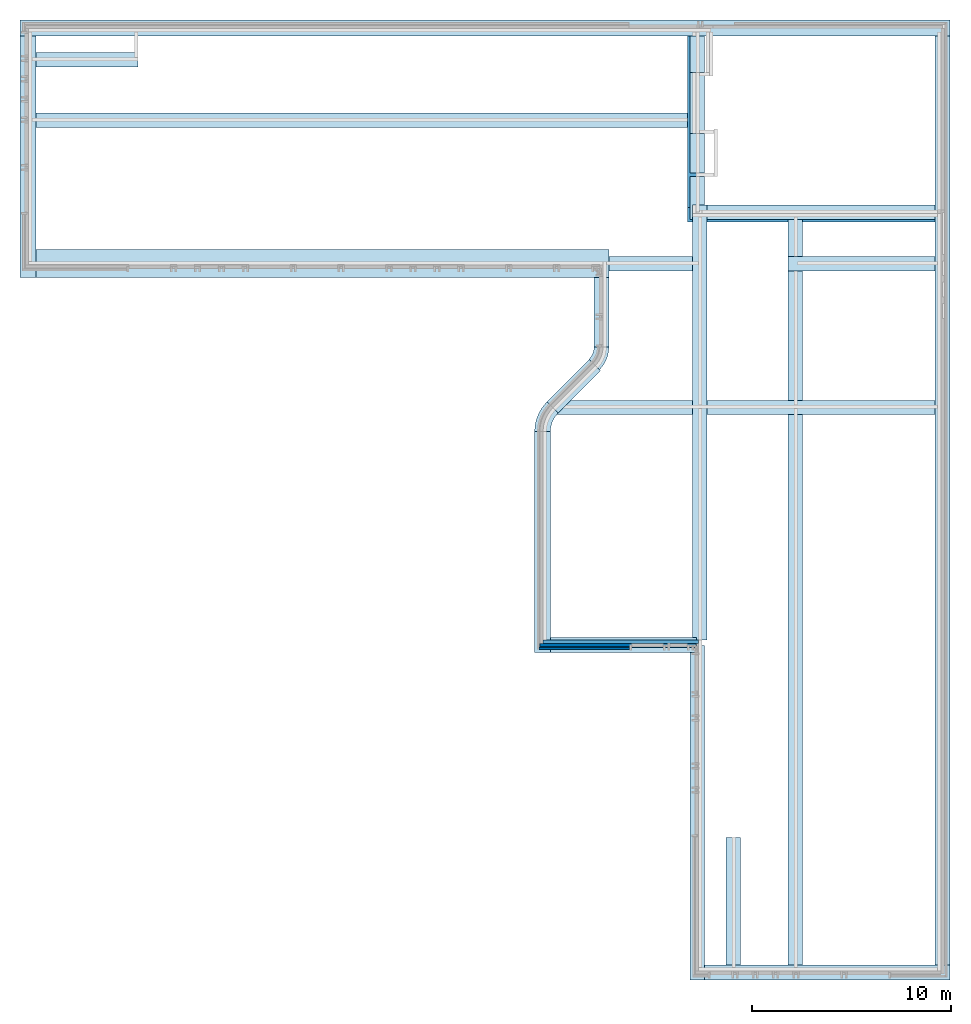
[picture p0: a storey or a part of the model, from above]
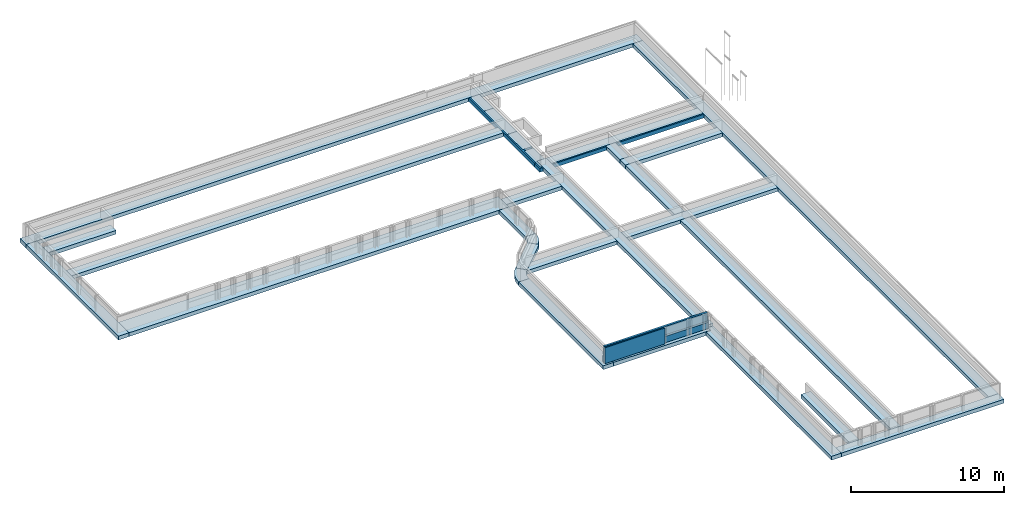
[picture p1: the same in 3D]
Properties of the parts of a building model (IFC2X3), part 1 of 37

# File
Description: ViewDefinition [CoordinationView_V2.0, QuantityTakeOffAddOnView], RevitIdentifiers [VersionGUID: 65c99af6-0f4b-4733-aae0-6f42005d6cb9, NumberOfSaves: 437], ExchangeRequirement [], CoordinateReference [CoordinateBase: Shared Coordinates]
File name: Kindcentrum de Nienekes
Time: 2024-05-14T12:10:15+01:00
Organization: DATarchitecten
Written by: ODA SDAI 23.12
Made in: Autodesk Revit 24.0.5.432 (ENU) - IFC 24.0.5.432

# IfcProject, Kindcentrum de Nienekes
LongName: 231105; Phase: <Project Status>

# IfcSite, <Kadastrale nummers>
RefLatitude: 52, 22, 58, 797912; RefLongitude: 4, 54, 57, 599601; RefElevation: 0 mm
Pset_ProductRequirements - Category: Project Information
Other - BCB_ProjectFolder: S:\7-BIM\01 BIM Bibliotheken\01 DAT Templates\; Category: Project Information; Client Name: Gemeente Land van Cuijk; Project Address: 231105@datarchitecten.nl; Project Issue Date: <Datum>; Project Name: 231105; Project Number: Kindcentrum de Nienekes; Project Status: <Project Status>; SiteName: <Kadastrale nummers>
Identity Data - IFC_Discipline: Bouwkundig; Organization Name: DAT; Revit_versie: R24; Workset: Project Info
Text - template_versie: 25-09-2017

# IfcSite: Table_Tennis_Table_12197:Table_Tennis_Table_12197 (2)
Material: Table Tennis playing surface, Table Tennis white lines, Table Tennis Metal, Table Tennis Glowing supports, Table Tennis Glowing Lines, Table Tennis net, Table Tennis Net Top
Pset_ProductRequirements - Category: Site
Other - Category: Site; Family: Table_Tennis_Table_12197; Family and Type: Table_Tennis_Table_12197: Table_Tennis_Table_12197; Type: Table_Tennis_Table_12197; Type Id: 6750400
Constraints - Level: 0; Moves With Nearby Elements: no; Offset from Host: 0 mm; Host: Level : 0
Dimensions - Area: 12.7457 m2; Volume: 0.258674 m3
Identity Data - Workset: situatie
Phasing - Phase Created: 2. nieuwbouw
Other(Type) - Category: Site; Family Name: Table_Tennis_Table_12197
Constraints(Type) - Default Elevation: 0 mm
Identity Data(Type) - Type Name: Table_Tennis_Table_12197; Workset: Family : Site : Table_Tennis_Table_12197
Name (Table_Tennis_Table_12197:Table_Tennis_Table_12197:...)
6750537
6750551

# IfcBuilding
Pset_BuildingCommon - NumberOfStoreys: 5
Pset_ProductRequirements - Category: Project Information
Other - BCB_ProjectFolder: S:\7-BIM\01 BIM Bibliotheken\01 DAT Templates\; Category: Project Information; Client Name: Gemeente Land van Cuijk; Project Address: 231105@datarchitecten.nl; Project Issue Date: <Datum>; Project Name: 231105; Project Number: Kindcentrum de Nienekes; Project Status: <Project Status>; SiteName: <Kadastrale nummers>
Identity Data - IFC_Discipline: Bouwkundig; Organization Name: DAT; Revit_versie: R24; Workset: Project Info
Text - template_versie: 25-09-2017

# IfcBuildingStorey: Level:A_hoogte_3.5mm, -1 fundering
LongName: ok. fundering; Elevation: -1570 mm
Pset_AirSideSystemInformation - Name: ok. fundering
Pset_ProductRequirements - Name: ok. fundering; Category: Levels
Other - Category: Levels; Family: Level; Family and Type: Level: A_hoogte_3.5mm; Type: A_hoogte_3.5mm; Type Id: 420648
Constraints - Elevation: -1570 mm
Dimensions - Computation Height: 0 mm
Identity Data - Structural: no; Building Story: yes; Name: ok. fundering; Workset: Shared Levels and Grids
Other(Type) - Category: Levels; Family Name: Level
Constraints(Type) - Elevation Base: Project Base Point
Graphics(Type) - Color: 8421504; Line Pattern: levels; Line Weight: 1; Symbol: 00_ISR_tag_level : 3.5mm; Symbol at End 1 Default: no; Symbol at End 2 Default: yes
Identity Data(Type) - Type Name: A_hoogte_3.5mm; Workset: Level Types

# IfcBuildingStorey: Level:A_omschrijving_3.5mm, -1 Speelvloer
LongName: V-1; Elevation: -600 mm
Pset_AirSideSystemInformation - Name: V-1; Description: Speelvloer
Pset_ProductRequirements - Name: V-1; Category: Levels
Other - Category: Levels; Family: Level; Family and Type: Level: A_omschrijving_3.5mm; Type: A_omschrijving_3.5mm; Type Id: 4122322
Constraints - Elevation: -600 mm
Dimensions - Computation Height: 0 mm
Identity Data - Structural: no; Building Story: yes; Workset: Shared Levels and Grids; Description: Speelvloer; Name: V-1
Other(Type) - Category: Levels; Family Name: Level
Constraints(Type) - Elevation Base: Project Base Point
Graphics(Type) - Line Pattern: levels; Line Weight: 1; Symbol at End 1 Default: no; Symbol at End 2 Default: yes; Color: 0; Symbol: 00_ISR_tag_level_description : 3.5mm
Identity Data(Type) - Workset: Level Types; Type Name: A_omschrijving_3.5mm

# IfcBuildingStorey: Level:S_hoogte_2.5mm_bk.vloer (3)
Pset_ProductRequirements - Category: Levels
Other - Category: Levels; Family: Level; Family and Type: Level: S_hoogte_2.5mm_bk.vloer; Type: S_hoogte_2.5mm_bk.vloer; Type Id: 549085
Dimensions - Computation Height: 0 mm
Identity Data - Structural: no; Building Story: yes; Workset: Shared Levels and Grids
Other(Type) - Category: Levels; Family Name: Level
Constraints(Type) - Elevation Base: Project Base Point
Graphics(Type) - Line Weight: 1; Color: 16711680; Line Pattern: Dash; Symbol: 00_ISR_tag_level_boven_buiten : std; Symbol at End 1 Default: yes; Symbol at End 2 Default: no
Identity Data(Type) - Workset: Level Types; Type Name: S_hoogte_2.5mm_bk.vloer
Name | LongName = Pset_AirSideSystemInformation, Name = Pset_ProductRequirements, Name = Identity Data, Name | Elevation (mm) = Constraints, Elevation (mm)
00 Begane grond | V0 bk. ruwe vloer | -70
01 eerste verdieping | V1 bk. ruwe vloer | 3560
02 tweede verdieping | V2 bk. ruwe vloer | 7150

# IfcSpace: BSO 1.04:5212714, 1.04
In: 01 eerste verdieping
LongName: BSO; InteriorOrExteriorSpace: INTERNAL
Pset_AirSideSystemInformation - Name: BSO
Pset_ProductRequirements - Name: BSO; Category: Rooms
Pset_SpaceCommon - Reference: BSO 1.04; Category: Rooms
BaseQuantities - NetFloorArea: 80.6502 m2; Height: 2600 mm; GrossFloorArea: 80.6502 m2; GrossVolume: 209.69 m3
Other - Category: Rooms; Phase Id: 0
Constraints - Base Offset: 0 mm; Upper Limit: 1; Level: 1; Limit Offset: 2600 mm
Dimensions - Computation Height: 0 mm; Area: 80.6502 m2; Perimeter: 46589.1 mm; Unbounded Height: 2600 mm; Volume: 208.352 m3
Energy Analysis - Actual Lighting Load per area: 0; Actual Power Load per area: 0; Base Lighting Load on: By Space Type; Base Power Load on: By Space Type; Heat Load Values: By Space Type; Lighting Load Units: Power Density; Number of People: 0; Power Load Units: Power Density; Actual Lighting Load: 0 W; Actual Power Load: 0 W; Area per Person: 28.5714 m2; Latent Heat Gain per person: 58.6142 W; Plenum Lighting Contribution: 20; Sensible Heat Gain per person: 73.2678 W; Specified Lighting Load: 0 W; Specified Lighting Load per area: 10.7639; Specified Power Load: 0 W; Specified Power Load per area: 13.9931; Total Heat Gain per person: 131.882 W
Identity Data - Workset: Bouwkundig; Name: BSO; Number: 1.04
Phasing - Phase: 2. nieuwbouw
Text - bezettingsgraadklasse: 30; bouwbesluit_functie: verblijfsruimte

# IfcSpace: BVO 0 2:5329016, 2
In: 00 Begane grond
LongName: BVO 0; InteriorOrExteriorSpace: INTERNAL; Group: bruto vloeroppervlak (BVO)
Pset_AirSideSystemInformation - Name: BVO 0
Pset_ProductRequirements - Name: BVO 0; Category: Areas
Pset_SpaceCommon - Reference: BVO 0 2; Category: Areas
BaseQuantities - NetFloorArea: 1160.68 m2; Height: 3630 mm; GrossFloorArea: 1160.68 m2; GrossVolume: 4213.26 m3
Other - Category: Areas; Area Scheme Id: 1055874; Area Type: Building Common Area
Constraints - Level: 0
Dimensions - Computation Height: 0 mm; Area: 1160.68 m2; Perimeter: 194664 mm
Identity Data - Workset: Bouwkundig; Name: BVO 0; Number: 2

# IfcSpace: BVO 1 1:5324504, 1
In: 01 eerste verdieping
LongName: BVO 1; InteriorOrExteriorSpace: INTERNAL; Group: bruto vloeroppervlak (BVO)
Pset_AirSideSystemInformation - Name: BVO 1
Pset_ProductRequirements - Name: BVO 1; Category: Areas
Pset_SpaceCommon - Reference: BVO 1 1; Category: Areas
BaseQuantities - NetFloorArea: 960.71 m2; Height: 3590 mm; GrossFloorArea: 960.71 m2; GrossVolume: 3448.95 m3
Other - Category: Areas; Area Scheme Id: 1055874; Area Type: Building Common Area
Constraints - Level: 1
Dimensions - Computation Height: 0 mm; Area: 960.71 m2; Perimeter: 197720 mm
Identity Data - Workset: Bouwkundig; Name: BVO 1; Number: 1

# IfcSpace: Basisgroep-lokaal 0.28:5206995, 0.28
In: 00 Begane grond
LongName: Basisgroep-lokaal; InteriorOrExteriorSpace: INTERNAL
Pset_AirSideSystemInformation - Name: Basisgroep-lokaal
Pset_ProductRequirements - Name: Basisgroep-lokaal; Category: Rooms
Pset_SpaceCommon - Reference: Basisgroep-lokaal 0.28; Category: Rooms
BaseQuantities - NetFloorArea: 49.9772 m2; Height: 2600 mm; GrossFloorArea: 49.9772 m2; GrossVolume: 129.941 m3
Other - Category: Rooms; Phase Id: 0
Constraints - Base Offset: 0 mm; Upper Limit: 0; Level: 0; Limit Offset: 2600 mm
Dimensions - Computation Height: 0 mm; Area: 49.9772 m2; Perimeter: 29171.9 mm; Unbounded Height: 2600 mm; Volume: 129.828 m3
Energy Analysis - Actual Lighting Load per area: 0; Actual Power Load per area: 0; Base Lighting Load on: By Space Type; Base Power Load on: By Space Type; Heat Load Values: By Space Type; Lighting Load Units: Power Density; Number of People: 0; Power Load Units: Power Density; Actual Lighting Load: 0 W; Actual Power Load: 0 W; Area per Person: 28.5714 m2; Latent Heat Gain per person: 58.6142 W; Plenum Lighting Contribution: 20; Sensible Heat Gain per person: 73.2678 W; Specified Lighting Load: 0 W; Specified Lighting Load per area: 10.7639; Specified Power Load: 0 W; Specified Power Load per area: 13.9931; Total Heat Gain per person: 131.882 W
Identity Data - Workset: Bouwkundig; Name: Basisgroep-lokaal; Number: 0.28
Phasing - Phase: 2. nieuwbouw
Text - bezettingsgraadklasse: 30; bouwbesluit_functie: verblijfsruimte

# IfcSpace: Basisgroep-lokaal 0.35:5207268, 0.35
In: 00 Begane grond
LongName: Basisgroep-lokaal; InteriorOrExteriorSpace: INTERNAL
Pset_AirSideSystemInformation - Name: Basisgroep-lokaal
Pset_ProductRequirements - Name: Basisgroep-lokaal; Category: Rooms
Pset_SpaceCommon - Reference: Basisgroep-lokaal 0.35; Category: Rooms
BaseQuantities - NetFloorArea: 48.6137 m2; Height: 2600 mm; GrossFloorArea: 48.6137 m2; GrossVolume: 126.395 m3
Other - Category: Rooms; Phase Id: 0
Constraints - Base Offset: 0 mm; Upper Limit: 0; Level: 0; Limit Offset: 2600 mm
Dimensions - Computation Height: 0 mm; Area: 48.6137 m2; Perimeter: 28484 mm; Unbounded Height: 2600 mm; Volume: 125.851 m3
Energy Analysis - Actual Lighting Load per area: 0; Actual Power Load per area: 0; Base Lighting Load on: By Space Type; Base Power Load on: By Space Type; Heat Load Values: By Space Type; Lighting Load Units: Power Density; Number of People: 0; Power Load Units: Power Density; Actual Lighting Load: 0 W; Actual Power Load: 0 W; Area per Person: 28.5714 m2; Latent Heat Gain per person: 58.6142 W; Plenum Lighting Contribution: 20; Sensible Heat Gain per person: 73.2678 W; Specified Lighting Load: 0 W; Specified Lighting Load per area: 10.7639; Specified Power Load: 0 W; Specified Power Load per area: 13.9931; Total Heat Gain per person: 131.882 W
Identity Data - Workset: Bouwkundig; Name: Basisgroep-lokaal; Number: 0.35
Phasing - Phase: 2. nieuwbouw
Text - bezettingsgraadklasse: 30; bouwbesluit_functie: verblijfsruimte

# IfcSpace: Basisgroep-lokaal 0.36:5207266, 0.36
In: 00 Begane grond
LongName: Basisgroep-lokaal; InteriorOrExteriorSpace: INTERNAL
Pset_AirSideSystemInformation - Name: Basisgroep-lokaal
Pset_ProductRequirements - Name: Basisgroep-lokaal; Category: Rooms
Pset_SpaceCommon - Reference: Basisgroep-lokaal 0.36; Category: Rooms
BaseQuantities - NetFloorArea: 49.4985 m2; Height: 2600 mm; GrossFloorArea: 49.4985 m2; GrossVolume: 128.696 m3
Other - Category: Rooms; Phase Id: 0
Constraints - Base Offset: 0 mm; Upper Limit: 0; Level: 0; Limit Offset: 2600 mm
Dimensions - Computation Height: 0 mm; Area: 49.4985 m2; Perimeter: 28762 mm; Unbounded Height: 2600 mm; Volume: 128.152 m3
Energy Analysis - Actual Lighting Load per area: 0; Actual Power Load per area: 0; Base Lighting Load on: By Space Type; Base Power Load on: By Space Type; Heat Load Values: By Space Type; Lighting Load Units: Power Density; Number of People: 0; Power Load Units: Power Density; Actual Lighting Load: 0 W; Actual Power Load: 0 W; Area per Person: 28.5714 m2; Latent Heat Gain per person: 58.6142 W; Plenum Lighting Contribution: 20; Sensible Heat Gain per person: 73.2678 W; Specified Lighting Load: 0 W; Specified Lighting Load per area: 10.7639; Specified Power Load: 0 W; Specified Power Load per area: 13.9931; Total Heat Gain per person: 131.882 W
Identity Data - Workset: Bouwkundig; Name: Basisgroep-lokaal; Number: 0.36
Phasing - Phase: 2. nieuwbouw
Text - bezettingsgraadklasse: 30; bouwbesluit_functie: verblijfsruimte

# IfcSpace: Basisgroep-lokaal 0.37:5207267, 0.37
In: 00 Begane grond
LongName: Basisgroep-lokaal; InteriorOrExteriorSpace: INTERNAL
Pset_AirSideSystemInformation - Name: Basisgroep-lokaal
Pset_ProductRequirements - Name: Basisgroep-lokaal; Category: Rooms
Pset_SpaceCommon - Reference: Basisgroep-lokaal 0.37; Category: Rooms
BaseQuantities - NetFloorArea: 49.6696 m2; Height: 2600 mm; GrossFloorArea: 49.6696 m2; GrossVolume: 129.141 m3
Other - Category: Rooms; Phase Id: 0
Constraints - Base Offset: 0 mm; Upper Limit: 0; Level: 0; Limit Offset: 2600 mm
Dimensions - Computation Height: 0 mm; Area: 49.6696 m2; Perimeter: 28804 mm; Unbounded Height: 2600 mm; Volume: 128.597 m3
Energy Analysis - Actual Lighting Load per area: 0; Actual Power Load per area: 0; Base Lighting Load on: By Space Type; Base Power Load on: By Space Type; Heat Load Values: By Space Type; Lighting Load Units: Power Density; Number of People: 0; Power Load Units: Power Density; Actual Lighting Load: 0 W; Actual Power Load: 0 W; Area per Person: 28.5714 m2; Latent Heat Gain per person: 58.6142 W; Plenum Lighting Contribution: 20; Sensible Heat Gain per person: 73.2678 W; Specified Lighting Load: 0 W; Specified Lighting Load per area: 10.7639; Specified Power Load: 0 W; Specified Power Load per area: 13.9931; Total Heat Gain per person: 131.882 W
Identity Data - Workset: Bouwkundig; Name: Basisgroep-lokaal; Number: 0.37
Phasing - Phase: 2. nieuwbouw
Text - bezettingsgraadklasse: 30; bouwbesluit_functie: verblijfsruimte

# IfcSpace: Basisgroep-lokaal 1.01:5212717, 1.01
In: 01 eerste verdieping
LongName: Basisgroep-lokaal; InteriorOrExteriorSpace: INTERNAL
Pset_AirSideSystemInformation - Name: Basisgroep-lokaal
Pset_ProductRequirements - Name: Basisgroep-lokaal; Category: Rooms
Pset_SpaceCommon - Reference: Basisgroep-lokaal 1.01; Category: Rooms
BaseQuantities - NetFloorArea: 48.8263 m2; Height: 2600 mm; GrossFloorArea: 48.8263 m2; GrossVolume: 126.948 m3
Other - Category: Rooms; Phase Id: 0
Constraints - Base Offset: 0 mm; Upper Limit: 1; Level: 1; Limit Offset: 2600 mm
Dimensions - Computation Height: 0 mm; Area: 48.8263 m2; Perimeter: 29366 mm; Unbounded Height: 2600 mm; Volume: 126.416 m3
Energy Analysis - Actual Lighting Load per area: 0; Actual Power Load per area: 0; Base Lighting Load on: By Space Type; Base Power Load on: By Space Type; Heat Load Values: By Space Type; Lighting Load Units: Power Density; Number of People: 0; Power Load Units: Power Density; Actual Lighting Load: 0 W; Actual Power Load: 0 W; Area per Person: 28.5714 m2; Latent Heat Gain per person: 58.6142 W; Plenum Lighting Contribution: 20; Sensible Heat Gain per person: 73.2678 W; Specified Lighting Load: 0 W; Specified Lighting Load per area: 10.7639; Specified Power Load: 0 W; Specified Power Load per area: 13.9931; Total Heat Gain per person: 131.882 W
Identity Data - Workset: Bouwkundig; Name: Basisgroep-lokaal; Number: 1.01
Phasing - Phase: 2. nieuwbouw
Text - bezettingsgraadklasse: 30; bouwbesluit_functie: verblijfsruimte

# IfcSpace: Basisgroep-lokaal 1.02:5212716, 1.02
In: 01 eerste verdieping
LongName: Basisgroep-lokaal; InteriorOrExteriorSpace: INTERNAL
Pset_AirSideSystemInformation - Name: Basisgroep-lokaal
Pset_ProductRequirements - Name: Basisgroep-lokaal; Category: Rooms
Pset_SpaceCommon - Reference: Basisgroep-lokaal 1.02; Category: Rooms
BaseQuantities - NetFloorArea: 49.5244 m2; Height: 2600 mm; GrossFloorArea: 49.5244 m2; GrossVolume: 128.763 m3
Other - Category: Rooms; Phase Id: 0
Constraints - Base Offset: 0 mm; Upper Limit: 1; Level: 1; Limit Offset: 2600 mm
Dimensions - Computation Height: 0 mm; Area: 49.5244 m2; Perimeter: 29568 mm; Unbounded Height: 2600 mm; Volume: 128.231 m3
Energy Analysis - Actual Lighting Load per area: 0; Actual Power Load per area: 0; Base Lighting Load on: By Space Type; Base Power Load on: By Space Type; Heat Load Values: By Space Type; Lighting Load Units: Power Density; Number of People: 0; Power Load Units: Power Density; Actual Lighting Load: 0 W; Actual Power Load: 0 W; Area per Person: 28.5714 m2; Latent Heat Gain per person: 58.6142 W; Plenum Lighting Contribution: 20; Sensible Heat Gain per person: 73.2678 W; Specified Lighting Load: 0 W; Specified Lighting Load per area: 10.7639; Specified Power Load: 0 W; Specified Power Load per area: 13.9931; Total Heat Gain per person: 131.882 W
Identity Data - Workset: Bouwkundig; Name: Basisgroep-lokaal; Number: 1.02
Phasing - Phase: 2. nieuwbouw
Text - bezettingsgraadklasse: 30; bouwbesluit_functie: verblijfsruimte

# IfcSpace: Basisgroep-lokaal 1.03:5212708, 1.03
In: 01 eerste verdieping
LongName: Basisgroep-lokaal; InteriorOrExteriorSpace: INTERNAL
Pset_AirSideSystemInformation - Name: Basisgroep-lokaal
Pset_ProductRequirements - Name: Basisgroep-lokaal; Category: Rooms
Pset_SpaceCommon - Reference: Basisgroep-lokaal 1.03; Category: Rooms
BaseQuantities - NetFloorArea: 49.4522 m2; Height: 2600 mm; GrossFloorArea: 49.4522 m2; GrossVolume: 128.576 m3
Other - Category: Rooms; Phase Id: 0
Constraints - Base Offset: 0 mm; Upper Limit: 1; Level: 1; Limit Offset: 2600 mm
Dimensions - Computation Height: 0 mm; Area: 49.4522 m2; Perimeter: 29556 mm; Unbounded Height: 2600 mm; Volume: 128.056 m3
Energy Analysis - Actual Lighting Load per area: 0; Actual Power Load per area: 0; Base Lighting Load on: By Space Type; Base Power Load on: By Space Type; Heat Load Values: By Space Type; Lighting Load Units: Power Density; Number of People: 0; Power Load Units: Power Density; Actual Lighting Load: 0 W; Actual Power Load: 0 W; Area per Person: 28.5714 m2; Latent Heat Gain per person: 58.6142 W; Plenum Lighting Contribution: 20; Sensible Heat Gain per person: 73.2678 W; Specified Lighting Load: 0 W; Specified Lighting Load per area: 10.7639; Specified Power Load: 0 W; Specified Power Load per area: 13.9931; Total Heat Gain per person: 131.882 W
Identity Data - Workset: Bouwkundig; Name: Basisgroep-lokaal; Number: 1.03
Phasing - Phase: 2. nieuwbouw
Text - bezettingsgraadklasse: 30; bouwbesluit_functie: verblijfsruimte

# IfcSpace: Basisgroep-lokaal 1.21:5227321, 1.21
In: 01 eerste verdieping
LongName: Basisgroep-lokaal; InteriorOrExteriorSpace: INTERNAL
Pset_AirSideSystemInformation - Name: Basisgroep-lokaal
Pset_ProductRequirements - Name: Basisgroep-lokaal; Category: Rooms
Pset_SpaceCommon - Reference: Basisgroep-lokaal 1.21; Category: Rooms
BaseQuantities - NetFloorArea: 48.8446 m2; Height: 2600 mm; GrossFloorArea: 48.8446 m2; GrossVolume: 126.996 m3
Other - Category: Rooms; Phase Id: 0
Constraints - Base Offset: 0 mm; Upper Limit: 1; Level: 1; Limit Offset: 2600 mm
Dimensions - Computation Height: 0 mm; Area: 48.8446 m2; Perimeter: 28554 mm; Unbounded Height: 2600 mm; Volume: 126.452 m3
Energy Analysis - Actual Lighting Load per area: 0; Actual Power Load per area: 0; Base Lighting Load on: By Space Type; Base Power Load on: By Space Type; Heat Load Values: By Space Type; Lighting Load Units: Power Density; Number of People: 0; Power Load Units: Power Density; Actual Lighting Load: 0 W; Actual Power Load: 0 W; Area per Person: 28.5714 m2; Latent Heat Gain per person: 58.6142 W; Plenum Lighting Contribution: 20; Sensible Heat Gain per person: 73.2678 W; Specified Lighting Load: 0 W; Specified Lighting Load per area: 10.7639; Specified Power Load: 0 W; Specified Power Load per area: 13.9931; Total Heat Gain per person: 131.882 W
Identity Data - Workset: Bouwkundig; Name: Basisgroep-lokaal; Number: 1.21
Phasing - Phase: 2. nieuwbouw
Text - bezettingsgraadklasse: 30; bouwbesluit_functie: verblijfsruimte

# IfcSpace: Basisgroep-lokaal 1.22:5212715, 1.22
In: 01 eerste verdieping
LongName: Basisgroep-lokaal; InteriorOrExteriorSpace: INTERNAL
Pset_AirSideSystemInformation - Name: Basisgroep-lokaal
Pset_ProductRequirements - Name: Basisgroep-lokaal; Category: Rooms
Pset_SpaceCommon - Reference: Basisgroep-lokaal 1.22; Category: Rooms
BaseQuantities - NetFloorArea: 49.5842 m2; Height: 2600 mm; GrossFloorArea: 49.5842 m2; GrossVolume: 128.919 m3
Other - Category: Rooms; Phase Id: 0
Constraints - Base Offset: 0 mm; Upper Limit: 1; Level: 1; Limit Offset: 2600 mm
Dimensions - Computation Height: 0 mm; Area: 49.5842 m2; Perimeter: 28794 mm; Unbounded Height: 2600 mm; Volume: 128.375 m3
Energy Analysis - Actual Lighting Load per area: 0; Actual Power Load per area: 0; Base Lighting Load on: By Space Type; Base Power Load on: By Space Type; Heat Load Values: By Space Type; Lighting Load Units: Power Density; Number of People: 0; Power Load Units: Power Density; Actual Lighting Load: 0 W; Actual Power Load: 0 W; Area per Person: 28.5714 m2; Latent Heat Gain per person: 58.6142 W; Plenum Lighting Contribution: 20; Sensible Heat Gain per person: 73.2678 W; Specified Lighting Load: 0 W; Specified Lighting Load per area: 10.7639; Specified Power Load: 0 W; Specified Power Load per area: 13.9931; Total Heat Gain per person: 131.882 W
Identity Data - Workset: Bouwkundig; Name: Basisgroep-lokaal; Number: 1.22
Phasing - Phase: 2. nieuwbouw
Text - bezettingsgraadklasse: 30; bouwbesluit_functie: verblijfsruimte

# IfcSpace: Basisgroep-lokaal 1.23:5227404, 1.23
In: 01 eerste verdieping
LongName: Basisgroep-lokaal; InteriorOrExteriorSpace: INTERNAL
Pset_AirSideSystemInformation - Name: Basisgroep-lokaal
Pset_ProductRequirements - Name: Basisgroep-lokaal; Category: Rooms
Pset_SpaceCommon - Reference: Basisgroep-lokaal 1.23; Category: Rooms
BaseQuantities - NetFloorArea: 49.6036 m2; Height: 2600 mm; GrossFloorArea: 49.6036 m2; GrossVolume: 128.969 m3
Other - Category: Rooms; Phase Id: 0
Constraints - Base Offset: 0 mm; Upper Limit: 1; Level: 1; Limit Offset: 2600 mm
Dimensions - Computation Height: 0 mm; Area: 49.6036 m2; Perimeter: 28784 mm; Unbounded Height: 2600 mm; Volume: 128.425 m3
Energy Analysis - Actual Lighting Load per area: 0; Actual Power Load per area: 0; Base Lighting Load on: By Space Type; Base Power Load on: By Space Type; Heat Load Values: By Space Type; Lighting Load Units: Power Density; Number of People: 0; Power Load Units: Power Density; Actual Lighting Load: 0 W; Actual Power Load: 0 W; Area per Person: 28.5714 m2; Latent Heat Gain per person: 58.6142 W; Plenum Lighting Contribution: 20; Sensible Heat Gain per person: 73.2678 W; Specified Lighting Load: 0 W; Specified Lighting Load per area: 10.7639; Specified Power Load: 0 W; Specified Power Load per area: 13.9931; Total Heat Gain per person: 131.882 W
Identity Data - Workset: Bouwkundig; Name: Basisgroep-lokaal; Number: 1.23
Phasing - Phase: 2. nieuwbouw
Text - bezettingsgraadklasse: 30; bouwbesluit_functie: verblijfsruimte

# IfcSpace: Basisgroep-lokaal groot 0.38:5207250, 0.38
In: 00 Begane grond
LongName: Basisgroep-lokaal groot; InteriorOrExteriorSpace: INTERNAL
Pset_AirSideSystemInformation - Name: Basisgroep-lokaal groot
Pset_ProductRequirements - Name: Basisgroep-lokaal groot; Category: Rooms
Pset_SpaceCommon - Reference: Basisgroep-lokaal groot 0.38; Category: Rooms
BaseQuantities - NetFloorArea: 67.4257 m2; Height: 2600 mm; GrossPerimeter: 33670 mm; GrossFloorArea: 67.4257 m2; GrossVolume: 175.307 m3
Other - Category: Rooms; Phase Id: 0
Constraints - Base Offset: 0 mm; Upper Limit: 0; Level: 0; Limit Offset: 2600 mm
Dimensions - Computation Height: 0 mm; Area: 67.4257 m2; Perimeter: 33670 mm; Unbounded Height: 2600 mm; Volume: 175.307 m3
Energy Analysis - Actual Lighting Load per area: 0; Actual Power Load per area: 0; Base Lighting Load on: By Space Type; Base Power Load on: By Space Type; Heat Load Values: By Space Type; Lighting Load Units: Power Density; Number of People: 0; Power Load Units: Power Density; Actual Lighting Load: 0 W; Actual Power Load: 0 W; Area per Person: 28.5714 m2; Latent Heat Gain per person: 58.6142 W; Plenum Lighting Contribution: 20; Sensible Heat Gain per person: 73.2678 W; Specified Lighting Load: 0 W; Specified Lighting Load per area: 10.7639; Specified Power Load: 0 W; Specified Power Load per area: 13.9931; Total Heat Gain per person: 131.882 W
Identity Data - Workset: Bouwkundig; Name: Basisgroep-lokaal groot; Number: 0.38
Phasing - Phase: 2. nieuwbouw
Text - bezettingsgraadklasse: 40; bouwbesluit_functie: verblijfsruimte

# IfcSpace: Basisgroep-lokaal groot 1.24:5212697, 1.24
In: 01 eerste verdieping
LongName: Basisgroep-lokaal groot; InteriorOrExteriorSpace: INTERNAL
Pset_AirSideSystemInformation - Name: Basisgroep-lokaal groot
Pset_ProductRequirements - Name: Basisgroep-lokaal groot; Category: Rooms
Pset_SpaceCommon - Reference: Basisgroep-lokaal groot 1.24; Category: Rooms
BaseQuantities - NetFloorArea: 66.0765 m2; Height: 2600 mm; GrossPerimeter: 33320 mm; GrossFloorArea: 66.0765 m2; GrossVolume: 171.799 m3
Other - Category: Rooms; Phase Id: 0
Constraints - Base Offset: 0 mm; Level: 1; Limit Offset: 2600 mm; Upper Limit: 1
Dimensions - Computation Height: 0 mm; Area: 66.0765 m2; Perimeter: 33320 mm; Unbounded Height: 2600 mm; Volume: 171.799 m3
Energy Analysis - Actual Lighting Load per area: 0; Actual Power Load per area: 0; Base Lighting Load on: By Space Type; Base Power Load on: By Space Type; Heat Load Values: By Space Type; Lighting Load Units: Power Density; Number of People: 0; Power Load Units: Power Density; Actual Lighting Load: 0 W; Actual Power Load: 0 W; Area per Person: 28.5714 m2; Latent Heat Gain per person: 58.6142 W; Plenum Lighting Contribution: 20; Sensible Heat Gain per person: 73.2678 W; Specified Lighting Load: 0 W; Specified Lighting Load per area: 10.7639; Specified Power Load: 0 W; Specified Power Load per area: 13.9931; Total Heat Gain per person: 131.882 W
Identity Data - Workset: Bouwkundig; Name: Basisgroep-lokaal groot; Number: 1.24
Phasing - Phase: 2. nieuwbouw
Text - bezettingsgraadklasse: 40; bouwbesluit_functie: verblijfsruimte

# IfcSpace: Berging 1.05:5212718, 1.05
In: 01 eerste verdieping
LongName: Berging; InteriorOrExteriorSpace: INTERNAL
Pset_AirSideSystemInformation - Name: Berging
Pset_ProductRequirements - Name: Berging; Category: Rooms
Pset_SpaceCommon - Reference: Berging 1.05; Category: Rooms
BaseQuantities - NetFloorArea: 4.31485 m2; Height: 2600 mm; GrossFloorArea: 4.31485 m2; GrossVolume: 11.2186 m3
Other - Category: Rooms; Phase Id: 0
Constraints - Base Offset: 0 mm; Upper Limit: 1; Level: 1; Limit Offset: 2600 mm
Dimensions - Computation Height: 0 mm; Area: 4.31485 m2; Perimeter: 8542 mm; Unbounded Height: 2600 mm; Volume: 10.3621 m3
Energy Analysis - Actual Lighting Load per area: 0; Actual Power Load per area: 0; Base Lighting Load on: By Space Type; Base Power Load on: By Space Type; Heat Load Values: By Space Type; Lighting Load Units: Power Density; Number of People: 0; Power Load Units: Power Density; Actual Lighting Load: 0 W; Actual Power Load: 0 W; Area per Person: 28.5714 m2; Latent Heat Gain per person: 58.6142 W; Plenum Lighting Contribution: 20; Sensible Heat Gain per person: 73.2678 W; Specified Lighting Load: 0 W; Specified Lighting Load per area: 10.7639; Specified Power Load: 0 W; Specified Power Load per area: 13.9931; Total Heat Gain per person: 131.882 W
Identity Data - Workset: Bouwkundig; Name: Berging; Number: 1.05
Phasing - Phase: 2. nieuwbouw
Text - bouwbesluit_functie: opslagruimte

# IfcSpace: Berging 1.07:5212719, 1.07
In: 01 eerste verdieping
LongName: Berging; InteriorOrExteriorSpace: INTERNAL
Pset_AirSideSystemInformation - Name: Berging
Pset_ProductRequirements - Name: Berging; Category: Rooms
Pset_SpaceCommon - Reference: Berging 1.07; Category: Rooms
BaseQuantities - NetFloorArea: 2.17581 m2; Height: 2600 mm; GrossFloorArea: 2.17581 m2; GrossVolume: 5.65711 m3
Other - Category: Rooms; Phase Id: 0
Constraints - Base Offset: 0 mm; Upper Limit: 1; Level: 1; Limit Offset: 2600 mm
Dimensions - Computation Height: 0 mm; Area: 2.17581 m2; Perimeter: 5962 mm; Unbounded Height: 2600 mm; Volume: 5.22883 m3
Energy Analysis - Actual Lighting Load per area: 0; Actual Power Load per area: 0; Base Lighting Load on: By Space Type; Base Power Load on: By Space Type; Heat Load Values: By Space Type; Lighting Load Units: Power Density; Number of People: 0; Power Load Units: Power Density; Actual Lighting Load: 0 W; Actual Power Load: 0 W; Area per Person: 28.5714 m2; Latent Heat Gain per person: 58.6142 W; Plenum Lighting Contribution: 20; Sensible Heat Gain per person: 73.2678 W; Specified Lighting Load: 0 W; Specified Lighting Load per area: 10.7639; Specified Power Load: 0 W; Specified Power Load per area: 13.9931; Total Heat Gain per person: 131.882 W
Identity Data - Workset: Bouwkundig; Name: Berging; Number: 1.07
Phasing - Phase: 2. nieuwbouw
Text - bouwbesluit_functie: opslagruimte

# IfcSpace: Berging 1.09:5212704, 1.09
In: 01 eerste verdieping
LongName: Berging; InteriorOrExteriorSpace: INTERNAL
Pset_AirSideSystemInformation - Name: Berging
Pset_ProductRequirements - Name: Berging; Category: Rooms
Pset_SpaceCommon - Reference: Berging 1.09; Category: Rooms
BaseQuantities - NetFloorArea: 3.52948 m2; Height: 2600 mm; GrossFloorArea: 3.52948 m2; GrossVolume: 9.17666 m3
Other - Category: Rooms; Phase Id: 0
Constraints - Base Offset: 0 mm; Upper Limit: 1; Level: 1; Limit Offset: 2600 mm
Dimensions - Computation Height: 0 mm; Area: 3.52948 m2; Perimeter: 7592 mm; Unbounded Height: 2600 mm; Volume: 8.47614 m3
Energy Analysis - Actual Lighting Load per area: 0; Actual Power Load per area: 0; Base Lighting Load on: By Space Type; Base Power Load on: By Space Type; Heat Load Values: By Space Type; Lighting Load Units: Power Density; Number of People: 0; Power Load Units: Power Density; Actual Lighting Load: 0 W; Actual Power Load: 0 W; Area per Person: 28.5714 m2; Latent Heat Gain per person: 58.6142 W; Plenum Lighting Contribution: 20; Sensible Heat Gain per person: 73.2678 W; Specified Lighting Load: 0 W; Specified Lighting Load per area: 10.7639; Specified Power Load: 0 W; Specified Power Load per area: 13.9931; Total Heat Gain per person: 131.882 W
Identity Data - Workset: Bouwkundig; Name: Berging; Number: 1.09
Phasing - Phase: 2. nieuwbouw
Text - bouwbesluit_functie: opslagruimte

# IfcSpace: Bibliotheek 1.13:5226995, 1.13
In: 01 eerste verdieping
LongName: Bibliotheek; InteriorOrExteriorSpace: INTERNAL
Pset_AirSideSystemInformation - Name: Bibliotheek
Pset_ProductRequirements - Name: Bibliotheek; Category: Rooms
Pset_SpaceCommon - Reference: Bibliotheek 1.13; Category: Rooms
BaseQuantities - NetFloorArea: 7.35 m2; Height: 2600 mm; GrossPerimeter: 10850 mm; GrossFloorArea: 7.35 m2; GrossVolume: 19.11 m3
Other - Category: Rooms; Phase Id: 0
Constraints - Base Offset: 0 mm; Upper Limit: 1; Level: 1; Limit Offset: 2600 mm
Dimensions - Computation Height: 0 mm; Area: 7.35 m2; Perimeter: 10850 mm; Unbounded Height: 2600 mm; Volume: 19.11 m3
Energy Analysis - Actual Lighting Load per area: 0; Actual Power Load per area: 0; Base Lighting Load on: By Space Type; Base Power Load on: By Space Type; Heat Load Values: By Space Type; Lighting Load Units: Power Density; Number of People: 0; Power Load Units: Power Density; Actual Lighting Load: 0 W; Actual Power Load: 0 W; Area per Person: 28.5714 m2; Latent Heat Gain per person: 58.6142 W; Plenum Lighting Contribution: 20; Sensible Heat Gain per person: 73.2678 W; Specified Lighting Load: 0 W; Specified Lighting Load per area: 10.7639; Specified Power Load: 0 W; Specified Power Load per area: 13.9931; Total Heat Gain per person: 131.882 W
Identity Data - Workset: Bouwkundig; Name: Bibliotheek; Number: 1.13
Phasing - Phase: 2. nieuwbouw
Text - bouwbesluit_functie: verkeersruimte

# IfcSpace: Entree 0.39:5207273, 0.39
In: 00 Begane grond
LongName: Entree; InteriorOrExteriorSpace: INTERNAL
Pset_AirSideSystemInformation - Name: Entree
Pset_ProductRequirements - Name: Entree; Category: Rooms
Pset_SpaceCommon - Reference: Entree 0.39; Category: Rooms
BaseQuantities - NetFloorArea: 4.61525 m2; Height: 6828.96 mm; GrossPerimeter: 9240 mm; GrossFloorArea: 4.61525 m2; GrossVolume: 31.5174 m3
Other - Category: Rooms; Phase Id: 0
Constraints - Base Offset: 0 mm; Upper Limit: 0; Level: 0; Limit Offset: 6828.96 mm
Dimensions - Computation Height: 0 mm; Area: 4.61525 m2; Perimeter: 9240 mm; Unbounded Height: 6828.96 mm; Volume: 31.5174 m3
Energy Analysis - Actual Lighting Load per area: 0; Actual Power Load per area: 0; Base Lighting Load on: By Space Type; Base Power Load on: By Space Type; Heat Load Values: By Space Type; Lighting Load Units: Power Density; Number of People: 0; Power Load Units: Power Density; Actual Lighting Load: 0 W; Actual Power Load: 0 W; Area per Person: 28.5714 m2; Latent Heat Gain per person: 58.6142 W; Plenum Lighting Contribution: 20; Sensible Heat Gain per person: 73.2678 W; Specified Lighting Load: 0 W; Specified Lighting Load per area: 10.7639; Specified Power Load: 0 W; Specified Power Load per area: 13.9931; Total Heat Gain per person: 131.882 W
Identity Data - Workset: Bouwkundig; Name: Entree; Number: 0.39
Phasing - Phase: 2. nieuwbouw
Text - bouwbesluit_functie: verkeersruimte

# IfcSpace: GO 0 2:5305672, 2
In: 00 Begane grond
LongName: GO 0; InteriorOrExteriorSpace: INTERNAL; Group: gebruiksoppvlak (GO)
Pset_AirSideSystemInformation - Name: GO 0
Pset_ProductRequirements - Name: GO 0; Category: Areas
Pset_SpaceCommon - Reference: GO 0 2; Category: Areas
BaseQuantities - NetFloorArea: 1056.22 m2; Height: 3630 mm; GrossFloorArea: 1056.22 m2; GrossVolume: 3834.07 m3
Other - Area Scheme Id: 1055910; Category: Areas; Area Type: Building Common Area
Constraints - Level: 0
Dimensions - Computation Height: 0 mm; Area: 1056.22 m2; Perimeter: 188694 mm
Identity Data - Workset: Bouwkundig; Name: GO 0; Number: 2

# IfcSpace: GO 1 1:5305666, 1
In: 01 eerste verdieping
LongName: GO 1; InteriorOrExteriorSpace: INTERNAL; Group: gebruiksoppvlak (GO)
Pset_AirSideSystemInformation - Name: GO 1
Pset_ProductRequirements - Name: GO 1; Category: Areas
Pset_SpaceCommon - Reference: GO 1 1; Category: Areas
BaseQuantities - NetFloorArea: 819.925 m2; Height: 3590 mm; GrossFloorArea: 819.925 m2; GrossVolume: 2943.53 m3
Other - Area Scheme Id: 1055910; Area Type: Building Common Area; Category: Areas
Constraints - Level: 1
Dimensions - Computation Height: 0 mm; Area: 819.925 m2; Perimeter: 208830 mm
Identity Data - Workset: Bouwkundig; Name: GO 1; Number: 1

# IfcSpace: Groepsruimte Kinderopvang 0.01:5207262, 0.01
In: 00 Begane grond
LongName: Groepsruimte Kinderopvang; InteriorOrExteriorSpace: INTERNAL
Pset_AirSideSystemInformation - Name: Groepsruimte Kinderopvang
Pset_ProductRequirements - Name: Groepsruimte Kinderopvang; Category: Rooms
Pset_SpaceCommon - Reference: Groepsruimte Kinderopvang 0.01; Category: Rooms
BaseQuantities - NetFloorArea: 59.4844 m2; Height: 2600 mm; GrossFloorArea: 59.4844 m2; GrossVolume: 154.659 m3
Other - Category: Rooms; Phase Id: 0
Constraints - Base Offset: 0 mm; Upper Limit: 0; Level: 0; Limit Offset: 2600 mm
Dimensions - Computation Height: 0 mm; Area: 59.4844 m2; Perimeter: 31950 mm; Unbounded Height: 2600 mm; Volume: 154.325 m3
Energy Analysis - Actual Lighting Load per area: 0; Actual Power Load per area: 0; Base Lighting Load on: By Space Type; Base Power Load on: By Space Type; Heat Load Values: By Space Type; Lighting Load Units: Power Density; Number of People: 0; Power Load Units: Power Density; Actual Lighting Load: 0 W; Actual Power Load: 0 W; Area per Person: 28.5714 m2; Latent Heat Gain per person: 58.6142 W; Plenum Lighting Contribution: 20; Sensible Heat Gain per person: 73.2678 W; Specified Lighting Load: 0 W; Specified Lighting Load per area: 10.7639; Specified Power Load: 0 W; Specified Power Load per area: 13.9931; Total Heat Gain per person: 131.882 W
Identity Data - Workset: Bouwkundig; Name: Groepsruimte Kinderopvang; Number: 0.01
Phasing - Phase: 2. nieuwbouw
Text - bezettingsgraadklasse: 20; bouwbesluit_functie: verblijfsruimte

# IfcSpace: Groepsruimte Kinderopvang 0.05:5207275, 0.05
In: 00 Begane grond
LongName: Groepsruimte Kinderopvang; InteriorOrExteriorSpace: INTERNAL
Pset_AirSideSystemInformation - Name: Groepsruimte Kinderopvang
Pset_ProductRequirements - Name: Groepsruimte Kinderopvang; Category: Rooms
Pset_SpaceCommon - Reference: Groepsruimte Kinderopvang 0.05; Category: Rooms
BaseQuantities - NetFloorArea: 58.788 m2; Height: 2600 mm; GrossFloorArea: 58.788 m2; GrossVolume: 152.849 m3
Other - Category: Rooms; Phase Id: 0
Constraints - Base Offset: 0 mm; Upper Limit: 0; Level: 0; Limit Offset: 2600 mm
Dimensions - Computation Height: 0 mm; Area: 58.788 m2; Perimeter: 31570 mm; Unbounded Height: 2600 mm; Volume: 152.587 m3
Energy Analysis - Actual Lighting Load per area: 0; Actual Power Load per area: 0; Base Lighting Load on: By Space Type; Base Power Load on: By Space Type; Heat Load Values: By Space Type; Lighting Load Units: Power Density; Number of People: 0; Power Load Units: Power Density; Actual Lighting Load: 0 W; Actual Power Load: 0 W; Area per Person: 28.5714 m2; Latent Heat Gain per person: 58.6142 W; Plenum Lighting Contribution: 20; Sensible Heat Gain per person: 73.2678 W; Specified Lighting Load: 0 W; Specified Lighting Load per area: 10.7639; Specified Power Load: 0 W; Specified Power Load per area: 13.9931; Total Heat Gain per person: 131.882 W
Identity Data - Workset: Bouwkundig; Name: Groepsruimte Kinderopvang; Number: 0.05
Phasing - Phase: 2. nieuwbouw
Text - bezettingsgraadklasse: 20; bouwbesluit_functie: verblijfsruimte

# IfcSpace: Hoofdentree 0.16:5207265, 0.16
In: 00 Begane grond
LongName: Hoofdentree; InteriorOrExteriorSpace: INTERNAL
Pset_AirSideSystemInformation - Name: Hoofdentree
Pset_ProductRequirements - Name: Hoofdentree; Category: Rooms
Pset_SpaceCommon - Reference: Hoofdentree 0.16; Category: Rooms
BaseQuantities - NetFloorArea: 9.70099 m2; Height: 2600 mm; GrossPerimeter: 13530.1 mm; GrossFloorArea: 9.70099 m2; GrossVolume: 25.2226 m3
Other - Category: Rooms; Phase Id: 0
Constraints - Base Offset: 0 mm; Upper Limit: 0; Level: 0; Limit Offset: 2600 mm
Dimensions - Computation Height: 0 mm; Area: 9.70099 m2; Perimeter: 13530.1 mm; Unbounded Height: 2600 mm; Volume: 25.2226 m3
Energy Analysis - Actual Lighting Load per area: 0; Actual Power Load per area: 0; Base Lighting Load on: By Space Type; Base Power Load on: By Space Type; Heat Load Values: By Space Type; Lighting Load Units: Power Density; Number of People: 0; Power Load Units: Power Density; Actual Lighting Load: 0 W; Actual Power Load: 0 W; Area per Person: 28.5714 m2; Latent Heat Gain per person: 58.6142 W; Plenum Lighting Contribution: 20; Sensible Heat Gain per person: 73.2678 W; Specified Lighting Load: 0 W; Specified Lighting Load per area: 10.7639; Specified Power Load: 0 W; Specified Power Load per area: 13.9931; Total Heat Gain per person: 131.882 W
Identity Data - Workset: Bouwkundig; Name: Hoofdentree; Number: 0.16
Phasing - Phase: 2. nieuwbouw
Text - bouwbesluit_functie: verkeersruimte

# IfcSpace: Kantoor 0.26:5207261, 0.26
In: 00 Begane grond
LongName: Kantoor; InteriorOrExteriorSpace: INTERNAL
Pset_AirSideSystemInformation - Name: Kantoor
Pset_ProductRequirements - Name: Kantoor; Category: Rooms
Pset_SpaceCommon - Reference: Kantoor 0.26; Category: Rooms
BaseQuantities - NetFloorArea: 13.6652 m2; Height: 2600 mm; GrossPerimeter: 15520.1 mm; GrossFloorArea: 13.6652 m2; GrossVolume: 35.5295 m3
Other - Category: Rooms; Phase Id: 0
Constraints - Base Offset: 0 mm; Upper Limit: 0; Level: 0; Limit Offset: 2600 mm
Dimensions - Computation Height: 0 mm; Area: 13.6652 m2; Perimeter: 15647.7 mm; Unbounded Height: 2600 mm; Volume: 35.5295 m3
Energy Analysis - Actual Lighting Load per area: 0; Actual Power Load per area: 0; Base Lighting Load on: By Space Type; Base Power Load on: By Space Type; Heat Load Values: By Space Type; Lighting Load Units: Power Density; Number of People: 0; Power Load Units: Power Density; Actual Lighting Load: 0 W; Actual Power Load: 0 W; Area per Person: 28.5714 m2; Latent Heat Gain per person: 58.6142 W; Plenum Lighting Contribution: 20; Sensible Heat Gain per person: 73.2678 W; Specified Lighting Load: 0 W; Specified Lighting Load per area: 10.7639; Specified Power Load: 0 W; Specified Power Load per area: 13.9931; Total Heat Gain per person: 131.882 W
Identity Data - Workset: Bouwkundig; Name: Kantoor; Number: 0.26
Phasing - Phase: 2. nieuwbouw
Text - bezettingsgraadklasse: 2; bouwbesluit_functie: verblijfsruimte

# IfcSpace: Kantoor 0.27:5207260, 0.27
In: 00 Begane grond
LongName: Kantoor; InteriorOrExteriorSpace: INTERNAL
Pset_AirSideSystemInformation - Name: Kantoor
Pset_ProductRequirements - Name: Kantoor; Category: Rooms
Pset_SpaceCommon - Reference: Kantoor 0.27; Category: Rooms
BaseQuantities - NetFloorArea: 13.7113 m2; Height: 2600 mm; GrossPerimeter: 15731 mm; GrossFloorArea: 13.7113 m2; GrossVolume: 35.6493 m3
Other - Category: Rooms; Phase Id: 0
Constraints - Base Offset: 0 mm; Upper Limit: 0; Level: 0; Limit Offset: 2600 mm
Dimensions - Computation Height: 0 mm; Area: 13.7113 m2; Perimeter: 15800.4 mm; Unbounded Height: 2600 mm; Volume: 35.6493 m3
Energy Analysis - Actual Lighting Load per area: 0; Actual Power Load per area: 0; Base Lighting Load on: By Space Type; Base Power Load on: By Space Type; Heat Load Values: By Space Type; Lighting Load Units: Power Density; Number of People: 0; Power Load Units: Power Density; Actual Lighting Load: 0 W; Actual Power Load: 0 W; Area per Person: 28.5714 m2; Latent Heat Gain per person: 58.6142 W; Plenum Lighting Contribution: 20; Sensible Heat Gain per person: 73.2678 W; Specified Lighting Load: 0 W; Specified Lighting Load per area: 10.7639; Specified Power Load: 0 W; Specified Power Load per area: 13.9931; Total Heat Gain per person: 131.882 W
Identity Data - Workset: Bouwkundig; Name: Kantoor; Number: 0.27
Phasing - Phase: 2. nieuwbouw
Text - bezettingsgraadklasse: 2; bouwbesluit_functie: verblijfsruimte

# IfcSpace: Kantoor 0.29:5206989, 0.29
In: 00 Begane grond
LongName: Kantoor; InteriorOrExteriorSpace: INTERNAL
Pset_AirSideSystemInformation - Name: Kantoor
Pset_ProductRequirements - Name: Kantoor; Category: Rooms
Pset_SpaceCommon - Reference: Kantoor 0.29; Category: Rooms
BaseQuantities - NetFloorArea: 18.8993 m2; Height: 2600 mm; GrossPerimeter: 20611.9 mm; GrossFloorArea: 18.8993 m2; GrossVolume: 49.1381 m3
Other - Category: Rooms; Phase Id: 0
Constraints - Base Offset: 0 mm; Level: 0; Limit Offset: 2600 mm; Upper Limit: 0
Dimensions - Area: 18.8993 m2; Computation Height: 0 mm; Perimeter: 20611.9 mm; Unbounded Height: 2600 mm; Volume: 49.1381 m3
Energy Analysis - Actual Lighting Load: 0 W; Actual Lighting Load per area: 0; Actual Power Load: 0 W; Actual Power Load per area: 0; Area per Person: 28.5714 m2; Base Lighting Load on: By Space Type; Base Power Load on: By Space Type; Heat Load Values: By Space Type; Latent Heat Gain per person: 58.6142 W; Lighting Load Units: Power Density; Number of People: 0; Plenum Lighting Contribution: 20; Power Load Units: Power Density; Sensible Heat Gain per person: 73.2678 W; Specified Lighting Load: 0 W; Specified Lighting Load per area: 10.7639; Specified Power Load: 0 W; Specified Power Load per area: 13.9931; Total Heat Gain per person: 131.882 W
Identity Data - Name: Kantoor; Number: 0.29; Workset: Bouwkundig
Phasing - Phase: 2. nieuwbouw
Text - bezettingsgraadklasse: 2; bouwbesluit_functie: verblijfsruimte

# IfcSpace: Kantoor 1.16:5212698, 1.16
In: 01 eerste verdieping
LongName: Kantoor; InteriorOrExteriorSpace: INTERNAL
Pset_AirSideSystemInformation - Name: Kantoor
Pset_ProductRequirements - Name: Kantoor; Category: Rooms
Pset_SpaceCommon - Reference: Kantoor 1.16; Category: Rooms
BaseQuantities - NetFloorArea: 14.4305 m2; Height: 2600 mm; GrossPerimeter: 16170 mm; GrossFloorArea: 14.4305 m2; GrossVolume: 37.5193 m3
Other - Category: Rooms; Phase Id: 0
Constraints - Base Offset: 0 mm; Upper Limit: 1; Level: 1; Limit Offset: 2600 mm
Dimensions - Computation Height: 0 mm; Area: 14.4305 m2; Perimeter: 16170 mm; Unbounded Height: 2600 mm; Volume: 37.5193 m3
Energy Analysis - Actual Lighting Load per area: 0; Actual Power Load per area: 0; Base Lighting Load on: By Space Type; Base Power Load on: By Space Type; Heat Load Values: By Space Type; Lighting Load Units: Power Density; Number of People: 0; Power Load Units: Power Density; Actual Lighting Load: 0 W; Actual Power Load: 0 W; Area per Person: 28.5714 m2; Latent Heat Gain per person: 58.6142 W; Plenum Lighting Contribution: 20; Sensible Heat Gain per person: 73.2678 W; Specified Lighting Load: 0 W; Specified Lighting Load per area: 10.7639; Specified Power Load: 0 W; Specified Power Load per area: 13.9931; Total Heat Gain per person: 131.882 W
Identity Data - Workset: Bouwkundig; Name: Kantoor; Number: 1.16
Phasing - Phase: 2. nieuwbouw
Text - bezettingsgraadklasse: 2; bouwbesluit_functie: overige ruimte

# IfcSpace: Kantoor 1.17:5212700, 1.17
In: 01 eerste verdieping
LongName: Kantoor; InteriorOrExteriorSpace: INTERNAL
Pset_AirSideSystemInformation - Name: Kantoor
Pset_ProductRequirements - Name: Kantoor; Category: Rooms
Pset_SpaceCommon - Reference: Kantoor 1.17; Category: Rooms
BaseQuantities - NetFloorArea: 12.4785 m2; Height: 2600 mm; GrossPerimeter: 14360 mm; GrossFloorArea: 12.4785 m2; GrossVolume: 32.4441 m3
Other - Category: Rooms; Phase Id: 0
Constraints - Base Offset: 0 mm; Upper Limit: 1; Level: 1; Limit Offset: 2600 mm
Dimensions - Computation Height: 0 mm; Area: 12.4785 m2; Perimeter: 14360 mm; Unbounded Height: 2600 mm; Volume: 32.4441 m3
Energy Analysis - Actual Lighting Load per area: 0; Actual Power Load per area: 0; Base Lighting Load on: By Space Type; Base Power Load on: By Space Type; Heat Load Values: By Space Type; Lighting Load Units: Power Density; Number of People: 0; Power Load Units: Power Density; Actual Lighting Load: 0 W; Actual Power Load: 0 W; Area per Person: 28.5714 m2; Latent Heat Gain per person: 58.6142 W; Plenum Lighting Contribution: 20; Sensible Heat Gain per person: 73.2678 W; Specified Lighting Load: 0 W; Specified Lighting Load per area: 10.7639; Specified Power Load: 0 W; Specified Power Load per area: 13.9931; Total Heat Gain per person: 131.882 W
Identity Data - Workset: Bouwkundig; Name: Kantoor; Number: 1.17
Phasing - Phase: 2. nieuwbouw
Text - bezettingsgraadklasse: 2; bouwbesluit_functie: overige ruimte

# IfcSpace: Kastruimte 0.15a:5980794, 0.15a
In: 00 Begane grond
LongName: Kastruimte; InteriorOrExteriorSpace: INTERNAL
Pset_AirSideSystemInformation - Name: Kastruimte
Pset_ProductRequirements - Name: Kastruimte; Category: Rooms
Pset_SpaceCommon - Reference: Kastruimte 0.15a; Category: Rooms
BaseQuantities - NetFloorArea: 8.27925 m2; Height: 2438.4 mm; GrossPerimeter: 48010 mm; GrossFloorArea: 8.27925 m2; GrossVolume: 20.1881 m3
Other - Category: Rooms; Phase Id: 0
Constraints - Base Offset: 0 mm; Upper Limit: 0; Limit Offset: 2438.4 mm; Level: 0
Dimensions - Computation Height: 0 mm; Unbounded Height: 2438.4 mm; Area: 8.27925 m2; Perimeter: 48010 mm; Volume: 20.1881 m3
Energy Analysis - Actual Lighting Load per area: 0; Actual Power Load per area: 0; Base Lighting Load on: By Space Type; Base Power Load on: By Space Type; Heat Load Values: By Space Type; Lighting Load Units: Power Density; Number of People: 0; Power Load Units: Power Density; Actual Lighting Load: 0 W; Actual Power Load: 0 W; Area per Person: 28.5714 m2; Latent Heat Gain per person: 58.6142 W; Plenum Lighting Contribution: 20; Sensible Heat Gain per person: 73.2678 W; Specified Lighting Load: 0 W; Specified Lighting Load per area: 10.7639; Specified Power Load: 0 W; Specified Power Load per area: 13.9931; Total Heat Gain per person: 131.882 W
Identity Data - Workset: Bouwkundig; Name: Kastruimte; Number: 0.15a
Phasing - Phase: 2. nieuwbouw
Text - bouwbesluit_functie: opslagruimte

# IfcSpace: Kastruimte 1.10:5220931, 1.10
In: 01 eerste verdieping
LongName: Kastruimte; InteriorOrExteriorSpace: INTERNAL
Pset_AirSideSystemInformation - Name: Kastruimte
Pset_ProductRequirements - Name: Kastruimte; Category: Rooms
Pset_SpaceCommon - Reference: Kastruimte 1.10; Category: Rooms
BaseQuantities - NetFloorArea: 2.892 m2; Height: 2600 mm; GrossFloorArea: 2.892 m2; GrossVolume: 7.5192 m3
Other - Category: Rooms; Phase Id: 0
Constraints - Base Offset: 0 mm; Upper Limit: 1; Level: 1; Limit Offset: 2600 mm
Dimensions - Computation Height: 0 mm; Area: 2.892 m2; Perimeter: 10827.2 mm; Unbounded Height: 2600 mm; Volume: 6.9649 m3
Energy Analysis - Actual Lighting Load per area: 0; Actual Power Load per area: 0; Base Lighting Load on: By Space Type; Base Power Load on: By Space Type; Heat Load Values: By Space Type; Lighting Load Units: Power Density; Number of People: 0; Power Load Units: Power Density; Actual Lighting Load: 0 W; Actual Power Load: 0 W; Area per Person: 28.5714 m2; Latent Heat Gain per person: 58.6142 W; Plenum Lighting Contribution: 20; Sensible Heat Gain per person: 73.2678 W; Specified Lighting Load: 0 W; Specified Lighting Load per area: 10.7639; Specified Power Load: 0 W; Specified Power Load per area: 13.9931; Total Heat Gain per person: 131.882 W
Identity Data - Workset: Bouwkundig; Name: Kastruimte; Number: 1.10
Phasing - Phase: 2. nieuwbouw
Text - bouwbesluit_functie: opslagruimte

# IfcSpace: Keuken 0.44:5311100, 0.44
In: 00 Begane grond
LongName: Keuken; InteriorOrExteriorSpace: INTERNAL
Pset_AirSideSystemInformation - Name: Keuken
Pset_ProductRequirements - Name: Keuken; Category: Rooms
Pset_SpaceCommon - Reference: Keuken 0.44; Category: Rooms
BaseQuantities - NetFloorArea: 9.3117 m2; Height: 2438.4 mm; GrossPerimeter: 14700 mm; GrossFloorArea: 9.3117 m2; GrossVolume: 22.7056 m3
Other - Category: Rooms; Phase Id: 0
Constraints - Base Offset: 0 mm; Upper Limit: 0; Limit Offset: 2438.4 mm; Level: 0
Dimensions - Computation Height: 0 mm; Unbounded Height: 2438.4 mm; Area: 9.3117 m2; Perimeter: 14700 mm; Volume: 22.7056 m3
Energy Analysis - Actual Lighting Load per area: 0; Actual Power Load per area: 0; Base Lighting Load on: By Space Type; Base Power Load on: By Space Type; Heat Load Values: By Space Type; Lighting Load Units: Power Density; Number of People: 0; Power Load Units: Power Density; Actual Lighting Load: 0 W; Actual Power Load: 0 W; Area per Person: 28.5714 m2; Latent Heat Gain per person: 58.6142 W; Plenum Lighting Contribution: 20; Sensible Heat Gain per person: 73.2678 W; Specified Lighting Load: 0 W; Specified Lighting Load per area: 10.7639; Specified Power Load: 0 W; Specified Power Load per area: 13.9931; Total Heat Gain per person: 131.882 W
Identity Data - Workset: Bouwkundig; Name: Keuken; Number: 0.44
Phasing - Phase: 2. nieuwbouw
Text - bouwbesluit_functie: overige ruimte

# IfcSpace: Leerplein 0.33:5207283, 0.33
In: 00 Begane grond
LongName: Leerplein; InteriorOrExteriorSpace: INTERNAL
Pset_AirSideSystemInformation - Name: Leerplein
Pset_ProductRequirements - Name: Leerplein; Category: Rooms
Pset_SpaceCommon - Reference: Leerplein 0.33; Category: Rooms
BaseQuantities - NetFloorArea: 84.9762 m2; Height: 2600 mm; GrossFloorArea: 84.9762 m2; GrossVolume: 220.938 m3
Other - Category: Rooms; Phase Id: 0
Constraints - Base Offset: 0 mm; Upper Limit: 0; Level: 0; Limit Offset: 2600 mm
Dimensions - Computation Height: 0 mm; Area: 84.9762 m2; Perimeter: 59538.9 mm; Unbounded Height: 2600 mm; Volume: 216.532 m3
Energy Analysis - Actual Lighting Load per area: 0; Actual Power Load per area: 0; Base Lighting Load on: By Space Type; Base Power Load on: By Space Type; Heat Load Values: By Space Type; Lighting Load Units: Power Density; Number of People: 0; Power Load Units: Power Density; Actual Lighting Load: 0 W; Actual Power Load: 0 W; Area per Person: 28.5714 m2; Latent Heat Gain per person: 58.6142 W; Plenum Lighting Contribution: 20; Sensible Heat Gain per person: 73.2678 W; Specified Lighting Load: 0 W; Specified Lighting Load per area: 10.7639; Specified Power Load: 0 W; Specified Power Load per area: 13.9931; Total Heat Gain per person: 131.882 W
Identity Data - Workset: Bouwkundig; Name: Leerplein; Number: 0.33
Phasing - Phase: 2. nieuwbouw
Text - bouwbesluit_functie: verkeersruimte

# IfcSpace: Leerplein 1.11:5212710, 1.11
In: 01 eerste verdieping
LongName: Leerplein; InteriorOrExteriorSpace: INTERNAL
Pset_AirSideSystemInformation - Name: Leerplein
Pset_ProductRequirements - Name: Leerplein; Category: Rooms
Pset_SpaceCommon - Reference: Leerplein 1.11; Category: Rooms
BaseQuantities - NetFloorArea: 108.024 m2; Height: 2600 mm; GrossFloorArea: 108.024 m2; GrossVolume: 280.862 m3
Other - Category: Rooms; Phase Id: 0
Constraints - Base Offset: 0 mm; Upper Limit: 1; Level: 1; Limit Offset: 2600 mm
Dimensions - Computation Height: 0 mm; Area: 108.024 m2; Perimeter: 82002 mm; Unbounded Height: 2600 mm; Volume: 278.051 m3
Energy Analysis - Actual Lighting Load per area: 0; Actual Power Load per area: 0; Base Lighting Load on: By Space Type; Base Power Load on: By Space Type; Heat Load Values: By Space Type; Lighting Load Units: Power Density; Number of People: 0; Power Load Units: Power Density; Actual Lighting Load: 0 W; Actual Power Load: 0 W; Area per Person: 28.5714 m2; Latent Heat Gain per person: 58.6142 W; Plenum Lighting Contribution: 20; Sensible Heat Gain per person: 73.2678 W; Specified Lighting Load: 0 W; Specified Lighting Load per area: 10.7639; Specified Power Load: 0 W; Specified Power Load per area: 13.9931; Total Heat Gain per person: 131.882 W
Identity Data - Workset: Bouwkundig; Name: Leerplein; Number: 1.11
Phasing - Phase: 2. nieuwbouw
Text - bouwbesluit_functie: verkeersruimte

# IfcSpace: Leerplein 1.12:5212721, 1.12
In: 01 eerste verdieping
LongName: Leerplein; InteriorOrExteriorSpace: INTERNAL
Pset_AirSideSystemInformation - Name: Leerplein
Pset_ProductRequirements - Name: Leerplein; Category: Rooms
Pset_SpaceCommon - Reference: Leerplein 1.12; Category: Rooms
BaseQuantities - NetFloorArea: 51.6118 m2; Height: 2600 mm; GrossFloorArea: 51.6118 m2; GrossVolume: 134.191 m3
Other - Category: Rooms; Phase Id: 0
Constraints - Base Offset: 0 mm; Upper Limit: 1; Level: 1; Limit Offset: 2600 mm
Dimensions - Computation Height: 0 mm; Area: 51.6118 m2; Perimeter: 58824.4 mm; Unbounded Height: 2600 mm; Volume: 133.836 m3
Energy Analysis - Actual Lighting Load per area: 0; Actual Power Load per area: 0; Base Lighting Load on: By Space Type; Base Power Load on: By Space Type; Heat Load Values: By Space Type; Lighting Load Units: Power Density; Number of People: 0; Power Load Units: Power Density; Actual Lighting Load: 0 W; Actual Power Load: 0 W; Area per Person: 28.5714 m2; Latent Heat Gain per person: 58.6142 W; Plenum Lighting Contribution: 20; Sensible Heat Gain per person: 73.2678 W; Specified Lighting Load: 0 W; Specified Lighting Load per area: 10.7639; Specified Power Load: 0 W; Specified Power Load per area: 13.9931; Total Heat Gain per person: 131.882 W
Identity Data - Workset: Bouwkundig; Name: Leerplein; Number: 1.12
Phasing - Phase: 2. nieuwbouw
Text - bouwbesluit_functie: verkeersruimte

# IfcSpace: Leerplein 1.20:5212720, 1.20
In: 01 eerste verdieping
LongName: Leerplein; InteriorOrExteriorSpace: INTERNAL
Pset_AirSideSystemInformation - Name: Leerplein
Pset_ProductRequirements - Name: Leerplein; Category: Rooms
Pset_SpaceCommon - Reference: Leerplein 1.20; Category: Rooms
BaseQuantities - NetFloorArea: 80.8009 m2; Height: 2600 mm; GrossFloorArea: 80.8009 m2; GrossVolume: 210.082 m3
Other - Category: Rooms; Phase Id: 0
Constraints - Base Offset: 0 mm; Upper Limit: 1; Level: 1; Limit Offset: 2600 mm
Dimensions - Computation Height: 0 mm; Area: 80.8009 m2; Perimeter: 56043.4 mm; Unbounded Height: 2600 mm; Volume: 208.124 m3
Energy Analysis - Actual Lighting Load per area: 0; Actual Power Load per area: 0; Base Lighting Load on: By Space Type; Base Power Load on: By Space Type; Heat Load Values: By Space Type; Lighting Load Units: Power Density; Number of People: 0; Power Load Units: Power Density; Actual Lighting Load: 0 W; Actual Power Load: 0 W; Area per Person: 28.5714 m2; Latent Heat Gain per person: 58.6142 W; Plenum Lighting Contribution: 20; Sensible Heat Gain per person: 73.2678 W; Specified Lighting Load: 0 W; Specified Lighting Load per area: 10.7639; Specified Power Load: 0 W; Specified Power Load per area: 13.9931; Total Heat Gain per person: 131.882 W
Identity Data - Workset: Bouwkundig; Name: Leerplein; Number: 1.20
Phasing - Phase: 2. nieuwbouw
Text - bouwbesluit_functie: verkeersruimte

# IfcSpace: Lift 0.00:5207251, 0.00
In: 00 Begane grond
LongName: Lift; InteriorOrExteriorSpace: INTERNAL
Pset_AirSideSystemInformation - Name: Lift
Pset_ProductRequirements - Name: Lift; Category: Rooms
Pset_SpaceCommon - Reference: Lift 0.00; Category: Rooms
BaseQuantities - NetFloorArea: 2.68095 m2; Height: 6047.98 mm; GrossFloorArea: 2.68095 m2; GrossVolume: 16.2143 m3
Other - Category: Rooms; Phase Id: 0
Constraints - Base Offset: 0 mm; Upper Limit: 0; Level: 0; Limit Offset: 6047.98 mm
Dimensions - Computation Height: 0 mm; Area: 2.68095 m2; Perimeter: 6605.92 mm; Unbounded Height: 6047.98 mm; Volume: 16.045 m3
Energy Analysis - Actual Lighting Load per area: 0; Actual Power Load per area: 0; Base Lighting Load on: By Space Type; Base Power Load on: By Space Type; Heat Load Values: By Space Type; Lighting Load Units: Power Density; Number of People: 0; Power Load Units: Power Density; Actual Lighting Load: 0 W; Actual Power Load: 0 W; Area per Person: 28.5714 m2; Latent Heat Gain per person: 58.6142 W; Plenum Lighting Contribution: 20; Sensible Heat Gain per person: 73.2678 W; Specified Lighting Load: 0 W; Specified Lighting Load per area: 10.7639; Specified Power Load: 0 W; Specified Power Load per area: 13.9931; Total Heat Gain per person: 131.882 W
Identity Data - Workset: Bouwkundig; Name: Lift; Number: 0.00
Phasing - Phase: 2. nieuwbouw
Text - bouwbesluit_functie: verkeersruimte

# IfcSpace: MiVa-toilet 0.18:5207281, 0.18
In: 00 Begane grond
LongName: MiVa-toilet; InteriorOrExteriorSpace: INTERNAL
Pset_AirSideSystemInformation - Name: MiVa-toilet
Pset_ProductRequirements - Name: MiVa-toilet; Category: Rooms
Pset_SpaceCommon - Reference: MiVa-toilet 0.18; Category: Rooms
BaseQuantities - NetFloorArea: 4.329 m2; Height: 2600 mm; GrossPerimeter: 8340 mm; GrossFloorArea: 4.329 m2; GrossVolume: 11.2554 m3
Other - Category: Rooms; Phase Id: 0
Constraints - Base Offset: 0 mm; Upper Limit: 0; Level: 0; Limit Offset: 2600 mm
Dimensions - Computation Height: 0 mm; Area: 4.329 m2; Perimeter: 8340 mm; Unbounded Height: 2600 mm; Volume: 10.3896 m3
Energy Analysis - Actual Lighting Load per area: 0; Actual Power Load per area: 0; Base Lighting Load on: By Space Type; Base Power Load on: By Space Type; Heat Load Values: By Space Type; Lighting Load Units: Power Density; Number of People: 0; Power Load Units: Power Density; Actual Lighting Load: 0 W; Actual Power Load: 0 W; Area per Person: 28.5714 m2; Latent Heat Gain per person: 58.6142 W; Plenum Lighting Contribution: 20; Sensible Heat Gain per person: 73.2678 W; Specified Lighting Load: 0 W; Specified Lighting Load per area: 10.7639; Specified Power Load: 0 W; Specified Power Load per area: 13.9931; Total Heat Gain per person: 131.882 W
Identity Data - Workset: Bouwkundig; Name: MiVa-toilet; Number: 0.18
Phasing - Phase: 2. nieuwbouw
Text - bouwbesluit_functie: toiletruimte
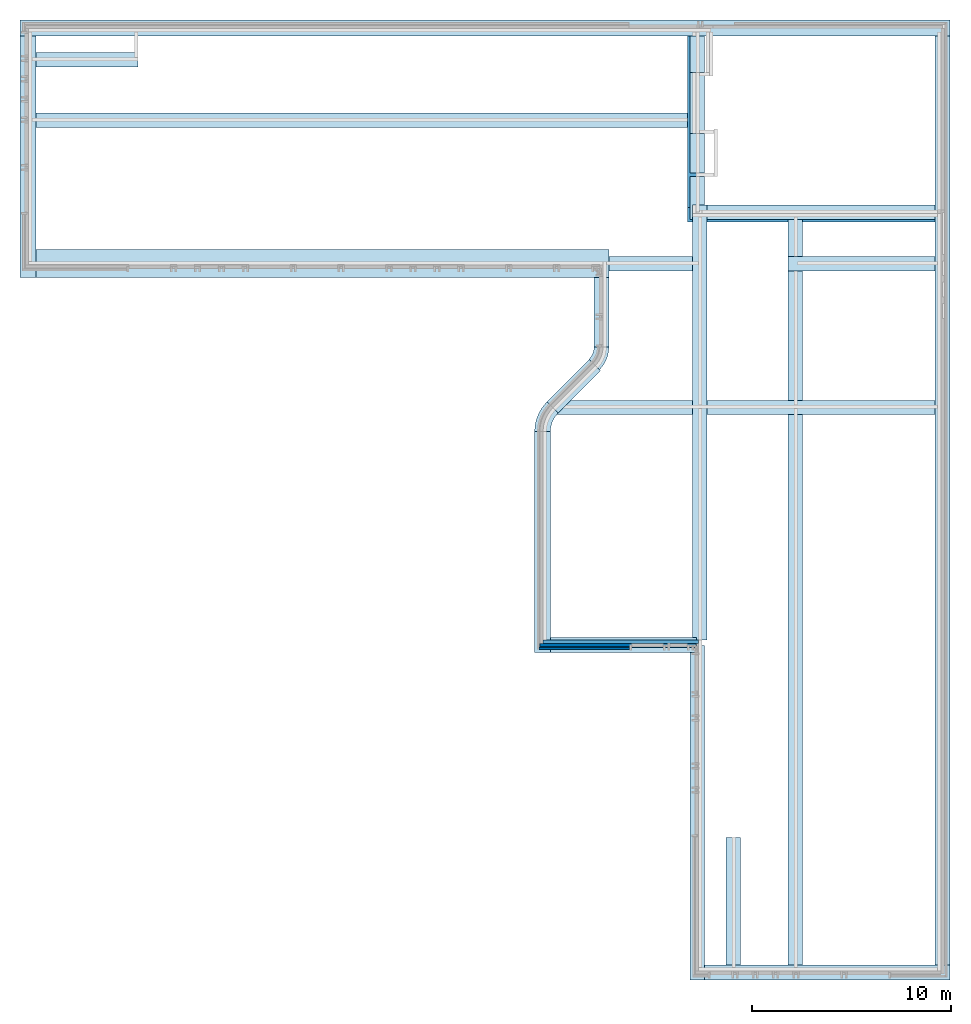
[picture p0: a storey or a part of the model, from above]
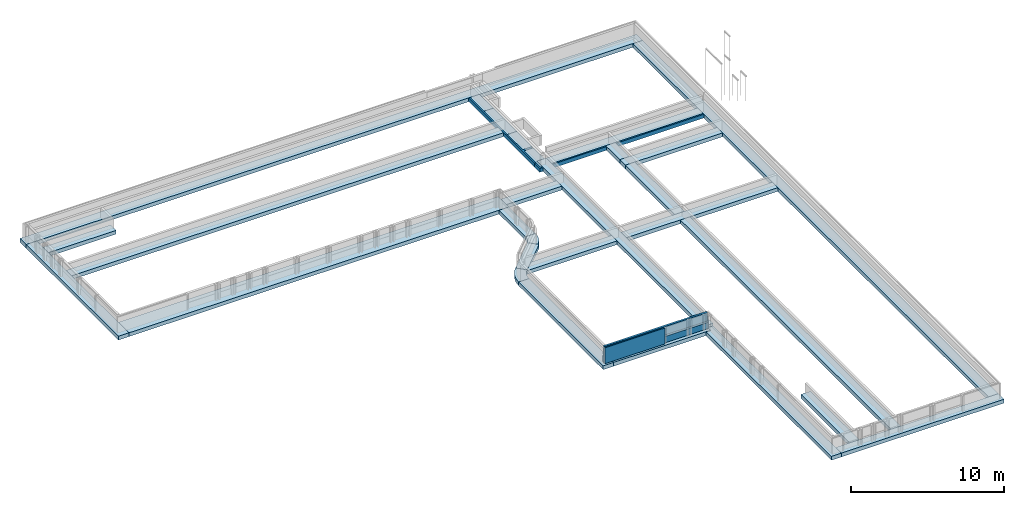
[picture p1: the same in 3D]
Properties of the parts of a building model (IFC2X3), part 2 of 37

# IfcSpace: Ontmoeten 0.20:5207280, 0.20
In: 00 Begane grond
LongName: Ontmoeten; InteriorOrExteriorSpace: INTERNAL
Pset_AirSideSystemInformation - Name: Ontmoeten
Pset_ProductRequirements - Name: Ontmoeten; Category: Rooms
Pset_SpaceCommon - Reference: Ontmoeten 0.20; Category: Rooms
BaseQuantities - NetFloorArea: 113.701 m2; Height: 2600 mm; GrossFloorArea: 113.701 m2; GrossVolume: 295.622 m3
Other - Category: Rooms; Phase Id: 0
Constraints - Base Offset: 0 mm; Upper Limit: 0; Level: 0; Limit Offset: 2600 mm
Dimensions - Computation Height: 0 mm; Area: 113.701 m2; Perimeter: 73110 mm; Unbounded Height: 2600 mm; Volume: 294.216 m3
Energy Analysis - Actual Lighting Load per area: 0; Actual Power Load per area: 0; Base Lighting Load on: By Space Type; Base Power Load on: By Space Type; Heat Load Values: By Space Type; Lighting Load Units: Power Density; Number of People: 0; Power Load Units: Power Density; Actual Lighting Load: 0 W; Actual Power Load: 0 W; Area per Person: 28.5714 m2; Latent Heat Gain per person: 58.6142 W; Plenum Lighting Contribution: 20; Sensible Heat Gain per person: 73.2678 W; Specified Lighting Load: 0 W; Specified Lighting Load per area: 10.7639; Specified Power Load: 0 W; Specified Power Load per area: 13.9931; Total Heat Gain per person: 131.882 W
Identity Data - Workset: Bouwkundig; Name: Ontmoeten; Number: 0.20
Phasing - Phase: 2. nieuwbouw
Text - bouwbesluit_functie: verkeersruimte

# IfcSpace: Opslag 0.40:5218797, 0.40
In: 00 Begane grond
LongName: Opslag; InteriorOrExteriorSpace: INTERNAL
Pset_AirSideSystemInformation - Name: Opslag
Pset_ProductRequirements - Name: Opslag; Category: Rooms
Pset_SpaceCommon - Reference: Opslag 0.40; Category: Rooms
BaseQuantities - NetFloorArea: 5.35267 m2; Height: 2600 mm; GrossPerimeter: 10140 mm; GrossFloorArea: 5.35267 m2; GrossVolume: 13.9169 m3
Other - Category: Rooms; Phase Id: 0
Constraints - Base Offset: 0 mm; Upper Limit: 0; Level: 0; Limit Offset: 2600 mm
Dimensions - Computation Height: 0 mm; Area: 5.35267 m2; Perimeter: 10140 mm; Unbounded Height: 2600 mm; Volume: 13.9169 m3
Energy Analysis - Actual Lighting Load per area: 0; Actual Power Load per area: 0; Base Lighting Load on: By Space Type; Base Power Load on: By Space Type; Heat Load Values: By Space Type; Lighting Load Units: Power Density; Number of People: 0; Power Load Units: Power Density; Actual Lighting Load: 0 W; Actual Power Load: 0 W; Area per Person: 28.5714 m2; Latent Heat Gain per person: 58.6142 W; Plenum Lighting Contribution: 20; Sensible Heat Gain per person: 73.2678 W; Specified Lighting Load: 0 W; Specified Lighting Load per area: 10.7639; Specified Power Load: 0 W; Specified Power Load per area: 13.9931; Total Heat Gain per person: 131.882 W
Identity Data - Workset: Bouwkundig; Name: Opslag; Number: 0.40
Phasing - Phase: 2. nieuwbouw
Text - bouwbesluit_functie: opslagruimte

# IfcSpace: Opslag algemeen 0.34:5218394, 0.34
In: 00 Begane grond
LongName: Opslag algemeen; InteriorOrExteriorSpace: INTERNAL
Pset_AirSideSystemInformation - Name: Opslag algemeen
Pset_ProductRequirements - Name: Opslag algemeen; Category: Rooms
Pset_SpaceCommon - Reference: Opslag algemeen 0.34; Category: Rooms
BaseQuantities - NetFloorArea: 23.67 m2; Height: 2600 mm; GrossPerimeter: 21007.5 mm; GrossFloorArea: 23.67 m2; GrossVolume: 61.5421 m3
Other - Category: Rooms; Phase Id: 0
Constraints - Base Offset: 0 mm; Upper Limit: 0; Level: 0; Limit Offset: 2600 mm
Dimensions - Computation Height: 0 mm; Area: 23.67 m2; Perimeter: 21007.5 mm; Unbounded Height: 2600 mm; Volume: 61.5421 m3
Energy Analysis - Actual Lighting Load per area: 0; Actual Power Load per area: 0; Base Lighting Load on: By Space Type; Base Power Load on: By Space Type; Heat Load Values: By Space Type; Lighting Load Units: Power Density; Number of People: 0; Power Load Units: Power Density; Actual Lighting Load: 0 W; Actual Power Load: 0 W; Area per Person: 28.5714 m2; Latent Heat Gain per person: 58.6142 W; Plenum Lighting Contribution: 20; Sensible Heat Gain per person: 73.2678 W; Specified Lighting Load: 0 W; Specified Lighting Load per area: 10.7639; Specified Power Load: 0 W; Specified Power Load per area: 13.9931; Total Heat Gain per person: 131.882 W
Identity Data - Workset: Bouwkundig; Name: Opslag algemeen; Number: 0.34
Phasing - Phase: 2. nieuwbouw
Text - bouwbesluit_functie: opslagruimte

# IfcSpace: PSZ/BSO 0.09:5207274, 0.09
In: 00 Begane grond
LongName: PSZ/BSO; InteriorOrExteriorSpace: INTERNAL
Pset_AirSideSystemInformation - Name: PSZ/BSO
Pset_ProductRequirements - Name: PSZ/BSO; Category: Rooms
Pset_SpaceCommon - Reference: PSZ/BSO 0.09; Category: Rooms
BaseQuantities - NetFloorArea: 59.4864 m2; Height: 2600 mm; GrossFloorArea: 59.4864 m2; GrossVolume: 154.665 m3
Other - Category: Rooms; Phase Id: 0
Constraints - Base Offset: 0 mm; Upper Limit: 0; Level: 0; Limit Offset: 2600 mm
Dimensions - Computation Height: 0 mm; Area: 59.4864 m2; Perimeter: 32770 mm; Unbounded Height: 2600 mm; Volume: 154.403 m3
Energy Analysis - Actual Lighting Load per area: 0; Actual Power Load per area: 0; Base Lighting Load on: By Space Type; Base Power Load on: By Space Type; Heat Load Values: By Space Type; Lighting Load Units: Power Density; Number of People: 0; Power Load Units: Power Density; Actual Lighting Load: 0 W; Actual Power Load: 0 W; Area per Person: 28.5714 m2; Latent Heat Gain per person: 58.6142 W; Plenum Lighting Contribution: 20; Sensible Heat Gain per person: 73.2678 W; Specified Lighting Load: 0 W; Specified Lighting Load per area: 10.7639; Specified Power Load: 0 W; Specified Power Load per area: 13.9931; Total Heat Gain per person: 131.882 W
Identity Data - Workset: Bouwkundig; Name: PSZ/BSO; Number: 0.09
Phasing - Phase: 2. nieuwbouw
Text - bezettingsgraadklasse: 20; bouwbesluit_functie: verblijfsruimte

# IfcSpace: Server 1.15:5212699, 1.15
In: 01 eerste verdieping
LongName: Server; InteriorOrExteriorSpace: INTERNAL
Pset_AirSideSystemInformation - Name: Server
Pset_ProductRequirements - Name: Server; Category: Rooms
Pset_SpaceCommon - Reference: Server 1.15; Category: Rooms
BaseQuantities - NetFloorArea: 4.0565 m2; Height: 2600 mm; GrossPerimeter: 8370 mm; GrossFloorArea: 4.0565 m2; GrossVolume: 10.5469 m3
Other - Category: Rooms; Phase Id: 0
Constraints - Base Offset: 0 mm; Upper Limit: 1; Level: 1; Limit Offset: 2600 mm
Dimensions - Computation Height: 0 mm; Area: 4.0565 m2; Perimeter: 8370 mm; Unbounded Height: 2600 mm; Volume: 10.5469 m3
Energy Analysis - Actual Lighting Load per area: 0; Actual Power Load per area: 0; Base Lighting Load on: By Space Type; Base Power Load on: By Space Type; Heat Load Values: By Space Type; Lighting Load Units: Power Density; Number of People: 0; Power Load Units: Power Density; Actual Lighting Load: 0 W; Actual Power Load: 0 W; Area per Person: 28.5714 m2; Latent Heat Gain per person: 58.6142 W; Plenum Lighting Contribution: 20; Sensible Heat Gain per person: 73.2678 W; Specified Lighting Load: 0 W; Specified Lighting Load per area: 10.7639; Specified Power Load: 0 W; Specified Power Load per area: 13.9931; Total Heat Gain per person: 131.882 W
Identity Data - Workset: Bouwkundig; Name: Server; Number: 1.15
Phasing - Phase: 2. nieuwbouw
Text - bouwbesluit_functie: technische ruimte

# IfcSpace: Slaapkamer 0.02:5207253, 0.02
In: 00 Begane grond
LongName: Slaapkamer; InteriorOrExteriorSpace: INTERNAL
Pset_AirSideSystemInformation - Name: Slaapkamer
Pset_ProductRequirements - Name: Slaapkamer; Category: Rooms
Pset_SpaceCommon - Reference: Slaapkamer 0.02; Category: Rooms
BaseQuantities - NetFloorArea: 9.09455 m2; Height: 2600 mm; GrossFloorArea: 9.09455 m2; GrossVolume: 23.6458 m3
Other - Category: Rooms; Phase Id: 0
Constraints - Base Offset: 0 mm; Upper Limit: 0; Level: 0; Limit Offset: 2600 mm
Dimensions - Computation Height: 0 mm; Area: 9.09455 m2; Perimeter: 12312 mm; Unbounded Height: 2600 mm; Volume: 21.8333 m3
Energy Analysis - Actual Lighting Load per area: 0; Actual Power Load per area: 0; Base Lighting Load on: By Space Type; Base Power Load on: By Space Type; Heat Load Values: By Space Type; Lighting Load Units: Power Density; Number of People: 0; Power Load Units: Power Density; Actual Lighting Load: 0 W; Actual Power Load: 0 W; Area per Person: 28.5714 m2; Latent Heat Gain per person: 58.6142 W; Plenum Lighting Contribution: 20; Sensible Heat Gain per person: 73.2678 W; Specified Lighting Load: 0 W; Specified Lighting Load per area: 10.7639; Specified Power Load: 0 W; Specified Power Load per area: 13.9931; Total Heat Gain per person: 131.882 W
Identity Data - Workset: Bouwkundig; Name: Slaapkamer; Number: 0.02
Phasing - Phase: 2. nieuwbouw
Text - bouwbesluit_functie: overige ruimte

# IfcSpace: Slaapkamer 0.03:5207252, 0.03
In: 00 Begane grond
LongName: Slaapkamer; InteriorOrExteriorSpace: INTERNAL
Pset_AirSideSystemInformation - Name: Slaapkamer
Pset_ProductRequirements - Name: Slaapkamer; Category: Rooms
Pset_SpaceCommon - Reference: Slaapkamer 0.03; Category: Rooms
BaseQuantities - NetFloorArea: 9.09455 m2; Height: 2600 mm; GrossFloorArea: 9.09455 m2; GrossVolume: 23.6458 m3
Other - Category: Rooms; Phase Id: 0
Constraints - Base Offset: 0 mm; Upper Limit: 0; Level: 0; Limit Offset: 2600 mm
Dimensions - Computation Height: 0 mm; Area: 9.09455 m2; Perimeter: 12312 mm; Unbounded Height: 2600 mm; Volume: 21.8333 m3
Energy Analysis - Actual Lighting Load per area: 0; Actual Power Load per area: 0; Base Lighting Load on: By Space Type; Base Power Load on: By Space Type; Heat Load Values: By Space Type; Lighting Load Units: Power Density; Number of People: 0; Power Load Units: Power Density; Actual Lighting Load: 0 W; Actual Power Load: 0 W; Area per Person: 28.5714 m2; Latent Heat Gain per person: 58.6142 W; Plenum Lighting Contribution: 20; Sensible Heat Gain per person: 73.2678 W; Specified Lighting Load: 0 W; Specified Lighting Load per area: 10.7639; Specified Power Load: 0 W; Specified Power Load per area: 13.9931; Total Heat Gain per person: 131.882 W
Identity Data - Workset: Bouwkundig; Name: Slaapkamer; Number: 0.03
Phasing - Phase: 2. nieuwbouw
Text - bouwbesluit_functie: overige ruimte

# IfcSpace: Slaapkamer 0.06:5207255, 0.06
In: 00 Begane grond
LongName: Slaapkamer; InteriorOrExteriorSpace: INTERNAL
Pset_AirSideSystemInformation - Name: Slaapkamer
Pset_ProductRequirements - Name: Slaapkamer; Category: Rooms
Pset_SpaceCommon - Reference: Slaapkamer 0.06; Category: Rooms
BaseQuantities - NetFloorArea: 9.13178 m2; Height: 2600 mm; GrossFloorArea: 9.13178 m2; GrossVolume: 23.7426 m3
Other - Category: Rooms; Phase Id: 0
Constraints - Base Offset: 0 mm; Upper Limit: 0; Level: 0; Limit Offset: 2600 mm
Dimensions - Computation Height: 0 mm; Area: 9.13178 m2; Perimeter: 12384 mm; Unbounded Height: 2600 mm; Volume: 21.9301 m3
Energy Analysis - Actual Lighting Load per area: 0; Actual Power Load per area: 0; Base Lighting Load on: By Space Type; Base Power Load on: By Space Type; Heat Load Values: By Space Type; Lighting Load Units: Power Density; Number of People: 0; Power Load Units: Power Density; Actual Lighting Load: 0 W; Actual Power Load: 0 W; Area per Person: 28.5714 m2; Latent Heat Gain per person: 58.6142 W; Plenum Lighting Contribution: 20; Sensible Heat Gain per person: 73.2678 W; Specified Lighting Load: 0 W; Specified Lighting Load per area: 10.7639; Specified Power Load: 0 W; Specified Power Load per area: 13.9931; Total Heat Gain per person: 131.882 W
Identity Data - Workset: Bouwkundig; Name: Slaapkamer; Number: 0.06
Phasing - Phase: 2. nieuwbouw
Text - bouwbesluit_functie: overige ruimte

# IfcSpace: Slaapkamer 0.07:5207254, 0.07
In: 00 Begane grond
LongName: Slaapkamer; InteriorOrExteriorSpace: INTERNAL
Pset_AirSideSystemInformation - Name: Slaapkamer
Pset_ProductRequirements - Name: Slaapkamer; Category: Rooms
Pset_SpaceCommon - Reference: Slaapkamer 0.07; Category: Rooms
BaseQuantities - NetFloorArea: 9.13178 m2; Height: 2600 mm; GrossFloorArea: 9.13178 m2; GrossVolume: 23.7426 m3
Other - Category: Rooms; Phase Id: 0
Constraints - Base Offset: 0 mm; Upper Limit: 0; Level: 0; Limit Offset: 2600 mm
Dimensions - Computation Height: 0 mm; Area: 9.13178 m2; Perimeter: 12384 mm; Unbounded Height: 2600 mm; Volume: 21.9301 m3
Energy Analysis - Actual Lighting Load per area: 0; Actual Power Load per area: 0; Base Lighting Load on: By Space Type; Base Power Load on: By Space Type; Heat Load Values: By Space Type; Lighting Load Units: Power Density; Number of People: 0; Power Load Units: Power Density; Actual Lighting Load: 0 W; Actual Power Load: 0 W; Area per Person: 28.5714 m2; Latent Heat Gain per person: 58.6142 W; Plenum Lighting Contribution: 20; Sensible Heat Gain per person: 73.2678 W; Specified Lighting Load: 0 W; Specified Lighting Load per area: 10.7639; Specified Power Load: 0 W; Specified Power Load per area: 13.9931; Total Heat Gain per person: 131.882 W
Identity Data - Workset: Bouwkundig; Name: Slaapkamer; Number: 0.07
Phasing - Phase: 2. nieuwbouw
Text - bouwbesluit_functie: overige ruimte

# IfcSpace: Speellokaal 0.23:5214059, 0.23
In: 00 Begane grond
LongName: Speellokaal; InteriorOrExteriorSpace: INTERNAL
Pset_AirSideSystemInformation - Name: Speellokaal
Pset_ProductRequirements - Name: Speellokaal; Category: Rooms
Pset_SpaceCommon - Reference: Speellokaal 0.23; Category: Rooms
BaseQuantities - NetFloorArea: 85.1122 m2; Height: 2600 mm; GrossPerimeter: 38729.9 mm; GrossFloorArea: 85.1122 m2; GrossVolume: 221.292 m3
Other - Category: Rooms; Phase Id: 0
Constraints - Base Offset: 0 mm; Upper Limit: 0; Level: 0; Limit Offset: 2600 mm
Dimensions - Computation Height: 0 mm; Area: 85.1122 m2; Perimeter: 39151.6 mm; Unbounded Height: 2600 mm; Volume: 221.292 m3
Energy Analysis - Actual Lighting Load per area: 0; Actual Power Load per area: 0; Base Lighting Load on: By Space Type; Base Power Load on: By Space Type; Heat Load Values: By Space Type; Lighting Load Units: Power Density; Number of People: 0; Power Load Units: Power Density; Actual Lighting Load: 0 W; Actual Power Load: 0 W; Area per Person: 28.5714 m2; Latent Heat Gain per person: 58.6142 W; Plenum Lighting Contribution: 20; Sensible Heat Gain per person: 73.2678 W; Specified Lighting Load: 0 W; Specified Lighting Load per area: 10.7639; Specified Power Load: 0 W; Specified Power Load per area: 13.9931; Total Heat Gain per person: 131.882 W
Identity Data - Workset: Bouwkundig; Name: Speellokaal; Number: 0.23
Phasing - Phase: 2. nieuwbouw
Text - bezettingsgraadklasse: 35; bouwbesluit_functie: overige ruimte

# IfcSpace: Spreekkamer 1.14:5212712, 1.14
In: 01 eerste verdieping
LongName: Spreekkamer; InteriorOrExteriorSpace: INTERNAL
Pset_AirSideSystemInformation - Name: Spreekkamer
Pset_ProductRequirements - Name: Spreekkamer; Category: Rooms
Pset_SpaceCommon - Reference: Spreekkamer 1.14; Category: Rooms
BaseQuantities - NetFloorArea: 6.48805 m2; Height: 2600 mm; GrossPerimeter: 10476.6 mm; GrossFloorArea: 6.48805 m2; GrossVolume: 16.8689 m3
Other - Category: Rooms; Phase Id: 0
Constraints - Base Offset: 0 mm; Upper Limit: 1; Level: 1; Limit Offset: 2600 mm
Dimensions - Computation Height: 0 mm; Area: 6.48805 m2; Perimeter: 10574.8 mm; Unbounded Height: 2600 mm; Volume: 16.8689 m3
Energy Analysis - Actual Lighting Load per area: 0; Actual Power Load per area: 0; Base Lighting Load on: By Space Type; Base Power Load on: By Space Type; Heat Load Values: By Space Type; Lighting Load Units: Power Density; Number of People: 0; Power Load Units: Power Density; Actual Lighting Load: 0 W; Actual Power Load: 0 W; Area per Person: 28.5714 m2; Latent Heat Gain per person: 58.6142 W; Plenum Lighting Contribution: 20; Sensible Heat Gain per person: 73.2678 W; Specified Lighting Load: 0 W; Specified Lighting Load per area: 10.7639; Specified Power Load: 0 W; Specified Power Load per area: 13.9931; Total Heat Gain per person: 131.882 W
Identity Data - Workset: Bouwkundig; Name: Spreekkamer; Number: 1.14
Phasing - Phase: 2. nieuwbouw
Text - bezettingsgraadklasse: 4; bouwbesluit_functie: overige ruimte

# IfcSpace: Toilet 0.12:5207256, 0.12
In: 00 Begane grond
LongName: Toilet; InteriorOrExteriorSpace: INTERNAL
Pset_AirSideSystemInformation - Name: Toilet
Pset_ProductRequirements - Name: Toilet; Category: Rooms
Pset_SpaceCommon - Reference: Toilet 0.12; Category: Rooms
BaseQuantities - NetFloorArea: 1.13176 m2; Height: 2600 mm; GrossFloorArea: 1.13176 m2; GrossVolume: 2.94259 m3
Other - Category: Rooms; Phase Id: 0
Constraints - Base Offset: 0 mm; Upper Limit: 0; Level: 0; Limit Offset: 2600 mm
Dimensions - Computation Height: 0 mm; Area: 1.13176 m2; Perimeter: 4292 mm; Unbounded Height: 2600 mm; Volume: 2.72271 m3
Energy Analysis - Actual Lighting Load per area: 0; Actual Power Load per area: 0; Base Lighting Load on: By Space Type; Base Power Load on: By Space Type; Heat Load Values: By Space Type; Lighting Load Units: Power Density; Number of People: 0; Power Load Units: Power Density; Actual Lighting Load: 0 W; Actual Power Load: 0 W; Area per Person: 28.5714 m2; Latent Heat Gain per person: 58.6142 W; Plenum Lighting Contribution: 20; Sensible Heat Gain per person: 73.2678 W; Specified Lighting Load: 0 W; Specified Lighting Load per area: 10.7639; Specified Power Load: 0 W; Specified Power Load per area: 13.9931; Total Heat Gain per person: 131.882 W
Identity Data - Workset: Bouwkundig; Name: Toilet; Number: 0.12
Phasing - Phase: 2. nieuwbouw
Text - bouwbesluit_functie: toiletruimte

# IfcSpace: Toilet 0.46:5207258, 0.46
In: 00 Begane grond
LongName: Toilet; InteriorOrExteriorSpace: INTERNAL
Pset_AirSideSystemInformation - Name: Toilet
Pset_ProductRequirements - Name: Toilet; Category: Rooms
Pset_SpaceCommon - Reference: Toilet 0.46; Category: Rooms
BaseQuantities - NetFloorArea: 2.0575 m2; Height: 2600 mm; GrossFloorArea: 2.0575 m2; GrossVolume: 5.34951 m3
Other - Category: Rooms; Phase Id: 0
Constraints - Base Offset: 0 mm; Upper Limit: 0; Level: 0; Limit Offset: 2600 mm
Dimensions - Computation Height: 0 mm; Area: 2.0575 m2; Perimeter: 5979.96 mm; Unbounded Height: 2600 mm; Volume: 4.94556 m3
Energy Analysis - Actual Lighting Load per area: 0; Actual Power Load per area: 0; Base Lighting Load on: By Space Type; Base Power Load on: By Space Type; Heat Load Values: By Space Type; Lighting Load Units: Power Density; Number of People: 0; Power Load Units: Power Density; Actual Lighting Load: 0 W; Actual Power Load: 0 W; Area per Person: 28.5714 m2; Latent Heat Gain per person: 58.6142 W; Plenum Lighting Contribution: 20; Sensible Heat Gain per person: 73.2678 W; Specified Lighting Load: 0 W; Specified Lighting Load per area: 10.7639; Specified Power Load: 0 W; Specified Power Load per area: 13.9931; Total Heat Gain per person: 131.882 W
Identity Data - Workset: Bouwkundig; Name: Toilet; Number: 0.46
Phasing - Phase: 2. nieuwbouw
Text - bouwbesluit_functie: toiletruimte

# IfcSpace: Toilet 1.18:5212713, 1.18
In: 01 eerste verdieping
LongName: Toilet; InteriorOrExteriorSpace: INTERNAL
Pset_AirSideSystemInformation - Name: Toilet
Pset_ProductRequirements - Name: Toilet; Category: Rooms
Pset_SpaceCommon - Reference: Toilet 1.18; Category: Rooms
BaseQuantities - NetFloorArea: 1.47046 m2; Height: 2438.4 mm; GrossPerimeter: 4898.25 mm; GrossFloorArea: 1.47046 m2; GrossVolume: 3.58558 m3
Other - Category: Rooms; Phase Id: 0
Constraints - Base Offset: 0 mm; Upper Limit: 1; Limit Offset: 2438.4 mm; Level: 1
Dimensions - Computation Height: 0 mm; Unbounded Height: 2438.4 mm; Area: 1.47046 m2; Perimeter: 4898.25 mm; Volume: 3.58558 m3
Energy Analysis - Actual Lighting Load per area: 0; Actual Power Load per area: 0; Base Lighting Load on: By Space Type; Base Power Load on: By Space Type; Heat Load Values: By Space Type; Lighting Load Units: Power Density; Number of People: 0; Power Load Units: Power Density; Actual Lighting Load: 0 W; Actual Power Load: 0 W; Area per Person: 28.5714 m2; Latent Heat Gain per person: 58.6142 W; Plenum Lighting Contribution: 20; Sensible Heat Gain per person: 73.2678 W; Specified Lighting Load: 0 W; Specified Lighting Load per area: 10.7639; Specified Power Load: 0 W; Specified Power Load per area: 13.9931; Total Heat Gain per person: 131.882 W
Identity Data - Workset: Bouwkundig; Name: Toilet; Number: 1.18
Phasing - Phase: 2. nieuwbouw
Text - bouwbesluit_functie: toiletruimte

# IfcSpace: Toiletgroep 0.41:5207272, 0.41
In: 00 Begane grond
LongName: Toiletgroep; InteriorOrExteriorSpace: INTERNAL
Pset_AirSideSystemInformation - Name: Toiletgroep
Pset_ProductRequirements - Name: Toiletgroep; Category: Rooms
Pset_SpaceCommon - Reference: Toiletgroep 0.41; Category: Rooms
BaseQuantities - NetFloorArea: 3.977 m2; Height: 2600 mm; GrossPerimeter: 8130 mm; GrossFloorArea: 3.977 m2; GrossVolume: 10.3402 m3
Other - Category: Rooms; Phase Id: 0
Constraints - Base Offset: 0 mm; Upper Limit: 0; Level: 0; Limit Offset: 2600 mm
Dimensions - Computation Height: 0 mm; Area: 3.977 m2; Perimeter: 8130 mm; Unbounded Height: 2600 mm; Volume: 9.5448 m3
Energy Analysis - Actual Lighting Load per area: 0; Actual Power Load per area: 0; Base Lighting Load on: By Space Type; Base Power Load on: By Space Type; Heat Load Values: By Space Type; Lighting Load Units: Power Density; Number of People: 0; Power Load Units: Power Density; Actual Lighting Load: 0 W; Actual Power Load: 0 W; Area per Person: 28.5714 m2; Latent Heat Gain per person: 58.6142 W; Plenum Lighting Contribution: 20; Sensible Heat Gain per person: 73.2678 W; Specified Lighting Load: 0 W; Specified Lighting Load per area: 10.7639; Specified Power Load: 0 W; Specified Power Load per area: 13.9931; Total Heat Gain per person: 131.882 W
Identity Data - Workset: Bouwkundig; Name: Toiletgroep; Number: 0.41
Phasing - Phase: 2. nieuwbouw
Text - bouwbesluit_functie: toiletruimte

# IfcSpace: Toiletgroep 0.42:5207270, 0.42
In: 00 Begane grond
LongName: Toiletgroep; InteriorOrExteriorSpace: INTERNAL
Pset_AirSideSystemInformation - Name: Toiletgroep
Pset_ProductRequirements - Name: Toiletgroep; Category: Rooms
Pset_SpaceCommon - Reference: Toiletgroep 0.42; Category: Rooms
BaseQuantities - NetFloorArea: 3.977 m2; Height: 2600 mm; GrossPerimeter: 8130 mm; GrossFloorArea: 3.977 m2; GrossVolume: 10.3402 m3
Other - Category: Rooms; Phase Id: 0
Constraints - Base Offset: 0 mm; Upper Limit: 0; Level: 0; Limit Offset: 2600 mm
Dimensions - Computation Height: 0 mm; Area: 3.977 m2; Perimeter: 8130 mm; Unbounded Height: 2600 mm; Volume: 9.5448 m3
Energy Analysis - Actual Lighting Load per area: 0; Actual Power Load per area: 0; Base Lighting Load on: By Space Type; Base Power Load on: By Space Type; Heat Load Values: By Space Type; Lighting Load Units: Power Density; Number of People: 0; Power Load Units: Power Density; Actual Lighting Load: 0 W; Actual Power Load: 0 W; Area per Person: 28.5714 m2; Latent Heat Gain per person: 58.6142 W; Plenum Lighting Contribution: 20; Sensible Heat Gain per person: 73.2678 W; Specified Lighting Load: 0 W; Specified Lighting Load per area: 10.7639; Specified Power Load: 0 W; Specified Power Load per area: 13.9931; Total Heat Gain per person: 131.882 W
Identity Data - Workset: Bouwkundig; Name: Toiletgroep; Number: 0.42
Phasing - Phase: 2. nieuwbouw
Text - bouwbesluit_functie: toiletruimte

# IfcSpace: Toiletgroep 0.43:5207271, 0.43
In: 00 Begane grond
LongName: Toiletgroep; InteriorOrExteriorSpace: INTERNAL
Pset_AirSideSystemInformation - Name: Toiletgroep
Pset_ProductRequirements - Name: Toiletgroep; Category: Rooms
Pset_SpaceCommon - Reference: Toiletgroep 0.43; Category: Rooms
BaseQuantities - NetFloorArea: 3.977 m2; Height: 2600 mm; GrossPerimeter: 8130 mm; GrossFloorArea: 3.977 m2; GrossVolume: 10.3402 m3
Other - Category: Rooms; Phase Id: 0
Constraints - Base Offset: 0 mm; Upper Limit: 0; Level: 0; Limit Offset: 2600 mm
Dimensions - Computation Height: 0 mm; Area: 3.977 m2; Perimeter: 8130 mm; Unbounded Height: 2600 mm; Volume: 9.5448 m3
Energy Analysis - Actual Lighting Load per area: 0; Actual Power Load per area: 0; Base Lighting Load on: By Space Type; Base Power Load on: By Space Type; Heat Load Values: By Space Type; Lighting Load Units: Power Density; Number of People: 0; Power Load Units: Power Density; Actual Lighting Load: 0 W; Actual Power Load: 0 W; Area per Person: 28.5714 m2; Latent Heat Gain per person: 58.6142 W; Plenum Lighting Contribution: 20; Sensible Heat Gain per person: 73.2678 W; Specified Lighting Load: 0 W; Specified Lighting Load per area: 10.7639; Specified Power Load: 0 W; Specified Power Load per area: 13.9931; Total Heat Gain per person: 131.882 W
Identity Data - Workset: Bouwkundig; Name: Toiletgroep; Number: 0.43
Phasing - Phase: 2. nieuwbouw
Text - bouwbesluit_functie: toiletruimte

# IfcSpace: Toiletgroep 1.06:5212711, 1.06
In: 01 eerste verdieping
LongName: Toiletgroep; InteriorOrExteriorSpace: INTERNAL
Pset_AirSideSystemInformation - Name: Toiletgroep
Pset_ProductRequirements - Name: Toiletgroep; Category: Rooms
Pset_SpaceCommon - Reference: Toiletgroep 1.06; Category: Rooms
BaseQuantities - NetFloorArea: 3.977 m2; Height: 2600 mm; GrossFloorArea: 3.977 m2; GrossVolume: 10.3402 m3
Other - Category: Rooms; Phase Id: 0
Constraints - Base Offset: 0 mm; Upper Limit: 1; Level: 1; Limit Offset: 2600 mm
Dimensions - Computation Height: 0 mm; Area: 3.977 m2; Perimeter: 8130 mm; Unbounded Height: 2600 mm; Volume: 9.5448 m3
Energy Analysis - Actual Lighting Load per area: 0; Actual Power Load per area: 0; Base Lighting Load on: By Space Type; Base Power Load on: By Space Type; Heat Load Values: By Space Type; Lighting Load Units: Power Density; Number of People: 0; Power Load Units: Power Density; Actual Lighting Load: 0 W; Actual Power Load: 0 W; Area per Person: 28.5714 m2; Latent Heat Gain per person: 58.6142 W; Plenum Lighting Contribution: 20; Sensible Heat Gain per person: 73.2678 W; Specified Lighting Load: 0 W; Specified Lighting Load per area: 10.7639; Specified Power Load: 0 W; Specified Power Load per area: 13.9931; Total Heat Gain per person: 131.882 W
Identity Data - Workset: Bouwkundig; Name: Toiletgroep; Number: 1.06
Phasing - Phase: 2. nieuwbouw
Text - bouwbesluit_functie: toiletruimte

# IfcSpace: Toiletgroep 1.08:5212709, 1.08
In: 01 eerste verdieping
LongName: Toiletgroep; InteriorOrExteriorSpace: INTERNAL
Pset_AirSideSystemInformation - Name: Toiletgroep
Pset_ProductRequirements - Name: Toiletgroep; Category: Rooms
Pset_SpaceCommon - Reference: Toiletgroep 1.08; Category: Rooms
BaseQuantities - NetFloorArea: 3.7966 m2; Height: 2600 mm; GrossFloorArea: 3.7966 m2; GrossVolume: 9.87116 m3
Other - Category: Rooms; Phase Id: 0
Constraints - Base Offset: 0 mm; Upper Limit: 1; Level: 1; Limit Offset: 2600 mm
Dimensions - Computation Height: 0 mm; Area: 3.7966 m2; Perimeter: 7910 mm; Unbounded Height: 2600 mm; Volume: 9.11184 m3
Energy Analysis - Actual Lighting Load per area: 0; Actual Power Load per area: 0; Base Lighting Load on: By Space Type; Base Power Load on: By Space Type; Heat Load Values: By Space Type; Lighting Load Units: Power Density; Number of People: 0; Power Load Units: Power Density; Actual Lighting Load: 0 W; Actual Power Load: 0 W; Area per Person: 28.5714 m2; Latent Heat Gain per person: 58.6142 W; Plenum Lighting Contribution: 20; Sensible Heat Gain per person: 73.2678 W; Specified Lighting Load: 0 W; Specified Lighting Load per area: 10.7639; Specified Power Load: 0 W; Specified Power Load per area: 13.9931; Total Heat Gain per person: 131.882 W
Identity Data - Workset: Bouwkundig; Name: Toiletgroep; Number: 1.08
Phasing - Phase: 2. nieuwbouw
Text - bouwbesluit_functie: toiletruimte

# IfcSpace: Toiletgroep 1.25:5212707, 1.25
In: 01 eerste verdieping
LongName: Toiletgroep; InteriorOrExteriorSpace: INTERNAL
Pset_AirSideSystemInformation - Name: Toiletgroep
Pset_ProductRequirements - Name: Toiletgroep; Category: Rooms
Pset_SpaceCommon - Reference: Toiletgroep 1.25; Category: Rooms
BaseQuantities - NetFloorArea: 3.977 m2; Height: 2600 mm; GrossPerimeter: 8130 mm; GrossFloorArea: 3.977 m2; GrossVolume: 10.3402 m3
Other - Category: Rooms; Phase Id: 0
Constraints - Base Offset: 0 mm; Upper Limit: 1; Level: 1; Limit Offset: 2600 mm
Dimensions - Computation Height: 0 mm; Area: 3.977 m2; Perimeter: 8130 mm; Unbounded Height: 2600 mm; Volume: 9.5448 m3
Energy Analysis - Actual Lighting Load per area: 0; Actual Power Load per area: 0; Base Lighting Load on: By Space Type; Base Power Load on: By Space Type; Heat Load Values: By Space Type; Lighting Load Units: Power Density; Number of People: 0; Power Load Units: Power Density; Actual Lighting Load: 0 W; Actual Power Load: 0 W; Area per Person: 28.5714 m2; Latent Heat Gain per person: 58.6142 W; Plenum Lighting Contribution: 20; Sensible Heat Gain per person: 73.2678 W; Specified Lighting Load: 0 W; Specified Lighting Load per area: 10.7639; Specified Power Load: 0 W; Specified Power Load per area: 13.9931; Total Heat Gain per person: 131.882 W
Identity Data - Workset: Bouwkundig; Name: Toiletgroep; Number: 1.25
Phasing - Phase: 2. nieuwbouw
Text - bouwbesluit_functie: toiletruimte

# IfcSpace: Toiletgroep 1.27:5212705, 1.27
In: 01 eerste verdieping
LongName: Toiletgroep; InteriorOrExteriorSpace: INTERNAL
Pset_AirSideSystemInformation - Name: Toiletgroep
Pset_ProductRequirements - Name: Toiletgroep; Category: Rooms
Pset_SpaceCommon - Reference: Toiletgroep 1.27; Category: Rooms
BaseQuantities - NetFloorArea: 3.977 m2; Height: 2600 mm; GrossPerimeter: 8130 mm; GrossFloorArea: 3.977 m2; GrossVolume: 10.3402 m3
Other - Category: Rooms; Phase Id: 0
Constraints - Base Offset: 0 mm; Upper Limit: 1; Level: 1; Limit Offset: 2600 mm
Dimensions - Computation Height: 0 mm; Area: 3.977 m2; Perimeter: 8130 mm; Unbounded Height: 2600 mm; Volume: 9.5448 m3
Energy Analysis - Actual Lighting Load per area: 0; Actual Power Load per area: 0; Base Lighting Load on: By Space Type; Base Power Load on: By Space Type; Heat Load Values: By Space Type; Lighting Load Units: Power Density; Number of People: 0; Power Load Units: Power Density; Actual Lighting Load: 0 W; Actual Power Load: 0 W; Area per Person: 28.5714 m2; Latent Heat Gain per person: 58.6142 W; Plenum Lighting Contribution: 20; Sensible Heat Gain per person: 73.2678 W; Specified Lighting Load: 0 W; Specified Lighting Load per area: 10.7639; Specified Power Load: 0 W; Specified Power Load per area: 13.9931; Total Heat Gain per person: 131.882 W
Identity Data - Workset: Bouwkundig; Name: Toiletgroep; Number: 1.27
Phasing - Phase: 2. nieuwbouw
Text - bouwbesluit_functie: toiletruimte

# IfcSpace: VG0.1 1:5736376, 1
In: 00 Begane grond
LongName: VG0.1; InteriorOrExteriorSpace: INTERNAL; Group: verblijfsgebied (VG)
Pset_AirSideSystemInformation - Name: VG0.1
Pset_ProductRequirements - Name: VG0.1; Category: Areas
Pset_SpaceCommon - Reference: VG0.1 1; Category: Areas
BaseQuantities - NetFloorArea: 156.773 m2; Height: 3630 mm; GrossFloorArea: 156.773 m2; GrossVolume: 569.086 m3
Other - Category: Areas; Area Scheme Id: 1055865; Area Type: Building Common Area
Constraints - Level: 0
Dimensions - Computation Height: 0 mm; Area: 156.773 m2; Perimeter: 68924 mm
Identity Data - Workset: Bouwkundig; Name: VG0.1; Number: 1

# IfcSpace: VG0.2 2:5736378, 2
In: 00 Begane grond
LongName: VG0.2; InteriorOrExteriorSpace: INTERNAL; Group: verblijfsgebied (VG)
Pset_AirSideSystemInformation - Name: VG0.2
Pset_ProductRequirements - Name: VG0.2; Category: Areas
Pset_SpaceCommon - Reference: VG0.2 2; Category: Areas
BaseQuantities - NetFloorArea: 58.351 m2; Height: 3630 mm; GrossFloorArea: 58.351 m2; GrossVolume: 211.814 m3
Other - Category: Areas; Area Scheme Id: 1055865; Area Type: Building Common Area
Constraints - Level: 0
Dimensions - Computation Height: 0 mm; Area: 58.351 m2; Perimeter: 31812 mm
Identity Data - Workset: Bouwkundig; Name: VG0.2; Number: 2

# IfcSpace: VG0.3 3:5738454, 3
In: 00 Begane grond
LongName: VG0.3; InteriorOrExteriorSpace: INTERNAL; Group: verblijfsgebied (VG)
Pset_AirSideSystemInformation - Name: VG0.3
Pset_ProductRequirements - Name: VG0.3; Category: Areas
Pset_SpaceCommon - Reference: VG0.3 3; Category: Areas
BaseQuantities - NetFloorArea: 244.595 m2; Height: 3630 mm; GrossFloorArea: 244.595 m2; GrossVolume: 887.88 m3
Other - Category: Areas; Area Scheme Id: 1055865; Area Type: Building Common Area
Constraints - Level: 0
Dimensions - Computation Height: 0 mm; Area: 244.595 m2; Perimeter: 108766 mm
Identity Data - Workset: Bouwkundig; Name: VG0.3; Number: 3

# IfcSpace: VG0.4 4:5736381, 4
In: 00 Begane grond
LongName: VG0.4; InteriorOrExteriorSpace: INTERNAL; Group: verblijfsgebied (VG)
Pset_AirSideSystemInformation - Name: VG0.4
Pset_ProductRequirements - Name: VG0.4; Category: Areas
Pset_SpaceCommon - Reference: VG0.4 4; Category: Areas
BaseQuantities - NetFloorArea: 380.377 m2; Height: 3630 mm; GrossFloorArea: 380.377 m2; GrossVolume: 1380.77 m3
Other - Category: Areas; Area Scheme Id: 1055865; Area Type: Building Common Area
Constraints - Level: 0
Dimensions - Computation Height: 0 mm; Area: 380.377 m2; Perimeter: 101180 mm
Identity Data - Workset: Bouwkundig; Name: VG0.4; Number: 4

# IfcSpace: VG1.1 5:5743598, 5
In: 01 eerste verdieping
LongName: VG1.1; InteriorOrExteriorSpace: INTERNAL; Group: verblijfsgebied (VG)
Pset_AirSideSystemInformation - Name: VG1.1
Pset_ProductRequirements - Name: VG1.1; Category: Areas
Pset_SpaceCommon - Reference: VG1.1 5; Category: Areas
BaseQuantities - NetFloorArea: 346.358 m2; Height: 3590 mm; GrossFloorArea: 346.358 m2; GrossVolume: 1243.43 m3
Other - Category: Areas; Area Scheme Id: 1055865; Area Type: Building Common Area
Constraints - Level: 1
Dimensions - Computation Height: 0 mm; Area: 346.358 m2; Perimeter: 98000 mm
Identity Data - Workset: Bouwkundig; Name: VG1.1; Number: 5

# IfcSpace: VG1.2 6:5743601, 6
In: 01 eerste verdieping
LongName: VG1.2; InteriorOrExteriorSpace: INTERNAL; Group: verblijfsgebied (VG)
Pset_AirSideSystemInformation - Name: VG1.2
Pset_ProductRequirements - Name: VG1.2; Category: Areas
Pset_SpaceCommon - Reference: VG1.2 6; Category: Areas
BaseQuantities - NetFloorArea: 87.2078 m2; Height: 3590 mm; GrossFloorArea: 87.2078 m2; GrossVolume: 313.076 m3
Other - Category: Areas; Area Scheme Id: 1055865; Area Type: Building Common Area
Constraints - Level: 1
Dimensions - Computation Height: 0 mm; Area: 87.2078 m2; Perimeter: 76187.4 mm
Identity Data - Workset: Bouwkundig; Name: VG1.2; Number: 6

# IfcSpace: VG1.3 8:5744100, 8
In: 01 eerste verdieping
LongName: VG1.3; InteriorOrExteriorSpace: INTERNAL; Group: verblijfsgebied (VG)
Pset_AirSideSystemInformation - Name: VG1.3
Pset_ProductRequirements - Name: VG1.3; Category: Areas
Pset_SpaceCommon - Reference: VG1.3 8; Category: Areas
BaseQuantities - NetFloorArea: 29.0926 m2; Height: 3590 mm; GrossFloorArea: 29.0926 m2; GrossVolume: 104.443 m3
Other - Category: Areas; Area Scheme Id: 1055865; Area Type: Building Common Area
Constraints - Level: 1
Dimensions - Computation Height: 0 mm; Area: 29.0926 m2; Perimeter: 22350 mm
Identity Data - Workset: Bouwkundig; Name: VG1.3; Number: 8

# IfcSpace: VG1.4 7:5743604, 7
In: 01 eerste verdieping
LongName: VG1.4; InteriorOrExteriorSpace: INTERNAL; Group: verblijfsgebied (VG)
Pset_AirSideSystemInformation - Name: VG1.4
Pset_ProductRequirements - Name: VG1.4; Category: Areas
Pset_SpaceCommon - Reference: VG1.4 7; Category: Areas
BaseQuantities - NetFloorArea: 304.009 m2; Height: 3590 mm; GrossFloorArea: 304.009 m2; GrossVolume: 1091.39 m3
Other - Category: Areas; Area Scheme Id: 1055865; Area Type: Building Common Area
Constraints - Level: 1
Dimensions - Computation Height: 0 mm; Area: 304.009 m2; Perimeter: 85580 mm
Identity Data - Workset: Bouwkundig; Name: VG1.4; Number: 7

# IfcSpace: Verkeersuimte 0.15:5207269, 0.15
In: 00 Begane grond
LongName: Verkeersuimte; InteriorOrExteriorSpace: INTERNAL
Pset_AirSideSystemInformation - Name: Verkeersuimte
Pset_ProductRequirements - Name: Verkeersuimte; Category: Rooms
Pset_SpaceCommon - Reference: Verkeersuimte 0.15; Category: Rooms
BaseQuantities - NetFloorArea: 48.8263 m2; Height: 2600 mm; GrossFloorArea: 48.8263 m2; GrossVolume: 126.948 m3
Other - Category: Rooms; Phase Id: 0
Constraints - Base Offset: 0 mm; Upper Limit: 0; Level: 0; Limit Offset: 2600 mm
Dimensions - Computation Height: 0 mm; Area: 48.8263 m2; Perimeter: 58378 mm; Unbounded Height: 2600 mm; Volume: 125.509 m3
Energy Analysis - Actual Lighting Load per area: 0; Actual Power Load per area: 0; Base Lighting Load on: By Space Type; Base Power Load on: By Space Type; Heat Load Values: By Space Type; Lighting Load Units: Power Density; Number of People: 0; Power Load Units: Power Density; Actual Lighting Load: 0 W; Actual Power Load: 0 W; Area per Person: 28.5714 m2; Latent Heat Gain per person: 58.6142 W; Plenum Lighting Contribution: 20; Sensible Heat Gain per person: 73.2678 W; Specified Lighting Load: 0 W; Specified Lighting Load per area: 10.7639; Specified Power Load: 0 W; Specified Power Load per area: 13.9931; Total Heat Gain per person: 131.882 W
Identity Data - Workset: Bouwkundig; Name: Verkeersuimte; Number: 0.15
Phasing - Phase: 2. nieuwbouw
Text - bouwbesluit_functie: verkeersruimte

# IfcSpace: Verschoonruimte 0.04:5207276, 0.04
In: 00 Begane grond
LongName: Verschoonruimte; InteriorOrExteriorSpace: INTERNAL
Pset_AirSideSystemInformation - Name: Verschoonruimte
Pset_ProductRequirements - Name: Verschoonruimte; Category: Rooms
Pset_SpaceCommon - Reference: Verschoonruimte 0.04; Category: Rooms
BaseQuantities - NetFloorArea: 14.0257 m2; Height: 2600 mm; GrossFloorArea: 14.0257 m2; GrossVolume: 36.4668 m3
Other - Category: Rooms; Phase Id: 0
Constraints - Base Offset: 0 mm; Upper Limit: 0; Level: 0; Limit Offset: 2600 mm
Dimensions - Computation Height: 0 mm; Area: 14.0257 m2; Perimeter: 15340 mm; Unbounded Height: 2600 mm; Volume: 33.6617 m3
Energy Analysis - Actual Lighting Load per area: 0; Actual Power Load per area: 0; Base Lighting Load on: By Space Type; Base Power Load on: By Space Type; Heat Load Values: By Space Type; Lighting Load Units: Power Density; Number of People: 0; Power Load Units: Power Density; Actual Lighting Load: 0 W; Actual Power Load: 0 W; Area per Person: 28.5714 m2; Latent Heat Gain per person: 58.6142 W; Plenum Lighting Contribution: 20; Sensible Heat Gain per person: 73.2678 W; Specified Lighting Load: 0 W; Specified Lighting Load per area: 10.7639; Specified Power Load: 0 W; Specified Power Load per area: 13.9931; Total Heat Gain per person: 131.882 W
Identity Data - Workset: Bouwkundig; Name: Verschoonruimte; Number: 0.04
Phasing - Phase: 2. nieuwbouw
Text - bouwbesluit_functie: toiletruimte

# IfcSpace: Verschoonruimte 0.08:5207277, 0.08
In: 00 Begane grond
LongName: Verschoonruimte; InteriorOrExteriorSpace: INTERNAL
Pset_AirSideSystemInformation - Name: Verschoonruimte
Pset_ProductRequirements - Name: Verschoonruimte; Category: Rooms
Pset_SpaceCommon - Reference: Verschoonruimte 0.08; Category: Rooms
BaseQuantities - NetFloorArea: 12.0603 m2; Height: 2600 mm; GrossFloorArea: 12.0603 m2; GrossVolume: 31.3568 m3
Other - Category: Rooms; Phase Id: 0
Constraints - Base Offset: 0 mm; Upper Limit: 0; Level: 0; Limit Offset: 2600 mm
Dimensions - Computation Height: 0 mm; Area: 12.0603 m2; Perimeter: 15310 mm; Unbounded Height: 2600 mm; Volume: 28.9448 m3
Energy Analysis - Actual Lighting Load per area: 0; Actual Power Load per area: 0; Base Lighting Load on: By Space Type; Base Power Load on: By Space Type; Heat Load Values: By Space Type; Lighting Load Units: Power Density; Number of People: 0; Power Load Units: Power Density; Actual Lighting Load: 0 W; Actual Power Load: 0 W; Area per Person: 28.5714 m2; Latent Heat Gain per person: 58.6142 W; Plenum Lighting Contribution: 20; Sensible Heat Gain per person: 73.2678 W; Specified Lighting Load: 0 W; Specified Lighting Load per area: 10.7639; Specified Power Load: 0 W; Specified Power Load per area: 13.9931; Total Heat Gain per person: 131.882 W
Identity Data - Workset: Bouwkundig; Name: Verschoonruimte; Number: 0.08
Phasing - Phase: 2. nieuwbouw
Text - bouwbesluit_functie: toiletruimte

# IfcSpace: Werkkast 0.30:5207259, 0.30
In: 00 Begane grond
LongName: Werkkast; InteriorOrExteriorSpace: INTERNAL
Pset_AirSideSystemInformation - Name: Werkkast
Pset_ProductRequirements - Name: Werkkast; Category: Rooms
Pset_SpaceCommon - Reference: Werkkast 0.30; Category: Rooms
BaseQuantities - NetFloorArea: 2.40245 m2; Height: 2600 mm; GrossFloorArea: 2.40245 m2; GrossVolume: 6.24636 m3
Other - Category: Rooms; Phase Id: 0
Constraints - Base Offset: 0 mm; Upper Limit: 0; Level: 0; Limit Offset: 2600 mm
Dimensions - Computation Height: 0 mm; Area: 2.40245 m2; Perimeter: 6340.79 mm; Unbounded Height: 2600 mm; Volume: 5.77389 m3
Energy Analysis - Actual Lighting Load per area: 0; Actual Power Load per area: 0; Base Lighting Load on: By Space Type; Base Power Load on: By Space Type; Heat Load Values: By Space Type; Lighting Load Units: Power Density; Number of People: 0; Power Load Units: Power Density; Actual Lighting Load: 0 W; Actual Power Load: 0 W; Area per Person: 28.5714 m2; Latent Heat Gain per person: 58.6142 W; Plenum Lighting Contribution: 20; Sensible Heat Gain per person: 73.2678 W; Specified Lighting Load: 0 W; Specified Lighting Load per area: 10.7639; Specified Power Load: 0 W; Specified Power Load per area: 13.9931; Total Heat Gain per person: 131.882 W
Identity Data - Workset: Bouwkundig; Name: Werkkast; Number: 0.30
Phasing - Phase: 2. nieuwbouw
Text - bouwbesluit_functie: overige ruimte

# IfcSpace: Werkkast 1.19:5212702, 1.19
In: 01 eerste verdieping
LongName: Werkkast; InteriorOrExteriorSpace: INTERNAL
Pset_AirSideSystemInformation - Name: Werkkast
Pset_ProductRequirements - Name: Werkkast; Category: Rooms
Pset_SpaceCommon - Reference: Werkkast 1.19; Category: Rooms
BaseQuantities - NetFloorArea: 2.24757 m2; Height: 2438.4 mm; GrossPerimeter: 6042.25 mm; GrossFloorArea: 2.24757 m2; GrossVolume: 5.48049 m3
Other - Category: Rooms; Phase Id: 0
Constraints - Base Offset: 0 mm; Upper Limit: 1; Level: 1; Limit Offset: 2438.4 mm
Dimensions - Computation Height: 0 mm; Area: 2.24757 m2; Perimeter: 6042.25 mm; Unbounded Height: 2438.4 mm; Volume: 5.48049 m3
Energy Analysis - Actual Lighting Load per area: 0; Actual Power Load per area: 0; Base Lighting Load on: By Space Type; Base Power Load on: By Space Type; Heat Load Values: By Space Type; Lighting Load Units: Power Density; Number of People: 0; Power Load Units: Power Density; Actual Lighting Load: 0 W; Actual Power Load: 0 W; Area per Person: 28.5714 m2; Latent Heat Gain per person: 58.6142 W; Plenum Lighting Contribution: 20; Sensible Heat Gain per person: 73.2678 W; Specified Lighting Load: 0 W; Specified Lighting Load per area: 10.7639; Specified Power Load: 0 W; Specified Power Load per area: 13.9931; Total Heat Gain per person: 131.882 W
Identity Data - Workset: Bouwkundig; Name: Werkkast; Number: 1.19
Phasing - Phase: 2. nieuwbouw
Text - bouwbesluit_functie: overige ruimte

# IfcSpace: berging 0.24:5207263, 0.24
In: 00 Begane grond
LongName: berging; InteriorOrExteriorSpace: INTERNAL
Pset_AirSideSystemInformation - Name: berging
Pset_ProductRequirements - Name: berging; Category: Rooms
Pset_SpaceCommon - Reference: berging 0.24; Category: Rooms
BaseQuantities - NetFloorArea: 4.49955 m2; Height: 2600 mm; GrossPerimeter: 8853.7 mm; GrossFloorArea: 4.49955 m2; GrossVolume: 11.6988 m3
Other - Category: Rooms; Phase Id: 0
Constraints - Base Offset: 0 mm; Upper Limit: 0; Level: 0; Limit Offset: 2600 mm
Dimensions - Computation Height: 0 mm; Area: 4.49955 m2; Perimeter: 8951.88 mm; Unbounded Height: 2600 mm; Volume: 11.6987 m3
Energy Analysis - Actual Lighting Load per area: 0; Actual Power Load per area: 0; Base Lighting Load on: By Space Type; Base Power Load on: By Space Type; Heat Load Values: By Space Type; Lighting Load Units: Power Density; Number of People: 0; Power Load Units: Power Density; Actual Lighting Load: 0 W; Actual Power Load: 0 W; Area per Person: 28.5714 m2; Latent Heat Gain per person: 58.6142 W; Plenum Lighting Contribution: 20; Sensible Heat Gain per person: 73.2678 W; Specified Lighting Load: 0 W; Specified Lighting Load per area: 10.7639; Specified Power Load: 0 W; Specified Power Load per area: 13.9931; Total Heat Gain per person: 131.882 W
Identity Data - Workset: Bouwkundig; Name: berging; Number: 0.24
Phasing - Phase: 2. nieuwbouw
Text - bouwbesluit_functie: opslagruimte

# IfcSpace: berging 1.26:5212706, 1.26
In: 01 eerste verdieping
LongName: berging; InteriorOrExteriorSpace: INTERNAL
Pset_AirSideSystemInformation - Name: berging
Pset_ProductRequirements - Name: berging; Category: Rooms
Pset_SpaceCommon - Reference: berging 1.26; Category: Rooms
BaseQuantities - NetFloorArea: 2.02265 m2; Height: 2600 mm; GrossFloorArea: 2.02265 m2; GrossVolume: 5.25889 m3
Other - Category: Rooms; Phase Id: 0
Constraints - Base Offset: 0 mm; Upper Limit: 1; Level: 1; Limit Offset: 2600 mm
Dimensions - Computation Height: 0 mm; Area: 2.02265 m2; Perimeter: 5949.23 mm; Unbounded Height: 2600 mm; Volume: 4.8658 m3
Energy Analysis - Actual Lighting Load per area: 0; Actual Power Load per area: 0; Base Lighting Load on: By Space Type; Base Power Load on: By Space Type; Heat Load Values: By Space Type; Lighting Load Units: Power Density; Number of People: 0; Power Load Units: Power Density; Actual Lighting Load: 0 W; Actual Power Load: 0 W; Area per Person: 28.5714 m2; Latent Heat Gain per person: 58.6142 W; Plenum Lighting Contribution: 20; Sensible Heat Gain per person: 73.2678 W; Specified Lighting Load: 0 W; Specified Lighting Load per area: 10.7639; Specified Power Load: 0 W; Specified Power Load per area: 13.9931; Total Heat Gain per person: 131.882 W
Identity Data - Workset: Bouwkundig; Name: berging; Number: 1.26
Phasing - Phase: 2. nieuwbouw
Text - bouwbesluit_functie: opslagruimte

# IfcSpace: entree 0.25:5207257, 0.25
In: 00 Begane grond
LongName: entree; InteriorOrExteriorSpace: INTERNAL
Pset_AirSideSystemInformation - Name: entree
Pset_ProductRequirements - Name: entree; Category: Rooms
Pset_SpaceCommon - Reference: entree 0.25; Category: Rooms
BaseQuantities - NetFloorArea: 3.85913 m2; Height: 2600 mm; GrossFloorArea: 3.85913 m2; GrossVolume: 10.0337 m3
Other - Category: Rooms; Phase Id: 0
Constraints - Base Offset: 0 mm; Upper Limit: 0; Level: 0; Limit Offset: 2600 mm
Dimensions - Computation Height: 0 mm; Area: 3.85913 m2; Perimeter: 7859.93 mm; Unbounded Height: 2600 mm; Volume: 9.26191 m3
Energy Analysis - Actual Lighting Load per area: 0; Actual Power Load per area: 0; Base Lighting Load on: By Space Type; Base Power Load on: By Space Type; Heat Load Values: By Space Type; Lighting Load Units: Power Density; Number of People: 0; Power Load Units: Power Density; Actual Lighting Load: 0 W; Actual Power Load: 0 W; Area per Person: 28.5714 m2; Latent Heat Gain per person: 58.6142 W; Plenum Lighting Contribution: 20; Sensible Heat Gain per person: 73.2678 W; Specified Lighting Load: 0 W; Specified Lighting Load per area: 10.7639; Specified Power Load: 0 W; Specified Power Load per area: 13.9931; Total Heat Gain per person: 131.882 W
Identity Data - Workset: Bouwkundig; Name: entree; Number: 0.25
Phasing - Phase: 2. nieuwbouw
Text - bouwbesluit_functie: verkeersruimte

# IfcSpace: garderobe 0.28a:5416243, 0.28a
In: 00 Begane grond
LongName: garderobe; InteriorOrExteriorSpace: INTERNAL
Pset_AirSideSystemInformation - Name: garderobe
Pset_ProductRequirements - Name: garderobe; Category: Rooms
Pset_SpaceCommon - Reference: garderobe 0.28a; Category: Rooms
BaseQuantities - NetFloorArea: 1.38657 m2; Height: 2438.4 mm; GrossFloorArea: 1.38657 m2; GrossVolume: 3.38102 m3
Other - Category: Rooms; Phase Id: 0
Constraints - Base Offset: 0 mm; Upper Limit: 0; Limit Offset: 2438.4 mm; Level: 0
Dimensions - Computation Height: 0 mm; Unbounded Height: 2438.4 mm; Area: 1.38657 m2; Perimeter: 8498 mm; Volume: 3.32808 m3
Energy Analysis - Actual Lighting Load per area: 0; Actual Power Load per area: 0; Base Lighting Load on: By Space Type; Base Power Load on: By Space Type; Heat Load Values: By Space Type; Lighting Load Units: Power Density; Number of People: 0; Power Load Units: Power Density; Actual Lighting Load: 0 W; Actual Power Load: 0 W; Area per Person: 28.5714 m2; Latent Heat Gain per person: 58.6142 W; Plenum Lighting Contribution: 20; Sensible Heat Gain per person: 73.2678 W; Specified Lighting Load: 0 W; Specified Lighting Load per area: 10.7639; Specified Power Load: 0 W; Specified Power Load per area: 13.9931; Total Heat Gain per person: 131.882 W
Identity Data - Workset: Bouwkundig; Name: garderobe; Number: 0.28a
Phasing - Phase: 2. nieuwbouw
Text - bouwbesluit_functie: opslagruimte

# IfcSpace: garderobe 0.35a:5416272, 0.35a
In: 00 Begane grond
LongName: garderobe; InteriorOrExteriorSpace: INTERNAL
Pset_AirSideSystemInformation - Name: garderobe
Pset_ProductRequirements - Name: garderobe; Category: Rooms
Pset_SpaceCommon - Reference: garderobe 0.35a; Category: Rooms
BaseQuantities - NetFloorArea: 1.42393 m2; Height: 2438.4 mm; GrossFloorArea: 1.42393 m2; GrossVolume: 3.47211 m3
Other - Category: Rooms; Phase Id: 0
Constraints - Base Offset: 0 mm; Upper Limit: 0; Limit Offset: 2438.4 mm; Level: 0
Dimensions - Computation Height: 0 mm; Unbounded Height: 2438.4 mm; Area: 1.42393 m2; Perimeter: 8573.88 mm; Volume: 3.41781 m3
Energy Analysis - Actual Lighting Load per area: 0; Actual Power Load per area: 0; Base Lighting Load on: By Space Type; Base Power Load on: By Space Type; Heat Load Values: By Space Type; Lighting Load Units: Power Density; Number of People: 0; Power Load Units: Power Density; Actual Lighting Load: 0 W; Actual Power Load: 0 W; Area per Person: 28.5714 m2; Latent Heat Gain per person: 58.6142 W; Plenum Lighting Contribution: 20; Sensible Heat Gain per person: 73.2678 W; Specified Lighting Load: 0 W; Specified Lighting Load per area: 10.7639; Specified Power Load: 0 W; Specified Power Load per area: 13.9931; Total Heat Gain per person: 131.882 W
Identity Data - Workset: Bouwkundig; Name: garderobe; Number: 0.35a
Phasing - Phase: 2. nieuwbouw
Text - bouwbesluit_functie: opslagruimte

# IfcSpace: garderobe 0.36a:5416292, 0.36a
In: 00 Begane grond
LongName: garderobe; InteriorOrExteriorSpace: INTERNAL
Pset_AirSideSystemInformation - Name: garderobe
Pset_ProductRequirements - Name: garderobe; Category: Rooms
Pset_SpaceCommon - Reference: garderobe 0.36a; Category: Rooms
BaseQuantities - NetFloorArea: 1.4221 m2; Height: 2438.4 mm; GrossFloorArea: 1.4221 m2; GrossVolume: 3.46765 m3
Other - Category: Rooms; Phase Id: 0
Constraints - Base Offset: 0 mm; Upper Limit: 0; Limit Offset: 2438.4 mm; Level: 0
Dimensions - Computation Height: 0 mm; Unbounded Height: 2438.4 mm; Area: 1.4221 m2; Perimeter: 8579.49 mm; Volume: 3.41342 m3
Energy Analysis - Actual Lighting Load per area: 0; Actual Power Load per area: 0; Base Lighting Load on: By Space Type; Base Power Load on: By Space Type; Heat Load Values: By Space Type; Lighting Load Units: Power Density; Number of People: 0; Power Load Units: Power Density; Actual Lighting Load: 0 W; Actual Power Load: 0 W; Area per Person: 28.5714 m2; Latent Heat Gain per person: 58.6142 W; Plenum Lighting Contribution: 20; Sensible Heat Gain per person: 73.2678 W; Specified Lighting Load: 0 W; Specified Lighting Load per area: 10.7639; Specified Power Load: 0 W; Specified Power Load per area: 13.9931; Total Heat Gain per person: 131.882 W
Identity Data - Workset: Bouwkundig; Name: garderobe; Number: 0.36a
Phasing - Phase: 2. nieuwbouw
Text - bouwbesluit_functie: opslagruimte

# IfcSpace: garderobe 0.37a:5416321, 0.37a
In: 00 Begane grond
LongName: garderobe; InteriorOrExteriorSpace: INTERNAL
Pset_AirSideSystemInformation - Name: garderobe
Pset_ProductRequirements - Name: garderobe; Category: Rooms
Pset_SpaceCommon - Reference: garderobe 0.37a; Category: Rooms
BaseQuantities - NetFloorArea: 1.4258 m2; Height: 2438.4 mm; GrossFloorArea: 1.4258 m2; GrossVolume: 3.47668 m3
Other - Category: Rooms; Phase Id: 0
Constraints - Base Offset: 0 mm; Upper Limit: 0; Limit Offset: 2438.4 mm; Level: 0
Dimensions - Computation Height: 0 mm; Unbounded Height: 2438.4 mm; Area: 1.4258 m2; Perimeter: 8593.88 mm; Volume: 3.4223 m3
Energy Analysis - Actual Lighting Load per area: 0; Actual Power Load per area: 0; Base Lighting Load on: By Space Type; Base Power Load on: By Space Type; Heat Load Values: By Space Type; Lighting Load Units: Power Density; Number of People: 0; Power Load Units: Power Density; Actual Lighting Load: 0 W; Actual Power Load: 0 W; Area per Person: 28.5714 m2; Latent Heat Gain per person: 58.6142 W; Plenum Lighting Contribution: 20; Sensible Heat Gain per person: 73.2678 W; Specified Lighting Load: 0 W; Specified Lighting Load per area: 10.7639; Specified Power Load: 0 W; Specified Power Load per area: 13.9931; Total Heat Gain per person: 131.882 W
Identity Data - Workset: Bouwkundig; Name: garderobe; Number: 0.37a
Phasing - Phase: 2. nieuwbouw
Text - bouwbesluit_functie: opslagruimte

# IfcSpace: garderobe 1.01a:5311804, 1.01a
In: 01 eerste verdieping
LongName: garderobe; InteriorOrExteriorSpace: INTERNAL
Pset_AirSideSystemInformation - Name: garderobe
Pset_ProductRequirements - Name: garderobe; Category: Rooms
Pset_SpaceCommon - Reference: garderobe 1.01a; Category: Rooms
BaseQuantities - NetFloorArea: 1.18717 m2; Height: 2438.4 mm; GrossPerimeter: 7188 mm; GrossFloorArea: 1.18717 m2; GrossVolume: 2.89479 m3
Other - Category: Rooms; Phase Id: 0
Constraints - Base Offset: 0 mm; Upper Limit: 1; Limit Offset: 2438.4 mm; Level: 1
Dimensions - Computation Height: 0 mm; Unbounded Height: 2438.4 mm; Area: 1.18717 m2; Perimeter: 7188 mm; Volume: 2.8492 m3
Energy Analysis - Actual Lighting Load per area: 0; Actual Power Load per area: 0; Base Lighting Load on: By Space Type; Base Power Load on: By Space Type; Heat Load Values: By Space Type; Lighting Load Units: Power Density; Number of People: 0; Power Load Units: Power Density; Actual Lighting Load: 0 W; Actual Power Load: 0 W; Area per Person: 28.5714 m2; Latent Heat Gain per person: 58.6142 W; Plenum Lighting Contribution: 20; Sensible Heat Gain per person: 73.2678 W; Specified Lighting Load: 0 W; Specified Lighting Load per area: 10.7639; Specified Power Load: 0 W; Specified Power Load per area: 13.9931; Total Heat Gain per person: 131.882 W
Identity Data - Workset: Bouwkundig; Name: garderobe; Number: 1.01a
Phasing - Phase: 2. nieuwbouw
Text - bouwbesluit_functie: opslagruimte

# IfcSpace: garderobe 1.02a:5311807, 1.02a
In: 01 eerste verdieping
LongName: garderobe; InteriorOrExteriorSpace: INTERNAL
Pset_AirSideSystemInformation - Name: garderobe
Pset_ProductRequirements - Name: garderobe; Category: Rooms
Pset_SpaceCommon - Reference: garderobe 1.02a; Category: Rooms
BaseQuantities - NetFloorArea: 1.18901 m2; Height: 2438.4 mm; GrossPerimeter: 7198 mm; GrossFloorArea: 1.18901 m2; GrossVolume: 2.89928 m3
Other - Category: Rooms; Phase Id: 0
Constraints - Base Offset: 0 mm; Upper Limit: 1; Limit Offset: 2438.4 mm; Level: 1
Dimensions - Computation Height: 0 mm; Unbounded Height: 2438.4 mm; Area: 1.18901 m2; Perimeter: 7198 mm; Volume: 2.85362 m3
Energy Analysis - Actual Lighting Load per area: 0; Actual Power Load per area: 0; Base Lighting Load on: By Space Type; Base Power Load on: By Space Type; Heat Load Values: By Space Type; Lighting Load Units: Power Density; Number of People: 0; Power Load Units: Power Density; Actual Lighting Load: 0 W; Actual Power Load: 0 W; Area per Person: 28.5714 m2; Latent Heat Gain per person: 58.6142 W; Plenum Lighting Contribution: 20; Sensible Heat Gain per person: 73.2678 W; Specified Lighting Load: 0 W; Specified Lighting Load per area: 10.7639; Specified Power Load: 0 W; Specified Power Load per area: 13.9931; Total Heat Gain per person: 131.882 W
Identity Data - Workset: Bouwkundig; Name: garderobe; Number: 1.02a
Phasing - Phase: 2. nieuwbouw
Text - bouwbesluit_functie: opslagruimte

# IfcSpace: garderobe 1.03a:5311847, 1.03a
In: 01 eerste verdieping
LongName: garderobe; InteriorOrExteriorSpace: INTERNAL
Pset_AirSideSystemInformation - Name: garderobe
Pset_ProductRequirements - Name: garderobe; Category: Rooms
Pset_SpaceCommon - Reference: garderobe 1.03a; Category: Rooms
BaseQuantities - NetFloorArea: 1.18901 m2; Height: 2438.4 mm; GrossPerimeter: 7198 mm; GrossFloorArea: 1.18901 m2; GrossVolume: 2.89928 m3
Other - Category: Rooms; Phase Id: 0
Constraints - Base Offset: 0 mm; Upper Limit: 1; Limit Offset: 2438.4 mm; Level: 1
Dimensions - Computation Height: 0 mm; Unbounded Height: 2438.4 mm; Area: 1.18901 m2; Perimeter: 7198 mm; Volume: 2.85362 m3
Energy Analysis - Actual Lighting Load per area: 0; Actual Power Load per area: 0; Base Lighting Load on: By Space Type; Base Power Load on: By Space Type; Heat Load Values: By Space Type; Lighting Load Units: Power Density; Number of People: 0; Power Load Units: Power Density; Actual Lighting Load: 0 W; Actual Power Load: 0 W; Area per Person: 28.5714 m2; Latent Heat Gain per person: 58.6142 W; Plenum Lighting Contribution: 20; Sensible Heat Gain per person: 73.2678 W; Specified Lighting Load: 0 W; Specified Lighting Load per area: 10.7639; Specified Power Load: 0 W; Specified Power Load per area: 13.9931; Total Heat Gain per person: 131.882 W
Identity Data - Workset: Bouwkundig; Name: garderobe; Number: 1.03a
Phasing - Phase: 2. nieuwbouw
Text - bouwbesluit_functie: opslagruimte

# IfcSpace: garderobe 1.04a:5311868, 1.04a
In: 01 eerste verdieping
LongName: garderobe; InteriorOrExteriorSpace: INTERNAL
Pset_AirSideSystemInformation - Name: garderobe
Pset_ProductRequirements - Name: garderobe; Category: Rooms
Pset_SpaceCommon - Reference: garderobe 1.04a; Category: Rooms
BaseQuantities - NetFloorArea: 1.18717 m2; Height: 2438.4 mm; GrossPerimeter: 7188 mm; GrossFloorArea: 1.18717 m2; GrossVolume: 2.89479 m3
Other - Category: Rooms; Phase Id: 0
Constraints - Base Offset: 0 mm; Upper Limit: 1; Limit Offset: 2438.4 mm; Level: 1
Dimensions - Computation Height: 0 mm; Unbounded Height: 2438.4 mm; Area: 1.18717 m2; Perimeter: 7188 mm; Volume: 2.8492 m3
Energy Analysis - Actual Lighting Load per area: 0; Actual Power Load per area: 0; Base Lighting Load on: By Space Type; Base Power Load on: By Space Type; Heat Load Values: By Space Type; Lighting Load Units: Power Density; Number of People: 0; Power Load Units: Power Density; Actual Lighting Load: 0 W; Actual Power Load: 0 W; Area per Person: 28.5714 m2; Latent Heat Gain per person: 58.6142 W; Plenum Lighting Contribution: 20; Sensible Heat Gain per person: 73.2678 W; Specified Lighting Load: 0 W; Specified Lighting Load per area: 10.7639; Specified Power Load: 0 W; Specified Power Load per area: 13.9931; Total Heat Gain per person: 131.882 W
Identity Data - Workset: Bouwkundig; Name: garderobe; Number: 1.04a
Phasing - Phase: 2. nieuwbouw
Text - bouwbesluit_functie: opslagruimte

# IfcSpace: garderobe 1.21a:5311910, 1.21a
In: 01 eerste verdieping
LongName: garderobe; InteriorOrExteriorSpace: INTERNAL
Pset_AirSideSystemInformation - Name: garderobe
Pset_ProductRequirements - Name: garderobe; Category: Rooms
Pset_SpaceCommon - Reference: garderobe 1.21a; Category: Rooms
BaseQuantities - NetFloorArea: 1.42315 m2; Height: 2438.4 mm; GrossFloorArea: 1.42315 m2; GrossVolume: 3.47022 m3
Other - Category: Rooms; Phase Id: 0
Constraints - Base Offset: 0 mm; Upper Limit: 1; Limit Offset: 2438.4 mm; Level: 1
Dimensions - Computation Height: 0 mm; Unbounded Height: 2438.4 mm; Area: 1.42315 m2; Perimeter: 8578.9 mm; Volume: 3.41584 m3
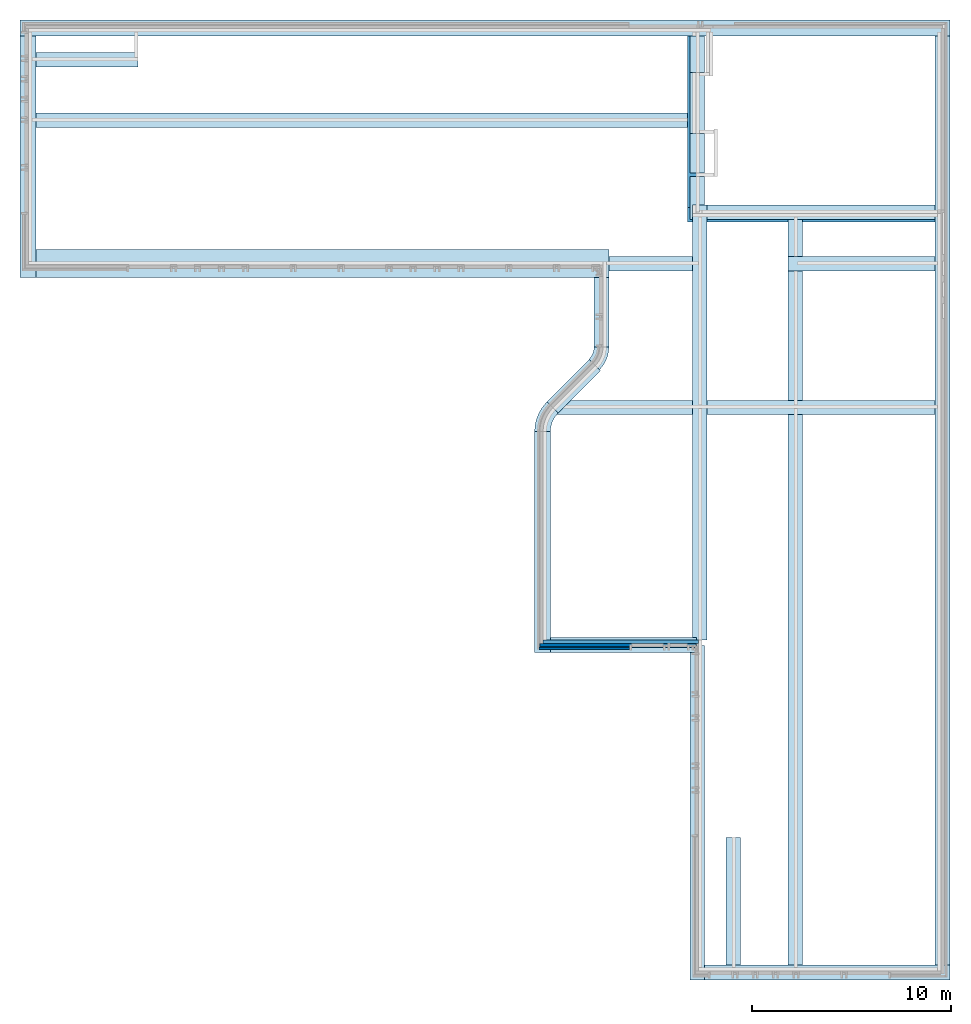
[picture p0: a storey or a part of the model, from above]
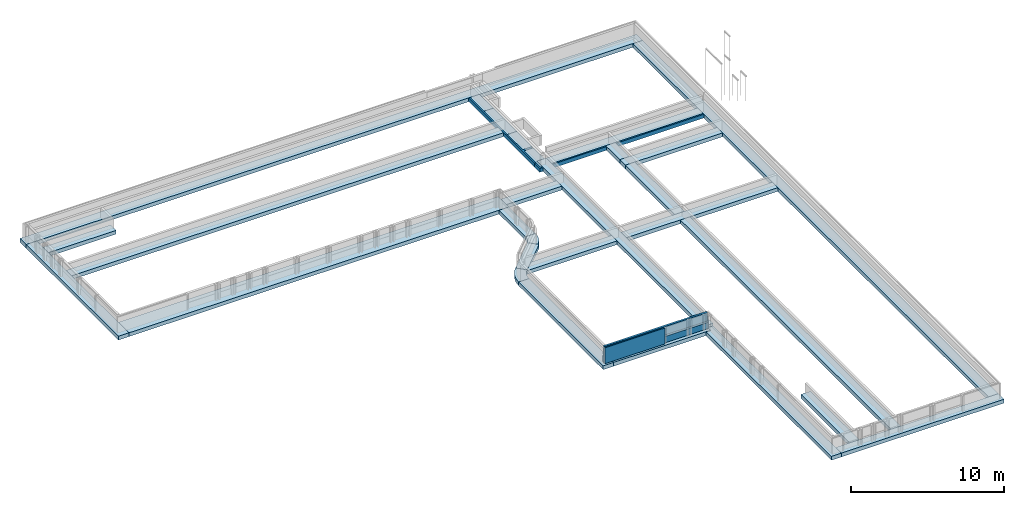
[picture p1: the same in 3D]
Properties of the parts of a building model (IFC2X3), part 3 of 37

# IfcSpace: garderobe 1.21a:5311910, 1.21a
Energy Analysis - Actual Lighting Load per area: 0; Actual Power Load per area: 0; Base Lighting Load on: By Space Type; Base Power Load on: By Space Type; Heat Load Values: By Space Type; Lighting Load Units: Power Density; Number of People: 0; Power Load Units: Power Density; Actual Lighting Load: 0 W; Actual Power Load: 0 W; Area per Person: 28.5714 m2; Latent Heat Gain per person: 58.6142 W; Plenum Lighting Contribution: 20; Sensible Heat Gain per person: 73.2678 W; Specified Lighting Load: 0 W; Specified Lighting Load per area: 10.7639; Specified Power Load: 0 W; Specified Power Load per area: 13.9931; Total Heat Gain per person: 131.882 W
Identity Data - Workset: Bouwkundig; Name: garderobe; Number: 1.21a
Phasing - Phase: 2. nieuwbouw
Text - bouwbesluit_functie: opslagruimte

# IfcSpace: garderobe 1.22a:5311933, 1.22a
In: 01 eerste verdieping
LongName: garderobe; InteriorOrExteriorSpace: INTERNAL
Pset_AirSideSystemInformation - Name: garderobe
Pset_ProductRequirements - Name: garderobe; Category: Rooms
Pset_SpaceCommon - Reference: garderobe 1.22a; Category: Rooms
BaseQuantities - NetFloorArea: 1.42315 m2; Height: 2438.4 mm; GrossFloorArea: 1.42315 m2; GrossVolume: 3.47021 m3
Other - Category: Rooms; Phase Id: 0
Constraints - Base Offset: 0 mm; Upper Limit: 1; Limit Offset: 2438.4 mm; Level: 1
Dimensions - Computation Height: 0 mm; Unbounded Height: 2438.4 mm; Area: 1.42315 m2; Perimeter: 8578.9 mm; Volume: 3.41584 m3
Energy Analysis - Actual Lighting Load per area: 0; Actual Power Load per area: 0; Base Lighting Load on: By Space Type; Base Power Load on: By Space Type; Heat Load Values: By Space Type; Lighting Load Units: Power Density; Number of People: 0; Power Load Units: Power Density; Actual Lighting Load: 0 W; Actual Power Load: 0 W; Area per Person: 28.5714 m2; Latent Heat Gain per person: 58.6142 W; Plenum Lighting Contribution: 20; Sensible Heat Gain per person: 73.2678 W; Specified Lighting Load: 0 W; Specified Lighting Load per area: 10.7639; Specified Power Load: 0 W; Specified Power Load per area: 13.9931; Total Heat Gain per person: 131.882 W
Identity Data - Workset: Bouwkundig; Name: garderobe; Number: 1.22a
Phasing - Phase: 2. nieuwbouw
Text - bouwbesluit_functie: opslagruimte

# IfcSpace: garderobe 1.23a:5311945, 1.23a
In: 01 eerste verdieping
LongName: garderobe; InteriorOrExteriorSpace: INTERNAL
Pset_AirSideSystemInformation - Name: garderobe
Pset_ProductRequirements - Name: garderobe; Category: Rooms
Pset_SpaceCommon - Reference: garderobe 1.23a; Category: Rooms
BaseQuantities - NetFloorArea: 1.42582 m2; Height: 2438.4 mm; GrossFloorArea: 1.42582 m2; GrossVolume: 3.47673 m3
Other - Category: Rooms; Phase Id: 0
Constraints - Base Offset: 0 mm; Upper Limit: 1; Limit Offset: 2438.4 mm; Level: 1
Dimensions - Computation Height: 0 mm; Unbounded Height: 2438.4 mm; Area: 1.42582 m2; Perimeter: 8582 mm; Volume: 3.42235 m3
Energy Analysis - Actual Lighting Load per area: 0; Actual Power Load per area: 0; Base Lighting Load on: By Space Type; Base Power Load on: By Space Type; Heat Load Values: By Space Type; Lighting Load Units: Power Density; Number of People: 0; Power Load Units: Power Density; Actual Lighting Load: 0 W; Actual Power Load: 0 W; Area per Person: 28.5714 m2; Latent Heat Gain per person: 58.6142 W; Plenum Lighting Contribution: 20; Sensible Heat Gain per person: 73.2678 W; Specified Lighting Load: 0 W; Specified Lighting Load per area: 10.7639; Specified Power Load: 0 W; Specified Power Load per area: 13.9931; Total Heat Gain per person: 131.882 W
Identity Data - Workset: Bouwkundig; Name: garderobe; Number: 1.23a
Phasing - Phase: 2. nieuwbouw
Text - bouwbesluit_functie: opslagruimte

# IfcSpace: kastruimte 0.10:5217941, 0.10
In: 00 Begane grond
LongName: kastruimte; InteriorOrExteriorSpace: INTERNAL
Pset_AirSideSystemInformation - Name: kastruimte
Pset_ProductRequirements - Name: kastruimte; Category: Rooms
Pset_SpaceCommon - Reference: kastruimte 0.10; Category: Rooms
BaseQuantities - NetFloorArea: 1.50061 m2; Height: 2600 mm; GrossFloorArea: 1.50061 m2; GrossVolume: 3.90157 m3
Other - Category: Rooms; Phase Id: 0
Constraints - Base Offset: 0 mm; Upper Limit: 0; Level: 0; Limit Offset: 2600 mm
Dimensions - Computation Height: 0 mm; Area: 1.50061 m2; Perimeter: 6098 mm; Unbounded Height: 2600 mm; Volume: 3.62757 m3
Energy Analysis - Actual Lighting Load per area: 0; Actual Power Load per area: 0; Base Lighting Load on: By Space Type; Base Power Load on: By Space Type; Heat Load Values: By Space Type; Lighting Load Units: Power Density; Number of People: 0; Power Load Units: Power Density; Actual Lighting Load: 0 W; Actual Power Load: 0 W; Area per Person: 28.5714 m2; Latent Heat Gain per person: 58.6142 W; Plenum Lighting Contribution: 20; Sensible Heat Gain per person: 73.2678 W; Specified Lighting Load: 0 W; Specified Lighting Load per area: 10.7639; Specified Power Load: 0 W; Specified Power Load per area: 13.9931; Total Heat Gain per person: 131.882 W
Identity Data - Workset: Bouwkundig; Name: kastruimte; Number: 0.10
Phasing - Phase: 2. nieuwbouw
Text - bouwbesluit_functie: opslagruimte

# IfcSpace: kastruimte 0.11:5213646, 0.11
In: 00 Begane grond
LongName: kastruimte; InteriorOrExteriorSpace: INTERNAL
Pset_AirSideSystemInformation - Name: kastruimte
Pset_ProductRequirements - Name: kastruimte; Category: Rooms
Pset_SpaceCommon - Reference: kastruimte 0.11; Category: Rooms
BaseQuantities - NetFloorArea: 2.11276 m2; Height: 2600 mm; GrossPerimeter: 6548 mm; GrossFloorArea: 2.11276 m2; GrossVolume: 5.49318 m3
Other - Category: Rooms; Phase Id: 0
Constraints - Base Offset: 0 mm; Upper Limit: 0; Level: 0; Limit Offset: 2600 mm
Dimensions - Computation Height: 0 mm; Area: 2.11276 m2; Perimeter: 6548 mm; Unbounded Height: 2600 mm; Volume: 5.49318 m3
Energy Analysis - Actual Lighting Load per area: 0; Actual Power Load per area: 0; Base Lighting Load on: By Space Type; Base Power Load on: By Space Type; Heat Load Values: By Space Type; Lighting Load Units: Power Density; Number of People: 0; Power Load Units: Power Density; Actual Lighting Load: 0 W; Actual Power Load: 0 W; Area per Person: 28.5714 m2; Latent Heat Gain per person: 58.6142 W; Plenum Lighting Contribution: 20; Sensible Heat Gain per person: 73.2678 W; Specified Lighting Load: 0 W; Specified Lighting Load per area: 10.7639; Specified Power Load: 0 W; Specified Power Load per area: 13.9931; Total Heat Gain per person: 131.882 W
Identity Data - Workset: Bouwkundig; Name: kastruimte; Number: 0.11
Phasing - Phase: 2. nieuwbouw
Text - bouwbesluit_functie: opslagruimte

# IfcSpace: kastruimte 0.13:5213649, 0.13
In: 00 Begane grond
LongName: kastruimte; InteriorOrExteriorSpace: INTERNAL
Pset_AirSideSystemInformation - Name: kastruimte
Pset_ProductRequirements - Name: kastruimte; Category: Rooms
Pset_SpaceCommon - Reference: kastruimte 0.13; Category: Rooms
BaseQuantities - NetFloorArea: 2.11276 m2; Height: 2600 mm; GrossPerimeter: 6548 mm; GrossFloorArea: 2.11276 m2; GrossVolume: 5.49318 m3
Other - Category: Rooms; Phase Id: 0
Constraints - Base Offset: 0 mm; Upper Limit: 0; Level: 0; Limit Offset: 2600 mm
Dimensions - Computation Height: 0 mm; Area: 2.11276 m2; Perimeter: 6548 mm; Unbounded Height: 2600 mm; Volume: 5.49318 m3
Energy Analysis - Actual Lighting Load per area: 0; Actual Power Load per area: 0; Base Lighting Load on: By Space Type; Base Power Load on: By Space Type; Heat Load Values: By Space Type; Lighting Load Units: Power Density; Number of People: 0; Power Load Units: Power Density; Actual Lighting Load: 0 W; Actual Power Load: 0 W; Area per Person: 28.5714 m2; Latent Heat Gain per person: 58.6142 W; Plenum Lighting Contribution: 20; Sensible Heat Gain per person: 73.2678 W; Specified Lighting Load: 0 W; Specified Lighting Load per area: 10.7639; Specified Power Load: 0 W; Specified Power Load per area: 13.9931; Total Heat Gain per person: 131.882 W
Identity Data - Workset: Bouwkundig; Name: kastruimte; Number: 0.13
Phasing - Phase: 2. nieuwbouw
Text - bouwbesluit_functie: opslagruimte

# IfcSpace: kastruimte 0.21:5207247, 0.21
In: 00 Begane grond
LongName: kastruimte; InteriorOrExteriorSpace: INTERNAL
Pset_AirSideSystemInformation - Name: kastruimte
Pset_ProductRequirements - Name: kastruimte; Category: Rooms
Pset_SpaceCommon - Reference: kastruimte 0.21; Category: Rooms
BaseQuantities - NetFloorArea: 2.00734 m2; Height: 2600 mm; GrossPerimeter: 6642 mm; GrossFloorArea: 2.00734 m2; GrossVolume: 5.21908 m3
Other - Category: Rooms; Phase Id: 0
Constraints - Base Offset: 0 mm; Upper Limit: 0; Level: 0; Limit Offset: 2600 mm
Dimensions - Computation Height: 0 mm; Area: 2.00734 m2; Perimeter: 6642 mm; Unbounded Height: 2600 mm; Volume: 5.21908 m3
Energy Analysis - Actual Lighting Load per area: 0; Actual Power Load per area: 0; Base Lighting Load on: By Space Type; Base Power Load on: By Space Type; Heat Load Values: By Space Type; Lighting Load Units: Power Density; Number of People: 0; Power Load Units: Power Density; Actual Lighting Load: 0 W; Actual Power Load: 0 W; Area per Person: 28.5714 m2; Latent Heat Gain per person: 58.6142 W; Plenum Lighting Contribution: 20; Sensible Heat Gain per person: 73.2678 W; Specified Lighting Load: 0 W; Specified Lighting Load per area: 10.7639; Specified Power Load: 0 W; Specified Power Load per area: 13.9931; Total Heat Gain per person: 131.882 W
Identity Data - Workset: Bouwkundig; Name: kastruimte; Number: 0.21
Phasing - Phase: 2. nieuwbouw
Text - bouwbesluit_functie: opslagruimte

# IfcSpace: kastruimte 0.22:5207248, 0.22
In: 00 Begane grond
LongName: kastruimte; InteriorOrExteriorSpace: INTERNAL
Pset_AirSideSystemInformation - Name: kastruimte
Pset_ProductRequirements - Name: kastruimte; Category: Rooms
Pset_SpaceCommon - Reference: kastruimte 0.22; Category: Rooms
BaseQuantities - NetFloorArea: 1.83429 m2; Height: 2600 mm; GrossFloorArea: 1.83429 m2; GrossVolume: 4.76915 m3
Other - Category: Rooms; Phase Id: 0
Constraints - Base Offset: 0 mm; Upper Limit: 0; Level: 0; Limit Offset: 2600 mm
Dimensions - Computation Height: 0 mm; Area: 1.83429 m2; Perimeter: 6182 mm; Unbounded Height: 2600 mm; Volume: 4.4023 m3
Energy Analysis - Actual Lighting Load per area: 0; Actual Power Load per area: 0; Base Lighting Load on: By Space Type; Base Power Load on: By Space Type; Heat Load Values: By Space Type; Lighting Load Units: Power Density; Number of People: 0; Power Load Units: Power Density; Actual Lighting Load: 0 W; Actual Power Load: 0 W; Area per Person: 28.5714 m2; Latent Heat Gain per person: 58.6142 W; Plenum Lighting Contribution: 20; Sensible Heat Gain per person: 73.2678 W; Specified Lighting Load: 0 W; Specified Lighting Load per area: 10.7639; Specified Power Load: 0 W; Specified Power Load per area: 13.9931; Total Heat Gain per person: 131.882 W
Identity Data - Workset: Bouwkundig; Name: kastruimte; Number: 0.22
Phasing - Phase: 2. nieuwbouw
Text - bouwbesluit_functie: opslagruimte

# IfcSpace: kastruimte 0.32:5207282, 0.32
In: 00 Begane grond
LongName: kastruimte; InteriorOrExteriorSpace: INTERNAL
Pset_AirSideSystemInformation - Name: kastruimte
Pset_ProductRequirements - Name: kastruimte; Category: Rooms
Pset_SpaceCommon - Reference: kastruimte 0.32; Category: Rooms
BaseQuantities - NetFloorArea: 2.34879 m2; Height: 2600 mm; GrossPerimeter: 6974 mm; GrossFloorArea: 2.34879 m2; GrossVolume: 6.10685 m3
Other - Category: Rooms; Phase Id: 0
Constraints - Base Offset: 0 mm; Upper Limit: 0; Level: 0; Limit Offset: 2600 mm
Dimensions - Computation Height: 0 mm; Area: 2.34879 m2; Perimeter: 6974 mm; Unbounded Height: 2600 mm; Volume: 5.63709 m3
Energy Analysis - Actual Lighting Load per area: 0; Actual Power Load per area: 0; Base Lighting Load on: By Space Type; Base Power Load on: By Space Type; Heat Load Values: By Space Type; Lighting Load Units: Power Density; Number of People: 0; Power Load Units: Power Density; Actual Lighting Load: 0 W; Actual Power Load: 0 W; Area per Person: 28.5714 m2; Latent Heat Gain per person: 58.6142 W; Plenum Lighting Contribution: 20; Sensible Heat Gain per person: 73.2678 W; Specified Lighting Load: 0 W; Specified Lighting Load per area: 10.7639; Specified Power Load: 0 W; Specified Power Load per area: 13.9931; Total Heat Gain per person: 131.882 W
Identity Data - Workset: Bouwkundig; Name: kastruimte; Number: 0.32
Phasing - Phase: 2. nieuwbouw
Text - bouwbesluit_functie: opslagruimte

# IfcSpace: meterkast 0.45:5207264, 0.45
In: 00 Begane grond
LongName: meterkast; InteriorOrExteriorSpace: INTERNAL
Pset_AirSideSystemInformation - Name: meterkast
Pset_ProductRequirements - Name: meterkast; Category: Rooms
Pset_SpaceCommon - Reference: meterkast 0.45; Category: Rooms
BaseQuantities - NetFloorArea: 1.09303 m2; Height: 2600 mm; GrossPerimeter: 5712 mm; GrossFloorArea: 1.09303 m2; GrossVolume: 2.84188 m3
Other - Category: Rooms; Phase Id: 0
Constraints - Base Offset: 0 mm; Upper Limit: 0; Level: 0; Limit Offset: 2600 mm
Dimensions - Computation Height: 0 mm; Area: 1.09303 m2; Perimeter: 5712 mm; Unbounded Height: 2600 mm; Volume: 2.84188 m3
Energy Analysis - Actual Lighting Load per area: 0; Actual Power Load per area: 0; Base Lighting Load on: By Space Type; Base Power Load on: By Space Type; Heat Load Values: By Space Type; Lighting Load Units: Power Density; Number of People: 0; Power Load Units: Power Density; Actual Lighting Load: 0 W; Actual Power Load: 0 W; Area per Person: 28.5714 m2; Latent Heat Gain per person: 58.6142 W; Plenum Lighting Contribution: 20; Sensible Heat Gain per person: 73.2678 W; Specified Lighting Load: 0 W; Specified Lighting Load per area: 10.7639; Specified Power Load: 0 W; Specified Power Load per area: 13.9931; Total Heat Gain per person: 131.882 W
Identity Data - Workset: Bouwkundig; Name: meterkast; Number: 0.45
Phasing - Phase: 2. nieuwbouw
Text - bouwbesluit_functie: technische ruimte

# IfcSpace: opstelruimte techniek 0.47:6622314, 0.47
In: 00 Begane grond
LongName: opstelruimte techniek; InteriorOrExteriorSpace: INTERNAL
Pset_AirSideSystemInformation - Name: opstelruimte techniek
Pset_ProductRequirements - Name: opstelruimte techniek; Category: Rooms
Pset_SpaceCommon - Reference: opstelruimte techniek 0.47; Category: Rooms
BaseQuantities - NetFloorArea: 8.96992 m2; Height: 2438.4 mm; GrossPerimeter: 12970 mm; GrossFloorArea: 8.96992 m2; GrossVolume: 21.8723 m3
Other - Category: Rooms; Phase Id: 0
Constraints - Base Offset: 0 mm; Upper Limit: 0; Limit Offset: 2438.4 mm; Level: 0
Dimensions - Computation Height: 0 mm; Unbounded Height: 2438.4 mm; Area: 8.96992 m2; Perimeter: 12970 mm; Volume: 21.8724 m3
Energy Analysis - Actual Lighting Load per area: 0; Actual Power Load per area: 0; Base Lighting Load on: By Space Type; Base Power Load on: By Space Type; Heat Load Values: By Space Type; Lighting Load Units: Power Density; Number of People: 0; Power Load Units: Power Density; Actual Lighting Load: 0 W; Actual Power Load: 0 W; Area per Person: 28.5714 m2; Latent Heat Gain per person: 58.6142 W; Plenum Lighting Contribution: 20; Sensible Heat Gain per person: 73.2678 W; Specified Lighting Load: 0 W; Specified Lighting Load per area: 10.7639; Specified Power Load: 0 W; Specified Power Load per area: 13.9931; Total Heat Gain per person: 131.882 W
Identity Data - Workset: Bouwkundig; Name: opstelruimte techniek; Number: 0.47
Phasing - Phase: 2. nieuwbouw
Text - bouwbesluit_functie: technische ruimte

# IfcSpace: wasruimte 0.14:5207278, 0.14
In: 00 Begane grond
LongName: wasruimte; InteriorOrExteriorSpace: INTERNAL
Pset_AirSideSystemInformation - Name: wasruimte
Pset_ProductRequirements - Name: wasruimte; Category: Rooms
Pset_SpaceCommon - Reference: wasruimte 0.14; Category: Rooms
BaseQuantities - NetFloorArea: 7.54258 m2; Height: 2600 mm; GrossPerimeter: 16342 mm; GrossFloorArea: 7.54258 m2; GrossVolume: 19.6107 m3
Other - Category: Rooms; Phase Id: 0
Constraints - Base Offset: 0 mm; Upper Limit: 0; Level: 0; Limit Offset: 2600 mm
Dimensions - Computation Height: 0 mm; Area: 7.54258 m2; Perimeter: 16342 mm; Unbounded Height: 2600 mm; Volume: 19.6107 m3
Energy Analysis - Actual Lighting Load per area: 0; Actual Power Load per area: 0; Base Lighting Load on: By Space Type; Base Power Load on: By Space Type; Heat Load Values: By Space Type; Lighting Load Units: Power Density; Number of People: 0; Power Load Units: Power Density; Actual Lighting Load: 0 W; Actual Power Load: 0 W; Area per Person: 28.5714 m2; Latent Heat Gain per person: 58.6142 W; Plenum Lighting Contribution: 20; Sensible Heat Gain per person: 73.2678 W; Specified Lighting Load: 0 W; Specified Lighting Load per area: 10.7639; Specified Power Load: 0 W; Specified Power Load per area: 13.9931; Total Heat Gain per person: 131.882 W
Identity Data - Workset: Bouwkundig; Name: wasruimte; Number: 0.14
Phasing - Phase: 2. nieuwbouw
Text - bouwbesluit_functie: overige ruimte

# IfcBeam: 300_28_ISR_balk_IPE:IPE160 (4)
In: 00 Begane grond
Type - Other - Category: Structural Framing; Family Name: 300_28_ISR_balk_IPE
Type - Dimensions - bf: 82 mm; d: 160 mm; k: 16.4 mm; tf: 7.4 mm; tr: 9 mm; tw: 5 mm
Type - Identity Data - Assembly Code: 28.11; Assembly Description: hoofddraagconstructies; kolommen en liggers, kolom-/liggerconstructies; Datum_Gewijzigd: 20110429; SmartRevit_Versie: 2012.1; Type Name: IPE160; Workset: Family : Structural Framing : 300_28_ISR_balk_IPE
Type - Structural - A: 0.002009 m2; Section Shape: 0; W: 16.1
Type - Pset_BeamCommon - LoadBearing: yes; IsExternal: no
Type - Pset_ProductRequirements - Category: Structural Framing
Classification: 28.11 Uniformat (Uniformat)
BaseQuantities - CrossSectionArea: 0.00200919 m2
Pset_BeamCommon - Slope: 0 deg; Reference: IPE160
Pset_QuantityTakeOff - Reference: IPE160; sets with these values: 2
Pset_DAT_KMS - Assembly Code: 28.11; Assembly Description: hoofddraagconstructies; kolommen en liggers, kolom-/liggerconstructies
Other - End Extension Calculation: 3000.1 mm; Family: 300_28_ISR_balk_IPE; Family and Type: 300_28_ISR_balk_IPE: IPE160; Type: IPE160; Type Id: 3825140
Constraints - Cross-Section Rotation: 0 deg; Reference Level: 0; Reference Level Elevation: 0 mm; End Level Offset: 2120 mm; Start Level Offset: 2120 mm
Construction - End Extension: -12.604 mm
Dimensions - Elevation at Bottom: 2120 mm; Elevation at Top: 2280 mm
Identity Data - Has Association: no; Workset: situatie
Phasing - Phase Created: 2. nieuwbouw
Structural - Stick Symbol Location: Center of Geometry; Structural Usage: Other
Geometric Position - End Extension: 0 mm; Start Extension: 0 mm; y Justification: Origin; yz Justification: Uniform; y Offset Value: 0 mm; z Offset Value: 0 mm; z Justification: Bottom; Join Status: One or two joins disabled
Name (300_28_ISR_balk_IPE:IPE160:...) | Material = Structural Material | BaseQuantities, Length (mm) = Cut Length (mm) | OuterSurfaceArea (m2) | GrossVolume (m3) | NetVolume (m3) = Volume (m3) | Span (mm) = Dimensions, Length (mm) | Start Extension Calculation (mm) | Start Extension (mm)
6497481 | ISR_RAL 7006 | 27650 | 17.2135 | 0.055554 | 0.0536299 | 27637.2 | 3012.7 | 0
6497533 | STAAL_RAL 7006 | 27650 | 17.2135 | 0.055554 | 0.0536299 | 27637.2 | 3012.7 | 0
6497590 | ISR_RAL 7006 | 2209.7 | 1.37565 | 0.0044397 | 0.00428593 | 2196.9 | 3012.7 | 0
6497693 | ISR_RAL 7006 | 2209.99 | 1.37582 | 0.00444028 | 0.00428649 | 2196.9 | 3012.99 | 0.286564

# IfcBeam: NLRS_28_SF_LIB_balk SFB_gen_ASN Links:balk HEA260460x15, NLRS_28_SF_LIB_balk SFB_gen_ASN Links:balk HEA260460x15:6526746
In: 00 Begane grond
Type - PredefinedType: BEAM; Material: <Unnamed>, ISR_Staal
Type - Other - Category: Structural Framing; Family Name: NLRS_28_SF_LIB_balk SFB_gen_ASN Links
Type - Dimensions - bf: 260 mm; bu: 360 mm; h: 250 mm; k: 42.5 mm; kr: 30 mm; NLRS_C_breedte: 260 mm; NLRS_C_hoogte: 250 mm; tf: 12.5 mm; tu: 15 mm; tw: 9 mm; y: 121 mm
Type - General - NLRS_C_content_creator: Arkance Systems; NLRS_C_content_datum_gewijzigd: 2022.05.27; NLRS_C_content_provider: Arkance Systems; NLRS_C_content_versie: 2.1; NLRS_C_revit_versie: 2021
Type - Identity Data - Assembly Code: 28.10; Assembly Description: hoofddraagconstructies; kolommen en liggers, algemeen (verzamelniveau); Description: HEA260 460x15; Manufacturer: generiek; Model: SFB ligger; Type Name: balk HEA260460x15; Workset: Family : Structural Framing : NLRS_28_SF_LIB_balk SFB_gen_ASN Links
Type - Structural - A: 0.012437 m2; Section Shape: 16; SG: 7800
Type - Structural Section Geometry - Bottom Flange Thickness: 15 mm; Bottom Flange Width: 360 mm; Centroid Horizontal: 180 mm; Centroid Vertical: 121 mm; Height: 250 mm; Top Flange Thickness: 12.5 mm; Top Flange Width: 260 mm; Web Height: 225 mm; Web Thickness: 9 mm; Width: 260 mm
Type - Pset_BeamCommon - LoadBearing: yes; IsExternal: no
Type - Pset_ManufacturerTypeInformation - Manufacturer: generiek
Type - Pset_ProductRequirements - Category: Structural Framing
Type - Pset_ReinforcementBarPitchOfBeam - Description: HEA260 460x15
Classification: 28.10 Uniformat (Uniformat); Material: ISR_Staal
Pset_BeamCommon - Slope: 0 deg; IsExternal: yes; Reference: balk HEA260460x15; Span: 1040 mm
Pset_PrecastConcreteElementGeneral - ElementWeight: 0 kg
Pset_QuantityTakeOff - Reference: balk HEA260460x15; sets with these values: 2
Pset_DAT_KMS - Assembly Code: 28.10; Assembly Description: hoofddraagconstructies; kolommen en liggers, algemeen (verzamelniveau); Description: HEA260 460x15
BaseQuantities - Length: 1040 mm; CrossSectionArea: 0.0054 m2; OuterSurfaceArea: 0.756437 m2; GrossSurfaceArea: 0.767237 m2; GrossVolume: 0.00544635 m3; NetVolume: 0.0170553 m3; NetSurfaceArea: 2.62187 m2
Other - Type: balk HEA260460x15; Family: NLRS_28_SF_LIB_balk SFB_gen_ASN Links; Family and Type: NLRS_28_SF_LIB_balk SFB_gen_ASN Links: balk HEA260460x15; Type Id: 5974320
Constraints - Cross-Section Rotation: 0 deg; Orientation: Normal; Reference Level: 0; Reference Level Elevation: 0 mm; End Level Offset: 3500 mm; Start Level Offset: 3500 mm; wandoplegging_eind: 120 mm; wandoplegging_start: 120 mm; Work Plane: <not associated>
Dimensions - Elevation at Bottom: 3225 mm; Elevation at Top: 3490 mm; Length: 1040 mm; NLRS_C_lengte: 1040 mm; Volume: 0.0170553 m3
Identity Data - Has Association: no; Workset: Constructie
Phasing - Phase Created: 2. nieuwbouw
Structural - Stick Symbol Location: Center of Geometry; Structural Usage: Other; Cut Length: 1248.58 mm
Geometric Position - End Extension: 0 mm; Join Status: Both joins enabled; y Justification: Origin; yz Justification: Uniform; z Justification: Top; Start Extension: 208.583 mm; y Offset Value: 10 mm; z Offset Value: -10 mm

# IfcBeam: NLRS_28_SF_LIB_balk SFB_gen_ASN Links:balk HEA260460x15, NLRS_28_SF_LIB_balk SFB_gen_ASN Links:balk HEA260460x15:4749066
In: 00 Begane grond
Type - PredefinedType: BEAM; Material: h2_staal S235
Type - Other - Category: Structural Framing; Family Name: NLRS_28_SF_LIB_balk SFB_gen_ASN Links
Type - Dimensions - bf: 260 mm; bu: 360 mm; h: 250 mm; k: 42.5 mm; kr: 30 mm; NLRS_C_breedte: 260 mm; NLRS_C_hoogte: 250 mm; tf: 12.5 mm; tu: 15 mm; tw: 9 mm; y: 121 mm
Type - General - NLRS_C_content_creator: Arkance Systems; NLRS_C_content_datum_gewijzigd: 2022.05.27; NLRS_C_content_provider: Arkance Systems; NLRS_C_content_versie: 2.1; NLRS_C_revit_versie: 2021
Type - Identity Data - Assembly Code: 28.10; Assembly Description: hoofddraagconstructies; kolommen en liggers, algemeen (verzamelniveau); Description: HEA260 460x15; Manufacturer: generiek; Model: SFB ligger; Type Name: balk HEA260460x15; Workset: Family : Structural Framing : NLRS_28_SF_LIB_balk SFB_gen_ASN Links
Type - Structural - A: 0.012437 m2; Section Shape: 16; SG: 7800
Type - Structural Section Geometry - Bottom Flange Thickness: 15 mm; Bottom Flange Width: 360 mm; Centroid Horizontal: 180 mm; Centroid Vertical: 121 mm; Height: 250 mm; Top Flange Thickness: 12.5 mm; Top Flange Width: 260 mm; Web Height: 225 mm; Web Thickness: 9 mm; Width: 260 mm
Type - Pset_BeamCommon - LoadBearing: yes; IsExternal: no
Type - Pset_ManufacturerTypeInformation - Manufacturer: generiek
Type - Pset_ProductRequirements - Category: Structural Framing
Type - Pset_ReinforcementBarPitchOfBeam - Description: HEA260 460x15
Classification: 28.10 Uniformat (Uniformat)
Pset_BeamCommon - Slope: 0 deg; IsExternal: yes; Reference: balk HEA260460x15; Span: 1790 mm
Pset_PrecastConcreteElementGeneral - ElementWeight: 0 kg
Pset_QuantityTakeOff - Reference: balk HEA260460x15; sets with these values: 2
Pset_DAT_KMS - Assembly Code: 28.10; Assembly Description: hoofddraagconstructies; kolommen en liggers, algemeen (verzamelniveau); Description: HEA260 460x15
BaseQuantities - Length: 1790 mm; CrossSectionArea: 0.0054 m2; OuterSurfaceArea: 3.46875 m2; GrossSurfaceArea: 3.47955 m2; GrossVolume: 0.024975 m3; NetVolume: 0.0702082 m3; NetSurfaceArea: 10.6521 m2
Other - Type: balk HEA260460x15; Family: NLRS_28_SF_LIB_balk SFB_gen_ASN Links; Family and Type: NLRS_28_SF_LIB_balk SFB_gen_ASN Links: balk HEA260460x15; Type Id: 5974320
Constraints - Cross-Section Rotation: 0 deg; End Level Offset: -15 mm; Reference Level: V1 ok. ruwe vloer; Reference Level Elevation: 3240 mm; Start Level Offset: -15 mm; wandoplegging_eind: 120 mm; wandoplegging_start: 120 mm
Dimensions - Elevation at Bottom: 3225 mm; Elevation at Top: 3490 mm; Length: 1790 mm; NLRS_C_lengte: 1790 mm; Volume: 0.0702082 m3
Identity Data - Has Association: no; Workset: Constructie
Materials and Finishes - Structural Material: h2_staal S235
Phasing - Phase Created: 2. nieuwbouw
Structural - Stick Symbol Location: Center of Geometry; Structural Usage: Other; Cut Length: 4865 mm
Geometric Position - End Extension: 0 mm; Join Status: Both joins enabled; y Justification: Origin; yz Justification: Uniform; y Offset Value: 0 mm; z Offset Value: 0 mm; Start Extension: 3075 mm; z Justification: Bottom

# IfcBeam: NLRS_28_SF_LIB_balk SFB_gen_ASN Links:balk HEB220 320x15 (2)
In: 00 Begane grond
Type - PredefinedType: T_BEAM; Material: h2_staal S235
Type - Other - Category: Structural Framing; Family Name: NLRS_28_SF_LIB_balk SFB_gen_ASN Links
Type - Dimensions - bf: 220 mm; bu: 320 mm; h: 220 mm; k: 42.5 mm; kr: 27 mm; NLRS_C_breedte: 220 mm; NLRS_C_hoogte: 220 mm; tf: 15.5 mm; tu: 15 mm; tw: 9 mm; y: 121 mm
Type - General - NLRS_C_content_creator: Arkance Systems; NLRS_C_content_datum_gewijzigd: 2022.05.27; NLRS_C_content_provider: Arkance Systems; NLRS_C_content_versie: 2.1; NLRS_C_revit_versie: 2021
Type - Identity Data - Workset: Family : Structural Framing : NLRS_28_SF_LIB_balk SFB_gen_ASN Links; Assembly Code: 28.10; Assembly Description: hoofddraagconstructies; kolommen en liggers, algemeen (verzamelniveau); Description: SFB-HEA320 500x15; Manufacturer: generiek; Model: SFB ligger; Type Name: balk HEB220 320x15
Type - Structural - A: 0.012437 m2; Section Shape: 16; SG: 7800
Type - Structural Section Geometry - Bottom Flange Thickness: 15 mm; Bottom Flange Width: 320 mm; Centroid Horizontal: 160 mm; Centroid Vertical: 121 mm; Height: 220 mm; Top Flange Thickness: 15.5 mm; Top Flange Width: 220 mm; Web Height: 189 mm; Web Thickness: 9 mm; Width: 220 mm
Type - Pset_BeamCommon - LoadBearing: yes; IsExternal: no
Type - Pset_ManufacturerTypeInformation - Manufacturer: generiek
Type - Pset_ProductRequirements - Category: Structural Framing
Type - Pset_ReinforcementBarPitchOfBeam - Description: SFB-HEA320 500x15
Classification: 28.10 Uniformat (Uniformat)
Pset_BeamCommon - Slope: 0 deg; IsExternal: yes; Reference: balk HEB220 320x15
Pset_PrecastConcreteElementGeneral - ElementWeight: 0 kg
Pset_QuantityTakeOff - Reference: balk HEB220 320x15; sets with these values: 2
Pset_DAT_KMS - Assembly Code: 28.10; Assembly Description: hoofddraagconstructies; kolommen en liggers, algemeen (verzamelniveau); Description: SFB-HEA320 500x15
BaseQuantities - CrossSectionArea: 0.0048 m2
Other - Family: NLRS_28_SF_LIB_balk SFB_gen_ASN Links; Family and Type: NLRS_28_SF_LIB_balk SFB_gen_ASN Links: balk HEB220 320x15; Type: balk HEB220 320x15; Type Id: 6156994
Constraints - Cross-Section Rotation: 0 deg; End Level Offset: 0 mm; Orientation: Normal; Start Level Offset: 0 mm; Reference Level: V1 ok. ruwe vloer; Reference Level Elevation: 3240 mm; wandoplegging_eind: 120 mm; wandoplegging_start: 120 mm
Dimensions - Elevation at Bottom: 3240 mm; Elevation at Top: 3475 mm
Identity Data - Has Association: no; Workset: Constructie
Materials and Finishes - Structural Material: h2_staal S235
Phasing - Phase Created: 2. nieuwbouw
Structural - Stick Symbol Location: Center of Geometry; Structural Usage: Other
Geometric Position - End Extension: 0 mm; Join Status: Both joins enabled; Start Extension: 0 mm; y Justification: Origin; yz Justification: Uniform; y Offset Value: 0 mm; z Offset Value: 0 mm; z Justification: Bottom
Name (NLRS_28_SF_LIB_balk SFB_gen_ASN Links:balk HEB220 320x15:...) | Span (mm) = BaseQuantities, Length (mm) = Dimensions, Length (mm) = NLRS_C_lengte (mm) | OuterSurfaceArea (m2) | GrossSurfaceArea (m2) | GrossVolume (m3) | NetVolume (m3) = Volume (m3) | NetSurfaceArea (m2) | Work Plane | Cut Length (mm)
6156946 | 8700 | 5.61949 | 5.62909 | 0.040259 | 0.119172 | 16.4802 | Level : V1 ok. ruwe vloer | 8627.3 | Structural - Start Attachment Type: End Elevation; Geometric Position - Start Join Cutback: 12.7 mm
6158140 | 5800 | 3.7252 | 3.7348 | 0.026688 | 0.0797399 | 11.0358 | Floor : 23_kanaalplaatvloer_260 | 5800

# IfcBeam: NLRS_28_SF_LIB_balk SFB_gen_ASN Links:balk HEB220 500x15, NLRS_28_SF_LIB_balk SFB_gen_ASN Links:balk HEB220 500x15:6147385
In: 00 Begane grond
Type - PredefinedType: T_BEAM; Material: <Unnamed>, ISR_Staal
Type - Other - Category: Structural Framing; Family Name: NLRS_28_SF_LIB_balk SFB_gen_ASN Links
Type - Dimensions - bf: 220 mm; bu: 400 mm; h: 220 mm; k: 42.5 mm; kr: 27 mm; NLRS_C_breedte: 220 mm; NLRS_C_hoogte: 220 mm; tf: 15.5 mm; tu: 15 mm; tw: 9 mm; y: 121 mm
Type - General - NLRS_C_content_creator: Arkance Systems; NLRS_C_content_datum_gewijzigd: 2022.05.27; NLRS_C_content_provider: Arkance Systems; NLRS_C_content_versie: 2.1; NLRS_C_revit_versie: 2021
Type - Identity Data - Workset: Family : Structural Framing : NLRS_28_SF_LIB_balk SFB_gen_ASN Links; Assembly Code: 28.10; Assembly Description: hoofddraagconstructies; kolommen en liggers, algemeen (verzamelniveau); Description: SFB-HEA320 500x15; Manufacturer: generiek; Model: SFB ligger; Type Name: balk HEB220 500x15
Type - Structural - A: 0.012437 m2; Section Shape: 16; SG: 7800
Type - Structural Section Geometry - Bottom Flange Thickness: 15 mm; Bottom Flange Width: 400 mm; Centroid Horizontal: 200 mm; Centroid Vertical: 121 mm; Height: 220 mm; Top Flange Thickness: 15.5 mm; Top Flange Width: 220 mm; Web Height: 189 mm; Web Thickness: 9 mm; Width: 220 mm
Type - Pset_BeamCommon - LoadBearing: yes; IsExternal: no
Type - Pset_ManufacturerTypeInformation - Manufacturer: generiek
Type - Pset_ProductRequirements - Category: Structural Framing
Type - Pset_ReinforcementBarPitchOfBeam - Description: SFB-HEA320 500x15
Classification: 28.10 Uniformat (Uniformat); Material: ISR_Staal
Pset_BeamCommon - Slope: 0 deg; IsExternal: yes; Reference: balk HEB220 500x15; Span: 10945 mm
Pset_PrecastConcreteElementGeneral - ElementWeight: 0 kg
Pset_QuantityTakeOff - Reference: balk HEB220 500x15; sets with these values: 2
Pset_DAT_KMS - Assembly Code: 28.10; Assembly Description: hoofddraagconstructies; kolommen en liggers, algemeen (verzamelniveau); Description: SFB-HEA320 500x15
BaseQuantities - Length: 10945 mm; CrossSectionArea: 0.006 m2; OuterSurfaceArea: 8.88515 m2; GrossSurfaceArea: 8.89715 m2; GrossVolume: 0.06423 m3; NetVolume: 0.164342 m3; NetSurfaceArea: 22.6585 m2
Other - Family: NLRS_28_SF_LIB_balk SFB_gen_ASN Links; Family and Type: NLRS_28_SF_LIB_balk SFB_gen_ASN Links: balk HEB220 500x15; Type: balk HEB220 500x15; Type Id: 5976243
Constraints - Cross-Section Rotation: 0 deg; Orientation: Normal; End Level Offset: 3470 mm; Reference Level: 0; Reference Level Elevation: 0 mm; Start Level Offset: 3470 mm; wandoplegging_eind: 120 mm; wandoplegging_start: 120 mm; Work Plane: <not associated>
Dimensions - Elevation at Bottom: 3225 mm; Elevation at Top: 3460 mm; Length: 10945 mm; NLRS_C_lengte: 10945 mm; Volume: 0.164342 m3
Identity Data - Has Association: no; Workset: Constructie
Phasing - Phase Created: 2. nieuwbouw
Structural - Stick Symbol Location: Center of Geometry; Structural Usage: Other; Cut Length: 10945 mm
Geometric Position - End Extension: 0 mm; Join Status: Both joins enabled; Start Extension: 0 mm; y Justification: Origin; yz Justification: Uniform; z Justification: Top; y Offset Value: 10 mm; z Offset Value: -10 mm

# IfcBeam: NLRS_28_SF_LIB_balk SFB_gen_ASN Links:balk HEB260 450x20, NLRS_28_SF_LIB_balk SFB_gen_ASN Links:balk HEB260 450x20:6155766
In: 01 eerste verdieping
Type - PredefinedType: T_BEAM; Material: h2_staal S235
Type - Other - Category: Structural Framing; Family Name: NLRS_28_SF_LIB_balk SFB_gen_ASN Links
Type - Dimensions - bf: 260 mm; bu: 460 mm; h: 260 mm; k: 41.5 mm; kr: 24 mm; NLRS_C_breedte: 260 mm; NLRS_C_hoogte: 260 mm; tf: 17.5 mm; tu: 20 mm; tw: 10 mm; y: 94 mm
Type - General - NLRS_C_content_creator: Arkance Systems; NLRS_C_content_datum_gewijzigd: 2022.05.27; NLRS_C_content_provider: Arkance Systems; NLRS_C_content_versie: 2.1; NLRS_C_revit_versie: 2021
Type - Identity Data - Workset: Family : Structural Framing : NLRS_28_SF_LIB_balk SFB_gen_ASN Links; Assembly Code: 28.10; Assembly Description: hoofddraagconstructies; kolommen en liggers, algemeen (verzamelniveau); Description: SFB-HEB260 450x15; Manufacturer: generiek; Model: SFB ligger; Type Name: balk HEB260 450x20
Type - Structural - A: 0.011844 m2; Section Shape: 16; SG: 7800
Type - Structural Section Geometry - Bottom Flange Thickness: 20 mm; Bottom Flange Width: 460 mm; Centroid Horizontal: 230 mm; Centroid Vertical: 94 mm; Height: 260 mm; Top Flange Thickness: 17.5 mm; Top Flange Width: 260 mm; Web Height: 225 mm; Web Thickness: 10 mm; Width: 260 mm
Type - Pset_BeamCommon - LoadBearing: yes; IsExternal: no
Type - Pset_ManufacturerTypeInformation - Manufacturer: generiek
Type - Pset_ProductRequirements - Category: Structural Framing
Type - Pset_ReinforcementBarPitchOfBeam - Description: SFB-HEB260 450x15
Classification: 28.10 Uniformat (Uniformat)
Pset_BeamCommon - Slope: 0 deg; IsExternal: yes; Reference: balk HEB260 450x20; Span: 3400 mm
Pset_PrecastConcreteElementGeneral - ElementWeight: 0 kg
Pset_QuantityTakeOff - Reference: balk HEB260 450x20; sets with these values: 2
Pset_DAT_KMS - Assembly Code: 28.10; Assembly Description: hoofddraagconstructies; kolommen en liggers, algemeen (verzamelniveau); Description: SFB-HEB260 450x15
BaseQuantities - Length: 3400 mm; CrossSectionArea: 0.0092 m2; OuterSurfaceArea: 2.77802 m2; GrossSurfaceArea: 2.79642 m2; GrossVolume: 0.0266227 m3; NetVolume: 0.0643771 m3; NetSurfaceArea: 7.59752 m2
Other - Family: NLRS_28_SF_LIB_balk SFB_gen_ASN Links; Type: balk HEB260 450x20; Family and Type: NLRS_28_SF_LIB_balk SFB_gen_ASN Links: balk HEB260 450x20; Type Id: 5974322
Constraints - Cross-Section Rotation: 0 deg; Reference Level: V2 ok. ruwe vloer; End Level Offset: -20 mm; Reference Level Elevation: 6890 mm; Start Level Offset: -20 mm; wandoplegging_eind: 173.731 mm; wandoplegging_start: 120 mm
Dimensions - Elevation at Bottom: 6870 mm; Elevation at Top: 7150 mm; Length: 3400 mm; NLRS_C_lengte: 3400 mm; Volume: 0.0643771 m3
Identity Data - Has Association: no; Workset: Constructie
Materials and Finishes - Structural Material: h2_staal S235
Phasing - Phase Created: 2. nieuwbouw
Structural - Stick Symbol Location: Center of Geometry; Structural Usage: Other; Cut Length: 3187.5 mm
Geometric Position - Join Status: Both joins enabled; Start Extension: 0 mm; y Justification: Origin; yz Justification: Uniform; y Offset Value: 0 mm; z Offset Value: 0 mm; z Justification: Bottom; End Extension: -212.5 mm

# IfcBeam: NLRS_28_SF_LIB_balk SFB_gen_ASN:balk HEA260460x15 (2)
Type - PredefinedType: BEAM; Material: <Unnamed>, ISR_Staal
Type - Other - Category: Structural Framing; Family Name: NLRS_28_SF_LIB_balk SFB_gen_ASN
Type - Dimensions - bf: 260 mm; bu: 460 mm; h: 250 mm; k: 42.5 mm; kr: 30 mm; NLRS_C_breedte: 260 mm; NLRS_C_hoogte: 250 mm; tf: 12.5 mm; tu: 15 mm; tw: 9 mm; y: 121 mm
Type - General - NLRS_C_content_creator: Arkance Systems; NLRS_C_content_datum_gewijzigd: 2022.05.27; NLRS_C_content_provider: Arkance Systems; NLRS_C_content_versie: 2.1; NLRS_C_revit_versie: 2021
Type - Identity Data - Workset: Family : Structural Framing : NLRS_28_SF_LIB_balk SFB_gen_ASN; Assembly Code: 28.10; Assembly Description: hoofddraagconstructies; kolommen en liggers, algemeen (verzamelniveau); Description: HEA260 460x15; Manufacturer: generiek; Model: SFB ligger; Type Name: balk HEA260460x15
Type - Structural - A: 0.012437 m2; Section Shape: 16; SG: 7800
Type - Structural Section Geometry - Bottom Flange Thickness: 15 mm; Bottom Flange Width: 460 mm; Centroid Horizontal: 230 mm; Centroid Vertical: 121 mm; Height: 250 mm; Top Flange Thickness: 12.5 mm; Top Flange Width: 260 mm; Web Height: 225 mm; Web Thickness: 9 mm; Width: 260 mm
Type - Pset_BeamCommon - LoadBearing: yes; IsExternal: no
Type - Pset_ManufacturerTypeInformation - Manufacturer: generiek
Type - Pset_ProductRequirements - Category: Structural Framing
Type - Pset_ReinforcementBarPitchOfBeam - Description: HEA260 460x15
Classification: 28.10 Uniformat (Uniformat); Material: ISR_Staal
Pset_BeamCommon - Slope: 0 deg; IsExternal: yes; Reference: balk HEA260460x15
Pset_PrecastConcreteElementGeneral - ElementWeight: 0 kg
Pset_QuantityTakeOff - Reference: balk HEA260460x15; sets with these values: 2
Pset_DAT_KMS - Assembly Code: 28.10; Assembly Description: hoofddraagconstructies; kolommen en liggers, algemeen (verzamelniveau); Description: HEA260 460x15
BaseQuantities - CrossSectionArea: 0.00929805 m2
Other - Family: NLRS_28_SF_LIB_balk SFB_gen_ASN; Family and Type: NLRS_28_SF_LIB_balk SFB_gen_ASN: balk HEA260460x15; Type: balk HEA260460x15; Type Id: 5940187
Constraints - Cross-Section Rotation: 0 deg
Identity Data - Has Association: no; Workset: Constructie
Phasing - Phase Created: 2. nieuwbouw
Structural - Stick Symbol Location: Center of Geometry; Structural Usage: Other
Geometric Position - Join Status: Both joins enabled; Start Extension: 0 mm; y Justification: Origin; yz Justification: Uniform; z Justification: Top; y Offset Value: -10 mm; z Offset Value: -10 mm
Name (NLRS_28_SF_LIB_balk SFB_gen_ASN:balk HEA260460x15:...) | In | Span (mm) = BaseQuantities, Length (mm) = Dimensions, Length (mm) = NLRS_C_lengte (mm) | OuterSurfaceArea (m2) | GrossSurfaceArea (m2) | GrossVolume (m3) | NetVolume (m3) = Volume (m3) | NetSurfaceArea (m2) | End Level Offset (mm) = Start Level Offset (mm) | Reference Level | Reference Level Elevation (mm) | wandoplegging_eind (mm) | wandoplegging_start (mm) | Elevation at Bottom (mm) | Elevation at Top (mm) | Cut Length (mm) | End Extension (mm)
4715135 | 01 eerste verdieping | 7000.01 | 9.96602 | 9.98462 | 0.0630159 | 0.107777 | 16.1616 | 0 | V1 bk. ruwe vloer | 3560 | 175 | 114.796 | 3285 | 3550 | 6777.32 | 0 | Geometric Position - Start Join Cutback: 12.7 mm
6526382 | 00 Begane grond | 4800 | 5.22234 | 5.24094 | 0.0330212 | 0.0558687 | 8.40058 | 3500 | 0 | 0 | 120 | 120 | 3225 | 3490 | 3551.42 | -1248.58 | Constraints - Orientation: Normal; Work Plane: <not associated>

# IfcBeam: NLRS_28_SF_LIB_balk SFB_gen_ASN:balk HEA260460x15 (2)
In: 00 Begane grond
Type - PredefinedType: BEAM; Material: h2_staal S235
Type - Other - Category: Structural Framing; Family Name: NLRS_28_SF_LIB_balk SFB_gen_ASN
Type - Dimensions - bf: 260 mm; bu: 460 mm; h: 250 mm; k: 42.5 mm; kr: 30 mm; NLRS_C_breedte: 260 mm; NLRS_C_hoogte: 250 mm; tf: 12.5 mm; tu: 15 mm; tw: 9 mm; y: 121 mm
Type - General - NLRS_C_content_creator: Arkance Systems; NLRS_C_content_datum_gewijzigd: 2022.05.27; NLRS_C_content_provider: Arkance Systems; NLRS_C_content_versie: 2.1; NLRS_C_revit_versie: 2021
Type - Identity Data - Workset: Family : Structural Framing : NLRS_28_SF_LIB_balk SFB_gen_ASN; Assembly Code: 28.10; Assembly Description: hoofddraagconstructies; kolommen en liggers, algemeen (verzamelniveau); Description: HEA260 460x15; Manufacturer: generiek; Model: SFB ligger; Type Name: balk HEA260460x15
Type - Structural - A: 0.012437 m2; Section Shape: 16; SG: 7800
Type - Structural Section Geometry - Bottom Flange Thickness: 15 mm; Bottom Flange Width: 460 mm; Centroid Horizontal: 230 mm; Centroid Vertical: 121 mm; Height: 250 mm; Top Flange Thickness: 12.5 mm; Top Flange Width: 260 mm; Web Height: 225 mm; Web Thickness: 9 mm; Width: 260 mm
Type - Pset_BeamCommon - LoadBearing: yes; IsExternal: no
Type - Pset_ManufacturerTypeInformation - Manufacturer: generiek
Type - Pset_ProductRequirements - Category: Structural Framing
Type - Pset_ReinforcementBarPitchOfBeam - Description: HEA260 460x15
Classification: 28.10 Uniformat (Uniformat)
Pset_BeamCommon - Slope: 0 deg; IsExternal: yes; Reference: balk HEA260460x15
Pset_PrecastConcreteElementGeneral - ElementWeight: 0 kg
Pset_QuantityTakeOff - Reference: balk HEA260460x15; sets with these values: 2
Pset_DAT_KMS - Assembly Code: 28.10; Assembly Description: hoofddraagconstructies; kolommen en liggers, algemeen (verzamelniveau); Description: HEA260 460x15
BaseQuantities - CrossSectionArea: 0.00929805 m2
Other - Family: NLRS_28_SF_LIB_balk SFB_gen_ASN; Family and Type: NLRS_28_SF_LIB_balk SFB_gen_ASN: balk HEA260460x15; Type: balk HEA260460x15; Type Id: 5940187
Constraints - Cross-Section Rotation: 0 deg; wandoplegging_eind: 120 mm
Dimensions - Elevation at Bottom: 3225 mm; Elevation at Top: 3490 mm
Identity Data - Has Association: no; Workset: Constructie
Materials and Finishes - Structural Material: h2_staal S235
Phasing - Phase Created: 2. nieuwbouw
Structural - Stick Symbol Location: Center of Geometry; Structural Usage: Other
Geometric Position - End Extension: 0 mm; Join Status: Both joins enabled; y Justification: Origin; yz Justification: Uniform; y Offset Value: 0 mm; z Offset Value: 0 mm; z Justification: Bottom; End Join Cutback: 12.7 mm
Name (NLRS_28_SF_LIB_balk SFB_gen_ASN:balk HEA260460x15:...) | Span (mm) = BaseQuantities, Length (mm) = Dimensions, Length (mm) = NLRS_C_lengte (mm) | OuterSurfaceArea (m2) | GrossSurfaceArea (m2) | GrossVolume (m3) | NetVolume (m3) = Volume (m3) | NetSurfaceArea (m2) | Reference Level | End Level Offset (mm) = Start Level Offset (mm) | Reference Level Elevation (mm) | wandoplegging_start (mm) | Cut Length (mm) | Start Extension (mm)
6151664 | 2270 | 3.33405 | 3.35265 | 0.0210815 | 0.035069 | 5.29239 | V1 ok. ruwe vloer | -15 | 3240 | 120 | 2267.3 | 10
6220123 | 6870 | 10.4733 | 10.4919 | 0.0662235 | 0.11277 | 16.9147 | 0 | 3225 | 0 | 256.002 | 7122.3 | 340 | Constraints - Orientation: Normal; Work Plane: <not associated>; Structural - End Attachment Type: End Elevation

# IfcBeam: NLRS_28_SF_LIB_balk SFB_gen_ASN:balk HEA320 500x15 (3)
In: 01 eerste verdieping
Type - PredefinedType: T_BEAM; Material: <Unnamed>, ISR_Staal
Type - Other - Category: Structural Framing; Family Name: NLRS_28_SF_LIB_balk SFB_gen_ASN
Type - Dimensions - bf: 300 mm; bu: 500 mm; h: 310 mm; k: 42.5 mm; kr: 27 mm; NLRS_C_breedte: 300 mm; NLRS_C_hoogte: 310 mm; tf: 15.5 mm; tu: 15 mm; tw: 9 mm; y: 121 mm
Type - General - NLRS_C_content_creator: Arkance Systems; NLRS_C_content_datum_gewijzigd: 2022.05.27; NLRS_C_content_provider: Arkance Systems; NLRS_C_content_versie: 2.1; NLRS_C_revit_versie: 2021
Type - Identity Data - Assembly Code: 28.10; Assembly Description: hoofddraagconstructies; kolommen en liggers, algemeen (verzamelniveau); Description: SFB-HEA320 500x15; Manufacturer: generiek; Model: SFB ligger; Type Name: balk HEA320 500x15; Workset: Family : Structural Framing : NLRS_28_SF_LIB_balk SFB_gen_ASN
Type - Structural - A: 0.012437 m2; Section Shape: 16; SG: 7800
Type - Structural Section Geometry - Bottom Flange Thickness: 15 mm; Bottom Flange Width: 500 mm; Centroid Horizontal: 250 mm; Centroid Vertical: 121 mm; Height: 310 mm; Top Flange Thickness: 15.5 mm; Top Flange Width: 300 mm; Web Height: 279 mm; Web Thickness: 9 mm; Width: 300 mm
Type - Pset_BeamCommon - LoadBearing: yes; IsExternal: no
Type - Pset_ManufacturerTypeInformation - Manufacturer: generiek
Type - Pset_ProductRequirements - Category: Structural Framing
Type - Pset_ReinforcementBarPitchOfBeam - Description: SFB-HEA320 500x15
Classification: 28.10 Uniformat (Uniformat); Material: ISR_Staal
Pset_BeamCommon - Reference: balk HEA320 500x15; Slope: 0 deg; IsExternal: yes
Pset_PrecastConcreteElementGeneral - ElementWeight: 0 kg
Pset_QuantityTakeOff - Reference: balk HEA320 500x15; sets with these values: 2
Pset_DAT_KMS - Assembly Code: 28.10; Assembly Description: hoofddraagconstructies; kolommen en liggers, algemeen (verzamelniveau); Description: SFB-HEA320 500x15
BaseQuantities - CrossSectionArea: 0.0124372 m2
Other - Family: NLRS_28_SF_LIB_balk SFB_gen_ASN; Family and Type: NLRS_28_SF_LIB_balk SFB_gen_ASN: balk HEA320 500x15; Type: balk HEA320 500x15; Type Id: 4711934
Constraints - Cross-Section Rotation: 0 deg; End Level Offset: 0 mm; Reference Level: V1 bk. ruwe vloer; Reference Level Elevation: 3560 mm; Start Level Offset: 0 mm; wandoplegging_eind: 175 mm
Dimensions - Elevation at Bottom: 3225 mm; Elevation at Top: 3550 mm
Identity Data - Has Association: no; Workset: Constructie
Phasing - Phase Created: 2. nieuwbouw
Structural - Stick Symbol Location: Center of Geometry; Structural Usage: Other
Geometric Position - End Extension: 0 mm; Join Status: Both joins enabled; Start Extension: 0 mm; y Justification: Origin; y Offset Value: -10 mm; yz Justification: Uniform; z Justification: Top; z Offset Value: -10 mm
Name (NLRS_28_SF_LIB_balk SFB_gen_ASN:balk HEA320 500x15:...) | Span (mm) = BaseQuantities, Length (mm) = Dimensions, Length (mm) = NLRS_C_lengte (mm) | OuterSurfaceArea (m2) | GrossSurfaceArea (m2) | GrossVolume (m3) | NetVolume (m3) = Volume (m3) | NetSurfaceArea (m2) | Orientation | wandoplegging_start (mm) | Work Plane | Cut Length (mm)
4714632 | 9010 | 15.8184 | 15.8432 | 0.112059 | 0.177006 | 24.778 | Normal | 175 | Level : V1 bk. ruwe vloer | 9010
4714757 | 28200 | 49.5092 | 49.5341 | 0.350729 | 0.560082 | 78.3015 |  | 110 |  | 28200
4715373 | 38410 | 66.9556 | 66.9805 | 0.474322 | 0.757713 | 105.916 | Normal | 175 | Level : V1 bk. ruwe vloer | 38137.3 | Geometric Position - End Join Cutback: 12.7 mm

# IfcBeam: NLRS_28_SF_LIB_balk SFB_gen_ASN:balk HEA320 500x20, NLRS_28_SF_LIB_balk SFB_gen_ASN:balk HEA320 500x20:4715047
In: 01 eerste verdieping
Type - PredefinedType: BEAM; Material: <Unnamed>, ISR_Staal
Type - Other - Category: Structural Framing; Family Name: NLRS_28_SF_LIB_balk SFB_gen_ASN
Type - Dimensions - bf: 300 mm; bu: 500 mm; h: 310 mm; k: 42.5 mm; kr: 27 mm; NLRS_C_breedte: 300 mm; NLRS_C_hoogte: 310 mm; tf: 15.5 mm; tu: 20 mm; tw: 9 mm; y: 121 mm
Type - General - NLRS_C_content_creator: Arkance Systems; NLRS_C_content_datum_gewijzigd: 2022.05.27; NLRS_C_content_provider: Arkance Systems; NLRS_C_content_versie: 2.1; NLRS_C_revit_versie: 2021
Type - Identity Data - Workset: Family : Structural Framing : NLRS_28_SF_LIB_balk SFB_gen_ASN; Assembly Code: 28.10; Assembly Description: hoofddraagconstructies; kolommen en liggers, algemeen (verzamelniveau); Description: SFB-HEA320 500x15; Manufacturer: generiek; Model: SFB ligger; Type Name: balk HEA320 500x20
Type - Structural - A: 0.012437 m2; Section Shape: 16; SG: 7800
Type - Structural Section Geometry - Bottom Flange Thickness: 20 mm; Bottom Flange Width: 500 mm; Centroid Horizontal: 250 mm; Centroid Vertical: 121 mm; Height: 310 mm; Top Flange Thickness: 15.5 mm; Top Flange Width: 300 mm; Web Height: 279 mm; Web Thickness: 9 mm; Width: 300 mm
Type - Pset_BeamCommon - LoadBearing: yes; IsExternal: no
Type - Pset_ManufacturerTypeInformation - Manufacturer: generiek
Type - Pset_ProductRequirements - Category: Structural Framing
Type - Pset_ReinforcementBarPitchOfBeam - Description: SFB-HEA320 500x15
Classification: 28.10 Uniformat (Uniformat); Material: ISR_Staal
Pset_BeamCommon - Slope: 0 deg; IsExternal: yes; Reference: balk HEA320 500x20; Span: 26090 mm
Pset_PrecastConcreteElementGeneral - ElementWeight: 0 kg
Pset_QuantityTakeOff - Reference: balk HEA320 500x20; sets with these values: 2
Pset_DAT_KMS - Assembly Code: 28.10; Assembly Description: hoofddraagconstructies; kolommen en liggers, algemeen (verzamelniveau); Description: SFB-HEA320 500x15
BaseQuantities - Length: 26090 mm; CrossSectionArea: 0.0124372 m2; OuterSurfaceArea: 45.326 m2; GrossSurfaceArea: 45.3509 m2; GrossVolume: 0.321095 m3; NetVolume: 0.575759 m3; NetSurfaceArea: 71.8569 m2
Other - Family: NLRS_28_SF_LIB_balk SFB_gen_ASN; Family and Type: NLRS_28_SF_LIB_balk SFB_gen_ASN: balk HEA320 500x20; Type: balk HEA320 500x20; Type Id: 5973235
Constraints - Cross-Section Rotation: 0 deg; End Level Offset: 0 mm; Orientation: Normal; Reference Level: V1 bk. ruwe vloer; Start Level Offset: 0 mm; Reference Level Elevation: 3560 mm; wandoplegging_eind: 175 mm; wandoplegging_start: 175 mm; Work Plane: Level : V1 bk. ruwe vloer
Dimensions - Elevation at Bottom: 3220 mm; Elevation at Top: 3550 mm; Length: 26090 mm; NLRS_C_lengte: 26090 mm; Volume: 0.575759 m3
Identity Data - Has Association: no; Workset: Constructie
Phasing - Phase Created: 2. nieuwbouw
Structural - Stick Symbol Location: Center of Geometry; Structural Usage: Other; Cut Length: 25817.3 mm
Geometric Position - End Extension: 0 mm; Join Status: Both joins enabled; Start Extension: 0 mm; y Justification: Origin; yz Justification: Uniform; z Justification: Top; Start Join Cutback: 12.7 mm; y Offset Value: -10 mm; z Offset Value: -10 mm

# IfcBeam: NLRS_28_SF_LIB_balk SFB_gen_ASN:balk HEB260 450x20, NLRS_28_SF_LIB_balk SFB_gen_ASN:balk HEB260 450x20:6151386
In: 00 Begane grond
Type - PredefinedType: T_BEAM; Material: h2_staal S235
Type - Other - Category: Structural Framing; Family Name: NLRS_28_SF_LIB_balk SFB_gen_ASN
Type - Dimensions - bf: 260 mm; bu: 460 mm; h: 260 mm; k: 41.5 mm; kr: 24 mm; NLRS_C_breedte: 260 mm; NLRS_C_hoogte: 260 mm; tf: 17.5 mm; tu: 20 mm; tw: 10 mm; y: 94 mm
Type - General - NLRS_C_content_creator: Arkance Systems; NLRS_C_content_datum_gewijzigd: 2022.05.27; NLRS_C_content_provider: Arkance Systems; NLRS_C_content_versie: 2.1; NLRS_C_revit_versie: 2021
Type - Identity Data - Workset: Family : Structural Framing : NLRS_28_SF_LIB_balk SFB_gen_ASN; Assembly Code: 28.10; Assembly Description: hoofddraagconstructies; kolommen en liggers, algemeen (verzamelniveau); Description: SFB-HEB260 450x15; Manufacturer: generiek; Model: SFB ligger; Type Name: balk HEB260 450x20
Type - Structural - A: 0.011844 m2; Section Shape: 16; SG: 7800
Type - Structural Section Geometry - Bottom Flange Thickness: 20 mm; Bottom Flange Width: 460 mm; Centroid Horizontal: 230 mm; Centroid Vertical: 94 mm; Height: 260 mm; Top Flange Thickness: 17.5 mm; Top Flange Width: 260 mm; Web Height: 225 mm; Web Thickness: 10 mm; Width: 260 mm
Type - Pset_BeamCommon - LoadBearing: yes; IsExternal: no
Type - Pset_ManufacturerTypeInformation - Manufacturer: generiek
Type - Pset_ProductRequirements - Category: Structural Framing
Type - Pset_ReinforcementBarPitchOfBeam - Description: SFB-HEB260 450x15
Classification: 28.10 Uniformat (Uniformat)
Pset_BeamCommon - Slope: 0 deg; IsExternal: yes; Reference: balk HEB260 450x20; Span: 4800 mm
Pset_PrecastConcreteElementGeneral - ElementWeight: 0 kg
Pset_QuantityTakeOff - Reference: balk HEB260 450x20; sets with these values: 2
Pset_DAT_KMS - Assembly Code: 28.10; Assembly Description: hoofddraagconstructies; kolommen en liggers, algemeen (verzamelniveau); Description: SFB-HEB260 450x15
BaseQuantities - Length: 4800 mm; CrossSectionArea: 0.0118448 m2; OuterSurfaceArea: 6.83916 m2; GrossSurfaceArea: 6.86285 m2; GrossVolume: 0.0540489 m3; NetVolume: 0.0938202 m3; NetSurfaceArea: 11.0314 m2
Other - Family: NLRS_28_SF_LIB_balk SFB_gen_ASN; Family and Type: NLRS_28_SF_LIB_balk SFB_gen_ASN: balk HEB260 450x20; Type: balk HEB260 450x20; Type Id: 4713009
Constraints - Cross-Section Rotation: 0 deg; Reference Level: V1 ok. ruwe vloer; End Level Offset: -20 mm; Reference Level Elevation: 3240 mm; Start Level Offset: -20 mm; wandoplegging_eind: 120 mm; wandoplegging_start: 120 mm
Dimensions - Elevation at Bottom: 3220 mm; Elevation at Top: 3500 mm; Length: 4800 mm; NLRS_C_lengte: 4800 mm; Volume: 0.0938202 m3
Identity Data - Has Association: no; Workset: Constructie
Materials and Finishes - Structural Material: h2_staal S235
Phasing - Phase Created: 2. nieuwbouw
Structural - Stick Symbol Location: Center of Geometry; Structural Usage: Other; Start Attachment Type: End Elevation; Cut Length: 4563.1 mm; End Attachment Type: End Elevation
Geometric Position - End Extension: 0 mm; Join Status: Both joins enabled; Start Extension: 0 mm; y Justification: Origin; yz Justification: Uniform; y Offset Value: 0 mm; z Offset Value: 0 mm; z Justification: Bottom; End Join Cutback: 12.7 mm; Start Join Cutback: 12.7 mm

# IfcBeam: NLRS_28_SF_LIB_balk SFB_gen_ASN:balk HEB260 460x15, NLRS_28_SF_LIB_balk SFB_gen_ASN:balk HEB260 460x15:6159238
In: 00 Begane grond
Type - PredefinedType: BEAM; Material: <Unnamed>, ISR_Staal
Type - Other - Category: Structural Framing; Family Name: NLRS_28_SF_LIB_balk SFB_gen_ASN
Type - Dimensions - bf: 260 mm; bu: 460 mm; h: 260 mm; k: 41.5 mm; kr: 24 mm; NLRS_C_breedte: 260 mm; NLRS_C_hoogte: 260 mm; tf: 17.5 mm; tu: 15 mm; tw: 10 mm; y: 94 mm
Type - General - NLRS_C_content_creator: Arkance Systems; NLRS_C_content_datum_gewijzigd: 2022.05.27; NLRS_C_content_provider: Arkance Systems; NLRS_C_content_versie: 2.1; NLRS_C_revit_versie: 2021
Type - Identity Data - Workset: Family : Structural Framing : NLRS_28_SF_LIB_balk SFB_gen_ASN; Assembly Code: 28.10; Assembly Description: hoofddraagconstructies; kolommen en liggers, algemeen (verzamelniveau); Description: SFB-HEB260 450x15; Manufacturer: generiek; Model: SFB ligger; Type Name: balk HEB260 460x15
Type - Structural - A: 0.011844 m2; Section Shape: 16; SG: 7800
Type - Structural Section Geometry - Bottom Flange Thickness: 15 mm; Bottom Flange Width: 460 mm; Centroid Horizontal: 230 mm; Centroid Vertical: 94 mm; Height: 260 mm; Top Flange Thickness: 17.5 mm; Top Flange Width: 260 mm; Web Height: 225 mm; Web Thickness: 10 mm; Width: 260 mm
Type - Pset_BeamCommon - LoadBearing: yes; IsExternal: no
Type - Pset_ManufacturerTypeInformation - Manufacturer: generiek
Type - Pset_ProductRequirements - Category: Structural Framing
Type - Pset_ReinforcementBarPitchOfBeam - Description: SFB-HEB260 450x15
Classification: 28.10 Uniformat (Uniformat); Material: ISR_Staal
Pset_BeamCommon - Slope: 0 deg; IsExternal: yes; Reference: balk HEB260 460x15; Span: 7200 mm
Pset_PrecastConcreteElementGeneral - ElementWeight: 0 kg
Pset_QuantityTakeOff - Reference: balk HEB260 460x15; sets with these values: 2
Pset_DAT_KMS - Assembly Code: 28.10; Assembly Description: hoofddraagconstructies; kolommen en liggers, algemeen (verzamelniveau); Description: SFB-HEB260 450x15
BaseQuantities - Length: 7200 mm; CrossSectionArea: 0.0118448 m2; OuterSurfaceArea: 10.7913 m2; GrossSurfaceArea: 10.815 m2; GrossVolume: 0.0852824 m3; NetVolume: 0.133305 m3; NetSurfaceArea: 17.4408 m2
Other - Family: NLRS_28_SF_LIB_balk SFB_gen_ASN; Family and Type: NLRS_28_SF_LIB_balk SFB_gen_ASN: balk HEB260 460x15; Type: balk HEB260 460x15; Type Id: 6150993
Constraints - Cross-Section Rotation: 0 deg; Orientation: Normal; Reference Level: 0; Reference Level Elevation: 0 mm; End Level Offset: 3510 mm; Start Level Offset: 3510 mm; wandoplegging_eind: 120 mm; wandoplegging_start: 120 mm; Work Plane: <not associated>
Dimensions - Elevation at Bottom: 3225 mm; Elevation at Top: 3500 mm; Length: 7200 mm; NLRS_C_lengte: 7200 mm; Volume: 0.133305 m3
Identity Data - Has Association: no; Workset: Constructie
Phasing - Phase Created: 2. nieuwbouw
Structural - Stick Symbol Location: Center of Geometry; Structural Usage: Other; Cut Length: 7200 mm
Geometric Position - End Extension: 0 mm; Join Status: Both joins enabled; Start Extension: 0 mm; y Justification: Origin; yz Justification: Uniform; z Justification: Top; y Offset Value: -10 mm; z Offset Value: -10 mm

# IfcBeam: NLRS_28_SF_LIB_balk SFB_gen_ASN:balk HEB260 460x20 (2)
In: 02 tweede verdieping
Type - PredefinedType: BEAM; Material: <Unnamed>, ISR_Staal
Type - Other - Category: Structural Framing; Family Name: NLRS_28_SF_LIB_balk SFB_gen_ASN
Type - Dimensions - bf: 260 mm; bu: 460 mm; h: 260 mm; k: 41.5 mm; kr: 24 mm; NLRS_C_breedte: 260 mm; NLRS_C_hoogte: 260 mm; tf: 17.5 mm; tu: 20 mm; tw: 10 mm; y: 94 mm
Type - General - NLRS_C_content_creator: Arkance Systems; NLRS_C_content_datum_gewijzigd: 2022.05.27; NLRS_C_content_provider: Arkance Systems; NLRS_C_content_versie: 2.1; NLRS_C_revit_versie: 2021
Type - Identity Data - Workset: Family : Structural Framing : NLRS_28_SF_LIB_balk SFB_gen_ASN; Assembly Code: 28.10; Assembly Description: hoofddraagconstructies; kolommen en liggers, algemeen (verzamelniveau); Description: SFB-HEB260 450x15; Manufacturer: generiek; Model: SFB ligger; Type Name: balk HEB260 460x20
Type - Structural - A: 0.011844 m2; Section Shape: 16; SG: 7800
Type - Structural Section Geometry - Bottom Flange Thickness: 20 mm; Bottom Flange Width: 460 mm; Centroid Horizontal: 230 mm; Centroid Vertical: 94 mm; Height: 260 mm; Top Flange Thickness: 17.5 mm; Top Flange Width: 260 mm; Web Height: 225 mm; Web Thickness: 10 mm; Width: 260 mm
Type - Pset_BeamCommon - LoadBearing: yes; IsExternal: no
Type - Pset_ManufacturerTypeInformation - Manufacturer: generiek
Type - Pset_ProductRequirements - Category: Structural Framing
Type - Pset_ReinforcementBarPitchOfBeam - Description: SFB-HEB260 450x15
Classification: 28.10 Uniformat (Uniformat); Material: ISR_Staal
Pset_BeamCommon - IsExternal: yes; Reference: balk HEB260 460x20
Pset_PrecastConcreteElementGeneral - ElementWeight: 0 kg
Pset_QuantityTakeOff - Reference: balk HEB260 460x20; sets with these values: 2
Pset_DAT_KMS - Assembly Code: 28.10; Assembly Description: hoofddraagconstructies; kolommen en liggers, algemeen (verzamelniveau); Description: SFB-HEB260 450x15
BaseQuantities - CrossSectionArea: 0.0118448 m2
Other - Family: NLRS_28_SF_LIB_balk SFB_gen_ASN; Family and Type: NLRS_28_SF_LIB_balk SFB_gen_ASN: balk HEB260 460x20; Type: balk HEB260 460x20; Type Id: 6155599
Constraints - Cross-Section Rotation: 0 deg; Start Level Offset: 0 mm; Reference Level: V2 bk. ruwe vloer; Reference Level Elevation: 7150 mm; wandoplegging_eind: 175 mm; wandoplegging_start: 175 mm
Identity Data - Has Association: no; Workset: Constructie
Phasing - Phase Created: 2. nieuwbouw
Structural - Stick Symbol Location: Center of Geometry; Structural Usage: Other
Geometric Position - End Extension: 0 mm; Join Status: Both joins enabled; Start Extension: 0 mm; y Justification: Origin; yz Justification: Uniform; z Justification: Top; y Offset Value: 0 mm; z Offset Value: 0 mm
Name (NLRS_28_SF_LIB_balk SFB_gen_ASN:balk HEB260 460x20:...) | Slope (deg) | Span (mm) = BaseQuantities, Length (mm) = Dimensions, Length (mm) = NLRS_C_lengte (mm) | OuterSurfaceArea (m2) | GrossSurfaceArea (m2) | GrossVolume (m3) | NetVolume (m3) = Volume (m3) | NetSurfaceArea (m2) | End Level Offset (mm) | Cut Length (mm)
4715706 | 0 | 43912.5 | 65.8159 | 65.8396 | 0.520134 | 0.920897 | 107.678 | 0 | 43912.5 | Constraints - Orientation: Normal; Work Plane: Level : V2 bk. ruwe vloer; Dimensions - Elevation at Bottom: 6870 mm; Elevation at Top: 7150 mm
4715799 | 0.102314 | 33600.1 | 50.0408 | 50.0645 | 0.395466 | 0.699401 | 81.7988 | -60 | 33387.4 | Geometric Position - End Join Cutback: 12.7 mm

# IfcBeam: NLRS_28_SF_LIB_balk hea -SH_gen_ISR:balk gen hea140 (7)
In: 02 tweede verdieping
Type - PredefinedType: BEAM
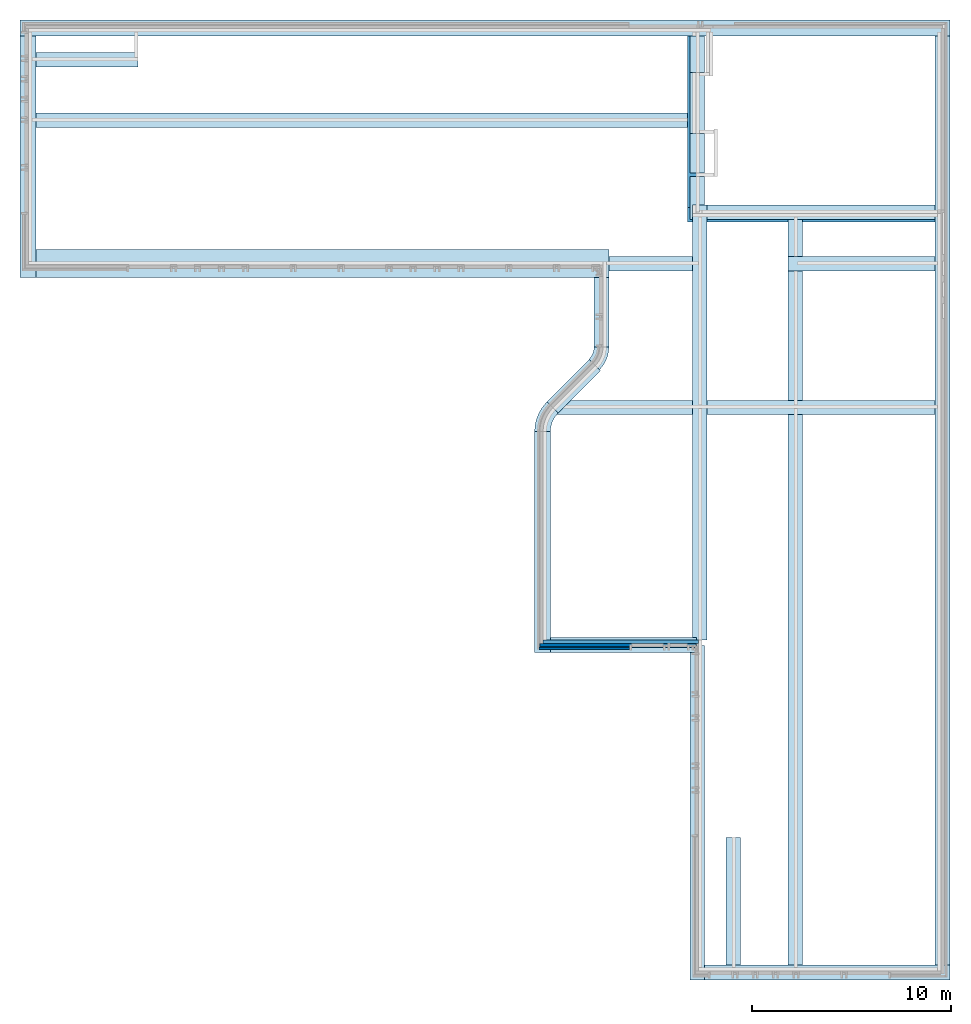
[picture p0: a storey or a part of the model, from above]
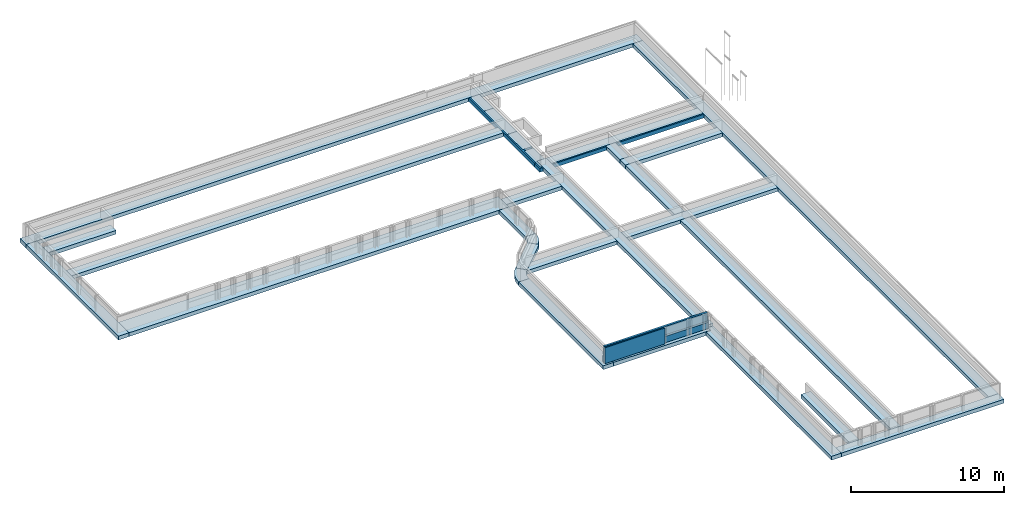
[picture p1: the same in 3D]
Properties of the parts of a building model (IFC2X3), part 4 of 37

# IfcBeam: NLRS_28_SF_LIB_balk hea -SH_gen_ISR:balk gen hea140 (7)
Type - Other - Category: Structural Framing; Family Name: NLRS_28_SF_LIB_balk hea -SH_gen_ISR
Type - Dimensions - NLRS_C_breedte: 140 mm; NLRS_C_hoogte: 133 mm; r: 12 mm; tf: 8.5 mm; tw: 5.5 mm
Type - Identity Data - Assembly Code: 28.10; Assembly Description: hoofddraagconstructies; kolommen en liggers, algemeen (verzamelniveau); Code Name: EURONORM 53-62; DIN 1025-3; Description: HEA140; Section Name Key: HEA140; SmartRevit_Versie: 2021.1; Type Name: balk gen hea140; Workset: Family : Structural Framing : NLRS_28_SF_LIB_balk hea -SH_gen_ISR
Type - Structural - Section Shape: 8
Type - Structural Analysis - Elastic Modulus strong axis: 0.000155 m3; Elastic Modulus weak axis: 0.0000556 m3; Moment of Inertia strong axis: 0.0000103 m4; Moment of Inertia weak axis: 0.00000389 m4; Nominal Weight: 24.6999; Perimeter: 794 mm; Plastic Modulus strong axis: 0.0001735 m3; Plastic Modulus weak axis: 0.00008485 m3; Section Area: 0.00314 m2; Torsional Moment of Inertia: 0 m4; Warping Constant: 0
Type - Structural Section Geometry - Centroid Horizontal: 70 mm; Centroid Vertical: 66.5 mm; Flange Thickness: 8.5 mm; Height: 133 mm; Web Fillet: 12 mm; Web Thickness: 5.5 mm; Width: 140 mm
Type - Pset_BeamCommon - LoadBearing: yes; IsExternal: no
Type - Pset_ProductRequirements - Category: Structural Framing
Type - Pset_ReinforcementBarPitchOfBeam - Description: HEA140
Classification: 28.10 Uniformat (Uniformat); Material: h2_staal S235
BaseQuantities - Length: 2940 mm; CrossSectionArea: 0.00314169 m2; OuterSurfaceArea: 2.33553 m2; GrossVolume: 0.00923658 m3; NetVolume: 0.00923639 m3
Pset_BeamCommon - Slope: 0 deg; IsExternal: yes; Reference: balk gen hea140
Pset_PrecastConcreteElementGeneral - ElementWeight: 0 kg
Pset_QuantityTakeOff - Reference: balk gen hea140; sets with these values: 2
Pset_DAT_KMS - Assembly Code: 28.10; Assembly Description: hoofddraagconstructies; kolommen en liggers, algemeen (verzamelniveau); Description: HEA140
Other - Family: NLRS_28_SF_LIB_balk hea -SH_gen_ISR; Family and Type: NLRS_28_SF_LIB_balk hea -SH_gen_ISR: balk gen hea140; Type: balk gen hea140; Type Id: 5971563
Constraints - Cross-Section Rotation: 0 deg; End Level Offset: -140 mm; Reference Level: 3; Reference Level Elevation: 9700 mm; Start Level Offset: -140 mm
Dimensions - Elevation at Bottom: 9560 mm; Elevation at Top: 9693 mm; Volume: 0.00923639 m3
Identity Data - Has Association: no; Workset: Constructie
Materials and Finishes - Structural Material: h2_staal S235
Phasing - Phase Created: 2. nieuwbouw
Structural - Stick Symbol Location: Center of Geometry; Structural Usage: Other; Cut Length: 2940 mm
Geometric Position - Join Status: Both joins enabled; y Justification: Origin; yz Justification: Uniform; y Offset Value: 0 mm; z Offset Value: 0 mm; z Justification: Bottom
Name (NLRS_28_SF_LIB_balk hea -SH_gen_ISR:balk gen hea140:...) | Span (mm) = Length (mm) = NLRS_C_lengte (mm) | Start Extension (mm) | End Extension (mm)
5971161 | 2640 | 0 | 435 | Structural - Start Attachment Type: End Elevation; Geometric Position - Start Join Cutback: 0 mm
5971162 | 1693 | 1132 | 115
5971163 | 3100 | 115 | -275
5971389 | 1693 | 1132 | 115
5971401 | 1693 | 1132 | 115
5971411 | 1693 | 1132 | 115
5971485 | 3100 | 115 | -275

# IfcBeam: NLRS_28_SF_LIB_balk sfb_gen_ISR Links:balk gen hea200 300x15, NLRS_28_SF_LIB_balk sfb_gen_ISR Links:balk gen hea200 300x15:6234599
In: 00 Begane grond
Type - PredefinedType: T_BEAM; Material: h2_staal S235
Type - Other - Category: Structural Framing; Family Name: NLRS_28_SF_LIB_balk sfb_gen_ISR Links
Type - Dimensions - bf: 200 mm; bu: 400 mm; h: 190 mm; k: 28 mm; kr: 18 mm; NLRS_C_breedte: 200 mm; NLRS_C_hoogte: 190 mm; tf: 10 mm; tu: 15 mm; tw: 6.5 mm; y: 73 mm
Type - Identity Data - Assembly Code: 28.10; Assembly Description: hoofddraagconstructies; kolommen en liggers, algemeen (verzamelniveau); Description: SFB-HEA200 400x10; Model: LOD300; SmartRevit_Versie: 2021.1; Type Name: balk gen hea200 300x15; Workset: Family : Structural Framing : NLRS_28_SF_LIB_balk sfb_gen_ISR Links
Type - Structural - A: 0.005383 m2; Section Shape: 16; SG: 7800
Type - Structural Section Geometry - Bottom Flange Thickness: 15 mm; Bottom Flange Width: 400 mm; Centroid Horizontal: 200 mm; Centroid Vertical: 73 mm; Height: 190 mm; Top Flange Thickness: 10 mm; Top Flange Width: 200 mm; Web Height: 170 mm; Web Thickness: 6.5 mm; Width: 200 mm
Type - Pset_BeamCommon - LoadBearing: yes; IsExternal: no
Type - Pset_ProductRequirements - Category: Structural Framing
Type - Pset_ReinforcementBarPitchOfBeam - Description: SFB-HEA200 400x10
Classification: 28.10 Uniformat (Uniformat)
Pset_BeamCommon - Slope: 0 deg; IsExternal: yes; Reference: balk gen hea200 300x15; Span: 24040 mm
Pset_PrecastConcreteElementGeneral - ElementWeight: 0 kg
Pset_QuantityTakeOff - Reference: balk gen hea200 300x15; sets with these values: 2
Pset_DAT_KMS - Assembly Code: 28.10; Assembly Description: hoofddraagconstructies; kolommen en liggers, algemeen (verzamelniveau); Description: SFB-HEA200 400x10
BaseQuantities - Length: 24040 mm; CrossSectionArea: 0.0045 m2; OuterSurfaceArea: 14.9387 m2; GrossSurfaceArea: 14.9477 m2; GrossVolume: 0.106705 m3; NetVolume: 0.235645 m3; NetSurfaceArea: 42.1707 m2
Other - Family: NLRS_28_SF_LIB_balk sfb_gen_ISR Links; Family and Type: NLRS_28_SF_LIB_balk sfb_gen_ISR Links: balk gen hea200 300x15; Type: balk gen hea200 300x15; Type Id: 5975614
Constraints - Cross-Section Rotation: 0 deg; Orientation: Normal; Reference Level: 0; Reference Level Elevation: 0 mm; End Level Offset: 3225 mm; Start Level Offset: 3225 mm; wandoplegging_eind: 120 mm; wandoplegging_start: 120 mm; Work Plane: <not associated>
Dimensions - Elevation at Bottom: 3225 mm; Elevation at Top: 3430 mm; Length: 24040 mm; NLRS_C_lengte: 24040 mm; Volume: 0.235645 m3
Identity Data - Has Association: no; Workset: Constructie
Materials and Finishes - Structural Material: h2_staal S235
Phasing - Phase Created: 2. nieuwbouw
Structural - Stick Symbol Location: Center of Geometry; Structural Usage: Other; End Attachment Type: End Elevation; Cut Length: 23952.3 mm
Geometric Position - End Extension: 0 mm; Join Status: Both joins enabled; Start Extension: 0 mm; y Justification: Origin; yz Justification: Uniform; y Offset Value: 0 mm; z Offset Value: 0 mm; z Justification: Bottom; End Join Cutback: 12.7 mm

# IfcBeam: NLRS_28_SF_LIB_balk sfb_gen_ISR1:balk gen heb200 400x15, NLRS_28_SF_LIB_balk sfb_gen_ISR1:balk gen heb200 400x15:4715749
In: 02 tweede verdieping
Type - PredefinedType: T_BEAM; Material: <Unnamed>, ISR_Staal
Type - Other - Category: Structural Framing; Family Name: NLRS_28_SF_LIB_balk sfb_gen_ISR1
Type - Dimensions - bf: 200 mm; bu: 400 mm; h: 200 mm; k: 33 mm; kr: 18 mm; NLRS_C_breedte: 200 mm; NLRS_C_hoogte: 200 mm; tf: 15 mm; tu: 15 mm; tw: 9 mm; y: 68 mm
Type - Identity Data - Assembly Code: 28.10; Assembly Description: hoofddraagconstructies; kolommen en liggers, algemeen (verzamelniveau); Description: SFB-HEB200 400x15; Model: LOD300; SmartRevit_Versie: 2021.1; Type Name: balk gen heb200 400x15; Workset: Family : Structural Framing : NLRS_28_SF_LIB_balk sfb_gen_ISR1
Type - Structural - A: 0.007808 m2; Section Shape: 16; SG: 7800
Type - Structural Section Geometry - Bottom Flange Thickness: 15 mm; Bottom Flange Width: 400 mm; Centroid Horizontal: 200 mm; Centroid Vertical: 68 mm; Height: 200 mm; Top Flange Thickness: 15 mm; Top Flange Width: 200 mm; Web Height: 170 mm; Web Thickness: 9 mm; Width: 200 mm
Type - Pset_BeamCommon - LoadBearing: yes; IsExternal: no
Type - Pset_ProductRequirements - Category: Structural Framing
Type - Pset_ReinforcementBarPitchOfBeam - Description: SFB-HEB200 400x15
Classification: 28.10 Uniformat (Uniformat); Material: ISR_Staal
Pset_BeamCommon - Slope: 0 deg; IsExternal: yes; Reference: balk gen heb200 400x15; Span: 11400 mm
Pset_PrecastConcreteElementGeneral - ElementWeight: 0 kg
Pset_QuantityTakeOff - Reference: balk gen heb200 400x15; sets with these values: 2
Pset_DAT_KMS - Assembly Code: 28.10; Assembly Description: hoofddraagconstructies; kolommen en liggers, algemeen (verzamelniveau); Description: SFB-HEB200 400x15
BaseQuantities - Length: 11400 mm; CrossSectionArea: 0.00780831 m2; OuterSurfaceArea: 13.1225 m2; GrossSurfaceArea: 13.1381 m2; GrossVolume: 0.0890147 m3; NetVolume: 0.155973 m3; NetSurfaceArea: 22.4129 m2
Other - Family: NLRS_28_SF_LIB_balk sfb_gen_ISR1; Family and Type: NLRS_28_SF_LIB_balk sfb_gen_ISR1: balk gen heb200 400x15; Type: balk gen heb200 400x15; Type Id: 5969169
Constraints - Cross-Section Rotation: 0 deg; Reference Level: V2 bk. ruwe vloer; End Level Offset: -60 mm; Reference Level Elevation: 7150 mm; Start Level Offset: -60 mm; wandoplegging_eind: 120 mm; wandoplegging_start: 120 mm
Dimensions - Elevation at Bottom: 6875 mm; Elevation at Top: 7090 mm; Length: 11400 mm; NLRS_C_lengte: 11400 mm; Volume: 0.155973 m3
Identity Data - Has Association: no; Workset: Constructie
Phasing - Phase Created: 2. nieuwbouw
Structural - Stick Symbol Location: Center of Geometry; Structural Usage: Other; Cut Length: 11400 mm
Geometric Position - End Extension: 0 mm; Join Status: Both joins enabled; Start Extension: 0 mm; y Justification: Origin; yz Justification: Uniform; z Justification: Top; y Offset Value: 0 mm; z Offset Value: 0 mm

# IfcBeam: NLRS_28_SF_LIB_balk sfb_gen_ISR:balk gen hea180 400x15 (2)
In: 01 eerste verdieping
Type - PredefinedType: T_BEAM; Material: h2_staal S235
Type - Other - Category: Structural Framing; Family Name: NLRS_28_SF_LIB_balk sfb_gen_ISR
Type - Dimensions - bf: 180 mm; bu: 280 mm; h: 171 mm; k: 24.5 mm; kr: 15 mm; NLRS_C_breedte: 180 mm; NLRS_C_hoogte: 171 mm; tf: 9.5 mm; tu: 15 mm; tw: 6 mm; y: 64 mm
Type - Identity Data - Assembly Code: 28.10; Assembly Description: hoofddraagconstructies; kolommen en liggers, algemeen (verzamelniveau); Description: SFB-HEA180 400x10; Model: LOD300; SmartRevit_Versie: 2021.1; Type Name: balk gen hea180 400x15; Workset: Family : Structural Framing : NLRS_28_SF_LIB_balk sfb_gen_ISR
Type - Structural - A: 0.004525 m2; Section Shape: 16; SG: 7800
Type - Structural Section Geometry - Bottom Flange Thickness: 15 mm; Bottom Flange Width: 280 mm; Centroid Horizontal: 140 mm; Centroid Vertical: 64 mm; Height: 171 mm; Top Flange Thickness: 9.5 mm; Top Flange Width: 180 mm; Web Height: 152 mm; Web Thickness: 6 mm; Width: 180 mm
Type - Pset_BeamCommon - LoadBearing: yes; IsExternal: no
Type - Pset_ProductRequirements - Category: Structural Framing
Type - Pset_ReinforcementBarPitchOfBeam - Description: SFB-HEA180 400x10
Classification: 28.10 Uniformat (Uniformat)
Pset_BeamCommon - Slope: 0 deg; IsExternal: yes; Reference: balk gen hea180 400x15
Pset_PrecastConcreteElementGeneral - ElementWeight: 0 kg
Pset_QuantityTakeOff - Reference: balk gen hea180 400x15; sets with these values: 2
Pset_DAT_KMS - Assembly Code: 28.10; Assembly Description: hoofddraagconstructies; kolommen en liggers, algemeen (verzamelniveau); Description: SFB-HEA180 400x10
BaseQuantities - CrossSectionArea: 0.0042 m2
Other - Family: NLRS_28_SF_LIB_balk sfb_gen_ISR; Family and Type: NLRS_28_SF_LIB_balk sfb_gen_ISR: balk gen hea180 400x15; Type: balk gen hea180 400x15; Type Id: 5968162
Constraints - Cross-Section Rotation: 0 deg; End Level Offset: -15 mm; Reference Level: V2 ok. ruwe vloer; Reference Level Elevation: 6890 mm; Start Level Offset: -15 mm; wandoplegging_eind: 120 mm
Dimensions - Elevation at Bottom: 6875 mm; Elevation at Top: 7061 mm
Identity Data - Has Association: no; Workset: Constructie
Materials and Finishes - Structural Material: h2_staal S235
Phasing - Phase Created: 2. nieuwbouw
Structural - Stick Symbol Location: Center of Geometry; Structural Usage: Other
Geometric Position - Join Status: Both joins enabled; y Justification: Origin; yz Justification: Uniform; y Offset Value: 0 mm; z Offset Value: 0 mm; z Justification: Bottom
Name (NLRS_28_SF_LIB_balk sfb_gen_ISR:balk gen hea180 400x15:...) | Span (mm) = BaseQuantities, Length (mm) = Dimensions, Length (mm) = NLRS_C_lengte (mm) | OuterSurfaceArea (m2) | GrossSurfaceArea (m2) | GrossVolume (m3) | NetVolume (m3) = Volume (m3) | NetSurfaceArea (m2) | wandoplegging_start (mm) | Cut Length (mm) | Start Extension (mm) | End Extension (mm)
4750500 | 31200 | 20.6166 | 20.625 | 0.146762 | 0.305714 | 56.612 | 62.9599 | 35126.3 | 0 | 3926.29
4750589 | 38400 | 22.5321 | 22.5405 | 0.160398 | 0.3343 | 61.9114 | 120 | 38430 | 15 | 15

# IfcBuildingElementProxy: 100_00_DAT_Revit_base_point_DAT:100_00_DAT_Revit_base_point_DAT, 100_00_DAT_Revit_base_point_DAT:100_00_DAT_Revit_base_point_DAT:4256537
In: 00 Begane grond
Type - Material: <Unnamed>
Type - Other - Category: Generic Models; Family Name: 100_00_DAT_Revit_base_point_DAT
Type - Constraints - Default Elevation: 0 mm
Type - Identity Data - Description: DAT base point; Manufacturer: DAT; Type Comments: Moet in positieve kwadrant staan.Denk aan de modeldatum voor export!; Type Name: 100_00_DAT_Revit_base_point_DAT; Workset: Family : Generic Models : 100_00_DAT_Revit_base_point_DAT
Type - Pset_ManufacturerTypeInformation - Manufacturer: DAT
Type - Pset_ProductRequirements - Category: Generic Models
Pset_BuildingElementProxyCommon - Reference: 100_00_DAT_Revit_base_point_DAT; sets with these values: 2
Pset_Generic Models - Family and Type: 100_00_DAT_Revit_base_point_DAT: 100_00_DAT_Revit_base_point_DAT; Omschrijving: DAT base point; Type Comments: Moet in positieve kwadrant staan.Denk aan de modeldatum voor export!; Level: 0
Pset_DAT_KMS - Description: DAT base point
Other - Family: 100_00_DAT_Revit_base_point_DAT; Family and Type: 100_00_DAT_Revit_base_point_DAT: 100_00_DAT_Revit_base_point_DAT; Type: 100_00_DAT_Revit_base_point_DAT; Type Id: 4256522
Constraints - Elevation from Level: 0 mm; Host: Level : 0; Level: 0; Moves With Nearby Elements: no; Offset from Host: 0 mm
Dimensions - Area: 3.12809 m2; Volume: 0.99936 m3
Identity Data - Workset: Bouwkundig; Edited by: Bas.Schenk
Phasing - Phase Created: 2. nieuwbouw
Text - model_datum: 14-05-2024

# IfcBuildingElementProxy: 29_DAT_Prefab betonband afgeschuind:29_DAT_Prefab betonband afgeschuind (80)
Type - Material: ISR_Beton_prefab
Type - Other - Category: Generic Models; Family Name: 29_DAT_Prefab betonband afgeschuind
Type - Constraints - Default Elevation: 0 mm
Type - Identity Data - Description: Prefab betonband 150x175; Manufacturer: NeHoBo; Model: SB afgeschuind; Type Comments: Prefab betonband; Type Name: 29_DAT_Prefab betonband afgeschuind; Workset: Family : Generic Models : 29_DAT_Prefab betonband afgeschuind
Type - Materials and Finishes - NLRS_C_materiaal: ISR_Beton_prefab
Type - Pset_ManufacturerTypeInformation - Manufacturer: NeHoBo
Type - Pset_ProductRequirements - Category: Generic Models
Pset_BuildingElementProxyCommon - Reference: 29_DAT_Prefab betonband afgeschuind; sets with these values: 2
Pset_Generic Models - Family and Type: 29_DAT_Prefab betonband afgeschuind: 29_DAT_Prefab betonband afgeschuind; Omschrijving: Prefab betonband 150x175; Type Comments: Prefab betonband
Pset_DAT_KMS - Description: Prefab betonband 150x175
Other - Family: 29_DAT_Prefab betonband afgeschuind; Family and Type: 29_DAT_Prefab betonband afgeschuind: 29_DAT_Prefab betonband afgeschuind; Type: 29_DAT_Prefab betonband afgeschuind; Type Id: 4783124
Constraints - Moves With Nearby Elements: no
Identity Data - Workset: Bouwkundig
Phasing - Phase Created: 2. nieuwbouw
Name (29_DAT_Prefab betonband afgeschuind:29_DAT_Prefab betonband afgeschuind:...) | In | Pset_Generic Models, Level = Constraints, Level | Elevation from Level (mm) = Offset from Host (mm) | Host | Area (m2) | NLRS_C_afstand (mm) | Volume (m3) | Group
5536854 | 00 Begane grond | 0 | 2762.5 | Level : 0 | 0.79014 | 2394 | 0.0547627 | Model Group:K_Raamwerk_03:5536855
5536926 | 00 Begane grond | 0 | 2762.5 | Level : 0 | 0.79014 | 2394 | 0.0547627 | Model Group:K_Raamwerk_03:5536927
5536977 | 00 Begane grond | 0 | 2762.5 | Level : 0 | 0.454582 | 1347 | 0.0308126 | Model Group:K_Raamwerk_05:5536976
5536979 | 00 Begane grond | 0 | 2762.5 | Level : 0 | 0.703607 | 2124 | 0.0485865 | Model Group:K_Raamwerk_21:5536962
5536980 | 00 Begane grond | 0 | 2762.5 | Level : 0 | 0.771872 | 2337 | 0.0534589 | Model Group:K_Raamwerk_02a:5536902
5536981 | 00 Begane grond | 0 | 2762.5 | Level : 0 | 0.405546 | 1194 | 0.0273127 | Model Group:K_Raamwerk_01:5536916
5536982 | 00 Begane grond | 0 | 2762.5 | Level : 0 | 0.405546 | 1194 | 0.0273127 | Model Group:K_Raamwerk_01:5536948
5537077 | 00 Begane grond | 0 | 2762.5 | Level : 0 | 0.79014 | 2394 | 0.0547627 | Model Group:K_Raamwerk_03:5537078
5537111 | 00 Begane grond | 0 | 2762.5 | Level : 0 | 0.454582 | 1347 | 0.0308126 | Model Group:K_Raamwerk_05:5537110
5537363 | 01 eerste verdieping | V1 bk. ruwe vloer | 4077.5 | Level : V1 bk. ruwe vloer | 0.775077 | 2347 | 0.0536876
5537380 | 01 eerste verdieping | V1 bk. ruwe vloer | 4077.5 | Level : V1 bk. ruwe vloer | 0.363882 | 1064 | 0.024339
5537381 | 01 eerste verdieping | V1 bk. ruwe vloer | 4077.5 | Level : V1 bk. ruwe vloer | 0.363882 | 1064 | 0.024339
5537382 | 01 eerste verdieping | V1 bk. ruwe vloer | 4077.5 | Level : V1 bk. ruwe vloer | 0.363882 | 1064 | 0.024339
5537383 | 01 eerste verdieping | V1 bk. ruwe vloer | 4077.5 | Level : V1 bk. ruwe vloer | 0.363882 | 1064 | 0.024339
5537384 | 01 eerste verdieping | V1 bk. ruwe vloer | 4077.5 | Level : V1 bk. ruwe vloer | 0.363882 | 1064 | 0.024339
5537442 | 00 Begane grond | 0 | 3012.5 | Level : 0 | 0.361318 | 1064 | 0.024156 | Model Group:K_Raamwerk_06:5537331
5537445 | 00 Begane grond | 0 | 3012.5 | Level : 0 | 0.363882 | 1064 | 0.024339 | Model Group:K_Raamwerk_06:5537289
5537448 | 00 Begane grond | 0 | 3012.5 | Level : 0 | 0.363882 | 1064 | 0.024339 | Model Group:K_Raamwerk_06:5537301
5537451 | 00 Begane grond | 0 | 3012.5 | Level : 0 | 0.363882 | 1064 | 0.024339 | Model Group:K_Raamwerk_06:5537313
5537454 | 00 Begane grond | 0 | 3012.5 | Level : 0 | 0.363882 | 1064 | 0.024339 | Model Group:K_Raamwerk_06:5537322
5537457 | 00 Begane grond | 0 | 3012.5 | Level : 0 | 0.363882 | 1064 | 0.024339 | Model Group:K_Raamwerk_06:5537327
5537497 | 00 Begane grond | 0 | 3012.5 | Level : 0 | 0.345614 | 1007 | 0.0230351 | Model Group:K_Raamwerk_06a:5537494
5537535 | 00 Begane grond | 0 | 3012.5 | Level : 0 | 0.847829 | 2574 | 0.0588803 | Model Group:K_Raamwerk_07:5537510
5537566 | 01 eerste verdieping | V1 bk. ruwe vloer | 4077.5 | Level : V1 bk. ruwe vloer | 0.363882 | 1064 | 0.024339
5537621 | 01 eerste verdieping | V1 bk. ruwe vloer | 4077.5 | Level : V1 bk. ruwe vloer | 0.813536 | 2467 | 0.0564326
5537723 | 00 Begane grond | 0 | 3012.5 | Level : 0 | 0.847829 | 2574 | 0.0588803 | Model Group:K_Raamwerk_07:5537720
5537738 | 01 eerste verdieping | 1 | 2862.5 | Level : 1 | 0.346255 | 1009 | 0.0230809 | Model Group:K_Raamwerk_30:5537736
5537758 | 01 eerste verdieping | 1 | 2862.5 | Level : 1 | 0.753924 | 2281 | 0.0521779 | Model Group:K_Raamwerk_23:5537755
5537762 | 01 eerste verdieping | 1 | 3987.5 | Level : 1 | 0.831805 | 2524 | 0.0577365 | Model Group:K_Raamwerk_22:5537759
5537766 | 01 eerste verdieping | 1 | 3987.5 | Level : 1 | 0.831805 | 2524 | 0.0577365 | Model Group:K_Raamwerk_22:5537763
5537770 | 01 eerste verdieping | 1 | 3987.5 | Level : 1 | 0.831805 | 2524 | 0.0577365 | Model Group:K_Raamwerk_22:5537767
5537774 | 01 eerste verdieping | 1 | 3987.5 | Level : 1 | 0.831805 | 2524 | 0.0577365 | Model Group:K_Raamwerk_22:5537771
5537778 | 01 eerste verdieping | 1 | 3987.5 | Level : 1 | 0.831805 | 2524 | 0.0577365 | Model Group:K_Raamwerk_22:5537775
5537782 | 01 eerste verdieping | 1 | 3987.5 | Level : 1 | 0.831805 | 2524 | 0.0577365 | Model Group:K_Raamwerk_22:5537779
5537825 | 01 eerste verdieping | 1 | 3987.5 | Level : 1 | 0.703607 | 2124 | 0.0485865 | Model Group:K_Raamwerk_29a:5537822
5537841 | 01 eerste verdieping | 1 | 3987.5 | Level : 1 | 0.831805 | 2524 | 0.0577365 | Model Group:K_Raamwerk_22:5537838
5537849 | 01 eerste verdieping | 1 | 3987.5 | Level : 1 | 0.831805 | 2524 | 0.0577365 | Model Group:K_Raamwerk_22:5537846
5537873 | 01 eerste verdieping | 1 | 3987.5 | Level : 1 | 0.831805 | 2524 | 0.0577365 | Model Group:K_Raamwerk_22:5537870
5537881 | 01 eerste verdieping | 1 | 3987.5 | Level : 1 | 0.831805 | 2524 | 0.0577365 | Model Group:K_Raamwerk_22:5537878
5537905 | 01 eerste verdieping | 1 | 3987.5 | Level : 1 | 0.831805 | 2524 | 0.0577365 | Model Group:K_Raamwerk_22:5537902
5537913 | 01 eerste verdieping | 1 | 3987.5 | Level : 1 | 0.831805 | 2524 | 0.0577365 | Model Group:K_Raamwerk_22:5537910
5537937 | 01 eerste verdieping | 1 | 3987.5 | Level : 1 | 0.831805 | 2524 | 0.0577365 | Model Group:K_Raamwerk_22:5537934
5537945 | 01 eerste verdieping | 1 | 3987.5 | Level : 1 | 0.831805 | 2524 | 0.0577365 | Model Group:K_Raamwerk_22:5537942
5537959 | 01 eerste verdieping | 1 | 3987.5 | Level : 1 | 1.2164 | 3724 | 0.0851865
5537963 | 01 eerste verdieping | 1 | 3987.5 | Level : 1 | 0.56964 | 1706 | 0.0390248
5537972 | 01 eerste verdieping | 1 | 3987.5 | Level : 1 | 0.459389 | 1362 | 0.0311557 | Model Group:K_Raamwerk_25:5537969
5538604 | 00 Begane grond | 0 | 3012.5 | Level : 0 | 0.0456302 | 71 | 0.00162413
5538760 | 00 Begane grond | 0 | 2762.5 | Level : 0 | 0.79014 | 2394 | 0.0547627 | Model Group:K_Raamwerk_03:5538761
5538778 | 00 Begane grond | 0 | 2762.5 | Level : 0 | 0.79014 | 2394 | 0.0547627 | Model Group:K_Raamwerk_03:5538779
5538796 | 00 Begane grond | 0 | 2762.5 | Level : 0 | 0.771872 | 2337 | 0.0534589 | Model Group:K_Raamwerk_03a:5538797
5538816 | 00 Begane grond | 0 | 2762.5 | Level : 0 | 0.79014 | 2394 | 0.0547627 | Model Group:K_Raamwerk_02:5538732
5538817 | 00 Begane grond | 0 | 2762.5 | Level : 0 | 0.79014 | 2394 | 0.0547627 | Model Group:K_Raamwerk_02:5538742
5538818 | 00 Begane grond | 0 | 2762.5 | Level : 0 | 0.405546 | 1194 | 0.0273127 | Model Group:K_Raamwerk_01 A:5538614
5538820 | 00 Begane grond | 0 | 2762.5 | Level : 0 | 0.6347 | 1909 | 0.0436684 | Model Group:K_Raamwerk_18:5538682
5539089 | 00 Begane grond | 0 | 2762.5 | Level : 0 | 0.505861 | 1507 | 0.0344726
5539093 | 00 Begane grond | 0 | 2762.5 | Level : 0 | 0.34946 | 1019 | 0.0233096 | Model Group:K_Raamwerk_04:5539091
5539096 | 00 Begane grond | 0 | 2762.5 | Level : 0 | 0.34946 | 1019 | 0.0233096 | Model Group:K_Raamwerk_04 A:5539094
5539099 | 00 Begane grond | 0 | 2762.5 | Level : 0 | 0.34946 | 1019 | 0.0233096 | Model Group:K_Raamwerk_04:5539097
5539102 | 00 Begane grond | 0 | 2762.5 | Level : 0 | 0.34946 | 1019 | 0.0233096 | Model Group:K_Raamwerk_04:5539100
5539105 | 00 Begane grond | 0 | 2762.5 | Level : 0 | 0.34946 | 1019 | 0.0233096 | Model Group:K_Raamwerk_04:5539103
5539108 | 00 Begane grond | 0 | 2762.5 | Level : 0 | 0.34946 | 1019 | 0.0233096 | Model Group:K_Raamwerk_04:5539106
5539159 | 00 Begane grond | 0 | 2762.5 | Level : 0 | 0.722836 | 2184 | 0.049959 | Model Group:K_Raamwerk_20:5539160
5539204 | 00 Begane grond | 0 | 2762.5 | Level : 0 | 0.616581 | 1852.46 | 0.0423751 | Model Group:K_Raamwerk_18A:5539193
5539233 | 00 Begane grond | 0 | 2762.5 | Level : 0 | 0.405546 | 1194 | 0.0273127 | Model Group:K_Raamwerk_01:5536975
5539235 | 00 Begane grond | 0 | 2762.5 | Level : 0 | 0.771872 | 2337 | 0.0534589 | Model Group:K_Raamwerk_02a:5537101
5539237 | 00 Begane grond | 0 | 2762.5 | Level : 0 | 0.771872 | 2337 | 0.0534589 | Model Group:K_Raamwerk_02a:5536878
5539373 | 00 Begane grond | 0 | 2762.5 | Level : 0 | 0.79014 | 2394 | 0.0547627 | Model Group:K_Raamwerk_02:5539371
6239124 | 00 Begane grond | 0 | 2762.5 | Level : 0 | 0.405546 | 1194 | 0.0273127 | Model Group:K_Raamwerk_01 A:5538632
6239129 | 00 Begane grond | 0 | 2762.5 | Level : 0 | 0.405546 | 1194 | 0.0273127 | Model Group:K_Raamwerk_01 A:5538692
6239134 | 00 Begane grond | 0 | 2762.5 | Level : 0 | 0.405546 | 1194 | 0.0273127 | Model Group:K_Raamwerk_01 A:5538702
6239139 | 00 Begane grond | 0 | 2762.5 | Level : 0 | 0.405546 | 1194 | 0.0273127 | Model Group:K_Raamwerk_01 A:5538712
6239144 | 00 Begane grond | 0 | 2762.5 | Level : 0 | 0.405546 | 1194 | 0.0273127 | Model Group:K_Raamwerk_01 A:5538722
6656740 | 01 eerste verdieping | 1 | 3987.5 | Level : 1 | 0.706812 | 2134 | 0.0488152 | Model Group:Waterslag K29 Dubbel:6656850
6658413 | 01 eerste verdieping | 1 | 3987.5 | Level : 1 | 0.706812 | 2134 | 0.0488152 | Model Group:Waterslag K29 Dubbel:6658414
6658425 | 01 eerste verdieping | 1 | 3987.5 | Level : 1 | 0.706812 | 2134 | 0.0488152 | Model Group:Waterslag K29 Dubbel:6658426
6659750 | 01 eerste verdieping | 1 | 3987.5 | Level : 1 | 0.364843 | 1067 | 0.0244076 | Model Group:Waterslag K29 Enkel:6659751
6660296 | 01 eerste verdieping | 1 | 3987.5 | Level : 1 | 0.706812 | 2134 | 0.0488152 | Model Group:Waterslag K29 Dubbel:6660297
6660383 | 01 eerste verdieping | 1 | 3987.5 | Level : 1 | 0.706812 | 2134 | 0.0488152 | Model Group:Waterslag K29 Dubbel:6660384
6660395 | 01 eerste verdieping | 1 | 3987.5 | Level : 1 | 0.706812 | 2134 | 0.0488152 | Model Group:Waterslag K29 Dubbel:6660396
6660526 | 01 eerste verdieping | 1 | 3987.5 | Level : 1 | 0.706812 | 2134 | 0.0488152 | Model Group:Waterslag K29 Dubbel:6660527

# IfcBuildingElementProxy: 29_DAT_Prefab betonband afgeschuind_Binnen_Hoek oplossing:29_DAT_Prefab betonband afgeschuind_Binnen_Hoek oplossing (2)
In: 00 Begane grond
Type - Material: ISR_Beton_prefab
Type - Other - Category: Generic Models; Family Name: 29_DAT_Prefab betonband afgeschuind_Binnen_Hoek oplossing
Type - Constraints - Default Elevation: 0 mm
Type - Identity Data - Type Name: 29_DAT_Prefab betonband afgeschuind_Binnen_Hoek oplossing; Workset: Family : Generic Models : 29_DAT_Prefab betonband afgeschuind_Binnen_Hoek oplossing
Type - Materials and Finishes - Materiaal: ISR_Beton_prefab
Type - Pset_ProductRequirements - Category: Generic Models
Pset_BuildingElementProxyCommon - Reference: 29_DAT_Prefab betonband afgeschuind_Binnen_Hoek oplossing; sets with these values: 2
Pset_Generic Models - Family and Type: 29_DAT_Prefab betonband afgeschuind_Binnen_Hoek oplossing: 29_DAT_Prefab betonband afgeschuind_Binnen_Hoek oplossing; Level: 0
Other - Family: 29_DAT_Prefab betonband afgeschuind_Binnen_Hoek oplossing; Family and Type: 29_DAT_Prefab betonband afgeschuind_Binnen_Hoek oplossing: 29_DAT_Prefab betonband afgeschuind_Binnen_Hoek oplossing; Type: 29_DAT_Prefab betonband afgeschuind_Binnen_Hoek oplossing; Type Id: 5076192
Constraints - Level: 0; Moves With Nearby Elements: no; Elevation from Level: 2650 mm; Host: Level : 0; Offset from Host: 2650 mm
Dimensions - Area: 0.111311 m2; Volume: 0.00638067 m3
Identity Data - Workset: Bouwkundig
Phasing - Phase Created: 2. nieuwbouw
Name (29_DAT_Prefab betonband afgeschuind_Binnen_Hoek oplossing:29_DAT_Prefab betonband afgeschuind_Binnen_Hoek oplossing:...)
5539162
5539163

# IfcBuildingElementProxy: 29_DAT_Prefab betonband afgeschuind_Hoek oplossing:29_DAT_Prefab betonband afgeschuind_Hoek oplossing (3)
Type - Material: ISR_Beton_prefab
Type - Other - Category: Generic Models; Family Name: 29_DAT_Prefab betonband afgeschuind_Hoek oplossing
Type - Constraints - Default Elevation: 0 mm
Type - Identity Data - Description: Prefab beton dorpel; Type Name: 29_DAT_Prefab betonband afgeschuind_Hoek oplossing; Workset: Family : Generic Models : 29_DAT_Prefab betonband afgeschuind_Hoek oplossing
Type - Materials and Finishes - Materiaal: ISR_Beton_prefab
Type - Pset_ProductRequirements - Category: Generic Models
Pset_BuildingElementProxyCommon - Reference: 29_DAT_Prefab betonband afgeschuind_Hoek oplossing; sets with these values: 2
Pset_Generic Models - Family and Type: 29_DAT_Prefab betonband afgeschuind_Hoek oplossing: 29_DAT_Prefab betonband afgeschuind_Hoek oplossing; Omschrijving: Prefab beton dorpel
Pset_DAT_KMS - Description: Prefab beton dorpel
Other - Family: 29_DAT_Prefab betonband afgeschuind_Hoek oplossing; Family and Type: 29_DAT_Prefab betonband afgeschuind_Hoek oplossing: 29_DAT_Prefab betonband afgeschuind_Hoek oplossing; Type: 29_DAT_Prefab betonband afgeschuind_Hoek oplossing; Type Id: 4901498
Constraints - Moves With Nearby Elements: no
Dimensions - Area: 0.231858 m2; Volume: 0.0148473 m3
Identity Data - Workset: Bouwkundig
Phasing - Phase Created: 2. nieuwbouw
Name (29_DAT_Prefab betonband afgeschuind_Hoek oplossing:29_DAT_Prefab betonband afgeschuind_Hoek oplossing:...) | In | Pset_Generic Models, Level = Constraints, Level | Elevation from Level (mm) = Offset from Host (mm) | Host
5537713 | 01 eerste verdieping | V1 bk. ruwe vloer | 2840 | Level : V1 bk. ruwe vloer
6013398 | 00 Begane grond | 0 | 2900 | Level : 0
6482919 | 01 eerste verdieping | V1 bk. ruwe vloer | 3965 | Level : V1 bk. ruwe vloer

# IfcBuildingElementProxy: 29_DAT_Prefab betonnen afdekplaat:29_DAT_Prefab betonnen afdekplaat (2)
In: 01 eerste verdieping
Type - Material: ISR_Beton_prefab
Type - Other - Category: Generic Models; Family Name: 29_DAT_Prefab betonnen afdekplaat; Links: yes; Rechts: yes
Type - Constraints - Default Elevation: 0 mm
Type - Identity Data - Description: Prefab afdekkap; Manufacturer: NeHoBo; Model: RD; Type Comments: Prefab betonband; Type Name: 29_DAT_Prefab betonnen afdekplaat; Workset: Family : Generic Models : 29_DAT_Prefab betonnen afdekplaat
Type - Materials and Finishes - NLRS_C_materiaal: ISR_Beton_prefab
Type - Pset_ManufacturerTypeInformation - Manufacturer: NeHoBo
Type - Pset_ProductRequirements - Category: Generic Models
Pset_BuildingElementProxyCommon - Reference: 29_DAT_Prefab betonnen afdekplaat; sets with these values: 2
Pset_Generic Models - Family and Type: 29_DAT_Prefab betonnen afdekplaat: 29_DAT_Prefab betonnen afdekplaat; Omschrijving: Prefab afdekkap; Type Comments: Prefab betonband; Level: 1
Pset_DAT_KMS - Description: Prefab afdekkap
Other - Family: 29_DAT_Prefab betonnen afdekplaat; Family and Type: 29_DAT_Prefab betonnen afdekplaat: 29_DAT_Prefab betonnen afdekplaat; Type: 29_DAT_Prefab betonnen afdekplaat; Type Id: 4993859; vlak 1: yes; vlak 2: yes
Constraints - Moves With Nearby Elements: no; Level: 1; Elevation from Level: 800 mm; Host: Level : 1; Offset from Host: 800 mm
Dimensions - hart vlak 1: 124.812 mm; hart vlak 2: 2200 mm; L opstand maat: 157 mm; Opvulhoogte: 43.8722 mm; R opstand maat: 157 mm
Identity Data - Workset: Bouwkundig
Phasing - Phase Created: 2. nieuwbouw
Name (29_DAT_Prefab betonnen afdekplaat:29_DAT_Prefab betonnen afdekplaat:...) | Area (m2) | NLRS_C_afstand (mm) | Volume (m3)
4992810 | 4.72521 | 6423 | 0.565466
4994083 | 1.85974 | 2454 | 0.216044

# IfcBuildingElementProxy: 29_DAT_Prefab betonnen waterslag kort:29_DAT_Prefab betonnen waterslag kort (54)
Type - Material: ISR_Beton_prefab
Type - Other - Category: Generic Models; Family Name: 29_DAT_Prefab betonnen waterslag kort
Type - Constraints - Default Elevation: 0 mm
Type - Identity Data - Description: Prefab beton raamdorpel; Manufacturer: NeHoBo; Model: RD; Type Comments: Prefab beton raamdorpel 132x270mm; Type Name: 29_DAT_Prefab betonnen waterslag kort; Workset: Family : Generic Models : 29_DAT_Prefab betonnen waterslag kort
Type - Materials and Finishes - NLRS_C_materiaal: ISR_Beton_prefab
Type - Pset_ManufacturerTypeInformation - Manufacturer: NeHoBo
Type - Pset_ProductRequirements - Category: Generic Models
Pset_BuildingElementProxyCommon - Reference: 29_DAT_Prefab betonnen waterslag kort; sets with these values: 2
Pset_Generic Models - Family and Type: 29_DAT_Prefab betonnen waterslag kort: 29_DAT_Prefab betonnen waterslag kort; Omschrijving: Prefab beton raamdorpel; Type Comments: Prefab beton raamdorpel 132x270mm
Pset_DAT_KMS - Description: Prefab beton raamdorpel
Other - vlak 1: yes; vlak 2: yes; Family: 29_DAT_Prefab betonnen waterslag kort; Family and Type: 29_DAT_Prefab betonnen waterslag kort: 29_DAT_Prefab betonnen waterslag kort; Type: 29_DAT_Prefab betonnen waterslag kort; Type Id: 4802417
Constraints - Moves With Nearby Elements: no
Dimensions - hart vlak 1: 124.812 mm; hart vlak 2: 2200 mm
Identity Data - Workset: Bouwkundig
Phasing - Phase Created: 2. nieuwbouw
Name (29_DAT_Prefab betonnen waterslag kort:29_DAT_Prefab betonnen waterslag kort:...) | In | Pset_Generic Models, Level = Constraints, Level | Elevation from Level (mm) = Offset from Host (mm) | Host | Area (m2) | NLRS_C_afstand (mm) | Volume (m3) | Group
5541152 | 00 Begane grond | 0 | 700 | Level : 0 | 0.915039 | 2000 | 0.0788221 | Model Group:K_Raamwerk_17:5540557
5542287 | 00 Begane grond | 0 | 700 | Level : 0 | 0.915039 | 2000 | 0.0788221 | Model Group:K_Raamwerk_17:5542283
5542313 | 00 Begane grond | 0 | 700 | Level : 0 | 0.915039 | 2000 | 0.0788221 | Model Group:K_Raamwerk_17:5542309
5542339 | 00 Begane grond | 0 | 700 | Level : 0 | 0.915039 | 2000 | 0.0788221 | Model Group:K_Raamwerk_17:5542335
5542365 | 00 Begane grond | 0 | 700 | Level : 0 | 0.915039 | 2000 | 0.0788221 | Model Group:K_Raamwerk_17:5542361
5542391 | 00 Begane grond | 0 | 700 | Level : 0 | 0.915039 | 2000 | 0.0788221 | Model Group:K_Raamwerk_17:5542387
5542463 | 00 Begane grond | 0 | 700 | Level : 0 | 0.407175 | 840 | 0.0331053 | Model Group:K_Raamwerk_16:5542459
5544036 | 00 Begane grond | 0 | 700 | Level : 0 | 0.407175 | 840 | 0.0331053 | Model Group:K_Raamwerk_16:5544033
5544058 | 00 Begane grond | 0 | 700 | Level : 0 | 0.407175 | 840 | 0.0331053 | Model Group:K_Raamwerk_16:5544055
5544109 | 00 Begane grond | 0 | 700 | Level : 0 | 0.407175 | 840 | 0.0331053 | Model Group:K_Raamwerk_16:5544106
5544135 | 00 Begane grond | 0 | 700 | Level : 0 | 0.407175 | 840 | 0.0331053 | Model Group:K_Raamwerk_16:5544132
5544807 | 00 Begane grond | 0 | 700 | Level : 0 | 0.407175 | 840 | 0.0331053 | Model Group:K_Raamwerk_16:5544804
5544825 | 00 Begane grond | 0 | 700 | Level : 0 | 0.407175 | 840 | 0.0331053 | Model Group:K_Raamwerk_16:5544822
5544975 | 00 Begane grond | 0 | 700 | Level : 0 | 0.915039 | 2000 | 0.0788221 | Model Group:K_Raamwerk_17:5544971
5545010 | 00 Begane grond | 0 | 700 | Level : 0 | 0.915039 | 2000 | 0.0788221 | Model Group:K_Raamwerk_17:5545006
5545036 | 00 Begane grond | 0 | 700 | Level : 0 | 0.407175 | 840 | 0.0331053 | Model Group:K_Raamwerk_16:5545033
5545109 | 00 Begane grond | 0 | 700 | Level : 0 | 0.407175 | 840 | 0.0331053 | Model Group:K_Raamwerk_16:5545106
5545132 | 00 Begane grond | 0 | 700 | Level : 0 | 0.407175 | 840 | 0.0331053 | Model Group:K_Raamwerk_16:5545129
5552761 | 00 Begane grond | 0 | 700 | Level : 0 | 0.407175 | 840 | 0.0331053
5856139 | 00 Begane grond | 0 | 700 | Level : 0 | 0.407175 | 840 | 0.0331053 | Model Group:K_Raamwerk_16:5856137
5856142 | 00 Begane grond | 0 | 700 | Level : 0 | 0.407175 | 840 | 0.0331053 | Model Group:K_Raamwerk_16:5856140
6054221 | 00 Begane grond | 0 | 700 | Level : 0 | 0.915039 | 2000 | 0.0788221 | Model Group:K_Raamwerk_17:5544238
6054341 | 00 Begane grond | 0 | 700 | Level : 0 | 0.915039 | 2000 | 0.0788221 | Model Group:K_Raamwerk_17:5856134
6054391 | 00 Begane grond | 0 | 700 | Level : 0 | 0.915039 | 2000 | 0.0788221 | Model Group:K_Raamwerk_17:5544293
6057857 | 01 eerste verdieping | V1 bk. ruwe vloer | 890 | Level : V1 bk. ruwe vloer | 0.407175 | 840 | 0.0331053 | Model Group:K_Raamwerk_28:6057727
6058275 | 01 eerste verdieping | V1 bk. ruwe vloer | 890 | Level : V1 bk. ruwe vloer | 0.407175 | 840 | 0.0331053 | Model Group:K_Raamwerk_28:6058262
6058294 | 01 eerste verdieping | V1 bk. ruwe vloer | 890 | Level : V1 bk. ruwe vloer | 0.407175 | 840 | 0.0331053 | Model Group:K_Raamwerk_28:6058281
6058313 | 01 eerste verdieping | V1 bk. ruwe vloer | 890 | Level : V1 bk. ruwe vloer | 0.407175 | 840 | 0.0331053 | Model Group:K_Raamwerk_28:6058300
6058332 | 01 eerste verdieping | V1 bk. ruwe vloer | 890 | Level : V1 bk. ruwe vloer | 0.407175 | 840 | 0.0331053 | Model Group:K_Raamwerk_28:6058319
6058351 | 01 eerste verdieping | V1 bk. ruwe vloer | 890 | Level : V1 bk. ruwe vloer | 0.407175 | 840 | 0.0331053 | Model Group:K_Raamwerk_28:6058338
6058370 | 01 eerste verdieping | V1 bk. ruwe vloer | 890 | Level : V1 bk. ruwe vloer | 0.407175 | 840 | 0.0331053 | Model Group:K_Raamwerk_28:6058357
6058389 | 01 eerste verdieping | V1 bk. ruwe vloer | 890 | Level : V1 bk. ruwe vloer | 0.407175 | 840 | 0.0331053 | Model Group:K_Raamwerk_28:6058376
6058408 | 01 eerste verdieping | V1 bk. ruwe vloer | 890 | Level : V1 bk. ruwe vloer | 0.407175 | 840 | 0.0331053 | Model Group:K_Raamwerk_28:6058395
6058427 | 01 eerste verdieping | V1 bk. ruwe vloer | 890 | Level : V1 bk. ruwe vloer | 0.407175 | 840 | 0.0331053 | Model Group:K_Raamwerk_28:6058414
6058446 | 01 eerste verdieping | V1 bk. ruwe vloer | 890 | Level : V1 bk. ruwe vloer | 0.407175 | 840 | 0.0331053 | Model Group:K_Raamwerk_28:6058433
6058465 | 01 eerste verdieping | V1 bk. ruwe vloer | 890 | Level : V1 bk. ruwe vloer | 0.407175 | 840 | 0.0331053 | Model Group:K_Raamwerk_28:6058452
6058484 | 01 eerste verdieping | V1 bk. ruwe vloer | 890 | Level : V1 bk. ruwe vloer | 0.407175 | 840 | 0.0331053 | Model Group:K_Raamwerk_28:6058471
6058503 | 01 eerste verdieping | V1 bk. ruwe vloer | 890 | Level : V1 bk. ruwe vloer | 0.407175 | 840 | 0.0331053 | Model Group:K_Raamwerk_28:6058490
6058522 | 01 eerste verdieping | V1 bk. ruwe vloer | 890 | Level : V1 bk. ruwe vloer | 0.407175 | 840 | 0.0331053 | Model Group:K_Raamwerk_28:6058509
6058541 | 01 eerste verdieping | V1 bk. ruwe vloer | 890 | Level : V1 bk. ruwe vloer | 0.407175 | 840 | 0.0331053 | Model Group:K_Raamwerk_28:6058528
6058560 | 01 eerste verdieping | V1 bk. ruwe vloer | 890 | Level : V1 bk. ruwe vloer | 0.407175 | 840 | 0.0331053 | Model Group:K_Raamwerk_28:6058547
6058694 | 01 eerste verdieping | 1 | 800 | Level : 1 | 0.915039 | 2000 | 0.0788221 | Model Group:K_Raamwerk_24:6058628
6059002 | 01 eerste verdieping | 1 | 800 | Level : 1 | 0.915039 | 2000 | 0.0788221 | Model Group:K_Raamwerk_24:6058988
6059021 | 01 eerste verdieping | 1 | 800 | Level : 1 | 0.915039 | 2000 | 0.0788221 | Model Group:K_Raamwerk_24:6059007
6059040 | 01 eerste verdieping | 1 | 800 | Level : 1 | 0.915039 | 2000 | 0.0788221 | Model Group:K_Raamwerk_24:6059026
6059059 | 01 eerste verdieping | 1 | 800 | Level : 1 | 0.915039 | 2000 | 0.0788221 | Model Group:K_Raamwerk_24:6059045
6059078 | 01 eerste verdieping | 1 | 800 | Level : 1 | 0.915039 | 2000 | 0.0788221 | Model Group:K_Raamwerk_24:6059064
6059097 | 01 eerste verdieping | 1 | 800 | Level : 1 | 0.915039 | 2000 | 0.0788221 | Model Group:K_Raamwerk_24:6059083
6059116 | 01 eerste verdieping | 1 | 800 | Level : 1 | 0.915039 | 2000 | 0.0788221 | Model Group:K_Raamwerk_24:6059102
6059135 | 01 eerste verdieping | 1 | 800 | Level : 1 | 0.915039 | 2000 | 0.0788221 | Model Group:K_Raamwerk_24:6059121
6059154 | 01 eerste verdieping | 1 | 800 | Level : 1 | 0.915039 | 2000 | 0.0788221 | Model Group:K_Raamwerk_24:6059140
6059173 | 01 eerste verdieping | 1 | 800 | Level : 1 | 0.915039 | 2000 | 0.0788221 | Model Group:K_Raamwerk_24:6059159
6059192 | 01 eerste verdieping | 1 | 800 | Level : 1 | 0.915039 | 2000 | 0.0788221 | Model Group:K_Raamwerk_24:6059178
6059211 | 01 eerste verdieping | 1 | 800 | Level : 1 | 0.915039 | 2000 | 0.0788221 | Model Group:K_Raamwerk_24:6059197

# IfcBuildingElementProxy: 29_DAT_Prefab betonnen waterslag lang Hoekoplossing:29_DAT_Prefab betonnen waterslag lang Hoekoplossing (2)
Type - Material: ISR_Beton_prefab
Type - Other - Category: Generic Models; Rechts: yes; Blok: no; Family Name: 29_DAT_Prefab betonnen waterslag lang Hoekoplossing
Type - Constraints - Default Elevation: 0 mm
Type - Identity Data - Workset: Family : Generic Models : 29_DAT_Prefab betonnen waterslag lang Hoekoplossing; Type Name: 29_DAT_Prefab betonnen waterslag lang Hoekoplossing
Type - Materials and Finishes - NLRS_C_materiaal: ISR_Beton_prefab; Materiaal: ISR_Beton_prefab
Type - Pset_ProductRequirements - Category: Generic Models
Pset_BuildingElementProxyCommon - Reference: 29_DAT_Prefab betonnen waterslag lang Hoekoplossing; sets with these values: 2
Pset_Generic Models - Family and Type: 29_DAT_Prefab betonnen waterslag lang Hoekoplossing: 29_DAT_Prefab betonnen waterslag lang Hoekoplossing
Other - Family: 29_DAT_Prefab betonnen waterslag lang Hoekoplossing; Family and Type: 29_DAT_Prefab betonnen waterslag lang Hoekoplossing: 29_DAT_Prefab betonnen waterslag lang Hoekoplossing; Type: 29_DAT_Prefab betonnen waterslag lang Hoekoplossing; Type Id: 4903744
Constraints - Moves With Nearby Elements: no
Dimensions - Area: 0.32852 m2; Opvulhoogte: 43.8722 mm; Volume: 0.0224456 m3
Identity Data - Workset: Bouwkundig
Phasing - Phase Created: 2. nieuwbouw
Name (29_DAT_Prefab betonnen waterslag lang Hoekoplossing:29_DAT_Prefab betonnen waterslag lang Hoekoplossing:...) | In | Pset_Generic Models, Level = Constraints, Level | Elevation from Level (mm) | Host | Offset from Host (mm)
6013733 | 00 Begane grond | 0 | 525 | Sub-Division | 535
6474500 | 01 eerste verdieping | 1 | 625 | Level : 1 | 625

# IfcBuildingElementProxy: 29_DAT_Prefab betonnen waterslag lang Hoekoplossing:29_DAT_Prefab betonnen waterslag lang Hoekoplossing Block, 29_DAT_Prefab betonnen waterslag lang Hoekoplossing:29_DAT_Prefab betonnen waterslag lang Hoekoplossing Block:5537704
In: 01 eerste verdieping
Type - Material: ISR_Beton_prefab
Type - Other - Category: Generic Models; Rechts: yes; Blok: yes; Family Name: 29_DAT_Prefab betonnen waterslag lang Hoekoplossing
Type - Constraints - Default Elevation: 0 mm
Type - Identity Data - Type Name: 29_DAT_Prefab betonnen waterslag lang Hoekoplossing Block; Workset: Family : Generic Models : 29_DAT_Prefab betonnen waterslag lang Hoekoplossing
Type - Materials and Finishes - NLRS_C_materiaal: ISR_Beton_prefab; Materiaal: ISR_Beton_prefab
Type - Pset_ProductRequirements - Category: Generic Models
Pset_BuildingElementProxyCommon - Reference: 29_DAT_Prefab betonnen waterslag lang Hoekoplossing Block; sets with these values: 2
Pset_Generic Models - Family and Type: 29_DAT_Prefab betonnen waterslag lang Hoekoplossing: 29_DAT_Prefab betonnen waterslag lang Hoekoplossing Block; Level: 1
Other - Family: 29_DAT_Prefab betonnen waterslag lang Hoekoplossing; Family and Type: 29_DAT_Prefab betonnen waterslag lang Hoekoplossing: 29_DAT_Prefab betonnen waterslag lang Hoekoplossing Block; Type: 29_DAT_Prefab betonnen waterslag lang Hoekoplossing Block; Type Id: 4998435
Constraints - Moves With Nearby Elements: no; Level: 1; Elevation from Level: 625 mm; Host: Level : 1; Offset from Host: 625 mm
Dimensions - Area: 0.32852 m2; Opvulhoogte: 43.8722 mm; Volume: 0.0224456 m3
Identity Data - Workset: Bouwkundig
Phasing - Phase Created: 2. nieuwbouw

# IfcBuildingElementProxy: 29_DAT_Prefab betonnen waterslag lang:06, 29_DAT_Prefab betonnen waterslag lang:06:5537496
In: 00 Begane grond
Type - Material: ISR_Beton_prefab
Type - Other - Category: Generic Models; 01: yes; 02: yes; 03: no; 04: no; 05: no; 06: no; 07: no; 08: no; 09: no; 10: no; Family Name: 29_DAT_Prefab betonnen waterslag lang
Type - Constraints - Default Elevation: 0 mm
Type - Dimensions - NLRS_C_afstand: 1007 mm; NLRS_C_lengte_01: 67 mm; NLRS_C_lengte_02: 917 mm; NLRS_C_lengte_03: 960 mm; NLRS_C_lengte_04: 1300 mm; NLRS_C_lengte_05: 1440 mm; NLRS_C_lengte_06: 1620 mm; NLRS_C_lengte_07: 1800 mm; NLRS_C_lengte_08: 1960 mm; NLRS_C_lengte_09: 2130 mm; NLRS_C_lengte_10: 2280 mm
Type - Identity Data - Workset: Family : Generic Models : 29_DAT_Prefab betonnen waterslag lang; Description: Prefab beton raamdorpel; Manufacturer: NeHoBo; Model: RD; Type Comments: Prefab beton raamdorpel 131x270mm; Type Name: 06
Type - Materials and Finishes - NLRS_C_materiaal: ISR_Beton_prefab
Type - Pset_ManufacturerTypeInformation - Manufacturer: NeHoBo
Type - Pset_ProductRequirements - Category: Generic Models
Pset_BuildingElementProxyCommon - Reference: 06; sets with these values: 2
Pset_Generic Models - Family and Type: 29_DAT_Prefab betonnen waterslag lang: 06; Omschrijving: Prefab beton raamdorpel; Type Comments: Prefab beton raamdorpel 131x270mm; Level: 0
Pset_DAT_KMS - Description: Prefab beton raamdorpel
Other - Family: 29_DAT_Prefab betonnen waterslag lang; Family and Type: 29_DAT_Prefab betonnen waterslag lang: 06; Type: 06; Type Id: 6865797
Constraints - Level: 0; Moves With Nearby Elements: no; Elevation from Level: 700 mm; Host: Level : 0; Offset from Host: 700 mm
Dimensions - Area: 0.775129 m2; Volume: 0.046919 m3
Identity Data - Workset: Bouwkundig
Phasing - Phase Created: 2. nieuwbouw
Group: Model Group:K_Raamwerk_06a:5537494

# IfcBuildingElementProxy: 29_DAT_Prefab betonnen waterslag lang:06 3x (2)
In: 00 Begane grond
Type - Material: ISR_Beton_prefab
Type - Other - Category: Generic Models; 01: yes; 02: yes; 07: no; 08: no; 09: no; 10: no; 03: yes; 04: yes; 05: yes; 06: yes; Family Name: 29_DAT_Prefab betonnen waterslag lang
Type - Constraints - Default Elevation: 0 mm
Type - Dimensions - NLRS_C_afstand: 3207 mm; NLRS_C_lengte_01: 67 mm; NLRS_C_lengte_02: 917 mm; NLRS_C_lengte_03: 1137 mm; NLRS_C_lengte_04: 1987 mm; NLRS_C_lengte_05: 2207 mm; NLRS_C_lengte_06: 3057 mm; NLRS_C_lengte_07: 1800 mm; NLRS_C_lengte_08: 1960 mm; NLRS_C_lengte_09: 2130 mm; NLRS_C_lengte_10: 2280 mm
Type - Identity Data - Workset: Family : Generic Models : 29_DAT_Prefab betonnen waterslag lang; Description: Prefab beton raamdorpel; Manufacturer: NeHoBo; Model: RD; Type Comments: Prefab beton raamdorpel 131x270mm; Type Name: 06 3x
Type - Materials and Finishes - NLRS_C_materiaal: ISR_Beton_prefab
Type - Pset_ManufacturerTypeInformation - Manufacturer: NeHoBo
Type - Pset_ProductRequirements - Category: Generic Models
Pset_BuildingElementProxyCommon - Reference: 06 3x; sets with these values: 2
Pset_Generic Models - Family and Type: 29_DAT_Prefab betonnen waterslag lang: 06 3x; Omschrijving: Prefab beton raamdorpel; Type Comments: Prefab beton raamdorpel 131x270mm; Level: 0
Pset_DAT_KMS - Description: Prefab beton raamdorpel
Other - Family: 29_DAT_Prefab betonnen waterslag lang; Family and Type: 29_DAT_Prefab betonnen waterslag lang: 06 3x; Type: 06 3x; Type Id: 6866039
Constraints - Level: 0; Moves With Nearby Elements: no; Elevation from Level: 700 mm; Host: Level : 0; Offset from Host: 700 mm
Dimensions - Area: 1.7594 m2; Volume: 0.136518 m3
Identity Data - Workset: Bouwkundig
Phasing - Phase Created: 2. nieuwbouw
Name (29_DAT_Prefab betonnen waterslag lang:06 3x:...)
5537444
6866346

# IfcBuildingElementProxy: 29_DAT_Prefab betonnen waterslag lang:07 (2)
In: 00 Begane grond
Type - Material: ISR_Beton_prefab
Type - Other - Category: Generic Models; 01: yes; 02: yes; 03: no; 04: no; 05: no; 06: no; 07: no; 08: no; 09: no; 10: no; Family Name: 29_DAT_Prefab betonnen waterslag lang
Type - Constraints - Default Elevation: 0 mm
Type - Dimensions - NLRS_C_afstand: 2574 mm; NLRS_C_lengte_01: 67 mm; NLRS_C_lengte_02: 2427 mm; NLRS_C_lengte_03: 960 mm; NLRS_C_lengte_04: 1300 mm; NLRS_C_lengte_05: 1440 mm; NLRS_C_lengte_06: 1620 mm; NLRS_C_lengte_07: 1800 mm; NLRS_C_lengte_08: 1960 mm; NLRS_C_lengte_09: 2130 mm; NLRS_C_lengte_10: 2280 mm
Type - Identity Data - Workset: Family : Generic Models : 29_DAT_Prefab betonnen waterslag lang; Description: Prefab beton raamdorpel; Manufacturer: NeHoBo; Model: RD; Type Comments: Prefab beton raamdorpel 131x270mm; Type Name: 07
Type - Materials and Finishes - NLRS_C_materiaal: ISR_Beton_prefab
Type - Pset_ManufacturerTypeInformation - Manufacturer: NeHoBo
Type - Pset_ProductRequirements - Category: Generic Models
Pset_BuildingElementProxyCommon - Reference: 07; sets with these values: 2
Pset_Generic Models - Family and Type: 29_DAT_Prefab betonnen waterslag lang: 07; Omschrijving: Prefab beton raamdorpel; Type Comments: Prefab beton raamdorpel 131x270mm; Level: 0
Pset_DAT_KMS - Description: Prefab beton raamdorpel
Other - Family: 29_DAT_Prefab betonnen waterslag lang; Family and Type: 29_DAT_Prefab betonnen waterslag lang: 07; Type: 07; Type Id: 6865959
Constraints - Level: 0; Moves With Nearby Elements: no; Elevation from Level: 700 mm; Host: Level : 0; Offset from Host: 700 mm
Dimensions - Area: 1.4762 m2; Volume: 0.110738 m3
Identity Data - Workset: Bouwkundig
Phasing - Phase Created: 2. nieuwbouw
Name (29_DAT_Prefab betonnen waterslag lang:07:...) | Group
5537534 | Model Group:K_Raamwerk_07:5537510
5537722 | Model Group:K_Raamwerk_07:5537720

# IfcBuildingElementProxy: 29_DAT_Prefab betonnen waterslag lang:08, 29_DAT_Prefab betonnen waterslag lang:08:5537433
In: 00 Begane grond
Type - Material: ISR_Beton_prefab
Type - Other - Category: Generic Models; 01: yes; 02: yes; 03: no; 04: no; 05: no; 06: no; 07: no; 08: no; 09: no; 10: no; Family Name: 29_DAT_Prefab betonnen waterslag lang
Type - Constraints - Default Elevation: 0 mm
Type - Dimensions - NLRS_C_afstand: 2347 mm; NLRS_C_lengte_01: 10 mm; NLRS_C_lengte_02: 2200 mm; NLRS_C_lengte_03: 960 mm; NLRS_C_lengte_04: 1300 mm; NLRS_C_lengte_05: 1440 mm; NLRS_C_lengte_06: 1620 mm; NLRS_C_lengte_07: 1800 mm; NLRS_C_lengte_08: 1960 mm; NLRS_C_lengte_09: 2130 mm; NLRS_C_lengte_10: 2280 mm
Type - Identity Data - Description: Prefab beton raamdorpel; Manufacturer: NeHoBo; Model: RD; Type Comments: Prefab beton raamdorpel 131x270mm; Type Name: 08; Workset: Family : Generic Models : 29_DAT_Prefab betonnen waterslag lang
Type - Materials and Finishes - NLRS_C_materiaal: ISR_Beton_prefab
Type - Pset_ManufacturerTypeInformation - Manufacturer: NeHoBo
Type - Pset_ProductRequirements - Category: Generic Models
Pset_BuildingElementProxyCommon - Reference: 08; sets with these values: 2
Pset_Generic Models - Family and Type: 29_DAT_Prefab betonnen waterslag lang: 08; Omschrijving: Prefab beton raamdorpel; Type Comments: Prefab beton raamdorpel 131x270mm; Level: 0
Pset_DAT_KMS - Description: Prefab beton raamdorpel
Other - Family: 29_DAT_Prefab betonnen waterslag lang; Family and Type: 29_DAT_Prefab betonnen waterslag lang: 08; Type: 08; Type Id: 6866385
Constraints - Level: 0; Moves With Nearby Elements: no; Elevation from Level: 700 mm; Host: Level : 0; Offset from Host: 700 mm
Dimensions - Area: 1.37464 m2; Volume: 0.101493 m3
Identity Data - Workset: Bouwkundig
Phasing - Phase Created: 2. nieuwbouw

# IfcBuildingElementProxy: 29_DAT_Prefab betonnen waterslag lang:09, 29_DAT_Prefab betonnen waterslag lang:09:5537438
In: 01 eerste verdieping
Type - Material: ISR_Beton_prefab
Type - Other - Category: Generic Models; 01: yes; 02: yes; 03: no; 04: no; 05: no; 06: no; 07: no; 08: no; 09: no; 10: no; Family Name: 29_DAT_Prefab betonnen waterslag lang
Type - Constraints - Default Elevation: 0 mm
Type - Dimensions - NLRS_C_afstand: 1117 mm; NLRS_C_lengte_01: 67 mm; NLRS_C_lengte_02: 917 mm; NLRS_C_lengte_03: 960 mm; NLRS_C_lengte_04: 1300 mm; NLRS_C_lengte_05: 1440 mm; NLRS_C_lengte_06: 1620 mm; NLRS_C_lengte_07: 1800 mm; NLRS_C_lengte_08: 1960 mm; NLRS_C_lengte_09: 2130 mm; NLRS_C_lengte_10: 2280 mm
Type - Identity Data - Workset: Family : Generic Models : 29_DAT_Prefab betonnen waterslag lang; Description: Prefab beton raamdorpel; Manufacturer: NeHoBo; Model: RD; Type Comments: Prefab beton raamdorpel 131x270mm; Type Name: 09
Type - Materials and Finishes - NLRS_C_materiaal: ISR_Beton_prefab
Type - Pset_ManufacturerTypeInformation - Manufacturer: NeHoBo
Type - Pset_ProductRequirements - Category: Generic Models
Pset_BuildingElementProxyCommon - Reference: 09; sets with these values: 2
Pset_Generic Models - Family and Type: 29_DAT_Prefab betonnen waterslag lang: 09; Omschrijving: Prefab beton raamdorpel; Type Comments: Prefab beton raamdorpel 131x270mm; Level: 1
Pset_DAT_KMS - Description: Prefab beton raamdorpel
Other - Family: 29_DAT_Prefab betonnen waterslag lang; Family and Type: 29_DAT_Prefab betonnen waterslag lang: 09; Type: 09; Type Id: 6866500
Constraints - Moves With Nearby Elements: no; Level: 1; Elevation from Level: 800 mm; Host: Level : 1; Offset from Host: 800 mm
Dimensions - Area: 0.824343 m2; Volume: 0.051399 m3
Identity Data - Workset: Bouwkundig
Phasing - Phase Created: 2. nieuwbouw

# IfcBuildingElementProxy: 29_DAT_Prefab betonnen waterslag lang:09 eind (5)
In: 00 Begane grond
Type - Material: ISR_Beton_prefab
Type - Other - Category: Generic Models; 01: yes; 02: yes; 03: no; 04: no; 05: no; 06: no; 07: no; 08: no; 09: no; 10: no; Family Name: 29_DAT_Prefab betonnen waterslag lang
Type - Constraints - Default Elevation: 0 mm
Type - Dimensions - NLRS_C_afstand: 1060 mm; NLRS_C_lengte_01: 10 mm; NLRS_C_lengte_02: 860 mm; NLRS_C_lengte_03: 960 mm; NLRS_C_lengte_04: 1300 mm; NLRS_C_lengte_05: 1440 mm; NLRS_C_lengte_06: 1620 mm; NLRS_C_lengte_07: 1800 mm; NLRS_C_lengte_08: 1960 mm; NLRS_C_lengte_09: 2130 mm; NLRS_C_lengte_10: 2280 mm
Type - Identity Data - Workset: Family : Generic Models : 29_DAT_Prefab betonnen waterslag lang; Description: Prefab beton raamdorpel; Manufacturer: NeHoBo; Model: RD; Type Comments: Prefab beton raamdorpel 131x270mm; Type Name: 09 eind
Type - Materials and Finishes - NLRS_C_materiaal: ISR_Beton_prefab
Type - Pset_ManufacturerTypeInformation - Manufacturer: NeHoBo
Type - Pset_ProductRequirements - Category: Generic Models
Pset_BuildingElementProxyCommon - Reference: 09 eind; sets with these values: 2
Pset_Generic Models - Family and Type: 29_DAT_Prefab betonnen waterslag lang: 09 eind; Omschrijving: Prefab beton raamdorpel; Type Comments: Prefab beton raamdorpel 131x270mm; Level: 0
Pset_DAT_KMS - Description: Prefab beton raamdorpel
Other - Family: 29_DAT_Prefab betonnen waterslag lang; Family and Type: 29_DAT_Prefab betonnen waterslag lang: 09 eind; Type: 09 eind; Type Id: 6867171
Constraints - Level: 0; Moves With Nearby Elements: no; Host: Level : 0
Dimensions - Area: 0.798841 m2; Volume: 0.0490775 m3
Identity Data - Workset: Bouwkundig
Phasing - Phase Created: 2. nieuwbouw
Name (29_DAT_Prefab betonnen waterslag lang:09 eind:...) | Elevation from Level (mm) = Offset from Host (mm)
5537434 | 1325
5537435 | 1950
5537436 | 2575
5537437 | 3200
5537439 | 3825

# IfcBuildingElementProxy: 29_DAT_Prefab betonnen waterslag lang:22 (14)
In: 01 eerste verdieping
Type - Material: ISR_Beton_prefab
Type - Other - Category: Generic Models; 01: yes; 02: yes; 03: no; 04: no; 05: no; 06: no; 07: no; 08: no; 09: no; 10: no; Family Name: 29_DAT_Prefab betonnen waterslag lang
Type - Constraints - Default Elevation: 0 mm
Type - Dimensions - NLRS_C_afstand: 2524 mm; NLRS_C_lengte_01: 67 mm; NLRS_C_lengte_02: 2377 mm; NLRS_C_lengte_03: 960 mm; NLRS_C_lengte_04: 1300 mm; NLRS_C_lengte_05: 1440 mm; NLRS_C_lengte_06: 1620 mm; NLRS_C_lengte_07: 1800 mm; NLRS_C_lengte_08: 1960 mm; NLRS_C_lengte_09: 2130 mm; NLRS_C_lengte_10: 2280 mm
Type - Identity Data - Workset: Family : Generic Models : 29_DAT_Prefab betonnen waterslag lang; Description: Prefab beton raamdorpel; Manufacturer: NeHoBo; Model: RD; Type Comments: Prefab beton raamdorpel 131x270mm; Type Name: 22
Type - Materials and Finishes - NLRS_C_materiaal: ISR_Beton_prefab
Type - Pset_ManufacturerTypeInformation - Manufacturer: NeHoBo
Type - Pset_ProductRequirements - Category: Generic Models
Pset_BuildingElementProxyCommon - Reference: 22; sets with these values: 2
Pset_Generic Models - Family and Type: 29_DAT_Prefab betonnen waterslag lang: 22; Omschrijving: Prefab beton raamdorpel; Type Comments: Prefab beton raamdorpel 131x270mm; Level: 1
Pset_DAT_KMS - Description: Prefab beton raamdorpel
Other - Family: 29_DAT_Prefab betonnen waterslag lang; Family and Type: 29_DAT_Prefab betonnen waterslag lang: 22; Type: 22; Type Id: 6853429
Constraints - Moves With Nearby Elements: no; Level: 1; Elevation from Level: 800 mm; Host: Level : 1; Offset from Host: 800 mm
Dimensions - Area: 1.45383 m2; Volume: 0.108701 m3
Identity Data - Workset: Bouwkundig
Phasing - Phase Created: 2. nieuwbouw
Name (29_DAT_Prefab betonnen waterslag lang:22:...) | Group
5537760 | Model Group:K_Raamwerk_22:5537759
5537764 | Model Group:K_Raamwerk_22:5537763
5537768 | Model Group:K_Raamwerk_22:5537767
5537772 | Model Group:K_Raamwerk_22:5537771
5537776 | Model Group:K_Raamwerk_22:5537775
5537780 | Model Group:K_Raamwerk_22:5537779
5537839 | Model Group:K_Raamwerk_22:5537838
5537847 | Model Group:K_Raamwerk_22:5537846
5537871 | Model Group:K_Raamwerk_22:5537870
5537879 | Model Group:K_Raamwerk_22:5537878
5537903 | Model Group:K_Raamwerk_22:5537902
5537911 | Model Group:K_Raamwerk_22:5537910
5537935 | Model Group:K_Raamwerk_22:5537934
5537943 | Model Group:K_Raamwerk_22:5537942

# IfcBuildingElementProxy: 29_DAT_Prefab betonnen waterslag lang:22 eind, 29_DAT_Prefab betonnen waterslag lang:22 eind:5537619
In: 01 eerste verdieping
Type - Material: ISR_Beton_prefab
Type - Other - Category: Generic Models; 01: yes; 02: yes; 03: no; 04: no; 05: no; 06: no; 07: no; 08: no; 09: no; 10: no; Family Name: 29_DAT_Prefab betonnen waterslag lang
Type - Constraints - Default Elevation: 0 mm
Type - Dimensions - NLRS_C_afstand: 2467 mm; NLRS_C_lengte_01: 10 mm; NLRS_C_lengte_02: 2320 mm; NLRS_C_lengte_03: 960 mm; NLRS_C_lengte_04: 1300 mm; NLRS_C_lengte_05: 1440 mm; NLRS_C_lengte_06: 1620 mm; NLRS_C_lengte_07: 1800 mm; NLRS_C_lengte_08: 1960 mm; NLRS_C_lengte_09: 2130 mm; NLRS_C_lengte_10: 2280 mm
Type - Identity Data - Workset: Family : Generic Models : 29_DAT_Prefab betonnen waterslag lang; Description: Prefab beton raamdorpel; Manufacturer: NeHoBo; Model: RD; Type Comments: Prefab beton raamdorpel 131x270mm; Type Name: 22 eind
Type - Materials and Finishes - NLRS_C_materiaal: ISR_Beton_prefab
Type - Pset_ManufacturerTypeInformation - Manufacturer: NeHoBo
Type - Pset_ProductRequirements - Category: Generic Models
Pset_BuildingElementProxyCommon - Reference: 22 eind; sets with these values: 2
Pset_Generic Models - Family and Type: 29_DAT_Prefab betonnen waterslag lang: 22 eind; Omschrijving: Prefab beton raamdorpel; Type Comments: Prefab beton raamdorpel 131x270mm; Level: 1
Pset_DAT_KMS - Description: Prefab beton raamdorpel
Other - Family: 29_DAT_Prefab betonnen waterslag lang; Family and Type: 29_DAT_Prefab betonnen waterslag lang: 22 eind; Type: 22 eind; Type Id: 6867109
Constraints - Moves With Nearby Elements: no; Level: 1; Elevation from Level: 800 mm; Host: Level : 1; Offset from Host: 800 mm
Dimensions - Area: 1.42833 m2; Volume: 0.10638 m3
Identity Data - Workset: Bouwkundig
Phasing - Phase Created: 2. nieuwbouw

# IfcBuildingElementProxy: 29_DAT_Prefab betonnen waterslag lang:23, 29_DAT_Prefab betonnen waterslag lang:23:5537756
In: 01 eerste verdieping
Type - Material: ISR_Beton_prefab
Type - Other - Category: Generic Models; 01: yes; 02: yes; 03: no; 04: no; 05: no; 06: no; 07: no; 08: no; 09: no; 10: no; Family Name: 29_DAT_Prefab betonnen waterslag lang
Type - Constraints - Default Elevation: 0 mm
Type - Dimensions - NLRS_C_afstand: 2281 mm; NLRS_C_lengte_01: 10 mm; NLRS_C_lengte_02: 2134 mm; NLRS_C_lengte_03: 960 mm; NLRS_C_lengte_04: 1300 mm; NLRS_C_lengte_05: 1440 mm; NLRS_C_lengte_06: 1620 mm; NLRS_C_lengte_07: 1800 mm; NLRS_C_lengte_08: 1960 mm; NLRS_C_lengte_09: 2130 mm; NLRS_C_lengte_10: 2280 mm
Type - Identity Data - Workset: Family : Generic Models : 29_DAT_Prefab betonnen waterslag lang; Description: Prefab beton raamdorpel; Manufacturer: NeHoBo; Model: RD; Type Comments: Prefab beton raamdorpel 131x270mm; Type Name: 23
Type - Materials and Finishes - NLRS_C_materiaal: ISR_Beton_prefab
Type - Pset_ManufacturerTypeInformation - Manufacturer: NeHoBo
Type - Pset_ProductRequirements - Category: Generic Models
Pset_BuildingElementProxyCommon - Reference: 23; sets with these values: 2
Pset_Generic Models - Family and Type: 29_DAT_Prefab betonnen waterslag lang: 23; Omschrijving: Prefab beton raamdorpel; Type Comments: Prefab beton raamdorpel 131x270mm; Level: 1
Pset_DAT_KMS - Description: Prefab beton raamdorpel
Other - Family: 29_DAT_Prefab betonnen waterslag lang; Family and Type: 29_DAT_Prefab betonnen waterslag lang: 23; Type: 23; Type Id: 6865601
Constraints - Moves With Nearby Elements: no; Level: 1; Elevation from Level: 800 mm; Host: Level : 1; Offset from Host: 800 mm
Dimensions - Area: 1.34511 m2; Volume: 0.0988049 m3
Identity Data - Workset: Bouwkundig
Phasing - Phase Created: 2. nieuwbouw
Group: Model Group:K_Raamwerk_23:5537755
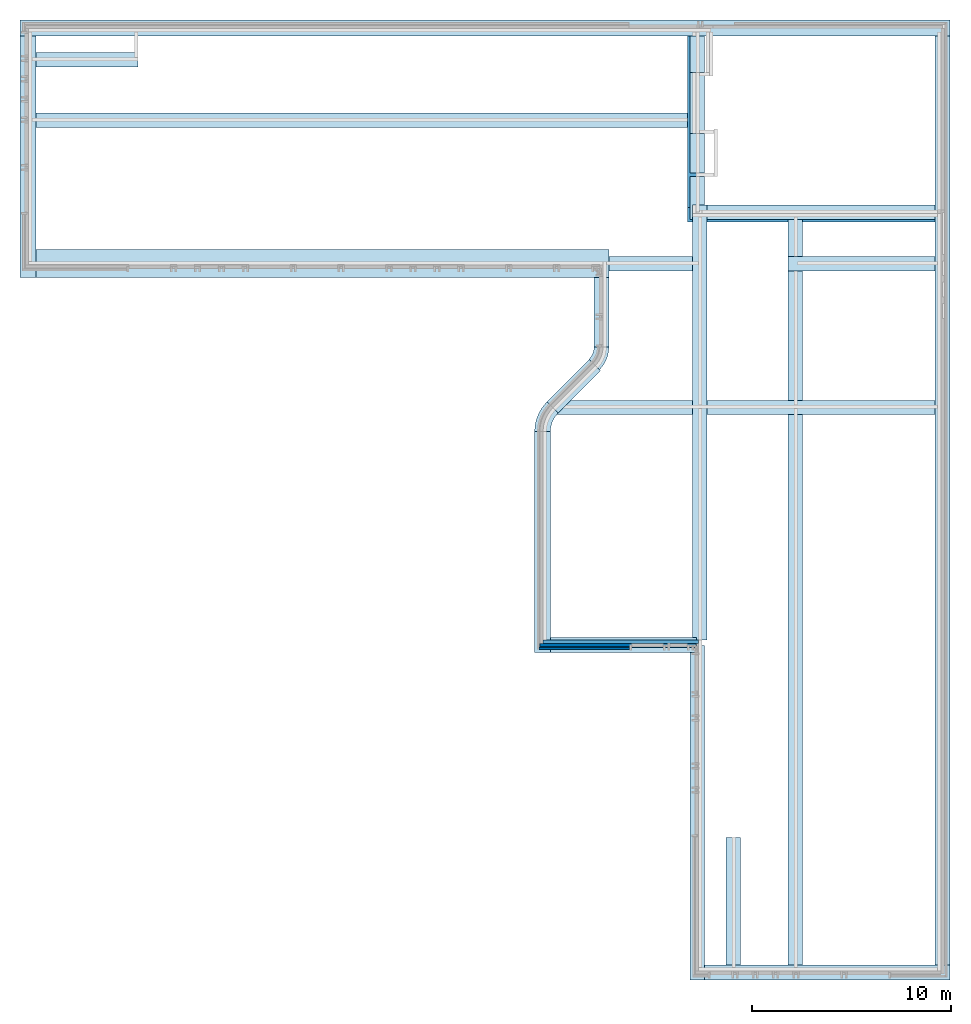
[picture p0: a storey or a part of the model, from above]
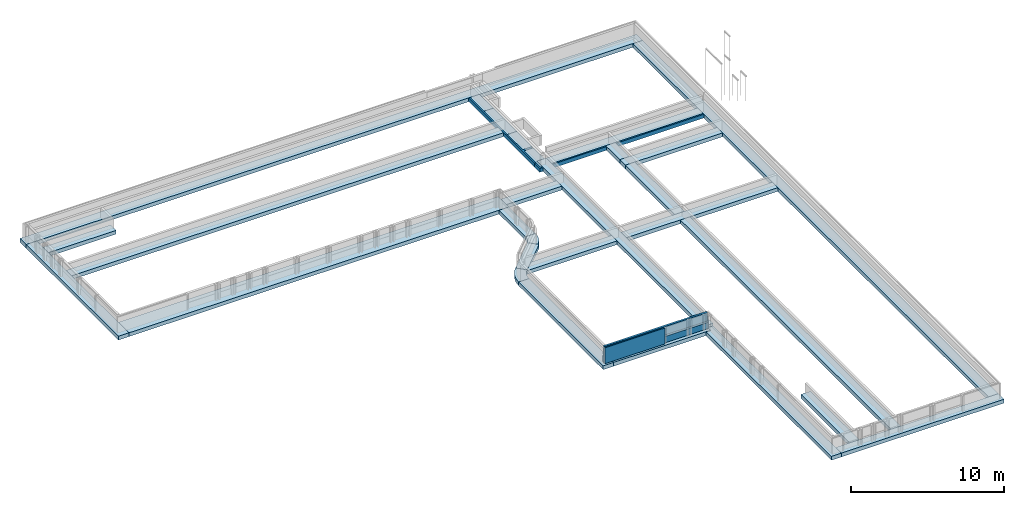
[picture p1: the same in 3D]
Properties of the parts of a building model (IFC2X3), part 5 of 37

# IfcBuildingElementProxy: 29_DAT_Prefab betonnen waterslag lang:25, 29_DAT_Prefab betonnen waterslag lang:25:5537970
In: 01 eerste verdieping
Type - Material: ISR_Beton_prefab
Type - Other - Category: Generic Models; 01: yes; 02: yes; 03: no; 04: no; 05: no; 06: no; 07: no; 08: no; 09: no; 10: no; Family Name: 29_DAT_Prefab betonnen waterslag lang
Type - Constraints - Default Elevation: 0 mm
Type - Dimensions - NLRS_C_afstand: 1362 mm; NLRS_C_lengte_01: 10 mm; NLRS_C_lengte_02: 1215 mm; NLRS_C_lengte_03: 960 mm; NLRS_C_lengte_04: 1300 mm; NLRS_C_lengte_05: 1440 mm; NLRS_C_lengte_06: 1620 mm; NLRS_C_lengte_07: 1800 mm; NLRS_C_lengte_08: 1960 mm; NLRS_C_lengte_09: 2130 mm; NLRS_C_lengte_10: 2280 mm
Type - Identity Data - Workset: Family : Generic Models : 29_DAT_Prefab betonnen waterslag lang; Description: Prefab beton raamdorpel; Manufacturer: NeHoBo; Model: RD; Type Comments: Prefab beton raamdorpel 131x270mm; Type Name: 25
Type - Materials and Finishes - NLRS_C_materiaal: ISR_Beton_prefab
Type - Pset_ManufacturerTypeInformation - Manufacturer: NeHoBo
Type - Pset_ProductRequirements - Category: Generic Models
Pset_BuildingElementProxyCommon - Reference: 25; sets with these values: 2
Pset_Generic Models - Family and Type: 29_DAT_Prefab betonnen waterslag lang: 25; Omschrijving: Prefab beton raamdorpel; Type Comments: Prefab beton raamdorpel 131x270mm; Level: 1
Pset_DAT_KMS - Description: Prefab beton raamdorpel
Other - Family: 29_DAT_Prefab betonnen waterslag lang; Family and Type: 29_DAT_Prefab betonnen waterslag lang: 25; Type: 25; Type Id: 6867348
Constraints - Moves With Nearby Elements: no; Level: 1; Elevation from Level: 800 mm; Host: Level : 1; Offset from Host: 800 mm
Dimensions - Area: 0.933955 m2; Volume: 0.061377 m3
Identity Data - Workset: Bouwkundig
Phasing - Phase Created: 2. nieuwbouw
Group: Model Group:K_Raamwerk_25:5537969

# IfcBuildingElementProxy: 29_DAT_Prefab betonnen waterslag lang:29 dubbel, 29_DAT_Prefab betonnen waterslag lang:29 dubbel:6857884
In: 01 eerste verdieping
Type - Material: ISR_Beton_prefab
Type - Other - Category: Generic Models; 01: yes; 02: yes; 05: no; 06: no; 07: no; 08: no; 09: no; 10: no; 03: yes; 04: yes; Family Name: 29_DAT_Prefab betonnen waterslag lang
Type - Constraints - Default Elevation: 0 mm
Type - Dimensions - NLRS_C_afstand: 2187 mm; NLRS_C_lengte_01: 120 mm; NLRS_C_lengte_02: 970 mm; NLRS_C_lengte_03: 1190 mm; NLRS_C_lengte_04: 2040 mm; NLRS_C_lengte_05: 1440 mm; NLRS_C_lengte_06: 1620 mm; NLRS_C_lengte_07: 1800 mm; NLRS_C_lengte_08: 1960 mm; NLRS_C_lengte_09: 2130 mm; NLRS_C_lengte_10: 2280 mm
Type - Identity Data - Workset: Family : Generic Models : 29_DAT_Prefab betonnen waterslag lang; Description: Prefab beton raamdorpel; Manufacturer: NeHoBo; Model: RD; Type Comments: Prefab beton raamdorpel 131x270mm; Type Name: 29 dubbel
Type - Materials and Finishes - NLRS_C_materiaal: ISR_Beton_prefab
Type - Pset_ManufacturerTypeInformation - Manufacturer: NeHoBo
Type - Pset_ProductRequirements - Category: Generic Models
Pset_BuildingElementProxyCommon - Reference: 29 dubbel; sets with these values: 2
Pset_Generic Models - Family and Type: 29_DAT_Prefab betonnen waterslag lang: 29 dubbel; Omschrijving: Prefab beton raamdorpel; Type Comments: Prefab beton raamdorpel 131x270mm; Level: 1
Pset_DAT_KMS - Description: Prefab beton raamdorpel
Other - Family: 29_DAT_Prefab betonnen waterslag lang; Family and Type: 29_DAT_Prefab betonnen waterslag lang: 29 dubbel; Type: 29 dubbel; Type Id: 6854009
Constraints - Moves With Nearby Elements: no; Level: 1; Elevation from Level: 800 mm; Host: Level : 1; Offset from Host: 800 mm
Dimensions - Area: 1.30306 m2; Volume: 0.0949765 m3
Identity Data - Workset: Bouwkundig
Phasing - Phase Created: 2. nieuwbouw
Group: Model Group:K_Raamwerk_29a:5537822

# IfcBuildingElementProxy: 29_DAT_Prefab betonnen waterslag lang:29 dubbel 1 (7)
In: 01 eerste verdieping
Type - Material: ISR_Beton_prefab
Type - Other - Category: Generic Models; 01: yes; 02: yes; 05: no; 06: no; 07: no; 08: no; 09: no; 10: no; 03: yes; 04: yes; Family Name: 29_DAT_Prefab betonnen waterslag lang
Type - Constraints - Default Elevation: 0 mm
Type - Dimensions - NLRS_C_afstand: 2134 mm; NLRS_C_lengte_01: 67 mm; NLRS_C_lengte_02: 917 mm; NLRS_C_lengte_03: 1137 mm; NLRS_C_lengte_04: 1987 mm; NLRS_C_lengte_05: 1387 mm; NLRS_C_lengte_06: 1620 mm; NLRS_C_lengte_07: 1800 mm; NLRS_C_lengte_08: 1960 mm; NLRS_C_lengte_09: 2130 mm; NLRS_C_lengte_10: 2280 mm
Type - Identity Data - Workset: Family : Generic Models : 29_DAT_Prefab betonnen waterslag lang; Description: Prefab beton raamdorpel; Manufacturer: NeHoBo; Model: RD; Type Comments: Prefab beton raamdorpel 131x270mm; Type Name: 29 dubbel 1
Type - Materials and Finishes - NLRS_C_materiaal: ISR_Beton_prefab
Type - Pset_ManufacturerTypeInformation - Manufacturer: NeHoBo
Type - Pset_ProductRequirements - Category: Generic Models
Pset_BuildingElementProxyCommon - Reference: 29 dubbel 1; sets with these values: 2
Pset_Generic Models - Family and Type: 29_DAT_Prefab betonnen waterslag lang: 29 dubbel 1; Omschrijving: Prefab beton raamdorpel; Type Comments: Prefab beton raamdorpel 131x270mm; Level: 1
Pset_DAT_KMS - Description: Prefab beton raamdorpel
Other - Family: 29_DAT_Prefab betonnen waterslag lang; Family and Type: 29_DAT_Prefab betonnen waterslag lang: 29 dubbel 1; Type: 29 dubbel 1; Type Id: 6866760
Constraints - Moves With Nearby Elements: no; Level: 1; Elevation from Level: 800 mm; Host: Level : 1; Offset from Host: 800 mm
Dimensions - Area: 1.27934 m2; Volume: 0.092818 m3
Identity Data - Workset: Bouwkundig
Phasing - Phase Created: 2. nieuwbouw
Name (29_DAT_Prefab betonnen waterslag lang:29 dubbel 1:...)
6656739
6658412
6658424
6660295
6660382
6660394
6866862

# IfcBuildingElementProxy: 29_DAT_Prefab betonnen waterslag lang:29 enkel, 29_DAT_Prefab betonnen waterslag lang:29 enkel:6659749
In: 01 eerste verdieping
Type - Material: ISR_Beton_prefab
Type - Other - Category: Generic Models; 01: yes; 02: yes; 03: no; 04: no; 05: no; 06: no; 07: no; 08: no; 09: no; 10: no; Family Name: 29_DAT_Prefab betonnen waterslag lang
Type - Constraints - Default Elevation: 0 mm
Type - Dimensions - NLRS_C_afstand: 1067 mm; NLRS_C_lengte_01: 67 mm; NLRS_C_lengte_02: 920 mm; NLRS_C_lengte_03: 1137 mm; NLRS_C_lengte_04: 1987 mm; NLRS_C_lengte_05: 1440 mm; NLRS_C_lengte_06: 1620 mm; NLRS_C_lengte_07: 1800 mm; NLRS_C_lengte_08: 1960 mm; NLRS_C_lengte_09: 2130 mm; NLRS_C_lengte_10: 2280 mm
Type - Identity Data - Workset: Family : Generic Models : 29_DAT_Prefab betonnen waterslag lang; Description: Prefab beton raamdorpel; Manufacturer: NeHoBo; Model: RD; Type Comments: Prefab beton raamdorpel 131x270mm; Type Name: 29 enkel
Type - Materials and Finishes - NLRS_C_materiaal: ISR_Beton_prefab
Type - Pset_ManufacturerTypeInformation - Manufacturer: NeHoBo
Type - Pset_ProductRequirements - Category: Generic Models
Pset_BuildingElementProxyCommon - Reference: 29 enkel; sets with these values: 2
Pset_Generic Models - Family and Type: 29_DAT_Prefab betonnen waterslag lang: 29 enkel; Omschrijving: Prefab beton raamdorpel; Type Comments: Prefab beton raamdorpel 131x270mm; Level: 1
Pset_DAT_KMS - Description: Prefab beton raamdorpel
Other - Family: 29_DAT_Prefab betonnen waterslag lang; Family and Type: 29_DAT_Prefab betonnen waterslag lang: 29 enkel; Type: 29 enkel; Type Id: 6857771
Constraints - Moves With Nearby Elements: no; Level: 1; Elevation from Level: 800 mm; Host: Level : 1; Offset from Host: 800 mm
Dimensions - Area: 0.801973 m2; Volume: 0.0493626 m3
Identity Data - Workset: Bouwkundig
Phasing - Phase Created: 2. nieuwbouw
Group: Model Group:Waterslag K29 Enkel:6659751

# IfcBuildingElementProxy: 29_DAT_Prefab betonnen waterslag lang:30, 29_DAT_Prefab betonnen waterslag lang:30:5537815
In: 01 eerste verdieping
Type - Material: ISR_Beton_prefab
Type - Other - Category: Generic Models; 01: yes; 02: yes; 03: no; 04: no; 05: no; 06: no; 07: no; 08: no; 09: no; 10: no; Family Name: 29_DAT_Prefab betonnen waterslag lang
Type - Constraints - Default Elevation: 0 mm
Type - Dimensions - NLRS_C_afstand: 1009 mm; NLRS_C_lengte_01: 10 mm; NLRS_C_lengte_02: 862 mm; NLRS_C_lengte_03: 960 mm; NLRS_C_lengte_04: 1300 mm; NLRS_C_lengte_05: 1440 mm; NLRS_C_lengte_06: 1620 mm; NLRS_C_lengte_07: 1800 mm; NLRS_C_lengte_08: 1960 mm; NLRS_C_lengte_09: 2130 mm; NLRS_C_lengte_10: 2280 mm
Type - Identity Data - Workset: Family : Generic Models : 29_DAT_Prefab betonnen waterslag lang; Description: Prefab beton raamdorpel; Manufacturer: NeHoBo; Model: RD; Type Comments: Prefab beton raamdorpel 131x270mm; Type Name: 30
Type - Materials and Finishes - NLRS_C_materiaal: ISR_Beton_prefab
Type - Pset_ManufacturerTypeInformation - Manufacturer: NeHoBo
Type - Pset_ProductRequirements - Category: Generic Models
Pset_BuildingElementProxyCommon - Reference: 30; sets with these values: 2
Pset_Generic Models - Family and Type: 29_DAT_Prefab betonnen waterslag lang: 30; Omschrijving: Prefab beton raamdorpel; Type Comments: Prefab beton raamdorpel 131x270mm; Level: 1
Pset_DAT_KMS - Description: Prefab beton raamdorpel
Other - Family: 29_DAT_Prefab betonnen waterslag lang; Family and Type: 29_DAT_Prefab betonnen waterslag lang: 30; Type: 30; Type Id: 6865634
Constraints - Moves With Nearby Elements: no; Level: 1; Elevation from Level: 800 mm; Host: Level : 1; Offset from Host: 800 mm
Dimensions - Area: 0.776024 m2; Volume: 0.0470005 m3
Identity Data - Workset: Bouwkundig
Phasing - Phase Created: 2. nieuwbouw
Group: Model Group:K_Raamwerk_30:5537736

# IfcBuildingElementProxy: 29_DAT_Prefab dakoverstek:29_DAT_Prefab dakoverstek, 29_DAT_Prefab dakoverstek:29_DAT_Prefab dakoverstek:5537557
In: 00 Begane grond
Type - Material: STAAL_RAL 7006
Type - Other - Category: Generic Models; Family Name: 29_DAT_Prefab dakoverstek
Type - Constraints - Default Elevation: 0 mm
Type - Identity Data - Description: Luifel in Ral: 7006; Manufacturer: NeHoBo; Model: SB afgeschuind; Type Name: 29_DAT_Prefab dakoverstek; Workset: Family : Generic Models : 29_DAT_Prefab dakoverstek
Type - Materials and Finishes - NLRS_C_materiaal: STAAL_RAL 7006
Type - Pset_ManufacturerTypeInformation - Manufacturer: NeHoBo
Type - Pset_ProductRequirements - Category: Generic Models
Pset_BuildingElementProxyCommon - Reference: 29_DAT_Prefab dakoverstek; sets with these values: 2
Pset_Generic Models - Family and Type: 29_DAT_Prefab dakoverstek: 29_DAT_Prefab dakoverstek; Omschrijving: Luifel in Ral: 7006; Level: 0
Pset_DAT_KMS - Description: Luifel in Ral: 7006
Other - Family: 29_DAT_Prefab dakoverstek; Family and Type: 29_DAT_Prefab dakoverstek: 29_DAT_Prefab dakoverstek; Type: 29_DAT_Prefab dakoverstek; Type Id: 4914482
Constraints - Level: 0; Moves With Nearby Elements: no; Elevation from Level: 2762.5 mm; Host: Level : 0; Offset from Host: 2762.5 mm
Dimensions - Area: 7.66093 m2; NLRS_C_afstand: 6385 mm; Volume: 1.0408 m3
Identity Data - Workset: Bouwkundig
Phasing - Phase Created: 2. nieuwbouw

# IfcBuildingElementProxy: 29_dat_hoek Dakplaat:29_dat_hoek Dakplaat, 29_dat_hoek Dakplaat:29_dat_hoek Dakplaat:4999344
In: 01 eerste verdieping
Type - Material: ISR_Beton_prefab
Type - Other - Category: Generic Models; Family Name: 29_dat_hoek Dakplaat
Type - Constraints - Default Elevation: 0 mm
Type - Identity Data - Description: Prefab beton afdekplaat; Type Name: 29_dat_hoek Dakplaat; Workset: Family : Generic Models : 29_dat_hoek Dakplaat
Type - Materials and Finishes - Materiaal: ISR_Beton_prefab
Type - Pset_ProductRequirements - Category: Generic Models
Pset_BuildingElementProxyCommon - Reference: 29_dat_hoek Dakplaat; sets with these values: 2
Pset_Generic Models - Family and Type: 29_dat_hoek Dakplaat: 29_dat_hoek Dakplaat; Omschrijving: Prefab beton afdekplaat; Level: 1
Pset_DAT_KMS - Description: Prefab beton afdekplaat
Other - Family: 29_dat_hoek Dakplaat; Family and Type: 29_dat_hoek Dakplaat: 29_dat_hoek Dakplaat; Type: 29_dat_hoek Dakplaat; Type Id: 4999328
Constraints - Moves With Nearby Elements: no; Level: 1; Elevation from Level: 800 mm; Host: Level : 1; Offset from Host: 800 mm
Dimensions - Area: 0.776503 m2; Volume: 0.0831508 m3
Identity Data - Workset: Bouwkundig
Phasing - Phase Created: 2. nieuwbouw

# IfcBuildingElementProxy: 300_74_DAT_toiletbeugel_MiVa:300_74_DAT_toiletbeugel_MiVa (2)
In: 0.18
Type - Material: <Unnamed>
Type - Other - Category: Generic Models; Family Name: 300_74_DAT_toiletbeugel_MiVa
Type - Constraints - Default Elevation: 0 mm
Type - Dimensions - bovenzijde beugel t.o.v. vloerpeil: 700 mm
Type - Identity Data - Type Name: 300_74_DAT_toiletbeugel_MiVa; Workset: Family : Generic Models : 300_74_DAT_toiletbeugel_MiVa
Type - Pset_ProductRequirements - Category: Generic Models
Pset_BuildingElementProxyCommon - Reference: 300_74_DAT_toiletbeugel_MiVa; sets with these values: 2
Pset_Generic Models - Family and Type: 300_74_DAT_toiletbeugel_MiVa: 300_74_DAT_toiletbeugel_MiVa; Level: 0
Other - Family: 300_74_DAT_toiletbeugel_MiVa; Family and Type: 300_74_DAT_toiletbeugel_MiVa: 300_74_DAT_toiletbeugel_MiVa; Type: 300_74_DAT_toiletbeugel_MiVa; Type Id: 5136540
Constraints - Elevation from Level: 0 mm; Level: 0; Moves With Nearby Elements: no; Offset from Host: 0 mm; Host: Level : 0
Dimensions - Area: 0.124212 m2; Volume: 0.00187079 m3
Identity Data - Workset: Bouwkundig
Phasing - Phase Created: 2. nieuwbouw
Name (300_74_DAT_toiletbeugel_MiVa:300_74_DAT_toiletbeugel_MiVa:...)
5136438
5136439

# IfcBuildingElementProxy: 300_90_ISR_boom:12500_Scarlet Oak (3)
In: 00 Begane grond
Type - Material: x_Situatie_Boom
Type - Other - Category: Planting; Family Name: 300_90_ISR_boom
Type - Constraints - Default Elevation: 0 mm
Type - Dimensions - Height: 12500 mm
Type - Graphics - basis_01: no; basis_02: no; basis_03: no; basis_04: no; basis_05: no; basis_07: no; basis_08: no; basis_09: no; basis_10: no; basis_12: no; basis_13: no; basis_06: no; basis_11: yes
Type - Identity Data - Workset: Family : Planting : 300_90_ISR_boom; Datum_Gewijzigd: 20110418; Render Appearance: RPC-16-G0FB-J5PX-0LX6-U000-ST1L-LVER-AU; Render Appearance Properties: {2, 15},{39, RPC-16-G0FB-J5PX-0LX6-U000-ST1L-LVER-AU},{1, 0},{1, 0},{2, 13},{1, 8},{5, Color},{1, 0},{1, 0},{3, 0.8},{3, 0.8},{3, 0.8},{1, 8},{7, BBoxMin},{1, 0},{1, 0},{1, 0},{1, 0},{1, 0},{1, 8},{7, BBoxMax},{1, 0},{1, 0},{1, 0},{1, 0},{1, 0},{2, 11},{9, RPCTypeId},{1, 0},{1, 0},{39, RPC-16-G0FB-J5PX-0LX6-U000-ST1L-LVER-AU},{1, 6},{14, RPCPlantHeight},{1, 0},{1, 0},{7, 41.0105},{2, 11},{7, keyword},{1, 0},{1, 0},{34, :RPCs:Trees [General]:Geometry:RPC},{2, 11},{8, category},{1, 0},{1, 0},{15, Trees [General]},{2, 11},{12, LocalizedUID},{1, 0},{1, 0},{11, Scarlet_Oak},{2, 14},{6, Height},{1, 0},{1, 0},{7, 41.0105},{1, 2},{16, Cast Reflections},{1, 0},{1, 0},{1, 0},{1, 2},{12, Cast Shadows},{1, 0},{1, 0},{1, 1},{1, 2},{9, Lock View},{1, 0},{1, 0},{1, 0},{1, 4},{5, ViewC},{1, 0},{1, 0},{1, 0},{21, assetlibrary_base.fbx},{1, 5},; SmartRevit_Versie: 2012.1; Type Comments: Scarlet Oak; Type Name: 12500_Scarlet Oak
Type - Pset_ProductRequirements - Category: Planting
Type - Pset_ProvisionForVoid - Height: 12500 mm
Pset_BuildingElementProxyCommon - Reference: 12500_Scarlet Oak; sets with these values: 2
Other - Family: 300_90_ISR_boom; Family and Type: 300_90_ISR_boom: 12500_Scarlet Oak; Type: 12500_Scarlet Oak; Type Id: 3890071
Constraints - Level: 0; Moves With Nearby Elements: no; Offset from Host: 0 mm
Dimensions - Area: 1762.93 m2; Volume: 5534.82 m3
Identity Data - Workset: Bouwkundig
Phasing - Phase Created: 2. nieuwbouw
Name (300_90_ISR_boom:12500_Scarlet Oak:...) | Elevation from Level (mm) | Host
5766061 | 0 | Level : 0
5766134 | -30 | Toposolid : Toposolid 1
6654332 | 0 | Level : 0

# IfcBuildingElementProxy: 300_90_ISR_boom:14500_Scarlet Oak (3)
In: 00 Begane grond
Type - Material: x_Situatie_Boom
Type - Other - Category: Planting; Family Name: 300_90_ISR_boom
Type - Constraints - Default Elevation: 0 mm
Type - Dimensions - Height: 14500 mm
Type - Graphics - basis_01: no; basis_02: no; basis_03: no; basis_04: no; basis_05: no; basis_07: no; basis_08: no; basis_09: no; basis_10: no; basis_12: no; basis_13: no; basis_06: no; basis_11: yes
Type - Identity Data - Workset: Family : Planting : 300_90_ISR_boom; Datum_Gewijzigd: 20110418; Render Appearance: RPC-16-G0FB-J5PX-0LX6-U000-ST1L-LVER-AU; Render Appearance Properties: {2, 15},{39, RPC-16-G0FB-J5PX-0LX6-U000-ST1L-LVER-AU},{1, 0},{1, 0},{2, 13},{1, 8},{5, Color},{1, 0},{1, 0},{3, 0.8},{3, 0.8},{3, 0.8},{1, 8},{7, BBoxMin},{1, 0},{1, 0},{1, 0},{1, 0},{1, 0},{1, 8},{7, BBoxMax},{1, 0},{1, 0},{1, 0},{1, 0},{1, 0},{2, 11},{9, RPCTypeId},{1, 0},{1, 0},{39, RPC-16-G0FB-J5PX-0LX6-U000-ST1L-LVER-AU},{1, 6},{14, RPCPlantHeight},{1, 0},{1, 0},{7, 41.0105},{2, 11},{7, keyword},{1, 0},{1, 0},{34, :RPCs:Trees [General]:Geometry:RPC},{2, 11},{8, category},{1, 0},{1, 0},{15, Trees [General]},{2, 11},{12, LocalizedUID},{1, 0},{1, 0},{11, Scarlet_Oak},{2, 14},{6, Height},{1, 0},{1, 0},{7, 41.0105},{1, 2},{16, Cast Reflections},{1, 0},{1, 0},{1, 0},{1, 2},{12, Cast Shadows},{1, 0},{1, 0},{1, 1},{1, 2},{9, Lock View},{1, 0},{1, 0},{1, 0},{1, 4},{5, ViewC},{1, 0},{1, 0},{1, 0},{21, assetlibrary_base.fbx},{1, 5},; SmartRevit_Versie: 2012.1; Type Comments: Scarlet Oak; Type Name: 14500_Scarlet Oak
Type - Pset_ProductRequirements - Category: Planting
Type - Pset_ProvisionForVoid - Height: 14500 mm
Pset_BuildingElementProxyCommon - Reference: 14500_Scarlet Oak; sets with these values: 2
Other - Family: 300_90_ISR_boom; Family and Type: 300_90_ISR_boom: 14500_Scarlet Oak; Type: 14500_Scarlet Oak; Type Id: 6651911
Constraints - Level: 0; Moves With Nearby Elements: no; Offset from Host: 0 mm
Dimensions - Area: 2348.19 m2; Volume: 8503.98 m3
Identity Data - Workset: Bouwkundig
Phasing - Phase Created: 2. nieuwbouw
Name (300_90_ISR_boom:14500_Scarlet Oak:...) | Elevation from Level (mm) | Host
5766041 | -10 | Sub-Division
6654128 | -30 | Toposolid : Toposolid 1
6654300 | -30 | Toposolid : Toposolid 1

# IfcBuildingElementProxy: 300_90_ISR_boom:3000_Japanese Maple (5)
In: 00 Begane grond
Type - Material: x_Situatie_Boom
Type - Other - Category: Planting; Family Name: 300_90_ISR_boom
Type - Constraints - Default Elevation: 0 mm
Type - Dimensions - Height: 3000 mm
Type - Graphics - basis_01: no; basis_03: no; basis_04: no; basis_05: no; basis_07: no; basis_08: no; basis_09: no; basis_10: no; basis_11: no; basis_12: no; basis_13: no; basis_06: no; basis_02: yes
Type - Identity Data - Workset: Family : Planting : 300_90_ISR_boom; Datum_Gewijzigd: 20110418; Render Appearance: RPC-16-G1GU-4F80-7PP2-A000-ST1L-LVER-AU; Render Appearance Properties: {2, 15},{39, RPC-16-G1GU-4F80-7PP2-A000-ST1L-LVER-AU},{1, 0},{1, 0},{2, 18},{1, 8},{5, Color},{1, 0},{1, 0},{3, 0.8},{3, 0.8},{3, 0.8},{1, 8},{7, BBoxMin},{1, 0},{1, 0},{1, 0},{1, 0},{1, 0},{1, 8},{7, BBoxMax},{1, 0},{1, 0},{1, 0},{1, 0},{1, 0},{2, 11},{9, RPCTypeId},{1, 0},{1, 0},{39, RPC-16-G1GU-4F80-7PP2-A000-ST1L-LVER-AU},{1, 6},{14, RPCPlantHeight},{1, 0},{1, 0},{7, 9.84252},{2, 11},{7, keyword},{1, 0},{1, 0},{34, :RPCs:Trees [General]:Geometry:RPC},{2, 11},{8, category},{1, 0},{1, 0},{15, Trees [General]},{2, 11},{12, LocalizedUID},{1, 0},{1, 0},{14, Japanese Maple},{2, 14},{6, Height},{1, 0},{1, 0},{7, 9.84252},{1, 2},{16, Cast Reflections},{1, 0},{1, 0},{1, 0},{1, 2},{12, Cast Shadows},{1, 0},{1, 0},{1, 1},{1, 2},{9, Lock View},{1, 0},{1, 0},{1, 0},{1, 4},{5, ViewC},{1, 0},{1, 0},{1, 0},{1, 2},{20, RPC_Cast Reflections},{1, 0},{1, 0},{1, 0},{1, 2},{16, RPC_Cast Shadows},{1, 0},{1, 0},{1, 1},{1, 2},{13, RPC_Lock View},{1, 0},{1, 0},{1, 0},{1, 4},{9, RPC_ViewC},{1, 0},{1, 0},{1, 0},{2, 11},{11, RPCFilePath},{1, 0},{1, 0},{124, C:\Program Files\Common Files\Autodesk Shared\Materials\4\assetlibrary_base.fbm\RPCs\ArchVision_Stills_T5_Japanese_Maple.rpc},{21, assetlibrary_base.fbx},{1, 5},; SmartRevit_Versie: 2012.1; Type Comments: Japanese Maple; Type Name: 3000_Japanese Maple
Type - Materials and Finishes - materiaal: x_Situatie_Boom
Type - Pset_ProductRequirements - Category: Planting
Type - Pset_ProvisionForVoid - Height: 3000 mm
Pset_BuildingElementProxyCommon - Reference: 3000_Japanese Maple; sets with these values: 2
Other - Family: 300_90_ISR_boom; Family and Type: 300_90_ISR_boom: 3000_Japanese Maple; Type: 3000_Japanese Maple; Type Id: 3890101
Constraints - Level: 0; Moves With Nearby Elements: no; Offset from Host: 0 mm; Elevation from Level: -30 mm; Host: Toposolid : Toposolid 1
Dimensions - Area: 100.517 m2; Volume: 75.3151 m3
Identity Data - Workset: Bouwkundig
Phasing - Phase Created: 2. nieuwbouw
Name (300_90_ISR_boom:3000_Japanese Maple:...)
5767900
6649112
6649277
6649442
6649607

# IfcBuildingElementProxy: 300_90_ISR_boom:6000_Comman Apple (32)
In: 00 Begane grond
Type - Material: x_Situatie_Boom
Type - Other - Category: Planting; Family Name: 300_90_ISR_boom
Type - Constraints - Default Elevation: 0 mm
Type - Dimensions - Height: 6000 mm
Type - Graphics - basis_01: no; basis_02: no; basis_03: no; basis_04: no; basis_07: no; basis_08: no; basis_09: no; basis_10: no; basis_11: no; basis_12: no; basis_13: no; basis_06: no; basis_05: yes
Type - Identity Data - Workset: Family : Planting : 300_90_ISR_boom; Datum_Gewijzigd: 20110418; Render Appearance: RPC-16-FXGK-4KXX-PJE5-6000-ST1L-LVER-AU; Render Appearance Properties: {2, 15},{39, RPC-16-FXGK-4KXX-PJE5-6000-ST1L-LVER-AU},{1, 0},{1, 0},{2, 13},{1, 8},{5, Color},{1, 0},{1, 0},{3, 0.8},{3, 0.8},{3, 0.8},{1, 8},{7, BBoxMin},{1, 0},{1, 0},{1, 0},{1, 0},{1, 0},{1, 8},{7, BBoxMax},{1, 0},{1, 0},{1, 0},{1, 0},{1, 0},{2, 11},{9, RPCTypeId},{1, 0},{1, 0},{39, RPC-16-FXGK-4KXX-PJE5-6000-ST1L-LVER-AU},{1, 6},{14, RPCPlantHeight},{1, 0},{1, 0},{6, 19.685},{2, 11},{7, keyword},{1, 0},{1, 0},{34, :RPCs:Trees [General]:Geometry:RPC},{2, 11},{8, category},{1, 0},{1, 0},{15, Trees [General]},{2, 11},{12, LocalizedUID},{1, 0},{1, 0},{12, Common Apple},{2, 14},{6, Height},{1, 0},{1, 0},{6, 19.685},{1, 2},{16, Cast Reflections},{1, 0},{1, 0},{1, 0},{1, 2},{12, Cast Shadows},{1, 0},{1, 0},{1, 1},{1, 2},{9, Lock View},{1, 0},{1, 0},{1, 0},{1, 4},{5, ViewC},{1, 0},{1, 0},{1, 0},{21, assetlibrary_base.fbx},{1, 5},; SmartRevit_Versie: 2012.1; Type Comments: Comman Apple; Type Name: 6000_Comman Apple
Type - Materials and Finishes - materiaal: x_Situatie_Boom
Type - Pset_ProductRequirements - Category: Planting
Type - Pset_ProvisionForVoid - Height: 6000 mm
Pset_BuildingElementProxyCommon - Reference: 6000_Comman Apple; sets with these values: 2
Other - Family: 300_90_ISR_boom; Family and Type: 300_90_ISR_boom: 6000_Comman Apple; Type: 6000_Comman Apple; Type Id: 3890091
Constraints - Level: 0; Moves With Nearby Elements: no; Offset from Host: 0 mm
Dimensions - Area: 407.947 m2; Volume: 615.022 m3
Identity Data - Workset: Bouwkundig
Phasing - Phase Created: 2. nieuwbouw
Name (300_90_ISR_boom:6000_Comman Apple:...) | Elevation from Level (mm) | Host
5766050 | -10 | Sub-Division
5766053 | -10 | Sub-Division
5766078 | 0 | Level : 0
5766081 | 0 | Level : 0
5766087 | 0 | Level : 0
5766106 | 0 | Level : 0
5766634 | -30 | Toposolid : Toposolid 1
5768065 | -30 | Toposolid : Toposolid 1
5768230 | -30 | Toposolid : Toposolid 1
5768395 | -30 | Toposolid : Toposolid 1
5768560 | -30 | Toposolid : Toposolid 1
5769055 | -30 | Toposolid : Toposolid 1
5770212 | -30 | Toposolid : Toposolid 1
5770377 | -30 | Toposolid : Toposolid 1
5770872 | -30 | Toposolid : Toposolid 1
5771367 | -30 | Toposolid : Toposolid 1
5771866 | -30 | Toposolid : Toposolid 1
5772033 | -30 | Toposolid : Toposolid 1
5772198 | -30 | Toposolid : Toposolid 1
5772363 | -30 | Toposolid : Toposolid 1
5772528 | -30 | Toposolid : Toposolid 1
5772899 | -30 | Toposolid : Toposolid 1
5819498 | -30 | Toposolid : Toposolid 1
5819663 | -30 | Toposolid : Toposolid 1
5819828 | -30 | Toposolid : Toposolid 1
5820077 | -30 | Toposolid : Toposolid 1
5820242 | -30 | Toposolid : Toposolid 1
6652303 | -30 | Toposolid : Toposolid 1
6652477 | -30 | Toposolid : Toposolid 1
6652644 | -30 | Toposolid : Toposolid 1
6652809 | -30 | Toposolid : Toposolid 1
6652974 | -30 | Toposolid : Toposolid 1

# IfcBuildingElementProxy: 300_90_ISR_boom:6000_Comman Apple 3000 (9)
In: 00 Begane grond
Type - Material: x_Situatie_Boom
Type - Other - Category: Planting; Family Name: 300_90_ISR_boom
Type - Constraints - Default Elevation: 0 mm
Type - Dimensions - Height: 4000 mm
Type - Graphics - basis_01: no; basis_02: no; basis_03: no; basis_04: no; basis_07: no; basis_08: no; basis_09: no; basis_10: no; basis_11: no; basis_12: no; basis_13: no; basis_06: no; basis_05: yes
Type - Identity Data - Workset: Family : Planting : 300_90_ISR_boom; Datum_Gewijzigd: 20110418; Render Appearance: RPC-16-FXGK-4KXX-PJE5-6000-ST1L-LVER-AU; Render Appearance Properties: {2, 15},{39, RPC-16-FXGK-4KXX-PJE5-6000-ST1L-LVER-AU},{1, 0},{1, 0},{2, 13},{1, 8},{5, Color},{1, 0},{1, 0},{3, 0.8},{3, 0.8},{3, 0.8},{1, 8},{7, BBoxMin},{1, 0},{1, 0},{1, 0},{1, 0},{1, 0},{1, 8},{7, BBoxMax},{1, 0},{1, 0},{1, 0},{1, 0},{1, 0},{2, 11},{9, RPCTypeId},{1, 0},{1, 0},{39, RPC-16-FXGK-4KXX-PJE5-6000-ST1L-LVER-AU},{1, 6},{14, RPCPlantHeight},{1, 0},{1, 0},{6, 19.685},{2, 11},{7, keyword},{1, 0},{1, 0},{34, :RPCs:Trees [General]:Geometry:RPC},{2, 11},{8, category},{1, 0},{1, 0},{15, Trees [General]},{2, 11},{12, LocalizedUID},{1, 0},{1, 0},{12, Common Apple},{2, 14},{6, Height},{1, 0},{1, 0},{6, 19.685},{1, 2},{16, Cast Reflections},{1, 0},{1, 0},{1, 0},{1, 2},{12, Cast Shadows},{1, 0},{1, 0},{1, 1},{1, 2},{9, Lock View},{1, 0},{1, 0},{1, 0},{1, 4},{5, ViewC},{1, 0},{1, 0},{1, 0},{21, assetlibrary_base.fbx},{1, 5},; SmartRevit_Versie: 2012.1; Type Comments: Comman Apple; Type Name: 6000_Comman Apple 3000
Type - Materials and Finishes - materiaal: x_Situatie_Boom
Type - Pset_ProductRequirements - Category: Planting
Type - Pset_ProvisionForVoid - Height: 4000 mm
Pset_BuildingElementProxyCommon - Reference: 6000_Comman Apple 3000; sets with these values: 2
Other - Family: 300_90_ISR_boom; Family and Type: 300_90_ISR_boom: 6000_Comman Apple 3000; Type: 6000_Comman Apple 3000; Type Id: 6650176
Constraints - Level: 0; Moves With Nearby Elements: no; Offset from Host: 0 mm; Elevation from Level: -30 mm; Host: Toposolid : Toposolid 1
Dimensions - Area: 178.697 m2; Volume: 178.525 m3
Identity Data - Workset: Bouwkundig
Phasing - Phase Created: 2. nieuwbouw
Name (300_90_ISR_boom:6000_Comman Apple 3000:...)
5768890
5769715
5771037
5771202
5771532
5771697
6650153
6650421
6650962

# IfcBuildingElementProxy: 300_90_ISR_boom:6000_Comman Apple 5000 (5)
In: 00 Begane grond
Type - Material: x_Situatie_Boom
Type - Other - Category: Planting; Family Name: 300_90_ISR_boom
Type - Constraints - Default Elevation: 0 mm
Type - Dimensions - Height: 5000 mm
Type - Graphics - basis_01: no; basis_02: no; basis_03: no; basis_04: no; basis_07: no; basis_08: no; basis_09: no; basis_10: no; basis_11: no; basis_12: no; basis_13: no; basis_06: no; basis_05: yes
Type - Identity Data - Workset: Family : Planting : 300_90_ISR_boom; Datum_Gewijzigd: 20110418; Render Appearance: RPC-16-FXGK-4KXX-PJE5-6000-ST1L-LVER-AU; Render Appearance Properties: {2, 15},{39, RPC-16-FXGK-4KXX-PJE5-6000-ST1L-LVER-AU},{1, 0},{1, 0},{2, 13},{1, 8},{5, Color},{1, 0},{1, 0},{3, 0.8},{3, 0.8},{3, 0.8},{1, 8},{7, BBoxMin},{1, 0},{1, 0},{1, 0},{1, 0},{1, 0},{1, 8},{7, BBoxMax},{1, 0},{1, 0},{1, 0},{1, 0},{1, 0},{2, 11},{9, RPCTypeId},{1, 0},{1, 0},{39, RPC-16-FXGK-4KXX-PJE5-6000-ST1L-LVER-AU},{1, 6},{14, RPCPlantHeight},{1, 0},{1, 0},{6, 19.685},{2, 11},{7, keyword},{1, 0},{1, 0},{34, :RPCs:Trees [General]:Geometry:RPC},{2, 11},{8, category},{1, 0},{1, 0},{15, Trees [General]},{2, 11},{12, LocalizedUID},{1, 0},{1, 0},{12, Common Apple},{2, 14},{6, Height},{1, 0},{1, 0},{6, 19.685},{1, 2},{16, Cast Reflections},{1, 0},{1, 0},{1, 0},{1, 2},{12, Cast Shadows},{1, 0},{1, 0},{1, 1},{1, 2},{9, Lock View},{1, 0},{1, 0},{1, 0},{1, 4},{5, ViewC},{1, 0},{1, 0},{1, 0},{21, assetlibrary_base.fbx},{1, 5},; SmartRevit_Versie: 2012.1; Type Comments: Comman Apple; Type Name: 6000_Comman Apple 5000
Type - Materials and Finishes - materiaal: x_Situatie_Boom
Type - Pset_ProductRequirements - Category: Planting
Type - Pset_ProvisionForVoid - Height: 5000 mm
Pset_BuildingElementProxyCommon - Reference: 6000_Comman Apple 5000; sets with these values: 2
Other - Family: 300_90_ISR_boom; Family and Type: 300_90_ISR_boom: 6000_Comman Apple 5000; Type: 6000_Comman Apple 5000; Type Id: 6649732
Constraints - Level: 0; Moves With Nearby Elements: no; Offset from Host: 0 mm
Dimensions - Area: 279.214 m2; Volume: 348.681 m3
Identity Data - Workset: Bouwkundig
Phasing - Phase Created: 2. nieuwbouw
Name (300_90_ISR_boom:6000_Comman Apple 5000:...) | Elevation from Level (mm) | Host
5766084 | 0 | Level : 0
5769880 | -30 | Toposolid : Toposolid 1
6649986 | -30 | Toposolid : Toposolid 1
6653564 | -30 | Toposolid : Toposolid 1
6653746 | -30 | Toposolid : Toposolid 1

# IfcBuildingElementProxy: 300_90_ISR_boom:6000_Comman Apple 7000 (2)
In: 00 Begane grond
Type - Material: x_Situatie_Boom
Type - Other - Category: Planting; Family Name: 300_90_ISR_boom
Type - Constraints - Default Elevation: 0 mm
Type - Dimensions - Height: 7000 mm
Type - Graphics - basis_01: no; basis_02: no; basis_03: no; basis_04: no; basis_07: no; basis_08: no; basis_09: no; basis_10: no; basis_11: no; basis_12: no; basis_13: no; basis_06: no; basis_05: yes
Type - Identity Data - Workset: Family : Planting : 300_90_ISR_boom; Datum_Gewijzigd: 20110418; Render Appearance: RPC-16-FXGK-4KXX-PJE5-6000-ST1L-LVER-AU; Render Appearance Properties: {2, 15},{39, RPC-16-FXGK-4KXX-PJE5-6000-ST1L-LVER-AU},{1, 0},{1, 0},{2, 13},{1, 8},{5, Color},{1, 0},{1, 0},{3, 0.8},{3, 0.8},{3, 0.8},{1, 8},{7, BBoxMin},{1, 0},{1, 0},{1, 0},{1, 0},{1, 0},{1, 8},{7, BBoxMax},{1, 0},{1, 0},{1, 0},{1, 0},{1, 0},{2, 11},{9, RPCTypeId},{1, 0},{1, 0},{39, RPC-16-FXGK-4KXX-PJE5-6000-ST1L-LVER-AU},{1, 6},{14, RPCPlantHeight},{1, 0},{1, 0},{6, 19.685},{2, 11},{7, keyword},{1, 0},{1, 0},{34, :RPCs:Trees [General]:Geometry:RPC},{2, 11},{8, category},{1, 0},{1, 0},{15, Trees [General]},{2, 11},{12, LocalizedUID},{1, 0},{1, 0},{12, Common Apple},{2, 14},{6, Height},{1, 0},{1, 0},{6, 19.685},{1, 2},{16, Cast Reflections},{1, 0},{1, 0},{1, 0},{1, 2},{12, Cast Shadows},{1, 0},{1, 0},{1, 1},{1, 2},{9, Lock View},{1, 0},{1, 0},{1, 0},{1, 4},{5, ViewC},{1, 0},{1, 0},{1, 0},{21, assetlibrary_base.fbx},{1, 5},; SmartRevit_Versie: 2012.1; Type Comments: Comman Apple; Type Name: 6000_Comman Apple 7000
Type - Materials and Finishes - materiaal: x_Situatie_Boom
Type - Pset_ProductRequirements - Category: Planting
Type - Pset_ProvisionForVoid - Height: 7000 mm
Pset_BuildingElementProxyCommon - Reference: 6000_Comman Apple 7000; sets with these values: 2
Other - Family: 300_90_ISR_boom; Family and Type: 300_90_ISR_boom: 6000_Comman Apple 7000; Type: 6000_Comman Apple 7000; Type Id: 6651169
Constraints - Level: 0; Moves With Nearby Elements: no; Offset from Host: 0 mm
Dimensions - Area: 555.064 m2; Volume: 979.363 m3
Identity Data - Workset: Bouwkundig
Phasing - Phase Created: 2. nieuwbouw
Name (300_90_ISR_boom:6000_Comman Apple 7000:...) | Elevation from Level (mm) | Host
5766109 | 0 | Level : 0
5770045 | -30 | Toposolid : Toposolid 1

# IfcBuildingElementProxy: 300_90_ISR_boom:9000_Red Maple, 300_90_ISR_boom:9000_Red Maple:5772693
In: 00 Begane grond
Type - Material: x_Situatie_Boom
Type - Other - Category: Planting; Family Name: 300_90_ISR_boom
Type - Constraints - Default Elevation: 0 mm
Type - Dimensions - Height: 9000 mm
Type - Graphics - basis_01: no; basis_02: no; basis_03: no; basis_04: no; basis_05: no; basis_08: no; basis_09: no; basis_10: no; basis_11: no; basis_12: no; basis_13: no; basis_06: no; basis_07: yes
Type - Identity Data - Workset: Family : Planting : 300_90_ISR_boom; Datum_Gewijzigd: 20110418; Render Appearance: RPC-16-G0SR-83PX-Q347-6000-ST1L-LVER-AU; Render Appearance Properties: {2, 15},{39, RPC-16-G0SR-83PX-Q347-6000-ST1L-LVER-AU},{1, 0},{1, 0},{2, 13},{1, 8},{5, Color},{1, 0},{1, 0},{3, 0.8},{3, 0.8},{3, 0.8},{1, 8},{7, BBoxMin},{1, 0},{1, 0},{1, 0},{1, 0},{1, 0},{1, 8},{7, BBoxMax},{1, 0},{1, 0},{1, 0},{1, 0},{1, 0},{2, 11},{9, RPCTypeId},{1, 0},{1, 0},{39, RPC-16-G0SR-83PX-Q347-6000-ST1L-LVER-AU},{1, 6},{14, RPCPlantHeight},{1, 0},{1, 0},{7, 29.5276},{2, 11},{7, keyword},{1, 0},{1, 0},{34, :RPCs:Trees [General]:Geometry:RPC},{2, 11},{8, category},{1, 0},{1, 0},{15, Trees [General]},{2, 11},{12, LocalizedUID},{1, 0},{1, 0},{9, Red Maple},{2, 14},{6, Height},{1, 0},{1, 0},{7, 29.5276},{1, 2},{16, Cast Reflections},{1, 0},{1, 0},{1, 0},{1, 2},{12, Cast Shadows},{1, 0},{1, 0},{1, 1},{1, 2},{9, Lock View},{1, 0},{1, 0},{1, 0},{1, 4},{5, ViewC},{1, 0},{1, 0},{1, 0},{21, assetlibrary_base.fbx},{1, 5},; SmartRevit_Versie: 2012.1; Type Comments: Red Maple; Type Name: 9000_Red Maple
Type - Pset_ProductRequirements - Category: Planting
Type - Pset_ProvisionForVoid - Height: 9000 mm
Pset_BuildingElementProxyCommon - Reference: 9000_Red Maple; sets with these values: 2
Other - Family: 300_90_ISR_boom; Family and Type: 300_90_ISR_boom: 9000_Red Maple; Type: 9000_Red Maple; Type Id: 3890073
Constraints - Level: 0; Moves With Nearby Elements: no; Offset from Host: 0 mm; Elevation from Level: -30 mm; Host: Toposolid : Toposolid 1
Dimensions - Area: 902.249 m2; Volume: 2025.3 m3
Identity Data - Workset: Bouwkundig
Phasing - Phase Created: 2. nieuwbouw

# IfcBuildingElementProxy: 300_90_ISR_boom:9100_Shumard Oak (2)
In: 00 Begane grond
Type - Material: x_Situatie_Boom
Type - Other - Category: Planting; Family Name: 300_90_ISR_boom
Type - Constraints - Default Elevation: 0 mm
Type - Dimensions - Height: 9100 mm
Type - Graphics - basis_01: no; basis_02: no; basis_03: no; basis_04: no; basis_05: no; basis_06: yes; basis_07: no; basis_08: no; basis_09: no; basis_10: no; basis_11: no; basis_12: no; basis_13: no
Type - Identity Data - Datum_Gewijzigd: 20110418; Render Appearance: RPC-16-FXGQ-AS80-PNHH-0000-ST1L-LVER-AU; Render Appearance Properties: {2, 15},{39, RPC-16-FXGQ-AS80-PNHH-0000-ST1L-LVER-AU},{1, 0},{1, 0},{2, 13},{1, 8},{5, Color},{1, 0},{1, 0},{3, 0.8},{3, 0.8},{3, 0.8},{1, 8},{7, BBoxMin},{1, 0},{1, 0},{1, 0},{1, 0},{1, 0},{1, 8},{7, BBoxMax},{1, 0},{1, 0},{1, 0},{1, 0},{1, 0},{2, 11},{9, RPCTypeId},{1, 0},{1, 0},{39, RPC-16-FXGQ-AS80-PNHH-0000-ST1L-LVER-AU},{1, 6},{14, RPCPlantHeight},{1, 0},{1, 0},{7, 29.8556},{2, 11},{7, keyword},{1, 0},{1, 0},{34, :RPCs:Trees [General]:Geometry:RPC},{2, 11},{8, category},{1, 0},{1, 0},{15, Trees [General]},{2, 11},{12, LocalizedUID},{1, 0},{1, 0},{11, Shumard Oak},{2, 14},{6, Height},{1, 0},{1, 0},{7, 29.8556},{1, 2},{16, Cast Reflections},{1, 0},{1, 0},{1, 0},{1, 2},{12, Cast Shadows},{1, 0},{1, 0},{1, 1},{1, 2},{9, Lock View},{1, 0},{1, 0},{1, 0},{1, 4},{5, ViewC},{1, 0},{1, 0},{1, 0},{21, assetlibrary_base.fbx},{1, 5},; SmartRevit_Versie: 2012.1; Type Comments: Shumard Oak; Type Name: 9100_Shumard Oak; Workset: Family : Planting : 300_90_ISR_boom
Type - Materials and Finishes - materiaal: x_Situatie_Boom
Type - Pset_ProductRequirements - Category: Planting
Type - Pset_ProvisionForVoid - Height: 9100 mm
Pset_BuildingElementProxyCommon - Reference: 9100_Shumard Oak; sets with these values: 2
Other - Family: 300_90_ISR_boom; Family and Type: 300_90_ISR_boom: 9100_Shumard Oak; Type: 9100_Shumard Oak; Type Id: 3890105
Constraints - Level: 0; Moves With Nearby Elements: no; Offset from Host: 0 mm
Dimensions - Area: 918.797 m2; Volume: 2081.34 m3
Identity Data - Workset: Bouwkundig
Phasing - Phase Created: 2. nieuwbouw
Name (300_90_ISR_boom:9100_Shumard Oak:...) | Elevation from Level (mm) | Host
5765969 | -10 | Sub-Division
5816987 | -30 | Toposolid : Toposolid 1

# IfcBuildingElementProxy: 31_DAT_Screen_zonwering_bak85:31_DAT_Screen_zonwering_bak85 (7)
In: 00 Begane grond
Type - Material: <Unnamed>
Type - Other - Category: Generic Models; Family Name: 31_DAT_Screen_zonwering_bak85
Type - Constraints - Default Elevation: 0 mm
Type - Identity Data - Assembly Code: 31.40; Assembly Description: buitenwandopeningen; gevuld met puien, algemeen (verzamelniveau); Description: Screen zonwering 85x85mmBak en geleiders: Ral 7006Doek: 1006 (1090) zand/brons (lichte kant binnen); Type Comments: Screen zonwering; Type Mark: ZW; Type Name: 31_DAT_Screen_zonwering_bak85; Workset: Family : Generic Models : 31_DAT_Screen_zonwering_bak85
Type - Pset_ProductRequirements - Category: Generic Models
Classification: 31.40 Uniformat (Uniformat)
Pset_BuildingElementProxyCommon - Reference: 31_DAT_Screen_zonwering_bak85; sets with these values: 2
Pset_Generic Models - Family and Type: 31_DAT_Screen_zonwering_bak85: 31_DAT_Screen_zonwering_bak85; NL-sfb-Codering: 31.40; Omschrijving: Screen zonwering 85x85mmBak en geleiders: Ral 7006Doek: 1006 (1090) zand/brons (lichte kant binnen); Type Comments: Screen zonwering; Level: 0
Pset_DAT_KMS - Assembly Code: 31.40; Assembly Description: buitenwandopeningen; gevuld met puien, algemeen (verzamelniveau); Description: Screen zonwering 85x85mmBak en geleiders: Ral 7006Doek: 1006 (1090) zand/brons (lichte kant binnen)
Other - Family: 31_DAT_Screen_zonwering_bak85; Family and Type: 31_DAT_Screen_zonwering_bak85: 31_DAT_Screen_zonwering_bak85; Type: 31_DAT_Screen_zonwering_bak85; Type Id: 4785772
Constraints - Elevation from Level: 0 mm; Level: 0; Moves With Nearby Elements: no; Offset from Host: 0 mm; Host: Level : 0
Dimensions - peil_BK_kap: 2735 mm
Identity Data - Workset: Bouwkundig
Phasing - Phase Created: 2. nieuwbouw
Name (31_DAT_Screen_zonwering_bak85:31_DAT_Screen_zonwering_bak85:...) | Width (mm) | Height (mm) = Depth (mm) | ok-geleiders (mm) | Area (m2) | hoogte (mm) | lengte (mm) | openstand (mm) | Volume (m3) | Group
5539092 | 1.16331 | 660 | 0 | 0.824732 | 2735 | 700 | 2616.88 | 0.00164525 | Model Group:K_Raamwerk_04:5539091
5539098 | 1.16331 | 660 | 0 | 0.824732 | 2735 | 700 | 2616.88 | 0.00164525 | Model Group:K_Raamwerk_04:5539097
5539101 | 1.16331 | 660 | 0 | 0.824732 | 2735 | 700 | 2616.88 | 0.00164525 | Model Group:K_Raamwerk_04:5539100
5539104 | 1.16331 | 660 | 0 | 0.824732 | 2735 | 700 | 2616.88 | 0.00164525 | Model Group:K_Raamwerk_04:5539103
5539107 | 1.16331 | 660 | 0 | 0.824732 | 2735 | 700 | 2616.88 | 0.00164525 | Model Group:K_Raamwerk_04:5539106
5539203 | 1.16331 | 1555 | 0 | 1.23144 | 2735 | 1595 | 2570.05 | 0.00278049 | Model Group:K_Raamwerk_18A:5539193
5552760 | 800 | 1.16331 | 710 | 0.786021 | 2025 | 840 | 1983.77 | 0.0016553

# IfcBuildingElementProxy: 31_DAT_Screen_zonwering_bak85:31_DAT_Screen_zonwering_bak85 (120)
Type - Material: STAAL_RAL 7006, <Unnamed>
Type - Other - Category: Generic Models; Family Name: 31_DAT_Screen_zonwering_bak85
Type - Constraints - Default Elevation: 0 mm
Type - Identity Data - Assembly Code: 31.40; Assembly Description: buitenwandopeningen; gevuld met puien, algemeen (verzamelniveau); Description: Screen zonwering 85x85mmBak en geleiders: Ral 7006Doek: 1006 (1090) zand/brons (lichte kant binnen); Type Comments: Screen zonwering; Type Mark: ZW; Type Name: 31_DAT_Screen_zonwering_bak85; Workset: Family : Generic Models : 31_DAT_Screen_zonwering_bak85
Type - Pset_ProductRequirements - Category: Generic Models
Classification: 31.40 Uniformat (Uniformat)
Pset_BuildingElementProxyCommon - Reference: 31_DAT_Screen_zonwering_bak85; sets with these values: 2
Pset_Generic Models - Family and Type: 31_DAT_Screen_zonwering_bak85: 31_DAT_Screen_zonwering_bak85; NL-sfb-Codering: 31.40; Omschrijving: Screen zonwering 85x85mmBak en geleiders: Ral 7006Doek: 1006 (1090) zand/brons (lichte kant binnen); Type Comments: Screen zonwering
Pset_DAT_KMS - Assembly Code: 31.40; Assembly Description: buitenwandopeningen; gevuld met puien, algemeen (verzamelniveau); Description: Screen zonwering 85x85mmBak en geleiders: Ral 7006Doek: 1006 (1090) zand/brons (lichte kant binnen)
Other - Family: 31_DAT_Screen_zonwering_bak85; Family and Type: 31_DAT_Screen_zonwering_bak85: 31_DAT_Screen_zonwering_bak85; Type: 31_DAT_Screen_zonwering_bak85; Type Id: 4785772
Constraints - Moves With Nearby Elements: no
Identity Data - Workset: Bouwkundig
Materials and Finishes - aluminium: STAAL_RAL 7006
Phasing - Phase Created: 2. nieuwbouw
Name (31_DAT_Screen_zonwering_bak85:31_DAT_Screen_zonwering_bak85:...) | In | Width (mm) | Height (mm) = Depth (mm) | Pset_Generic Models, Level = Constraints, Level | Elevation from Level (mm) = Offset from Host (mm) | Host | Area (m2) | hoogte (mm) | lengte (mm) | ok-geleiders (mm) | openstand (mm) | peil_BK_kap (mm) | Volume (m3) | Group
5536903 | 00 Begane grond | 1.16331 | 2039.95 | 0 | 0 | Level : 0 | 1.43504 | 2735 | 2079.95 | 0 | 2570.05 | 2735 | 0.00337613 | Model Group:K_Raamwerk_02a:5536902
5536917 | 00 Begane grond | 1.16331 | 840 | 0 | 0 | Level : 0 | 0.931263 | 2735 | 880 | 0 | 2570.05 | 2735 | 0.00190229 | Model Group:K_Raamwerk_01:5536916
5536949 | 00 Begane grond | 1.16331 | 840 | 0 | 0 | Level : 0 | 0.931263 | 2735 | 880 | 0 | 2570.05 | 2735 | 0.00190229 | Model Group:K_Raamwerk_01:5536948
5536963 | 00 Begane grond | 1.16331 | 1785 | 0 | 0 | Level : 0 | 1.328 | 2735 | 1825 | 0 | 2570.05 | 2735 | 0.00306299 | Model Group:K_Raamwerk_21:5536962
5537359 | 00 Begane grond | 2050 | 1.16331 | 0 | 3177 | Level : 0 | 1.37262 | 2858 | 2090 | 450 | 2738 | 3308 | 0.00331939
5537440 | 00 Begane grond | 710 | 1.16331 | 0 | 250 | Level : 0 | 0.763428 | 2285 | 750 | 450 | 2147.82 | 2735 | 0.00158022 | Model Group:K_Raamwerk_06:5537331
5537443 | 00 Begane grond | 710 | 1.16331 | 0 | 250 | Level : 0 | 0.763428 | 2285 | 750 | 450 | 2147.82 | 2735 | 0.00158022 | Model Group:K_Raamwerk_06:5537289
5537446 | 00 Begane grond | 710 | 1.16331 | 0 | 250 | Level : 0 | 0.763428 | 2285 | 750 | 450 | 2147.82 | 2735 | 0.00158022 | Model Group:K_Raamwerk_06:5537301
5537449 | 00 Begane grond | 710 | 1.16331 | 0 | 250 | Level : 0 | 0.763428 | 2285 | 750 | 450 | 2147.82 | 2735 | 0.00158022 | Model Group:K_Raamwerk_06:5537313
5537452 | 00 Begane grond | 710 | 1.16331 | 0 | 250 | Level : 0 | 0.763428 | 2285 | 750 | 450 | 2147.82 | 2735 | 0.00158022 | Model Group:K_Raamwerk_06:5537322
5537455 | 00 Begane grond | 710 | 1.16331 | 0 | 250 | Level : 0 | 0.763428 | 2285 | 750 | 450 | 2147.82 | 2735 | 0.00158022 | Model Group:K_Raamwerk_06:5537327
5537495 | 00 Begane grond | 702 | 1.16331 | 0 | 250 | Level : 0 | 0.760291 | 2285 | 742 | 450 | 2147.82 | 2735 | 0.00157066 | Model Group:K_Raamwerk_06a:5537494
5537516 | 00 Begane grond | 710 | 1.16331 | 0 | 1677 | Level : 0 | 0.869049 | 2848 | 750 | 1960 | 2726.8 | 4808 | 0.0017415
5537517 | 00 Begane grond | 710 | 1.16331 | 0 | 1995 | Level : 0 | 0.70219 | 1905 | 750 | 2585 | 1742.9 | 4490 | 0.00148305
5537518 | 00 Begane grond | 710 | 1.16331 | 0 | 0 | Level : 0 | 0.97867 | 3275 | 750 | 3210 | 3124.42 | 6485 | 0.00189809
5537519 | 00 Begane grond | 710 | 1.16331 | 0 | 0 | Level : 0 | 0.851803 | 2650 | 750 | 3835 | 2495.2 | 6485 | 0.00170789
5537520 | 01 eerste verdieping | 710 | 1.16331 | 1 | 10 | Level : 1 | 0.748334 | 2035 | 750 | 800 | 1846 | 2835 | 0.00154555
5537533 | 00 Begane grond | 2220 | 1.16331 | 0 | 0 | Level : 0 | 1.36001 | 2275 | 2260 | 710 | 2134.83 | 2985 | 0.00339073 | Model Group:K_Raamwerk_07:5537510
5537620 | 01 eerste verdieping | 2170 | 1.16331 | 1 | 10 | Level : 1 | 1.29671 | 2015 | 2210 | 800 | 1930 | 2815 | 0.00326237
5537721 | 00 Begane grond | 2220 | 1.16331 | 0 | 0 | Level : 0 | 1.36001 | 2275 | 2260 | 710 | 2134.83 | 2985 | 0.00339073 | Model Group:K_Raamwerk_07:5537720
5537737 | 01 eerste verdieping | 712 | 1.16331 | 1 | 10 | Level : 1 | 0.714192 | 2035 | 752 | 800 | 1895.12 | 2835 | 0.00150738 | Model Group:K_Raamwerk_30:5537736
5537757 | 01 eerste verdieping | 1984 | 1.16331 | 1 | 0 | Level : 1 | 1.20664 | 2035 | 2024 | 800 | 1940 | 2835 | 0.00302135 | Model Group:K_Raamwerk_23:5537755
5537761 | 01 eerste verdieping | 2170 | 1.16331 | 1 | 10 | Level : 1 | 1.24491 | 2015 | 2210 | 800 | 1893.86 | 2815 | 0.00320215 | Model Group:K_Raamwerk_22:5537759
5537765 | 01 eerste verdieping | 2170 | 1.16331 | 1 | 10 | Level : 1 | 1.24491 | 2015 | 2210 | 800 | 1893.86 | 2815 | 0.00320215 | Model Group:K_Raamwerk_22:5537763
5537769 | 01 eerste verdieping | 2170 | 1.16331 | 1 | 10 | Level : 1 | 1.24491 | 2015 | 2210 | 800 | 1893.86 | 2815 | 0.00320215 | Model Group:K_Raamwerk_22:5537767
5537773 | 01 eerste verdieping | 2170 | 1.16331 | 1 | 10 | Level : 1 | 1.24491 | 2015 | 2210 | 800 | 1893.86 | 2815 | 0.00320215 | Model Group:K_Raamwerk_22:5537771
5537777 | 01 eerste verdieping | 2170 | 1.16331 | 1 | 10 | Level : 1 | 1.24491 | 2015 | 2210 | 800 | 1893.86 | 2815 | 0.00320215 | Model Group:K_Raamwerk_22:5537775
5537781 | 01 eerste verdieping | 2170 | 1.16331 | 1 | 10 | Level : 1 | 1.24491 | 2015 | 2210 | 800 | 1893.86 | 2815 | 0.00320215 | Model Group:K_Raamwerk_22:5537779
5537785 | 01 eerste verdieping | 710 | 1.16331 | 1 | 10 | Level : 1 | 0.735641 | 2015 | 750 | 800 | 1962 | 2815 | 0.00152944 | Model Group:K_Raamwerk_29:5537783
5537789 | 01 eerste verdieping | 710 | 1.16331 | 1 | 10 | Level : 1 | 0.735641 | 2015 | 750 | 800 | 1962 | 2815 | 0.00152944 | Model Group:K_Raamwerk_29:5537787
5537793 | 01 eerste verdieping | 710 | 1.16331 | 1 | 10 | Level : 1 | 0.735641 | 2015 | 750 | 800 | 1962 | 2815 | 0.00152944 | Model Group:K_Raamwerk_29:5537791
5537797 | 01 eerste verdieping | 710 | 1.16331 | 1 | 10 | Level : 1 | 0.735641 | 2015 | 750 | 800 | 1962 | 2815 | 0.00152944 | Model Group:K_Raamwerk_29:5537795
5537801 | 01 eerste verdieping | 710 | 1.16331 | 1 | 10 | Level : 1 | 0.735641 | 2015 | 750 | 800 | 1962 | 2815 | 0.00152944 | Model Group:K_Raamwerk_29:5537799
5537805 | 01 eerste verdieping | 710 | 1.16331 | 1 | 10 | Level : 1 | 0.735641 | 2015 | 750 | 800 | 1962 | 2815 | 0.00152944 | Model Group:K_Raamwerk_29:5537803
5537809 | 01 eerste verdieping | 710 | 1.16331 | 1 | 10 | Level : 1 | 0.735641 | 2015 | 750 | 800 | 1962 | 2815 | 0.00152944 | Model Group:K_Raamwerk_29:5537807
5537813 | 01 eerste verdieping | 710 | 1.16331 | 1 | 10 | Level : 1 | 0.735641 | 2015 | 750 | 800 | 1962 | 2815 | 0.00152944 | Model Group:K_Raamwerk_29:5537811
5537824 | 01 eerste verdieping | 710 | 1.16331 | 1 | 10 | Level : 1 | 0.695087 | 2015 | 750 | 800 | 1904.97 | 2815 | 0.00148234 | Model Group:K_Raamwerk_29a:5537822
5537836 | 01 eerste verdieping | 710 | 1.16331 | 1 | 10 | Level : 1 | 0.735641 | 2015 | 750 | 800 | 1962 | 2815 | 0.00152944 | Model Group:K_Raamwerk_29:5537834
5537840 | 01 eerste verdieping | 2170 | 1.16331 | 1 | 10 | Level : 1 | 1.24491 | 2015 | 2210 | 800 | 1893.86 | 2815 | 0.00320215 | Model Group:K_Raamwerk_22:5537838
5537848 | 01 eerste verdieping | 2170 | 1.16331 | 1 | 10 | Level : 1 | 1.24491 | 2015 | 2210 | 800 | 1893.86 | 2815 | 0.00320215 | Model Group:K_Raamwerk_22:5537846
5537860 | 01 eerste verdieping | 710 | 1.16331 | 1 | 10 | Level : 1 | 0.735641 | 2015 | 750 | 800 | 1962 | 2815 | 0.00152944 | Model Group:K_Raamwerk_29:5537858
5537868 | 01 eerste verdieping | 710 | 1.16331 | 1 | 10 | Level : 1 | 0.735641 | 2015 | 750 | 800 | 1962 | 2815 | 0.00152944 | Model Group:K_Raamwerk_29:5537866
5537872 | 01 eerste verdieping | 2170 | 1.16331 | 1 | 10 | Level : 1 | 1.24491 | 2015 | 2210 | 800 | 1893.86 | 2815 | 0.00320215 | Model Group:K_Raamwerk_22:5537870
5537880 | 01 eerste verdieping | 2170 | 1.16331 | 1 | 10 | Level : 1 | 1.24491 | 2015 | 2210 | 800 | 1893.86 | 2815 | 0.00320215 | Model Group:K_Raamwerk_22:5537878
5537892 | 01 eerste verdieping | 710 | 1.16331 | 1 | 10 | Level : 1 | 0.735641 | 2015 | 750 | 800 | 1962 | 2815 | 0.00152944 | Model Group:K_Raamwerk_29:5537890
5537900 | 01 eerste verdieping | 710 | 1.16331 | 1 | 10 | Level : 1 | 0.735641 | 2015 | 750 | 800 | 1962 | 2815 | 0.00152944 | Model Group:K_Raamwerk_29:5537898
5537904 | 01 eerste verdieping | 2170 | 1.16331 | 1 | 10 | Level : 1 | 1.24491 | 2015 | 2210 | 800 | 1893.86 | 2815 | 0.00320215 | Model Group:K_Raamwerk_22:5537902
5537912 | 01 eerste verdieping | 2170 | 1.16331 | 1 | 10 | Level : 1 | 1.24491 | 2015 | 2210 | 800 | 1893.86 | 2815 | 0.00320215 | Model Group:K_Raamwerk_22:5537910
5537924 | 01 eerste verdieping | 710 | 1.16331 | 1 | 10 | Level : 1 | 0.735641 | 2015 | 750 | 800 | 1962 | 2815 | 0.00152944 | Model Group:K_Raamwerk_29:5537922
5537932 | 01 eerste verdieping | 710 | 1.16331 | 1 | 10 | Level : 1 | 0.735641 | 2015 | 750 | 800 | 1962 | 2815 | 0.00152944 | Model Group:K_Raamwerk_29:5537930
5537936 | 01 eerste verdieping | 2170 | 1.16331 | 1 | 10 | Level : 1 | 1.24491 | 2015 | 2210 | 800 | 1893.86 | 2815 | 0.00320215 | Model Group:K_Raamwerk_22:5537934
5537944 | 01 eerste verdieping | 2170 | 1.16331 | 1 | 10 | Level : 1 | 1.24491 | 2015 | 2210 | 800 | 1893.86 | 2815 | 0.00320215 | Model Group:K_Raamwerk_22:5537942
5537956 | 01 eerste verdieping | 710 | 1.16331 | 1 | 10 | Level : 1 | 0.735641 | 2015 | 750 | 800 | 1962 | 2815 | 0.00152944 | Model Group:K_Raamwerk_29:5537954
5537971 | 01 eerste verdieping | 1.16331 | 1065 | 1 | 0 | Level : 1 | 0.865506 | 2015 | 1105 | 800 | 1940 | 2815 | 0.00194319 | Model Group:K_Raamwerk_25:5537969
5538683 | 00 Begane grond | 1.16331 | 1555 | 0 | 0 | Level : 0 | 1.23144 | 2735 | 1595 | 0 | 2570.05 | 2735 | 0.00278049 | Model Group:K_Raamwerk_18:5538682
5538733 | 00 Begane grond | 1.16331 | 2040 | 0 | 0 | Level : 0 | 1.43506 | 2735 | 2080 | 0 | 2570.05 | 2735 | 0.00337619 | Model Group:K_Raamwerk_02:5538732
5538743 | 00 Begane grond | 1.16331 | 2040 | 0 | 0 | Level : 0 | 1.43506 | 2735 | 2080 | 0 | 2570.05 | 2735 | 0.00337619 | Model Group:K_Raamwerk_02:5538742
5539232 | 00 Begane grond | 1.16331 | 840 | 0 | 0 | Level : 0 | 0.931263 | 2735 | 880 | 0 | 2570.05 | 2735 | 0.00190229 | Model Group:K_Raamwerk_01:5536975
5539234 | 00 Begane grond | 1.16331 | 2039.95 | 0 | 0 | Level : 0 | 1.43504 | 2735 | 2079.95 | 0 | 2570.05 | 2735 | 0.00337613 | Model Group:K_Raamwerk_02a:5537101
5539236 | 00 Begane grond | 1.16331 | 2039.95 | 0 | 0 | Level : 0 | 1.43504 | 2735 | 2079.95 | 0 | 2570.05 | 2735 | 0.00337613 | Model Group:K_Raamwerk_02a:5536878
5539372 | 00 Begane grond | 1.16331 | 2040 | 0 | 0 | Level : 0 | 1.43506 | 2735 | 2080 | 0 | 2570.05 | 2735 | 0.00337619 | Model Group:K_Raamwerk_02:5539371
5541151 | 00 Begane grond | 1960 | 1.16331 | 0 | 0 | Level : 0 | 1.2346 | 2025 | 2000 | 710 | 1950.09 | 2735 | 0.00303541 | Model Group:K_Raamwerk_17:5540557
5542286 | 00 Begane grond | 1960 | 1.16331 | 0 | 0 | Level : 0 | 1.2346 | 2025 | 2000 | 710 | 1950.09 | 2735 | 0.00303541 | Model Group:K_Raamwerk_17:5542283
5542312 | 00 Begane grond | 1960 | 1.16331 | 0 | 0 | Level : 0 | 1.2346 | 2025 | 2000 | 710 | 1950.09 | 2735 | 0.00303541 | Model Group:K_Raamwerk_17:5542309
5542338 | 00 Begane grond | 1960 | 1.16331 | 0 | 0 | Level : 0 | 1.2346 | 2025 | 2000 | 710 | 1950.09 | 2735 | 0.00303541 | Model Group:K_Raamwerk_17:5542335
5542364 | 00 Begane grond | 1960 | 1.16331 | 0 | 0 | Level : 0 | 1.2346 | 2025 | 2000 | 710 | 1950.09 | 2735 | 0.00303541 | Model Group:K_Raamwerk_17:5542361
5542390 | 00 Begane grond | 1960 | 1.16331 | 0 | 0 | Level : 0 | 1.2346 | 2025 | 2000 | 710 | 1950.09 | 2735 | 0.00303541 | Model Group:K_Raamwerk_17:5542387
5542462 | 00 Begane grond | 800 | 1.16331 | 0 | 0 | Level : 0 | 0.786021 | 2025 | 840 | 710 | 1983.77 | 2735 | 0.0016553 | Model Group:K_Raamwerk_16:5542459
5544035 | 00 Begane grond | 800 | 1.16331 | 0 | 0 | Level : 0 | 0.786021 | 2025 | 840 | 710 | 1983.77 | 2735 | 0.0016553 | Model Group:K_Raamwerk_16:5544033
5544057 | 00 Begane grond | 800 | 1.16331 | 0 | 0 | Level : 0 | 0.786021 | 2025 | 840 | 710 | 1983.77 | 2735 | 0.0016553 | Model Group:K_Raamwerk_16:5544055
5544108 | 00 Begane grond | 800 | 1.16331 | 0 | 0 | Level : 0 | 0.786021 | 2025 | 840 | 710 | 1983.77 | 2735 | 0.0016553 | Model Group:K_Raamwerk_16:5544106
5544134 | 00 Begane grond | 800 | 1.16331 | 0 | 0 | Level : 0 | 0.786021 | 2025 | 840 | 710 | 1983.77 | 2735 | 0.0016553 | Model Group:K_Raamwerk_16:5544132
5544806 | 00 Begane grond | 800 | 1.16331 | 0 | 0 | Level : 0 | 0.786021 | 2025 | 840 | 710 | 1983.77 | 2735 | 0.0016553 | Model Group:K_Raamwerk_16:5544804
5544824 | 00 Begane grond | 800 | 1.16331 | 0 | 0 | Level : 0 | 0.786021 | 2025 | 840 | 710 | 1983.77 | 2735 | 0.0016553 | Model Group:K_Raamwerk_16:5544822
5544974 | 00 Begane grond | 1960 | 1.16331 | 0 | 0 | Level : 0 | 1.2346 | 2025 | 2000 | 710 | 1950.09 | 2735 | 0.00303541 | Model Group:K_Raamwerk_17:5544971
5545009 | 00 Begane grond | 1960 | 1.16331 | 0 | 0 | Level : 0 | 1.2346 | 2025 | 2000 | 710 | 1950.09 | 2735 | 0.00303541 | Model Group:K_Raamwerk_17:5545006
5545035 | 00 Begane grond | 800 | 1.16331 | 0 | 0 | Level : 0 | 0.786021 | 2025 | 840 | 710 | 1983.77 | 2735 | 0.0016553 | Model Group:K_Raamwerk_16:5545033
5545108 | 00 Begane grond | 800 | 1.16331 | 0 | 0 | Level : 0 | 0.786021 | 2025 | 840 | 710 | 1983.77 | 2735 | 0.0016553 | Model Group:K_Raamwerk_16:5545106
5545131 | 00 Begane grond | 800 | 1.16331 | 0 | 0 | Level : 0 | 0.786021 | 2025 | 840 | 710 | 1983.77 | 2735 | 0.0016553 | Model Group:K_Raamwerk_16:5545129
5627033 | 00 Begane grond | 1210 | 1.16331 | 0 | 0 | Level : 0 | 0.927123 | 2025 | 1250 | 710 | 1950.09 | 2735 | 0.00212283
5856138 | 00 Begane grond | 800 | 1.16331 | 0 | 0 | Level : 0 | 0.786021 | 2025 | 840 | 710 | 1983.77 | 2735 | 0.0016553 | Model Group:K_Raamwerk_16:5856137
5856141 | 00 Begane grond | 800 | 1.16331 | 0 | 0 | Level : 0 | 0.786021 | 2025 | 840 | 710 | 1983.77 | 2735 | 0.0016553 | Model Group:K_Raamwerk_16:5856140
6054220 | 00 Begane grond | 1960 | 1.16331 | 0 | 0 | Level : 0 | 1.2346 | 2025 | 2000 | 710 | 1950.09 | 2735 | 0.00303541 | Model Group:K_Raamwerk_17:5544238
6054340 | 00 Begane grond | 1960 | 1.16331 | 0 | 0 | Level : 0 | 1.2346 | 2025 | 2000 | 710 | 1950.09 | 2735 | 0.00303541 | Model Group:K_Raamwerk_17:5856134
6054390 | 00 Begane grond | 1960 | 1.16331 | 0 | 0 | Level : 0 | 1.2346 | 2025 | 2000 | 710 | 1950.09 | 2735 | 0.00303541 | Model Group:K_Raamwerk_17:5544293
6057858 | 01 eerste verdieping | 1.16331 | 800 | 1 | 0 | Level : 1 | 0.764889 | 2025 | 840 | 810 | 1957.39 | 2835 | 0.00163075 | Model Group:K_Raamwerk_28:6057727
6058276 | 01 eerste verdieping | 1.16331 | 800 | 1 | 0 | Level : 1 | 0.764889 | 2025 | 840 | 810 | 1957.39 | 2835 | 0.00163075 | Model Group:K_Raamwerk_28:6058262
6058295 | 01 eerste verdieping | 1.16331 | 800 | 1 | 0 | Level : 1 | 0.764889 | 2025 | 840 | 810 | 1957.39 | 2835 | 0.00163075 | Model Group:K_Raamwerk_28:6058281
6058314 | 01 eerste verdieping | 1.16331 | 800 | 1 | 0 | Level : 1 | 0.764889 | 2025 | 840 | 810 | 1957.39 | 2835 | 0.00163075 | Model Group:K_Raamwerk_28:6058300
6058333 | 01 eerste verdieping | 1.16331 | 800 | 1 | 0 | Level : 1 | 0.764889 | 2025 | 840 | 810 | 1957.39 | 2835 | 0.00163075 | Model Group:K_Raamwerk_28:6058319
6058352 | 01 eerste verdieping | 1.16331 | 800 | 1 | 0 | Level : 1 | 0.764889 | 2025 | 840 | 810 | 1957.39 | 2835 | 0.00163075 | Model Group:K_Raamwerk_28:6058338
6058371 | 01 eerste verdieping | 1.16331 | 800 | 1 | 0 | Level : 1 | 0.764889 | 2025 | 840 | 810 | 1957.39 | 2835 | 0.00163075 | Model Group:K_Raamwerk_28:6058357
6058390 | 01 eerste verdieping | 1.16331 | 800 | 1 | 0 | Level : 1 | 0.764889 | 2025 | 840 | 810 | 1957.39 | 2835 | 0.00163075 | Model Group:K_Raamwerk_28:6058376
6058409 | 01 eerste verdieping | 1.16331 | 800 | 1 | 0 | Level : 1 | 0.764889 | 2025 | 840 | 810 | 1957.39 | 2835 | 0.00163075 | Model Group:K_Raamwerk_28:6058395
6058428 | 01 eerste verdieping | 1.16331 | 800 | 1 | 0 | Level : 1 | 0.764889 | 2025 | 840 | 810 | 1957.39 | 2835 | 0.00163075 | Model Group:K_Raamwerk_28:6058414
6058447 | 01 eerste verdieping | 1.16331 | 800 | 1 | 0 | Level : 1 | 0.764889 | 2025 | 840 | 810 | 1957.39 | 2835 | 0.00163075 | Model Group:K_Raamwerk_28:6058433
6058466 | 01 eerste verdieping | 1.16331 | 800 | 1 | 0 | Level : 1 | 0.764889 | 2025 | 840 | 810 | 1957.39 | 2835 | 0.00163075 | Model Group:K_Raamwerk_28:6058452
6058485 | 01 eerste verdieping | 1.16331 | 800 | 1 | 0 | Level : 1 | 0.764889 | 2025 | 840 | 810 | 1957.39 | 2835 | 0.00163075 | Model Group:K_Raamwerk_28:6058471
6058504 | 01 eerste verdieping | 1.16331 | 800 | 1 | 0 | Level : 1 | 0.764889 | 2025 | 840 | 810 | 1957.39 | 2835 | 0.00163075 | Model Group:K_Raamwerk_28:6058490
6058523 | 01 eerste verdieping | 1.16331 | 800 | 1 | 0 | Level : 1 | 0.764889 | 2025 | 840 | 810 | 1957.39 | 2835 | 0.00163075 | Model Group:K_Raamwerk_28:6058509
6058542 | 01 eerste verdieping | 1.16331 | 800 | 1 | 0 | Level : 1 | 0.764889 | 2025 | 840 | 810 | 1957.39 | 2835 | 0.00163075 | Model Group:K_Raamwerk_28:6058528
6058561 | 01 eerste verdieping | 1.16331 | 800 | 1 | 0 | Level : 1 | 0.764889 | 2025 | 840 | 810 | 1957.39 | 2835 | 0.00163075 | Model Group:K_Raamwerk_28:6058547
6058693 | 01 eerste verdieping | 1960 | 1.16331 | V1 bk. ruwe vloer | 440 | Level : V1 bk. ruwe vloer | 1.19265 | 2035 | 2000 | 450 | 1902.36 | 2485 | 0.00298733 | Model Group:K_Raamwerk_24:6058628
6059001 | 01 eerste verdieping | 1960 | 1.16331 | V1 bk. ruwe vloer | 440 | Level : V1 bk. ruwe vloer | 1.19265 | 2035 | 2000 | 450 | 1902.36 | 2485 | 0.00298733 | Model Group:K_Raamwerk_24:6058988
6059020 | 01 eerste verdieping | 1960 | 1.16331 | V1 bk. ruwe vloer | 440 | Level : V1 bk. ruwe vloer | 1.19265 | 2035 | 2000 | 450 | 1902.36 | 2485 | 0.00298733 | Model Group:K_Raamwerk_24:6059007
6059039 | 01 eerste verdieping | 1960 | 1.16331 | V1 bk. ruwe vloer | 440 | Level : V1 bk. ruwe vloer | 1.19265 | 2035 | 2000 | 450 | 1902.36 | 2485 | 0.00298733 | Model Group:K_Raamwerk_24:6059026
6059058 | 01 eerste verdieping | 1960 | 1.16331 | V1 bk. ruwe vloer | 440 | Level : V1 bk. ruwe vloer | 1.19265 | 2035 | 2000 | 450 | 1902.36 | 2485 | 0.00298733 | Model Group:K_Raamwerk_24:6059045
6059077 | 01 eerste verdieping | 1960 | 1.16331 | V1 bk. ruwe vloer | 440 | Level : V1 bk. ruwe vloer | 1.19265 | 2035 | 2000 | 450 | 1902.36 | 2485 | 0.00298733 | Model Group:K_Raamwerk_24:6059064
6059096 | 01 eerste verdieping | 1960 | 1.16331 | V1 bk. ruwe vloer | 440 | Level : V1 bk. ruwe vloer | 1.19265 | 2035 | 2000 | 450 | 1902.36 | 2485 | 0.00298733 | Model Group:K_Raamwerk_24:6059083
6059115 | 01 eerste verdieping | 1960 | 1.16331 | V1 bk. ruwe vloer | 440 | Level : V1 bk. ruwe vloer | 1.19265 | 2035 | 2000 | 450 | 1902.36 | 2485 | 0.00298733 | Model Group:K_Raamwerk_24:6059102
6059134 | 01 eerste verdieping | 1960 | 1.16331 | V1 bk. ruwe vloer | 440 | Level : V1 bk. ruwe vloer | 1.19265 | 2035 | 2000 | 450 | 1902.36 | 2485 | 0.00298733 | Model Group:K_Raamwerk_24:6059121
6059153 | 01 eerste verdieping | 1960 | 1.16331 | V1 bk. ruwe vloer | 440 | Level : V1 bk. ruwe vloer | 1.19265 | 2035 | 2000 | 450 | 1902.36 | 2485 | 0.00298733 | Model Group:K_Raamwerk_24:6059140
6059172 | 01 eerste verdieping | 1960 | 1.16331 | V1 bk. ruwe vloer | 440 | Level : V1 bk. ruwe vloer | 1.19265 | 2035 | 2000 | 450 | 1902.36 | 2485 | 0.00298733 | Model Group:K_Raamwerk_24:6059159
6059191 | 01 eerste verdieping | 1960 | 1.16331 | V1 bk. ruwe vloer | 440 | Level : V1 bk. ruwe vloer | 1.19265 | 2035 | 2000 | 450 | 1902.36 | 2485 | 0.00298733 | Model Group:K_Raamwerk_24:6059178
6059210 | 01 eerste verdieping | 1960 | 1.16331 | V1 bk. ruwe vloer | 440 | Level : V1 bk. ruwe vloer | 1.19265 | 2035 | 2000 | 450 | 1902.36 | 2485 | 0.00298733 | Model Group:K_Raamwerk_24:6059197
6899194 | -1 fundering | 710 | 1.16331 | ok. fundering | 4815 | Level : ok. fundering | 0.673666 | 1905 | 750 | 1335 | 1783.01 | 3240 | 0.00144992
6899806 | -1 fundering | 2050 | 1.16331 | ok. fundering | 1822 | Level : ok. fundering | 1.39515 | 2925 | 2090 | 450 | 2800.8 | 3375 | 0.00335017
6900353 | -1 fundering | 710 | 1.16331 | ok. fundering | 1570 | Level : ok. fundering | 0.950691 | 3245 | 750 | 1335 | 3125 | 4580 | 0.00186354
6900577 | -1 fundering | 710 | 1.16331 | ok. fundering | 1570 | Level : ok. fundering | 0.625727 | 1677 | 750 | 1960 | 1555.8 | 3637 | 0.00137861
6900742 | -1 fundering | 710 | 1.16331 | bk. fundering | 1270 | Level : bk. fundering | 0.691397 | 1995 | 750 | 2585 | 1874.37 | 4580 | 0.00147668
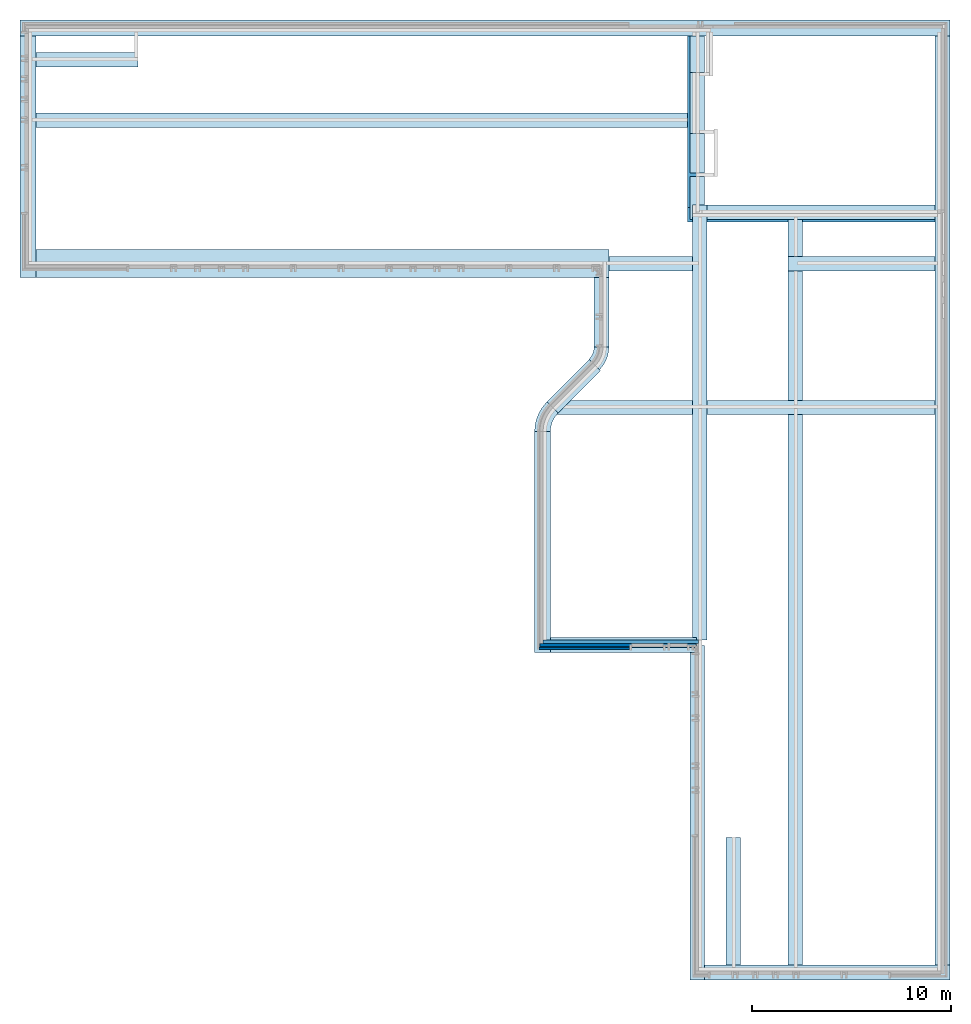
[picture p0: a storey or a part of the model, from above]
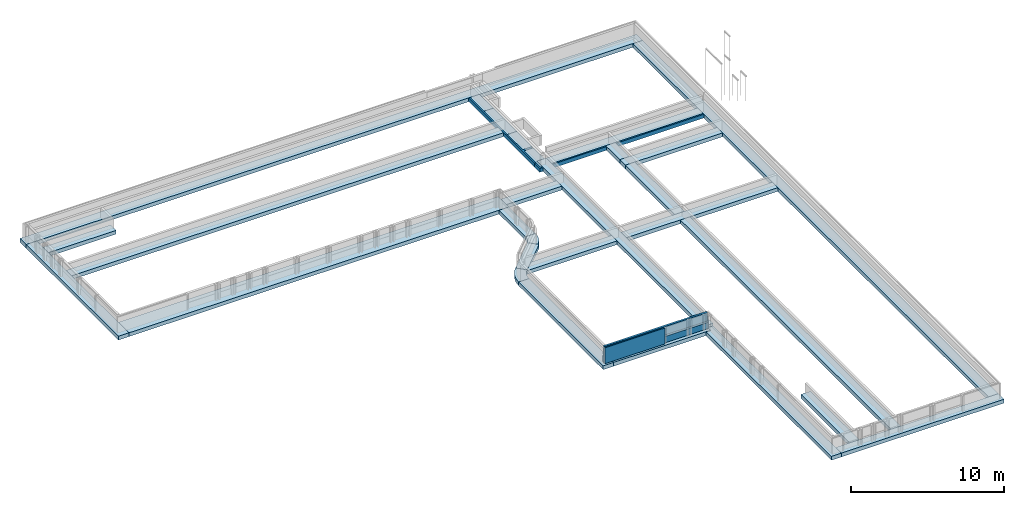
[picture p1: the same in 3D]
Properties of the parts of a building model (IFC2X3), part 6 of 37

# IfcBuildingElementProxy: 35_DAT_GM_prefab dorpel1:35_DAT_GM_prefab dorpel_41 (3)
In: 00 Begane grond
Type - Material: ISR_Beton_prefab
Type - Other - Category: Generic Models; Family Name: 35_DAT_GM_prefab dorpel1
Type - Constraints - Default Elevation: 0 mm
Type - Dimensions - breedte aanslag lip: 41 mm; Breedte waterslag: 190 mm
Type - Identity Data - Workset: Family : Generic Models : 35_DAT_GM_prefab dorpel1; Description: Prefab betonnen dorpel; Type Comments: prefab betonnen dorpel; Type Name: 35_DAT_GM_prefab dorpel_41
Type - Materials and Finishes - NLRS_C_materiaal: ISR_Beton_prefab
Type - Pset_ProductRequirements - Category: Generic Models
Pset_BuildingElementProxyCommon - Reference: 35_DAT_GM_prefab dorpel_41; sets with these values: 2
Pset_Generic Models - Family and Type: 35_DAT_GM_prefab dorpel1: 35_DAT_GM_prefab dorpel_41; Omschrijving: Prefab betonnen dorpel; Type Comments: prefab betonnen dorpel; Level: 0
Pset_DAT_KMS - Description: Prefab betonnen dorpel
Other - Family: 35_DAT_GM_prefab dorpel1; Family and Type: 35_DAT_GM_prefab dorpel1: 35_DAT_GM_prefab dorpel_41; Type: 35_DAT_GM_prefab dorpel_41; Type Id: 5676168
Constraints - Level: 0; Moves With Nearby Elements: no; Elevation from Level: -40 mm; Host: Level : 0; Offset from Host: -40 mm
Identity Data - Workset: Bouwkundig
Phasing - Phase Created: 2. nieuwbouw
Name (35_DAT_GM_prefab dorpel1:35_DAT_GM_prefab dorpel_41:...) | Area (m2) | NLRS_C_lengte (mm) | Volume (m3) | Group
5684593 | 0.46684 | 1870 | 0.0163476 | Model Group:K_Raamwerk_20:5539160
5685585 | 0.518285 | 2080 | 0.0181835 | Model Group:K_Raamwerk_03a:5538797
6293945 | 0.314958 | 1250 | 0.0109276

# IfcBuildingElementProxy: 35_DAT_GM_prefab dorpel1:35_DAT_GM_prefab dorpel_60, 35_DAT_GM_prefab dorpel1:35_DAT_GM_prefab dorpel_60:5694252
In: 00 Begane grond
Type - Material: ISR_Beton_prefab
Type - Other - Category: Generic Models; Family Name: 35_DAT_GM_prefab dorpel1
Type - Constraints - Default Elevation: 0 mm
Type - Dimensions - breedte aanslag lip: 60 mm; Breedte waterslag: 350 mm
Type - Identity Data - Workset: Family : Generic Models : 35_DAT_GM_prefab dorpel1; Description: Prefab betonnen dorpel; Type Comments: prefab betonnen dorpel; Type Name: 35_DAT_GM_prefab dorpel_60
Type - Materials and Finishes - NLRS_C_materiaal: ISR_Beton_prefab
Type - Pset_ProductRequirements - Category: Generic Models
Pset_BuildingElementProxyCommon - Reference: 35_DAT_GM_prefab dorpel_60; sets with these values: 2
Pset_Generic Models - Family and Type: 35_DAT_GM_prefab dorpel1: 35_DAT_GM_prefab dorpel_60; Omschrijving: Prefab betonnen dorpel; Type Comments: prefab betonnen dorpel; Level: 0
Pset_DAT_KMS - Description: Prefab betonnen dorpel
Other - Family: 35_DAT_GM_prefab dorpel1; Family and Type: 35_DAT_GM_prefab dorpel1: 35_DAT_GM_prefab dorpel_60; Type: 35_DAT_GM_prefab dorpel_60; Type Id: 5700533
Constraints - Level: 0; Moves With Nearby Elements: no; Elevation from Level: -40 mm; Host: Level : 0; Offset from Host: -40 mm
Dimensions - Area: 1.39648 m2; NLRS_C_lengte: 3410 mm; Volume: 0.0539694 m3
Identity Data - Workset: Bouwkundig
Phasing - Phase Created: 2. nieuwbouw

# IfcBuildingElementProxy: 35_DAT_GM_prefab dorpel1:35_DAT_GM_prefab dorpel_67 (29)
In: 00 Begane grond
Type - Material: ISR_Beton_prefab
Type - Other - Category: Generic Models; Family Name: 35_DAT_GM_prefab dorpel1
Type - Constraints - Default Elevation: 0 mm
Type - Dimensions - breedte aanslag lip: 67 mm; Breedte waterslag: 350 mm
Type - Identity Data - Description: Prefab betonnen dorpel; Type Comments: prefab betonnen dorpelgelijk aan voorkant metselwerkrib; Type Name: 35_DAT_GM_prefab dorpel_67; Workset: Family : Generic Models : 35_DAT_GM_prefab dorpel1
Type - Materials and Finishes - NLRS_C_materiaal: ISR_Beton_prefab
Type - Pset_ProductRequirements - Category: Generic Models
Pset_BuildingElementProxyCommon - Reference: 35_DAT_GM_prefab dorpel_67; sets with these values: 2
Pset_Generic Models - Family and Type: 35_DAT_GM_prefab dorpel1: 35_DAT_GM_prefab dorpel_67; Omschrijving: Prefab betonnen dorpel; Type Comments: prefab betonnen dorpelgelijk aan voorkant metselwerkrib; Level: 0
Pset_DAT_KMS - Description: Prefab betonnen dorpel
Other - Family: 35_DAT_GM_prefab dorpel1; Family and Type: 35_DAT_GM_prefab dorpel1: 35_DAT_GM_prefab dorpel_67; Type: 35_DAT_GM_prefab dorpel_67; Type Id: 4793988
Constraints - Level: 0; Moves With Nearby Elements: no; Host: Level : 0
Identity Data - Workset: Bouwkundig
Phasing - Phase Created: 2. nieuwbouw
Name (35_DAT_GM_prefab dorpel1:35_DAT_GM_prefab dorpel_67:...) | Elevation from Level (mm) = Offset from Host (mm) | Area (m2) | NLRS_C_lengte (mm) | Volume (m3) | Group
5539386 | -40 | 0.372252 | 880 | 0.0140375 | Model Group:K_Raamwerk_01 A:5538614
5539387 | -40 | 0.372252 | 880 | 0.0140375 | Model Group:K_Raamwerk_01:5536916
5539388 | -40 | 0.372252 | 880 | 0.0140375 | Model Group:K_Raamwerk_01:5536948
5539389 | -40 | 0.372252 | 880 | 0.0140375 | Model Group:K_Raamwerk_01:5536975
5655433 | -40 | 0.858115 | 2080 | 0.0331795 | Model Group:K_Raamwerk_02:5538742
5657515 | -40 | 0.858115 | 2080 | 0.0331795 | Model Group:K_Raamwerk_02:5538732
5657517 | -40 | 0.858115 | 2080 | 0.0331795 | Model Group:K_Raamwerk_02:5539371
5665368 | -45 | 0.754869 | 1825 | 0.0291118 | Model Group:K_Raamwerk_21:5536962
5665864 | -40 | 0.661745 | 1595 | 0.0254429 | Model Group:K_Raamwerk_18A:5539193
5666513 | -40 | 0.858115 | 2080 | 0.0331795 | Model Group:K_Raamwerk_02a:5536902
5666628 | -40 | 0.858115 | 2080 | 0.0331795 | Model Group:K_Raamwerk_02a:5536878
5666630 | -40 | 0.858115 | 2080 | 0.0331795 | Model Group:K_Raamwerk_02a:5537101
5666662 | -40 | 0.299372 | 700 | 0.0111662 | Model Group:K_Raamwerk_04:5539103
5666899 | -40 | 0.299372 | 700 | 0.0111662 | Model Group:K_Raamwerk_04:5539091
5666901 | -45 | 0.299372 | 700 | 0.0111662 | Model Group:K_Raamwerk_04 A:5539094
5666903 | -40 | 0.299372 | 700 | 0.0111662 | Model Group:K_Raamwerk_04:5539097
5666905 | -40 | 0.299372 | 700 | 0.0111662 | Model Group:K_Raamwerk_04:5539100
5666907 | -40 | 0.299372 | 700 | 0.0111662 | Model Group:K_Raamwerk_04:5539106
5680493 | -40 | 0.858115 | 2080 | 0.0331795 | Model Group:K_Raamwerk_03:5536855
5680668 | -40 | 0.858115 | 2080 | 0.0331795 | Model Group:K_Raamwerk_03:5536927
5680670 | -40 | 0.858115 | 2080 | 0.0331795 | Model Group:K_Raamwerk_03:5537078
5680672 | -40 | 0.858115 | 2080 | 0.0331795 | Model Group:K_Raamwerk_03:5538761
5680674 | -40 | 0.858115 | 2080 | 0.0331795 | Model Group:K_Raamwerk_03:5538779
5706680 | -40 | 0.661745 | 1595 | 0.0254429 | Model Group:K_Raamwerk_18:5538682
6239126 | -40 | 0.372252 | 880 | 0.0140375 | Model Group:K_Raamwerk_01 A:5538632
6239131 | -40 | 0.372252 | 880 | 0.0140375 | Model Group:K_Raamwerk_01 A:5538692
6239136 | -40 | 0.372252 | 880 | 0.0140375 | Model Group:K_Raamwerk_01 A:5538702
6239141 | -40 | 0.372252 | 880 | 0.0140375 | Model Group:K_Raamwerk_01 A:5538712
6239146 | -40 | 0.372252 | 880 | 0.0140375 | Model Group:K_Raamwerk_01 A:5538722

# IfcBuildingElementProxy: 35_DAT_GM_prefab dorpel1:35_DAT_GM_prefab dorpel_76 (2)
In: 00 Begane grond
Type - Material: ISR_Beton_prefab
Type - Other - Category: Generic Models; Family Name: 35_DAT_GM_prefab dorpel1
Type - Constraints - Default Elevation: 0 mm
Type - Dimensions - breedte aanslag lip: 76 mm; Breedte waterslag: 350 mm
Type - Identity Data - Workset: Family : Generic Models : 35_DAT_GM_prefab dorpel1; Description: Prefab betonnen dorpel; Type Comments: prefab betonnen dorpel; Type Name: 35_DAT_GM_prefab dorpel_76
Type - Materials and Finishes - NLRS_C_materiaal: ISR_Beton_prefab
Type - Pset_ProductRequirements - Category: Generic Models
Pset_BuildingElementProxyCommon - Reference: 35_DAT_GM_prefab dorpel_76; sets with these values: 2
Pset_Generic Models - Family and Type: 35_DAT_GM_prefab dorpel1: 35_DAT_GM_prefab dorpel_76; Omschrijving: Prefab betonnen dorpel; Type Comments: prefab betonnen dorpel; Level: 0
Pset_DAT_KMS - Description: Prefab betonnen dorpel
Other - Family: 35_DAT_GM_prefab dorpel1; Family and Type: 35_DAT_GM_prefab dorpel1: 35_DAT_GM_prefab dorpel_76; Type: 35_DAT_GM_prefab dorpel_76; Type Id: 6308851
Constraints - Level: 0; Moves With Nearby Elements: no; Elevation from Level: -40 mm; Host: Level : 0; Offset from Host: -40 mm
Dimensions - Area: 0.457442 m2; NLRS_C_lengte: 1090 mm; Volume: 0.0175623 m3
Identity Data - Workset: Bouwkundig
Phasing - Phase Created: 2. nieuwbouw
Name (35_DAT_GM_prefab dorpel1:35_DAT_GM_prefab dorpel_76:...) | Group
5674087 | Model Group:K_Raamwerk_05:5536976
5696768 | Model Group:K_Raamwerk_05:5537110

# IfcBuildingElementProxy: 48_DAT_brievenbus_smal:48_DAT_brievenbus_smal, 48_DAT_brievenbus_smal:48_DAT_brievenbus_smal:6481625
In: 00 Begane grond
Type - Material: <Unnamed>
Type - Other - Category: Generic Models; Family Name: 48_DAT_brievenbus_smal
Type - Constraints - Default Elevation: 0 mm
Type - Identity Data - Description: postkast BBK maatwerk 290mm breed - hoogte en diepte af te stemmen; Type Comments: postkast BBK maatwerk 290mm breed - hoogte en diepte af te stemmen; Type Name: 48_DAT_brievenbus_smal; Workset: Family : Generic Models : 48_DAT_brievenbus_smal
Type - Pset_ProductRequirements - Category: Generic Models
Pset_BuildingElementProxyCommon - Reference: 48_DAT_brievenbus_smal; sets with these values: 2
Pset_Generic Models - Family and Type: 48_DAT_brievenbus_smal: 48_DAT_brievenbus_smal; Omschrijving: postkast BBK maatwerk 290mm breed - hoogte en diepte af te stemmen; Type Comments: postkast BBK maatwerk 290mm breed - hoogte en diepte af te stemmen; Level: 0
Pset_DAT_KMS - Description: postkast BBK maatwerk 290mm breed - hoogte en diepte af te stemmen
Other - Family: 48_DAT_brievenbus_smal; Family and Type: 48_DAT_brievenbus_smal: 48_DAT_brievenbus_smal; Type: 48_DAT_brievenbus_smal; Type Id: 6481609
Constraints - Elevation from Level: 0 mm; Level: 0; Moves With Nearby Elements: no; Offset from Host: 0 mm; Host: Level : 0
Dimensions - Area: 0.556881 m2; Volume: 0.00109593 m3
Identity Data - Workset: Bouwkundig
Phasing - Phase Created: 2. nieuwbouw

# IfcBuildingElementProxy: 61_DAT_GMWB_digibord:61_DAT_GMWB_digibord (12)
Type - Material: <Unnamed>
Type - Other - Category: Electrical Equipment; Family Name: 61_DAT_GMWB_digibord
Type - Constraints - Default Elevation: 0 mm
Type - Identity Data - Assembly Code: 64.30; Assembly Description: communicatie; overdracht van beelden, algemeen (verzamelniveau); Description: Digibord; OmniClass Number: 23.80.30.11.17; OmniClass Title: Distribution Boards and Control Panels; Type Name: 61_DAT_GMWB_digibord; Workset: Family : Electrical Equipment : 61_DAT_GMWB_digibord
Type - Pset_ProductRequirements - Category: Electrical Equipment
Classification: 64.30 Uniformat (Uniformat)
Pset_BuildingElementProxyCommon - Reference: 61_DAT_GMWB_digibord; sets with these values: 2
Pset_DAT_KMS - Assembly Code: 64.30; Assembly Description: communicatie; overdracht van beelden, algemeen (verzamelniveau); Description: Digibord
Other - Family: 61_DAT_GMWB_digibord; Family and Type: 61_DAT_GMWB_digibord: 61_DAT_GMWB_digibord; Type: 61_DAT_GMWB_digibord; Type Id: 6733858
Constraints - Elevation from Level: 0 mm; Moves With Nearby Elements: no; Offset from Host: 0 mm
Dimensions - Area: 1.90346 m2; Breedte_digibord: 1600 mm; Hoogte_digibord: 1000 mm; Onderzijde_digibord: 1400 mm; Volume: 0.081116 m3
Electrical - Circuiting - Circuit Numbering Option: Default; Feed Through Lugs: yes; SubFeed Lugs: yes; MCB Rating: 1 A
Electrical - Loads - Apparent Load Phase A: 0 W; Apparent Load Phase B: 0 W; Apparent Load Phase C: 0 W; Branch Circuit Apparent Load Phase A: 0 W; Branch Circuit Apparent Load Phase B: 0 W; Branch Circuit Apparent Load Phase C: 0 W; Feed Through Lugs Apparent Load Phase A: 0 W; Feed Through Lugs Apparent Load Phase B: 0 W; Feed Through Lugs Apparent Load Phase C: 0 W; Total Connected: 0 W; Total Demand Factor: 100; Total Estimated Demand: 0 W
Identity Data - Workset: Bouwkundig
Phasing - Phase Created: 2. nieuwbouw
Name (61_DAT_GMWB_digibord:61_DAT_GMWB_digibord:...) | In | Level | Host | Location | Mark
6734057 | 0.35 | 0 | Floor : 23_Dekvloer 70mm | Basisgroep-lokaal 0.35 | 5
6734150 | 0.37 | 0 | Floor : 23_Dekvloer 70mm | Basisgroep-lokaal 0.37 | 6
6734249 | 0.38 | 0 | Floor : 23_Dekvloer 70mm | Basisgroep-lokaal groot 0.38 | 7
6734438 | 0.36 | 0 | Floor : 23_Dekvloer 70mm | Basisgroep-lokaal 0.36 | 8
6734549 | 0.28 | 0 | Floor : 23_Dekvloer 70mm | Basisgroep-lokaal 0.28 | 9
6735849 | 1.24 | 1 | Floor : 23_Zwevende dekvloer 90mm | Basisgroep-lokaal groot 1.24 | 12
6736126 | 1.23 | 1 | Floor : 23_Zwevende dekvloer 90mm | Basisgroep-lokaal 1.23 | 13
6736127 | 1.22 | 1 | Floor : 23_Zwevende dekvloer 90mm | Basisgroep-lokaal 1.22 | 14
6736281 | 1.21 | 1 | Floor : 23_Zwevende dekvloer 90mm | Basisgroep-lokaal 1.21 | 15
6736781 | 1.03 | 1 | Level : 1 | Basisgroep-lokaal 1.03 | 17
6736804 | 1.02 | 1 | Level : 1 | Basisgroep-lokaal 1.02 | 18
6736826 | 1.01 | 1 | Level : 1 | Basisgroep-lokaal 1.01 | 19

# IfcBuildingElementProxy: 6285826
In: 02 tweede verdieping
Pset_ProductRequirements - Category: Walls: Wall Sweeps; sets with these values: 2
Pset_ProvisionForVoid - Shape: Undefined
Constraints - Offset From Level: 2040 mm; Offset From Wall: 1 mm
Dimensions - Length: 1802.5 mm
Identity Data - Workset: Bouwkundig
Phasing - Phase Created: 2. nieuwbouw

# IfcBuildingElementProxy: 6285827
In: 02 tweede verdieping
Pset_ProductRequirements - Category: Walls: Wall Sweeps; sets with these values: 2
Pset_ProvisionForVoid - Shape: Undefined
Constraints - Offset From Level: 1920 mm; Offset From Wall: 1 mm
Dimensions - Length: 1802.5 mm
Identity Data - Workset: Bouwkundig
Phasing - Phase Created: 2. nieuwbouw

# IfcBuildingElementProxy: 6285828
In: 02 tweede verdieping
Pset_ProductRequirements - Category: Walls: Wall Sweeps; sets with these values: 2
Pset_ProvisionForVoid - Shape: Undefined
Constraints - Offset From Level: 1800 mm; Offset From Wall: 1 mm
Dimensions - Length: 1802.5 mm
Identity Data - Workset: Bouwkundig
Phasing - Phase Created: 2. nieuwbouw

# IfcBuildingElementProxy: 6285829
In: 02 tweede verdieping
Pset_ProductRequirements - Category: Walls: Wall Sweeps; sets with these values: 2
Pset_ProvisionForVoid - Shape: Undefined
Constraints - Offset From Level: 1680 mm; Offset From Wall: 1 mm
Dimensions - Length: 1802.5 mm
Identity Data - Workset: Bouwkundig
Phasing - Phase Created: 2. nieuwbouw

# IfcBuildingElementProxy: 6285830
In: 02 tweede verdieping
Pset_ProductRequirements - Category: Walls: Wall Sweeps; sets with these values: 2
Pset_ProvisionForVoid - Shape: Undefined
Constraints - Offset From Level: 1560 mm; Offset From Wall: 1 mm
Dimensions - Length: 1802.5 mm
Identity Data - Workset: Bouwkundig
Phasing - Phase Created: 2. nieuwbouw

# IfcBuildingElementProxy: 6285831
In: 02 tweede verdieping
Pset_ProductRequirements - Category: Walls: Wall Sweeps; sets with these values: 2
Pset_ProvisionForVoid - Shape: Undefined
Constraints - Offset From Level: 1440 mm; Offset From Wall: 1 mm
Dimensions - Length: 1802.5 mm
Identity Data - Workset: Bouwkundig
Phasing - Phase Created: 2. nieuwbouw

# IfcBuildingElementProxy: 6285832
In: 02 tweede verdieping
Pset_ProductRequirements - Category: Walls: Wall Sweeps; sets with these values: 2
Pset_ProvisionForVoid - Shape: Undefined
Constraints - Offset From Level: 1320 mm; Offset From Wall: 1 mm
Dimensions - Length: 1802.5 mm
Identity Data - Workset: Bouwkundig
Phasing - Phase Created: 2. nieuwbouw

# IfcBuildingElementProxy: 6285833
In: 02 tweede verdieping
Pset_ProductRequirements - Category: Walls: Wall Sweeps; sets with these values: 2
Pset_ProvisionForVoid - Shape: Undefined
Constraints - Offset From Level: 1200 mm; Offset From Wall: 1 mm
Dimensions - Length: 1802.5 mm
Identity Data - Workset: Bouwkundig
Phasing - Phase Created: 2. nieuwbouw

# IfcBuildingElementProxy: 6285834
In: 02 tweede verdieping
Pset_ProductRequirements - Category: Walls: Wall Sweeps; sets with these values: 2
Pset_ProvisionForVoid - Shape: Undefined
Constraints - Offset From Level: 1080 mm; Offset From Wall: 1 mm
Dimensions - Length: 1802.5 mm
Identity Data - Workset: Bouwkundig
Phasing - Phase Created: 2. nieuwbouw

# IfcBuildingElementProxy: 6285835
In: 02 tweede verdieping
Pset_ProductRequirements - Category: Walls: Wall Sweeps; sets with these values: 2
Pset_ProvisionForVoid - Shape: Undefined
Constraints - Offset From Level: 960 mm; Offset From Wall: 1 mm
Dimensions - Length: 1802.5 mm
Identity Data - Workset: Bouwkundig
Phasing - Phase Created: 2. nieuwbouw

# IfcBuildingElementProxy: 6285836
In: 02 tweede verdieping
Pset_ProductRequirements - Category: Walls: Wall Sweeps; sets with these values: 2
Pset_ProvisionForVoid - Shape: Undefined
Constraints - Offset From Level: 840 mm; Offset From Wall: 1 mm
Dimensions - Length: 1802.5 mm
Identity Data - Workset: Bouwkundig
Phasing - Phase Created: 2. nieuwbouw

# IfcBuildingElementProxy: 6285837
In: 02 tweede verdieping
Pset_ProductRequirements - Category: Walls: Wall Sweeps; sets with these values: 2
Pset_ProvisionForVoid - Shape: Undefined
Constraints - Offset From Level: 720 mm; Offset From Wall: 1 mm
Dimensions - Length: 1802.5 mm
Identity Data - Workset: Bouwkundig
Phasing - Phase Created: 2. nieuwbouw

# IfcBuildingElementProxy: 6285838
In: 02 tweede verdieping
Pset_ProductRequirements - Category: Walls: Wall Sweeps; sets with these values: 2
Pset_ProvisionForVoid - Shape: Undefined
Constraints - Offset From Level: 600 mm; Offset From Wall: 1 mm
Dimensions - Length: 1802.5 mm
Identity Data - Workset: Bouwkundig
Phasing - Phase Created: 2. nieuwbouw

# IfcBuildingElementProxy: 6285839
In: 02 tweede verdieping
Pset_ProductRequirements - Category: Walls: Wall Sweeps; sets with these values: 2
Pset_ProvisionForVoid - Shape: Undefined
Constraints - Offset From Level: 480 mm; Offset From Wall: 1 mm
Dimensions - Length: 1802.5 mm
Identity Data - Workset: Bouwkundig
Phasing - Phase Created: 2. nieuwbouw

# IfcBuildingElementProxy: 6285840
In: 02 tweede verdieping
Pset_ProductRequirements - Category: Walls: Wall Sweeps; sets with these values: 2
Pset_ProvisionForVoid - Shape: Undefined
Constraints - Offset From Level: 360 mm; Offset From Wall: 1 mm
Dimensions - Length: 1802.5 mm
Identity Data - Workset: Bouwkundig
Phasing - Phase Created: 2. nieuwbouw

# IfcBuildingElementProxy: 6285841
In: 02 tweede verdieping
Pset_ProductRequirements - Category: Walls: Wall Sweeps; sets with these values: 2
Pset_ProvisionForVoid - Shape: Undefined
Constraints - Offset From Level: 240 mm; Offset From Wall: 1 mm
Dimensions - Length: 1802.5 mm
Identity Data - Workset: Bouwkundig
Phasing - Phase Created: 2. nieuwbouw

# IfcBuildingElementProxy: 6285842
In: 02 tweede verdieping
Pset_ProductRequirements - Category: Walls: Wall Sweeps; sets with these values: 2
Pset_ProvisionForVoid - Shape: Undefined
Constraints - Offset From Level: 120 mm; Offset From Wall: 1 mm
Dimensions - Length: 1802.5 mm
Identity Data - Workset: Bouwkundig
Phasing - Phase Created: 2. nieuwbouw

# IfcBuildingElementProxy: 6286648
In: 02 tweede verdieping
Pset_ProductRequirements - Category: Walls: Wall Sweeps; sets with these values: 2
Constraints - Offset From Level: 2040 mm; Offset From Wall: 1 mm
Dimensions - Length: 1797.5 mm
Identity Data - Workset: Bouwkundig
Phasing - Phase Created: 2. nieuwbouw
Group: Model Group:Paneel op dak:6286816

# IfcBuildingElementProxy: 6286649
In: 02 tweede verdieping
Pset_ProductRequirements - Category: Walls: Wall Sweeps; sets with these values: 2
Pset_ProvisionForVoid - Shape: Undefined
Constraints - Offset From Level: 1920 mm; Offset From Wall: 1 mm
Dimensions - Length: 1797.5 mm
Identity Data - Workset: Bouwkundig
Phasing - Phase Created: 2. nieuwbouw
Group: Model Group:Paneel op dak:6286816

# IfcBuildingElementProxy: 6286650
In: 02 tweede verdieping
Pset_ProductRequirements - Category: Walls: Wall Sweeps; sets with these values: 2
Pset_ProvisionForVoid - Shape: Undefined
Constraints - Offset From Level: 1800 mm; Offset From Wall: 1 mm
Dimensions - Length: 1797.5 mm
Identity Data - Workset: Bouwkundig
Phasing - Phase Created: 2. nieuwbouw
Group: Model Group:Paneel op dak:6286816

# IfcBuildingElementProxy: 6286651
In: 02 tweede verdieping
Pset_ProductRequirements - Category: Walls: Wall Sweeps; sets with these values: 2
Pset_ProvisionForVoid - Shape: Undefined
Constraints - Offset From Level: 1680 mm; Offset From Wall: 1 mm
Dimensions - Length: 1797.5 mm
Identity Data - Workset: Bouwkundig
Phasing - Phase Created: 2. nieuwbouw
Group: Model Group:Paneel op dak:6286816

# IfcBuildingElementProxy: 6286652
In: 02 tweede verdieping
Pset_ProductRequirements - Category: Walls: Wall Sweeps; sets with these values: 2
Pset_ProvisionForVoid - Shape: Undefined
Constraints - Offset From Level: 1560 mm; Offset From Wall: 1 mm
Dimensions - Length: 1797.5 mm
Identity Data - Workset: Bouwkundig
Phasing - Phase Created: 2. nieuwbouw
Group: Model Group:Paneel op dak:6286816

# IfcBuildingElementProxy: 6286653
In: 02 tweede verdieping
Pset_ProductRequirements - Category: Walls: Wall Sweeps; sets with these values: 2
Pset_ProvisionForVoid - Shape: Undefined
Constraints - Offset From Level: 1440 mm; Offset From Wall: 1 mm
Dimensions - Length: 1797.5 mm
Identity Data - Workset: Bouwkundig
Phasing - Phase Created: 2. nieuwbouw
Group: Model Group:Paneel op dak:6286816

# IfcBuildingElementProxy: 6286654
In: 02 tweede verdieping
Pset_ProductRequirements - Category: Walls: Wall Sweeps; sets with these values: 2
Pset_ProvisionForVoid - Shape: Undefined
Constraints - Offset From Level: 1320 mm; Offset From Wall: 1 mm
Dimensions - Length: 1797.5 mm
Identity Data - Workset: Bouwkundig
Phasing - Phase Created: 2. nieuwbouw
Group: Model Group:Paneel op dak:6286816

# IfcBuildingElementProxy: 6286655
In: 02 tweede verdieping
Pset_ProductRequirements - Category: Walls: Wall Sweeps; sets with these values: 2
Pset_ProvisionForVoid - Shape: Undefined
Constraints - Offset From Level: 1200 mm; Offset From Wall: 1 mm
Dimensions - Length: 1797.5 mm
Identity Data - Workset: Bouwkundig
Phasing - Phase Created: 2. nieuwbouw
Group: Model Group:Paneel op dak:6286816

# IfcBuildingElementProxy: 6286656
In: 02 tweede verdieping
Pset_ProductRequirements - Category: Walls: Wall Sweeps; sets with these values: 2
Pset_ProvisionForVoid - Shape: Undefined
Constraints - Offset From Level: 1080 mm; Offset From Wall: 1 mm
Dimensions - Length: 1797.5 mm
Identity Data - Workset: Bouwkundig
Phasing - Phase Created: 2. nieuwbouw
Group: Model Group:Paneel op dak:6286816

# IfcBuildingElementProxy: 6286657
In: 02 tweede verdieping
Pset_ProductRequirements - Category: Walls: Wall Sweeps; sets with these values: 2
Pset_ProvisionForVoid - Shape: Undefined
Constraints - Offset From Level: 960 mm; Offset From Wall: 1 mm
Dimensions - Length: 1797.5 mm
Identity Data - Workset: Bouwkundig
Phasing - Phase Created: 2. nieuwbouw
Group: Model Group:Paneel op dak:6286816

# IfcBuildingElementProxy: 6286658
In: 02 tweede verdieping
Pset_ProductRequirements - Category: Walls: Wall Sweeps; sets with these values: 2
Pset_ProvisionForVoid - Shape: Undefined
Constraints - Offset From Level: 840 mm; Offset From Wall: 1 mm
Dimensions - Length: 1797.5 mm
Identity Data - Workset: Bouwkundig
Phasing - Phase Created: 2. nieuwbouw
Group: Model Group:Paneel op dak:6286816

# IfcBuildingElementProxy: 6286659
In: 02 tweede verdieping
Pset_ProductRequirements - Category: Walls: Wall Sweeps; sets with these values: 2
Pset_ProvisionForVoid - Shape: Undefined
Constraints - Offset From Level: 720 mm; Offset From Wall: 1 mm
Dimensions - Length: 1797.5 mm
Identity Data - Workset: Bouwkundig
Phasing - Phase Created: 2. nieuwbouw
Group: Model Group:Paneel op dak:6286816

# IfcBuildingElementProxy: 6286660
In: 02 tweede verdieping
Pset_ProductRequirements - Category: Walls: Wall Sweeps; sets with these values: 2
Pset_ProvisionForVoid - Shape: Undefined
Constraints - Offset From Level: 600 mm; Offset From Wall: 1 mm
Dimensions - Length: 1797.5 mm
Identity Data - Workset: Bouwkundig
Phasing - Phase Created: 2. nieuwbouw
Group: Model Group:Paneel op dak:6286816

# IfcBuildingElementProxy: 6286661
In: 02 tweede verdieping
Pset_ProductRequirements - Category: Walls: Wall Sweeps; sets with these values: 2
Pset_ProvisionForVoid - Shape: Undefined
Constraints - Offset From Level: 480 mm; Offset From Wall: 1 mm
Dimensions - Length: 1797.5 mm
Identity Data - Workset: Bouwkundig
Phasing - Phase Created: 2. nieuwbouw
Group: Model Group:Paneel op dak:6286816

# IfcBuildingElementProxy: 6286662
In: 02 tweede verdieping
Pset_ProductRequirements - Category: Walls: Wall Sweeps; sets with these values: 2
Pset_ProvisionForVoid - Shape: Undefined
Constraints - Offset From Level: 360 mm; Offset From Wall: 1 mm
Dimensions - Length: 1797.5 mm
Identity Data - Workset: Bouwkundig
Phasing - Phase Created: 2. nieuwbouw
Group: Model Group:Paneel op dak:6286816

# IfcBuildingElementProxy: 6286663
In: 02 tweede verdieping
Pset_ProductRequirements - Category: Walls: Wall Sweeps; sets with these values: 2
Pset_ProvisionForVoid - Shape: Undefined
Constraints - Offset From Level: 240 mm; Offset From Wall: 1 mm
Dimensions - Length: 1797.5 mm
Identity Data - Workset: Bouwkundig
Phasing - Phase Created: 2. nieuwbouw
Group: Model Group:Paneel op dak:6286816

# IfcBuildingElementProxy: 6286664
In: 02 tweede verdieping
Pset_ProductRequirements - Category: Walls: Wall Sweeps; sets with these values: 2
Pset_ProvisionForVoid - Shape: Undefined
Constraints - Offset From Level: 120 mm; Offset From Wall: 1 mm
Dimensions - Length: 1797.5 mm
Identity Data - Workset: Bouwkundig
Phasing - Phase Created: 2. nieuwbouw
Group: Model Group:Paneel op dak:6286816

# IfcBuildingElementProxy: 6286697
In: 02 tweede verdieping
Pset_ProductRequirements - Category: Walls: Wall Sweeps; sets with these values: 2
Pset_ProvisionForVoid - Shape: Undefined
Constraints - Offset From Level: 2040 mm; Offset From Wall: 1 mm
Dimensions - Length: 1797.5 mm
Identity Data - Workset: Bouwkundig
Phasing - Phase Created: 2. nieuwbouw
Group: Model Group:Paneel op dak:6286816

# IfcBuildingElementProxy: 6286698
In: 02 tweede verdieping
Pset_ProductRequirements - Category: Walls: Wall Sweeps; sets with these values: 2
Pset_ProvisionForVoid - Shape: Undefined
Constraints - Offset From Level: 1920 mm; Offset From Wall: 1 mm
Dimensions - Length: 1797.5 mm
Identity Data - Workset: Bouwkundig
Phasing - Phase Created: 2. nieuwbouw
Group: Model Group:Paneel op dak:6286816

# IfcBuildingElementProxy: 6286699
In: 02 tweede verdieping
Pset_ProductRequirements - Category: Walls: Wall Sweeps; sets with these values: 2
Pset_ProvisionForVoid - Shape: Undefined
Constraints - Offset From Level: 1800 mm; Offset From Wall: 1 mm
Dimensions - Length: 1797.5 mm
Identity Data - Workset: Bouwkundig
Phasing - Phase Created: 2. nieuwbouw
Group: Model Group:Paneel op dak:6286816

# IfcBuildingElementProxy: 6286700
In: 02 tweede verdieping
Pset_ProductRequirements - Category: Walls: Wall Sweeps; sets with these values: 2
Pset_ProvisionForVoid - Shape: Undefined
Constraints - Offset From Level: 1680 mm; Offset From Wall: 1 mm
Dimensions - Length: 1797.5 mm
Identity Data - Workset: Bouwkundig
Phasing - Phase Created: 2. nieuwbouw
Group: Model Group:Paneel op dak:6286816

# IfcBuildingElementProxy: 6286701
In: 02 tweede verdieping
Pset_ProductRequirements - Category: Walls: Wall Sweeps; sets with these values: 2
Pset_ProvisionForVoid - Shape: Undefined
Constraints - Offset From Level: 1560 mm; Offset From Wall: 1 mm
Dimensions - Length: 1797.5 mm
Identity Data - Workset: Bouwkundig
Phasing - Phase Created: 2. nieuwbouw
Group: Model Group:Paneel op dak:6286816

# IfcBuildingElementProxy: 6286702
In: 02 tweede verdieping
Pset_ProductRequirements - Category: Walls: Wall Sweeps; sets with these values: 2
Pset_ProvisionForVoid - Shape: Undefined
Constraints - Offset From Level: 1440 mm; Offset From Wall: 1 mm
Dimensions - Length: 1797.5 mm
Identity Data - Workset: Bouwkundig
Phasing - Phase Created: 2. nieuwbouw
Group: Model Group:Paneel op dak:6286816

# IfcBuildingElementProxy: 6286703
In: 02 tweede verdieping
Pset_ProductRequirements - Category: Walls: Wall Sweeps; sets with these values: 2
Pset_ProvisionForVoid - Shape: Undefined
Constraints - Offset From Level: 1320 mm; Offset From Wall: 1 mm
Dimensions - Length: 1797.5 mm
Identity Data - Workset: Bouwkundig
Phasing - Phase Created: 2. nieuwbouw
Group: Model Group:Paneel op dak:6286816

# IfcBuildingElementProxy: 6286704
In: 02 tweede verdieping
Pset_ProductRequirements - Category: Walls: Wall Sweeps; sets with these values: 2
Pset_ProvisionForVoid - Shape: Undefined
Constraints - Offset From Level: 1200 mm; Offset From Wall: 1 mm
Dimensions - Length: 1797.5 mm
Identity Data - Workset: Bouwkundig
Phasing - Phase Created: 2. nieuwbouw
Group: Model Group:Paneel op dak:6286816

# IfcBuildingElementProxy: 6286705
In: 02 tweede verdieping
Pset_ProductRequirements - Category: Walls: Wall Sweeps; sets with these values: 2
Pset_ProvisionForVoid - Shape: Undefined
Constraints - Offset From Level: 1080 mm; Offset From Wall: 1 mm
Dimensions - Length: 1797.5 mm
Identity Data - Workset: Bouwkundig
Phasing - Phase Created: 2. nieuwbouw
Group: Model Group:Paneel op dak:6286816

# IfcBuildingElementProxy: 6286706
In: 02 tweede verdieping
Pset_ProductRequirements - Category: Walls: Wall Sweeps; sets with these values: 2
Pset_ProvisionForVoid - Shape: Undefined
Constraints - Offset From Level: 960 mm; Offset From Wall: 1 mm
Dimensions - Length: 1797.5 mm
Identity Data - Workset: Bouwkundig
Phasing - Phase Created: 2. nieuwbouw
Group: Model Group:Paneel op dak:6286816

# IfcBuildingElementProxy: 6286707
In: 02 tweede verdieping
Pset_ProductRequirements - Category: Walls: Wall Sweeps; sets with these values: 2
Pset_ProvisionForVoid - Shape: Undefined
Constraints - Offset From Level: 840 mm; Offset From Wall: 1 mm
Dimensions - Length: 1797.5 mm
Identity Data - Workset: Bouwkundig
Phasing - Phase Created: 2. nieuwbouw
Group: Model Group:Paneel op dak:6286816

# IfcBuildingElementProxy: 6286708
In: 02 tweede verdieping
Pset_ProductRequirements - Category: Walls: Wall Sweeps; sets with these values: 2
Pset_ProvisionForVoid - Shape: Undefined
Constraints - Offset From Level: 720 mm; Offset From Wall: 1 mm
Dimensions - Length: 1797.5 mm
Identity Data - Workset: Bouwkundig
Phasing - Phase Created: 2. nieuwbouw
Group: Model Group:Paneel op dak:6286816

# IfcBuildingElementProxy: 6286709
In: 02 tweede verdieping
Pset_ProductRequirements - Category: Walls: Wall Sweeps; sets with these values: 2
Pset_ProvisionForVoid - Shape: Undefined
Constraints - Offset From Level: 600 mm; Offset From Wall: 1 mm
Dimensions - Length: 1797.5 mm
Identity Data - Workset: Bouwkundig
Phasing - Phase Created: 2. nieuwbouw
Group: Model Group:Paneel op dak:6286816

# IfcBuildingElementProxy: 6286710
In: 02 tweede verdieping
Pset_ProductRequirements - Category: Walls: Wall Sweeps; sets with these values: 2
Pset_ProvisionForVoid - Shape: Undefined
Constraints - Offset From Level: 480 mm; Offset From Wall: 1 mm
Dimensions - Length: 1797.5 mm
Identity Data - Workset: Bouwkundig
Phasing - Phase Created: 2. nieuwbouw
Group: Model Group:Paneel op dak:6286816

# IfcBuildingElementProxy: 6286711
In: 02 tweede verdieping
Pset_ProductRequirements - Category: Walls: Wall Sweeps; sets with these values: 2
Pset_ProvisionForVoid - Shape: Undefined
Constraints - Offset From Level: 360 mm; Offset From Wall: 1 mm
Dimensions - Length: 1797.5 mm
Identity Data - Workset: Bouwkundig
Phasing - Phase Created: 2. nieuwbouw
Group: Model Group:Paneel op dak:6286816

# IfcBuildingElementProxy: 6286712
In: 02 tweede verdieping
Pset_ProductRequirements - Category: Walls: Wall Sweeps; sets with these values: 2
Pset_ProvisionForVoid - Shape: Undefined
Constraints - Offset From Level: 240 mm; Offset From Wall: 1 mm
Dimensions - Length: 1797.5 mm
Identity Data - Workset: Bouwkundig
Phasing - Phase Created: 2. nieuwbouw
Group: Model Group:Paneel op dak:6286816

# IfcBuildingElementProxy: 6286713
In: 02 tweede verdieping
Pset_ProductRequirements - Category: Walls: Wall Sweeps; sets with these values: 2
Pset_ProvisionForVoid - Shape: Undefined
Constraints - Offset From Level: 120 mm; Offset From Wall: 1 mm
Dimensions - Length: 1797.5 mm
Identity Data - Workset: Bouwkundig
Phasing - Phase Created: 2. nieuwbouw
Group: Model Group:Paneel op dak:6286816

# IfcBuildingElementProxy: 6286746
In: 02 tweede verdieping
Pset_ProductRequirements - Category: Walls: Wall Sweeps; sets with these values: 2
Constraints - Offset From Level: 2040 mm; Offset From Wall: 1 mm
Dimensions - Length: 1797.5 mm
Identity Data - Workset: Bouwkundig
Phasing - Phase Created: 2. nieuwbouw
Group: Model Group:Paneel op dak:6286816

# IfcBuildingElementProxy: 6286747
In: 02 tweede verdieping
Pset_ProductRequirements - Category: Walls: Wall Sweeps; sets with these values: 2
Constraints - Offset From Level: 1920 mm; Offset From Wall: 1 mm
Dimensions - Length: 1797.5 mm
Identity Data - Workset: Bouwkundig
Phasing - Phase Created: 2. nieuwbouw
Group: Model Group:Paneel op dak:6286816

# IfcBuildingElementProxy: 6286748
In: 02 tweede verdieping
Pset_ProductRequirements - Category: Walls: Wall Sweeps; sets with these values: 2
Constraints - Offset From Level: 1800 mm; Offset From Wall: 1 mm
Dimensions - Length: 1797.5 mm
Identity Data - Workset: Bouwkundig
Phasing - Phase Created: 2. nieuwbouw
Group: Model Group:Paneel op dak:6286816

# IfcBuildingElementProxy: 6286749
In: 02 tweede verdieping
Pset_ProductRequirements - Category: Walls: Wall Sweeps; sets with these values: 2
Constraints - Offset From Level: 1680 mm; Offset From Wall: 1 mm
Dimensions - Length: 1797.5 mm
Identity Data - Workset: Bouwkundig
Phasing - Phase Created: 2. nieuwbouw
Group: Model Group:Paneel op dak:6286816

# IfcBuildingElementProxy: 6286750
In: 02 tweede verdieping
Pset_ProductRequirements - Category: Walls: Wall Sweeps; sets with these values: 2
Constraints - Offset From Level: 1560 mm; Offset From Wall: 1 mm
Dimensions - Length: 1797.5 mm
Identity Data - Workset: Bouwkundig
Phasing - Phase Created: 2. nieuwbouw
Group: Model Group:Paneel op dak:6286816

# IfcBuildingElementProxy: 6286751
In: 02 tweede verdieping
Pset_ProductRequirements - Category: Walls: Wall Sweeps; sets with these values: 2
Constraints - Offset From Level: 1440 mm; Offset From Wall: 1 mm
Dimensions - Length: 1797.5 mm
Identity Data - Workset: Bouwkundig
Phasing - Phase Created: 2. nieuwbouw
Group: Model Group:Paneel op dak:6286816

# IfcBuildingElementProxy: 6286752
In: 02 tweede verdieping
Pset_ProductRequirements - Category: Walls: Wall Sweeps; sets with these values: 2
Constraints - Offset From Level: 1320 mm; Offset From Wall: 1 mm
Dimensions - Length: 1797.5 mm
Identity Data - Workset: Bouwkundig
Phasing - Phase Created: 2. nieuwbouw
Group: Model Group:Paneel op dak:6286816

# IfcBuildingElementProxy: 6286753
In: 02 tweede verdieping
Pset_ProductRequirements - Category: Walls: Wall Sweeps; sets with these values: 2
Constraints - Offset From Level: 1200 mm; Offset From Wall: 1 mm
Dimensions - Length: 1797.5 mm
Identity Data - Workset: Bouwkundig
Phasing - Phase Created: 2. nieuwbouw
Group: Model Group:Paneel op dak:6286816

# IfcBuildingElementProxy: 6286754
In: 02 tweede verdieping
Pset_ProductRequirements - Category: Walls: Wall Sweeps; sets with these values: 2
Constraints - Offset From Level: 1080 mm; Offset From Wall: 1 mm
Dimensions - Length: 1797.5 mm
Identity Data - Workset: Bouwkundig
Phasing - Phase Created: 2. nieuwbouw
Group: Model Group:Paneel op dak:6286816

# IfcBuildingElementProxy: 6286755
In: 02 tweede verdieping
Pset_ProductRequirements - Category: Walls: Wall Sweeps; sets with these values: 2
Constraints - Offset From Level: 960 mm; Offset From Wall: 1 mm
Dimensions - Length: 1797.5 mm
Identity Data - Workset: Bouwkundig
Phasing - Phase Created: 2. nieuwbouw
Group: Model Group:Paneel op dak:6286816

# IfcBuildingElementProxy: 6286756
In: 02 tweede verdieping
Pset_ProductRequirements - Category: Walls: Wall Sweeps; sets with these values: 2
Constraints - Offset From Level: 840 mm; Offset From Wall: 1 mm
Dimensions - Length: 1797.5 mm
Identity Data - Workset: Bouwkundig
Phasing - Phase Created: 2. nieuwbouw
Group: Model Group:Paneel op dak:6286816

# IfcBuildingElementProxy: 6286757
In: 02 tweede verdieping
Pset_ProductRequirements - Category: Walls: Wall Sweeps; sets with these values: 2
Constraints - Offset From Level: 720 mm; Offset From Wall: 1 mm
Dimensions - Length: 1797.5 mm
Identity Data - Workset: Bouwkundig
Phasing - Phase Created: 2. nieuwbouw
Group: Model Group:Paneel op dak:6286816

# IfcBuildingElementProxy: 6286758
In: 02 tweede verdieping
Pset_ProductRequirements - Category: Walls: Wall Sweeps; sets with these values: 2
Constraints - Offset From Level: 600 mm; Offset From Wall: 1 mm
Dimensions - Length: 1797.5 mm
Identity Data - Workset: Bouwkundig
Phasing - Phase Created: 2. nieuwbouw
Group: Model Group:Paneel op dak:6286816

# IfcBuildingElementProxy: 6286759
In: 02 tweede verdieping
Pset_ProductRequirements - Category: Walls: Wall Sweeps; sets with these values: 2
Constraints - Offset From Level: 480 mm; Offset From Wall: 1 mm
Dimensions - Length: 1797.5 mm
Identity Data - Workset: Bouwkundig
Phasing - Phase Created: 2. nieuwbouw
Group: Model Group:Paneel op dak:6286816

# IfcBuildingElementProxy: 6286760
In: 02 tweede verdieping
Pset_ProductRequirements - Category: Walls: Wall Sweeps; sets with these values: 2
Constraints - Offset From Level: 360 mm; Offset From Wall: 1 mm
Dimensions - Length: 1797.5 mm
Identity Data - Workset: Bouwkundig
Phasing - Phase Created: 2. nieuwbouw
Group: Model Group:Paneel op dak:6286816

# IfcBuildingElementProxy: 6286761
In: 02 tweede verdieping
Pset_ProductRequirements - Category: Walls: Wall Sweeps; sets with these values: 2
Constraints - Offset From Level: 240 mm; Offset From Wall: 1 mm
Dimensions - Length: 1797.5 mm
Identity Data - Workset: Bouwkundig
Phasing - Phase Created: 2. nieuwbouw
Group: Model Group:Paneel op dak:6286816

# IfcBuildingElementProxy: 6286762
In: 02 tweede verdieping
Pset_ProductRequirements - Category: Walls: Wall Sweeps; sets with these values: 2
Constraints - Offset From Level: 120 mm; Offset From Wall: 1 mm
Dimensions - Length: 1797.5 mm
Identity Data - Workset: Bouwkundig
Phasing - Phase Created: 2. nieuwbouw
Group: Model Group:Paneel op dak:6286816

# IfcBuildingElementProxy: 6286799
In: 02 tweede verdieping
Pset_ProductRequirements - Category: Walls: Wall Sweeps; sets with these values: 2
Pset_ProvisionForVoid - Shape: Undefined
Constraints - Offset From Level: 2040 mm; Offset From Wall: 1 mm
Dimensions - Length: 1797.5 mm
Identity Data - Workset: Bouwkundig
Phasing - Phase Created: 2. nieuwbouw
Group: Model Group:Paneel op dak:6286816

# IfcBuildingElementProxy: 6286800
In: 02 tweede verdieping
Pset_ProductRequirements - Category: Walls: Wall Sweeps; sets with these values: 2
Pset_ProvisionForVoid - Shape: Undefined
Constraints - Offset From Level: 1920 mm; Offset From Wall: 1 mm
Dimensions - Length: 1797.5 mm
Identity Data - Workset: Bouwkundig
Phasing - Phase Created: 2. nieuwbouw
Group: Model Group:Paneel op dak:6286816

# IfcBuildingElementProxy: 6286801
In: 02 tweede verdieping
Pset_ProductRequirements - Category: Walls: Wall Sweeps; sets with these values: 2
Pset_ProvisionForVoid - Shape: Undefined
Constraints - Offset From Level: 1800 mm; Offset From Wall: 1 mm
Dimensions - Length: 1797.5 mm
Identity Data - Workset: Bouwkundig
Phasing - Phase Created: 2. nieuwbouw
Group: Model Group:Paneel op dak:6286816

# IfcBuildingElementProxy: 6286802
In: 02 tweede verdieping
Pset_ProductRequirements - Category: Walls: Wall Sweeps; sets with these values: 2
Pset_ProvisionForVoid - Shape: Undefined
Constraints - Offset From Level: 1680 mm; Offset From Wall: 1 mm
Dimensions - Length: 1797.5 mm
Identity Data - Workset: Bouwkundig
Phasing - Phase Created: 2. nieuwbouw
Group: Model Group:Paneel op dak:6286816

# IfcBuildingElementProxy: 6286803
In: 02 tweede verdieping
Pset_ProductRequirements - Category: Walls: Wall Sweeps; sets with these values: 2
Pset_ProvisionForVoid - Shape: Undefined
Constraints - Offset From Level: 1560 mm; Offset From Wall: 1 mm
Dimensions - Length: 1797.5 mm
Identity Data - Workset: Bouwkundig
Phasing - Phase Created: 2. nieuwbouw
Group: Model Group:Paneel op dak:6286816

# IfcBuildingElementProxy: 6286804
In: 02 tweede verdieping
Pset_ProductRequirements - Category: Walls: Wall Sweeps; sets with these values: 2
Pset_ProvisionForVoid - Shape: Undefined
Constraints - Offset From Level: 1440 mm; Offset From Wall: 1 mm
Dimensions - Length: 1797.5 mm
Identity Data - Workset: Bouwkundig
Phasing - Phase Created: 2. nieuwbouw
Group: Model Group:Paneel op dak:6286816

# IfcBuildingElementProxy: 6286805
In: 02 tweede verdieping
Pset_ProductRequirements - Category: Walls: Wall Sweeps; sets with these values: 2
Pset_ProvisionForVoid - Shape: Undefined
Constraints - Offset From Level: 1320 mm; Offset From Wall: 1 mm
Dimensions - Length: 1797.5 mm
Identity Data - Workset: Bouwkundig
Phasing - Phase Created: 2. nieuwbouw
Group: Model Group:Paneel op dak:6286816

# IfcBuildingElementProxy: 6286806
In: 02 tweede verdieping
Pset_ProductRequirements - Category: Walls: Wall Sweeps; sets with these values: 2
Pset_ProvisionForVoid - Shape: Undefined
Constraints - Offset From Level: 1200 mm; Offset From Wall: 1 mm
Dimensions - Length: 1797.5 mm
Identity Data - Workset: Bouwkundig
Phasing - Phase Created: 2. nieuwbouw
Group: Model Group:Paneel op dak:6286816

# IfcBuildingElementProxy: 6286807
In: 02 tweede verdieping
Pset_ProductRequirements - Category: Walls: Wall Sweeps; sets with these values: 2
Pset_ProvisionForVoid - Shape: Undefined
Constraints - Offset From Level: 1080 mm; Offset From Wall: 1 mm
Dimensions - Length: 1797.5 mm
Identity Data - Workset: Bouwkundig
Phasing - Phase Created: 2. nieuwbouw
Group: Model Group:Paneel op dak:6286816

# IfcBuildingElementProxy: 6286808
In: 02 tweede verdieping
Pset_ProductRequirements - Category: Walls: Wall Sweeps; sets with these values: 2
Pset_ProvisionForVoid - Shape: Undefined
Constraints - Offset From Level: 960 mm; Offset From Wall: 1 mm
Dimensions - Length: 1797.5 mm
Identity Data - Workset: Bouwkundig
Phasing - Phase Created: 2. nieuwbouw
Group: Model Group:Paneel op dak:6286816

# IfcBuildingElementProxy: 6286809
In: 02 tweede verdieping
Pset_ProductRequirements - Category: Walls: Wall Sweeps; sets with these values: 2
Pset_ProvisionForVoid - Shape: Undefined
Constraints - Offset From Level: 840 mm; Offset From Wall: 1 mm
Dimensions - Length: 1797.5 mm
Identity Data - Workset: Bouwkundig
Phasing - Phase Created: 2. nieuwbouw
Group: Model Group:Paneel op dak:6286816

# IfcBuildingElementProxy: 6286810
In: 02 tweede verdieping
Pset_ProductRequirements - Category: Walls: Wall Sweeps; sets with these values: 2
Pset_ProvisionForVoid - Shape: Undefined
Constraints - Offset From Level: 720 mm; Offset From Wall: 1 mm
Dimensions - Length: 1797.5 mm
Identity Data - Workset: Bouwkundig
Phasing - Phase Created: 2. nieuwbouw
Group: Model Group:Paneel op dak:6286816

# IfcBuildingElementProxy: 6286811
In: 02 tweede verdieping
Pset_ProductRequirements - Category: Walls: Wall Sweeps; sets with these values: 2
Pset_ProvisionForVoid - Shape: Undefined
Constraints - Offset From Level: 600 mm; Offset From Wall: 1 mm
Dimensions - Length: 1797.5 mm
Identity Data - Workset: Bouwkundig
Phasing - Phase Created: 2. nieuwbouw
Group: Model Group:Paneel op dak:6286816

# IfcBuildingElementProxy: 6286812
In: 02 tweede verdieping
Pset_ProductRequirements - Category: Walls: Wall Sweeps; sets with these values: 2
Pset_ProvisionForVoid - Shape: Undefined
Constraints - Offset From Level: 480 mm; Offset From Wall: 1 mm
Dimensions - Length: 1797.5 mm
Identity Data - Workset: Bouwkundig
Phasing - Phase Created: 2. nieuwbouw
Group: Model Group:Paneel op dak:6286816

# IfcBuildingElementProxy: 6286813
In: 02 tweede verdieping
Pset_ProductRequirements - Category: Walls: Wall Sweeps; sets with these values: 2
Pset_ProvisionForVoid - Shape: Undefined
Constraints - Offset From Level: 360 mm; Offset From Wall: 1 mm
Dimensions - Length: 1797.5 mm
Identity Data - Workset: Bouwkundig
Phasing - Phase Created: 2. nieuwbouw
Group: Model Group:Paneel op dak:6286816

# IfcBuildingElementProxy: 6286814
In: 02 tweede verdieping
Pset_ProductRequirements - Category: Walls: Wall Sweeps; sets with these values: 2
Pset_ProvisionForVoid - Shape: Undefined
Constraints - Offset From Level: 240 mm; Offset From Wall: 1 mm
Dimensions - Length: 1797.5 mm
Identity Data - Workset: Bouwkundig
Phasing - Phase Created: 2. nieuwbouw
Group: Model Group:Paneel op dak:6286816

# IfcBuildingElementProxy: 6286815
In: 02 tweede verdieping
Pset_ProductRequirements - Category: Walls: Wall Sweeps; sets with these values: 2
Pset_ProvisionForVoid - Shape: Undefined
Constraints - Offset From Level: 120 mm; Offset From Wall: 1 mm
Dimensions - Length: 1797.5 mm
Identity Data - Workset: Bouwkundig
Phasing - Phase Created: 2. nieuwbouw
Group: Model Group:Paneel op dak:6286816

# IfcBuildingElementProxy: 6287125
In: 02 tweede verdieping
Pset_ProductRequirements - Category: Walls: Wall Sweeps; sets with these values: 2
Constraints - Offset From Level: 2040 mm; Offset From Wall: 1 mm
Dimensions - Length: 1807.5 mm
Identity Data - Workset: Bouwkundig
Phasing - Phase Created: 2. nieuwbouw
Group: Model Group:Paneel op dak:6287293

# IfcBuildingElementProxy: 6287126
In: 02 tweede verdieping
Pset_ProductRequirements - Category: Walls: Wall Sweeps; sets with these values: 2
Pset_ProvisionForVoid - Shape: Undefined
Constraints - Offset From Level: 1920 mm; Offset From Wall: 1 mm
Dimensions - Length: 1807.5 mm
Identity Data - Workset: Bouwkundig
Phasing - Phase Created: 2. nieuwbouw
Group: Model Group:Paneel op dak:6287293

# IfcBuildingElementProxy: 6287127
In: 02 tweede verdieping
Pset_ProductRequirements - Category: Walls: Wall Sweeps; sets with these values: 2
Pset_ProvisionForVoid - Shape: Undefined
Constraints - Offset From Level: 1800 mm; Offset From Wall: 1 mm
Dimensions - Length: 1807.5 mm
Identity Data - Workset: Bouwkundig
Phasing - Phase Created: 2. nieuwbouw
Group: Model Group:Paneel op dak:6287293

# IfcBuildingElementProxy: 6287128
In: 02 tweede verdieping
Pset_ProductRequirements - Category: Walls: Wall Sweeps; sets with these values: 2
Pset_ProvisionForVoid - Shape: Undefined
Constraints - Offset From Level: 1680 mm; Offset From Wall: 1 mm
Dimensions - Length: 1807.5 mm
Identity Data - Workset: Bouwkundig
Phasing - Phase Created: 2. nieuwbouw
Group: Model Group:Paneel op dak:6287293

# IfcBuildingElementProxy: 6287129
In: 02 tweede verdieping
Pset_ProductRequirements - Category: Walls: Wall Sweeps; sets with these values: 2
Pset_ProvisionForVoid - Shape: Undefined
Constraints - Offset From Level: 1560 mm; Offset From Wall: 1 mm
Dimensions - Length: 1807.5 mm
Identity Data - Workset: Bouwkundig
Phasing - Phase Created: 2. nieuwbouw
Group: Model Group:Paneel op dak:6287293

# IfcBuildingElementProxy: 6287130
In: 02 tweede verdieping
Pset_ProductRequirements - Category: Walls: Wall Sweeps; sets with these values: 2
Pset_ProvisionForVoid - Shape: Undefined
Constraints - Offset From Level: 1440 mm; Offset From Wall: 1 mm
Dimensions - Length: 1807.5 mm
Identity Data - Workset: Bouwkundig
Phasing - Phase Created: 2. nieuwbouw
Group: Model Group:Paneel op dak:6287293

# IfcBuildingElementProxy: 6287131
In: 02 tweede verdieping
Pset_ProductRequirements - Category: Walls: Wall Sweeps; sets with these values: 2
Pset_ProvisionForVoid - Shape: Undefined
Constraints - Offset From Level: 1320 mm; Offset From Wall: 1 mm
Dimensions - Length: 1807.5 mm
Identity Data - Workset: Bouwkundig
Phasing - Phase Created: 2. nieuwbouw
Group: Model Group:Paneel op dak:6287293

# IfcBuildingElementProxy: 6287132
In: 02 tweede verdieping
Pset_ProductRequirements - Category: Walls: Wall Sweeps; sets with these values: 2
Pset_ProvisionForVoid - Shape: Undefined
Constraints - Offset From Level: 1200 mm; Offset From Wall: 1 mm
Dimensions - Length: 1807.5 mm
Identity Data - Workset: Bouwkundig
Phasing - Phase Created: 2. nieuwbouw
Group: Model Group:Paneel op dak:6287293

# IfcBuildingElementProxy: 6287133
In: 02 tweede verdieping
Pset_ProductRequirements - Category: Walls: Wall Sweeps; sets with these values: 2
Pset_ProvisionForVoid - Shape: Undefined
Constraints - Offset From Level: 1080 mm; Offset From Wall: 1 mm
Dimensions - Length: 1807.5 mm
Identity Data - Workset: Bouwkundig
Phasing - Phase Created: 2. nieuwbouw
Group: Model Group:Paneel op dak:6287293

# IfcBuildingElementProxy: 6287134
In: 02 tweede verdieping
Pset_ProductRequirements - Category: Walls: Wall Sweeps; sets with these values: 2
Pset_ProvisionForVoid - Shape: Undefined
Constraints - Offset From Level: 960 mm; Offset From Wall: 1 mm
Dimensions - Length: 1807.5 mm
Identity Data - Workset: Bouwkundig
Phasing - Phase Created: 2. nieuwbouw
Group: Model Group:Paneel op dak:6287293

# IfcBuildingElementProxy: 6287135
In: 02 tweede verdieping
Pset_ProductRequirements - Category: Walls: Wall Sweeps; sets with these values: 2
Pset_ProvisionForVoid - Shape: Undefined
Constraints - Offset From Level: 840 mm; Offset From Wall: 1 mm
Dimensions - Length: 1807.5 mm
Identity Data - Workset: Bouwkundig
Phasing - Phase Created: 2. nieuwbouw
Group: Model Group:Paneel op dak:6287293

# IfcBuildingElementProxy: 6287136
In: 02 tweede verdieping
Pset_ProductRequirements - Category: Walls: Wall Sweeps; sets with these values: 2
Pset_ProvisionForVoid - Shape: Undefined
Constraints - Offset From Level: 720 mm; Offset From Wall: 1 mm
Dimensions - Length: 1807.5 mm
Identity Data - Workset: Bouwkundig
Phasing - Phase Created: 2. nieuwbouw
Group: Model Group:Paneel op dak:6287293

# IfcBuildingElementProxy: 6287137
In: 02 tweede verdieping
Pset_ProductRequirements - Category: Walls: Wall Sweeps; sets with these values: 2
Pset_ProvisionForVoid - Shape: Undefined
Constraints - Offset From Level: 600 mm; Offset From Wall: 1 mm
Dimensions - Length: 1807.5 mm
Identity Data - Workset: Bouwkundig
Phasing - Phase Created: 2. nieuwbouw
Group: Model Group:Paneel op dak:6287293

# IfcBuildingElementProxy: 6287138
In: 02 tweede verdieping
Pset_ProductRequirements - Category: Walls: Wall Sweeps; sets with these values: 2
Pset_ProvisionForVoid - Shape: Undefined
Constraints - Offset From Level: 480 mm; Offset From Wall: 1 mm
Dimensions - Length: 1807.5 mm
Identity Data - Workset: Bouwkundig
Phasing - Phase Created: 2. nieuwbouw
Group: Model Group:Paneel op dak:6287293

# IfcBuildingElementProxy: 6287139
In: 02 tweede verdieping
Pset_ProductRequirements - Category: Walls: Wall Sweeps; sets with these values: 2
Pset_ProvisionForVoid - Shape: Undefined
Constraints - Offset From Level: 360 mm; Offset From Wall: 1 mm
Dimensions - Length: 1807.5 mm
Identity Data - Workset: Bouwkundig
Phasing - Phase Created: 2. nieuwbouw
Group: Model Group:Paneel op dak:6287293

# IfcBuildingElementProxy: 6287140
In: 02 tweede verdieping
Pset_ProductRequirements - Category: Walls: Wall Sweeps; sets with these values: 2
Pset_ProvisionForVoid - Shape: Undefined
Constraints - Offset From Level: 240 mm; Offset From Wall: 1 mm
Dimensions - Length: 1807.5 mm
Identity Data - Workset: Bouwkundig
Phasing - Phase Created: 2. nieuwbouw
Group: Model Group:Paneel op dak:6287293

# IfcBuildingElementProxy: 6287141
In: 02 tweede verdieping
Pset_ProductRequirements - Category: Walls: Wall Sweeps; sets with these values: 2
Pset_ProvisionForVoid - Shape: Undefined
Constraints - Offset From Level: 120 mm; Offset From Wall: 1 mm
Dimensions - Length: 1807.5 mm
Identity Data - Workset: Bouwkundig
Phasing - Phase Created: 2. nieuwbouw
Group: Model Group:Paneel op dak:6287293

# IfcBuildingElementProxy: 6287174
In: 02 tweede verdieping
Pset_ProductRequirements - Category: Walls: Wall Sweeps; sets with these values: 2
Pset_ProvisionForVoid - Shape: Undefined
Constraints - Offset From Level: 2040 mm; Offset From Wall: 1 mm
Dimensions - Length: 1797.5 mm
Identity Data - Workset: Bouwkundig
Phasing - Phase Created: 2. nieuwbouw
Group: Model Group:Paneel op dak:6287293

# IfcBuildingElementProxy: 6287175
In: 02 tweede verdieping
Pset_ProductRequirements - Category: Walls: Wall Sweeps; sets with these values: 2
Pset_ProvisionForVoid - Shape: Undefined
Constraints - Offset From Level: 1920 mm; Offset From Wall: 1 mm
Dimensions - Length: 1797.5 mm
Identity Data - Workset: Bouwkundig
Phasing - Phase Created: 2. nieuwbouw
Group: Model Group:Paneel op dak:6287293

# IfcBuildingElementProxy: 6287176
In: 02 tweede verdieping
Pset_ProductRequirements - Category: Walls: Wall Sweeps; sets with these values: 2
Pset_ProvisionForVoid - Shape: Undefined
Constraints - Offset From Level: 1800 mm; Offset From Wall: 1 mm
Dimensions - Length: 1797.5 mm
Identity Data - Workset: Bouwkundig
Phasing - Phase Created: 2. nieuwbouw
Group: Model Group:Paneel op dak:6287293

# IfcBuildingElementProxy: 6287177
In: 02 tweede verdieping
Pset_ProductRequirements - Category: Walls: Wall Sweeps; sets with these values: 2
Pset_ProvisionForVoid - Shape: Undefined
Constraints - Offset From Level: 1680 mm; Offset From Wall: 1 mm
Dimensions - Length: 1797.5 mm
Identity Data - Workset: Bouwkundig
Phasing - Phase Created: 2. nieuwbouw
Group: Model Group:Paneel op dak:6287293

# IfcBuildingElementProxy: 6287178
In: 02 tweede verdieping
Pset_ProductRequirements - Category: Walls: Wall Sweeps; sets with these values: 2
Pset_ProvisionForVoid - Shape: Undefined
Constraints - Offset From Level: 1560 mm; Offset From Wall: 1 mm
Dimensions - Length: 1797.5 mm
Identity Data - Workset: Bouwkundig
Phasing - Phase Created: 2. nieuwbouw
Group: Model Group:Paneel op dak:6287293

# IfcBuildingElementProxy: 6287179
In: 02 tweede verdieping
Pset_ProductRequirements - Category: Walls: Wall Sweeps; sets with these values: 2
Pset_ProvisionForVoid - Shape: Undefined
Constraints - Offset From Level: 1440 mm; Offset From Wall: 1 mm
Dimensions - Length: 1797.5 mm
Identity Data - Workset: Bouwkundig
Phasing - Phase Created: 2. nieuwbouw
Group: Model Group:Paneel op dak:6287293

# IfcBuildingElementProxy: 6287180
In: 02 tweede verdieping
Pset_ProductRequirements - Category: Walls: Wall Sweeps; sets with these values: 2
Pset_ProvisionForVoid - Shape: Undefined
Constraints - Offset From Level: 1320 mm; Offset From Wall: 1 mm
Dimensions - Length: 1797.5 mm
Identity Data - Workset: Bouwkundig
Phasing - Phase Created: 2. nieuwbouw
Group: Model Group:Paneel op dak:6287293

# IfcBuildingElementProxy: 6287181
In: 02 tweede verdieping
Pset_ProductRequirements - Category: Walls: Wall Sweeps; sets with these values: 2
Pset_ProvisionForVoid - Shape: Undefined
Constraints - Offset From Level: 1200 mm; Offset From Wall: 1 mm
Dimensions - Length: 1797.5 mm
Identity Data - Workset: Bouwkundig
Phasing - Phase Created: 2. nieuwbouw
Group: Model Group:Paneel op dak:6287293

# IfcBuildingElementProxy: 6287182
In: 02 tweede verdieping
Pset_ProductRequirements - Category: Walls: Wall Sweeps; sets with these values: 2
Pset_ProvisionForVoid - Shape: Undefined
Constraints - Offset From Level: 1080 mm; Offset From Wall: 1 mm
Dimensions - Length: 1797.5 mm
Identity Data - Workset: Bouwkundig
Phasing - Phase Created: 2. nieuwbouw
Group: Model Group:Paneel op dak:6287293

# IfcBuildingElementProxy: 6287183
In: 02 tweede verdieping
Pset_ProductRequirements - Category: Walls: Wall Sweeps; sets with these values: 2
Pset_ProvisionForVoid - Shape: Undefined
Constraints - Offset From Level: 960 mm; Offset From Wall: 1 mm
Dimensions - Length: 1797.5 mm
Identity Data - Workset: Bouwkundig
Phasing - Phase Created: 2. nieuwbouw
Group: Model Group:Paneel op dak:6287293

# IfcBuildingElementProxy: 6287184
In: 02 tweede verdieping
Pset_ProductRequirements - Category: Walls: Wall Sweeps; sets with these values: 2
Pset_ProvisionForVoid - Shape: Undefined
Constraints - Offset From Level: 840 mm; Offset From Wall: 1 mm
Dimensions - Length: 1797.5 mm
Identity Data - Workset: Bouwkundig
Phasing - Phase Created: 2. nieuwbouw
Group: Model Group:Paneel op dak:6287293

# IfcBuildingElementProxy: 6287185
In: 02 tweede verdieping
Pset_ProductRequirements - Category: Walls: Wall Sweeps; sets with these values: 2
Pset_ProvisionForVoid - Shape: Undefined
Constraints - Offset From Level: 720 mm; Offset From Wall: 1 mm
Dimensions - Length: 1797.5 mm
Identity Data - Workset: Bouwkundig
Phasing - Phase Created: 2. nieuwbouw
Group: Model Group:Paneel op dak:6287293

# IfcBuildingElementProxy: 6287186
In: 02 tweede verdieping
Pset_ProductRequirements - Category: Walls: Wall Sweeps; sets with these values: 2
Pset_ProvisionForVoid - Shape: Undefined
Constraints - Offset From Level: 600 mm; Offset From Wall: 1 mm
Dimensions - Length: 1797.5 mm
Identity Data - Workset: Bouwkundig
Phasing - Phase Created: 2. nieuwbouw
Group: Model Group:Paneel op dak:6287293

# IfcBuildingElementProxy: 6287187
In: 02 tweede verdieping
Pset_ProductRequirements - Category: Walls: Wall Sweeps; sets with these values: 2
Pset_ProvisionForVoid - Shape: Undefined
Constraints - Offset From Level: 480 mm; Offset From Wall: 1 mm
Dimensions - Length: 1797.5 mm
Identity Data - Workset: Bouwkundig
Phasing - Phase Created: 2. nieuwbouw
Group: Model Group:Paneel op dak:6287293

# IfcBuildingElementProxy: 6287188
In: 02 tweede verdieping
Pset_ProductRequirements - Category: Walls: Wall Sweeps; sets with these values: 2
Pset_ProvisionForVoid - Shape: Undefined
Constraints - Offset From Level: 360 mm; Offset From Wall: 1 mm
Dimensions - Length: 1797.5 mm
Identity Data - Workset: Bouwkundig
Phasing - Phase Created: 2. nieuwbouw
Group: Model Group:Paneel op dak:6287293

# IfcBuildingElementProxy: 6287189
In: 02 tweede verdieping
Pset_ProductRequirements - Category: Walls: Wall Sweeps; sets with these values: 2
Pset_ProvisionForVoid - Shape: Undefined
Constraints - Offset From Level: 240 mm; Offset From Wall: 1 mm
Dimensions - Length: 1797.5 mm
Identity Data - Workset: Bouwkundig
Phasing - Phase Created: 2. nieuwbouw
Group: Model Group:Paneel op dak:6287293

# IfcBuildingElementProxy: 6287190
In: 02 tweede verdieping
Pset_ProductRequirements - Category: Walls: Wall Sweeps; sets with these values: 2
Pset_ProvisionForVoid - Shape: Undefined
Constraints - Offset From Level: 120 mm; Offset From Wall: 1 mm
Dimensions - Length: 1797.5 mm
Identity Data - Workset: Bouwkundig
Phasing - Phase Created: 2. nieuwbouw
Group: Model Group:Paneel op dak:6287293

# IfcBuildingElementProxy: 6287223
In: 02 tweede verdieping
Pset_ProductRequirements - Category: Walls: Wall Sweeps; sets with these values: 2
Constraints - Offset From Level: 2040 mm; Offset From Wall: 1 mm
Dimensions - Length: 1797.5 mm
Identity Data - Workset: Bouwkundig
Phasing - Phase Created: 2. nieuwbouw
Group: Model Group:Paneel op dak:6287293

# IfcBuildingElementProxy: 6287224
In: 02 tweede verdieping
Pset_ProductRequirements - Category: Walls: Wall Sweeps; sets with these values: 2
Constraints - Offset From Level: 1920 mm; Offset From Wall: 1 mm
Dimensions - Length: 1797.5 mm
Identity Data - Workset: Bouwkundig
Phasing - Phase Created: 2. nieuwbouw
Group: Model Group:Paneel op dak:6287293

# IfcBuildingElementProxy: 6287225
In: 02 tweede verdieping
Pset_ProductRequirements - Category: Walls: Wall Sweeps; sets with these values: 2
Constraints - Offset From Level: 1800 mm; Offset From Wall: 1 mm
Dimensions - Length: 1797.5 mm
Identity Data - Workset: Bouwkundig
Phasing - Phase Created: 2. nieuwbouw
Group: Model Group:Paneel op dak:6287293

# IfcBuildingElementProxy: 6287226
In: 02 tweede verdieping
Pset_ProductRequirements - Category: Walls: Wall Sweeps; sets with these values: 2
Constraints - Offset From Level: 1680 mm; Offset From Wall: 1 mm
Dimensions - Length: 1797.5 mm
Identity Data - Workset: Bouwkundig
Phasing - Phase Created: 2. nieuwbouw
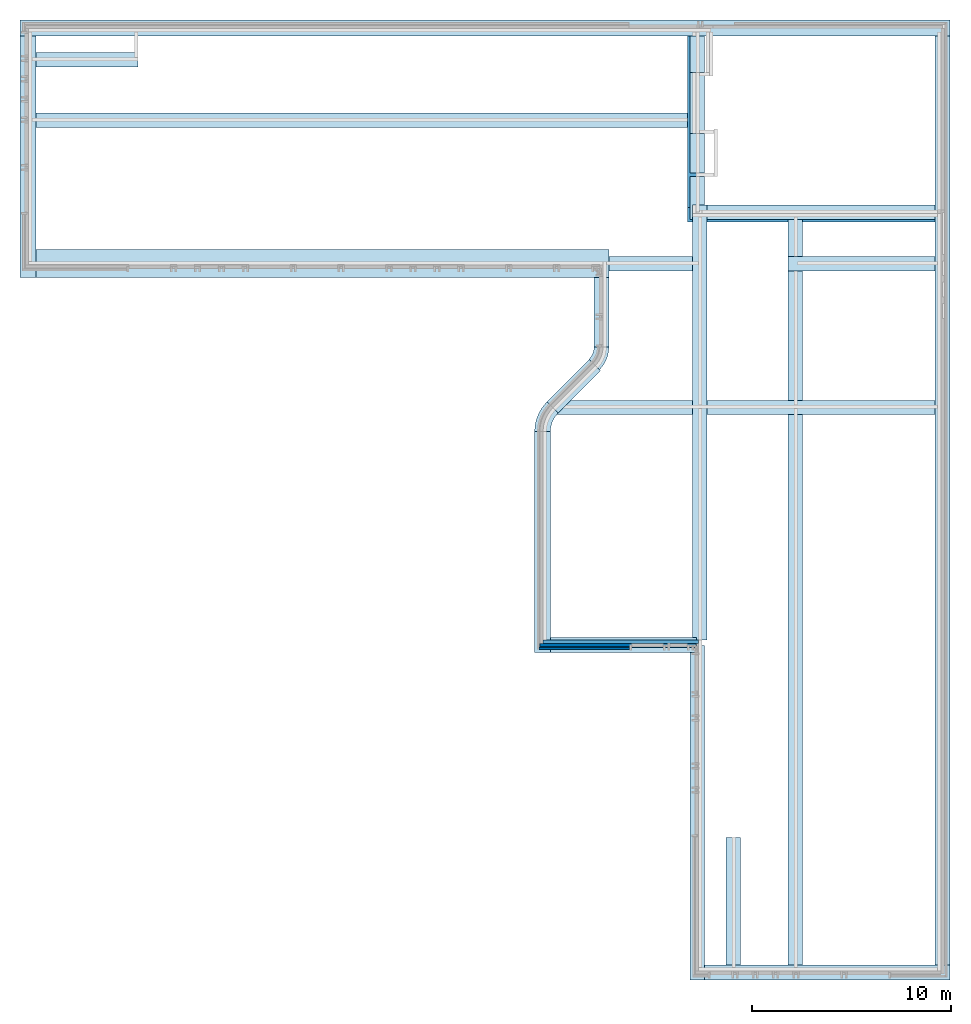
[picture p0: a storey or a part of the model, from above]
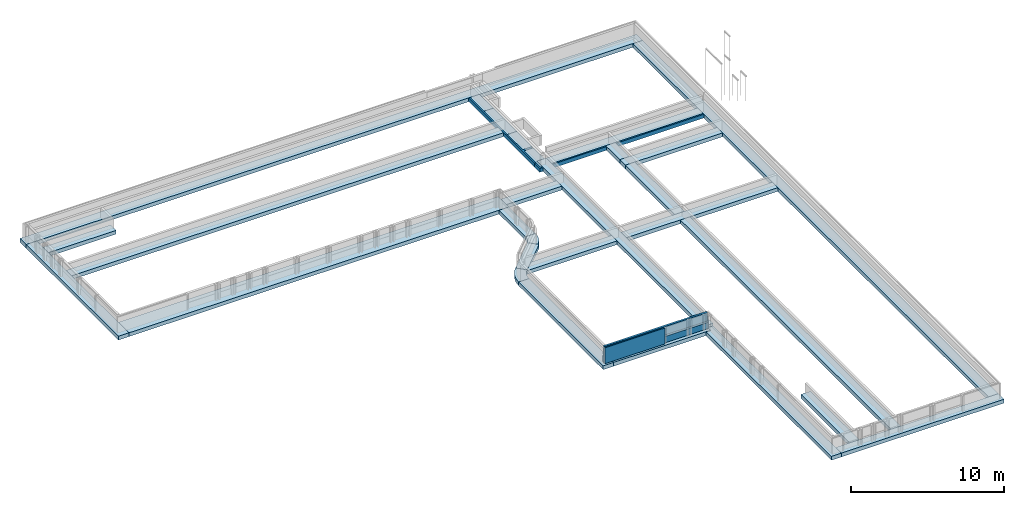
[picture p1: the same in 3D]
Properties of the parts of a building model (IFC2X3), part 7 of 37

# IfcBuildingElementProxy: 6287226
Group: Model Group:Paneel op dak:6287293

# IfcBuildingElementProxy: 6287227
In: 02 tweede verdieping
Pset_ProductRequirements - Category: Walls: Wall Sweeps; sets with these values: 2
Constraints - Offset From Level: 1560 mm; Offset From Wall: 1 mm
Dimensions - Length: 1797.5 mm
Identity Data - Workset: Bouwkundig
Phasing - Phase Created: 2. nieuwbouw
Group: Model Group:Paneel op dak:6287293

# IfcBuildingElementProxy: 6287228
In: 02 tweede verdieping
Pset_ProductRequirements - Category: Walls: Wall Sweeps; sets with these values: 2
Constraints - Offset From Level: 1440 mm; Offset From Wall: 1 mm
Dimensions - Length: 1797.5 mm
Identity Data - Workset: Bouwkundig
Phasing - Phase Created: 2. nieuwbouw
Group: Model Group:Paneel op dak:6287293

# IfcBuildingElementProxy: 6287229
In: 02 tweede verdieping
Pset_ProductRequirements - Category: Walls: Wall Sweeps; sets with these values: 2
Constraints - Offset From Level: 1320 mm; Offset From Wall: 1 mm
Dimensions - Length: 1797.5 mm
Identity Data - Workset: Bouwkundig
Phasing - Phase Created: 2. nieuwbouw
Group: Model Group:Paneel op dak:6287293

# IfcBuildingElementProxy: 6287230
In: 02 tweede verdieping
Pset_ProductRequirements - Category: Walls: Wall Sweeps; sets with these values: 2
Constraints - Offset From Level: 1200 mm; Offset From Wall: 1 mm
Dimensions - Length: 1797.5 mm
Identity Data - Workset: Bouwkundig
Phasing - Phase Created: 2. nieuwbouw
Group: Model Group:Paneel op dak:6287293

# IfcBuildingElementProxy: 6287231
In: 02 tweede verdieping
Pset_ProductRequirements - Category: Walls: Wall Sweeps; sets with these values: 2
Constraints - Offset From Level: 1080 mm; Offset From Wall: 1 mm
Dimensions - Length: 1797.5 mm
Identity Data - Workset: Bouwkundig
Phasing - Phase Created: 2. nieuwbouw
Group: Model Group:Paneel op dak:6287293

# IfcBuildingElementProxy: 6287232
In: 02 tweede verdieping
Pset_ProductRequirements - Category: Walls: Wall Sweeps; sets with these values: 2
Constraints - Offset From Level: 960 mm; Offset From Wall: 1 mm
Dimensions - Length: 1797.5 mm
Identity Data - Workset: Bouwkundig
Phasing - Phase Created: 2. nieuwbouw
Group: Model Group:Paneel op dak:6287293

# IfcBuildingElementProxy: 6287233
In: 02 tweede verdieping
Pset_ProductRequirements - Category: Walls: Wall Sweeps; sets with these values: 2
Constraints - Offset From Level: 840 mm; Offset From Wall: 1 mm
Dimensions - Length: 1797.5 mm
Identity Data - Workset: Bouwkundig
Phasing - Phase Created: 2. nieuwbouw
Group: Model Group:Paneel op dak:6287293

# IfcBuildingElementProxy: 6287234
In: 02 tweede verdieping
Pset_ProductRequirements - Category: Walls: Wall Sweeps; sets with these values: 2
Constraints - Offset From Level: 720 mm; Offset From Wall: 1 mm
Dimensions - Length: 1797.5 mm
Identity Data - Workset: Bouwkundig
Phasing - Phase Created: 2. nieuwbouw
Group: Model Group:Paneel op dak:6287293

# IfcBuildingElementProxy: 6287235
In: 02 tweede verdieping
Pset_ProductRequirements - Category: Walls: Wall Sweeps; sets with these values: 2
Constraints - Offset From Level: 600 mm; Offset From Wall: 1 mm
Dimensions - Length: 1797.5 mm
Identity Data - Workset: Bouwkundig
Phasing - Phase Created: 2. nieuwbouw
Group: Model Group:Paneel op dak:6287293

# IfcBuildingElementProxy: 6287236
In: 02 tweede verdieping
Pset_ProductRequirements - Category: Walls: Wall Sweeps; sets with these values: 2
Constraints - Offset From Level: 480 mm; Offset From Wall: 1 mm
Dimensions - Length: 1797.5 mm
Identity Data - Workset: Bouwkundig
Phasing - Phase Created: 2. nieuwbouw
Group: Model Group:Paneel op dak:6287293

# IfcBuildingElementProxy: 6287237
In: 02 tweede verdieping
Pset_ProductRequirements - Category: Walls: Wall Sweeps; sets with these values: 2
Constraints - Offset From Level: 360 mm; Offset From Wall: 1 mm
Dimensions - Length: 1797.5 mm
Identity Data - Workset: Bouwkundig
Phasing - Phase Created: 2. nieuwbouw
Group: Model Group:Paneel op dak:6287293

# IfcBuildingElementProxy: 6287238
In: 02 tweede verdieping
Pset_ProductRequirements - Category: Walls: Wall Sweeps; sets with these values: 2
Constraints - Offset From Level: 240 mm; Offset From Wall: 1 mm
Dimensions - Length: 1797.5 mm
Identity Data - Workset: Bouwkundig
Phasing - Phase Created: 2. nieuwbouw
Group: Model Group:Paneel op dak:6287293

# IfcBuildingElementProxy: 6287239
In: 02 tweede verdieping
Pset_ProductRequirements - Category: Walls: Wall Sweeps; sets with these values: 2
Constraints - Offset From Level: 120 mm; Offset From Wall: 1 mm
Dimensions - Length: 1797.5 mm
Identity Data - Workset: Bouwkundig
Phasing - Phase Created: 2. nieuwbouw
Group: Model Group:Paneel op dak:6287293

# IfcBuildingElementProxy: 6287276
In: 02 tweede verdieping
Pset_ProductRequirements - Category: Walls: Wall Sweeps; sets with these values: 2
Pset_ProvisionForVoid - Shape: Undefined
Constraints - Offset From Level: 2040 mm; Offset From Wall: 1 mm
Dimensions - Length: 1797.5 mm
Identity Data - Workset: Bouwkundig
Phasing - Phase Created: 2. nieuwbouw
Group: Model Group:Paneel op dak:6287293

# IfcBuildingElementProxy: 6287277
In: 02 tweede verdieping
Pset_ProductRequirements - Category: Walls: Wall Sweeps; sets with these values: 2
Pset_ProvisionForVoid - Shape: Undefined
Constraints - Offset From Level: 1920 mm; Offset From Wall: 1 mm
Dimensions - Length: 1797.5 mm
Identity Data - Workset: Bouwkundig
Phasing - Phase Created: 2. nieuwbouw
Group: Model Group:Paneel op dak:6287293

# IfcBuildingElementProxy: 6287278
In: 02 tweede verdieping
Pset_ProductRequirements - Category: Walls: Wall Sweeps; sets with these values: 2
Pset_ProvisionForVoid - Shape: Undefined
Constraints - Offset From Level: 1800 mm; Offset From Wall: 1 mm
Dimensions - Length: 1797.5 mm
Identity Data - Workset: Bouwkundig
Phasing - Phase Created: 2. nieuwbouw
Group: Model Group:Paneel op dak:6287293

# IfcBuildingElementProxy: 6287279
In: 02 tweede verdieping
Pset_ProductRequirements - Category: Walls: Wall Sweeps; sets with these values: 2
Pset_ProvisionForVoid - Shape: Undefined
Constraints - Offset From Level: 1680 mm; Offset From Wall: 1 mm
Dimensions - Length: 1797.5 mm
Identity Data - Workset: Bouwkundig
Phasing - Phase Created: 2. nieuwbouw
Group: Model Group:Paneel op dak:6287293

# IfcBuildingElementProxy: 6287280
In: 02 tweede verdieping
Pset_ProductRequirements - Category: Walls: Wall Sweeps; sets with these values: 2
Pset_ProvisionForVoid - Shape: Undefined
Constraints - Offset From Level: 1560 mm; Offset From Wall: 1 mm
Dimensions - Length: 1797.5 mm
Identity Data - Workset: Bouwkundig
Phasing - Phase Created: 2. nieuwbouw
Group: Model Group:Paneel op dak:6287293

# IfcBuildingElementProxy: 6287281
In: 02 tweede verdieping
Pset_ProductRequirements - Category: Walls: Wall Sweeps; sets with these values: 2
Pset_ProvisionForVoid - Shape: Undefined
Constraints - Offset From Level: 1440 mm; Offset From Wall: 1 mm
Dimensions - Length: 1797.5 mm
Identity Data - Workset: Bouwkundig
Phasing - Phase Created: 2. nieuwbouw
Group: Model Group:Paneel op dak:6287293

# IfcBuildingElementProxy: 6287282
In: 02 tweede verdieping
Pset_ProductRequirements - Category: Walls: Wall Sweeps; sets with these values: 2
Pset_ProvisionForVoid - Shape: Undefined
Constraints - Offset From Level: 1320 mm; Offset From Wall: 1 mm
Dimensions - Length: 1797.5 mm
Identity Data - Workset: Bouwkundig
Phasing - Phase Created: 2. nieuwbouw
Group: Model Group:Paneel op dak:6287293

# IfcBuildingElementProxy: 6287283
In: 02 tweede verdieping
Pset_ProductRequirements - Category: Walls: Wall Sweeps; sets with these values: 2
Pset_ProvisionForVoid - Shape: Undefined
Constraints - Offset From Level: 1200 mm; Offset From Wall: 1 mm
Dimensions - Length: 1797.5 mm
Identity Data - Workset: Bouwkundig
Phasing - Phase Created: 2. nieuwbouw
Group: Model Group:Paneel op dak:6287293

# IfcBuildingElementProxy: 6287284
In: 02 tweede verdieping
Pset_ProductRequirements - Category: Walls: Wall Sweeps; sets with these values: 2
Pset_ProvisionForVoid - Shape: Undefined
Constraints - Offset From Level: 1080 mm; Offset From Wall: 1 mm
Dimensions - Length: 1797.5 mm
Identity Data - Workset: Bouwkundig
Phasing - Phase Created: 2. nieuwbouw
Group: Model Group:Paneel op dak:6287293

# IfcBuildingElementProxy: 6287285
In: 02 tweede verdieping
Pset_ProductRequirements - Category: Walls: Wall Sweeps; sets with these values: 2
Pset_ProvisionForVoid - Shape: Undefined
Constraints - Offset From Level: 960 mm; Offset From Wall: 1 mm
Dimensions - Length: 1797.5 mm
Identity Data - Workset: Bouwkundig
Phasing - Phase Created: 2. nieuwbouw
Group: Model Group:Paneel op dak:6287293

# IfcBuildingElementProxy: 6287286
In: 02 tweede verdieping
Pset_ProductRequirements - Category: Walls: Wall Sweeps; sets with these values: 2
Pset_ProvisionForVoid - Shape: Undefined
Constraints - Offset From Level: 840 mm; Offset From Wall: 1 mm
Dimensions - Length: 1797.5 mm
Identity Data - Workset: Bouwkundig
Phasing - Phase Created: 2. nieuwbouw
Group: Model Group:Paneel op dak:6287293

# IfcBuildingElementProxy: 6287287
In: 02 tweede verdieping
Pset_ProductRequirements - Category: Walls: Wall Sweeps; sets with these values: 2
Pset_ProvisionForVoid - Shape: Undefined
Constraints - Offset From Level: 720 mm; Offset From Wall: 1 mm
Dimensions - Length: 1797.5 mm
Identity Data - Workset: Bouwkundig
Phasing - Phase Created: 2. nieuwbouw
Group: Model Group:Paneel op dak:6287293

# IfcBuildingElementProxy: 6287288
In: 02 tweede verdieping
Pset_ProductRequirements - Category: Walls: Wall Sweeps; sets with these values: 2
Pset_ProvisionForVoid - Shape: Undefined
Constraints - Offset From Level: 600 mm; Offset From Wall: 1 mm
Dimensions - Length: 1797.5 mm
Identity Data - Workset: Bouwkundig
Phasing - Phase Created: 2. nieuwbouw
Group: Model Group:Paneel op dak:6287293

# IfcBuildingElementProxy: 6287289
In: 02 tweede verdieping
Pset_ProductRequirements - Category: Walls: Wall Sweeps; sets with these values: 2
Pset_ProvisionForVoid - Shape: Undefined
Constraints - Offset From Level: 480 mm; Offset From Wall: 1 mm
Dimensions - Length: 1797.5 mm
Identity Data - Workset: Bouwkundig
Phasing - Phase Created: 2. nieuwbouw
Group: Model Group:Paneel op dak:6287293

# IfcBuildingElementProxy: 6287290
In: 02 tweede verdieping
Pset_ProductRequirements - Category: Walls: Wall Sweeps; sets with these values: 2
Pset_ProvisionForVoid - Shape: Undefined
Constraints - Offset From Level: 360 mm; Offset From Wall: 1 mm
Dimensions - Length: 1797.5 mm
Identity Data - Workset: Bouwkundig
Phasing - Phase Created: 2. nieuwbouw
Group: Model Group:Paneel op dak:6287293

# IfcBuildingElementProxy: 6287291
In: 02 tweede verdieping
Pset_ProductRequirements - Category: Walls: Wall Sweeps; sets with these values: 2
Pset_ProvisionForVoid - Shape: Undefined
Constraints - Offset From Level: 240 mm; Offset From Wall: 1 mm
Dimensions - Length: 1797.5 mm
Identity Data - Workset: Bouwkundig
Phasing - Phase Created: 2. nieuwbouw
Group: Model Group:Paneel op dak:6287293

# IfcBuildingElementProxy: 6287292
In: 02 tweede verdieping
Pset_ProductRequirements - Category: Walls: Wall Sweeps; sets with these values: 2
Pset_ProvisionForVoid - Shape: Undefined
Constraints - Offset From Level: 120 mm; Offset From Wall: 1 mm
Dimensions - Length: 1797.5 mm
Identity Data - Workset: Bouwkundig
Phasing - Phase Created: 2. nieuwbouw
Group: Model Group:Paneel op dak:6287293

# IfcBuildingElementProxy: 6287339
In: 02 tweede verdieping
Pset_ProductRequirements - Category: Walls: Wall Sweeps; sets with these values: 2
Constraints - Offset From Level: 2040 mm; Offset From Wall: 1 mm
Dimensions - Length: 1797.5 mm
Identity Data - Workset: Bouwkundig
Phasing - Phase Created: 2. nieuwbouw
Group: Model Group:Paneel op dak:6287507

# IfcBuildingElementProxy: 6287340
In: 02 tweede verdieping
Pset_ProductRequirements - Category: Walls: Wall Sweeps; sets with these values: 2
Pset_ProvisionForVoid - Shape: Undefined
Constraints - Offset From Level: 1920 mm; Offset From Wall: 1 mm
Dimensions - Length: 1797.5 mm
Identity Data - Workset: Bouwkundig
Phasing - Phase Created: 2. nieuwbouw
Group: Model Group:Paneel op dak:6287507

# IfcBuildingElementProxy: 6287341
In: 02 tweede verdieping
Pset_ProductRequirements - Category: Walls: Wall Sweeps; sets with these values: 2
Pset_ProvisionForVoid - Shape: Undefined
Constraints - Offset From Level: 1800 mm; Offset From Wall: 1 mm
Dimensions - Length: 1797.5 mm
Identity Data - Workset: Bouwkundig
Phasing - Phase Created: 2. nieuwbouw
Group: Model Group:Paneel op dak:6287507

# IfcBuildingElementProxy: 6287342
In: 02 tweede verdieping
Pset_ProductRequirements - Category: Walls: Wall Sweeps; sets with these values: 2
Pset_ProvisionForVoid - Shape: Undefined
Constraints - Offset From Level: 1680 mm; Offset From Wall: 1 mm
Dimensions - Length: 1797.5 mm
Identity Data - Workset: Bouwkundig
Phasing - Phase Created: 2. nieuwbouw
Group: Model Group:Paneel op dak:6287507

# IfcBuildingElementProxy: 6287343
In: 02 tweede verdieping
Pset_ProductRequirements - Category: Walls: Wall Sweeps; sets with these values: 2
Pset_ProvisionForVoid - Shape: Undefined
Constraints - Offset From Level: 1560 mm; Offset From Wall: 1 mm
Dimensions - Length: 1797.5 mm
Identity Data - Workset: Bouwkundig
Phasing - Phase Created: 2. nieuwbouw
Group: Model Group:Paneel op dak:6287507

# IfcBuildingElementProxy: 6287344
In: 02 tweede verdieping
Pset_ProductRequirements - Category: Walls: Wall Sweeps; sets with these values: 2
Pset_ProvisionForVoid - Shape: Undefined
Constraints - Offset From Level: 1440 mm; Offset From Wall: 1 mm
Dimensions - Length: 1797.5 mm
Identity Data - Workset: Bouwkundig
Phasing - Phase Created: 2. nieuwbouw
Group: Model Group:Paneel op dak:6287507

# IfcBuildingElementProxy: 6287345
In: 02 tweede verdieping
Pset_ProductRequirements - Category: Walls: Wall Sweeps; sets with these values: 2
Pset_ProvisionForVoid - Shape: Undefined
Constraints - Offset From Level: 1320 mm; Offset From Wall: 1 mm
Dimensions - Length: 1797.5 mm
Identity Data - Workset: Bouwkundig
Phasing - Phase Created: 2. nieuwbouw
Group: Model Group:Paneel op dak:6287507

# IfcBuildingElementProxy: 6287346
In: 02 tweede verdieping
Pset_ProductRequirements - Category: Walls: Wall Sweeps; sets with these values: 2
Pset_ProvisionForVoid - Shape: Undefined
Constraints - Offset From Level: 1200 mm; Offset From Wall: 1 mm
Dimensions - Length: 1797.5 mm
Identity Data - Workset: Bouwkundig
Phasing - Phase Created: 2. nieuwbouw
Group: Model Group:Paneel op dak:6287507

# IfcBuildingElementProxy: 6287347
In: 02 tweede verdieping
Pset_ProductRequirements - Category: Walls: Wall Sweeps; sets with these values: 2
Pset_ProvisionForVoid - Shape: Undefined
Constraints - Offset From Level: 1080 mm; Offset From Wall: 1 mm
Dimensions - Length: 1797.5 mm
Identity Data - Workset: Bouwkundig
Phasing - Phase Created: 2. nieuwbouw
Group: Model Group:Paneel op dak:6287507

# IfcBuildingElementProxy: 6287348
In: 02 tweede verdieping
Pset_ProductRequirements - Category: Walls: Wall Sweeps; sets with these values: 2
Pset_ProvisionForVoid - Shape: Undefined
Constraints - Offset From Level: 960 mm; Offset From Wall: 1 mm
Dimensions - Length: 1797.5 mm
Identity Data - Workset: Bouwkundig
Phasing - Phase Created: 2. nieuwbouw
Group: Model Group:Paneel op dak:6287507

# IfcBuildingElementProxy: 6287349
In: 02 tweede verdieping
Pset_ProductRequirements - Category: Walls: Wall Sweeps; sets with these values: 2
Pset_ProvisionForVoid - Shape: Undefined
Constraints - Offset From Level: 840 mm; Offset From Wall: 1 mm
Dimensions - Length: 1797.5 mm
Identity Data - Workset: Bouwkundig
Phasing - Phase Created: 2. nieuwbouw
Group: Model Group:Paneel op dak:6287507

# IfcBuildingElementProxy: 6287350
In: 02 tweede verdieping
Pset_ProductRequirements - Category: Walls: Wall Sweeps; sets with these values: 2
Pset_ProvisionForVoid - Shape: Undefined
Constraints - Offset From Level: 720 mm; Offset From Wall: 1 mm
Dimensions - Length: 1797.5 mm
Identity Data - Workset: Bouwkundig
Phasing - Phase Created: 2. nieuwbouw
Group: Model Group:Paneel op dak:6287507

# IfcBuildingElementProxy: 6287351
In: 02 tweede verdieping
Pset_ProductRequirements - Category: Walls: Wall Sweeps; sets with these values: 2
Pset_ProvisionForVoid - Shape: Undefined
Constraints - Offset From Level: 600 mm; Offset From Wall: 1 mm
Dimensions - Length: 1797.5 mm
Identity Data - Workset: Bouwkundig
Phasing - Phase Created: 2. nieuwbouw
Group: Model Group:Paneel op dak:6287507

# IfcBuildingElementProxy: 6287352
In: 02 tweede verdieping
Pset_ProductRequirements - Category: Walls: Wall Sweeps; sets with these values: 2
Pset_ProvisionForVoid - Shape: Undefined
Constraints - Offset From Level: 480 mm; Offset From Wall: 1 mm
Dimensions - Length: 1797.5 mm
Identity Data - Workset: Bouwkundig
Phasing - Phase Created: 2. nieuwbouw
Group: Model Group:Paneel op dak:6287507

# IfcBuildingElementProxy: 6287353
In: 02 tweede verdieping
Pset_ProductRequirements - Category: Walls: Wall Sweeps; sets with these values: 2
Pset_ProvisionForVoid - Shape: Undefined
Constraints - Offset From Level: 360 mm; Offset From Wall: 1 mm
Dimensions - Length: 1797.5 mm
Identity Data - Workset: Bouwkundig
Phasing - Phase Created: 2. nieuwbouw
Group: Model Group:Paneel op dak:6287507

# IfcBuildingElementProxy: 6287354
In: 02 tweede verdieping
Pset_ProductRequirements - Category: Walls: Wall Sweeps; sets with these values: 2
Pset_ProvisionForVoid - Shape: Undefined
Constraints - Offset From Level: 240 mm; Offset From Wall: 1 mm
Dimensions - Length: 1797.5 mm
Identity Data - Workset: Bouwkundig
Phasing - Phase Created: 2. nieuwbouw
Group: Model Group:Paneel op dak:6287507

# IfcBuildingElementProxy: 6287355
In: 02 tweede verdieping
Pset_ProductRequirements - Category: Walls: Wall Sweeps; sets with these values: 2
Pset_ProvisionForVoid - Shape: Undefined
Constraints - Offset From Level: 120 mm; Offset From Wall: 1 mm
Dimensions - Length: 1797.5 mm
Identity Data - Workset: Bouwkundig
Phasing - Phase Created: 2. nieuwbouw
Group: Model Group:Paneel op dak:6287507

# IfcBuildingElementProxy: 6287388
In: 02 tweede verdieping
Pset_ProductRequirements - Category: Walls: Wall Sweeps; sets with these values: 2
Pset_ProvisionForVoid - Shape: Undefined
Constraints - Offset From Level: 2040 mm; Offset From Wall: 1 mm
Dimensions - Length: 1797.5 mm
Identity Data - Workset: Bouwkundig
Phasing - Phase Created: 2. nieuwbouw
Group: Model Group:Paneel op dak:6287507

# IfcBuildingElementProxy: 6287389
In: 02 tweede verdieping
Pset_ProductRequirements - Category: Walls: Wall Sweeps; sets with these values: 2
Pset_ProvisionForVoid - Shape: Undefined
Constraints - Offset From Level: 1920 mm; Offset From Wall: 1 mm
Dimensions - Length: 1797.5 mm
Identity Data - Workset: Bouwkundig
Phasing - Phase Created: 2. nieuwbouw
Group: Model Group:Paneel op dak:6287507

# IfcBuildingElementProxy: 6287390
In: 02 tweede verdieping
Pset_ProductRequirements - Category: Walls: Wall Sweeps; sets with these values: 2
Pset_ProvisionForVoid - Shape: Undefined
Constraints - Offset From Level: 1800 mm; Offset From Wall: 1 mm
Dimensions - Length: 1797.5 mm
Identity Data - Workset: Bouwkundig
Phasing - Phase Created: 2. nieuwbouw
Group: Model Group:Paneel op dak:6287507

# IfcBuildingElementProxy: 6287391
In: 02 tweede verdieping
Pset_ProductRequirements - Category: Walls: Wall Sweeps; sets with these values: 2
Pset_ProvisionForVoid - Shape: Undefined
Constraints - Offset From Level: 1680 mm; Offset From Wall: 1 mm
Dimensions - Length: 1797.5 mm
Identity Data - Workset: Bouwkundig
Phasing - Phase Created: 2. nieuwbouw
Group: Model Group:Paneel op dak:6287507

# IfcBuildingElementProxy: 6287392
In: 02 tweede verdieping
Pset_ProductRequirements - Category: Walls: Wall Sweeps; sets with these values: 2
Pset_ProvisionForVoid - Shape: Undefined
Constraints - Offset From Level: 1560 mm; Offset From Wall: 1 mm
Dimensions - Length: 1797.5 mm
Identity Data - Workset: Bouwkundig
Phasing - Phase Created: 2. nieuwbouw
Group: Model Group:Paneel op dak:6287507

# IfcBuildingElementProxy: 6287393
In: 02 tweede verdieping
Pset_ProductRequirements - Category: Walls: Wall Sweeps; sets with these values: 2
Pset_ProvisionForVoid - Shape: Undefined
Constraints - Offset From Level: 1440 mm; Offset From Wall: 1 mm
Dimensions - Length: 1797.5 mm
Identity Data - Workset: Bouwkundig
Phasing - Phase Created: 2. nieuwbouw
Group: Model Group:Paneel op dak:6287507

# IfcBuildingElementProxy: 6287394
In: 02 tweede verdieping
Pset_ProductRequirements - Category: Walls: Wall Sweeps; sets with these values: 2
Pset_ProvisionForVoid - Shape: Undefined
Constraints - Offset From Level: 1320 mm; Offset From Wall: 1 mm
Dimensions - Length: 1797.5 mm
Identity Data - Workset: Bouwkundig
Phasing - Phase Created: 2. nieuwbouw
Group: Model Group:Paneel op dak:6287507

# IfcBuildingElementProxy: 6287395
In: 02 tweede verdieping
Pset_ProductRequirements - Category: Walls: Wall Sweeps; sets with these values: 2
Pset_ProvisionForVoid - Shape: Undefined
Constraints - Offset From Level: 1200 mm; Offset From Wall: 1 mm
Dimensions - Length: 1797.5 mm
Identity Data - Workset: Bouwkundig
Phasing - Phase Created: 2. nieuwbouw
Group: Model Group:Paneel op dak:6287507

# IfcBuildingElementProxy: 6287396
In: 02 tweede verdieping
Pset_ProductRequirements - Category: Walls: Wall Sweeps; sets with these values: 2
Pset_ProvisionForVoid - Shape: Undefined
Constraints - Offset From Level: 1080 mm; Offset From Wall: 1 mm
Dimensions - Length: 1797.5 mm
Identity Data - Workset: Bouwkundig
Phasing - Phase Created: 2. nieuwbouw
Group: Model Group:Paneel op dak:6287507

# IfcBuildingElementProxy: 6287397
In: 02 tweede verdieping
Pset_ProductRequirements - Category: Walls: Wall Sweeps; sets with these values: 2
Pset_ProvisionForVoid - Shape: Undefined
Constraints - Offset From Level: 960 mm; Offset From Wall: 1 mm
Dimensions - Length: 1797.5 mm
Identity Data - Workset: Bouwkundig
Phasing - Phase Created: 2. nieuwbouw
Group: Model Group:Paneel op dak:6287507

# IfcBuildingElementProxy: 6287398
In: 02 tweede verdieping
Pset_ProductRequirements - Category: Walls: Wall Sweeps; sets with these values: 2
Pset_ProvisionForVoid - Shape: Undefined
Constraints - Offset From Level: 840 mm; Offset From Wall: 1 mm
Dimensions - Length: 1797.5 mm
Identity Data - Workset: Bouwkundig
Phasing - Phase Created: 2. nieuwbouw
Group: Model Group:Paneel op dak:6287507

# IfcBuildingElementProxy: 6287399
In: 02 tweede verdieping
Pset_ProductRequirements - Category: Walls: Wall Sweeps; sets with these values: 2
Pset_ProvisionForVoid - Shape: Undefined
Constraints - Offset From Level: 720 mm; Offset From Wall: 1 mm
Dimensions - Length: 1797.5 mm
Identity Data - Workset: Bouwkundig
Phasing - Phase Created: 2. nieuwbouw
Group: Model Group:Paneel op dak:6287507

# IfcBuildingElementProxy: 6287400
In: 02 tweede verdieping
Pset_ProductRequirements - Category: Walls: Wall Sweeps; sets with these values: 2
Pset_ProvisionForVoid - Shape: Undefined
Constraints - Offset From Level: 600 mm; Offset From Wall: 1 mm
Dimensions - Length: 1797.5 mm
Identity Data - Workset: Bouwkundig
Phasing - Phase Created: 2. nieuwbouw
Group: Model Group:Paneel op dak:6287507

# IfcBuildingElementProxy: 6287401
In: 02 tweede verdieping
Pset_ProductRequirements - Category: Walls: Wall Sweeps; sets with these values: 2
Pset_ProvisionForVoid - Shape: Undefined
Constraints - Offset From Level: 480 mm; Offset From Wall: 1 mm
Dimensions - Length: 1797.5 mm
Identity Data - Workset: Bouwkundig
Phasing - Phase Created: 2. nieuwbouw
Group: Model Group:Paneel op dak:6287507

# IfcBuildingElementProxy: 6287402
In: 02 tweede verdieping
Pset_ProductRequirements - Category: Walls: Wall Sweeps; sets with these values: 2
Pset_ProvisionForVoid - Shape: Undefined
Constraints - Offset From Level: 360 mm; Offset From Wall: 1 mm
Dimensions - Length: 1797.5 mm
Identity Data - Workset: Bouwkundig
Phasing - Phase Created: 2. nieuwbouw
Group: Model Group:Paneel op dak:6287507

# IfcBuildingElementProxy: 6287403
In: 02 tweede verdieping
Pset_ProductRequirements - Category: Walls: Wall Sweeps; sets with these values: 2
Pset_ProvisionForVoid - Shape: Undefined
Constraints - Offset From Level: 240 mm; Offset From Wall: 1 mm
Dimensions - Length: 1797.5 mm
Identity Data - Workset: Bouwkundig
Phasing - Phase Created: 2. nieuwbouw
Group: Model Group:Paneel op dak:6287507

# IfcBuildingElementProxy: 6287404
In: 02 tweede verdieping
Pset_ProductRequirements - Category: Walls: Wall Sweeps; sets with these values: 2
Pset_ProvisionForVoid - Shape: Undefined
Constraints - Offset From Level: 120 mm; Offset From Wall: 1 mm
Dimensions - Length: 1797.5 mm
Identity Data - Workset: Bouwkundig
Phasing - Phase Created: 2. nieuwbouw
Group: Model Group:Paneel op dak:6287507

# IfcBuildingElementProxy: 6287437
In: 02 tweede verdieping
Pset_ProductRequirements - Category: Walls: Wall Sweeps; sets with these values: 2
Constraints - Offset From Level: 2040 mm; Offset From Wall: 1 mm
Dimensions - Length: 1797.5 mm
Identity Data - Workset: Bouwkundig
Phasing - Phase Created: 2. nieuwbouw
Group: Model Group:Paneel op dak:6287507

# IfcBuildingElementProxy: 6287438
In: 02 tweede verdieping
Pset_ProductRequirements - Category: Walls: Wall Sweeps; sets with these values: 2
Constraints - Offset From Level: 1920 mm; Offset From Wall: 1 mm
Dimensions - Length: 1797.5 mm
Identity Data - Workset: Bouwkundig
Phasing - Phase Created: 2. nieuwbouw
Group: Model Group:Paneel op dak:6287507

# IfcBuildingElementProxy: 6287439
In: 02 tweede verdieping
Pset_ProductRequirements - Category: Walls: Wall Sweeps; sets with these values: 2
Constraints - Offset From Level: 1800 mm; Offset From Wall: 1 mm
Dimensions - Length: 1797.5 mm
Identity Data - Workset: Bouwkundig
Phasing - Phase Created: 2. nieuwbouw
Group: Model Group:Paneel op dak:6287507

# IfcBuildingElementProxy: 6287440
In: 02 tweede verdieping
Pset_ProductRequirements - Category: Walls: Wall Sweeps; sets with these values: 2
Constraints - Offset From Level: 1680 mm; Offset From Wall: 1 mm
Dimensions - Length: 1797.5 mm
Identity Data - Workset: Bouwkundig
Phasing - Phase Created: 2. nieuwbouw
Group: Model Group:Paneel op dak:6287507

# IfcBuildingElementProxy: 6287441
In: 02 tweede verdieping
Pset_ProductRequirements - Category: Walls: Wall Sweeps; sets with these values: 2
Constraints - Offset From Level: 1560 mm; Offset From Wall: 1 mm
Dimensions - Length: 1797.5 mm
Identity Data - Workset: Bouwkundig
Phasing - Phase Created: 2. nieuwbouw
Group: Model Group:Paneel op dak:6287507

# IfcBuildingElementProxy: 6287442
In: 02 tweede verdieping
Pset_ProductRequirements - Category: Walls: Wall Sweeps; sets with these values: 2
Constraints - Offset From Level: 1440 mm; Offset From Wall: 1 mm
Dimensions - Length: 1797.5 mm
Identity Data - Workset: Bouwkundig
Phasing - Phase Created: 2. nieuwbouw
Group: Model Group:Paneel op dak:6287507

# IfcBuildingElementProxy: 6287443
In: 02 tweede verdieping
Pset_ProductRequirements - Category: Walls: Wall Sweeps; sets with these values: 2
Constraints - Offset From Level: 1320 mm; Offset From Wall: 1 mm
Dimensions - Length: 1797.5 mm
Identity Data - Workset: Bouwkundig
Phasing - Phase Created: 2. nieuwbouw
Group: Model Group:Paneel op dak:6287507

# IfcBuildingElementProxy: 6287444
In: 02 tweede verdieping
Pset_ProductRequirements - Category: Walls: Wall Sweeps; sets with these values: 2
Constraints - Offset From Level: 1200 mm; Offset From Wall: 1 mm
Dimensions - Length: 1797.5 mm
Identity Data - Workset: Bouwkundig
Phasing - Phase Created: 2. nieuwbouw
Group: Model Group:Paneel op dak:6287507

# IfcBuildingElementProxy: 6287445
In: 02 tweede verdieping
Pset_ProductRequirements - Category: Walls: Wall Sweeps; sets with these values: 2
Constraints - Offset From Level: 1080 mm; Offset From Wall: 1 mm
Dimensions - Length: 1797.5 mm
Identity Data - Workset: Bouwkundig
Phasing - Phase Created: 2. nieuwbouw
Group: Model Group:Paneel op dak:6287507

# IfcBuildingElementProxy: 6287446
In: 02 tweede verdieping
Pset_ProductRequirements - Category: Walls: Wall Sweeps; sets with these values: 2
Constraints - Offset From Level: 960 mm; Offset From Wall: 1 mm
Dimensions - Length: 1797.5 mm
Identity Data - Workset: Bouwkundig
Phasing - Phase Created: 2. nieuwbouw
Group: Model Group:Paneel op dak:6287507

# IfcBuildingElementProxy: 6287447
In: 02 tweede verdieping
Pset_ProductRequirements - Category: Walls: Wall Sweeps; sets with these values: 2
Constraints - Offset From Level: 840 mm; Offset From Wall: 1 mm
Dimensions - Length: 1797.5 mm
Identity Data - Workset: Bouwkundig
Phasing - Phase Created: 2. nieuwbouw
Group: Model Group:Paneel op dak:6287507

# IfcBuildingElementProxy: 6287448
In: 02 tweede verdieping
Pset_ProductRequirements - Category: Walls: Wall Sweeps; sets with these values: 2
Constraints - Offset From Level: 720 mm; Offset From Wall: 1 mm
Dimensions - Length: 1797.5 mm
Identity Data - Workset: Bouwkundig
Phasing - Phase Created: 2. nieuwbouw
Group: Model Group:Paneel op dak:6287507

# IfcBuildingElementProxy: 6287449
In: 02 tweede verdieping
Pset_ProductRequirements - Category: Walls: Wall Sweeps; sets with these values: 2
Constraints - Offset From Level: 600 mm; Offset From Wall: 1 mm
Dimensions - Length: 1797.5 mm
Identity Data - Workset: Bouwkundig
Phasing - Phase Created: 2. nieuwbouw
Group: Model Group:Paneel op dak:6287507

# IfcBuildingElementProxy: 6287450
In: 02 tweede verdieping
Pset_ProductRequirements - Category: Walls: Wall Sweeps; sets with these values: 2
Constraints - Offset From Level: 480 mm; Offset From Wall: 1 mm
Dimensions - Length: 1797.5 mm
Identity Data - Workset: Bouwkundig
Phasing - Phase Created: 2. nieuwbouw
Group: Model Group:Paneel op dak:6287507

# IfcBuildingElementProxy: 6287451
In: 02 tweede verdieping
Pset_ProductRequirements - Category: Walls: Wall Sweeps; sets with these values: 2
Constraints - Offset From Level: 360 mm; Offset From Wall: 1 mm
Dimensions - Length: 1797.5 mm
Identity Data - Workset: Bouwkundig
Phasing - Phase Created: 2. nieuwbouw
Group: Model Group:Paneel op dak:6287507

# IfcBuildingElementProxy: 6287452
In: 02 tweede verdieping
Pset_ProductRequirements - Category: Walls: Wall Sweeps; sets with these values: 2
Constraints - Offset From Level: 240 mm; Offset From Wall: 1 mm
Dimensions - Length: 1797.5 mm
Identity Data - Workset: Bouwkundig
Phasing - Phase Created: 2. nieuwbouw
Group: Model Group:Paneel op dak:6287507

# IfcBuildingElementProxy: 6287453
In: 02 tweede verdieping
Pset_ProductRequirements - Category: Walls: Wall Sweeps; sets with these values: 2
Constraints - Offset From Level: 120 mm; Offset From Wall: 1 mm
Dimensions - Length: 1797.5 mm
Identity Data - Workset: Bouwkundig
Phasing - Phase Created: 2. nieuwbouw
Group: Model Group:Paneel op dak:6287507

# IfcBuildingElementProxy: 6287490
In: 02 tweede verdieping
Pset_ProductRequirements - Category: Walls: Wall Sweeps; sets with these values: 2
Pset_ProvisionForVoid - Shape: Undefined
Constraints - Offset From Level: 2040 mm; Offset From Wall: 1 mm
Dimensions - Length: 1797.5 mm
Identity Data - Workset: Bouwkundig
Phasing - Phase Created: 2. nieuwbouw
Group: Model Group:Paneel op dak:6287507

# IfcBuildingElementProxy: 6287491
In: 02 tweede verdieping
Pset_ProductRequirements - Category: Walls: Wall Sweeps; sets with these values: 2
Pset_ProvisionForVoid - Shape: Undefined
Constraints - Offset From Level: 1920 mm; Offset From Wall: 1 mm
Dimensions - Length: 1797.5 mm
Identity Data - Workset: Bouwkundig
Phasing - Phase Created: 2. nieuwbouw
Group: Model Group:Paneel op dak:6287507

# IfcBuildingElementProxy: 6287492
In: 02 tweede verdieping
Pset_ProductRequirements - Category: Walls: Wall Sweeps; sets with these values: 2
Pset_ProvisionForVoid - Shape: Undefined
Constraints - Offset From Level: 1800 mm; Offset From Wall: 1 mm
Dimensions - Length: 1797.5 mm
Identity Data - Workset: Bouwkundig
Phasing - Phase Created: 2. nieuwbouw
Group: Model Group:Paneel op dak:6287507

# IfcBuildingElementProxy: 6287493
In: 02 tweede verdieping
Pset_ProductRequirements - Category: Walls: Wall Sweeps; sets with these values: 2
Pset_ProvisionForVoid - Shape: Undefined
Constraints - Offset From Level: 1680 mm; Offset From Wall: 1 mm
Dimensions - Length: 1797.5 mm
Identity Data - Workset: Bouwkundig
Phasing - Phase Created: 2. nieuwbouw
Group: Model Group:Paneel op dak:6287507

# IfcBuildingElementProxy: 6287494
In: 02 tweede verdieping
Pset_ProductRequirements - Category: Walls: Wall Sweeps; sets with these values: 2
Pset_ProvisionForVoid - Shape: Undefined
Constraints - Offset From Level: 1560 mm; Offset From Wall: 1 mm
Dimensions - Length: 1797.5 mm
Identity Data - Workset: Bouwkundig
Phasing - Phase Created: 2. nieuwbouw
Group: Model Group:Paneel op dak:6287507

# IfcBuildingElementProxy: 6287495
In: 02 tweede verdieping
Pset_ProductRequirements - Category: Walls: Wall Sweeps; sets with these values: 2
Pset_ProvisionForVoid - Shape: Undefined
Constraints - Offset From Level: 1440 mm; Offset From Wall: 1 mm
Dimensions - Length: 1797.5 mm
Identity Data - Workset: Bouwkundig
Phasing - Phase Created: 2. nieuwbouw
Group: Model Group:Paneel op dak:6287507

# IfcBuildingElementProxy: 6287496
In: 02 tweede verdieping
Pset_ProductRequirements - Category: Walls: Wall Sweeps; sets with these values: 2
Pset_ProvisionForVoid - Shape: Undefined
Constraints - Offset From Level: 1320 mm; Offset From Wall: 1 mm
Dimensions - Length: 1797.5 mm
Identity Data - Workset: Bouwkundig
Phasing - Phase Created: 2. nieuwbouw
Group: Model Group:Paneel op dak:6287507

# IfcBuildingElementProxy: 6287497
In: 02 tweede verdieping
Pset_ProductRequirements - Category: Walls: Wall Sweeps; sets with these values: 2
Pset_ProvisionForVoid - Shape: Undefined
Constraints - Offset From Level: 1200 mm; Offset From Wall: 1 mm
Dimensions - Length: 1797.5 mm
Identity Data - Workset: Bouwkundig
Phasing - Phase Created: 2. nieuwbouw
Group: Model Group:Paneel op dak:6287507

# IfcBuildingElementProxy: 6287498
In: 02 tweede verdieping
Pset_ProductRequirements - Category: Walls: Wall Sweeps; sets with these values: 2
Pset_ProvisionForVoid - Shape: Undefined
Constraints - Offset From Level: 1080 mm; Offset From Wall: 1 mm
Dimensions - Length: 1797.5 mm
Identity Data - Workset: Bouwkundig
Phasing - Phase Created: 2. nieuwbouw
Group: Model Group:Paneel op dak:6287507

# IfcBuildingElementProxy: 6287499
In: 02 tweede verdieping
Pset_ProductRequirements - Category: Walls: Wall Sweeps; sets with these values: 2
Pset_ProvisionForVoid - Shape: Undefined
Constraints - Offset From Level: 960 mm; Offset From Wall: 1 mm
Dimensions - Length: 1797.5 mm
Identity Data - Workset: Bouwkundig
Phasing - Phase Created: 2. nieuwbouw
Group: Model Group:Paneel op dak:6287507

# IfcBuildingElementProxy: 6287500
In: 02 tweede verdieping
Pset_ProductRequirements - Category: Walls: Wall Sweeps; sets with these values: 2
Pset_ProvisionForVoid - Shape: Undefined
Constraints - Offset From Level: 840 mm; Offset From Wall: 1 mm
Dimensions - Length: 1797.5 mm
Identity Data - Workset: Bouwkundig
Phasing - Phase Created: 2. nieuwbouw
Group: Model Group:Paneel op dak:6287507

# IfcBuildingElementProxy: 6287501
In: 02 tweede verdieping
Pset_ProductRequirements - Category: Walls: Wall Sweeps; sets with these values: 2
Pset_ProvisionForVoid - Shape: Undefined
Constraints - Offset From Level: 720 mm; Offset From Wall: 1 mm
Dimensions - Length: 1797.5 mm
Identity Data - Workset: Bouwkundig
Phasing - Phase Created: 2. nieuwbouw
Group: Model Group:Paneel op dak:6287507

# IfcBuildingElementProxy: 6287502
In: 02 tweede verdieping
Pset_ProductRequirements - Category: Walls: Wall Sweeps; sets with these values: 2
Pset_ProvisionForVoid - Shape: Undefined
Constraints - Offset From Level: 600 mm; Offset From Wall: 1 mm
Dimensions - Length: 1797.5 mm
Identity Data - Workset: Bouwkundig
Phasing - Phase Created: 2. nieuwbouw
Group: Model Group:Paneel op dak:6287507

# IfcBuildingElementProxy: 6287503
In: 02 tweede verdieping
Pset_ProductRequirements - Category: Walls: Wall Sweeps; sets with these values: 2
Pset_ProvisionForVoid - Shape: Undefined
Constraints - Offset From Level: 480 mm; Offset From Wall: 1 mm
Dimensions - Length: 1797.5 mm
Identity Data - Workset: Bouwkundig
Phasing - Phase Created: 2. nieuwbouw
Group: Model Group:Paneel op dak:6287507

# IfcBuildingElementProxy: 6287504
In: 02 tweede verdieping
Pset_ProductRequirements - Category: Walls: Wall Sweeps; sets with these values: 2
Pset_ProvisionForVoid - Shape: Undefined
Constraints - Offset From Level: 360 mm; Offset From Wall: 1 mm
Dimensions - Length: 1797.5 mm
Identity Data - Workset: Bouwkundig
Phasing - Phase Created: 2. nieuwbouw
Group: Model Group:Paneel op dak:6287507

# IfcBuildingElementProxy: 6287505
In: 02 tweede verdieping
Pset_ProductRequirements - Category: Walls: Wall Sweeps; sets with these values: 2
Pset_ProvisionForVoid - Shape: Undefined
Constraints - Offset From Level: 240 mm; Offset From Wall: 1 mm
Dimensions - Length: 1797.5 mm
Identity Data - Workset: Bouwkundig
Phasing - Phase Created: 2. nieuwbouw
Group: Model Group:Paneel op dak:6287507

# IfcBuildingElementProxy: 6287506
In: 02 tweede verdieping
Pset_ProductRequirements - Category: Walls: Wall Sweeps; sets with these values: 2
Pset_ProvisionForVoid - Shape: Undefined
Constraints - Offset From Level: 120 mm; Offset From Wall: 1 mm
Dimensions - Length: 1797.5 mm
Identity Data - Workset: Bouwkundig
Phasing - Phase Created: 2. nieuwbouw
Group: Model Group:Paneel op dak:6287507

# IfcBuildingElementProxy: 63_DAT_Spotverlichting layout 4 stuks:2400 (3)
In: 00 Begane grond
Type - Material: <Unnamed>
Type - Other - Category: Generic Models; Midden: no; Family Name: 63_DAT_Spotverlichting layout 4 stuks
Type - Constraints - Default Elevation: 0 mm
Type - Dimensions - Maat vanaf muur: 500 mm; Plafondhoogte: 3240 mm
Type - Identity Data - Type Name: 2400; Workset: Family : Generic Models : 63_DAT_Spotverlichting layout 4 stuks
Type - Pset_ProductRequirements - Category: Generic Models
Pset_BuildingElementProxyCommon - Reference: 2400; sets with these values: 2
Pset_Generic Models - Family and Type: 63_DAT_Spotverlichting layout 4 stuks: 2400; Level: 0
Other - Type: 2400; Family: 63_DAT_Spotverlichting layout 4 stuks; Family and Type: 63_DAT_Spotverlichting layout 4 stuks: 2400; Type Id: 5368973
Constraints - Elevation from Level: 0 mm; Level: 0; Moves With Nearby Elements: no; Offset from Host: 0 mm; Host: Level : 0
Dimensions - Area: 0.12566 m2; Lengte: 11015 mm; Volume: 0.00471217 m3
Identity Data - Workset: installatie
Phasing - Phase Created: 2. nieuwbouw
Name (63_DAT_Spotverlichting layout 4 stuks:2400:...)
5371534
5411740
5412089

# IfcBuildingElementProxy: 63_DAT_Spotverlichting:2400 (11)
Type - Material: <Unnamed>
Type - Other - Category: Generic Models; Family Name: 63_DAT_Spotverlichting
Type - Constraints - Default Elevation: 0 mm
Type - Dimensions - Diameter: 100 mm; Hoogte: 150 mm; Hoogte plafond: 2400 mm; Straal: 50 mm
Type - Identity Data - Type Name: 2400; Workset: Family : Generic Models : 63_DAT_Spotverlichting
Type - Pset_ProductRequirements - Category: Generic Models
Type - Pset_ProvisionForVoid - Diameter: 100 mm
Pset_BuildingElementProxyCommon - Reference: 2400; sets with these values: 2
Pset_Generic Models - Family and Type: 63_DAT_Spotverlichting: 2400
Other - Family: 63_DAT_Spotverlichting; Family and Type: 63_DAT_Spotverlichting: 2400; Type: 2400; Type Id: 5354753
Constraints - Elevation from Level: 0 mm; Moves With Nearby Elements: no; Offset from Host: 0 mm
Dimensions - Area: 0.0314149 m2; Volume: 0.00117804 m3
Identity Data - Workset: Bouwkundig
Phasing - Phase Created: 2. nieuwbouw
Name (63_DAT_Spotverlichting:2400:...) | In | Pset_Generic Models, Level = Constraints, Level | Host | Group
5354769 | 0.41 | 0 | Level : 0 | Model Group:WC_V0:4977398
5355276 | 0.43 | 0 | Level : 0 | Model Group:WC_V0:4976980
5355280 | 0.42 | 0 | Level : 0 | Model Group:WC_V0:4977293
5355282 | 1.27 | 1 | Level : 1 | Model Group:WC_V0:5035649
5355284 | 1.25 | 1 | Level : 1 | Model Group:WC_V0:5035659
5355286 | 1.08 | 1 | Level : 1
5381442 | 1.14 | 1 | Floor : 23_Zwevende dekvloer 90mm
5381517 | 1.15 | 1 | Floor : 23_Zwevende dekvloer 90mm
5381554 | 1.18 | 1 | Floor : 23_Zwevende dekvloer 90mm
5381589 | 1.19 | 1 | Floor : 23_Zwevende dekvloer 90mm
5994943 | 1.06 | 1 | Level : 1 | Model Group:WC_V0:5994912

# IfcBuildingElementProxy: 63_DAT_Spotverlichting:3240,0 (2)
In: 01 eerste verdieping
Type - Material: <Unnamed>
Type - Other - Category: Generic Models; Family Name: 63_DAT_Spotverlichting
Type - Constraints - Default Elevation: 0 mm
Type - Dimensions - Diameter: 100 mm; Hoogte: 150 mm; Hoogte plafond: 3240 mm; Straal: 50 mm
Type - Identity Data - Workset: Family : Generic Models : 63_DAT_Spotverlichting; Type Name: 3240,0
Type - Pset_ProductRequirements - Category: Generic Models
Type - Pset_ProvisionForVoid - Diameter: 100 mm
Pset_BuildingElementProxyCommon - Reference: 3240,0; sets with these values: 2
Pset_Generic Models - Family and Type: 63_DAT_Spotverlichting: 3240,0; Level: 1
Other - Family: 63_DAT_Spotverlichting; Family and Type: 63_DAT_Spotverlichting: 3240,0; Type: 3240,0; Type Id: 5355955
Constraints - Elevation from Level: 0 mm; Moves With Nearby Elements: no; Offset from Host: 0 mm; Level: 1; Host: Floor : 23_Zwevende dekvloer 90mm
Dimensions - Area: 0.0314149 m2; Volume: 0.00117804 m3
Identity Data - Workset: Bouwkundig
Phasing - Phase Created: 2. nieuwbouw
Name (63_DAT_Spotverlichting:3240,0:...)
5381012
5413787

# IfcBuildingElementProxy: 6605324
In: 02 tweede verdieping
Pset_ProductRequirements - Category: Walls: Wall Sweeps; sets with these values: 2
Constraints - Offset From Level: 2040 mm; Offset From Wall: 1 mm
Dimensions - Length: 1802.5 mm
Identity Data - Workset: Bouwkundig
Phasing - Phase Created: 2. nieuwbouw

# IfcBuildingElementProxy: 6605325
In: 02 tweede verdieping
Pset_ProductRequirements - Category: Walls: Wall Sweeps; sets with these values: 2
Constraints - Offset From Level: 1920 mm; Offset From Wall: 1 mm
Dimensions - Length: 1802.5 mm
Identity Data - Workset: Bouwkundig
Phasing - Phase Created: 2. nieuwbouw

# IfcBuildingElementProxy: 6605326
In: 02 tweede verdieping
Pset_ProductRequirements - Category: Walls: Wall Sweeps; sets with these values: 2
Constraints - Offset From Level: 1800 mm; Offset From Wall: 1 mm
Dimensions - Length: 1802.5 mm
Identity Data - Workset: Bouwkundig
Phasing - Phase Created: 2. nieuwbouw

# IfcBuildingElementProxy: 6605327
In: 02 tweede verdieping
Pset_ProductRequirements - Category: Walls: Wall Sweeps; sets with these values: 2
Constraints - Offset From Level: 1680 mm; Offset From Wall: 1 mm
Dimensions - Length: 1802.5 mm
Identity Data - Workset: Bouwkundig
Phasing - Phase Created: 2. nieuwbouw

# IfcBuildingElementProxy: 6605328
In: 02 tweede verdieping
Pset_ProductRequirements - Category: Walls: Wall Sweeps; sets with these values: 2
Constraints - Offset From Level: 1560 mm; Offset From Wall: 1 mm
Dimensions - Length: 1802.5 mm
Identity Data - Workset: Bouwkundig
Phasing - Phase Created: 2. nieuwbouw

# IfcBuildingElementProxy: 6605329
In: 02 tweede verdieping
Pset_ProductRequirements - Category: Walls: Wall Sweeps; sets with these values: 2
Constraints - Offset From Level: 1440 mm; Offset From Wall: 1 mm
Dimensions - Length: 1802.5 mm
Identity Data - Workset: Bouwkundig
Phasing - Phase Created: 2. nieuwbouw

# IfcBuildingElementProxy: 6605330
In: 02 tweede verdieping
Pset_ProductRequirements - Category: Walls: Wall Sweeps; sets with these values: 2
Constraints - Offset From Level: 1320 mm; Offset From Wall: 1 mm
Dimensions - Length: 1802.5 mm
Identity Data - Workset: Bouwkundig
Phasing - Phase Created: 2. nieuwbouw

# IfcBuildingElementProxy: 6605331
In: 02 tweede verdieping
Pset_ProductRequirements - Category: Walls: Wall Sweeps; sets with these values: 2
Constraints - Offset From Level: 1200 mm; Offset From Wall: 1 mm
Dimensions - Length: 1802.5 mm
Identity Data - Workset: Bouwkundig
Phasing - Phase Created: 2. nieuwbouw

# IfcBuildingElementProxy: 6605332
In: 02 tweede verdieping
Pset_ProductRequirements - Category: Walls: Wall Sweeps; sets with these values: 2
Constraints - Offset From Level: 1080 mm; Offset From Wall: 1 mm
Dimensions - Length: 1802.5 mm
Identity Data - Workset: Bouwkundig
Phasing - Phase Created: 2. nieuwbouw

# IfcBuildingElementProxy: 6605333
In: 02 tweede verdieping
Pset_ProductRequirements - Category: Walls: Wall Sweeps; sets with these values: 2
Constraints - Offset From Level: 960 mm; Offset From Wall: 1 mm
Dimensions - Length: 1802.5 mm
Identity Data - Workset: Bouwkundig
Phasing - Phase Created: 2. nieuwbouw

# IfcBuildingElementProxy: 6605334
In: 02 tweede verdieping
Pset_ProductRequirements - Category: Walls: Wall Sweeps; sets with these values: 2
Constraints - Offset From Level: 840 mm; Offset From Wall: 1 mm
Dimensions - Length: 1802.5 mm
Identity Data - Workset: Bouwkundig
Phasing - Phase Created: 2. nieuwbouw

# IfcBuildingElementProxy: 6605335
In: 02 tweede verdieping
Pset_ProductRequirements - Category: Walls: Wall Sweeps; sets with these values: 2
Constraints - Offset From Level: 720 mm; Offset From Wall: 1 mm
Dimensions - Length: 1802.5 mm
Identity Data - Workset: Bouwkundig
Phasing - Phase Created: 2. nieuwbouw

# IfcBuildingElementProxy: 6605336
In: 02 tweede verdieping
Pset_ProductRequirements - Category: Walls: Wall Sweeps; sets with these values: 2
Constraints - Offset From Level: 600 mm; Offset From Wall: 1 mm
Dimensions - Length: 1802.5 mm
Identity Data - Workset: Bouwkundig
Phasing - Phase Created: 2. nieuwbouw

# IfcBuildingElementProxy: 6605337
In: 02 tweede verdieping
Pset_ProductRequirements - Category: Walls: Wall Sweeps; sets with these values: 2
Constraints - Offset From Level: 480 mm; Offset From Wall: 1 mm
Dimensions - Length: 1802.5 mm
Identity Data - Workset: Bouwkundig
Phasing - Phase Created: 2. nieuwbouw

# IfcBuildingElementProxy: 6605338
In: 02 tweede verdieping
Pset_ProductRequirements - Category: Walls: Wall Sweeps; sets with these values: 2
Constraints - Offset From Level: 360 mm; Offset From Wall: 1 mm
Dimensions - Length: 1802.5 mm
Identity Data - Workset: Bouwkundig
Phasing - Phase Created: 2. nieuwbouw

# IfcBuildingElementProxy: 6605339
In: 02 tweede verdieping
Pset_ProductRequirements - Category: Walls: Wall Sweeps; sets with these values: 2
Constraints - Offset From Level: 240 mm; Offset From Wall: 1 mm
Dimensions - Length: 1802.5 mm
Identity Data - Workset: Bouwkundig
Phasing - Phase Created: 2. nieuwbouw

# IfcBuildingElementProxy: 6605340
In: 02 tweede verdieping
Pset_ProductRequirements - Category: Walls: Wall Sweeps; sets with these values: 2
Constraints - Offset From Level: 120 mm; Offset From Wall: 1 mm
Dimensions - Length: 1802.5 mm
Identity Data - Workset: Bouwkundig
Phasing - Phase Created: 2. nieuwbouw

# IfcBuildingElementProxy: 82_DAT_Trimlat om element:82_DAT_Trimlat om element (37)
Type - Material: ISR_HPL Kleur hout
Type - Other - Category: Generic Models; Family Name: 82_DAT_Trimlat om element
Type - Constraints - Default Elevation: 0 mm
Type - Dimensions - Breedte strip: 35 mm; Hoogte: 2400 mm; Ofset: 0 mm; voor de wand: 20 mm
Type - Identity Data - Type Name: 82_DAT_Trimlat om element; Workset: Family : Generic Models : 82_DAT_Trimlat om element
Type - Materials and Finishes - Materiaal: ISR_HPL Kleur hout
Type - Pset_ProductRequirements - Category: Generic Models
Pset_BuildingElementProxyCommon - Reference: 82_DAT_Trimlat om element; sets with these values: 2
Pset_Generic Models - Family and Type: 82_DAT_Trimlat om element: 82_DAT_Trimlat om element
Other - Boven: yes; Family: 82_DAT_Trimlat om element; Family and Type: 82_DAT_Trimlat om element: 82_DAT_Trimlat om element; Type: 82_DAT_Trimlat om element; Type Id: 6331531
Constraints - Elevation from Level: 0 mm; Moves With Nearby Elements: no; Offset from Host: 0 mm
Identity Data - Workset: Bouwkundig
Phasing - Phase Created: 2. nieuwbouw
Name (82_DAT_Trimlat om element:82_DAT_Trimlat om element:...) | In | Width (mm) | Height (mm) = Depth (mm) | Pset_Generic Models, Level = Constraints, Level | Links | Rechts | Host | Area (m2) | Breedte (mm) | Volume (m3)
6331882 | 0.15 | 20 | 1925 | 0 | yes | yes | Level : 0 | 0.371975 | 1855 | 0.0047075
6331927 | 0.15 | 20 | 2500 | 0 | yes | yes | Level : 0 | 0.4036 | 2430 | 0.00511
6331939 | 0.15 | 20 | 1925 | 0 | yes | yes | Level : 0 | 0.371975 | 1855 | 0.0047075
6331949 | 0.15 | 20 | 2485 | 0 | no | yes | Level : 0 | 0.402775 | 2415 | 0.0034195
6332899 | 0.16 | 20 | 4740.04 | 0 | no | no | Level : 0 | 0.526802 | 4670.04 | 0.00331803
6338791 | 0.33 | 20 | 4344 | 0 | yes | yes | Level : 0 | 0.50502 | 4274 | 0.0064008
6347505 | 0.33 | 20 | 4345 | 0 | yes | yes | Level : 0 | 0.505075 | 4275 | 0.0064015
6347556 | 0.33 | 20 | 4345 | 0 | yes | yes | Level : 0 | 0.505075 | 4275 | 0.0064015
6347725 | 0.33 | 20 | 4345 | 0 | yes | no | Level : 0 | 0.505075 | 4275 | 0.0047215
6367043 | 1.11 | 20 | 4345 | 1 | yes | yes | Level : 1 | 0.505075 | 4275 | 0.0064015
6367146 | 1.11 | 20 | 4345 | 1 | yes | yes | Level : 1 | 0.505075 | 4275 | 0.0064015
6367154 | 1.11 | 20 | 4345 | 1 | yes | yes | Level : 1 | 0.505075 | 4275 | 0.0064015
6367168 | 1.11 | 20 | 4345 | 1 | yes | yes | Level : 1 | 0.505075 | 4275 | 0.0064015
6370135 | 1.12 | 20 | 1578 | 1 | yes | yes | Level : 1 | 0.35289 | 1508 | 0.0044646
6371022 | 1.20 | 20 | 4345 | 1 | yes | no | Level : 1 | 0.505075 | 4275 | 0.0047215
6371474 | 1.20 | 20 | 4345 | 1 | yes | yes | Level : 1 | 0.505075 | 4275 | 0.0064015
6371482 | 1.20 | 20 | 4345 | 1 | yes | yes | Level : 1 | 0.505075 | 4275 | 0.0064015
6382278 | 00 Begane grond | 20 | 1726.25 | 0 | no | yes | Level : 0 | 0.361044 | 1656.25 | 0.00288837
6382283 | 01 eerste verdieping | 20 | 2923.99 | 1 | no | yes | Level : 1 | 0.42692 | 2853.99 | 0.0037268
6382303 | 00 Begane grond | 20 | 1580 | 0 | yes | no | Level : 0 | 0.353 | 1510 | 0.002786
6395413 | 0.36 | 4330 | 20 | 0 | yes | yes | Level : 0 | 0.50425 | 4260 | 0.006391
6397136 | 0.35 | 4330 | 20 | 0 | yes | yes | Level : 0 | 0.50425 | 4260 | 0.006391
6397144 | 0.37 | 4330 | 20 | 0 | yes | yes | Level : 0 | 0.50425 | 4260 | 0.006391
6397353 | 0.28 | 20 | 5320 | 0 | no | yes | Level : 0 | 0.5587 | 5250 | 0.005404
6399138 | 0.05 | 6995 | 20 | 0 | yes | yes | Level : 0 | 0.650825 | 6925 | 0.0082565
6399273 | 0.01 | 7020.5 | 20 | 0 | yes | yes | Level : 0 | 0.652227 | 6950.5 | 0.00827435
6399377 | 0.09 | 6995 | 20 | 0 | yes | yes | Level : 0 | 0.650825 | 6925 | 0.0082565
6405793 | 1.01 | 20 | 4345 | 1 | yes | no | Level : 1 | 0.505075 | 4275 | 0.0047215
6405851 | 1.02 | 20 | 4345 | 1 | yes | no | Level : 1 | 0.505075 | 4275 | 0.0047215
6405859 | 1.03 | 20 | 4345 | 1 | yes | no | Level : 1 | 0.505075 | 4275 | 0.0047215
6405869 | 1.04 | 20 | 4345 | 1 | yes | yes | Level : 1 | 0.505075 | 4275 | 0.0064015
6406740 | 1.21 | 4325 | 20 | 1 | yes | yes | Level : 1 | 0.503975 | 4255 | 0.0063875
6406804 | 1.22 | 4325 | 20 | 1 | yes | yes | Level : 1 | 0.503975 | 4255 | 0.0063875
6406812 | 1.23 | 4325 | 20 | 1 | yes | yes | Level : 1 | 0.503975 | 4255 | 0.0063875
6693919 | 0.16 | 1580 | 20 | 0 | yes | no | Level : 0 | 0.353 | 1510 | 0.002786
6693966 | 00 Begane grond | 20 | 1580 | 0 | yes | no | Level : 0 | 0.353 | 1510 | 0.002786
6884494 | 0.15 | 20 | 1925 | 0 | yes | yes | Level : 0 | 0.371975 | 1855 | 0.0047075

# IfcBuildingElementProxy: 82_DAT_garderobekast_ Hoek:82_DAT_garderobekast_02 (7)
Type - Material: <Unnamed>, ISR_HPL Kleur hout
Type - Other - Category: Generic Models; aantal 1_haakjes: 14; aantal 2_haakjes: 15; Family Name: 82_DAT_garderobekast_ Hoek; Tassenschot: yes; Totaal haakjes: 29
Type - Constraints - Default Elevation: 0 mm
Type - Dimensions - Diepte: 392 mm; Diepte gang: 1313.17 mm; Dikte paneel: 67 mm; Hoogte Kast: 1200 mm; Hoogte plank: 0 mm; Hoogte Tassen schot: 300 mm; Inham: 96 mm; Linkse verbreding: 670 mm; NLRS_C_lengte: 3120 mm; rechtse verbreding: 621 mm
Type - Identity Data - Type Name: 82_DAT_garderobekast_02; Workset: Family : Generic Models : 82_DAT_garderobekast_ Hoek
Type - Materials and Finishes - achterwand_materiaal: ISR_HPL Kleur hout; plank_materiaal: ISR_HPL Kleur hout
Type - Pset_ProductRequirements - Category: Generic Models
Pset_BuildingElementProxyCommon - Reference: 82_DAT_garderobekast_02; sets with these values: 2
Pset_Generic Models - Family and Type: 82_DAT_garderobekast_ Hoek: 82_DAT_garderobekast_02
Other - Family: 82_DAT_garderobekast_ Hoek; Family and Type: 82_DAT_garderobekast_ Hoek: 82_DAT_garderobekast_02; NLRS_C_aantal: 29; Ruimte Gipsplaat L: yes; Ruimte Gipsplaat R: yes; Type: 82_DAT_garderobekast_02; Type Id: 5147200; Verbreding links: no; Verbreding rechts: no
Constraints - Elevation from Level: 0 mm; Moves With Nearby Elements: no; Offset from Host: 0 mm
Dimensions - Area: 14.4253 m2; Volume: 0.32183 m3
Identity Data - Workset: Bouwkundig
Phasing - Phase Created: 2. nieuwbouw
Name (82_DAT_garderobekast_ Hoek:82_DAT_garderobekast_02:...) | In | Pset_Generic Models, Level = Constraints, Level | Host | Group
5147944 | 0.33 | 0 | Level : 0 | Model Group:Basisgroep element:5145694
5148190 | 0.33 | 0 | Level : 0 | Model Group:Basisgroep element:5145620
5148194 | 0.33 | 0 | Level : 0 | Model Group:Basisgroep element:5145670
5181888 | 1.20 | 1 | Level : 1 | Model Group:Basisgroep element:5181887
5184347 | 1.20 | 1 | Level : 1 | Model Group:Basisgroep element:5184346
5184396 | 1.20 | 1 | Level : 1 | Model Group:Basisgroep element:5184395
5203611 | 0.33 | 0 | Level : 0 | Model Group:Basisgroep element 2:5203610

# IfcBuildingElementProxy: 82_DAT_garderobekast_2 rijen:82_DAT_garderobekast_02 (4)
Type - Material: <Unnamed>, ISR_HPL Kleur hout
Type - Other - Category: Generic Models; Tassenschot: yes; aantal 1_haakjes: 14; aantal 2_haakjes: 15; Family Name: 82_DAT_garderobekast_2 rijen; Totaal haakjes: 29
Type - Constraints - Default Elevation: 0 mm
Type - Dimensions - Hoogte plank: 0 mm; Diepte: 392 mm; Dikte paneel: 67 mm; Hoogte Kast: 1200 mm; Hoogte Tassen schot: 300 mm; Inham: 96 mm; Linkse verbreding: 670 mm; maat plank voor haakjes: 60 mm; NLRS_C_lengte: 3125 mm; rechtse verbreding: 670 mm; Restmaat: 325 mm
Type - Identity Data - Workset: Family : Generic Models : 82_DAT_garderobekast_2 rijen; Type Name: 82_DAT_garderobekast_02
Type - Materials and Finishes - achterwand_materiaal: ISR_HPL Kleur hout; plank_materiaal: ISR_HPL Kleur hout
Type - Pset_ProductRequirements - Category: Generic Models
Pset_BuildingElementProxyCommon - Reference: 82_DAT_garderobekast_02; sets with these values: 2
Pset_Generic Models - Family and Type: 82_DAT_garderobekast_2 rijen: 82_DAT_garderobekast_02; Level: 1
Other - Ruimte Gipsplaat L: yes; Ruimte Gipsplaat R: yes; Type: 82_DAT_garderobekast_02; Verbreding links: no; Verbreding rechts: no; Family: 82_DAT_garderobekast_2 rijen; Family and Type: 82_DAT_garderobekast_2 rijen: 82_DAT_garderobekast_02; NLRS_C_aantal: 29; Type Id: 5169674
Constraints - Elevation from Level: 0 mm; Moves With Nearby Elements: no; Offset from Host: 0 mm; Level: 1; Host: Level : 1
Dimensions - Area: 11.5801 m2; Volume: 0.241119 m3
Identity Data - Workset: Bouwkundig
Phasing - Phase Created: 2. nieuwbouw
Name (82_DAT_garderobekast_2 rijen:82_DAT_garderobekast_02:...) | In
5989093 | 1.01a
5989135 | 1.03a | Group: Model Group:V1_Basiselement:5167028
5989137 | 1.04a
5989139 | 1.02a | Group: Model Group:V1_Basiselement:5988153

# IfcBuildingElementProxy: 82_DAT_garderobekast_2 rijen:82_DAT_garderobekast_05 (2)
In: 0.15
Type - Material: <Unnamed>, ISR_HPL Kleur hout
Type - Other - Category: Generic Models; Tassenschot: yes; aantal 1_haakjes: 10; aantal 2_haakjes: 11; Family Name: 82_DAT_garderobekast_2 rijen; Totaal haakjes: 21
Type - Constraints - Default Elevation: 0 mm
Type - Dimensions - Hoogte plank: 0 mm; Diepte: 392 mm; Dikte paneel: 67 mm; Hoogte Kast: 1000 mm; Hoogte Tassen schot: 250 mm; Inham: 96 mm; Linkse verbreding: 670 mm; maat plank voor haakjes: 60 mm; NLRS_C_lengte: 2400 mm; rechtse verbreding: 670 mm; Restmaat: 400 mm
Type - Identity Data - Type Name: 82_DAT_garderobekast_05; Workset: Family : Generic Models : 82_DAT_garderobekast_2 rijen
Type - Materials and Finishes - achterwand_materiaal: ISR_HPL Kleur hout; plank_materiaal: ISR_HPL Kleur hout
Type - Pset_ProductRequirements - Category: Generic Models
Pset_BuildingElementProxyCommon - Reference: 82_DAT_garderobekast_05; sets with these values: 2
Pset_Generic Models - Family and Type: 82_DAT_garderobekast_2 rijen: 82_DAT_garderobekast_05; Level: 0
Other - Ruimte Gipsplaat L: yes; Ruimte Gipsplaat R: yes; Verbreding links: no; Verbreding rechts: no; Family: 82_DAT_garderobekast_2 rijen; Family and Type: 82_DAT_garderobekast_2 rijen: 82_DAT_garderobekast_05; NLRS_C_aantal: 21; Type: 82_DAT_garderobekast_05; Type Id: 5688843
Constraints - Elevation from Level: 0 mm; Level: 0; Moves With Nearby Elements: no; Offset from Host: 0 mm; Host: Level : 0
Dimensions - Area: 8.61708 m2; Volume: 0.177608 m3
Identity Data - Workset: Bouwkundig
Phasing - Phase Created: 2. nieuwbouw
Name (82_DAT_garderobekast_2 rijen:82_DAT_garderobekast_05:...)
5688745
5689675

# IfcBuildingElementProxy: 82_DAT_garderobekast_2 rijen:82_DAT_garderobekast_05 2, 82_DAT_garderobekast_2 rijen:82_DAT_garderobekast_05 2:6144802
In: 01 eerste verdieping
Type - Material: <Unnamed>, ISR_RAL 7044
Type - Other - Category: Generic Models; Tassenschot: yes; aantal 1_haakjes: 4; aantal 2_haakjes: 5; Family Name: 82_DAT_garderobekast_2 rijen; Totaal haakjes: 9
Type - Constraints - Default Elevation: 0 mm
Type - Dimensions - Hoogte plank: 0 mm; Diepte: 392 mm; Dikte paneel: 67 mm; Hoogte Kast: 1200 mm; Hoogte Tassen schot: 250 mm; Inham: 96 mm; Linkse verbreding: 670 mm; maat plank voor haakjes: 60 mm; NLRS_C_lengte: 1200 mm; rechtse verbreding: 670 mm; Restmaat: 400 mm
Type - Identity Data - Workset: Family : Generic Models : 82_DAT_garderobekast_2 rijen; Type Name: 82_DAT_garderobekast_05 2
Type - Materials and Finishes - achterwand_materiaal: ISR_RAL 7044; plank_materiaal: Interieurplaat hout
Type - Pset_ProductRequirements - Category: Generic Models
Pset_BuildingElementProxyCommon - Reference: 82_DAT_garderobekast_05 2; sets with these values: 2
Pset_Generic Models - Family and Type: 82_DAT_garderobekast_2 rijen: 82_DAT_garderobekast_05 2; Level: 1
Other - Ruimte Gipsplaat L: yes; Ruimte Gipsplaat R: yes; Verbreding links: no; Verbreding rechts: no; Family: 82_DAT_garderobekast_2 rijen; Family and Type: 82_DAT_garderobekast_2 rijen: 82_DAT_garderobekast_05 2; NLRS_C_aantal: 9; Type: 82_DAT_garderobekast_05 2; Type Id: 6143656
Constraints - Elevation from Level: 0 mm; Moves With Nearby Elements: no; Offset from Host: 0 mm; Level: 1; Host: Level : 1
Dimensions - Area: 6.73813 m2; Volume: 0.127807 m3
Identity Data - Workset: Constructie
Phasing - Phase Created: 2. nieuwbouw

# IfcBuildingElementProxy: 90_DAT_Fietsen Nietjes:90_DAT_Fietsen Nietjes (13)
In: 00 Begane grond
Type - Material: bcb_staal
Type - Other - Category: Generic Models; Family Name: 90_DAT_Fietsen Nietjes
Type - Constraints - Default Elevation: 0 mm
Type - Dimensions - Breedte: 1200 mm; Hoogte: 900 mm; Maat X: 30 mm; Maat Y: 80 mm; Radius: 30 mm
Type - Identity Data - Type Name: 90_DAT_Fietsen Nietjes; Workset: Family : Generic Models : 90_DAT_Fietsen Nietjes
Type - Materials and Finishes - Materiaal: bcb_staal
Type - Pset_ProductRequirements - Category: Generic Models
Pset_BuildingElementProxyCommon - Reference: 90_DAT_Fietsen Nietjes; sets with these values: 2
Pset_Generic Models - Family and Type: 90_DAT_Fietsen Nietjes: 90_DAT_Fietsen Nietjes; Level: 0
Other - Family: 90_DAT_Fietsen Nietjes; Family and Type: 90_DAT_Fietsen Nietjes: 90_DAT_Fietsen Nietjes; Type: 90_DAT_Fietsen Nietjes; Type Id: 6761790
Constraints - Elevation from Level: 0 mm; Level: 0; Moves With Nearby Elements: no; Offset from Host: 0 mm; Host: Level : 0
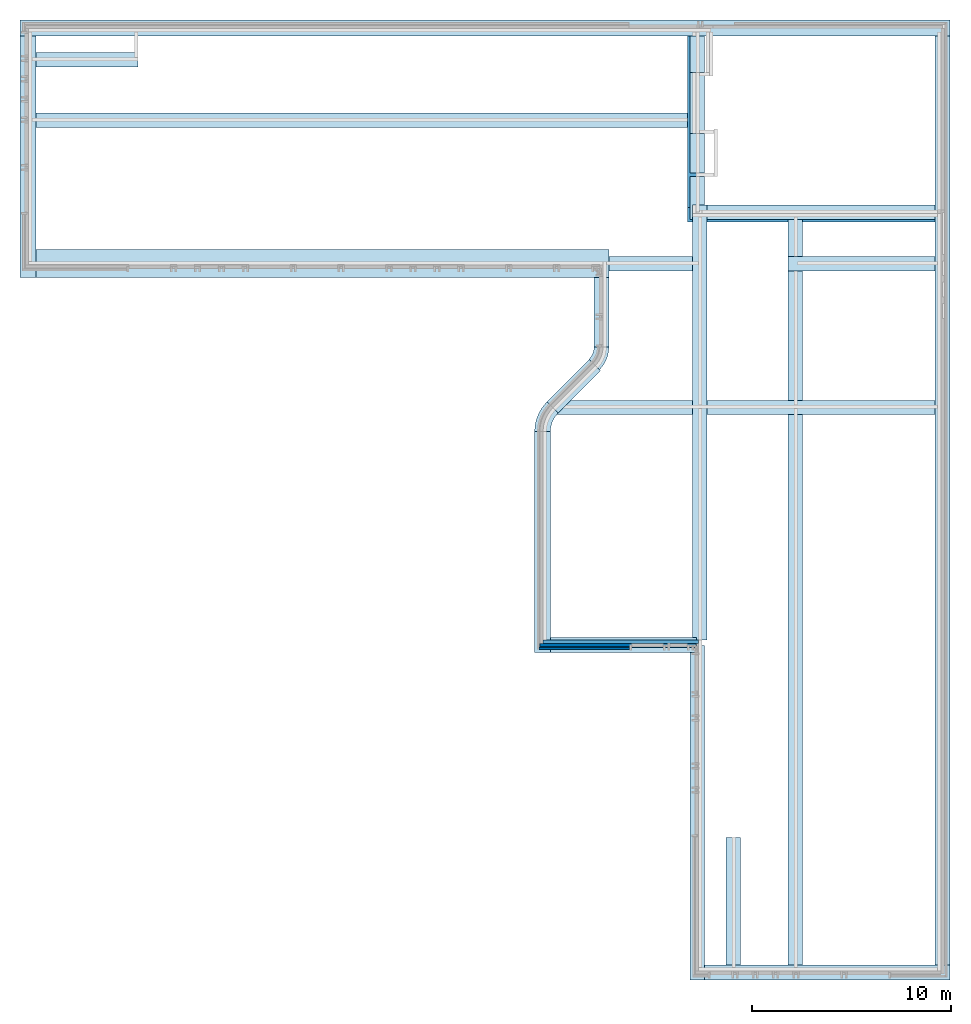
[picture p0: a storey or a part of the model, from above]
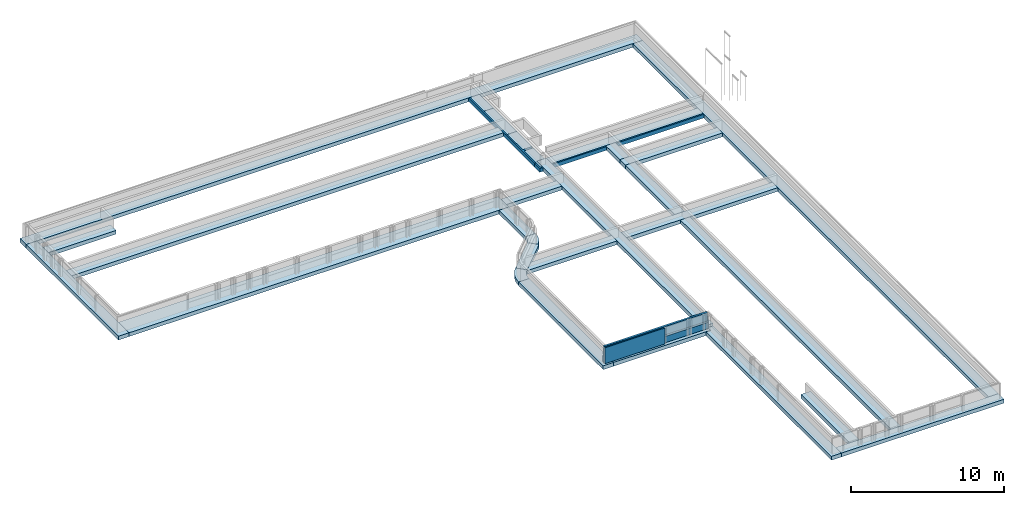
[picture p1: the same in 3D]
Properties of the parts of a building model (IFC2X3), part 8 of 37

# IfcBuildingElementProxy: 90_DAT_Fietsen Nietjes:90_DAT_Fietsen Nietjes (13)
Dimensions - Area: 0.267788 m2; Volume: 0.00794884 m3
Phasing - Phase Created: 2. nieuwbouw
Name (90_DAT_Fietsen Nietjes:90_DAT_Fietsen Nietjes:...) | Workset | Group
6762010 | Bouwkundig | Model Group:Array Group 4:6775005
6775008 | Bouwkundig | Model Group:Array Group 4:6775009
6775039 | Bouwkundig | Model Group:Array Group 4:6775040
6775066 | Bouwkundig | Model Group:Array Group 5:6775082
6775085 | Bouwkundig | Model Group:Array Group 5:6775086
6775102 | Bouwkundig | Model Group:Array Group 5:6775103
6775105 | Bouwkundig | Model Group:Array Group 5:6775106
6775108 | Bouwkundig | Model Group:Array Group 5:6775109
6775111 | Bouwkundig | Model Group:Array Group 5:6775112
6775114 | Bouwkundig | Model Group:Array Group 5:6775115
6902631 | situatie
6902645 | situatie
6902647 | situatie

# IfcBuildingElementProxy: A-side_Door_aluminium:1100 x 1467 - Left hinged (3)
Type - Material: cibes_RAL_9016
Type - Other - Category: Specialty Equipment; cibes_door_left_right_hung: Aluminium Door_single_glass : Left hinged; Family Name: A-side_Door_aluminium
Type - Constraints - Default Elevation: 1219.2 mm
Type - Construction - cibes_door_opening_AC_side: 900 mm
Type - Dimensions - cibes_component_width: 1440 mm
Type - General - Edition number: 1; Nominal height: 0; Nominal width: 0; Weight Net (Kg): 0; Date of publishing: 3/24/2014; Design country: Sweden; Manufacturer country: Sweden; Manufacturer name: Cibes Lift AB; Product family: Platform lifts; Product group: A5000; Product SKU: a_5000_ff; QR code: http://bimobject.com/cibeslift/product/a_5000_ff; Region Africa: All; Region Antarctica: All; Region Asia: All; Region Europe: All; Region Middle East: All; Region North America: All; Region Oceania: All; Region South America: All
Type - Identity Data - Assembly Code: 66.11; Assembly Description: transport; liften en heftableau's, elektrische liften; Product data url: https://bimobject.com/cibeslift/product/a_5000_ff; Technical description: http://www.cibeslift.com/products/platform-lifts/cibes-a5000-adaptable-solution/technical-overview/; Type Name: 1100 x 1467 - Left hinged; Workset: Family : Specialty Equipment : A-side_Door_aluminium; Youtube clip: http://www.youtube.com/watch?v=MNIus_d9DUA&feature=share&list=UUgiFKWIvNnKmXocLRwVWLuQ
Type - Materials and Finishes - Material main: Steel; Material secondary: Glass
Type - Pset_ProductRequirements - Category: Specialty Equipment
Classification: 66.11 Uniformat (Uniformat)
Pset_BuildingElementProxyCommon - Reference: 1100 x 1467 - Left hinged; sets with these values: 2
Pset_ProvisionForVoid - Width: 1440 mm; Height: 2460 mm; Depth: 2460 mm
Pset_DAT_KMS - Assembly Code: 66.11; Assembly Description: transport; liften en heftableau's, elektrische liften
Other - Family: A-side_Door_aluminium; Family and Type: A-side_Door_aluminium: 1100 x 1467 - Left hinged; Type: 1100 x 1467 - Left hinged; Type Id: 6207900
Construction - cibes_machinery_compartment: yes
Dimensions - Area: 2.23417 m2; Volume: 0.091854 m3
Fire Protection - NLRS_C_brandwerend: no
General - cibes_automatic_door_opener: yes
Identity Data - Workset: Bouwkundig
Materials and Finishes - cibes_component_material_glass: cibes_glass; cibes_component_material_glass_side: cibes_glass_black; cibes_component_material_additional: cibes_RAL_9016; cibes_component_material_main: cibes_RAL_9016; cibes_component_material_panel_steel: cibes_RAL_9016
Phasing - Phase Created: 2. nieuwbouw
Name (A-side_Door_aluminium:1100 x 1467 - Left hinged:...) | In | Level = Schedule Level | Elevation from Level (mm) | Offset from Host (mm) | Work Plane
6207977 | 0.00 | 0 | -45 | 555 | Floor : 23_Dekvloer 70mm
6209186 | -1 Speelvloer |  | 0 | 555 | <not associated>
6209443 | 0.00 | 1 | -45 | -45 | Level : 1

# IfcBuildingElementProxy: Cibes A5000 Base Component:1100x1567, Cibes A5000 Base Component:1100x1567:6200289
In: 0.00
Type - Material: <Unnamed>, cibes_metal_construction, cibes_RAL_9016_Traffic White, cibes_chrome, cibes_seat_wood, cibes_floor_rubber, cibes_pit, cibes_lifting_screw
Type - Other - Category: Electrical Equipment; Family Name: Cibes A5000 Base Component; ShX: 1680 mm; ShY: 1380 mm
Type - Constraints - Default Elevation: 0 mm
Type - Construction - cibes_construction_AC_side: 1440 mm; cibes_construction_BD_side: 1487 mm; cibes_hole_ac_side: 1380 mm; cibes_hole_bd_side: 1610 mm; cibes_platform: Platform A5000 : 1000x1467
Type - Dimensions - cibes_fixing_points_dist: 650 mm
Type - General - Date of publishing: 3/24/2014; Design country: Sweden; Edition number: 1; Manufacturer country: Sweden; Manufacturer name: Cibes Lift AB; Nominal height: 0; Nominal width: 0; Product family: Platform lifts; Product group: A5000; Product SKU: a_5000_ff; QR code: http://bimobject.com/cibeslift/product/a_5000_ff; Region Africa: All; Region Antarctica: All; Region Asia: All; Region Europe: All; Region Middle East: All; Region North America: All; Region Oceania: All; Region South America: All; Weight Net (Kg): 0
Type - Identity Data - Assembly Code: 66.11; Assembly Description: transport; liften en heftableau's, elektrische liften; Description: Plateaulift vloer 1100x1597; Keynote: 71; Manufacturer: Cibes Lift AB; Model: Cibes A5000; Product data url: https://bimobject.com/cibeslift/product/a_5000_ff; Technical description: http://www.cibeslift.com/products/platform-lifts/cibes-a5000-adaptable-solution/technical-overview/; Type Comments: Godkänd för både 400 kg och 500 kg; Type Name: 1100x1567; URL: http://www.cibeslift.com/; Workset: Family : Electrical Equipment : Cibes A5000 Base Component; Youtube clip: http://www.youtube.com/watch?v=MNIus_d9DUA&feature=share&list=UUgiFKWIvNnKmXocLRwVWLuQ
Type - Materials and Finishes - Material main: Steel; Material secondary: Glass
Type - Text - Fixing Points - Text: Fixing Points
Type - Pset_ManufacturerTypeInformation - Manufacturer: Cibes Lift AB
Type - Pset_ProductRequirements - Category: Electrical Equipment
Classification: 66.11 Uniformat (Uniformat)
Pset_BuildingElementProxyCommon - Reference: 1100x1567; sets with these values: 2
Pset_DAT_KMS - Assembly Code: 66.11; Assembly Description: transport; liften en heftableau's, elektrische liften; Description: Plateaulift vloer 1100x1597
Other - Family: Cibes A5000 Base Component; Family and Type: Cibes A5000 Base Component: 1100x1567; pltfmr_offs: 550 mm; Type: 1100x1567; Type Id: 6200254
Constraints - Elevation from Level: 0 mm; Moves With Nearby Elements: no; Offset from Host: 0 mm; Level: V-1; cibes_Celing_type: Ceiling w LEDs; cibes_fold-down_seat: yes; cibes_platform_elevation: 600 mm; cibes_top_floor_reference: 4250 mm; cibes_tot: 7440 mm; Host: Floor : 23_Dekvloer 70mm
Dimensions - Area: 90.6209 m2; Volume: 0.331598 m3
Electrical - Circuiting - Circuit Numbering Option: Default; Feed Through Lugs: yes; MCB Rating: 1 A; SubFeed Lugs: yes
Electrical - Loads - Apparent Load Phase A: 0 W; Apparent Load Phase B: 0 W; Apparent Load Phase C: 0 W; Branch Circuit Apparent Load Phase A: 0 W; Branch Circuit Apparent Load Phase B: 0 W; Branch Circuit Apparent Load Phase C: 0 W; Feed Through Lugs Apparent Load Phase A: 0 W; Feed Through Lugs Apparent Load Phase B: 0 W; Feed Through Lugs Apparent Load Phase C: 0 W; Total Connected: 0 W; Total Demand Factor: 100; Total Estimated Demand: 0 W
General - Location: Lift 0.00
Graphics - cibes_3D_text: no; cibes_show_construction_template: no; cibes_show_fixing_points_info: no; cibes_show_glass_info: no; cibes_show_hole_cutout_volume: no; cibes_show_shaft_hole_2D_info: yes; cibes_show_shaft_size: no
Identity Data - Workset: Bouwkundig; Cibes Product Sheet_GB: http://www.cibeslift.com/fileadmin/user_upload/Brochures_cibes/Cibes_A5000/Cibes.A5000.LOW.GB.pdf; Cibes Product Sheet_SE: http://www.cibeslift.com/fileadmin/user_upload/Brochures_cibes/Cibes_A5000/Cibes.A5000_HIGH.SE.pdf; Cibes Website: http://www.cibeslift.com/; Mark: 1
Materials and Finishes - cibes_component_material_additional: cibes_RAL_9016_Traffic White; cibes_component_material_glass: cibes_glass; cibes_component_material_glass_side: cibes_glass_black; cibes_component_material_main: cibes_RAL_9016_Traffic White; cibes_component_material_panel_steel: cibes_steel_panel_RAL9016; cibes_floor_material: cibes_floor_rubber
Phasing - Phase Created: 2. nieuwbouw

# IfcBuildingElementProxy: DAT_mozaiek:DAT_mozaiek, DAT_mozaiek:DAT_mozaiek:6325790
In: 00 Begane grond
Type - Material: <Unnamed>
Type - Other - Category: Generic Models; Family Name: DAT_mozaiek
Type - Constraints - Default Elevation: 0 mm
Type - Identity Data - Description: Mozaiek paneel Verdiept in metselwerk; Type Comments: Mozaiek paneel Verdiept in metselwerk; Type Name: DAT_mozaiek; Workset: Family : Generic Models : DAT_mozaiek
Type - Pset_ProductRequirements - Category: Generic Models
Pset_BuildingElementProxyCommon - Reference: DAT_mozaiek; sets with these values: 2
Pset_ProvisionForVoid - Width: 50 mm; Height: 1540 mm; Depth: 1540 mm
Pset_Generic Models - Family and Type: DAT_mozaiek: DAT_mozaiek; Omschrijving: Mozaiek paneel Verdiept in metselwerk; Type Comments: Mozaiek paneel Verdiept in metselwerk; Level: 0
Pset_DAT_KMS - Description: Mozaiek paneel Verdiept in metselwerk
Other - Family: DAT_mozaiek; Family and Type: DAT_mozaiek: DAT_mozaiek; Type: DAT_mozaiek; Type Id: 6325708
Constraints - Elevation from Level: 0 mm; Level: 0; Moves With Nearby Elements: no; Offset from Host: 0 mm; Host: Level : 0
Dimensions - Area: 1.53185 m2; Hoogte vanaf P: 1048 mm; Volume: 0.070455 m3
Identity Data - Workset: Bouwkundig
Phasing - Phase Created: 2. nieuwbouw

# IfcBuildingElementProxy: Furniture 1:Furniture 1, Furniture 1:Furniture 1:6430242
In: 0.20
Type - Material: ISR_HPL Kleur hout
Type - Other - Category: Generic Models; Family Name: Furniture 1
Type - Identity Data - Workset: Bouwkundig; Type Name: Furniture 1
Type - Pset_ProductRequirements - Category: Generic Models
Pset_BuildingElementProxyCommon - Reference: Furniture 1; sets with these values: 2
Pset_Generic Models - Family and Type: Furniture 1: Furniture 1
Other - Family: Furniture 1; Family and Type: Furniture 1: Furniture 1; Type: Furniture 1; Type Id: 6430240
Constraints - Moves With Nearby Elements: no
Dimensions - Area: 2.43024 m2; Volume: 0.877992 m3
Phasing - Phase Created: 2. nieuwbouw

# IfcBuildingElementProxy: LBK1:LBK, LBK1:LBK:6602786
In: 02 tweede verdieping
Type - Material: <Unnamed>
Type - Other - Category: Mechanical Equipment; Family Name: LBK1
Type - Identity Data - Workset: Bouwkundig; Type Name: LBK
Type - Pset_ProductRequirements - Category: Mechanical Equipment
Pset_BuildingElementProxyCommon - Reference: LBK; sets with these values: 2
Pset_ProvisionForVoid - Width: 3090 mm; Height: 2170 mm; Depth: 2170 mm
Other - Family: LBK1; Family and Type: LBK1: LBK; Type: LBK; Type Id: 6602784
Constraints - Moves With Nearby Elements: no; Elevation from Level: 290 mm
Dimensions - Area: 6.7053 m2; Volume: 14.0811 m3
Identity Data - Mark: 4
Phasing - Phase Created: 2. nieuwbouw

# IfcBuildingElementProxy: LBK:LBK, LBK:LBK:6602851
In: 02 tweede verdieping
Type - Material: <Unnamed>
Type - Other - Category: Mechanical Equipment; Family Name: LBK
Type - Identity Data - Workset: Bouwkundig; Type Name: LBK
Type - Pset_ProductRequirements - Category: Mechanical Equipment
Pset_BuildingElementProxyCommon - Reference: LBK; sets with these values: 2
Pset_ProvisionForVoid - Width: 3090 mm; Height: 2170 mm; Depth: 2170 mm
Other - Type: LBK; Family: LBK; Family and Type: LBK: LBK; Type Id: 6602849
Constraints - Moves With Nearby Elements: no; Elevation from Level: 290 mm
Dimensions - Area: 6.7053 m2; Volume: 14.0811 m3
Identity Data - Mark: 5
Phasing - Phase Created: 2. nieuwbouw

# IfcBuildingElementProxy: Mechanical Equipment 1:Mechanical Equipment 1, Mechanical Equipment 1:Mechanical Equipment 1:6622999
In: 02 tweede verdieping
Type - Material: <Unnamed>
Type - Other - Category: Mechanical Equipment; Family Name: Mechanical Equipment 1
Type - Identity Data - Workset: Bouwkundig; Type Name: Mechanical Equipment 1
Type - Pset_ProductRequirements - Category: Mechanical Equipment
Pset_BuildingElementProxyCommon - Reference: Mechanical Equipment 1; sets with these values: 2
Other - Family: Mechanical Equipment 1; Family and Type: Mechanical Equipment 1: Mechanical Equipment 1; Type: Mechanical Equipment 1; Type Id: 6622997
Constraints - Moves With Nearby Elements: no
Dimensions - Area: 23.2304 m2; Volume: 11.6152 m3
Identity Data - Mark: 6
Phasing - Phase Created: 2. nieuwbouw

# IfcBuildingElementProxy: Mechanical Equipment 2:Mechanical Equipment 1, Mechanical Equipment 2:Mechanical Equipment 1:6623226
In: 02 tweede verdieping
Type - Material: <Unnamed>
Type - Other - Category: Mechanical Equipment; Family Name: Mechanical Equipment 2
Type - Identity Data - Workset: Bouwkundig; Type Name: Mechanical Equipment 1
Type - Pset_ProductRequirements - Category: Mechanical Equipment
Pset_BuildingElementProxyCommon - Reference: Mechanical Equipment 1; sets with these values: 2
Other - Type: Mechanical Equipment 1; Family: Mechanical Equipment 2; Family and Type: Mechanical Equipment 2: Mechanical Equipment 1; Type Id: 6623224
Constraints - Moves With Nearby Elements: no
Dimensions - Area: 23.1684 m2; Volume: 11.5842 m3
Identity Data - Mark: 7
Phasing - Phase Created: 2. nieuwbouw

# IfcBuildingElementProxy: Mechanical Equipment 3:Mechanical Equipment 1, Mechanical Equipment 3:Mechanical Equipment 1:6623631
In: 02 tweede verdieping
Type - Material: <Unnamed>
Type - Other - Category: Mechanical Equipment; Family Name: Mechanical Equipment 3
Type - Identity Data - Workset: Bouwkundig; Type Name: Mechanical Equipment 1
Type - Pset_ProductRequirements - Category: Mechanical Equipment
Pset_BuildingElementProxyCommon - Reference: Mechanical Equipment 1; sets with these values: 2
Other - Type: Mechanical Equipment 1; Family: Mechanical Equipment 3; Family and Type: Mechanical Equipment 3: Mechanical Equipment 1; Type Id: 6623629
Constraints - Moves With Nearby Elements: no
Dimensions - Area: 25.3526 m2; Volume: 12.6763 m3
Identity Data - Mark: 8
Phasing - Phase Created: 2. nieuwbouw

# IfcBuildingElementProxy: Model Text:200mm Arial, Model Text:200mm Arial:6689090
In: 00 Begane grond
Type - Other - Category: Generic Models; Family Name: Model Text
Type - Identity Data - Workset: Model Text Types; Description: 3D text; Type Comments: Letters op pootjes van 20mm; Type Name: 200mm Arial
Type - Text - Bold: no; Italic: no; Text Font: Arial; Text Size: 200 mm
Type - Pset_ProductRequirements - Category: Generic Models
Pset_BuildingElementProxyCommon - Reference: 200mm Arial; sets with these values: 2
Pset_ProvisionForVoid - Shape: Undefined; Width: 20 mm; Height: 25.1141 mm; Depth: 20 mm
Pset_Generic Models - Family and Type: Model Text: 200mm Arial; Omschrijving: 3D text; Type Comments: Letters op pootjes van 20mm
Pset_DAT_KMS - Description: 3D text
Other - Family: Model Text; Family and Type: Model Text: 200mm Arial; Type: 200mm Arial; Type Id: 6595751
Constraints - Work Plane: <not associated>
Dimensions - Depth: 20 mm
Graphics - Horizontal Align: Left; Text: Kindcentrum
Identity Data - Workset: Bouwkundig; Subcategory: Generic Models
Phasing - Phase Created: 2. nieuwbouw

# IfcBuildingElementProxy: Model Text:400mm Arial, Model Text:400mm Arial:6595646
In: 00 Begane grond
Type - Other - Category: Generic Models; Family Name: Model Text
Type - Identity Data - Description: Blank RVS geborsteld op afstandhouders 20mm; Type Name: 400mm Arial; Workset: Model Text Types
Type - Text - Bold: no; Italic: no; Text Font: Arial; Text Size: 400 mm
Type - Pset_ProductRequirements - Category: Generic Models
Pset_BuildingElementProxyCommon - Reference: 400mm Arial; sets with these values: 2
Pset_ProvisionForVoid - Shape: Undefined; Width: 20 mm; Height: 50.2282 mm; Depth: 20 mm
Pset_Generic Models - Family and Type: Model Text: 400mm Arial; Omschrijving: Blank RVS geborsteld op afstandhouders 20mm
Pset_DAT_KMS - Description: Blank RVS geborsteld op afstandhouders 20mm
Other - Family: Model Text; Family and Type: Model Text: 400mm Arial; Type: 400mm Arial; Type Id: 4372635
Constraints - Work Plane: Basic Wall : 21_DAT_metselwerk_100
Dimensions - Depth: 20 mm
Graphics - Horizontal Align: Left; Text: De Nienekes
Identity Data - Workset: Bouwkundig; Subcategory: Generic Models
Phasing - Phase Created: 2. nieuwbouw

# IfcBuildingElementProxy: NLRS_24_GM_LB_betontrap bomen 20 treden_gen_ASN:betontrap met bomen gen b 1200, NLRS_24_GM_LB_betontrap bomen 20 treden_gen_ASN:betontrap met bomen gen b 1200:4789480
In: 0.14
Type - Material: f2_beton prefab
Type - Other - Category: Generic Models; Family Name: NLRS_24_GM_LB_betontrap bomen 20 treden_gen_ASN
Type - Constraints - Default Elevation: 0 mm
Type - Construction - trede_01: NLRS_24_GM_LB_traptrede bg_gen_ISR : traptrede bg_gen; aantal_treden: 20
Type - Dimensions - aantrede: 200 mm; bordes_dikte: 165 mm; meegestort_bordes_lengte: 1000 mm; NLRS_C_breedte: 1230 mm; NLRS_C_hoogte: 3650 mm; optrede: 182.5 mm; plaat: 100 mm
Type - General - NLRS_C_content_creator: Arkance Systems; NLRS_C_content_datum_gewijzigd: 2022.05.27; NLRS_C_content_provider: Arkance Systems; NLRS_C_content_versie: 2.1; NLRS_C_revit_versie: 2021
Type - Graphics - meegestort_bordes: no
Type - Identity Data - Workset: Family : Generic Models : NLRS_24_GM_LB_betontrap bomen 20 treden_gen_ASN; Assembly Code: 24.11; Assembly Description: trappen en hellingen; trappen, rechte steektrappen; Description: Trap met bomen 20 tredenOptrede 183mmAantrede 200mm; Manufacturer: generiek; Type Comments: Trap met bomen 20 tredenOptrede 183mmAantrede 200mm; Type Name: betontrap met bomen gen b 1200
Type - Pset_ManufacturerTypeInformation - Manufacturer: generiek
Type - Pset_ProductRequirements - Category: Generic Models
Classification: 24.11 Uniformat (Uniformat)
Pset_BuildingElementProxyCommon - Reference: betontrap met bomen gen b 1200; sets with these values: 2
Pset_Generic Models - Family and Type: NLRS_24_GM_LB_betontrap bomen 20 treden_gen_ASN: betontrap met bomen gen b 1200; NL-sfb-Codering: 24.11; Omschrijving: Trap met bomen 20 tredenOptrede 183mmAantrede 200mm; IfcExportAs: IfcStairs; Type Comments: Trap met bomen 20 tredenOptrede 183mmAantrede 200mm; Level: 0
Pset_DAT_KMS - Assembly Code: 24.11; Assembly Description: trappen en hellingen; trappen, rechte steektrappen; Description: Trap met bomen 20 tredenOptrede 183mmAantrede 200mm
Other - Family: NLRS_24_GM_LB_betontrap bomen 20 treden_gen_ASN; Family and Type: NLRS_24_GM_LB_betontrap bomen 20 treden_gen_ASN: betontrap met bomen gen b 1200; Type: betontrap met bomen gen b 1200; Type Id: 4760974
Constraints - Elevation from Level: 0 mm; Level: 0; Moves With Nearby Elements: no; Offset from Host: 0 mm; Host: Level : 0
Dimensions - Area: 14.9676 m2; Volume: 1.10694 m3
Identity Data - Workset: Bouwkundig
Materials and Finishes - NLRS_C_materiaal: f2_beton prefab
Phasing - Phase Created: 2. nieuwbouw
Structural - Rebar Cover: Rebar Cover 1 <25 mm>

# IfcBuildingElementProxy: NLRS_24_GM_LB_betontrap bomen 20 treden_gen_ASN:betontrap met bomen gen b 1500, NLRS_24_GM_LB_betontrap bomen 20 treden_gen_ASN:betontrap met bomen gen b 1500:4789362
In: 0.40
Type - Material: f2_beton prefab
Type - Other - Category: Generic Models; Family Name: NLRS_24_GM_LB_betontrap bomen 20 treden_gen_ASN
Type - Constraints - Default Elevation: 0 mm
Type - Construction - aantal_treden: 20; trede_01: NLRS_24_GM_LB_traptrede bg_gen_ISR : traptrede bg_gen
Type - Dimensions - aantrede: 200 mm; bordes_dikte: 165 mm; meegestort_bordes_lengte: 1000 mm; NLRS_C_breedte: 1480 mm; NLRS_C_hoogte: 3650 mm; optrede: 182.5 mm; plaat: 100 mm
Type - General - NLRS_C_content_creator: Arkance Systems; NLRS_C_content_datum_gewijzigd: 2022.05.27; NLRS_C_content_provider: Arkance Systems; NLRS_C_content_versie: 2.1; NLRS_C_revit_versie: 2021
Type - Graphics - meegestort_bordes: no
Type - Identity Data - Assembly Code: 24.11; Assembly Description: trappen en hellingen; trappen, rechte steektrappen; Description: Trap met bomen 20 tredenOptrede 183mmAantrede 200mm; Manufacturer: generiek; Type Comments: Trap met bomen 20 tredenOptrede 183mmAantrede 200mm; Type Name: betontrap met bomen gen b 1500; Workset: Family : Generic Models : NLRS_24_GM_LB_betontrap bomen 20 treden_gen_ASN
Type - Pset_ManufacturerTypeInformation - Manufacturer: generiek
Type - Pset_ProductRequirements - Category: Generic Models
Classification: 24.11 Uniformat (Uniformat)
Pset_BuildingElementProxyCommon - Reference: betontrap met bomen gen b 1500; sets with these values: 2
Pset_Generic Models - Family and Type: NLRS_24_GM_LB_betontrap bomen 20 treden_gen_ASN: betontrap met bomen gen b 1500; NL-sfb-Codering: 24.11; Omschrijving: Trap met bomen 20 tredenOptrede 183mmAantrede 200mm; IfcExportAs: IfcStairs; Type Comments: Trap met bomen 20 tredenOptrede 183mmAantrede 200mm; Level: 0
Pset_DAT_KMS - Assembly Code: 24.11; Assembly Description: trappen en hellingen; trappen, rechte steektrappen; Description: Trap met bomen 20 tredenOptrede 183mmAantrede 200mm
Other - Family: NLRS_24_GM_LB_betontrap bomen 20 treden_gen_ASN; Family and Type: NLRS_24_GM_LB_betontrap bomen 20 treden_gen_ASN: betontrap met bomen gen b 1500; Type: betontrap met bomen gen b 1500; Type Id: 4964773
Constraints - Elevation from Level: 0 mm; Level: 0; Moves With Nearby Elements: no; Offset from Host: 0 mm; Host: Level : 0
Dimensions - Area: 17.5816 m2; Volume: 1.3161 m3
Identity Data - Workset: Bouwkundig
Materials and Finishes - NLRS_C_materiaal: f2_beton prefab
Phasing - Phase Created: 2. nieuwbouw
Structural - Rebar Cover: Rebar Cover 1 <25 mm>

# IfcBuildingElementProxy: NLRS_24_GM_LB_betontrap zonder bomen 04 treden_gen_ASN:betontrap zonder bomen gen b 1100, NLRS_24_GM_LB_betontrap zonder bomen 04 treden_gen_ASN:betontrap zonder bomen gen b 1100:5034214
In: 1.12
Type - Material: ISR_Beton_prefab, f2_beton prefab
Type - Other - Category: Generic Models; Family Name: NLRS_24_GM_LB_betontrap zonder bomen 04 treden_gen_ASN
Type - Constraints - Default Elevation: 0 mm
Type - Construction - aantal_treden: 4; trede_01: NLRS_24_GM_LB_traptrede bg_gen_ISR : traptrede bg_gen
Type - Dimensions - aantrede: 250 mm; bordes_dikte: 165 mm; meegestort_bordes_lengte: 1000 mm; NLRS_C_breedte: 1800 mm; NLRS_C_hoogte: 730 mm; optrede: 182.5 mm; plaat: 100 mm
Type - General - NLRS_C_content_creator: Arkance Systems; NLRS_C_content_datum_gewijzigd: 2022.05.27; NLRS_C_content_provider: Arkance Systems; NLRS_C_content_versie: 2.1; NLRS_C_revit_versie: 2021
Type - Graphics - meegestort_bordes: no
Type - Identity Data - Assembly Code: 24.11; Assembly Description: trappen en hellingen; trappen, rechte steektrappen; Description: trap zonder bomen 04 treden; Manufacturer: generiek; Type Comments: trap:optrede 183mmaantrede 250mm; Type Name: betontrap zonder bomen gen b 1100; Workset: Family : Generic Models : NLRS_24_GM_LB_betontrap zonder bomen 04 treden_gen_ASN
Type - Pset_ManufacturerTypeInformation - Manufacturer: generiek
Type - Pset_ProductRequirements - Category: Generic Models
Classification: 24.11 Uniformat (Uniformat)
Pset_BuildingElementProxyCommon - Reference: betontrap zonder bomen gen b 1100; sets with these values: 2
Pset_Generic Models - Family and Type: NLRS_24_GM_LB_betontrap zonder bomen 04 treden_gen_ASN: betontrap zonder bomen gen b 1100; NL-sfb-Codering: 24.11; Omschrijving: trap zonder bomen 04 treden; IfcExportAs: IfcStairs; Type Comments: trap:optrede 183mmaantrede 250mm; Level: 1
Pset_DAT_KMS - Assembly Code: 24.11; Assembly Description: trappen en hellingen; trappen, rechte steektrappen; Description: trap zonder bomen 04 treden
Other - Family: NLRS_24_GM_LB_betontrap zonder bomen 04 treden_gen_ASN; Family and Type: NLRS_24_GM_LB_betontrap zonder bomen 04 treden_gen_ASN: betontrap zonder bomen gen b 1100; Type: betontrap zonder bomen gen b 1100; Type Id: 5027276
Constraints - Moves With Nearby Elements: no; Level: 1; Elevation from Level: -730 mm; Host: Level : 1; Offset from Host: -730 mm
Dimensions - Area: 4.287 m2; Volume: 0.359563 m3
Identity Data - Workset: Bouwkundig
Materials and Finishes - NLRS_C_materiaal: f2_beton prefab
Phasing - Phase Created: 2. nieuwbouw
Structural - Rebar Cover: Rebar Cover 1 <25 mm>

# IfcBuildingElementProxy: NLRS_31_GM_WPB_vensterbank natuursteen -SH_gen_ASN:200x18 (104)
Type - PredefinedType: USERDEFINED; Material: e1_natuursteen
Type - Other - Category: Generic Models; Family Name: NLRS_31_GM_WPB_vensterbank natuursteen -SH_gen_ASN
Type - Constraints - Default Elevation: 1219.2 mm
Type - Dimensions - breedte: 200 mm; hoogte: 18 mm
Type - General - NLRS_C_content_creator: Arkance Systems; NLRS_C_content_datum_gewijzigd: 2022.05.27; NLRS_C_content_provider: Arkance Systems; NLRS_C_content_versie: 2.1; NLRS_C_revit_versie: 2021
Type - Identity Data - Assembly Code: 31.20; Assembly Description: buitenwandopeningen; gevuld met ramen, algemeen (verzamelniveau); Description: vensterbank natuursteen; Manufacturer: generiek; Type Name: 200x18; Workset: Family : Generic Models : NLRS_31_GM_WPB_vensterbank natuursteen -SH_gen_ASN
Type - Materials and Finishes - materiaal: e1_natuursteen
Type - Pset_ManufacturerTypeInformation - Manufacturer: generiek
Type - Pset_ProductRequirements - Category: Generic Models
Classification: 31.20 Uniformat (Uniformat)
Pset_BuildingElementProxyCommon - Reference: 200x18; sets with these values: 2
Pset_Generic Models - Family and Type: NLRS_31_GM_WPB_vensterbank natuursteen -SH_gen_ASN: 200x18; NL-sfb-Codering: 31.20; Omschrijving: vensterbank natuursteen; IfcExportAs: IfcBuildingElementProxy
Pset_DAT_KMS - Assembly Code: 31.20; Assembly Description: buitenwandopeningen; gevuld met ramen, algemeen (verzamelniveau); Description: vensterbank natuursteen
Other - berekende_overstek_a: 0 mm; berekende_overstek_b: 0 mm; berekende_hoek_a: 0 deg; berekende_verlenging_a: 2000 mm; berekende_verlenging_b: 2000 mm; Family: NLRS_31_GM_WPB_vensterbank natuursteen -SH_gen_ASN; Family and Type: NLRS_31_GM_WPB_vensterbank natuursteen -SH_gen_ASN: 200x18; Type: 200x18; Type Id: 6051154
Dimensions - NLRS_C_breedte: 200 mm; NLRS_C_hoogte: 18 mm; verlenging_a: 0 mm; verlenging_b: 0 mm
Graphics - hoek_b: 0 deg; hoek_a: 0 deg
Identity Data - Workset: Bouwkundig
Phasing - Phase Created: 2. nieuwbouw
Name (NLRS_31_GM_WPB_vensterbank natuursteen -SH_gen_ASN:200x18:...) | In | Width (mm) | Height (mm) = Depth (mm) | Pset_Generic Models, Level = Constraints, Level = Schedule Level | Elevation from Level (mm) | lengte (mm) = element_lengte (mm) = NLRS_C_lengte (mm) | Offset from Host (mm) | Work Plane | Area (m2) | Volume (m3) | Group
6052729 | 0.35 | 2040 | 200 | 0 | 730 | 2040 | 730 | Level : 0 | 0.44832 | 0.007344 | Model Group:K_Raamwerk_17:5540557
6052733 | 0.35 | 2040 | 200 | 0 | 730 | 2040 | 730 | Level : 0 | 0.44832 | 0.007344 | Model Group:K_Raamwerk_17:5542283
6052735 | 0.36 | 2040 | 200 | 0 | 730 | 2040 | 730 | Level : 0 | 0.44832 | 0.007344 | Model Group:K_Raamwerk_17:5542309
6052737 | 0.36 | 2040 | 200 | 0 | 730 | 2040 | 730 | Level : 0 | 0.44832 | 0.007344 | Model Group:K_Raamwerk_17:5542335
6052739 | 0.37 | 2040 | 200 | 0 | 730 | 2040 | 730 | Level : 0 | 0.44832 | 0.007344 | Model Group:K_Raamwerk_17:5542361
6052741 | 0.37 | 2040 | 200 | 0 | 730 | 2040 | 730 | Level : 0 | 0.44832 | 0.007344 | Model Group:K_Raamwerk_17:5542387
6052745 | 0.28 | 2040 | 200 | 0 | 730 | 2040 | 730 | Level : 0 | 0.44832 | 0.007344 | Model Group:K_Raamwerk_17:5544971
6052747 | 0.28 | 2040 | 200 | 0 | 730 | 2040 | 730 | Level : 0 | 0.44832 | 0.007344 | Model Group:K_Raamwerk_17:5545006
6053996 | 0.36 | 889.903 | 200 |  | 0 | 889.903 | 730 | Floor : 23_Dekvloer 70mm | 0.197599 | 0.00320365 | Model Group:K_Raamwerk_16:5544033
6054141 | 0.35 | 889.903 | 200 | 0 | 730 | 889.903 | 730 | Level : 0 | 0.197599 | 0.00320365 | Model Group:K_Raamwerk_16:5542459
6054143 | 0.37 | 889.903 | 200 | 0 | 730 | 889.903 | 730 | Level : 0 | 0.197599 | 0.00320365 | Model Group:K_Raamwerk_16:5544055
6054145 | 0.38 | 889.903 | 200 | 0 | 730 | 889.903 | 730 | Level : 0 | 0.197599 | 0.00320365 | Model Group:K_Raamwerk_16:5544106
6054147 | 0.38 | 889.903 | 200 | 0 | 730 | 889.903 | 730 | Level : 0 | 0.197599 | 0.00320365 | Model Group:K_Raamwerk_16:5544132
6054149 | 0.15a |  |  | 0 | 730 | 889.903 | 730 | Level : 0 | 0.0297549 | 0.000118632 | Model Group:K_Raamwerk_16:5544804
6054151 | 0.15a |  |  | 0 | 730 | 889.903 | 730 | Level : 0 | 0.0297549 | 0.000118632 | Model Group:K_Raamwerk_16:5544822
6054153 | 0.28 | 889.903 | 200 | 0 | 730 | 889.903 | 730 | Level : 0 | 0.197599 | 0.00320365 | Model Group:K_Raamwerk_16:5545033
6054155 | 0.29 | 889.903 | 200 | 0 | 730 | 889.903 | 730 | Level : 0 | 0.197599 | 0.00320365 | Model Group:K_Raamwerk_16:5545106
6054157 | 0.27 | 889.903 | 200 | 0 | 730 | 889.903 | 730 | Level : 0 | 0.197599 | 0.00320365 | Model Group:K_Raamwerk_16:5545129
6054159 | 0.15a |  |  | 0 | 730 | 889.903 | 730 | Level : 0 | 0.0297549 | 0.000118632 | Model Group:K_Raamwerk_16:5856137
6054161 | 0.15a |  |  | 0 | 730 | 889.903 | 730 | Level : 0 | 0.0297549 | 0.000118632 | Model Group:K_Raamwerk_16:5856140
6054222 | 0.15a |  |  | 0 | 730 | 2040 | 730 | Level : 0 | 0.051956 | 0.00014562 | Model Group:K_Raamwerk_17:5544238
6054342 | 0.15a |  |  | 0 | 730 | 2040 | 730 | Level : 0 | 0.051956 | 0.00014562 | Model Group:K_Raamwerk_17:5856134
6054392 | 0.15a |  |  | 0 | 730 | 2040 | 730 | Level : 0 | 0.051956 | 0.00014562 | Model Group:K_Raamwerk_17:5544293
6054687 | 0.23 | 2310 | 200 | 0 | 730 | 2310 | 730 | Level : 0 | 0.50718 | 0.008316 | Model Group:K_Raamwerk_07:5537720
6054872 | 0.23 | 2310 | 200 | 0 | 730 | 2310 | 730 | Level : 0 | 0.50718 | 0.008316 | Model Group:K_Raamwerk_07:5537510
6056082 | 0.23 | 800 | 200 | 0 | 730 | 800 | 730 | Level : 0 | 0.178 | 0.00288 | Model Group:K_Raamwerk_06:5537322
6056178 | 0.23 | 800 | 200 | 0 | 730 | 800 | 730 | Level : 0 | 0.178 | 0.00288 | Model Group:K_Raamwerk_06:5537289
6056180 | 0.23 | 800 | 200 | 0 | 730 | 800 | 730 | Level : 0 | 0.178 | 0.00288 | Model Group:K_Raamwerk_06:5537301
6056182 | 0.23 | 800 | 200 | 0 | 730 | 800 | 730 | Level : 0 | 0.178 | 0.00288 | Model Group:K_Raamwerk_06:5537313
6056184 | 0.23 | 800 | 200 | 0 | 730 | 800 | 730 | Level : 0 | 0.178 | 0.00288 | Model Group:K_Raamwerk_06:5537327
6056186 | 00 Begane grond | 800 | 200 | 0 | 730 | 800 | 730 | Level : 0 | 0.178 | 0.00288 | Model Group:K_Raamwerk_06:5537331
6056404 | 0.23 | 790 | 200 | 0 | 730 | 790 | 730 | Level : 0 | 0.17582 | 0.002844 | Model Group:K_Raamwerk_06a:5537494
6056645 | 0.20 | 2130 | 200 | 0 | 730 | 2130 | 730 | Floor : 23_Dekvloer 70mm | 0.46794 | 0.007668
6056826 | 0.20 | 200 | 789.999 |  | 0 | 789.999 | 1355 | Floor : 23_Dekvloer 70mm | 0.17582 | 0.002844
6056990 | 0.20 | 200 | 789.999 |  | 0 | 789.999 | 1355 | <not associated> | 0.17582 | 0.002844
6057000 | 00 Begane grond | 200 | 789.999 |  | 0 | 789.999 | 1355 | <not associated> | 0.17582 | 0.002844
6057010 | 00 Begane grond | 200 | 789.999 |  | 0 | 789.999 | 1355 | <not associated> | 0.17582 | 0.002844
6057018 | 01 eerste verdieping | 200 | 789.999 |  | 0 | 789.999 | 1355 | <not associated> | 0.17582 | 0.002844
6057060 | 01 eerste verdieping | 200 | 789.999 | 1 | 830 | 789.999 | 830 | Level : 1 | 0.17582 | 0.002844
6057181 | 01 eerste verdieping | 200 | 789.999 | 1 | 830 | 789.999 | 830 | Level : 1 | 0.17582 | 0.002844 | Model Group:K_Raamwerk_29:5537787
6057253 | 1.23 | 200 | 789.999 | 1 | 830 | 789.999 | 830 | Level : 1 | 0.17582 | 0.002844 | Model Group:K_Raamwerk_29:5537783
6057255 | 1.21 | 200 | 789.999 | 1 | 830 | 789.999 | 830 | Level : 1 | 0.17582 | 0.002844 | Model Group:K_Raamwerk_29:5537791
6057257 | 1.21 | 200 | 789.999 | 1 | 830 | 789.999 | 830 | Level : 1 | 0.17582 | 0.002844 | Model Group:K_Raamwerk_29:5537795
6057259 | 1.22 | 200 | 789.999 | 1 | 830 | 789.999 | 830 | Level : 1 | 0.17582 | 0.002844 | Model Group:K_Raamwerk_29:5537799
6057261 | 1.22 | 200 | 789.999 | 1 | 830 | 789.999 | 830 | Level : 1 | 0.17582 | 0.002844 | Model Group:K_Raamwerk_29:5537803
6057263 | 1.23 | 200 | 789.999 | 1 | 830 | 789.999 | 830 | Level : 1 | 0.17582 | 0.002844 | Model Group:K_Raamwerk_29:5537807
6057265 | 1.24 | 200 | 789.999 | 1 | 830 | 789.999 | 830 | Level : 1 | 0.17582 | 0.002844 | Model Group:K_Raamwerk_29:5537811
6057267 | 1.11 | 200 | 789.999 | 1 | 830 | 789.999 | 830 | Level : 1 | 0.17582 | 0.002844 | Model Group:K_Raamwerk_29:5537834
6057269 | 1.11 | 200 | 789.999 | 1 | 830 | 789.999 | 830 | Level : 1 | 0.17582 | 0.002844 | Model Group:K_Raamwerk_29:5537858
6057271 | 1.11 | 200 | 789.999 | 1 | 830 | 789.999 | 830 | Level : 1 | 0.17582 | 0.002844 | Model Group:K_Raamwerk_29:5537866
6057273 | 1.11 | 200 | 789.999 | 1 | 830 | 789.999 | 830 | Level : 1 | 0.17582 | 0.002844 | Model Group:K_Raamwerk_29:5537890
6057275 | 1.11 | 200 | 789.999 | 1 | 830 | 789.999 | 830 | Level : 1 | 0.17582 | 0.002844 | Model Group:K_Raamwerk_29:5537898
6057277 | 1.11 | 200 | 789.999 | 1 | 830 | 789.999 | 830 | Level : 1 | 0.17582 | 0.002844 | Model Group:K_Raamwerk_29:5537922
6057279 | 1.11 | 200 | 789.999 | 1 | 830 | 789.999 | 830 | Level : 1 | 0.17582 | 0.002844 | Model Group:K_Raamwerk_29:5537930
6057281 | 01 eerste verdieping | 200 | 789.999 | 1 | 830 | 789.999 | 830 | Level : 1 | 0.17582 | 0.002844 | Model Group:K_Raamwerk_29:5537954
6057322 | 1.21 | 200 | 2250 | 1 | 830 | 2250 | 830 | Level : 1 | 0.4941 | 0.0081 | Model Group:K_Raamwerk_22:5537759
6057433 | 1.21 | 200 | 2250 | 1 | 830 | 2250 | 830 | Level : 1 | 0.4941 | 0.0081 | Model Group:K_Raamwerk_22:5537763
6057435 | 1.22 | 200 | 2250 | 1 | 830 | 2250 | 830 | Level : 1 | 0.4941 | 0.0081 | Model Group:K_Raamwerk_22:5537767
6057437 | 1.22 | 200 | 2250 | 1 | 830 | 2250 | 830 | Level : 1 | 0.4941 | 0.0081 | Model Group:K_Raamwerk_22:5537771
6057439 | 1.23 | 200 | 2250 | 1 | 830 | 2250 | 830 | Level : 1 | 0.4941 | 0.0081 | Model Group:K_Raamwerk_22:5537775
6057441 | 1.23 | 200 | 2250 | 1 | 830 | 2250 | 830 | Level : 1 | 0.4941 | 0.0081 | Model Group:K_Raamwerk_22:5537779
6057443 | 1.11 | 200 | 2250 | 1 | 830 | 2250 | 830 | Level : 1 | 0.4941 | 0.0081 | Model Group:K_Raamwerk_22:5537838
6057445 | 1.11 | 200 | 2250 | 1 | 830 | 2250 | 830 | Level : 1 | 0.4941 | 0.0081 | Model Group:K_Raamwerk_22:5537846
6057447 | 1.11 | 200 | 2250 | 1 | 830 | 2250 | 830 | Level : 1 | 0.4941 | 0.0081 | Model Group:K_Raamwerk_22:5537870
6057449 | 1.11 | 200 | 2250 | 1 | 830 | 2250 | 830 | Level : 1 | 0.4941 | 0.0081 | Model Group:K_Raamwerk_22:5537878
6057451 | 1.11 | 200 | 2250 | 1 | 830 | 2250 | 830 | Level : 1 | 0.4941 | 0.0081 | Model Group:K_Raamwerk_22:5537902
6057453 | 1.11 | 200 | 2250 | 1 | 830 | 2250 | 830 | Level : 1 | 0.4941 | 0.0081 | Model Group:K_Raamwerk_22:5537910
6057455 | 01 eerste verdieping | 200 | 2250 | 1 | 830 | 2250 | 830 | Level : 1 | 0.4941 | 0.0081 | Model Group:K_Raamwerk_22:5537934
6057457 | 01 eerste verdieping | 200 | 2250 | 1 | 830 | 2250 | 830 | Level : 1 | 0.4941 | 0.0081 | Model Group:K_Raamwerk_22:5537942
6057496 | 1.24 | 200 | 2250 | 1 | 830 | 2250 | 830 | Level : 1 | 0.4941 | 0.0081
6057540 | 01 eerste verdieping | 200 | 880 | 1 | 830 | 880 | 830 | Level : 1 | 0.19544 | 0.003168 | Model Group:K_Raamwerk_28:6057727
6059355 | 01 eerste verdieping | 200 | 880 | 1 | 830 | 880 | 830 | Level : 1 | 0.19544 | 0.003168 | Model Group:K_Raamwerk_28:6058262
6059357 | 01 eerste verdieping | 200 | 880 | 1 | 830 | 880 | 830 | Level : 1 | 0.19544 | 0.003168 | Model Group:K_Raamwerk_28:6058281
6059359 | 01 eerste verdieping | 200 | 880 | 1 | 830 | 880 | 830 | Level : 1 | 0.19544 | 0.003168 | Model Group:K_Raamwerk_28:6058300
6059361 | 01 eerste verdieping | 200 | 880 | 1 | 830 | 880 | 830 | Level : 1 | 0.19544 | 0.003168 | Model Group:K_Raamwerk_28:6058319
6059363 | 01 eerste verdieping | 200 | 880 | 1 | 830 | 880 | 830 | Level : 1 | 0.19544 | 0.003168 | Model Group:K_Raamwerk_28:6058338
6059365 | 01 eerste verdieping | 200 | 880 | 1 | 830 | 880 | 830 | Level : 1 | 0.19544 | 0.003168 | Model Group:K_Raamwerk_28:6058357
6059367 | 01 eerste verdieping | 200 | 880 | 1 | 830 | 880 | 830 | Level : 1 | 0.19544 | 0.003168 | Model Group:K_Raamwerk_28:6058376
6059369 | 01 eerste verdieping | 200 | 880 | 1 | 830 | 880 | 830 | Level : 1 | 0.19544 | 0.003168 | Model Group:K_Raamwerk_28:6058395
6059371 | 01 eerste verdieping | 200 | 880 | 1 | 830 | 880 | 830 | Level : 1 | 0.19544 | 0.003168 | Model Group:K_Raamwerk_28:6058414
6059373 | 01 eerste verdieping | 200 | 880 | 1 | 830 | 880 | 830 | Level : 1 | 0.19544 | 0.003168 | Model Group:K_Raamwerk_28:6058433
6059375 | 01 eerste verdieping | 200 | 880 | 1 | 830 | 880 | 830 | Level : 1 | 0.19544 | 0.003168 | Model Group:K_Raamwerk_28:6058452
6059377 | 01 eerste verdieping | 200 | 880 | 1 | 830 | 880 | 830 | Level : 1 | 0.19544 | 0.003168 | Model Group:K_Raamwerk_28:6058471
6059379 | 01 eerste verdieping | 200 | 880 | 1 | 830 | 880 | 830 | Level : 1 | 0.19544 | 0.003168 | Model Group:K_Raamwerk_28:6058490
6059381 | 01 eerste verdieping | 200 | 880 | 1 | 830 | 880 | 830 | Level : 1 | 0.19544 | 0.003168 | Model Group:K_Raamwerk_28:6058509
6059383 | 01 eerste verdieping | 200 | 880 | 1 | 830 | 880 | 830 | Level : 1 | 0.19544 | 0.003168 | Model Group:K_Raamwerk_28:6058528
6059385 | 01 eerste verdieping | 200 | 880 | 1 | 830 | 880 | 830 | Level : 1 | 0.19544 | 0.003168 | Model Group:K_Raamwerk_28:6058547
6059422 | 01 eerste verdieping | 200 | 2040 | 1 | 830 | 2040 | 830 | Level : 1 | 0.44832 | 0.007344 | Model Group:K_Raamwerk_24:6058628
6059528 | 01 eerste verdieping | 200 | 2040 | 1 | 830 | 2040 | 830 | Level : 1 | 0.44832 | 0.007344 | Model Group:K_Raamwerk_24:6058988
6059530 | 01 eerste verdieping | 200 | 2040 | 1 | 830 | 2040 | 830 | Level : 1 | 0.44832 | 0.007344 | Model Group:K_Raamwerk_24:6059007
6059532 | 01 eerste verdieping | 200 | 2040 | 1 | 830 | 2040 | 830 | Level : 1 | 0.44832 | 0.007344 | Model Group:K_Raamwerk_24:6059026
6059534 | 01 eerste verdieping | 200 | 2040 | 1 | 830 | 2040 | 830 | Level : 1 | 0.44832 | 0.007344 | Model Group:K_Raamwerk_24:6059045
6059536 | 01 eerste verdieping | 200 | 2040 | 1 | 830 | 2040 | 830 | Level : 1 | 0.44832 | 0.007344 | Model Group:K_Raamwerk_24:6059064
6059538 | 01 eerste verdieping | 200 | 2040 | 1 | 830 | 2040 | 830 | Level : 1 | 0.44832 | 0.007344 | Model Group:K_Raamwerk_24:6059083
6059540 | 01 eerste verdieping | 200 | 2040 | 1 | 830 | 2040 | 830 | Level : 1 | 0.44832 | 0.007344 | Model Group:K_Raamwerk_24:6059102
6059542 | 01 eerste verdieping | 200 | 2040 | 1 | 830 | 2040 | 830 | Level : 1 | 0.44832 | 0.007344 | Model Group:K_Raamwerk_24:6059121
6059544 | 01 eerste verdieping | 200 | 2040 | 1 | 830 | 2040 | 830 | Level : 1 | 0.44832 | 0.007344 | Model Group:K_Raamwerk_24:6059140
6059546 | 01 eerste verdieping | 200 | 2040 | 1 | 830 | 2040 | 830 | Level : 1 | 0.44832 | 0.007344 | Model Group:K_Raamwerk_24:6059159
6059548 | 01 eerste verdieping | 200 | 2040 | 1 | 830 | 2040 | 830 | Level : 1 | 0.44832 | 0.007344 | Model Group:K_Raamwerk_24:6059178
6059550 | 01 eerste verdieping | 200 | 2040 | 1 | 830 | 2040 | 830 | Level : 1 | 0.44832 | 0.007344 | Model Group:K_Raamwerk_24:6059197
6059606 | 01 eerste verdieping | 200 | 1145 | 1 | 830 | 1145 | 830 | Level : 1 | 0.25321 | 0.004122 | Model Group:K_Raamwerk_25:5537969
6059832 | 1.11 | 200 | 789.999 | 1 | 830 | 789.999 | 830 | Level : 1 | 0.17582 | 0.002844 | Model Group:K_Raamwerk_29a:5537822
6059915 | 1.13 | 200 | 792 | 1 | 830 | 792 | 830 | Level : 1 | 0.176256 | 0.0028512 | Model Group:K_Raamwerk_30:5537736
6060202 | 01 eerste verdieping | 200 | 2064 |  | 0 | 2064 | 830 | Floor : 23_Zwevende dekvloer 90mm | 0.453552 | 0.0074304 | Model Group:K_Raamwerk_23:5537755

# IfcBuildingElementProxy: NLRS_31_GM_WPB_vensterbank natuursteen -SH_gen_ASN:545x18 (7)
In: 0.15
Type - Material: e1_natuursteen
Type - Other - Category: Generic Models; Family Name: NLRS_31_GM_WPB_vensterbank natuursteen -SH_gen_ASN
Type - Constraints - Default Elevation: 1219.2 mm
Type - Dimensions - breedte: 545 mm; hoogte: 18 mm
Type - General - NLRS_C_content_creator: Arkance Systems; NLRS_C_content_datum_gewijzigd: 2022.05.27; NLRS_C_content_provider: Arkance Systems; NLRS_C_content_versie: 2.1; NLRS_C_revit_versie: 2021
Type - Identity Data - Workset: Family : Generic Models : NLRS_31_GM_WPB_vensterbank natuursteen -SH_gen_ASN; Assembly Code: 31.20; Assembly Description: buitenwandopeningen; gevuld met ramen, algemeen (verzamelniveau); Description: vensterbank natuursteen; Manufacturer: generiek; Type Name: 545x18
Type - Materials and Finishes - materiaal: e1_natuursteen
Type - Pset_ManufacturerTypeInformation - Manufacturer: generiek
Type - Pset_ProductRequirements - Category: Generic Models
Classification: 31.20 Uniformat (Uniformat)
Pset_BuildingElementProxyCommon - Reference: 545x18; sets with these values: 2
Pset_ProvisionForVoid - Height: 545 mm; Depth: 545 mm
Pset_Generic Models - Family and Type: NLRS_31_GM_WPB_vensterbank natuursteen -SH_gen_ASN: 545x18; NL-sfb-Codering: 31.20; Omschrijving: vensterbank natuursteen; IfcExportAs: IfcBuildingElementProxy
Pset_DAT_KMS - Assembly Code: 31.20; Assembly Description: buitenwandopeningen; gevuld met ramen, algemeen (verzamelniveau); Description: vensterbank natuursteen
Other - berekende_overstek_a: 0 mm; berekende_overstek_b: 0 mm; berekende_hoek_a: 0 deg; Family: NLRS_31_GM_WPB_vensterbank natuursteen -SH_gen_ASN; berekende_verlenging_a: 2000 mm; berekende_verlenging_b: 2000 mm; Family and Type: NLRS_31_GM_WPB_vensterbank natuursteen -SH_gen_ASN: 545x18; Type: 545x18; Type Id: 6053789
Constraints - Elevation from Level: 0 mm; Offset from Host: 730 mm; Work Plane: Floor : 23_Dekvloer 70mm
Dimensions - verlenging_a: 0 mm; verlenging_b: 0 mm; NLRS_C_breedte: 545 mm; NLRS_C_hoogte: 18 mm
Graphics - hoek_b: 0 deg; hoek_a: 0 deg
Identity Data - Workset: Bouwkundig
Phasing - Phase Created: 2. nieuwbouw
Name (NLRS_31_GM_WPB_vensterbank natuursteen -SH_gen_ASN:545x18:...) | Width (mm) = lengte (mm) = element_lengte (mm) = NLRS_C_lengte (mm) | Area (m2) | Volume (m3)
6054247 | 2030 | 1.1527 | 0.0199143
6054471 | 2030 | 1.1527 | 0.0199143
6054479 | 2030 | 1.1527 | 0.0199143
6054487 | 870 | 0.49962 | 0.0085347
6054547 | 870 | 0.49962 | 0.0085347
6054557 | 870 | 0.49962 | 0.0085347
6054565 | 870 | 0.49962 | 0.0085347

# IfcBuildingElementProxy: NLRS_42_GM_WBP_plaat:18x409 (11)
Type - Material: ISR_Multiplex
Type - Other - Category: Generic Models; Family Name: NLRS_42_GM_WBP_plaat
Type - Constraints - Default Elevation: 1219.2 mm
Type - Dimensions - breedte: 409 mm; NLRS_C_dikte: 18 mm
Type - Graphics - plank: yes
Type - Identity Data - Assembly Code: 2C(47); Description: multiplex plaat; Model: LOD300; SmartRevit_Versie: 2018.1; Type Comments: Multiplex 18mm; Type Name: 18x409; Workset: Family : Generic Models : NLRS_42_GM_WBP_plaat
Type - Materials and Finishes - materiaal_plank: ISR_Multiplex
Type - Pset_ProductRequirements - Category: Generic Models
Classification: 2C(47) Uniformat (Uniformat)
Pset_BuildingElementProxyCommon - Reference: 18x409; sets with these values: 2
Pset_Generic Models - Family and Type: NLRS_42_GM_WBP_plaat: 18x409; NL-sfb-Codering: 2C(47); Omschrijving: multiplex plaat; Type Comments: Multiplex 18mm
Pset_DAT_KMS - Assembly Code: 2C(47); Description: multiplex plaat
Other - Family: NLRS_42_GM_WBP_plaat; Family and Type: NLRS_42_GM_WBP_plaat: 18x409; Type: 18x409; Type Id: 5044810
Dimensions - NLRS_C_breedte: 409 mm
Identity Data - Workset: Bouwkundig
Phasing - Phase Created: 2. nieuwbouw
Name (NLRS_42_GM_WBP_plaat:18x409:...) | In | berekende_hoek_a (deg) | berekende_overstek_a (mm) | berekende_overstek_b (mm) | Elevation from Level (mm) | lengte (mm) = NLRS_C_lengte (mm) | Offset from Host (mm) | Work Plane | Area (m2) | element_lengte (mm) | Volume (m3) | hoek_a (deg) | hoek_b (deg)
5050371 | 00 Begane grond | 45 | 0 | 0 | 835 | 7799.96 | 835 | Level : V1 ok. ruwe vloer | 3.25215 | 7799.96 | 0.0559178 | -45 | 0 | Pset_Generic Models - Level: V1 ok. ruwe vloer; Constraints - Level: V1 ok. ruwe vloer; Schedule Level: V1 ok. ruwe vloer
5051320 | 00 Begane grond | 0 | 0 | 0 | 835 | 10914.3 | 835 | Level : V1 ok. ruwe vloer | 4.58196 | 10914.3 | 0.0788453 | 0 | -45 | Pset_Generic Models - Level: V1 ok. ruwe vloer; Constraints - Level: V1 ok. ruwe vloer; Schedule Level: V1 ok. ruwe vloer
5057973 | 01 eerste verdieping | 0 | 0 | 0 | 425 | 3000 | 261 | Basic Roof : 300_27_dakisolatie+dakleer+grind | 1.28836 | 3000 | 0.022086 | 0 | 0 | Pset_Generic Models - Level: 1; Constraints - Level: 1; Schedule Level: 1; Pset_ProvisionForVoid - Width: 3000 mm; Height: 409 mm; Depth: 409 mm
5059259 | 01 eerste verdieping | 0 | 0 | 0 | 425 | 3813.1 | 0 | Basic Wall : 21_DAT_metselwerk_100 | 1.63555 | 3813.1 | 0.028072 | 0 | 0 | Pset_Generic Models - Level: 1; Constraints - Level: 1; Schedule Level: 1; Pset_ProvisionForVoid - Width: 3813.1 mm; Height: 409 mm; Depth: 409 mm
5086360 | 02 tweede verdieping | 0 | 0 | 0 | 0 | 35690 | 125 | <not associated> | 15.1612 | 35690 | 0.261244 | 0 | -45
5086386 | 02 tweede verdieping | 45 | 0 | 410 | 0 | 33600 | 125 | <not associated> | 14.3576 | 34010 | 0.247363 | -45 | 45
5086426 | 02 tweede verdieping | -45 | 410 | 0 | 0 | 35400 | 125 | <not associated> | 15.1262 | 35810 | 0.260615 | 45 | -45
5086466 | 02 tweede verdieping | 45 | 0 | 0 | 0 | 12750 | 125 | <not associated> | 5.28002 | 12750 | 0.0908544 | -45 | -45
5086499 | 02 tweede verdieping | 45 | 0 | 0 | 0 | 44675 | 125 | <not associated> | 18.912 | 44675 | 0.325886 | -45 | -45
5086539 | 02 tweede verdieping | 45 | 0 | 0 | 0 | 7200 | 125 | <not associated> | 2.99597 | 7200 | 0.0515009 | -45 | 0
6256002 | 01 eerste verdieping | 45 | 0 | 0 | 550 | 12450 | 0 | Basic Wall : 21_DAT_Hekwerk 100 | 5.15192 | 12450 | 0.0886458 | -45 | -45 | Pset_Generic Models - Level: 2; Constraints - Level: 2; Schedule Level: 2

# IfcBuildingElementProxy: NLRS_42_GM_WBP_plaat_gebogen:18x430 (2)
In: 01 eerste verdieping
Type - Material: ISR_Multiplex
Type - Other - Category: Generic Models; Family Name: NLRS_42_GM_WBP_plaat_gebogen
Type - Constraints - Default Elevation: 0 mm
Type - Dimensions - NLRS_C_breedte: 409 mm; NLRS_C_dikte: 18 mm
Type - Identity Data - Assembly Code: 2D(41); Description: Multiplex plaat; Type Name: 18x430; Workset: Family : Generic Models : NLRS_42_GM_WBP_plaat_gebogen
Type - Materials and Finishes - NLRS_C_materiaal: ISR_Multiplex
Type - Pset_ProductRequirements - Category: Generic Models
Classification: 2D(41) Uniformat (Uniformat)
Pset_BuildingElementProxyCommon - Reference: 18x430; sets with these values: 2
Pset_Generic Models - Family and Type: NLRS_42_GM_WBP_plaat_gebogen: 18x430; NL-sfb-Codering: 2D(41); Omschrijving: Multiplex plaat; Level: 1
Pset_DAT_KMS - Assembly Code: 2D(41); Description: Multiplex plaat
Other - Family: NLRS_42_GM_WBP_plaat_gebogen; Family and Type: NLRS_42_GM_WBP_plaat_gebogen: 18x430; Type: 18x430; Type Id: 5044814
Constraints - Level: 1; Elevation from Level: 425 mm; Schedule Level: 1
Dimensions - NLRS_C_hoek: 45 deg
Identity Data - Workset: Bouwkundig
Phasing - Phase Created: 2. nieuwbouw
Name (NLRS_42_GM_WBP_plaat_gebogen:18x430:...) | Host | Area (m2) | buitenradius (mm) | NLRS_C_lengte (mm) | NLRS_C_radius (mm) | Volume (m3)
5056692 | Basic Wall : 21_DAT_Hekwerk 100 | 0.601144 | 1975 | 1229.93 | 1566 | 0.0102373
5059099 | Basic Wall : 21_DAT_metselwerk_100 | 0.419689 | 1434 | 805.033 | 1025 | 0.00710908

# IfcBuildingElementProxy: NLRS_42_GM_WPB_dakrand_afdekkap_gen_ISR:afdekkap (4)
Type - Material: STAAL_RAL 7006
Type - Other - Category: Generic Models; Family Name: NLRS_42_GM_WPB_dakrand_afdekkap_gen_ISR
Type - Constraints - Default Elevation: 1219.2 mm
Type - Dimensions - breedte: 140 mm
Type - Graphics - plank: yes
Type - Identity Data - Assembly Code: 2C(47); Description: Aluminium daktrimin RAL 7006; Model: LOD300; SmartRevit_Versie: 2018.1; Type Comments: Aluminium afdekkapRal 7006; Type Name: afdekkap; Workset: Family : Generic Models : NLRS_42_GM_WPB_dakrand_afdekkap_gen_ISR
Type - Materials and Finishes - materiaal_daktrim: STAAL_RAL 7006
Type - Pset_ProductRequirements - Category: Generic Models
Classification: 2C(47) Uniformat (Uniformat)
Pset_BuildingElementProxyCommon - Reference: afdekkap; sets with these values: 2
Pset_Generic Models - Family and Type: NLRS_42_GM_WPB_dakrand_afdekkap_gen_ISR: afdekkap; NL-sfb-Codering: 2C(47); Omschrijving: Aluminium daktrimin RAL 7006; Type Comments: Aluminium afdekkapRal 7006
Pset_DAT_KMS - Assembly Code: 2C(47); Description: Aluminium daktrimin RAL 7006
Other - berekende_hoek_a: 45 deg; berekende_overstek_a: 0 mm; berekende_overstek_b: 0 mm; Family: NLRS_42_GM_WPB_dakrand_afdekkap_gen_ISR; Family and Type: NLRS_42_GM_WPB_dakrand_afdekkap_gen_ISR: afdekkap; Type: afdekkap; Type Id: 6876892
Constraints - Offset from Host: 0 mm
Dimensions - breedte_plank: 105 mm; NLRS_C_breedte: 140 mm
Graphics - hoek_a: -45 deg; hoek_b: -45 deg
Identity Data - Workset: Bouwkundig
Phasing - Phase Created: 2. nieuwbouw
Name (NLRS_42_GM_WPB_dakrand_afdekkap_gen_ISR:afdekkap:...) | In | Elevation from Level (mm) | lengte (mm) = element_lengte (mm) = NLRS_C_lengte (mm) | Work Plane | Area (m2) | Volume (m3)
6875020 | 00 Begane grond | 9700 | 3494 | Basic Wall : 21_DAT_metselwerk_100 | 0.88896 | 0.00178201 | Pset_Generic Models - Level: 0; Constraints - Level: 0; Schedule Level: 0
6877323 | 02 tweede verdieping | 0 | 22384 | <not associated> | 5.89142 | 0.0118184
6877487 | 02 tweede verdieping | 0 | 22384 | <not associated> | 5.89142 | 0.0118184
6877597 | 02 tweede verdieping | 0 | 3494 | <not associated> | 0.88896 | 0.00178201

# IfcBuildingElementProxy: NLRS_42_GM_WPB_dakrand_gen_ISR:dakrand_gen (12)
Type - Material: STAAL_RAL 7006
Type - Other - Category: Generic Models; Family Name: NLRS_42_GM_WPB_dakrand_gen_ISR
Type - Constraints - Default Elevation: 1219.2 mm
Type - Dimensions - breedte: 122 mm
Type - Graphics - plank: yes
Type - Identity Data - Assembly Code: 2C(47); Description: Aluminium daktrimin RAL 7006; Model: LOD300; SmartRevit_Versie: 2018.1; Type Comments: Aluminium daktrim Ral 7006; Type Name: dakrand_gen; Workset: Family : Generic Models : NLRS_42_GM_WPB_dakrand_gen_ISR
Type - Materials and Finishes - materiaal_daktrim: STAAL_RAL 7006
Type - Pset_ProductRequirements - Category: Generic Models
Classification: 2C(47) Uniformat (Uniformat)
Pset_BuildingElementProxyCommon - Reference: dakrand_gen; sets with these values: 2
Pset_Generic Models - Family and Type: NLRS_42_GM_WPB_dakrand_gen_ISR: dakrand_gen; NL-sfb-Codering: 2C(47); Omschrijving: Aluminium daktrimin RAL 7006; Type Comments: Aluminium daktrim Ral 7006
Pset_DAT_KMS - Assembly Code: 2C(47); Description: Aluminium daktrimin RAL 7006
Other - Family: NLRS_42_GM_WPB_dakrand_gen_ISR; Family and Type: NLRS_42_GM_WPB_dakrand_gen_ISR: dakrand_gen; Type: dakrand_gen; Type Id: 5044812
Constraints - Offset from Host: 0 mm
Dimensions - breedte_plank: 105 mm; NLRS_C_breedte: 122 mm
Identity Data - Workset: Bouwkundig
Phasing - Phase Created: 2. nieuwbouw
Name (NLRS_42_GM_WPB_dakrand_gen_ISR:dakrand_gen:...) | In | berekende_hoek_a (deg) | berekende_overstek_a (mm) | berekende_overstek_b (mm) | Elevation from Level (mm) | lengte (mm) = NLRS_C_lengte (mm) | Work Plane | Area (m2) | element_lengte (mm) | Volume (m3) | hoek_a (deg) | hoek_b (deg)
5059795 | 01 eerste verdieping | 45 | 0 | 0 | 443 | 7776.96 | NLRS_42_GM_WBP_plaat : 18x409 | 1.17384 | 7776.96 | 0.00237277 | -45 | 0 | Pset_Generic Models - Level: 1; Constraints - Level: 1; Schedule Level: 1
5060461 | 01 eerste verdieping | 0 | 0 | 0 | 443 | 10931.3 | NLRS_42_GM_WBP_plaat : 18x409 | 1.65092 | 10931.3 | 0.00333752 | 0 | -45 | Pset_Generic Models - Level: 1; Constraints - Level: 1; Schedule Level: 1
5070208 | 01 eerste verdieping | 0 | 0 | 0 | 0 | 3000 | <not associated> | 0.454044 | 3000 | 0.000917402 | 0 | 0
5070271 | 01 eerste verdieping | 0 | 0 | 0 | 0 | 3000 | <not associated> | 0.454044 | 3000 | 0.000917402 | 0 | 0
5070378 | 01 eerste verdieping | 0 | 0 | 0 | 443 | 3813.1 | NLRS_42_GM_WBP_plaat : 18x409 | 0.577022 | 3813.1 | 0.00116605 | 0 | 0 | Pset_Generic Models - Level: 1; Constraints - Level: 1; Schedule Level: 1
5086362 | 02 tweede verdieping | 0 | 0 | 0 | 0 | 35707 | NLRS_42_GM_WBP_plaat : 18x409 | 5.39815 | 35707 | 0.010914 | 0 | -45
5086388 | 02 tweede verdieping | 45 | 0 | 123 | 0 | 33600 | NLRS_42_GM_WBP_plaat : 18x409 | 5.0823 | 33723 | 0.0102742 | -45 | 45
5086428 | 02 tweede verdieping | -45 | 123 | 0 | 0 | 35400 | NLRS_42_GM_WBP_plaat : 18x409 | 5.35455 | 35523 | 0.0108246 | 45 | -45
5086468 | 02 tweede verdieping | 45 | 0 | 0 | 0 | 12784 | NLRS_42_GM_WBP_plaat : 18x409 | 1.92844 | 12784 | 0.00389856 | -45 | -45
5086501 | 02 tweede verdieping | 45 | 0 | 0 | 0 | 44709 | NLRS_42_GM_WBP_plaat : 18x409 | 6.75697 | 44709 | 0.0136606 | -45 | -45
5086541 | 02 tweede verdieping | 45 | 0 | 0 | 0 | 7217 | NLRS_42_GM_WBP_plaat : 18x409 | 1.08915 | 7217 | 0.00220155 | -45 | 0
6256336 | 01 eerste verdieping | 45 | 0 | 0 | 568 | 12484 | NLRS_42_GM_WBP_plaat : 18x409 | 1.88306 | 12484 | 0.00380682 | -45 | -45 | Pset_Generic Models - Level: 2; Constraints - Level: 2; Schedule Level: 2

# IfcBuildingElementProxy: NLRS_42_GM_daktrim_gebogen Hol:18x400, NLRS_42_GM_daktrim_gebogen Hol:18x400:5080248
In: 01 eerste verdieping
Type - Material: STAAL_RAL 7006
Type - Other - Category: Generic Models; Family Name: NLRS_42_GM_daktrim_gebogen Hol
Type - Constraints - Default Elevation: 0 mm
Type - Dimensions - NLRS_C_breedte: 400 mm; NLRS_C_dikte: 18 mm
Type - Identity Data - Assembly Code: 2C(47); Description: Gebogen daktrim; Type Name: 18x400; Workset: Family : Generic Models : NLRS_42_GM_daktrim_gebogen Hol
Type - Materials and Finishes - NLRS_C_materiaal: STAAL_RAL 7006
Type - Pset_ProductRequirements - Category: Generic Models
Classification: 2C(47) Uniformat (Uniformat)
Pset_BuildingElementProxyCommon - Reference: 18x400; sets with these values: 2
Pset_Generic Models - Family and Type: NLRS_42_GM_daktrim_gebogen Hol: 18x400; NL-sfb-Codering: 2C(47); Omschrijving: Gebogen daktrim; Level: 1
Pset_DAT_KMS - Assembly Code: 2C(47); Description: Gebogen daktrim
Other - Type: 18x400; Family: NLRS_42_GM_daktrim_gebogen Hol; Family and Type: NLRS_42_GM_daktrim_gebogen Hol: 18x400; Type Id: 5080135
Constraints - Level: 1; Schedule Level: 1; Elevation from Level: 443 mm; Host: NLRS_42_GM_WBP_plaat_gebogen : 18x430
Dimensions - NLRS_C_hoek: 45 deg; Area: 0.122246 m2; buitenradius: 1425 mm; NLRS_C_lengte: 805.033 mm; NLRS_C_radius: 1025 mm; Volume: 0.000246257 m3
Identity Data - Workset: Bouwkundig
Phasing - Phase Created: 2. nieuwbouw

# IfcBuildingElementProxy: NLRS_42_GM_daktrim_gebogen:18x400, NLRS_42_GM_daktrim_gebogen:18x400:5070701
In: 01 eerste verdieping
Type - Material: STAAL_RAL 7006
Type - Other - Category: Generic Models; Family Name: NLRS_42_GM_daktrim_gebogen
Type - Constraints - Default Elevation: 0 mm
Type - Dimensions - NLRS_C_breedte: 400 mm; NLRS_C_dikte: 18 mm
Type - Identity Data - Assembly Code: 2C(47); Description: Gebogen daktrim; Type Name: 18x400; Workset: Family : Generic Models : NLRS_42_GM_daktrim_gebogen
Type - Materials and Finishes - NLRS_C_materiaal: STAAL_RAL 7006
Type - Pset_ProductRequirements - Category: Generic Models
Classification: 2C(47) Uniformat (Uniformat)
Pset_BuildingElementProxyCommon - Reference: 18x400; sets with these values: 2
Pset_Generic Models - Family and Type: NLRS_42_GM_daktrim_gebogen: 18x400; NL-sfb-Codering: 2C(47); Omschrijving: Gebogen daktrim; Level: 1
Pset_DAT_KMS - Assembly Code: 2C(47); Description: Gebogen daktrim
Other - Family: NLRS_42_GM_daktrim_gebogen; Family and Type: NLRS_42_GM_daktrim_gebogen: 18x400; Type: 18x400; Type Id: 5044815
Constraints - Level: 1; Schedule Level: 1; Elevation from Level: 443 mm; Host: NLRS_42_GM_WBP_plaat_gebogen : 18x430
Dimensions - NLRS_C_hoek: 45 deg; Area: 0.234762 m2; buitenradius: 2375 mm; NLRS_C_lengte: 1551.16 mm; NLRS_C_radius: 1975 mm; Volume: 0.000474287 m3
Identity Data - Workset: Bouwkundig
Phasing - Phase Created: 2. nieuwbouw

# IfcBuildingElementProxy: Storax-vloerluik-BV-F90:BV-F90 106 (5)
Type - Material: bcb_kunststof, bcb_staal
Type - Other(Type) - Category: Generic Models; Family Name: Storax-vloerluik-BV-F90
Type - Constraints(Type) - Default Elevation: 0 mm
Type - Data(Type) - belasting: 125 kN; binnenluik: tbv betonvulling; brandwerend 90 min: ja; gasdrukveer: nee; geïsoleerd: ja; gewicht: 45; rubberen_afdichting: enkel; scharnierend: nee; sluiting: 4; vergrendeling: nee
Type - Dimensions(Type) - binnenmaat_breedte: 600 mm; binnenmaat_lengte: 1000 mm; uitwendige_breedte: 735 mm; uitwendige_lengte: 1135 mm
Type - Identity Data(Type) - Assembly Code: 33.21; Assembly Description: vloeropeningen; gevuld, beloopbare vullingen; Description: vloerluik; Manufacturer: Storax; Model: BV; productgroep: Vloerluiken; Type Name: BV-F90 106; URL: http://www.storax.nl/producten/Staal/187/Type-BV-F90; Workset: Family : Generic Models : Storax-vloerluik-BV-F90
Type - Materials and Finishes(Type) - materiaal: bcb_staal; vullen_met_beton: ja
Type - Pset_ManufacturerTypeInformation - Manufacturer: Storax
Type - Pset_ProductRequirements - Category: Generic Models
Classification: 33.21 Uniformat (Uniformat)
Pset_BuildingElementProxyCommon - Reference: BV-F90 106; sets with these values: 2
Pset_Generic Models - Family and Type: Storax-vloerluik-BV-F90: BV-F90 106; NL-sfb-Codering: 33.21; Omschrijving: vloerluik
Pset_DAT_KMS - Assembly Code: 33.21; Assembly Description: vloeropeningen; gevuld, beloopbare vullingen; Description: vloerluik
Other - Category: Generic Models; Family: Storax-vloerluik-BV-F90; Family and Type: Storax-vloerluik-BV-F90: BV-F90 106; Type: BV-F90 106; Type Id: 6149338
Constraints - Elevation from Level: 0 mm; Host: Floor : 23_Dekvloer 70mm
Dimensions - Area: 1.86317 m2; inbouwhoogte: 75 mm; Volume: 0.0376724 m3
Identity Data - Workset: Bouwkundig
Phasing - Phase Created: 2. nieuwbouw
Name (Storax-vloerluik-BV-F90:BV-F90 106:...) | In | Pset_Generic Models, Level = Constraints, Level = Schedule Level
6149365 | 0.14 | 0
6149515 | 0.40 | 0
6149637 | 0.30 | 0
6149726 | 0.34 | 0
6224300 | 0.16

# IfcBuildingElementProxy: Sub-Division:5750698
In: 00 Begane grond
Pset_BuildingElementProxyCommon - Reference: Sub-Division; sets with these values: 2
Pset_ProductRequirements - Category: Toposolid; sets with these values: 2
Pset_ProvisionForVoid - Shape: Undefined
Dimensions - Area: 29.7337 m2; Elevation at Bottom: -30 mm; Elevation at Top: -5 mm; Perimeter: 605389 mm; Volume: 0.743644 m3
Identity Data - Workset: Bouwkundig
Phasing - Phase Created: 2. nieuwbouw
Sub-Division - Inherit Contours: yes; Material: x_Situatie_Band; Sub-divide Height: 25 mm

# IfcBuildingElementProxy: Sub-Division:5753152
In: 00 Begane grond
Pset_BuildingElementProxyCommon - Reference: Sub-Division; sets with these values: 2
Pset_ProductRequirements - Category: Toposolid; sets with these values: 2
Pset_ProvisionForVoid - Shape: Undefined
Dimensions - Area: 703.7 m2; Elevation at Bottom: -30 mm; Elevation at Top: -10 mm; Perimeter: 714531 mm; Volume: 14.0741 m3
Identity Data - Workset: Bouwkundig
Phasing - Phase Created: 2. nieuwbouw
Sub-Division - Inherit Contours: yes; Material: x_Situatie_Gras; Sub-divide Height: 20 mm

# IfcBuildingElementProxy: Sub-Division:5754387
In: 00 Begane grond
Pset_BuildingElementProxyCommon - Reference: Sub-Division; sets with these values: 2
Pset_ProductRequirements - Category: Toposolid; sets with these values: 2
Pset_ProvisionForVoid - Shape: Undefined
Dimensions - Area: 1.94196 m2; Elevation at Bottom: -30 mm; Elevation at Top: -10 mm; Perimeter: 38966 mm; Volume: 0.0389012 m3
Identity Data - Workset: Bouwkundig
Phasing - Phase Created: 2. nieuwbouw
Sub-Division - Inherit Contours: yes; Material: x_Situatie_Band; Sub-divide Height: 20 mm

# IfcBuildingElementProxy: Sub-Division:5758544
In: 00 Begane grond
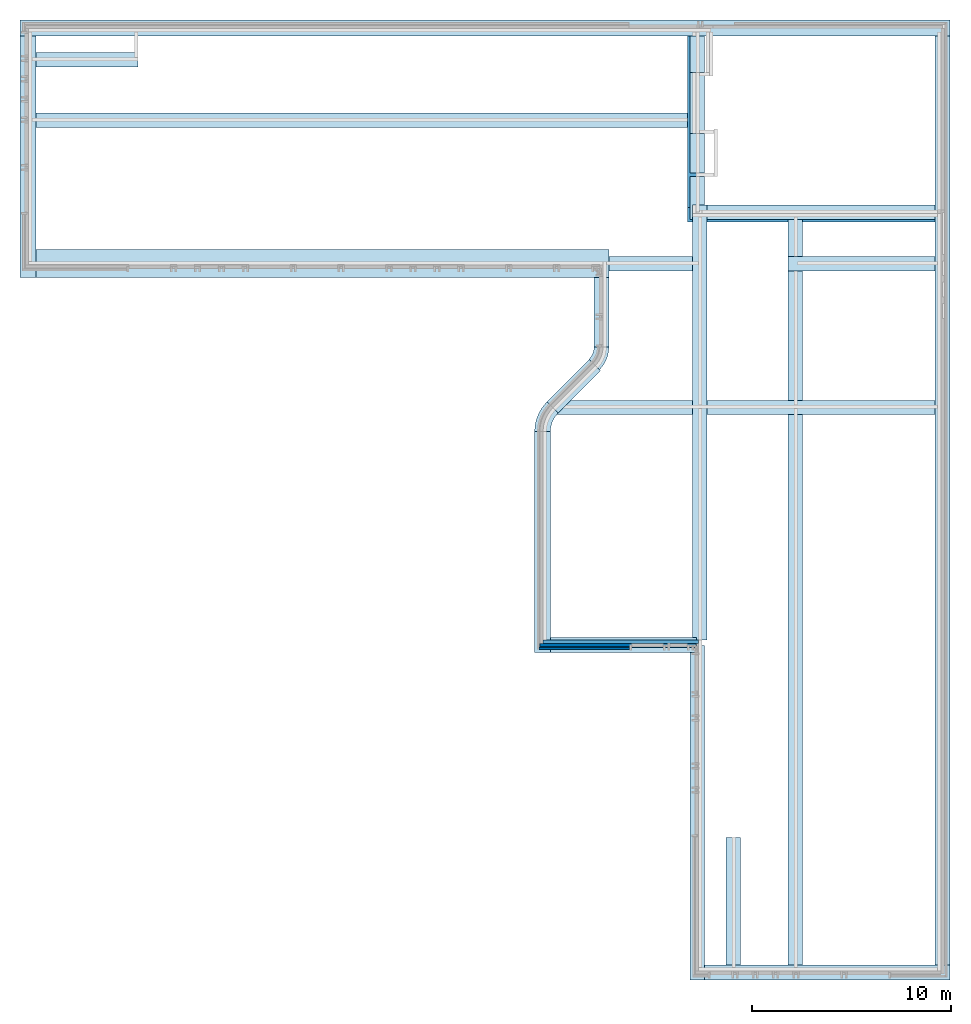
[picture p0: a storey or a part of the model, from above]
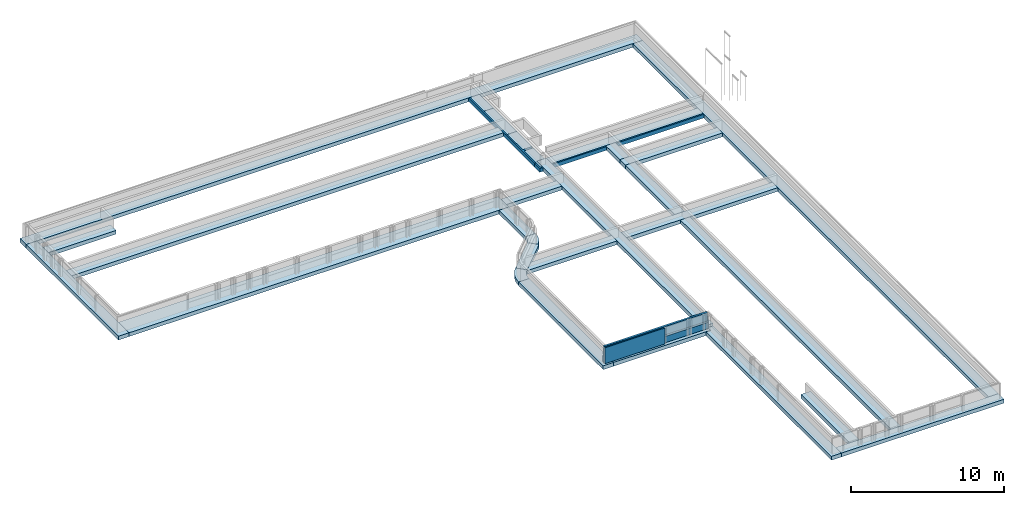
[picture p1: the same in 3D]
Properties of the parts of a building model (IFC2X3), part 9 of 37

# IfcBuildingElementProxy: Sub-Division:5758544
Pset_BuildingElementProxyCommon - Reference: Sub-Division; sets with these values: 2
Pset_ProductRequirements - Category: Toposolid; sets with these values: 2
Pset_ProvisionForVoid - Shape: Undefined
Dimensions - Elevation at Top: 0 mm; Area: 128.077 m2; Elevation at Bottom: -30 mm; Perimeter: 78699.9 mm; Volume: 3.84164 m3
Identity Data - Workset: Bouwkundig
Phasing - Phase Created: 2. nieuwbouw
Sub-Division - Inherit Contours: yes; Material: x_Situatie_Houtsnippers; Sub-divide Height: 30 mm

# IfcBuildingElementProxy: Sub-Division:5758580
In: 00 Begane grond
Pset_BuildingElementProxyCommon - Reference: Sub-Division; sets with these values: 2
Pset_ProductRequirements - Category: Toposolid; sets with these values: 2
Pset_ProvisionForVoid - Shape: Undefined
Dimensions - Elevation at Top: 0 mm; Area: 417.377 m2; Elevation at Bottom: -30 mm; Perimeter: 395030 mm; Volume: 12.5213 m3
Identity Data - Workset: Bouwkundig
Phasing - Phase Created: 2. nieuwbouw
Sub-Division - Inherit Contours: yes; Material: x_Situatie_Parkeren; Sub-divide Height: 30 mm

# IfcBuildingElementProxy: Sub-Division:5759375
In: 00 Begane grond
Pset_BuildingElementProxyCommon - Reference: Sub-Division; sets with these values: 2
Pset_ProductRequirements - Category: Toposolid; sets with these values: 2
Pset_ProvisionForVoid - Shape: Undefined
Dimensions - Area: 316.454 m2; Elevation at Bottom: -30 mm; Elevation at Top: -10 mm; Perimeter: 654524 mm; Volume: 6.32909 m3
Identity Data - Workset: Bouwkundig
Phasing - Phase Created: 2. nieuwbouw
Sub-Division - Inherit Contours: yes; Material: x_Situatie_Fietspad; Sub-divide Height: 20 mm

# IfcBuildingElementProxy: Sub-Division:5759901
In: 00 Begane grond
Pset_BuildingElementProxyCommon - Reference: Sub-Division; sets with these values: 2
Pset_ProductRequirements - Category: Toposolid; sets with these values: 2
Pset_ProvisionForVoid - Shape: Undefined
Dimensions - Area: 734.815 m2; Elevation at Bottom: -30 mm; Elevation at Top: -10 mm; Perimeter: 526577 mm; Volume: 14.6964 m3
Identity Data - Workset: Bouwkundig
Phasing - Phase Created: 2. nieuwbouw
Sub-Division - Inherit Contours: yes; Material: x_Situatie_Stoep; Sub-divide Height: 20 mm

# IfcBuildingElementProxy: Sub-Division:5765204
In: 00 Begane grond
Pset_BuildingElementProxyCommon - Reference: Sub-Division; sets with these values: 2
Pset_ProductRequirements - Category: Toposolid; sets with these values: 2
Pset_ProvisionForVoid - Shape: Undefined
Dimensions - Area: 1.94837 m2; Elevation at Bottom: -30 mm; Elevation at Top: 20 mm; Perimeter: 38966.3 mm; Volume: 0.0973118 m3
Identity Data - Workset: Bouwkundig
Phasing - Phase Created: 2. nieuwbouw
Sub-Division - Inherit Contours: yes; Material: x_Situatie_Band; Sub-divide Height: 50 mm

# IfcBuildingElementProxy: Sub-Division:5817066
In: 00 Begane grond
Pset_BuildingElementProxyCommon - Reference: Sub-Division; sets with these values: 2
Pset_ProductRequirements - Category: Toposolid; sets with these values: 2
Pset_ProvisionForVoid - Shape: Undefined
Dimensions - Area: 22181.2 m2; Elevation at Bottom: -30 mm; Elevation at Top: -10 mm; Perimeter: 1641687 mm; Volume: 443.625 m3
Identity Data - Workset: Bouwkundig
Phasing - Phase Created: 2. nieuwbouw
Sub-Division - Inherit Contours: yes; Material: x_Situatie_Situatie omgeving; Sub-divide Height: 20 mm

# IfcBuildingElementProxy: Sub-Division:5820671
In: 00 Begane grond
Pset_BuildingElementProxyCommon - Reference: Sub-Division; sets with these values: 2
Pset_ProductRequirements - Category: Toposolid; sets with these values: 2
Pset_ProvisionForVoid - Shape: Undefined
Dimensions - Area: 6111.83 m2; Elevation at Bottom: -30 mm; Elevation at Top: 20 mm; Perimeter: 2608415 mm; Volume: 305.592 m3
Identity Data - Workset: Bouwkundig
Phasing - Phase Created: 2. nieuwbouw
Sub-Division - Inherit Contours: yes; Material: x_Situatie_Gebouwen omgeving; Sub-divide Height: 50 mm

# IfcBuildingElementProxy: Sub-Division:6474244
In: 00 Begane grond
Pset_BuildingElementProxyCommon - Reference: Sub-Division; sets with these values: 2
Pset_ProductRequirements - Category: Toposolid; sets with these values: 2
Pset_ProvisionForVoid - Shape: Undefined
Dimensions - Area: 51.0715 m2; Elevation at Bottom: -30 mm; Elevation at Top: 1570 mm; Perimeter: 174952 mm; Volume: 81.7144 m3
Identity Data - Workset: situatie
Phasing - Phase Created: 2. nieuwbouw
Sub-Division - Inherit Contours: yes; Material: x_Situatie_Heg; Sub-divide Height: 1600 mm

# IfcBuildingElementProxy: Sub-Division:6474394
In: 00 Begane grond
Pset_BuildingElementProxyCommon - Reference: Sub-Division; sets with these values: 2
Pset_ProductRequirements - Category: Toposolid; sets with these values: 2
Pset_ProvisionForVoid - Shape: Undefined
Dimensions - Area: 16.7973 m2; Elevation at Bottom: -30 mm; Elevation at Top: 1170 mm; Perimeter: 57159 mm; Volume: 20.1498 m3
Identity Data - Workset: situatie
Phasing - Phase Created: 2. nieuwbouw
Sub-Division - Inherit Contours: yes; Material: x_Situatie_Heg; Sub-divide Height: 1200 mm

# IfcBuildingElementProxy: Sub-Division:6847005
In: -1 Speelvloer
Pset_BuildingElementProxyCommon - Reference: Sub-Division; sets with these values: 2
Pset_ProductRequirements - Category: Toposolid; sets with these values: 2
Pset_ProvisionForVoid - Shape: Rectangle; Width: 9999.33 mm; Height: 18999.5 mm
Dimensions - Area: 189.983 m2; Elevation at Bottom: -480 mm; Elevation at Top: -470 mm; Perimeter: 57997.7 mm; Volume: 1.89983 m3
Identity Data - Workset: Bouwkundig
Phasing - Phase Created: 2. nieuwbouw
Sub-Division - Inherit Contours: yes; Material: x_Situatie_Sportplek; Sub-divide Height: 10 mm

# IfcBuildingElementProxy: Sub-Division:6847038
In: -1 Speelvloer
Pset_BuildingElementProxyCommon - Reference: Sub-Division; sets with these values: 2
Pset_ProductRequirements - Category: Toposolid; sets with these values: 2
Pset_ProvisionForVoid - Shape: Rectangle
Dimensions - Area: 34.5529 m2; Elevation at Bottom: -480 mm; Elevation at Top: -470 mm; Perimeter: 46335.6 mm; Volume: 0.345529 m3
Identity Data - Workset: Bouwkundig
Phasing - Phase Created: 2. nieuwbouw
Sub-Division - Inherit Contours: yes; Material: x_Situatie_Tegel; Sub-divide Height: 10 mm

# IfcBuildingElementProxy: Sub-Division:6909690
In: 00 Begane grond
Pset_BuildingElementProxyCommon - Reference: Sub-Division; sets with these values: 2
Pset_ProductRequirements - Category: Toposolid; sets with these values: 2
Pset_ProvisionForVoid - Shape: Rectangle
Dimensions - Area: 1736.8 m2; Elevation at Bottom: -30 mm; Elevation at Top: -29 mm; Perimeter: 224525 mm; Volume: 1.7368 m3
Identity Data - Workset: Bouwkundig
Phasing - Phase Created: 2. nieuwbouw
Sub-Division - Inherit Contours: yes; Material: x_Situatie_Tegel; Sub-divide Height: 1 mm

# IfcBuildingElementProxy: Toposolid:Toposolid 1 (2)
In: 00 Begane grond
Type - Material: ISR_Terrein 3000 mm
Type - Other - Category: Toposolid; Family Name: Toposolid
Type - Construction - Default Thickness: 3000 mm
Type - Graphics - Coarse Scale Fill Color: 0
Type - Identity Data - Type Name: Toposolid 1; Workset: Toposolid Types
Type - Analytical Properties - Roughness: 1; Absorptance: 0.1
Type - Pset_ElementShading - Roughness: 304.8 mm
Type - Pset_ProductRequirements - Category: Toposolid
Pset_BuildingElementProxyCommon - Reference: Toposolid 1; sets with these values: 2
Pset_ProvisionForVoid - Shape: Undefined
Other - Family: Toposolid; Family and Type: Toposolid: Toposolid 1; Type: Toposolid 1; Type Id: 4709300
Constraints - Level: 0; Related to Mass: no; Room Bounding: yes
Dimensions - Thickness: 3000 mm
Identity Data - Workset: Bouwkundig
Phasing - Phase Created: 2. nieuwbouw
Name (Toposolid:Toposolid 1:...) | Height Offset From Level (mm) = Elevation at Top (mm) | Area (m2) | Elevation at Bottom (mm) | Perimeter (mm) | Volume (m3)
5187340 | -30 | 31976 | -3030 | 1008000 | 95928 | Slab Shape Edit - Curved Edge Condition: 1
6846565 | -480 | 237.409 | -3480 | 67345.9 | 712.225

# IfcBuildingElementProxy: Toposolid:Toposolid zitbank (3)
In: 00 Begane grond
Type - Material: ISR_Beton_prefab 3000 mm
Type - Other - Category: Toposolid; Family Name: Toposolid
Type - Construction - Default Thickness: 3000 mm
Type - Graphics - Coarse Scale Fill Color: 0
Type - Identity Data - Workset: Toposolid Types; Type Name: Toposolid zitbank
Type - Analytical Properties - Roughness: 1; Absorptance: 0.1
Type - Pset_ElementShading - Roughness: 304.8 mm
Type - Pset_ProductRequirements - Category: Toposolid
Pset_BuildingElementProxyCommon - Reference: Toposolid zitbank; sets with these values: 2
Pset_ProvisionForVoid - Shape: Rectangle
Other - Family: Toposolid; Family and Type: Toposolid: Toposolid zitbank; Type: Toposolid zitbank; Type Id: 6847471
Constraints - Level: 0; Related to Mass: no; Room Bounding: yes
Dimensions - Thickness: 3000 mm
Identity Data - Workset: Bouwkundig
Phasing - Phase Created: 2. nieuwbouw
Name (Toposolid:Toposolid zitbank:...) | Height Offset From Level (mm) = Elevation at Top (mm) | Area (m2) | Elevation at Bottom (mm) | Perimeter (mm) | Volume (m3)
6847249 | -170 | 11.0664 | -3170 | 40485.6 | 33.1993
6847559 | -170 | 0.900001 | -3170 | 7200 | 2.7
6847634 | -320 | 0.900001 | -3320 | 7200 | 2.7

# IfcBuildingElementProxy: Toposolid:hellingbaan (2)
In: 00 Begane grond
Type - Material: x_Situatie_Tegel 3000 mm
Type - Other - Category: Toposolid; Family Name: Toposolid
Type - Construction - Default Thickness: 3000 mm
Type - Graphics - Coarse Scale Fill Color: 0
Type - Identity Data - Workset: Toposolid Types; Type Name: hellingbaan
Type - Analytical Properties - Roughness: 1; Absorptance: 0.1
Type - Pset_ElementShading - Roughness: 304.8 mm
Type - Pset_ProductRequirements - Category: Toposolid
Pset_BuildingElementProxyCommon - Reference: hellingbaan; sets with these values: 2
Pset_ProvisionForVoid - Shape: Rectangle
Other - Family: Toposolid; Family and Type: Toposolid: hellingbaan; Type: hellingbaan; Type Id: 6847079
Constraints - Level: 0; Related to Mass: no; Room Bounding: yes; Height Offset From Level: 0 mm
Dimensions - Thickness: 3000 mm
Identity Data - Workset: Bouwkundig
Phasing - Phase Created: 2. nieuwbouw
Name (Toposolid:hellingbaan:...) | Width (mm) | Height (mm) | Area (m2) | Perimeter (mm) | Volume (m3)
6846654 | 3033.56 | 1199.38 | 3.6384 | 8398.76 | 10.9152
6846962 | 3032.5 | 1199.98 | 3.63895 | 8397.82 | 10.9169

# IfcColumn: NLRS_28_SCO_TLB_kolom buis betongevuld_gen_ASN:kolom betongevuld ø168.3x8 (2)
In: 00 Begane grond
Type - PredefinedType: COLUMN; Material: ISR_Beton ihwg, h2_staal
Type - Other - Category: Structural Columns; Family Name: NLRS_28_SCO_TLB_kolom buis betongevuld_gen_ASN
Type - Dimensions - Height: 168.3 mm; OD: 168.3 mm; r_inw: 76.15 mm; r_uitw: 84.15 mm; t: 8 mm; Wall Design Thickness: 8 mm; Width: 168.3 mm
Type - General - NLRS_C_content_creator: Arkance Systems; NLRS_C_content_datum_gewijzigd: 2022.05.27; NLRS_C_content_provider: Arkance Systems; NLRS_C_content_versie: 2.1; NLRS_C_revit_versie: 2021
Type - Identity Data - Assembly Code: 28.10; Assembly Description: hoofddraagconstructies; kolommen en liggers, algemeen (verzamelniveau); Description: ø168.3x8 betongevuld; Manufacturer: generiek; Model: buisprofiel, beton gevuld; Type Name: kolom betongevuld ø168.3x8; Workset: Family : Structural Columns : NLRS_28_SCO_TLB_kolom buis betongevuld_gen_ASN
Type - Structural - Section Shape: 15
Type - Structural Section Geometry - Centroid Horizontal: 84.15 mm; Centroid Vertical: 84.15 mm; Diameter: 168.3 mm; Wall Nominal Thickness: 8 mm
Type - Pset_ColumnCommon - LoadBearing: yes; IsExternal: no
Type - Pset_ManufacturerTypeInformation - Manufacturer: generiek
Type - Pset_ProductRequirements - Category: Structural Columns
Type - Pset_ReinforcementBarPitchOfColumn - Description: ø168.3x8 betongevuld
Classification: 28.10 Uniformat (Uniformat)
BaseQuantities - Length: 3240 mm; CrossSectionArea: 0.00402824 m2; OuterSurfaceArea: 3.26331 m2; GrossVolume: 0.0130515 m3; NetVolume: 0.0720746 m3
Pset_ColumnCommon - IsExternal: yes; Reference: kolom betongevuld ø168.3x8
Pset_PrecastConcreteElementGeneral - ElementWeight: 0 kg
Pset_QuantityTakeOff - Reference: kolom betongevuld ø168.3x8; sets with these values: 2
Pset_Structural Column - Omschrijving: ø168.3x8 betongevuld; NL-sfb-Codering: 28.10; Structural Material: h2_staal
Pset_DAT_KMS - Assembly Code: 28.10; Assembly Description: hoofddraagconstructies; kolommen en liggers, algemeen (verzamelniveau); Description: ø168.3x8 betongevuld
Other - Family: NLRS_28_SCO_TLB_kolom buis betongevuld_gen_ASN; Family and Type: NLRS_28_SCO_TLB_kolom buis betongevuld_gen_ASN: kolom betongevuld ø168.3x8; Type: kolom betongevuld ø168.3x8; Type Id: 5966522
Constraints - Base Offset: 0 mm; Level: 0; Base Level: 0; Column Style: Vertical; Moves With Grids: yes; Top Level: V1 ok. ruwe vloer; Top Offset: 0 mm
Dimensions - Length: 3240 mm; NLRS_C_breedte: 168.3 mm; NLRS_C_diameter: 168.3 mm; NLRS_C_hoogte: 168.3 mm; Volume: 0.0720746 m3
Identity Data - Has Association: no; Workset: Constructie
Materials and Finishes - Structural Material: h2_staal
Phasing - Phase Created: 2. nieuwbouw
Name (NLRS_28_SCO_TLB_kolom buis betongevuld_gen_ASN:kolom betongevuld ø168.3x8:...) | Column Location Mark
4751095 | J-1(309)
4755674 | A(310)-9

# IfcColumn: NLRS_28_SCO_TLB_kolom buis betongevuld_gen_ASN:kolom betongevuld ø273x6.3, NLRS_28_SCO_TLB_kolom buis betongevuld_gen_ASN:kolom betongevuld ø273x6.3:4752196
In: 00 Begane grond
Type - PredefinedType: COLUMN; Material: f2_beton, h2_staal
Type - Other - Category: Structural Columns; Family Name: NLRS_28_SCO_TLB_kolom buis betongevuld_gen_ASN
Type - Dimensions - Height: 273 mm; OD: 273 mm; r_inw: 130.2 mm; r_uitw: 136.5 mm; t: 6.3 mm; Wall Design Thickness: 6.3 mm; Width: 273 mm
Type - General - NLRS_C_content_creator: Arkance Systems; NLRS_C_content_datum_gewijzigd: 2022.05.27; NLRS_C_content_provider: Arkance Systems; NLRS_C_content_versie: 2.1; NLRS_C_revit_versie: 2021
Type - Identity Data - Workset: Family : Structural Columns : NLRS_28_SCO_TLB_kolom buis betongevuld_gen_ASN; Assembly Code: 28.10; Assembly Description: hoofddraagconstructies; kolommen en liggers, algemeen (verzamelniveau); Description: ø273x8 betongevuld; Manufacturer: generiek; Model: buisprofiel, beton gevuld; Type Name: kolom betongevuld ø273x6.3
Type - Structural - Section Shape: 15
Type - Structural Section Geometry - Centroid Horizontal: 136.5 mm; Centroid Vertical: 136.5 mm; Diameter: 273 mm; Wall Nominal Thickness: 6.3 mm
Type - Pset_ColumnCommon - LoadBearing: yes; IsExternal: no
Type - Pset_ManufacturerTypeInformation - Manufacturer: generiek
Type - Pset_ProductRequirements - Category: Structural Columns
Type - Pset_ReinforcementBarPitchOfColumn - Description: ø273x8 betongevuld
Classification: 28.10 Uniformat (Uniformat)
BaseQuantities - Length: 6890 mm; CrossSectionArea: 0.00527783 m2; OuterSurfaceArea: 11.5457 m2; GrossVolume: 0.0363642 m3; NetVolume: 0.403287 m3
Pset_ColumnCommon - IsExternal: yes; Reference: kolom betongevuld ø273x6.3
Pset_PrecastConcreteElementGeneral - ElementWeight: 0 kg
Pset_QuantityTakeOff - Reference: kolom betongevuld ø273x6.3; sets with these values: 2
Pset_Structural Column - Omschrijving: ø273x8 betongevuld; NL-sfb-Codering: 28.10; Structural Material: h2_staal
Pset_DAT_KMS - Assembly Code: 28.10; Assembly Description: hoofddraagconstructies; kolommen en liggers, algemeen (verzamelniveau); Description: ø273x8 betongevuld
Other - Family: NLRS_28_SCO_TLB_kolom buis betongevuld_gen_ASN; Family and Type: NLRS_28_SCO_TLB_kolom buis betongevuld_gen_ASN: kolom betongevuld ø273x6.3; Type: kolom betongevuld ø273x6.3; Type Id: 5966618
Constraints - Base Offset: 0 mm; Level: 0; Base Level: 0; Column Style: Vertical; Moves With Grids: yes; Top Offset: 0 mm; Top Level: V2 ok. ruwe vloer; Column Location Mark: F-9
Dimensions - Length: 6890 mm; NLRS_C_breedte: 273 mm; NLRS_C_diameter: 273 mm; NLRS_C_hoogte: 273 mm; Volume: 0.403287 m3
Identity Data - Has Association: no; Workset: Constructie
Materials and Finishes - Structural Material: h2_staal; materiaal_vulling: f2_beton
Phasing - Phase Created: 2. nieuwbouw

# IfcColumn: NLRS_28_SCO_TLB_kolom buis betongevuld_gen_ASN:kolom betongevuld ø273x8, NLRS_28_SCO_TLB_kolom buis betongevuld_gen_ASN:kolom betongevuld ø273x8:4752208
In: 00 Begane grond
Type - PredefinedType: COLUMN; Material: f2_beton, h2_staal
Type - Other - Category: Structural Columns; Family Name: NLRS_28_SCO_TLB_kolom buis betongevuld_gen_ASN
Type - Dimensions - Height: 273 mm; OD: 273 mm; r_inw: 128.5 mm; r_uitw: 136.5 mm; t: 8 mm; Wall Design Thickness: 8 mm; Width: 273 mm
Type - General - NLRS_C_content_creator: Arkance Systems; NLRS_C_content_datum_gewijzigd: 2022.05.27; NLRS_C_content_provider: Arkance Systems; NLRS_C_content_versie: 2.1; NLRS_C_revit_versie: 2021
Type - Identity Data - Workset: Family : Structural Columns : NLRS_28_SCO_TLB_kolom buis betongevuld_gen_ASN; Assembly Code: 28.10; Assembly Description: hoofddraagconstructies; kolommen en liggers, algemeen (verzamelniveau); Description: ø273x8 betongevuld; Manufacturer: generiek; Model: buisprofiel, beton gevuld; Type Name: kolom betongevuld ø273x8
Type - Structural - Section Shape: 15
Type - Structural Section Geometry - Centroid Horizontal: 136.5 mm; Centroid Vertical: 136.5 mm; Diameter: 273 mm; Wall Nominal Thickness: 8 mm
Type - Pset_ColumnCommon - LoadBearing: yes; IsExternal: no
Type - Pset_ManufacturerTypeInformation - Manufacturer: generiek
Type - Pset_ProductRequirements - Category: Structural Columns
Type - Pset_ReinforcementBarPitchOfColumn - Description: ø273x8 betongevuld
Classification: 28.10 Uniformat (Uniformat)
BaseQuantities - Length: 3240 mm; CrossSectionArea: 0.00665929 m2; OuterSurfaceArea: 5.39474 m2; GrossVolume: 0.0215761 m3; NetVolume: 0.189644 m3
Pset_ColumnCommon - IsExternal: yes; Reference: kolom betongevuld ø273x8
Pset_PrecastConcreteElementGeneral - ElementWeight: 0 kg
Pset_QuantityTakeOff - Reference: kolom betongevuld ø273x8; sets with these values: 2
Pset_Structural Column - Omschrijving: ø273x8 betongevuld; NL-sfb-Codering: 28.10; Structural Material: h2_staal
Pset_DAT_KMS - Assembly Code: 28.10; Assembly Description: hoofddraagconstructies; kolommen en liggers, algemeen (verzamelniveau); Description: ø273x8 betongevuld
Other - Family: NLRS_28_SCO_TLB_kolom buis betongevuld_gen_ASN; Family and Type: NLRS_28_SCO_TLB_kolom buis betongevuld_gen_ASN: kolom betongevuld ø273x8; Type: kolom betongevuld ø273x8; Type Id: 5966639
Constraints - Base Offset: 0 mm; Level: 0; Base Level: 0; Column Style: Vertical; Moves With Grids: yes; Top Level: V1 ok. ruwe vloer; Top Offset: 0 mm; Column Location Mark: G-8
Dimensions - Length: 3240 mm; NLRS_C_breedte: 273 mm; NLRS_C_diameter: 273 mm; NLRS_C_hoogte: 273 mm; Volume: 0.189644 m3
Identity Data - Has Association: no; Workset: Constructie
Materials and Finishes - Structural Material: h2_staal; materiaal_vulling: f2_beton
Phasing - Phase Created: 2. nieuwbouw

# IfcColumn: NLRS_28_SCO_TLB_kolom koker RHS_gen_ASN:kolom K120x60x10 (18)
Type - PredefinedType: COLUMN; Material: ISR_Staal
Type - Other - Category: Structural Columns; Family Name: NLRS_28_SCO_TLB_kolom koker RHS_gen_ASN; h: 160 mm
Type - Dimensions - NLRS_C_breedte: 60 mm; NLRS_C_dikte: 10 mm; NLRS_C_hoogte: 160 mm; r: 6 mm; r_inw: 3 mm; Wall Design Thickness: 10 mm
Type - General - NLRS_C_content_creator: Arkance Systems; NLRS_C_content_datum_gewijzigd: 2022.05.27; NLRS_C_content_provider: Arkance Systems; NLRS_C_content_versie: 2.1; NLRS_C_revit_versie: 2021
Type - Identity Data - Assembly Code: 28.10; Assembly Description: hoofddraagconstructies; kolommen en liggers, algemeen (verzamelniveau); Description: K120x60x10; Manufacturer: generiek; Model: kokerprofiel (ongelijkzijdig); Type Name: kolom K120x60x10; Workset: Family : Structural Columns : NLRS_28_SCO_TLB_kolom koker RHS_gen_ASN
Type - Structural - Section Shape: 14
Type - Text - Shape: rechthoek
Type - Structural Section Geometry - Centroid Horizontal: 80 mm; Centroid Vertical: 30 mm; Height: 160 mm; Inner Fillet: 3 mm; Outer Fillet: 6 mm; Wall Nominal Thickness: 10 mm; Width: 60 mm
Type - Pset_ColumnCommon - LoadBearing: yes; IsExternal: no
Type - Pset_ManufacturerTypeInformation - Manufacturer: generiek
Type - Pset_ProductRequirements - Category: Structural Columns
Type - Pset_ReinforcementBarPitchOfColumn - Description: K120x60x10
Classification: 28.10 Uniformat (Uniformat)
BaseQuantities - Length: 2350 mm; CrossSectionArea: 0.0039768 m2; OuterSurfaceArea: 1.84369 m2; GrossVolume: 0.00934547 m3; NetVolume: 0.00934552 m3
Pset_ColumnCommon - Slope: 0 deg; IsExternal: yes; Reference: kolom K120x60x10
Pset_PrecastConcreteElementGeneral - ElementWeight: 0 kg
Pset_QuantityTakeOff - Reference: kolom K120x60x10; sets with these values: 2
Pset_Structural Column - Omschrijving: K120x60x10; NL-sfb-Codering: 28.10
Pset_DAT_KMS - Assembly Code: 28.10; Assembly Description: hoofddraagconstructies; kolommen en liggers, algemeen (verzamelniveau); Description: K120x60x10
Other - Family: NLRS_28_SCO_TLB_kolom koker RHS_gen_ASN; Family and Type: NLRS_28_SCO_TLB_kolom koker RHS_gen_ASN: kolom K120x60x10; Type: kolom K120x60x10; Type Id: 5290611
Constraints - Column Style: Vertical; Moves With Grids: yes; Top Offset: 0 mm; Base Offset: 200 mm; Top Level: 3
Dimensions - Length: 2350 mm; Volume: 0.00934552 m3
Identity Data - Has Association: no; Workset: Constructie
Phasing - Phase Created: 2. nieuwbouw
Name (NLRS_28_SCO_TLB_kolom koker RHS_gen_ASN:kolom K120x60x10:...) | In | Base Level = Level | Column Location Mark
5290580 | 01 eerste verdieping | 2 | K-8(1895)
5291913 | 02 tweede verdieping | V2 bk. ruwe vloer | K-9(195)
5291951 | 02 tweede verdieping | V2 bk. ruwe vloer | J(900)-8(1895)
5291952 | 02 tweede verdieping | V2 bk. ruwe vloer | J(900)-9(195)
5291988 | 02 tweede verdieping | V2 bk. ruwe vloer | I(300)-8(1895)
5291989 | 02 tweede verdieping | V2 bk. ruwe vloer | I(300)-9(195)
5292021 | 02 tweede verdieping | V2 bk. ruwe vloer | G(900)-8(1895)
5292022 | 02 tweede verdieping | V2 bk. ruwe vloer | G(900)-9(195)
5292063 | 02 tweede verdieping | V2 bk. ruwe vloer | F(1800)-8(1895)
5292064 | 02 tweede verdieping | V2 bk. ruwe vloer | F(1800)-9(195)
5292102 | 02 tweede verdieping | V2 bk. ruwe vloer | E(900)-8(1895)
5292103 | 02 tweede verdieping | V2 bk. ruwe vloer | E(900)-9(195)
5292139 | 02 tweede verdieping | V2 bk. ruwe vloer | E(-2700)-8(1895)
5292140 | 02 tweede verdieping | V2 bk. ruwe vloer | E(-2700)-9(195)
5292445 | 02 tweede verdieping | V2 bk. ruwe vloer | K(195)-8(2090)
5292566 | 02 tweede verdieping | V2 bk. ruwe vloer | K(195)-9
5292648 | 02 tweede verdieping | V2 bk. ruwe vloer | E(-2895)-8(2090)
5292649 | 02 tweede verdieping | V2 bk. ruwe vloer | E(-2895)-9

# IfcColumn: NLRS_28_SCO_TLB_kolom koker betongevuld_gen_ASN:kolom betongevuld K120x120x5 (21)
In: 01 eerste verdieping
Type - PredefinedType: COLUMN; Material: f2_beton, h2_staal
Type - Other - Category: Structural Columns; Family Name: NLRS_28_SCO_TLB_kolom koker betongevuld_gen_ASN
Type - Dimensions - b: 120 mm; h: 120 mm; r: 9 mm; r_inw: 4 mm; t: 5 mm; Wall Design Thickness: 5 mm
Type - General - NLRS_C_content_creator: Arkance Systems; NLRS_C_content_datum_gewijzigd: 2022.05.27; NLRS_C_content_provider: Arkance Systems; NLRS_C_content_versie: 2.1; NLRS_C_revit_versie: 2021
Type - Identity Data - Workset: Family : Structural Columns : NLRS_28_SCO_TLB_kolom koker betongevuld_gen_ASN; Assembly Code: 28.10; Assembly Description: hoofddraagconstructies; kolommen en liggers, algemeen (verzamelniveau); Description: K120x120x4 betongevuld; Manufacturer: generiek; Model: kokerprofiel (gelijkzijdig), beton gevuld; Type Name: kolom betongevuld K120x120x5
Type - Structural - SG: 0; Section Shape: 14
Type - Text - Shape: vierkant
Type - Structural Section Geometry - Centroid Horizontal: 60 mm; Centroid Vertical: 60 mm; Height: 120 mm; Inner Fillet: 4 mm; Outer Fillet: 9 mm; Wall Nominal Thickness: 5 mm; Width: 120 mm
Type - Pset_ColumnCommon - LoadBearing: yes; IsExternal: no
Type - Pset_ManufacturerTypeInformation - Manufacturer: generiek
Type - Pset_ProductRequirements - Category: Structural Columns
Type - Pset_ReinforcementBarPitchOfColumn - Description: K120x120x4 betongevuld
Classification: 28.10 Uniformat (Uniformat)
BaseQuantities - Length: 3180 mm; CrossSectionArea: 0.00224415 m2; OuterSurfaceArea: 2.85463 m2; GrossVolume: 0.00713641 m3; NetVolume: 0.0455462 m3
Pset_ColumnCommon - IsExternal: yes; Reference: kolom betongevuld K120x120x5
Pset_PrecastConcreteElementGeneral - ElementWeight: 0 kg
Pset_QuantityTakeOff - Reference: kolom betongevuld K120x120x5; sets with these values: 2
Pset_Structural Column - Omschrijving: K120x120x4 betongevuld; NL-sfb-Codering: 28.10; Structural Material: h2_staal
Pset_DAT_KMS - Assembly Code: 28.10; Assembly Description: hoofddraagconstructies; kolommen en liggers, algemeen (verzamelniveau); Description: K120x120x4 betongevuld
Other - Family: NLRS_28_SCO_TLB_kolom koker betongevuld_gen_ASN; Family and Type: NLRS_28_SCO_TLB_kolom koker betongevuld_gen_ASN: kolom betongevuld K120x120x5; Type: kolom betongevuld K120x120x5; Type Id: 5966792
Constraints - Base Offset: 0 mm; Column Style: Vertical; Moves With Grids: yes; Base Level: 1; Level: 1; Top Level: V2 ok. ruwe vloer; Top Offset: -60 mm
Dimensions - Length: 3180 mm; NLRS_C_hoogte: 120 mm; Volume: 0.0455462 m3
Identity Data - Has Association: no; Workset: Constructie
Materials and Finishes - materiaal_vulling: f2_beton; Structural Material: h2_staal
Phasing - Phase Created: 2. nieuwbouw
Name (NLRS_28_SCO_TLB_kolom koker betongevuld_gen_ASN:kolom betongevuld K120x120x5:...) | Column Location Mark
4744586 | D-10
4744587 | C-10
4744588 | B-10
4744589 | B(3600)-10
4744591 | E-10
4744592 | D(3600)-10
4744663 | H-10
4744735 | K-1(1070)
4744745 | K-1(3600)
4744755 | K-2
4744765 | K-3
4744777 | K-3(3600)
4744787 | K-4
4744799 | K-5
4744823 | K-7
4744831 | K-7(1070)
4744841 | K-8
4744853 | K-9(-1700)
5966795 | K-1
5966868 | K-6(-600)
5967011 | C(3600)-10

# IfcColumn: NLRS_28_SCO_TLB_kolom koker betongevuld_gen_ASN:kolom betongevuld K120x120x6.3 (3)
In: 01 eerste verdieping
Type - PredefinedType: COLUMN; Material: f2_beton, h2_staal
Type - Other - Category: Structural Columns; Family Name: NLRS_28_SCO_TLB_kolom koker betongevuld_gen_ASN
Type - Dimensions - b: 120 mm; h: 120 mm; r: 9 mm; r_inw: 2.7 mm; t: 6.3 mm; Wall Design Thickness: 6.3 mm
Type - General - NLRS_C_content_creator: Arkance Systems; NLRS_C_content_datum_gewijzigd: 2022.05.27; NLRS_C_content_provider: Arkance Systems; NLRS_C_content_versie: 2.1; NLRS_C_revit_versie: 2021
Type - Identity Data - Workset: Family : Structural Columns : NLRS_28_SCO_TLB_kolom koker betongevuld_gen_ASN; Assembly Code: 28.10; Assembly Description: hoofddraagconstructies; kolommen en liggers, algemeen (verzamelniveau); Description: K120x120x4 betongevuld; Manufacturer: generiek; Model: kokerprofiel (gelijkzijdig), beton gevuld; Type Name: kolom betongevuld K120x120x6.3
Type - Structural - SG: 0; Section Shape: 14
Type - Text - Shape: vierkant
Type - Structural Section Geometry - Centroid Horizontal: 60 mm; Centroid Vertical: 60 mm; Height: 120 mm; Inner Fillet: 2.7 mm; Outer Fillet: 9 mm; Wall Nominal Thickness: 6.3 mm; Width: 120 mm
Type - Pset_ColumnCommon - LoadBearing: yes; IsExternal: no
Type - Pset_ManufacturerTypeInformation - Manufacturer: generiek
Type - Pset_ProductRequirements - Category: Structural Columns
Type - Pset_ReinforcementBarPitchOfColumn - Description: K120x120x4 betongevuld
Classification: 28.10 Uniformat (Uniformat)
BaseQuantities - CrossSectionArea: 0.00280191 m2
Pset_ColumnCommon - IsExternal: yes; Reference: kolom betongevuld K120x120x6.3
Pset_PrecastConcreteElementGeneral - ElementWeight: 0 kg
Pset_QuantityTakeOff - Reference: kolom betongevuld K120x120x6.3; sets with these values: 2
Pset_Structural Column - Omschrijving: K120x120x4 betongevuld; NL-sfb-Codering: 28.10; Structural Material: h2_staal
Pset_DAT_KMS - Assembly Code: 28.10; Assembly Description: hoofddraagconstructies; kolommen en liggers, algemeen (verzamelniveau); Description: K120x120x4 betongevuld
Other - Family: NLRS_28_SCO_TLB_kolom koker betongevuld_gen_ASN; Family and Type: NLRS_28_SCO_TLB_kolom koker betongevuld_gen_ASN: kolom betongevuld K120x120x6.3; Type: kolom betongevuld K120x120x6.3; Type Id: 5966896
Constraints - Base Offset: 0 mm; Column Style: Vertical; Moves With Grids: yes; Base Level: 1; Level: 1; Top Level: V2 ok. ruwe vloer
Dimensions - NLRS_C_hoogte: 120 mm
Identity Data - Has Association: no; Workset: Constructie
Materials and Finishes - materiaal_vulling: f2_beton; Structural Material: h2_staal
Phasing - Phase Created: 2. nieuwbouw
Name (NLRS_28_SCO_TLB_kolom koker betongevuld_gen_ASN:kolom betongevuld K120x120x6.3:...) | BaseQuantities, Length (mm) = Dimensions, Length (mm) | OuterSurfaceArea (m2) | GrossVolume (m3) | NetVolume (m3) = Volume (m3) | Column Location Mark | Top Offset (mm)
4744863 | 3180 | 2.82865 | 0.00891006 | 0.0455225 | K-9 | -60
4752873 | 3240 | 2.88202 | 0.00907818 | 0.0463814 | A-9 | 0
4752885 | 3240 | 2.88202 | 0.00907818 | 0.0463814 | J-1 | 0

# IfcColumn: NLRS_28_SCO_TLB_kolom koker betongevuld_gen_ASN:kolom betongevuld K120x120x8 (19)
Type - PredefinedType: COLUMN; Material: f2_beton, h2_staal
Type - Other - Category: Structural Columns; Family Name: NLRS_28_SCO_TLB_kolom koker betongevuld_gen_ASN
Type - Dimensions - b: 120 mm; h: 120 mm; r: 9 mm; r_inw: 1 mm; t: 8 mm; Wall Design Thickness: 8 mm
Type - General - NLRS_C_content_creator: Arkance Systems; NLRS_C_content_datum_gewijzigd: 2022.05.27; NLRS_C_content_provider: Arkance Systems; NLRS_C_content_versie: 2.1; NLRS_C_revit_versie: 2021
Type - Identity Data - Assembly Code: 28.10; Assembly Description: hoofddraagconstructies; kolommen en liggers, algemeen (verzamelniveau); Description: K120x120x4 betongevuld; Manufacturer: generiek; Model: kokerprofiel (gelijkzijdig), beton gevuld; Type Name: kolom betongevuld K120x120x8; Workset: Family : Structural Columns : NLRS_28_SCO_TLB_kolom koker betongevuld_gen_ASN
Type - Structural - Section Shape: 14; SG: 0
Type - Text - Shape: vierkant
Type - Structural Section Geometry - Centroid Horizontal: 60 mm; Centroid Vertical: 60 mm; Height: 120 mm; Inner Fillet: 1 mm; Outer Fillet: 9 mm; Wall Nominal Thickness: 8 mm; Width: 120 mm
Type - Pset_ColumnCommon - LoadBearing: yes; IsExternal: no
Type - Pset_ManufacturerTypeInformation - Manufacturer: generiek
Type - Pset_ProductRequirements - Category: Structural Columns
Type - Pset_ReinforcementBarPitchOfColumn - Description: K120x120x4 betongevuld
Classification: 28.10 Uniformat (Uniformat)
BaseQuantities - CrossSectionArea: 0.00351526 m2
Pset_ColumnCommon - IsExternal: yes; Reference: kolom betongevuld K120x120x8
Pset_PrecastConcreteElementGeneral - ElementWeight: 0 kg
Pset_QuantityTakeOff - Reference: kolom betongevuld K120x120x8; sets with these values: 2
Pset_Structural Column - Omschrijving: K120x120x4 betongevuld; NL-sfb-Codering: 28.10; Structural Material: h2_staal
Pset_DAT_KMS - Assembly Code: 28.10; Assembly Description: hoofddraagconstructies; kolommen en liggers, algemeen (verzamelniveau); Description: K120x120x4 betongevuld
Other - Family: NLRS_28_SCO_TLB_kolom koker betongevuld_gen_ASN; Family and Type: NLRS_28_SCO_TLB_kolom koker betongevuld_gen_ASN: kolom betongevuld K120x120x8; Type: kolom betongevuld K120x120x8; Type Id: 4741679
Constraints - Base Offset: 0 mm; Column Style: Vertical; Moves With Grids: yes
Dimensions - NLRS_C_hoogte: 120 mm
Identity Data - Has Association: no
Materials and Finishes - materiaal_vulling: f2_beton; Structural Material: h2_staal
Phasing - Phase Created: 2. nieuwbouw
Name (NLRS_28_SCO_TLB_kolom koker betongevuld_gen_ASN:kolom betongevuld K120x120x8:...) | In | BaseQuantities, Length (mm) = Dimensions, Length (mm) | OuterSurfaceArea (m2) | GrossVolume (m3) | NetVolume (m3) = Volume (m3) | Level = Base Level | Column Location Mark | Top Level | Top Offset (mm) | Workset
4744239 | 00 Begane grond | 3240 | 2.84742 | 0.0113894 | 0.0463639 | 0 | K-8 | V1 ok. ruwe vloer | 0 | Constructie
4744399 | 00 Begane grond | 3240 | 2.84742 | 0.0113894 | 0.0463639 | 0 | K(-2140)-10 | V1 ok. ruwe vloer | 0 | Constructie
4744554 | 00 Begane grond | 3240 | 2.84742 | 0.0113894 | 0.0463639 | 0 | B(3600)-8 | V1 ok. ruwe vloer | 0 | Constructie
4744564 | 00 Begane grond | 3240 | 2.84742 | 0.0113894 | 0.0463639 | 0 | C(-1200)-8 | V1 ok. ruwe vloer | 0 | Constructie
4773191 | 00 Begane grond | 3240 | 2.84742 | 0.0113894 | 0.0463639 | 0 | K-10 | V1 ok. ruwe vloer | 0 | Constructie
4900009 | 00 Begane grond | 3240 | 2.84742 | 0.0113894 | 0.0463639 | 0 | K-10(-2550) | V1 ok. ruwe vloer | 0 | Constructie
4919942 | 01 eerste verdieping | 3180 | 2.79469 | 0.0111785 | 0.0455053 | 1 | C(3600)-10 | V2 ok. ruwe vloer | -60 | Bouwkundig
4957412 | 00 Begane grond | 3240 | 2.84742 | 0.0113894 | 0.0463639 | 0 | G-2 | V1 ok. ruwe vloer | 0 | Constructie
4957413 | 00 Begane grond | 3240 | 2.84742 | 0.0113894 | 0.0463639 | 0 | G-3(2400) | V1 ok. ruwe vloer | 0 | Constructie
4957414 | 00 Begane grond | 3240 | 2.84742 | 0.0113894 | 0.0463639 | 0 | G-4(-2400) | V1 ok. ruwe vloer | 0 | Constructie
4957415 | 00 Begane grond | 3240 | 2.84742 | 0.0113894 | 0.0463639 | 0 | G-4 | V1 ok. ruwe vloer | 0 | Constructie
4957416 | 00 Begane grond | 3240 | 2.84742 | 0.0113894 | 0.0463639 | 0 | G-5 | V1 ok. ruwe vloer | 0 | Constructie
4957417 | 00 Begane grond | 3240 | 2.84742 | 0.0113894 | 0.0463639 | 0 | G-6(-1800) | V1 ok. ruwe vloer | 0 | Constructie
4957418 | 00 Begane grond | 3240 | 2.84742 | 0.0113894 | 0.0463639 | 0 | G-6(600) | V1 ok. ruwe vloer | 0 | Constructie
4957448 | 00 Begane grond | 3240 | 2.84742 | 0.0113894 | 0.0463639 | 0 | G-3 | V1 ok. ruwe vloer | 0 | Constructie
5329930 | 01 eerste verdieping | 3180 | 2.79469 | 0.0111785 | 0.0455053 | 1 | K-6(-600) | V2 ok. ruwe vloer | -60 | Bouwkundig
5966502 | 00 Begane grond | 3240 | 2.84742 | 0.0113894 | 0.0463639 | 0 | F(1812)-7 | V1 ok. ruwe vloer | 0 | Constructie
5966512 | 00 Begane grond | 3240 | 2.84742 | 0.0113894 | 0.0463639 | 0 | C(2642)-8 | V1 ok. ruwe vloer | 0 | Constructie
5966673 | 00 Begane grond | 3240 | 2.84742 | 0.0113894 | 0.0463639 | 0 | H-10 | V1 ok. ruwe vloer | 0 | Constructie

# IfcColumn: NLRS_28_SCO_TLB_kolom koker betongevuld_gen_ASN:kolom betongevuld K150x150x6.3 (6)
Type - PredefinedType: COLUMN; Material: f2_beton, h2_staal
Type - Other - Category: Structural Columns; Family Name: NLRS_28_SCO_TLB_kolom koker betongevuld_gen_ASN
Type - Dimensions - b: 150 mm; h: 150 mm; r: 13 mm; r_inw: 6.7 mm; t: 6.3 mm; Wall Design Thickness: 6.3 mm
Type - General - NLRS_C_content_creator: Arkance Systems; NLRS_C_content_datum_gewijzigd: 2022.05.27; NLRS_C_content_provider: Arkance Systems; NLRS_C_content_versie: 2.1; NLRS_C_revit_versie: 2021
Type - Identity Data - Workset: Family : Structural Columns : NLRS_28_SCO_TLB_kolom koker betongevuld_gen_ASN; Assembly Code: 28.10; Assembly Description: hoofddraagconstructies; kolommen en liggers, algemeen (verzamelniveau); Description: K150x150x8 betongevuld; Manufacturer: generiek; Model: kokerprofiel (gelijkzijdig), beton gevuld; Type Name: kolom betongevuld K150x150x6.3
Type - Structural - SG: 0; Section Shape: 14
Type - Text - Shape: vierkant
Type - Structural Section Geometry - Centroid Horizontal: 75 mm; Centroid Vertical: 75 mm; Height: 150 mm; Inner Fillet: 6.7 mm; Outer Fillet: 13 mm; Wall Nominal Thickness: 6.3 mm; Width: 150 mm
Type - Pset_ColumnCommon - LoadBearing: yes; IsExternal: no
Type - Pset_ManufacturerTypeInformation - Manufacturer: generiek
Type - Pset_ProductRequirements - Category: Structural Columns
Type - Pset_ReinforcementBarPitchOfColumn - Description: K150x150x8 betongevuld
Classification: 28.10 Uniformat (Uniformat)
BaseQuantities - CrossSectionArea: 0.00351461 m2
Pset_ColumnCommon - IsExternal: yes; Reference: kolom betongevuld K150x150x6.3
Pset_PrecastConcreteElementGeneral - ElementWeight: 0 kg
Pset_QuantityTakeOff - Reference: kolom betongevuld K150x150x6.3; sets with these values: 2
Pset_Structural Column - Omschrijving: K150x150x8 betongevuld; NL-sfb-Codering: 28.10; Structural Material: h2_staal
Pset_DAT_KMS - Assembly Code: 28.10; Assembly Description: hoofddraagconstructies; kolommen en liggers, algemeen (verzamelniveau); Description: K150x150x8 betongevuld
Other - Family: NLRS_28_SCO_TLB_kolom koker betongevuld_gen_ASN; Family and Type: NLRS_28_SCO_TLB_kolom koker betongevuld_gen_ASN: kolom betongevuld K150x150x6.3; Type: kolom betongevuld K150x150x6.3; Type Id: 5939945
Constraints - Column Style: Vertical; Moves With Grids: yes; Top Level: V2 ok. ruwe vloer; Top Offset: -60 mm
Dimensions - NLRS_C_hoogte: 150 mm
Identity Data - Has Association: no
Materials and Finishes - materiaal_vulling: f2_beton; Structural Material: h2_staal
Phasing - Phase Created: 2. nieuwbouw
Name (NLRS_28_SCO_TLB_kolom koker betongevuld_gen_ASN:kolom betongevuld K150x150x6.3:...) | In | BaseQuantities, Length (mm) = Dimensions, Length (mm) | OuterSurfaceArea (m2) | GrossVolume (m3) | NetVolume (m3) = Volume (m3) | Base Offset (mm) | Base Level = Level | Column Location Mark | Workset
4744621 | 01 eerste verdieping | 3180 | 3.54818 | 0.0111765 | 0.0711428 | 0 | 1 | F(-560)-10 | Constructie
4744631 | 01 eerste verdieping | 3620 | 4.03912 | 0.0127229 | 0.0809865 | -440 | 1 | F(510)-10 | Constructie
4744643 | 01 eerste verdieping | 4870 | 5.43384 | 0.0171162 | 0.108951 | -1690 | 1 | G(-1850)-10 | Constructie
4744653 | 00 Begane grond | 6900 | 7.69887 | 0.0242508 | 0.154367 | 0 | V0 bk. ruwe vloer | G(-780)-10 | Constructie
5940110 | 01 eerste verdieping | 3180 | 3.54818 | 0.0111765 | 0.0711428 | 0 | 1 | F(1580)-10 | Bouwkundig
5966674 | 01 eerste verdieping | 4245 | 4.73648 | 0.0149195 | 0.094969 | -1065 | 1 | F(1580)-10 | Constructie

# IfcColumn: NLRS_28_SCO_TLB_kolom koker betongevuld_gen_ASN:kolom betongevuld K150x150x8 (4)
In: 00 Begane grond
Type - PredefinedType: COLUMN; Material: f2_beton, h2_staal
Type - Other - Category: Structural Columns; Family Name: NLRS_28_SCO_TLB_kolom koker betongevuld_gen_ASN
Type - Dimensions - b: 150 mm; h: 150 mm; r: 13 mm; r_inw: 5 mm; t: 8 mm; Wall Design Thickness: 8 mm
Type - General - NLRS_C_content_creator: Arkance Systems; NLRS_C_content_datum_gewijzigd: 2022.05.27; NLRS_C_content_provider: Arkance Systems; NLRS_C_content_versie: 2.1; NLRS_C_revit_versie: 2021
Type - Identity Data - Workset: Family : Structural Columns : NLRS_28_SCO_TLB_kolom koker betongevuld_gen_ASN; Assembly Code: 28.10; Assembly Description: hoofddraagconstructies; kolommen en liggers, algemeen (verzamelniveau); Description: K150x150x8 betongevuld; Manufacturer: generiek; Model: kokerprofiel (gelijkzijdig), beton gevuld; Type Name: kolom betongevuld K150x150x8
Type - Structural - SG: 0; Section Shape: 14
Type - Text - Shape: vierkant
Type - Structural Section Geometry - Centroid Horizontal: 75 mm; Centroid Vertical: 75 mm; Height: 150 mm; Inner Fillet: 5 mm; Outer Fillet: 13 mm; Wall Nominal Thickness: 8 mm; Width: 150 mm
Type - Pset_ColumnCommon - LoadBearing: yes; IsExternal: no
Type - Pset_ManufacturerTypeInformation - Manufacturer: generiek
Type - Pset_ProductRequirements - Category: Structural Columns
Type - Pset_ReinforcementBarPitchOfColumn - Description: K150x150x8 betongevuld
Classification: 28.10 Uniformat (Uniformat)
BaseQuantities - CrossSectionArea: 0.00442028 m2
Pset_ColumnCommon - IsExternal: yes; Reference: kolom betongevuld K150x150x8
Pset_PrecastConcreteElementGeneral - ElementWeight: 0 kg
Pset_QuantityTakeOff - Reference: kolom betongevuld K150x150x8; sets with these values: 2
Pset_Structural Column - Omschrijving: K150x150x8 betongevuld; NL-sfb-Codering: 28.10; Structural Material: h2_staal
Pset_DAT_KMS - Assembly Code: 28.10; Assembly Description: hoofddraagconstructies; kolommen en liggers, algemeen (verzamelniveau); Description: K150x150x8 betongevuld
Other - Family: NLRS_28_SCO_TLB_kolom koker betongevuld_gen_ASN; Family and Type: NLRS_28_SCO_TLB_kolom koker betongevuld_gen_ASN: kolom betongevuld K150x150x8; Type: kolom betongevuld K150x150x8; Type Id: 4742762
Constraints - Base Offset: 0 mm; Level: 0; Base Level: 0; Column Style: Vertical; Moves With Grids: yes
Dimensions - NLRS_C_hoogte: 150 mm
Identity Data - Has Association: no
Materials and Finishes - materiaal_vulling: f2_beton; Structural Material: h2_staal
Phasing - Phase Created: 2. nieuwbouw
Name (NLRS_28_SCO_TLB_kolom koker betongevuld_gen_ASN:kolom betongevuld K150x150x8:...) | BaseQuantities, Length (mm) = Dimensions, Length (mm) | OuterSurfaceArea (m2) | GrossVolume (m3) | NetVolume (m3) = Volume (m3) | Top Level | Top Offset (mm) | Column Location Mark | Workset
4773327 | 3240 | 3.58052 | 0.0143217 | 0.0724298 | V1 ok. ruwe vloer | 0 | J(-1290)-10 | Constructie
5290344 | 2500 | 2.76274 | 0.0110507 | 0.0558872 | 0 | 2500 | G(290)-10 | Bouwkundig
5966487 | 3240 | 3.58052 | 0.0143217 | 0.0724298 | V1 ok. ruwe vloer | 0 | G-7 | Constructie
5966672 | 3240 | 3.58052 | 0.0143217 | 0.0724298 | V1 ok. ruwe vloer | 0 | K-9 | Constructie

# IfcColumn: NLRS_28_SCO_TLB_kolom koker betongevuld_gen_ASN:kolom betongevuld K150x70x6.3 (30)
In: 00 Begane grond
Type - PredefinedType: COLUMN; Material: ISR_Beton ihwg, ISR_RAL 7006
Type - Other - Category: Structural Columns; Family Name: NLRS_28_SCO_TLB_kolom koker betongevuld_gen_ASN
Type - Dimensions - b: 70 mm; h: 150 mm; r: 13 mm; r_inw: 6.7 mm; t: 6.3 mm; Wall Design Thickness: 6.3 mm
Type - General - NLRS_C_content_creator: Arkance Systems; NLRS_C_content_datum_gewijzigd: 2022.05.27; NLRS_C_content_provider: Arkance Systems; NLRS_C_content_versie: 2.1; NLRS_C_revit_versie: 2021
Type - Identity Data - Workset: Family : Structural Columns : NLRS_28_SCO_TLB_kolom koker betongevuld_gen_ASN; Assembly Code: 28.10; Assembly Description: hoofddraagconstructies; kolommen en liggers, algemeen (verzamelniveau); Description: K150x150x8 betongevuld; Manufacturer: generiek; Model: kokerprofiel (gelijkzijdig), beton gevuld; Type Name: kolom betongevuld K150x70x6.3
Type - Structural - SG: 0; Section Shape: 14
Type - Text - Shape: vierkant
Type - Structural Section Geometry - Centroid Horizontal: 35 mm; Centroid Vertical: 75 mm; Height: 150 mm; Inner Fillet: 6.7 mm; Outer Fillet: 13 mm; Wall Nominal Thickness: 6.3 mm; Width: 70 mm
Type - Pset_ColumnCommon - LoadBearing: yes; IsExternal: no
Type - Pset_ManufacturerTypeInformation - Manufacturer: generiek
Type - Pset_ProductRequirements - Category: Structural Columns
Type - Pset_ReinforcementBarPitchOfColumn - Description: K150x150x8 betongevuld
Classification: 28.10 Uniformat (Uniformat)
BaseQuantities - Length: 2120 mm; CrossSectionArea: 0.00250662 m2; OuterSurfaceArea: 1.68705 m2; GrossVolume: 0.00531404 m3; NetVolume: 0.0219886 m3
Pset_ColumnCommon - IsExternal: yes; Reference: kolom betongevuld K150x70x6.3
Pset_PrecastConcreteElementGeneral - ElementWeight: 0 kg
Pset_QuantityTakeOff - Reference: kolom betongevuld K150x70x6.3; sets with these values: 2
Pset_Structural Column - Omschrijving: K150x150x8 betongevuld; NL-sfb-Codering: 28.10; Structural Material: ISR_RAL 7006
Pset_DAT_KMS - Assembly Code: 28.10; Assembly Description: hoofddraagconstructies; kolommen en liggers, algemeen (verzamelniveau); Description: K150x150x8 betongevuld
Other - Family: NLRS_28_SCO_TLB_kolom koker betongevuld_gen_ASN; Family and Type: NLRS_28_SCO_TLB_kolom koker betongevuld_gen_ASN: kolom betongevuld K150x70x6.3; Type: kolom betongevuld K150x70x6.3; Type Id: 6494371
Constraints - Base Offset: 0 mm; Level: 0; Base Level: 0; Column Style: Vertical; Moves With Grids: yes; Top Level: 0; Top Offset: 2120 mm
Dimensions - Length: 2120 mm; NLRS_C_hoogte: 150 mm; Volume: 0.0219886 m3
Identity Data - Has Association: no; Workset: situatie
Materials and Finishes - Structural Material: ISR_RAL 7006
Phasing - Phase Created: 2. nieuwbouw
Name (NLRS_28_SCO_TLB_kolom koker betongevuld_gen_ASN:kolom betongevuld K150x70x6.3:...) | Column Location Mark
6494767 | A(-2586)-7(-733)
6494877 | A(-2586)-6(297)
6494951 | A(-2586)-6(-1673)
6494964 | A(-2586)-5(557)
6494975 | A(-2586)-5(-1413)
6495080 | A(-2586)-4(217)
6495109 | A(-2586)-4(-1753)
6495118 | A(-2586)-3(3477)
6495153 | A(-2586)-3(1507)
6495154 | A(-2586)-3(-463)
6495155 | A(-2586)-2(1167)
6495156 | A(-2586)-2(-803)
6495165 | A(-2586)-2(-2773)
6495166 | A(-2586)-1(2457)
6495167 | A(-2586)-1(487)
6495193 | A(-4646)-7(-733)
6495194 | A(-4646)-6(297)
6495195 | A(-4646)-6(-1673)
6495196 | A(-4646)-5(557)
6495197 | A(-4646)-5(-1413)
6495198 | A(-4646)-4(217)
6495199 | A(-4646)-4(-1753)
6495200 | A(-4646)-3(3477)
6495201 | A(-4646)-3(1507)
6495202 | A(-4646)-3(-463)
6495203 | A(-4646)-2(1167)
6495204 | A(-4646)-2(-803)
6495205 | A(-4646)-2(-2773)
6495206 | A(-4646)-1(2457)
6495207 | A(-4646)-1(487)

# IfcColumn: NLRS_28_SCO_TLB_kolom koker betongevuld_gen_ASN:kolom betongevuld K160x160x6.3 (13)
Type - PredefinedType: COLUMN; Material: f2_beton, h2_staal
Type - Other - Category: Structural Columns; Family Name: NLRS_28_SCO_TLB_kolom koker betongevuld_gen_ASN
Type - Dimensions - b: 160 mm; h: 160 mm; r: 13 mm; r_inw: 6.7 mm; t: 6.3 mm; Wall Design Thickness: 6.3 mm
Type - General - NLRS_C_content_creator: Arkance Systems; NLRS_C_content_datum_gewijzigd: 2022.05.27; NLRS_C_content_provider: Arkance Systems; NLRS_C_content_versie: 2.1; NLRS_C_revit_versie: 2021
Type - Identity Data - Workset: Family : Structural Columns : NLRS_28_SCO_TLB_kolom koker betongevuld_gen_ASN; Assembly Code: 28.10; Assembly Description: hoofddraagconstructies; kolommen en liggers, algemeen (verzamelniveau); Description: K160x160x8 betongevuld; Manufacturer: generiek; Model: kokerprofiel (gelijkzijdig), beton gevuld; Type Name: kolom betongevuld K160x160x6.3
Type - Structural - SG: 0; Section Shape: 14
Type - Text - Shape: vierkant
Type - Structural Section Geometry - Centroid Horizontal: 80 mm; Centroid Vertical: 80 mm; Height: 160 mm; Inner Fillet: 6.7 mm; Outer Fillet: 13 mm; Wall Nominal Thickness: 6.3 mm; Width: 160 mm
Type - Pset_ColumnCommon - LoadBearing: yes; IsExternal: no
Type - Pset_ManufacturerTypeInformation - Manufacturer: generiek
Type - Pset_ProductRequirements - Category: Structural Columns
Type - Pset_ReinforcementBarPitchOfColumn - Description: K160x160x8 betongevuld
Classification: 28.10 Uniformat (Uniformat)
BaseQuantities - CrossSectionArea: 0.00376661 m2
Pset_ColumnCommon - IsExternal: yes; Reference: kolom betongevuld K160x160x6.3
Pset_PrecastConcreteElementGeneral - ElementWeight: 0 kg
Pset_QuantityTakeOff - Reference: kolom betongevuld K160x160x6.3; sets with these values: 2
Pset_Structural Column - Omschrijving: K160x160x8 betongevuld; NL-sfb-Codering: 28.10; Structural Material: h2_staal
Pset_DAT_KMS - Assembly Code: 28.10; Assembly Description: hoofddraagconstructies; kolommen en liggers, algemeen (verzamelniveau); Description: K160x160x8 betongevuld
Other - Family: NLRS_28_SCO_TLB_kolom koker betongevuld_gen_ASN; Family and Type: NLRS_28_SCO_TLB_kolom koker betongevuld_gen_ASN: kolom betongevuld K160x160x6.3; Type: kolom betongevuld K160x160x6.3; Type Id: 5966651
Constraints - Base Offset: 0 mm; Column Style: Vertical; Moves With Grids: yes
Dimensions - NLRS_C_hoogte: 160 mm
Identity Data - Has Association: no; Workset: Constructie
Materials and Finishes - materiaal_vulling: f2_beton; Structural Material: h2_staal
Phasing - Phase Created: 2. nieuwbouw
Name (NLRS_28_SCO_TLB_kolom koker betongevuld_gen_ASN:kolom betongevuld K160x160x6.3:...) | In | BaseQuantities, Length (mm) = Dimensions, Length (mm) | OuterSurfaceArea (m2) | GrossVolume (m3) | NetVolume (m3) = Volume (m3) | Top Offset (mm) | Base Level = Level | Top Level | Column Location Mark
4752874 | 01 eerste verdieping | 3240 | 3.87432 | 0.0122038 | 0.0825291 | 0 | 1 | V2 ok. ruwe vloer | B-9
4752875 | 01 eerste verdieping | 3240 | 3.87432 | 0.0122038 | 0.0825291 | 0 | 1 | V2 ok. ruwe vloer | C-9
4752876 | 01 eerste verdieping | 3240 | 3.87432 | 0.0122038 | 0.0825291 | 0 | 1 | V2 ok. ruwe vloer | D-9
4752879 | 01 eerste verdieping | 3240 | 3.87432 | 0.0122038 | 0.0825291 | 0 | 1 | V2 ok. ruwe vloer | E-9
4752880 | 01 eerste verdieping | 3240 | 3.87432 | 0.0122038 | 0.0825291 | 0 | 1 | V2 ok. ruwe vloer | J-7
4752881 | 01 eerste verdieping | 3240 | 3.87432 | 0.0122038 | 0.0825291 | 0 | 1 | V2 ok. ruwe vloer | J-5
4752882 | 01 eerste verdieping | 3240 | 3.87432 | 0.0122038 | 0.0825291 | 0 | 1 | V2 ok. ruwe vloer | J-4
4752883 | 01 eerste verdieping | 3240 | 3.87432 | 0.0122038 | 0.0825291 | 0 | 1 | V2 ok. ruwe vloer | J-3
4752884 | 01 eerste verdieping | 3240 | 3.87432 | 0.0122038 | 0.0825291 | 0 | 1 | V2 ok. ruwe vloer | J-2
4752886 | 01 eerste verdieping | 3240 | 3.87432 | 0.0122038 | 0.0825291 | 0 | 1 | V2 ok. ruwe vloer | J-8
4772434 | 00 Begane grond | 3240 | 3.87432 | 0.0122038 | 0.0825291 | 0 | 0 | V1 ok. ruwe vloer | H-9
4772540 | 01 eerste verdieping | 3180 | 3.80258 | 0.0119778 | 0.0810008 | -60 | 1 | V2 ok. ruwe vloer | H-9
4772541 | 01 eerste verdieping | 3180 | 3.80258 | 0.0119778 | 0.0810008 | -60 | 1 | V2 ok. ruwe vloer | I-9

# IfcColumn: NLRS_28_SCO_TLB_kolom koker betongevuld_gen_ASN:kolom betongevuld K220x220x10 (2)
In: 00 Begane grond
Type - PredefinedType: COLUMN; Material: f2_beton, h2_staal
Type - Other - Category: Structural Columns; Family Name: NLRS_28_SCO_TLB_kolom koker betongevuld_gen_ASN
Type - Dimensions - b: 220 mm; h: 220 mm; r: 13 mm; r_inw: 3 mm; t: 10 mm; Wall Design Thickness: 10 mm
Type - General - NLRS_C_content_creator: Arkance Systems; NLRS_C_content_datum_gewijzigd: 2022.05.27; NLRS_C_content_provider: Arkance Systems; NLRS_C_content_versie: 2.1; NLRS_C_revit_versie: 2021
Type - Identity Data - Workset: Family : Structural Columns : NLRS_28_SCO_TLB_kolom koker betongevuld_gen_ASN; Assembly Code: 28.10; Assembly Description: hoofddraagconstructies; kolommen en liggers, algemeen (verzamelniveau); Description: K220x220x8 betongevuld; Manufacturer: generiek; Model: kokerprofiel (gelijkzijdig), beton gevuld; Type Name: kolom betongevuld K220x220x10
Type - Structural - SG: 0; Section Shape: 14
Type - Text - Shape: vierkant
Type - Structural Section Geometry - Centroid Horizontal: 110 mm; Centroid Vertical: 110 mm; Height: 220 mm; Inner Fillet: 3 mm; Outer Fillet: 13 mm; Wall Nominal Thickness: 10 mm; Width: 220 mm
Type - Pset_ColumnCommon - LoadBearing: yes; IsExternal: no
Type - Pset_ManufacturerTypeInformation - Manufacturer: generiek
Type - Pset_ProductRequirements - Category: Structural Columns
Type - Pset_ReinforcementBarPitchOfColumn - Description: K220x220x8 betongevuld
Classification: 28.10 Uniformat (Uniformat)
BaseQuantities - Length: 3240 mm; CrossSectionArea: 0.0082625 m2; OuterSurfaceArea: 5.3542 m2; GrossVolume: 0.0267705 m3; NetVolume: 0.156301 m3
Pset_ColumnCommon - IsExternal: yes; Reference: kolom betongevuld K220x220x10
Pset_PrecastConcreteElementGeneral - ElementWeight: 0 kg
Pset_QuantityTakeOff - Reference: kolom betongevuld K220x220x10; sets with these values: 2
Pset_Structural Column - Omschrijving: K220x220x8 betongevuld; NL-sfb-Codering: 28.10; Structural Material: h2_staal
Pset_DAT_KMS - Assembly Code: 28.10; Assembly Description: hoofddraagconstructies; kolommen en liggers, algemeen (verzamelniveau); Description: K220x220x8 betongevuld
Other - Family: NLRS_28_SCO_TLB_kolom koker betongevuld_gen_ASN; Family and Type: NLRS_28_SCO_TLB_kolom koker betongevuld_gen_ASN: kolom betongevuld K220x220x10; Type: kolom betongevuld K220x220x10; Type Id: 5966588
Constraints - Base Offset: 0 mm; Level: 0; Base Level: 0; Column Style: Vertical; Moves With Grids: yes; Top Level: V1 ok. ruwe vloer; Top Offset: 0 mm
Dimensions - Length: 3240 mm; NLRS_C_hoogte: 220 mm; Volume: 0.156301 m3
Identity Data - Has Association: no; Workset: Constructie
Materials and Finishes - materiaal_vulling: f2_beton; Structural Material: h2_staal
Phasing - Phase Created: 2. nieuwbouw
Name (NLRS_28_SCO_TLB_kolom koker betongevuld_gen_ASN:kolom betongevuld K220x220x10:...) | Column Location Mark
4751013 | D-8
4751025 | E-8

# IfcColumn: NLRS_28_SCO_TLB_kolom koker betongevuld_gen_ASN:kolom betongevuld K220x220x8 (11)
In: 00 Begane grond
Type - PredefinedType: COLUMN; Material: f2_beton, h2_staal
Type - Other - Category: Structural Columns; Family Name: NLRS_28_SCO_TLB_kolom koker betongevuld_gen_ASN
Type - Dimensions - b: 220 mm; h: 220 mm; r: 13 mm; r_inw: 5 mm; t: 8 mm; Wall Design Thickness: 8 mm
Type - General - NLRS_C_content_creator: Arkance Systems; NLRS_C_content_datum_gewijzigd: 2022.05.27; NLRS_C_content_provider: Arkance Systems; NLRS_C_content_versie: 2.1; NLRS_C_revit_versie: 2021
Type - Identity Data - Workset: Family : Structural Columns : NLRS_28_SCO_TLB_kolom koker betongevuld_gen_ASN; Assembly Code: 28.10; Assembly Description: hoofddraagconstructies; kolommen en liggers, algemeen (verzamelniveau); Description: K220x220x8 betongevuld; Manufacturer: generiek; Model: kokerprofiel (gelijkzijdig), beton gevuld; Type Name: kolom betongevuld K220x220x8
Type - Structural - SG: 0; Section Shape: 14
Type - Text - Shape: vierkant
Type - Structural Section Geometry - Centroid Horizontal: 110 mm; Centroid Vertical: 110 mm; Height: 220 mm; Inner Fillet: 5 mm; Outer Fillet: 13 mm; Wall Nominal Thickness: 8 mm; Width: 220 mm
Type - Pset_ColumnCommon - LoadBearing: yes; IsExternal: no
Type - Pset_ManufacturerTypeInformation - Manufacturer: generiek
Type - Pset_ProductRequirements - Category: Structural Columns
Type - Pset_ReinforcementBarPitchOfColumn - Description: K220x220x8 betongevuld
Classification: 28.10 Uniformat (Uniformat)
BaseQuantities - Length: 3240 mm; CrossSectionArea: 0.00666026 m2; OuterSurfaceArea: 5.39492 m2; GrossVolume: 0.0215792 m3; NetVolume: 0.156346 m3
Pset_ColumnCommon - IsExternal: yes; Reference: kolom betongevuld K220x220x8
Pset_PrecastConcreteElementGeneral - ElementWeight: 0 kg
Pset_QuantityTakeOff - Reference: kolom betongevuld K220x220x8; sets with these values: 2
Pset_Structural Column - Omschrijving: K220x220x8 betongevuld; NL-sfb-Codering: 28.10; Structural Material: h2_staal
Pset_DAT_KMS - Assembly Code: 28.10; Assembly Description: hoofddraagconstructies; kolommen en liggers, algemeen (verzamelniveau); Description: K220x220x8 betongevuld
Other - Family: NLRS_28_SCO_TLB_kolom koker betongevuld_gen_ASN; Family and Type: NLRS_28_SCO_TLB_kolom koker betongevuld_gen_ASN: kolom betongevuld K220x220x8; Type: kolom betongevuld K220x220x8; Type Id: 4750816
Constraints - Base Offset: 0 mm; Level: 0; Base Level: 0; Column Style: Vertical; Moves With Grids: yes; Top Level: V1 ok. ruwe vloer; Top Offset: 0 mm
Dimensions - Length: 3240 mm; NLRS_C_hoogte: 220 mm; Volume: 0.156346 m3
Identity Data - Has Association: no; Workset: Constructie
Materials and Finishes - materiaal_vulling: f2_beton; Structural Material: h2_staal
Phasing - Phase Created: 2. nieuwbouw
Name (NLRS_28_SCO_TLB_kolom koker betongevuld_gen_ASN:kolom betongevuld K220x220x8:...) | Column Location Mark
4750977 | B-9
4750993 | C-9
4751003 | D-9
4751035 | E-9
4751045 | J-7
4751055 | J-5
4751065 | J-4
4751077 | J-3
4751085 | J-2
4751109 | J-8
4772435 | I-9

# IfcCovering: Compound Ceiling:300_45_Gipsplaat_25mm, Compound Ceiling:300_45_Gipsplaat_25mm:5253457
In: 0.33
Type - PredefinedType: CEILING
Type - Other - Category: Ceilings; Family Name: Compound Ceiling
Type - Construction - Thickness: 25 mm
Type - Graphics - Coarse Scale Fill Pattern: <Solid fill>; Coarse Scale Fill Color: 0
Type - Identity Data - Workset: Ceiling Types; Assembly Code: 45.21; Assembly Description: plafondafwerkingen; niet verlaagd, afwerkingen; Description: Houtwolcementplaat plafond; Type Name: 300_45_Gipsplaat_25mm
Type - Analytical Properties - Roughness: 1; Absorptance: 0.1
Type - Pset_CoveringCommon - TotalThickness: 25 mm
Type - Pset_ElementShading - Roughness: 304.8 mm
Type - Pset_ProductRequirements - Category: Ceilings
Classification: 45.21 Uniformat (Uniformat); Material: ISR_Plafond 25 mm
Pset_CoveringCommon - Reference: 300_45_Gipsplaat_25mm; Finish: ISR_Plafond;
Pset_QuantityTakeOff - Reference: 300_45_Gipsplaat_25mm
Pset_Plafonds - Family and Type: Compound Ceiling: 300_45_Gipsplaat_25mm; Level: V0 ok. plafond; Omschrijving: Houtwolcementplaat plafond; NL-sfb-Codering: 45.21; Area: 8.1151 m2
Pset_DAT_KMS - Assembly Code: 45.21; Assembly Description: plafondafwerkingen; niet verlaagd, afwerkingen; Description: Houtwolcementplaat plafond
BaseQuantities - GrossCeilingArea: 8.1151 m2
Other - Family: Compound Ceiling; Family and Type: Compound Ceiling: 300_45_Gipsplaat_25mm; Type: 300_45_Gipsplaat_25mm; Type Id: 5148505
Constraints - Room Bounding: yes; Height Offset From Level: 0 mm; Level: V0 ok. plafond
Dimensions - Area: 8.1151 m2; Perimeter: 11507 mm; Volume: 0.202877 m3
Identity Data - Workset: Bouwkundig
Phasing - Phase Created: 2. nieuwbouw

# IfcCovering: Compound Ceiling:300_45_Gipsplaat_45 (8)
Type - PredefinedType: CEILING
Type - Other - Category: Ceilings; Family Name: Compound Ceiling
Type - Construction - Thickness: 45 mm
Type - Graphics - Coarse Scale Fill Pattern: <Solid fill>; Coarse Scale Fill Color: 0
Type - Identity Data - Workset: Ceiling Types; Assembly Code: 45.21; Assembly Description: plafondafwerkingen; niet verlaagd, afwerkingen; Description: Houtwolcementplaat plafond; Type Name: 300_45_Gipsplaat_45
Type - Analytical Properties - Roughness: 1; Absorptance: 0.1
Type - Pset_CoveringCommon - TotalThickness: 45 mm
Type - Pset_ElementShading - Roughness: 304.8 mm
Type - Pset_ProductRequirements - Category: Ceilings
Classification: 45.21 Uniformat (Uniformat); Material: ISR_Plafond 45 mm
Pset_CoveringCommon - Reference: 300_45_Gipsplaat_45; Finish: ISR_Plafond;
Pset_QuantityTakeOff - Reference: 300_45_Gipsplaat_45
Pset_Plafonds - Family and Type: Compound Ceiling: 300_45_Gipsplaat_45; Omschrijving: Houtwolcementplaat plafond; NL-sfb-Codering: 45.21
Pset_DAT_KMS - Assembly Code: 45.21; Assembly Description: plafondafwerkingen; niet verlaagd, afwerkingen; Description: Houtwolcementplaat plafond
Other - Family: Compound Ceiling; Family and Type: Compound Ceiling: 300_45_Gipsplaat_45; Type: 300_45_Gipsplaat_45; Type Id: 6297424
Constraints - Room Bounding: yes
Identity Data - Workset: Bouwkundig
Phasing - Phase Created: 2. nieuwbouw
Name (Compound Ceiling:300_45_Gipsplaat_45:...) | In | Pset_Plafonds, Level = Constraints, Level | Pset_Plafonds, Area (m2) = GrossCeilingArea (m2) = Dimensions, Area (m2) | Height Offset From Level (mm) | Perimeter (mm) | Volume (m3)
6251572 | 00 Begane grond | V1 ok. ruwe vloer | 18.5971 | -45 | 84760 | 0.836869
6251888 | 00 Begane grond | V1 ok. ruwe vloer | 7.16655 | -45 | 81856 | 0.322494
6252045 | 00 Begane grond | V1 ok. ruwe vloer | 7.0456 | -45 | 91676 | 0.317052
6252489 | 01 eerste verdieping | V2 ok. ruwe vloer | 39.0355 | -45 | 423730 | 1.7566
6423219 | 0.20 | V0 ok. plafond | 1.41362 | 0 | 6582.51 | 0.0636127
6425586 | 00 Begane grond | V1 ok. ruwe vloer | 5.49666 | -73 | 28012.9 | 0.247416
6425800 | 0.20 | V0 ok. plafond | 5.64385 | 0 | 9550.08 | 0.253973
6427275 | 00 Begane grond | V0 ok. plafond | 1.431 | 500 | 14710 | 0.064395

# IfcCovering: Compound Ceiling:300_45_akoestisch spuitwerk (3)
Type - PredefinedType: CEILING
Type - Other - Category: Ceilings; Family Name: Compound Ceiling
Type - Construction - Thickness: 35 mm
Type - Graphics - Coarse Scale Fill Color: 0; Coarse Scale Fill Pattern: afdichting
Type - Identity Data - Workset: Ceiling Types; Assembly Code: 45.21; Assembly Description: plafondafwerkingen; niet verlaagd, afwerkingen; Description: akoestisch spuitwerk; Type Name: 300_45_akoestisch spuitwerk
Type - Analytical Properties - Roughness: 1; Absorptance: 0.1
Type - Pset_CoveringCommon - TotalThickness: 35 mm
Type - Pset_ElementShading - Roughness: 304.8 mm
Type - Pset_ProductRequirements - Category: Ceilings
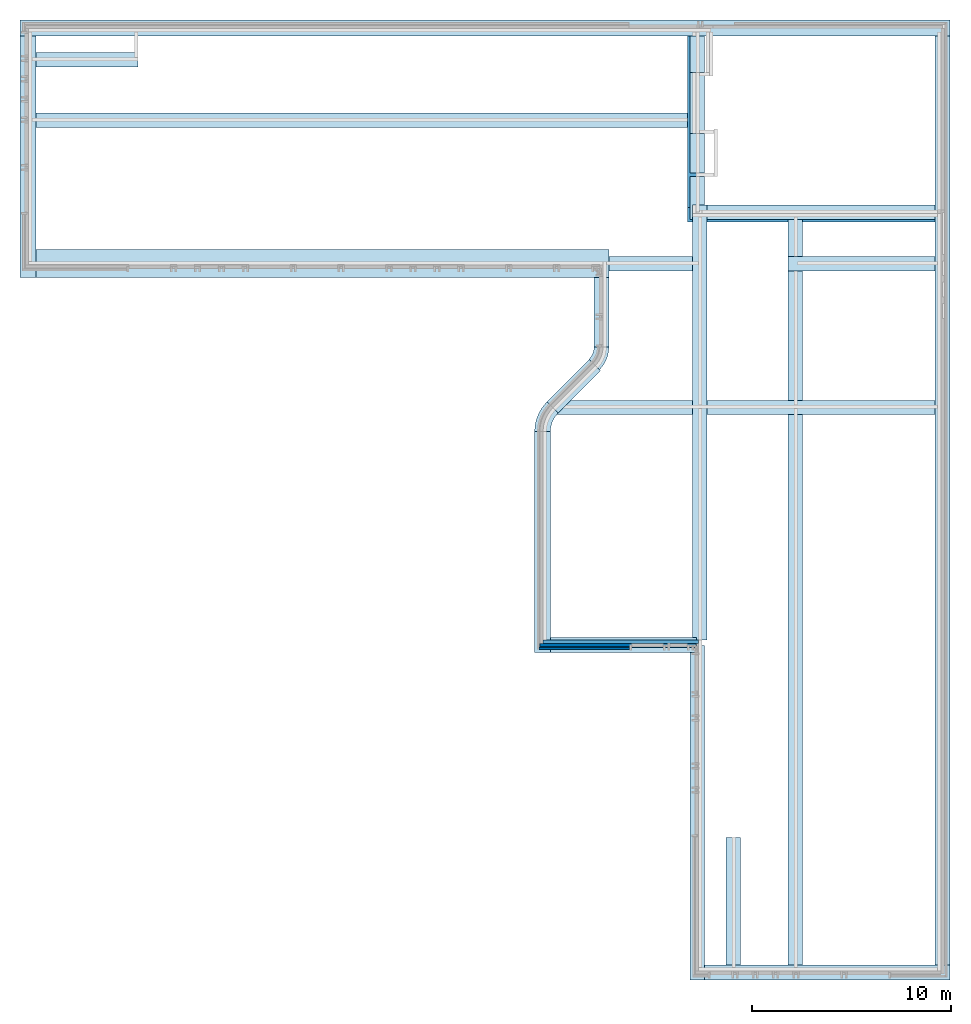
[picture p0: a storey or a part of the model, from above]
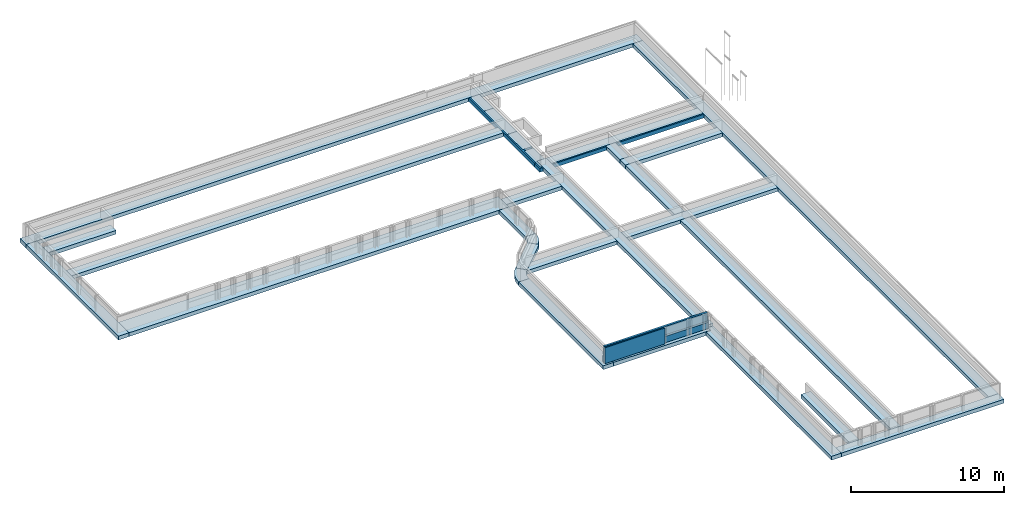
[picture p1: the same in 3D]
Properties of the parts of a building model (IFC2X3), part 10 of 37

# IfcCovering: Compound Ceiling:300_45_akoestisch spuitwerk (3)
Classification: 45.21 Uniformat (Uniformat); Material: ISR_Stucwerk_wit 35 mm
Pset_CoveringCommon - Reference: 300_45_akoestisch spuitwerk; sets with these values: 2
Pset_Plafonds - Family and Type: Compound Ceiling: 300_45_akoestisch spuitwerk; Omschrijving: akoestisch spuitwerk; NL-sfb-Codering: 45.21
Pset_DAT_KMS - Assembly Code: 45.21; Assembly Description: plafondafwerkingen; niet verlaagd, afwerkingen; Description: akoestisch spuitwerk
Other - Family: Compound Ceiling; Family and Type: Compound Ceiling: 300_45_akoestisch spuitwerk; Type: 300_45_akoestisch spuitwerk; Type Id: 5188795
Constraints - Room Bounding: yes
Identity Data - Workset: Bouwkundig
Phasing - Phase Created: 2. nieuwbouw
Name (Compound Ceiling:300_45_akoestisch spuitwerk:...) | In | Pset_Plafonds, Level = Constraints, Level | Pset_Plafonds, Area (m2) = GrossCeilingArea (m2) = Dimensions, Area (m2) | Height Offset From Level (mm) | Perimeter (mm) | Volume (m3)
5558964 | 01 eerste verdieping | V2 ok. ruwe vloer | 710.643 | -35 | 453637 | 24.8726
5995793 | 00 Begane grond | V1 ok. ruwe vloer | 503.378 | -35 | 348118 | 17.6182
6802930 | 00 Begane grond | V1 ok. ruwe vloer | 3.90565 | 0 | 8207.53 | 0.136698

# IfcCovering: Compound Ceiling:300_45_akoestisch spuitwerk DC2, Compound Ceiling:300_45_akoestisch spuitwerk DC2:6425207
In: 00 Begane grond
Type - PredefinedType: CEILING
Type - Other - Category: Ceilings; Family Name: Compound Ceiling
Type - Construction - Thickness: 35 mm
Type - Graphics - Coarse Scale Fill Color: 0; Coarse Scale Fill Pattern: afdichting
Type - Identity Data - Workset: Ceiling Types; Assembly Code: 45.21; Assembly Description: plafondafwerkingen; niet verlaagd, afwerkingen; Description: akoestisch spuitwerk; Type Name: 300_45_akoestisch spuitwerk DC2
Type - Analytical Properties - Roughness: 1; Absorptance: 0.1
Type - Pset_CoveringCommon - TotalThickness: 35 mm
Type - Pset_ElementShading - Roughness: 304.8 mm
Type - Pset_ProductRequirements - Category: Ceilings
Classification: 45.21 Uniformat (Uniformat); Material: ISR_Stucwerk_DC2 35 mm
Pset_CoveringCommon - Reference: 300_45_akoestisch spuitwerk DC2; sets with these values: 2
Pset_Plafonds - Family and Type: Compound Ceiling: 300_45_akoestisch spuitwerk DC2; Level: V1 ok. ruwe vloer; Omschrijving: akoestisch spuitwerk; NL-sfb-Codering: 45.21; Area: 52.0261 m2
Pset_DAT_KMS - Assembly Code: 45.21; Assembly Description: plafondafwerkingen; niet verlaagd, afwerkingen; Description: akoestisch spuitwerk
BaseQuantities - GrossCeilingArea: 52.0261 m2
Other - Family: Compound Ceiling; Family and Type: Compound Ceiling: 300_45_akoestisch spuitwerk DC2; Type: 300_45_akoestisch spuitwerk DC2; Type Id: 6255480
Constraints - Room Bounding: yes; Level: V1 ok. ruwe vloer; Height Offset From Level: -73 mm
Dimensions - Area: 52.0261 m2; Perimeter: 47126.4 mm; Volume: 1.82067 m3
Identity Data - Workset: Bouwkundig
Phasing - Phase Created: 2. nieuwbouw

# IfcCovering: Compound Ceiling:300_45_plaatwerk_25mm (31)
Type - PredefinedType: CEILING
Type - Other - Category: Ceilings; Family Name: Compound Ceiling
Type - Construction - Thickness: 25 mm
Type - Graphics - Coarse Scale Fill Pattern: <Solid fill>; Coarse Scale Fill Color: 0
Type - Identity Data - Assembly Code: 45.21; Assembly Description: plafondafwerkingen; niet verlaagd, afwerkingen; Description: Houtwolcementplaat plafond; Type Name: 300_45_plaatwerk_25mm; Workset: Ceiling Types
Type - Analytical Properties - Roughness: 1; Absorptance: 0.1
Type - Pset_CoveringCommon - TotalThickness: 25 mm
Type - Pset_ElementShading - Roughness: 304.8 mm
Type - Pset_ProductRequirements - Category: Ceilings
Classification: 45.21 Uniformat (Uniformat); Material: ISR_Paneel 25 mm
Pset_CoveringCommon - Reference: 300_45_plaatwerk_25mm; Finish: ISR_Paneel;
Pset_QuantityTakeOff - Reference: 300_45_plaatwerk_25mm
Pset_Plafonds - Family and Type: Compound Ceiling: 300_45_plaatwerk_25mm; Omschrijving: Houtwolcementplaat plafond; NL-sfb-Codering: 45.21
Pset_DAT_KMS - Assembly Code: 45.21; Assembly Description: plafondafwerkingen; niet verlaagd, afwerkingen; Description: Houtwolcementplaat plafond
Other - Family: Compound Ceiling; Family and Type: Compound Ceiling: 300_45_plaatwerk_25mm; Type: 300_45_plaatwerk_25mm; Type Id: 5164776
Constraints - Room Bounding: yes; Height Offset From Level: 0 mm
Identity Data - Workset: Bouwkundig
Phasing - Phase Created: 2. nieuwbouw
Name (Compound Ceiling:300_45_plaatwerk_25mm:...) | In | Pset_Plafonds, Level = Constraints, Level | Pset_Plafonds, Area (m2) = GrossCeilingArea (m2) = Dimensions, Area (m2) | Perimeter (mm) | Volume (m3) | Group
5148524 | 00 Begane grond | V0 ok. plafond | 4.69993 | 10748.8 | 0.117498 | Model Group:Basisgroep element:5145670
5148580 | 00 Begane grond | V0 ok. plafond | 4.69993 | 10748.8 | 0.117498 | Model Group:Basisgroep element:5145620
5148596 | 00 Begane grond | V0 ok. plafond | 4.69993 | 10748.8 | 0.117498 | Model Group:Basisgroep element:5145694
5152876 | 0.15 | V0 ok. plafond | 2.71552 | 11256 | 0.0678879
5153103 | 0.15 | V0 ok. plafond | 2.71552 | 11256 | 0.0678879
5153163 | 0.15 | V0 ok. plafond | 1.86312 | 5816 | 0.0465779
5165001 | 0.35 | V0 ok. plafond | 2.74817 | 9861.2 | 0.0687043 | Model Group:Basisgroep element:5145694
5165156 | 0.36 | V0 ok. plafond | 2.74817 | 9861.2 | 0.0687043 | Model Group:Basisgroep element:5145620
5165178 | 0.37 | V0 ok. plafond | 2.74817 | 9861.2 | 0.0687043 | Model Group:Basisgroep element:5145670
5165544 | 0.28 | V0 ok. plafond | 0.5625 | 3400 | 0.0140625
5172657 | 01 eerste verdieping | V1 ok. plafond | 4.7025 | 10750 | 0.117563
5172762 | 01 eerste verdieping | V1 ok. plafond | 4.7025 | 10750 | 0.117563 | Model Group:V1_Basiselement:5167028
5173217 | 01 eerste verdieping | V1 ok. plafond | 4.631 | 10620 | 0.115775
5174904 | 01 eerste verdieping | V1 ok. plafond | 4.7025 | 10750 | 0.117563
5181891 | 01 eerste verdieping | V1 ok. plafond | 4.69993 | 10748.8 | 0.117498 | Model Group:Basisgroep element:5181887
5181908 | 1.21 | V1 ok. plafond | 2.74817 | 9861.2 | 0.0687043 | Model Group:Basisgroep element:5181887
5184350 | 01 eerste verdieping | V1 ok. plafond | 4.69993 | 10748.8 | 0.117498 | Model Group:Basisgroep element:5184346
5184367 | 1.22 | V1 ok. plafond | 2.74817 | 9861.2 | 0.0687043 | Model Group:Basisgroep element:5184346
5184399 | 01 eerste verdieping | V1 ok. plafond | 4.69993 | 10748.8 | 0.117498 | Model Group:Basisgroep element:5184395
5184416 | 1.23 | V1 ok. plafond | 2.74817 | 9861.2 | 0.0687043 | Model Group:Basisgroep element:5184395
5203614 | 00 Begane grond | V0 ok. plafond | 4.7421 | 10822 | 0.118553 | Model Group:Basisgroep element 2:5203610
5250480 | 1.01 | V1 ok. plafond | 2.66382 | 9660 | 0.0665956
5250593 | 1.03 | V1 ok. plafond | 2.5995 | 9660 | 0.0649874 | Model Group:V1_Basiselement:5167028
5250605 | 1.04 | V1 ok. plafond | 2.67335 | 9690 | 0.0668337
5280676 | 1.12 | V1 ok. plafond | 1.786 | 5390 | 0.04465
5988158 | 01 eerste verdieping | V1 ok. plafond | 4.7025 | 10750 | 0.117563 | Model Group:V1_Basiselement:5988153
5988177 | 1.02 | V1 ok. plafond | 2.66382 | 9660 | 0.0665956 | Model Group:V1_Basiselement:5988153
6309681 | 0.09 | V0 ok. plafond | 1.30734 | 5936 | 0.0326835
6310124 | 0.05 | V0 ok. plafond | 1.30734 | 5936 | 0.0326835
6310143 | 0.01 | V0 ok. plafond | 1.67184 | 6236 | 0.041796
6596418 | 1.04 | V1 ok. plafond | 4.0172 | 8160 | 0.10043

# IfcCovering: Compound Ceiling:300_45_plaatwerk_25mm plafond 2 (20)
Type - PredefinedType: CEILING
Type - Other - Category: Ceilings; Family Name: Compound Ceiling
Type - Construction - Thickness: 25 mm
Type - Graphics - Coarse Scale Fill Pattern: <Solid fill>; Coarse Scale Fill Color: 0
Type - Identity Data - Workset: Ceiling Types; Assembly Code: 45.21; Assembly Description: plafondafwerkingen; niet verlaagd, afwerkingen; Description: Verlaagd systeemplafond; Type Name: 300_45_plaatwerk_25mm plafond 2
Type - Analytical Properties - Roughness: 1; Absorptance: 0.1
Type - Pset_CoveringCommon - TotalThickness: 25 mm
Type - Pset_ElementShading - Roughness: 304.8 mm
Type - Pset_ProductRequirements - Category: Ceilings
Classification: 45.21 Uniformat (Uniformat); Material: ISR_Paneel(2) 25 mm
Pset_CoveringCommon - Reference: 300_45_plaatwerk_25mm plafond 2; Finish: ISR_Paneel(2);
Pset_QuantityTakeOff - Reference: 300_45_plaatwerk_25mm plafond 2
Pset_Plafonds - Family and Type: Compound Ceiling: 300_45_plaatwerk_25mm plafond 2; Omschrijving: Verlaagd systeemplafond; NL-sfb-Codering: 45.21
Pset_DAT_KMS - Assembly Code: 45.21; Assembly Description: plafondafwerkingen; niet verlaagd, afwerkingen; Description: Verlaagd systeemplafond
Other - Family: Compound Ceiling; Family and Type: Compound Ceiling: 300_45_plaatwerk_25mm plafond 2; Type: 300_45_plaatwerk_25mm plafond 2; Type Id: 5244022
Constraints - Room Bounding: yes
Identity Data - Workset: Bouwkundig
Phasing - Phase Created: 2. nieuwbouw
Name (Compound Ceiling:300_45_plaatwerk_25mm plafond 2:...) | In | Pset_Plafonds, Level = Constraints, Level | Pset_Plafonds, Area (m2) = GrossCeilingArea (m2) = Dimensions, Area (m2) | Height Offset From Level (mm) | Perimeter (mm) | Volume (m3)
5153610 | 0.32 | V0 ok. plafond | 2.87735 | 0 | 7662 | 0.0719338
5154864 | 0.33 | V0 ok. plafond | 0.78125 | 0 | 3750 | 0.0195312
5180101 | 1.10 | V1 ok. plafond | 2.7715 | 0 | 10790 | 0.0692875
5188814 | 00 Begane grond | V0 ok. plafond | 10.2282 | 250 | 16804 | 0.255706
5189018 | 00 Begane grond | V0 ok. plafond | 10.2282 | 250 | 16804 | 0.255706
5189690 | 00 Begane grond | V0 ok. plafond | 10.2873 | 250 | 16884 | 0.257183
5244101 | 00 Begane grond | V0 ok. plafond | 46.2421 | 300 | 51800.5 | 1.15605
5245317 | 0.41 | V0 ok. plafond | 4.4571 | 0 | 8690 | 0.111427
5245396 | 0.42 | V0 ok. plafond | 4.5484 | 0 | 8800 | 0.11371
5245428 | 0.43 | V0 ok. plafond | 4.5484 | 0 | 8800 | 0.11371
5246730 | 0.18 | V0 ok. plafond | 4.71815 | 0 | 8730 | 0.117954
5250628 | 01 eerste verdieping | V1 ok. plafond | 29.9078 | 0 | 62790 | 0.747696
5252772 | 01 eerste verdieping | V1 ok. plafond | 41.9877 | 300 | 61107.4 | 1.04969
5256973 | 0.22 | V0 ok. plafond | 2.061 | 0 | 6380 | 0.051525
5257642 | 00 Begane grond | V0 ok. plafond | 4.07734 | 200 | 12972 | 0.101934
5280408 | 0.30 | V0 ok. plafond | 2.36985 | 0 | 6250 | 0.0592463
6220557 | 00 Begane grond | V0 ok. plafond | 5.88953 | 0 | 13779.9 | 0.147238
6220905 | 00 Begane grond | V0 ok. plafond | 65.0955 | 0 | 84970 | 1.62739
6802691 | 00 Begane grond | V0 ok. plafond | 6.71247 | 250 | 15641.7 | 0.167814
6802808 | 0.10 | V0 ok. plafond | 1.37004 | 0 | 5836 | 0.034251

# IfcCovering: Compound Ceiling:Systeemplafond 600x600 Balvast, Compound Ceiling:Systeemplafond 600x600 Balvast:6426352
In: 00 Begane grond
Type - PredefinedType: CEILING
Type - Other - Category: Ceilings; Family Name: Compound Ceiling
Type - Construction - Thickness: 100 mm
Type - Graphics - Coarse Scale Fill Pattern: <Solid fill>; Coarse Scale Fill Color: 4227327
Type - Identity Data - Workset: Ceiling Types; Assembly Code: 45.11; Assembly Description: plafondafwerkingen; verlaagd, verlaagde plafonds; Description: Systeemplafond 600x600; Keynote: 75mm luchtspouw in model tbv ruimtebeslag, die moet installatievrij zijn; Type Name: Systeemplafond 600x600 Balvast
Type - Analytical Properties - Roughness: 1; Absorptance: 0.1
Type - Pset_CoveringCommon - TotalThickness: 100 mm
Type - Pset_ElementShading - Roughness: 304.8 mm
Type - Pset_ProductRequirements - Category: Ceilings
Classification: 45.11 Uniformat (Uniformat); Material: ISR_Luchtspouw 75 mm, ISR_Plafondplaten_600x600 BAL VAST 25 mm
Pset_CoveringCommon - Reference: Systeemplafond 600x600 Balvast; Finish: ISR_Plafondplaten_600x600 BAL VAST;
Pset_QuantityTakeOff - Reference: Systeemplafond 600x600 Balvast
Pset_Plafonds - Family and Type: Compound Ceiling: Systeemplafond 600x600 Balvast; Level: V0 ok. plafond; Omschrijving: Systeemplafond 600x600; NL-sfb-Codering: 45.11; Area: 34.0337 m2
Pset_DAT_KMS - Assembly Code: 45.11; Assembly Description: plafondafwerkingen; verlaagd, verlaagde plafonds; Description: Systeemplafond 600x600
BaseQuantities - GrossCeilingArea: 34.0337 m2
Other - Family: Compound Ceiling; Family and Type: Compound Ceiling: Systeemplafond 600x600 Balvast; Type: Systeemplafond 600x600 Balvast; Type Id: 6426333
Constraints - Room Bounding: yes; Level: V0 ok. plafond; Height Offset From Level: 500 mm
Dimensions - Area: 34.0337 m2; Perimeter: 25089.9 mm; Volume: 3.35507 m3
Identity Data - Workset: Bouwkundig
Phasing - Phase Created: 2. nieuwbouw

# IfcCurtainWall: Basic Wall:NLRS_21_WA_lamellenwand Linius - L.120_Storax (14)
In: 02 tweede verdieping
Type - Material: STAAL_RAL 7006 2 mm
Type - Other - Category: Walls; Family Name: Basic Wall
Type - Model Properties - Storax_I Lamel_materiaal: STAAL_RAL 7006; Storax_I Material: STAAL_RAL 7006
Type - Construction - Function: Exterior; Wrapping at Inserts: Do not wrap; Width: 2 mm
Type - Graphics - Coarse Scale Fill Color: 0
Type - Identity Data - Workset: Wall Types; Type Comments: storax lamellenwand enkele lamellenhouder: type ST-120-11 Ral:7006; Type Name: NLRS_21_WA_lamellenwand Linius - L.120_Storax
Type - Materials and Finishes - Structural Material: STAAL_RAL 7006
Type - Analytical Properties - Roughness: 1; Absorptance: 0.1
Type - Pset_CurtainWallCommon - IsExternal: yes
Type - Pset_ElementShading - Roughness: 304.8 mm
Type - Pset_ProductRequirements - Category: Walls
Classification: 20 Uniformat (Uniformat)
Pset_CurtainWallCommon - Reference: NLRS_21_WA_lamellenwand Linius - L.120_Storax
Pset_ProductRequirements - Category: Curtain Panels
Pset_QuantityTakeOff - Reference: NLRS_21_WA_lamellenwand Linius - L.120_Storax
Other - Family: Basic Wall; Category: Curtain Panels; Family and Type: Basic Wall: NLRS_21_WA_lamellenwand Linius - L.120_Storax; Type: NLRS_21_WA_lamellenwand Linius - L.120_Storax; Type Id: 6284810
Constraints - Base Extension Distance: 0 mm; Related to Mass: no; Top Extension Distance: 0 mm; Location Line: Wall Centerline; Base Constraint: V2 bk. ruwe vloer; Base Offset: 500 mm; Location Line Offset: 0 mm; Unconnected Height: 2050 mm
Dimensions - Height: 2050 mm
Identity Data - Workset: Bouwkundig; Categorize as: Panel
Phasing - Phase Created: 2. nieuwbouw
Structural - Structural Usage: Non-bearing; Structural: no
Cross-Section Definition - Cross-Section: Vertical
Name (Basic Wall:NLRS_21_WA_lamellenwand Linius - L.120_Storax:...) | Area (m2) | Length (mm) | Volume (m3) | Width (mm) | Group
6605291 | 3.69512 | 1802.5 | 0.00739025 | 1802.5
6285787 | 3.69512 | 1802.5 | 0.00739025 | 1802.5
6286611 | 3.68487 | 1797.5 | 0.00736975 | 1797.5 | Model Group:Paneel op dak:6286816
6286766 | 3.68487 | 1797.5 | 0.00736975 | 1797.5 | Model Group:Paneel op dak:6286816
6286610 | 3.68487 | 1797.5 | 0.00736975 | 1797.5 | Model Group:Paneel op dak:6286816
6286609 | 3.68487 | 1797.5 | 0.00736975 | 1797.5 | Model Group:Paneel op dak:6286816
6287088 | 3.68487 | 1797.5 | 0.00736975 | 1797.5 | Model Group:Paneel op dak:6287293
6287243 | 3.68487 | 1797.5 | 0.00736975 | 1797.5 | Model Group:Paneel op dak:6287293
6287087 | 3.68487 | 1797.5 | 0.00736975 | 1797.5 | Model Group:Paneel op dak:6287293
6287086 | 3.70537 | 1807.5 | 0.00741075 | 1797.5 | Model Group:Paneel op dak:6287293
6287302 | 3.68487 | 1797.5 | 0.00736975 | 1797.5 | Model Group:Paneel op dak:6287507
6287457 | 3.68487 | 1797.5 | 0.00736975 | 1797.5 | Model Group:Paneel op dak:6287507
6287301 | 3.68487 | 1797.5 | 0.00736975 | 1797.5 | Model Group:Paneel op dak:6287507
6287300 | 3.68487 | 1797.5 | 0.00736975 | 1797.5 | Model Group:Paneel op dak:6287507

# IfcCurtainWall: Curtain Wall:K_01 (3)
In: 00 Begane grond
Type - Other(Type) - Category: Walls; Family Name: Curtain Wall
Type - Construction(Type) - Function: Exterior; Automatically Embed: yes; Curtain Panel: System Panel : glas_offset 35; Join Condition: Border and Vertical Grid Continuous
Type - Identity Data(Type) - Workset: Curtain Wall Types; Assembly Code: 31; Assembly Description: buitenwandopeningen; Description: Kunststof kozijn Gealan Kubus; Type Mark: K01; Type Name: K_01
Type - Horizontal Grid(Type) - Adjust for Mullion Size: no
Type - Vertical Grid(Type) - Adjust for Mullion Size: no
Type - Horizontal Mullions(Type) - Border 1 Type: Rectangular Mullion : 120x83 Gealan Kubus; Border 2 Type: Rectangular Mullion : 100x83 Gealan Kubus; Interior Type: Rectangular Mullion : 100x83 Gealan Kubus
Type - Vertical Mullions(Type) - Border 1 Type: Rectangular Mullion : 100x83 Gealan Kubus; Border 2 Type: Rectangular Mullion : 100x83 Gealan Kubus; Interior Type: Rectangular Mullion : 100x83 Gealan Kubus
Type - Pset_CurtainWallCommon - IsExternal: yes
Type - Pset_ProductRequirements - Category: Walls
Type - Pset_kozijnen (CW) - Kozijnmerk: K01
Classification: 31 Uniformat (Uniformat)
Pset_CurtainWallCommon - Reference: K_01
Pset_QuantityTakeOff - Reference: K_01
Pset_wanden - Structural Usage: Non-bearing; Omschrijving: Kunststof kozijn Gealan Kubus; NL-sfb-Codering: 31
Pset_kozijnen (CW) - Omschrijving: Kunststof kozijn Gealan Kubus; NL-sfb-Codering: 31
Pset_DAT_KMS - Assembly Code: 31; Assembly Description: buitenwandopeningen; Description: Kunststof kozijn Gealan Kubus
Other - Category: Walls; Family: Curtain Wall; Doorvalveilig 1-zijdig: no; Doorvalveilig 2-zijdig: yes; Family and Type: Curtain Wall: K_01; Type: K_01; Type Id: 4774158
Constraints - Top Offset: 0 mm; Base is Attached: no; Related to Mass: no; Room Bounding: yes; Top is Attached: no; Base Constraint: 0; Base Offset: 10 mm; Unconnected Height: 2630 mm
Dimensions - Area: 2.4196 m2; Length: 920 mm
Identity Data - Workset: Bouwkundig
Phasing - Phase Created: 2. nieuwbouw
Structural - Structural Usage: Non-bearing; Structural: no
Text - NLRS_C_merk: K01
Horizontal Grid - Angle: 0 deg; Justification: Beginning; Number: 4; Offset: 0 mm; sets with these values: 2
Cross-Section Definition - Cross-Section: Vertical
Name (Curtain Wall:K_01:...) | Group
5536919 | Model Group:Merk K01:5536918
5536951 | Model Group:Merk K01:5536950
5539225 | Model Group:Merk K01:5539224

# IfcCurtainWall: Curtain Wall:K_02 (7)
In: 00 Begane grond
Type - Other(Type) - Category: Walls; Family Name: Curtain Wall
Type - Construction(Type) - Function: Exterior; Automatically Embed: yes; Curtain Panel: System Panel : glas_offset 35; Join Condition: Border and Vertical Grid Continuous
Type - Identity Data(Type) - Workset: Curtain Wall Types; Assembly Code: 31; Assembly Description: buitenwandopeningen; Description: Kunststof kozijn Gealan Kubus; Type Comments: Kunststof kozijn; Type Mark: K02; Type Name: K_02
Type - Horizontal Grid(Type) - Adjust for Mullion Size: no
Type - Vertical Grid(Type) - Adjust for Mullion Size: no
Type - Horizontal Mullions(Type) - Border 1 Type: Rectangular Mullion : 120x83 Gealan Kubus; Border 2 Type: Rectangular Mullion : 100x83 Gealan Kubus; Interior Type: Rectangular Mullion : 100x83 Gealan Kubus
Type - Vertical Mullions(Type) - Border 1 Type: Rectangular Mullion : 100x83 Gealan Kubus; Border 2 Type: Rectangular Mullion : 100x83 Gealan Kubus; Interior Type: Rectangular Mullion : 100x83 Gealan Kubus
Type - Pset_CurtainWallCommon - IsExternal: yes
Type - Pset_ProductRequirements - Category: Walls
Type - Pset_kozijnen (CW) - Kozijnmerk: K02
Classification: 31 Uniformat (Uniformat)
Pset_CurtainWallCommon - Reference: K_02
Pset_QuantityTakeOff - Reference: K_02
Pset_wanden - Structural Usage: Non-bearing; Omschrijving: Kunststof kozijn Gealan Kubus; NL-sfb-Codering: 31
Pset_kozijnen (CW) - Omschrijving: Kunststof kozijn Gealan Kubus; NL-sfb-Codering: 31
Pset_DAT_KMS - Assembly Code: 31; Assembly Description: buitenwandopeningen; Description: Kunststof kozijn Gealan Kubus
Other - Category: Walls; Family: Curtain Wall; Doorvalveilig 1-zijdig: no; Doorvalveilig 2-zijdig: yes; Family and Type: Curtain Wall: K_02; Type: K_02; Type Id: 4792108
Constraints - Top Offset: 0 mm; Base is Attached: no; Related to Mass: no; Room Bounding: yes; Top is Attached: no; Base Constraint: 0; Base Offset: 10 mm; Unconnected Height: 2630 mm
Dimensions - Area: 5.5756 m2; Length: 2120 mm
Identity Data - Workset: Bouwkundig
Phasing - Phase Created: 2. nieuwbouw
Structural - Structural Usage: Non-bearing; Structural: no
Text - NLRS_C_merk: K01
Horizontal Grid - Angle: 0 deg; Justification: Beginning; Number: 4; Offset: 0 mm; sets with these values: 2
Cross-Section Definition - Cross-Section: Vertical
Name (Curtain Wall:K_02:...) | Group
5536880 | Model Group:Merk K02:5536879
5536905 | Model Group:Merk K02:5536904
5537103 | Model Group:Merk K02:5537102
5538735 | Model Group:Merk K02:5538734
5538745 | Model Group:Merk K02:5538744
5538753 | Model Group:Merk K02:5538752
6782308

# IfcCurtainWall: Curtain Wall:K_03 (6)
In: 00 Begane grond
Type - Other(Type) - Category: Walls; Family Name: Curtain Wall
Type - Construction(Type) - Function: Exterior; Automatically Embed: yes; Curtain Panel: System Panel : glas_offset 35; Join Condition: Border and Vertical Grid Continuous
Type - Identity Data(Type) - Workset: Curtain Wall Types; Assembly Code: 31; Assembly Description: buitenwandopeningen; Description: Kunststof kozijn Gealan Linear; Type Comments: Kunststof kozijn; Type Mark: K03; Type Name: K_03
Type - Horizontal Grid(Type) - Adjust for Mullion Size: no
Type - Vertical Grid(Type) - Adjust for Mullion Size: no
Type - Horizontal Mullions(Type) - Border 1 Type: Rectangular Mullion : 40x74 Gealan linear; Border 2 Type: Rectangular Mullion : 84x74 Gealan linear; Interior Type: Rectangular Mullion : 84x74 Gealan linear
Type - Vertical Mullions(Type) - Border 1 Type: Rectangular Mullion : 84x74 Gealan linear; Border 2 Type: Rectangular Mullion : 84x74 Gealan linear; Interior Type: Rectangular Mullion : 84x74 Gealan linear
Type - Pset_CurtainWallCommon - IsExternal: yes
Type - Pset_ProductRequirements - Category: Walls
Type - Pset_kozijnen (CW) - Kozijnmerk: K03
Classification: 31 Uniformat (Uniformat)
Pset_CurtainWallCommon - Reference: K_03
Pset_QuantityTakeOff - Reference: K_03
Pset_wanden - Structural Usage: Non-bearing; Omschrijving: Kunststof kozijn Gealan Linear; NL-sfb-Codering: 31
Pset_kozijnen (CW) - Omschrijving: Kunststof kozijn Gealan Linear; NL-sfb-Codering: 31
Pset_DAT_KMS - Assembly Code: 31; Assembly Description: buitenwandopeningen; Description: Kunststof kozijn Gealan Linear
Other - Category: Walls; Family: Curtain Wall; Doorvalveilig 1-zijdig: no; Doorvalveilig 2-zijdig: yes; Family and Type: Curtain Wall: K_03; Type: K_03; Type Id: 4793066
Constraints - Top Offset: 0 mm; Base is Attached: no; Related to Mass: no; Room Bounding: yes; Top is Attached: no; Base Constraint: 0; Base Offset: 30 mm; Unconnected Height: 2610 mm
Dimensions - Area: 5.5332 m2; Length: 2120 mm
Identity Data - Workset: Bouwkundig
Phasing - Phase Created: 2. nieuwbouw
Structural - Structural Usage: Non-bearing; Structural: no
Text - NLRS_C_merk: K01
Horizontal Grid - Angle: 0 deg; Justification: Beginning; Number: 4; Offset: 0 mm; sets with these values: 2
Cross-Section Definition - Cross-Section: Vertical
Name (Curtain Wall:K_03:...) | Group
5536857 | Model Group:Merk K03:5536856
5536929 | Model Group:Merk K03:5536928
5537080 | Model Group:Merk K03:5537079
5538763 | Model Group:Merk K03:5538762
5538781 | Model Group:Merk K03:5538780
5538799 | Model Group:Merk K03:5538798

# IfcCurtainWall: Curtain Wall:K_04 (5)
In: 00 Begane grond
Type - Other(Type) - Category: Walls; Family Name: Curtain Wall
Type - Construction(Type) - Function: Exterior; Automatically Embed: yes; Curtain Panel: System Panel : glas_offset 35; Join Condition: Border and Vertical Grid Continuous
Type - Identity Data(Type) - Workset: Curtain Wall Types; Assembly Code: 31; Assembly Description: buitenwandopeningen; Description: Kunststof kozijn Gealan Kubus; Type Mark: K04; Type Name: K_04
Type - Horizontal Grid(Type) - Adjust for Mullion Size: no
Type - Vertical Grid(Type) - Adjust for Mullion Size: no
Type - Horizontal Mullions(Type) - Border 1 Type: Rectangular Mullion : 120x83 Gealan Kubus; Border 2 Type: Rectangular Mullion : 100x83 Gealan Kubus; Interior Type: Rectangular Mullion : 100x83 Gealan Kubus
Type - Vertical Mullions(Type) - Border 1 Type: Rectangular Mullion : 100x83 Gealan Kubus; Border 2 Type: Rectangular Mullion : 100x83 Gealan Kubus; Interior Type: Rectangular Mullion : 100x83 Gealan Kubus
Type - Pset_CurtainWallCommon - IsExternal: yes
Type - Pset_ProductRequirements - Category: Walls
Type - Pset_kozijnen (CW) - Kozijnmerk: K04
Classification: 31 Uniformat (Uniformat)
Pset_CurtainWallCommon - Reference: K_04
Pset_QuantityTakeOff - Reference: K_04
Pset_wanden - Structural Usage: Non-bearing; Omschrijving: Kunststof kozijn Gealan Kubus; NL-sfb-Codering: 31
Pset_kozijnen (CW) - Omschrijving: Kunststof kozijn Gealan Kubus; NL-sfb-Codering: 31
Pset_DAT_KMS - Assembly Code: 31; Assembly Description: buitenwandopeningen; Description: Kunststof kozijn Gealan Kubus
Other - Category: Walls; Family: Curtain Wall; Doorvalveilig 1-zijdig: no; Doorvalveilig 2-zijdig: yes; Family and Type: Curtain Wall: K_04; Type: K_04; Type Id: 4800906
Constraints - Top Offset: 0 mm; Base is Attached: no; Related to Mass: no; Room Bounding: yes; Top is Attached: no; Base Constraint: 0; Base Offset: 10 mm; Unconnected Height: 2630 mm
Dimensions - Area: 1.9462 m2; Length: 740 mm
Identity Data - Workset: Bouwkundig
Phasing - Phase Created: 2. nieuwbouw
Structural - Structural Usage: Non-bearing; Structural: no
Text - NLRS_C_merk: K01
Horizontal Grid - Angle: 0 deg; Justification: Beginning; Number: 4; Offset: 0 mm; sets with these values: 2
Cross-Section Definition - Cross-Section: Vertical
Name (Curtain Wall:K_04:...) | Group
5536831 | Model Group:Merk K04:5536830
5536839 | Model Group:Merk K04:5536838
5536847 | Model Group:Merk K04:5536846
5537031 | Model Group:Merk K04:5537030
5537066 | Model Group:Merk K04:5537065

# IfcCurtainWall: Curtain Wall:K_05 (2)
In: 00 Begane grond
Type - Other(Type) - Category: Walls; Family Name: Curtain Wall
Type - Construction(Type) - Function: Exterior; Automatically Embed: yes; Curtain Panel: System Panel : glas_offset 35; Join Condition: Border and Vertical Grid Continuous
Type - Identity Data(Type) - Workset: Curtain Wall Types; Assembly Code: 31; Assembly Description: buitenwandopeningen; Description: Kunststof kozijn Gealan Linear; Type Mark: K05; Type Name: K_05
Type - Horizontal Grid(Type) - Adjust for Mullion Size: no
Type - Vertical Grid(Type) - Adjust for Mullion Size: no
Type - Horizontal Mullions(Type) - Border 1 Type: Rectangular Mullion : 40x74 Gealan linear; Border 2 Type: Rectangular Mullion : 84x74 Gealan linear; Interior Type: Rectangular Mullion : 84x74 Gealan linear
Type - Vertical Mullions(Type) - Border 1 Type: Rectangular Mullion : 84x74 Gealan linear; Border 2 Type: Rectangular Mullion : 84x74 Gealan linear; Interior Type: Rectangular Mullion : 84x74 Gealan linear
Type - Pset_CurtainWallCommon - IsExternal: yes
Type - Pset_ProductRequirements - Category: Walls
Type - Pset_kozijnen (CW) - Kozijnmerk: K05
Classification: 31 Uniformat (Uniformat)
Pset_CurtainWallCommon - Reference: K_05
Pset_QuantityTakeOff - Reference: K_05
Pset_wanden - Structural Usage: Non-bearing; Omschrijving: Kunststof kozijn Gealan Linear; NL-sfb-Codering: 31
Pset_kozijnen (CW) - Omschrijving: Kunststof kozijn Gealan Linear; NL-sfb-Codering: 31
Pset_DAT_KMS - Assembly Code: 31; Assembly Description: buitenwandopeningen; Description: Kunststof kozijn Gealan Linear
Other - Category: Walls; Family: Curtain Wall; Doorvalveilig 1-zijdig: no; Doorvalveilig 2-zijdig: yes; Family and Type: Curtain Wall: K_05; Type: K_05; Type Id: 4797835
Constraints - Top Offset: 0 mm; Base is Attached: no; Related to Mass: no; Room Bounding: yes; Top is Attached: no; Base Constraint: 0; Base Offset: 10 mm; Unconnected Height: 2630 mm
Dimensions - Area: 2.9719 m2; Length: 1130 mm
Identity Data - Workset: Bouwkundig
Phasing - Phase Created: 2. nieuwbouw
Structural - Structural Usage: Non-bearing; Structural: no
Text - NLRS_C_merk: K01
Horizontal Grid - Angle: 0 deg; Justification: Beginning; Number: 4; Offset: 0 mm; sets with these values: 2
Cross-Section Definition - Cross-Section: Vertical
Name (Curtain Wall:K_05:...) | Group
5537043 | Model Group:Merk K05:5537042
6703045 | Model Group:Merk K05:6703044

# IfcCurtainWall: Curtain Wall:K_06 (7)
In: 00 Begane grond
Type - Other - Category: Walls; Family Name: Curtain Wall
Type - Construction - Function: Exterior; Automatically Embed: yes; Curtain Panel: System Panel : glas_offset 35; Join Condition: Border and Vertical Grid Continuous
Type - Identity Data - Workset: Curtain Wall Types; Assembly Code: 31; Assembly Description: buitenwandopeningen; Description: Kunststof kozijn Gealan Kubus; Type Mark: K06; Type Name: K_06
Type - Horizontal Grid - Adjust for Mullion Size: no
Type - Vertical Grid - Adjust for Mullion Size: no
Type - Horizontal Mullions - Border 1 Type: Rectangular Mullion : 120x83 Gealan Kubus; Border 2 Type: Rectangular Mullion : 100x83 Gealan Kubus; Interior Type: Rectangular Mullion : 100x83 Gealan Kubus
Type - Vertical Mullions - Border 1 Type: Rectangular Mullion : 100x83 Gealan Kubus; Border 2 Type: Rectangular Mullion : 100x83 Gealan Kubus; Interior Type: Rectangular Mullion : 100x83 Gealan Kubus
Type - Pset_CurtainWallCommon - IsExternal: yes
Type - Pset_ProductRequirements - Category: Walls
Type - Pset_kozijnen (CW) - Kozijnmerk: K06
Classification: 31 Uniformat (Uniformat)
Pset_CurtainWallCommon - Reference: K_06
Pset_QuantityTakeOff - Reference: K_06
Pset_wanden - Structural Usage: Non-bearing; Omschrijving: Kunststof kozijn Gealan Kubus; NL-sfb-Codering: 31
Pset_kozijnen (CW) - Omschrijving: Kunststof kozijn Gealan Kubus; NL-sfb-Codering: 31
Pset_DAT_KMS - Assembly Code: 31; Assembly Description: buitenwandopeningen; Description: Kunststof kozijn Gealan Kubus
Other - Family: Curtain Wall; Doorvalveilig 1-zijdig: no; Doorvalveilig 2-zijdig: yes; Family and Type: Curtain Wall: K_06; Type: K_06; Type Id: 4842980
Constraints - Top Offset: 0 mm; Base is Attached: no; Related to Mass: no; Room Bounding: yes; Top is Attached: no; Base Constraint: 0; Base Offset: 710 mm; Unconnected Height: 2180 mm
Dimensions - Area: 1.7222 m2; Length: 790 mm
Identity Data - Workset: Bouwkundig
Phasing - Phase Created: 2. nieuwbouw
Structural - Structural Usage: Non-bearing; Structural: no
Text - NLRS_C_merk: K01
Horizontal Grid - Angle: 0 deg; Justification: Beginning; Number: 4; Offset: 0 mm; sets with these values: 2
Cross-Section Definition - Cross-Section: Vertical
Name (Curtain Wall:K_06:...) | Group
5537282 | Model Group:Merk K06:5537281
5537294 | Model Group:Merk K06:5537293
5537333 | Model Group:Merk K06:5537332
5537341 | Model Group:Merk K06:5537340
5610885 | Model Group:Merk K06:5537348
5610909 | Model Group:Merk K06:5537306
5610955 | Model Group:Merk K06:5537485

# IfcCurtainWall: Curtain Wall:K_07 (2)
In: 00 Begane grond
Type - Other(Type) - Category: Walls; Family Name: Curtain Wall
Type - Construction(Type) - Function: Exterior; Automatically Embed: yes; Curtain Panel: System Panel : glas_offset 35; Join Condition: Border and Vertical Grid Continuous
Type - Identity Data(Type) - Workset: Curtain Wall Types; Assembly Code: 31; Assembly Description: buitenwandopeningen; Description: Kunststof kozijn Gealan Kubus; Type Mark: K07; Type Name: K_07
Type - Horizontal Grid(Type) - Adjust for Mullion Size: no
Type - Vertical Grid(Type) - Adjust for Mullion Size: no
Type - Horizontal Mullions(Type) - Border 1 Type: Rectangular Mullion : 120x83 Gealan Kubus; Border 2 Type: Rectangular Mullion : 100x83 Gealan Kubus; Interior Type: Rectangular Mullion : 100x83 Gealan Kubus
Type - Vertical Mullions(Type) - Border 1 Type: Rectangular Mullion : 100x83 Gealan Kubus; Border 2 Type: Rectangular Mullion : 100x83 Gealan Kubus; Interior Type: Rectangular Mullion : 154x83 Gealan Kubus
Type - Pset_CurtainWallCommon - IsExternal: yes
Type - Pset_ProductRequirements - Category: Walls
Type - Pset_kozijnen (CW) - Kozijnmerk: K07
Classification: 31 Uniformat (Uniformat)
Pset_CurtainWallCommon - Reference: K_07
Pset_QuantityTakeOff - Reference: K_07
Pset_wanden - Structural Usage: Non-bearing; Omschrijving: Kunststof kozijn Gealan Kubus; NL-sfb-Codering: 31
Pset_kozijnen (CW) - Omschrijving: Kunststof kozijn Gealan Kubus; NL-sfb-Codering: 31
Pset_DAT_KMS - Assembly Code: 31; Assembly Description: buitenwandopeningen; Description: Kunststof kozijn Gealan Kubus
Other - Category: Walls; Family: Curtain Wall; Doorvalveilig 1-zijdig: no; Doorvalveilig 2-zijdig: yes; Family and Type: Curtain Wall: K_07; Type: K_07; Type Id: 4849800
Constraints - Top Offset: 0 mm; Base is Attached: no; Related to Mass: no; Room Bounding: yes; Top is Attached: no; Base Constraint: 0; Base Offset: 710 mm; Unconnected Height: 2180 mm
Dimensions - Area: 5.014 m2; Length: 2300 mm
Identity Data - Workset: Bouwkundig
Phasing - Phase Created: 2. nieuwbouw
Structural - Structural Usage: Non-bearing; Structural: no
Text - NLRS_C_merk: K01
Horizontal Grid - Angle: 0 deg; Justification: Beginning; Number: 4; Offset: 0 mm; sets with these values: 2
Cross-Section Definition - Cross-Section: Vertical
Name (Curtain Wall:K_07:...) | Group
5537503 | Model Group:Merk K07:5537502
5537725 | Model Group:Merk K07:5537724

# IfcCurtainWall: Curtain Wall:K_08, Curtain Wall:K_08:5537386
In: 00 Begane grond
Type - Other(Type) - Category: Walls; Family Name: Curtain Wall
Type - Construction(Type) - Function: Exterior; Automatically Embed: yes; Curtain Panel: System Panel : glas_offset 35; Join Condition: Border and Vertical Grid Continuous
Type - Identity Data(Type) - Workset: Curtain Wall Types; Assembly Code: 31; Assembly Description: buitenwandopeningen; Description: Kunststof kozijn Gealan Kubus; Type Mark: K08; Type Name: K_08
Type - Horizontal Grid(Type) - Adjust for Mullion Size: no
Type - Vertical Grid(Type) - Adjust for Mullion Size: no
Type - Horizontal Mullions(Type) - Border 1 Type: Rectangular Mullion : 120x83 Gealan Kubus; Border 2 Type: Rectangular Mullion : 100x83 Gealan Kubus; Interior Type: Rectangular Mullion : 100x83 Gealan Kubus
Type - Vertical Mullions(Type) - Border 1 Type: Rectangular Mullion : 100x83 Gealan Kubus; Border 2 Type: Rectangular Mullion : 100x83 Gealan Kubus; Interior Type: Rectangular Mullion : 100x83 Gealan Kubus
Type - Pset_CurtainWallCommon - IsExternal: yes
Type - Pset_ProductRequirements - Category: Walls
Type - Pset_kozijnen (CW) - Kozijnmerk: K08
Classification: 31 Uniformat (Uniformat); Group: Model Group:Merk K08:5537385
Pset_CurtainWallCommon - Reference: K_08
Pset_QuantityTakeOff - Reference: K_08
Pset_wanden - Structural Usage: Non-bearing; Omschrijving: Kunststof kozijn Gealan Kubus; NL-sfb-Codering: 31
Pset_kozijnen (CW) - Omschrijving: Kunststof kozijn Gealan Kubus; NL-sfb-Codering: 31
Pset_DAT_KMS - Assembly Code: 31; Assembly Description: buitenwandopeningen; Description: Kunststof kozijn Gealan Kubus
Other - Category: Walls; Family: Curtain Wall; Doorvalveilig 1-zijdig: no; Doorvalveilig 2-zijdig: yes; Family and Type: Curtain Wall: K_08; Type: K_08; Type Id: 4854521
Constraints - Top Offset: 0 mm; Base is Attached: no; Related to Mass: no; Room Bounding: yes; Top is Attached: no; Base Constraint: 0; Base Offset: 710 mm; Unconnected Height: 5680 mm
Dimensions - Area: 12.0984 m2; Length: 2130 mm
Identity Data - Workset: Bouwkundig
Phasing - Phase Created: 2. nieuwbouw
Structural - Structural Usage: Non-bearing; Structural: no
Text - NLRS_C_merk: K01
Horizontal Grid - Angle: 0 deg; Justification: Beginning; Number: 4; Offset: 0 mm; sets with these values: 2
Cross-Section Definition - Cross-Section: Vertical

# IfcCurtainWall: Curtain Wall:K_09, Curtain Wall:K_09:5537394
In: 00 Begane grond
Type - Other(Type) - Category: Walls; Family Name: Curtain Wall
Type - Construction(Type) - Function: Exterior; Automatically Embed: yes; Curtain Panel: System Panel : glas_offset 35; Join Condition: Border and Vertical Grid Continuous
Type - Identity Data(Type) - Workset: Curtain Wall Types; Assembly Code: 31; Assembly Description: buitenwandopeningen; Description: Kunststof kozijn Gealan Kubus; Type Mark: K09; Type Name: K_09
Type - Horizontal Grid(Type) - Adjust for Mullion Size: no
Type - Vertical Grid(Type) - Adjust for Mullion Size: no
Type - Horizontal Mullions(Type) - Border 1 Type: Rectangular Mullion : 120x83 Gealan Kubus; Border 2 Type: Rectangular Mullion : 100x83 Gealan Kubus; Interior Type: Rectangular Mullion : 100x83 Gealan Kubus
Type - Vertical Mullions(Type) - Border 1 Type: Rectangular Mullion : 100x83 Gealan Kubus; Border 2 Type: Rectangular Mullion : 100x83 Gealan Kubus; Interior Type: Rectangular Mullion : 100x83 Gealan Kubus
Type - Pset_CurtainWallCommon - IsExternal: yes
Type - Pset_ProductRequirements - Category: Walls
Type - Pset_kozijnen (CW) - Kozijnmerk: K09
Classification: 31 Uniformat (Uniformat); Group: Model Group:Merk K09:5537393
Pset_CurtainWallCommon - Reference: K_09
Pset_QuantityTakeOff - Reference: K_09
Pset_wanden - Structural Usage: Non-bearing; Omschrijving: Kunststof kozijn Gealan Kubus; NL-sfb-Codering: 31
Pset_kozijnen (CW) - Omschrijving: Kunststof kozijn Gealan Kubus; NL-sfb-Codering: 31
Pset_DAT_KMS - Assembly Code: 31; Assembly Description: buitenwandopeningen; Description: Kunststof kozijn Gealan Kubus
Other - Category: Walls; Family: Curtain Wall; Doorvalveilig 1-zijdig: no; Doorvalveilig 2-zijdig: yes; Family and Type: Curtain Wall: K_09; Type: K_09; Type Id: 4858854
Constraints - Top Offset: 0 mm; Base is Attached: no; Related to Mass: no; Room Bounding: yes; Top is Attached: no; Base Constraint: 0; Base Offset: 1335 mm; Unconnected Height: 5055 mm
Dimensions - Area: 3.99345 m2; Length: 790 mm
Identity Data - Workset: Bouwkundig
Phasing - Phase Created: 2. nieuwbouw
Structural - Structural Usage: Non-bearing; Structural: no
Text - NLRS_C_merk: K01
Horizontal Grid - Angle: 0 deg; Justification: Beginning; Number: 4; Offset: 0 mm; sets with these values: 2
Cross-Section Definition - Cross-Section: Vertical

# IfcCurtainWall: Curtain Wall:K_10, Curtain Wall:K_10:5537402
In: 00 Begane grond
Type - Other(Type) - Category: Walls; Family Name: Curtain Wall
Type - Construction(Type) - Function: Exterior; Automatically Embed: yes; Curtain Panel: System Panel : glas_offset 35; Join Condition: Border and Vertical Grid Continuous
Type - Identity Data(Type) - Workset: Curtain Wall Types; Assembly Code: 31; Assembly Description: buitenwandopeningen; Description: Kunststof kozijn Gealan Kubus; Type Mark: K10; Type Name: K_10
Type - Horizontal Grid(Type) - Adjust for Mullion Size: no
Type - Vertical Grid(Type) - Adjust for Mullion Size: no
Type - Horizontal Mullions(Type) - Border 1 Type: Rectangular Mullion : 120x83 Gealan Kubus; Border 2 Type: Rectangular Mullion : 100x83 Gealan Kubus; Interior Type: Rectangular Mullion : 100x83 Gealan Kubus
Type - Vertical Mullions(Type) - Border 1 Type: Rectangular Mullion : 100x83 Gealan Kubus; Border 2 Type: Rectangular Mullion : 100x83 Gealan Kubus; Interior Type: Rectangular Mullion : 100x83 Gealan Kubus
Type - Pset_CurtainWallCommon - IsExternal: yes
Type - Pset_ProductRequirements - Category: Walls
Type - Pset_kozijnen (CW) - Kozijnmerk: K10
Classification: 31 Uniformat (Uniformat); Group: Model Group:Merk K10:5537401
Pset_CurtainWallCommon - Reference: K_10
Pset_QuantityTakeOff - Reference: K_10
Pset_wanden - Structural Usage: Non-bearing; Omschrijving: Kunststof kozijn Gealan Kubus; NL-sfb-Codering: 31
Pset_kozijnen (CW) - Omschrijving: Kunststof kozijn Gealan Kubus; NL-sfb-Codering: 31
Pset_DAT_KMS - Assembly Code: 31; Assembly Description: buitenwandopeningen; Description: Kunststof kozijn Gealan Kubus
Other - Category: Walls; Family: Curtain Wall; Doorvalveilig 1-zijdig: no; Doorvalveilig 2-zijdig: yes; Family and Type: Curtain Wall: K_10; Type: K_10; Type Id: 4859456
Constraints - Top Offset: 0 mm; Base is Attached: no; Related to Mass: no; Room Bounding: yes; Top is Attached: no; Base Constraint: 0; Base Offset: 1960 mm; Unconnected Height: 4430 mm
Dimensions - Area: 3.4997 m2; Length: 790 mm
Identity Data - Workset: Bouwkundig
Phasing - Phase Created: 2. nieuwbouw
Structural - Structural Usage: Non-bearing; Structural: no
Text - NLRS_C_merk: K01
Horizontal Grid - Angle: 0 deg; Justification: Beginning; Number: 4; Offset: 0 mm; sets with these values: 2
Cross-Section Definition - Cross-Section: Vertical

# IfcCurtainWall: Curtain Wall:K_11, Curtain Wall:K_11:5537410
In: 00 Begane grond
Type - Other(Type) - Category: Walls; Family Name: Curtain Wall
Type - Construction(Type) - Function: Exterior; Automatically Embed: yes; Curtain Panel: System Panel : glas_offset 35; Join Condition: Border and Vertical Grid Continuous
Type - Identity Data(Type) - Workset: Curtain Wall Types; Assembly Code: 31; Assembly Description: buitenwandopeningen; Description: Kunststof kozijn Gealan Kubus; Type Mark: K11; Type Name: K_11
Type - Horizontal Grid(Type) - Adjust for Mullion Size: no
Type - Vertical Grid(Type) - Adjust for Mullion Size: no
Type - Horizontal Mullions(Type) - Border 1 Type: Rectangular Mullion : 120x83 Gealan Kubus; Border 2 Type: Rectangular Mullion : 100x83 Gealan Kubus; Interior Type: Rectangular Mullion : 100x83 Gealan Kubus
Type - Vertical Mullions(Type) - Border 1 Type: Rectangular Mullion : 100x83 Gealan Kubus; Border 2 Type: Rectangular Mullion : 100x83 Gealan Kubus; Interior Type: Rectangular Mullion : 100x83 Gealan Kubus
Type - Pset_CurtainWallCommon - IsExternal: yes
Type - Pset_ProductRequirements - Category: Walls
Type - Pset_kozijnen (CW) - Kozijnmerk: K11
Classification: 31 Uniformat (Uniformat); Group: Model Group:Merk K11:5537409
Pset_CurtainWallCommon - Reference: K_11
Pset_QuantityTakeOff - Reference: K_11
Pset_wanden - Structural Usage: Non-bearing; Omschrijving: Kunststof kozijn Gealan Kubus; NL-sfb-Codering: 31
Pset_kozijnen (CW) - Omschrijving: Kunststof kozijn Gealan Kubus; NL-sfb-Codering: 31
Pset_DAT_KMS - Assembly Code: 31; Assembly Description: buitenwandopeningen; Description: Kunststof kozijn Gealan Kubus
Other - Category: Walls; Family: Curtain Wall; Doorvalveilig 1-zijdig: no; Doorvalveilig 2-zijdig: yes; Family and Type: Curtain Wall: K_11; Type: K_11; Type Id: 4859827
Constraints - Top Offset: 0 mm; Base is Attached: no; Related to Mass: no; Room Bounding: yes; Top is Attached: no; Base Constraint: 0; Base Offset: 2585 mm; Unconnected Height: 3805 mm
Dimensions - Area: 3.00595 m2; Length: 790 mm
Identity Data - Workset: Bouwkundig
Phasing - Phase Created: 2. nieuwbouw
Structural - Structural Usage: Non-bearing; Structural: no
Text - NLRS_C_merk: K01
Horizontal Grid - Angle: 0 deg; Justification: Beginning; Number: 4; Offset: 0 mm; sets with these values: 2
Cross-Section Definition - Cross-Section: Vertical

# IfcCurtainWall: Curtain Wall:K_12, Curtain Wall:K_12:5537418
In: 00 Begane grond
Type - Other(Type) - Category: Walls; Family Name: Curtain Wall
Type - Construction(Type) - Function: Exterior; Automatically Embed: yes; Curtain Panel: System Panel : glas_offset 35; Join Condition: Border and Vertical Grid Continuous
Type - Identity Data(Type) - Workset: Curtain Wall Types; Assembly Code: 31; Assembly Description: buitenwandopeningen; Description: Kunststof kozijn Gealan Kubus; Type Mark: K12; Type Name: K_12
Type - Horizontal Grid(Type) - Adjust for Mullion Size: no
Type - Vertical Grid(Type) - Adjust for Mullion Size: no
Type - Horizontal Mullions(Type) - Border 1 Type: Rectangular Mullion : 120x83 Gealan Kubus; Border 2 Type: Rectangular Mullion : 100x83 Gealan Kubus; Interior Type: Rectangular Mullion : 100x83 Gealan Kubus
Type - Vertical Mullions(Type) - Border 1 Type: Rectangular Mullion : 100x83 Gealan Kubus; Border 2 Type: Rectangular Mullion : 100x83 Gealan Kubus; Interior Type: Rectangular Mullion : 100x83 Gealan Kubus
Type - Pset_CurtainWallCommon - IsExternal: yes
Type - Pset_ProductRequirements - Category: Walls
Type - Pset_kozijnen (CW) - Kozijnmerk: K12
Classification: 31 Uniformat (Uniformat); Group: Model Group:Merk K12:5537417
Pset_CurtainWallCommon - Reference: K_12
Pset_QuantityTakeOff - Reference: K_12
Pset_wanden - Structural Usage: Non-bearing; Omschrijving: Kunststof kozijn Gealan Kubus; NL-sfb-Codering: 31
Pset_kozijnen (CW) - Omschrijving: Kunststof kozijn Gealan Kubus; NL-sfb-Codering: 31
Pset_DAT_KMS - Assembly Code: 31; Assembly Description: buitenwandopeningen; Description: Kunststof kozijn Gealan Kubus
Other - Category: Walls; Family: Curtain Wall; Doorvalveilig 1-zijdig: no; Doorvalveilig 2-zijdig: yes; Family and Type: Curtain Wall: K_12; Type: K_12; Type Id: 4860014
Constraints - Top Offset: 0 mm; Base is Attached: no; Related to Mass: no; Room Bounding: yes; Top is Attached: no; Base Constraint: 0; Base Offset: 3210 mm; Unconnected Height: 3180 mm
Dimensions - Area: 2.5122 m2; Length: 790 mm
Identity Data - Workset: Bouwkundig
Phasing - Phase Created: 2. nieuwbouw
Structural - Structural Usage: Non-bearing; Structural: no
Text - NLRS_C_merk: K01
Horizontal Grid - Angle: 0 deg; Justification: Beginning; Number: 4; Offset: 0 mm; sets with these values: 2
Cross-Section Definition - Cross-Section: Vertical

# IfcCurtainWall: Curtain Wall:K_13, Curtain Wall:K_13:5537426
In: 00 Begane grond
Type - Other(Type) - Category: Walls; Family Name: Curtain Wall
Type - Construction(Type) - Function: Exterior; Automatically Embed: yes; Curtain Panel: System Panel : glas_offset 35; Join Condition: Border and Vertical Grid Continuous
Type - Identity Data(Type) - Workset: Curtain Wall Types; Assembly Code: 31; Assembly Description: buitenwandopeningen; Description: Kunststof kozijn Gealan Kubus; Type Mark: K13; Type Name: K_13
Type - Horizontal Grid(Type) - Adjust for Mullion Size: no
Type - Vertical Grid(Type) - Adjust for Mullion Size: no
Type - Horizontal Mullions(Type) - Border 1 Type: Rectangular Mullion : 120x83 Gealan Kubus; Border 2 Type: Rectangular Mullion : 100x83 Gealan Kubus; Interior Type: Rectangular Mullion : 100x83 Gealan Kubus
Type - Vertical Mullions(Type) - Border 1 Type: Rectangular Mullion : 100x83 Gealan Kubus; Border 2 Type: Rectangular Mullion : 100x83 Gealan Kubus; Interior Type: Rectangular Mullion : 100x83 Gealan Kubus
Type - Pset_CurtainWallCommon - IsExternal: yes
Type - Pset_ProductRequirements - Category: Walls
Type - Pset_kozijnen (CW) - Kozijnmerk: K13
Classification: 31 Uniformat (Uniformat); Group: Model Group:Merk K13:5537425
Pset_CurtainWallCommon - Reference: K_13
Pset_QuantityTakeOff - Reference: K_13
Pset_wanden - Structural Usage: Non-bearing; Omschrijving: Kunststof kozijn Gealan Kubus; NL-sfb-Codering: 31
Pset_kozijnen (CW) - Omschrijving: Kunststof kozijn Gealan Kubus; NL-sfb-Codering: 31
Pset_DAT_KMS - Assembly Code: 31; Assembly Description: buitenwandopeningen; Description: Kunststof kozijn Gealan Kubus
Other - Category: Walls; Family: Curtain Wall; Doorvalveilig 1-zijdig: no; Doorvalveilig 2-zijdig: yes; Family and Type: Curtain Wall: K_13; Type: K_13; Type Id: 4860509
Constraints - Top Offset: 0 mm; Base is Attached: no; Related to Mass: no; Room Bounding: yes; Top is Attached: no; Base Constraint: 0; Base Offset: 3835 mm; Unconnected Height: 2555 mm
Dimensions - Area: 2.01845 m2; Length: 790 mm
Identity Data - Workset: Bouwkundig
Phasing - Phase Created: 2. nieuwbouw
Structural - Structural Usage: Non-bearing; Structural: no
Text - NLRS_C_merk: K01
Horizontal Grid - Angle: 0 deg; Justification: Beginning; Number: 4; Offset: 0 mm; sets with these values: 2
Cross-Section Definition - Cross-Section: Vertical

# IfcCurtainWall: Curtain Wall:K_14, Curtain Wall:K_14:5537526
In: 00 Begane grond
Type - Other(Type) - Category: Walls; Family Name: Curtain Wall
Type - Construction(Type) - Function: Exterior; Automatically Embed: yes; Curtain Panel: System Panel : glas_offset 35; Join Condition: Border and Vertical Grid Continuous
Type - Identity Data(Type) - Workset: Curtain Wall Types; Assembly Code: 31; Assembly Description: buitenwandopeningen; Description: Kunststof kozijn Gealan Kubus; Type Mark: K14; Type Name: K_14
Type - Horizontal Grid(Type) - Adjust for Mullion Size: no
Type - Vertical Grid(Type) - Adjust for Mullion Size: no
Type - Horizontal Mullions(Type) - Border 1 Type: Rectangular Mullion : 120x83 Gealan Kubus; Border 2 Type: Rectangular Mullion : 100x83 Gealan Kubus; Interior Type: Rectangular Mullion : 100x83 Gealan Kubus
Type - Vertical Mullions(Type) - Border 1 Type: Rectangular Mullion : 100x83 Gealan Kubus; Border 2 Type: Rectangular Mullion : 100x83 Gealan Kubus; Interior Type: Rectangular Mullion : 100x83 Gealan Kubus
Type - Pset_CurtainWallCommon - IsExternal: yes
Type - Pset_ProductRequirements - Category: Walls
Type - Pset_kozijnen (CW) - Kozijnmerk: K14
Classification: 31 Uniformat (Uniformat); Group: Model Group:Merk K14:5537525
Pset_CurtainWallCommon - Reference: K_14
Pset_QuantityTakeOff - Reference: K_14
Pset_wanden - Structural Usage: Non-bearing; Omschrijving: Kunststof kozijn Gealan Kubus; NL-sfb-Codering: 31
Pset_kozijnen (CW) - Omschrijving: Kunststof kozijn Gealan Kubus; NL-sfb-Codering: 31
Pset_DAT_KMS - Assembly Code: 31; Assembly Description: buitenwandopeningen; Description: Kunststof kozijn Gealan Kubus
Other - Category: Walls; Family: Curtain Wall; Doorvalveilig 1-zijdig: no; Doorvalveilig 2-zijdig: yes; Family and Type: Curtain Wall: K_14; Type: K_14; Type Id: 4906721
Constraints - Top Offset: 0 mm; Base is Attached: no; Related to Mass: no; Room Bounding: yes; Top is Attached: no; Base Constraint: 0; Base Offset: 10 mm; Unconnected Height: 2630 mm
Dimensions - Area: 3.93185 m2; Length: 1495 mm
Identity Data - Workset: Bouwkundig
Phasing - Phase Created: 2. nieuwbouw
Structural - Structural Usage: Non-bearing; Structural: no
Text - NLRS_C_merk: K01
Horizontal Grid - Angle: 0 deg; Justification: Beginning; Number: 4; Offset: 0 mm; sets with these values: 2
Cross-Section Definition - Cross-Section: Vertical

# IfcCurtainWall: Curtain Wall:K_15, Curtain Wall:K_15:5537537
In: 00 Begane grond
Type - Other(Type) - Category: Walls; Family Name: Curtain Wall
Type - Construction(Type) - Function: Exterior; Automatically Embed: yes; Curtain Panel: System Panel : glas_offset 35; Join Condition: Border and Vertical Grid Continuous
Type - Identity Data(Type) - Workset: Curtain Wall Types; Assembly Code: 31; Assembly Description: buitenwandopeningen; Description: Kunststof kozijn Gealan Kubus; Type Mark: K15; Type Name: K_15
Type - Horizontal Grid(Type) - Adjust for Mullion Size: no
Type - Vertical Grid(Type) - Adjust for Mullion Size: no
Type - Horizontal Mullions(Type) - Border 1 Type: Rectangular Mullion : 120x83 Gealan Kubus; Border 2 Type: Rectangular Mullion : 100x83 Gealan Kubus; Interior Type: Rectangular Mullion : 100x83 Gealan Kubus
Type - Vertical Mullions(Type) - Border 1 Type: Rectangular Mullion : 100x83 Gealan Kubus; Border 2 Type: Rectangular Mullion : 100x83 Gealan Kubus; Interior Type: Rectangular Mullion : 100x83 Gealan Kubus
Type - Pset_CurtainWallCommon - IsExternal: yes
Type - Pset_ProductRequirements - Category: Walls
Type - Pset_kozijnen (CW) - Kozijnmerk: K15
Classification: 31 Uniformat (Uniformat); Group: Model Group:Merk K15:5537536
Pset_CurtainWallCommon - Reference: K_15
Pset_QuantityTakeOff - Reference: K_15
Pset_wanden - Structural Usage: Non-bearing; Omschrijving: Kunststof kozijn Gealan Kubus; NL-sfb-Codering: 31
Pset_kozijnen (CW) - Omschrijving: Kunststof kozijn Gealan Kubus; NL-sfb-Codering: 31
Pset_DAT_KMS - Assembly Code: 31; Assembly Description: buitenwandopeningen; Description: Kunststof kozijn Gealan Kubus
Other - Category: Walls; Family: Curtain Wall; Doorvalveilig 1-zijdig: no; Doorvalveilig 2-zijdig: yes; Family and Type: Curtain Wall: K_15; Type: K_15; Type Id: 4912009
Constraints - Top Offset: 0 mm; Base is Attached: no; Related to Mass: no; Room Bounding: yes; Top is Attached: no; Base Constraint: 0; Base Offset: 10 mm; Unconnected Height: 2630 mm
Dimensions - Area: 9.0735 m2; Length: 3450 mm
Identity Data - Workset: Bouwkundig
Phasing - Phase Created: 2. nieuwbouw
Structural - Structural Usage: Non-bearing; Structural: no
Text - NLRS_C_merk: K01
Horizontal Grid - Angle: 0 deg; Justification: Beginning; Number: 4; Offset: 0 mm; sets with these values: 2
Cross-Section Definition - Cross-Section: Vertical

# IfcCurtainWall: Curtain Wall:K_16 (12)
In: 00 Begane grond
Type - Other(Type) - Category: Walls; Family Name: Curtain Wall
Type - Construction(Type) - Function: Exterior; Automatically Embed: yes; Curtain Panel: System Panel : glas_offset 35; Join Condition: Border and Vertical Grid Continuous
Type - Identity Data(Type) - Workset: Curtain Wall Types; Assembly Code: 31; Assembly Description: buitenwandopeningen; Description: Kunststof kozijn Gealan Kubus; Type Comments: Kunststof kozijn; Type Mark: K16; Type Name: K_16
Type - Horizontal Grid(Type) - Adjust for Mullion Size: no
Type - Vertical Grid(Type) - Adjust for Mullion Size: no
Type - Horizontal Mullions(Type) - Border 1 Type: Rectangular Mullion : 120x83 Gealan Kubus; Border 2 Type: Rectangular Mullion : 100x83 Gealan Kubus; Interior Type: Rectangular Mullion : 100x83 Gealan Kubus
Type - Vertical Mullions(Type) - Border 1 Type: Rectangular Mullion : 100x83 Gealan Kubus; Border 2 Type: Rectangular Mullion : 100x83 Gealan Kubus; Interior Type: Rectangular Mullion : 100x83 Gealan Kubus
Type - Pset_CurtainWallCommon - IsExternal: yes
Type - Pset_ProductRequirements - Category: Walls
Type - Pset_kozijnen (CW) - Kozijnmerk: K16
Classification: 31 Uniformat (Uniformat)
Pset_CurtainWallCommon - Reference: K_16
Pset_QuantityTakeOff - Reference: K_16
Pset_wanden - Structural Usage: Non-bearing; Omschrijving: Kunststof kozijn Gealan Kubus; NL-sfb-Codering: 31
Pset_kozijnen (CW) - Omschrijving: Kunststof kozijn Gealan Kubus; NL-sfb-Codering: 31
Pset_DAT_KMS - Assembly Code: 31; Assembly Description: buitenwandopeningen; Description: Kunststof kozijn Gealan Kubus
Other - Category: Walls; Family: Curtain Wall; Doorvalveilig 1-zijdig: no; Doorvalveilig 2-zijdig: yes; Family and Type: Curtain Wall: K_16; Type: K_16; Type Id: 6074129
Constraints - Top Offset: 0 mm; Base is Attached: no; Related to Mass: no; Room Bounding: yes; Top is Attached: no; Base Constraint: 0; Base Offset: 710 mm; Unconnected Height: 1930 mm
Dimensions - Area: 1.6984 m2; Length: 880 mm
Identity Data - Workset: Bouwkundig
Phasing - Phase Created: 2. nieuwbouw
Structural - Structural Usage: Non-bearing; Structural: no
Text - NLRS_C_merk: K01
Horizontal Grid - Angle: 0 deg; Justification: Beginning; Number: 4; Offset: 0 mm; sets with these values: 2
Cross-Section Definition - Cross-Section: Vertical
Name (Curtain Wall:K_16:...) | Group
5542464 | Model Group:Merk K16:5542460
5544037 | Model Group:Merk K16:5544034
5544059 | Model Group:Merk K16:5544056
5544110 | Model Group:Merk K16:5544107
5544136 | Model Group:Merk K16:5544133
5544808 | Model Group:Merk K16:5544805
5544826 | Model Group:Merk K16:5544823
5545037 | Model Group:Merk K16:5545034
5552592 | Model Group:Merk K16:5552591
5552763 | Model Group:Merk K16:5552762
5856002 | Model Group:Merk K16:5856001
5856009 | Model Group:Merk K16:5856008

# IfcCurtainWall: Curtain Wall:K_17 (11)
In: 00 Begane grond
Type - Other(Type) - Category: Walls; Family Name: Curtain Wall
Type - Construction(Type) - Function: Exterior; Automatically Embed: yes; Curtain Panel: System Panel : glas_offset 35; Join Condition: Border and Vertical Grid Continuous
Type - Identity Data(Type) - Workset: Curtain Wall Types; Assembly Code: 31; Assembly Description: buitenwandopeningen; Description: Kunststof kozijn Gealan Kubus; Type Comments: Kunststof kozijn; Type Mark: K17; Type Name: K_17
Type - Horizontal Grid(Type) - Adjust for Mullion Size: no
Type - Vertical Grid(Type) - Adjust for Mullion Size: no
Type - Horizontal Mullions(Type) - Border 1 Type: Rectangular Mullion : 120x83 Gealan Kubus; Border 2 Type: Rectangular Mullion : 100x83 Gealan Kubus; Interior Type: Rectangular Mullion : 100x83 Gealan Kubus
Type - Vertical Mullions(Type) - Border 1 Type: Rectangular Mullion : 100x83 Gealan Kubus; Border 2 Type: Rectangular Mullion : 100x83 Gealan Kubus; Interior Type: Rectangular Mullion : 154x83 Gealan Kubus
Type - Pset_CurtainWallCommon - IsExternal: yes
Type - Pset_ProductRequirements - Category: Walls
Type - Pset_kozijnen (CW) - Kozijnmerk: K17
Classification: 31 Uniformat (Uniformat)
Pset_CurtainWallCommon - Reference: K_17
Pset_QuantityTakeOff - Reference: K_17
Pset_wanden - Structural Usage: Non-bearing; Omschrijving: Kunststof kozijn Gealan Kubus; NL-sfb-Codering: 31
Pset_kozijnen (CW) - Omschrijving: Kunststof kozijn Gealan Kubus; NL-sfb-Codering: 31
Pset_DAT_KMS - Assembly Code: 31; Assembly Description: buitenwandopeningen; Description: Kunststof kozijn Gealan Kubus
Other - Category: Walls; Family: Curtain Wall; Doorvalveilig 1-zijdig: no; Doorvalveilig 2-zijdig: yes; Family and Type: Curtain Wall: K_17; Type: K_17; Type Id: 6061266
Constraints - Top Offset: 0 mm; Base is Attached: no; Related to Mass: no; Room Bounding: yes; Top is Attached: no; Base Constraint: 0; Base Offset: 710 mm; Unconnected Height: 1930 mm
Dimensions - Area: 3.9372 m2; Length: 2040 mm
Identity Data - Workset: Bouwkundig
Phasing - Phase Created: 2. nieuwbouw
Structural - Structural Usage: Non-bearing; Structural: no
Text - NLRS_C_merk: K01
Horizontal Grid - Angle: 0 deg; Justification: Beginning; Number: 4; Offset: 0 mm; sets with these values: 2
Cross-Section Definition - Cross-Section: Vertical
Name (Curtain Wall:K_17:...) | Group
5542011 | Model Group:Merk K17:5540560
5542288 | Model Group:Merk K17:5542284
5542314 | Model Group:Merk K17:5542310
5542340 | Model Group:Merk K17:5542336
5542366 | Model Group:Merk K17:5542362
5542392 | Model Group:Merk K17:5542388
5544298 | Model Group:Merk K17:5544294
5544976 | Model Group:Merk K17:5544972
5545011 | Model Group:Merk K17:5545007
5855990 | Model Group:Merk K17:5855989
5856031 | Model Group:Merk K17:5856030

# IfcCurtainWall: Curtain Wall:K_18 (2)
In: 00 Begane grond
Type - Other(Type) - Category: Walls; Family Name: Curtain Wall
Type - Construction(Type) - Function: Exterior; Automatically Embed: yes; Curtain Panel: System Panel : glas_offset 35; Join Condition: Border and Vertical Grid Continuous
Type - Identity Data(Type) - Workset: Curtain Wall Types; Assembly Code: 31; Assembly Description: buitenwandopeningen; Description: Kunststof kozijn Gealan Kubus; Type Comments: Kunststof kozijn; Type Mark: K18; Type Name: K_18
Type - Horizontal Grid(Type) - Adjust for Mullion Size: no
Type - Vertical Grid(Type) - Adjust for Mullion Size: no
Type - Horizontal Mullions(Type) - Border 1 Type: Rectangular Mullion : 120x83 Gealan Kubus; Border 2 Type: Rectangular Mullion : 100x83 Gealan Kubus; Interior Type: Rectangular Mullion : 100x83 Gealan Kubus
Type - Vertical Mullions(Type) - Border 1 Type: Rectangular Mullion : 100x83 Gealan Kubus; Border 2 Type: Rectangular Mullion : 100x83 Gealan Kubus; Interior Type: Rectangular Mullion : 100x83 Gealan Kubus
Type - Pset_CurtainWallCommon - IsExternal: yes
Type - Pset_ProductRequirements - Category: Walls
Type - Pset_kozijnen (CW) - Kozijnmerk: K18
Classification: 31 Uniformat (Uniformat)
Pset_CurtainWallCommon - Reference: K_18
Pset_QuantityTakeOff - Reference: K_18
Pset_wanden - Structural Usage: Non-bearing; Omschrijving: Kunststof kozijn Gealan Kubus; NL-sfb-Codering: 31
Pset_kozijnen (CW) - Omschrijving: Kunststof kozijn Gealan Kubus; NL-sfb-Codering: 31
Pset_DAT_KMS - Assembly Code: 31; Assembly Description: buitenwandopeningen; Description: Kunststof kozijn Gealan Kubus
Other - Category: Walls; Family: Curtain Wall; Doorvalveilig 1-zijdig: no; Doorvalveilig 2-zijdig: yes; Family and Type: Curtain Wall: K_18; Type: K_18; Type Id: 6067594
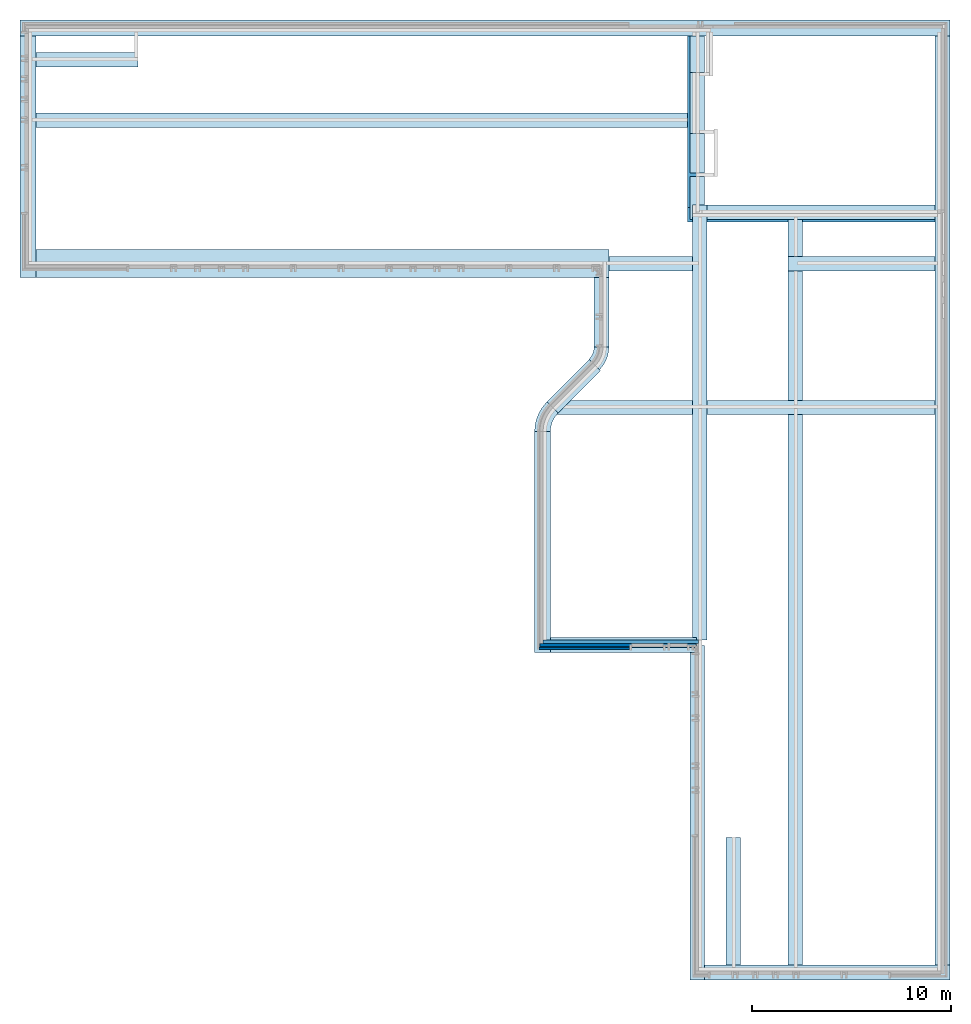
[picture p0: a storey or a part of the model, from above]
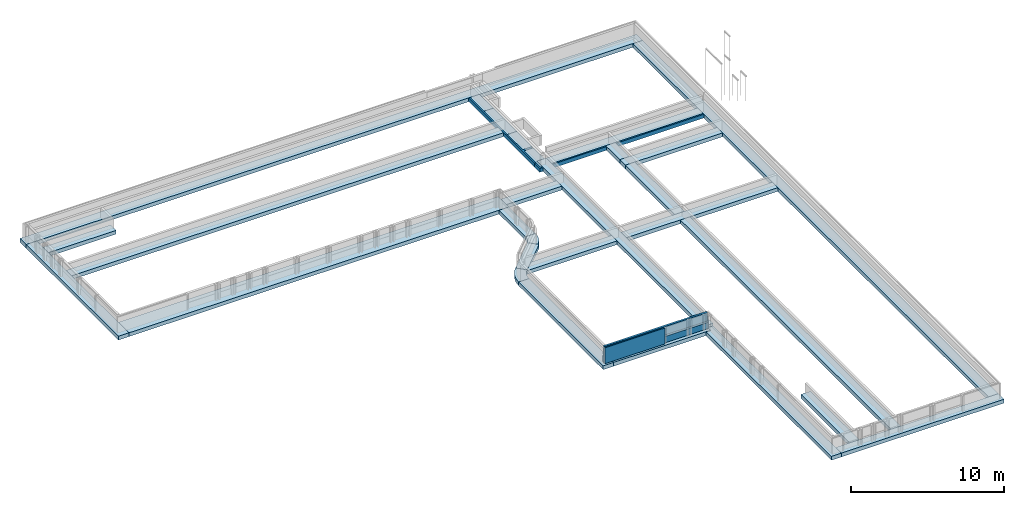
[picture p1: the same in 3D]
Properties of the parts of a building model (IFC2X3), part 11 of 37

# IfcCurtainWall: Curtain Wall:K_18 (2)
Constraints - Top Offset: 0 mm; Base is Attached: no; Related to Mass: no; Room Bounding: yes; Top is Attached: no; Base Constraint: 0; Base Offset: 10 mm; Unconnected Height: 2630 mm
Dimensions - Area: 4.30005 m2; Length: 1635 mm
Identity Data - Workset: Bouwkundig
Phasing - Phase Created: 2. nieuwbouw
Structural - Structural Usage: Non-bearing; Structural: no
Text - NLRS_C_merk: K01
Horizontal Grid - Angle: 0 deg; Justification: Beginning; Number: 4; Offset: 0 mm; sets with these values: 2
Cross-Section Definition - Cross-Section: Vertical
Name (Curtain Wall:K_18:...) | Group
5538685 | Model Group:Merk K18:5538684
5539196 | Model Group:Merk K18:5539194

# IfcCurtainWall: Curtain Wall:K_20, Curtain Wall:K_20:5539075
In: 00 Begane grond
Type - Other(Type) - Category: Walls; Family Name: Curtain Wall
Type - Construction(Type) - Function: Exterior; Automatically Embed: yes; Curtain Panel: System Panel : glas_offset 35; Join Condition: Border and Vertical Grid Continuous
Type - Identity Data(Type) - Workset: Curtain Wall Types; Assembly Code: 31; Assembly Description: buitenwandopeningen; Description: Kunststof kozijn Gealan Linear; Type Mark: K20; Type Name: K_20
Type - Horizontal Grid(Type) - Adjust for Mullion Size: no
Type - Vertical Grid(Type) - Adjust for Mullion Size: no
Type - Horizontal Mullions(Type) - Border 1 Type: Rectangular Mullion : 40x74 Gealan linear; Border 2 Type: Rectangular Mullion : 84x74 Gealan linear; Interior Type: Rectangular Mullion : 84x74 Gealan linear
Type - Vertical Mullions(Type) - Border 1 Type: Rectangular Mullion : 84x74 Gealan linear; Border 2 Type: Rectangular Mullion : 84x74 Gealan linear; Interior Type: Rectangular Mullion : 84x74 Gealan linear
Type - Pset_CurtainWallCommon - IsExternal: yes
Type - Pset_ProductRequirements - Category: Walls
Type - Pset_kozijnen (CW) - Kozijnmerk: K20
Classification: 31 Uniformat (Uniformat); Group: Model Group:Merk K20:5539074
Pset_CurtainWallCommon - Reference: K_20
Pset_QuantityTakeOff - Reference: K_20
Pset_wanden - Structural Usage: Non-bearing; Omschrijving: Kunststof kozijn Gealan Linear; NL-sfb-Codering: 31
Pset_kozijnen (CW) - Omschrijving: Kunststof kozijn Gealan Linear; NL-sfb-Codering: 31
Pset_DAT_KMS - Assembly Code: 31; Assembly Description: buitenwandopeningen; Description: Kunststof kozijn Gealan Linear
Other - Category: Walls; Family: Curtain Wall; Doorvalveilig 1-zijdig: no; Doorvalveilig 2-zijdig: yes; Family and Type: Curtain Wall: K_20; Type: K_20; Type Id: 4960166
Constraints - Top Offset: 0 mm; Base is Attached: no; Related to Mass: no; Room Bounding: yes; Top is Attached: no; Base Constraint: 0; Base Offset: 30 mm; Unconnected Height: 2630 mm
Dimensions - Area: 5.0233 m2; Length: 1910 mm
Identity Data - Workset: Bouwkundig
Phasing - Phase Created: 2. nieuwbouw
Structural - Structural Usage: Non-bearing; Structural: no
Text - NLRS_C_merk: K01
Horizontal Grid - Angle: 0 deg; Justification: Beginning; Number: 4; Offset: 0 mm; sets with these values: 2
Cross-Section Definition - Cross-Section: Vertical

# IfcCurtainWall: Curtain Wall:K_21, Curtain Wall:K_21:5536965
In: 00 Begane grond
Type - Other(Type) - Category: Walls; Family Name: Curtain Wall
Type - Construction(Type) - Function: Exterior; Automatically Embed: yes; Curtain Panel: System Panel : glas_offset 35; Join Condition: Border and Vertical Grid Continuous
Type - Identity Data(Type) - Workset: Curtain Wall Types; Assembly Code: 31; Assembly Description: buitenwandopeningen; Description: Kunststof kozijn Gealan Kubus; Type Mark: K21; Type Name: K_21
Type - Horizontal Grid(Type) - Adjust for Mullion Size: no
Type - Vertical Grid(Type) - Adjust for Mullion Size: no
Type - Horizontal Mullions(Type) - Border 1 Type: Rectangular Mullion : 120x83 Gealan Kubus; Border 2 Type: Rectangular Mullion : 100x83 Gealan Kubus; Interior Type: Rectangular Mullion : 100x83 Gealan Kubus
Type - Vertical Mullions(Type) - Border 1 Type: Rectangular Mullion : 100x83 Gealan Kubus; Border 2 Type: Rectangular Mullion : 100x83 Gealan Kubus; Interior Type: Rectangular Mullion : 100x83 Gealan Kubus
Type - Pset_CurtainWallCommon - IsExternal: yes
Type - Pset_ProductRequirements - Category: Walls
Type - Pset_kozijnen (CW) - Kozijnmerk: K21
Classification: 31 Uniformat (Uniformat); Group: Model Group:Merk K21:5536964
Pset_CurtainWallCommon - Reference: K_21
Pset_QuantityTakeOff - Reference: K_21
Pset_wanden - Structural Usage: Non-bearing; Omschrijving: Kunststof kozijn Gealan Kubus; NL-sfb-Codering: 31
Pset_kozijnen (CW) - Omschrijving: Kunststof kozijn Gealan Kubus; NL-sfb-Codering: 31
Pset_DAT_KMS - Assembly Code: 31; Assembly Description: buitenwandopeningen; Description: Kunststof kozijn Gealan Kubus
Other - Category: Walls; Family: Curtain Wall; Doorvalveilig 1-zijdig: no; Doorvalveilig 2-zijdig: yes; Family and Type: Curtain Wall: K_21; Type: K_21; Type Id: 5077807
Constraints - Top Offset: 0 mm; Base is Attached: no; Related to Mass: no; Room Bounding: yes; Top is Attached: no; Base Constraint: 0; Base Offset: 10 mm; Unconnected Height: 2630 mm
Dimensions - Area: 4.90495 m2; Length: 1865 mm
Identity Data - Workset: Bouwkundig
Phasing - Phase Created: 2. nieuwbouw
Structural - Structural Usage: Non-bearing; Structural: no
Text - NLRS_C_merk: K01
Horizontal Grid - Angle: 0 deg; Justification: Beginning; Number: 4; Offset: 0 mm; sets with these values: 2
Cross-Section Definition - Cross-Section: Vertical

# IfcCurtainWall: Curtain Wall:K_22 (13)
In: 01 eerste verdieping
Type - Other(Type) - Category: Walls; Family Name: Curtain Wall
Type - Construction(Type) - Function: Exterior; Automatically Embed: yes; Curtain Panel: System Panel : glas_offset 35; Join Condition: Border and Vertical Grid Continuous
Type - Identity Data(Type) - Workset: Curtain Wall Types; Assembly Code: 31; Assembly Description: buitenwandopeningen; Description: Kunststof kozijn Gealan Kubus; Type Mark: K22; Type Name: K_22
Type - Horizontal Grid(Type) - Adjust for Mullion Size: no
Type - Vertical Grid(Type) - Adjust for Mullion Size: no
Type - Horizontal Mullions(Type) - Border 1 Type: Rectangular Mullion : 120x83 Gealan Kubus; Border 2 Type: Rectangular Mullion : 100x83 Gealan Kubus; Interior Type: Rectangular Mullion : 100x83 Gealan Kubus
Type - Vertical Mullions(Type) - Border 1 Type: Rectangular Mullion : 100x83 Gealan Kubus; Border 2 Type: Rectangular Mullion : 100x83 Gealan Kubus; Interior Type: Rectangular Mullion : 154x83 Gealan Kubus
Type - Pset_CurtainWallCommon - IsExternal: yes
Type - Pset_ProductRequirements - Category: Walls
Type - Pset_kozijnen (CW) - Kozijnmerk: K22
Classification: 31 Uniformat (Uniformat)
Pset_CurtainWallCommon - Reference: K_22
Pset_QuantityTakeOff - Reference: K_22
Pset_wanden - Structural Usage: Non-bearing; Omschrijving: Kunststof kozijn Gealan Kubus; NL-sfb-Codering: 31
Pset_kozijnen (CW) - Omschrijving: Kunststof kozijn Gealan Kubus; NL-sfb-Codering: 31
Pset_DAT_KMS - Assembly Code: 31; Assembly Description: buitenwandopeningen; Description: Kunststof kozijn Gealan Kubus
Other - Category: Walls; Family: Curtain Wall; Doorvalveilig 1-zijdig: no; Doorvalveilig 2-zijdig: yes; Family and Type: Curtain Wall: K_22; Type: K_22; Type Id: 4917986
Constraints - Top Offset: 0 mm; Base is Attached: no; Related to Mass: no; Room Bounding: yes; Top is Attached: no; Base Constraint: 1; Base Offset: 810 mm; Unconnected Height: 1930 mm
Dimensions - Area: 4.3425 m2; Length: 2250 mm
Identity Data - Workset: Bouwkundig
Phasing - Phase Created: 2. nieuwbouw
Structural - Structural Usage: Non-bearing; Structural: no
Text - NLRS_C_merk: K01
Horizontal Grid - Angle: 0 deg; Justification: Beginning; Number: 4; Offset: 0 mm; sets with these values: 2
Cross-Section Definition - Cross-Section: Vertical
Name (Curtain Wall:K_22:...) | Group
5537991 | Model Group:Merk K22:5537990
5537999 | Model Group:Merk K22:5537998
5538007 | Model Group:Merk K22:5538006
5538015 | Model Group:Merk K22:5538014
5538023 | Model Group:Merk K22:5538022
5538031 | Model Group:Merk K22:5538030
5538039 | Model Group:Merk K22:5538038
5538047 | Model Group:Merk K22:5538046
5538055 | Model Group:Merk K22:5538054
5538063 | Model Group:Merk K22:5538062
5538071 | Model Group:Merk K22:5538070
5538079 | Model Group:Merk K22:5538078
5538087 | Model Group:Merk K22:5538086

# IfcCurtainWall: Curtain Wall:K_23, Curtain Wall:K_23:5537748
In: 01 eerste verdieping
Type - Other(Type) - Category: Walls; Family Name: Curtain Wall
Type - Construction(Type) - Function: Exterior; Automatically Embed: yes; Curtain Panel: System Panel : glas_offset 35; Join Condition: Border and Vertical Grid Continuous
Type - Identity Data(Type) - Workset: Curtain Wall Types; Assembly Code: 31; Assembly Description: buitenwandopeningen; Description: Kunststof kozijn Gealan Kubus; Type Mark: K23; Type Name: K_23
Type - Horizontal Grid(Type) - Adjust for Mullion Size: no
Type - Vertical Grid(Type) - Adjust for Mullion Size: no
Type - Horizontal Mullions(Type) - Border 1 Type: Rectangular Mullion : 120x83 Gealan Kubus; Border 2 Type: Rectangular Mullion : 100x83 Gealan Kubus; Interior Type: Rectangular Mullion : 100x83 Gealan Kubus
Type - Vertical Mullions(Type) - Border 1 Type: Rectangular Mullion : 100x83 Gealan Kubus; Border 2 Type: Rectangular Mullion : 100x83 Gealan Kubus; Interior Type: Rectangular Mullion : 100x83 Gealan Kubus
Type - Pset_CurtainWallCommon - IsExternal: yes
Type - Pset_ProductRequirements - Category: Walls
Type - Pset_kozijnen (CW) - Kozijnmerk: K23
Classification: 31 Uniformat (Uniformat); Group: Model Group:Merk K23:5537747
Pset_CurtainWallCommon - Reference: K_23
Pset_QuantityTakeOff - Reference: K_23
Pset_wanden - Structural Usage: Non-bearing; Omschrijving: Kunststof kozijn Gealan Kubus; NL-sfb-Codering: 31
Pset_kozijnen (CW) - Omschrijving: Kunststof kozijn Gealan Kubus; NL-sfb-Codering: 31
Pset_DAT_KMS - Assembly Code: 31; Assembly Description: buitenwandopeningen; Description: Kunststof kozijn Gealan Kubus
Other - Category: Walls; Family: Curtain Wall; Doorvalveilig 1-zijdig: no; Doorvalveilig 2-zijdig: yes; Family and Type: Curtain Wall: K_23; Type: K_23; Type Id: 4942408
Constraints - Top Offset: 0 mm; Base is Attached: no; Related to Mass: no; Room Bounding: yes; Top is Attached: no; Base Constraint: 1; Base Offset: 810 mm; Unconnected Height: 1930 mm
Dimensions - Area: 3.98352 m2; Length: 2064 mm
Identity Data - Workset: Bouwkundig
Phasing - Phase Created: 2. nieuwbouw
Structural - Structural Usage: Non-bearing; Structural: no
Text - NLRS_C_merk: K01
Horizontal Grid - Angle: 0 deg; Justification: Beginning; Number: 4; Offset: 0 mm; sets with these values: 2
Cross-Section Definition - Cross-Section: Vertical

# IfcCurtainWall: Curtain Wall:K_24 (13)
In: 01 eerste verdieping
Type - Other(Type) - Category: Walls; Family Name: Curtain Wall
Type - Construction(Type) - Function: Exterior; Automatically Embed: yes; Curtain Panel: System Panel : glas_offset 35; Join Condition: Border and Vertical Grid Continuous
Type - Identity Data(Type) - Workset: Curtain Wall Types; Assembly Code: 31; Assembly Description: buitenwandopeningen; Description: Kunststof kozijn Gealan Kubus; Type Comments: Kunststof kozijn; Type Mark: K24; Type Name: K_24
Type - Horizontal Grid(Type) - Adjust for Mullion Size: no
Type - Vertical Grid(Type) - Adjust for Mullion Size: no
Type - Horizontal Mullions(Type) - Border 1 Type: Rectangular Mullion : 120x83 Gealan Kubus; Border 2 Type: Rectangular Mullion : 100x83 Gealan Kubus; Interior Type: Rectangular Mullion : 100x83 Gealan Kubus
Type - Vertical Mullions(Type) - Border 1 Type: Rectangular Mullion : 100x83 Gealan Kubus; Border 2 Type: Rectangular Mullion : 100x83 Gealan Kubus; Interior Type: Rectangular Mullion : 154x83 Gealan Kubus
Type - Pset_CurtainWallCommon - IsExternal: yes
Type - Pset_ProductRequirements - Category: Walls
Type - Pset_kozijnen (CW) - Kozijnmerk: K24
Classification: 31 Uniformat (Uniformat)
Pset_CurtainWallCommon - Reference: K_24
Pset_QuantityTakeOff - Reference: K_24
Pset_wanden - Structural Usage: Non-bearing; Omschrijving: Kunststof kozijn Gealan Kubus; NL-sfb-Codering: 31
Pset_kozijnen (CW) - Omschrijving: Kunststof kozijn Gealan Kubus; NL-sfb-Codering: 31
Pset_DAT_KMS - Assembly Code: 31; Assembly Description: buitenwandopeningen; Description: Kunststof kozijn Gealan Kubus
Other - Category: Walls; Family: Curtain Wall; Doorvalveilig 1-zijdig: no; Doorvalveilig 2-zijdig: yes; Family and Type: Curtain Wall: K_24; Type: K_24; Type Id: 4801721
Constraints - Top Offset: 0 mm; Base is Attached: no; Related to Mass: no; Room Bounding: yes; Top is Attached: no; Base Constraint: 1; Base Offset: 810 mm; Unconnected Height: 1930 mm
Dimensions - Area: 3.9372 m2; Length: 2040 mm
Identity Data - Workset: Bouwkundig
Phasing - Phase Created: 2. nieuwbouw
Structural - Structural Usage: Non-bearing; Structural: no
Text - NLRS_C_merk: K01
Horizontal Grid - Angle: 0 deg; Justification: Beginning; Number: 4; Offset: 0 mm; sets with these values: 2
Cross-Section Definition - Cross-Section: Vertical
Name (Curtain Wall:K_24:...) | Group
6065213 | Model Group:Merk K24:6065197
6065244 | Model Group:Merk K24:6065228
6065275 | Model Group:Merk K24:6065259
6065306 | Model Group:Merk K24:6065290
6065337 | Model Group:Merk K24:6065321
6065368 | Model Group:Merk K24:6065352
6065399 | Model Group:Merk K24:6065383
6065430 | Model Group:Merk K24:6065414
6065461 | Model Group:Merk K24:6065445
6065492 | Model Group:Merk K24:6065476
6065523 | Model Group:Merk K24:6065507
6065554 | Model Group:Merk K24:6065538
6065585 | Model Group:Merk K24:6065569

# IfcCurtainWall: Curtain Wall:K_25, Curtain Wall:K_25:5537975
In: 01 eerste verdieping
Type - Other(Type) - Category: Walls; Family Name: Curtain Wall
Type - Construction(Type) - Function: Exterior; Automatically Embed: yes; Curtain Panel: System Panel : glas_offset 35; Join Condition: Border and Vertical Grid Continuous
Type - Identity Data(Type) - Workset: Curtain Wall Types; Assembly Code: 31; Assembly Description: buitenwandopeningen; Description: Kunststof kozijn Gealan Kubus; Type Mark: K25; Type Name: K_25
Type - Horizontal Grid(Type) - Adjust for Mullion Size: no
Type - Vertical Grid(Type) - Adjust for Mullion Size: no
Type - Horizontal Mullions(Type) - Border 1 Type: Rectangular Mullion : 120x83 Gealan Kubus; Border 2 Type: Rectangular Mullion : 100x83 Gealan Kubus; Interior Type: Rectangular Mullion : 100x83 Gealan Kubus
Type - Vertical Mullions(Type) - Border 1 Type: Rectangular Mullion : 100x83 Gealan Kubus; Border 2 Type: Rectangular Mullion : 100x83 Gealan Kubus; Interior Type: Rectangular Mullion : 100x83 Gealan Kubus
Type - Pset_CurtainWallCommon - IsExternal: yes
Type - Pset_ProductRequirements - Category: Walls
Type - Pset_kozijnen (CW) - Kozijnmerk: K25
Classification: 31 Uniformat (Uniformat); Group: Model Group:Merk K25:5537974
Pset_CurtainWallCommon - Reference: K_25
Pset_QuantityTakeOff - Reference: K_25
Pset_wanden - Structural Usage: Non-bearing; Omschrijving: Kunststof kozijn Gealan Kubus; NL-sfb-Codering: 31
Pset_kozijnen (CW) - Omschrijving: Kunststof kozijn Gealan Kubus; NL-sfb-Codering: 31
Pset_DAT_KMS - Assembly Code: 31; Assembly Description: buitenwandopeningen; Description: Kunststof kozijn Gealan Kubus
Other - Category: Walls; Family: Curtain Wall; Doorvalveilig 1-zijdig: no; Doorvalveilig 2-zijdig: yes; Family and Type: Curtain Wall: K_25; Type: K_25; Type Id: 4942169
Constraints - Top Offset: 0 mm; Base is Attached: no; Related to Mass: no; Room Bounding: yes; Top is Attached: no; Base Constraint: 1; Base Offset: 810 mm; Unconnected Height: 1930 mm
Dimensions - Area: 2.20985 m2; Length: 1145 mm
Identity Data - Workset: Bouwkundig
Phasing - Phase Created: 2. nieuwbouw
Structural - Structural Usage: Non-bearing; Structural: no
Text - NLRS_C_merk: K01
Horizontal Grid - Angle: 0 deg; Justification: Beginning; Number: 4; Offset: 0 mm; sets with these values: 2
Cross-Section Definition - Cross-Section: Vertical

# IfcCurtainWall: Curtain Wall:K_26, Curtain Wall:K_26:5538528
In: 01 eerste verdieping
Type - Other(Type) - Category: Walls; Family Name: Curtain Wall
Type - Construction(Type) - Function: Exterior; Automatically Embed: yes; Curtain Panel: System Panel : glas_offset 35; Join Condition: Border and Vertical Grid Continuous
Type - Identity Data(Type) - Workset: Curtain Wall Types; Assembly Code: 31; Assembly Description: buitenwandopeningen; Description: Kunststof kozijn Gealan Kubus; Type Mark: K26; Type Name: K_26
Type - Horizontal Grid(Type) - Adjust for Mullion Size: no
Type - Vertical Grid(Type) - Adjust for Mullion Size: no
Type - Horizontal Mullions(Type) - Border 1 Type: Rectangular Mullion : 120x83 Gealan Kubus; Border 2 Type: Rectangular Mullion : 100x83 Gealan Kubus; Interior Type: Rectangular Mullion : 100x83 Gealan Kubus
Type - Vertical Mullions(Type) - Border 1 Type: Rectangular Mullion : 100x83 Gealan Kubus; Border 2 Type: Rectangular Mullion : 100x83 Gealan Kubus; Interior Type: Rectangular Mullion : 100x83 Gealan Kubus
Type - Pset_CurtainWallCommon - IsExternal: yes
Type - Pset_ProductRequirements - Category: Walls
Type - Pset_kozijnen (CW) - Kozijnmerk: K26
Classification: 31 Uniformat (Uniformat); Group: Model Group:Merk K26:5538527
Pset_CurtainWallCommon - Reference: K_26
Pset_QuantityTakeOff - Reference: K_26
Pset_wanden - Structural Usage: Non-bearing; Omschrijving: Kunststof kozijn Gealan Kubus; NL-sfb-Codering: 31
Pset_kozijnen (CW) - Omschrijving: Kunststof kozijn Gealan Kubus; NL-sfb-Codering: 31
Pset_DAT_KMS - Assembly Code: 31; Assembly Description: buitenwandopeningen; Description: Kunststof kozijn Gealan Kubus
Other - Category: Walls; Family: Curtain Wall; Doorvalveilig 1-zijdig: no; Doorvalveilig 2-zijdig: yes; Family and Type: Curtain Wall: K_26; Type: K_26; Type Id: 4951884
Constraints - Top Offset: 0 mm; Base is Attached: no; Related to Mass: no; Room Bounding: yes; Top is Attached: no; Base Constraint: 1; Base Offset: -20 mm; Unconnected Height: 2760 mm
Dimensions - Area: 4.1262 m2; Length: 1495 mm
Identity Data - Workset: Bouwkundig
Phasing - Phase Created: 2. nieuwbouw
Structural - Structural Usage: Non-bearing; Structural: no
Text - NLRS_C_merk: K01
Horizontal Grid - Angle: 0 deg; Justification: Beginning; Number: 4; Offset: 0 mm; sets with these values: 2
Cross-Section Definition - Cross-Section: Vertical

# IfcCurtainWall: Curtain Wall:K_27, Curtain Wall:K_27:5538542
In: 01 eerste verdieping
Type - Other(Type) - Category: Walls; Family Name: Curtain Wall
Type - Construction(Type) - Function: Exterior; Automatically Embed: yes; Curtain Panel: System Panel : glas_offset 35; Join Condition: Border and Vertical Grid Continuous
Type - Identity Data(Type) - Workset: Curtain Wall Types; Assembly Code: 31; Assembly Description: buitenwandopeningen; Description: Kunststof kozijn Gealan Kubus; Type Mark: K27; Type Name: K_27
Type - Horizontal Grid(Type) - Adjust for Mullion Size: no
Type - Vertical Grid(Type) - Adjust for Mullion Size: no
Type - Horizontal Mullions(Type) - Border 1 Type: Rectangular Mullion : 120x83 Gealan Kubus; Border 2 Type: Rectangular Mullion : 100x83 Gealan Kubus; Interior Type: Rectangular Mullion : 100x83 Gealan Kubus
Type - Vertical Mullions(Type) - Border 1 Type: Rectangular Mullion : 100x83 Gealan Kubus; Border 2 Type: Rectangular Mullion : 100x83 Gealan Kubus; Interior Type: Rectangular Mullion : 100x83 Gealan Kubus
Type - Pset_CurtainWallCommon - IsExternal: yes
Type - Pset_ProductRequirements - Category: Walls
Type - Pset_kozijnen (CW) - Kozijnmerk: K27
Classification: 31 Uniformat (Uniformat); Group: Model Group:Merk K27:5538541
Pset_CurtainWallCommon - Reference: K_27
Pset_QuantityTakeOff - Reference: K_27
Pset_wanden - Structural Usage: Non-bearing; Omschrijving: Kunststof kozijn Gealan Kubus; NL-sfb-Codering: 31
Pset_kozijnen (CW) - Omschrijving: Kunststof kozijn Gealan Kubus; NL-sfb-Codering: 31
Pset_DAT_KMS - Assembly Code: 31; Assembly Description: buitenwandopeningen; Description: Kunststof kozijn Gealan Kubus
Other - Category: Walls; Family: Curtain Wall; Doorvalveilig 1-zijdig: no; Doorvalveilig 2-zijdig: yes; Family and Type: Curtain Wall: K_27; Type: K_27; Type Id: 4952631
Constraints - Top Offset: 0 mm; Base is Attached: no; Related to Mass: no; Room Bounding: yes; Top is Attached: no; Base Constraint: 1; Base Offset: -20 mm; Unconnected Height: 2760 mm
Dimensions - Area: 9.522 m2; Length: 3450 mm
Identity Data - Workset: Bouwkundig
Phasing - Phase Created: 2. nieuwbouw
Structural - Structural Usage: Non-bearing; Structural: no
Text - NLRS_C_merk: K01
Horizontal Grid - Angle: 0 deg; Justification: Beginning; Number: 4; Offset: 0 mm; sets with these values: 2
Cross-Section Definition - Cross-Section: Vertical

# IfcCurtainWall: Curtain Wall:K_28 (13)
In: 01 eerste verdieping
Type - Other(Type) - Category: Walls; Family Name: Curtain Wall
Type - Construction(Type) - Function: Exterior; Automatically Embed: yes; Curtain Panel: System Panel : glas_offset 35; Join Condition: Border and Vertical Grid Continuous
Type - Identity Data(Type) - Workset: Curtain Wall Types; Assembly Code: 31; Assembly Description: buitenwandopeningen; Description: Kunststof kozijn Gealan Kubus; Type Mark: K28; Type Name: K_28
Type - Horizontal Grid(Type) - Adjust for Mullion Size: no
Type - Vertical Grid(Type) - Adjust for Mullion Size: no
Type - Horizontal Mullions(Type) - Border 1 Type: Rectangular Mullion : 120x83 Gealan Kubus; Border 2 Type: Rectangular Mullion : 100x83 Gealan Kubus; Interior Type: Rectangular Mullion : 100x83 Gealan Kubus
Type - Vertical Mullions(Type) - Border 1 Type: Rectangular Mullion : 100x83 Gealan Kubus; Border 2 Type: Rectangular Mullion : 100x83 Gealan Kubus; Interior Type: Rectangular Mullion : 100x83 Gealan Kubus
Type - Pset_CurtainWallCommon - IsExternal: yes
Type - Pset_ProductRequirements - Category: Walls
Type - Pset_kozijnen (CW) - Kozijnmerk: K28
Classification: 31 Uniformat (Uniformat)
Pset_CurtainWallCommon - Reference: K_28
Pset_QuantityTakeOff - Reference: K_28
Pset_wanden - Structural Usage: Non-bearing; Omschrijving: Kunststof kozijn Gealan Kubus; NL-sfb-Codering: 31
Pset_kozijnen (CW) - Omschrijving: Kunststof kozijn Gealan Kubus; NL-sfb-Codering: 31
Pset_DAT_KMS - Assembly Code: 31; Assembly Description: buitenwandopeningen; Description: Kunststof kozijn Gealan Kubus
Other - Category: Walls; Family: Curtain Wall; Doorvalveilig 1-zijdig: no; Doorvalveilig 2-zijdig: yes; Family and Type: Curtain Wall: K_28; Type: K_28; Type Id: 6068408
Constraints - Top Offset: 0 mm; Base is Attached: no; Related to Mass: no; Room Bounding: yes; Top is Attached: no; Base Constraint: 1; Base Offset: 810 mm; Unconnected Height: 1930 mm
Dimensions - Area: 1.6984 m2; Length: 880 mm
Identity Data - Workset: Bouwkundig
Phasing - Phase Created: 2. nieuwbouw
Structural - Structural Usage: Non-bearing; Structural: no
Text - NLRS_C_merk: K01
Horizontal Grid - Angle: 0 deg; Justification: Beginning; Number: 4; Offset: 0 mm; sets with these values: 2
Cross-Section Definition - Cross-Section: Vertical
Name (Curtain Wall:K_28:...) | Group
6064878 | Model Group:Merk K28:6064868
6064897 | Model Group:Merk K28:6064887
6064916 | Model Group:Merk K28:6064906
6064935 | Model Group:Merk K28:6064925
6064954 | Model Group:Merk K28:6064944
6064973 | Model Group:Merk K28:6064963
6064992 | Model Group:Merk K28:6064982
6065030 | Model Group:Merk K28:6065020
6065049 | Model Group:Merk K28:6065039
6065087 | Model Group:Merk K28:6065077
6065106 | Model Group:Merk K28:6065096
6065125 | Model Group:Merk K28:6065115
6065144 | Model Group:Merk K28:6065134

# IfcCurtainWall: Curtain Wall:K_29 (18)
In: 01 eerste verdieping
Type - Other(Type) - Category: Walls; Family Name: Curtain Wall
Type - Construction(Type) - Function: Exterior; Automatically Embed: yes; Curtain Panel: System Panel : glas_offset 35; Join Condition: Border and Vertical Grid Continuous
Type - Identity Data(Type) - Workset: Curtain Wall Types; Assembly Code: 31; Assembly Description: buitenwandopeningen; Description: Kunststof kozijn Gealan Kubus; Type Comments: Kunststof kozijn; Type Mark: K29; Type Name: K_29
Type - Horizontal Grid(Type) - Adjust for Mullion Size: no
Type - Vertical Grid(Type) - Adjust for Mullion Size: no
Type - Horizontal Mullions(Type) - Border 1 Type: Rectangular Mullion : 120x83 Gealan Kubus; Border 2 Type: Rectangular Mullion : 100x83 Gealan Kubus; Interior Type: Rectangular Mullion : 100x83 Gealan Kubus
Type - Vertical Mullions(Type) - Border 1 Type: Rectangular Mullion : 100x83 Gealan Kubus; Border 2 Type: Rectangular Mullion : 100x83 Gealan Kubus; Interior Type: Rectangular Mullion : 100x83 Gealan Kubus
Type - Pset_CurtainWallCommon - IsExternal: yes
Type - Pset_ProductRequirements - Category: Walls
Type - Pset_kozijnen (CW) - Kozijnmerk: K29
Classification: 31 Uniformat (Uniformat)
Pset_CurtainWallCommon - Reference: K_29
Pset_QuantityTakeOff - Reference: K_29
Pset_wanden - Structural Usage: Non-bearing; Omschrijving: Kunststof kozijn Gealan Kubus; NL-sfb-Codering: 31
Pset_kozijnen (CW) - Omschrijving: Kunststof kozijn Gealan Kubus; NL-sfb-Codering: 31
Pset_DAT_KMS - Assembly Code: 31; Assembly Description: buitenwandopeningen; Description: Kunststof kozijn Gealan Kubus
Other - Category: Walls; Family: Curtain Wall; Doorvalveilig 1-zijdig: no; Doorvalveilig 2-zijdig: yes; Family and Type: Curtain Wall: K_29; Type: K_29; Type Id: 4860879
Constraints - Top Offset: 0 mm; Base is Attached: no; Related to Mass: no; Room Bounding: yes; Top is Attached: no; Base Constraint: 1; Base Offset: 810 mm; Unconnected Height: 1930 mm
Dimensions - Area: 1.5247 m2; Length: 790 mm
Identity Data - Workset: Bouwkundig
Phasing - Phase Created: 2. nieuwbouw
Structural - Structural Usage: Non-bearing; Structural: no
Text - NLRS_C_merk: K01
Horizontal Grid - Angle: 0 deg; Justification: Beginning; Number: 4; Offset: 0 mm; sets with these values: 2
Cross-Section Definition - Cross-Section: Vertical
Name (Curtain Wall:K_29:...) | Group
5537982 | Model Group:Merk K29:5537981
5538111 | Model Group:Merk K29:5538110
5538120 | Model Group:Merk K29:5538119
5538129 | Model Group:Merk K29:5538128
5538138 | Model Group:Merk K29:5538137
5538147 | Model Group:Merk K29:5538146
5538156 | Model Group:Merk K29:5538155
5538165 | Model Group:Merk K29:5538164
5538174 | Model Group:Merk K29:5538173
5538183 | Model Group:Merk K29:5538182
5538192 | Model Group:Merk K29:5538191
5538201 | Model Group:Merk K29:5538200
5538210 | Model Group:Merk K29:5538209
5538219 | Model Group:Merk K29:5538218
5538228 | Model Group:Merk K29:5538227
5538237 | Model Group:Merk K29:5538236
5538246 | Model Group:Merk K29:5538245
5538255 | Model Group:Merk K29:5538254

# IfcCurtainWall: Curtain Wall:K_30, Curtain Wall:K_30:5537740
In: 01 eerste verdieping
Type - Other(Type) - Category: Walls; Family Name: Curtain Wall
Type - Construction(Type) - Function: Exterior; Automatically Embed: yes; Curtain Panel: System Panel : glas_offset 35; Join Condition: Border and Vertical Grid Continuous
Type - Identity Data(Type) - Workset: Curtain Wall Types; Assembly Code: 31; Assembly Description: buitenwandopeningen; Description: Kunststof kozijn Gealan Kubus; Type Mark: K30; Type Name: K_30
Type - Horizontal Grid(Type) - Adjust for Mullion Size: no
Type - Vertical Grid(Type) - Adjust for Mullion Size: no
Type - Horizontal Mullions(Type) - Border 1 Type: Rectangular Mullion : 120x83 Gealan Kubus; Border 2 Type: Rectangular Mullion : 100x83 Gealan Kubus; Interior Type: Rectangular Mullion : 100x83 Gealan Kubus
Type - Vertical Mullions(Type) - Border 1 Type: Rectangular Mullion : 100x83 Gealan Kubus; Border 2 Type: Rectangular Mullion : 100x83 Gealan Kubus; Interior Type: Rectangular Mullion : 100x83 Gealan Kubus
Type - Pset_CurtainWallCommon - IsExternal: yes
Type - Pset_ProductRequirements - Category: Walls
Type - Pset_kozijnen (CW) - Kozijnmerk: K30
Classification: 31 Uniformat (Uniformat); Group: Model Group:Merk K30:5537739
Pset_CurtainWallCommon - Reference: K_30
Pset_QuantityTakeOff - Reference: K_30
Pset_wanden - Structural Usage: Non-bearing; Omschrijving: Kunststof kozijn Gealan Kubus; NL-sfb-Codering: 31
Pset_kozijnen (CW) - Omschrijving: Kunststof kozijn Gealan Kubus; NL-sfb-Codering: 31
Pset_DAT_KMS - Assembly Code: 31; Assembly Description: buitenwandopeningen; Description: Kunststof kozijn Gealan Kubus
Other - Category: Walls; Family: Curtain Wall; Doorvalveilig 1-zijdig: no; Doorvalveilig 2-zijdig: yes; Family and Type: Curtain Wall: K_30; Type: K_30; Type Id: 4942327
Constraints - Top Offset: 0 mm; Base is Attached: no; Related to Mass: no; Room Bounding: yes; Top is Attached: no; Base Constraint: 1; Base Offset: 810 mm; Unconnected Height: 1930 mm
Dimensions - Area: 1.5247 m2; Length: 790 mm
Identity Data - Workset: Bouwkundig
Phasing - Phase Created: 2. nieuwbouw
Structural - Structural Usage: Non-bearing; Structural: no
Text - NLRS_C_merk: K01
Horizontal Grid - Angle: 0 deg; Justification: Beginning; Number: 4; Offset: 0 mm; sets with these values: 2
Cross-Section Definition - Cross-Section: Vertical

# IfcCurtainWall: Curtain Wall:K_31 (5)
Type - Other(Type) - Category: Walls; Family Name: Curtain Wall
Type - Construction(Type) - Function: Exterior; Automatically Embed: yes; Curtain Panel: System Panel : glas_offset 35; Join Condition: Border and Vertical Grid Continuous
Type - Identity Data(Type) - Workset: Curtain Wall Types; Assembly Code: 31; Assembly Description: buitenwandopeningen; Description: Kunststof kozijn Gealan Kubus; Type Mark: K31; Type Name: K_31
Type - Horizontal Grid(Type) - Adjust for Mullion Size: no
Type - Vertical Grid(Type) - Adjust for Mullion Size: no
Type - Horizontal Mullions(Type) - Border 1 Type: Rectangular Mullion : 120x83 Gealan Kubus; Border 2 Type: Rectangular Mullion : 100x83 Gealan Kubus; Interior Type: Rectangular Mullion : 100x83 Gealan Kubus
Type - Vertical Mullions(Type) - Border 1 Type: Rectangular Mullion : 100x83 Gealan Kubus; Border 2 Type: Rectangular Mullion : 100x83 Gealan Kubus; Interior Type: Rectangular Mullion : 100x83 Gealan Kubus
Type - Pset_CurtainWallCommon - IsExternal: yes
Type - Pset_ProductRequirements - Category: Walls
Type - Pset_kozijnen (CW) - Kozijnmerk: K31
Classification: 31 Uniformat (Uniformat)
Pset_CurtainWallCommon - Reference: K_31
Pset_QuantityTakeOff - Reference: K_31
Pset_wanden - Structural Usage: Non-bearing; Omschrijving: Kunststof kozijn Gealan Kubus; NL-sfb-Codering: 31
Pset_kozijnen (CW) - Omschrijving: Kunststof kozijn Gealan Kubus; NL-sfb-Codering: 31
Pset_DAT_KMS - Assembly Code: 31; Assembly Description: buitenwandopeningen; Description: Kunststof kozijn Gealan Kubus
Other - Category: Walls; Family: Curtain Wall; Doorvalveilig 1-zijdig: no; Doorvalveilig 2-zijdig: yes; Family and Type: Curtain Wall: K_31; Type: K_31; Type Id: 6069143
Constraints - Top Offset: 0 mm; Base is Attached: no; Related to Mass: no; Room Bounding: yes; Top is Attached: no; Unconnected Height: 1930 mm
Dimensions - Area: 1.6984 m2; Length: 880 mm
Identity Data - Workset: Bouwkundig
Phasing - Phase Created: 2. nieuwbouw
Structural - Structural Usage: Non-bearing; Structural: no
Text - NLRS_C_merk: K01
Horizontal Grid - Angle: 0 deg; Justification: Beginning; Number: 4; Offset: 0 mm; sets with these values: 2
Cross-Section Definition - Cross-Section: Vertical
Name (Curtain Wall:K_31:...) | In | Base Constraint | Base Offset (mm) | Group
6315730 | 01 eerste verdieping | 1 | 810 | Model Group:Merk K31:6065001
6315973 | 01 eerste verdieping | 1 | 810 | Model Group:Merk K31:6065058
6322834 | 01 eerste verdieping | 1 | 810 | Model Group:Merk K31:6322821
6322865 | 01 eerste verdieping | 1 | 810 | Model Group:Merk K31:6322854
6474576 | 00 Begane grond | V0 bk. ruwe vloer | 780 | Model Group:Merk K31:6474575

# IfcCurtainWall: Curtain Wall:K_32 (2)
In: 01 eerste verdieping
Type - Other(Type) - Category: Walls; Family Name: Curtain Wall
Type - Construction(Type) - Function: Exterior; Automatically Embed: yes; Curtain Panel: System Panel : glas_offset 35; Join Condition: Border and Vertical Grid Continuous
Type - Identity Data(Type) - Workset: Curtain Wall Types; Assembly Code: 31; Assembly Description: buitenwandopeningen; Description: Kunststof kozijn Gealan Kubus; Type Mark: K32; Type Name: K_32
Type - Horizontal Grid(Type) - Adjust for Mullion Size: no
Type - Vertical Grid(Type) - Adjust for Mullion Size: no
Type - Horizontal Mullions(Type) - Border 1 Type: Rectangular Mullion : 120x83 Gealan Kubus; Border 2 Type: Rectangular Mullion : 100x83 Gealan Kubus; Interior Type: Rectangular Mullion : 100x83 Gealan Kubus
Type - Vertical Mullions(Type) - Border 1 Type: Rectangular Mullion : 100x83 Gealan Kubus; Border 2 Type: Rectangular Mullion : 100x83 Gealan Kubus; Interior Type: Rectangular Mullion : 154x83 Gealan Kubus
Type - Pset_CurtainWallCommon - IsExternal: yes
Type - Pset_ProductRequirements - Category: Walls
Type - Pset_kozijnen (CW) - Kozijnmerk: K32
Classification: 31 Uniformat (Uniformat)
Pset_CurtainWallCommon - Reference: K_32
Pset_QuantityTakeOff - Reference: K_32
Pset_wanden - Structural Usage: Non-bearing; Omschrijving: Kunststof kozijn Gealan Kubus; NL-sfb-Codering: 31
Pset_kozijnen (CW) - Omschrijving: Kunststof kozijn Gealan Kubus; NL-sfb-Codering: 31
Pset_DAT_KMS - Assembly Code: 31; Assembly Description: buitenwandopeningen; Description: Kunststof kozijn Gealan Kubus
Other - Category: Walls; Family: Curtain Wall; Doorvalveilig 1-zijdig: no; Doorvalveilig 2-zijdig: yes; Family and Type: Curtain Wall: K_32; Type: K_32; Type Id: 6474551
Constraints - Top Offset: 0 mm; Base is Attached: no; Related to Mass: no; Room Bounding: yes; Top is Attached: no; Base Constraint: 1; Base Offset: 810 mm; Unconnected Height: 1930 mm
Dimensions - Area: 4.3425 m2; Length: 2250 mm
Identity Data - Workset: Bouwkundig
Phasing - Phase Created: 2. nieuwbouw
Structural - Structural Usage: Non-bearing; Structural: no
Text - NLRS_C_merk: K01
Horizontal Grid - Angle: 0 deg; Justification: Beginning; Number: 4; Offset: 0 mm; sets with these values: 2
Cross-Section Definition - Cross-Section: Vertical
Name (Curtain Wall:K_32:...) | Group
5538103 | Model Group:Merk K32:5538102
6474584 | Model Group:Merk K32:5538094

# IfcCurtainWall: Curtain Wall:Merk H01 (16)
Type - Other(Type) - Category: Walls; Family Name: Curtain Wall
Type - Construction(Type) - Function: Exterior; Automatically Embed: yes; Curtain Panel: 31_WI_glas_1 : 31_glas_2; Join Condition: Border and Horizontal Grid Continuous
Type - Identity Data(Type) - Workset: Curtain Wall Types; Assembly Code: 31.10; Assembly Description: buitenwandopeningen; niet gevuld, algemeen (verzamelniveau); Description: houten kozijn; Manufacturer: ITANNEX; Model: 10-07-2014; Type Mark: H01; Type Name: Merk H01; URL: www.bimvoorfabrikanten.nl
Type - Horizontal Grid(Type) - Adjust for Mullion Size: no
Type - Vertical Grid(Type) - Adjust for Mullion Size: no
Type - Horizontal Mullions(Type) - Border 1 Type: Rectangular Mullion : 31_CWM_067x114; Border 2 Type: Rectangular Mullion : 31_CWM_067x114; Interior Type: Rectangular Mullion : 31_CWM_067x114
Type - Vertical Mullions(Type) - Border 1 Type: Rectangular Mullion : 31_CWM_067x114; Border 2 Type: Rectangular Mullion : 31_CWM_067x114; Interior Type: Rectangular Mullion : 31_CWM_067x114
Type - Pset_CurtainWallCommon - IsExternal: yes
Type - Pset_ManufacturerTypeInformation - Manufacturer: ITANNEX
Type - Pset_ProductRequirements - Category: Walls
Type - Pset_kozijnen (CW) - Kozijnmerk: H01
Classification: 31.10 Uniformat (Uniformat)
Pset_CurtainWallCommon - Reference: Merk H01
Pset_QuantityTakeOff - Reference: Merk H01
Pset_wanden - Structural Usage: Non-bearing; Omschrijving: houten kozijn; NL-sfb-Codering: 31.10
Pset_kozijnen (CW) - Omschrijving: houten kozijn; NL-sfb-Codering: 31.10
Pset_DAT_KMS - Assembly Code: 31.10; Assembly Description: buitenwandopeningen; niet gevuld, algemeen (verzamelniveau); Description: houten kozijn
Other - Category: Walls; Family: Curtain Wall; Family and Type: Curtain Wall: Merk H01; Type: Merk H01; Type Id: 5121256
Constraints - Base Offset: 0 mm; Base is Attached: no; Related to Mass: no; Room Bounding: yes; Top is Attached: no; Top Offset: 400 mm; Unconnected Height: 2390 mm
Dimensions - Area: 2.47126 m2; Length: 1034 mm
Identity Data - Workset: Bouwkundig
Materials and Finishes - NLRS_C_Afwerking Kozijn: Ral 9010 - Deur HPL Formica F2296 Sno White
Phasing - Phase Created: 2. nieuwbouw
Structural - Structural Usage: Non-bearing; Structural: no
Horizontal Grid - Angle: 0 deg; Justification: Beginning; Number: 4; Offset: 0 mm; sets with these values: 2
Cross-Section Definition - Cross-Section: Vertical
Name (Curtain Wall:Merk H01:...) | In | Pset_wanden, NLRS_C_Geluidwering_DnTA = Pset_kozijnen (CW), NLRS_C_Geluidwering_DnTA = Data, NLRS_C_Geluidwering_DnTA | Base Constraint | Group
5125426 | 00 Begane grond | 34 | 0 | Model Group:H01:5125425
5125625 | 00 Begane grond | 34 | 0 | Model Group:H01:5125624
5126010 | 00 Begane grond | 34 | 0 | Model Group:H01:5126009
5126019 | 00 Begane grond | 34 | 0 | Model Group:H01:5126018
5126063 | 00 Begane grond | 34 | 0 | Model Group:H01:5126062 | Pset_wanden - NLRS_C_brandwerendheid: 30; Pset_kozijnen (CW) - Kozijnmerk: S; NLRS_C_brandwerendheid: 30; NLRS_C_gespiegeld: S; Data - NLRS_C_gespiegeld: S; Fire Protection - NLRS_C_brandwerendheid: 30
5126072 | 00 Begane grond | 34 | 0 | Model Group:H01:5126071 | Pset_wanden - NLRS_C_brandwerendheid: 30; Pset_kozijnen (CW) - Kozijnmerk: S; NLRS_C_brandwerendheid: 30; NLRS_C_gespiegeld: S; Data - NLRS_C_gespiegeld: S; Fire Protection - NLRS_C_brandwerendheid: 30
5127341 | 00 Begane grond | 33 | 0 | Model Group:H01:5127340
5127583 | 00 Begane grond | 33 | 0 | Model Group:H01:5127582
5127594 | 00 Begane grond | 33 | 0 | Model Group:H01:5127593
5127605 | 01 eerste verdieping | 33 | 1 | Model Group:H01:5127604
5127616 | 01 eerste verdieping | 33 | 1 | Model Group:H01:5127615
5127627 | 01 eerste verdieping | 33 | 1 | Model Group:H01:5127626
5174550 | 01 eerste verdieping | 25 | 1 | Model Group:H01:5174549
5277201 | 01 eerste verdieping | 25 | 1 | Model Group:H01:5174800
5277237 | 01 eerste verdieping | 25 | 1 | Model Group:H01:5174841
5994925 | 01 eerste verdieping |  | 1 | Model Group:H01:5994924

# IfcCurtainWall: Curtain Wall:Merk H02 (11)
Type - Other(Type) - Category: Walls; Family Name: Curtain Wall
Type - Construction(Type) - Function: Exterior; Automatically Embed: yes; Curtain Panel: 31_WI_glas_1 : 31_glas_2; Join Condition: Border and Horizontal Grid Continuous
Type - Identity Data(Type) - Assembly Code: 31.10; Assembly Description: buitenwandopeningen; niet gevuld, algemeen (verzamelniveau); Description: houten kozijn; Manufacturer: ITANNEX; Model: 10-07-2014; Type Mark: H02; Type Name: Merk H02; URL: www.bimvoorfabrikanten.nl; Workset: Curtain Wall Types
Type - Horizontal Grid(Type) - Adjust for Mullion Size: no
Type - Vertical Grid(Type) - Adjust for Mullion Size: no
Type - Horizontal Mullions(Type) - Border 1 Type: Rectangular Mullion : 31_CWM_067x114; Border 2 Type: Rectangular Mullion : 31_CWM_067x114; Interior Type: Rectangular Mullion : 31_CWM_067x114
Type - Vertical Mullions(Type) - Border 1 Type: Rectangular Mullion : 31_CWM_067x114; Border 2 Type: Rectangular Mullion : 31_CWM_067x114; Interior Type: Rectangular Mullion : 31_CWM_067x114
Type - Pset_CurtainWallCommon - IsExternal: yes
Type - Pset_ManufacturerTypeInformation - Manufacturer: ITANNEX
Type - Pset_ProductRequirements - Category: Walls
Type - Pset_kozijnen (CW) - Kozijnmerk: H02
Classification: 31.10 Uniformat (Uniformat)
Pset_CurtainWallCommon - Reference: Merk H02
Pset_QuantityTakeOff - Reference: Merk H02
Pset_wanden - Structural Usage: Non-bearing; Omschrijving: houten kozijn; NL-sfb-Codering: 31.10
Pset_kozijnen (CW) - Omschrijving: houten kozijn; NL-sfb-Codering: 31.10
Pset_DAT_KMS - Assembly Code: 31.10; Assembly Description: buitenwandopeningen; niet gevuld, algemeen (verzamelniveau); Description: houten kozijn
Other - Category: Walls; Family: Curtain Wall; Family and Type: Curtain Wall: Merk H02; Type: Merk H02; Type Id: 5128107
Constraints - Base Offset: 0 mm; Base is Attached: no; Related to Mass: no; Room Bounding: yes; Top is Attached: no; Top Offset: 400 mm; Unconnected Height: 2390 mm
Dimensions - Area: 2.47126 m2; Length: 1034 mm
Identity Data - Workset: Bouwkundig
Phasing - Phase Created: 2. nieuwbouw
Structural - Structural Usage: Non-bearing; Structural: no
Horizontal Grid - Angle: 0 deg; Justification: Beginning; Number: 4; Offset: 0 mm; sets with these values: 2
Cross-Section Definition - Cross-Section: Vertical
Name (Curtain Wall:Merk H02:...) | In | Pset_wanden, NLRS_C_Geluidwering_DnTA = Pset_kozijnen (CW), NLRS_C_Geluidwering_DnTA = Data, NLRS_C_Geluidwering_DnTA | Base Constraint | NLRS_C_Afwerking Kozijn | Group
5126986 | 00 Begane grond | 25 | 0 | Kozijn Bamboo - Deur Bamboo | Model Group:H02:5126985
5130145 | 00 Begane grond | 25 | 0 | Ral 9010 - Deur HPL Formica F2296 Sno White | Model Group:H02:5130144
5202330 | 00 Begane grond | 25 | 0 | Ral 9010 - Deur HPL Formica F2296 Sno White | Model Group:H02:5127227
5206507 | 00 Begane grond |  | 0 | Ral 9010 - Deur HPL Formica F2296 Sno White | Model Group:H02:5206506
5533682 | 01 eerste verdieping | 25 | 1 | Ral 9010 - Deur HPL Formica F2296 Sno White | Model Group:H02:5533681
5987149 | 01 eerste verdieping | 34 | 1 | Ral 9010 - Deur HPL Formica F2296 Sno White | Model Group:H02:5987148
5987395 | 01 eerste verdieping | 34 | 1 | Ral 9010 - Deur HPL Formica F2296 Sno White | Model Group:H02:5987394
5987403 | 01 eerste verdieping | 25 | 1 | Ral 9010 - Deur HPL Formica F2296 Sno White | Model Group:H02:5987402
6522731 | 00 Begane grond | 25 | 0 | Ral 9010 - Deur HPL Formica F2296 Sno White | Model Group:H02:6522730
6694315 | 00 Begane grond | 25 | 0 | Ral 9010 - Deur HPL Formica F2296 Sno White | Model Group:H02:6694314
6804081 | 00 Begane grond | 25 | 0 | Ral 9010 - Deur HPL Formica F2296 Sno White | Model Group:H02:5126556

# IfcCurtainWall: Curtain Wall:Merk H03 (3)
Type - Other(Type) - Category: Walls; Family Name: Curtain Wall
Type - Construction(Type) - Function: Exterior; Automatically Embed: yes; Curtain Panel: 31_WI_glas_1 : 31_glas_2; Join Condition: Border and Horizontal Grid Continuous
Type - Identity Data(Type) - Workset: Curtain Wall Types; Assembly Code: 31.10; Assembly Description: buitenwandopeningen; niet gevuld, algemeen (verzamelniveau); Description: houten kozijn; Manufacturer: ITANNEX; Model: 10-07-2014; Type Mark: H03; Type Name: Merk H03; URL: www.bimvoorfabrikanten.nl
Type - Horizontal Grid(Type) - Adjust for Mullion Size: no
Type - Vertical Grid(Type) - Adjust for Mullion Size: no
Type - Horizontal Mullions(Type) - Border 1 Type: Rectangular Mullion : 31_CWM_067x114; Border 2 Type: Rectangular Mullion : 31_CWM_067x114; Interior Type: Rectangular Mullion : 31_CWM_067x114
Type - Vertical Mullions(Type) - Border 1 Type: Rectangular Mullion : 31_CWM_067x114; Border 2 Type: Rectangular Mullion : 31_CWM_067x114; Interior Type: Rectangular Mullion : 31_CWM_090x114
Type - Pset_CurtainWallCommon - IsExternal: yes
Type - Pset_ManufacturerTypeInformation - Manufacturer: ITANNEX
Type - Pset_ProductRequirements - Category: Walls
Type - Pset_kozijnen (CW) - Kozijnmerk: H03
Classification: 31.10 Uniformat (Uniformat)
Pset_CurtainWallCommon - Reference: Merk H03
Pset_QuantityTakeOff - Reference: Merk H03
Pset_wanden - Structural Usage: Non-bearing; Omschrijving: houten kozijn; NL-sfb-Codering: 31.10
Pset_kozijnen (CW) - Omschrijving: houten kozijn; NL-sfb-Codering: 31.10
Pset_DAT_KMS - Assembly Code: 31.10; Assembly Description: buitenwandopeningen; niet gevuld, algemeen (verzamelniveau); Description: houten kozijn
Other - Category: Walls; Family: Curtain Wall; Family and Type: Curtain Wall: Merk H03; Type: Merk H03; Type Id: 5128005
Constraints - Base Offset: 0 mm; Base is Attached: no; Related to Mass: no; Room Bounding: yes; Top is Attached: no; Top Offset: 400 mm; Unconnected Height: 2390 mm
Dimensions - Area: 3.5133 m2; Length: 1470 mm
Identity Data - Workset: Bouwkundig
Materials and Finishes - NLRS_C_Afwerking Kozijn: Kozijn Bamboo - Deur Bamboo
Phasing - Phase Created: 2. nieuwbouw
Structural - Structural Usage: Non-bearing; Structural: no
Horizontal Grid - Angle: 0 deg; Justification: Beginning; Number: 4; Offset: 0 mm; sets with these values: 2
Cross-Section Definition - Cross-Section: Vertical
Name (Curtain Wall:Merk H03:...) | In | Pset_wanden, NLRS_C_Geluidwering_DnTA = Pset_kozijnen (CW), NLRS_C_Geluidwering_DnTA = Data, NLRS_C_Geluidwering_DnTA | Pset_wanden, NLRS_C_brandwerendheid = Pset_kozijnen (CW), NLRS_C_brandwerendheid = Fire Protection, NLRS_C_brandwerendheid | Base Constraint | Group
5131934 | 00 Begane grond | 31 | 30 | 0 | Model Group:H03:5131933
5179822 | 01 eerste verdieping | 39 | 20 | 1 | Model Group:H03:5179821
5465828 | 00 Begane grond |  | 30 | 0 | Model Group:H03:5465827

# IfcCurtainWall: Curtain Wall:Merk H04 (3)
In: 00 Begane grond
Type - Other(Type) - Category: Walls; Family Name: Curtain Wall
Type - Construction(Type) - Function: Exterior; Automatically Embed: yes; Curtain Panel: 31_WI_glas_1 : 31_glas_2; Join Condition: Border and Horizontal Grid Continuous
Type - Identity Data(Type) - Workset: Curtain Wall Types; Assembly Code: 31.10; Assembly Description: buitenwandopeningen; niet gevuld, algemeen (verzamelniveau); Description: houten kozijn; Manufacturer: ITANNEX; Model: 10-07-2014; Type Mark: H04; Type Name: Merk H04; URL: www.bimvoorfabrikanten.nl
Type - Horizontal Grid(Type) - Adjust for Mullion Size: no
Type - Vertical Grid(Type) - Adjust for Mullion Size: no
Type - Horizontal Mullions(Type) - Border 1 Type: Rectangular Mullion : 31_CWM_090x114; Border 2 Type: Rectangular Mullion : 31_CWM_090x114; Interior Type: Rectangular Mullion : 31_CWM_090x114
Type - Vertical Mullions(Type) - Border 1 Type: Rectangular Mullion : 31_CWM_090x114; Border 2 Type: Rectangular Mullion : 31_CWM_090x114; Interior Type: Rectangular Mullion : 31_CWM_090x114
Type - Pset_CurtainWallCommon - IsExternal: yes
Type - Pset_ManufacturerTypeInformation - Manufacturer: ITANNEX
Type - Pset_ProductRequirements - Category: Walls
Type - Pset_kozijnen (CW) - Kozijnmerk: H04
Classification: 31.10 Uniformat (Uniformat)
Pset_CurtainWallCommon - Reference: Merk H04
Pset_QuantityTakeOff - Reference: Merk H04
Pset_wanden - Structural Usage: Non-bearing; Omschrijving: houten kozijn; NL-sfb-Codering: 31.10; NLRS_C_Geluidwering_DnTA: 25
Pset_kozijnen (CW) - Omschrijving: houten kozijn; NL-sfb-Codering: 31.10; NLRS_C_Geluidwering_DnTA: 25
Pset_DAT_KMS - Assembly Code: 31.10; Assembly Description: buitenwandopeningen; niet gevuld, algemeen (verzamelniveau); Description: houten kozijn
Other - Category: Walls; Family: Curtain Wall; Family and Type: Curtain Wall: Merk H04; Type: Merk H04; Type Id: 6102986
Constraints - Base Offset: 0 mm; Base is Attached: no; Related to Mass: no; Room Bounding: yes; Top is Attached: no; Base Constraint: 0; Top Offset: 400 mm; Unconnected Height: 2390 mm
Data - NLRS_C_Geluidwering_DnTA: 25
Dimensions - Area: 4.36175 m2; Length: 1825 mm
Identity Data - Workset: Bouwkundig
Materials and Finishes - NLRS_C_Afwerking Kozijn: Kozijn Bamboo - Deur Bamboo
Phasing - Phase Created: 2. nieuwbouw
Structural - Structural Usage: Non-bearing; Structural: no
Horizontal Grid - Angle: 0 deg; Justification: Beginning; Number: 4; Offset: 0 mm; sets with these values: 2
Cross-Section Definition - Cross-Section: Vertical
Name (Curtain Wall:Merk H04:...) | Group | Pset_wanden, NLRS_C_brandwerendheid = Pset_kozijnen (CW), NLRS_C_brandwerendheid = Fire Protection, NLRS_C_brandwerendheid
5130949 | Model Group:H04:5130948
5131647 | Model Group:H04:5131646 | 30
6241462 | Model Group:H04:6241461 | 30

# IfcCurtainWall: Curtain Wall:Merk H05 (14)
Type - Other(Type) - Category: Walls; Family Name: Curtain Wall
Type - Construction(Type) - Function: Exterior; Automatically Embed: yes; Curtain Panel: 31_WI_glas_1 : 31_glas_2; Join Condition: Border and Horizontal Grid Continuous
Type - Identity Data(Type) - Workset: Curtain Wall Types; Assembly Code: 31.10; Assembly Description: buitenwandopeningen; niet gevuld, algemeen (verzamelniveau); Description: houten kozijn; Manufacturer: ITANNEX; Model: 10-07-2014; Type Mark: H05; Type Name: Merk H05; URL: www.bimvoorfabrikanten.nl
Type - Horizontal Grid(Type) - Adjust for Mullion Size: no
Type - Vertical Grid(Type) - Adjust for Mullion Size: no
Type - Horizontal Mullions(Type) - Border 1 Type: Rectangular Mullion : 31_CWM_067x114; Border 2 Type: Rectangular Mullion : 31_CWM_067x114; Interior Type: Rectangular Mullion : 31_CWM_067x114
Type - Vertical Mullions(Type) - Border 1 Type: Rectangular Mullion : 31_CWM_067x114; Border 2 Type: Rectangular Mullion : 31_CWM_067x114; Interior Type: Rectangular Mullion : 31_CWM_067x114
Type - Pset_CurtainWallCommon - IsExternal: yes
Type - Pset_ManufacturerTypeInformation - Manufacturer: ITANNEX
Type - Pset_ProductRequirements - Category: Walls
Type - Pset_kozijnen (CW) - Kozijnmerk: H05
Classification: 31.10 Uniformat (Uniformat)
Pset_CurtainWallCommon - Reference: Merk H05
Pset_QuantityTakeOff - Reference: Merk H05
Pset_wanden - Structural Usage: Non-bearing; Omschrijving: houten kozijn; NL-sfb-Codering: 31.10
Pset_kozijnen (CW) - Omschrijving: houten kozijn; NL-sfb-Codering: 31.10
Pset_DAT_KMS - Assembly Code: 31.10; Assembly Description: buitenwandopeningen; niet gevuld, algemeen (verzamelniveau); Description: houten kozijn
Other - Category: Walls; Family: Curtain Wall; Family and Type: Curtain Wall: Merk H05; Type: Merk H05; Type Id: 5132093
Constraints - Base is Attached: no; Related to Mass: no; Room Bounding: yes; Top is Attached: no; Base Offset: 1200 mm; Top Offset: 400 mm; Unconnected Height: 1190 mm
Dimensions - Area: 0.714 m2; Length: 600 mm
Identity Data - Workset: Bouwkundig
Materials and Finishes - NLRS_C_Afwerking Kozijn: Ral 9010 - Deur HPL Formica F2296 Sno White
Phasing - Phase Created: 2. nieuwbouw
Structural - Structural Usage: Non-bearing; Structural: no
Horizontal Grid - Angle: 0 deg; Justification: Beginning; Number: 4; Offset: 0 mm; sets with these values: 2
Cross-Section Definition - Cross-Section: Vertical
Name (Curtain Wall:Merk H05:...) | In | Pset_wanden, NLRS_C_Geluidwering_DnTA = Pset_kozijnen (CW), NLRS_C_Geluidwering_DnTA = Data, NLRS_C_Geluidwering_DnTA | Base Constraint | Group
5174066 | 00 Begane grond | 39 | 0 | Model Group:H05:5174065
5174266 | 00 Begane grond | 39 | 0 | Model Group:H05:5174265
5174286 | 00 Begane grond | 39 | 0 | Model Group:H05:5174285
5174296 | 01 eerste verdieping | 39 | 1 | Model Group:H05:5174295
5174306 | 01 eerste verdieping | 39 | 1 | Model Group:H05:5174305
5174316 | 01 eerste verdieping | 39 | 1 | Model Group:H05:5174315
5174562 | 01 eerste verdieping | 25 | 1 | Model Group:H05:5174561
5178252 | 01 eerste verdieping | 34 | 1 | Model Group:H05:5178251
5185370 | 01 eerste verdieping | 25 | 1 | Model Group:H05:5185369
5185411 | 01 eerste verdieping | 25 | 1 | Model Group:H05:5185410
5196985 | 00 Begane grond | 34 | 0 | Model Group:H05:5196983
5197462 | 00 Begane grond | 34 | 0 | Model Group:H05:5197461
5197622 | 00 Begane grond | 34 | 0 | Model Group:H05:5197621
5994935 | 01 eerste verdieping | 25 | 1 | Model Group:H05:5994934

# IfcCurtainWall: Curtain Wall:Merk H07 (5)
Type - Other(Type) - Category: Walls; Family Name: Curtain Wall
Type - Construction(Type) - Function: Exterior; Automatically Embed: yes; Curtain Panel: 31_WI_glas_1 : 31_glas_2; Join Condition: Border and Horizontal Grid Continuous
Type - Identity Data(Type) - Workset: Curtain Wall Types; Assembly Code: 31.10; Assembly Description: buitenwandopeningen; niet gevuld, algemeen (verzamelniveau); Description: houten kozijn; Manufacturer: ITANNEX; Model: 10-07-2014; Type Mark: H06; Type Name: Merk H07; URL: www.bimvoorfabrikanten.nl
Type - Horizontal Grid(Type) - Adjust for Mullion Size: no
Type - Vertical Grid(Type) - Adjust for Mullion Size: no
Type - Horizontal Mullions(Type) - Border 1 Type: Rectangular Mullion : 31_CWM_067x114; Border 2 Type: Rectangular Mullion : 31_CWM_067x114; Interior Type: Rectangular Mullion : 31_CWM_067x114
Type - Vertical Mullions(Type) - Border 1 Type: Rectangular Mullion : 31_CWM_067x114; Border 2 Type: Rectangular Mullion : 31_CWM_067x114; Interior Type: Rectangular Mullion : 31_CWM_067x114
Type - Pset_CurtainWallCommon - IsExternal: yes
Type - Pset_ManufacturerTypeInformation - Manufacturer: ITANNEX
Type - Pset_ProductRequirements - Category: Walls
Type - Pset_kozijnen (CW) - Kozijnmerk: H06
Classification: 31.10 Uniformat (Uniformat)
Pset_CurtainWallCommon - Reference: Merk H07
Pset_QuantityTakeOff - Reference: Merk H07
Pset_wanden - Structural Usage: Non-bearing; Omschrijving: houten kozijn; NL-sfb-Codering: 31.10; NLRS_C_Geluidwering_DnTA: 38
Pset_kozijnen (CW) - Omschrijving: houten kozijn; NL-sfb-Codering: 31.10; NLRS_C_Geluidwering_DnTA: 38
Pset_DAT_KMS - Assembly Code: 31.10; Assembly Description: buitenwandopeningen; niet gevuld, algemeen (verzamelniveau); Description: houten kozijn
Other - Category: Walls; Family: Curtain Wall; Family and Type: Curtain Wall: Merk H07; Type: Merk H07; Type Id: 5144215
Constraints - Base Offset: 0 mm; Base is Attached: no; Related to Mass: no; Room Bounding: yes; Top is Attached: no; Top Offset: 400 mm; Unconnected Height: 2390 mm
Data - NLRS_C_Geluidwering_DnTA: 38
Dimensions - Area: 4.7322 m2; Length: 1980 mm
Identity Data - Workset: Bouwkundig
Materials and Finishes - NLRS_C_Afwerking Kozijn: Ral 9010 - Deur HPL Formica F2296 Sno White
Phasing - Phase Created: 2. nieuwbouw
Structural - Structural Usage: Non-bearing; Structural: no
Horizontal Grid - Angle: 0 deg; Justification: Beginning; Number: 4; Offset: 0 mm; sets with these values: 2
Cross-Section Definition - Cross-Section: Vertical
Name (Curtain Wall:Merk H07:...) | In | Base Constraint | Group
5144104 | 00 Begane grond | 0 | Model Group:H07:5144116
5145171 | 00 Begane grond | 0 | Model Group:H07:5145183
5227226 | 01 eerste verdieping | 1 | Model Group:H07:5227238
5227252 | 01 eerste verdieping | 1 | Model Group:H07:5227264
5995271 | 01 eerste verdieping | 1 | Model Group:H07:5995281

# IfcCurtainWall: Curtain Wall:Merk H08 (7)
Type - Other(Type) - Category: Walls; Family Name: Curtain Wall
Type - Construction(Type) - Function: Exterior; Automatically Embed: yes; Curtain Panel: 31_WI_glas_1 : 31_glas_2; Join Condition: Border and Horizontal Grid Continuous
Type - Identity Data(Type) - Workset: Curtain Wall Types; Assembly Code: 31.10; Assembly Description: buitenwandopeningen; niet gevuld, algemeen (verzamelniveau); Description: houten kozijn; Manufacturer: ITANNEX; Model: 10-07-2014; Type Mark: H08; Type Name: Merk H08; URL: www.bimvoorfabrikanten.nl
Type - Horizontal Grid(Type) - Adjust for Mullion Size: no
Type - Vertical Grid(Type) - Adjust for Mullion Size: no
Type - Horizontal Mullions(Type) - Border 1 Type: Rectangular Mullion : 31_CWM_067x114; Border 2 Type: Rectangular Mullion : 31_CWM_067x114; Interior Type: Rectangular Mullion : 31_CWM_067x114
Type - Vertical Mullions(Type) - Border 1 Type: Rectangular Mullion : 31_CWM_067x114; Border 2 Type: Rectangular Mullion : 31_CWM_067x114; Interior Type: Rectangular Mullion : 31_CWM_067x114
Type - Pset_CurtainWallCommon - IsExternal: yes
Type - Pset_ManufacturerTypeInformation - Manufacturer: ITANNEX
Type - Pset_ProductRequirements - Category: Walls
Type - Pset_kozijnen (CW) - Kozijnmerk: H08
Classification: 31.10 Uniformat (Uniformat)
Pset_CurtainWallCommon - Reference: Merk H08
Pset_QuantityTakeOff - Reference: Merk H08
Pset_wanden - Structural Usage: Non-bearing; Omschrijving: houten kozijn; NL-sfb-Codering: 31.10; NLRS_C_Geluidwering_DnTA: 31
Pset_kozijnen (CW) - Omschrijving: houten kozijn; NL-sfb-Codering: 31.10; NLRS_C_Geluidwering_DnTA: 31
Pset_DAT_KMS - Assembly Code: 31.10; Assembly Description: buitenwandopeningen; niet gevuld, algemeen (verzamelniveau); Description: houten kozijn
Other - Category: Walls; Family: Curtain Wall; Family and Type: Curtain Wall: Merk H08; Type: Merk H08; Type Id: 5145389
Constraints - Base is Attached: no; Related to Mass: no; Room Bounding: yes; Top is Attached: no; Base Offset: 1200 mm; Top Offset: 400 mm; Unconnected Height: 600 mm
Data - NLRS_C_Geluidwering_DnTA: 31
Dimensions - Area: 1.626 m2; Length: 2710 mm
Identity Data - Workset: Bouwkundig
Materials and Finishes - NLRS_C_Afwerking Kozijn: Kozijn Bamboo - Deur Bamboo
Phasing - Phase Created: 2. nieuwbouw
Structural - Structural Usage: Non-bearing; Structural: no
Horizontal Grid - Angle: 0 deg; Justification: Beginning; Number: 4; Offset: 0 mm; sets with these values: 2
Cross-Section Definition - Cross-Section: Vertical
Name (Curtain Wall:Merk H08:...) | In | Base Constraint | Group
5145321 | 00 Begane grond | 0 | Model Group:H08:5145320
5145663 | 00 Begane grond | 0 | Model Group:H08:5145662
5145687 | 00 Begane grond | 0 | Model Group:H08:5145686
5181880 | 01 eerste verdieping | 1 | Model Group:H08:5181879
5184339 | 01 eerste verdieping | 1 | Model Group:H08:5184338
5184388 | 01 eerste verdieping | 1 | Model Group:H08:5184387
5203603 | 00 Begane grond | 0 | Model Group:H08:5203602

# IfcCurtainWall: Curtain Wall:Merk H09 (13)
Type - Other(Type) - Category: Walls; Family Name: Curtain Wall
Type - Construction(Type) - Function: Exterior; Automatically Embed: yes; Curtain Panel: 31_WI_glas_1 : 31_glas_2; Join Condition: Border and Horizontal Grid Continuous
Type - Identity Data(Type) - Workset: Curtain Wall Types; Assembly Code: 31.10; Assembly Description: buitenwandopeningen; niet gevuld, algemeen (verzamelniveau); Description: houten kozijn; Manufacturer: ITANNEX; Model: 10-07-2014; Type Mark: H09; Type Name: Merk H09; URL: www.bimvoorfabrikanten.nl
Type - Horizontal Grid(Type) - Adjust for Mullion Size: no
Type - Vertical Grid(Type) - Adjust for Mullion Size: no
Type - Horizontal Mullions(Type) - Border 1 Type: Rectangular Mullion : 31_CWM_067x114; Border 2 Type: Rectangular Mullion : 31_CWM_067x114; Interior Type: Rectangular Mullion : 31_CWM_067x114
Type - Vertical Mullions(Type) - Border 1 Type: Rectangular Mullion : 31_CWM_067x114; Border 2 Type: Rectangular Mullion : 31_CWM_067x114; Interior Type: Rectangular Mullion : 31_CWM_067x114
Type - Pset_CurtainWallCommon - IsExternal: yes
Type - Pset_ManufacturerTypeInformation - Manufacturer: ITANNEX
Type - Pset_ProductRequirements - Category: Walls
Type - Pset_kozijnen (CW) - Kozijnmerk: H09
Classification: 31.10 Uniformat (Uniformat)
Pset_CurtainWallCommon - Reference: Merk H09
Pset_QuantityTakeOff - Reference: Merk H09
Pset_wanden - Structural Usage: Non-bearing; Omschrijving: houten kozijn; NL-sfb-Codering: 31.10
Pset_kozijnen (CW) - Omschrijving: houten kozijn; NL-sfb-Codering: 31.10
Pset_DAT_KMS - Assembly Code: 31.10; Assembly Description: buitenwandopeningen; niet gevuld, algemeen (verzamelniveau); Description: houten kozijn
Other - Category: Walls; Family: Curtain Wall; Family and Type: Curtain Wall: Merk H09; Type: Merk H09; Type Id: 5149044
Constraints - Base Offset: 0 mm; Base is Attached: no; Related to Mass: no; Room Bounding: yes; Top is Attached: no; Top Offset: 400 mm; Unconnected Height: 2390 mm
Dimensions - Area: 2.71026 m2; Length: 1134 mm
Identity Data - Workset: Bouwkundig
Phasing - Phase Created: 2. nieuwbouw
Structural - Structural Usage: Non-bearing; Structural: no
Horizontal Grid - Angle: 0 deg; Justification: Beginning; Number: 4; Offset: 0 mm; sets with these values: 2
Cross-Section Definition - Cross-Section: Vertical
Name (Curtain Wall:Merk H09:...) | In | Pset_wanden, NLRS_C_Geluidwering_DnTA = Pset_kozijnen (CW), NLRS_C_Geluidwering_DnTA = Data, NLRS_C_Geluidwering_DnTA | Base Constraint | NLRS_C_Afwerking Kozijn | Group
5149166 | 00 Begane grond | 31 | 0 | Kozijn Bamboo - Deur Bamboo | Model Group:H09:5145245
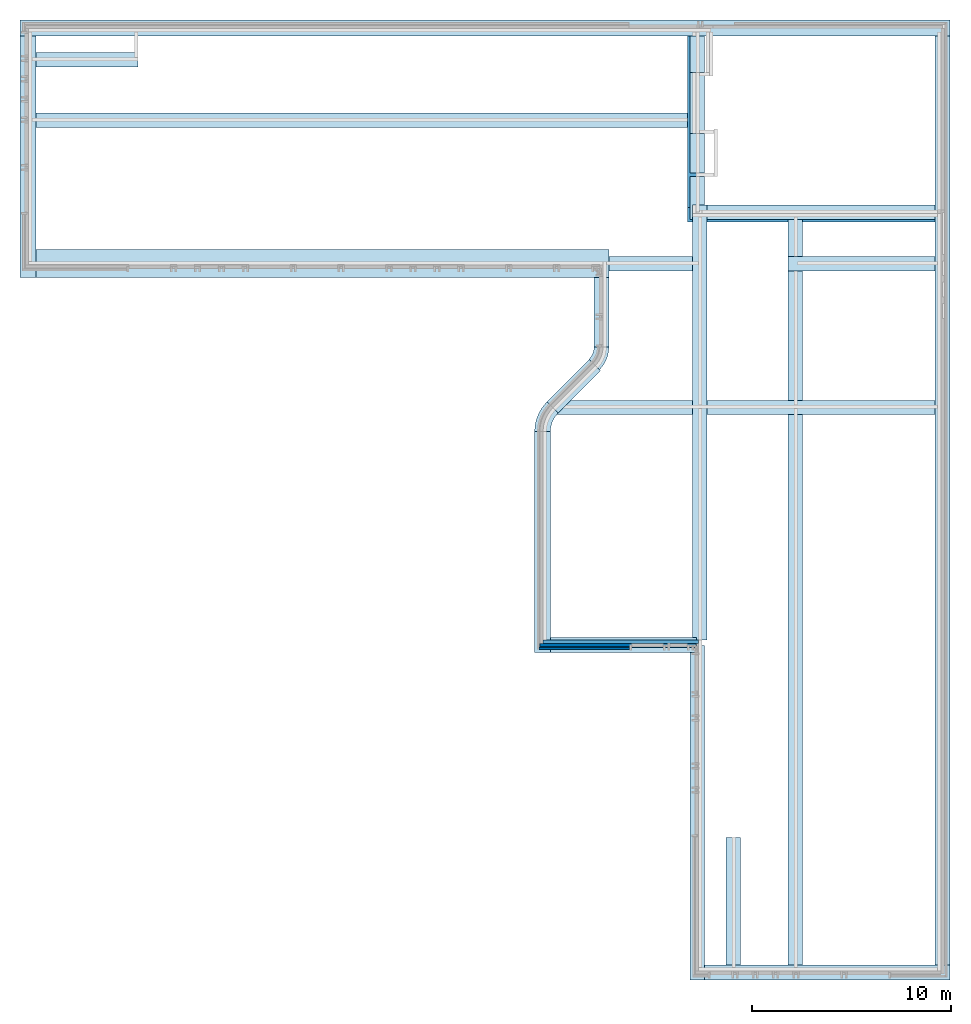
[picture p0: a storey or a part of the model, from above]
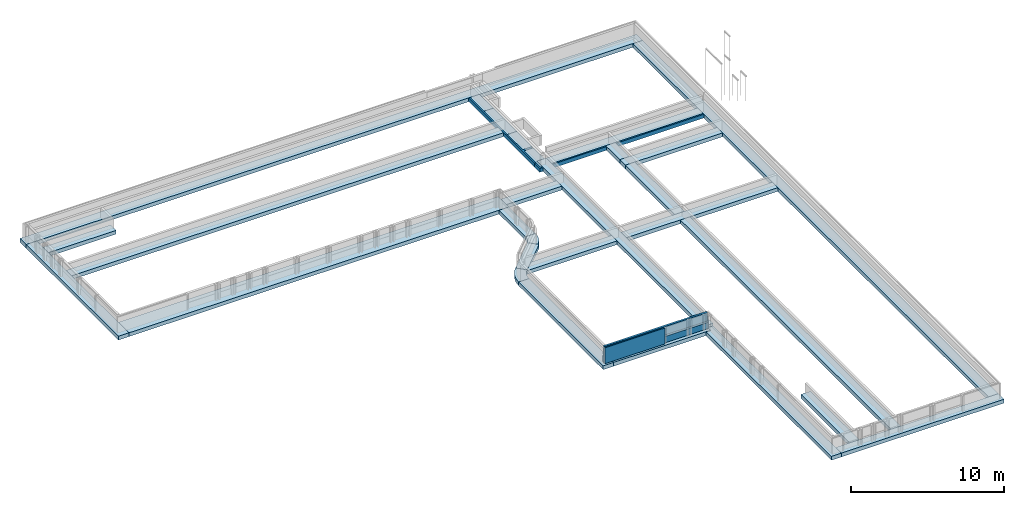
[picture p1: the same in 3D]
Properties of the parts of a building model (IFC2X3), part 12 of 37

# IfcCurtainWall: Curtain Wall:Merk H09 (13)
Name (Curtain Wall:Merk H09:...) | In | Pset_wanden, NLRS_C_Geluidwering_DnTA = Pset_kozijnen (CW), NLRS_C_Geluidwering_DnTA = Data, NLRS_C_Geluidwering_DnTA | Base Constraint | NLRS_C_Afwerking Kozijn | Group
5149210 | 00 Begane grond | 31 | 0 | Kozijn Bamboo - Deur Bamboo | Model Group:H09:5145654
5149218 | 00 Begane grond | 31 | 0 | Kozijn Bamboo - Deur Bamboo | Model Group:H09:5145678
5167023 | 01 eerste verdieping | 31 | 1 | Kozijn Bamboo - Deur Bamboo | Model Group:H09:5167012
5167164 | 01 eerste verdieping | 31 | 1 | Kozijn Bamboo - Deur Bamboo | Model Group:H09:5167153
5174894 | 01 eerste verdieping | 31 | 1 | Kozijn Bamboo - Deur Bamboo | Model Group:H09:5174883
5181898 | 01 eerste verdieping | 31 | 1 | Kozijn Bamboo - Deur Bamboo | Model Group:H09:5181878
5184357 | 01 eerste verdieping | 31 | 1 | Kozijn Bamboo - Deur Bamboo | Model Group:H09:5184337
5184406 | 01 eerste verdieping | 31 | 1 | Kozijn Bamboo - Deur Bamboo | Model Group:H09:5184386
5203621 | 00 Begane grond | 31 | 0 | Kozijn Bamboo - Deur Bamboo | Model Group:H09:5203601
5206888 | 00 Begane grond | 34 | 0 | Ral 9010 - Deur HPL Formica F2296 Sno White | Model Group:H09:5206741
5988148 | 01 eerste verdieping | 31 | 1 | Kozijn Bamboo - Deur Bamboo | Model Group:H09:5988145
6668703 | 00 Begane grond | 39 | 0 | Ral 9010 - Deur HPL Formica F2296 Sno White | Model Group:H09:6668701

# IfcCurtainWall: Curtain Wall:Merk H10, Curtain Wall:Merk H10:5151840
In: 00 Begane grond
Type - Other - Category: Walls; Family Name: Curtain Wall
Type - Construction - Function: Exterior; Automatically Embed: yes; Curtain Panel: 31_WI_glas_1 : 31_glas_2; Join Condition: Border and Horizontal Grid Continuous
Type - Identity Data - Workset: Curtain Wall Types; Assembly Code: 31.10; Assembly Description: buitenwandopeningen; niet gevuld, algemeen (verzamelniveau); Description: houten kozijn; Manufacturer: ITANNEX; Model: 10-07-2014; Type Mark: H10; Type Name: Merk H10; URL: www.bimvoorfabrikanten.nl
Type - Horizontal Grid - Adjust for Mullion Size: no
Type - Vertical Grid - Adjust for Mullion Size: no
Type - Horizontal Mullions - Border 1 Type: Rectangular Mullion : 31_CWM_067x114; Border 2 Type: Rectangular Mullion : 31_CWM_067x114; Interior Type: Rectangular Mullion : 31_CWM_067x114
Type - Vertical Mullions - Border 1 Type: Rectangular Mullion : 31_CWM_067x114; Border 2 Type: Rectangular Mullion : 31_CWM_067x114; Interior Type: Rectangular Mullion : 31_CWM_090x114
Type - Pset_CurtainWallCommon - IsExternal: yes
Type - Pset_ManufacturerTypeInformation - Manufacturer: ITANNEX
Type - Pset_ProductRequirements - Category: Walls
Type - Pset_kozijnen (CW) - Kozijnmerk: H10
Classification: 31.10 Uniformat (Uniformat); Group: Model Group:H10:5151852
Pset_CurtainWallCommon - Reference: Merk H10
Pset_QuantityTakeOff - Reference: Merk H10
Pset_wanden - Structural Usage: Non-bearing; Omschrijving: houten kozijn; NL-sfb-Codering: 31.10; NLRS_C_Geluidwering_DnTA: 34; NLRS_C_brandwerendheid: 30
Pset_kozijnen (CW) - Omschrijving: houten kozijn; NL-sfb-Codering: 31.10; NLRS_C_brandwerendheid: 30; NLRS_C_Geluidwering_DnTA: 34
Pset_DAT_KMS - Assembly Code: 31.10; Assembly Description: buitenwandopeningen; niet gevuld, algemeen (verzamelniveau); Description: houten kozijn
Other - Family: Curtain Wall; Family and Type: Curtain Wall: Merk H10; Type: Merk H10; Type Id: 5152091
Constraints - Base Offset: 0 mm; Base is Attached: no; Related to Mass: no; Room Bounding: yes; Top is Attached: no; Base Constraint: 0; Top Offset: 400 mm; Unconnected Height: 2390 mm
Data - NLRS_C_Geluidwering_DnTA: 34
Dimensions - Area: 7.7914 m2; Length: 3260 mm
Fire Protection - NLRS_C_brandwerendheid: 30
Identity Data - Workset: Bouwkundig
Materials and Finishes - NLRS_C_Afwerking Kozijn: Kozijn Bamboo - Deur Bamboo
Phasing - Phase Created: 2. nieuwbouw
Structural - Structural Usage: Non-bearing; Structural: no
Horizontal Grid - Angle: 0 deg; Justification: Beginning; Number: 4; Offset: 0 mm; sets with these values: 2
Cross-Section Definition - Cross-Section: Vertical

# IfcCurtainWall: Curtain Wall:Merk H11, Curtain Wall:Merk H11:5533689
In: 01 eerste verdieping
Type - Other(Type) - Category: Walls; Family Name: Curtain Wall
Type - Construction(Type) - Function: Exterior; Automatically Embed: yes; Curtain Panel: 31_WI_glas_1 : 31_glas_2; Join Condition: Border and Horizontal Grid Continuous
Type - Identity Data(Type) - Workset: Curtain Wall Types; Assembly Code: 31.10; Assembly Description: buitenwandopeningen; niet gevuld, algemeen (verzamelniveau); Description: houten kozijn; Manufacturer: ITANNEX; Model: 10-07-2014; Type Mark: H11; Type Name: Merk H11; URL: www.bimvoorfabrikanten.nl
Type - Horizontal Grid(Type) - Adjust for Mullion Size: no
Type - Vertical Grid(Type) - Adjust for Mullion Size: no
Type - Horizontal Mullions(Type) - Border 1 Type: Rectangular Mullion : 31_CWM_067x114; Border 2 Type: Rectangular Mullion : 31_CWM_067x114; Interior Type: Rectangular Mullion : 31_CWM_090x114
Type - Vertical Mullions(Type) - Border 1 Type: Rectangular Mullion : 31_CWM_067x114; Border 2 Type: Rectangular Mullion : 31_CWM_067x114; Interior Type: Rectangular Mullion : 31_CWM_090x114
Type - Pset_CurtainWallCommon - IsExternal: yes
Type - Pset_ManufacturerTypeInformation - Manufacturer: ITANNEX
Type - Pset_ProductRequirements - Category: Walls
Type - Pset_kozijnen (CW) - Kozijnmerk: H11
Classification: 31.10 Uniformat (Uniformat); Group: Model Group:H11:5533699
Pset_CurtainWallCommon - Reference: Merk H11
Pset_QuantityTakeOff - Reference: Merk H11
Pset_wanden - Structural Usage: Non-bearing; Omschrijving: houten kozijn; NL-sfb-Codering: 31.10; NLRS_C_Geluidwering_DnTA: 31; NLRS_C_brandwerendheid: 30
Pset_kozijnen (CW) - Omschrijving: houten kozijn; NL-sfb-Codering: 31.10; NLRS_C_brandwerendheid: 30; NLRS_C_Geluidwering_DnTA: 31
Pset_DAT_KMS - Assembly Code: 31.10; Assembly Description: buitenwandopeningen; niet gevuld, algemeen (verzamelniveau); Description: houten kozijn
Other - Category: Walls; Family: Curtain Wall; Family and Type: Curtain Wall: Merk H11; Type: Merk H11; Type Id: 5175472
Constraints - Base Offset: 0 mm; Base is Attached: no; Related to Mass: no; Room Bounding: yes; Top is Attached: no; Base Constraint: 1; Top Offset: 400 mm; Unconnected Height: 3190 mm
Data - NLRS_C_Geluidwering_DnTA: 31
Dimensions - Area: 9.4743 m2; Length: 2970 mm
Fire Protection - NLRS_C_brandwerendheid: 30
Identity Data - Workset: Bouwkundig
Materials and Finishes - NLRS_C_Afwerking Kozijn: Ral 9010 - Deur HPL Formica F2296 Sno White
Phasing - Phase Created: 2. nieuwbouw
Structural - Structural Usage: Non-bearing; Structural: no
Horizontal Grid - Angle: 0 deg; Justification: Beginning; Number: 4; Offset: 0 mm; sets with these values: 2
Cross-Section Definition - Cross-Section: Vertical

# IfcCurtainWall: Curtain Wall:Merk H12, Curtain Wall:Merk H12:5194902
In: 01 eerste verdieping
Type - Other(Type) - Category: Walls; Family Name: Curtain Wall
Type - Construction(Type) - Function: Exterior; Automatically Embed: yes; Curtain Panel: 31_WI_glas_1 : 31_glas_2; Join Condition: Border and Horizontal Grid Continuous
Type - Identity Data(Type) - Workset: Curtain Wall Types; Assembly Code: 31.10; Assembly Description: buitenwandopeningen; niet gevuld, algemeen (verzamelniveau); Description: houten kozijn; Manufacturer: ITANNEX; Model: 10-07-2014; Type Mark: H12; Type Name: Merk H12; URL: www.bimvoorfabrikanten.nl
Type - Horizontal Grid(Type) - Adjust for Mullion Size: no
Type - Vertical Grid(Type) - Adjust for Mullion Size: no
Type - Horizontal Mullions(Type) - Border 1 Type: Rectangular Mullion : 31_CWM_067x114; Border 2 Type: Rectangular Mullion : 31_CWM_067x114; Interior Type: Rectangular Mullion : 31_CWM_090x114
Type - Vertical Mullions(Type) - Border 1 Type: Rectangular Mullion : 31_CWM_067x114; Border 2 Type: Rectangular Mullion : 31_CWM_067x114; Interior Type: Rectangular Mullion : 31_CWM_090x114
Type - Pset_CurtainWallCommon - IsExternal: yes
Type - Pset_ManufacturerTypeInformation - Manufacturer: ITANNEX
Type - Pset_ProductRequirements - Category: Walls
Type - Pset_kozijnen (CW) - Kozijnmerk: H12
Classification: 31.10 Uniformat (Uniformat); Group: Model Group:H12:5194912
Pset_CurtainWallCommon - Reference: Merk H12
Pset_QuantityTakeOff - Reference: Merk H12
Pset_wanden - Structural Usage: Non-bearing; Omschrijving: houten kozijn; NL-sfb-Codering: 31.10; NLRS_C_Geluidwering_DnTA: 34; NLRS_C_brandwerendheid: 30
Pset_kozijnen (CW) - Omschrijving: houten kozijn; NL-sfb-Codering: 31.10; NLRS_C_brandwerendheid: 30; NLRS_C_Geluidwering_DnTA: 34
Pset_DAT_KMS - Assembly Code: 31.10; Assembly Description: buitenwandopeningen; niet gevuld, algemeen (verzamelniveau); Description: houten kozijn
Other - Category: Walls; Family: Curtain Wall; Family and Type: Curtain Wall: Merk H12; Type: Merk H12; Type Id: 5181526
Constraints - Base Offset: 0 mm; Base is Attached: no; Related to Mass: no; Room Bounding: yes; Top is Attached: no; Base Constraint: 1; Top Offset: 400 mm; Unconnected Height: 3190 mm
Data - NLRS_C_Geluidwering_DnTA: 34
Dimensions - Area: 10.4313 m2; Length: 3270 mm
Fire Protection - NLRS_C_brandwerendheid: 30
Identity Data - Workset: Bouwkundig
Materials and Finishes - NLRS_C_Afwerking Kozijn: Ral 9010 - Deur HPL Formica F2296 Sno White
Phasing - Phase Created: 2. nieuwbouw
Structural - Structural Usage: Non-bearing; Structural: no
Horizontal Grid - Angle: 0 deg; Justification: Beginning; Number: 4; Offset: 0 mm; sets with these values: 2
Cross-Section Definition - Cross-Section: Vertical

# IfcCurtainWall: Curtain Wall:Merk H13 (6)
In: 01 eerste verdieping
Type - Other(Type) - Category: Walls; Family Name: Curtain Wall
Type - Construction(Type) - Function: Exterior; Automatically Embed: yes; Curtain Panel: 31_WI_glas_1 : 31_glas_2; Join Condition: Border and Horizontal Grid Continuous
Type - Identity Data(Type) - Workset: Curtain Wall Types; Assembly Code: 31.10; Assembly Description: buitenwandopeningen; niet gevuld, algemeen (verzamelniveau); Description: houten kozijn; Manufacturer: ITANNEX; Model: 10-07-2014; Type Mark: H13; Type Name: Merk H13; URL: www.bimvoorfabrikanten.nl
Type - Horizontal Grid(Type) - Adjust for Mullion Size: no
Type - Vertical Grid(Type) - Adjust for Mullion Size: no
Type - Horizontal Mullions(Type) - Border 1 Type: Rectangular Mullion : 31_CWM_067x114; Border 2 Type: Rectangular Mullion : 31_CWM_067x114; Interior Type: Rectangular Mullion : 31_CWM_067x114
Type - Vertical Mullions(Type) - Border 1 Type: Rectangular Mullion : 31_CWM_067x114; Border 2 Type: Rectangular Mullion : 31_CWM_067x114; Interior Type: Rectangular Mullion : 31_CWM_067x114
Type - Pset_CurtainWallCommon - IsExternal: yes
Type - Pset_ManufacturerTypeInformation - Manufacturer: ITANNEX
Type - Pset_ProductRequirements - Category: Walls
Type - Pset_kozijnen (CW) - Kozijnmerk: H13
Classification: 31.10 Uniformat (Uniformat)
Pset_CurtainWallCommon - Reference: Merk H13
Pset_QuantityTakeOff - Reference: Merk H13
Pset_wanden - Structural Usage: Non-bearing; Omschrijving: houten kozijn; NL-sfb-Codering: 31.10
Pset_kozijnen (CW) - Omschrijving: houten kozijn; NL-sfb-Codering: 31.10
Pset_DAT_KMS - Assembly Code: 31.10; Assembly Description: buitenwandopeningen; niet gevuld, algemeen (verzamelniveau); Description: houten kozijn
Other - Category: Walls; Family: Curtain Wall; Family and Type: Curtain Wall: Merk H13; Type: Merk H13; Type Id: 6102836
Constraints - Base is Attached: no; Related to Mass: no; Room Bounding: yes; Top is Attached: no; Base Constraint: 1; Base Offset: 1200 mm; Top Offset: 400 mm; Unconnected Height: 600 mm
Dimensions - Area: 1.323 m2; Length: 2205 mm
Identity Data - Workset: Bouwkundig
Phasing - Phase Created: 2. nieuwbouw
Structural - Structural Usage: Non-bearing; Structural: no
Horizontal Grid - Angle: 0 deg; Justification: Beginning; Number: 4; Offset: 0 mm; sets with these values: 2
Cross-Section Definition - Cross-Section: Vertical
Name (Curtain Wall:Merk H13:...) | Pset_wanden, NLRS_C_Geluidwering_DnTA = Pset_kozijnen (CW), NLRS_C_Geluidwering_DnTA = Data, NLRS_C_Geluidwering_DnTA | NLRS_C_Afwerking Kozijn | Group
5185192 | 31 | Kozijn Bamboo - Deur Bamboo | Model Group:H13:5167154
5185255 | 31 | Kozijn Bamboo - Deur Bamboo | Model Group:H13:5167013
5185263 | 31 | Kozijn Bamboo - Deur Bamboo | Model Group:H13:5174884
5185277 | 31 | Ral 9010 - Deur HPL Formica F2296 Sno White | Model Group:H13:5184708
5274117 |  | Ral 9010 - Deur HPL Formica F2296 Sno White | Model Group:H13:5274116
5988164 | 31 | Kozijn Bamboo - Deur Bamboo | Model Group:H13:5988146

# IfcCurtainWall: Curtain Wall:Merk H14 (2)
In: 00 Begane grond
Type - Other(Type) - Category: Walls; Family Name: Curtain Wall
Type - Construction(Type) - Function: Exterior; Automatically Embed: yes; Curtain Panel: 31_WI_glas_1 : 31_glas_2; Join Condition: Border and Horizontal Grid Continuous
Type - Identity Data(Type) - Workset: Curtain Wall Types; Assembly Code: 31.10; Assembly Description: buitenwandopeningen; niet gevuld, algemeen (verzamelniveau); Description: houten kozijn; Manufacturer: ITANNEX; Model: 10-07-2014; Type Mark: H14; Type Name: Merk H14; URL: www.bimvoorfabrikanten.nl
Type - Horizontal Grid(Type) - Adjust for Mullion Size: no
Type - Vertical Grid(Type) - Adjust for Mullion Size: no
Type - Horizontal Mullions(Type) - Border 1 Type: Rectangular Mullion : 31_CWM_067x114; Border 2 Type: Rectangular Mullion : 31_CWM_067x114; Interior Type: Rectangular Mullion : 31_CWM_067x114
Type - Vertical Mullions(Type) - Border 1 Type: Rectangular Mullion : 31_CWM_067x114; Border 2 Type: Rectangular Mullion : 31_CWM_067x114; Interior Type: Rectangular Mullion : 31_CWM_067x114
Type - Pset_CurtainWallCommon - IsExternal: yes
Type - Pset_ManufacturerTypeInformation - Manufacturer: ITANNEX
Type - Pset_ProductRequirements - Category: Walls
Type - Pset_kozijnen (CW) - Kozijnmerk: H14
Classification: 31.10 Uniformat (Uniformat)
Pset_CurtainWallCommon - Reference: Merk H14
Pset_QuantityTakeOff - Reference: Merk H14
Pset_wanden - Structural Usage: Non-bearing; Omschrijving: houten kozijn; NL-sfb-Codering: 31.10; NLRS_C_Geluidwering_DnTA: 25
Pset_kozijnen (CW) - Omschrijving: houten kozijn; NL-sfb-Codering: 31.10; NLRS_C_Geluidwering_DnTA: 25
Pset_DAT_KMS - Assembly Code: 31.10; Assembly Description: buitenwandopeningen; niet gevuld, algemeen (verzamelniveau); Description: houten kozijn
Other - Category: Walls; Family: Curtain Wall; Family and Type: Curtain Wall: Merk H14; Type: Merk H14; Type Id: 5142452
Constraints - Base Offset: 0 mm; Base is Attached: no; Related to Mass: no; Room Bounding: yes; Top is Attached: no; Base Constraint: 0; Top Offset: 400 mm; Unconnected Height: 2390 mm
Data - NLRS_C_Geluidwering_DnTA: 25
Identity Data - Workset: Bouwkundig
Materials and Finishes - NLRS_C_Afwerking Kozijn: Kozijn Bamboo - Deur Bamboo
Phasing - Phase Created: 2. nieuwbouw
Structural - Structural Usage: Non-bearing; Structural: no
Horizontal Grid - Angle: 0 deg; Justification: Beginning; Number: 4; Offset: 0 mm; sets with these values: 2
Cross-Section Definition - Cross-Section: Vertical
Name (Curtain Wall:Merk H14:...) | Area (m2) | Length (mm) | Group
5142280 | 4.48125 | 1875 | Model Group:H14:5143401
5143923 | 5.0668 | 2120 | Model Group:H06:5143935 | Pset_wanden - NLRS_C_brandwerendheid: 30; Pset_kozijnen (CW) - NLRS_C_brandwerendheid: 30; Fire Protection - NLRS_C_brandwerendheid: 30

# IfcCurtainWall: Curtain Wall:Merk H15 (2)
In: 00 Begane grond
Type - Other(Type) - Category: Walls; Family Name: Curtain Wall
Type - Construction(Type) - Function: Exterior; Automatically Embed: yes; Curtain Panel: 31_WI_glas_1 : 31_glas_2; Join Condition: Border and Horizontal Grid Continuous
Type - Identity Data(Type) - Workset: Curtain Wall Types; Assembly Code: 31.10; Assembly Description: buitenwandopeningen; niet gevuld, algemeen (verzamelniveau); Description: houten kozijn; Manufacturer: ITANNEX; Model: 10-07-2014; Type Mark: H15; Type Name: Merk H15; URL: www.bimvoorfabrikanten.nl
Type - Horizontal Grid(Type) - Adjust for Mullion Size: no
Type - Vertical Grid(Type) - Adjust for Mullion Size: no
Type - Horizontal Mullions(Type) - Border 1 Type: Rectangular Mullion : 31_CWM_067x114; Border 2 Type: Rectangular Mullion : 31_CWM_067x114; Interior Type: Rectangular Mullion : 31_CWM_067x114
Type - Vertical Mullions(Type) - Border 1 Type: Rectangular Mullion : 31_CWM_067x114; Border 2 Type: Rectangular Mullion : 31_CWM_067x114; Interior Type: Rectangular Mullion : 31_CWM_067x114
Type - Pset_CurtainWallCommon - IsExternal: yes
Type - Pset_ManufacturerTypeInformation - Manufacturer: ITANNEX
Type - Pset_ProductRequirements - Category: Walls
Type - Pset_kozijnen (CW) - Kozijnmerk: H15
Classification: 31.10 Uniformat (Uniformat)
Pset_CurtainWallCommon - Reference: Merk H15
Pset_QuantityTakeOff - Reference: Merk H15
Pset_wanden - Structural Usage: Non-bearing; Omschrijving: houten kozijn; NL-sfb-Codering: 31.10; NLRS_C_Geluidwering_DnTA: 25
Pset_kozijnen (CW) - Omschrijving: houten kozijn; NL-sfb-Codering: 31.10; NLRS_C_Geluidwering_DnTA: 25
Pset_DAT_KMS - Assembly Code: 31.10; Assembly Description: buitenwandopeningen; niet gevuld, algemeen (verzamelniveau); Description: houten kozijn
Other - Category: Walls; Family: Curtain Wall; Family and Type: Curtain Wall: Merk H15; Type: Merk H15; Type Id: 5184984
Constraints - Base is Attached: no; Related to Mass: no; Room Bounding: yes; Top is Attached: no; Base Constraint: 0; Base Offset: 1000 mm; Top Offset: 400 mm; Unconnected Height: 600 mm
Data - NLRS_C_Geluidwering_DnTA: 25
Dimensions - Area: 1.44 m2; Length: 2400 mm
Identity Data - Workset: Bouwkundig
Materials and Finishes - NLRS_C_Afwerking Kozijn: Kozijn Bamboo - Deur Bamboo
Phasing - Phase Created: 2. nieuwbouw
Structural - Structural Usage: Non-bearing; Structural: no
Horizontal Grid - Angle: 0 deg; Justification: Beginning; Number: 4; Offset: 0 mm; sets with these values: 2
Cross-Section Definition - Cross-Section: Vertical
Name (Curtain Wall:Merk H15:...) | Group
5270211 | Model Group:H15:5270210 | Pset_wanden - NLRS_C_brandwerendheid: 30; Pset_kozijnen (CW) - NLRS_C_brandwerendheid: 30; Fire Protection - NLRS_C_brandwerendheid: 30
5271079 | Model Group:H15:5271078

# IfcCurtainWall: Curtain Wall:Merk H16 (13)
Type - Other(Type) - Category: Walls; Family Name: Curtain Wall
Type - Construction(Type) - Function: Exterior; Automatically Embed: yes; Curtain Panel: 31_WI_glas_1 : 31_glas_2; Join Condition: Border and Horizontal Grid Continuous
Type - Identity Data(Type) - Workset: Curtain Wall Types; Assembly Code: 31.10; Assembly Description: buitenwandopeningen; niet gevuld, algemeen (verzamelniveau); Description: houten kozijn; Manufacturer: ITANNEX; Model: 10-07-2014; Type Mark: H16; Type Name: Merk H16; URL: www.bimvoorfabrikanten.nl
Type - Horizontal Grid(Type) - Adjust for Mullion Size: no
Type - Vertical Grid(Type) - Adjust for Mullion Size: no
Type - Horizontal Mullions(Type) - Border 1 Type: Rectangular Mullion : 31_CWM_067x114; Border 2 Type: Rectangular Mullion : 31_CWM_067x114; Interior Type: Rectangular Mullion : 31_CWM_067x114
Type - Vertical Mullions(Type) - Border 1 Type: Rectangular Mullion : 31_CWM_067x114; Border 2 Type: Rectangular Mullion : 31_CWM_067x114; Interior Type: Rectangular Mullion : 31_CWM_067x114
Type - Pset_CurtainWallCommon - IsExternal: yes
Type - Pset_ManufacturerTypeInformation - Manufacturer: ITANNEX
Type - Pset_ProductRequirements - Category: Walls
Type - Pset_kozijnen (CW) - Kozijnmerk: H16
Classification: 31.10 Uniformat (Uniformat)
Pset_CurtainWallCommon - Reference: Merk H16
Pset_QuantityTakeOff - Reference: Merk H16
Pset_wanden - Structural Usage: Non-bearing; Omschrijving: houten kozijn; NL-sfb-Codering: 31.10
Pset_kozijnen (CW) - Omschrijving: houten kozijn; NL-sfb-Codering: 31.10
Pset_DAT_KMS - Assembly Code: 31.10; Assembly Description: buitenwandopeningen; niet gevuld, algemeen (verzamelniveau); Description: houten kozijn
Other - Category: Walls; Family: Curtain Wall; Family and Type: Curtain Wall: Merk H16; Type: Merk H16; Type Id: 6103248
Constraints - Base Offset: 0 mm; Base is Attached: no; Related to Mass: no; Room Bounding: yes; Top is Attached: no; Top Offset: 400 mm; Unconnected Height: 2390 mm
Dimensions - Area: 2.47126 m2; Length: 1034 mm
Identity Data - Workset: Bouwkundig
Phasing - Phase Created: 2. nieuwbouw
Structural - Structural Usage: Non-bearing; Structural: no
Horizontal Grid - Angle: 0 deg; Justification: Beginning; Number: 4; Offset: 0 mm; sets with these values: 2
Cross-Section Definition - Cross-Section: Vertical
Name (Curtain Wall:Merk H16:...) | In | Pset_wanden, NLRS_C_Geluidwering_DnTA = Pset_kozijnen (CW), NLRS_C_Geluidwering_DnTA = Data, NLRS_C_Geluidwering_DnTA | Base Constraint | NLRS_C_Afwerking Kozijn | Group | Kozijnmerk = Pset_kozijnen (CW), NLRS_C_gespiegeld = Data, NLRS_C_gespiegeld
5227245 | 01 eerste verdieping | 38 | 1 | Ral 9010 - Deur HPL Formica F2296 Sno White | Model Group:H16:5227244
5276453 | 00 Begane grond | 34 | 0 | Ral 9010 - Deur HPL Formica F2296 Sno White | Model Group:H16:5197611 | S
5276560 | 00 Begane grond | 34 | 0 | Ral 9010 - Deur HPL Formica F2296 Sno White | Model Group:H16:5195722 | S
5276569 | 00 Begane grond | 34 | 0 | Ral 9010 - Deur HPL Formica F2296 Sno White | Model Group:H16:5197451
6382284 | 01 eerste verdieping | 25 | 1 | Kozijn Bamboo - Deur Bamboo | Model Group:H16:5185909 | S
6800002 | 00 Begane grond | 38 | 0 | Ral 9010 - Deur HPL Formica F2296 Sno White | Model Group:H16:5145073
6800234 | 01 eerste verdieping | 38 | 1 | Ral 9010 - Deur HPL Formica F2296 Sno White | Model Group:H16:5987797 | S
6800243 | 01 eerste verdieping | 38 | 1 | Ral 9010 - Deur HPL Formica F2296 Sno White | Model Group:H16:5995318 | S
6801736 | 00 Begane grond | 39 | 0 | Ral 9010 - Deur HPL Formica F2296 Sno White | Model Group:H16:5130407
6801779 | 00 Begane grond | 39 | 0 | Ral 9010 - Deur HPL Formica F2296 Sno White | Model Group:H16:5127086 | S
6802014 | 01 eerste verdieping | 34 | 1 | Ral 9010 - Deur HPL Formica F2296 Sno White | Model Group:H16:5987147
6802177 | 01 eerste verdieping | 34 | 1 | Ral 9010 - Deur HPL Formica F2296 Sno White | Model Group:H16:5987156 | S
6802218 | 01 eerste verdieping | 34 | 1 | Ral 9010 - Deur HPL Formica F2296 Sno White | Model Group:H16:5179182 | S

# IfcCurtainWall: Curtain Wall:Merk H17 (4)
In: 00 Begane grond
Type - Other(Type) - Category: Walls; Family Name: Curtain Wall
Type - Construction(Type) - Function: Exterior; Automatically Embed: yes; Curtain Panel: 31_WI_glas_1 : 31_glas_2; Join Condition: Border and Horizontal Grid Continuous
Type - Identity Data(Type) - Workset: Curtain Wall Types; Assembly Code: 31.10; Assembly Description: buitenwandopeningen; niet gevuld, algemeen (verzamelniveau); Description: houten kozijn; Manufacturer: ITANNEX; Model: 10-07-2014; Type Mark: H17; Type Name: Merk H17; URL: www.bimvoorfabrikanten.nl
Type - Horizontal Grid(Type) - Adjust for Mullion Size: no
Type - Vertical Grid(Type) - Adjust for Mullion Size: no
Type - Horizontal Mullions(Type) - Border 1 Type: Rectangular Mullion : 31_CWM_067x114; Border 2 Type: Rectangular Mullion : 31_CWM_067x114; Interior Type: Rectangular Mullion : 31_CWM_067x114
Type - Vertical Mullions(Type) - Border 1 Type: Rectangular Mullion : 31_CWM_067x114; Border 2 Type: Rectangular Mullion : 31_CWM_067x114; Interior Type: Rectangular Mullion : 31_CWM_067x114
Type - Pset_CurtainWallCommon - IsExternal: yes
Type - Pset_ManufacturerTypeInformation - Manufacturer: ITANNEX
Type - Pset_ProductRequirements - Category: Walls
Type - Pset_kozijnen (CW) - Kozijnmerk: H17
Classification: 31.10 Uniformat (Uniformat)
Pset_CurtainWallCommon - Reference: Merk H17
Pset_QuantityTakeOff - Reference: Merk H17
Pset_wanden - Structural Usage: Non-bearing; Omschrijving: houten kozijn; NL-sfb-Codering: 31.10
Pset_kozijnen (CW) - Omschrijving: houten kozijn; NL-sfb-Codering: 31.10
Pset_DAT_KMS - Assembly Code: 31.10; Assembly Description: buitenwandopeningen; niet gevuld, algemeen (verzamelniveau); Description: houten kozijn
Other - Category: Walls; Family: Curtain Wall; Family and Type: Curtain Wall: Merk H17; Type: Merk H17; Type Id: 6423568
Constraints - Base is Attached: no; Related to Mass: no; Room Bounding: yes; Top is Attached: no; Base Constraint: 0; Base Offset: 900 mm; Top Offset: 400 mm; Unconnected Height: 1190 mm
Dimensions - Area: 0.6545 m2; Length: 550 mm
Identity Data - Workset: Bouwkundig
Materials and Finishes - NLRS_C_Afwerking Kozijn: Ral 9010 - Deur HPL Formica F2296 Sno White
Phasing - Phase Created: 2. nieuwbouw
Structural - Structural Usage: Non-bearing; Structural: no
Horizontal Grid - Angle: 0 deg; Justification: Beginning; Number: 4; Offset: 0 mm; sets with these values: 2
Cross-Section Definition - Cross-Section: Vertical
Name (Curtain Wall:Merk H17:...) | Pset_wanden, NLRS_C_Geluidwering_DnTA = Pset_kozijnen (CW), NLRS_C_Geluidwering_DnTA = Data, NLRS_C_Geluidwering_DnTA | Group
5259387 | 25 | Model Group:H17:5259385
6423886 | 39 | Model Group:H27:5259555
6423921 | 39 | Model Group:H27:5259652
6693330 | 39 | Model Group:H27:6693328

# IfcCurtainWall: Curtain Wall:Merk H18 (2)
Type - Other - Category: Walls; Family Name: Curtain Wall
Type - Construction - Function: Exterior; Automatically Embed: yes; Curtain Panel: 31_WI_glas_1 : 31_glas_2; Join Condition: Border and Horizontal Grid Continuous
Type - Identity Data - Workset: Curtain Wall Types; Assembly Code: 31.10; Assembly Description: buitenwandopeningen; niet gevuld, algemeen (verzamelniveau); Description: houten kozijn; Manufacturer: ITANNEX; Model: 10-07-2014; Type Mark: H18; Type Name: Merk H18; URL: www.bimvoorfabrikanten.nl
Type - Horizontal Grid - Adjust for Mullion Size: no
Type - Vertical Grid - Adjust for Mullion Size: no
Type - Horizontal Mullions - Border 1 Type: Rectangular Mullion : 31_CWM_067x114; Border 2 Type: Rectangular Mullion : 31_CWM_067x114; Interior Type: Rectangular Mullion : 31_CWM_067x114
Type - Vertical Mullions - Border 1 Type: Rectangular Mullion : 31_CWM_067x114; Border 2 Type: Rectangular Mullion : 31_CWM_067x114; Interior Type: Rectangular Mullion : 31_CWM_090x114
Type - Pset_CurtainWallCommon - IsExternal: yes
Type - Pset_ManufacturerTypeInformation - Manufacturer: ITANNEX
Type - Pset_ProductRequirements - Category: Walls
Type - Pset_kozijnen (CW) - Kozijnmerk: H18
Classification: 31.10 Uniformat (Uniformat)
Pset_CurtainWallCommon - Reference: Merk H18
Pset_QuantityTakeOff - Reference: Merk H18
Pset_wanden - Structural Usage: Non-bearing; Omschrijving: houten kozijn; NL-sfb-Codering: 31.10; NLRS_C_Geluidwering_DnTA: 31
Pset_kozijnen (CW) - Omschrijving: houten kozijn; NL-sfb-Codering: 31.10; NLRS_C_Geluidwering_DnTA: 31
Pset_DAT_KMS - Assembly Code: 31.10; Assembly Description: buitenwandopeningen; niet gevuld, algemeen (verzamelniveau); Description: houten kozijn
Other - Family: Curtain Wall; Family and Type: Curtain Wall: Merk H18; Type: Merk H18; Type Id: 6103426
Constraints - Base Offset: 0 mm; Base is Attached: no; Related to Mass: no; Room Bounding: yes; Top is Attached: no; Top Offset: 400 mm; Unconnected Height: 2390 mm
Data - NLRS_C_Geluidwering_DnTA: 31
Dimensions - Area: 3.824 m2; Length: 1600 mm
Identity Data - Workset: Bouwkundig
Materials and Finishes - NLRS_C_Afwerking Kozijn: Kozijn Bamboo - Deur Bamboo
Phasing - Phase Created: 2. nieuwbouw
Structural - Structural Usage: Non-bearing; Structural: no
Horizontal Grid - Angle: 0 deg; Justification: Beginning; Number: 4; Offset: 0 mm; sets with these values: 2
Cross-Section Definition - Cross-Section: Vertical
Name (Curtain Wall:Merk H18:...) | In | Base Constraint | Group
5185792 | 01 eerste verdieping | 1 | Model Group:H18:5185791
6604026 | 00 Begane grond | 0 | Model Group:H18:5129917

# IfcCurtainWall: Curtain Wall:Merk H19, Curtain Wall:Merk H19:5125870
In: 00 Begane grond
Type - Other - Category: Walls; Family Name: Curtain Wall
Type - Construction - Function: Exterior; Automatically Embed: yes; Curtain Panel: 31_WI_glas_1 : 31_glas_2; Join Condition: Border and Horizontal Grid Continuous
Type - Identity Data - Workset: Curtain Wall Types; Assembly Code: 31.10; Assembly Description: buitenwandopeningen; niet gevuld, algemeen (verzamelniveau); Description: houten kozijn; Manufacturer: ITANNEX; Model: 10-07-2014; Type Mark: H19; Type Name: Merk H19; URL: www.bimvoorfabrikanten.nl
Type - Horizontal Grid - Adjust for Mullion Size: no
Type - Vertical Grid - Adjust for Mullion Size: no
Type - Horizontal Mullions - Border 1 Type: Rectangular Mullion : 31_CWM_067x114; Border 2 Type: Rectangular Mullion : 31_CWM_067x114; Interior Type: Rectangular Mullion : 31_CWM_067x114
Type - Vertical Mullions - Border 1 Type: Rectangular Mullion : 31_CWM_067x114; Border 2 Type: Rectangular Mullion : 31_CWM_067x114; Interior Type: Rectangular Mullion : 31_CWM_067x114
Type - Pset_CurtainWallCommon - IsExternal: yes
Type - Pset_ManufacturerTypeInformation - Manufacturer: ITANNEX
Type - Pset_ProductRequirements - Category: Walls
Type - Pset_kozijnen (CW) - Kozijnmerk: H19
Classification: 31.10 Uniformat (Uniformat); Group: Model Group:H19:5125869
Pset_CurtainWallCommon - Reference: Merk H19
Pset_QuantityTakeOff - Reference: Merk H19
Pset_wanden - Structural Usage: Non-bearing; Omschrijving: houten kozijn; NL-sfb-Codering: 31.10; NLRS_C_Geluidwering_DnTA: 34
Pset_kozijnen (CW) - Omschrijving: houten kozijn; NL-sfb-Codering: 31.10; NLRS_C_Geluidwering_DnTA: 34
Pset_DAT_KMS - Assembly Code: 31.10; Assembly Description: buitenwandopeningen; niet gevuld, algemeen (verzamelniveau); Description: houten kozijn
Other - Family: Curtain Wall; Family and Type: Curtain Wall: Merk H19; Type: Merk H19; Type Id: 6103729
Constraints - Base Offset: 0 mm; Base is Attached: no; Related to Mass: no; Room Bounding: yes; Top is Attached: no; Base Constraint: 0; Top Offset: 400 mm; Unconnected Height: 2390 mm
Data - NLRS_C_Geluidwering_DnTA: 34
Dimensions - Area: 2.629 m2; Length: 1100 mm
Identity Data - Workset: Bouwkundig
Materials and Finishes - NLRS_C_Afwerking Kozijn: Ral 9010 - Deur HPL Formica F2296 Sno White
Phasing - Phase Created: 2. nieuwbouw
Structural - Structural Usage: Non-bearing; Structural: no
Horizontal Grid - Angle: 0 deg; Justification: Beginning; Number: 4; Offset: 0 mm; sets with these values: 2
Cross-Section Definition - Cross-Section: Vertical

# IfcCurtainWall: Curtain Wall:Merk H20, Curtain Wall:Merk H20:5140500
In: 00 Begane grond
Type - Other(Type) - Category: Walls; Family Name: Curtain Wall
Type - Construction(Type) - Function: Exterior; Automatically Embed: yes; Curtain Panel: 31_WI_glas_1 : 31_glas_2; Join Condition: Border and Horizontal Grid Continuous
Type - Identity Data(Type) - Workset: Curtain Wall Types; Assembly Code: 31.10; Assembly Description: buitenwandopeningen; niet gevuld, algemeen (verzamelniveau); Description: houten kozijn; Manufacturer: ITANNEX; Model: 10-07-2014; Type Mark: H20; Type Name: Merk H20; URL: www.bimvoorfabrikanten.nl
Type - Horizontal Grid(Type) - Adjust for Mullion Size: no
Type - Vertical Grid(Type) - Adjust for Mullion Size: no
Type - Horizontal Mullions(Type) - Border 1 Type: Rectangular Mullion : 31_CWM_067x114; Border 2 Type: Rectangular Mullion : 31_CWM_067x114; Interior Type: Rectangular Mullion : 31_CWM_067x114
Type - Vertical Mullions(Type) - Border 1 Type: Rectangular Mullion : 31_CWM_067x114; Border 2 Type: Rectangular Mullion : 31_CWM_067x114; Interior Type: Rectangular Mullion : 31_CWM_067x114
Type - Pset_CurtainWallCommon - IsExternal: yes
Type - Pset_ManufacturerTypeInformation - Manufacturer: ITANNEX
Type - Pset_ProductRequirements - Category: Walls
Type - Pset_kozijnen (CW) - Kozijnmerk: H20
Classification: 31.10 Uniformat (Uniformat); Group: Model Group:H20:5488876
Pset_CurtainWallCommon - Reference: Merk H20
Pset_QuantityTakeOff - Reference: Merk H20
Pset_wanden - Structural Usage: Non-bearing; Omschrijving: houten kozijn; NL-sfb-Codering: 31.10
Pset_kozijnen (CW) - Omschrijving: houten kozijn; NL-sfb-Codering: 31.10
Pset_DAT_KMS - Assembly Code: 31.10; Assembly Description: buitenwandopeningen; niet gevuld, algemeen (verzamelniveau); Description: houten kozijn
Other - Category: Walls; Family: Curtain Wall; Family and Type: Curtain Wall: Merk H20; Type: Merk H20; Type Id: 5488219
Constraints - Base Offset: 0 mm; Base is Attached: no; Related to Mass: no; Room Bounding: yes; Top is Attached: no; Base Constraint: 0; Top Offset: 400 mm; Unconnected Height: 2390 mm
Dimensions - Area: 4.78 m2; Length: 2000 mm
Identity Data - Workset: Bouwkundig
Materials and Finishes - NLRS_C_Afwerking Kozijn: Kozijn Bamboo - Deur Bamboo
Phasing - Phase Created: 2. nieuwbouw
Structural - Structural Usage: Non-bearing; Structural: no
Horizontal Grid - Angle: 0 deg; Justification: Beginning; Number: 4; Offset: 0 mm; sets with these values: 2
Cross-Section Definition - Cross-Section: Vertical

# IfcCurtainWall: Curtain Wall:Merk H21, Curtain Wall:Merk H21:5489886
In: 00 Begane grond
Type - Other - Category: Walls; Family Name: Curtain Wall
Type - Construction - Function: Exterior; Automatically Embed: yes; Curtain Panel: 31_WI_glas_1 : 31_glas_2; Join Condition: Border and Horizontal Grid Continuous
Type - Identity Data - Workset: Curtain Wall Types; Assembly Code: 31.10; Assembly Description: buitenwandopeningen; niet gevuld, algemeen (verzamelniveau); Description: houten kozijn; Manufacturer: ITANNEX; Model: 10-07-2014; Type Mark: H21; Type Name: Merk H21; URL: www.bimvoorfabrikanten.nl
Type - Materials and Finishes - NLRS_C_afwerkingsklasse: S3020-Y20R - Deur HPL Formica F0903 cafe
Type - Horizontal Grid - Adjust for Mullion Size: no
Type - Vertical Grid - Adjust for Mullion Size: no
Type - Horizontal Mullions - Border 1 Type: Rectangular Mullion : 31_CWM_020x114; Border 2 Type: Rectangular Mullion : 31_CWM_020x114; Interior Type: Rectangular Mullion : 31_CWM_020x114
Type - Vertical Mullions - Border 1 Type: Rectangular Mullion : 31_CWM_020x114; Border 2 Type: Rectangular Mullion : 31_CWM_020x114; Interior Type: Rectangular Mullion : 31_CWM_020x114
Type - Pset_CurtainWallCommon - IsExternal: yes
Type - Pset_ManufacturerTypeInformation - Manufacturer: ITANNEX
Type - Pset_ProductRequirements - Category: Walls
Type - Pset_kozijnen (CW) - Kozijnmerk: H21
Classification: 31.10 Uniformat (Uniformat); Group: Model Group:H21:5489898
Pset_CurtainWallCommon - Reference: Merk H21
Pset_QuantityTakeOff - Reference: Merk H21
Pset_wanden - Structural Usage: Non-bearing; Omschrijving: houten kozijn; NL-sfb-Codering: 31.10; IfcMaterial: S3020-Y20R - Deur HPL Formica F0903 cafe; NLRS_C_afwerkingsklasse: S3020-Y20R - Deur HPL Formica F0903 cafe
Pset_kozijnen (CW) - Omschrijving: houten kozijn; NL-sfb-Codering: 31.10
Pset_DAT_KMS - Assembly Code: 31.10; Assembly Description: buitenwandopeningen; niet gevuld, algemeen (verzamelniveau); Description: houten kozijn
Other - Family: Curtain Wall; Family and Type: Curtain Wall: Merk H21; Type: Merk H21; Type Id: 5893300
Constraints - Base Offset: 0 mm; Base is Attached: no; Related to Mass: no; Room Bounding: yes; Top is Attached: no; Base Constraint: 0; Top Offset: 400 mm; Unconnected Height: 2390 mm
Dimensions - Area: 5.497 m2; Length: 2300 mm
Identity Data - Workset: Bouwkundig
Materials and Finishes - NLRS_C_Afwerking Kozijn: S3020-Y20R - Deur HPL Formica F0903 cafe
Phasing - Phase Created: 2. nieuwbouw
Structural - Structural Usage: Non-bearing; Structural: no
Horizontal Grid - Angle: 0 deg; Justification: Beginning; Number: 4; Offset: 0 mm; sets with these values: 2
Cross-Section Definition - Cross-Section: Vertical

# IfcCurtainWall: Curtain Wall:Merk H22, Curtain Wall:Merk H22:5493791
In: -1 Speelvloer
Type - Other(Type) - Category: Walls; Family Name: Curtain Wall
Type - Construction(Type) - Function: Exterior; Automatically Embed: yes; Curtain Panel: 31_WI_glas_1 : 31_glas_2; Join Condition: Border and Horizontal Grid Continuous
Type - Identity Data(Type) - Workset: Curtain Wall Types; Assembly Code: 31.10; Assembly Description: buitenwandopeningen; niet gevuld, algemeen (verzamelniveau); Description: houten kozijn; Manufacturer: ITANNEX; Model: 10-07-2014; Type Mark: H26; Type Name: Merk H22; URL: www.bimvoorfabrikanten.nl
Type - Horizontal Grid(Type) - Adjust for Mullion Size: no
Type - Vertical Grid(Type) - Adjust for Mullion Size: no
Type - Horizontal Mullions(Type) - Border 1 Type: Rectangular Mullion : 31_CWM_020x114; Border 2 Type: Rectangular Mullion : 31_CWM_020x114; Interior Type: Rectangular Mullion : 31_CWM_020x114
Type - Vertical Mullions(Type) - Border 1 Type: Rectangular Mullion : 31_CWM_020x114; Border 2 Type: Rectangular Mullion : 31_CWM_020x114; Interior Type: Rectangular Mullion : 31_CWM_020x114
Type - Pset_CurtainWallCommon - IsExternal: yes
Type - Pset_ManufacturerTypeInformation - Manufacturer: ITANNEX
Type - Pset_ProductRequirements - Category: Walls
Type - Pset_kozijnen (CW) - Kozijnmerk: H26
Classification: 31.10 Uniformat (Uniformat); Group: Model Group:H22:5493776
Pset_CurtainWallCommon - Reference: Merk H22
Pset_QuantityTakeOff - Reference: Merk H22
Pset_wanden - Structural Usage: Non-bearing; Omschrijving: houten kozijn; NL-sfb-Codering: 31.10
Pset_kozijnen (CW) - Omschrijving: houten kozijn; NL-sfb-Codering: 31.10
Pset_DAT_KMS - Assembly Code: 31.10; Assembly Description: buitenwandopeningen; niet gevuld, algemeen (verzamelniveau); Description: houten kozijn
Other - Category: Walls; Family: Curtain Wall; Family and Type: Curtain Wall: Merk H22; Type: Merk H22; Type Id: 5490352
Constraints - Base Offset: 0 mm; Base is Attached: no; Related to Mass: no; Room Bounding: yes; Top is Attached: no; Base Constraint: V-1; Top Offset: 400 mm; Unconnected Height: 2650 mm
Dimensions - Area: 5.512 m2; Length: 2080 mm
Identity Data - Workset: Bouwkundig
Materials and Finishes - NLRS_C_Afwerking Kozijn: Ral 9010 - Deur HPL Formica F2296 Sno White
Phasing - Phase Created: 2. nieuwbouw
Structural - Structural Usage: Non-bearing; Structural: no
Horizontal Grid - Angle: 0 deg; Justification: Beginning; Number: 4; Offset: 0 mm; sets with these values: 2
Cross-Section Definition - Cross-Section: Vertical

# IfcCurtainWall: Curtain Wall:Merk H23, Curtain Wall:Merk H23:6608197
In: -1 Speelvloer
Type - Other - Category: Walls; Family Name: Curtain Wall
Type - Construction - Function: Exterior; Automatically Embed: yes; Curtain Panel: 31_WI_glas_1 : 31_glas_2; Join Condition: Border and Horizontal Grid Continuous
Type - Identity Data - Workset: Curtain Wall Types; Assembly Code: 31.10; Assembly Description: buitenwandopeningen; niet gevuld, algemeen (verzamelniveau); Description: houten kozijn; Manufacturer: ITANNEX; Model: 10-07-2014; Type Mark: H28; Type Name: Merk H23; URL: www.bimvoorfabrikanten.nl
Type - Horizontal Grid - Adjust for Mullion Size: no
Type - Vertical Grid - Adjust for Mullion Size: no
Type - Horizontal Mullions - Border 1 Type: Rectangular Mullion : 31_CWM_020x114; Border 2 Type: Rectangular Mullion : 31_CWM_020x114; Interior Type: Rectangular Mullion : 31_CWM_020x114
Type - Vertical Mullions - Border 1 Type: Rectangular Mullion : 31_CWM_020x114; Border 2 Type: Rectangular Mullion : 31_CWM_020x114; Interior Type: Rectangular Mullion : 31_CWM_020x114
Type - Pset_CurtainWallCommon - IsExternal: yes
Type - Pset_ManufacturerTypeInformation - Manufacturer: ITANNEX
Type - Pset_ProductRequirements - Category: Walls
Type - Pset_kozijnen (CW) - Kozijnmerk: H28
Classification: 31.10 Uniformat (Uniformat); Group: Model Group:H23:5131789
Pset_CurtainWallCommon - Reference: Merk H23
Pset_QuantityTakeOff - Reference: Merk H23
Pset_wanden - Structural Usage: Non-bearing; Omschrijving: houten kozijn; NL-sfb-Codering: 31.10
Pset_kozijnen (CW) - Kozijnmerk: s; Omschrijving: houten kozijn; NL-sfb-Codering: 31.10; NLRS_C_gespiegeld: s
Pset_DAT_KMS - Assembly Code: 31.10; Assembly Description: buitenwandopeningen; niet gevuld, algemeen (verzamelniveau); Description: houten kozijn
Other - Family: Curtain Wall; Family and Type: Curtain Wall: Merk H23; Type: Merk H23; Type Id: 6608376
Constraints - Base Offset: 0 mm; Base is Attached: no; Related to Mass: no; Room Bounding: yes; Top is Attached: no; Base Constraint: V-1; Top Offset: 400 mm; Unconnected Height: 2650 mm
Data - NLRS_C_gespiegeld: s
Dimensions - Area: 5.60464 m2; Length: 2114.96 mm
Identity Data - Workset: Bouwkundig
Materials and Finishes - NLRS_C_Afwerking Kozijn: Ral 9010 - Deur HPL Formica F2296 Sno White
Phasing - Phase Created: 2. nieuwbouw
Structural - Structural Usage: Non-bearing; Structural: no
Horizontal Grid - Angle: 0 deg; Justification: Beginning; Number: 4; Offset: 0 mm; sets with these values: 2
Cross-Section Definition - Cross-Section: Vertical

# IfcCurtainWall: Curtain Wall:Merk H24 (3)
In: 00 Begane grond
Type - Other(Type) - Category: Walls; Family Name: Curtain Wall
Type - Construction(Type) - Function: Exterior; Automatically Embed: yes; Curtain Panel: 31_WI_glas_1 : 31_glas_2; Join Condition: Border and Horizontal Grid Continuous
Type - Identity Data(Type) - Workset: Curtain Wall Types; Assembly Code: 31.10; Assembly Description: buitenwandopeningen; niet gevuld, algemeen (verzamelniveau); Description: houten kozijn; Manufacturer: ITANNEX; Model: 10-07-2014; Type Mark: H24; Type Name: Merk H24; URL: www.bimvoorfabrikanten.nl
Type - Horizontal Grid(Type) - Adjust for Mullion Size: no
Type - Vertical Grid(Type) - Adjust for Mullion Size: no
Type - Horizontal Mullions(Type) - Border 1 Type: Rectangular Mullion : 31_CWM_020x114; Border 2 Type: Rectangular Mullion : 31_CWM_020x114; Interior Type: Rectangular Mullion : 31_CWM_020x114
Type - Vertical Mullions(Type) - Border 1 Type: Rectangular Mullion : 31_CWM_020x114; Border 2 Type: Rectangular Mullion : 31_CWM_020x114; Interior Type: Rectangular Mullion : 31_CWM_020x114
Type - Pset_CurtainWallCommon - IsExternal: yes
Type - Pset_ManufacturerTypeInformation - Manufacturer: ITANNEX
Type - Pset_ProductRequirements - Category: Walls
Type - Pset_kozijnen (CW) - Kozijnmerk: H24
Classification: 31.10 Uniformat (Uniformat)
Pset_CurtainWallCommon - Reference: Merk H24
Pset_QuantityTakeOff - Reference: Merk H24
Pset_wanden - Structural Usage: Non-bearing; Omschrijving: houten kozijn; NL-sfb-Codering: 31.10
Pset_kozijnen (CW) - Omschrijving: houten kozijn; NL-sfb-Codering: 31.10
Pset_DAT_KMS - Assembly Code: 31.10; Assembly Description: buitenwandopeningen; niet gevuld, algemeen (verzamelniveau); Description: houten kozijn
Other - Category: Walls; Family: Curtain Wall; Family and Type: Curtain Wall: Merk H24; Type: Merk H24; Type Id: 5489050
Constraints - Base Offset: 0 mm; Base is Attached: no; Related to Mass: no; Room Bounding: yes; Top is Attached: no; Base Constraint: 0; Top Offset: 400 mm; Unconnected Height: 2390 mm
Dimensions - Area: 5.6404 m2; Length: 2360 mm
Identity Data - Workset: Bouwkundig
Phasing - Phase Created: 2. nieuwbouw
Structural - Structural Usage: Non-bearing; Structural: no
Horizontal Grid - Angle: 0 deg; Justification: Beginning; Number: 4; Offset: 0 mm; sets with these values: 2
Cross-Section Definition - Cross-Section: Vertical
Name (Curtain Wall:Merk H24:...) | NLRS_C_Afwerking Kozijn | Group
5489859 | S3020-Y20R - Deur HPL Formica F0903 cafe | Model Group:H24:5489871
5490909 | Ral 9010 - Deur HPL Formica F2296 Sno White | Model Group:H24:5490908
6241702 | S3020-Y20R - Deur HPL Formica F0903 cafe | Model Group:H24:6241714

# IfcCurtainWall: Curtain Wall:NLRS_21_CWA_lamellenwand Linius - L.120 met LD.0065_Storax (4)
In: 02 tweede verdieping
Type - Other - Category: Walls; Family Name: Curtain Wall
Type - Model Properties - Storax_I Cd-coëfficiënt uitblaas met gaas: 0.198; Storax_I Cd-coëfficiënt uitblaas zonder gaas: 0.261; Storax_I Ce-coëfficiënt aanzuig met gaas: 0.206; Storax_I Ce-coëfficiënt aanzuig zonder gaas: 0.269; Storax_I Deur: ja; Storax_I Fysische vrije doorlaat: 0.6; Storax_I Gaas: yes; Storax_I Gaas_positie: achter; Storax_I Gebogen: no; Storax_I K-factor aanzuig met gaas: 25.25; Storax_I K-factor aanzuig zonder gaas: 13.82; Storax_I K-factor uitblaas met gaas: 23.56; Storax_I K-factor uitblaas zonder gaas: 14.68; Storax_I Lamel_diepte: 90; Storax_I Lamel_hoek: 52; Storax_I Lamel_hoogte: 36576 mm; Storax_I Lamel_materiaal: aluminiumAlMgSi0.5; Storax_I Lamel_overlap: 0; Storax_I Lamel_stap: 36576 mm; Storax_I Lamel_type: L.120; Storax_I Lamel_vorm: Z; Storax_I Material: aluminiumALMgSi0.5; Storax_I Maximale overspanning tussen 2 dragers: 707441 mm; Storax_I Sleepcoëfficient Cfy: 1.21; Storax_I Sleepcoëfficient Cfz: 0.85; Storax_I Verstekhoek: yes; Storax_I Visuele vrije doorlaat: 0.66
Type - Construction - Function: Exterior; Automatically Embed: yes; Join Condition: Border and Vertical Grid Continuous; Curtain Panel: Basic Wall : NLRS_21_WA_lamellenwand Linius - L.120_Storax
Type - Identity Data - Workset: Curtain Wall Types; Assembly Code: 20; Manufacturer: Renson; NLRS_C_code_artikel: VV-L-1.1501; NLRS_C_code_ETIM_url: http://prod.etim-international.com/Class/Details?classId=EC003108&classVersion=2; NLRS_C_content_creator: Itannex; NLRS_C_content_datum_uitgifte: 29-03-2017; NLRS_C_content_handleiding: n/a; NLRS_C_content_provider: Storax; NLRS_C_content_versie: V1; NLRS_C_description: lamellenwand_Storax_Linius_L.120 met LD.0065; NLRS_C_IFC_versie: 2x3; NLRS_C_model: Linius; NLRS_C_revit_versie: 2016; NLRS_C_type: L.120 met LD.0065; NLRS_C_type_comments: lamellenwand; Storax_I BaseKeynote: 21.1; Type Name: NLRS_21_CWA_lamellenwand Linius - L.120 met LD.0065_Storax; URL: https://www.storax.nl/producten/lamellenwanden
Type - Horizontal Grid - Adjust for Mullion Size: no; Layout: Fixed Distance; Spacing: 6000 mm
Type - Vertical Grid - Adjust for Mullion Size: no; Layout: Maximum Spacing; Spacing: 2321 mm
Type - Vertical Mullions - Border 1 Type: Rectangular Mullion : NLRS_21_CWM_drager LD.0065 - rechts_Storax; Border 2 Type: Rectangular Mullion : NLRS_21_CWM_drager LD.0065 - links_Storax; Interior Type: Rectangular Mullion : NLRS_21_CWM_drager LD.0065_Storax
Type - Pset_CurtainWallCommon - IsExternal: yes
Type - Pset_ManufacturerTypeInformation - Manufacturer: Renson
Type - Pset_ProductRequirements - Category: Walls
Classification: 20 Uniformat (Uniformat)
Pset_CurtainWallCommon - Reference: NLRS_21_CWA_lamellenwand Linius - L.120 met LD.0065_Storax
Pset_QuantityTakeOff - Reference: NLRS_21_CWA_lamellenwand Linius - L.120 met LD.0065_Storax
Pset_wanden - Structural Usage: Non-bearing; NL-sfb-Codering: 20
Pset_DAT_KMS - Assembly Code: 20
Other - Family: Curtain Wall; Family and Type: Curtain Wall: NLRS_21_CWA_lamellenwand Linius - L.120 met LD.0065_Storax; Type: NLRS_21_CWA_lamellenwand Linius - L.120 met LD.0065_Storax; Type Id: 6284811
Constraints - Base is Attached: no; Related to Mass: no; Room Bounding: yes; Top is Attached: no; Base Constraint: V2 bk. ruwe vloer; Top Constraint: Up to level: V2 bk. ruwe vloer; Base Offset: 500 mm; Top Offset: 2550 mm; Unconnected Height: 2050 mm
Identity Data - Workset: Bouwkundig
Phasing - Phase Created: 2. nieuwbouw
Structural - Structural Usage: Non-bearing; Structural: no
Horizontal Grid - Angle: 0 deg; Justification: Beginning; Number: 4; Offset: 0 mm
Vertical Grid - Angle: 0 deg; Justification: Beginning; Offset: 0 mm
Cross-Section Definition - Cross-Section: Vertical
Name (Curtain Wall:NLRS_21_CWA_lamellenwand Linius - L.120 met LD.0065_Storax:...) | Area (m2) | Length (mm) | Number | Group
6285781 | 7.39025 | 3605 | 1
6286603 | 14.7395 | 7190 | 3 | Model Group:Paneel op dak:6286816
6287080 | 14.7395 | 7190 | 3 | Model Group:Paneel op dak:6287293
6287294 | 14.7395 | 7190 | 3 | Model Group:Paneel op dak:6287507

# IfcCurtainWall: Curtain Wall:NLRS_31_CW_buitenbergingdeuren (10)
In: 00 Begane grond
Type - Other(Type) - Category: Walls; Family Name: Curtain Wall
Type - Construction(Type) - Function: Exterior; Automatically Embed: yes; Curtain Panel: 31_WI_glas_1 : 31_glas_2; Join Condition: Border and Horizontal Grid Continuous
Type - Identity Data(Type) - Workset: Curtain Wall Types; Assembly Code: 31.10; Assembly Description: buitenwandopeningen; niet gevuld, algemeen (verzamelniveau); Description: kozijn; Manufacturer: ITANNEX; Model: 10-07-2014; Type Name: NLRS_31_CW_buitenbergingdeuren; URL: www.bimvoorfabrikanten.nl
Type - Horizontal Grid(Type) - Adjust for Mullion Size: no
Type - Vertical Grid(Type) - Adjust for Mullion Size: no
Type - Horizontal Mullions(Type) - Border 1 Type: Rectangular Mullion : 31_CWM_067x114; Border 2 Type: Rectangular Mullion : 31_CWM_067x114; Interior Type: Rectangular Mullion : 31_CWM_067x114
Type - Vertical Mullions(Type) - Border 1 Type: Rectangular Mullion : 31_CWM_067x114; Border 2 Type: Rectangular Mullion : 31_CWM_067x114; Interior Type: Rectangular Mullion : 31_CWM_067x114
Type - Pset_CurtainWallCommon - IsExternal: yes
Type - Pset_ManufacturerTypeInformation - Manufacturer: ITANNEX
Type - Pset_ProductRequirements - Category: Walls
Classification: 31.10 Uniformat (Uniformat)
Pset_CurtainWallCommon - Reference: NLRS_31_CW_buitenbergingdeuren
Pset_QuantityTakeOff - Reference: NLRS_31_CW_buitenbergingdeuren
Pset_wanden - Structural Usage: Non-bearing; Omschrijving: kozijn; NL-sfb-Codering: 31.10
Pset_kozijnen (CW) - Omschrijving: kozijn; NL-sfb-Codering: 31.10
Pset_DAT_KMS - Assembly Code: 31.10; Assembly Description: buitenwandopeningen; niet gevuld, algemeen (verzamelniveau); Description: kozijn
Other - Category: Walls; Family: Curtain Wall; Family and Type: Curtain Wall: NLRS_31_CW_buitenbergingdeuren; Type: NLRS_31_CW_buitenbergingdeuren; Type Id: 6486346
Constraints - Top Offset: 0 mm; Base is Attached: no; Related to Mass: no; Room Bounding: yes; Top is Attached: no; Base Constraint: 0
Phasing - Phase Created: 2. nieuwbouw
Structural - Structural Usage: Non-bearing; Structural: no
Horizontal Grid - Angle: 0 deg; Justification: Beginning; Number: 4; Offset: 0 mm; sets with these values: 2
Cross-Section Definition - Cross-Section: Vertical
Name (Curtain Wall:NLRS_31_CW_buitenbergingdeuren:...) | Base Offset (mm) | Unconnected Height (mm) | Area (m2) | Length (mm) | Workset
6486348 | 0 | 1065 | 1.90635 | 4854 | situatie
6487006 | 100 | 1500 | 3.75 | 2500 | situatie
6487408 | 100 | 1500 | 5.22276 | 3481.84 | situatie
6487742 | 100 | 1100 | 1.04539 | 950.358 | situatie
6495806 | 50 | 2050 | 3.854 | 1880 | situatie | Group: Model Group:bergingdeur:6495812
6495822 | 50 | 2050 | 3.854 | 1880 | situatie | Group: Model Group:bergingdeur:6495828
6495926 | 50 | 2050 | 3.854 | 1880 | situatie | Group: Model Group:bergingdeur:6495932
6495940 | 50 | 2050 | 3.854 | 1880 | situatie | Group: Model Group:bergingdeur:6495946
6766702 | 0 | 1065 | 1.90635 | 1790 | Bouwkundig
6872227 | 100 | 1100 | 1.04539 | 950.358 | situatie

# IfcCurtainWall: Curtain Wall:k_19, Curtain Wall:k_19:5539067
In: 00 Begane grond
Type - Other(Type) - Category: Walls; Family Name: Curtain Wall
Type - Construction(Type) - Function: Exterior; Automatically Embed: yes; Curtain Panel: System Panel : glas_offset 35; Join Condition: Border and Vertical Grid Continuous
Type - Identity Data(Type) - Workset: Curtain Wall Types; Assembly Code: 31; Assembly Description: buitenwandopeningen; Description: Kunststof kozijn Gealan Kubus; Type Mark: K19; Type Name: k_19
Type - Horizontal Grid(Type) - Adjust for Mullion Size: no
Type - Vertical Grid(Type) - Adjust for Mullion Size: no
Type - Horizontal Mullions(Type) - Border 1 Type: Rectangular Mullion : 120x83 Gealan Kubus; Border 2 Type: Rectangular Mullion : 100x83 Gealan Kubus; Interior Type: Rectangular Mullion : 100x83 Gealan Kubus
Type - Vertical Mullions(Type) - Border 1 Type: Rectangular Mullion : 100x83 Gealan Kubus; Border 2 Type: Rectangular Mullion : 100x83 Gealan Kubus; Interior Type: Rectangular Mullion : 100x83 Gealan Kubus
Type - Pset_CurtainWallCommon - IsExternal: yes
Type - Pset_ProductRequirements - Category: Walls
Type - Pset_kozijnen (CW) - Kozijnmerk: K19
Classification: 31 Uniformat (Uniformat); Group: Model Group:Merk K19:5539066
Pset_CurtainWallCommon - Reference: k_19
Pset_QuantityTakeOff - Reference: k_19
Pset_wanden - Structural Usage: Non-bearing; Omschrijving: Kunststof kozijn Gealan Kubus; NL-sfb-Codering: 31
Pset_kozijnen (CW) - Omschrijving: Kunststof kozijn Gealan Kubus; NL-sfb-Codering: 31
Pset_DAT_KMS - Assembly Code: 31; Assembly Description: buitenwandopeningen; Description: Kunststof kozijn Gealan Kubus
Other - Category: Walls; Family: Curtain Wall; Doorvalveilig 1-zijdig: no; Doorvalveilig 2-zijdig: yes; Family and Type: Curtain Wall: k_19; Type: k_19; Type Id: 4959005
Constraints - Top Offset: 0 mm; Base is Attached: no; Related to Mass: no; Room Bounding: yes; Top is Attached: no; Base Constraint: 0; Base Offset: 10 mm; Unconnected Height: 2630 mm
Dimensions - Area: 3.3927 m2; Length: 1290 mm
Identity Data - Workset: Bouwkundig
Phasing - Phase Created: 2. nieuwbouw
Structural - Structural Usage: Non-bearing; Structural: no
Text - NLRS_C_merk: K01
Horizontal Grid - Angle: 0 deg; Justification: Beginning; Number: 4; Offset: 0 mm; sets with these values: 2
Cross-Section Definition - Cross-Section: Vertical

# IfcDistributionControlElement: 57_luchtbehandelings buis:Ø 250 op 2946 (22)
Type - Material: <Unnamed>
Type - Other - Category: Mechanical Control Devices; Family Name: 57_luchtbehandelings buis
Type - Constraints - Default Elevation: 0 mm
Type - Dimensions - Diameter: 250 mm; Hoogte Hart buis: 2800 mm; Straal Buis: 125 mm
Type - Identity Data - Workset: Family : Mechanical Control Devices : 57_luchtbehandelings buis; Type Name: Ø 250 op 2946
Type - Pset_ProductRequirements - Category: Mechanical Control Devices
Pset_QuantityTakeOff - Reference: Ø 250 op 2946
Other - Family: 57_luchtbehandelings buis; Family and Type: 57_luchtbehandelings buis: Ø 250 op 2946; Type: Ø 250 op 2946; Type Id: 5399404
Constraints - Elevation from Level: 0 mm; Moves With Nearby Elements: no; Offset from Host: 0 mm
Phasing - Phase Created: 2. nieuwbouw
Name (57_luchtbehandelings buis:Ø 250 op 2946:...) | In | Level | Host | Area (m2) | Lengte (mm) | Volume (m3) | Workset | Group
5399350 | 00 Begane grond | 0 | Floor : 23_Dekvloer 70mm | 0.21696 | 427.5 | 0.0209839 | installatie | Model Group:Verlichtingsplan lokaal:5339618
5399931 | 00 Begane grond | 0 | Floor : 23_Dekvloer 70mm | 0.21696 | 427.5 | 0.0209839 | installatie | Model Group:Verlichtingsplan lokaal:5339709
5399957 | 00 Begane grond | 0 | Floor : 23_Dekvloer 70mm | 0.21696 | 427.5 | 0.0209839 | installatie | Model Group:Verlichtingsplan lokaal:5339745
5399983 | 01 eerste verdieping | 1 | Floor : 23_Zwevende dekvloer 90mm | 0.21696 | 427.5 | 0.0209839 | installatie | Model Group:Verlichtingsplan lokaal:5347175
5400010 | 01 eerste verdieping | 1 | Floor : 23_Zwevende dekvloer 90mm | 0.21696 | 427.5 | 0.0209839 | installatie | Model Group:Verlichtingsplan lokaal:5347232
5400037 | 01 eerste verdieping | 1 | Floor : 23_Zwevende dekvloer 90mm | 0.21696 | 427.5 | 0.0209839 | installatie | Model Group:Verlichtingsplan lokaal:5347244
5400091 | 01 eerste verdieping | 1 | Floor : 23_Zwevende dekvloer 90mm | 0.21696 | 427.5 | 0.0209839 | installatie | Model Group:Verlichtingsplan lokaal:5347429
5400117 | 01 eerste verdieping | 1 | Floor : 23_Zwevende dekvloer 90mm | 0.21696 | 427.5 | 0.0209839 | installatie | Model Group:Verlichtingsplan lokaal:5347502
5400143 | 01 eerste verdieping | 1 | Floor : 23_Zwevende dekvloer 90mm | 0.21696 | 427.5 | 0.0209839 | installatie | Model Group:Verlichtingsplan lokaal:5347541
5400281 | 00 Begane grond | 0 | Floor : 23_Dekvloer 70mm | 0.21696 | 427.5 | 0.0209839 | Bouwkundig | Model Group:Verlichtingsplan lokaal 3:5347561
5400382 | 00 Begane grond | 0 | Floor : 23_Dekvloer 70mm | 0.184396 | 344.578 | 0.0169136 | Bouwkundig | Model Group:Verlichtingsplan lokaal 3:5347561
5400616 | 01 eerste verdieping | 1 | Floor : 23_Zwevende dekvloer 90mm | 0.21696 | 427.5 | 0.0209839 | Bouwkundig | Model Group:Verlichtingsplan lokaal 3:5347665
5400617 | 01 eerste verdieping | 1 | Floor : 23_Zwevende dekvloer 90mm | 0.184396 | 344.578 | 0.0169136 | Bouwkundig | Model Group:Verlichtingsplan lokaal 3:5347665
5401251 | 00 Begane grond | 0 | Floor : 23_Dekvloer 70mm | 0.176708 | 325 | 0.0159526 | Bouwkundig | Model Group:Verlichtingsplan lokaal 4:5376136
5401774 | 00 Begane grond | 0 | Floor : 23_Dekvloer 70mm | 0.374039 | 827.5 | 0.0406179 | Bouwkundig | Model Group:Verlichtingsplan lokaal 2:5344628
5401993 | 00 Begane grond | 0 | Floor : 23_Dekvloer 70mm | 0.374039 | 827.5 | 0.0406179 | Bouwkundig | Model Group:Verlichtingsplan lokaal 2:5344952
5402019 | 00 Begane grond | 0 | Floor : 23_Dekvloer 70mm | 0.374039 | 827.5 | 0.0406179 | Bouwkundig | Model Group:Verlichtingsplan lokaal 2:5344994
6223567 | 01 eerste verdieping | 1 | Floor : 23_Zwevende dekvloer 90mm | 0.21696 | 427.5 | 0.0209839 | Bouwkundig
6227679 | 01 eerste verdieping | 1 | Level : 1 | 0.565729 | 1315.63 | 0.064578 | Bouwkundig
6227789 | 01 eerste verdieping | 1 | Level : 1 | 0.565729 | 1315.63 | 0.064578 | Bouwkundig
6542721 | 00 Begane grond | 0 | Floor : 23_Dekvloer 70mm | 0.179653 | 332.5 | 0.0163208 | Bouwkundig | Identity Data - Mark: 2
6543637 | 01 eerste verdieping | 1 | Level : 1 | 0.244449 | 497.501 | 0.0244199 | Bouwkundig | Identity Data - Mark: 7

# IfcDistributionControlElement: 57_luchtbehandelings buis:Ø 350 op 2945 (25)
Type - Material: <Unnamed>
Type - Other - Category: Mechanical Control Devices; Family Name: 57_luchtbehandelings buis
Type - Constraints - Default Elevation: 0 mm
Type - Dimensions - Diameter: 350 mm; Hoogte Hart buis: 2800 mm; Straal Buis: 175 mm
Type - Identity Data - Type Name: Ø 350 op 2945; Workset: Family : Mechanical Control Devices : 57_luchtbehandelings buis
Type - Pset_ProductRequirements - Category: Mechanical Control Devices
Pset_QuantityTakeOff - Reference: Ø 350 op 2945
Other - Family: 57_luchtbehandelings buis; Family and Type: 57_luchtbehandelings buis: Ø 350 op 2945; Type: Ø 350 op 2945; Type Id: 5334317
Constraints - Moves With Nearby Elements: no
Phasing - Phase Created: 2. nieuwbouw
Name (57_luchtbehandelings buis:Ø 350 op 2945:...) | In | Elevation from Level (mm) | Level | Offset from Host (mm) | Host | Area (m2) | Lengte (mm) | Volume (m3) | Workset | Group
5336060 | 00 Begane grond | 0 | 0 | 0 | Floor : 23_Dekvloer 70mm | 3.3935 | 5997.5 | 0.577 | installatie | Model Group:Verlichtingsplan lokaal:5339618
5336440 | 00 Begane grond | 0 | 0 | 0 | Floor : 23_Dekvloer 70mm | 3.54264 | 6268.78 | 0.603099 | Bouwkundig | Model Group:Verlichtingsplan lokaal 3:5347561
5339705 | 00 Begane grond | 0 | 0 | 0 | Floor : 23_Dekvloer 70mm | 3.3935 | 5997.5 | 0.577 | installatie | Model Group:Verlichtingsplan lokaal:5339709
5339741 | 00 Begane grond | 0 | 0 | 0 | Floor : 23_Dekvloer 70mm | 3.3935 | 5997.5 | 0.577 | installatie | Model Group:Verlichtingsplan lokaal:5339745
5344624 | 00 Begane grond | 0 | 0 | 0 | Floor : 23_Dekvloer 70mm | 3.3935 | 5997.5 | 0.577 | Bouwkundig | Model Group:Verlichtingsplan lokaal 2:5344628
5344948 | 00 Begane grond | 0 | 0 | 0 | Floor : 23_Dekvloer 70mm | 3.3935 | 5997.5 | 0.577 | Bouwkundig | Model Group:Verlichtingsplan lokaal 2:5344952
5344990 | 00 Begane grond | 0 | 0 | 0 | Floor : 23_Dekvloer 70mm | 3.3935 | 5997.5 | 0.577 | Bouwkundig | Model Group:Verlichtingsplan lokaal 2:5344994
5346791 | 0.23 | -75 | 0 | 525 | Floor : 23_Dekvloer 70mm | 3.47734 | 6150 | 0.591671 | Bouwkundig
5347171 | 01 eerste verdieping | 0 | 1 | 0 | Floor : 23_Zwevende dekvloer 90mm | 3.3935 | 5997.5 | 0.577 | installatie | Model Group:Verlichtingsplan lokaal:5347175
5347228 | 01 eerste verdieping | 0 | 1 | 0 | Floor : 23_Zwevende dekvloer 90mm | 3.3935 | 5997.5 | 0.577 | installatie | Model Group:Verlichtingsplan lokaal:5347232
5347240 | 01 eerste verdieping | 0 | 1 | 0 | Floor : 23_Zwevende dekvloer 90mm | 3.3935 | 5997.5 | 0.577 | installatie | Model Group:Verlichtingsplan lokaal:5347244
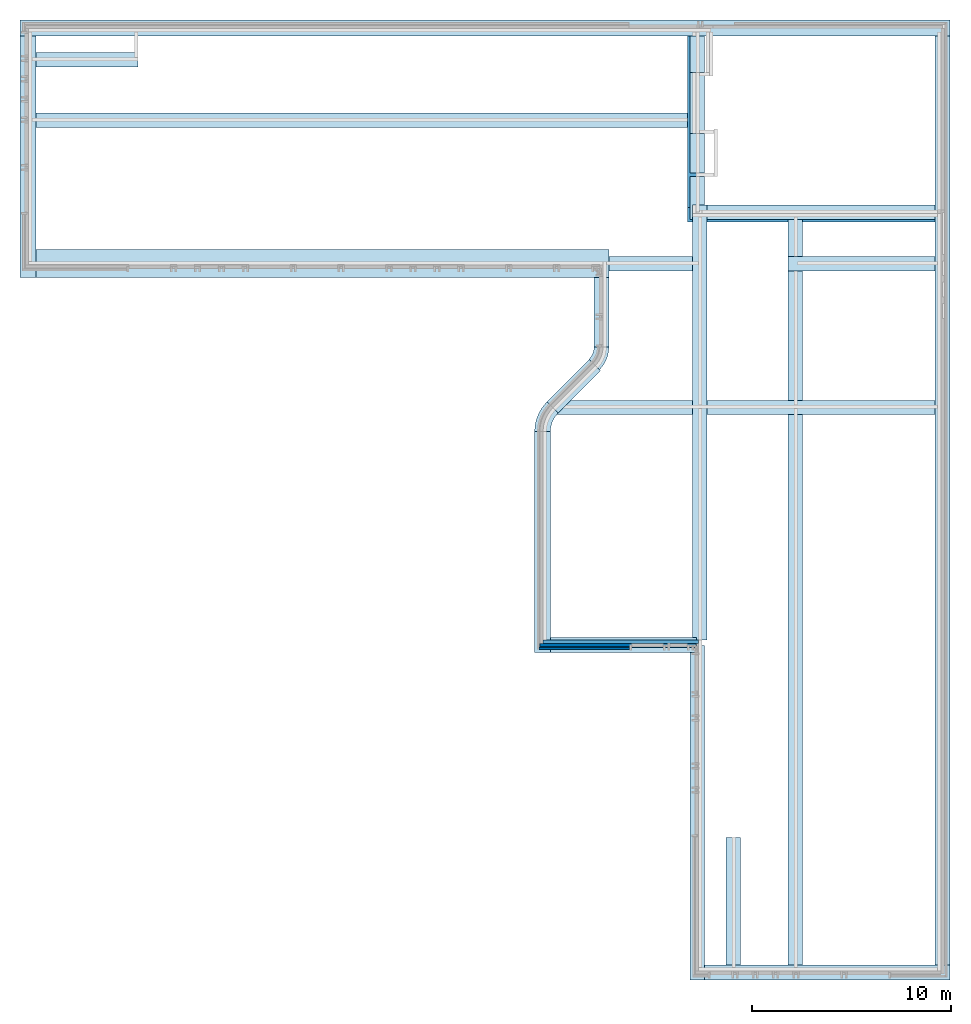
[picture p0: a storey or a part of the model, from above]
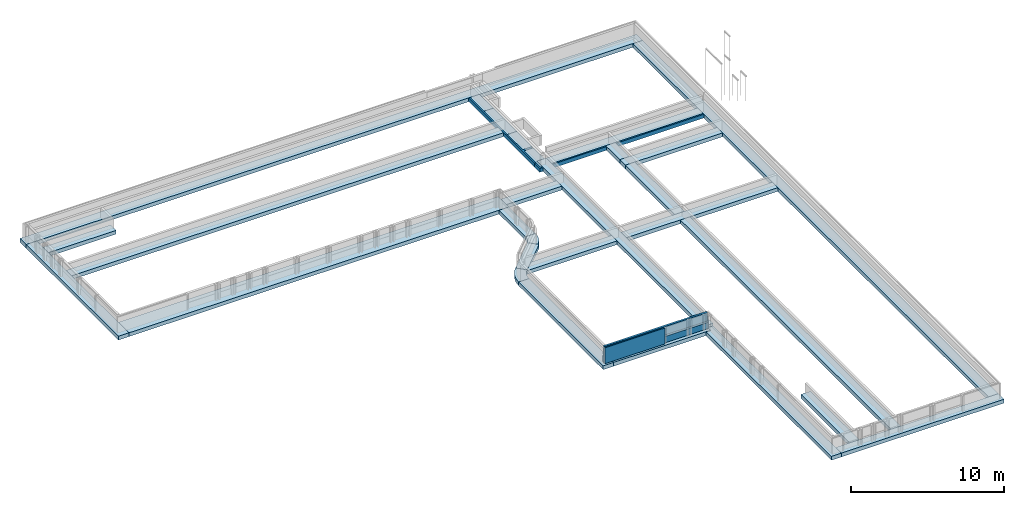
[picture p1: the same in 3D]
Properties of the parts of a building model (IFC2X3), part 13 of 37

# IfcDistributionControlElement: 57_luchtbehandelings buis:Ø 350 op 2945 (25)
Name (57_luchtbehandelings buis:Ø 350 op 2945:...) | In | Elevation from Level (mm) | Level | Offset from Host (mm) | Host | Area (m2) | Lengte (mm) | Volume (m3) | Workset | Group
5347425 | 01 eerste verdieping | 0 | 1 | 0 | Floor : 23_Zwevende dekvloer 90mm | 3.3935 | 5997.5 | 0.577 | installatie | Model Group:Verlichtingsplan lokaal:5347429
5347498 | 01 eerste verdieping | 0 | 1 | 0 | Floor : 23_Zwevende dekvloer 90mm | 3.3935 | 5997.5 | 0.577 | installatie | Model Group:Verlichtingsplan lokaal:5347502
5347537 | 01 eerste verdieping | 0 | 1 | 0 | Floor : 23_Zwevende dekvloer 90mm | 3.3935 | 5997.5 | 0.577 | installatie | Model Group:Verlichtingsplan lokaal:5347541
5347652 | 01 eerste verdieping | 0 | 1 | 0 | Floor : 23_Zwevende dekvloer 90mm | 3.54264 | 6268.78 | 0.603099 | Bouwkundig | Model Group:Verlichtingsplan lokaal 3:5347665
5376133 | 00 Begane grond | 0 | 0 | 0 | Level : 0 | 3.3935 | 5997.5 | 0.577 | Bouwkundig | Model Group:Verlichtingsplan lokaal 4:5376136
6223562 | 01 eerste verdieping | 0 | 1 | 0 | Floor : 23_Zwevende dekvloer 90mm | 3.3935 | 5997.5 | 0.577 | Bouwkundig
6227574 | 01 eerste verdieping | 0 | 1 | 0 | Level : 1 | 4.02162 | 7140 | 0.686916 | Bouwkundig
6228057 | 01 eerste verdieping | 0 | 1 | 0 | Level : 1 | 4.02162 | 7140 | 0.686916 | Bouwkundig
6542720 | 00 Begane grond | 0 | 0 | 0 | Floor : 23_Dekvloer 70mm | 2.20323 | 3832.5 | 0.368712 | Bouwkundig | Identity Data - Mark: 1
6543071 | 00 Begane grond | 0 | 0 | 0 | Level : 0 | 2.97704 | 5240 | 0.504123 | Bouwkundig | Identity Data - Mark: 4
6543328 | 00 Begane grond | 0 | 0 | 0 | Level : 0 | 2.97704 | 5240 | 0.504123 | Bouwkundig | Identity Data - Mark: 5
6543636 | 01 eerste verdieping | 0 | 1 | 0 | Level : 1 | 3.67857 | 6516.03 | 0.626886 | Bouwkundig | Identity Data - Mark: 6
6544633 | 01 eerste verdieping | 0 | 1 | 0 | Level : 1 | 2.97704 | 5240 | 0.504123 | Bouwkundig | Identity Data - Mark: 9
6544634 | 01 eerste verdieping | 0 | 1 | 0 | Level : 1 | 2.97704 | 5240 | 0.504123 | Bouwkundig | Identity Data - Mark: 10

# IfcDistributionPort (186)
Description: Flow
Name | FlowDirection
OutPort_4977532_1 | SOURCE
OutPort_4977532_2 | SOURCE
OutPort_4977532_3 | SOURCE
OutPort_4977532_4 | SOURCE
OutPort_4977532_5 | SOURCE
OutPort_4977532_6 | SOURCE
OutPort_4977532_7 | SOURCE
OutPort_4977533_1 | SOURCE
OutPort_4977533_2 | SOURCE
OutPort_4977533_3 | SOURCE
OutPort_4977533_4 | SOURCE
OutPort_4977533_5 | SOURCE
OutPort_4977533_6 | SOURCE
OutPort_4977533_7 | SOURCE
OutPort_4977711_1 | SOURCE
OutPort_4977711_2 | SOURCE
OutPort_4977711_3 | SOURCE
OutPort_4977711_4 | SOURCE
OutPort_4977711_5 | SOURCE
OutPort_4977711_6 | SOURCE
OutPort_4977711_7 | SOURCE
OutPort_4977712_1 | SOURCE
OutPort_4977712_2 | SOURCE
OutPort_4977712_3 | SOURCE
OutPort_4977712_4 | SOURCE
OutPort_4977712_5 | SOURCE
OutPort_4977712_6 | SOURCE
OutPort_4977712_7 | SOURCE
OutPort_4977722_1 | SOURCE
OutPort_4977722_2 | SOURCE
OutPort_4977722_3 | SOURCE
OutPort_4977722_4 | SOURCE
OutPort_4977722_5 | SOURCE
OutPort_4977722_6 | SOURCE
OutPort_4977722_7 | SOURCE
OutPort_4977723_1 | SOURCE
OutPort_4977723_2 | SOURCE
OutPort_4977723_3 | SOURCE
OutPort_4977723_4 | SOURCE
OutPort_4977723_5 | SOURCE
OutPort_4977723_6 | SOURCE
OutPort_4977723_7 | SOURCE
OutPort_5000930_1 | SOURCE
OutPort_5000930_2 | SOURCE
OutPort_5000930_3 | SOURCE
OutPort_5000930_4 | SOURCE
OutPort_5000930_5 | SOURCE
OutPort_5000930_6 | SOURCE
OutPort_5000930_7 | SOURCE
OutPort_5035663_1 | SOURCE
OutPort_5035663_2 | SOURCE
OutPort_5035663_3 | SOURCE
OutPort_5035663_4 | SOURCE
OutPort_5035663_5 | SOURCE
OutPort_5035663_6 | SOURCE
OutPort_5035663_7 | SOURCE
OutPort_5035664_1 | SOURCE
OutPort_5035664_2 | SOURCE
OutPort_5035664_3 | SOURCE
OutPort_5035664_4 | SOURCE
OutPort_5035664_5 | SOURCE
OutPort_5035664_6 | SOURCE
OutPort_5035664_7 | SOURCE
OutPort_5035681_1 | SOURCE
OutPort_5035681_2 | SOURCE
OutPort_5035681_3 | SOURCE
OutPort_5035681_4 | SOURCE
OutPort_5035681_5 | SOURCE
OutPort_5035681_6 | SOURCE
OutPort_5035681_7 | SOURCE
OutPort_5035682_1 | SOURCE
OutPort_5035682_2 | SOURCE
OutPort_5035682_3 | SOURCE
OutPort_5035682_4 | SOURCE
OutPort_5035682_5 | SOURCE
OutPort_5035682_6 | SOURCE
OutPort_5035682_7 | SOURCE
OutPort_5135296_1 | SOURCE
InPort_5135296_2 | SINK
OutPort_5135341_1 | SOURCE
InPort_5135341_2 | SINK
OutPort_5136225_1 | SOURCE
InPort_5136225_2 | SINK
OutPort_5136282_1 | SOURCE
OutPort_5136282_2 | SOURCE
OutPort_5136282_3 | SOURCE
OutPort_5136282_4 | SOURCE
OutPort_5136282_5 | SOURCE
OutPort_5136282_6 | SOURCE
OutPort_5136282_7 | SOURCE
OutPort_5136436_1 | SOURCE
OutPort_5136436_2 | SOURCE
OutPort_5136436_3 | SOURCE
OutPort_5136437_1 | SOURCE
OutPort_5158567_1 | SOURCE
OutPort_5158645_1 | SOURCE
InPort_5173648_1 | SINK
InPort_5173652_1 | SINK
InPort_5173654_1 | SINK
InPort_5173656_1 | SINK
InPort_5173660_1 | SINK
OutPort_5174541_1 | SOURCE
OutPort_5174541_2 | SOURCE
OutPort_5174541_3 | SOURCE
OutPort_5174541_4 | SOURCE
OutPort_5174541_5 | SOURCE
OutPort_5174541_6 | SOURCE
OutPort_5174541_7 | SOURCE
OutPort_5174542_1 | SOURCE
OutPort_5174542_2 | SOURCE
OutPort_5174542_3 | SOURCE
OutPort_5174542_4 | SOURCE
OutPort_5174542_5 | SOURCE
OutPort_5174542_6 | SOURCE
OutPort_5174542_7 | SOURCE
InPort_5174560_1 | SINK
OutPort_5178714_1 | SOURCE
OutPort_5178714_2 | SOURCE
OutPort_5178714_3 | SOURCE
OutPort_5178714_4 | SOURCE
OutPort_5178714_5 | SOURCE
OutPort_5178714_6 | SOURCE
OutPort_5178714_7 | SOURCE
OutPort_5178997_1 | SOURCE
OutPort_5179287_1 | SOURCE
InPort_5225412_1 | SINK
OutPort_5225412_2 | SOURCE
Port_5225412_3 | SOURCEANDSINK
InPort_5225495_1 | SINK
OutPort_5225495_2 | SOURCE
Port_5225495_3 | SOURCEANDSINK
InPort_5226056_1 | SINK
OutPort_5226056_2 | SOURCE
Port_5226056_3 | SOURCEANDSINK
InPort_5226265_1 | SINK
OutPort_5226265_2 | SOURCE
Port_5226265_3 | SOURCEANDSINK
InPort_5267633_1 | SINK
OutPort_5267633_2 | SOURCE
Port_5267633_3 | SOURCEANDSINK
InPort_5382441_1 | SINK
InPort_5440045_1 | SINK
InPort_5466378_1 | SINK
OutPort_5994916_1 | SOURCE
OutPort_5994916_2 | SOURCE
OutPort_5994916_3 | SOURCE
OutPort_5994916_4 | SOURCE
OutPort_5994916_5 | SOURCE
OutPort_5994916_6 | SOURCE
OutPort_5994916_7 | SOURCE
OutPort_5994917_1 | SOURCE
OutPort_5994917_2 | SOURCE
OutPort_5994917_3 | SOURCE
OutPort_5994917_4 | SOURCE
OutPort_5994917_5 | SOURCE
OutPort_5994917_6 | SOURCE
OutPort_5994917_7 | SOURCE
InPort_5994933_1 | SINK
OutPort_6420698_1 | SOURCE
OutPort_6522726_1 | SOURCE
OutPort_6522726_2 | SOURCE
OutPort_6522726_3 | SOURCE
OutPort_6522726_4 | SOURCE
OutPort_6522726_5 | SOURCE
OutPort_6522726_6 | SOURCE
OutPort_6522726_7 | SOURCE
InPort_6598615_1 | SINK
InPort_6610308_1 | SINK
InPort_6702433_1 | SINK
InPort_6702433_2 | SINK
OutPort_6702433_3 | SOURCE
InPort_6702625_1 | SINK
InPort_6702625_2 | SINK
OutPort_6702625_3 | SOURCE
Port_6880071_1 | SOURCEANDSINK
Port_6880484_1 | SOURCEANDSINK
Port_6880547_1 | SOURCEANDSINK
Port_6880549_1 | SOURCEANDSINK
Port_6880551_1 | SOURCEANDSINK
Port_6880553_1 | SOURCEANDSINK
Port_6880555_1 | SOURCEANDSINK
Port_6880628_1 | SOURCEANDSINK
Port_6881375_1 | SOURCEANDSINK
Port_6881456_1 | SOURCEANDSINK
Port_6882090_1 | SOURCEANDSINK
Port_6882139_1 | SOURCEANDSINK

# IfcDoor: 31_DO_Rondgat_deur:dichte_deur (16)
Type - ParameterTakesPrecedence: no; Sizeable: no; Material: ISR_Kunststof_wit, ISR_Mass_Glazing
Type - Other - Category: Doors; Family Name: 31_DO_Rondgat_deur
Type - Constraints - Offset: 30 mm; offset_bovenkant: 0 mm; offset_links: 0 mm; offset_onderkant: 0 mm; offset_rechts: 0 mm
Type - Dimensions - Hartlein rond gat: 1600 mm; Radius rond gat: 200 mm; Thickness: 54 mm
Type - Identity Data - Assembly Code: 31.3; Description: deur dicht; Manufacturer: ITANNEX; Model: 10-07-2014; Type Comments: deuren; Type Mark: 347; Type Name: dichte_deur; URL: www.bimvoorfabrikanten.nl; Workset: Family : Doors : 31_DO_Rondgat_deur
Type - Analytical Properties - Define Thermal Properties by: Schematic Type; Analytic Construction: <None>
Type - Pset_DoorCommon - IsExternal: no
Type - Pset_ManufacturerTypeInformation - Manufacturer: ITANNEX
Type - Pset_ProductRequirements - Category: Doors
Type - Pset_Door - Kozijnmerk: 347
OverallHeight: 2303 mm; OverallWidth: 900 mm; Classification: 31.10 Uniformat (Uniformat)
Pset_DoorCommon - Reference: dichte_deur
Pset_QuantityTakeOff - Reference: dichte_deur
Pset_Door - Description: deur dicht; NL-sfb-Codering: 31.3
Pset_DAT_KMS - Assembly Code: 31.3; Description: deur dicht
BaseQuantities - Height: 2303 mm; Width: 900 mm; Area: 2.0727 m2
Other - Family: 31_DO_Rondgat_deur; Family and Type: 31_DO_Rondgat_deur: dichte_deur; HeightReport: 2303 mm; offset_a: 30 mm; offset_b: 60 mm; offset_bovenkant_a: 0 mm; offset_bovenkant_b: 0 mm; offset_links_a: 0 mm; offset_links_b: 0 mm; offset_onderkant_a: 0 mm; offset_onderkant_b: 0 mm; offset_rechts_a: 0 mm; offset_rechts_b: 0 mm; Type: dichte_deur; Type Id: 5468890; WidthReport: 900 mm
Model Properties - diepte_offset_a: 0 mm; draairichting_a_type: BU deur links
Dimensions - Area: 2.0727 m2; Height: 2303 mm; netto_breedte: 900 mm; netto_hoogte: 2303 mm; paneel_oppervlakte: 2.0727 m2; Volume: 0.0557279 m3; Width: 900 mm
Fire Protection - WBDBO 20: no; WBDBO 60: no
Graphics - Geen WBDBO of zelfsluitend: yes
Identity Data - Workset: Bouwkundig
Materials and Finishes - paneel_exterieur_materiaal: ISR_Kunststof_wit; paneel_interieur_materiaal: ISR_Kunststof_wit
Phasing - Phase Created: 2. nieuwbouw
Name (31_DO_Rondgat_deur:dichte_deur:...) | In | Host Id | Level | Firerating_grafisch | WBDBO 30 = Zelfsluitend | Zelfsluitend_grafisch | Mark | Group
5125427 | 00 Begane grond | 5125426 | 0 | 0 | no | 0 | 478 | Model Group:H01:5125425 | Pset_DoorCommon - IsExternal: yes
5125626 | 00 Begane grond | 5125625 | 0 | 0 | no | 0 | 480 | Model Group:H01:5125624
5126011 | 00 Begane grond | 5126010 | 0 | 0 | no | 0 | 2683 | Model Group:H01:5126009
5126020 | 00 Begane grond | 5126019 | 0 | 0 | no | 0 | 2684 | Model Group:H01:5126018
5126064 | 00 Begane grond | 5126063 | 0 | 30 | yes | 30 | 2687 | Model Group:H01:5126062
5126073 | 00 Begane grond | 5126072 | 0 | 30 | yes | 2 | 2688 | Model Group:H01:5126071 | Pset_Door - NLRS_C_brandwerendheid: R200; Fire Protection - NLRS_C_brandwerendheid: R200
5127342 | 00 Begane grond | 5127341 | 0 | 0 | no | 0 | 2707 | Model Group:H01:5127340
5127584 | 00 Begane grond | 5127583 | 0 | 0 | no | 0 | 2708 | Model Group:H01:5127582
5127595 | 00 Begane grond | 5127594 | 0 | 0 | no | 0 | 2709 | Model Group:H01:5127593
5127606 | 01 eerste verdieping | 5127605 | 1 | 0 | no | 0 | 2711 | Model Group:H01:5127604
5127617 | 01 eerste verdieping | 5127616 | 1 | 0 | no | 0 | 2712 | Model Group:H01:5127615
5127628 | 01 eerste verdieping | 5127627 | 1 | 0 | no | 0 | 2713 | Model Group:H01:5127626
5174551 | 01 eerste verdieping | 5174550 | 1 | 0 | no | 0 | 3267 | Model Group:H01:5174549
5277202 | 01 eerste verdieping | 5277201 | 1 | 0 | no | 0 | 2727 | Model Group:H01:5174800
5277238 | 01 eerste verdieping | 5277237 | 1 | 0 | no | 0 | 2730 | Model Group:H01:5174841
5994926 | 01 eerste verdieping | 5994925 | 1 | 0 | no | 0 | 2781 | Model Group:H01:5994924

# IfcDoor: 31_DO_deur_met_stapeldorpel:deur_Gealan Liniear Links (7)
In: 00 Begane grond
Type - ParameterTakesPrecedence: no; Sizeable: no; Material: ISR_Kunststof_RAL7006
Type - Other - Category: Doors; Family Name: 31_DO_deur_met_stapeldorpel
Type - Constraints - offset_links: 0 mm; Offset: 16 mm; offset_bovenkant: 34 mm; offset_onderkant: 10 mm; offset_rechts: 34 mm
Type - Dimensions - SillStacks: 0; Frame: 110 mm; Head: 110 mm; Sill: 110 mm; Thickness: 74 mm
Type - Identity Data - Workset: Family : Doors : 31_DO_deur_met_stapeldorpel; Assembly Code: 31.3; Description: deur met 1 stapeldorpel; Manufacturer: ITANNEX; Model: 10-07-2014; Type Comments: deuren; Type Mark: 350; Type Name: deur_Gealan Liniear Links; URL: www.bimvoorfabrikanten.nl
Type - Analytical Properties - Define Thermal Properties by: Schematic Type; Analytic Construction: <None>
Type - Pset_DoorCommon - IsExternal: no
Type - Pset_ManufacturerTypeInformation - Manufacturer: ITANNEX
Type - Pset_ProductRequirements - Category: Doors
Type - Pset_Door - Kozijnmerk: 350
Classification: 31 Uniformat (Uniformat)
Pset_DoorCommon - Reference: deur_Gealan Liniear Links
Pset_QuantityTakeOff - Reference: deur_Gealan Liniear Links
Pset_Door - Description: deur met 1 stapeldorpel; NL-sfb-Codering: 31.3
Pset_DAT_KMS - Assembly Code: 31.3; Description: deur met 1 stapeldorpel
Other - offset_links_a: 0 mm; offset_links_b: 0 mm; Family: 31_DO_deur_met_stapeldorpel; SillStacksCalc: 2; Family and Type: 31_DO_deur_met_stapeldorpel: deur_Gealan Liniear Links; offset_a: 16 mm; offset_b: 32 mm; offset_bovenkant_a: 34 mm; offset_bovenkant_b: 68 mm; offset_onderkant_a: 10 mm; offset_onderkant_b: 20 mm; offset_rechts_a: 34 mm; offset_rechts_b: 68 mm; Type: deur_Gealan Liniear Links; Type Id: 5644733
Model Properties - diepte_offset_a: 0 mm; subpaneel_a1_roedes_hor: 0; subpaneel_a1_roedes_ver: 0; subpaneel_a1_type: WI_subvak1 : glas 2; draairichting_a_type: BU deur rechts
Constraints - Level: 0
Fire Protection - WBDBO 20: no; WBDBO 30: no; WBDBO 60: no
Identity Data - Workset: Bouwkundig
Materials and Finishes - paneel_exterieur_materiaal: ISR_Kunststof_RAL7006; paneel_interieur_materiaal: ISR_Kunststof_RAL7006
Phasing - Phase Created: 2. nieuwbouw
Name (31_DO_deur_met_stapeldorpel:deur_Gealan Liniear Links:...) | OverallHeight (mm) = netto_hoogte (mm) | OverallWidth (mm) | BaseQuantities, Height (mm) = HeightReport (mm) = Dimensions, Height (mm) | BaseQuantities, Width (mm) = WidthReport (mm) = Dimensions, Width (mm) | BaseQuantities, Area (m2) = Dimensions, Area (m2) | Host Id | subpaneel_1_hoogte (mm) | subpaneel_a_breedte (mm) | subpaneel_a1_oppervlakte (m2) | netto_breedte (mm) | paneel_oppervlakte (m2) | Volume (m3) | Zelfsluitend | Firerating_grafisch = Zelfsluitend_grafisch | Mark | Group
5536858 | 2550 | 1027 | 2506 | 976 | 2.44586 | 5536857 | 2330 | 790 | 1.8407 | 1010 | 0.7348 | 0.00489171 | no | 0 | 2756 | Model Group:Merk K03:5536856 | Pset_DoorCommon - IsExternal: yes
5536930 | 2550 | 1027 | 2506 | 976 | 2.44586 | 5536929 | 2330 | 790 | 1.8407 | 1010 | 0.7348 | 0.00489171 | no | 0 | 2761 | Model Group:Merk K03:5536928
5537081 | 2550 | 1027 | 2506 | 976 | 2.44586 | 5537080 | 2330 | 790 | 1.8407 | 1010 | 0.7348 | 0.00489171 | no | 0 | 2766 | Model Group:Merk K03:5537079
5538764 | 2550 | 1027 | 2506 | 976 | 2.44586 | 5538763 | 2330 | 790 | 1.8407 | 1010 | 0.7348 | 0.00489171 | no | 0 | 2770 | Model Group:Merk K03:5538762
5538782 | 2550 | 1027 | 2506 | 976 | 2.44586 | 5538781 | 2330 | 790 | 1.8407 | 1010 | 0.7348 | 0.00489171 | no | 0 | 2772 | Model Group:Merk K03:5538780
5538800 | 2550 | 1027 | 2506 | 976 | 2.44586 | 5538799 | 2330 | 790 | 1.8407 | 1010 | 0.7348 | 0.00489171 | no | 0 | 2774 | Model Group:Merk K03:5538798
5539076 | 2570 | 922 | 2526 | 871 | 2.20015 | 5539075 | 2350 | 685 | 1.60975 | 905 | 0.7161 | 0.00440029 | yes | 1 | 2776 | Model Group:Merk K20:5539074

# IfcDoor: 31_DO_deur_met_stapeldorpel:deur_Gealan Liniear Rechts (7)
In: 00 Begane grond
Type - ParameterTakesPrecedence: no; Sizeable: no; Material: ISR_Kunststof_RAL7006
Type - Other - Category: Doors; Family Name: 31_DO_deur_met_stapeldorpel
Type - Constraints - offset_rechts: 0 mm; Offset: 16 mm; offset_bovenkant: 34 mm; offset_links: 34 mm; offset_onderkant: 10 mm
Type - Dimensions - SillStacks: 0; Frame: 110 mm; Head: 110 mm; Sill: 110 mm; Thickness: 74 mm
Type - Identity Data - Workset: Family : Doors : 31_DO_deur_met_stapeldorpel; Assembly Code: 31.3; Description: deur met 1 stapeldorpel; Manufacturer: ITANNEX; Model: 10-07-2014; Type Comments: deuren; Type Mark: 351; Type Name: deur_Gealan Liniear Rechts; URL: www.bimvoorfabrikanten.nl
Type - Analytical Properties - Define Thermal Properties by: Schematic Type; Analytic Construction: <None>
Type - Pset_DoorCommon - IsExternal: no
Type - Pset_ManufacturerTypeInformation - Manufacturer: ITANNEX
Type - Pset_ProductRequirements - Category: Doors
Type - Pset_Door - Kozijnmerk: 351
Classification: 31 Uniformat (Uniformat)
Pset_DoorCommon - Reference: deur_Gealan Liniear Rechts
Pset_QuantityTakeOff - Reference: deur_Gealan Liniear Rechts
Pset_Door - Description: deur met 1 stapeldorpel; NL-sfb-Codering: 31.3
Pset_DAT_KMS - Assembly Code: 31.3; Description: deur met 1 stapeldorpel
Other - offset_rechts_a: 0 mm; offset_rechts_b: 0 mm; Family: 31_DO_deur_met_stapeldorpel; SillStacksCalc: 2; Family and Type: 31_DO_deur_met_stapeldorpel: deur_Gealan Liniear Rechts; offset_a: 16 mm; offset_b: 32 mm; offset_bovenkant_a: 34 mm; offset_bovenkant_b: 68 mm; offset_links_a: 34 mm; offset_links_b: 68 mm; offset_onderkant_a: 10 mm; offset_onderkant_b: 20 mm; Type: deur_Gealan Liniear Rechts; Type Id: 5648002
Model Properties - diepte_offset_a: 0 mm; draairichting_a_type: BU deur links; subpaneel_a1_roedes_hor: 0; subpaneel_a1_roedes_ver: 0; subpaneel_a1_type: WI_subvak1 : glas 2
Constraints - Level: 0
Fire Protection - WBDBO 20: no; WBDBO 30: no; WBDBO 60: no; Firerating_grafisch: 0
Identity Data - Workset: Bouwkundig
Materials and Finishes - paneel_exterieur_materiaal: ISR_Kunststof_RAL7006; paneel_interieur_materiaal: ISR_Kunststof_RAL7006
Phasing - Phase Created: 2. nieuwbouw
Name (31_DO_deur_met_stapeldorpel:deur_Gealan Liniear Rechts:...) | OverallHeight (mm) = netto_hoogte (mm) | OverallWidth (mm) | BaseQuantities, Height (mm) = HeightReport (mm) = Dimensions, Height (mm) | BaseQuantities, Width (mm) = WidthReport (mm) = Dimensions, Width (mm) | BaseQuantities, Area (m2) = Dimensions, Area (m2) | Host Id | subpaneel_1_hoogte (mm) | subpaneel_a_breedte (mm) | subpaneel_a1_oppervlakte (m2) | netto_breedte (mm) | paneel_oppervlakte (m2) | Volume (m3) | Zelfsluitend | Zelfsluitend_grafisch | Mark | Group
5536864 | 2550 | 1027 | 2506 | 976 | 2.44586 | 5536857 | 2330 | 790 | 1.8407 | 1010 | 0.7348 | 0.00489171 | no | 0 | 2759 | Model Group:Merk K03:5536856 | Pset_DoorCommon - IsExternal: yes
5536936 | 2550 | 1027 | 2506 | 976 | 2.44586 | 5536929 | 2330 | 790 | 1.8407 | 1010 | 0.7348 | 0.00489171 | no | 0 | 2762 | Model Group:Merk K03:5536928
5537087 | 2550 | 1027 | 2506 | 976 | 2.44586 | 5537080 | 2330 | 790 | 1.8407 | 1010 | 0.7348 | 0.00489171 | no | 0 | 2767 | Model Group:Merk K03:5537079
5538770 | 2550 | 1027 | 2506 | 976 | 2.44586 | 5538763 | 2330 | 790 | 1.8407 | 1010 | 0.7348 | 0.00489171 | no | 0 | 2771 | Model Group:Merk K03:5538762
5538788 | 2550 | 1027 | 2506 | 976 | 2.44586 | 5538781 | 2330 | 790 | 1.8407 | 1010 | 0.7348 | 0.00489171 | no | 0 | 2773 | Model Group:Merk K03:5538780
5538806 | 2550 | 1027 | 2506 | 976 | 2.44586 | 5538799 | 2330 | 790 | 1.8407 | 1010 | 0.7348 | 0.00489171 | no | 0 | 2775 | Model Group:Merk K03:5538798
5539082 | 2570 | 922 | 2526 | 871 | 2.20015 | 5539075 | 2350 | 685 | 1.60975 | 905 | 0.7161 | 0.00440029 | yes | 1 | 2777 | Model Group:Merk K20:5539074

# IfcDoor: 31_DO_deur_met_stapeldorpel:deur_Gealan Liniear enkel (2)
In: 00 Begane grond
Type - ParameterTakesPrecedence: no; Sizeable: no; Material: ISR_Kunststof_RAL7006
Type - Other - Category: Doors; Family Name: 31_DO_deur_met_stapeldorpel
Type - Constraints - Offset: 16 mm; offset_bovenkant: 34 mm; offset_links: 34 mm; offset_onderkant: 10 mm; offset_rechts: 34 mm
Type - Dimensions - SillStacks: 0; Frame: 110 mm; Head: 110 mm; Sill: 110 mm; Thickness: 74 mm
Type - Identity Data - Workset: Family : Doors : 31_DO_deur_met_stapeldorpel; Assembly Code: 31.3; Description: deur met 1 stapeldorpel; Manufacturer: ITANNEX; Model: 10-07-2014; Type Comments: deuren; Type Mark: 352; Type Name: deur_Gealan Liniear enkel; URL: www.bimvoorfabrikanten.nl
Type - Analytical Properties - Define Thermal Properties by: Schematic Type; Analytic Construction: <None>
Type - Pset_DoorCommon - IsExternal: no
Type - Pset_ManufacturerTypeInformation - Manufacturer: ITANNEX
Type - Pset_ProductRequirements - Category: Doors
Type - Pset_Door - Kozijnmerk: 352
OverallHeight: 2550 mm; OverallWidth: 1030 mm; Classification: 31 Uniformat (Uniformat)
Pset_DoorCommon - Reference: deur_Gealan Liniear enkel
Pset_QuantityTakeOff - Reference: deur_Gealan Liniear enkel
Pset_Door - Description: deur met 1 stapeldorpel; NL-sfb-Codering: 31.3
Pset_DAT_KMS - Assembly Code: 31.3; Description: deur met 1 stapeldorpel
BaseQuantities - Height: 2506 mm; Width: 962 mm; Area: 2.41077 m2
Other - Family: 31_DO_deur_met_stapeldorpel; SillStacksCalc: 2; Family and Type: 31_DO_deur_met_stapeldorpel: deur_Gealan Liniear enkel; HeightReport: 2506 mm; offset_a: 16 mm; offset_b: 32 mm; offset_bovenkant_a: 34 mm; offset_bovenkant_b: 68 mm; offset_links_a: 34 mm; offset_links_b: 68 mm; offset_onderkant_a: 10 mm; offset_onderkant_b: 20 mm; offset_rechts_a: 34 mm; offset_rechts_b: 68 mm; subpaneel_1_hoogte: 2330 mm; subpaneel_a_breedte: 810 mm; subpaneel_a1_oppervlakte: 1.8873 m2; Type: deur_Gealan Liniear enkel; Type Id: 5649567; WidthReport: 962 mm
Model Properties - diepte_offset_a: 0 mm; subpaneel_a1_roedes_hor: 0; subpaneel_a1_roedes_ver: 0; subpaneel_a1_type: WI_subvak1 : glas 2; draairichting_a_type: BU deur rechts
Constraints - Level: 0
Dimensions - Area: 2.41077 m2; Height: 2506 mm; netto_breedte: 1030 mm; netto_hoogte: 2550 mm; paneel_oppervlakte: 0.7392 m2; Volume: 0.00482154 m3; Width: 962 mm
Fire Protection - WBDBO 20: no; WBDBO 30: no; WBDBO 60: no; Zelfsluitend: yes; Firerating_grafisch: 0; Zelfsluitend_grafisch: 1
Identity Data - Workset: Bouwkundig
Materials and Finishes - paneel_exterieur_materiaal: ISR_Kunststof_RAL7006; paneel_interieur_materiaal: ISR_Kunststof_RAL7006
Phasing - Phase Created: 2. nieuwbouw
Name (31_DO_deur_met_stapeldorpel:deur_Gealan Liniear enkel:...) | Host Id | Mark | Group
5537044 | 5537043 | 2765 | Model Group:Merk K05:5537042 | Pset_DoorCommon - IsExternal: yes
6703046 | 6703045 | 2700 | Model Group:Merk K05:6703044

# IfcDoor: 31_DO_deur_met_stapeldorpel:deur_met_stapeldorpel (36)
Type - ParameterTakesPrecedence: no; Sizeable: no; Material: HPL F7853 ocean gray
Type - Other - Category: Doors; Family Name: 31_DO_deur_met_stapeldorpel
Type - Constraints - offset_bovenkant: 0 mm; offset_links: 0 mm; offset_onderkant: 0 mm; offset_rechts: 0 mm; Offset: 30 mm
Type - Dimensions - Frame: 120 mm; Head: 120 mm; Sill: 240 mm; SillStacks: 0; Thickness: 54 mm
Type - Identity Data - Assembly Code: 31.3; Description: deur met 1 stapeldorpel; Manufacturer: ITANNEX; Model: 10-07-2014; Type Comments: deuren; Type Mark: 341; Type Name: deur_met_stapeldorpel; URL: www.bimvoorfabrikanten.nl; Workset: Family : Doors : 31_DO_deur_met_stapeldorpel
Type - Analytical Properties - Define Thermal Properties by: Schematic Type; Analytic Construction: <None>
Type - Pset_DoorCommon - IsExternal: no
Type - Pset_ManufacturerTypeInformation - Manufacturer: ITANNEX
Type - Pset_ProductRequirements - Category: Doors
Type - Pset_Door - Kozijnmerk: 341
OverallHeight: 2303 mm; Classification: 31.10 Uniformat (Uniformat)
Pset_DoorCommon - Reference: deur_met_stapeldorpel
Pset_QuantityTakeOff - Reference: deur_met_stapeldorpel
Pset_Door - Description: deur met 1 stapeldorpel; NL-sfb-Codering: 31.3
Pset_DAT_KMS - Assembly Code: 31.3; Description: deur met 1 stapeldorpel
BaseQuantities - Height: 2303 mm
Other - offset_bovenkant_a: 0 mm; offset_bovenkant_b: 0 mm; offset_links_a: 0 mm; offset_links_b: 0 mm; offset_onderkant_a: 0 mm; offset_onderkant_b: 0 mm; offset_rechts_a: 0 mm; offset_rechts_b: 0 mm; Family: 31_DO_deur_met_stapeldorpel; Family and Type: 31_DO_deur_met_stapeldorpel: deur_met_stapeldorpel; SillStacksCalc: 2; Type: deur_met_stapeldorpel; Type Id: 4388973; HeightReport: 2303 mm; offset_a: 30 mm; offset_b: 60 mm; subpaneel_1_hoogte: 1943 mm
Model Properties - diepte_offset_a: 0 mm; subpaneel_a1_roedes_hor: 0; subpaneel_a1_roedes_ver: 0; subpaneel_a1_type: WI_subvak1 : glas 2
Dimensions - Height: 2303 mm; netto_hoogte: 2303 mm
Fire Protection - WBDBO 20: no; WBDBO 60: no
Identity Data - Workset: Bouwkundig
Materials and Finishes - paneel_exterieur_materiaal: HPL F7853 ocean gray; paneel_interieur_materiaal: HPL F7853 ocean gray
Phasing - Phase Created: 2. nieuwbouw
Name (31_DO_deur_met_stapeldorpel:deur_met_stapeldorpel:...) | In | OverallWidth (mm) = BaseQuantities, Width (mm) = WidthReport (mm) = netto_breedte (mm) = Dimensions, Width (mm) | BaseQuantities, Area (m2) = Dimensions, Area (m2) | Host Id | subpaneel_a_breedte (mm) | subpaneel_a1_oppervlakte (m2) | draairichting_a_type | Level | paneel_oppervlakte (m2) | Volume (m3) | WBDBO 30 = Zelfsluitend | Firerating_grafisch | Zelfsluitend_grafisch | Mark | Group
5131942 | 00 Begane grond | 1000 | 2.303 | 5131934 | 760 | 1.47668 | BU deur links | 0 | 0.82632 | 0.004606 | yes | 30 | 30 | 3233 | Model Group:H03:5131933 | Pset_Door - NLRS_C_brandwerendheid: 30; Fire Protection - NLRS_C_brandwerendheid: 30
5142281 | 00 Begane grond | 870.5 | 2.00476 | 5142280 | 630.5 | 1.22506 | BU deur rechts | 0 | 0.7797 | 0.00400952 | no | 0 | 0 | 3245 | Model Group:H14:5143401
5142599 | 00 Begane grond | 870.5 | 2.00476 | 5142280 | 630.5 | 1.22506 | BU deur links | 0 | 0.7797 | 0.00400952 | no | 0 | 0 | 3246 | Model Group:H14:5143401
5144105 | 00 Begane grond | 923 | 2.12567 | 5144104 | 683 | 1.32707 | BU deur rechts | 0 | 0.7986 | 0.00425134 | no | 0 | 0 | 3251 | Model Group:H07:5144116
5144112 | 00 Begane grond | 923 | 2.12567 | 5144104 | 683 | 1.32707 | BU deur links | 0 | 0.7986 | 0.00425134 | no | 0 | 0 | 3252 | Model Group:H07:5144116
5145172 | 00 Begane grond | 923 | 2.12567 | 5145171 | 683 | 1.32707 | BU deur rechts | 0 | 0.7986 | 0.00425134 | no | 0 | 0 | 3255 | Model Group:H07:5145183
5145179 | 00 Begane grond | 923 | 2.12567 | 5145171 | 683 | 1.32707 | BU deur links | 0 | 0.7986 | 0.00425134 | no | 0 | 0 | 3256 | Model Group:H07:5145183
5161150 | 00 Begane grond | 900 | 2.0727 | 5151840 | 660 | 1.28238 | BU deur rechts | 0 | 0.79032 | 0.0041454 | yes | 30 | 30 | 2701 | Model Group:H10:5151852 | Pset_Door - NLRS_C_brandwerendheid: 30; Fire Protection - NLRS_C_brandwerendheid: 30
5151848 | 00 Begane grond | 900 | 2.0727 | 5151840 | 660 | 1.28238 | BU deur links | 0 | 0.79032 | 0.0041454 | yes | 30 | 30 | 3259 | Model Group:H10:5151852 | Pset_Door - NLRS_C_brandwerendheid: 30; Fire Protection - NLRS_C_brandwerendheid: 30
5179830 | 01 eerste verdieping | 1000 | 2.303 | 5179822 | 760 | 1.47668 | BU deur links | 1 | 0.82632 | 0.004606 | yes | 30 | 20 | 2722 | Model Group:H03:5179821 | Pset_Door - NLRS_C_brandwerendheid: 20; Fire Protection - NLRS_C_brandwerendheid: 20
5185800 | 01 eerste verdieping | 1000 | 2.303 | 5185792 | 760 | 1.47668 | BU deur links | 1 | 0.82632 | 0.004606 | no | 0 | 0 | 2718 | Model Group:H18:5185791
5194917 | 01 eerste verdieping | 903.75 | 2.08134 | 5194902 | 663.75 | 1.28967 | BU deur rechts | 1 | 0.79167 | 0.00416267 | yes | 30 | 30 | 2729 | Model Group:H12:5194912 | Pset_Door - NLRS_C_brandwerendheid: 30; Fire Protection - NLRS_C_brandwerendheid: 30
5194909 | 01 eerste verdieping | 896.25 | 2.06406 | 5194902 | 656.25 | 1.27509 | BI deur rechts | 1 | 0.78897 | 0.00412813 | yes | 30 | 30 | 2728 | Model Group:H12:5194912 | Pset_Door - NLRS_C_brandwerendheid: 30; Fire Protection - NLRS_C_brandwerendheid: 30
5227227 | 01 eerste verdieping | 923 | 2.12567 | 5227226 | 683 | 1.32707 | BU deur rechts | 1 | 0.7986 | 0.00425134 | no | 0 | 0 | 2731 | Model Group:H07:5227238
5227234 | 01 eerste verdieping | 923 | 2.12567 | 5227226 | 683 | 1.32707 | BU deur links | 1 | 0.7986 | 0.00425134 | no | 0 | 0 | 2733 | Model Group:H07:5227238
5227246 | 01 eerste verdieping | 900 | 2.0727 | 5227245 | 660 | 1.28238 | BU deur links | 1 | 0.79032 | 0.0041454 | no | 0 | 0 | 2734 | Model Group:H16:5227244
5227253 | 01 eerste verdieping | 923 | 2.12567 | 5227252 | 683 | 1.32707 | BU deur rechts | 1 | 0.7986 | 0.00425134 | no | 0 | 0 | 2735 | Model Group:H07:5227264
5227260 | 01 eerste verdieping | 923 | 2.12567 | 5227252 | 683 | 1.32707 | BU deur links | 1 | 0.7986 | 0.00425134 | no | 0 | 0 | 2736 | Model Group:H07:5227264
5276454 | 00 Begane grond | 900 | 2.0727 | 5276453 | 660 | 1.28238 | BU deur links | 0 | 0.79032 | 0.0041454 | no | 0 | 0 | 2694 | Model Group:H16:5197611
5276561 | 00 Begane grond | 900 | 2.0727 | 5276560 | 660 | 1.28238 | BU deur links | 0 | 0.79032 | 0.0041454 | no | 0 | 0 | 2695 | Model Group:H16:5195722
5276570 | 00 Begane grond | 900 | 2.0727 | 5276569 | 660 | 1.28238 | BU deur links | 0 | 0.79032 | 0.0041454 | no | 0 | 0 | 2696 | Model Group:H16:5197451
5465836 | 00 Begane grond | 1000 | 2.303 | 5465828 | 760 | 1.47668 | BU deur links | 0 | 0.82632 | 0.004606 | yes | 30 | 1 | 477 | Model Group:H03:5465827
5533704 | 01 eerste verdieping | 900 | 2.0727 | 5533689 | 660 | 1.28238 | BU deur rechts | 1 | 0.79032 | 0.0041454 | yes | 30 | 20 | 2719 | Model Group:H11:5533699 | Pset_Door - NLRS_C_brandwerendheid: 20; Fire Protection - NLRS_C_brandwerendheid: 20
5533696 | 01 eerste verdieping | 900 | 2.0727 | 5533689 | 660 | 1.28238 | BU deur links | 1 | 0.79032 | 0.0041454 | yes | 30 | 20 | 2715 | Model Group:H11:5533699 | Pset_Door - NLRS_C_brandwerendheid: 20; Fire Protection - NLRS_C_brandwerendheid: 20
5995272 | 01 eerste verdieping | 923 | 2.12567 | 5995271 | 683 | 1.32707 | BU deur rechts | 1 | 0.7986 | 0.00425134 | no | 0 | 0 | 2782 | Model Group:H07:5995281
5995278 | 01 eerste verdieping | 923 | 2.12567 | 5995271 | 683 | 1.32707 | BU deur links | 1 | 0.7986 | 0.00425134 | no | 0 | 0 | 2783 | Model Group:H07:5995281
6382285 | 01 eerste verdieping | 900 | 2.0727 | 6382284 | 660 | 1.28238 | BU deur links | 1 | 0.79032 | 0.0041454 | no | 0 | 0 | 2739 | Model Group:H16:5185909
6604034 | 00 Begane grond | 1000 | 2.303 | 6604026 | 760 | 1.47668 | BU deur links | 0 | 0.82632 | 0.004606 | no | 0 | 0 | 479 | Model Group:H18:5129917
6800003 | 00 Begane grond | 900 | 2.0727 | 6800002 | 660 | 1.28238 | BU deur links | 0 | 0.79032 | 0.0041454 | no | 0 | 0 | 2710 | Model Group:H16:5145073
6800235 | 01 eerste verdieping | 900 | 2.0727 | 6800234 | 660 | 1.28238 | BU deur links | 1 | 0.79032 | 0.0041454 | no | 0 | 0 | 2726 | Model Group:H16:5987797
6800244 | 01 eerste verdieping | 900 | 2.0727 | 6800243 | 660 | 1.28238 | BU deur links | 1 | 0.79032 | 0.0041454 | no | 0 | 0 | 2754 | Model Group:H16:5995318
6801737 | 00 Begane grond | 900 | 2.0727 | 6801736 | 660 | 1.28238 | BU deur links | 0 | 0.79032 | 0.0041454 | no | 0 | 0 | 2794 | Model Group:H16:5130407
6801780 | 00 Begane grond | 900 | 2.0727 | 6801779 | 660 | 1.28238 | BU deur links | 0 | 0.79032 | 0.0041454 | no | 0 | 0 | 2795 | Model Group:H16:5127086
6802015 | 01 eerste verdieping | 900 | 2.0727 | 6802014 | 660 | 1.28238 | BU deur links | 1 | 0.79032 | 0.0041454 | no | 0 | 0 | 2800 | Model Group:H16:5987147
6802178 | 01 eerste verdieping | 900 | 2.0727 | 6802177 | 660 | 1.28238 | BU deur links | 1 | 0.79032 | 0.0041454 | no | 0 | 0 | 2801 | Model Group:H16:5987156
6802219 | 01 eerste verdieping | 900 | 2.0727 | 6802218 | 660 | 1.28238 | BU deur links | 1 | 0.79032 | 0.0041454 | no | 0 | 0 | 2802 | Model Group:H16:5179182

# IfcDoor: 31_DO_deur_met_stapeldorpel:deur_met_stapeldorpel, 31_DO_deur_met_stapeldorpel:deur_met_stapeldorpel:5143931
In: 00 Begane grond
Type - ParameterTakesPrecedence: no; Sizeable: no; Material: HPL F7853 ocean gray, ISR_HPL Kleur hout
Type - Other - Category: Doors; Family Name: 31_DO_deur_met_stapeldorpel
Type - Constraints - offset_bovenkant: 0 mm; offset_links: 0 mm; offset_onderkant: 0 mm; offset_rechts: 0 mm; Offset: 30 mm
Type - Dimensions - Frame: 120 mm; Head: 120 mm; Sill: 240 mm; SillStacks: 0; Thickness: 54 mm
Type - Identity Data - Assembly Code: 31.3; Description: deur met 1 stapeldorpel; Manufacturer: ITANNEX; Model: 10-07-2014; Type Comments: deuren; Type Mark: 341; Type Name: deur_met_stapeldorpel; URL: www.bimvoorfabrikanten.nl; Workset: Family : Doors : 31_DO_deur_met_stapeldorpel
Type - Analytical Properties - Define Thermal Properties by: Schematic Type; Analytic Construction: <None>
Type - Pset_DoorCommon - IsExternal: no
Type - Pset_ManufacturerTypeInformation - Manufacturer: ITANNEX
Type - Pset_ProductRequirements - Category: Doors
Type - Pset_Door - Kozijnmerk: 341
OverallHeight: 2303 mm; OverallWidth: 993 mm; Classification: 31.10 Uniformat (Uniformat); Group: Model Group:H06:5143935
Pset_DoorCommon - Reference: deur_met_stapeldorpel
Pset_QuantityTakeOff - Reference: deur_met_stapeldorpel
Pset_Door - Description: deur met 1 stapeldorpel; NL-sfb-Codering: 31.3; NLRS_C_brandwerendheid: 30
Pset_DAT_KMS - Assembly Code: 31.3; Description: deur met 1 stapeldorpel
BaseQuantities - Height: 2303 mm; Width: 993 mm; Area: 2.28688 m2
Other - offset_bovenkant_a: 0 mm; offset_bovenkant_b: 0 mm; offset_links_a: 0 mm; offset_links_b: 0 mm; offset_onderkant_a: 0 mm; offset_onderkant_b: 0 mm; offset_rechts_a: 0 mm; offset_rechts_b: 0 mm; Family: 31_DO_deur_met_stapeldorpel; Family and Type: 31_DO_deur_met_stapeldorpel: deur_met_stapeldorpel; SillStacksCalc: 2; Type: deur_met_stapeldorpel; Type Id: 4388973; Host Id: 5143923; HeightReport: 2303 mm; offset_a: 30 mm; offset_b: 60 mm; subpaneel_1_hoogte: 1943 mm; subpaneel_a_breedte: 753 mm; subpaneel_a1_oppervlakte: 1.46308 m2; WidthReport: 993 mm
Model Properties - diepte_offset_a: 0 mm; draairichting_a_type: BU deur links; subpaneel_a1_roedes_hor: 0; subpaneel_a1_roedes_ver: 0; subpaneel_a1_type: WI_subvak1 : glas 2
Constraints - Level: 0
Dimensions - Area: 2.28688 m2; Height: 2303 mm; netto_breedte: 993 mm; netto_hoogte: 2303 mm; paneel_oppervlakte: 0.8238 m2; Volume: 0.00457376 m3; Width: 993 mm
Fire Protection - WBDBO 20: no; WBDBO 60: no; WBDBO 30: yes; Zelfsluitend: yes; Firerating_grafisch: 30; NLRS_C_brandwerendheid: 30; Zelfsluitend_grafisch: 30
Identity Data - Workset: Bouwkundig; Mark: 3250
Materials and Finishes - paneel_exterieur_materiaal: HPL F7853 ocean gray; paneel_interieur_materiaal: ISR_HPL Kleur hout
Phasing - Phase Created: 2. nieuwbouw

# IfcDoor: 31_DO_deur_met_stapeldorpel:deur_met_stapeldorpel (17)
Type - ParameterTakesPrecedence: no; Sizeable: no; Material: ISR_HPL Kleur hout
Type - Other - Category: Doors; Family Name: 31_DO_deur_met_stapeldorpel
Type - Constraints - offset_bovenkant: 0 mm; offset_links: 0 mm; offset_onderkant: 0 mm; offset_rechts: 0 mm; Offset: 30 mm
Type - Dimensions - Frame: 120 mm; Head: 120 mm; Sill: 240 mm; SillStacks: 0; Thickness: 54 mm
Type - Identity Data - Assembly Code: 31.3; Description: deur met 1 stapeldorpel; Manufacturer: ITANNEX; Model: 10-07-2014; Type Comments: deuren; Type Mark: 341; Type Name: deur_met_stapeldorpel; URL: www.bimvoorfabrikanten.nl; Workset: Family : Doors : 31_DO_deur_met_stapeldorpel
Type - Analytical Properties - Define Thermal Properties by: Schematic Type; Analytic Construction: <None>
Type - Pset_DoorCommon - IsExternal: no
Type - Pset_ManufacturerTypeInformation - Manufacturer: ITANNEX
Type - Pset_ProductRequirements - Category: Doors
Type - Pset_Door - Kozijnmerk: 341
Classification: 31.10 Uniformat (Uniformat)
Pset_DoorCommon - Reference: deur_met_stapeldorpel
Pset_QuantityTakeOff - Reference: deur_met_stapeldorpel
Pset_Door - Description: deur met 1 stapeldorpel; NL-sfb-Codering: 31.3
Pset_DAT_KMS - Assembly Code: 31.3; Description: deur met 1 stapeldorpel
Other - offset_bovenkant_a: 0 mm; offset_bovenkant_b: 0 mm; offset_links_a: 0 mm; offset_links_b: 0 mm; offset_onderkant_a: 0 mm; offset_onderkant_b: 0 mm; offset_rechts_a: 0 mm; offset_rechts_b: 0 mm; Family: 31_DO_deur_met_stapeldorpel; Family and Type: 31_DO_deur_met_stapeldorpel: deur_met_stapeldorpel; offset_a: 30 mm; offset_b: 60 mm; SillStacksCalc: 2; Type: deur_met_stapeldorpel; Type Id: 4388973
Model Properties - diepte_offset_a: 0 mm; subpaneel_a1_roedes_hor: 0; subpaneel_a1_roedes_ver: 0; subpaneel_a1_type: WI_subvak1 : glas 2
Fire Protection - WBDBO 20: no; WBDBO 60: no
Identity Data - Workset: Bouwkundig
Materials and Finishes - paneel_exterieur_materiaal: ISR_HPL Kleur hout; paneel_interieur_materiaal: ISR_HPL Kleur hout
Phasing - Phase Created: 2. nieuwbouw
Name (31_DO_deur_met_stapeldorpel:deur_met_stapeldorpel:...) | In | OverallHeight (mm) = BaseQuantities, Height (mm) = HeightReport (mm) = Dimensions, Height (mm) = netto_hoogte (mm) | OverallWidth (mm) = BaseQuantities, Width (mm) = WidthReport (mm) = netto_breedte (mm) = Dimensions, Width (mm) | BaseQuantities, Area (m2) = Dimensions, Area (m2) | Host Id | subpaneel_1_hoogte (mm) | subpaneel_a_breedte (mm) | subpaneel_a1_oppervlakte (m2) | draairichting_a_type | Level | paneel_oppervlakte (m2) | Volume (m3) | WBDBO 30 = Zelfsluitend | Firerating_grafisch = Zelfsluitend_grafisch | Mark | Group
5130957 | 00 Begane grond | 2280 | 1000 | 2.28 | 5130949 | 1920 | 760 | 1.4592 | BU deur links | 0 | 0.8208 | 0.00456 | no | 0 | 3232 | Model Group:H04:5130948 | Pset_DoorCommon - IsExternal: yes
5131655 | 00 Begane grond | 2280 | 1000 | 2.28 | 5131647 | 1920 | 760 | 1.4592 | BU deur links | 0 | 0.8208 | 0.00456 | yes | 30 | 3223 | Model Group:H04:5131646 | Pset_Door - NLRS_C_brandwerendheid: R200; Fire Protection - NLRS_C_brandwerendheid: R200
5143924 | 00 Begane grond | 2303 | 993 | 2.28688 | 5143923 | 1943 | 753 | 1.46308 | BU deur rechts | 0 | 0.8238 | 0.00457376 | yes | 30 | 3249 | Model Group:H06:5143935 | Pset_Door - NLRS_C_brandwerendheid: 30; Fire Protection - NLRS_C_brandwerendheid: 30
5149167 | 00 Begane grond | 2303 | 1000 | 2.303 | 5149166 | 1943 | 760 | 1.47668 | BU deur links | 0 | 0.82632 | 0.004606 | no | 0 | 2682 | Model Group:H09:5145245
5149211 | 00 Begane grond | 2303 | 1000 | 2.303 | 5149210 | 1943 | 760 | 1.47668 | BU deur links | 0 | 0.82632 | 0.004606 | no | 0 | 2685 | Model Group:H09:5145654
5149219 | 00 Begane grond | 2303 | 1000 | 2.303 | 5149218 | 1943 | 760 | 1.47668 | BU deur links | 0 | 0.82632 | 0.004606 | no | 0 | 2686 | Model Group:H09:5145678
5167024 | 01 eerste verdieping | 2303 | 1000 | 2.303 | 5167023 | 1943 | 760 | 1.47668 | BU deur links | 1 | 0.82632 | 0.004606 | no | 0 | 3261 | Model Group:H09:5167012
5167165 | 01 eerste verdieping | 2303 | 1000 | 2.303 | 5167164 | 1943 | 760 | 1.47668 | BU deur links | 1 | 0.82632 | 0.004606 | no | 0 | 3263 | Model Group:H09:5167153
5174895 | 01 eerste verdieping | 2303 | 1000 | 2.303 | 5174894 | 1943 | 760 | 1.47668 | BU deur links | 1 | 0.82632 | 0.004606 | no | 0 | 3272 | Model Group:H09:5174883
5181899 | 01 eerste verdieping | 2303 | 1000 | 2.303 | 5181898 | 1943 | 760 | 1.47668 | BU deur links | 1 | 0.82632 | 0.004606 | no | 0 | 2702 | Model Group:H09:5181878
5184358 | 01 eerste verdieping | 2303 | 1000 | 2.303 | 5184357 | 1943 | 760 | 1.47668 | BU deur links | 1 | 0.82632 | 0.004606 | no | 0 | 2714 | Model Group:H09:5184337
5184407 | 01 eerste verdieping | 2303 | 1000 | 2.303 | 5184406 | 1943 | 760 | 1.47668 | BU deur links | 1 | 0.82632 | 0.004606 | no | 0 | 2717 | Model Group:H09:5184386
5203622 | 00 Begane grond | 2303 | 1000 | 2.303 | 5203621 | 1943 | 760 | 1.47668 | BU deur links | 0 | 0.82632 | 0.004606 | no | 0 | 2725 | Model Group:H09:5203601
5206889 | 00 Begane grond | 2303 | 1000 | 2.303 | 5206888 | 1943 | 760 | 1.47668 | BU deur links | 0 | 0.82632 | 0.004606 | no | 0 | 2732 | Model Group:H09:5206741
5988149 | 01 eerste verdieping | 2303 | 1000 | 2.303 | 5988148 | 1943 | 760 | 1.47668 | BU deur links | 1 | 0.82632 | 0.004606 | no | 0 | 2780 | Model Group:H09:5988145
6241470 | 00 Begane grond | 2280 | 1000 | 2.28 | 6241462 | 1920 | 760 | 1.4592 | BU deur links | 0 | 0.8208 | 0.00456 | yes | 30 | 2691 | Model Group:H04:6241461 | Pset_Door - NLRS_C_brandwerendheid: R200; Fire Protection - NLRS_C_brandwerendheid: R200
6668704 | 00 Begane grond | 2303 | 1000 | 2.303 | 6668703 | 1943 | 760 | 1.47668 | BU deur links | 0 | 0.82632 | 0.004606 | yes | 30 | 2740 | Model Group:H09:6668701

# IfcDoor: 31_DO_deur_met_stapeldorpel:deur_met_stapeldorpel Gealan Links, 31_DO_deur_met_stapeldorpel:deur_met_stapeldorpel Gealan Links:5537550
In: 00 Begane grond
Type - ParameterTakesPrecedence: no; Sizeable: no; Material: ISR_Kunststof_RAL7006
Type - Other - Category: Doors; Family Name: 31_DO_deur_met_stapeldorpel
Type - Constraints - offset_rechts: 0 mm; Offset: -18 mm; offset_bovenkant: 64 mm; offset_links: 64 mm; offset_onderkant: 64 mm
Type - Dimensions - SillStacks: 0; Frame: 120 mm; Head: 120 mm; Sill: 240 mm; Thickness: 86 mm
Type - Identity Data - Workset: Family : Doors : 31_DO_deur_met_stapeldorpel; Assembly Code: 31.3; Description: deur met 1 stapeldorpel; Manufacturer: ITANNEX; Model: 10-07-2014; Type Comments: deuren; Type Mark: 353; Type Name: deur_met_stapeldorpel Gealan Links; URL: www.bimvoorfabrikanten.nl
Type - Analytical Properties - Define Thermal Properties by: Schematic Type; Analytic Construction: <None>
Type - Pset_DoorCommon - IsExternal: no
Type - Pset_ManufacturerTypeInformation - Manufacturer: ITANNEX
Type - Pset_ProductRequirements - Category: Doors
Type - Pset_Door - Kozijnmerk: 353
OverallHeight: 2618 mm; OverallWidth: 997 mm; Classification: 31 Uniformat (Uniformat); Group: Model Group:Merk K15:5537536
Pset_DoorCommon - IsExternal: yes; Reference: deur_met_stapeldorpel Gealan Links
Pset_QuantityTakeOff - Reference: deur_met_stapeldorpel Gealan Links
Pset_Door - Description: deur met 1 stapeldorpel; NL-sfb-Codering: 31.3
Pset_DAT_KMS - Assembly Code: 31.3; Description: deur met 1 stapeldorpel
BaseQuantities - Height: 2490 mm; Width: 901 mm; Area: 2.24349 m2
Other - offset_rechts_a: 0 mm; offset_rechts_b: 0 mm; offset_b: 0 mm; Family: 31_DO_deur_met_stapeldorpel; SillStacksCalc: 2; Host Id: 5537537; Family and Type: 31_DO_deur_met_stapeldorpel: deur_met_stapeldorpel Gealan Links; HeightReport: 2490 mm; offset_a: 18 mm; offset_bovenkant_a: 64 mm; offset_bovenkant_b: 128 mm; offset_links_a: 64 mm; offset_links_b: 128 mm; offset_onderkant_a: 64 mm; offset_onderkant_b: 128 mm; subpaneel_1_hoogte: 2258 mm; subpaneel_a_breedte: 725 mm; subpaneel_a1_oppervlakte: 1.63705 m2; Type: deur_met_stapeldorpel Gealan Links; Type Id: 6477741; WidthReport: 901 mm
Model Properties - diepte_offset_a: 0 mm; subpaneel_a1_roedes_hor: 0; subpaneel_a1_roedes_ver: 0; subpaneel_a1_type: WI_subvak1 : glas 2; draairichting_a_type: BI deur rechts
Constraints - Level: 0
Dimensions - Area: 2.24349 m2; Height: 2490 mm; netto_breedte: 965 mm; netto_hoogte: 2618 mm; paneel_oppervlakte: 0.88932 m2; Volume: 0.00448698 m3; Width: 901 mm
Fire Protection - WBDBO 20: no; WBDBO 30: no; WBDBO 60: no; Zelfsluitend: yes; Firerating_grafisch: 0; Zelfsluitend_grafisch: 1
Identity Data - Workset: Bouwkundig; Mark: 2769
Materials and Finishes - paneel_exterieur_materiaal: ISR_Kunststof_RAL7006; paneel_interieur_materiaal: ISR_Kunststof_RAL7006
Phasing - Phase Created: 2. nieuwbouw

# IfcDoor: 31_DO_deur_met_stapeldorpel:deur_met_stapeldorpel Gealan Rechts, 31_DO_deur_met_stapeldorpel:deur_met_stapeldorpel Gealan Rechts:5537538
In: 00 Begane grond
Type - ParameterTakesPrecedence: no; Sizeable: no; Material: ISR_Kunststof_RAL7006
Type - Other - Category: Doors; Family Name: 31_DO_deur_met_stapeldorpel
Type - Constraints - offset_links: 0 mm; Offset: -18 mm; offset_bovenkant: 64 mm; offset_onderkant: 64 mm; offset_rechts: 64 mm
Type - Dimensions - SillStacks: 0; Frame: 120 mm; Head: 120 mm; Sill: 240 mm; Thickness: 86 mm
Type - Identity Data - Workset: Family : Doors : 31_DO_deur_met_stapeldorpel; Assembly Code: 31.3; Description: deur met 1 stapeldorpel; Manufacturer: ITANNEX; Model: 10-07-2014; Type Comments: deuren; Type Mark: 354; Type Name: deur_met_stapeldorpel Gealan Rechts; URL: www.bimvoorfabrikanten.nl
Type - Analytical Properties - Define Thermal Properties by: Schematic Type; Analytic Construction: <None>
Type - Pset_DoorCommon - IsExternal: no
Type - Pset_ManufacturerTypeInformation - Manufacturer: ITANNEX
Type - Pset_ProductRequirements - Category: Doors
Type - Pset_Door - Kozijnmerk: 354
OverallHeight: 2618 mm; OverallWidth: 1071 mm; Classification: 31 Uniformat (Uniformat); Group: Model Group:Merk K15:5537536
Pset_DoorCommon - IsExternal: yes; Reference: deur_met_stapeldorpel Gealan Rechts
Pset_QuantityTakeOff - Reference: deur_met_stapeldorpel Gealan Rechts
Pset_Door - Description: deur met 1 stapeldorpel; NL-sfb-Codering: 31.3
Pset_DAT_KMS - Assembly Code: 31.3; Description: deur met 1 stapeldorpel
BaseQuantities - Height: 2490 mm; Width: 975 mm; Area: 2.42775 m2
Other - offset_links_a: 0 mm; offset_links_b: 0 mm; offset_b: 0 mm; Family: 31_DO_deur_met_stapeldorpel; SillStacksCalc: 2; Family and Type: 31_DO_deur_met_stapeldorpel: deur_met_stapeldorpel Gealan Rechts; HeightReport: 2490 mm; Host Id: 5537537; offset_a: 18 mm; offset_bovenkant_a: 64 mm; offset_bovenkant_b: 128 mm; offset_onderkant_a: 64 mm; offset_onderkant_b: 128 mm; offset_rechts_a: 64 mm; offset_rechts_b: 128 mm; subpaneel_1_hoogte: 2258 mm; subpaneel_a_breedte: 799 mm; subpaneel_a1_oppervlakte: 1.80414 m2; Type: deur_met_stapeldorpel Gealan Rechts; Type Id: 6479543; WidthReport: 975 mm
Model Properties - diepte_offset_a: 0 mm; subpaneel_a1_roedes_hor: 0; subpaneel_a1_roedes_ver: 0; subpaneel_a1_type: WI_subvak1 : glas 2; draairichting_a_type: BI deur links
Constraints - Level: 0
Dimensions - Area: 2.42775 m2; Height: 2490 mm; netto_breedte: 1039 mm; netto_hoogte: 2618 mm; paneel_oppervlakte: 0.91596 m2; Volume: 0.0048555 m3; Width: 975 mm
Fire Protection - WBDBO 20: no; WBDBO 30: no; WBDBO 60: no; Zelfsluitend: yes; Firerating_grafisch: 0; Zelfsluitend_grafisch: 1
Identity Data - Workset: Bouwkundig; Mark: 2768
Materials and Finishes - paneel_exterieur_materiaal: ISR_Kunststof_RAL7006; paneel_interieur_materiaal: ISR_Kunststof_RAL7006
Phasing - Phase Created: 2. nieuwbouw

# IfcDoor: 31_DO_dichte_deur:berging dakluik (2)
In: 00 Begane grond
Type - ParameterTakesPrecedence: no; Sizeable: no; Material: ISR_Underlayment, ISR_Dak_folie
Type - Other - Category: Doors; Family Name: 31_DO_dichte_deur
Type - Constraints - offset_bovenkant: 0 mm; offset_links: 0 mm; offset_onderkant: 0 mm; offset_rechts: 0 mm; Offset: 30 mm
Type - Dimensions - Thickness: 54 mm
Type - Identity Data - Workset: Family : Doors : 31_DO_dichte_deur; Assembly Code: 31.3; Description: deur dicht; Manufacturer: ITANNEX; Model: 10-07-2014; Type Comments: deuren; Type Mark: 353; Type Name: berging dakluik; URL: www.bimvoorfabrikanten.nl
Type - Analytical Properties - Define Thermal Properties by: Schematic Type; Analytic Construction: <None>
Type - Pset_DoorCommon - IsExternal: no
Type - Pset_ManufacturerTypeInformation - Manufacturer: ITANNEX
Type - Pset_ProductRequirements - Category: Doors
Type - Pset_Door - Kozijnmerk: 353
OverallHeight: 1977.75 mm; OverallWidth: 1417 mm; Classification: 27.20 Uniformat (Uniformat)
Pset_DoorCommon - IsExternal: yes; Reference: berging dakluik
Pset_QuantityTakeOff - Reference: berging dakluik
Pset_Door - Description: deur dicht; NL-sfb-Codering: 31.3
Pset_DAT_KMS - Assembly Code: 31.3; Description: deur dicht
BaseQuantities - Height: 2389 mm; Width: 1417 mm; Area: 3.38521 m2
Other - offset_bovenkant_a: 0 mm; offset_bovenkant_b: 0 mm; offset_links_a: 0 mm; offset_links_b: 0 mm; offset_onderkant_a: 0 mm; offset_onderkant_b: 0 mm; offset_rechts_a: 0 mm; offset_rechts_b: 0 mm; Family: 31_DO_dichte_deur; Family and Type: 31_DO_dichte_deur: berging dakluik; HeightReport: 2389 mm; Host Id: 6486298; offset_a: 1 mm; offset_b: 2 mm; Type: berging dakluik; Type Id: 6486329; WidthReport: 1417 mm
Model Properties - draairichting_a_type: BI deur links; diepte_offset_a: 1 mm
Constraints - Level: 0
Dimensions - Area: 3.38521 m2; Height: 2389 mm; netto_breedte: 1417 mm; netto_hoogte: 2389 mm; paneel_oppervlakte: 3.38521 m2; Volume: 0.0914008 m3; Width: 1417 mm
Fire Protection - WBDBO 20: no; WBDBO 30: no; WBDBO 60: no; Zelfsluitend: no; Firerating_grafisch: 0; Zelfsluitend_grafisch: 0
Graphics - Geen WBDBO of zelfsluitend: yes
Identity Data - Workset: situatie
Materials and Finishes - paneel_exterieur_materiaal: ISR_Dak_folie; paneel_interieur_materiaal: ISR_Underlayment
Phasing - Phase Created: 2. nieuwbouw
Name (31_DO_dichte_deur:berging dakluik:...)
6486308
6486317

# IfcDoor: 31_DO_dichte_deur:dichte_deur (5)
Type - ParameterTakesPrecedence: no; Sizeable: no; Material: HPL F7853 ocean gray
Type - Other - Category: Doors; Family Name: 31_DO_dichte_deur
Type - Constraints - offset_bovenkant: 0 mm; offset_links: 0 mm; offset_onderkant: 0 mm; offset_rechts: 0 mm; Offset: 30 mm
Type - Dimensions - Thickness: 54 mm
Type - Identity Data - Assembly Code: 31.3; Description: deur dicht; Manufacturer: ITANNEX; Model: 10-07-2014; Type Comments: deuren; Type Mark: 338; Type Name: dichte_deur; URL: www.bimvoorfabrikanten.nl; Workset: Family : Doors : 31_DO_dichte_deur
Type - Analytical Properties - Define Thermal Properties by: Schematic Type; Analytic Construction: <None>
Type - Pset_DoorCommon - IsExternal: no
Type - Pset_ManufacturerTypeInformation - Manufacturer: ITANNEX
Type - Pset_ProductRequirements - Category: Doors
Type - Pset_Door - Kozijnmerk: 338
Classification: 31.10 Uniformat (Uniformat)
Pset_DoorCommon - Reference: dichte_deur
Pset_QuantityTakeOff - Reference: dichte_deur
Pset_Door - Description: deur dicht; NL-sfb-Codering: 31.3
Pset_DAT_KMS - Assembly Code: 31.3; Description: deur dicht
Other - offset_bovenkant_a: 0 mm; offset_bovenkant_b: 0 mm; offset_links_a: 0 mm; offset_links_b: 0 mm; offset_onderkant_a: 0 mm; offset_onderkant_b: 0 mm; offset_rechts_a: 0 mm; offset_rechts_b: 0 mm; Type: dichte_deur; Family: 31_DO_dichte_deur; Family and Type: 31_DO_dichte_deur: dichte_deur; Type Id: 4388966
Fire Protection - WBDBO 20: no; WBDBO 30: no; WBDBO 60: no; Zelfsluitend: no; Firerating_grafisch: 0; Zelfsluitend_grafisch: 0
Graphics - Geen WBDBO of zelfsluitend: yes
Identity Data - Workset: Bouwkundig
Materials and Finishes - paneel_exterieur_materiaal: HPL F7853 ocean gray; paneel_interieur_materiaal: HPL F7853 ocean gray
Phasing - Phase Created: 2. nieuwbouw
Name (31_DO_dichte_deur:dichte_deur:...) | In | OverallHeight (mm) = BaseQuantities, Height (mm) = HeightReport (mm) = Dimensions, Height (mm) = netto_hoogte (mm) | OverallWidth (mm) | BaseQuantities, Width (mm) = WidthReport (mm) = netto_breedte (mm) = Dimensions, Width (mm) | BaseQuantities, Area (m2) = Dimensions, Area (m2) = paneel_oppervlakte (m2) | Host Id | offset_a (mm) | offset_b (mm) | draairichting_a_type | diepte_offset_a (mm) | Level | Volume (m3) | Mark | Group
5125871 | 00 Begane grond | 2303 | 966 | 966 | 2.2247 | 5125870 | 1 | 0 | BU deur links | -1 | 0 | 0.0600668 | 488 | Model Group:H19:5125869 | Pset_DoorCommon - IsExternal: yes
5493792 | -1 Speelvloer | 2610 | 2200 | 1160 | 3.0276 | 5493791 | 30 | 60 | BU schuif links | 0 | V-1 | 0.0817452 | 2738 | Model Group:H22:5493776
5493799 | -1 Speelvloer | 2610 | 1640 | 880 | 2.2968 | 5493791 | 30 | 60 | BI schuif rechts | 0 | V-1 | 0.0620136 | 2747 | Model Group:H22:5493776
6608198 | -1 Speelvloer | 2610 | 1954 | 1037 | 2.70657 | 6608197 | 30 | 60 | BU schuif links | 0 | V-1 | 0.0730774 | 3219 | Model Group:H23:5131789
6608205 | -1 Speelvloer | 2610 | 1955.92 | 1037.96 | 2.70908 | 6608197 | 30 | 60 | BI schuif rechts | 0 | V-1 | 0.073145 | 3220 | Model Group:H23:5131789

# IfcDoor: 31_DO_dichte_deur:dichte_deur, 31_DO_dichte_deur:dichte_deur:5140501
In: 00 Begane grond
Type - ParameterTakesPrecedence: no; Sizeable: no; Material: HPL F7853 ocean gray, ISR_HPL Kleur hout
Type - Other - Category: Doors; Family Name: 31_DO_dichte_deur
Type - Constraints - offset_bovenkant: 0 mm; offset_links: 0 mm; offset_onderkant: 0 mm; offset_rechts: 0 mm; Offset: 30 mm
Type - Dimensions - Thickness: 54 mm
Type - Identity Data - Assembly Code: 31.3; Description: deur dicht; Manufacturer: ITANNEX; Model: 10-07-2014; Type Comments: deuren; Type Mark: 338; Type Name: dichte_deur; URL: www.bimvoorfabrikanten.nl; Workset: Family : Doors : 31_DO_dichte_deur
Type - Analytical Properties - Define Thermal Properties by: Schematic Type; Analytic Construction: <None>
Type - Pset_DoorCommon - IsExternal: no
Type - Pset_ManufacturerTypeInformation - Manufacturer: ITANNEX
Type - Pset_ProductRequirements - Category: Doors
Type - Pset_Door - Kozijnmerk: 338
OverallHeight: 2303 mm; OverallWidth: 933 mm; Classification: 31.10 Uniformat (Uniformat); Group: Model Group:H20:5488876
Pset_DoorCommon - Reference: dichte_deur
Pset_QuantityTakeOff - Reference: dichte_deur
Pset_Door - Description: deur dicht; NL-sfb-Codering: 31.3
Pset_DAT_KMS - Assembly Code: 31.3; Description: deur dicht
BaseQuantities - Height: 2303 mm; Width: 933 mm; Area: 2.1487 m2
Other - offset_bovenkant_a: 0 mm; offset_bovenkant_b: 0 mm; offset_links_a: 0 mm; offset_links_b: 0 mm; offset_onderkant_a: 0 mm; offset_onderkant_b: 0 mm; offset_rechts_a: 0 mm; offset_rechts_b: 0 mm; Type: dichte_deur; Family: 31_DO_dichte_deur; Family and Type: 31_DO_dichte_deur: dichte_deur; Type Id: 4388966; HeightReport: 2303 mm; Host Id: 5140500; offset_a: 60 mm; offset_b: 120 mm; WidthReport: 933 mm
Model Properties - diepte_offset_a: 60 mm; draairichting_a_type: BU deur rechts
Constraints - Level: 0
Dimensions - Area: 2.1487 m2; Height: 2303 mm; netto_breedte: 933 mm; netto_hoogte: 2303 mm; paneel_oppervlakte: 2.1487 m2; Volume: 0.0580149 m3; Width: 933 mm
Fire Protection - WBDBO 20: no; WBDBO 30: no; WBDBO 60: no; Zelfsluitend: no; Firerating_grafisch: 0; Zelfsluitend_grafisch: 0
Graphics - Geen WBDBO of zelfsluitend: yes
Identity Data - Workset: Bouwkundig; Mark: 3242
Materials and Finishes - paneel_interieur_materiaal: HPL F7853 ocean gray; paneel_exterieur_materiaal: ISR_HPL Kleur hout
Phasing - Phase Created: 2. nieuwbouw

# IfcDoor: 31_DO_dichte_deur:dichte_deur (9)
In: 00 Begane grond
Type - ParameterTakesPrecedence: no; Sizeable: no; Material: ISR_HPL Kleur hout
Type - Other - Category: Doors; Family Name: 31_DO_dichte_deur
Type - Constraints - offset_bovenkant: 0 mm; offset_links: 0 mm; offset_onderkant: 0 mm; offset_rechts: 0 mm; Offset: 30 mm
Type - Dimensions - Thickness: 54 mm
Type - Identity Data - Assembly Code: 31.3; Description: deur dicht; Manufacturer: ITANNEX; Model: 10-07-2014; Type Comments: deuren; Type Mark: 338; Type Name: dichte_deur; URL: www.bimvoorfabrikanten.nl; Workset: Family : Doors : 31_DO_dichte_deur
Type - Analytical Properties - Define Thermal Properties by: Schematic Type; Analytic Construction: <None>
Type - Pset_DoorCommon - IsExternal: no
Type - Pset_ManufacturerTypeInformation - Manufacturer: ITANNEX
Type - Pset_ProductRequirements - Category: Doors
Type - Pset_Door - Kozijnmerk: 338
Classification: 31.10 Uniformat (Uniformat)
Pset_DoorCommon - Reference: dichte_deur
Pset_QuantityTakeOff - Reference: dichte_deur
Pset_Door - Description: deur dicht; NL-sfb-Codering: 31.3
Pset_DAT_KMS - Assembly Code: 31.3; Description: deur dicht
Other - offset_bovenkant_a: 0 mm; offset_bovenkant_b: 0 mm; offset_links_a: 0 mm; offset_links_b: 0 mm; offset_onderkant_a: 0 mm; offset_onderkant_b: 0 mm; offset_rechts_a: 0 mm; offset_rechts_b: 0 mm; Type: dichte_deur; Family: 31_DO_dichte_deur; Family and Type: 31_DO_dichte_deur: dichte_deur; Type Id: 4388966
Constraints - Level: 0
Fire Protection - WBDBO 20: no; WBDBO 30: no; WBDBO 60: no; Zelfsluitend: no; Firerating_grafisch: 0; Zelfsluitend_grafisch: 0
Graphics - Geen WBDBO of zelfsluitend: yes
Identity Data - Workset: Bouwkundig
Materials and Finishes - paneel_exterieur_materiaal: ISR_HPL Kleur hout; paneel_interieur_materiaal: ISR_HPL Kleur hout
Phasing - Phase Created: 2. nieuwbouw
Name (31_DO_dichte_deur:dichte_deur:...) | OverallHeight (mm) = BaseQuantities, Height (mm) = HeightReport (mm) = Dimensions, Height (mm) = netto_hoogte (mm) | OverallWidth (mm) | BaseQuantities, Width (mm) = WidthReport (mm) = netto_breedte (mm) = Dimensions, Width (mm) | BaseQuantities, Area (m2) = Dimensions, Area (m2) = paneel_oppervlakte (m2) | Host Id | offset_a (mm) | offset_b (mm) | draairichting_a_type | diepte_offset_a (mm) | Volume (m3) | Mark | Group
5488369 | 2303 | 933 | 933 | 2.1487 | 5140500 | 60 | 120 | BU deur links | 60 | 0.0580149 | 2737 | Model Group:H20:5488876
5489860 | 2350 | 2250 | 1185 | 2.78475 | 5489859 | 30 | 60 | BU schuif links | 0 | 0.0751882 | 2741 | Model Group:H24:5489871
5489867 | 2350 | 2150 | 1135 | 2.66725 | 5489859 | 30 | 60 | BI schuif rechts | 0 | 0.0720157 | 2742 | Model Group:H24:5489871
5489887 | 2350 | 2135 | 1127.5 | 2.64963 | 5489886 | 30 | 60 | BU schuif links | 0 | 0.0715399 | 2743 | Model Group:H21:5489898
5489894 | 2350 | 2145 | 1132.5 | 2.66137 | 5489886 | 30 | 60 | BI schuif rechts | 0 | 0.0718571 | 2744 | Model Group:H21:5489898
5490910 | 2350 | 2250 | 1185 | 2.78475 | 5490909 | 30 | 60 | BU schuif links | 0 | 0.0751882 | 2752 | Model Group:H24:5490908
5490917 | 2350 | 2150 | 1135 | 2.66725 | 5490909 | 30 | 60 | BI schuif rechts | 0 | 0.0720157 | 2753 | Model Group:H24:5490908
6241703 | 2350 | 2250 | 1185 | 2.78475 | 6241702 | 30 | 60 | BU schuif links | 0 | 0.0751882 | 2697 | Model Group:H24:6241714
6241710 | 2350 | 2150 | 1135 | 2.66725 | 6241702 | 30 | 60 | BI schuif rechts | 0 | 0.0720157 | 2698 | Model Group:H24:6241714

# IfcDoor: 31_DO_dichte_deur:dichte_deur (11)
Type - ParameterTakesPrecedence: no; Sizeable: no; Material: ISR_Kunststof_wit
Type - Other - Category: Doors; Family Name: 31_DO_dichte_deur
Type - Constraints - offset_bovenkant: 0 mm; offset_links: 0 mm; offset_onderkant: 0 mm; offset_rechts: 0 mm; Offset: 30 mm
Type - Dimensions - Thickness: 54 mm
Type - Identity Data - Assembly Code: 31.3; Description: deur dicht; Manufacturer: ITANNEX; Model: 10-07-2014; Type Comments: deuren; Type Mark: 338; Type Name: dichte_deur; URL: www.bimvoorfabrikanten.nl; Workset: Family : Doors : 31_DO_dichte_deur
Type - Analytical Properties - Define Thermal Properties by: Schematic Type; Analytic Construction: <None>
Type - Pset_DoorCommon - IsExternal: no
Type - Pset_ManufacturerTypeInformation - Manufacturer: ITANNEX
Type - Pset_ProductRequirements - Category: Doors
Type - Pset_Door - Kozijnmerk: 338
OverallHeight: 2303 mm; OverallWidth: 900 mm; Classification: 31.10 Uniformat (Uniformat)
Pset_DoorCommon - Reference: dichte_deur
Pset_QuantityTakeOff - Reference: dichte_deur
Pset_Door - Description: deur dicht; NL-sfb-Codering: 31.3
Pset_DAT_KMS - Assembly Code: 31.3; Description: deur dicht
BaseQuantities - Height: 2303 mm; Width: 900 mm; Area: 2.0727 m2
Other - offset_bovenkant_a: 0 mm; offset_bovenkant_b: 0 mm; offset_links_a: 0 mm; offset_links_b: 0 mm; offset_onderkant_a: 0 mm; offset_onderkant_b: 0 mm; offset_rechts_a: 0 mm; offset_rechts_b: 0 mm; Type: dichte_deur; Family: 31_DO_dichte_deur; Family and Type: 31_DO_dichte_deur: dichte_deur; offset_b: 0 mm; Type Id: 4388966; HeightReport: 2303 mm; offset_a: 1 mm; WidthReport: 900 mm
Model Properties - draairichting_a_type: BU deur links; diepte_offset_a: -1 mm
Dimensions - Area: 2.0727 m2; Height: 2303 mm; netto_breedte: 900 mm; netto_hoogte: 2303 mm; paneel_oppervlakte: 2.0727 m2; Volume: 0.0559629 m3; Width: 900 mm
Fire Protection - WBDBO 20: no; WBDBO 30: no; WBDBO 60: no; Zelfsluitend: no; Firerating_grafisch: 0; Zelfsluitend_grafisch: 0
Graphics - Geen WBDBO of zelfsluitend: yes
Identity Data - Workset: Bouwkundig
Materials and Finishes - paneel_exterieur_materiaal: ISR_Kunststof_wit; paneel_interieur_materiaal: ISR_Kunststof_wit
Phasing - Phase Created: 2. nieuwbouw
Name (31_DO_dichte_deur:dichte_deur:...) | In | Host Id | Level | Mark | Group
5126987 | 00 Begane grond | 5126986 | 0 | 2701 | Model Group:H02:5126985
5130146 | 00 Begane grond | 5130145 | 0 | 3224 | Model Group:H02:5130144
5202331 | 00 Begane grond | 5202330 | 0 | 2723 | Model Group:H02:5127227
5206508 | 00 Begane grond | 5206507 | 0 | 2724 | Model Group:H02:5206506
5533683 | 01 eerste verdieping | 5533682 | 1 | 2704 | Model Group:H02:5533681
5987150 | 01 eerste verdieping | 5987149 | 1 | 2745 | Model Group:H02:5987148
5987396 | 01 eerste verdieping | 5987395 | 1 | 2750 | Model Group:H02:5987394
5987404 | 01 eerste verdieping | 5987403 | 1 | 2751 | Model Group:H02:5987402
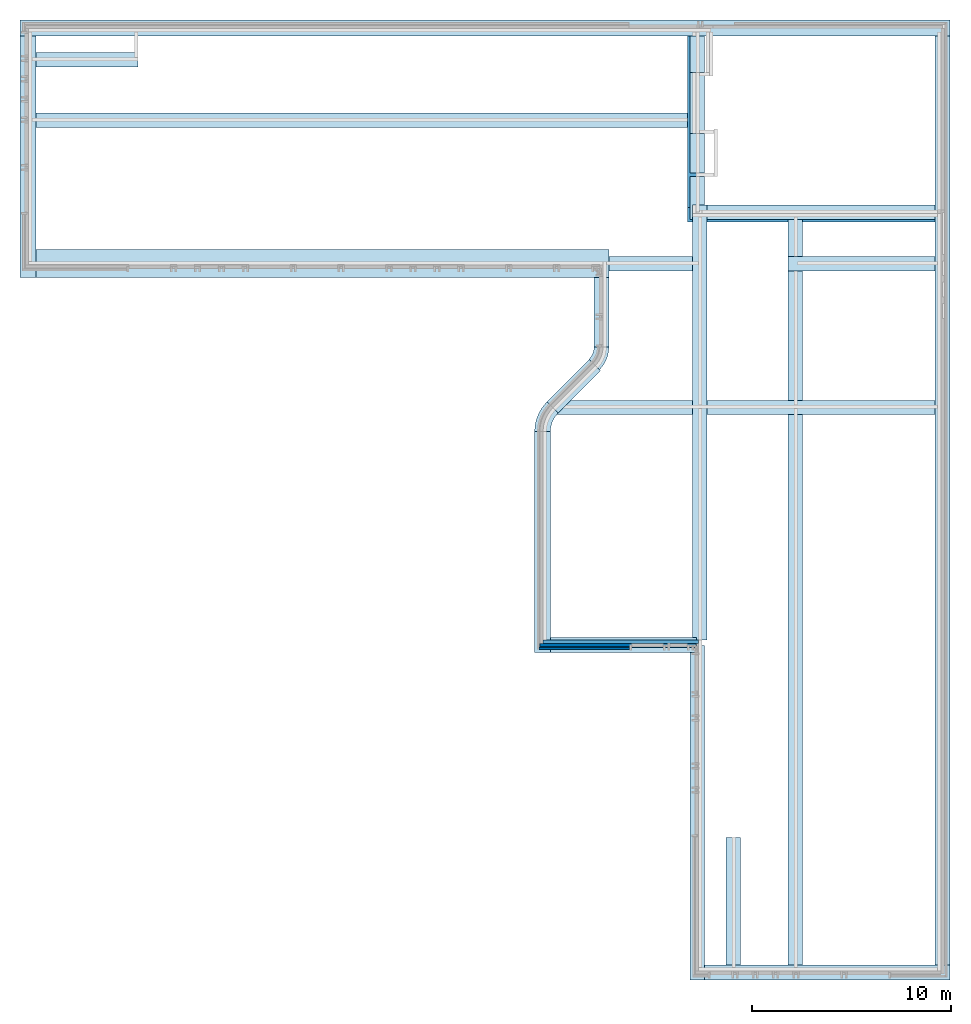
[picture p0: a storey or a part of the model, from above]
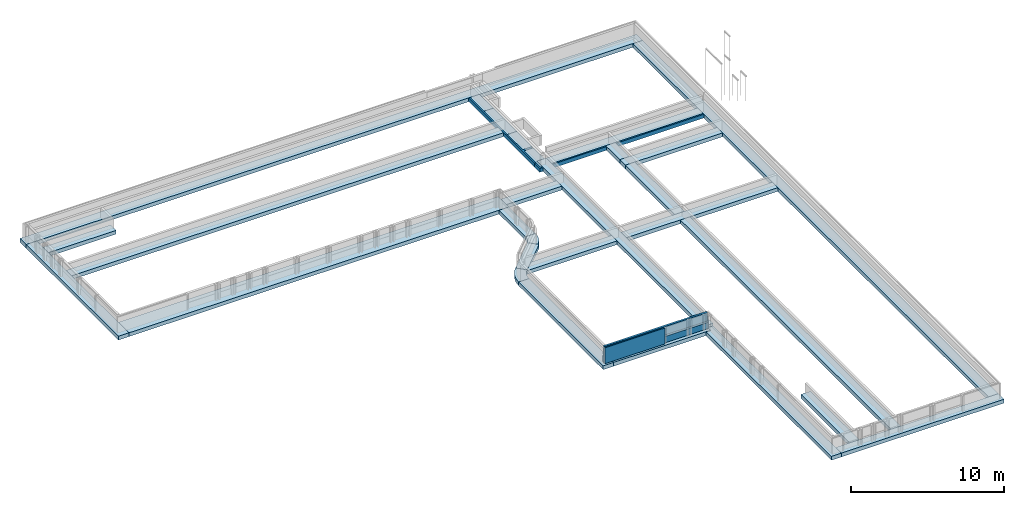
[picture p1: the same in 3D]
Properties of the parts of a building model (IFC2X3), part 14 of 37

# IfcDoor: 31_DO_dichte_deur:dichte_deur (11)
Name (31_DO_dichte_deur:dichte_deur:...) | In | Host Id | Level | Mark | Group
6522732 | 00 Begane grond | 6522731 | 0 | 2787 | Model Group:H02:6522730
6694316 | 00 Begane grond | 6694315 | 0 | 2692 | Model Group:H02:6694314
6804082 | 00 Begane grond | 6804081 | 0 | 2804 | Model Group:H02:5126556

# IfcDoor: 31_DO_dichte_deur:dichte_deur buitenberging (12)
In: 00 Begane grond
Type - ParameterTakesPrecedence: no; Sizeable: no; Material: ISR_Hardhout_gevelbekleding
Type - Other - Category: Doors; Family Name: 31_DO_dichte_deur
Type - Constraints - offset_bovenkant: 0 mm; offset_links: 0 mm; offset_onderkant: 0 mm; offset_rechts: 0 mm; Offset: 30 mm
Type - Dimensions - Thickness: 16 mm
Type - Identity Data - Workset: Family : Doors : 31_DO_dichte_deur; Assembly Code: 31.3; Description: deur dicht; Manufacturer: ITANNEX; Model: 10-07-2014; Type Comments: deuren; Type Mark: 354; Type Name: dichte_deur buitenberging; URL: www.bimvoorfabrikanten.nl
Type - Analytical Properties - Define Thermal Properties by: Schematic Type; Analytic Construction: <None>
Type - Pset_DoorCommon - IsExternal: no
Type - Pset_ManufacturerTypeInformation - Manufacturer: ITANNEX
Type - Pset_ProductRequirements - Category: Doors
Type - Pset_Door - Kozijnmerk: 354
Classification: 31.10 Uniformat (Uniformat)
Pset_DoorCommon - Reference: dichte_deur buitenberging
Pset_QuantityTakeOff - Reference: dichte_deur buitenberging
Pset_Door - Description: deur dicht; NL-sfb-Codering: 31.3
Pset_DAT_KMS - Assembly Code: 31.3; Description: deur dicht
Other - offset_bovenkant_a: 0 mm; offset_bovenkant_b: 0 mm; offset_links_a: 0 mm; offset_links_b: 0 mm; offset_onderkant_a: 0 mm; offset_onderkant_b: 0 mm; offset_rechts_a: 0 mm; offset_rechts_b: 0 mm; Family: 31_DO_dichte_deur; offset_b: 0 mm; Family and Type: 31_DO_dichte_deur: dichte_deur buitenberging; offset_a: 1 mm; Type: dichte_deur buitenberging; Type Id: 6486402
Model Properties - diepte_offset_a: -1 mm
Constraints - Level: 0
Fire Protection - WBDBO 20: no; WBDBO 30: no; WBDBO 60: no; Zelfsluitend: no; Firerating_grafisch: 0; Zelfsluitend_grafisch: 0
Graphics - Geen WBDBO of zelfsluitend: yes
Materials and Finishes - paneel_exterieur_materiaal: ISR_Hardhout_gevelbekleding; paneel_interieur_materiaal: ISR_Hardhout_gevelbekleding
Phasing - Phase Created: 2. nieuwbouw
Name (31_DO_dichte_deur:dichte_deur buitenberging:...) | OverallHeight (mm) = BaseQuantities, Height (mm) = HeightReport (mm) = Dimensions, Height (mm) = netto_hoogte (mm) | OverallWidth (mm) = BaseQuantities, Width (mm) = WidthReport (mm) = netto_breedte (mm) = Dimensions, Width (mm) | BaseQuantities, Area (m2) = Dimensions, Area (m2) = paneel_oppervlakte (m2) | Host Id | draairichting_a_type | Volume (m3) | Workset | Mark | Group
6486349 | 1065 | 900.5 | 0.959032 | 6486348 | BU deur rechts | 0.00767226 | situatie | 3562 | Pset_DoorCommon - IsExternal: yes
6486375 | 1065 | 889.5 | 0.947318 | 6486348 | BU deur links | 0.00757854 | situatie | 3566 | Pset_DoorCommon - IsExternal: yes
6495807 | 2050 | 940 | 1.927 | 6495806 | BU deur rechts | 0.015416 | situatie | 2814 | Model Group:bergingdeur:6495812
6495809 | 2050 | 940 | 1.927 | 6495806 | BU deur links | 0.015416 | situatie | 2815 | Model Group:bergingdeur:6495812
6495823 | 2050 | 940 | 1.927 | 6495822 | BU deur rechts | 0.015416 | situatie | 2816 | Model Group:bergingdeur:6495828
6495825 | 2050 | 940 | 1.927 | 6495822 | BU deur links | 0.015416 | situatie | 2817 | Model Group:bergingdeur:6495828
6495927 | 2050 | 940 | 1.927 | 6495926 | BU deur rechts | 0.015416 | situatie | 2828 | Model Group:bergingdeur:6495932
6495929 | 2050 | 940 | 1.927 | 6495926 | BU deur links | 0.015416 | situatie | 2829 | Model Group:bergingdeur:6495932
6495941 | 2050 | 940 | 1.927 | 6495940 | BU deur rechts | 0.015416 | situatie | 2830 | Model Group:bergingdeur:6495946
6495943 | 2050 | 940 | 1.927 | 6495940 | BU deur links | 0.015416 | situatie | 2831 | Model Group:bergingdeur:6495946
6766703 | 1065 | 900.5 | 0.959032 | 6766702 | BU deur rechts | 0.00767226 | Bouwkundig | 2786
6766705 | 1065 | 889.5 | 0.947318 | 6766702 | BU deur links | 0.00757854 | Bouwkundig | 2788

# IfcDoor: 31_DO_dichte_deur:draairichting poort (4)
In: 00 Begane grond
Type - ParameterTakesPrecedence: no; Sizeable: no; Material: ISR_Luchtspouw
Type - Other - Category: Doors; Family Name: 31_DO_dichte_deur
Type - Constraints - Offset: 0 mm; offset_bovenkant: 0 mm; offset_links: 0 mm; offset_onderkant: 0 mm; offset_rechts: 0 mm
Type - Dimensions - Thickness: 50 mm
Type - Identity Data - Workset: Family : Doors : 31_DO_dichte_deur; Assembly Code: 31.3; Description: deur dicht; Manufacturer: ITANNEX; Model: 10-07-2014; Type Comments: deuren; Type Mark: 355; Type Name: draairichting poort; URL: www.bimvoorfabrikanten.nl
Type - Analytical Properties - Define Thermal Properties by: Schematic Type; Analytic Construction: <None>
Type - Pset_DoorCommon - IsExternal: no
Type - Pset_ManufacturerTypeInformation - Manufacturer: ITANNEX
Type - Pset_ProductRequirements - Category: Doors
Type - Pset_Door - Kozijnmerk: 355
OverallHeight: 1500 mm; Classification: 31.10 Uniformat (Uniformat)
Pset_DoorCommon - Reference: draairichting poort
Pset_QuantityTakeOff - Reference: draairichting poort
Pset_Door - Description: deur dicht; NL-sfb-Codering: 31.3
Pset_DAT_KMS - Assembly Code: 31.3; Description: deur dicht
BaseQuantities - Height: 1500 mm
Other - offset_bovenkant_a: 0 mm; offset_bovenkant_b: 0 mm; offset_links_a: 0 mm; offset_links_b: 0 mm; offset_onderkant_a: 0 mm; offset_onderkant_b: 0 mm; offset_rechts_a: 0 mm; offset_rechts_b: 0 mm; Family: 31_DO_dichte_deur; offset_b: 0 mm; Family and Type: 31_DO_dichte_deur: draairichting poort; HeightReport: 1500 mm; offset_a: 0 mm; Type: draairichting poort; Type Id: 6486575
Model Properties - diepte_offset_a: 0 mm
Constraints - Level: 0
Dimensions - Height: 1500 mm; netto_hoogte: 1500 mm
Fire Protection - WBDBO 20: no; WBDBO 30: no; WBDBO 60: no; Zelfsluitend: no; Firerating_grafisch: 0; Zelfsluitend_grafisch: 0
Graphics - Geen WBDBO of zelfsluitend: yes
Identity Data - Workset: situatie
Materials and Finishes - paneel_exterieur_materiaal: ISR_Luchtspouw; paneel_interieur_materiaal: ISR_Luchtspouw
Phasing - Phase Created: 2. nieuwbouw
Name (31_DO_dichte_deur:draairichting poort:...) | OverallWidth (mm) = BaseQuantities, Width (mm) = WidthReport (mm) = netto_breedte (mm) = Dimensions, Width (mm) | BaseQuantities, Area (m2) = Dimensions, Area (m2) = paneel_oppervlakte (m2) | Host Id | draairichting_a_type | Volume (m3) | Mark
6487007 | 1250 | 1.875 | 6487006 | BU deur rechts | 0.046875 | 2791 | Pset_DoorCommon - IsExternal: yes
6487009 | 1250 | 1.875 | 6487006 | BU deur links | 0.046875 | 2792 | Pset_DoorCommon - IsExternal: yes
6487409 | 1740.94 | 2.61141 | 6487408 | BU deur rechts | 0.0652853 | 2797
6487411 | 1740.9 | 2.61135 | 6487408 | BU deur links | 0.0652838 | 2798

# IfcDoor: Aluminium Door_single_glass:Left hinged (3)
Type - ParameterTakesPrecedence: no; Sizeable: no; Material: cibes_RAL_9016, cibes_glass
Type - Other - Category: Doors; Family Name: Aluminium Door_single_glass; Left hinged: yes; Right_hinged: no
Type - Dimensions - clg_handle_side: 105 mm; clg_hinged_side: 105 mm
Type - Identity Data - Type Mark: YD10:DD; Type Name: Left hinged; Workset: Family : Doors : Aluminium Door_single_glass
Type - Analytical Properties - Define Thermal Properties by: Schematic Type; Analytic Construction: <None>
Type - Pset_DoorCommon - IsExternal: no
Type - Pset_ProductRequirements - Category: Doors
Type - Pset_Door - Kozijnmerk: YD10:DD
OverallHeight: 900 mm; OverallWidth: 900 mm
Pset_DoorCommon - Reference: Left hinged
Pset_QuantityTakeOff - Reference: Left hinged
BaseQuantities - Area: 1.02552 m2
Other - Family: Aluminium Door_single_glass; Family and Type: Aluminium Door_single_glass: Left hinged; Type: Left hinged; Type Id: 6207808
Constraints - Moves With Nearby Elements: no; Offset from Host: 0 mm
Dimensions - Area: 1.02552 m2; clg_depth: 50 mm; clg_door_opening: 939 mm; clg_door_sidepanel: 200 mm; clg_glass_offset: 0 mm; clg_height: 2100 mm; clg_width: 900 mm; clg_window_left: 100 mm; clg_window_right: 100 mm; clg_window_sill: 450 mm; Volume: 0.0401561 m3
Identity Data - Workset: Bouwkundig
Materials and Finishes - clg_material_additional: cibes_RAL_9016; clg_material_glass: cibes_glass; clg_material_glass_side: cibes_glass_black; clg_material_main: cibes_RAL_9016
Phasing - Phase Created: 2. nieuwbouw
Name (Aluminium Door_single_glass:Left hinged:...) | In | Host | Mark
6207978 | 00 Begane grond | Floor : 23_Dekvloer 70mm | 2778
6209187 | -1 Speelvloer | <not associated> | 2779
6209444 | 01 eerste verdieping | Level : 1 | 2785

# IfcDoor: NLRS_22_DO_LB_ESP Vetro rail en basiswandlijst:-, NLRS_22_DO_LB_ESP Vetro rail en basiswandlijst:-:5089135
In: 00 Begane grond
Type - ParameterTakesPrecedence: no; Sizeable: no; Material: <Unnamed>, Default(2)
Type - Other - Category: Doors; Family Name: NLRS_22_DO_LB_ESP Vetro rail en basiswandlijst
Type - Dimensions - ESP_aftrekmaat_1: 65 mm; ESP_aftrekmaat_2: 65 mm; Height: 0 mm; NLRS_C_hoogte: 3240 mm; Rough Height: 0 mm; Rough Width: 0 mm; Thickness: 0 mm; Width: 0 mm
Type - Identity Data - Assembly Code: 22.14; Assembly Description: binnenwanden; niet constructief, systeemwanden; verplaatsbaar; Description: Panelenwand; Manufacturer: Espero BV; Model: 2P; Type Comments: Akoestische panelenwand; Type Mark: 348; Type Name: -; URL: www.espero.nl; Workset: Family : Doors : NLRS_22_DO_LB_ESP Vetro rail en basiswandlijst
Type - Text - bouwdeel: 1
Type - Analytical Properties - Analytic Construction: <None>; Define Thermal Properties by: Schematic Type
Type - Pset_DoorCommon - IsExternal: no
Type - Pset_ManufacturerTypeInformation - Manufacturer: Espero BV
Type - Pset_ProductRequirements - Category: Doors
Type - Pset_Door - Kozijnmerk: 348
OverallHeight: 150 mm; OverallWidth: 6450 mm; Classification: 22.14 Uniformat (Uniformat); Group: Model Group:S01:5089124
Pset_DoorCommon - Reference: -
Pset_QuantityTakeOff - Reference: -
Pset_Door - Description: Panelenwand; NL-sfb-Codering: 22.14
Pset_DAT_KMS - Assembly Code: 22.14; Assembly Description: binnenwanden; niet constructief, systeemwanden; verplaatsbaar; Description: Panelenwand
BaseQuantities - Height: 0 mm; Width: 0 mm; Area: 0 m2
Other - Family: NLRS_22_DO_LB_ESP Vetro rail en basiswandlijst; Family and Type: NLRS_22_DO_LB_ESP Vetro rail en basiswandlijst: -; Type: -; Type Id: 5002823
Constraints - Offset from Host: 0 mm; Length: 6450 mm; Work Plane: Level : 0
Construction - ESP_afhanging: yes; ESP_drager: yes
Dimensions - Area: 4.49475 m2; ESP_aantal railplaten: 14; ESP_draadeind links: 70 mm; ESP_draadeind rechts: 70 mm; ESP_h.o.h. afhanging: 450 mm; ESP_hoogte afhanging: 600 mm; NLRS_C_breedte: 6450 mm; Volume: 0.0427333 m3
Graphics - ESP_100x100 hoek: no; ESP_90 graden hoek: yes
Identity Data - Workset: Bouwkundig; Has Association: no; Mark: 2679
Phasing - Phase Created: 2. nieuwbouw

# IfcDoor: NLRS_22_DO_UN_ESP_Vetro:Wand_A_Flexio85_BP met wiel 785 (7)
In: 00 Begane grond
Type - OperationType: REVOLVING; ParameterTakesPrecedence: no; Sizeable: no; Material: Diverse, <Unnamed>, ISR_HPL Kleur hout
Type - NLRS_22_DO_UN_ESP_Vetro:Wand_A_Flexio85_BP met wiel 785:5089136:1 - PanelOperation: REVOLVING
Type - Other - Category: Doors; ESP_deurpaneel: no; ESP_DI_paneel_b.k.: NLRS_22_DI_verticaal : BP_Flexio 85; ESP_DI_paneel_links: NLRS_22_DI_Horizontaal : BP_Flexio 85; ESP_DI_paneel_o.k.: NLRS_22_DI_verticaal : BP_Flexio 85; ESP_DI_paneel_rechts: NLRS_22_DI_Horizontaal : BP_Flexio 85; Family Name: NLRS_22_DO_UN_ESP_Vetro
Type - Constraints - ESP_overstek_if: 451.5 mm; NLRS_C_dikte_if: 86 mm
Type - Construction - ESP_drager_centrisch: yes; ESP_overstek: 65 mm
Type - Dimensions - ESP_breedte_KP: 853 mm; ESP_dikte_aftrekmaat afwerking: 0 mm; ESP_sparing_bovenkant: 0 mm; ESP_sparing_dikte: 3 mm; ESP_sparing_links: 0 mm; ESP_sparing_onderkant: 0 mm; ESP_sparing_rechts: 0 mm; Height: 3210 mm; Length: 700 mm; NLRS_C_breedte: 903 mm; NLRS_C_dikte: 86 mm; NLRS_C_hoogte: 3210 mm; Rough Height: 3210 mm; Rough Width: 903 mm; Thickness: 86 mm; Width: 903 mm
Type - Graphics - ESP_draairichting: no; ESP_glasopening: no; ESP_sluitpaneel: no
Type - Identity Data - Assembly Code: 22.14; Assembly Description: binnenwanden; niet constructief, systeemwanden; verplaatsbaar; Description: Basispaneel; Manufacturer: ESPERO B.V.; Model: BP; NLRS_C_leverancier_bedrijfsnaam: ESPERO B.V.; NLRS_C_leverancier_email: info@espero.nl; NLRS_C_leverancier_telefoonnummer: +31 (0)416 33 89 55; NLRS_C_leverancier_URL: www.espero.nl; Type Mark: 356; Type Name: Wand_A_Flexio85_BP met wiel 785; Workset: Family : Doors : NLRS_22_DO_UN_ESP_Vetro
Type - Materials and Finishes - NLRS_C_materiaal_01: ISR_HPL Kleur hout; NLRS_C_materiaal_02: ISR_HPL Kleur hout
Type - Text - ESP_taal_Engels: no; ESP_taal_Nederland: yes; NLRS_C_omschrijving: Wand profiel
Type - Visibility - ESP_Wiel: yes
Type - Analytical Properties - Define Thermal Properties by: Schematic Type; Analytic Construction: <None>
Type - Pset_DoorCommon - IsExternal: no
Type - Pset_ManufacturerTypeInformation - Manufacturer: ESPERO B.V.
Type - Pset_ProductRequirements - Category: Doors
Type - Pset_Door - Kozijnmerk: 356
OverallHeight: 989.25 mm; OverallWidth: 1217.53 mm; Classification: 22.14 Uniformat (Uniformat); Group: Model Group:S01:5089124
Pset_DoorCommon - Reference: Wand_A_Flexio85_BP met wiel 785
Pset_QuantityTakeOff - Reference: Wand_A_Flexio85_BP met wiel 785
Pset_Door - Description: Basispaneel; NL-sfb-Codering: 22.14
Pset_DAT_KMS - Assembly Code: 22.14; Assembly Description: binnenwanden; niet constructief, systeemwanden; verplaatsbaar; Description: Basispaneel
BaseQuantities - Height: 3210 mm; Width: 903 mm; Area: 2.89863 m2
Other - Family: NLRS_22_DO_UN_ESP_Vetro; Family and Type: NLRS_22_DO_UN_ESP_Vetro: Wand_A_Flexio85_BP met wiel 785; Type: Wand_A_Flexio85_BP met wiel 785; Type Id: 5002825
Constraints - Level: 0; Moves With Nearby Elements: no; Offset from Host: 0 mm; ESP_glasopening_if: no; Host: Level : 0
Construction - ESP_drager_zichtbaar: yes
Dimensions - Area: 1.20492 m2; Volume: 0.0384813 m3
Graphics - ESP_gestippeld: no; ESP_getekend: yes; ESP_Rozet: yes
Identity Data - Workset: Bouwkundig
Phasing - Phase Created: 2. nieuwbouw
Name (NLRS_22_DO_UN_ESP_Vetro:Wand_A_Flexio85_BP met wiel 785:...) | Mark
5089136 | 2749
5089137 | 2755
5089138 | 2757
5089139 | 2758
5089140 | 2763
5089141 | 2764
6714295 | 2680

# IfcFlowTerminal: 63_DAT_Spotverlichting layout:2 Spots (25)
Type - Material: <Unnamed>
Type - Other - Category: Lighting Fixtures; Family Name: 63_DAT_Spotverlichting layout; Midden: no
Type - Constraints - Default Elevation: 0 mm
Type - Dimensions - Maat vanaf muur: 700 mm; Plafondhoogte: 3240 mm
Type - Identity Data - Type Name: 2 Spots; Workset: Family : Lighting Fixtures : 63_DAT_Spotverlichting layout
Type - Pset_ProductRequirements - Category: Lighting Fixtures
Pset_DistributionFlowElementCommon - Reference: 2 Spots; sets with these values: 2
Other - Family: 63_DAT_Spotverlichting layout; Family and Type: 63_DAT_Spotverlichting layout: 2 Spots; Type: 2 Spots; Type Id: 5352061
Constraints - Elevation from Level: 0 mm; Moves With Nearby Elements: no; Offset from Host: 0 mm
Dimensions - Area: 0.0942446 m2; Lengte: 3292.5 mm; Volume: 0.00353412 m3
Electrical - Lighting - Calculate Coefficient of Utilization: no
Identity Data - Workset: Bouwkundig
Phasing - Phase Created: 2. nieuwbouw
Name (63_DAT_Spotverlichting layout:2 Spots:...) | In | Level | Host
5352217 | 00 Begane grond | 0 | Floor : 23_Dekvloer 70mm | Group: Model Group:Verlichtingsplan gang BG1:5347695
5352870 | 00 Begane grond | 0 | Floor : 23_Dekvloer 70mm | Group: Model Group:Verlichtingsplan gang BG1:5347695
5353417 | 00 Begane grond | 0 | Floor : 23_Dekvloer 70mm | Group: Model Group:Verlichtingsplan gang BG1:5347695
5353513 | 00 Begane grond | 0 | Floor : 23_Dekvloer 70mm | Group: Model Group:Verlichtingsplan gang BG1:5347695
5353573 | 00 Begane grond | 0 | Floor : 23_Dekvloer 70mm | Group: Model Group:Verlichtingsplan gang BG1:5347695
5355435 | 00 Begane grond | 0 | Floor : 23_Dekvloer 70mm
5379943 | 01 eerste verdieping | 1 | Floor : 23_Zwevende dekvloer 90mm
5380038 | 01 eerste verdieping | 1 | Floor : 23_Zwevende dekvloer 90mm
5380075 | 01 eerste verdieping | 1 | Floor : 23_Zwevende dekvloer 90mm
5380145 | 01 eerste verdieping | 1 | Floor : 23_Zwevende dekvloer 90mm
5380180 | 01 eerste verdieping | 1 | Floor : 23_Zwevende dekvloer 90mm
5380217 | 01 eerste verdieping | 1 | Floor : 23_Zwevende dekvloer 90mm
5380254 | 01 eerste verdieping | 1 | Floor : 23_Zwevende dekvloer 90mm
5380541 | 01 eerste verdieping | 1 | Floor : 23_Zwevende dekvloer 90mm
5380615 | 01 eerste verdieping | 1 | Floor : 23_Zwevende dekvloer 90mm
5411449 | 01 eerste verdieping | 1 | Floor : 23_Zwevende dekvloer 90mm
5411450 | 01 eerste verdieping | 1 | Floor : 23_Zwevende dekvloer 90mm
5411451 | 01 eerste verdieping | 1 | Floor : 23_Zwevende dekvloer 90mm
5411452 | 01 eerste verdieping | 1 | Floor : 23_Zwevende dekvloer 90mm
5411453 | 01 eerste verdieping | 1 | Floor : 23_Zwevende dekvloer 90mm
5411501 | 01 eerste verdieping | 1 | Floor : 23_Zwevende dekvloer 90mm | Group: Model Group:Verlichtingsplan gang 2:5347818
5411502 | 01 eerste verdieping | 1 | Floor : 23_Zwevende dekvloer 90mm | Group: Model Group:Verlichtingsplan gang 2:5347818
5411503 | 01 eerste verdieping | 1 | Floor : 23_Zwevende dekvloer 90mm | Group: Model Group:Verlichtingsplan gang 2:5347818
5411504 | 01 eerste verdieping | 1 | Floor : 23_Zwevende dekvloer 90mm | Group: Model Group:Verlichtingsplan gang 2:5347818
5411505 | 01 eerste verdieping | 1 | Floor : 23_Zwevende dekvloer 90mm | Group: Model Group:Verlichtingsplan gang 2:5347818

# IfcFlowTerminal: 63_DAT_Spotverlichting layout:2 Spots 2, 63_DAT_Spotverlichting layout:2 Spots 2:5379980
In: 01 eerste verdieping
Type - Material: <Unnamed>
Type - Other - Category: Lighting Fixtures; Midden: no; Family Name: 63_DAT_Spotverlichting layout
Type - Constraints - Default Elevation: 0 mm
Type - Dimensions - Maat vanaf muur: 700 mm; Plafondhoogte: 3240 mm
Type - Identity Data - Workset: Family : Lighting Fixtures : 63_DAT_Spotverlichting layout; Type Name: 2 Spots 2
Type - Pset_ProductRequirements - Category: Lighting Fixtures
Pset_DistributionFlowElementCommon - Reference: 2 Spots 2; sets with these values: 2
Other - Family: 63_DAT_Spotverlichting layout; Family and Type: 63_DAT_Spotverlichting layout: 2 Spots 2; Type: 2 Spots 2; Type Id: 5412546
Constraints - Elevation from Level: 0 mm; Moves With Nearby Elements: no; Offset from Host: 0 mm; Level: 1; Host: Floor : 23_Zwevende dekvloer 90mm
Dimensions - Area: 0.0942446 m2; Lengte: 3292.5 mm; Volume: 0.00353412 m3
Electrical - Lighting - Calculate Coefficient of Utilization: no
Identity Data - Workset: Bouwkundig
Phasing - Phase Created: 2. nieuwbouw

# IfcFlowTerminal: 63_DAT_Spotverlichting layout:2400 (8)
In: 00 Begane grond
Type - Material: <Unnamed>
Type - Other - Category: Lighting Fixtures; Midden: no; Family Name: 63_DAT_Spotverlichting layout
Type - Constraints - Default Elevation: 0 mm
Type - Dimensions - Maat vanaf muur: 500 mm; Plafondhoogte: 3240 mm
Type - Identity Data - Workset: Family : Lighting Fixtures : 63_DAT_Spotverlichting layout; Type Name: 2400
Type - Pset_ProductRequirements - Category: Lighting Fixtures
Pset_DistributionFlowElementCommon - Reference: 2400; sets with these values: 2
Other - Family: 63_DAT_Spotverlichting layout; Type: 2400; Family and Type: 63_DAT_Spotverlichting layout: 2400; Type Id: 5361337
Constraints - Elevation from Level: 0 mm; Level: 0; Moves With Nearby Elements: no; Offset from Host: 0 mm; Host: Level : 0
Dimensions - Area: 0.0942446 m2; Lengte: 3670 mm; Volume: 0.00353412 m3
Electrical - Lighting - Calculate Coefficient of Utilization: no
Identity Data - Workset: Bouwkundig
Phasing - Phase Created: 2. nieuwbouw
Name (63_DAT_Spotverlichting layout:2400:...)
5361152
5361415
5361648
5361693
5372456
5372457
5372458
5372459

# IfcFlowTerminal: 63_DAT_TL Bak met kabelgoot:63_DAT_TL Bak met kabelgoot (50)
Type - Material: <Unnamed>
Type - Other - Category: Lighting Fixtures; Family Name: 63_DAT_TL Bak met kabelgoot; Tl Bak: yes
Type - Constraints - Default Elevation: 0 mm
Type - Dimensions - Breedte Kabelgoot: 240 mm; Hoogte: 2800 mm; Hoogte kabelgoot: 50.3009 mm
Type - Identity Data - Type Name: 63_DAT_TL Bak met kabelgoot; Workset: Family : Lighting Fixtures : 63_DAT_TL Bak met kabelgoot
Type - Pset_ProductRequirements - Category: Lighting Fixtures
Pset_DistributionFlowElementCommon - Reference: 63_DAT_TL Bak met kabelgoot; sets with these values: 2
Other - Family: 63_DAT_TL Bak met kabelgoot; Family and Type: 63_DAT_TL Bak met kabelgoot: 63_DAT_TL Bak met kabelgoot; Type: 63_DAT_TL Bak met kabelgoot; Type Id: 5338772
Constraints - Moves With Nearby Elements: no
Electrical - Lighting - Calculate Coefficient of Utilization: no
Phasing - Phase Created: 2. nieuwbouw
Name (63_DAT_TL Bak met kabelgoot:63_DAT_TL Bak met kabelgoot:...) | In | Elevation from Level (mm) | Level | Offset from Host (mm) | Host | Area (m2) | Lengte (mm) | Volume (m3) | Workset | Group
5339303 | 00 Begane grond | 0 | 0 | 0 | Floor : 23_Dekvloer 70mm | 2.87233 | 6597.5 | 0.116246 | installatie | Model Group:Verlichtingsplan lokaal:5339618
5339569 | 00 Begane grond | 0 | 0 | 0 | Floor : 23_Dekvloer 70mm | 2.87233 | 6597.5 | 0.116246 | installatie | Model Group:Verlichtingsplan lokaal:5339618
5339706 | 00 Begane grond | 0 | 0 | 0 | Floor : 23_Dekvloer 70mm | 2.87233 | 6597.5 | 0.116246 | installatie | Model Group:Verlichtingsplan lokaal:5339709
5339708 | 00 Begane grond | 0 | 0 | 0 | Floor : 23_Dekvloer 70mm | 2.87233 | 6597.5 | 0.116246 | installatie | Model Group:Verlichtingsplan lokaal:5339709
5339742 | 00 Begane grond | 0 | 0 | 0 | Floor : 23_Dekvloer 70mm | 2.87233 | 6597.5 | 0.116246 | installatie | Model Group:Verlichtingsplan lokaal:5339745
5339744 | 00 Begane grond | 0 | 0 | 0 | Floor : 23_Dekvloer 70mm | 2.87233 | 6597.5 | 0.116246 | installatie | Model Group:Verlichtingsplan lokaal:5339745
5339779 | 00 Begane grond | 0 | 0 | 0 | Floor : 23_Dekvloer 70mm | 2.75258 | 6185 | 0.111267 | Bouwkundig | Model Group:Verlichtingsplan lokaal 3:5347561
5344241 | 00 Begane grond | 0 | 0 | 0 | Floor : 23_Dekvloer 70mm | 2.75258 | 6185 | 0.111267 | Bouwkundig | Model Group:Verlichtingsplan lokaal 3:5347561
5344625 | 00 Begane grond | -30 | 0 | -30 | Floor : 23_Dekvloer 70mm | 3.01821 | 7100 | 0.122313 | Bouwkundig | Model Group:Verlichtingsplan lokaal 2:5344628
5344627 | 00 Begane grond | -30 | 0 | -30 | Floor : 23_Dekvloer 70mm | 3.01821 | 7100 | 0.122313 | Bouwkundig | Model Group:Verlichtingsplan lokaal 2:5344628
5344949 | 00 Begane grond | -30 | 0 | -30 | Floor : 23_Dekvloer 70mm | 3.01821 | 7100 | 0.122313 | Bouwkundig | Model Group:Verlichtingsplan lokaal 2:5344952
5344951 | 00 Begane grond | -30 | 0 | -30 | Floor : 23_Dekvloer 70mm | 3.01821 | 7100 | 0.122313 | Bouwkundig | Model Group:Verlichtingsplan lokaal 2:5344952
5344991 | 00 Begane grond | -30 | 0 | -30 | Floor : 23_Dekvloer 70mm | 3.01821 | 7100 | 0.122313 | Bouwkundig | Model Group:Verlichtingsplan lokaal 2:5344994
5344993 | 00 Begane grond | -30 | 0 | -30 | Floor : 23_Dekvloer 70mm | 3.01821 | 7100 | 0.122313 | Bouwkundig | Model Group:Verlichtingsplan lokaal 2:5344994
5347172 | 01 eerste verdieping | 0 | 1 | 0 | Floor : 23_Zwevende dekvloer 90mm | 2.87233 | 6597.5 | 0.116246 | installatie | Model Group:Verlichtingsplan lokaal:5347175
5347174 | 01 eerste verdieping | 0 | 1 | 0 | Floor : 23_Zwevende dekvloer 90mm | 2.87233 | 6597.5 | 0.116246 | installatie | Model Group:Verlichtingsplan lokaal:5347175
5347229 | 01 eerste verdieping | 0 | 1 | 0 | Floor : 23_Zwevende dekvloer 90mm | 2.87233 | 6597.5 | 0.116246 | installatie | Model Group:Verlichtingsplan lokaal:5347232
5347231 | 01 eerste verdieping | 0 | 1 | 0 | Floor : 23_Zwevende dekvloer 90mm | 2.87233 | 6597.5 | 0.116246 | installatie | Model Group:Verlichtingsplan lokaal:5347232
5347241 | 01 eerste verdieping | 0 | 1 | 0 | Floor : 23_Zwevende dekvloer 90mm | 2.87233 | 6597.5 | 0.116246 | installatie | Model Group:Verlichtingsplan lokaal:5347244
5347243 | 01 eerste verdieping | 0 | 1 | 0 | Floor : 23_Zwevende dekvloer 90mm | 2.87233 | 6597.5 | 0.116246 | installatie | Model Group:Verlichtingsplan lokaal:5347244
5347313 | 01 eerste verdieping | 0 | 1 | 0 | Level : 1 | 2.87233 | 6597.5 | 0.116246 | Bouwkundig
5347426 | 01 eerste verdieping | 0 | 1 | 0 | Floor : 23_Zwevende dekvloer 90mm | 2.87233 | 6597.5 | 0.116246 | installatie | Model Group:Verlichtingsplan lokaal:5347429
5347428 | 01 eerste verdieping | 0 | 1 | 0 | Floor : 23_Zwevende dekvloer 90mm | 2.87233 | 6597.5 | 0.116246 | installatie | Model Group:Verlichtingsplan lokaal:5347429
5347499 | 01 eerste verdieping | 0 | 1 | 0 | Floor : 23_Zwevende dekvloer 90mm | 2.87233 | 6597.5 | 0.116246 | installatie | Model Group:Verlichtingsplan lokaal:5347502
5347501 | 01 eerste verdieping | 0 | 1 | 0 | Floor : 23_Zwevende dekvloer 90mm | 2.87233 | 6597.5 | 0.116246 | installatie | Model Group:Verlichtingsplan lokaal:5347502
5347538 | 01 eerste verdieping | 0 | 1 | 0 | Floor : 23_Zwevende dekvloer 90mm | 2.87233 | 6597.5 | 0.116246 | installatie | Model Group:Verlichtingsplan lokaal:5347541
5347540 | 01 eerste verdieping | 0 | 1 | 0 | Floor : 23_Zwevende dekvloer 90mm | 2.87233 | 6597.5 | 0.116246 | installatie | Model Group:Verlichtingsplan lokaal:5347541
5347653 | 01 eerste verdieping | 0 | 1 | 0 | Floor : 23_Zwevende dekvloer 90mm | 2.75258 | 6185 | 0.111267 | Bouwkundig | Model Group:Verlichtingsplan lokaal 3:5347665
5347657 | 01 eerste verdieping | 0 | 1 | 0 | Floor : 23_Zwevende dekvloer 90mm | 2.75258 | 6185 | 0.111267 | Bouwkundig | Model Group:Verlichtingsplan lokaal 3:5347665
5373593 | 00 Begane grond | 0 | 0 | 0 | Floor : 23_Dekvloer 70mm | 2.75258 | 6185 | 0.111267 | Bouwkundig | Model Group:Verlichtingsplan lokaal 3:5347561
5373736 | 01 eerste verdieping | 0 | 1 | 0 | Floor : 23_Zwevende dekvloer 90mm | 2.75258 | 6185 | 0.111267 | Bouwkundig | Model Group:Verlichtingsplan lokaal 3:5347665
5374067 | 00 Begane grond | 0 | 0 | 0 | Floor : 23_Dekvloer 70mm | 2.87233 | 6597.5 | 0.116246 | installatie | Model Group:Verlichtingsplan lokaal:5339745
5374583 | 00 Begane grond | 0 | 0 | 0 | Floor : 23_Dekvloer 70mm | 2.87233 | 6597.5 | 0.116246 | installatie | Model Group:Verlichtingsplan lokaal:5339618
5374635 | 00 Begane grond | 0 | 0 | 0 | Floor : 23_Dekvloer 70mm | 2.87233 | 6597.5 | 0.116246 | installatie | Model Group:Verlichtingsplan lokaal:5339709
5374687 | 01 eerste verdieping | 0 | 1 | 0 | Floor : 23_Zwevende dekvloer 90mm | 2.87233 | 6597.5 | 0.116246 | installatie | Model Group:Verlichtingsplan lokaal:5347175
5374714 | 01 eerste verdieping | 0 | 1 | 0 | Floor : 23_Zwevende dekvloer 90mm | 2.87233 | 6597.5 | 0.116246 | installatie | Model Group:Verlichtingsplan lokaal:5347232
5374741 | 01 eerste verdieping | 0 | 1 | 0 | Floor : 23_Zwevende dekvloer 90mm | 2.87233 | 6597.5 | 0.116246 | installatie | Model Group:Verlichtingsplan lokaal:5347244
5374795 | 01 eerste verdieping | 0 | 1 | 0 | Floor : 23_Zwevende dekvloer 90mm | 2.87233 | 6597.5 | 0.116246 | installatie | Model Group:Verlichtingsplan lokaal:5347429
5374821 | 01 eerste verdieping | 0 | 1 | 0 | Floor : 23_Zwevende dekvloer 90mm | 2.87233 | 6597.5 | 0.116246 | installatie | Model Group:Verlichtingsplan lokaal:5347502
5374847 | 01 eerste verdieping | 0 | 1 | 0 | Floor : 23_Zwevende dekvloer 90mm | 2.87233 | 6597.5 | 0.116246 | installatie | Model Group:Verlichtingsplan lokaal:5347541
5375706 | 00 Begane grond | -30 | 0 | -30 | Floor : 23_Dekvloer 70mm | 3.01821 | 7100 | 0.122313 | Bouwkundig | Model Group:Verlichtingsplan lokaal 2:5344628
5375884 | 00 Begane grond | -30 | 0 | -30 | Floor : 23_Dekvloer 70mm | 3.01821 | 7100 | 0.122313 | Bouwkundig | Model Group:Verlichtingsplan lokaal 2:5344952
5375910 | 00 Begane grond | -30 | 0 | -30 | Floor : 23_Dekvloer 70mm | 3.01821 | 7100 | 0.122313 | Bouwkundig | Model Group:Verlichtingsplan lokaal 2:5344994
5376134 | 0.28 | -60 | 0 | -30 | Toposolid : Toposolid 1 | 2.85853 | 6549.96 | 0.115673 | Bouwkundig | Model Group:Verlichtingsplan lokaal 4:5376136
5376756 | 00 Begane grond | -30 | 0 | -30 | Floor : 23_Dekvloer 70mm | 2.85853 | 6549.96 | 0.115673 | Bouwkundig | Model Group:Verlichtingsplan lokaal 4:5376136
5376860 | 00 Begane grond | -30 | 0 | -30 | Floor : 23_Dekvloer 70mm | 2.85853 | 6549.96 | 0.115673 | Bouwkundig | Model Group:Verlichtingsplan lokaal 4:5376136
6223563 | 01 eerste verdieping | 0 | 1 | 0 | Floor : 23_Zwevende dekvloer 90mm | 2.87233 | 6597.5 | 0.116246 | Bouwkundig
6223564 | 01 eerste verdieping | 0 | 1 | 0 | Floor : 23_Zwevende dekvloer 90mm | 2.87233 | 6597.5 | 0.116246 | Bouwkundig
6223566 | 01 eerste verdieping | 0 | 1 | 0 | Floor : 23_Zwevende dekvloer 90mm | 2.87233 | 6597.5 | 0.116246 | Bouwkundig
6223977 | 01 eerste verdieping | 0 | 1 | 0 | Level : 1 | 2.87233 | 6597.5 | 0.116246 | Bouwkundig

# IfcFlowTerminal: 63_DAT_TL Bak met kabelgoot:Kabelgoot (6)
Type - Material: <Unnamed>
Type - Other - Category: Lighting Fixtures; Family Name: 63_DAT_TL Bak met kabelgoot; Tl Bak: no
Type - Constraints - Default Elevation: 0 mm
Type - Dimensions - Breedte Kabelgoot: 240 mm; Hoogte: 2800 mm; Hoogte kabelgoot: 50.3009 mm
Type - Identity Data - Workset: Family : Lighting Fixtures : 63_DAT_TL Bak met kabelgoot; Type Name: Kabelgoot
Type - Pset_ProductRequirements - Category: Lighting Fixtures
Pset_DistributionFlowElementCommon - Reference: Kabelgoot; sets with these values: 2
Other - Family: 63_DAT_TL Bak met kabelgoot; Family and Type: 63_DAT_TL Bak met kabelgoot: Kabelgoot; Type: Kabelgoot; Type Id: 5341885
Constraints - Elevation from Level: 0 mm; Moves With Nearby Elements: no; Offset from Host: 0 mm
Dimensions - Area: 2.10812 m2; Lengte: 3965 mm; Volume: 0.0844663 m3
Electrical - Lighting - Calculate Coefficient of Utilization: no
Identity Data - Workset: Bouwkundig
Phasing - Phase Created: 2. nieuwbouw
Name (63_DAT_TL Bak met kabelgoot:Kabelgoot:...) | In | Level | Host | Group
5341804 | 00 Begane grond | 0 | Level : 0 | Model Group:Verlichtingsplan lokaal 3:5347561
5344242 | 00 Begane grond | 0 | Level : 0 | Model Group:Verlichtingsplan lokaal 3:5347561
5347654 | 01 eerste verdieping | 1 | Level : 1 | Model Group:Verlichtingsplan lokaal 3:5347665
5347658 | 01 eerste verdieping | 1 | Level : 1 | Model Group:Verlichtingsplan lokaal 3:5347665
5373594 | 00 Begane grond | 0 | Level : 0 | Model Group:Verlichtingsplan lokaal 3:5347561
5373737 | 01 eerste verdieping | 1 | Level : 1 | Model Group:Verlichtingsplan lokaal 3:5347665

# IfcFlowTerminal: 63_DAT_TL Bak:63_DAT_TL Bak (12)
Type - Material: <Unnamed>
Type - Other - Category: Lighting Fixtures; Family Name: 63_DAT_TL Bak
Type - Constraints - Default Elevation: 0 mm
Type - Dimensions - Breedte: 200 mm; Lengte: 1220 mm
Type - Identity Data - Type Name: 63_DAT_TL Bak; Workset: Family : Lighting Fixtures : 63_DAT_TL Bak
Type - Pset_ProductRequirements - Category: Lighting Fixtures
Pset_DistributionFlowElementCommon - Reference: 63_DAT_TL Bak; sets with these values: 2
Other - Family: 63_DAT_TL Bak; Family and Type: 63_DAT_TL Bak: 63_DAT_TL Bak; Type: 63_DAT_TL Bak; Type Id: 5342791
Constraints - Moves With Nearby Elements: no; Elevation from Level: 2502.34 mm; Offset from Host: 2502.34 mm
Dimensions - Area: 0.315 m2; Volume: 0.0122 m3
Electrical - Lighting - Calculate Coefficient of Utilization: no
Identity Data - Workset: Bouwkundig
Phasing - Phase Created: 2. nieuwbouw
Name (63_DAT_TL Bak:63_DAT_TL Bak:...) | In | Level | Host | Group
5343333 | 0.38 | 0 | Level : 0 | Model Group:Verlichtingsplan lokaal 3:5347561
5344090 | 0.38 | 0 | Level : 0 | Model Group:Verlichtingsplan lokaal 3:5347561
5344243 | 0.38 | 0 | Level : 0 | Model Group:Verlichtingsplan lokaal 3:5347561
5344244 | 0.38 | 0 | Level : 0 | Model Group:Verlichtingsplan lokaal 3:5347561
5347655 | 1.24 | 1 | Level : 1 | Model Group:Verlichtingsplan lokaal 3:5347665
5347656 | 1.24 | 1 | Level : 1 | Model Group:Verlichtingsplan lokaal 3:5347665
5347659 | 1.24 | 1 | Level : 1 | Model Group:Verlichtingsplan lokaal 3:5347665
5347660 | 1.24 | 1 | Level : 1 | Model Group:Verlichtingsplan lokaal 3:5347665
5373595 | 0.38 | 0 | Level : 0 | Model Group:Verlichtingsplan lokaal 3:5347561
5373596 | 0.38 | 0 | Level : 0 | Model Group:Verlichtingsplan lokaal 3:5347561
5373738 | 1.24 | 1 | Level : 1 | Model Group:Verlichtingsplan lokaal 3:5347665
5373739 | 1.24 | 1 | Level : 1 | Model Group:Verlichtingsplan lokaal 3:5347665

# IfcFlowTerminal: 74_DAT_PF_Sphinx300_kindertoilet:74_DAT_PF_Sphinx300_kindertoilet (3)
Type - Material: <Unnamed>
Type - Other - Category: Plumbing Fixtures; artikelnummer: S8203205000; BCB WUID: AgAAAGNe6wABAAAAZX8BAAWkQwAAy3AAAD4vAACodwEA2IEBAAAA; Family Name: 74_DAT_PF_Sphinx300_kindertoilet; IFCClass: IFCFLOWTERMINAL; IFCExportAs: IFCFLOWTERMINAL; kleur: wit; merk: Sphinx; NLRS_C_zichtbaar_01: no; NL-SfB tabel 1: 74.11; NL-SfB tabel 3: g3; serie: 300 Kids; uitvoering: zonder gaten
Type - Constraints - Default Elevation: 0 mm
Type - Dimensions - breedte: 330 mm; diepte: 535 mm; hoogte: 335 mm
Type - Identity Data - OmniClass Number: 23.45.00.00; OmniClass Title: Sanitary, Laundry, and Cleaning Equipment; Type Name: 74_DAT_PF_Sphinx300_kindertoilet; Workset: Family : Plumbing Fixtures : 74_DAT_PF_Sphinx300_kindertoilet
Type - Pset_ProductRequirements - Category: Plumbing Fixtures
Pset_DistributionFlowElementCommon - Reference: 74_DAT_PF_Sphinx300_kindertoilet; sets with these values: 2
Other - Family: 74_DAT_PF_Sphinx300_kindertoilet; Family and Type: 74_DAT_PF_Sphinx300_kindertoilet: 74_DAT_PF_Sphinx300_kindertoilet; Type: 74_DAT_PF_Sphinx300_kindertoilet; Type Id: 5132973
Constraints - Level: 0; Elevation from Level: 420 mm; Host: Level : 0; Offset from Host: 420 mm
Dimensions - Area: 0.562636 m2; Volume: 0.0354004 m3
Identity Data - Workset: Bouwkundig
Mechanical - System Classification: Sanitary,Domestic Cold Water
Phasing - Phase Created: 2. nieuwbouw
Name (74_DAT_PF_Sphinx300_kindertoilet:74_DAT_PF_Sphinx300_kindertoilet:...) | In | Mark
5135296 | 0.04 | 39
5135341 | 0.04 | 40
5136225 | 0.08 | 43

# IfcFlowTerminal: 74_DAT_fonteintje:74_DAT_fonteintje (3)
Type - Material: <Unnamed>
Type - Other - Category: Plumbing Fixtures; artikelnummer: S8400100000; BCB WUID: AgAAANNAKAEBAAAA1RUAAAWkQwAAr2UAAK8wAAB0vwAAhYEBAAAA; Family Name: 74_DAT_fonteintje; IFCClass: IFCFLOWTERMINAL; IFCExportAs: IFCFLOWTERMINAL; kleur: wit; kraangat: rechts; merk: Sphinx; NL-SfB tabel 1: 74.11; NL-SfB tabel 3: g3; serie: 300 Basic; type: afgerond, kuip afgerond; uitvoering: 36 met kraangat en overloop
Type - Constraints - Default Elevation: 0 mm
Type - Dimensions - breedte: 360 mm; diepte: 250 mm; hoogte: 138 mm
Type - Identity Data - Assembly Code: 74; Assembly Description: vaste sanitaire voorzieningen; Description: Fonteintje; OmniClass Number: 23.45.00.00; OmniClass Title: Sanitary, Laundry, and Cleaning Equipment; Type Name: 74_DAT_fonteintje; Workset: Family : Plumbing Fixtures : 74_DAT_fonteintje
Type - Pset_ProductRequirements - Category: Plumbing Fixtures
Classification: 74 Uniformat (Uniformat)
Pset_DistributionFlowElementCommon - Reference: 74_DAT_fonteintje; sets with these values: 2
Pset_DAT_KMS - Assembly Code: 74; Assembly Description: vaste sanitaire voorzieningen; Description: Fonteintje
Other - Family: 74_DAT_fonteintje; Family and Type: 74_DAT_fonteintje: 74_DAT_fonteintje; Type: 74_DAT_fonteintje; Type Id: 4334299
Constraints - Elevation from Level: 800 mm; Offset from Host: 800 mm
Dimensions - Area: 0.15302 m2; Volume: 0.00490432 m3
Identity Data - Workset: Bouwkundig
Mechanical - System Classification: Sanitary
Phasing - Phase Created: 2. nieuwbouw
Name (74_DAT_fonteintje:74_DAT_fonteintje:...) | In | Level | Host | Mark
5158567 | 0.46 | 0 | Level : 0 | 50
5158645 | 0.12 | 0 | Level : 0 | 51
5178997 | 1.18 | 1 | Level : 1 | 72

# IfcFlowTerminal: 74_DAT_toiletpot zwevend:74_DAT_toiletpot zwevend (18)
Type - Material: <Unnamed>
Type - Other - Category: Plumbing Fixtures; artikelnummer: S8200100000; BCB WUID: AgAAALYs0QABAAAAsAAAAAWkQwAAy3AAAKmKAAB0vwAAntcAAAAA; Family Name: 74_DAT_toiletpot zwevend; IFCClass: IFCFLOWTERMINAL; IFCExportAs: IFCFLOWTERMINAL; kleur: wit; merk: Sphinx; NL-SfB tabel 1: 74.11; NL-SfB tabel 3: g3; serie: 300 Basic; type: 22
Type - Constraints - Default Elevation: 0 mm
Type - Dimensions - breedte: 355 mm; diepte: 530 mm; hoogte: 378 mm
Type - Identity Data - Assembly Code: 74; Assembly Description: vaste sanitaire voorzieningen; Description: Hangende toiletpot; OmniClass Number: 23.45.00.00; OmniClass Title: Sanitary, Laundry, and Cleaning Equipment; Type Name: 74_DAT_toiletpot zwevend; Workset: Family : Plumbing Fixtures : 74_DAT_toiletpot zwevend
Type - Pset_ProductRequirements - Category: Plumbing Fixtures
Classification: 74 Uniformat (Uniformat)
Pset_DistributionFlowElementCommon - Reference: 74_DAT_toiletpot zwevend; sets with these values: 2
Pset_DAT_KMS - Assembly Code: 74; Assembly Description: vaste sanitaire voorzieningen; Description: Hangende toiletpot
Other - Family: 74_DAT_toiletpot zwevend; Family and Type: 74_DAT_toiletpot zwevend: 74_DAT_toiletpot zwevend; Type: 74_DAT_toiletpot zwevend; Type Id: 4334295
Constraints - Elevation from Level: 420 mm; Offset from Host: 420 mm
Dimensions - Area: 0.490268 m2; Volume: 0.0579985 m3
Identity Data - Workset: Bouwkundig
Mechanical - System Classification: Sanitary
Phasing - Phase Created: 2. nieuwbouw
Name (74_DAT_toiletpot zwevend:74_DAT_toiletpot zwevend:...) | In | Level | Host | Mark | Group
4977532 | 0.43 | 0 | Level : 0 | 15 | Model Group:WC_V0:4976980
4977533 | 0.43 | 0 | Level : 0 | 16 | Model Group:WC_V0:4976980
4977711 | 0.42 | 0 | Level : 0 | 17 | Model Group:WC_V0:4977293
4977712 | 0.42 | 0 | Level : 0 | 18 | Model Group:WC_V0:4977293
4977722 | 0.41 | 0 | Level : 0 | 19 | Model Group:WC_V0:4977398
4977723 | 0.41 | 0 | Level : 0 | 20 | Model Group:WC_V0:4977398
5000930 | 0.12 | 0 | Level : 0 | 22
5035663 | 1.27 | 1 | Level : 1 | 23 | Model Group:WC_V0:5035649
5035664 | 1.27 | 1 | Level : 1 | 24 | Model Group:WC_V0:5035649
5035681 | 1.25 | 1 | Level : 1 | 27 | Model Group:WC_V0:5035659
5035682 | 1.25 | 1 | Level : 1 | 28 | Model Group:WC_V0:5035659
5136282 | 0.08 | 0 | Level : 0 | 44
5174541 | 1.08 | 1 | Level : 1 | 65
5174542 | 1.08 | 1 | Level : 1 | 66
5178714 | 1.18 | 1 | Floor : 23_Zwevende dekvloer 90mm | 71
5994916 | 1.06 | 1 | Level : 1 | 74 | Model Group:WC_V0:5994912
5994917 | 1.06 | 1 | Level : 1 | 75 | Model Group:WC_V0:5994912
6522726 | 0.46 | 0 | Level : 0 | 78

# IfcFlowTerminal: 74_DAT_wastafel:74_DAT_wastafel (7)
Type - Material: <Unnamed>
Type - Other - Category: Plumbing Fixtures; artikelnummer: S8300100000; BCB WUID: AgAAAEusfAEBAAAATeEAAAWkQwAA1jIAAK8wAAB0vwAA5IIBAAAA; Family Name: 74_DAT_wastafel; IFCClass: IFCFLOWTERMINAL; IFCExportAs: IFCFLOWTERMINAL; kleur: wit; kraangat: midden; merk: Sphinx; NL-SfB tabel 1: 74.11; NL-SfB tabel 3: g3; serie: 300 Basic; type: afgerond, kuip afgerond; uitvoering: 50 met kraangat en overloop
Type - Constraints - Default Elevation: 0 mm
Type - Dimensions - breedte: 500 mm; diepte: 380 mm; hoogte: 170 mm
Type - Identity Data - Assembly Code: 74; Assembly Description: vaste sanitaire voorzieningen; Description: Wastafel; OmniClass Number: 23.45.00.00; OmniClass Title: Sanitary, Laundry, and Cleaning Equipment; Type Name: 74_DAT_wastafel; Workset: Family : Plumbing Fixtures : 74_DAT_wastafel
Type - Pset_ProductRequirements - Category: Plumbing Fixtures
Classification: 74 Uniformat (Uniformat)
Pset_DistributionFlowElementCommon - Reference: 74_DAT_wastafel; sets with these values: 2
Pset_DAT_KMS - Assembly Code: 74; Assembly Description: vaste sanitaire voorzieningen; Description: Wastafel
Other - Family: 74_DAT_wastafel; Family and Type: 74_DAT_wastafel: 74_DAT_wastafel; Type: 74_DAT_wastafel; Type Id: 4272932
Constraints - Elevation from Level: 800 mm; Offset from Host: 800 mm
Dimensions - Area: 0.369486 m2; Volume: 0.0160438 m3
Identity Data - Workset: Bouwkundig
Mechanical - System Classification: Sanitary
Phasing - Phase Created: 2. nieuwbouw
Name (74_DAT_wastafel:74_DAT_wastafel:...) | In | Level | Host | Mark | Group
5173648 | 0.43 | 0 | Level : 0 | 58 | Model Group:WC_V0:4976980
5173652 | 0.42 | 0 | Level : 0 | 59 | Model Group:WC_V0:4977293
5173654 | 0.41 | 0 | Level : 0 | 60 | Model Group:WC_V0:4977398
5173656 | 1.27 | 1 | Level : 1 | 61 | Model Group:WC_V0:5035649
5173660 | 1.25 | 1 | Level : 1 | 63 | Model Group:WC_V0:5035659
5174560 | 1.08 | 1 | Level : 1 | 67
5994933 | 1.06 | 1 | Level : 1 | 76 | Model Group:WC_V0:5994912

# IfcFlowTerminal: Lighting_Wall_Fagerhult_Rondo-G3-Twin-Wall_Unhosted:Reload with Type Catalog (12)
In: 00 Begane grond
Type - Material: bcb_staal
Type - Other - Category: Lighting Fixtures; Family Name: Lighting_Wall_Fagerhult_Rondo-G3-Twin-Wall_Unhosted
Type - Constraints - Default Elevation: 0 mm; Default Elevation_2: 1219 mm
Type - Dimensions - Height: 242.9 mm; Length: 205 mm; Width: 75 mm
Type - Electrical - Lamp: LED
Type - Electrical - Lighting - Calculate Coefficient of Utilization: yes; Coefficient of Utilization: 0
Type - Electrical - Loads - Apparent Load: 21 W; Load Classification: Lighting; Voltage: 230 V
Type - Identity Data - Article Number: Reload with Type Catalog; Assembly Code: D5020230; Description: Reload with Type Catalog; EAN_Code: Reload with Type Catalog; IP Code: Reload with Type Catalog; Keynote: V59; Manufacturer: Fagerhult; Model: Reload with Type Catalog; OmniClass Number: 23.80.70.00; OmniClass Title: Lighting; TypeID: EA2xx-i; Type Name: Reload with Type Catalog; URL: www.Fagerhult.com; Weight (Kg): Reload with Type Catalog; Workset: Family : Lighting Fixtures : Lighting_Wall_Fagerhult_Rondo-G3-Twin-Wall_Unhosted
Type - Photometrics - Dimming Lamp Color Temperature Shift: <None>; Emit Shape Visible in Rendering: no; Tilt Angle: 90 deg; Total Light Loss Factor: 1; Color Filter: 16777215; Color Rendering Index: Reload with Type Catalog; Efficacy: 148.542 s3*lm/kg/m2; Emit from Circle Diameter: 90 mm; Illuminance: 11.8206 lx; Initial Color Temperature: 3200 K; Light Source Definition (family): Circle+Photometric Web; Luminous Flux: 1380 lm; Luminous Intensity: 109.817 cd; Photometric File Note: The .IES files provided are sample files based on a few standard configurations. Not all photometric configurations are available. The actual data and values will vary depending on lens, color temperature and other options. Please visit www.fagerhult.com for more defined photometric data.; Photometric Web File: GENERIC - Please download and link the .IES file that best matches your fixture specification; Wattage: 9.2903 W
Type - Materials and Finishes - Body: bcb_staal; Color: Reload with Type Catalog
Type - Pset_ElementShading - Color: Reload with Type Catalog
Type - Pset_ManufacturerTypeInformation - ArticleNumber: Reload with Type Catalog; Manufacturer: Fagerhult
Type - Pset_ProductRequirements - Category: Lighting Fixtures
Classification: D5020230 Uniformat (Uniformat)
Pset_DistributionFlowElementCommon - Reference: Reload with Type Catalog; sets with these values: 2
Pset_DAT_KMS - Assembly Code: D5020230; Description: Reload with Type Catalog
Other - Family: Lighting_Wall_Fagerhult_Rondo-G3-Twin-Wall_Unhosted; Family and Type: Lighting_Wall_Fagerhult_Rondo-G3-Twin-Wall_Unhosted: Reload with Type Catalog; Type: Reload with Type Catalog; Type Id: 6879808
Constraints - Level: 0; Host: Level : 0
Dimensions - Area: 0.113423 m2; Volume: 0.00531433 m3
Electrical - Circuiting - Electrical Data: Reload with Type Catalog 230 V/1-21 VA
Identity Data - Workset: Bouwkundig
Phasing - Phase Created: 2. nieuwbouw
Name (Lighting_Wall_Fagerhult_Rondo-G3-Twin-Wall_Unhosted:Reload with Type Catalog:...) | Elevation from Level (mm) = Offset from Host (mm) | Mark
6880071 | 2982.1 | 7
6880484 | 2982.1 | 9 | Group: Model Group:Merk K03:5538780
6880547 | 2982.1 | 10 | Group: Model Group:Merk K03:5536856
6880549 | 2982.1 | 11 | Group: Model Group:Merk K03:5536928
6880551 | 2982.1 | 12 | Group: Model Group:Merk K03:5537079
6880553 | 2982.1 | 13 | Group: Model Group:Merk K03:5538762
6880555 | 2982.1 | 14 | Group: Model Group:Merk K03:5538798
6880628 | 2200 | 16
6881375 | 1600 | 20
6881456 | 1600 | 22
6882090 | 1600 | 23
6882139 | 1600 | 24

# IfcFlowTerminal: NLRS_59_PF_FB_brandslanghaspel inbouw_gen_ISR:haspel slang 30m gen hxdxb 730x240x790 (5)
Type - PredefinedType: USERDEFINED; Material: ISR_Kunststof_wit
Type - Other(Type) - Category: Plumbing Fixtures; Family Name: NLRS_59_PF_FB_brandslanghaspel inbouw_gen_ISR; slang_lengte: 30000 mm
Type - Constraints(Type) - Default Elevation: 1500 mm
Type - Dimensions(Type) - haspelkast_breedte: 790 mm; haspelkast_diepte: 240 mm; haspelkast_hoogte: 790 mm; leiding_diameter: 22 mm; leiding_radius: 11 mm
Type - Identity Data(Type) - Assembly Code: 59.20; Datum_Gewijzigd: 12-11-2020; Description: brandslanghaspel inbouw; Model: LOD300; SmartRevit_Versie: 2021.1; Type Comments: brandslanghaspel inbouw; Type Name: haspel slang 30m gen hxdxb 730x240x790; Workset: Family : Plumbing Fixtures : NLRS_59_PF_FB_brandslanghaspel inbouw_gen_ISR
Type - Materials and Finishes(Type) - haspelkast_materiaal: ISR_Kunststof_wit
Type - Pset_ProductRequirements - Category: Plumbing Fixtures
Classification: 59.20 Uniformat (Uniformat)
Pset_DistributionFlowElementCommon - Reference: haspel slang 30m gen hxdxb 730x240x790; sets with these values: 2
Pset_DAT_KMS - Assembly Code: 59.20; Description: brandslanghaspel inbouw
Other - Category: Plumbing Fixtures; Family: NLRS_59_PF_FB_brandslanghaspel inbouw_gen_ISR; Family and Type: NLRS_59_PF_FB_brandslanghaspel inbouw_gen_ISR: haspel slang 30m gen hxdxb 730x240x790; Type: haspel slang 30m gen hxdxb 730x240x790; Type Id: 4687182
Dimensions - Area: 1.00371 m2; NLRS_C_breedte: 790 mm; NLRS_C_diepte: 240 mm; NLRS_C_hoogte: 790 mm; Volume: 0.149784 m3
General - NLRS_P_c01_diameter: 22 mm; NLRS_P_c01_radius: 11 mm
Graphics - slang_bereik: no
Identity Data - Workset: Bouwkundig
Mechanical - brandslanghaspel_kw_flow: 0.361 m3/s; System Classification: Domestic Cold Water
Phasing - Phase Created: 2. nieuwbouw
Name (NLRS_59_PF_FB_brandslanghaspel inbouw_gen_ISR:haspel slang 30m gen hxdxb 730x240x790:...) | In | Level = Schedule Level | Elevation from Level (mm) | Host | Mark
5382441 | 0.33 | 0 | 1195 | Basic Wall : 22_DAT_binnenwand_125 | 103
5440045 | 1.11 | 1 | 1195 | Basic Wall : 22_DAT_binnenwand_125 HPL | 107
5466378 | 0.20 | 0 | 1195 | Basic Wall : 22_DAT_binnenwand_125 | 109
6598615 | 0.15 | V-1 | 1780 | Basic Wall : 22_DAT_binnenwand_125 | 80
6610308 | 1.20 | 1 | 1195 | Basic Wall : 22_DAT_binnenwand_125 HPL | 81

# IfcFlowTerminal: NLRS_74_PF_UN_AV_Geberit wastafel S8VR3027000G_BCB:NLRS_74_PF_UN_AV_Geberit wastafel S8VR3027000G_BCB (2)
Type - Material: NLRS_n0_kunststof_Geberit
Type - Other - Category: Plumbing Fixtures; Family Name: NLRS_74_PF_UN_AV_Geberit wastafel S8VR3027000G_BCB
Type - Model Properties - Content creator URL: www.bouwconnect.nl; NLRS_C_content_datum_uitgifte: 2018-04; Revit standaard: NLRS 2.5.2
Type - Constraints - Default Elevation: 0 mm
Type - Data - Gewicht: 30 kg
Type - Dimensions - Diameter in: 35 mm; Diameter uit: 45 mm; NLRS_C_breedte: 900 mm; NLRS_C_diepte: 415 mm; NLRS_C_hoogte: 200 mm
Type - General - NLRS_C_content_creator: BouwConnect; NLRS_C_content_datum_gewijzigd: 2020-03; NLRS_C_content_versie: 2.0; NLRS_C_revit_versie: 2018
Type - Identity Data - Assembly Code: 74.11; Assembly Description: vaste sanitaire voorzieningen; standaard, sanitaire toestellen; normaal; Description: 300 Kids kinderspeelwastafel 90 cm; Manufacturer: Geberit B.V.; Model: Kinderspeelwastafel 90 cm zonder overloop; NLRS_C_code_artikel: S8VR3027000G; NLRS_C_code_EAN: 4025410724434; NLRS_C_model: Kinderspeelwastafel 90 cm zonder overloop; NLRS_C_serie: 300 Kids; OmniClass Number: 23.45.00.00; OmniClass Title: Sanitary, Laundry, and Cleaning Equipment; Type Name: NLRS_74_PF_UN_AV_Geberit wastafel S8VR3027000G_BCB; URL: http://www.geberit.nl/; URL BCB: https://bcb-online.nl/?zoekterm=Geberit; Workset: Family : Plumbing Fixtures : NLRS_74_PF_UN_AV_Geberit wastafel S8VR3027000G_BCB
Type - Materials and Finishes - NLRS_C_materiaal: NLRS_n0_kunststof_Geberit
Type - Mechanical - CWFU: 0; WFU: 0
Type - Text - NLRS_C_merk: Geberit B.V.; NLRS_C_omschrijving: 300 Kids kinderspeelwastafel 90 cm; NLRS_C_type: Wastafel
Type - Pset_ManufacturerTypeInformation - Manufacturer: Geberit B.V.
Type - Pset_ProductRequirements - Category: Plumbing Fixtures
Classification: 74.11 Uniformat (Uniformat)
Pset_DistributionFlowElementCommon - Reference: NLRS_74_PF_UN_AV_Geberit wastafel S8VR3027000G_BCB; sets with these values: 2
Pset_DAT_KMS - Assembly Code: 74.11; Assembly Description: vaste sanitaire voorzieningen; standaard, sanitaire toestellen; normaal; Description: 300 Kids kinderspeelwastafel 90 cm
Other - Family: NLRS_74_PF_UN_AV_Geberit wastafel S8VR3027000G_BCB; Family and Type: NLRS_74_PF_UN_AV_Geberit wastafel S8VR3027000G_BCB: NLRS_74_PF_UN_AV_Geberit wastafel S8VR3027000G_BCB; Type: NLRS_74_PF_UN_AV_Geberit wastafel S8VR3027000G_BCB; Type Id: 6702381
Constraints - Level: 0; Elevation from Level: 530 mm; Host: Level : 0; Offset from Host: 530 mm
Dimensions - Area: 0.829575 m2; Volume: 0.0360579 m3
Identity Data - Workset: Bouwkundig
Mechanical - System Classification: Sanitary
Phasing - Phase Created: 2. nieuwbouw
Name (NLRS_74_PF_UN_AV_Geberit wastafel S8VR3027000G_BCB:NLRS_74_PF_UN_AV_Geberit wastafel S8VR3027000G_BCB:...) | In | Mark
6702433 | 0.08 | 84
6702625 | 0.04 | 85

# IfcFlowTerminal: NLRS_83_PF_LB_vaatwasser_gen_ASN:Koelkast (3)
Type - Material: <Unnamed>
Type - Other - Category: Plumbing Fixtures; Family Name: NLRS_83_PF_LB_vaatwasser_gen_ASN
Type - Constraints - Default Elevation: 0 mm
Type - Dimensions - KW_radius: 11 mm; NLRS_C_breedte: 600 mm; NLRS_C_diepte: 590 mm; NLRS_C_hoogte: 850 mm; vaatwasser_breedte: 600 mm; vaatwasser_diepte: 590 mm; vaatwasser_hoogte: 850 mm; VWA_radius: 20 mm
Type - Electrical - Loads - aansluit_waarde: 2200 W
Type - General - NLRS_C_content_creator: Arkance Systems; NLRS_C_content_datum_gewijzigd: 2022.05.27; NLRS_C_content_provider: Arkance Systems; NLRS_C_content_versie: 2.1; NLRS_C_revit_versie: 2021
Type - Identity Data - Assembly Code: 83.12; Assembly Description: losse keukeninventaris; standaard, keukenapparatuur; Description: koelkast; Manufacturer: generiek; Type Comments: KK; Type Name: Koelkast; Workset: Family : Plumbing Fixtures : NLRS_83_PF_LB_vaatwasser_gen_ASN
Type - Text - text: yes
Type - Pset_ManufacturerTypeInformation - Manufacturer: generiek
Type - Pset_ProductRequirements - Category: Plumbing Fixtures
Classification: 83.12 Uniformat (Uniformat)
Pset_DistributionFlowElementCommon - Reference: Koelkast; sets with these values: 2
Pset_DAT_KMS - Assembly Code: 83.12; Assembly Description: losse keukeninventaris; standaard, keukenapparatuur; Description: koelkast
Other - Family: NLRS_83_PF_LB_vaatwasser_gen_ASN; Family and Type: NLRS_83_PF_LB_vaatwasser_gen_ASN: Koelkast; Type: Koelkast; Type Id: 5226057
Dimensions - Area: 1.1878 m2; Volume: 0.24108 m3
Identity Data - Workset: Bouwkundig
Mechanical - System Classification: Domestic Cold Water,Sanitary,Power
Phasing - Phase Created: 2. nieuwbouw
Name (NLRS_83_PF_LB_vaatwasser_gen_ASN:Koelkast:...) | In | Level | Elevation from Level (mm) = Offset from Host (mm) | Host | Mark
5226056 | 1.10 | 1 | 100 | Level : 1 | 4
5226265 | 1.10 | 1 | 100 | Level : 1 | 88
5267633 | 0.33 | 0 | 96.3158 | Level : 0 | 95

# IfcFlowTerminal: NLRS_85_PF_LB_wasmaschine_gen_ASN:wasmachine (2)
In: 0.14
Type - Material: <Unnamed>
Type - Other - Category: Plumbing Fixtures; Family Name: NLRS_85_PF_LB_wasmaschine_gen_ASN
Type - Constraints - Default Elevation: 0 mm
Type - Dimensions - KW_radius: 11 mm; NLRS_C_breedte: 600 mm; NLRS_C_diepte: 590 mm; NLRS_C_hoogte: 850 mm; VWA_radius: 20 mm; wasmaschine_breedte: 600 mm; wasmaschine_diepte: 590 mm; wasmaschine_hoogte: 850 mm
Type - Electrical - Loads - aansluit_waarde: 2300 W
Type - General - NLRS_C_content_creator: Arkance Systems; NLRS_C_content_datum_gewijzigd: 2022.05.27; NLRS_C_content_provider: Arkance Systems; NLRS_C_content_versie: 2.1; NLRS_C_revit_versie: 2021
Type - Identity Data - Assembly Code: 85.11; Assembly Description: losse schoonmaakinventaris; standaard, schoonmaakapparatuur; Description: wasmachine; Manufacturer: generiek; Type Comments: WM; Type Name: wasmachine; Workset: Family : Plumbing Fixtures : NLRS_85_PF_LB_wasmaschine_gen_ASN
Type - Text - text: yes
Type - Pset_ManufacturerTypeInformation - Manufacturer: generiek
Type - Pset_ProductRequirements - Category: Plumbing Fixtures
Classification: 85.11 Uniformat (Uniformat)
Pset_DistributionFlowElementCommon - Reference: wasmachine; sets with these values: 2
Pset_DAT_KMS - Assembly Code: 85.11; Assembly Description: losse schoonmaakinventaris; standaard, schoonmaakapparatuur; Description: wasmachine
Other - Family: NLRS_85_PF_LB_wasmaschine_gen_ASN; Family and Type: NLRS_85_PF_LB_wasmaschine_gen_ASN: wasmachine; Type: wasmachine; Type Id: 5221094
Constraints - Elevation from Level: 0 mm; Level: 0; Offset from Host: 0 mm; Host: Level : 0
Dimensions - Area: 1.19115 m2; Volume: 0.241093 m3
Identity Data - Workset: Bouwkundig
Mechanical - System Classification: Domestic Cold Water,Sanitary,Power
Phasing - Phase Created: 2. nieuwbouw
Name (NLRS_85_PF_LB_wasmaschine_gen_ASN:wasmachine:...) | Mark
5225412 | 86
5225495 | 87

# IfcFlowTerminal: S8203300000:S8203300000, S8203300000:S8203300000:5136436
In: 0.18
Type - Material: <Unnamed>
Type - Other - Category: Plumbing Fixtures; artikelnummer: S8203300000; BCB WUID: AgAAACY0TwABAAAAIHgBAAWkQwAAy3AAAKmKAABjdwEA6YABAAAA; Family Name: S8203300000; IFCClass: IFCFLOWTERMINAL; IFCExportAs: IFCFLOWTERMINAL; kleur: wit; merk: Sphinx; NL-SfB tabel 1: 74.11; NL-SfB tabel 3: g3; serie: 300 Comfort; type: verlengd 700
Type - Constraints - Default Elevation: 0 mm
Type - Dimensions - breedte: 390 mm; diepte: 700 mm; hoogte: 350 mm
Type - Identity Data - OmniClass Number: 23.45.00.00; OmniClass Title: Sanitary, Laundry, and Cleaning Equipment; Type Name: S8203300000; Workset: Family : Plumbing Fixtures : S8203300000
Type - Pset_ProductRequirements - Category: Plumbing Fixtures
Pset_DistributionFlowElementCommon - Reference: S8203300000; sets with these values: 2
Other - Family: S8203300000; Family and Type: S8203300000: S8203300000; Type: S8203300000; Type Id: 5136542
Constraints - Level: 0; Elevation from Level: 400 mm; Host: Level : 0; Offset from Host: 400 mm
Dimensions - Area: 0.74894 m2; Volume: 0.0697791 m3
Identity Data - Workset: Bouwkundig; Mark: 97
Mechanical - System Classification: Sanitary
Phasing - Phase Created: 2. nieuwbouw

# IfcFlowTerminal: S8309800000:S8309800000 (3)
Type - Material: <Unnamed>
Type - Other - Category: Plumbing Fixtures; artikelnummer: S8309800000; BCB WUID: AgAAAO-iSAABAAAA6XMBAAWkQwAA1jIAAK8wAABjdwEAb38BAAAA; Family Name: S8309800000; IFCClass: IFCFLOWTERMINAL; IFCExportAs: IFCFLOWTERMINAL; kleur: wit; kraangat: midden; merk: Sphinx; NL-SfB tabel 1: 74.11; NL-SfB tabel 3: g3; serie: 300 Comfort; type: (afgerond, kuip afgerond); uitvoering: rolstoelwastafel met kraangat en overloop
Type - Constraints - Default Elevation: 0 mm
Type - Dimensions - breedte: 650 mm; diepte: 550 mm; hoogte: 155 mm
Type - Identity Data - OmniClass Number: 23.45.00.00; OmniClass Title: Sanitary, Laundry, and Cleaning Equipment; Type Name: S8309800000; Workset: Family : Plumbing Fixtures : S8309800000
Type - Pset_ProductRequirements - Category: Plumbing Fixtures
Pset_DistributionFlowElementCommon - Reference: S8309800000; sets with these values: 2
Other - Family: S8309800000; Family and Type: S8309800000: S8309800000; Type: S8309800000; Type Id: 5136538
Constraints - Elevation from Level: 800 mm; Offset from Host: 800 mm
Dimensions - Area: 0.554908 m2; Volume: 0.0401448 m3
Identity Data - Workset: Bouwkundig
Mechanical - System Classification: Sanitary
Phasing - Phase Created: 2. nieuwbouw
Name (S8309800000:S8309800000:...) | In | Level | Host | Mark
5136437 | 0.18 | 0 | Level : 0 | 98
5179287 | 1.19 | 1 | Floor : 23_Zwevende dekvloer 90mm | 73
6420698 | 0.30 | 0 | Level : 0 | 77

# IfcFlowTerminal: ___LED___subcomponent:___LED___subcomponent (4)
In: -1 Speelvloer
Type - Material: Cibes_spotlight
Type - Other - Category: Lighting Fixtures; Family Name: ___LED___subcomponent
Type - Constraints - Default Elevation: 0 mm
Type - Dimensions - Light Source Symbol Length: 3048 mm
Type - Identity Data - OmniClass Number: 23.80.70.00; OmniClass Title: Lighting; Type Name: ___LED___subcomponent; Workset: Family : Lighting Fixtures : ___LED___subcomponent
Type - Photometrics - Color Filter: 16777215; Dimming Lamp Color Temperature Shift: <None>; Efficacy: 148.542 s3*lm/kg/m2; Emit from Circle Diameter: 50 mm; Emit Shape Visible in Rendering: no; Illuminance: 959.925 lx; Initial Color Temperature: 3000 K; Light Source Definition (family): Circle+Spot; Luminous Flux: 1380 lm; Luminous Intensity: 8917.99 cd; Spot Beam Angle: 30 deg; Spot Field Angle: 30 deg; Tilt Angle: 90 deg; Total Light Loss Factor: 1; Wattage: 9.2903 W
Type - Pset_ProductRequirements - Category: Lighting Fixtures
Pset_DistributionFlowElementCommon - Reference: ___LED___subcomponent; sets with these values: 2
Other - Family: ___LED___subcomponent; Family and Type: ___LED___subcomponent: ___LED___subcomponent; Type: ___LED___subcomponent; Type Id: 6199750
Constraints - Moves With Nearby Elements: no; Level: V-1; Elevation from Level: 4490 mm; Host: Level : V-1; Offset from Host: 4490 mm
Dimensions - Area: 10.1946 m2; Volume: 4.25805 m3
Electrical - Lighting - Calculate Coefficient of Utilization: no
Identity Data - Workset: Bouwkundig
Phasing - Phase Created: 2. nieuwbouw
Name (___LED___subcomponent:___LED___subcomponent:...) | Mark
6200291 | 1
6200292 | 2
6200293 | 3
6200294 | 4

# IfcFooting: Wall Foundation:300_16_strokenfundatie_300x1400, Wall Foundation:300_16_strokenfundatie_300x1400:6264903
In: -1 fundering
PredefinedType: STRIP_FOOTING; Classification: 16.12 Uniformat (Uniformat)
Pset_ProductRequirements - Category: Structural Foundations
Pset_QuantityTakeOff - Reference: 300_16_strokenfundatie_300x1400; sets with these values: 3
Pset_Constructieve fundering - NL-sfb-Codering: 16.12; Volume: 12.0214 m3
Pset_DAT_KMS - Assembly Code: 16.12; Assembly Description: funderingsconstructies; voeten en balken, fundatie balken
Other - Category: Structural Foundations; Family: Wall Foundation; Family and Type: Wall Foundation: 300_16_strokenfundatie_300x1400; Type: 300_16_strokenfundatie_300x1400; Type Id: 6548097
Dimensions - Area: 40.0714 m2; Elevation at Bottom: -1570 mm; Elevation at Bottom Survey: -1570 mm; Elevation at Top: -1270 mm; Elevation at Top Survey: -1270 mm; Length: 28800 mm; Volume: 12.0214 m3; Width: 1395 mm
Identity Data - Workset: Bouwkundig; Has Association: no
Phasing - Phase Created: 2. nieuwbouw
Structural - Rebar Cover - Bottom Face: Rebar Cover 1 <25 mm>; Rebar Cover - Other Faces: Rebar Cover 1 <25 mm>; Rebar Cover - Top Face: Rebar Cover 1 <25 mm>
Other(Type) - Category: Structural Foundations; Family Name: Wall Foundation
Dimensions(Type) - Default End Extension Length: 0 mm; Do Not Break At Inserts: yes; Foundation Thickness: 300 mm; Heel Length: 425 mm; Toe Length: 775 mm
Identity Data(Type) - Workset: Wall Types; Assembly Code: 16.12; Assembly Description: funderingsconstructies; voeten en balken, fundatie balken; Type Name: 300_16_strokenfundatie_300x1400
Structural(Type) - Structural Usage: Retaining

# IfcFooting: Wall Foundation:300_16_strokenfundatie_300x800 (5)
In: -1 fundering
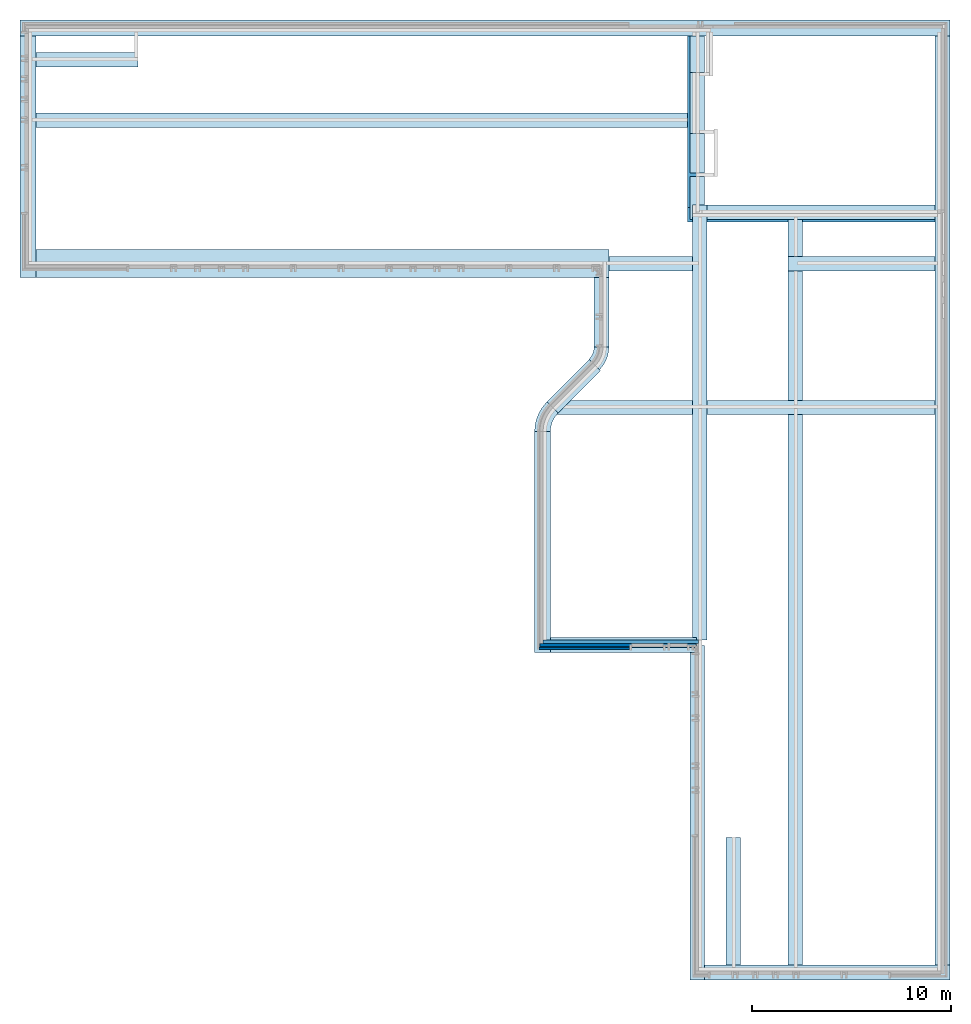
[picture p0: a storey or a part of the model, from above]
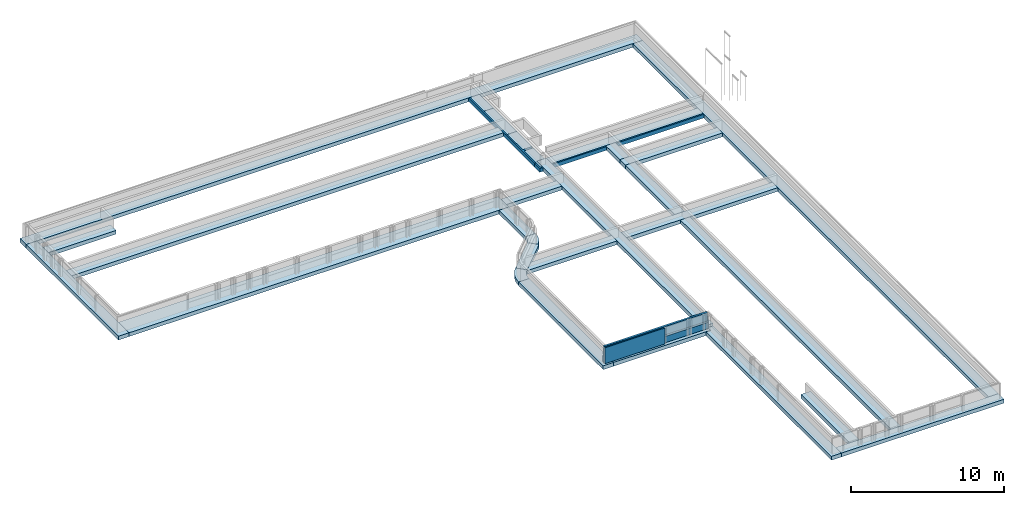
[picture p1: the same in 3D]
Properties of the parts of a building model (IFC2X3), part 15 of 37

# IfcFooting: Wall Foundation:300_16_strokenfundatie_300x800 (5)
PredefinedType: STRIP_FOOTING; Classification: 16.12 Uniformat (Uniformat)
Pset_ProductRequirements - Category: Structural Foundations
Pset_QuantityTakeOff - Reference: 300_16_strokenfundatie_300x800; sets with these values: 3
Pset_Constructieve fundering - NL-sfb-Codering: 16.12
Pset_DAT_KMS - Assembly Code: 16.12; Assembly Description: funderingsconstructies; voeten en balken, fundatie balken
Other - Category: Structural Foundations; Family: Wall Foundation; Family and Type: Wall Foundation: 300_16_strokenfundatie_300x800; Type: 300_16_strokenfundatie_300x800; Type Id: 6547655
Dimensions - Elevation at Bottom: -1570 mm; Elevation at Bottom Survey: -1570 mm; Elevation at Top: -1270 mm; Elevation at Top Survey: -1270 mm; Width: 795 mm
Identity Data - Workset: Bouwkundig; Has Association: no
Phasing - Phase Created: 2. nieuwbouw
Structural - Rebar Cover - Bottom Face: Rebar Cover 1 <25 mm>; Rebar Cover - Other Faces: Rebar Cover 1 <25 mm>; Rebar Cover - Top Face: Rebar Cover 1 <25 mm>
Other(Type) - Category: Structural Foundations; Family Name: Wall Foundation
Dimensions(Type) - Default End Extension Length: 0 mm; Do Not Break At Inserts: yes; Foundation Thickness: 300 mm; Heel Length: 225 mm; Toe Length: 375 mm
Identity Data(Type) - Workset: Wall Types; Assembly Code: 16.12; Assembly Description: funderingsconstructies; voeten en balken, fundatie balken; Type Name: 300_16_strokenfundatie_300x800
Structural(Type) - Structural Usage: Retaining
Name (Wall Foundation:300_16_strokenfundatie_300x800:...) | Pset_Constructieve fundering, Volume (m3) = Dimensions, Volume (m3) | Area (m2) | Length (mm)
6264879 | 11.1201 | 37.0669 | 46150
6264891 | 2.88704 | 9.62347 | 11860
6264934 | 0.7155 | 2.385 | 3000
6264941 | 0.318909 | 1.06293 | 1396.05
6264953 | 2.63883 | 8.79609 | 10619.3

# IfcFooting: Wall Foundation:300_16_strokenfundatie_bi350/bu250/hg350 (21)
In: -1 fundering
PredefinedType: STRIP_FOOTING; Classification: 16.12 Uniformat (Uniformat)
Pset_ProductRequirements - Category: Structural Foundations
Pset_QuantityTakeOff - Reference: 300_16_strokenfundatie_bi350/bu250/hg350; sets with these values: 3
Pset_Constructieve fundering - NL-sfb-Codering: 16.12
Pset_DAT_KMS - Assembly Code: 16.12; Assembly Description: funderingsconstructies; voeten en balken, fundatie balken
Other - Category: Structural Foundations; Family: Wall Foundation; Family and Type: Wall Foundation: 300_16_strokenfundatie_bi350/bu250/hg350; Type: 300_16_strokenfundatie_bi350/bu250/hg350; Type Id: 53638
Dimensions - Elevation at Bottom: -1570 mm; Elevation at Bottom Survey: -1570 mm; Elevation at Top: -1270 mm; Elevation at Top Survey: -1270 mm
Identity Data - Has Association: no
Phasing - Phase Created: 2. nieuwbouw
Structural - Rebar Cover - Bottom Face: Rebar Cover 1 <25 mm>; Rebar Cover - Other Faces: Rebar Cover 1 <25 mm>; Rebar Cover - Top Face: Rebar Cover 1 <25 mm>
Other(Type) - Category: Structural Foundations; Family Name: Wall Foundation
Dimensions(Type) - Default End Extension Length: 0 mm; Do Not Break At Inserts: yes; Foundation Thickness: 300 mm; Heel Length: 250 mm; Toe Length: 300 mm
Identity Data(Type) - Workset: Wall Types; Assembly Code: 16.12; Assembly Description: funderingsconstructies; voeten en balken, fundatie balken; Type Name: 300_16_strokenfundatie_bi350/bu250/hg350
Structural(Type) - Structural Usage: Retaining
Name (Wall Foundation:300_16_strokenfundatie_bi350/bu250/hg350:...) | Pset_Constructieve fundering, Volume (m3) = Dimensions, Volume (m3) | Area (m2) | Length (mm) | Width (mm) | Workset
6264915 | 0.77959 | 2.59863 | 4108.1 | 745 | Bouwkundig
6264922 | 0.218981 | 0.729944 | 960.149 | 745 | Bouwkundig
6264965 | 1.63825 | 5.46082 | 7899.96 | 745 | Bouwkundig
6264977 | 3.71358 | 12.3786 | 16335 | 745 | Bouwkundig
6264989 | 2.75017 | 9.16722 | 12355 | 745 | Bouwkundig
6265001 | 10.4117 | 34.7058 | 47455 | 745 | Bouwkundig
6266390 | 7.10682 | 23.6894 | 33120 | 725 | Bouwkundig
6266402 | 4.73321 | 15.7774 | 21365 | 725 | Bouwkundig
6266420 | 0.914579 | 3.0486 | 4620 | 725 | Bouwkundig
6266432 | 1.60243 | 5.34144 | 7012.5 | 725 | Bouwkundig
6266444 | 3.89201 | 12.9734 | 19078 | 725 | Bouwkundig
6266456 | 7.81369 | 26.0456 | 37795 | 725 | Bouwkundig
6266474 | 1.38983 | 4.63275 | 6510 | 725 | Bouwkundig
6266566 | 0.396938 | 1.32313 | 2020 | 725 | Bouwkundig
6266694 | 0.434823 | 1.44941 | 1999.19 | 725 | Bouwkundig
6266777 | 0.665264 | 2.21755 | 3058.69 | 725 | Bouwkundig
6266789 | 0.341058 | 1.13686 | 1672.13 | 725 | Bouwkundig
6266807 | 2.50317 | 8.3439 | 12120 | 730 | Bouwkundig
6266974 | 1.11273 | 3.7091 | 5311 | 725 | Bouwkundig
6492231 | 0.381479 | 1.2716 | 12280 | 710 | situatie
6562866 | 0.31563 | 1.0521 | 9105 | 710 | Bouwkundig

# IfcFurnishingElement: 00_DAT Vaste inrichting Boven Keukenkasten:Bovenkast Gaderobe (28)
Type - Material: ISR_HPL Kleur hout
Type - Other - Category: Furniture; Family Name: 00_DAT Vaste inrichting Boven Keukenkasten
Type - Constraints - Default Elevation: 0 mm
Type - Dimensions - 1/2 maat: 337.5 mm; Breedte: 675 mm; Diepte Bovenkast: 415 mm; Hoogte Bovenkast: 590 mm; Hoogte Bovenkast vanaf 0: 1800 mm; y: 295 mm
Type - Identity Data - Workset: Family : Furniture : 00_DAT Vaste inrichting Boven Keukenkasten; OmniClass Number: 23.40.20.00; OmniClass Title: General Furniture and Specialties; Type Name: Bovenkast Gaderobe
Type - Materials and Finishes - Materiaal: ISR_HPL Kleur hout
Type - Pset_ProductRequirements - Category: Furniture
Pset_QuantityTakeOff - Reference: Bovenkast Gaderobe
Other - Boven Geen: no; Family: 00_DAT Vaste inrichting Boven Keukenkasten; Family and Type: 00_DAT Vaste inrichting Boven Keukenkasten: Bovenkast Gaderobe; Type: Bovenkast Gaderobe; Type Id: 5853006
Constraints - Elevation from Level: 0 mm; Moves With Nearby Elements: no; Offset from Host: 0 mm
Dimensions - Area: 0.923225 m2; Volume: 0.165274 m3
Identity Data - Workset: Bouwkundig
Phasing - Phase Created: 2. nieuwbouw
Visibility - Bo Geen Visible: no
Name (00_DAT Vaste inrichting Boven Keukenkasten:Bovenkast Gaderobe:...) | In | Boven Links = Bo Links Visible | Boven Rechts = Bo Rechts Visible | Level | Host | Group
5864548 | 0.28a | no | yes | 0 | Level : 0 | Model Group:Basisgroep element 2:5203610
5865112 | 0.28a | yes | no | 0 | Level : 0 | Model Group:Basisgroep element 2:5203610
5865122 | 0.28a | no | yes | 0 | Level : 0 | Model Group:Basisgroep element 2:5203610
5865130 | 0.28a | yes | no | 0 | Level : 0 | Model Group:Basisgroep element 2:5203610
5884165 | 0.35a | no | yes | 0 | Level : 0 | Model Group:Basisgroep element:5145694
5884345 | 0.35a | yes | no | 0 | Level : 0 | Model Group:Basisgroep element:5145694
5884353 | 0.35a | no | yes | 0 | Level : 0 | Model Group:Basisgroep element:5145694
5884361 | 0.35a | yes | no | 0 | Level : 0 | Model Group:Basisgroep element:5145694
5884455 | 0.36a | no | yes | 0 | Level : 0 | Model Group:Basisgroep element:5145620
5884456 | 0.36a | yes | no | 0 | Level : 0 | Model Group:Basisgroep element:5145620
5884457 | 0.36a | no | yes | 0 | Level : 0 | Model Group:Basisgroep element:5145620
5884458 | 0.36a | yes | no | 0 | Level : 0 | Model Group:Basisgroep element:5145620
5884467 | 0.37a | no | yes | 0 | Level : 0 | Model Group:Basisgroep element:5145670
5884468 | 0.37a | yes | no | 0 | Level : 0 | Model Group:Basisgroep element:5145670
5884469 | 0.37a | no | yes | 0 | Level : 0 | Model Group:Basisgroep element:5145670
5884470 | 0.37a | yes | no | 0 | Level : 0 | Model Group:Basisgroep element:5145670
5884473 | 1.21a | no | yes | 1 | Level : 1 | Model Group:Basisgroep element:5181887
5884474 | 1.21a | yes | no | 1 | Level : 1 | Model Group:Basisgroep element:5181887
5884475 | 1.21a | no | yes | 1 | Level : 1 | Model Group:Basisgroep element:5181887
5884476 | 1.21a | yes | no | 1 | Level : 1 | Model Group:Basisgroep element:5181887
5884479 | 1.22a | no | yes | 1 | Level : 1 | Model Group:Basisgroep element:5184346
5884480 | 1.22a | yes | no | 1 | Level : 1 | Model Group:Basisgroep element:5184346
5884481 | 1.22a | no | yes | 1 | Level : 1 | Model Group:Basisgroep element:5184346
5884482 | 1.22a | yes | no | 1 | Level : 1 | Model Group:Basisgroep element:5184346
5884485 | 1.23a | no | yes | 1 | Level : 1 | Model Group:Basisgroep element:5184395
5884486 | 1.23a | yes | no | 1 | Level : 1 | Model Group:Basisgroep element:5184395
5884487 | 1.23a | no | yes | 1 | Level : 1 | Model Group:Basisgroep element:5184395
5884488 | 1.23a | yes | no | 1 | Level : 1 | Model Group:Basisgroep element:5184395

# IfcFurnishingElement: 00_DAT Vaste inrichting Boven Keukenkasten:Bovenkast Gaderobe B643 Hoog (7)
Type - Material: ISR_HPL Kleur hout
Type - Other - Category: Furniture; Family Name: 00_DAT Vaste inrichting Boven Keukenkasten
Type - Constraints - Default Elevation: 0 mm
Type - Dimensions - 1/2 maat: 331.5 mm; Breedte: 663 mm; Diepte Bovenkast: 415 mm; Hoogte Bovenkast: 1190 mm; Hoogte Bovenkast vanaf 0: 1200 mm; y: 595 mm
Type - Identity Data - Workset: Family : Furniture : 00_DAT Vaste inrichting Boven Keukenkasten; OmniClass Number: 23.40.20.00; OmniClass Title: General Furniture and Specialties; Type Name: Bovenkast Gaderobe B643 Hoog
Type - Materials and Finishes - Materiaal: ISR_HPL Kleur hout
Type - Pset_ProductRequirements - Category: Furniture
Pset_QuantityTakeOff - Reference: Bovenkast Gaderobe B643 Hoog
Other - Boven Links: no; Boven Rechts: yes; Boven Geen: no; Family: 00_DAT Vaste inrichting Boven Keukenkasten; Family and Type: 00_DAT Vaste inrichting Boven Keukenkasten: Bovenkast Gaderobe B643 Hoog; Type: Bovenkast Gaderobe B643 Hoog; Type Id: 6142823
Constraints - Elevation from Level: 0 mm; Moves With Nearby Elements: no; Offset from Host: 0 mm
Dimensions - Area: 1.55797 m2; Volume: 0.327423 m3
Identity Data - Workset: Bouwkundig
Phasing - Phase Created: 2. nieuwbouw
Visibility - Bo Geen Visible: no; Bo Links Visible: no; Bo Rechts Visible: yes
Name (00_DAT Vaste inrichting Boven Keukenkasten:Bovenkast Gaderobe B643 Hoog:...) | In | Level | Host | Group
5868138 | 0.28a | 0 | Level : 0 | Model Group:Basisgroep element 2:5203610
5884038 | 0.35a | 0 | Level : 0 | Model Group:Basisgroep element:5145694
5884454 | 0.36a | 0 | Level : 0 | Model Group:Basisgroep element:5145620
5884466 | 0.37a | 0 | Level : 0 | Model Group:Basisgroep element:5145670
5884472 | 1.21a | 1 | Level : 1 | Model Group:Basisgroep element:5181887
5884478 | 1.22a | 1 | Level : 1 | Model Group:Basisgroep element:5184346
5884484 | 1.23a | 1 | Level : 1 | Model Group:Basisgroep element:5184395

# IfcFurnishingElement: 00_DAT Vaste inrichting Boven Keukenkasten:Bovenkast Gaderobe KDV (8)
In: 0.15
Type - Material: ISR_HPL Kleur hout
Type - Other - Category: Furniture; Family Name: 00_DAT Vaste inrichting Boven Keukenkasten
Type - Constraints - Default Elevation: 0 mm
Type - Dimensions - 1/2 maat: 300 mm; Breedte: 600 mm; Diepte Bovenkast: 415 mm; Hoogte Bovenkast: 790 mm; Hoogte Bovenkast vanaf 0: 1600 mm; y: 395 mm
Type - Identity Data - Workset: Family : Furniture : 00_DAT Vaste inrichting Boven Keukenkasten; OmniClass Number: 23.40.20.00; OmniClass Title: General Furniture and Specialties; Type Name: Bovenkast Gaderobe KDV
Type - Materials and Finishes - Materiaal: ISR_HPL Kleur hout
Type - Pset_ProductRequirements - Category: Furniture
Pset_QuantityTakeOff - Reference: Bovenkast Gaderobe KDV
Other - Boven Geen: no; Family: 00_DAT Vaste inrichting Boven Keukenkasten; Family and Type: 00_DAT Vaste inrichting Boven Keukenkasten: Bovenkast Gaderobe KDV; Type: Bovenkast Gaderobe KDV; Type Id: 5895941
Constraints - Elevation from Level: 0 mm; Level: 0; Moves With Nearby Elements: no; Offset from Host: 0 mm; Host: Floor : 23_Dekvloer 70mm
Dimensions - Area: 1.05085 m2; Volume: 0.19671 m3
Identity Data - Workset: Bouwkundig
Phasing - Phase Created: 2. nieuwbouw
Visibility - Bo Geen Visible: no
Name (00_DAT Vaste inrichting Boven Keukenkasten:Bovenkast Gaderobe KDV:...) | Boven Rechts = Bo Rechts Visible | Boven Links = Bo Links Visible | Group
5896300 | no | yes | Model Group:Bovenkast KDV:5896304
5896301 | yes | no | Model Group:Bovenkast KDV:5896304
5896302 | no | yes | Model Group:Bovenkast KDV:5896304
5896303 | yes | no | Model Group:Bovenkast KDV:5896304
6181584 | no | yes | Model Group:Bovenkast KDV:6181588
6181585 | yes | no | Model Group:Bovenkast KDV:6181588
6181586 | no | yes | Model Group:Bovenkast KDV:6181588
6181587 | yes | no | Model Group:Bovenkast KDV:6181588

# IfcFurnishingElement: 00_DAT Vaste inrichting Boven Keukenkasten:Bovenkast Gaderobe bso (12)
Type - Material: ISR_HPL Kleur hout
Type - Other - Category: Furniture; Family Name: 00_DAT Vaste inrichting Boven Keukenkasten
Type - Constraints - Default Elevation: 0 mm
Type - Dimensions - 1/2 maat: 367.5 mm; Breedte: 735 mm; Diepte Bovenkast: 415 mm; Hoogte Bovenkast: 590 mm; Hoogte Bovenkast vanaf 0: 1800 mm; y: 295 mm
Type - Identity Data - Workset: Family : Furniture : 00_DAT Vaste inrichting Boven Keukenkasten; OmniClass Number: 23.40.20.00; OmniClass Title: General Furniture and Specialties; Type Name: Bovenkast Gaderobe bso
Type - Materials and Finishes - Materiaal: ISR_HPL Kleur hout
Type - Pset_ProductRequirements - Category: Furniture
Pset_QuantityTakeOff - Reference: Bovenkast Gaderobe bso
Other - Boven Geen: no; Family: 00_DAT Vaste inrichting Boven Keukenkasten; Family and Type: 00_DAT Vaste inrichting Boven Keukenkasten: Bovenkast Gaderobe bso; Type: Bovenkast Gaderobe bso; Type Id: 6281085
Constraints - Elevation from Level: 0 mm; Moves With Nearby Elements: no; Offset from Host: 0 mm; Level: 1; Host: Floor : 23_Zwevende dekvloer 90mm
Dimensions - Area: 0.983525 m2; Volume: 0.179965 m3
Identity Data - Workset: Bouwkundig
Phasing - Phase Created: 2. nieuwbouw
Visibility - Bo Geen Visible: no
Name (00_DAT Vaste inrichting Boven Keukenkasten:Bovenkast Gaderobe bso:...) | In | Boven Rechts = Bo Rechts Visible | Boven Links = Bo Links Visible
6280809 | 1.04a | no | yes
6281253 | 1.04a | yes | no
6281286 | 1.04a | no | yes
6281465 | 1.03a | no | yes | Group: Model Group:V1_Basiselement:5167028
6281466 | 1.03a | yes | no | Group: Model Group:V1_Basiselement:5167028
6281467 | 1.03a | no | yes | Group: Model Group:V1_Basiselement:5167028
6281644 | 1.02a | no | yes | Group: Model Group:V1_Basiselement:5988153
6281645 | 1.02a | yes | no | Group: Model Group:V1_Basiselement:5988153
6281646 | 1.02a | no | yes | Group: Model Group:V1_Basiselement:5988153
6281745 | 1.01a | no | yes
6281746 | 1.01a | yes | no
6281747 | 1.01a | no | yes

# IfcFurnishingElement: 00_DAT Vaste inrichting Boven Keukenkasten:Bovenkast Gaderobe bso Hoog (4)
Type - Material: ISR_HPL Kleur hout
Type - Other - Category: Furniture; Family Name: 00_DAT Vaste inrichting Boven Keukenkasten
Type - Constraints - Default Elevation: 0 mm
Type - Dimensions - 1/2 maat: 460 mm; Breedte: 920 mm; Diepte Bovenkast: 415 mm; Hoogte Bovenkast: 1190 mm; Hoogte Bovenkast vanaf 0: 1200 mm; y: 595 mm
Type - Identity Data - Workset: Family : Furniture : 00_DAT Vaste inrichting Boven Keukenkasten; OmniClass Number: 23.40.20.00; OmniClass Title: General Furniture and Specialties; Type Name: Bovenkast Gaderobe bso Hoog
Type - Materials and Finishes - Materiaal: ISR_HPL Kleur hout
Type - Pset_ProductRequirements - Category: Furniture
Pset_QuantityTakeOff - Reference: Bovenkast Gaderobe bso Hoog
Other - Boven Links: no; Boven Rechts: yes; Boven Geen: no; Family: 00_DAT Vaste inrichting Boven Keukenkasten; Family and Type: 00_DAT Vaste inrichting Boven Keukenkasten: Bovenkast Gaderobe bso Hoog; Type: Bovenkast Gaderobe bso Hoog; Type Id: 6612757
Constraints - Elevation from Level: 0 mm; Moves With Nearby Elements: no; Offset from Host: 0 mm; Level: 1; Host: Floor : 23_Zwevende dekvloer 90mm
Dimensions - Area: 1.97045 m2; Volume: 0.454342 m3
Identity Data - Workset: Bouwkundig
Phasing - Phase Created: 2. nieuwbouw
Visibility - Bo Geen Visible: no; Bo Links Visible: no; Bo Rechts Visible: yes
Name (00_DAT Vaste inrichting Boven Keukenkasten:Bovenkast Gaderobe bso Hoog:...) | In
6281356 | 1.04a
6281469 | 1.03a | Group: Model Group:V1_Basiselement:5167028
6281648 | 1.02a | Group: Model Group:V1_Basiselement:5988153
6281749 | 1.01a

# IfcFurnishingElement: 00_DAT Vaste inrichting Boven Keukenkasten:Kastenwand B 23490, 00_DAT Vaste inrichting Boven Keukenkasten:Kastenwand B 23490:5855752
In: 00 Begane grond
Type - Material: ISR_RAL 9010
Type - Other - Category: Furniture; Family Name: 00_DAT Vaste inrichting Boven Keukenkasten
Type - Constraints - Default Elevation: 0 mm
Type - Dimensions - 1/2 maat: 11777.5 mm; Breedte: 23555 mm; Diepte Bovenkast: 350 mm; Hoogte Bovenkast: 600 mm; Hoogte Bovenkast vanaf 0: 2640 mm; y: 300 mm
Type - Identity Data - OmniClass Number: 23.40.20.00; OmniClass Title: General Furniture and Specialties; Type Name: Kastenwand B 23490; Workset: Family : Furniture : 00_DAT Vaste inrichting Boven Keukenkasten
Type - Pset_ProductRequirements - Category: Furniture
Pset_QuantityTakeOff - Reference: Kastenwand B 23490
Other - Boven Links: no; Boven Rechts: no; Boven Geen: no; Family: 00_DAT Vaste inrichting Boven Keukenkasten; Family and Type: 00_DAT Vaste inrichting Boven Keukenkasten: Kastenwand B 23490; Type: Kastenwand B 23490; Type Id: 5853000
Constraints - Elevation from Level: 0 mm; Level: 0; Moves With Nearby Elements: no; Offset from Host: 0 mm; Host: Floor : 23_Dekvloer 70mm
Dimensions - Area: 22.5873 m2; Volume: 4.94655 m3
Identity Data - Workset: Bouwkundig
Phasing - Phase Created: 2. nieuwbouw
Visibility - Bo Geen Visible: yes; Bo Links Visible: yes; Bo Rechts Visible: no
Group: Model Group:Kastenwand:5849908

# IfcFurnishingElement: 00_DAT Vaste inrichting Keukenkasten hoog:Hoge kast 600 (4)
Type - Material: ISR_RAL 9010
Type - Other - Category: Furniture; Family Name: 00_DAT Vaste inrichting Keukenkasten hoog
Type - Constraints - Default Elevation: 0 mm
Type - Dimensions - Breedte: 600 mm; Diepte Bovenkast: 350 mm; Diepte Kast: 600 mm; Hoogte: 2390 mm; Hoogte Bovenkast: 490 mm; Hoogte Bovenkast vanaf 0: 1900 mm; Hoogte Spatwand: 300 mm
Type - Division Geometry - 1/2 maat: 300 mm; x: 2700 mm; y: 245 mm; Z: 875 mm
Type - Identity Data - OmniClass Number: 23.40.20.00; OmniClass Title: General Furniture and Specialties; Type Name: Hoge kast 600; Workset: Family : Furniture : 00_DAT Vaste inrichting Keukenkasten hoog
Type - Pset_ProductRequirements - Category: Furniture
Pset_QuantityTakeOff - Reference: Hoge kast 600
Other - Boven Links: no; Boven Rechts: no; Family: 00_DAT Vaste inrichting Keukenkasten hoog; Family and Type: 00_DAT Vaste inrichting Keukenkasten hoog: Hoge kast 600; Type: Hoge kast 600; Type Id: 5837111
Constraints - Elevation from Level: 0 mm; Moves With Nearby Elements: no; Offset from Host: 0 mm
Dimensions - Area: 3.223 m2; Volume: 0.8574 m3
Identity Data - Workset: Bouwkundig
Phasing - Phase Created: 2. nieuwbouw
Name (00_DAT Vaste inrichting Keukenkasten hoog:Hoge kast 600:...) | In | Links | Boven klep = Bovenkast | Rechts | Level | Host
5837167 | 0.44 | yes | no | no | 0 | Level : 0
5837186 | 00 Begane grond | no | yes | yes | 0 | Level : 0
5905151 | 1.04 | no | yes | no | 1 | Level : 1
6134567 | 0.44 | yes | yes | no | 0 | Level : 0

# IfcFurnishingElement: 00_DAT Vaste inrichting Keukenkasten hoog:Hogekast Lokaal 400B (6)
Type - Material: ISR_HPL Kleur hout
Type - Other - Category: Furniture; Family Name: 00_DAT Vaste inrichting Keukenkasten hoog
Type - Constraints - Default Elevation: 0 mm
Type - Dimensions - Breedte: 400 mm; Diepte Bovenkast: 350 mm; Diepte Kast: 600 mm; Hoogte: 2390 mm; Hoogte Bovenkast: 0 mm; Hoogte Bovenkast vanaf 0: 2390 mm; Hoogte Spatwand: 300 mm
Type - Division Geometry - 1/2 maat: 200 mm; x: 2700 mm; y: 0 mm; Z: 1120 mm
Type - Identity Data - Workset: Family : Furniture : 00_DAT Vaste inrichting Keukenkasten hoog; OmniClass Number: 23.40.20.00; OmniClass Title: General Furniture and Specialties; Type Name: Hogekast Lokaal 400B
Type - Materials and Finishes - Materiaal: ISR_HPL Kleur hout
Type - Pset_ProductRequirements - Category: Furniture
Pset_QuantityTakeOff - Reference: Hogekast Lokaal 400B
Other - Links: yes; Boven klep: no; Boven Links: no; Boven Rechts: no; Bovenkast: no; Rechts: no; Family: 00_DAT Vaste inrichting Keukenkasten hoog; Family and Type: 00_DAT Vaste inrichting Keukenkasten hoog: Hogekast Lokaal 400B; Type: Hogekast Lokaal 400B; Type Id: 5844316
Constraints - Elevation from Level: 0 mm; Moves With Nearby Elements: no; Offset from Host: 0 mm
Dimensions - Area: 2.625 m2; Volume: 0.5716 m3
Identity Data - Workset: Bouwkundig
Phasing - Phase Created: 2. nieuwbouw
Name (00_DAT Vaste inrichting Keukenkasten hoog:Hogekast Lokaal 400B:...) | In | Level | Host | Group
5846868 | 0.35 | 0 | Level : 0 | Model Group:Pantrie onderbouw:5846863
5846875 | 1.21 | 1 | Level : 1 | Model Group:Pantrie Middenbouw:5846870
5912808 | 1.22 | 1 | Level : 1 | Model Group:Pantrie Middenbouw:5912805
5912821 | 1.23 | 1 | Level : 1 | Model Group:Pantrie Middenbouw:5912818
5983577 | 0.36 | 0 | Level : 0 | Model Group:Pantrie onderbouw:5983574
5983592 | 0.37 | 0 | Level : 0 | Model Group:Pantrie onderbouw:5983589

# IfcFurnishingElement: 00_DAT Vaste inrichting Keukenkasten hoog:Hogekast Lokaal 600B (8)
In: 1.10
Type - Material: ISR_RAL 9010
Type - Other - Category: Furniture; Family Name: 00_DAT Vaste inrichting Keukenkasten hoog
Type - Constraints - Default Elevation: 0 mm
Type - Dimensions - Hoogte Bovenkast: 0 mm; Breedte: 600 mm; Diepte Bovenkast: 350 mm; Diepte Kast: 600 mm; Hoogte: 2390 mm; Hoogte Bovenkast vanaf 0: 2390 mm; Hoogte Spatwand: 300 mm
Type - Division Geometry - y: 0 mm; 1/2 maat: 300 mm; x: 2700 mm; Z: 1120 mm
Type - Identity Data - Workset: Family : Furniture : 00_DAT Vaste inrichting Keukenkasten hoog; OmniClass Number: 23.40.20.00; OmniClass Title: General Furniture and Specialties; Type Name: Hogekast Lokaal 600B
Type - Pset_ProductRequirements - Category: Furniture
Pset_QuantityTakeOff - Reference: Hogekast Lokaal 600B
Other - Boven Links: no; Boven Rechts: no; Boven klep: yes; Bovenkast: yes; Family: 00_DAT Vaste inrichting Keukenkasten hoog; Family and Type: 00_DAT Vaste inrichting Keukenkasten hoog: Hogekast Lokaal 600B; Type: Hogekast Lokaal 600B; Type Id: 5841196
Constraints - Elevation from Level: 0 mm; Moves With Nearby Elements: no; Offset from Host: 0 mm; Level: 1; Host: Level : 1
Dimensions - Area: 3.223 m2; Volume: 0.8574 m3
Identity Data - Workset: Bouwkundig
Phasing - Phase Created: 2. nieuwbouw
Name (00_DAT Vaste inrichting Keukenkasten hoog:Hogekast Lokaal 600B:...) | Links | Rechts
5910214 | yes | no
5910215 | no | yes
5910423 | yes | no
5910424 | no | yes
5910434 | yes | no
5910435 | no | yes
5910445 | yes | no
5910446 | no | yes

# IfcFurnishingElement: 00_DAT Vaste inrichting Keukenkasten hoog:Hogekast Lokaal 600B 22 (2)
In: 0.33
Type - Material: ISR_RAL 9010
Type - Other - Category: Furniture; Family Name: 00_DAT Vaste inrichting Keukenkasten hoog
Type - Constraints - Default Elevation: 0 mm
Type - Dimensions - Hoogte Bovenkast: 0 mm; Breedte: 600 mm; Diepte Bovenkast: 350 mm; Diepte Kast: 600 mm; Hoogte: 2100 mm; Hoogte Bovenkast vanaf 0: 2100 mm; Hoogte Spatwand: 300 mm
Type - Division Geometry - y: 0 mm; 1/2 maat: 300 mm; x: 2700 mm; Z: 975 mm
Type - Identity Data - Workset: Family : Furniture : 00_DAT Vaste inrichting Keukenkasten hoog; OmniClass Number: 23.40.20.00; OmniClass Title: General Furniture and Specialties; Type Name: Hogekast Lokaal 600B 22
Type - Pset_ProductRequirements - Category: Furniture
Pset_QuantityTakeOff - Reference: Hogekast Lokaal 600B 22
Other - Boven Links: no; Boven Rechts: no; Boven klep: yes; Bovenkast: yes; Family: 00_DAT Vaste inrichting Keukenkasten hoog; Family and Type: 00_DAT Vaste inrichting Keukenkasten hoog: Hogekast Lokaal 600B 22; Type: Hogekast Lokaal 600B 22; Type Id: 6732193
Constraints - Elevation from Level: 0 mm; Level: 0; Moves With Nearby Elements: no; Offset from Host: 0 mm; Host: Level : 0
Dimensions - Area: 2.875 m2; Volume: 0.753 m3
Identity Data - Workset: Bouwkundig
Phasing - Phase Created: 2. nieuwbouw
Name (00_DAT Vaste inrichting Keukenkasten hoog:Hogekast Lokaal 600B 22:...) | Links | Rechts
5864014 | yes | no
5864015 | no | yes

# IfcFurnishingElement: 00_DAT Vaste inrichting Keukenkasten hoog:Hogekast Lokaal 675B (4)
Type - Material: ISR_HPL Kleur hout
Type - Other - Category: Furniture; Family Name: 00_DAT Vaste inrichting Keukenkasten hoog
Type - Constraints - Default Elevation: 0 mm
Type - Dimensions - Hoogte Bovenkast: 0 mm; Breedte: 675 mm; Diepte Bovenkast: 350 mm; Diepte Kast: 600 mm; Hoogte: 2390 mm; Hoogte Bovenkast vanaf 0: 2390 mm; Hoogte Spatwand: 300 mm
Type - Division Geometry - y: 0 mm; 1/2 maat: 337.5 mm; x: 2700 mm; Z: 1120 mm
Type - Identity Data - Workset: Family : Furniture : 00_DAT Vaste inrichting Keukenkasten hoog; OmniClass Number: 23.40.20.00; OmniClass Title: General Furniture and Specialties; Type Name: Hogekast Lokaal 675B
Type - Materials and Finishes - Materiaal: ISR_HPL Kleur hout
Type - Pset_ProductRequirements - Category: Furniture
Pset_QuantityTakeOff - Reference: Hogekast Lokaal 675B
Other - Links: yes; Boven Links: no; Boven Rechts: no; Rechts: no; Boven klep: yes; Bovenkast: yes; Family: 00_DAT Vaste inrichting Keukenkasten hoog; Family and Type: 00_DAT Vaste inrichting Keukenkasten hoog: Hogekast Lokaal 675B; Type: Hogekast Lokaal 675B; Type Id: 6268540
Constraints - Elevation from Level: 0 mm; Moves With Nearby Elements: no; Offset from Host: 0 mm; Level: 1; Host: Level : 1
Dimensions - Area: 3.44725 m2; Volume: 0.964575 m3
Identity Data - Workset: Bouwkundig
Phasing - Phase Created: 2. nieuwbouw
Name (00_DAT Vaste inrichting Keukenkasten hoog:Hogekast Lokaal 675B:...) | In | Group
6023157 | 1.03 | Model Group:Pantry lokaal boven 2:5977383
6023173 | 1.02 | Model Group:Pantry lokaal boven 2:5988671
6269194 | 1.01 | Model Group:Pantrie lokaal Boven:5901741
6269307 | 1.04 | Model Group:Pantrie lokaal Boven:5901934

# IfcFurnishingElement: 00_DAT Vaste inrichting Keukenkasten hoog:Hogekast kastenwand 115B, 00_DAT Vaste inrichting Keukenkasten hoog:Hogekast kastenwand 115B:6531498
In: 0.15a
Type - Material: ISR_RAL 9010
Type - Other - Category: Furniture; Family Name: 00_DAT Vaste inrichting Keukenkasten hoog
Type - Constraints - Default Elevation: 0 mm
Type - Dimensions - Hoogte Bovenkast: 0 mm; Breedte: 115 mm; Diepte Bovenkast: 350 mm; Diepte Kast: 350 mm; Hoogte: 2640 mm; Hoogte Bovenkast vanaf 0: 2640 mm; Hoogte Spatwand: 300 mm
Type - Division Geometry - y: 0 mm; 1/2 maat: 57.5 mm; x: 2700 mm; Z: 1245 mm
Type - Identity Data - Workset: Family : Furniture : 00_DAT Vaste inrichting Keukenkasten hoog; OmniClass Number: 23.40.20.00; OmniClass Title: General Furniture and Specialties; Type Name: Hogekast kastenwand 115B
Type - Pset_ProductRequirements - Category: Furniture
Pset_QuantityTakeOff - Reference: Hogekast kastenwand 115B
Other - Boven klep: no; Boven Links: no; Boven Rechts: no; Links: no; Bovenkast: no; Rechts: no; Family: 00_DAT Vaste inrichting Keukenkasten hoog; Family and Type: 00_DAT Vaste inrichting Keukenkasten hoog: Hogekast kastenwand 115B; Type: Hogekast kastenwand 115B; Type Id: 6534307
Constraints - Elevation from Level: 0 mm; Level: 0; Moves With Nearby Elements: no; Offset from Host: 0 mm; Host: Level : 0
Dimensions - Area: 1.26285 m2; Volume: 0.105685 m3
Identity Data - Workset: Bouwkundig
Phasing - Phase Created: 2. nieuwbouw
Group: Model Group:Kastenwand:5849908

# IfcFurnishingElement: 00_DAT Vaste inrichting Keukenkasten hoog:Hogekast kastenwand 220B, 00_DAT Vaste inrichting Keukenkasten hoog:Hogekast kastenwand 220B:6531324
In: 0.15a
Type - Material: ISR_RAL 9010
Type - Other - Category: Furniture; Family Name: 00_DAT Vaste inrichting Keukenkasten hoog
Type - Constraints - Default Elevation: 0 mm
Type - Dimensions - Hoogte Bovenkast: 0 mm; Breedte: 225 mm; Diepte Bovenkast: 350 mm; Diepte Kast: 350 mm; Hoogte: 2640 mm; Hoogte Bovenkast vanaf 0: 2640 mm; Hoogte Spatwand: 300 mm
Type - Division Geometry - y: 0 mm; 1/2 maat: 112.5 mm; x: 2700 mm; Z: 1245 mm
Type - Identity Data - Workset: Family : Furniture : 00_DAT Vaste inrichting Keukenkasten hoog; OmniClass Number: 23.40.20.00; OmniClass Title: General Furniture and Specialties; Type Name: Hogekast kastenwand 220B
Type - Pset_ProductRequirements - Category: Furniture
Pset_QuantityTakeOff - Reference: Hogekast kastenwand 220B
Other - Boven klep: no; Boven Links: no; Boven Rechts: no; Links: no; Bovenkast: no; Rechts: no; Family: 00_DAT Vaste inrichting Keukenkasten hoog; Family and Type: 00_DAT Vaste inrichting Keukenkasten hoog: Hogekast kastenwand 220B; Type: Hogekast kastenwand 220B; Type Id: 6531347
Constraints - Elevation from Level: 0 mm; Level: 0; Moves With Nearby Elements: no; Offset from Host: 0 mm; Host: Level : 0
Dimensions - Area: 1.59175 m2; Volume: 0.206775 m3
Identity Data - Workset: Bouwkundig
Phasing - Phase Created: 2. nieuwbouw
Group: Model Group:Kastenwand:5849908

# IfcFurnishingElement: 00_DAT Vaste inrichting Keukenkasten hoog:Hogekast kastenwand 370 (2)
In: 0.15a
Type - Material: ISR_RAL 9010
Type - Other - Category: Furniture; Family Name: 00_DAT Vaste inrichting Keukenkasten hoog
Type - Constraints - Default Elevation: 0 mm
Type - Dimensions - Hoogte Bovenkast: 0 mm; Breedte: 370 mm; Diepte Bovenkast: 350 mm; Diepte Kast: 350 mm; Hoogte: 2640 mm; Hoogte Bovenkast vanaf 0: 2640 mm; Hoogte Spatwand: 300 mm
Type - Division Geometry - y: 0 mm; 1/2 maat: 185 mm; x: 2700 mm; Z: 1245 mm
Type - Identity Data - Workset: Family : Furniture : 00_DAT Vaste inrichting Keukenkasten hoog; OmniClass Number: 23.40.20.00; OmniClass Title: General Furniture and Specialties; Type Name: Hogekast kastenwand 370
Type - Pset_ProductRequirements - Category: Furniture
Pset_QuantityTakeOff - Reference: Hogekast kastenwand 370
Other - Boven klep: no; Boven Links: no; Boven Rechts: no; Links: no; Rechts: no; Family: 00_DAT Vaste inrichting Keukenkasten hoog; Family and Type: 00_DAT Vaste inrichting Keukenkasten hoog: Hogekast kastenwand 370; Type: Hogekast kastenwand 370; Type Id: 5849592
Constraints - Elevation from Level: 0 mm; Level: 0; Moves With Nearby Elements: no; Offset from Host: 0 mm; Host: Level : 0
Dimensions - Area: 2.0253 m2; Volume: 0.34003 m3
Identity Data - Workset: Bouwkundig
Phasing - Phase Created: 2. nieuwbouw
Group: Model Group:Kastenwand:5849908
Name (00_DAT Vaste inrichting Keukenkasten hoog:Hogekast kastenwand 370:...) | Bovenkast
5849627 | no
5850150 | yes

# IfcFurnishingElement: 00_DAT Vaste inrichting Keukenkasten hoog:Hogekast kastenwand 510B (2)
In: 0.15a
Type - Material: ISR_RAL 9010
Type - Other - Category: Furniture; Family Name: 00_DAT Vaste inrichting Keukenkasten hoog
Type - Constraints - Default Elevation: 0 mm
Type - Dimensions - Hoogte Bovenkast: 0 mm; Breedte: 510 mm; Diepte Bovenkast: 350 mm; Diepte Kast: 350 mm; Hoogte: 2640 mm; Hoogte Bovenkast vanaf 0: 2640 mm; Hoogte Spatwand: 300 mm
Type - Division Geometry - y: 0 mm; 1/2 maat: 255 mm; x: 2700 mm; Z: 1245 mm
Type - Identity Data - Workset: Family : Furniture : 00_DAT Vaste inrichting Keukenkasten hoog; OmniClass Number: 23.40.20.00; OmniClass Title: General Furniture and Specialties; Type Name: Hogekast kastenwand 510B
Type - Pset_ProductRequirements - Category: Furniture
Pset_QuantityTakeOff - Reference: Hogekast kastenwand 510B
Other - Boven klep: no; Boven Links: no; Boven Rechts: no; Links: no; Rechts: no; Family: 00_DAT Vaste inrichting Keukenkasten hoog; Family and Type: 00_DAT Vaste inrichting Keukenkasten hoog: Hogekast kastenwand 510B; Type: Hogekast kastenwand 510B; Type Id: 5849824
Constraints - Elevation from Level: 0 mm; Level: 0; Moves With Nearby Elements: no; Offset from Host: 0 mm; Host: Level : 0
Dimensions - Area: 2.4439 m2; Volume: 0.46869 m3
Identity Data - Workset: Bouwkundig
Phasing - Phase Created: 2. nieuwbouw
Group: Model Group:Kastenwand:5849908
Name (00_DAT Vaste inrichting Keukenkasten hoog:Hogekast kastenwand 510B:...) | Bovenkast
5849851 | no
5850153 | yes

# IfcFurnishingElement: 00_DAT Vaste inrichting Keukenkasten hoog:Hogekast kastenwand 790B (8)
In: 0.15a
Type - Material: ISR_RAL 9010
Type - Other - Category: Furniture; Family Name: 00_DAT Vaste inrichting Keukenkasten hoog
Type - Constraints - Default Elevation: 0 mm
Type - Dimensions - Hoogte Bovenkast: 0 mm; Breedte: 790 mm; Diepte Bovenkast: 350 mm; Diepte Kast: 350 mm; Hoogte: 2640 mm; Hoogte Bovenkast vanaf 0: 2640 mm; Hoogte Spatwand: 300 mm
Type - Division Geometry - y: 0 mm; 1/2 maat: 395 mm; x: 2700 mm; Z: 1245 mm
Type - Identity Data - Workset: Family : Furniture : 00_DAT Vaste inrichting Keukenkasten hoog; OmniClass Number: 23.40.20.00; OmniClass Title: General Furniture and Specialties; Type Name: Hogekast kastenwand 790B
Type - Pset_ProductRequirements - Category: Furniture
Pset_QuantityTakeOff - Reference: Hogekast kastenwand 790B
Other - Boven klep: no; Boven Links: no; Boven Rechts: no; Bovenkast: yes; Family: 00_DAT Vaste inrichting Keukenkasten hoog; Family and Type: 00_DAT Vaste inrichting Keukenkasten hoog: Hogekast kastenwand 790B; Type: Hogekast kastenwand 790B; Type Id: 5849347
Constraints - Elevation from Level: 0 mm; Level: 0; Moves With Nearby Elements: no; Offset from Host: 0 mm; Host: Level : 0
Dimensions - Area: 3.2811 m2; Volume: 0.72601 m3
Identity Data - Workset: Bouwkundig
Phasing - Phase Created: 2. nieuwbouw
Group: Model Group:Kastenwand:5849908
Name (00_DAT Vaste inrichting Keukenkasten hoog:Hogekast kastenwand 790B:...) | Rechts | Links
5849997 | yes | no
5850013 | yes | no
5850021 | no | yes
5850220 | yes | no
5850221 | no | yes
5850222 | yes | no
5850223 | no | yes
6231324 | no | yes

# IfcFurnishingElement: 00_DAT Vaste inrichting Keukenkasten hoog:Hogekast kastenwand 795 (7)
In: 0.15a
Type - Material: ISR_RAL 9010
Type - Other - Category: Furniture; Family Name: 00_DAT Vaste inrichting Keukenkasten hoog
Type - Constraints - Default Elevation: 0 mm
Type - Dimensions - Hoogte Bovenkast: 0 mm; Breedte: 795 mm; Diepte Bovenkast: 350 mm; Diepte Kast: 350 mm; Hoogte: 2640 mm; Hoogte Bovenkast vanaf 0: 2640 mm; Hoogte Spatwand: 300 mm
Type - Division Geometry - y: 0 mm; 1/2 maat: 397.5 mm; x: 2700 mm; Z: 1245 mm
Type - Identity Data - Workset: Family : Furniture : 00_DAT Vaste inrichting Keukenkasten hoog; OmniClass Number: 23.40.20.00; OmniClass Title: General Furniture and Specialties; Type Name: Hogekast kastenwand 795
Type - Pset_ProductRequirements - Category: Furniture
Pset_QuantityTakeOff - Reference: Hogekast kastenwand 795
Other - Links: yes; Boven klep: no; Boven Links: no; Boven Rechts: no; Rechts: no; Bovenkast: yes; Family: 00_DAT Vaste inrichting Keukenkasten hoog; Family and Type: 00_DAT Vaste inrichting Keukenkasten hoog: Hogekast kastenwand 795; Type: Hogekast kastenwand 795; Type Id: 6535067
Constraints - Elevation from Level: 0 mm; Level: 0; Moves With Nearby Elements: no; Offset from Host: 0 mm; Host: Level : 0
Dimensions - Area: 3.29605 m2; Volume: 0.730605 m3
Identity Data - Workset: Bouwkundig
Phasing - Phase Created: 2. nieuwbouw
Group: Model Group:Kastenwand:5849908
Name (00_DAT Vaste inrichting Keukenkasten hoog:Hogekast kastenwand 795:...)
5849518
5849960
5850029
5850149
5850219
5850224
5850276

# IfcFurnishingElement: 00_DAT Vaste inrichting Keukenkasten hoog:Plaat hoge kast (4)
Type - Material: ISR_HPL Kleur hout
Type - Other - Category: Furniture; Family Name: 00_DAT Vaste inrichting Keukenkasten hoog
Type - Constraints - Default Elevation: 0 mm
Type - Dimensions - Hoogte Bovenkast: 0 mm; Breedte: 226 mm; Diepte Bovenkast: 350 mm; Diepte Kast: 300 mm; Hoogte: 2390 mm; Hoogte Bovenkast vanaf 0: 2390 mm; Hoogte Spatwand: 300 mm
Type - Division Geometry - y: 0 mm; 1/2 maat: 113 mm; x: 2700 mm; Z: 1120 mm
Type - Identity Data - Workset: Family : Furniture : 00_DAT Vaste inrichting Keukenkasten hoog; OmniClass Number: 23.40.20.00; OmniClass Title: General Furniture and Specialties; Type Name: Plaat hoge kast
Type - Materials and Finishes - Materiaal: ISR_HPL Kleur hout
Type - Pset_ProductRequirements - Category: Furniture
Pset_QuantityTakeOff - Reference: Plaat hoge kast
Other - Boven Links: no; Boven Rechts: no; Links: no; Rechts: no; Boven klep: yes; Bovenkast: yes; Family: 00_DAT Vaste inrichting Keukenkasten hoog; Family and Type: 00_DAT Vaste inrichting Keukenkasten hoog: Plaat hoge kast; Type: Plaat hoge kast; Type Id: 6268682
Constraints - Elevation from Level: 0 mm; Moves With Nearby Elements: no; Offset from Host: 0 mm; Level: 1; Host: Level : 1
Dimensions - Area: 1.31994 m2; Volume: 0.160912 m3
Identity Data - Workset: Bouwkundig
Phasing - Phase Created: 2. nieuwbouw
Name (00_DAT Vaste inrichting Keukenkasten hoog:Plaat hoge kast:...) | In | Group
6268659 | 1.03 | Model Group:Pantry lokaal boven 2:5977383
6268808 | 1.02 | Model Group:Pantry lokaal boven 2:5988671
6269195 | 1.01 | Model Group:Pantrie lokaal Boven:5901741
6269308 | 1.04 | Model Group:Pantrie lokaal Boven:5901934

# IfcFurnishingElement: 00_DAT Vaste inrichting Keukenkasten hoog:lagekast kastenwand 1020B (6)
In: 0.15a
Type - Material: ISR_RAL 9010
Type - Other - Category: Furniture; Family Name: 00_DAT Vaste inrichting Keukenkasten hoog
Type - Constraints - Default Elevation: 0 mm
Type - Dimensions - Hoogte Bovenkast: 0 mm; Breedte: 1020 mm; Diepte Bovenkast: 350 mm; Diepte Kast: 350 mm; Hoogte: 730 mm; Hoogte Bovenkast vanaf 0: 730 mm; Hoogte Spatwand: 300 mm
Type - Division Geometry - y: 0 mm; 1/2 maat: 510 mm; x: 2700 mm; Z: 290 mm
Type - Identity Data - Workset: Family : Furniture : 00_DAT Vaste inrichting Keukenkasten hoog; OmniClass Number: 23.40.20.00; OmniClass Title: General Furniture and Specialties; Type Name: lagekast kastenwand 1020B
Type - Pset_ProductRequirements - Category: Furniture
Pset_QuantityTakeOff - Reference: lagekast kastenwand 1020B
Other - Boven klep: no; Boven Links: no; Boven Rechts: no; Bovenkast: no; Family: 00_DAT Vaste inrichting Keukenkasten hoog; Family and Type: 00_DAT Vaste inrichting Keukenkasten hoog: lagekast kastenwand 1020B; Type: lagekast kastenwand 1020B; Type Id: 5849362
Constraints - Elevation from Level: 0 mm; Level: 0; Moves With Nearby Elements: no; Offset from Host: 0 mm; Host: Level : 0
Dimensions - Area: 1.3521 m2; Volume: 0.25551 m3
Identity Data - Workset: Bouwkundig
Phasing - Phase Created: 2. nieuwbouw
Group: Model Group:Kastenwand:5849908
Name (00_DAT Vaste inrichting Keukenkasten hoog:lagekast kastenwand 1020B:...) | Links | Rechts
5849395 | yes | no
5849460 | no | yes
5850147 | yes | no
5850148 | no | yes
5850274 | yes | no
5850275 | no | yes

# IfcFurnishingElement: 00_DAT Vaste inrichting Keukenkasten hoog:lagekast kastenwand 880B (4)
In: 0.15a
Type - Material: ISR_RAL 9010
Type - Other - Category: Furniture; Family Name: 00_DAT Vaste inrichting Keukenkasten hoog
Type - Constraints - Default Elevation: 0 mm
Type - Dimensions - Hoogte Bovenkast: 0 mm; Breedte: 880 mm; Diepte Bovenkast: 350 mm; Diepte Kast: 350 mm; Hoogte: 730 mm; Hoogte Bovenkast vanaf 0: 730 mm; Hoogte Spatwand: 300 mm
Type - Division Geometry - y: 0 mm; 1/2 maat: 440 mm; x: 2700 mm; Z: 290 mm
Type - Identity Data - Workset: Family : Furniture : 00_DAT Vaste inrichting Keukenkasten hoog; OmniClass Number: 23.40.20.00; OmniClass Title: General Furniture and Specialties; Type Name: lagekast kastenwand 880B
Type - Pset_ProductRequirements - Category: Furniture
Pset_QuantityTakeOff - Reference: lagekast kastenwand 880B
Other - Boven klep: no; Boven Links: no; Boven Rechts: no; Bovenkast: no; Family: 00_DAT Vaste inrichting Keukenkasten hoog; Family and Type: 00_DAT Vaste inrichting Keukenkasten hoog: lagekast kastenwand 880B; Type: lagekast kastenwand 880B; Type Id: 5849705
Constraints - Elevation from Level: 0 mm; Level: 0; Moves With Nearby Elements: no; Offset from Host: 0 mm; Host: Level : 0
Dimensions - Area: 1.2009 m2; Volume: 0.22044 m3
Identity Data - Workset: Bouwkundig
Phasing - Phase Created: 2. nieuwbouw
Group: Model Group:Kastenwand:5849908
Name (00_DAT Vaste inrichting Keukenkasten hoog:lagekast kastenwand 880B:...) | Links | Rechts
5849731 | yes | no
5849757 | no | yes
5850151 | yes | no
5850152 | no | yes

# IfcFurnishingElement: 00_DAT Vaste inrichting Keukenkasten:Kast met Bovenkast 120 B675 (12)
Type - Material: ISR_HPL Kleur hout
Type - Other - Category: Furniture; Bovenkast: yes; Family Name: 00_DAT Vaste inrichting Keukenkasten
Type - Constraints - Default Elevation: 0 mm
Type - Dimensions - 1/2 maat: 337.5 mm; Breedte: 675 mm; Diepte Bovenkast: 350 mm; Hoogte: 1200 mm; Hoogte Bovenkast: 590 mm; Hoogte Bovenkast vanaf 0: 1800 mm; Hoogte Spatwand: 600 mm; Plint: 100 mm; x: 1800 mm; y: 295 mm; Z: 630 mm
Type - Identity Data - Workset: Family : Furniture : 00_DAT Vaste inrichting Keukenkasten; OmniClass Number: 23.40.20.00; OmniClass Title: General Furniture and Specialties; Type Name: Kast met Bovenkast 120 B675
Type - Pset_ProductRequirements - Category: Furniture
Pset_QuantityTakeOff - Reference: Kast met Bovenkast 120 B675
Other - Boven klep: no; Family: 00_DAT Vaste inrichting Keukenkasten; Klep: no; Kookplaat: no; Lade: no; Wasbak: no; Family and Type: 00_DAT Vaste inrichting Keukenkasten: Kast met Bovenkast 120 B675; Spatwand: no; Type: Kast met Bovenkast 120 B675; Type Id: 5862070
Constraints - Elevation from Level: 0 mm; Moves With Nearby Elements: no; Offset from Host: 0 mm
Dimensions - Area: 3.66268 m2; Volume: 0.623001 m3
Identity Data - Workset: Bouwkundig
Materials and Finishes - Materiaal: ISR_HPL Kleur hout
Phasing - Phase Created: 2. nieuwbouw
Visibility - Klep visible: no; Lade visible: no
Name (00_DAT Vaste inrichting Keukenkasten:Kast met Bovenkast 120 B675:...) | In | Links = Boven Links = Links visible | Boven Rechts = Rechts = Rechts visible | Level | Host | Group
5846867 | 0.35 | yes | no | 0 | Level : 0 | Model Group:Pantrie onderbouw:5846863
5846874 | 1.21 | yes | no | 1 | Level : 1 | Model Group:Pantrie Middenbouw:5846870
5862140 | 0.35 | no | yes | 0 | Level : 0 | Model Group:Pantrie onderbouw:5846863
5862322 | 1.21 | no | yes | 1 | Level : 1 | Model Group:Pantrie Middenbouw:5846870
5912807 | 1.22 | yes | no | 1 | Level : 1 | Model Group:Pantrie Middenbouw:5912805
5912809 | 1.22 | no | yes | 1 | Level : 1 | Model Group:Pantrie Middenbouw:5912805
5912820 | 1.23 | yes | no | 1 | Level : 1 | Model Group:Pantrie Middenbouw:5912818
5912822 | 1.23 | no | yes | 1 | Level : 1 | Model Group:Pantrie Middenbouw:5912818
5983576 | 0.36 | yes | no | 0 | Level : 0 | Model Group:Pantrie onderbouw:5983574
5983578 | 0.36 | no | yes | 0 | Level : 0 | Model Group:Pantrie onderbouw:5983574
5983591 | 0.37 | yes | no | 0 | Level : 0 | Model Group:Pantrie onderbouw:5983589
5983593 | 0.37 | no | yes | 0 | Level : 0 | Model Group:Pantrie onderbouw:5983589

# IfcFurnishingElement: 00_DAT Vaste inrichting Keukenkasten:Kast met Bovenkast 600, 00_DAT Vaste inrichting Keukenkasten:Kast met Bovenkast 600:5863058
In: 0.28
Type - Material: ISR_HPL Kleur hout
Type - Other - Category: Furniture; Bovenkast: yes; Family Name: 00_DAT Vaste inrichting Keukenkasten
Type - Constraints - Default Elevation: 0 mm
Type - Dimensions - 1/2 maat: 300 mm; Breedte: 600 mm; Diepte Bovenkast: 350 mm; Hoogte: 650 mm; Hoogte Bovenkast: 890 mm; Hoogte Bovenkast vanaf 0: 1500 mm; Hoogte Spatwand: 850 mm; Plint: 100 mm; x: 1500 mm; y: 445 mm; Z: 355 mm
Type - Identity Data - Workset: Family : Furniture : 00_DAT Vaste inrichting Keukenkasten; OmniClass Number: 23.40.20.00; OmniClass Title: General Furniture and Specialties; Type Name: Kast met Bovenkast 600
Type - Pset_ProductRequirements - Category: Furniture
Pset_QuantityTakeOff - Reference: Kast met Bovenkast 600
Other - Rechts: yes; Boven klep: no; Boven Links: no; Family: 00_DAT Vaste inrichting Keukenkasten; Klep: no; Kookplaat: no; Lade: no; Links: no; Spatwand: yes; Wasbak: no; Boven Rechts: yes; Family and Type: 00_DAT Vaste inrichting Keukenkasten: Kast met Bovenkast 600; Type: Kast met Bovenkast 600; Type Id: 5841616
Constraints - Elevation from Level: 0 mm; Level: 0; Moves With Nearby Elements: no; Offset from Host: 0 mm; Host: Level : 0
Dimensions - Area: 3.14918 m2; Volume: 0.423931 m3
Identity Data - Workset: Bouwkundig
Materials and Finishes - Materiaal: ISR_HPL Kleur hout
Phasing - Phase Created: 2. nieuwbouw
Visibility - Klep visible: no; Lade visible: no; Links visible: no; Rechts visible: yes

# IfcFurnishingElement: 00_DAT Vaste inrichting Keukenkasten:Kast met Bovenkast 600, 00_DAT Vaste inrichting Keukenkasten:Kast met Bovenkast 600:5863625
In: 0.28
Type - Material: NBS_VilleroyAndBochAG_Chrome, ISR_HPL Kleur hout
Type - Other - Category: Furniture; Bovenkast: yes; Family Name: 00_DAT Vaste inrichting Keukenkasten
Type - Constraints - Default Elevation: 0 mm
Type - Dimensions - 1/2 maat: 300 mm; Breedte: 600 mm; Diepte Bovenkast: 350 mm; Hoogte: 650 mm; Hoogte Bovenkast: 890 mm; Hoogte Bovenkast vanaf 0: 1500 mm; Hoogte Spatwand: 850 mm; Plint: 100 mm; x: 1500 mm; y: 445 mm; Z: 355 mm
Type - Identity Data - Workset: Family : Furniture : 00_DAT Vaste inrichting Keukenkasten; OmniClass Number: 23.40.20.00; OmniClass Title: General Furniture and Specialties; Type Name: Kast met Bovenkast 600
Type - Pset_ProductRequirements - Category: Furniture
Pset_QuantityTakeOff - Reference: Kast met Bovenkast 600
Other - Links: yes; Boven klep: no; Boven Rechts: no; Family: 00_DAT Vaste inrichting Keukenkasten; Klep: no; Kookplaat: no; Lade: no; Spatwand: yes; Rechts: no; Wasbak: yes; Boven Links: yes; Family and Type: 00_DAT Vaste inrichting Keukenkasten: Kast met Bovenkast 600; Type: Kast met Bovenkast 600; Type Id: 5841616
Constraints - Elevation from Level: 0 mm; Level: 0; Moves With Nearby Elements: no; Offset from Host: 0 mm; Host: Level : 0
Dimensions - Area: 3.40631 m2; Volume: 0.364575 m3
Identity Data - Workset: Bouwkundig
Materials and Finishes - Materiaal: ISR_HPL Kleur hout
Phasing - Phase Created: 2. nieuwbouw
Visibility - Klep visible: no; Lade visible: no; Links visible: yes; Rechts visible: no

# IfcFurnishingElement: 00_DAT Vaste inrichting Keukenkasten:Kast met Bovenkast B675 (3)
Type - Material: ISR_HPL Kleur hout
Type - Other - Category: Furniture; Bovenkast: yes; Family Name: 00_DAT Vaste inrichting Keukenkasten
Type - Constraints - Default Elevation: 0 mm
Type - Dimensions - 1/2 maat: 337.5 mm; Breedte: 675 mm; Diepte Bovenkast: 350 mm; Hoogte: 650 mm; Hoogte Bovenkast: 590 mm; Hoogte Bovenkast vanaf 0: 1800 mm; Hoogte Spatwand: 550 mm; Plint: 100 mm; x: 1200 mm; y: 295 mm; Z: 355 mm
Type - Identity Data - Workset: Family : Furniture : 00_DAT Vaste inrichting Keukenkasten; OmniClass Number: 23.40.20.00; OmniClass Title: General Furniture and Specialties; Type Name: Kast met Bovenkast B675
Type - Pset_ProductRequirements - Category: Furniture
Pset_QuantityTakeOff - Reference: Kast met Bovenkast B675
Other - Rechts: yes; Boven klep: no; Boven Links: no; Family: 00_DAT Vaste inrichting Keukenkasten; Klep: no; Kookplaat: no; Lade: no; Links: no; Spatwand: yes; Wasbak: no; Boven Rechts: yes; Family and Type: 00_DAT Vaste inrichting Keukenkasten: Kast met Bovenkast B675; Type: Kast met Bovenkast B675; Type Id: 5862163
Constraints - Elevation from Level: 0 mm; Level: 0; Moves With Nearby Elements: no; Offset from Host: 0 mm; Host: Level : 0
Dimensions - Area: 2.92718 m2; Volume: 0.403963 m3
Identity Data - Workset: Bouwkundig
Materials and Finishes - Materiaal: ISR_HPL Kleur hout
Phasing - Phase Created: 2. nieuwbouw
Visibility - Klep visible: no; Lade visible: no; Links visible: no; Rechts visible: yes
Name (00_DAT Vaste inrichting Keukenkasten:Kast met Bovenkast B675:...) | In | Group
5862242 | 0.35 | Model Group:Pantrie onderbouw:5846863
5983579 | 0.36 | Model Group:Pantrie onderbouw:5983574
5983594 | 0.37 | Model Group:Pantrie onderbouw:5983589

# IfcFurnishingElement: 00_DAT Vaste inrichting Keukenkasten:Kast met Bovenkast B675 (3)
Type - Material: NBS_VilleroyAndBochAG_Chrome, ISR_HPL Kleur hout
Type - Other - Category: Furniture; Bovenkast: yes; Family Name: 00_DAT Vaste inrichting Keukenkasten
Type - Constraints - Default Elevation: 0 mm
Type - Dimensions - 1/2 maat: 337.5 mm; Breedte: 675 mm; Diepte Bovenkast: 350 mm; Hoogte: 650 mm; Hoogte Bovenkast: 590 mm; Hoogte Bovenkast vanaf 0: 1800 mm; Hoogte Spatwand: 550 mm; Plint: 100 mm; x: 1200 mm; y: 295 mm; Z: 355 mm
Type - Identity Data - Workset: Family : Furniture : 00_DAT Vaste inrichting Keukenkasten; OmniClass Number: 23.40.20.00; OmniClass Title: General Furniture and Specialties; Type Name: Kast met Bovenkast B675
Type - Pset_ProductRequirements - Category: Furniture
Pset_QuantityTakeOff - Reference: Kast met Bovenkast B675
Other - Links: yes; Boven klep: no; Boven Rechts: no; Family: 00_DAT Vaste inrichting Keukenkasten; Klep: no; Kookplaat: no; Lade: no; Spatwand: yes; Rechts: no; Wasbak: yes; Boven Links: yes; Family and Type: 00_DAT Vaste inrichting Keukenkasten: Kast met Bovenkast B675; Type: Kast met Bovenkast B675; Type Id: 5862163
Constraints - Elevation from Level: 0 mm; Level: 0; Moves With Nearby Elements: no; Offset from Host: 0 mm; Host: Level : 0
Dimensions - Area: 3.20681 m2; Volume: 0.335607 m3
Identity Data - Workset: Bouwkundig
Materials and Finishes - Materiaal: ISR_HPL Kleur hout
Phasing - Phase Created: 2. nieuwbouw
Visibility - Klep visible: no; Lade visible: no; Links visible: yes; Rechts visible: no
Name (00_DAT Vaste inrichting Keukenkasten:Kast met Bovenkast B675:...) | In | Group
5846865 | 0.35 | Model Group:Pantrie onderbouw:5846863
5983575 | 0.36 | Model Group:Pantrie onderbouw:5983574
5983590 | 0.37 | Model Group:Pantrie onderbouw:5983589

# IfcFurnishingElement: 00_DAT Vaste inrichting Keukenkasten:Kast met Bovenkast B675 H850 (3)
Type - Material: ISR_HPL Kleur hout
Type - Other - Category: Furniture; Bovenkast: yes; Family Name: 00_DAT Vaste inrichting Keukenkasten
Type - Constraints - Default Elevation: 0 mm
Type - Dimensions - 1/2 maat: 337.5 mm; Breedte: 675 mm; Diepte Bovenkast: 350 mm; Hoogte: 850 mm; Hoogte Bovenkast: 590 mm; Hoogte Bovenkast vanaf 0: 1800 mm; Hoogte Spatwand: 350 mm; Plint: 100 mm; x: 1200 mm; y: 295 mm; Z: 455 mm
Type - Identity Data - Workset: Family : Furniture : 00_DAT Vaste inrichting Keukenkasten; OmniClass Number: 23.40.20.00; OmniClass Title: General Furniture and Specialties; Type Name: Kast met Bovenkast B675 H850
Type - Pset_ProductRequirements - Category: Furniture
Pset_QuantityTakeOff - Reference: Kast met Bovenkast B675 H850
Other - Rechts: yes; Boven klep: no; Boven Rechts: no; Family: 00_DAT Vaste inrichting Keukenkasten; Klep: no; Kookplaat: no; Lade: no; Links: no; Spatwand: yes; Wasbak: no; Boven Links: yes; Family and Type: 00_DAT Vaste inrichting Keukenkasten: Kast met Bovenkast B675 H850; Type: Kast met Bovenkast B675 H850; Type Id: 5912665
Constraints - Elevation from Level: 0 mm; Moves With Nearby Elements: no; Offset from Host: 0 mm; Level: 1; Host: Level : 1
Dimensions - Area: 3.04518 m2; Volume: 0.483613 m3
Identity Data - Workset: Bouwkundig
Materials and Finishes - Materiaal: ISR_HPL Kleur hout
Phasing - Phase Created: 2. nieuwbouw
Visibility - Klep visible: no; Lade visible: no; Links visible: no; Rechts visible: yes
Name (00_DAT Vaste inrichting Keukenkasten:Kast met Bovenkast B675 H850:...) | In | Group
5862323 | 1.21 | Model Group:Pantrie Middenbouw:5846870
5912810 | 1.22 | Model Group:Pantrie Middenbouw:5912805
5912823 | 1.23 | Model Group:Pantrie Middenbouw:5912818

# IfcFurnishingElement: 00_DAT Vaste inrichting Keukenkasten:Kast met Bovenkast B675 H850 (3)
Type - Material: NBS_VilleroyAndBochAG_Chrome, ISR_HPL Kleur hout
Type - Other - Category: Furniture; Bovenkast: yes; Family Name: 00_DAT Vaste inrichting Keukenkasten
Type - Constraints - Default Elevation: 0 mm
Type - Dimensions - 1/2 maat: 337.5 mm; Breedte: 675 mm; Diepte Bovenkast: 350 mm; Hoogte: 850 mm; Hoogte Bovenkast: 590 mm; Hoogte Bovenkast vanaf 0: 1800 mm; Hoogte Spatwand: 350 mm; Plint: 100 mm; x: 1200 mm; y: 295 mm; Z: 455 mm
Type - Identity Data - Workset: Family : Furniture : 00_DAT Vaste inrichting Keukenkasten; OmniClass Number: 23.40.20.00; OmniClass Title: General Furniture and Specialties; Type Name: Kast met Bovenkast B675 H850
Type - Pset_ProductRequirements - Category: Furniture
Pset_QuantityTakeOff - Reference: Kast met Bovenkast B675 H850
Other - Links: yes; Boven klep: no; Boven Rechts: no; Family: 00_DAT Vaste inrichting Keukenkasten; Klep: no; Kookplaat: no; Lade: no; Spatwand: yes; Rechts: no; Wasbak: yes; Boven Links: yes; Family and Type: 00_DAT Vaste inrichting Keukenkasten: Kast met Bovenkast B675 H850; Type: Kast met Bovenkast B675 H850; Type Id: 5912665
Constraints - Elevation from Level: 0 mm; Moves With Nearby Elements: no; Offset from Host: 0 mm; Level: 1; Host: Level : 1
Dimensions - Area: 3.32481 m2; Volume: 0.415257 m3
Identity Data - Workset: Bouwkundig
Materials and Finishes - Materiaal: ISR_HPL Kleur hout
Phasing - Phase Created: 2. nieuwbouw
Visibility - Klep visible: no; Lade visible: no; Links visible: yes; Rechts visible: no
Name (00_DAT Vaste inrichting Keukenkasten:Kast met Bovenkast B675 H850:...) | In | Group
5846872 | 1.21 | Model Group:Pantrie Middenbouw:5846870
5912806 | 1.22 | Model Group:Pantrie Middenbouw:5912805
5912819 | 1.23 | Model Group:Pantrie Middenbouw:5912818

# IfcFurnishingElement: 00_DAT Vaste inrichting Keukenkasten:Kast met Bovenkast Ont (3)
In: 0.44
Type - Material: ISR_RAL 9010
Type - Other - Category: Furniture; Bovenkast: yes; Family Name: 00_DAT Vaste inrichting Keukenkasten
Type - Constraints - Default Elevation: 0 mm
Type - Dimensions - 1/2 maat: 300 mm; Breedte: 600 mm; Diepte Bovenkast: 600 mm; Hoogte: 900 mm; Hoogte Bovenkast: 490 mm; Hoogte Bovenkast vanaf 0: 1900 mm; Hoogte Spatwand: 1000 mm; Plint: 100 mm; x: 1900 mm; y: 245 mm; Z: 480 mm
Type - Identity Data - Workset: Family : Furniture : 00_DAT Vaste inrichting Keukenkasten; OmniClass Number: 23.40.20.00; OmniClass Title: General Furniture and Specialties; Type Name: Kast met Bovenkast Ont
Type - Pset_ProductRequirements - Category: Furniture
Pset_QuantityTakeOff - Reference: Kast met Bovenkast Ont
Other - Boven Links: no; Boven Rechts: no; Family: 00_DAT Vaste inrichting Keukenkasten; Klep: no; Kookplaat: no; Lade: no; Spatwand: yes; Wasbak: no; Boven klep: yes; Family and Type: 00_DAT Vaste inrichting Keukenkasten: Kast met Bovenkast Ont; Type: Kast met Bovenkast Ont; Type Id: 6134596
Constraints - Elevation from Level: 0 mm; Level: 0; Moves With Nearby Elements: no; Offset from Host: 0 mm; Host: Level : 0
Dimensions - Area: 3.43318 m2; Volume: 0.504331 m3
Identity Data - Workset: Bouwkundig
Phasing - Phase Created: 2. nieuwbouw
Visibility - Klep visible: no; Lade visible: no
Name (00_DAT Vaste inrichting Keukenkasten:Kast met Bovenkast Ont:...) | Links = Links visible | Rechts = Rechts visible
5830259 | yes | no
5830511 | no | yes
5830517 | yes | no

# IfcFurnishingElement: 00_DAT Vaste inrichting Keukenkasten:Kast met Bovenkast bovenbouw (8)
Type - Material: ISR_HPL Kleur hout
Type - Other - Category: Furniture; Bovenkast: yes; Family Name: 00_DAT Vaste inrichting Keukenkasten
Type - Constraints - Default Elevation: 0 mm
Type - Dimensions - 1/2 maat: 367.5 mm; Breedte: 735 mm; Diepte Bovenkast: 350 mm; Hoogte: 850 mm; Hoogte Bovenkast: 590 mm; Hoogte Bovenkast vanaf 0: 1800 mm; Hoogte Spatwand: 350 mm; Plint: 100 mm; x: 1200 mm; y: 295 mm; Z: 455 mm
Type - Identity Data - Workset: Family : Furniture : 00_DAT Vaste inrichting Keukenkasten; OmniClass Number: 23.40.20.00; OmniClass Title: General Furniture and Specialties; Type Name: Kast met Bovenkast bovenbouw
Type - Pset_ProductRequirements - Category: Furniture
Pset_QuantityTakeOff - Reference: Kast met Bovenkast bovenbouw
Other - Boven klep: no; Family: 00_DAT Vaste inrichting Keukenkasten; Klep: no; Kookplaat: no; Lade: no; Spatwand: yes; Wasbak: no; Family and Type: 00_DAT Vaste inrichting Keukenkasten: Kast met Bovenkast bovenbouw; Type: Kast met Bovenkast bovenbouw; Type Id: 5840733
Constraints - Elevation from Level: 0 mm; Moves With Nearby Elements: no; Offset from Host: 0 mm; Level: 1; Host: Level : 1
Dimensions - Area: 3.24198 m2; Volume: 0.526559 m3
Identity Data - Workset: Bouwkundig
Materials and Finishes - Materiaal: ISR_HPL Kleur hout
Phasing - Phase Created: 2. nieuwbouw
Visibility - Klep visible: no; Lade visible: no
Name (00_DAT Vaste inrichting Keukenkasten:Kast met Bovenkast bovenbouw:...) | In | Rechts = Boven Rechts = Rechts visible | Boven Links = Links = Links visible | Group
5899888 | 1.03 | yes | no | Model Group:Pantry lokaal boven 2:5977383
5900739 | 1.03 | no | yes | Model Group:Pantry lokaal boven 2:5977383
5901743 | 1.01 | yes | no | Model Group:Pantrie lokaal Boven:5901741
5901745 | 1.01 | no | yes | Model Group:Pantrie lokaal Boven:5901741
5901936 | 1.04 | yes | no | Model Group:Pantrie lokaal Boven:5901934
5901938 | 1.04 | no | yes | Model Group:Pantrie lokaal Boven:5901934
5988673 | 1.02 | yes | no | Model Group:Pantry lokaal boven 2:5988671
5988675 | 1.02 | no | yes | Model Group:Pantry lokaal boven 2:5988671

# IfcFurnishingElement: 00_DAT Vaste inrichting Keukenkasten:Kast met Bovenkast bovenbouw (4)
Type - Material: NBS_VilleroyAndBochAG_Chrome, ISR_HPL Kleur hout
Type - Other - Category: Furniture; Bovenkast: yes; Family Name: 00_DAT Vaste inrichting Keukenkasten
Type - Constraints - Default Elevation: 0 mm
Type - Dimensions - 1/2 maat: 367.5 mm; Breedte: 735 mm; Diepte Bovenkast: 350 mm; Hoogte: 850 mm; Hoogte Bovenkast: 590 mm; Hoogte Bovenkast vanaf 0: 1800 mm; Hoogte Spatwand: 350 mm; Plint: 100 mm; x: 1200 mm; y: 295 mm; Z: 455 mm
Type - Identity Data - Workset: Family : Furniture : 00_DAT Vaste inrichting Keukenkasten; OmniClass Number: 23.40.20.00; OmniClass Title: General Furniture and Specialties; Type Name: Kast met Bovenkast bovenbouw
Type - Pset_ProductRequirements - Category: Furniture
Pset_QuantityTakeOff - Reference: Kast met Bovenkast bovenbouw
Other - Links: yes; Boven klep: no; Boven Rechts: no; Family: 00_DAT Vaste inrichting Keukenkasten; Klep: no; Kookplaat: no; Lade: no; Spatwand: yes; Rechts: no; Wasbak: yes; Boven Links: yes; Family and Type: 00_DAT Vaste inrichting Keukenkasten: Kast met Bovenkast bovenbouw; Type: Kast met Bovenkast bovenbouw; Type Id: 5840733
Constraints - Elevation from Level: 0 mm; Moves With Nearby Elements: no; Offset from Host: 0 mm; Level: 1; Host: Level : 1
Dimensions - Area: 3.53961 m2; Volume: 0.451003 m3
Identity Data - Workset: Bouwkundig
Materials and Finishes - Materiaal: ISR_HPL Kleur hout
Phasing - Phase Created: 2. nieuwbouw
Visibility - Klep visible: no; Lade visible: no; Links visible: yes; Rechts visible: no
Name (00_DAT Vaste inrichting Keukenkasten:Kast met Bovenkast bovenbouw:...) | In | Group
5900738 | 1.03 | Model Group:Pantry lokaal boven 2:5977383
5901744 | 1.01 | Model Group:Pantrie lokaal Boven:5901741
5901937 | 1.04 | Model Group:Pantrie lokaal Boven:5901934
5988674 | 1.02 | Model Group:Pantry lokaal boven 2:5988671

# IfcFurnishingElement: 00_DAT Vaste inrichting Keukenkasten:Kast met bovenkast KDV (9)
Type - Material: ISR_HPL Kleur hout
Type - Other - Category: Furniture; Bovenkast: yes; Family Name: 00_DAT Vaste inrichting Keukenkasten
Type - Constraints - Default Elevation: 0 mm
Type - Dimensions - 1/2 maat: 300 mm; Breedte: 600 mm; Diepte Bovenkast: 350 mm; Hoogte: 900 mm; Hoogte Bovenkast: 790 mm; Hoogte Bovenkast vanaf 0: 1600 mm; Hoogte Spatwand: 100 mm; Plint: 100 mm; x: 1000 mm; y: 395 mm; Z: 480 mm
Type - Identity Data - Workset: Family : Furniture : 00_DAT Vaste inrichting Keukenkasten; OmniClass Number: 23.40.20.00; OmniClass Title: General Furniture and Specialties; Type Name: Kast met bovenkast KDV
Type - Pset_ProductRequirements - Category: Furniture
Pset_QuantityTakeOff - Reference: Kast met bovenkast KDV
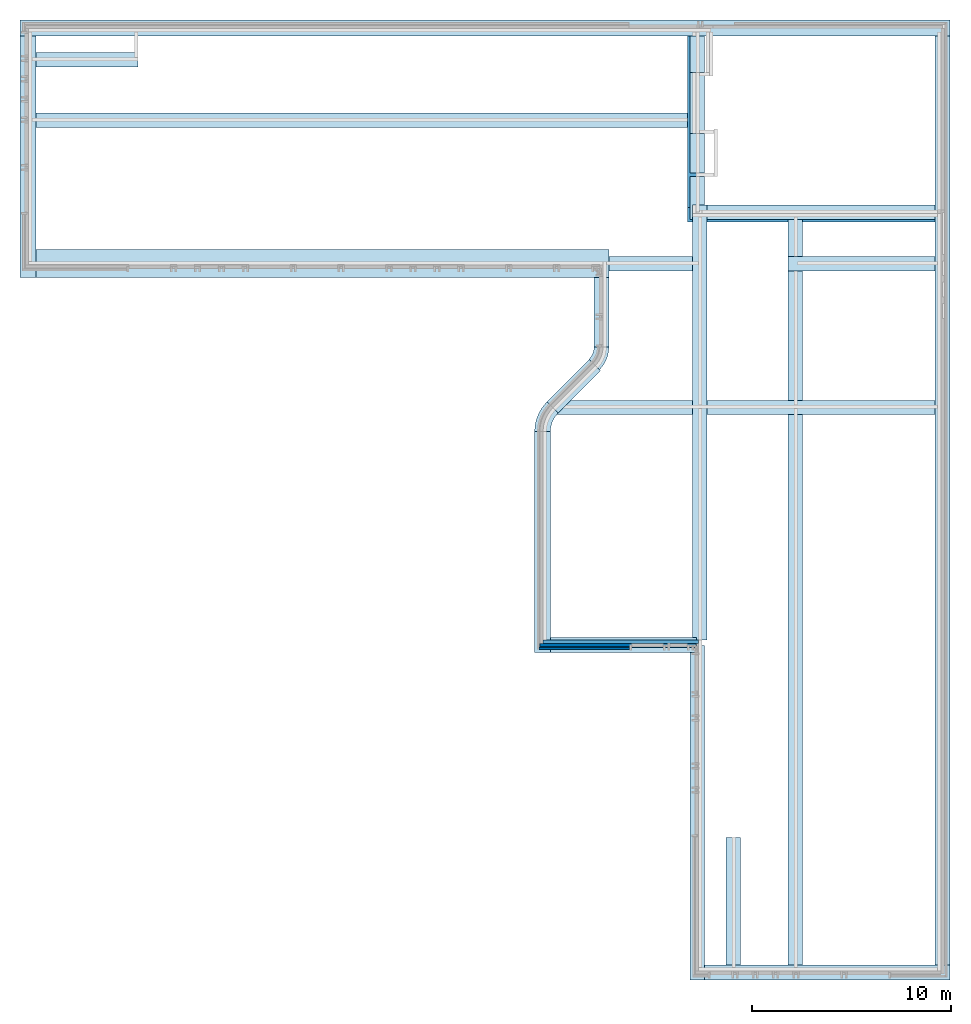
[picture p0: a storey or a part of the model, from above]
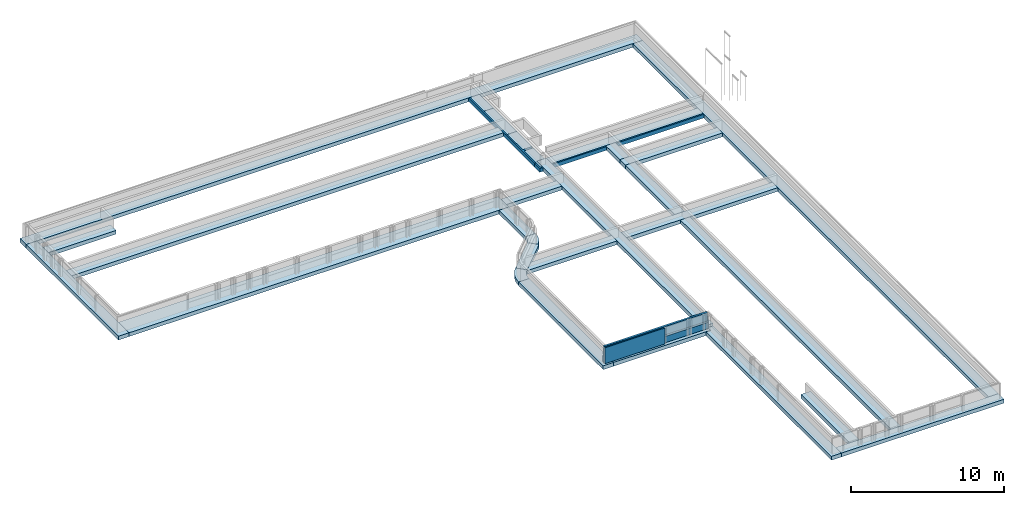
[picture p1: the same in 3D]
Properties of the parts of a building model (IFC2X3), part 16 of 37

# IfcFurnishingElement: 00_DAT Vaste inrichting Keukenkasten:Kast met bovenkast KDV (9)
Other - Boven klep: no; Boven Rechts: no; Family: 00_DAT Vaste inrichting Keukenkasten; Kookplaat: no; Spatwand: yes; Wasbak: no; Rechts: no; Family and Type: 00_DAT Vaste inrichting Keukenkasten: Kast met bovenkast KDV; Type: Kast met bovenkast KDV; Type Id: 5839756
Constraints - Elevation from Level: 0 mm; Level: 0; Moves With Nearby Elements: no; Offset from Host: 0 mm; Host: Level : 0
Dimensions - Area: 2.89668 m2; Volume: 0.488431 m3
Identity Data - Workset: Bouwkundig
Materials and Finishes - Materiaal: ISR_HPL Kleur hout
Phasing - Phase Created: 2. nieuwbouw
Visibility - Rechts visible: no
Name (00_DAT Vaste inrichting Keukenkasten:Kast met bovenkast KDV:...) | In | Links = Links visible | Klep = Klep visible | Lade = Lade visible | Boven Links | Group
5840231 | 0.05 | yes | no | no | yes | Model Group:Pantrie KDV BSO/PSZ:5840235
5840233 | 0.05 | no | yes | no | yes | Model Group:Pantrie KDV BSO/PSZ:5840235
5840274 | 0.09 | yes | no | no | yes | Model Group:Pantrie KDV BSO/PSZ:5840278
5840276 | 0.09 | no | yes | no | yes | Model Group:Pantrie KDV BSO/PSZ:5840278
6141297 | 0.01 | yes | no | no | yes | Model Group:Pantrie KDV BSO/PSZ:6141301
6141299 | 0.01 | no | yes | no | yes | Model Group:Pantrie KDV BSO/PSZ:6141301
6697206 | 0.05 | no | no | yes | no | Model Group:Pantrie KDV BSO/PSZ:5840235
6697241 | 0.09 | no | no | yes | no | Model Group:Pantrie KDV BSO/PSZ:5840278
6697243 | 0.01 | no | no | yes | no | Model Group:Pantrie KDV BSO/PSZ:6141301

# IfcFurnishingElement: 00_DAT Vaste inrichting Keukenkasten:Kast met bovenkast KDV (3)
Type - Material: NBS_VilleroyAndBochAG_Chrome, ISR_HPL Kleur hout
Type - Other - Category: Furniture; Bovenkast: yes; Family Name: 00_DAT Vaste inrichting Keukenkasten
Type - Constraints - Default Elevation: 0 mm
Type - Dimensions - 1/2 maat: 300 mm; Breedte: 600 mm; Diepte Bovenkast: 350 mm; Hoogte: 900 mm; Hoogte Bovenkast: 790 mm; Hoogte Bovenkast vanaf 0: 1600 mm; Hoogte Spatwand: 100 mm; Plint: 100 mm; x: 1000 mm; y: 395 mm; Z: 480 mm
Type - Identity Data - Workset: Family : Furniture : 00_DAT Vaste inrichting Keukenkasten; OmniClass Number: 23.40.20.00; OmniClass Title: General Furniture and Specialties; Type Name: Kast met bovenkast KDV
Type - Pset_ProductRequirements - Category: Furniture
Pset_QuantityTakeOff - Reference: Kast met bovenkast KDV
Other - Links: yes; Boven klep: no; Boven Links: no; Family: 00_DAT Vaste inrichting Keukenkasten; Klep: no; Kookplaat: no; Lade: no; Spatwand: yes; Rechts: no; Wasbak: yes; Family and Type: 00_DAT Vaste inrichting Keukenkasten: Kast met bovenkast KDV; Type: Kast met bovenkast KDV; Type Id: 5839756; Boven Rechts: yes
Constraints - Elevation from Level: 0 mm; Level: 0; Moves With Nearby Elements: no; Offset from Host: 0 mm; Host: Level : 0
Dimensions - Area: 3.15381 m2; Volume: 0.429075 m3
Identity Data - Workset: Bouwkundig
Materials and Finishes - Materiaal: ISR_HPL Kleur hout
Phasing - Phase Created: 2. nieuwbouw
Visibility - Klep visible: no; Lade visible: no; Links visible: yes; Rechts visible: no
Name (00_DAT Vaste inrichting Keukenkasten:Kast met bovenkast KDV:...) | In | Group
5840232 | 0.05 | Model Group:Pantrie KDV BSO/PSZ:5840235
5840275 | 0.09 | Model Group:Pantrie KDV BSO/PSZ:5840278
6141298 | 0.01 | Model Group:Pantrie KDV BSO/PSZ:6141301

# IfcFurnishingElement: 00_DAT Vaste inrichting Keukenkasten:Kast voor verdeler (2)
Type - Material: ISR_RAL 9010
Type - Other - Category: Furniture; Bovenkast: no; Family Name: 00_DAT Vaste inrichting Keukenkasten
Type - Constraints - Default Elevation: 0 mm
Type - Dimensions - 1/2 maat: 337.5 mm; Breedte: 675 mm; Diepte Bovenkast: 350 mm; Hoogte: 1200 mm; Hoogte Bovenkast: 590 mm; Hoogte Bovenkast vanaf 0: 1800 mm; Hoogte Spatwand: 600 mm; Plint: 100 mm; x: 1800 mm; y: 295 mm; Z: 630 mm
Type - Identity Data - Workset: Family : Furniture : 00_DAT Vaste inrichting Keukenkasten; OmniClass Number: 23.40.20.00; OmniClass Title: General Furniture and Specialties; Type Name: Kast voor verdeler
Type - Pset_ProductRequirements - Category: Furniture
Pset_QuantityTakeOff - Reference: Kast voor verdeler
Other - Rechts: yes; Boven klep: no; Boven Links: no; Boven Rechts: no; Family: 00_DAT Vaste inrichting Keukenkasten; Klep: no; Kookplaat: no; Lade: no; Links: no; Wasbak: no; Spatwand: no; Family and Type: 00_DAT Vaste inrichting Keukenkasten: Kast voor verdeler; Type: Kast voor verdeler; Type Id: 6314441
Constraints - Elevation from Level: 0 mm; Moves With Nearby Elements: no; Offset from Host: 0 mm
Dimensions - Area: 3.66268 m2; Volume: 0.483613 m3
Identity Data - Workset: Bouwkundig
Phasing - Phase Created: 2. nieuwbouw
Visibility - Klep visible: no; Lade visible: no; Links visible: no; Rechts visible: yes
Name (00_DAT Vaste inrichting Keukenkasten:Kast voor verdeler:...) | In | Level | Host | Group
6314420 | 0.38 | 0 | Level : 0 | Model Group:pantry 0.38 en 1.24:6883385
6883437 | 1.24 | 1 | Level : 1 | Model Group:pantry 0.38 en 1.24:6883476

# IfcFurnishingElement: 00_DAT Vaste inrichting Keukenkasten:Kast zonder Bovenkast D300, 00_DAT Vaste inrichting Keukenkasten:Kast zonder Bovenkast D300:5904407
In: 1.04
Type - Material: ISR_RAL 9010
Type - Other - Category: Furniture; Bovenkast: no; Family Name: 00_DAT Vaste inrichting Keukenkasten
Type - Constraints - Default Elevation: 0 mm
Type - Dimensions - 1/2 maat: 150 mm; Breedte: 300 mm; Diepte Bovenkast: 350 mm; Hoogte: 900 mm; Hoogte Bovenkast: 540 mm; Hoogte Bovenkast vanaf 0: 1500 mm; Hoogte Spatwand: 300 mm; Plint: 100 mm; x: 1200 mm; y: 270 mm; Z: 480 mm
Type - Identity Data - Workset: Family : Furniture : 00_DAT Vaste inrichting Keukenkasten; OmniClass Number: 23.40.20.00; OmniClass Title: General Furniture and Specialties; Type Name: Kast zonder Bovenkast D300
Type - Pset_ProductRequirements - Category: Furniture
Pset_QuantityTakeOff - Reference: Kast zonder Bovenkast D300
Other - Rechts: yes; Boven klep: no; Boven Links: no; Boven Rechts: no; Family: 00_DAT Vaste inrichting Keukenkasten; Klep: no; Kookplaat: no; Lade: no; Links: no; Spatwand: yes; Wasbak: no; Family and Type: 00_DAT Vaste inrichting Keukenkasten: Kast zonder Bovenkast D300; Type: Kast zonder Bovenkast D300; Type Id: 5904422
Constraints - Elevation from Level: 0 mm; Moves With Nearby Elements: no; Offset from Host: 0 mm; Level: 1; Host: Level : 1
Dimensions - Area: 1.70514 m2; Volume: 0.162103 m3
Identity Data - Workset: Bouwkundig
Phasing - Phase Created: 2. nieuwbouw
Visibility - Klep visible: no; Lade visible: no; Links visible: no; Rechts visible: yes

# IfcFurnishingElement: 00_DAT Vaste inrichting Keukenkasten:Kast zonder Bovenkast D400, 00_DAT Vaste inrichting Keukenkasten:Kast zonder Bovenkast D400:5905382
In: 1.04
Type - Material: ISR_RAL 9010
Type - Other - Category: Furniture; Bovenkast: no; Family Name: 00_DAT Vaste inrichting Keukenkasten
Type - Constraints - Default Elevation: 0 mm
Type - Dimensions - 1/2 maat: 200 mm; Breedte: 400 mm; Diepte Bovenkast: 350 mm; Hoogte: 900 mm; Hoogte Bovenkast: 540 mm; Hoogte Bovenkast vanaf 0: 1500 mm; Hoogte Spatwand: 300 mm; Plint: 100 mm; x: 1200 mm; y: 270 mm; Z: 480 mm
Type - Identity Data - Workset: Family : Furniture : 00_DAT Vaste inrichting Keukenkasten; OmniClass Number: 23.40.20.00; OmniClass Title: General Furniture and Specialties; Type Name: Kast zonder Bovenkast D400
Type - Pset_ProductRequirements - Category: Furniture
Pset_QuantityTakeOff - Reference: Kast zonder Bovenkast D400
Other - Rechts: yes; Boven klep: no; Boven Links: no; Boven Rechts: no; Family: 00_DAT Vaste inrichting Keukenkasten; Klep: no; Kookplaat: no; Lade: no; Links: no; Spatwand: yes; Wasbak: no; Family and Type: 00_DAT Vaste inrichting Keukenkasten: Kast zonder Bovenkast D400; Type: Kast zonder Bovenkast D400; Type Id: 5905405
Constraints - Elevation from Level: 0 mm; Moves With Nearby Elements: no; Offset from Host: 0 mm; Level: 1; Host: Level : 1
Dimensions - Area: 2.02814 m2; Volume: 0.215979 m3
Identity Data - Workset: Bouwkundig
Phasing - Phase Created: 2. nieuwbouw
Visibility - Klep visible: no; Lade visible: no; Links visible: no; Rechts visible: yes

# IfcFurnishingElement: 00_DAT Vaste inrichting Keukenkasten:Kast zonder Bovenkast D600 (4)
In: 0.44
Type - Material: ISR_Kunststof_wit
Type - Other - Category: Furniture; Bovenkast: no; Family Name: 00_DAT Vaste inrichting Keukenkasten
Type - Constraints - Default Elevation: 0 mm
Type - Dimensions - 1/2 maat: 300 mm; Breedte: 600 mm; Diepte Bovenkast: 350 mm; Hoogte: 900 mm; Hoogte Bovenkast: 540 mm; Hoogte Bovenkast vanaf 0: 1500 mm; Hoogte Spatwand: 300 mm; Plint: 100 mm; x: 1200 mm; y: 270 mm; Z: 480 mm
Type - Identity Data - OmniClass Number: 23.40.20.00; OmniClass Title: General Furniture and Specialties; Type Name: Kast zonder Bovenkast D600; Workset: Family : Furniture : 00_DAT Vaste inrichting Keukenkasten
Type - Pset_ProductRequirements - Category: Furniture
Pset_QuantityTakeOff - Reference: Kast zonder Bovenkast D600
Other - Boven klep: no; Boven Links: no; Boven Rechts: no; Family: 00_DAT Vaste inrichting Keukenkasten; Family and Type: 00_DAT Vaste inrichting Keukenkasten: Kast zonder Bovenkast D600; Kookplaat: no; Spatwand: yes; Type: Kast zonder Bovenkast D600; Type Id: 5827483; Wasbak: no
Constraints - Elevation from Level: 0 mm; Level: 0; Moves With Nearby Elements: no; Offset from Host: 0 mm; Host: Level : 0
Dimensions - Area: 2.78118 m2; Volume: 0.323731 m3
Identity Data - Workset: Bouwkundig
Materials and Finishes - Materiaal: ISR_Kunststof_wit
Phasing - Phase Created: 2. nieuwbouw
Name (00_DAT Vaste inrichting Keukenkasten:Kast zonder Bovenkast D600:...) | Rechts = Rechts visible | Klep = Klep visible | Lade = Lade visible | Links = Links visible
5827460 | yes | no | no | no
5829845 | no | no | no | yes
5829863 | no | yes | no | no
6428757 | no | no | yes | no

# IfcFurnishingElement: 00_DAT Vaste inrichting Keukenkasten:Kast zonder Bovenkast D600 (2)
In: 1.04
Type - Material: ISR_RAL 9010
Type - Other - Category: Furniture; Bovenkast: no; Family Name: 00_DAT Vaste inrichting Keukenkasten
Type - Constraints - Default Elevation: 0 mm
Type - Dimensions - 1/2 maat: 300 mm; Breedte: 600 mm; Diepte Bovenkast: 350 mm; Hoogte: 900 mm; Hoogte Bovenkast: 540 mm; Hoogte Bovenkast vanaf 0: 1500 mm; Hoogte Spatwand: 300 mm; Plint: 100 mm; x: 1200 mm; y: 270 mm; Z: 480 mm
Type - Identity Data - OmniClass Number: 23.40.20.00; OmniClass Title: General Furniture and Specialties; Type Name: Kast zonder Bovenkast D600; Workset: Family : Furniture : 00_DAT Vaste inrichting Keukenkasten
Type - Pset_ProductRequirements - Category: Furniture
Pset_QuantityTakeOff - Reference: Kast zonder Bovenkast D600
Other - Boven klep: no; Boven Links: no; Boven Rechts: no; Family: 00_DAT Vaste inrichting Keukenkasten; Family and Type: 00_DAT Vaste inrichting Keukenkasten: Kast zonder Bovenkast D600; Kookplaat: no; Lade: no; Spatwand: yes; Type: Kast zonder Bovenkast D600; Type Id: 5827483; Wasbak: no; Rechts: no
Constraints - Elevation from Level: 0 mm; Moves With Nearby Elements: no; Offset from Host: 0 mm; Level: 1; Host: Level : 1
Dimensions - Area: 2.78118 m2; Volume: 0.323731 m3
Identity Data - Workset: Bouwkundig
Phasing - Phase Created: 2. nieuwbouw
Visibility - Lade visible: no; Rechts visible: no
Name (00_DAT Vaste inrichting Keukenkasten:Kast zonder Bovenkast D600:...) | Links = Links visible | Klep = Klep visible
5904185 | no | yes
5904798 | yes | no

# IfcFurnishingElement: 00_DAT Vaste inrichting Keukenkasten:Kast zonder Bovenkast D600, 00_DAT Vaste inrichting Keukenkasten:Kast zonder Bovenkast D600:5829855
In: 0.44
Type - Material: NBS_VilleroyAndBochAG_Chrome, ISR_Kunststof_wit
Type - Other - Category: Furniture; Bovenkast: no; Family Name: 00_DAT Vaste inrichting Keukenkasten
Type - Constraints - Default Elevation: 0 mm
Type - Dimensions - 1/2 maat: 300 mm; Breedte: 600 mm; Diepte Bovenkast: 350 mm; Hoogte: 900 mm; Hoogte Bovenkast: 540 mm; Hoogte Bovenkast vanaf 0: 1500 mm; Hoogte Spatwand: 300 mm; Plint: 100 mm; x: 1200 mm; y: 270 mm; Z: 480 mm
Type - Identity Data - OmniClass Number: 23.40.20.00; OmniClass Title: General Furniture and Specialties; Type Name: Kast zonder Bovenkast D600; Workset: Family : Furniture : 00_DAT Vaste inrichting Keukenkasten
Type - Pset_ProductRequirements - Category: Furniture
Pset_QuantityTakeOff - Reference: Kast zonder Bovenkast D600
Other - Links: yes; Boven klep: no; Boven Links: no; Boven Rechts: no; Family: 00_DAT Vaste inrichting Keukenkasten; Family and Type: 00_DAT Vaste inrichting Keukenkasten: Kast zonder Bovenkast D600; Klep: no; Kookplaat: no; Lade: no; Spatwand: yes; Type: Kast zonder Bovenkast D600; Type Id: 5827483; Rechts: no; Wasbak: yes
Constraints - Elevation from Level: 0 mm; Level: 0; Moves With Nearby Elements: no; Offset from Host: 0 mm; Host: Level : 0
Dimensions - Area: 3.03831 m2; Volume: 0.264375 m3
Identity Data - Workset: Bouwkundig
Materials and Finishes - Materiaal: ISR_Kunststof_wit
Phasing - Phase Created: 2. nieuwbouw
Visibility - Klep visible: no; Lade visible: no; Links visible: yes; Rechts visible: no

# IfcFurnishingElement: 00_DAT Vaste inrichting Keukenkasten:Kast zonder Bovenkast D600 H650 (2)
Type - Material: ISR_RAL 9010
Type - Other - Category: Furniture; Bovenkast: no; Family Name: 00_DAT Vaste inrichting Keukenkasten
Type - Constraints - Default Elevation: 0 mm
Type - Dimensions - 1/2 maat: 300 mm; Breedte: 600 mm; Diepte Bovenkast: 350 mm; Hoogte: 650 mm; Hoogte Bovenkast: 540 mm; Hoogte Bovenkast vanaf 0: 1500 mm; Hoogte Spatwand: 300 mm; Plint: 100 mm; x: 950 mm; y: 270 mm; Z: 355 mm
Type - Identity Data - Workset: Family : Furniture : 00_DAT Vaste inrichting Keukenkasten; OmniClass Number: 23.40.20.00; OmniClass Title: General Furniture and Specialties; Type Name: Kast zonder Bovenkast D600 H650
Type - Pset_ProductRequirements - Category: Furniture
Pset_QuantityTakeOff - Reference: Kast zonder Bovenkast D600 H650
Other - Links: yes; Boven klep: no; Boven Links: no; Boven Rechts: no; Family: 00_DAT Vaste inrichting Keukenkasten; Klep: no; Kookplaat: no; Lade: no; Spatwand: yes; Wasbak: no; Rechts: no; Family and Type: 00_DAT Vaste inrichting Keukenkasten: Kast zonder Bovenkast D600 H650; Type: Kast zonder Bovenkast D600 H650; Type Id: 6134193
Constraints - Elevation from Level: 0 mm; Moves With Nearby Elements: no; Offset from Host: 0 mm
Dimensions - Area: 2.48118 m2; Volume: 0.233731 m3
Identity Data - Workset: Bouwkundig
Phasing - Phase Created: 2. nieuwbouw
Visibility - Klep visible: no; Lade visible: no; Links visible: yes; Rechts visible: no
Name (00_DAT Vaste inrichting Keukenkasten:Kast zonder Bovenkast D600 H650:...) | In | Level | Host | Group
5981449 | 0.38 | 0 | Level : 0 | Model Group:pantry 0.38 en 1.24:6883385
6883436 | 1.24 | 1 | Level : 1 | Model Group:pantry 0.38 en 1.24:6883476

# IfcFurnishingElement: 00_DAT Vaste inrichting Keukenkasten:Kast zonder Bovenkast D600 H650 (2)
Type - Material: NBS_VilleroyAndBochAG_Chrome, ISR_RAL 9010
Type - Other - Category: Furniture; Bovenkast: no; Family Name: 00_DAT Vaste inrichting Keukenkasten
Type - Constraints - Default Elevation: 0 mm
Type - Dimensions - 1/2 maat: 300 mm; Breedte: 600 mm; Diepte Bovenkast: 350 mm; Hoogte: 650 mm; Hoogte Bovenkast: 540 mm; Hoogte Bovenkast vanaf 0: 1500 mm; Hoogte Spatwand: 300 mm; Plint: 100 mm; x: 950 mm; y: 270 mm; Z: 355 mm
Type - Identity Data - Workset: Family : Furniture : 00_DAT Vaste inrichting Keukenkasten; OmniClass Number: 23.40.20.00; OmniClass Title: General Furniture and Specialties; Type Name: Kast zonder Bovenkast D600 H650
Type - Pset_ProductRequirements - Category: Furniture
Pset_QuantityTakeOff - Reference: Kast zonder Bovenkast D600 H650
Other - Rechts: yes; Boven klep: no; Boven Links: no; Boven Rechts: no; Family: 00_DAT Vaste inrichting Keukenkasten; Klep: no; Kookplaat: no; Lade: no; Links: no; Spatwand: yes; Wasbak: yes; Family and Type: 00_DAT Vaste inrichting Keukenkasten: Kast zonder Bovenkast D600 H650; Type: Kast zonder Bovenkast D600 H650; Type Id: 6134193
Constraints - Elevation from Level: 0 mm; Moves With Nearby Elements: no; Offset from Host: 0 mm
Dimensions - Area: 2.73831 m2; Volume: 0.174375 m3
Identity Data - Workset: Bouwkundig
Phasing - Phase Created: 2. nieuwbouw
Visibility - Klep visible: no; Lade visible: no; Links visible: no; Rechts visible: yes
Name (00_DAT Vaste inrichting Keukenkasten:Kast zonder Bovenkast D600 H650:...) | In | Level | Host | Group
5981448 | 0.38 | 0 | Level : 0 | Model Group:pantry 0.38 en 1.24:6883385
6883435 | 1.24 | 1 | Level : 1 | Model Group:pantry 0.38 en 1.24:6883476

# IfcFurnishingElement: 00_DAT Vaste inrichting Keukenkasten:Kast zonder Bovenkast D600 Hogeplint (2)
In: 1.04
Type - Material: ISR_RAL 9010
Type - Other - Category: Furniture; Bovenkast: no; Family Name: 00_DAT Vaste inrichting Keukenkasten
Type - Constraints - Default Elevation: 0 mm
Type - Dimensions - 1/2 maat: 300 mm; Breedte: 600 mm; Diepte Bovenkast: 350 mm; Hoogte: 900 mm; Hoogte Bovenkast: 540 mm; Hoogte Bovenkast vanaf 0: 1500 mm; Hoogte Spatwand: 300 mm; Plint: 150 mm; x: 1200 mm; y: 270 mm; Z: 480 mm
Type - Identity Data - Workset: Family : Furniture : 00_DAT Vaste inrichting Keukenkasten; OmniClass Number: 23.40.20.00; OmniClass Title: General Furniture and Specialties; Type Name: Kast zonder Bovenkast D600 Hogeplint
Type - Pset_ProductRequirements - Category: Furniture
Pset_QuantityTakeOff - Reference: Kast zonder Bovenkast D600 Hogeplint
Other - Boven klep: no; Boven Links: no; Boven Rechts: no; Family: 00_DAT Vaste inrichting Keukenkasten; Klep: no; Spatwand: yes; Wasbak: no; Rechts: no; Family and Type: 00_DAT Vaste inrichting Keukenkasten: Kast zonder Bovenkast D600 Hogeplint; Type: Kast zonder Bovenkast D600 Hogeplint; Type Id: 5904596
Constraints - Elevation from Level: 0 mm; Moves With Nearby Elements: no; Offset from Host: 0 mm; Level: 1; Host: Level : 1
Dimensions - Area: 2.77868 m2
Identity Data - Workset: Bouwkundig
Phasing - Phase Created: 2. nieuwbouw
Visibility - Klep visible: no; Rechts visible: no
Name (00_DAT Vaste inrichting Keukenkasten:Kast zonder Bovenkast D600 Hogeplint:...) | Links = Links visible | Kookplaat = Lade = Lade visible | Volume (m3)
5904568 | no | yes | 0.326664
5904611 | yes | no | 0.322231

# IfcFurnishingElement: 00_DAT Vaste inrichting Keukenkasten:Kast zonder Bovenkast D600 Hogeplint, 00_DAT Vaste inrichting Keukenkasten:Kast zonder Bovenkast D600 Hogeplint:5904621
In: 1.04
Type - Material: NBS_VilleroyAndBochAG_Chrome, ISR_RAL 9010
Type - Other - Category: Furniture; Bovenkast: no; Family Name: 00_DAT Vaste inrichting Keukenkasten
Type - Constraints - Default Elevation: 0 mm
Type - Dimensions - 1/2 maat: 300 mm; Breedte: 600 mm; Diepte Bovenkast: 350 mm; Hoogte: 900 mm; Hoogte Bovenkast: 540 mm; Hoogte Bovenkast vanaf 0: 1500 mm; Hoogte Spatwand: 300 mm; Plint: 150 mm; x: 1200 mm; y: 270 mm; Z: 480 mm
Type - Identity Data - Workset: Family : Furniture : 00_DAT Vaste inrichting Keukenkasten; OmniClass Number: 23.40.20.00; OmniClass Title: General Furniture and Specialties; Type Name: Kast zonder Bovenkast D600 Hogeplint
Type - Pset_ProductRequirements - Category: Furniture
Pset_QuantityTakeOff - Reference: Kast zonder Bovenkast D600 Hogeplint
Other - Rechts: yes; Boven klep: no; Boven Links: no; Boven Rechts: no; Family: 00_DAT Vaste inrichting Keukenkasten; Klep: no; Kookplaat: no; Lade: no; Links: no; Spatwand: yes; Wasbak: yes; Family and Type: 00_DAT Vaste inrichting Keukenkasten: Kast zonder Bovenkast D600 Hogeplint; Type: Kast zonder Bovenkast D600 Hogeplint; Type Id: 5904596
Constraints - Elevation from Level: 0 mm; Moves With Nearby Elements: no; Offset from Host: 0 mm; Level: 1; Host: Level : 1
Dimensions - Area: 3.03581 m2; Volume: 0.262875 m3
Identity Data - Workset: Bouwkundig
Phasing - Phase Created: 2. nieuwbouw
Visibility - Klep visible: no; Lade visible: no; Links visible: no; Rechts visible: yes

# IfcFurnishingElement: Furniture 2:Furniture 2, Furniture 2:Furniture 2:6882631
In: 0.38
Type - Material: ISR_RAL 9010
Type - Other - Category: Furniture; Family Name: Furniture 2
Type - Dimensions - Height: 0 mm
Type - Identity Data - Workset: Bouwkundig; Type Name: Furniture 2
Type - Pset_ProductRequirements - Category: Furniture
Pset_QuantityTakeOff - Reference: Furniture 2
Other - Family: Furniture 2; Family and Type: Furniture 2: Furniture 2; Type: Furniture 2; Type Id: 6882629
Constraints - Moves With Nearby Elements: no
Dimensions - Area: 0.292564 m2; Volume: 0.592412 m3
Phasing - Phase Created: 2. nieuwbouw
Group: Model Group:pantry 0.38 en 1.24:6883385

# IfcFurnishingElement: Furniture 3:Furniture 2, Furniture 3:Furniture 2:6883453
In: 1.24
Type - Material: ISR_RAL 9010
Type - Other - Category: Furniture; Family Name: Furniture 3
Type - Dimensions - Height: 0 mm
Type - Identity Data - Workset: Bouwkundig; Type Name: Furniture 2
Type - Pset_ProductRequirements - Category: Furniture
Pset_QuantityTakeOff - Reference: Furniture 2
Other - Type: Furniture 2; Family: Furniture 3; Family and Type: Furniture 3: Furniture 2; Type Id: 6883451
Constraints - Moves With Nearby Elements: no
Dimensions - Area: 0.292564 m2; Volume: 0.592412 m3
Phasing - Phase Created: 2. nieuwbouw
Group: Model Group:pantry 0.38 en 1.24:6883476

# IfcFurnishingElement: Furniture 4:Furniture 4, Furniture 4:Furniture 4:6886827
In: 1.04
Type - Material: ISR_RAL 9010
Type - Other - Category: Furniture; Family Name: Furniture 4
Type - Dimensions - Height: 0 mm
Type - Identity Data - Workset: Bouwkundig; Type Name: Furniture 4
Type - Pset_ProductRequirements - Category: Furniture
Pset_QuantityTakeOff - Reference: Furniture 4
Other - Family: Furniture 4; Family and Type: Furniture 4: Furniture 4; Type: Furniture 4; Type Id: 6886825
Constraints - Moves With Nearby Elements: no
Dimensions - Area: 0.407663 m2; Volume: 0.00815325 m3
Phasing - Phase Created: 2. nieuwbouw

# IfcFurnishingElement: NLRS_82_FU_LB_kast boeken_gen_ASN:boekenkast gen bxhxd 900 x 2100 x 300 (12)
Type - Material: ISR_RAL 9010
Type - Other - Category: Furniture; Family Name: NLRS_82_FU_LB_kast boeken_gen_ASN; knop_pl_hoogte: 1000 mm; plank_diepte: 250 mm; plank_dikte: 20 mm; plank_hoogte_1: 400 mm; plank_hoogte_2: 800 mm; plank_hoogte_3: 1200 mm; plank_hoogte_4: 1600 mm; plint_hoogte: 50 mm; wand_dikte: 18 mm
Type - Constraints - Default Elevation: 0 mm
Type - Dimensions - kast_breedte: 900 mm; kast_diepte: 300 mm; kast_hoogte: 2100 mm; NLRS_C_breedte: 900 mm; NLRS_C_diepte: 300 mm; NLRS_C_hoogte: 2100 mm
Type - General - NLRS_C_content_creator: Arkance Systems; NLRS_C_content_datum_gewijzigd: 2022.05.27; NLRS_C_content_provider: Arkance Systems; NLRS_C_content_versie: 2.1; NLRS_C_revit_versie: 2021
Type - Identity Data - Assembly Code: 82.10; Assembly Description: losse gebruikersinventaris; standaard, algemeen (verzamelniveau); Description: boekenkast; Manufacturer: generiek; Type Name: boekenkast gen bxhxd 900 x 2100 x 300; Workset: Family : Furniture : NLRS_82_FU_LB_kast boeken_gen_ASN
Type - Pset_FurnitureTypeCommon - Description: boekenkast
Type - Pset_ManufacturerTypeInformation - Manufacturer: generiek
Type - Pset_ProductRequirements - Category: Furniture
Classification: 82.10 Uniformat (Uniformat)
Pset_QuantityTakeOff - Reference: boekenkast gen bxhxd 900 x 2100 x 300
Pset_DAT_KMS - Assembly Code: 82.10; Assembly Description: losse gebruikersinventaris; standaard, algemeen (verzamelniveau); Description: boekenkast
Other - Family: NLRS_82_FU_LB_kast boeken_gen_ASN; Family and Type: NLRS_82_FU_LB_kast boeken_gen_ASN: boekenkast gen bxhxd 900 x 2100 x 300; Type: boekenkast gen bxhxd 900 x 2100 x 300; Type Id: 5925837
Constraints - Elevation from Level: 0 mm; Moves With Nearby Elements: no; Offset from Host: 0 mm
Dimensions - Area: 4.55472 m2; Volume: 0.0935729 m3
Graphics - plank_1: yes; plank_2: yes; plank_3: yes; plank_4: yes
Identity Data - Workset: Bouwkundig
Phasing - Phase Created: 2. nieuwbouw
Name (NLRS_82_FU_LB_kast boeken_gen_ASN:boekenkast gen bxhxd 900 x 2100 x 300:...) | In | Level | Host
5925768 | 0.26 | 0 | Level : 0
5928866 | 0.26 | 0 | Level : 0
5928884 | 0.26 | 0 | Level : 0
5929007 | 0.27 | 0 | Level : 0
5929008 | 0.27 | 0 | Level : 0
5929125 | 0.29 | 0 | Level : 0
5929126 | 0.29 | 0 | Level : 0
5929198 | 0.29 | 0 | Level : 0
5933387 | 1.17 | 1 | Level : 1
5933388 | 1.17 | 1 | Level : 1
5933604 | 1.16 | 1 | Level : 1
5933605 | 1.16 | 1 | Level : 1

# IfcFurnishingElement: NLRS_82_FU_LB_tafel 1_gen_ASN:eettafel rond gen d 1200, NLRS_82_FU_LB_tafel 1_gen_ASN:eettafel rond gen d 1200:5933257
In: 1.14
Type - Material: ISR_RAL 9010
Type - Other - Category: Furniture; afronding_blad: 599 mm; afronding_poot: 2 mm; blad_dikte: 40 mm; Family Name: NLRS_82_FU_LB_tafel 1_gen_ASN; overstek: 300 mm; poot_dikte: 60 mm
Type - Constraints - Default Elevation: 0 mm
Type - Dimensions - frame_hoogte: 30 mm; NLRS_C_breedte: 1200 mm; NLRS_C_diepte: 1200 mm; NLRS_C_hoogte: 720 mm
Type - General - NLRS_C_content_creator: Arkance Systems; NLRS_C_content_datum_gewijzigd: 2022.05.27; NLRS_C_content_provider: Arkance Systems; NLRS_C_content_versie: 2.1; NLRS_C_revit_versie: 2021
Type - Identity Data - Assembly Code: 82.10; Assembly Description: losse gebruikersinventaris; standaard, algemeen (verzamelniveau); Description: eettafel rond; Manufacturer: generiek; Type Name: eettafel rond gen d 1200; Workset: Family : Furniture : NLRS_82_FU_LB_tafel 1_gen_ASN
Type - Pset_FurnitureTypeCommon - Description: eettafel rond
Type - Pset_ManufacturerTypeInformation - Manufacturer: generiek
Type - Pset_ProductRequirements - Category: Furniture
Classification: 82.10 Uniformat (Uniformat); Group: Model Group:spreektafel rond 120+4 stoelen:5933262
Pset_QuantityTakeOff - Reference: eettafel rond gen d 1200
Pset_DAT_KMS - Assembly Code: 82.10; Assembly Description: losse gebruikersinventaris; standaard, algemeen (verzamelniveau); Description: eettafel rond
Other - Family: NLRS_82_FU_LB_tafel 1_gen_ASN; Family and Type: NLRS_82_FU_LB_tafel 1_gen_ASN: eettafel rond gen d 1200; Type: eettafel rond gen d 1200; Type Id: 5923328
Constraints - Elevation from Level: 0 mm; Moves With Nearby Elements: no; Offset from Host: 0 mm; Level: 1; Host: Level : 1
Dimensions - Area: 1.71537 m2; Volume: 0.0582878 m3
Identity Data - Workset: Bouwkundig
Phasing - Phase Created: 2. nieuwbouw

# IfcFurnishingElement: NLRS_82_FU_LB_zitmeubel_gen_ASN:stoel (4)
In: 1.14
Type - Material: ISR_RAL 9010
Type - Other - Category: Furniture; Family Name: NLRS_82_FU_LB_zitmeubel_gen_ASN; leuning_afronding: 200 mm; leuning_links: 0 mm; leuning_rechts: 0 mm; poot_afronding: 1 mm; poot_dikte: 30 mm; poot_offset: 10 mm
Type - Constraints - Default Elevation: 0 mm
Type - Data - EnscapeAssetSource: REMOTE; EnscapeNativeAssetHeight: 873.142 mm
Type - Dimensions - breedte: 500 mm; diepte: 500 mm; hoogte: 900 mm; NLRS_C_breedte: 500 mm; NLRS_C_diepte: 500 mm; NLRS_C_hoogte: 900 mm; poot_hoogte: 350 mm; zit_hoogte: 430 mm
Type - General - NLRS_C_content_creator: Arkance Systems; NLRS_C_content_datum_gewijzigd: 2022.05.27; NLRS_C_content_provider: Arkance Systems; NLRS_C_content_versie: 2.1; NLRS_C_revit_versie: 2021
Type - Identity Data - Assembly Code: 82.10; Assembly Description: losse gebruikersinventaris; standaard, algemeen (verzamelniveau); Description: stoel; Manufacturer: generiek; Type Name: stoel; Workset: Family : Furniture : NLRS_82_FU_LB_zitmeubel_gen_ASN
Type - Pset_FurnitureTypeCommon - Description: stoel
Type - Pset_ManufacturerTypeInformation - Manufacturer: generiek
Type - Pset_ProductRequirements - Category: Furniture
Classification: 82.10 Uniformat (Uniformat); Group: Model Group:spreektafel rond 120+4 stoelen:5933262
Pset_QuantityTakeOff - Reference: stoel
Pset_DAT_KMS - Assembly Code: 82.10; Assembly Description: losse gebruikersinventaris; standaard, algemeen (verzamelniveau); Description: stoel
Other - Family: NLRS_82_FU_LB_zitmeubel_gen_ASN; Family and Type: NLRS_82_FU_LB_zitmeubel_gen_ASN: stoel; Type: stoel; Type Id: 5923324
Constraints - Elevation from Level: 0 mm; Moves With Nearby Elements: no; Offset from Host: 0 mm; Level: 1; Host: Level : 1
Data - EnscapeHeight: 873.142 mm
Dimensions - Area: 0.674531 m2; Volume: 0.0326063 m3
Identity Data - Workset: Bouwkundig
Phasing - Phase Created: 2. nieuwbouw
Name (NLRS_82_FU_LB_zitmeubel_gen_ASN:stoel:...)
5933258
5933259
5933260
5933261

# IfcFurnishingElement: Plaat2:Plaat, Plaat2:Plaat:6143360
In: 0.36a
Type - Material: ISR_HPL Kleur hout
Type - Other - Category: Furniture; Family Name: Plaat2
Type - Dimensions - Height: 0 mm
Type - Identity Data - Workset: Bouwkundig; Type Name: Plaat
Type - Pset_ProductRequirements - Category: Furniture
Pset_QuantityTakeOff - Reference: Plaat
Other - Type: Plaat; Family: Plaat2; Family and Type: Plaat2: Plaat; Type Id: 6143358
Constraints - Elevation from Level: 0 mm; Moves With Nearby Elements: no
Dimensions - Area: 0.0096739 m2; Volume: 0.00580434 m3
Phasing - Phase Created: 2. nieuwbouw
Group: Model Group:Basisgroep element:5145620

# IfcFurnishingElement: Plaat3:Plaat, Plaat3:Plaat:6143384
In: 0.37a
Type - Material: ISR_HPL Kleur hout
Type - Other - Category: Furniture; Family Name: Plaat3
Type - Dimensions - Height: 0 mm
Type - Identity Data - Workset: Bouwkundig; Type Name: Plaat
Type - Pset_ProductRequirements - Category: Furniture
Pset_QuantityTakeOff - Reference: Plaat
Other - Type: Plaat; Family: Plaat3; Family and Type: Plaat3: Plaat; Type Id: 6143382
Constraints - Elevation from Level: 0 mm; Moves With Nearby Elements: no
Dimensions - Area: 0.0096739 m2; Volume: 0.00580434 m3
Phasing - Phase Created: 2. nieuwbouw
Group: Model Group:Basisgroep element:5145670

# IfcFurnishingElement: Plaat4:Plaat, Plaat4:Plaat:6143396
In: 1.21a
Type - Material: ISR_HPL Kleur hout
Type - Other - Category: Furniture; Family Name: Plaat4
Type - Dimensions - Height: 0 mm
Type - Identity Data - Workset: Bouwkundig; Type Name: Plaat
Type - Pset_ProductRequirements - Category: Furniture
Pset_QuantityTakeOff - Reference: Plaat
Other - Type: Plaat; Family: Plaat4; Family and Type: Plaat4: Plaat; Type Id: 6143394
Constraints - Elevation from Level: 0 mm; Moves With Nearby Elements: no
Dimensions - Area: 0.0096739 m2; Volume: 0.00580434 m3
Phasing - Phase Created: 2. nieuwbouw
Group: Model Group:Basisgroep element:5181887

# IfcFurnishingElement: Plaat5:Plaat, Plaat5:Plaat:6143408
In: 1.22a
Type - Material: ISR_HPL Kleur hout
Type - Other - Category: Furniture; Family Name: Plaat5
Type - Dimensions - Height: 0 mm
Type - Identity Data - Workset: Bouwkundig; Type Name: Plaat
Type - Pset_ProductRequirements - Category: Furniture
Pset_QuantityTakeOff - Reference: Plaat
Other - Type: Plaat; Family: Plaat5; Family and Type: Plaat5: Plaat; Type Id: 6143406
Constraints - Elevation from Level: 0 mm; Moves With Nearby Elements: no
Dimensions - Area: 0.0096739 m2; Volume: 0.00580434 m3
Phasing - Phase Created: 2. nieuwbouw
Group: Model Group:Basisgroep element:5184346

# IfcFurnishingElement: Plaat6:Plaat, Plaat6:Plaat:6143420
In: 1.23a
Type - Material: ISR_HPL Kleur hout
Type - Other - Category: Furniture; Family Name: Plaat6
Type - Dimensions - Height: 0 mm
Type - Identity Data - Workset: Bouwkundig; Type Name: Plaat
Type - Pset_ProductRequirements - Category: Furniture
Pset_QuantityTakeOff - Reference: Plaat
Other - Type: Plaat; Family: Plaat6; Family and Type: Plaat6: Plaat; Type Id: 6143418
Constraints - Elevation from Level: 0 mm; Moves With Nearby Elements: no
Dimensions - Area: 0.0096739 m2; Volume: 0.00580434 m3
Phasing - Phase Created: 2. nieuwbouw
Group: Model Group:Basisgroep element:5184395

# IfcFurnishingElement: Plaat7:Plaat, Plaat7:Plaat:6143259
In: 0.35a
Type - Material: ISR_HPL Kleur hout
Type - Other - Category: Furniture; Family Name: Plaat7
Type - Dimensions - Height: 0 mm
Type - Identity Data - Workset: Bouwkundig; Type Name: Plaat
Type - Pset_ProductRequirements - Category: Furniture
Pset_QuantityTakeOff - Reference: Plaat
Other - Type: Plaat; Family: Plaat7; Family and Type: Plaat7: Plaat; Type Id: 6143257
Constraints - Elevation from Level: 0 mm; Moves With Nearby Elements: no
Dimensions - Area: 0.0096739 m2; Volume: 0.00580434 m3
Phasing - Phase Created: 2. nieuwbouw
Group: Model Group:Basisgroep element:5145694

# IfcFurnishingElement: Plaat:Plaat, Plaat:Plaat:6143120
In: 0.28a
Type - Material: ISR_HPL Kleur hout
Type - Other - Category: Furniture; Family Name: Plaat
Type - Dimensions - Height: 0 mm
Type - Identity Data - Workset: Bouwkundig; Type Name: Plaat
Type - Pset_ProductRequirements - Category: Furniture
Pset_QuantityTakeOff - Reference: Plaat
Other - Family: Plaat; Family and Type: Plaat: Plaat; Type: Plaat; Type Id: 6143118
Constraints - Moves With Nearby Elements: no
Dimensions - Area: 0.00747 m2; Volume: 0.004482 m3
Phasing - Phase Created: 2. nieuwbouw
Group: Model Group:Basisgroep element 2:5203610

# IfcFurnishingElement: verschoontafel1:verschoontafel, verschoontafel1:verschoontafel:6246990
In: 0.08
Type - Material: ISR_RAL 9010
Type - Other - Category: Furniture; Family Name: verschoontafel1
Type - Dimensions - Height: 0 mm
Type - Identity Data - Workset: Bouwkundig; Type Name: verschoontafel
Type - Pset_ProductRequirements - Category: Furniture
Pset_QuantityTakeOff - Reference: verschoontafel
Other - Type: verschoontafel; Family: verschoontafel1; Family and Type: verschoontafel1: verschoontafel; Type Id: 6246988
Constraints - Elevation from Level: 0 mm; Moves With Nearby Elements: no
Dimensions - Area: 2.16 m2; Volume: 1.836 m3
Phasing - Phase Created: 2. nieuwbouw
Group: Model Group:verschoontafel 800x2700x850 bxlxh:6246991

# IfcFurnishingElement: verschoontafel2:verschoontafel, verschoontafel2:verschoontafel:6246961
In: 0.04
Type - Material: ISR_RAL 9010
Type - Other - Category: Furniture; Family Name: verschoontafel2
Type - Dimensions - Height: 0 mm
Type - Identity Data - Workset: Bouwkundig; Type Name: verschoontafel
Type - Pset_ProductRequirements - Category: Furniture
Pset_QuantityTakeOff - Reference: verschoontafel
Other - Family: verschoontafel2; Family and Type: verschoontafel2: verschoontafel; Type: verschoontafel; Type Id: 6246959
Constraints - Moves With Nearby Elements: no
Dimensions - Area: 2.16 m2; Volume: 1.836 m3
Phasing - Phase Created: 2. nieuwbouw
Group: Model Group:verschoontafel 800x2700x850 bxlxh:6246962

# IfcGroup (3)
Other - Category: Area Schemes
Identity Data - Workset: Area and Volume Computations
Name | Name
gebruiksoppvlak (GO) | gebruiksoppvlak (GO)
bruto vloeroppervlak (BVO) | bruto vloeroppervlak (BVO)
verblijfsgebied (VG) | verblijfsgebied (VG)

# IfcGroup: Model Group:Array Group 4 (3)
Other - Category: Model Groups; Family: Model Group; Family and Type: Model Group: Array Group 4; Type: Array Group 4; Type Id: 6775006
Constraints - Origin Level Offset: 0 mm; Reference Level: 0
Identity Data - Workset: Bouwkundig
Other(Type) - Category: Model Groups; Family Name: Model Group
Identity Data(Type) - Workset: Bouwkundig; Type Name: Array Group 4
Name (Model Group:Array Group 4:...)
6775005
6775009
6775040

# IfcGroup: Model Group:Array Group 5 (7)
Other - Category: Model Groups; Family: Model Group; Family and Type: Model Group: Array Group 5; Type: Array Group 5; Type Id: 6775083
Constraints - Origin Level Offset: 0 mm; Reference Level: 0
Identity Data - Workset: Bouwkundig
Other(Type) - Category: Model Groups; Family Name: Model Group
Identity Data(Type) - Workset: Bouwkundig; Type Name: Array Group 5
Name (Model Group:Array Group 5:...)
6775082
6775086
6775103
6775106
6775109
6775112
6775115

# IfcGroup: Model Group:Basisgroep element (6)
Other - Category: Model Groups; Family: Model Group; Family and Type: Model Group: Basisgroep element; Type: Basisgroep element; Type Id: 5145621
Constraints - Origin Level Offset: 0 mm
Identity Data - Workset: Bouwkundig
Other(Type) - Category: Model Groups; Family Name: Model Group
Identity Data(Type) - Workset: Bouwkundig; Type Name: Basisgroep element
Name (Model Group:Basisgroep element:...) | Reference Level
5145620 | 0
5145670 | 0
5145694 | 0
5181887 | 1
5184346 | 1
5184395 | 1

# IfcGroup: Model Group:Basisgroep element 2, Model Group:Basisgroep element 2:5203610
Other - Category: Model Groups; Family: Model Group; Family and Type: Model Group: Basisgroep element 2; Type: Basisgroep element 2; Type Id: 5205386
Constraints - Origin Level Offset: 0 mm; Reference Level: 0
Identity Data - Workset: Bouwkundig
Other(Type) - Category: Model Groups; Family Name: Model Group
Identity Data(Type) - Workset: Bouwkundig; Type Name: Basisgroep element 2

# IfcGroup: Model Group:Bovenkast KDV (2)
Other - Category: Model Groups; Family: Model Group; Family and Type: Model Group: Bovenkast KDV; Type: Bovenkast KDV; Type Id: 5896203
Constraints - Origin Level Offset: 0 mm; Reference Level: 0
Identity Data - Workset: Bouwkundig
Other(Type) - Category: Model Groups; Family Name: Model Group
Identity Data(Type) - Workset: Bouwkundig; Type Name: Bovenkast KDV
Name (Model Group:Bovenkast KDV:...)
5896304
6181588

# IfcGroup: Model Group:Dicht kozijn (6)
Other - Category: Model Groups; Family: Model Group; Family and Type: Model Group: Dicht kozijn; Type: Dicht kozijn; Type Id: 6238664
Constraints - Origin Level Offset: 0 mm; Reference Level: 0
Identity Data - Workset: Bouwkundig
Other(Type) - Category: Model Groups; Family Name: Model Group
Identity Data(Type) - Workset: Bouwkundig; Type Name: Dicht kozijn
Name (Model Group:Dicht kozijn:...)
6238663
6238866
6238878
6238890
6905425
6905436

# IfcGroup: Model Group:H01 (16)
Other - Category: Model Groups; Family: Model Group; Family and Type: Model Group: H01; Type: H01; Type Id: 5121246
Constraints - Origin Level Offset: 0 mm
Identity Data - Workset: Bouwkundig
Other(Type) - Category: Model Groups; Family Name: Model Group
Identity Data(Type) - Workset: Bouwkundig; Description: dm 900; Type Name: H01
Name (Model Group:H01:...) | Reference Level
5125425 | 0
5125624 | 0
5126009 | 0
5126018 | 0
5126062 | 0
5126071 | 0
5127340 | 0 | Group: Model Group:WC_V0:4976980
5127582 | 0 | Group: Model Group:WC_V0:4977293
5127593 | 0 | Group: Model Group:WC_V0:4977398
5127604 | 1 | Group: Model Group:WC_V0:5035649
5127615 | 1
5127626 | 1 | Group: Model Group:WC_V0:5035659
5174549 | 1
5174800 | 1
5174841 | 1
5994924 | 1 | Group: Model Group:WC_V0:5994912

# IfcGroup: Model Group:H02 (11)
Other - Category: Model Groups; Family: Model Group; Family and Type: Model Group: H02; Type: H02; Type Id: 5125894
Constraints - Origin Level Offset: 0 mm
Identity Data - Workset: Bouwkundig
Other(Type) - Category: Model Groups; Family Name: Model Group
Identity Data(Type) - Workset: Bouwkundig; Type Mark: Merk H02; Type Name: H02
Name (Model Group:H02:...) | Reference Level
5126556 | 0
5126985 | 0
5127227 | 0
5130144 | 0
5206506 | 0
5533681 | 1
5987148 | 1
5987394 | 1
5987402 | 1
6522730 | 0
6694314 | 0

# IfcGroup: Model Group:H03 (3)
Other - Category: Model Groups; Family: Model Group; Family and Type: Model Group: H03; Type: H03; Type Id: 5127977
Constraints - Origin Level Offset: 0 mm
Identity Data - Workset: Bouwkundig
Other(Type) - Category: Model Groups; Family Name: Model Group
Identity Data(Type) - Workset: Bouwkundig; Type Comments: DM 1000mm; Type Mark: Merk H03; Type Name: H03
Name (Model Group:H03:...) | Reference Level
5131933 | 0
5179821 | 1
5465827 | 0

# IfcGroup: Model Group:H04 (3)
Other - Category: Model Groups; Family: Model Group; Family and Type: Model Group: H04; Type: H04; Type Id: 5131220
Constraints - Origin Level Offset: 0 mm; Reference Level: 0
Identity Data - Workset: Bouwkundig
Other(Type) - Category: Model Groups; Family Name: Model Group
Identity Data(Type) - Workset: Bouwkundig; Type Comments: Dm 1000mm; Type Name: H04
Name (Model Group:H04:...)
5130948
5131646
6241461

# IfcGroup: Model Group:H05 (14)
Other - Category: Model Groups; Family: Model Group; Family and Type: Model Group: H05; Type: H05; Type Id: 5132062
Constraints - Origin Level Offset: 0 mm
Identity Data - Workset: Bouwkundig
Other(Type) - Category: Model Groups; Family Name: Model Group
Identity Data(Type) - Workset: Bouwkundig; Type Name: H05
Name (Model Group:H05:...) | Reference Level
5174065 | 0 | Group: Model Group:WC_V0:4977293
5174265 | 0 | Group: Model Group:WC_V0:4976980
5174285 | 0 | Group: Model Group:WC_V0:4977398
5174295 | 1 | Group: Model Group:WC_V0:5035649
5174305 | 1
5174315 | 1 | Group: Model Group:WC_V0:5035659
5174561 | 1
5178251 | 1
5185369 | 1
5185410 | 1
5196983 | 0
5197461 | 0
5197621 | 0
5994934 | 1 | Group: Model Group:WC_V0:5994912

# IfcGroup: Model Group:H06, Model Group:H06:5143935
Other - Category: Model Groups; Family: Model Group; Family and Type: Model Group: H06; Type: H06; Type Id: 5143402
Constraints - Origin Level Offset: 0 mm; Reference Level: 0
Identity Data - Workset: Bouwkundig
Other(Type) - Category: Model Groups; Family Name: Model Group
Identity Data(Type) - Workset: Bouwkundig; Type Name: H06

# IfcGroup: Model Group:H07 (5)
Other - Category: Model Groups; Family: Model Group; Family and Type: Model Group: H07; Type: H07; Type Id: 5144179
Constraints - Origin Level Offset: 0 mm
Identity Data - Workset: Bouwkundig
Other(Type) - Category: Model Groups; Family Name: Model Group
Identity Data(Type) - Workset: Bouwkundig; Type Name: H07
Name (Model Group:H07:...) | Reference Level
5144116 | 0
5145183 | 0
5227238 | 1
5227264 | 1
5995281 | 1

# IfcGroup: Model Group:H08 (7)
Other - Category: Model Groups; Family: Model Group; Family and Type: Model Group: H08; Type: H08; Type Id: 5145355
Constraints - Origin Level Offset: 0 mm
Identity Data - Workset: Bouwkundig
Other(Type) - Category: Model Groups; Family Name: Model Group
Identity Data(Type) - Workset: Bouwkundig; Type Name: H08
Name (Model Group:H08:...) | Reference Level | Group
5145320 | 0 | Model Group:Basisgroep element:5145620
5145662 | 0 | Model Group:Basisgroep element:5145670
5145686 | 0 | Model Group:Basisgroep element:5145694
5181879 | 1 | Model Group:Basisgroep element:5181887
5184338 | 1 | Model Group:Basisgroep element:5184346
5184387 | 1 | Model Group:Basisgroep element:5184395
5203602 | 0 | Model Group:Basisgroep element 2:5203610

# IfcGroup: Model Group:H09 (13)
Other - Category: Model Groups; Family: Model Group; Family and Type: Model Group: H09; Type: H09; Type Id: 5149017
Constraints - Origin Level Offset: 0 mm
Identity Data - Workset: Bouwkundig
Other(Type) - Category: Model Groups; Family Name: Model Group
Identity Data(Type) - Workset: Bouwkundig; Type Comments: Dm 1000mm; Type Name: H09
Name (Model Group:H09:...) | Reference Level | Group
5145245 | 0 | Model Group:Basisgroep element:5145620
5145654 | 0 | Model Group:Basisgroep element:5145670
5145678 | 0 | Model Group:Basisgroep element:5145694
5167012 | 1 | Model Group:V1_Basiselement:5167028
5167153 | 1
5174883 | 1
5181878 | 1 | Model Group:Basisgroep element:5181887
5184337 | 1 | Model Group:Basisgroep element:5184346
5184386 | 1 | Model Group:Basisgroep element:5184395
5203601 | 0 | Model Group:Basisgroep element 2:5203610
5206741 | 0
5988145 | 1 | Model Group:V1_Basiselement:5988153
6668701 | 0

# IfcGroup: Model Group:H10, Model Group:H10:5151852
Other - Category: Model Groups; Family: Model Group; Family and Type: Model Group: H10; Type: H10; Type Id: 5152044
Constraints - Origin Level Offset: 0 mm; Reference Level: 0
Identity Data - Workset: Bouwkundig
Other(Type) - Category: Model Groups; Family Name: Model Group
Identity Data(Type) - Workset: Bouwkundig; Type Mark: Merk H10; Type Name: H10

# IfcGroup: Model Group:H11, Model Group:H11:5533699
Other - Category: Model Groups; Family: Model Group; Family and Type: Model Group: H11; Type: H11; Type Id: 5175415
Constraints - Origin Level Offset: 0 mm; Reference Level: 1
Identity Data - Workset: Bouwkundig
Other(Type) - Category: Model Groups; Family Name: Model Group
Identity Data(Type) - Workset: Bouwkundig; Type Name: H11

# IfcGroup: Model Group:H12, Model Group:H12:5194912
Other - Category: Model Groups; Family: Model Group; Family and Type: Model Group: H12; Type: H12; Type Id: 5181458
Constraints - Origin Level Offset: 0 mm; Reference Level: 1
Identity Data - Workset: Bouwkundig
Other(Type) - Category: Model Groups; Family Name: Model Group
Identity Data(Type) - Workset: Bouwkundig; Type Mark: Merk H13; Type Name: H12

# IfcGroup: Model Group:H13 (6)
Other - Category: Model Groups; Family: Model Group; Family and Type: Model Group: H13; Type: H13; Type Id: 5184919
Constraints - Origin Level Offset: 0 mm; Reference Level: 1
Identity Data - Workset: Bouwkundig
Other(Type) - Category: Model Groups; Family Name: Model Group
Identity Data(Type) - Workset: Bouwkundig; Type Name: H13
Name (Model Group:H13:...)
5167013 | Group: Model Group:V1_Basiselement:5167028
5167154
5174884
5184708
5274116
5988146 | Group: Model Group:V1_Basiselement:5988153

# IfcGroup: Model Group:H14, Model Group:H14:5143401
Other - Category: Model Groups; Family: Model Group; Family and Type: Model Group: H14; Type: H14; Type Id: 5254885
Constraints - Origin Level Offset: 0 mm; Reference Level: 0
Identity Data - Workset: Bouwkundig
Other(Type) - Category: Model Groups; Family Name: Model Group
Identity Data(Type) - Workset: Bouwkundig; Type Name: H14

# IfcGroup: Model Group:H15 (2)
Other - Category: Model Groups; Family: Model Group; Family and Type: Model Group: H15; Type: H15; Type Id: 5270412
Constraints - Origin Level Offset: 0 mm; Reference Level: 0
Identity Data - Workset: Bouwkundig
Other(Type) - Category: Model Groups; Family Name: Model Group
Identity Data(Type) - Workset: Bouwkundig; Type Name: H15
Name (Model Group:H15:...)
5270210
5271078

# IfcGroup: Model Group:H16 (13)
Other - Category: Model Groups; Family: Model Group; Family and Type: Model Group: H16; Type: H16; Type Id: 5276279
Constraints - Origin Level Offset: 0 mm
Identity Data - Workset: Bouwkundig
Other(Type) - Category: Model Groups; Family Name: Model Group
Identity Data(Type) - Workset: Bouwkundig; Type Name: H16
Name (Model Group:H16:...) | Reference Level
5127086 | 0
5130407 | 0
5145073 | 0
5179182 | 1
5185909 | 1
5195722 | 0
5197451 | 0
5197611 | 0
5227244 | 1
5987147 | 1
5987156 | 1
5987797 | 1
5995318 | 1

# IfcGroup: Model Group:H17, Model Group:H17:5259385
Other - Category: Model Groups; Family: Model Group; Family and Type: Model Group: H17; Type: H17; Type Id: 6800297
Constraints - Origin Level Offset: 0 mm; Reference Level: 0
Identity Data - Workset: Bouwkundig
Other(Type) - Category: Model Groups; Family Name: Model Group
Identity Data(Type) - Workset: Bouwkundig; Type Name: H17

# IfcGroup: Model Group:H18 (2)
Other - Category: Model Groups; Family: Model Group; Family and Type: Model Group: H18; Type: H18; Type Id: 5277649
Constraints - Origin Level Offset: 0 mm
Identity Data - Workset: Bouwkundig
Other(Type) - Category: Model Groups; Family Name: Model Group
Identity Data(Type) - Workset: Bouwkundig; Description: Dm 1000; Type Comments: Dm 1000; Type Name: H18
Name (Model Group:H18:...) | Reference Level
5129917 | 0
5185791 | 1

# IfcGroup: Model Group:H19, Model Group:H19:5125869
Other - Category: Model Groups; Family: Model Group; Family and Type: Model Group: H19; Type: H19; Type Id: 5980873
Constraints - Origin Level Offset: 0 mm; Reference Level: 0
Identity Data - Workset: Bouwkundig
Other(Type) - Category: Model Groups; Family Name: Model Group
Identity Data(Type) - Workset: Bouwkundig; Type Mark: Merk H27; Type Name: H19

# IfcGroup: Model Group:H20, Model Group:H20:5488876
Other - Category: Model Groups; Family: Model Group; Family and Type: Model Group: H20; Type: H20; Type Id: 5488877
Constraints - Origin Level Offset: 0 mm; Reference Level: 0
Identity Data - Workset: Bouwkundig
Other(Type) - Category: Model Groups; Family Name: Model Group
Identity Data(Type) - Workset: Bouwkundig; Type Name: H20

# IfcGroup: Model Group:H21, Model Group:H21:5489898
Other - Category: Model Groups; Family: Model Group; Family and Type: Model Group: H21; Type: H21; Type Id: 5893234
Constraints - Origin Level Offset: 0 mm; Reference Level: 0
Identity Data - Workset: Bouwkundig
Other(Type) - Category: Model Groups; Family Name: Model Group
Identity Data(Type) - Workset: Bouwkundig; Type Name: H21

# IfcGroup: Model Group:H22, Model Group:H22:5493776
Other - Category: Model Groups; Family: Model Group; Family and Type: Model Group: H22; Type: H22; Type Id: 5490314
Constraints - Origin Level Offset: 0 mm; Reference Level: V-1
Identity Data - Workset: Bouwkundig
Other(Type) - Category: Model Groups; Family Name: Model Group
Identity Data(Type) - Workset: Bouwkundig; Type Name: H22

# IfcGroup: Model Group:H23, Model Group:H23:5131789
Other - Category: Model Groups; Family: Model Group; Family and Type: Model Group: H23; Type: H23; Type Id: 6608317
Constraints - Origin Level Offset: 0 mm; Reference Level: V-1
Identity Data - Workset: Bouwkundig
Other(Type) - Category: Model Groups; Family Name: Model Group
Identity Data(Type) - Workset: Bouwkundig; Type Name: H23

# IfcGroup: Model Group:H24 (3)
Other - Category: Model Groups; Family: Model Group; Family and Type: Model Group: H24; Type: H24; Type Id: 5489748
Constraints - Origin Level Offset: 0 mm; Reference Level: 0
Identity Data - Workset: Bouwkundig
Other(Type) - Category: Model Groups; Family Name: Model Group
Identity Data(Type) - Workset: Bouwkundig; Type Name: H24
Name (Model Group:H24:...)
5489871
5490908
6241714

# IfcGroup: Model Group:H27 (3)
Other - Category: Model Groups; Family: Model Group; Family and Type: Model Group: H27; Type: H27; Type Id: 6423382
Constraints - Origin Level Offset: 0 mm; Reference Level: 0
Identity Data - Workset: Bouwkundig
Other(Type) - Category: Model Groups; Family Name: Model Group
Identity Data(Type) - Workset: Bouwkundig; Type Name: H27
Name (Model Group:H27:...)
5259555
5259652
6693328

# IfcGroup: Model Group:K_Raamwerk_01 (3)
Other - Category: Model Groups; Family: Model Group; Family and Type: Model Group: K_Raamwerk_01; Type: K_Raamwerk_01; Type Id: 4785289
Constraints - Reference Level: 0; Origin Level Offset: -50 mm
Identity Data - Workset: Bouwkundig
Other(Type) - Category: Model Groups; Family Name: Model Group
Identity Data(Type) - Workset: Bouwkundig; Type Name: K_Raamwerk_01
Name (Model Group:K_Raamwerk_01:...)
5536916
5536948
5536975

# IfcGroup: Model Group:K_Raamwerk_01 A (6)
Other - Category: Model Groups; Family: Model Group; Family and Type: Model Group: K_Raamwerk_01 A; Type: K_Raamwerk_01 A; Type Id: 6238935
Constraints - Reference Level: 0; Origin Level Offset: -50 mm
Identity Data - Workset: Bouwkundig
Other(Type) - Category: Model Groups; Family Name: Model Group
Identity Data(Type) - Workset: Bouwkundig; Type Name: K_Raamwerk_01 A
Name (Model Group:K_Raamwerk_01 A:...)
5538614
5538632
5538692
5538702
5538712
5538722

# IfcGroup: Model Group:K_Raamwerk_02 (3)
Other - Category: Model Groups; Family: Model Group; Family and Type: Model Group: K_Raamwerk_02; Type: K_Raamwerk_02; Type Id: 4792265
Constraints - Reference Level: 0; Origin Level Offset: -50 mm
Identity Data - Workset: Bouwkundig
Other(Type) - Category: Model Groups; Family Name: Model Group
Identity Data(Type) - Workset: Bouwkundig; Type Name: K_Raamwerk_02
Name (Model Group:K_Raamwerk_02:...)
5538732
5538742
5539371

# IfcGroup: Model Group:K_Raamwerk_02a (3)
Other - Category: Model Groups; Family: Model Group; Family and Type: Model Group: K_Raamwerk_02a; Type: K_Raamwerk_02a; Type Id: 5279937
Constraints - Reference Level: 0; Origin Level Offset: -50 mm
Identity Data - Workset: Bouwkundig
Other(Type) - Category: Model Groups; Family Name: Model Group
Identity Data(Type) - Workset: Bouwkundig; Type Name: K_Raamwerk_02a
Name (Model Group:K_Raamwerk_02a:...)
5536878
5536902
5537101

# IfcGroup: Model Group:K_Raamwerk_03 (5)
Other - Category: Model Groups; Family: Model Group; Family and Type: Model Group: K_Raamwerk_03; Type: K_Raamwerk_03; Type Id: 4793642
Constraints - Reference Level: 0; Origin Level Offset: -50 mm
Identity Data - Workset: Bouwkundig
Other(Type) - Category: Model Groups; Family Name: Model Group
Identity Data(Type) - Workset: Bouwkundig; Type Name: K_Raamwerk_03
Name (Model Group:K_Raamwerk_03:...)
5536855
5536927
5537078
5538761
5538779

# IfcGroup: Model Group:K_Raamwerk_03a, Model Group:K_Raamwerk_03a:5538797
Other - Category: Model Groups; Family: Model Group; Family and Type: Model Group: K_Raamwerk_03a; Type: K_Raamwerk_03a; Type Id: 5278888
Constraints - Reference Level: 0; Origin Level Offset: -50 mm
Identity Data - Workset: Bouwkundig
Other(Type) - Category: Model Groups; Family Name: Model Group
Identity Data(Type) - Workset: Bouwkundig; Type Name: K_Raamwerk_03a

# IfcGroup: Model Group:K_Raamwerk_04 (5)
Other - Category: Model Groups; Family: Model Group; Family and Type: Model Group: K_Raamwerk_04; Type: K_Raamwerk_04; Type Id: 4796440
Constraints - Origin Level Offset: 0 mm; Reference Level: 0
Identity Data - Workset: Bouwkundig
Other(Type) - Category: Model Groups; Family Name: Model Group
Identity Data(Type) - Workset: Bouwkundig; Type Name: K_Raamwerk_04
Name (Model Group:K_Raamwerk_04:...)
5539091
5539097
5539100
5539103
5539106

# IfcGroup: Model Group:K_Raamwerk_04 A, Model Group:K_Raamwerk_04 A:5539094
Other - Category: Model Groups; Family: Model Group; Family and Type: Model Group: K_Raamwerk_04 A; Type: K_Raamwerk_04 A; Type Id: 6239494
Constraints - Origin Level Offset: 0 mm; Reference Level: 0
Identity Data - Workset: Bouwkundig
Other(Type) - Category: Model Groups; Family Name: Model Group
Identity Data(Type) - Workset: Bouwkundig; Type Name: K_Raamwerk_04 A

# IfcGroup: Model Group:K_Raamwerk_05 (2)
Other - Category: Model Groups; Family: Model Group; Family and Type: Model Group: K_Raamwerk_05; Type: K_Raamwerk_05; Type Id: 4798525
Constraints - Origin Level Offset: 0 mm; Reference Level: 0
Identity Data - Workset: Bouwkundig
Other(Type) - Category: Model Groups; Family Name: Model Group
Identity Data(Type) - Workset: Bouwkundig; Type Name: K_Raamwerk_05
Name (Model Group:K_Raamwerk_05:...)
5536976
5537110

# IfcGroup: Model Group:K_Raamwerk_06 (6)
Other - Category: Model Groups; Family: Model Group; Family and Type: Model Group: K_Raamwerk_06; Type: K_Raamwerk_06; Type Id: 4843161
Constraints - Origin Level Offset: 0 mm; Reference Level: 0
Identity Data - Workset: Bouwkundig
Other(Type) - Category: Model Groups; Family Name: Model Group
Identity Data(Type) - Workset: Bouwkundig; Type Name: K_Raamwerk_06
Name (Model Group:K_Raamwerk_06:...)
5537289
5537301
5537313
5537322
5537327
5537331

# IfcGroup: Model Group:K_Raamwerk_06a, Model Group:K_Raamwerk_06a:5537494
Other - Category: Model Groups; Family: Model Group; Family and Type: Model Group: K_Raamwerk_06a; Type: K_Raamwerk_06a; Type Id: 4910352
Constraints - Origin Level Offset: 0 mm; Reference Level: 0
Identity Data - Workset: Bouwkundig
Other(Type) - Category: Model Groups; Family Name: Model Group
Identity Data(Type) - Workset: Bouwkundig; Type Name: K_Raamwerk_06a

# IfcGroup: Model Group:K_Raamwerk_07 (2)
Other - Category: Model Groups; Family: Model Group; Family and Type: Model Group: K_Raamwerk_07; Type: K_Raamwerk_07; Type Id: 4849752
Constraints - Origin Level Offset: 0 mm; Reference Level: 0
Identity Data - Workset: Bouwkundig
Other(Type) - Category: Model Groups; Family Name: Model Group
Identity Data(Type) - Workset: Bouwkundig; Type Name: K_Raamwerk_07
Name (Model Group:K_Raamwerk_07:...)
5537510
5537720

# IfcGroup: Model Group:K_Raamwerk_16 (12)
Other - Category: Model Groups; Family: Model Group; Family and Type: Model Group: K_Raamwerk_16; Type: K_Raamwerk_16; Type Id: 5956500
Constraints - Origin Level Offset: 0 mm; Reference Level: 0
Identity Data - Workset: Bouwkundig
Other(Type) - Category: Model Groups; Family Name: Model Group
Identity Data(Type) - Workset: Bouwkundig; Type Name: K_Raamwerk_16
Name (Model Group:K_Raamwerk_16:...)
5542459
5544033
5544055
5544106
5544132
5544804
5544822
5545033
5545106
5545129
5856137
5856140

# IfcGroup: Model Group:K_Raamwerk_17 (11)
Other - Category: Model Groups; Family: Model Group; Family and Type: Model Group: K_Raamwerk_17; Type: K_Raamwerk_17; Type Id: 5541129
Constraints - Origin Level Offset: 0 mm; Reference Level: 0
Identity Data - Workset: Bouwkundig
Other(Type) - Category: Model Groups; Family Name: Model Group
Identity Data(Type) - Workset: Bouwkundig; Type Name: K_Raamwerk_17
Name (Model Group:K_Raamwerk_17:...)
5540557
5542283
5542309
5542335
5542361
5542387
5544238
5544293
5544971
5545006
5856134

# IfcGroup: Model Group:K_Raamwerk_18, Model Group:K_Raamwerk_18:5538682
Other - Category: Model Groups; Family: Model Group; Family and Type: Model Group: K_Raamwerk_18; Type: K_Raamwerk_18; Type Id: 5073640
Constraints - Reference Level: 0; Origin Level Offset: -50 mm
Identity Data - Workset: Bouwkundig
Other(Type) - Category: Model Groups; Family Name: Model Group
Identity Data(Type) - Workset: Bouwkundig; Type Name: K_Raamwerk_18

# IfcGroup: Model Group:K_Raamwerk_18A, Model Group:K_Raamwerk_18A:5539193
Other - Category: Model Groups; Family: Model Group; Family and Type: Model Group: K_Raamwerk_18A; Type: K_Raamwerk_18A; Type Id: 5269075
Constraints - Reference Level: 0; Origin Level Offset: -50 mm
Identity Data - Workset: Bouwkundig
Other(Type) - Category: Model Groups; Family Name: Model Group
Identity Data(Type) - Workset: Bouwkundig; Type Name: K_Raamwerk_18A

# IfcGroup: Model Group:K_Raamwerk_20, Model Group:K_Raamwerk_20:5539160
Other - Category: Model Groups; Family: Model Group; Family and Type: Model Group: K_Raamwerk_20; Type: K_Raamwerk_20; Type Id: 5074515
Constraints - Reference Level: 0; Origin Level Offset: -50 mm
Identity Data - Workset: Bouwkundig
Other(Type) - Category: Model Groups; Family Name: Model Group
Identity Data(Type) - Workset: Bouwkundig; Type Name: K_Raamwerk_20

# IfcGroup: Model Group:K_Raamwerk_21, Model Group:K_Raamwerk_21:5536962
Other - Category: Model Groups; Family: Model Group; Family and Type: Model Group: K_Raamwerk_21; Type: K_Raamwerk_21; Type Id: 5078062
Constraints - Reference Level: 0; Origin Level Offset: -50 mm
Identity Data - Workset: Bouwkundig
Other(Type) - Category: Model Groups; Family Name: Model Group
Identity Data(Type) - Workset: Bouwkundig; Type Name: K_Raamwerk_21

# IfcGroup: Model Group:K_Raamwerk_22 (14)
Other - Category: Model Groups; Family: Model Group; Family and Type: Model Group: K_Raamwerk_22; Type: K_Raamwerk_22; Type Id: 4918289
Constraints - Origin Level Offset: 0 mm; Reference Level: 1
Identity Data - Workset: Bouwkundig
Other(Type) - Category: Model Groups; Family Name: Model Group
Identity Data(Type) - Workset: Bouwkundig; Type Name: K_Raamwerk_22
Name (Model Group:K_Raamwerk_22:...)
5537759
5537763
5537767
5537771
5537775
5537779
5537838
5537846
5537870
5537878
5537902
5537910
5537934
5537942

# IfcGroup: Model Group:K_Raamwerk_23, Model Group:K_Raamwerk_23:5537755
Other - Category: Model Groups; Family: Model Group; Family and Type: Model Group: K_Raamwerk_23; Type: K_Raamwerk_23; Type Id: 4927166
Constraints - Origin Level Offset: 0 mm; Reference Level: 1
Identity Data - Workset: Bouwkundig
Other(Type) - Category: Model Groups; Family Name: Model Group
Identity Data(Type) - Workset: Bouwkundig; Type Name: K_Raamwerk_23

# IfcGroup: Model Group:K_Raamwerk_24 (13)
Other - Category: Model Groups; Family: Model Group; Family and Type: Model Group: K_Raamwerk_24; Type: K_Raamwerk_24; Type Id: 4802323
Constraints - Origin Level Offset: 0 mm; Reference Level: 1
Identity Data - Workset: Bouwkundig
Other(Type) - Category: Model Groups; Family Name: Model Group
Identity Data(Type) - Workset: Bouwkundig; Type Name: K_Raamwerk_24
Name (Model Group:K_Raamwerk_24:...)
6058628
6058988
6059007
6059026
6059045
6059064
6059083
6059102
6059121
6059140
6059159
6059178
6059197

# IfcGroup: Model Group:K_Raamwerk_25, Model Group:K_Raamwerk_25:5537969
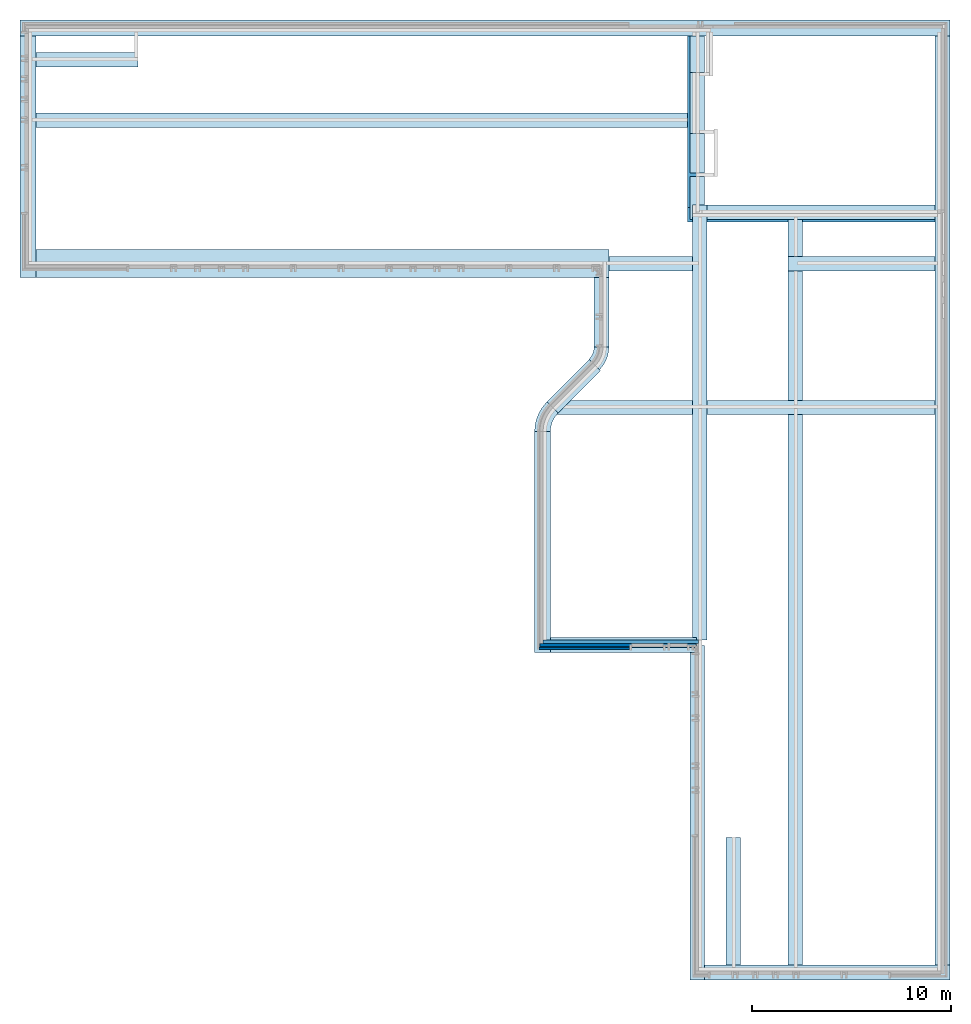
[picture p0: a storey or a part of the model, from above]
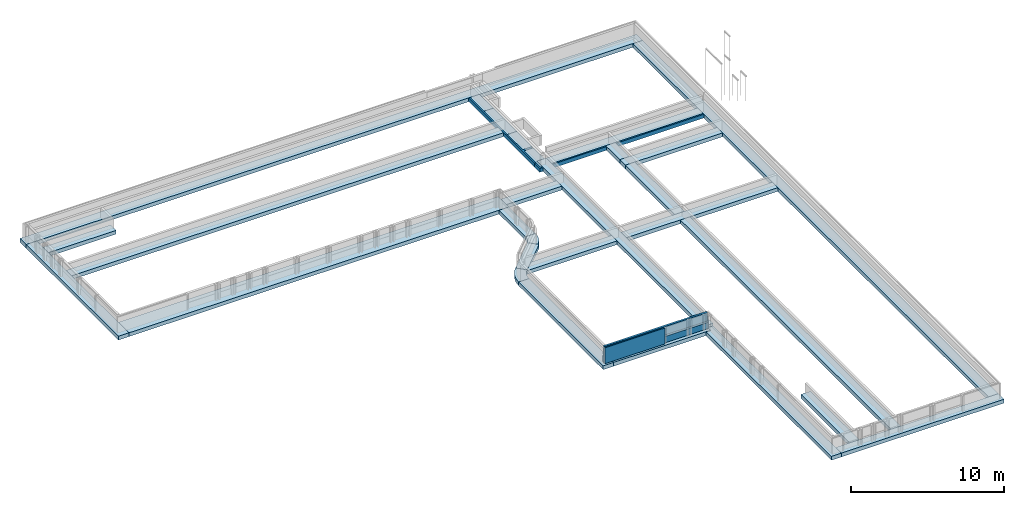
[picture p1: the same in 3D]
Properties of the parts of a building model (IFC2X3), part 17 of 37

# IfcGroup: Model Group:K_Raamwerk_25, Model Group:K_Raamwerk_25:5537969
Other - Category: Model Groups; Family: Model Group; Family and Type: Model Group: K_Raamwerk_25; Type: K_Raamwerk_25; Type Id: 4940530
Constraints - Origin Level Offset: 0 mm; Reference Level: 1
Identity Data - Workset: Bouwkundig
Other(Type) - Category: Model Groups; Family Name: Model Group
Identity Data(Type) - Workset: Bouwkundig; Type Name: K_Raamwerk_25

# IfcGroup: Model Group:K_Raamwerk_28 (17)
Other - Category: Model Groups; Family: Model Group; Family and Type: Model Group: K_Raamwerk_28; Type: K_Raamwerk_28; Type Id: 5545851
Constraints - Origin Level Offset: 0 mm; Reference Level: 1
Identity Data - Workset: Bouwkundig
Other(Type) - Category: Model Groups; Family Name: Model Group
Identity Data(Type) - Workset: Bouwkundig; Type Name: K_Raamwerk_28
Name (Model Group:K_Raamwerk_28:...)
6057727
6058262
6058281
6058300
6058319
6058338
6058357
6058376
6058395
6058414
6058433
6058452
6058471
6058490
6058509
6058528
6058547

# IfcGroup: Model Group:K_Raamwerk_29 (16)
Other - Category: Model Groups; Family: Model Group; Family and Type: Model Group: K_Raamwerk_29; Type: K_Raamwerk_29; Type Id: 4916091
Constraints - Origin Level Offset: 0 mm; Reference Level: 1
Identity Data - Workset: Bouwkundig
Other(Type) - Category: Model Groups; Family Name: Model Group
Identity Data(Type) - Workset: Bouwkundig; Type Name: K_Raamwerk_29
Name (Model Group:K_Raamwerk_29:...)
5537783
5537787
5537791
5537795
5537799
5537803
5537807
5537811
5537834
5537858
5537866
5537890
5537898
5537922
5537930
5537954

# IfcGroup: Model Group:K_Raamwerk_29a, Model Group:K_Raamwerk_29a:5537822
Other - Category: Model Groups; Family: Model Group; Family and Type: Model Group: K_Raamwerk_29a; Type: K_Raamwerk_29a; Type Id: 4936863
Constraints - Origin Level Offset: 0 mm; Reference Level: 1
Identity Data - Workset: Bouwkundig
Other(Type) - Category: Model Groups; Family Name: Model Group
Identity Data(Type) - Workset: Bouwkundig; Type Name: K_Raamwerk_29a

# IfcGroup: Model Group:K_Raamwerk_30, Model Group:K_Raamwerk_30:5537736
Other - Category: Model Groups; Family: Model Group; Family and Type: Model Group: K_Raamwerk_30; Type: K_Raamwerk_30; Type Id: 4934201
Constraints - Origin Level Offset: 0 mm; Reference Level: 1
Identity Data - Workset: Bouwkundig
Other(Type) - Category: Model Groups; Family Name: Model Group
Identity Data(Type) - Workset: Bouwkundig; Type Name: K_Raamwerk_30

# IfcGroup: Model Group:Kastenwand, Model Group:Kastenwand:5849908
Other - Category: Model Groups; Family: Model Group; Family and Type: Model Group: Kastenwand; Type: Kastenwand; Type Id: 5849909
Constraints - Origin Level Offset: 0 mm; Reference Level: 0
Identity Data - Workset: Bouwkundig
Other(Type) - Category: Model Groups; Family Name: Model Group
Identity Data(Type) - Workset: Bouwkundig; Type Name: Kastenwand

# IfcGroup: Model Group:Kollom tussenmaat 120x120 (5)
Other - Category: Model Groups; Family: Model Group; Family and Type: Model Group: Kollom tussenmaat 120x120; Type: Kollom tussenmaat 120x120; Type Id: 6001335
Other(Type) - Category: Model Groups; Family Name: Model Group
Identity Data(Type) - Workset: Bouwkundig; Type Name: Kollom tussenmaat 120x120
Name (Model Group:Kollom tussenmaat 120x120:...) | Origin Level Offset (mm) | Reference Level | Workset
5998666 | 0 | V0 bk. ruwe vloer | Bouwkundig
6002382 | 0 | V0 bk. ruwe vloer | Bouwkundig
6002465 | 0 | V0 bk. ruwe vloer | Bouwkundig
6152818 | 20 | V1 bk. ruwe vloer | Constructie
6152949 | 20 | V1 bk. ruwe vloer | Bouwkundig

# IfcGroup: Model Group:Kollom tussenmaat 120x120 Heel (10)
Other - Category: Model Groups; Family: Model Group; Family and Type: Model Group: Kollom tussenmaat 120x120 Heel; Type: Kollom tussenmaat 120x120 Heel; Type Id: 6782473
Identity Data - Workset: Bouwkundig
Other(Type) - Category: Model Groups; Family Name: Model Group
Identity Data(Type) - Workset: Bouwkundig; Type Name: Kollom tussenmaat 120x120 Heel
Name (Model Group:Kollom tussenmaat 120x120 Heel:...) | Origin Level Offset (mm) | Reference Level
5998578 | 0 | V0 bk. ruwe vloer
5998631 | 0 | V0 bk. ruwe vloer
5998642 | 0 | V0 bk. ruwe vloer
5998655 | 0 | V0 bk. ruwe vloer
5998677 | 0 | V0 bk. ruwe vloer
5998690 | 0 | V0 bk. ruwe vloer
5998910 | 0 | V0 bk. ruwe vloer
6000652 | 0 | V0 bk. ruwe vloer
6000703 | 0 | V0 bk. ruwe vloer
6004935 | 20 | V1 bk. ruwe vloer

# IfcGroup: Model Group:Kollom tussenmaat 120x120 eerste verdieping (16)
Other - Category: Model Groups; Family: Model Group; Family and Type: Model Group: Kollom tussenmaat 120x120 eerste verdieping; Type: Kollom tussenmaat 120x120 eerste verdieping; Type Id: 6786180
Constraints - Origin Level Offset: 0 mm; Reference Level: 1
Identity Data - Workset: Bouwkundig
Other(Type) - Category: Model Groups; Family Name: Model Group
Identity Data(Type) - Workset: Bouwkundig; Type Name: Kollom tussenmaat 120x120 eerste verdieping
Name (Model Group:Kollom tussenmaat 120x120 eerste verdieping:...)
6790255
6790516
6790527
6790538
6790549
6790560
6790571
6791081
6791092
6791103
6791114
6791125
6791136
6791147
6791290
6791938

# IfcGroup: Model Group:Kollom tussenmaat 150x150 (2)
Other - Category: Model Groups; Family: Model Group; Family and Type: Model Group: Kollom tussenmaat 150x150; Type: Kollom tussenmaat 150x150; Type Id: 5998579
Constraints - Origin Level Offset: 0 mm; Reference Level: V0 bk. ruwe vloer
Identity Data - Workset: Bouwkundig
Other(Type) - Category: Model Groups; Family Name: Model Group
Identity Data(Type) - Workset: Bouwkundig; Type Name: Kollom tussenmaat 150x150
Name (Model Group:Kollom tussenmaat 150x150:...)
6001982
6001993

# IfcGroup: Model Group:Kollom tussenmaat 150x150 Trap (5)
Other - Category: Model Groups; Family: Model Group; Family and Type: Model Group: Kollom tussenmaat 150x150 Trap; Type: Kollom tussenmaat 150x150 Trap; Type Id: 6008085
Constraints - Origin Level Offset: 0 mm; Reference Level: 0
Identity Data - Workset: Bouwkundig
Other(Type) - Category: Model Groups; Family Name: Model Group
Identity Data(Type) - Workset: Bouwkundig; Type Name: Kollom tussenmaat 150x150 Trap
Name (Model Group:Kollom tussenmaat 150x150 Trap:...)
6008169
6008522
6008536
6789422
6789695

# IfcGroup: Model Group:Merk K01 (3)
Other - Category: Model Groups; Family: Model Group; Family and Type: Model Group: Merk K01; Type: Merk K01; Type Id: 4774201
Constraints - Origin Level Offset: 0 mm; Reference Level: 0
Identity Data - Workset: Bouwkundig
Other(Type) - Category: Model Groups; Family Name: Model Group
Identity Data(Type) - Workset: Bouwkundig; Type Name: Merk K01
Name (Model Group:Merk K01:...)
5536918
5536950
5539224

# IfcGroup: Model Group:Merk K02 (6)
Other - Category: Model Groups; Family: Model Group; Family and Type: Model Group: Merk K02; Type: Merk K02; Type Id: 4792076
Constraints - Origin Level Offset: 0 mm; Reference Level: 0
Identity Data - Workset: Bouwkundig
Other(Type) - Category: Model Groups; Family Name: Model Group
Identity Data(Type) - Workset: Bouwkundig; Type Name: Merk K02
Name (Model Group:Merk K02:...)
5536879
5536904
5537102
5538734
5538744
5538752

# IfcGroup: Model Group:Merk K03 (6)
Other - Category: Model Groups; Family: Model Group; Family and Type: Model Group: Merk K03; Type: Merk K03; Type Id: 4793034
Constraints - Origin Level Offset: 0 mm; Reference Level: 0
Identity Data - Workset: Bouwkundig
Other(Type) - Category: Model Groups; Family Name: Model Group
Identity Data(Type) - Workset: Bouwkundig; Type Name: Merk K03
Name (Model Group:Merk K03:...)
5536856
5536928
5537079
5538762
5538780
5538798

# IfcGroup: Model Group:Merk K04 (5)
Other - Category: Model Groups; Family: Model Group; Family and Type: Model Group: Merk K04; Type: Merk K04; Type Id: 4796422
Constraints - Origin Level Offset: 0 mm; Reference Level: 0
Identity Data - Workset: Bouwkundig
Other(Type) - Category: Model Groups; Family Name: Model Group
Identity Data(Type) - Workset: Bouwkundig; Type Name: Merk K04
Name (Model Group:Merk K04:...)
5536830
5536838
5536846
5537030
5537065

# IfcGroup: Model Group:Merk K05 (2)
Other - Category: Model Groups; Family: Model Group; Family and Type: Model Group: Merk K05; Type: Merk K05; Type Id: 4797789
Constraints - Origin Level Offset: 0 mm; Reference Level: 0
Identity Data - Workset: Bouwkundig
Other(Type) - Category: Model Groups; Family Name: Model Group
Identity Data(Type) - Workset: Bouwkundig; Type Mark: Merk K05; Type Name: Merk K05
Name (Model Group:Merk K05:...)
5537042
6703044

# IfcGroup: Model Group:Merk K06 (7)
Other - Category: Model Groups; Family: Model Group; Family and Type: Model Group: Merk K06; Type: Merk K06; Type Id: 4842956
Constraints - Origin Level Offset: 0 mm; Reference Level: 0
Identity Data - Workset: Bouwkundig
Other(Type) - Category: Model Groups; Family Name: Model Group
Identity Data(Type) - Workset: Bouwkundig; Type Name: Merk K06
Name (Model Group:Merk K06:...)
5537281
5537293
5537306
5537332
5537340
5537348
5537485

# IfcGroup: Model Group:Merk K07 (2)
Other - Category: Model Groups; Family: Model Group; Family and Type: Model Group: Merk K07; Type: Merk K07; Type Id: 4849768
Constraints - Origin Level Offset: 0 mm; Reference Level: 0
Identity Data - Workset: Bouwkundig
Other(Type) - Category: Model Groups; Family Name: Model Group
Identity Data(Type) - Workset: Bouwkundig; Type Name: Merk K07
Name (Model Group:Merk K07:...)
5537502
5537724

# IfcGroup: Model Group:Merk K08, Model Group:Merk K08:5537385
Other - Category: Model Groups; Family: Model Group; Family and Type: Model Group: Merk K08; Type: Merk K08; Type Id: 4854489
Constraints - Reference Level: 0; Origin Level Offset: 44 mm
Identity Data - Workset: Bouwkundig
Other(Type) - Category: Model Groups; Family Name: Model Group
Identity Data(Type) - Workset: Bouwkundig; Type Name: Merk K08

# IfcGroup: Model Group:Merk K09, Model Group:Merk K09:5537393
Other - Category: Model Groups; Family: Model Group; Family and Type: Model Group: Merk K09; Type: Merk K09; Type Id: 4858759
Constraints - Reference Level: 0; Origin Level Offset: 44 mm
Identity Data - Workset: Bouwkundig
Other(Type) - Category: Model Groups; Family Name: Model Group
Identity Data(Type) - Workset: Bouwkundig; Type Name: Merk K09

# IfcGroup: Model Group:Merk K10, Model Group:Merk K10:5537401
Other - Category: Model Groups; Family: Model Group; Family and Type: Model Group: Merk K10; Type: Merk K10; Type Id: 4859432
Constraints - Reference Level: 0; Origin Level Offset: 44 mm
Identity Data - Workset: Bouwkundig
Other(Type) - Category: Model Groups; Family Name: Model Group
Identity Data(Type) - Workset: Bouwkundig; Type Name: Merk K10

# IfcGroup: Model Group:Merk K11, Model Group:Merk K11:5537409
Other - Category: Model Groups; Family: Model Group; Family and Type: Model Group: Merk K11; Type: Merk K11; Type Id: 4859803
Constraints - Reference Level: 0; Origin Level Offset: 44 mm
Identity Data - Workset: Bouwkundig
Other(Type) - Category: Model Groups; Family Name: Model Group
Identity Data(Type) - Workset: Bouwkundig; Type Name: Merk K11

# IfcGroup: Model Group:Merk K12, Model Group:Merk K12:5537417
Other - Category: Model Groups; Family: Model Group; Family and Type: Model Group: Merk K12; Type: Merk K12; Type Id: 4859990
Constraints - Reference Level: 0; Origin Level Offset: 44 mm
Identity Data - Workset: Bouwkundig
Other(Type) - Category: Model Groups; Family Name: Model Group
Identity Data(Type) - Workset: Bouwkundig; Type Name: Merk K12

# IfcGroup: Model Group:Merk K13, Model Group:Merk K13:5537425
Other - Category: Model Groups; Family: Model Group; Family and Type: Model Group: Merk K13; Type: Merk K13; Type Id: 4860485
Constraints - Reference Level: 0; Origin Level Offset: 44 mm
Identity Data - Workset: Bouwkundig
Other(Type) - Category: Model Groups; Family Name: Model Group
Identity Data(Type) - Workset: Bouwkundig; Type Name: Merk K13

# IfcGroup: Model Group:Merk K14, Model Group:Merk K14:5537525
Other - Category: Model Groups; Family: Model Group; Family and Type: Model Group: Merk K14; Type: Merk K14; Type Id: 4906686
Constraints - Origin Level Offset: 0 mm; Reference Level: 0
Identity Data - Workset: Bouwkundig
Other(Type) - Category: Model Groups; Family Name: Model Group
Identity Data(Type) - Workset: Bouwkundig; Type Name: Merk K14

# IfcGroup: Model Group:Merk K15, Model Group:Merk K15:5537536
Other - Category: Model Groups; Family: Model Group; Family and Type: Model Group: Merk K15; Type: Merk K15; Type Id: 4911977
Constraints - Origin Level Offset: 0 mm; Reference Level: 0
Identity Data - Workset: Bouwkundig
Other(Type) - Category: Model Groups; Family Name: Model Group
Identity Data(Type) - Workset: Bouwkundig; Type Name: Merk K15

# IfcGroup: Model Group:Merk K16 (12)
Other - Category: Model Groups; Family: Model Group; Family and Type: Model Group: Merk K16; Type: Merk K16; Type Id: 5543341
Constraints - Origin Level Offset: 0 mm; Reference Level: 0
Identity Data - Workset: Bouwkundig
Other(Type) - Category: Model Groups; Family Name: Model Group
Identity Data(Type) - Workset: Bouwkundig; Type Name: Merk K16
Name (Model Group:Merk K16:...)
5542460
5544034
5544056
5544107
5544133
5544805
5544823
5545034
5552591
5552762
5856001
5856008

# IfcGroup: Model Group:Merk K17 (11)
Other - Category: Model Groups; Family: Model Group; Family and Type: Model Group: Merk K17; Type: Merk K17; Type Id: 5541643
Constraints - Origin Level Offset: 0 mm; Reference Level: 0
Identity Data - Workset: Bouwkundig
Other(Type) - Category: Model Groups; Family Name: Model Group
Identity Data(Type) - Workset: Bouwkundig; Type Name: Merk K17
Name (Model Group:Merk K17:...)
5540560
5542284
5542310
5542336
5542362
5542388
5544294
5544972
5545007
5855989
5856030

# IfcGroup: Model Group:Merk K18 (2)
Other - Category: Model Groups; Family: Model Group; Family and Type: Model Group: Merk K18; Type: Merk K18; Type Id: 5073427
Constraints - Origin Level Offset: 0 mm; Reference Level: 0
Identity Data - Workset: Bouwkundig
Other(Type) - Category: Model Groups; Family Name: Model Group
Identity Data(Type) - Workset: Bouwkundig; Type Name: Merk K18
Name (Model Group:Merk K18:...)
5538684
5539194

# IfcGroup: Model Group:Merk K19, Model Group:Merk K19:5539066
Other - Category: Model Groups; Family: Model Group; Family and Type: Model Group: Merk K19; Type: Merk K19; Type Id: 4958975
Constraints - Origin Level Offset: 0 mm; Reference Level: 0
Identity Data - Workset: Bouwkundig
Other(Type) - Category: Model Groups; Family Name: Model Group
Identity Data(Type) - Workset: Bouwkundig; Type Name: Merk K19

# IfcGroup: Model Group:Merk K20, Model Group:Merk K20:5539074
Other - Category: Model Groups; Family: Model Group; Family and Type: Model Group: Merk K20; Type: Merk K20; Type Id: 6067154
Constraints - Origin Level Offset: 0 mm; Reference Level: 0
Identity Data - Workset: Bouwkundig
Other(Type) - Category: Model Groups; Family Name: Model Group
Identity Data(Type) - Workset: Bouwkundig; Type Name: Merk K20

# IfcGroup: Model Group:Merk K21, Model Group:Merk K21:5536964
Other - Category: Model Groups; Family: Model Group; Family and Type: Model Group: Merk K21; Type: Merk K21; Type Id: 6068928
Constraints - Origin Level Offset: 0 mm; Reference Level: 0
Identity Data - Workset: Bouwkundig
Other(Type) - Category: Model Groups; Family Name: Model Group
Identity Data(Type) - Workset: Bouwkundig; Type Name: Merk K21

# IfcGroup: Model Group:Merk K22 (13)
Other - Category: Model Groups; Family: Model Group; Family and Type: Model Group: Merk K22; Type: Merk K22; Type Id: 4917955
Constraints - Origin Level Offset: 0 mm; Reference Level: 1
Identity Data - Workset: Bouwkundig
Other(Type) - Category: Model Groups; Family Name: Model Group
Identity Data(Type) - Workset: Bouwkundig; Type Name: Merk K22
Name (Model Group:Merk K22:...)
5537990
5537998
5538006
5538014
5538022
5538030
5538038
5538046
5538054
5538062
5538070
5538078
5538086

# IfcGroup: Model Group:Merk K23, Model Group:Merk K23:5537747
Other - Category: Model Groups; Family: Model Group; Family and Type: Model Group: Merk K23; Type: Merk K23; Type Id: 4927041
Constraints - Origin Level Offset: 0 mm; Reference Level: 1
Identity Data - Workset: Bouwkundig
Other(Type) - Category: Model Groups; Family Name: Model Group
Identity Data(Type) - Workset: Bouwkundig; Type Name: Merk K23

# IfcGroup: Model Group:Merk K24 (13)
Other - Category: Model Groups; Family: Model Group; Family and Type: Model Group: Merk K24; Type: Merk K24; Type Id: 4801691
Constraints - Origin Level Offset: 0 mm; Reference Level: 1
Identity Data - Workset: Bouwkundig
Other(Type) - Category: Model Groups; Family Name: Model Group
Identity Data(Type) - Workset: Bouwkundig; Type Name: Merk K24
Name (Model Group:Merk K24:...)
6065197
6065228
6065259
6065290
6065321
6065352
6065383
6065414
6065445
6065476
6065507
6065538
6065569

# IfcGroup: Model Group:Merk K25, Model Group:Merk K25:5537974
Other - Category: Model Groups; Family: Model Group; Family and Type: Model Group: Merk K25; Type: Merk K25; Type Id: 4940549
Constraints - Origin Level Offset: 0 mm; Reference Level: 1
Identity Data - Workset: Bouwkundig
Other(Type) - Category: Model Groups; Family Name: Model Group
Identity Data(Type) - Workset: Bouwkundig; Type Name: Merk K25

# IfcGroup: Model Group:Merk K26, Model Group:Merk K26:5538527
Other - Category: Model Groups; Family: Model Group; Family and Type: Model Group: Merk K26; Type: Merk K26; Type Id: 4951849
Constraints - Origin Level Offset: 0 mm; Reference Level: 1
Identity Data - Workset: Bouwkundig
Other(Type) - Category: Model Groups; Family Name: Model Group
Identity Data(Type) - Workset: Bouwkundig; Type Name: Merk K26

# IfcGroup: Model Group:Merk K27, Model Group:Merk K27:5538541
Other - Category: Model Groups; Family: Model Group; Family and Type: Model Group: Merk K27; Type: Merk K27; Type Id: 4952595
Constraints - Origin Level Offset: 0 mm; Reference Level: 1
Identity Data - Workset: Bouwkundig
Other(Type) - Category: Model Groups; Family Name: Model Group
Identity Data(Type) - Workset: Bouwkundig; Type Name: Merk K27

# IfcGroup: Model Group:Merk K28 (13)
Other - Category: Model Groups; Family: Model Group; Family and Type: Model Group: Merk K28; Type: Merk K28; Type Id: 5545617
Constraints - Origin Level Offset: 0 mm; Reference Level: 1
Identity Data - Workset: Bouwkundig
Other(Type) - Category: Model Groups; Family Name: Model Group
Identity Data(Type) - Workset: Bouwkundig; Type Name: Merk K28
Name (Model Group:Merk K28:...)
6064868
6064887
6064906
6064925
6064944
6064963
6064982
6065020
6065039
6065077
6065096
6065115
6065134

# IfcGroup: Model Group:Merk K29 (18)
Other - Category: Model Groups; Family: Model Group; Family and Type: Model Group: Merk K29; Type: Merk K29; Type Id: 4860855
Constraints - Origin Level Offset: 0 mm; Reference Level: 1
Identity Data - Workset: Bouwkundig
Other(Type) - Category: Model Groups; Family Name: Model Group
Identity Data(Type) - Workset: Bouwkundig; Type Name: Merk K29
Name (Model Group:Merk K29:...)
5537981
5538110
5538119
5538128
5538137
5538146
5538155
5538164
5538173
5538182
5538191
5538200
5538209
5538218
5538227
5538236
5538245
5538254

# IfcGroup: Model Group:Merk K30, Model Group:Merk K30:5537739
Other - Category: Model Groups; Family: Model Group; Family and Type: Model Group: Merk K30; Type: Merk K30; Type Id: 5611745
Constraints - Origin Level Offset: 0 mm; Reference Level: 1
Identity Data - Workset: Bouwkundig
Other(Type) - Category: Model Groups; Family Name: Model Group
Identity Data(Type) - Workset: Bouwkundig; Type Name: Merk K30

# IfcGroup: Model Group:Merk K31 (5)
Other - Category: Model Groups; Family: Model Group; Family and Type: Model Group: Merk K31; Type: Merk K31; Type Id: 5610678
Identity Data - Workset: Bouwkundig
Other(Type) - Category: Model Groups; Family Name: Model Group
Identity Data(Type) - Workset: Bouwkundig; Type Name: Merk K31
Name (Model Group:Merk K31:...) | Origin Level Offset (mm) | Reference Level
6065001 | 0 | 1
6065058 | 0 | 1
6322821 | 0 | 1
6322854 | 0 | 1
6474575 | -100 | 0

# IfcGroup: Model Group:Merk K32 (2)
Other - Category: Model Groups; Family: Model Group; Family and Type: Model Group: Merk K32; Type: Merk K32; Type Id: 6474502
Constraints - Origin Level Offset: 0 mm; Reference Level: 1
Identity Data - Workset: Bouwkundig
Other(Type) - Category: Model Groups; Family Name: Model Group
Identity Data(Type) - Workset: Bouwkundig; Type Name: Merk K32
Name (Model Group:Merk K32:...)
5538094
5538102

# IfcGroup: Model Group:Paneel op dak (3)
Other - Category: Model Groups; Family: Model Group; Family and Type: Model Group: Paneel op dak; Type: Paneel op dak; Type Id: 6286380
Constraints - Origin Level Offset: 0 mm; Reference Level: V2 bk. ruwe vloer
Identity Data - Workset: Bouwkundig
Other(Type) - Category: Model Groups; Family Name: Model Group
Identity Data(Type) - Workset: Bouwkundig; Description: Lammewand draaiend ivm toegankelijkheid installatie; Type Name: Paneel op dak
Name (Model Group:Paneel op dak:...)
6286816
6287293
6287507

# IfcGroup: Model Group:Pantrie KDV BSO/PSZ (3)
Other - Category: Model Groups; Family: Model Group; Family and Type: Model Group: Pantrie KDV BSO/PSZ; Type: Pantrie KDV BSO/PSZ; Type Id: 5840111
Constraints - Origin Level Offset: 0 mm; Reference Level: 0
Identity Data - Workset: Bouwkundig
Other(Type) - Category: Model Groups; Family Name: Model Group
Identity Data(Type) - Workset: Bouwkundig; Type Name: Pantrie KDV BSO/PSZ
Name (Model Group:Pantrie KDV BSO/PSZ:...)
5840235
5840278
6141301

# IfcGroup: Model Group:Pantrie Middenbouw (3)
Other - Category: Model Groups; Family: Model Group; Family and Type: Model Group: Pantrie Middenbouw; Type: Pantrie Middenbouw; Type Id: 5912641
Constraints - Origin Level Offset: 0 mm; Reference Level: 1
Identity Data - Workset: Bouwkundig
Other(Type) - Category: Model Groups; Family Name: Model Group
Identity Data(Type) - Workset: Bouwkundig; Type Name: Pantrie Middenbouw
Name (Model Group:Pantrie Middenbouw:...)
5846870
5912805
5912818

# IfcGroup: Model Group:Pantrie lokaal Boven (2)
Other - Category: Model Groups; Family: Model Group; Family and Type: Model Group: Pantrie lokaal Boven; Type: Pantrie lokaal Boven; Type Id: 5840671
Constraints - Origin Level Offset: 0 mm; Reference Level: 1
Identity Data - Workset: Bouwkundig
Other(Type) - Category: Model Groups; Family Name: Model Group
Identity Data(Type) - Workset: Bouwkundig; Type Name: Pantrie lokaal Boven
Name (Model Group:Pantrie lokaal Boven:...)
5901741
5901934

# IfcGroup: Model Group:Pantrie onderbouw (3)
Other - Category: Model Groups; Family: Model Group; Family and Type: Model Group: Pantrie onderbouw; Type: Pantrie onderbouw; Type Id: 5841593
Constraints - Origin Level Offset: 0 mm; Reference Level: 0
Identity Data - Workset: Bouwkundig
Other(Type) - Category: Model Groups; Family Name: Model Group
Identity Data(Type) - Workset: Bouwkundig; Type Name: Pantrie onderbouw
Name (Model Group:Pantrie onderbouw:...)
5846863
5983574
5983589

# IfcGroup: Model Group:Pantry lokaal boven 2 (2)
Other - Category: Model Groups; Family: Model Group; Family and Type: Model Group: Pantry lokaal boven 2; Type: Pantry lokaal boven 2; Type Id: 5977384
Constraints - Origin Level Offset: 0 mm; Reference Level: 1
Identity Data - Workset: Bouwkundig
Other(Type) - Category: Model Groups; Family Name: Model Group
Identity Data(Type) - Workset: Bouwkundig; Type Name: Pantry lokaal boven 2
Name (Model Group:Pantry lokaal boven 2:...)
5977383
5988671

# IfcGroup: Model Group:Penant Dubbel (29)
Other - Category: Model Groups; Family: Model Group; Family and Type: Model Group: Penant Dubbel; Type: Penant Dubbel; Type Id: 4753454
Constraints - Origin Level Offset: 0 mm; Reference Level: 0
Identity Data - Workset: Bouwkundig
Other(Type) - Category: Model Groups; Family Name: Model Group
Identity Data(Type) - Workset: Bouwkundig; Type Name: Penant Dubbel
Name (Model Group:Penant Dubbel:...)
5536807
5536817
5536821
5536825
5536829
5536875
5536915
5536947
5536961
5537029
5537041
5537064
5537076
5537098
5537524
5538619
5538623
5538645
5538649
5538653
5538657
5538661
5538665
5538669
5538673
5538677
5538681
5539114
5539188

# IfcGroup: Model Group:Penant Dubbel P+450 (9)
Other - Category: Model Groups; Family: Model Group; Family and Type: Model Group: Penant Dubbel P+450; Type: Penant Dubbel P+450; Type Id: 4844330
Constraints - Origin Level Offset: 0 mm; Reference Level: 0
Identity Data - Workset: Bouwkundig
Other(Type) - Category: Model Groups; Family Name: Model Group
Identity Data(Type) - Workset: Bouwkundig; Type Name: Penant Dubbel P+450
Name (Model Group:Penant Dubbel P+450:...)
5536811
5536812
5537302
5537318
5537323
5537484
5537501
5537715
5537732

# IfcGroup: Model Group:Penant Dubbel v1 (34)
Other - Category: Model Groups; Family: Model Group; Family and Type: Model Group: Penant Dubbel v1; Type: Penant Dubbel v1; Type Id: 4915368
Constraints - Origin Level Offset: 0 mm; Reference Level: 0
Identity Data - Workset: Bouwkundig
Other(Type) - Category: Model Groups; Family Name: Model Group
Identity Data(Type) - Workset: Bouwkundig; Type Name: Penant Dubbel v1
Name (Model Group:Penant Dubbel v1:...)
5537561
5537565
5537570
5537574
5537578
5537582
5537586
5537590
5537594
5537598
5537602
5537606
5537610
5537614
5537618
5537821
5537829
5537833
5537845
5537853
5537857
5537865
5537877
5537885
5537889
5537897
5537909
5537917
5537921
5537929
5537941
5537949
5537953
5537968

# IfcGroup: Model Group:Penant Dubbel v1 Enkel (2)
Other - Category: Model Groups; Family: Model Group; Family and Type: Model Group: Penant Dubbel v1 Enkel; Type: Penant Dubbel v1 Enkel; Type Id: 4926586
Constraints - Origin Level Offset: 0 mm; Reference Level: 0
Identity Data - Workset: Bouwkundig
Other(Type) - Category: Model Groups; Family Name: Model Group
Identity Data(Type) - Workset: Bouwkundig; Type Name: Penant Dubbel v1 Enkel
Name (Model Group:Penant Dubbel v1 Enkel:...)
5537706
5537964

# IfcGroup: Model Group:Penant Dubbel v1 Laag (2)
Other - Category: Model Groups; Family: Model Group; Family and Type: Model Group: Penant Dubbel v1 Laag; Type: Penant Dubbel v1 Laag; Type Id: 4927763
Constraints - Origin Level Offset: 0 mm; Reference Level: 0
Identity Data - Workset: Bouwkundig
Other(Type) - Category: Model Groups; Family Name: Model Group
Identity Data(Type) - Workset: Bouwkundig; Type Name: Penant Dubbel v1 Laag
Name (Model Group:Penant Dubbel v1 Laag:...)
5537689
5537690

# IfcGroup: Model Group:Penant Enkel (8)
Other - Category: Model Groups; Family: Model Group; Family and Type: Model Group: Penant Enkel; Type: Penant Enkel; Type Id: 4797535
Constraints - Origin Level Offset: 0 mm; Reference Level: 0
Identity Data - Workset: Bouwkundig
Other(Type) - Category: Model Groups; Family Name: Model Group
Identity Data(Type) - Workset: Bouwkundig; Type Name: Penant Enkel
Name (Model Group:Penant Enkel:...)
5536803
5536877
5536898
5537051
5537100
5538814
5539115
5539192

# IfcGroup: Model Group:Penant Hoek (2)
Other - Category: Model Groups; Family: Model Group; Family and Type: Model Group: Penant Hoek; Type: Penant Hoek; Type Id: 5090360
Constraints - Origin Level Offset: 0 mm; Reference Level: 0
Identity Data - Workset: Bouwkundig
Other(Type) - Category: Model Groups; Family Name: Model Group
Identity Data(Type) - Workset: Bouwkundig; Type Name: Penant Hoek
Name (Model Group:Penant Hoek:...)
5539155
5539183

# IfcGroup: Model Group:Pui (7)
Other - Category: Model Groups; Family: Model Group; Family and Type: Model Group: Pui; Type: Pui; Type Id: 5023087
Constraints - Reference Level: 0; Origin Level Offset: 60 mm
Identity Data - Workset: Bouwkundig
Other(Type) - Category: Model Groups; Family Name: Model Group
Identity Data(Type) - Workset: Bouwkundig; Type Name: Pui
Name (Model Group:Pui:...)
5023121
5023220
5023230
5023242
5023252
5023264
6713380

# IfcGroup: Model Group:S01, Model Group:S01:5089124
Other - Category: Model Groups; Family: Model Group; Family and Type: Model Group: S01; Type: S01; Type Id: 5002827
Constraints - Origin Level Offset: 0 mm; Reference Level: 0
Identity Data - Workset: Bouwkundig
Other(Type) - Category: Model Groups; Family Name: Model Group
Identity Data(Type) - Workset: Bouwkundig; Type Name: S01

# IfcGroup: Model Group:V1_Basiselement (2)
Other - Category: Model Groups; Family: Model Group; Family and Type: Model Group: V1_Basiselement; Type: V1_Basiselement; Type Id: 5166976
Constraints - Origin Level Offset: 0 mm; Reference Level: 1
Identity Data - Workset: Bouwkundig
Other(Type) - Category: Model Groups; Family Name: Model Group
Identity Data(Type) - Workset: Bouwkundig; Type Name: V1_Basiselement
Name (Model Group:V1_Basiselement:...)
5167028
5988153

# IfcGroup: Model Group:Verlichtingsplan gang 2, Model Group:Verlichtingsplan gang 2:5347818
Other - Category: Model Groups; Family: Model Group; Family and Type: Model Group: Verlichtingsplan gang 2; Type: Verlichtingsplan gang 2; Type Id: 5411570
Constraints - Origin Level Offset: 0 mm; Reference Level: 1
Identity Data - Workset: Bouwkundig
Other(Type) - Category: Model Groups; Family Name: Model Group
Identity Data(Type) - Workset: Bouwkundig; Type Name: Verlichtingsplan gang 2

# IfcGroup: Model Group:Verlichtingsplan gang BG1, Model Group:Verlichtingsplan gang BG1:5347695
Other - Category: Model Groups; Family: Model Group; Family and Type: Model Group: Verlichtingsplan gang BG1; Type: Verlichtingsplan gang BG1; Type Id: 5410957
Constraints - Origin Level Offset: 0 mm; Reference Level: 0
Identity Data - Workset: Bouwkundig
Other(Type) - Category: Model Groups; Family Name: Model Group
Identity Data(Type) - Workset: Bouwkundig; Type Name: Verlichtingsplan gang BG1

# IfcGroup: Model Group:Verlichtingsplan lokaal (9)
Other - Category: Model Groups; Family: Model Group; Family and Type: Model Group: Verlichtingsplan lokaal; Type: Verlichtingsplan lokaal; Type Id: 5339619
Constraints - Origin Level Offset: 0 mm
Identity Data - Workset: installatie
Other(Type) - Category: Model Groups; Family Name: Model Group
Identity Data(Type) - Workset: Bouwkundig; Type Name: Verlichtingsplan lokaal
Name (Model Group:Verlichtingsplan lokaal:...) | Reference Level
5339618 | 0
5339709 | 0
5339745 | 0
5347175 | 1
5347232 | 1
5347244 | 1
5347429 | 1
5347502 | 1
5347541 | 1

# IfcGroup: Model Group:Verlichtingsplan lokaal 2 (3)
Other - Category: Model Groups; Family: Model Group; Family and Type: Model Group: Verlichtingsplan lokaal 2; Type: Verlichtingsplan lokaal 2; Type Id: 5344675
Constraints - Origin Level Offset: 0 mm; Reference Level: 0
Identity Data - Workset: Bouwkundig
Other(Type) - Category: Model Groups; Family Name: Model Group
Identity Data(Type) - Workset: Bouwkundig; Type Name: Verlichtingsplan lokaal 2
Name (Model Group:Verlichtingsplan lokaal 2:...)
5344628
5344952
5344994

# IfcGroup: Model Group:Verlichtingsplan lokaal 3 (2)
Other - Category: Model Groups; Family: Model Group; Family and Type: Model Group: Verlichtingsplan lokaal 3; Type: Verlichtingsplan lokaal 3; Type Id: 5347562
Constraints - Origin Level Offset: 0 mm
Identity Data - Workset: Bouwkundig
Other(Type) - Category: Model Groups; Family Name: Model Group
Identity Data(Type) - Workset: Bouwkundig; Type Name: Verlichtingsplan lokaal 3
Name (Model Group:Verlichtingsplan lokaal 3:...) | Reference Level
5347561 | 0
5347665 | 1

# IfcGroup: Model Group:Verlichtingsplan lokaal 4, Model Group:Verlichtingsplan lokaal 4:5376136
Other - Category: Model Groups; Family: Model Group; Family and Type: Model Group: Verlichtingsplan lokaal 4; Type: Verlichtingsplan lokaal 4; Type Id: 5376179
Constraints - Origin Level Offset: 0 mm; Reference Level: 0
Identity Data - Workset: Bouwkundig
Other(Type) - Category: Model Groups; Family Name: Model Group
Identity Data(Type) - Workset: Bouwkundig; Type Name: Verlichtingsplan lokaal 4

# IfcGroup: Model Group:WC_V0 (6)
Other - Category: Model Groups; Family: Model Group; Family and Type: Model Group: WC_V0; Type: WC_V0; Type Id: 4976988
Constraints - Origin Level Offset: 0 mm
Identity Data - Workset: Bouwkundig
Other(Type) - Category: Model Groups; Family Name: Model Group
Identity Data(Type) - Workset: Bouwkundig; Type Name: WC_V0
Name (Model Group:WC_V0:...) | Reference Level
4976980 | 0
4977293 | 0
4977398 | 0
5035649 | 1
5035659 | 1
5994912 | 1

# IfcGroup: Model Group:Waterslag K29 Dubbel (7)
Other - Category: Model Groups; Family: Model Group; Family and Type: Model Group: Waterslag K29 Dubbel; Type: Waterslag K29 Dubbel; Type Id: 6656851
Constraints - Origin Level Offset: 0 mm; Reference Level: 1
Identity Data - Workset: Bouwkundig
Other(Type) - Category: Model Groups; Family Name: Model Group
Identity Data(Type) - Workset: Bouwkundig; Type Name: Waterslag K29 Dubbel
Name (Model Group:Waterslag K29 Dubbel:...)
6656850
6658414
6658426
6660297
6660384
6660396
6660527

# IfcGroup: Model Group:Waterslag K29 Enkel, Model Group:Waterslag K29 Enkel:6659751
Other - Category: Model Groups; Family: Model Group; Family and Type: Model Group: Waterslag K29 Enkel; Type: Waterslag K29 Enkel; Type Id: 6659951
Constraints - Origin Level Offset: 0 mm; Reference Level: 1
Identity Data - Workset: Bouwkundig
Other(Type) - Category: Model Groups; Family Name: Model Group
Identity Data(Type) - Workset: Bouwkundig; Type Name: Waterslag K29 Enkel

# IfcGroup: Model Group:berging-gaas 2100 (6)
Other - Category: Model Groups; Family: Model Group; Family and Type: Model Group: berging-gaas 2100; Type: berging-gaas 2100; Type Id: 6536587
Constraints - Origin Level Offset: 0 mm; Reference Level: 0
Identity Data - Workset: situatie
Other(Type) - Category: Model Groups; Family Name: Model Group
Identity Data(Type) - Workset: situatie; Type Name: berging-gaas 2100
Name (Model Group:berging-gaas 2100:...)
6536580
6536592
6536594
6536596
6536598
6536600

# IfcGroup: Model Group:bergingdeur (4)
Other - Category: Model Groups; Family: Model Group; Family and Type: Model Group: bergingdeur; Type: bergingdeur; Type Id: 6495677
Constraints - Origin Level Offset: 0 mm; Reference Level: 0
Identity Data - Workset: situatie
Other(Type) - Category: Model Groups; Family Name: Model Group
Identity Data(Type) - Workset: situatie; Type Name: bergingdeur
Name (Model Group:bergingdeur:...)
6495812
6495828
6495932
6495946

# IfcGroup: Model Group:bergingpaneel 1890 (8)
Other - Category: Model Groups; Family: Model Group; Family and Type: Model Group: bergingpaneel 1890; Type: bergingpaneel 1890; Type Id: 6496385
Constraints - Origin Level Offset: 0 mm; Reference Level: 0
Identity Data - Workset: situatie
Other(Type) - Category: Model Groups; Family Name: Model Group
Identity Data(Type) - Workset: situatie; Type Name: bergingpaneel 1890
Name (Model Group:bergingpaneel 1890:...)
6496384
6496413
6496426
6496488
6621998
6622049
6622058
6622169

# IfcGroup: Model Group:bergingpaneel 2100 (8)
Other - Category: Model Groups; Family: Model Group; Family and Type: Model Group: bergingpaneel 2100; Type: bergingpaneel 2100; Type Id: 6496586
Constraints - Origin Level Offset: 0 mm; Reference Level: 0
Identity Data - Workset: situatie
Other(Type) - Category: Model Groups; Family Name: Model Group
Identity Data(Type) - Workset: situatie; Type Name: bergingpaneel 2100
Name (Model Group:bergingpaneel 2100:...)
6496585
6496607
6496616
6496625
6496636
6496645
6496654
6496665

# IfcGroup: Model Group:negge merk k40 (11)
Other - Category: Model Groups; Family: Model Group; Family and Type: Model Group: negge merk k40; Type: negge merk k40; Type Id: 5915475
Constraints - Origin Level Offset: 0 mm; Reference Level: 0
Identity Data - Workset: Bouwkundig
Other(Type) - Category: Model Groups; Family Name: Model Group
Identity Data(Type) - Workset: Bouwkundig; Type Name: negge merk k40
Name (Model Group:negge merk k40:...)
5915474
5916090
5916098
5916122
5916191
5916225
5916259
5916280
5916328
5917384
5917417

# IfcGroup: Model Group:negge merk k41 (21)
Other - Category: Model Groups; Family: Model Group; Family and Type: Model Group: negge merk k41; Type: negge merk k41; Type Id: 5916383
Constraints - Origin Level Offset: 0 mm; Reference Level: 0
Identity Data - Workset: Bouwkundig
Other(Type) - Category: Model Groups; Family Name: Model Group
Identity Data(Type) - Workset: Bouwkundig; Type Name: negge merk k41
Name (Model Group:negge merk k41:...) | Group
5916371 | Model Group:K_Raamwerk_16:5544055
5916917
5916942
5916974
5917039
5917176
5917231
5917242
5917353
5954455 | Model Group:K_Raamwerk_16:5542459
5954465 | Model Group:K_Raamwerk_16:5544033
5954470 | Model Group:K_Raamwerk_16:5544106
5954475 | Model Group:K_Raamwerk_16:5544132
5954480 | Model Group:K_Raamwerk_16:5544804
5954485 | Model Group:K_Raamwerk_16:5544822
5954490 | Model Group:K_Raamwerk_16:5545033
5954495 | Model Group:K_Raamwerk_16:5545106
5954500 | Model Group:K_Raamwerk_16:5545129
5954505
5954510 | Model Group:K_Raamwerk_16:5856137
5954515 | Model Group:K_Raamwerk_16:5856140

# IfcGroup: Model Group:negge merk k42 (17)
Other - Category: Model Groups; Family: Model Group; Family and Type: Model Group: negge merk k42; Type: negge merk k42; Type Id: 5953989
Constraints - Origin Level Offset: 0 mm; Reference Level: 1
Identity Data - Workset: Bouwkundig
Other(Type) - Category: Model Groups; Family Name: Model Group
Identity Data(Type) - Workset: Bouwkundig; Type Name: negge merk k42
Name (Model Group:negge merk k42:...) | Group
6057861 | Model Group:K_Raamwerk_28:6057727
6058279 | Model Group:K_Raamwerk_28:6058262
6058298 | Model Group:K_Raamwerk_28:6058281
6058317 | Model Group:K_Raamwerk_28:6058300
6058336 | Model Group:K_Raamwerk_28:6058319
6058355 | Model Group:K_Raamwerk_28:6058338
6058374 | Model Group:K_Raamwerk_28:6058357
6058393 | Model Group:K_Raamwerk_28:6058376
6058412 | Model Group:K_Raamwerk_28:6058395
6058431 | Model Group:K_Raamwerk_28:6058414
6058450 | Model Group:K_Raamwerk_28:6058433
6058469 | Model Group:K_Raamwerk_28:6058452
6058488 | Model Group:K_Raamwerk_28:6058471
6058507 | Model Group:K_Raamwerk_28:6058490
6058526 | Model Group:K_Raamwerk_28:6058509
6058545 | Model Group:K_Raamwerk_28:6058528
6058564 | Model Group:K_Raamwerk_28:6058547

# IfcGroup: Model Group:pantry 0.38 en 1.24 (2)
Other - Category: Model Groups; Family: Model Group; Family and Type: Model Group: pantry 0.38 en 1.24; Type: pantry 0.38 en 1.24; Type Id: 6883386
Constraints - Origin Level Offset: 0 mm
Identity Data - Workset: Bouwkundig
Other(Type) - Category: Model Groups; Family Name: Model Group
Identity Data(Type) - Workset: Bouwkundig; Type Name: pantry 0.38 en 1.24
Name (Model Group:pantry 0.38 en 1.24:...) | Reference Level
6883385 | 0
6883476 | 1

# IfcGroup: Model Group:raamwerk K07 (13)
Other - Category: Model Groups; Family: Model Group; Family and Type: Model Group: raamwerk K07; Type: raamwerk K07; Type Id: 5957044
Constraints - Reference Level: V1 bk. ruwe vloer; Origin Level Offset: 90 mm
Identity Data - Workset: Bouwkundig
Other(Type) - Category: Model Groups; Family Name: Model Group
Identity Data(Type) - Workset: Bouwkundig; Type Name: raamwerk K07
Name (Model Group:raamwerk K07:...) | Group
6058698 | Model Group:K_Raamwerk_24:6058628
6059006 | Model Group:K_Raamwerk_24:6058988
6059025 | Model Group:K_Raamwerk_24:6059007
6059044 | Model Group:K_Raamwerk_24:6059026
6059063 | Model Group:K_Raamwerk_24:6059045
6059082 | Model Group:K_Raamwerk_24:6059064
6059101 | Model Group:K_Raamwerk_24:6059083
6059120 | Model Group:K_Raamwerk_24:6059102
6059139 | Model Group:K_Raamwerk_24:6059121
6059158 | Model Group:K_Raamwerk_24:6059140
6059177 | Model Group:K_Raamwerk_24:6059159
6059196 | Model Group:K_Raamwerk_24:6059178
6059215 | Model Group:K_Raamwerk_24:6059197

# IfcGroup: Model Group:spreektafel rond 120+4 stoelen, Model Group:spreektafel rond 120+4 stoelen:5933262
Other - Category: Model Groups; Family: Model Group; Family and Type: Model Group: spreektafel rond 120+4 stoelen; Type: spreektafel rond 120+4 stoelen; Type Id: 5923311
Constraints - Origin Level Offset: 0 mm; Reference Level: 1
Identity Data - Workset: Bouwkundig
Other(Type) - Category: Model Groups; Family Name: Model Group
Identity Data(Type) - Workset: Bouwkundig; Type Name: spreektafel rond 120+4 stoelen

# IfcGroup: Model Group:verschoontafel 800x2700x850 bxlxh (2)
Other - Category: Model Groups; Family: Model Group; Family and Type: Model Group: verschoontafel 800x2700x850 bxlxh; Type: verschoontafel 800x2700x850 bxlxh; Type Id: 6246963
Constraints - Origin Level Offset: 0 mm; Reference Level: 0
Identity Data - Workset: Bouwkundig
Other(Type) - Category: Model Groups; Family Name: Model Group
Identity Data(Type) - Workset: Bouwkundig; Description: verschoontafel vv aansluiting boiler; Type Name: verschoontafel 800x2700x850 bxlxh
Name (Model Group:verschoontafel 800x2700x850 bxlxh:...)
6246962
6246991

# IfcMember: Rectangular Mullion:100x83 Gealan Kubus (437)
Type - PredefinedType: MULLION; Material: ISR_Kunststof_RAL7006
Type - Other - Category: Curtain Wall Mullions; Family Name: Rectangular Mullion
Type - Constraints - Angle: 0 deg; Offset: 41.5 mm
Type - Construction - Corner Mullion: no; Position: Perpendicular to Face; Profile: System Mullion Profile: Rectangular; Thickness: 83 mm
Type - Dimensions - Width on side 1: 50 mm; Width on side 2: 50 mm
Type - Identity Data - Workset: Family : Curtain Wall Mullions : Rectangular Mullion; Manufacturer: Gealan; Type Name: 100x83 Gealan Kubus
Type - Materials and Finishes - Material: ISR_Kunststof_RAL7006
Type - Pset_ManufacturerTypeInformation - Manufacturer: Gealan
Type - Pset_MemberCommon - IsExternal: no
Type - Pset_ProductRequirements - Category: Curtain Wall Mullions
Classification: 31 Uniformat (Uniformat)
Pset_MemberCommon - Reference: 100x83 Gealan Kubus
Pset_QuantityTakeOff - Reference: 100x83 Gealan Kubus
Other - Family: Rectangular Mullion; Family and Type: Rectangular Mullion: 100x83 Gealan Kubus; Type: 100x83 Gealan Kubus; Type Id: 4774139
Identity Data - Workset: Bouwkundig
Phasing - Phase Created: 2. nieuwbouw
Name (Rectangular Mullion:100x83 Gealan Kubus:...) | In | Span (mm) = BaseQuantities, Length (mm) = Dimensions, Length (mm) | CrossSectionArea (m2) = Area (m2) | NetVolume (m3) = Volume (m3) | NetSurfaceArea (m2) | Host Id | Level | Group
5536833 | 00 Begane grond | 540 | 0.10712 | 0.004482 | 0.21424 | 5536831 | 0 | Model Group:Merk K04:5536830 | Pset_MemberCommon - IsExternal: yes
5536835 | 00 Begane grond | 2510 | 0.46763 | 0.020833 | 0.93526 | 5536831 | 0 | Model Group:Merk K04:5536830 | Pset_MemberCommon - IsExternal: yes
5536836 | 00 Begane grond | 2510 | 0.46763 | 0.020833 | 0.93526 | 5536831 | 0 | Model Group:Merk K04:5536830 | Pset_MemberCommon - IsExternal: yes
5536841 | 00 Begane grond | 540 | 0.10712 | 0.004482 | 0.21424 | 5536839 | 0 | Model Group:Merk K04:5536838
5536843 | 00 Begane grond | 2510 | 0.46763 | 0.020833 | 0.93526 | 5536839 | 0 | Model Group:Merk K04:5536838
5536844 | 00 Begane grond | 2510 | 0.46763 | 0.020833 | 0.93526 | 5536839 | 0 | Model Group:Merk K04:5536838
5536849 | 00 Begane grond | 540 | 0.10712 | 0.004482 | 0.21424 | 5536847 | 0 | Model Group:Merk K04:5536846
5536851 | 00 Begane grond | 2510 | 0.46763 | 0.020833 | 0.93526 | 5536847 | 0 | Model Group:Merk K04:5536846
5536852 | 00 Begane grond | 2510 | 0.46763 | 0.020833 | 0.93526 | 5536847 | 0 | Model Group:Merk K04:5536846
5536882 | 00 Begane grond | 1920 | 0.35966 | 0.015936 | 0.71932 | 5536880 | 0 | Model Group:Merk K02:5536879
5536884 | 00 Begane grond | 2510 | 0.46763 | 0.020833 | 0.93526 | 5536880 | 0 | Model Group:Merk K02:5536879
5536885 | 00 Begane grond | 2510 | 0.46763 | 0.020833 | 0.93526 | 5536880 | 0 | Model Group:Merk K02:5536879
5536907 | 00 Begane grond | 1920 | 0.35966 | 0.015936 | 0.71932 | 5536905 | 0 | Model Group:Merk K02:5536904
5536909 | 00 Begane grond | 2510 | 0.46763 | 0.020833 | 0.93526 | 5536905 | 0 | Model Group:Merk K02:5536904
5536910 | 00 Begane grond | 2510 | 0.46763 | 0.020833 | 0.93526 | 5536905 | 0 | Model Group:Merk K02:5536904
5536921 | 00 Begane grond | 720 | 0.14006 | 0.005976 | 0.28012 | 5536919 | 0 | Model Group:Merk K01:5536918
5536923 | 00 Begane grond | 2510 | 0.46763 | 0.020833 | 0.93526 | 5536919 | 0 | Model Group:Merk K01:5536918
5536924 | 00 Begane grond | 2510 | 0.46763 | 0.020833 | 0.93526 | 5536919 | 0 | Model Group:Merk K01:5536918
5536953 | 00 Begane grond | 720 | 0.14006 | 0.005976 | 0.28012 | 5536951 | 0 | Model Group:Merk K01:5536950
5536955 | 00 Begane grond | 2510 | 0.46763 | 0.020833 | 0.93526 | 5536951 | 0 | Model Group:Merk K01:5536950
5536956 | 00 Begane grond | 2510 | 0.46763 | 0.020833 | 0.93526 | 5536951 | 0 | Model Group:Merk K01:5536950
5536967 | 00 Begane grond | 1665 | 0.312995 | 0.0138195 | 0.625989 | 5536965 | 0 | Model Group:Merk K21:5536964
5536969 | 00 Begane grond | 2510 | 0.46763 | 0.020833 | 0.93526 | 5536965 | 0 | Model Group:Merk K21:5536964
5536970 | 00 Begane grond | 2510 | 0.46763 | 0.020833 | 0.93526 | 5536965 | 0 | Model Group:Merk K21:5536964
5537033 | 00 Begane grond | 540 | 0.10712 | 0.004482 | 0.21424 | 5537031 | 0 | Model Group:Merk K04:5537030
5537035 | 00 Begane grond | 2510 | 0.46763 | 0.020833 | 0.93526 | 5537031 | 0 | Model Group:Merk K04:5537030
5537036 | 00 Begane grond | 2510 | 0.46763 | 0.020833 | 0.93526 | 5537031 | 0 | Model Group:Merk K04:5537030
5537068 | 00 Begane grond | 540 | 0.10712 | 0.004482 | 0.21424 | 5537066 | 0 | Model Group:Merk K04:5537065
5537070 | 00 Begane grond | 2510 | 0.46763 | 0.020833 | 0.93526 | 5537066 | 0 | Model Group:Merk K04:5537065
5537071 | 00 Begane grond | 2510 | 0.46763 | 0.020833 | 0.93526 | 5537066 | 0 | Model Group:Merk K04:5537065
5537105 | 00 Begane grond | 1920 | 0.35966 | 0.015936 | 0.71932 | 5537103 | 0 | Model Group:Merk K02:5537102
5537107 | 00 Begane grond | 2510 | 0.46763 | 0.020833 | 0.93526 | 5537103 | 0 | Model Group:Merk K02:5537102
5537108 | 00 Begane grond | 2510 | 0.46763 | 0.020833 | 0.93526 | 5537103 | 0 | Model Group:Merk K02:5537102
5537284 | 00 Begane grond | 590 | 0.11627 | 0.004897 | 0.23254 | 5537282 | 0 | Model Group:Merk K06:5537281
5537286 | 00 Begane grond | 2180 | 0.40724 | 0.018094 | 0.81448 | 5537282 | 0 | Model Group:Merk K06:5537281
5537287 | 00 Begane grond | 2180 | 0.40724 | 0.018094 | 0.81448 | 5537282 | 0 | Model Group:Merk K06:5537281
5537296 | 00 Begane grond | 590 | 0.11627 | 0.004897 | 0.23254 | 5537294 | 0 | Model Group:Merk K06:5537293
5537298 | 00 Begane grond | 2180 | 0.40724 | 0.018094 | 0.81448 | 5537294 | 0 | Model Group:Merk K06:5537293
5537299 | 00 Begane grond | 2180 | 0.40724 | 0.018094 | 0.81448 | 5537294 | 0 | Model Group:Merk K06:5537293
5537335 | 00 Begane grond | 590 | 0.11627 | 0.004897 | 0.23254 | 5537333 | 0 | Model Group:Merk K06:5537332
5537337 | 00 Begane grond | 2180 | 0.40724 | 0.018094 | 0.81448 | 5537333 | 0 | Model Group:Merk K06:5537332
5537338 | 00 Begane grond | 2180 | 0.40724 | 0.018094 | 0.81448 | 5537333 | 0 | Model Group:Merk K06:5537332
5537343 | 00 Begane grond | 590 | 0.11627 | 0.004897 | 0.23254 | 5537341 | 0 | Model Group:Merk K06:5537340
5537345 | 00 Begane grond | 2180 | 0.40724 | 0.018094 | 0.81448 | 5537341 | 0 | Model Group:Merk K06:5537340
5537346 | 00 Begane grond | 2180 | 0.40724 | 0.018094 | 0.81448 | 5537341 | 0 | Model Group:Merk K06:5537340
5537388 | 00 Begane grond | 2030 | 0.37979 | 0.016849 | 0.75958 | 5537386 | 0 | Model Group:Merk K08:5537385
5537390 | 00 Begane grond | 2720 | 0.50606 | 0.022576 | 1.00382 | 5537386 | 0 | Model Group:Merk K08:5537385
5537391 | 00 Begane grond | 2740 | 0.50972 | 0.022742 | 1.01114 | 5537386 | 0 | Model Group:Merk K08:5537385
5539241 | 00 Begane grond | 2840 | 0.52802 | 0.023572 | 1.04774 | 5537386 | 0 | Model Group:Merk K08:5537385
5539242 | 00 Begane grond | 2840 | 0.52802 | 0.023572 | 1.04774 | 5537386 | 0 | Model Group:Merk K08:5537385
5537396 | 00 Begane grond | 790 | 0.15287 | 0.006557 | 0.30574 | 5537394 | 0 | Model Group:Merk K09:5537393
5537398 | 00 Begane grond | 3048 | 0.566084 | 0.0252984 | 1.12387 | 5537394 | 0 | Model Group:Merk K09:5537393
5537399 | 00 Begane grond | 1787 | 0.335321 | 0.0148321 | 0.662342 | 5537394 | 0 | Model Group:Merk K09:5537393
5539247 | 00 Begane grond | 1787 | 0.335321 | 0.0148321 | 0.662342 | 5537394 | 0 | Model Group:Merk K09:5537393
5539248 | 00 Begane grond | 3048 | 0.566084 | 0.0252984 | 1.12387 | 5537394 | 0 | Model Group:Merk K09:5537393
5537404 | 00 Begane grond | 690 | 0.13457 | 0.005727 | 0.26914 | 5537402 | 0 | Model Group:Merk K10:5537401
5537406 | 00 Begane grond | 1480 | 0.27914 | 0.012284 | 0.54998 | 5537402 | 0 | Model Group:Merk K10:5537401
5537407 | 00 Begane grond | 2730 | 0.50789 | 0.022659 | 1.00748 | 5537402 | 0 | Model Group:Merk K10:5537401
6896998 | 00 Begane grond | 2830 | 0.52619 | 0.023489 | 1.04408 | 5537402 | 0 | Model Group:Merk K10:5537401
6896999 | 00 Begane grond | 1600 | 0.3011 | 0.01328 | 0.5939 | 5537402 | 0 | Model Group:Merk K10:5537401
5537412 | 00 Begane grond | 690 | 0.13457 | 0.005727 | 0.26914 | 5537410 | 0 | Model Group:Merk K11:5537409
5537414 | 00 Begane grond | 1798 | 0.337334 | 0.0149234 | 0.666368 | 5537410 | 0 | Model Group:Merk K11:5537409
5537415 | 00 Begane grond | 1787 | 0.335321 | 0.0148321 | 0.662342 | 5537410 | 0 | Model Group:Merk K11:5537409
6896095 | 00 Begane grond | 1887 | 0.353621 | 0.0156621 | 0.698942 | 5537410 | 0 | Model Group:Merk K11:5537409
6896096 | 00 Begane grond | 1918 | 0.359294 | 0.0159194 | 0.710288 | 5537410 | 0 | Model Group:Merk K11:5537409
5537420 | 00 Begane grond | 590 | 0.11627 | 0.004897 | 0.23254 | 5537418 | 0 | Model Group:Merk K12:5537417
5537422 | 00 Begane grond | 3180 | 0.59024 | 0.026394 | 1.18048 | 5537418 | 0 | Model Group:Merk K12:5537417
5537423 | 00 Begane grond | 3180 | 0.59024 | 0.026394 | 1.18048 | 5537418 | 0 | Model Group:Merk K12:5537417
5537428 | 00 Begane grond | 590 | 0.11627 | 0.004897 | 0.23254 | 5537426 | 0 | Model Group:Merk K13:5537425
5537430 | 00 Begane grond | 2555 | 0.475865 | 0.0212065 | 0.95173 | 5537426 | 0 | Model Group:Merk K13:5537425
5537431 | 00 Begane grond | 2555 | 0.475865 | 0.0212065 | 0.95173 | 5537426 | 0 | Model Group:Merk K13:5537425
5537505 | 00 Begane grond | 767 | 0.148661 | 0.0063661 | 0.289022 | 5537503 | 0 | Model Group:Merk K07:5537502
5537507 | 00 Begane grond | 1960 | 0.36698 | 0.016268 | 0.73396 | 5537503 | 0 | Model Group:Merk K07:5537502
5537508 | 00 Begane grond | 1960 | 0.36698 | 0.016268 | 0.73396 | 5537503 | 0 | Model Group:Merk K07:5537502
5611176 | 00 Begane grond | 1533 | 0.288839 | 0.0127239 | 0.569378 | 5537503 | 0 | Model Group:Merk K07:5537502
5537528 | 00 Begane grond | 1295 | 0.245285 | 0.0107485 | 0.49057 | 5537526 | 0 | Model Group:Merk K14:5537525
5537530 | 00 Begane grond | 2630 | 0.48959 | 0.021829 | 0.97918 | 5537526 | 0 | Model Group:Merk K14:5537525
5537531 | 00 Begane grond | 2630 | 0.48959 | 0.021829 | 0.97918 | 5537526 | 0 | Model Group:Merk K14:5537525
5537539 | 00 Begane grond | 863 | 0.166229 | 0.0071629 | 0.324158 | 5537537 | 0 | Model Group:Merk K15:5537536
5537541 | 00 Begane grond | 2410 | 0.44933 | 0.020003 | 0.89866 | 5537537 | 0 | Model Group:Merk K15:5537536
5537542 | 00 Begane grond | 2490 | 0.46397 | 0.020667 | 0.92794 | 5537537 | 0 | Model Group:Merk K15:5537536
5537546 | 00 Begane grond | 978 | 0.187274 | 0.0081174 | 0.357948 | 5537537 | 0 | Model Group:Merk K15:5537536
5537551 | 00 Begane grond | 1075 | 0.205025 | 0.0089225 | 0.40175 | 5537537 | 0 | Model Group:Merk K15:5537536
6479920 | 00 Begane grond | 534 | 0.106022 | 0.0044322 | 0.195444 | 5537537 | 0 | Model Group:Merk K15:5537536
5537727 | 00 Begane grond | 767 | 0.148661 | 0.0063661 | 0.289022 | 5537725 | 0 | Model Group:Merk K07:5537724
5537729 | 00 Begane grond | 1960 | 0.36698 | 0.016268 | 0.73396 | 5537725 | 0 | Model Group:Merk K07:5537724
5537730 | 00 Begane grond | 1960 | 0.36698 | 0.016268 | 0.73396 | 5537725 | 0 | Model Group:Merk K07:5537724
5611359 | 00 Begane grond | 1533 | 0.288839 | 0.0127239 | 0.569378 | 5537725 | 0 | Model Group:Merk K07:5537724
5537742 | 01 eerste verdieping | 590 | 0.11627 | 0.004897 | 0.23254 | 5537740 | 1 | Model Group:Merk K30:5537739
5537744 | 01 eerste verdieping | 1810 | 0.33953 | 0.015023 | 0.67906 | 5537740 | 1 | Model Group:Merk K30:5537739
5537745 | 01 eerste verdieping | 1810 | 0.33953 | 0.015023 | 0.67906 | 5537740 | 1 | Model Group:Merk K30:5537739
5537750 | 01 eerste verdieping | 1864 | 0.349412 | 0.0154712 | 0.698824 | 5537748 | 1 | Model Group:Merk K23:5537747
5537752 | 01 eerste verdieping | 1810 | 0.33953 | 0.015023 | 0.67906 | 5537748 | 1 | Model Group:Merk K23:5537747
5537753 | 01 eerste verdieping | 1810 | 0.33953 | 0.015023 | 0.67906 | 5537748 | 1 | Model Group:Merk K23:5537747
5537977 | 01 eerste verdieping | 945 | 0.181235 | 0.0078435 | 0.36247 | 5537975 | 1 | Model Group:Merk K25:5537974
5537979 | 01 eerste verdieping | 1810 | 0.33953 | 0.015023 | 0.67906 | 5537975 | 1 | Model Group:Merk K25:5537974
5537980 | 01 eerste verdieping | 1810 | 0.33953 | 0.015023 | 0.67906 | 5537975 | 1 | Model Group:Merk K25:5537974
5537984 | 01 eerste verdieping | 590 | 0.11627 | 0.004897 | 0.23254 | 5537982 | 1 | Model Group:Merk K29:5537981
5537986 | 01 eerste verdieping | 1930 | 0.36149 | 0.016019 | 0.72298 | 5537982 | 1 | Model Group:Merk K29:5537981
5537987 | 01 eerste verdieping | 1930 | 0.36149 | 0.016019 | 0.72298 | 5537982 | 1 | Model Group:Merk K29:5537981
5537993 | 01 eerste verdieping | 1483 | 0.279689 | 0.0123089 | 0.551078 | 5537991 | 1 | Model Group:Merk K22:5537990
5537995 | 01 eerste verdieping | 1710 | 0.32123 | 0.014193 | 0.64246 | 5537991 | 1 | Model Group:Merk K22:5537990
5537996 | 01 eerste verdieping | 1710 | 0.32123 | 0.014193 | 0.64246 | 5537991 | 1 | Model Group:Merk K22:5537990
5549596 | 01 eerste verdieping | 767 | 0.148661 | 0.0063661 | 0.289022 | 5537991 | 1 | Model Group:Merk K22:5537990
5538001 | 01 eerste verdieping | 1483 | 0.279689 | 0.0123089 | 0.551078 | 5537999 | 1 | Model Group:Merk K22:5537998
5538003 | 01 eerste verdieping | 1710 | 0.32123 | 0.014193 | 0.64246 | 5537999 | 1 | Model Group:Merk K22:5537998
5538004 | 01 eerste verdieping | 1710 | 0.32123 | 0.014193 | 0.64246 | 5537999 | 1 | Model Group:Merk K22:5537998
5548699 | 01 eerste verdieping | 767 | 0.148661 | 0.0063661 | 0.289022 | 5537999 | 1 | Model Group:Merk K22:5537998
5538009 | 01 eerste verdieping | 1483 | 0.279689 | 0.0123089 | 0.551078 | 5538007 | 1 | Model Group:Merk K22:5538006
5538011 | 01 eerste verdieping | 1710 | 0.32123 | 0.014193 | 0.64246 | 5538007 | 1 | Model Group:Merk K22:5538006
5538012 | 01 eerste verdieping | 1710 | 0.32123 | 0.014193 | 0.64246 | 5538007 | 1 | Model Group:Merk K22:5538006
5549605 | 01 eerste verdieping | 767 | 0.148661 | 0.0063661 | 0.289022 | 5538007 | 1 | Model Group:Merk K22:5538006
5538017 | 01 eerste verdieping | 1483 | 0.279689 | 0.0123089 | 0.551078 | 5538015 | 1 | Model Group:Merk K22:5538014
5538019 | 01 eerste verdieping | 1710 | 0.32123 | 0.014193 | 0.64246 | 5538015 | 1 | Model Group:Merk K22:5538014
5538020 | 01 eerste verdieping | 1710 | 0.32123 | 0.014193 | 0.64246 | 5538015 | 1 | Model Group:Merk K22:5538014
5549614 | 01 eerste verdieping | 767 | 0.148661 | 0.0063661 | 0.289022 | 5538015 | 1 | Model Group:Merk K22:5538014
5538025 | 01 eerste verdieping | 1483 | 0.279689 | 0.0123089 | 0.551078 | 5538023 | 1 | Model Group:Merk K22:5538022
5538027 | 01 eerste verdieping | 1710 | 0.32123 | 0.014193 | 0.64246 | 5538023 | 1 | Model Group:Merk K22:5538022
5538028 | 01 eerste verdieping | 1710 | 0.32123 | 0.014193 | 0.64246 | 5538023 | 1 | Model Group:Merk K22:5538022
5549623 | 01 eerste verdieping | 767 | 0.148661 | 0.0063661 | 0.289022 | 5538023 | 1 | Model Group:Merk K22:5538022
5538033 | 01 eerste verdieping | 1483 | 0.279689 | 0.0123089 | 0.551078 | 5538031 | 1 | Model Group:Merk K22:5538030
5538035 | 01 eerste verdieping | 1710 | 0.32123 | 0.014193 | 0.64246 | 5538031 | 1 | Model Group:Merk K22:5538030
5538036 | 01 eerste verdieping | 1710 | 0.32123 | 0.014193 | 0.64246 | 5538031 | 1 | Model Group:Merk K22:5538030
5549632 | 01 eerste verdieping | 767 | 0.148661 | 0.0063661 | 0.289022 | 5538031 | 1 | Model Group:Merk K22:5538030
5538041 | 01 eerste verdieping | 1483 | 0.279689 | 0.0123089 | 0.551078 | 5538039 | 1 | Model Group:Merk K22:5538038
5538043 | 01 eerste verdieping | 1710 | 0.32123 | 0.014193 | 0.64246 | 5538039 | 1 | Model Group:Merk K22:5538038
5538044 | 01 eerste verdieping | 1710 | 0.32123 | 0.014193 | 0.64246 | 5538039 | 1 | Model Group:Merk K22:5538038
5549641 | 01 eerste verdieping | 767 | 0.148661 | 0.0063661 | 0.289022 | 5538039 | 1 | Model Group:Merk K22:5538038
5538049 | 01 eerste verdieping | 1483 | 0.279689 | 0.0123089 | 0.551078 | 5538047 | 1 | Model Group:Merk K22:5538046
5538051 | 01 eerste verdieping | 1710 | 0.32123 | 0.014193 | 0.64246 | 5538047 | 1 | Model Group:Merk K22:5538046
5538052 | 01 eerste verdieping | 1710 | 0.32123 | 0.014193 | 0.64246 | 5538047 | 1 | Model Group:Merk K22:5538046
5549650 | 01 eerste verdieping | 767 | 0.148661 | 0.0063661 | 0.289022 | 5538047 | 1 | Model Group:Merk K22:5538046
5538057 | 01 eerste verdieping | 1483 | 0.279689 | 0.0123089 | 0.551078 | 5538055 | 1 | Model Group:Merk K22:5538054
5538059 | 01 eerste verdieping | 1710 | 0.32123 | 0.014193 | 0.64246 | 5538055 | 1 | Model Group:Merk K22:5538054
5538060 | 01 eerste verdieping | 1710 | 0.32123 | 0.014193 | 0.64246 | 5538055 | 1 | Model Group:Merk K22:5538054
5549659 | 01 eerste verdieping | 767 | 0.148661 | 0.0063661 | 0.289022 | 5538055 | 1 | Model Group:Merk K22:5538054
5538065 | 01 eerste verdieping | 1483 | 0.279689 | 0.0123089 | 0.551078 | 5538063 | 1 | Model Group:Merk K22:5538062
5538067 | 01 eerste verdieping | 1710 | 0.32123 | 0.014193 | 0.64246 | 5538063 | 1 | Model Group:Merk K22:5538062
5538068 | 01 eerste verdieping | 1710 | 0.32123 | 0.014193 | 0.64246 | 5538063 | 1 | Model Group:Merk K22:5538062
5549668 | 01 eerste verdieping | 767 | 0.148661 | 0.0063661 | 0.289022 | 5538063 | 1 | Model Group:Merk K22:5538062
5538073 | 01 eerste verdieping | 1483 | 0.279689 | 0.0123089 | 0.551078 | 5538071 | 1 | Model Group:Merk K22:5538070
5538075 | 01 eerste verdieping | 1710 | 0.32123 | 0.014193 | 0.64246 | 5538071 | 1 | Model Group:Merk K22:5538070
5538076 | 01 eerste verdieping | 1710 | 0.32123 | 0.014193 | 0.64246 | 5538071 | 1 | Model Group:Merk K22:5538070
5549677 | 01 eerste verdieping | 767 | 0.148661 | 0.0063661 | 0.289022 | 5538071 | 1 | Model Group:Merk K22:5538070
5538081 | 01 eerste verdieping | 1483 | 0.279689 | 0.0123089 | 0.551078 | 5538079 | 1 | Model Group:Merk K22:5538078
5538083 | 01 eerste verdieping | 1710 | 0.32123 | 0.014193 | 0.64246 | 5538079 | 1 | Model Group:Merk K22:5538078
5538084 | 01 eerste verdieping | 1710 | 0.32123 | 0.014193 | 0.64246 | 5538079 | 1 | Model Group:Merk K22:5538078
5549686 | 01 eerste verdieping | 767 | 0.148661 | 0.0063661 | 0.289022 | 5538079 | 1 | Model Group:Merk K22:5538078
5538089 | 01 eerste verdieping | 1483 | 0.279689 | 0.0123089 | 0.551078 | 5538087 | 1 | Model Group:Merk K22:5538086
5538091 | 01 eerste verdieping | 1710 | 0.32123 | 0.014193 | 0.64246 | 5538087 | 1 | Model Group:Merk K22:5538086
5538092 | 01 eerste verdieping | 1710 | 0.32123 | 0.014193 | 0.64246 | 5538087 | 1 | Model Group:Merk K22:5538086
5549695 | 01 eerste verdieping | 767 | 0.148661 | 0.0063661 | 0.289022 | 5538087 | 1 | Model Group:Merk K22:5538086
5538105 | 01 eerste verdieping | 1483 | 0.279689 | 0.0123089 | 0.551078 | 5538103 | 1 | Model Group:Merk K32:5538102
5538107 | 01 eerste verdieping | 1710 | 0.32123 | 0.014193 | 0.64246 | 5538103 | 1 | Model Group:Merk K32:5538102
5538108 | 01 eerste verdieping | 1710 | 0.32123 | 0.014193 | 0.64246 | 5538103 | 1 | Model Group:Merk K32:5538102
5549713 | 01 eerste verdieping | 767 | 0.148661 | 0.0063661 | 0.289022 | 5538103 | 1 | Model Group:Merk K32:5538102
5538113 | 01 eerste verdieping | 590 | 0.11627 | 0.004897 | 0.23254 | 5538111 | 1 | Model Group:Merk K29:5538110
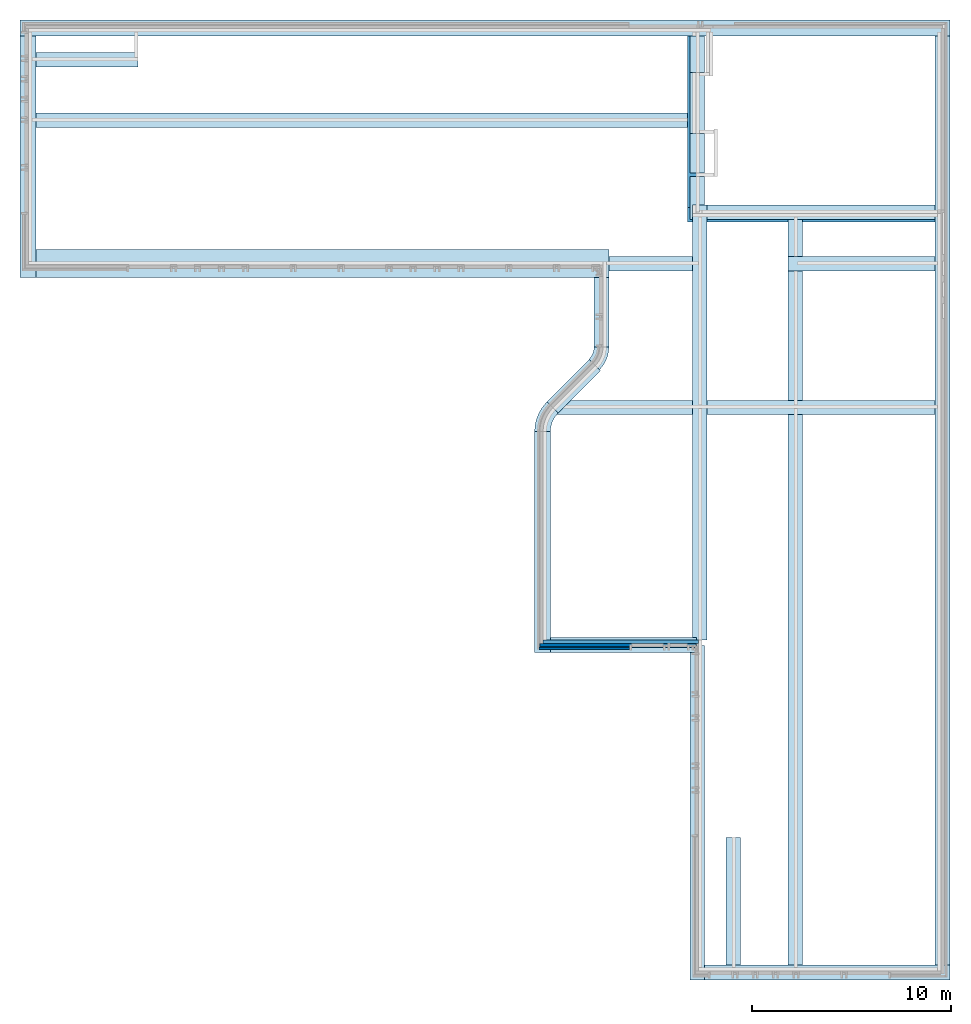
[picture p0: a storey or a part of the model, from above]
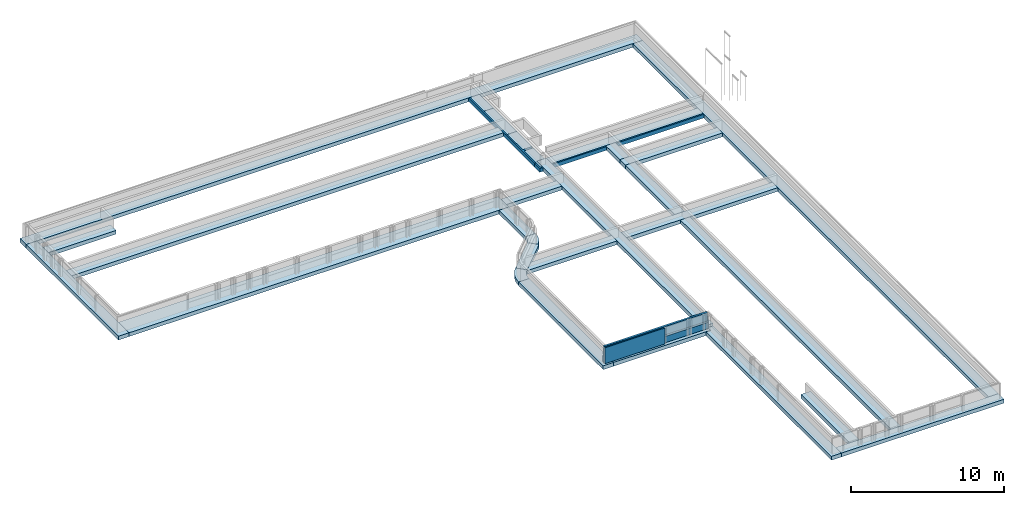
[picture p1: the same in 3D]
Properties of the parts of a building model (IFC2X3), part 18 of 37

# IfcMember: Rectangular Mullion:100x83 Gealan Kubus (437)
Name (Rectangular Mullion:100x83 Gealan Kubus:...) | In | Span (mm) = BaseQuantities, Length (mm) = Dimensions, Length (mm) | CrossSectionArea (m2) = Area (m2) | NetVolume (m3) = Volume (m3) | NetSurfaceArea (m2) | Host Id | Level | Group
5538115 | 01 eerste verdieping | 1930 | 0.36149 | 0.016019 | 0.72298 | 5538111 | 1 | Model Group:Merk K29:5538110
5538116 | 01 eerste verdieping | 1930 | 0.36149 | 0.016019 | 0.72298 | 5538111 | 1 | Model Group:Merk K29:5538110
5538122 | 01 eerste verdieping | 590 | 0.11627 | 0.004897 | 0.23254 | 5538120 | 1 | Model Group:Merk K29:5538119
5538124 | 01 eerste verdieping | 1930 | 0.36149 | 0.016019 | 0.72298 | 5538120 | 1 | Model Group:Merk K29:5538119
5538125 | 01 eerste verdieping | 1930 | 0.36149 | 0.016019 | 0.72298 | 5538120 | 1 | Model Group:Merk K29:5538119
5538131 | 01 eerste verdieping | 590 | 0.11627 | 0.004897 | 0.23254 | 5538129 | 1 | Model Group:Merk K29:5538128
5538133 | 01 eerste verdieping | 1930 | 0.36149 | 0.016019 | 0.72298 | 5538129 | 1 | Model Group:Merk K29:5538128
5538134 | 01 eerste verdieping | 1930 | 0.36149 | 0.016019 | 0.72298 | 5538129 | 1 | Model Group:Merk K29:5538128
5538140 | 01 eerste verdieping | 590 | 0.11627 | 0.004897 | 0.23254 | 5538138 | 1 | Model Group:Merk K29:5538137
5538142 | 01 eerste verdieping | 1930 | 0.36149 | 0.016019 | 0.72298 | 5538138 | 1 | Model Group:Merk K29:5538137
5538143 | 01 eerste verdieping | 1930 | 0.36149 | 0.016019 | 0.72298 | 5538138 | 1 | Model Group:Merk K29:5538137
5538149 | 01 eerste verdieping | 590 | 0.11627 | 0.004897 | 0.23254 | 5538147 | 1 | Model Group:Merk K29:5538146
5538151 | 01 eerste verdieping | 1930 | 0.36149 | 0.016019 | 0.72298 | 5538147 | 1 | Model Group:Merk K29:5538146
5538152 | 01 eerste verdieping | 1930 | 0.36149 | 0.016019 | 0.72298 | 5538147 | 1 | Model Group:Merk K29:5538146
5538158 | 01 eerste verdieping | 590 | 0.11627 | 0.004897 | 0.23254 | 5538156 | 1 | Model Group:Merk K29:5538155
5538160 | 01 eerste verdieping | 1930 | 0.36149 | 0.016019 | 0.72298 | 5538156 | 1 | Model Group:Merk K29:5538155
5538161 | 01 eerste verdieping | 1930 | 0.36149 | 0.016019 | 0.72298 | 5538156 | 1 | Model Group:Merk K29:5538155
5538167 | 01 eerste verdieping | 590 | 0.11627 | 0.004897 | 0.23254 | 5538165 | 1 | Model Group:Merk K29:5538164
5538169 | 01 eerste verdieping | 1930 | 0.36149 | 0.016019 | 0.72298 | 5538165 | 1 | Model Group:Merk K29:5538164
5538170 | 01 eerste verdieping | 1930 | 0.36149 | 0.016019 | 0.72298 | 5538165 | 1 | Model Group:Merk K29:5538164
5538176 | 01 eerste verdieping | 590 | 0.11627 | 0.004897 | 0.23254 | 5538174 | 1 | Model Group:Merk K29:5538173
5538178 | 01 eerste verdieping | 1930 | 0.36149 | 0.016019 | 0.72298 | 5538174 | 1 | Model Group:Merk K29:5538173
5538179 | 01 eerste verdieping | 1930 | 0.36149 | 0.016019 | 0.72298 | 5538174 | 1 | Model Group:Merk K29:5538173
5538185 | 01 eerste verdieping | 590 | 0.11627 | 0.004897 | 0.23254 | 5538183 | 1 | Model Group:Merk K29:5538182
5538187 | 01 eerste verdieping | 1930 | 0.36149 | 0.016019 | 0.72298 | 5538183 | 1 | Model Group:Merk K29:5538182
5538188 | 01 eerste verdieping | 1930 | 0.36149 | 0.016019 | 0.72298 | 5538183 | 1 | Model Group:Merk K29:5538182
5538194 | 01 eerste verdieping | 590 | 0.11627 | 0.004897 | 0.23254 | 5538192 | 1 | Model Group:Merk K29:5538191
5538196 | 01 eerste verdieping | 1930 | 0.36149 | 0.016019 | 0.72298 | 5538192 | 1 | Model Group:Merk K29:5538191
5538197 | 01 eerste verdieping | 1930 | 0.36149 | 0.016019 | 0.72298 | 5538192 | 1 | Model Group:Merk K29:5538191
5538203 | 01 eerste verdieping | 590 | 0.11627 | 0.004897 | 0.23254 | 5538201 | 1 | Model Group:Merk K29:5538200
5538205 | 01 eerste verdieping | 1930 | 0.36149 | 0.016019 | 0.72298 | 5538201 | 1 | Model Group:Merk K29:5538200
5538206 | 01 eerste verdieping | 1930 | 0.36149 | 0.016019 | 0.72298 | 5538201 | 1 | Model Group:Merk K29:5538200
5538212 | 01 eerste verdieping | 590 | 0.11627 | 0.004897 | 0.23254 | 5538210 | 1 | Model Group:Merk K29:5538209
5538214 | 01 eerste verdieping | 1930 | 0.36149 | 0.016019 | 0.72298 | 5538210 | 1 | Model Group:Merk K29:5538209
5538215 | 01 eerste verdieping | 1930 | 0.36149 | 0.016019 | 0.72298 | 5538210 | 1 | Model Group:Merk K29:5538209
5538221 | 01 eerste verdieping | 590 | 0.11627 | 0.004897 | 0.23254 | 5538219 | 1 | Model Group:Merk K29:5538218
5538223 | 01 eerste verdieping | 1930 | 0.36149 | 0.016019 | 0.72298 | 5538219 | 1 | Model Group:Merk K29:5538218
5538224 | 01 eerste verdieping | 1930 | 0.36149 | 0.016019 | 0.72298 | 5538219 | 1 | Model Group:Merk K29:5538218
5538230 | 01 eerste verdieping | 590 | 0.11627 | 0.004897 | 0.23254 | 5538228 | 1 | Model Group:Merk K29:5538227
5538232 | 01 eerste verdieping | 1930 | 0.36149 | 0.016019 | 0.72298 | 5538228 | 1 | Model Group:Merk K29:5538227
5538233 | 01 eerste verdieping | 1930 | 0.36149 | 0.016019 | 0.72298 | 5538228 | 1 | Model Group:Merk K29:5538227
5538239 | 01 eerste verdieping | 590 | 0.11627 | 0.004897 | 0.23254 | 5538237 | 1 | Model Group:Merk K29:5538236
5538241 | 01 eerste verdieping | 1930 | 0.36149 | 0.016019 | 0.72298 | 5538237 | 1 | Model Group:Merk K29:5538236
5538242 | 01 eerste verdieping | 1930 | 0.36149 | 0.016019 | 0.72298 | 5538237 | 1 | Model Group:Merk K29:5538236
5538248 | 01 eerste verdieping | 590 | 0.11627 | 0.004897 | 0.23254 | 5538246 | 1 | Model Group:Merk K29:5538245
5538250 | 01 eerste verdieping | 1930 | 0.36149 | 0.016019 | 0.72298 | 5538246 | 1 | Model Group:Merk K29:5538245
5538251 | 01 eerste verdieping | 1930 | 0.36149 | 0.016019 | 0.72298 | 5538246 | 1 | Model Group:Merk K29:5538245
5538257 | 01 eerste verdieping | 590 | 0.11627 | 0.004897 | 0.23254 | 5538255 | 1 | Model Group:Merk K29:5538254
5538259 | 01 eerste verdieping | 1930 | 0.36149 | 0.016019 | 0.72298 | 5538255 | 1 | Model Group:Merk K29:5538254
5538260 | 01 eerste verdieping | 1930 | 0.36149 | 0.016019 | 0.72298 | 5538255 | 1 | Model Group:Merk K29:5538254
5538530 | 01 eerste verdieping | 1295 | 0.245285 | 0.0107485 | 0.49057 | 5538528 | 1 | Model Group:Merk K26:5538527
5538532 | 01 eerste verdieping | 2760 | 0.51338 | 0.022908 | 1.02676 | 5538528 | 1 | Model Group:Merk K26:5538527
5538533 | 01 eerste verdieping | 2760 | 0.51338 | 0.022908 | 1.02676 | 5538528 | 1 | Model Group:Merk K26:5538527
5538544 | 01 eerste verdieping | 2122 | 0.396626 | 0.0176126 | 0.784952 | 5538542 | 1 | Model Group:Merk K27:5538541
5538546 | 01 eerste verdieping | 2640 | 0.49142 | 0.021912 | 0.98284 | 5538542 | 1 | Model Group:Merk K27:5538541
5538547 | 01 eerste verdieping | 2540 | 0.47312 | 0.021082 | 0.94624 | 5538542 | 1 | Model Group:Merk K27:5538541
5553897 | 01 eerste verdieping | 1228 | 0.233024 | 0.0101924 | 0.457748 | 5538542 | 1 | Model Group:Merk K27:5538541
5538687 | 00 Begane grond | 1435 | 0.270905 | 0.0119105 | 0.54181 | 5538685 | 0 | Model Group:Merk K18:5538684
5538689 | 00 Begane grond | 2510 | 0.46763 | 0.020833 | 0.93526 | 5538685 | 0 | Model Group:Merk K18:5538684
5538690 | 00 Begane grond | 2510 | 0.46763 | 0.020833 | 0.93526 | 5538685 | 0 | Model Group:Merk K18:5538684
5538737 | 00 Begane grond | 1920 | 0.35966 | 0.015936 | 0.71932 | 5538735 | 0 | Model Group:Merk K02:5538734
5538739 | 00 Begane grond | 2510 | 0.46763 | 0.020833 | 0.93526 | 5538735 | 0 | Model Group:Merk K02:5538734
5538740 | 00 Begane grond | 2510 | 0.46763 | 0.020833 | 0.93526 | 5538735 | 0 | Model Group:Merk K02:5538734
5538747 | 00 Begane grond | 1920 | 0.35966 | 0.015936 | 0.71932 | 5538745 | 0 | Model Group:Merk K02:5538744
5538749 | 00 Begane grond | 2510 | 0.46763 | 0.020833 | 0.93526 | 5538745 | 0 | Model Group:Merk K02:5538744
5538750 | 00 Begane grond | 2510 | 0.46763 | 0.020833 | 0.93526 | 5538745 | 0 | Model Group:Merk K02:5538744
5538755 | 00 Begane grond | 1920 | 0.35966 | 0.015936 | 0.71932 | 5538753 | 0 | Model Group:Merk K02:5538752
5538757 | 00 Begane grond | 2510 | 0.46763 | 0.020833 | 0.93526 | 5538753 | 0 | Model Group:Merk K02:5538752
5538758 | 00 Begane grond | 2510 | 0.46763 | 0.020833 | 0.93526 | 5538753 | 0 | Model Group:Merk K02:5538752
5539069 | 00 Begane grond | 1090 | 0.20777 | 0.009047 | 0.41554 | 5539067 | 0 | Model Group:Merk K19:5539066
5539071 | 00 Begane grond | 2510 | 0.46763 | 0.020833 | 0.93526 | 5539067 | 0 | Model Group:Merk K19:5539066
5539072 | 00 Begane grond | 2510 | 0.46763 | 0.020833 | 0.93526 | 5539067 | 0 | Model Group:Merk K19:5539066
5539198 | 00 Begane grond | 1435 | 0.270905 | 0.0119105 | 0.54181 | 5539196 | 0 | Model Group:Merk K18:5539194
5539200 | 00 Begane grond | 2510 | 0.46763 | 0.020833 | 0.93526 | 5539196 | 0 | Model Group:Merk K18:5539194
5539201 | 00 Begane grond | 2510 | 0.46763 | 0.020833 | 0.93526 | 5539196 | 0 | Model Group:Merk K18:5539194
5539227 | 00 Begane grond | 720 | 0.14006 | 0.005976 | 0.28012 | 5539225 | 0 | Model Group:Merk K01:5539224
5539229 | 00 Begane grond | 2510 | 0.46763 | 0.020833 | 0.93526 | 5539225 | 0 | Model Group:Merk K01:5539224
5539230 | 00 Begane grond | 2510 | 0.46763 | 0.020833 | 0.93526 | 5539225 | 0 | Model Group:Merk K01:5539224
5542013 | 00 Begane grond | 1183 | 0.224789 | 0.0098189 | 0.441278 | 5542011 | 0 | Model Group:Merk K17:5540560
5542015 | 00 Begane grond | 1710 | 0.32123 | 0.014193 | 0.64246 | 5542011 | 0 | Model Group:Merk K17:5540560
5542016 | 00 Begane grond | 1710 | 0.32123 | 0.014193 | 0.64246 | 5542011 | 0 | Model Group:Merk K17:5540560
5542020 | 00 Begane grond | 857 | 0.165131 | 0.0071131 | 0.321962 | 5542011 | 0 | Model Group:Merk K17:5540560
5542290 | 00 Begane grond | 1183 | 0.224789 | 0.0098189 | 0.441278 | 5542288 | 0 | Model Group:Merk K17:5542284
5542292 | 00 Begane grond | 1710 | 0.32123 | 0.014193 | 0.64246 | 5542288 | 0 | Model Group:Merk K17:5542284
5542293 | 00 Begane grond | 1710 | 0.32123 | 0.014193 | 0.64246 | 5542288 | 0 | Model Group:Merk K17:5542284
5542297 | 00 Begane grond | 857 | 0.165131 | 0.0071131 | 0.321962 | 5542288 | 0 | Model Group:Merk K17:5542284
5542316 | 00 Begane grond | 1183 | 0.224789 | 0.0098189 | 0.441278 | 5542314 | 0 | Model Group:Merk K17:5542310
5542318 | 00 Begane grond | 1710 | 0.32123 | 0.014193 | 0.64246 | 5542314 | 0 | Model Group:Merk K17:5542310
5542319 | 00 Begane grond | 1710 | 0.32123 | 0.014193 | 0.64246 | 5542314 | 0 | Model Group:Merk K17:5542310
5542323 | 00 Begane grond | 857 | 0.165131 | 0.0071131 | 0.321962 | 5542314 | 0 | Model Group:Merk K17:5542310
5542342 | 00 Begane grond | 1183 | 0.224789 | 0.0098189 | 0.441278 | 5542340 | 0 | Model Group:Merk K17:5542336
5542344 | 00 Begane grond | 1710 | 0.32123 | 0.014193 | 0.64246 | 5542340 | 0 | Model Group:Merk K17:5542336
5542345 | 00 Begane grond | 1710 | 0.32123 | 0.014193 | 0.64246 | 5542340 | 0 | Model Group:Merk K17:5542336
5542349 | 00 Begane grond | 857 | 0.165131 | 0.0071131 | 0.321962 | 5542340 | 0 | Model Group:Merk K17:5542336
5542368 | 00 Begane grond | 1183 | 0.224789 | 0.0098189 | 0.441278 | 5542366 | 0 | Model Group:Merk K17:5542362
5542370 | 00 Begane grond | 1710 | 0.32123 | 0.014193 | 0.64246 | 5542366 | 0 | Model Group:Merk K17:5542362
5542371 | 00 Begane grond | 1710 | 0.32123 | 0.014193 | 0.64246 | 5542366 | 0 | Model Group:Merk K17:5542362
5542375 | 00 Begane grond | 857 | 0.165131 | 0.0071131 | 0.321962 | 5542366 | 0 | Model Group:Merk K17:5542362
5542394 | 00 Begane grond | 1183 | 0.224789 | 0.0098189 | 0.441278 | 5542392 | 0 | Model Group:Merk K17:5542388
5542396 | 00 Begane grond | 1710 | 0.32123 | 0.014193 | 0.64246 | 5542392 | 0 | Model Group:Merk K17:5542388
5542397 | 00 Begane grond | 1710 | 0.32123 | 0.014193 | 0.64246 | 5542392 | 0 | Model Group:Merk K17:5542388
5542401 | 00 Begane grond | 857 | 0.165131 | 0.0071131 | 0.321962 | 5542392 | 0 | Model Group:Merk K17:5542388
5542466 | 00 Begane grond | 680 | 0.13274 | 0.005644 | 0.26548 | 5542464 | 0 | Model Group:Merk K16:5542460
5542468 | 00 Begane grond | 1810 | 0.33953 | 0.015023 | 0.67906 | 5542464 | 0 | Model Group:Merk K16:5542460
5542469 | 00 Begane grond | 1810 | 0.33953 | 0.015023 | 0.67906 | 5542464 | 0 | Model Group:Merk K16:5542460
5544039 | 00 Begane grond | 680 | 0.13274 | 0.005644 | 0.26548 | 5544037 | 0 | Model Group:Merk K16:5544034
5544041 | 00 Begane grond | 1810 | 0.33953 | 0.015023 | 0.67906 | 5544037 | 0 | Model Group:Merk K16:5544034
5544042 | 00 Begane grond | 1810 | 0.33953 | 0.015023 | 0.67906 | 5544037 | 0 | Model Group:Merk K16:5544034
5544061 | 00 Begane grond | 680 | 0.13274 | 0.005644 | 0.26548 | 5544059 | 0 | Model Group:Merk K16:5544056
5544063 | 00 Begane grond | 1810 | 0.33953 | 0.015023 | 0.67906 | 5544059 | 0 | Model Group:Merk K16:5544056
5544064 | 00 Begane grond | 1810 | 0.33953 | 0.015023 | 0.67906 | 5544059 | 0 | Model Group:Merk K16:5544056
5544112 | 00 Begane grond | 680 | 0.13274 | 0.005644 | 0.26548 | 5544110 | 0 | Model Group:Merk K16:5544107
5544114 | 00 Begane grond | 1810 | 0.33953 | 0.015023 | 0.67906 | 5544110 | 0 | Model Group:Merk K16:5544107
5544115 | 00 Begane grond | 1810 | 0.33953 | 0.015023 | 0.67906 | 5544110 | 0 | Model Group:Merk K16:5544107
5544138 | 00 Begane grond | 680 | 0.13274 | 0.005644 | 0.26548 | 5544136 | 0 | Model Group:Merk K16:5544133
5544140 | 00 Begane grond | 1810 | 0.33953 | 0.015023 | 0.67906 | 5544136 | 0 | Model Group:Merk K16:5544133
5544141 | 00 Begane grond | 1810 | 0.33953 | 0.015023 | 0.67906 | 5544136 | 0 | Model Group:Merk K16:5544133
5544300 | 00 Begane grond | 1183 | 0.224789 | 0.0098189 | 0.441278 | 5544298 | 0 | Model Group:Merk K17:5544294
5544302 | 00 Begane grond | 1710 | 0.32123 | 0.014193 | 0.64246 | 5544298 | 0 | Model Group:Merk K17:5544294
5544303 | 00 Begane grond | 1710 | 0.32123 | 0.014193 | 0.64246 | 5544298 | 0 | Model Group:Merk K17:5544294
5544307 | 00 Begane grond | 857 | 0.165131 | 0.0071131 | 0.321962 | 5544298 | 0 | Model Group:Merk K17:5544294
5544810 | 00 Begane grond | 680 | 0.13274 | 0.005644 | 0.26548 | 5544808 | 0 | Model Group:Merk K16:5544805
5544812 | 00 Begane grond | 1810 | 0.33953 | 0.015023 | 0.67906 | 5544808 | 0 | Model Group:Merk K16:5544805
5544813 | 00 Begane grond | 1810 | 0.33953 | 0.015023 | 0.67906 | 5544808 | 0 | Model Group:Merk K16:5544805
5544828 | 00 Begane grond | 680 | 0.13274 | 0.005644 | 0.26548 | 5544826 | 0 | Model Group:Merk K16:5544823
5544830 | 00 Begane grond | 1810 | 0.33953 | 0.015023 | 0.67906 | 5544826 | 0 | Model Group:Merk K16:5544823
5544831 | 00 Begane grond | 1810 | 0.33953 | 0.015023 | 0.67906 | 5544826 | 0 | Model Group:Merk K16:5544823
5544978 | 00 Begane grond | 1183 | 0.224789 | 0.0098189 | 0.441278 | 5544976 | 0 | Model Group:Merk K17:5544972
5544980 | 00 Begane grond | 1710 | 0.32123 | 0.014193 | 0.64246 | 5544976 | 0 | Model Group:Merk K17:5544972
5544981 | 00 Begane grond | 1710 | 0.32123 | 0.014193 | 0.64246 | 5544976 | 0 | Model Group:Merk K17:5544972
5544985 | 00 Begane grond | 857 | 0.165131 | 0.0071131 | 0.321962 | 5544976 | 0 | Model Group:Merk K17:5544972
5545013 | 00 Begane grond | 1183 | 0.224789 | 0.0098189 | 0.441278 | 5545011 | 0 | Model Group:Merk K17:5545007
5545015 | 00 Begane grond | 1710 | 0.32123 | 0.014193 | 0.64246 | 5545011 | 0 | Model Group:Merk K17:5545007
5545016 | 00 Begane grond | 1710 | 0.32123 | 0.014193 | 0.64246 | 5545011 | 0 | Model Group:Merk K17:5545007
5545020 | 00 Begane grond | 857 | 0.165131 | 0.0071131 | 0.321962 | 5545011 | 0 | Model Group:Merk K17:5545007
5545039 | 00 Begane grond | 680 | 0.13274 | 0.005644 | 0.26548 | 5545037 | 0 | Model Group:Merk K16:5545034
5545041 | 00 Begane grond | 1810 | 0.33953 | 0.015023 | 0.67906 | 5545037 | 0 | Model Group:Merk K16:5545034
5545042 | 00 Begane grond | 1810 | 0.33953 | 0.015023 | 0.67906 | 5545037 | 0 | Model Group:Merk K16:5545034
5552594 | 00 Begane grond | 680 | 0.13274 | 0.005644 | 0.26548 | 5552592 | 0 | Model Group:Merk K16:5552591
5552596 | 00 Begane grond | 1810 | 0.33953 | 0.015023 | 0.67906 | 5552592 | 0 | Model Group:Merk K16:5552591
5552597 | 00 Begane grond | 1810 | 0.33953 | 0.015023 | 0.67906 | 5552592 | 0 | Model Group:Merk K16:5552591
5552765 | 00 Begane grond | 680 | 0.13274 | 0.005644 | 0.26548 | 5552763 | 0 | Model Group:Merk K16:5552762
5552767 | 00 Begane grond | 1810 | 0.33953 | 0.015023 | 0.67906 | 5552763 | 0 | Model Group:Merk K16:5552762
5552768 | 00 Begane grond | 1810 | 0.33953 | 0.015023 | 0.67906 | 5552763 | 0 | Model Group:Merk K16:5552762
5610887 | 00 Begane grond | 590 | 0.11627 | 0.004897 | 0.23254 | 5610885 | 0 | Model Group:Merk K06:5537348
5610889 | 00 Begane grond | 2180 | 0.40724 | 0.018094 | 0.81448 | 5610885 | 0 | Model Group:Merk K06:5537348
5610890 | 00 Begane grond | 2180 | 0.40724 | 0.018094 | 0.81448 | 5610885 | 0 | Model Group:Merk K06:5537348
5610911 | 00 Begane grond | 590 | 0.11627 | 0.004897 | 0.23254 | 5610909 | 0 | Model Group:Merk K06:5537306
5610913 | 00 Begane grond | 2180 | 0.40724 | 0.018094 | 0.81448 | 5610909 | 0 | Model Group:Merk K06:5537306
5610914 | 00 Begane grond | 2180 | 0.40724 | 0.018094 | 0.81448 | 5610909 | 0 | Model Group:Merk K06:5537306
5610957 | 00 Begane grond | 590 | 0.11627 | 0.004897 | 0.23254 | 5610955 | 0 | Model Group:Merk K06:5537485
5610959 | 00 Begane grond | 2180 | 0.40724 | 0.018094 | 0.81448 | 5610955 | 0 | Model Group:Merk K06:5537485
5610960 | 00 Begane grond | 2180 | 0.40724 | 0.018094 | 0.81448 | 5610955 | 0 | Model Group:Merk K06:5537485
5855992 | 00 Begane grond | 1183 | 0.224789 | 0.0098189 | 0.441278 | 5855990 | 0 | Model Group:Merk K17:5855989
5855994 | 00 Begane grond | 1710 | 0.32123 | 0.014193 | 0.64246 | 5855990 | 0 | Model Group:Merk K17:5855989
5855995 | 00 Begane grond | 1710 | 0.32123 | 0.014193 | 0.64246 | 5855990 | 0 | Model Group:Merk K17:5855989
5855998 | 00 Begane grond | 857 | 0.165131 | 0.0071131 | 0.321962 | 5855990 | 0 | Model Group:Merk K17:5855989
5856004 | 00 Begane grond | 680 | 0.13274 | 0.005644 | 0.26548 | 5856002 | 0 | Model Group:Merk K16:5856001
5856006 | 00 Begane grond | 1810 | 0.33953 | 0.015023 | 0.67906 | 5856002 | 0 | Model Group:Merk K16:5856001
5856007 | 00 Begane grond | 1810 | 0.33953 | 0.015023 | 0.67906 | 5856002 | 0 | Model Group:Merk K16:5856001
5856011 | 00 Begane grond | 680 | 0.13274 | 0.005644 | 0.26548 | 5856009 | 0 | Model Group:Merk K16:5856008
5856013 | 00 Begane grond | 1810 | 0.33953 | 0.015023 | 0.67906 | 5856009 | 0 | Model Group:Merk K16:5856008
5856014 | 00 Begane grond | 1810 | 0.33953 | 0.015023 | 0.67906 | 5856009 | 0 | Model Group:Merk K16:5856008
5856033 | 00 Begane grond | 1183 | 0.224789 | 0.0098189 | 0.441278 | 5856031 | 0 | Model Group:Merk K17:5856030
5856035 | 00 Begane grond | 1710 | 0.32123 | 0.014193 | 0.64246 | 5856031 | 0 | Model Group:Merk K17:5856030
5856036 | 00 Begane grond | 1710 | 0.32123 | 0.014193 | 0.64246 | 5856031 | 0 | Model Group:Merk K17:5856030
5856039 | 00 Begane grond | 857 | 0.165131 | 0.0071131 | 0.321962 | 5856031 | 0 | Model Group:Merk K17:5856030
6064880 | 01 eerste verdieping | 680 | 0.13274 | 0.005644 | 0.26548 | 6064878 | V1 ok. ruwe vloer | Model Group:Merk K28:6064868
6064882 | 01 eerste verdieping | 1810 | 0.33953 | 0.015023 | 0.67906 | 6064878 | V1 ok. ruwe vloer | Model Group:Merk K28:6064868
6064883 | 01 eerste verdieping | 1810 | 0.33953 | 0.015023 | 0.67906 | 6064878 | V1 ok. ruwe vloer | Model Group:Merk K28:6064868
6064899 | 01 eerste verdieping | 680 | 0.13274 | 0.005644 | 0.26548 | 6064897 | V1 ok. ruwe vloer | Model Group:Merk K28:6064887
6064901 | 01 eerste verdieping | 1810 | 0.33953 | 0.015023 | 0.67906 | 6064897 | V1 ok. ruwe vloer | Model Group:Merk K28:6064887
6064902 | 01 eerste verdieping | 1810 | 0.33953 | 0.015023 | 0.67906 | 6064897 | V1 ok. ruwe vloer | Model Group:Merk K28:6064887
6064918 | 01 eerste verdieping | 680 | 0.13274 | 0.005644 | 0.26548 | 6064916 | V1 ok. ruwe vloer | Model Group:Merk K28:6064906
6064920 | 01 eerste verdieping | 1810 | 0.33953 | 0.015023 | 0.67906 | 6064916 | V1 ok. ruwe vloer | Model Group:Merk K28:6064906
6064921 | 01 eerste verdieping | 1810 | 0.33953 | 0.015023 | 0.67906 | 6064916 | V1 ok. ruwe vloer | Model Group:Merk K28:6064906
6064937 | 01 eerste verdieping | 680 | 0.13274 | 0.005644 | 0.26548 | 6064935 | V1 ok. ruwe vloer | Model Group:Merk K28:6064925
6064939 | 01 eerste verdieping | 1810 | 0.33953 | 0.015023 | 0.67906 | 6064935 | V1 ok. ruwe vloer | Model Group:Merk K28:6064925
6064940 | 01 eerste verdieping | 1810 | 0.33953 | 0.015023 | 0.67906 | 6064935 | V1 ok. ruwe vloer | Model Group:Merk K28:6064925
6064956 | 01 eerste verdieping | 680 | 0.13274 | 0.005644 | 0.26548 | 6064954 | V1 ok. ruwe vloer | Model Group:Merk K28:6064944
6064958 | 01 eerste verdieping | 1810 | 0.33953 | 0.015023 | 0.67906 | 6064954 | V1 ok. ruwe vloer | Model Group:Merk K28:6064944
6064959 | 01 eerste verdieping | 1810 | 0.33953 | 0.015023 | 0.67906 | 6064954 | V1 ok. ruwe vloer | Model Group:Merk K28:6064944
6064975 | 01 eerste verdieping | 680 | 0.13274 | 0.005644 | 0.26548 | 6064973 | V1 ok. ruwe vloer | Model Group:Merk K28:6064963
6064977 | 01 eerste verdieping | 1810 | 0.33953 | 0.015023 | 0.67906 | 6064973 | V1 ok. ruwe vloer | Model Group:Merk K28:6064963
6064978 | 01 eerste verdieping | 1810 | 0.33953 | 0.015023 | 0.67906 | 6064973 | V1 ok. ruwe vloer | Model Group:Merk K28:6064963
6064994 | 01 eerste verdieping | 680 | 0.13274 | 0.005644 | 0.26548 | 6064992 | V1 ok. ruwe vloer | Model Group:Merk K28:6064982
6064996 | 01 eerste verdieping | 1810 | 0.33953 | 0.015023 | 0.67906 | 6064992 | V1 ok. ruwe vloer | Model Group:Merk K28:6064982
6064997 | 01 eerste verdieping | 1810 | 0.33953 | 0.015023 | 0.67906 | 6064992 | V1 ok. ruwe vloer | Model Group:Merk K28:6064982
6065032 | 01 eerste verdieping | 680 | 0.13274 | 0.005644 | 0.26548 | 6065030 | V1 ok. ruwe vloer | Model Group:Merk K28:6065020
6065034 | 01 eerste verdieping | 1810 | 0.33953 | 0.015023 | 0.67906 | 6065030 | V1 ok. ruwe vloer | Model Group:Merk K28:6065020
6065035 | 01 eerste verdieping | 1810 | 0.33953 | 0.015023 | 0.67906 | 6065030 | V1 ok. ruwe vloer | Model Group:Merk K28:6065020
6065051 | 01 eerste verdieping | 680 | 0.13274 | 0.005644 | 0.26548 | 6065049 | V1 ok. ruwe vloer | Model Group:Merk K28:6065039
6065053 | 01 eerste verdieping | 1810 | 0.33953 | 0.015023 | 0.67906 | 6065049 | V1 ok. ruwe vloer | Model Group:Merk K28:6065039
6065054 | 01 eerste verdieping | 1810 | 0.33953 | 0.015023 | 0.67906 | 6065049 | V1 ok. ruwe vloer | Model Group:Merk K28:6065039
6065089 | 01 eerste verdieping | 680 | 0.13274 | 0.005644 | 0.26548 | 6065087 | V1 ok. ruwe vloer | Model Group:Merk K28:6065077
6065091 | 01 eerste verdieping | 1810 | 0.33953 | 0.015023 | 0.67906 | 6065087 | V1 ok. ruwe vloer | Model Group:Merk K28:6065077
6065092 | 01 eerste verdieping | 1810 | 0.33953 | 0.015023 | 0.67906 | 6065087 | V1 ok. ruwe vloer | Model Group:Merk K28:6065077
6065108 | 01 eerste verdieping | 680 | 0.13274 | 0.005644 | 0.26548 | 6065106 | V1 ok. ruwe vloer | Model Group:Merk K28:6065096
6065110 | 01 eerste verdieping | 1810 | 0.33953 | 0.015023 | 0.67906 | 6065106 | V1 ok. ruwe vloer | Model Group:Merk K28:6065096
6065111 | 01 eerste verdieping | 1810 | 0.33953 | 0.015023 | 0.67906 | 6065106 | V1 ok. ruwe vloer | Model Group:Merk K28:6065096
6065127 | 01 eerste verdieping | 680 | 0.13274 | 0.005644 | 0.26548 | 6065125 | V1 ok. ruwe vloer | Model Group:Merk K28:6065115
6065129 | 01 eerste verdieping | 1810 | 0.33953 | 0.015023 | 0.67906 | 6065125 | V1 ok. ruwe vloer | Model Group:Merk K28:6065115
6065130 | 01 eerste verdieping | 1810 | 0.33953 | 0.015023 | 0.67906 | 6065125 | V1 ok. ruwe vloer | Model Group:Merk K28:6065115
6065146 | 01 eerste verdieping | 680 | 0.13274 | 0.005644 | 0.26548 | 6065144 | V1 ok. ruwe vloer | Model Group:Merk K28:6065134
6065148 | 01 eerste verdieping | 1810 | 0.33953 | 0.015023 | 0.67906 | 6065144 | V1 ok. ruwe vloer | Model Group:Merk K28:6065134
6065149 | 01 eerste verdieping | 1810 | 0.33953 | 0.015023 | 0.67906 | 6065144 | V1 ok. ruwe vloer | Model Group:Merk K28:6065134
6065215 | 01 eerste verdieping | 1183 | 0.224789 | 0.0098189 | 0.441278 | 6065213 | V1 ok. ruwe vloer | Model Group:Merk K24:6065197
6065217 | 01 eerste verdieping | 1710 | 0.32123 | 0.014193 | 0.64246 | 6065213 | V1 ok. ruwe vloer | Model Group:Merk K24:6065197
6065218 | 01 eerste verdieping | 1710 | 0.32123 | 0.014193 | 0.64246 | 6065213 | V1 ok. ruwe vloer | Model Group:Merk K24:6065197
6065221 | 01 eerste verdieping | 857 | 0.165131 | 0.0071131 | 0.321962 | 6065213 | V1 ok. ruwe vloer | Model Group:Merk K24:6065197
6065246 | 01 eerste verdieping | 1183 | 0.224789 | 0.0098189 | 0.441278 | 6065244 | V1 ok. ruwe vloer | Model Group:Merk K24:6065228
6065248 | 01 eerste verdieping | 1710 | 0.32123 | 0.014193 | 0.64246 | 6065244 | V1 ok. ruwe vloer | Model Group:Merk K24:6065228
6065249 | 01 eerste verdieping | 1710 | 0.32123 | 0.014193 | 0.64246 | 6065244 | V1 ok. ruwe vloer | Model Group:Merk K24:6065228
6065252 | 01 eerste verdieping | 857 | 0.165131 | 0.0071131 | 0.321962 | 6065244 | V1 ok. ruwe vloer | Model Group:Merk K24:6065228
6065277 | 01 eerste verdieping | 1183 | 0.224789 | 0.0098189 | 0.441278 | 6065275 | V1 ok. ruwe vloer | Model Group:Merk K24:6065259
6065279 | 01 eerste verdieping | 1710 | 0.32123 | 0.014193 | 0.64246 | 6065275 | V1 ok. ruwe vloer | Model Group:Merk K24:6065259
6065280 | 01 eerste verdieping | 1710 | 0.32123 | 0.014193 | 0.64246 | 6065275 | V1 ok. ruwe vloer | Model Group:Merk K24:6065259
6065283 | 01 eerste verdieping | 857 | 0.165131 | 0.0071131 | 0.321962 | 6065275 | V1 ok. ruwe vloer | Model Group:Merk K24:6065259
6065308 | 01 eerste verdieping | 1183 | 0.224789 | 0.0098189 | 0.441278 | 6065306 | V1 ok. ruwe vloer | Model Group:Merk K24:6065290
6065310 | 01 eerste verdieping | 1710 | 0.32123 | 0.014193 | 0.64246 | 6065306 | V1 ok. ruwe vloer | Model Group:Merk K24:6065290
6065311 | 01 eerste verdieping | 1710 | 0.32123 | 0.014193 | 0.64246 | 6065306 | V1 ok. ruwe vloer | Model Group:Merk K24:6065290
6065314 | 01 eerste verdieping | 857 | 0.165131 | 0.0071131 | 0.321962 | 6065306 | V1 ok. ruwe vloer | Model Group:Merk K24:6065290
6065339 | 01 eerste verdieping | 1183 | 0.224789 | 0.0098189 | 0.441278 | 6065337 | V1 ok. ruwe vloer | Model Group:Merk K24:6065321
6065341 | 01 eerste verdieping | 1710 | 0.32123 | 0.014193 | 0.64246 | 6065337 | V1 ok. ruwe vloer | Model Group:Merk K24:6065321
6065342 | 01 eerste verdieping | 1710 | 0.32123 | 0.014193 | 0.64246 | 6065337 | V1 ok. ruwe vloer | Model Group:Merk K24:6065321
6065345 | 01 eerste verdieping | 857 | 0.165131 | 0.0071131 | 0.321962 | 6065337 | V1 ok. ruwe vloer | Model Group:Merk K24:6065321
6065370 | 01 eerste verdieping | 1183 | 0.224789 | 0.0098189 | 0.441278 | 6065368 | V1 ok. ruwe vloer | Model Group:Merk K24:6065352
6065372 | 01 eerste verdieping | 1710 | 0.32123 | 0.014193 | 0.64246 | 6065368 | V1 ok. ruwe vloer | Model Group:Merk K24:6065352
6065373 | 01 eerste verdieping | 1710 | 0.32123 | 0.014193 | 0.64246 | 6065368 | V1 ok. ruwe vloer | Model Group:Merk K24:6065352
6065376 | 01 eerste verdieping | 857 | 0.165131 | 0.0071131 | 0.321962 | 6065368 | V1 ok. ruwe vloer | Model Group:Merk K24:6065352
6065401 | 01 eerste verdieping | 1183 | 0.224789 | 0.0098189 | 0.441278 | 6065399 | V1 ok. ruwe vloer | Model Group:Merk K24:6065383
6065403 | 01 eerste verdieping | 1710 | 0.32123 | 0.014193 | 0.64246 | 6065399 | V1 ok. ruwe vloer | Model Group:Merk K24:6065383
6065404 | 01 eerste verdieping | 1710 | 0.32123 | 0.014193 | 0.64246 | 6065399 | V1 ok. ruwe vloer | Model Group:Merk K24:6065383
6065407 | 01 eerste verdieping | 857 | 0.165131 | 0.0071131 | 0.321962 | 6065399 | V1 ok. ruwe vloer | Model Group:Merk K24:6065383
6065432 | 01 eerste verdieping | 1183 | 0.224789 | 0.0098189 | 0.441278 | 6065430 | V1 ok. ruwe vloer | Model Group:Merk K24:6065414
6065434 | 01 eerste verdieping | 1710 | 0.32123 | 0.014193 | 0.64246 | 6065430 | V1 ok. ruwe vloer | Model Group:Merk K24:6065414
6065435 | 01 eerste verdieping | 1710 | 0.32123 | 0.014193 | 0.64246 | 6065430 | V1 ok. ruwe vloer | Model Group:Merk K24:6065414
6065438 | 01 eerste verdieping | 857 | 0.165131 | 0.0071131 | 0.321962 | 6065430 | V1 ok. ruwe vloer | Model Group:Merk K24:6065414
6065463 | 01 eerste verdieping | 1183 | 0.224789 | 0.0098189 | 0.441278 | 6065461 | V1 ok. ruwe vloer | Model Group:Merk K24:6065445
6065465 | 01 eerste verdieping | 1710 | 0.32123 | 0.014193 | 0.64246 | 6065461 | V1 ok. ruwe vloer | Model Group:Merk K24:6065445
6065466 | 01 eerste verdieping | 1710 | 0.32123 | 0.014193 | 0.64246 | 6065461 | V1 ok. ruwe vloer | Model Group:Merk K24:6065445
6065469 | 01 eerste verdieping | 857 | 0.165131 | 0.0071131 | 0.321962 | 6065461 | V1 ok. ruwe vloer | Model Group:Merk K24:6065445
6065494 | 01 eerste verdieping | 1183 | 0.224789 | 0.0098189 | 0.441278 | 6065492 | V1 ok. ruwe vloer | Model Group:Merk K24:6065476
6065496 | 01 eerste verdieping | 1710 | 0.32123 | 0.014193 | 0.64246 | 6065492 | V1 ok. ruwe vloer | Model Group:Merk K24:6065476
6065497 | 01 eerste verdieping | 1710 | 0.32123 | 0.014193 | 0.64246 | 6065492 | V1 ok. ruwe vloer | Model Group:Merk K24:6065476
6065500 | 01 eerste verdieping | 857 | 0.165131 | 0.0071131 | 0.321962 | 6065492 | V1 ok. ruwe vloer | Model Group:Merk K24:6065476
6065525 | 01 eerste verdieping | 1183 | 0.224789 | 0.0098189 | 0.441278 | 6065523 | V1 ok. ruwe vloer | Model Group:Merk K24:6065507
6065527 | 01 eerste verdieping | 1710 | 0.32123 | 0.014193 | 0.64246 | 6065523 | V1 ok. ruwe vloer | Model Group:Merk K24:6065507
6065528 | 01 eerste verdieping | 1710 | 0.32123 | 0.014193 | 0.64246 | 6065523 | V1 ok. ruwe vloer | Model Group:Merk K24:6065507
6065531 | 01 eerste verdieping | 857 | 0.165131 | 0.0071131 | 0.321962 | 6065523 | V1 ok. ruwe vloer | Model Group:Merk K24:6065507
6065556 | 01 eerste verdieping | 1183 | 0.224789 | 0.0098189 | 0.441278 | 6065554 | V1 ok. ruwe vloer | Model Group:Merk K24:6065538
6065558 | 01 eerste verdieping | 1710 | 0.32123 | 0.014193 | 0.64246 | 6065554 | V1 ok. ruwe vloer | Model Group:Merk K24:6065538
6065559 | 01 eerste verdieping | 1710 | 0.32123 | 0.014193 | 0.64246 | 6065554 | V1 ok. ruwe vloer | Model Group:Merk K24:6065538
6065562 | 01 eerste verdieping | 857 | 0.165131 | 0.0071131 | 0.321962 | 6065554 | V1 ok. ruwe vloer | Model Group:Merk K24:6065538
6065587 | 01 eerste verdieping | 1183 | 0.224789 | 0.0098189 | 0.441278 | 6065585 | V1 ok. ruwe vloer | Model Group:Merk K24:6065569
6065589 | 01 eerste verdieping | 1710 | 0.32123 | 0.014193 | 0.64246 | 6065585 | V1 ok. ruwe vloer | Model Group:Merk K24:6065569
6065590 | 01 eerste verdieping | 1710 | 0.32123 | 0.014193 | 0.64246 | 6065585 | V1 ok. ruwe vloer | Model Group:Merk K24:6065569
6065593 | 01 eerste verdieping | 857 | 0.165131 | 0.0071131 | 0.321962 | 6065585 | V1 ok. ruwe vloer | Model Group:Merk K24:6065569
6315732 | 01 eerste verdieping | 680 | 0.13274 | 0.005644 | 0.26548 | 6315730 | V1 ok. ruwe vloer | Model Group:Merk K31:6065001
6315734 | 01 eerste verdieping | 1930 | 0.36149 | 0.016019 | 0.72298 | 6315730 | V1 ok. ruwe vloer | Model Group:Merk K31:6065001
6315735 | 01 eerste verdieping | 1930 | 0.36149 | 0.016019 | 0.72298 | 6315730 | V1 ok. ruwe vloer | Model Group:Merk K31:6065001
6315975 | 01 eerste verdieping | 680 | 0.13274 | 0.005644 | 0.26548 | 6315973 | V1 ok. ruwe vloer | Model Group:Merk K31:6065058
6315977 | 01 eerste verdieping | 1930 | 0.36149 | 0.016019 | 0.72298 | 6315973 | V1 ok. ruwe vloer | Model Group:Merk K31:6065058
6315978 | 01 eerste verdieping | 1930 | 0.36149 | 0.016019 | 0.72298 | 6315973 | V1 ok. ruwe vloer | Model Group:Merk K31:6065058
6322836 | 01 eerste verdieping | 680 | 0.13274 | 0.005644 | 0.26548 | 6322834 | V1 ok. ruwe vloer | Model Group:Merk K31:6322821
6322838 | 01 eerste verdieping | 1930 | 0.36149 | 0.016019 | 0.72298 | 6322834 | V1 ok. ruwe vloer | Model Group:Merk K31:6322821
6322839 | 01 eerste verdieping | 1930 | 0.36149 | 0.016019 | 0.72298 | 6322834 | V1 ok. ruwe vloer | Model Group:Merk K31:6322821
6322867 | 01 eerste verdieping | 680 | 0.13274 | 0.005644 | 0.26548 | 6322865 | V1 ok. ruwe vloer | Model Group:Merk K31:6322854
6322869 | 01 eerste verdieping | 1930 | 0.36149 | 0.016019 | 0.72298 | 6322865 | V1 ok. ruwe vloer | Model Group:Merk K31:6322854
6322870 | 01 eerste verdieping | 1930 | 0.36149 | 0.016019 | 0.72298 | 6322865 | V1 ok. ruwe vloer | Model Group:Merk K31:6322854
6474578 | 00 Begane grond | 680 | 0.13274 | 0.005644 | 0.26548 | 6474576 | V-1 | Model Group:Merk K31:6474575
6474580 | 00 Begane grond | 1930 | 0.36149 | 0.016019 | 0.72298 | 6474576 | V-1 | Model Group:Merk K31:6474575
6474581 | 00 Begane grond | 1930 | 0.36149 | 0.016019 | 0.72298 | 6474576 | V-1 | Model Group:Merk K31:6474575
6474586 | 01 eerste verdieping | 1483 | 0.279689 | 0.0123089 | 0.551078 | 6474584 | 1 | Model Group:Merk K32:5538094
6474588 | 01 eerste verdieping | 1710 | 0.32123 | 0.014193 | 0.64246 | 6474584 | 1 | Model Group:Merk K32:5538094
6474589 | 01 eerste verdieping | 1710 | 0.32123 | 0.014193 | 0.64246 | 6474584 | 1 | Model Group:Merk K32:5538094
6474592 | 01 eerste verdieping | 767 | 0.148661 | 0.0063661 | 0.289022 | 6474584 | 1 | Model Group:Merk K32:5538094
6782310 | 00 Begane grond | 1920 | 0.35966 | 0.015936 | 0.71932 | 6782308 | 0
6782312 | 00 Begane grond | 2510 | 0.46763 | 0.020833 | 0.93526 | 6782308 | 0
6782313 | 00 Begane grond | 2510 | 0.46763 | 0.020833 | 0.93526 | 6782308 | 0

# IfcMember: Rectangular Mullion:120x83 Gealan Kubus (171)
Type - PredefinedType: MULLION; Material: ISR_Kunststof_RAL7006
Type - Other - Category: Curtain Wall Mullions; Family Name: Rectangular Mullion
Type - Constraints - Angle: 0 deg; Offset: 41.5 mm
Type - Construction - Corner Mullion: no; Position: Perpendicular to Face; Profile: System Mullion Profile: Rectangular; Thickness: 83 mm
Type - Dimensions - Width on side 1: 60 mm; Width on side 2: 60 mm
Type - Identity Data - Workset: Family : Curtain Wall Mullions : Rectangular Mullion; Type Name: 120x83 Gealan Kubus
Type - Materials and Finishes - Material: ISR_Kunststof_RAL7006
Type - Pset_MemberCommon - IsExternal: no
Type - Pset_ProductRequirements - Category: Curtain Wall Mullions
Classification: 31 Uniformat (Uniformat)
Pset_MemberCommon - Reference: 120x83 Gealan Kubus
Pset_QuantityTakeOff - Reference: 120x83 Gealan Kubus
Other - Family: Rectangular Mullion; Family and Type: Rectangular Mullion: 120x83 Gealan Kubus; Type: 120x83 Gealan Kubus; Type Id: 5612153
Identity Data - Workset: Bouwkundig
Phasing - Phase Created: 2. nieuwbouw
Name (Rectangular Mullion:120x83 Gealan Kubus:...) | In | Span (mm) = BaseQuantities, Length (mm) = Dimensions, Length (mm) | CrossSectionArea (m2) = Area (m2) | NetVolume (m3) = Volume (m3) | NetSurfaceArea (m2) | Host Id | Level | Group
5536834 | 00 Begane grond | 740 | 0.16018 | 0.0073704 | 0.32036 | 5536831 | 0 | Model Group:Merk K04:5536830 | Pset_MemberCommon - IsExternal: yes
5536842 | 00 Begane grond | 740 | 0.16018 | 0.0073704 | 0.32036 | 5536839 | 0 | Model Group:Merk K04:5536838
5536850 | 00 Begane grond | 740 | 0.16018 | 0.0073704 | 0.32036 | 5536847 | 0 | Model Group:Merk K04:5536846
5536883 | 00 Begane grond | 2120 | 0.44032 | 0.0211152 | 0.88064 | 5536880 | 0 | Model Group:Merk K02:5536879
5536908 | 00 Begane grond | 2120 | 0.44032 | 0.0211152 | 0.88064 | 5536905 | 0 | Model Group:Merk K02:5536904
5536922 | 00 Begane grond | 920 | 0.19672 | 0.0091632 | 0.39344 | 5536919 | 0 | Model Group:Merk K01:5536918
5536954 | 00 Begane grond | 920 | 0.19672 | 0.0091632 | 0.39344 | 5536951 | 0 | Model Group:Merk K01:5536950
5536968 | 00 Begane grond | 1865 | 0.388555 | 0.0185754 | 0.777109 | 5536965 | 0 | Model Group:Merk K21:5536964
5537034 | 00 Begane grond | 740 | 0.16018 | 0.0073704 | 0.32036 | 5537031 | 0 | Model Group:Merk K04:5537030
5537069 | 00 Begane grond | 740 | 0.16018 | 0.0073704 | 0.32036 | 5537066 | 0 | Model Group:Merk K04:5537065
5537106 | 00 Begane grond | 2120 | 0.44032 | 0.0211152 | 0.88064 | 5537103 | 0 | Model Group:Merk K02:5537102
5537285 | 00 Begane grond | 590 | 0.12973 | 0.0058764 | 0.25946 | 5537282 | 0 | Model Group:Merk K06:5537281
5537297 | 00 Begane grond | 590 | 0.12973 | 0.0058764 | 0.25946 | 5537294 | 0 | Model Group:Merk K06:5537293
5537336 | 00 Begane grond | 590 | 0.12973 | 0.0058764 | 0.25946 | 5537333 | 0 | Model Group:Merk K06:5537332
5537344 | 00 Begane grond | 590 | 0.12973 | 0.0058764 | 0.25946 | 5537341 | 0 | Model Group:Merk K06:5537340
5537389 | 00 Begane grond | 2030 | 0.42205 | 0.0202188 | 0.8441 | 5537386 | 0 | Model Group:Merk K08:5537385
5537397 | 00 Begane grond | 790 | 0.17033 | 0.0078684 | 0.34066 | 5537394 | 0 | Model Group:Merk K09:5537393
5537405 | 00 Begane grond | 690 | 0.15003 | 0.0068724 | 0.30006 | 5537402 | 0 | Model Group:Merk K10:5537401
5537413 | 00 Begane grond | 690 | 0.15003 | 0.0068724 | 0.30006 | 5537410 | 0 | Model Group:Merk K11:5537409
5537421 | 00 Begane grond | 590 | 0.12973 | 0.0058764 | 0.25946 | 5537418 | 0 | Model Group:Merk K12:5537417
5537429 | 00 Begane grond | 590 | 0.12973 | 0.0058764 | 0.25946 | 5537426 | 0 | Model Group:Merk K13:5537425
5537506 | 00 Begane grond | 1533 | 0.321159 | 0.0152687 | 0.632358 | 5537503 | 0 | Model Group:Merk K07:5537502
5611177 | 00 Begane grond | 767 | 0.165661 | 0.00763932 | 0.321362 | 5537503 | 0 | Model Group:Merk K07:5537502
5537529 | 00 Begane grond | 1295 | 0.272845 | 0.0128982 | 0.54569 | 5537526 | 0 | Model Group:Merk K14:5537525
5537547 | 00 Begane grond | 457 | 0.102731 | 0.00455172 | 0.195502 | 5537537 | 0 | Model Group:Merk K15:5537536
6479921 | 00 Begane grond | 863 | 0.185149 | 0.00859548 | 0.360338 | 5537537 | 0 | Model Group:Merk K15:5537536
5537728 | 00 Begane grond | 1533 | 0.321159 | 0.0152687 | 0.632358 | 5537725 | 0 | Model Group:Merk K07:5537724
5611360 | 00 Begane grond | 767 | 0.165661 | 0.00763932 | 0.321362 | 5537725 | 0 | Model Group:Merk K07:5537724
5537743 | 01 eerste verdieping | 790 | 0.17033 | 0.0078684 | 0.34066 | 5537740 | 1 | Model Group:Merk K30:5537739
5537751 | 01 eerste verdieping | 2064 | 0.428952 | 0.0205574 | 0.857904 | 5537748 | 1 | Model Group:Merk K23:5537747
5537978 | 01 eerste verdieping | 1145 | 0.242395 | 0.0114042 | 0.48479 | 5537975 | 1 | Model Group:Merk K25:5537974
5537985 | 01 eerste verdieping | 590 | 0.12973 | 0.0058764 | 0.25946 | 5537982 | 1 | Model Group:Merk K29:5537981
5537994 | 01 eerste verdieping | 767 | 0.165661 | 0.00763932 | 0.321362 | 5537991 | 1 | Model Group:Merk K22:5537990
5549597 | 01 eerste verdieping | 1483 | 0.311009 | 0.0147707 | 0.612058 | 5537991 | 1 | Model Group:Merk K22:5537990
5538002 | 01 eerste verdieping | 767 | 0.165661 | 0.00763932 | 0.321362 | 5537999 | 1 | Model Group:Merk K22:5537998
5548700 | 01 eerste verdieping | 1483 | 0.311009 | 0.0147707 | 0.612058 | 5537999 | 1 | Model Group:Merk K22:5537998
5538010 | 01 eerste verdieping | 767 | 0.165661 | 0.00763932 | 0.321362 | 5538007 | 1 | Model Group:Merk K22:5538006
5549606 | 01 eerste verdieping | 1483 | 0.311009 | 0.0147707 | 0.612058 | 5538007 | 1 | Model Group:Merk K22:5538006
5538018 | 01 eerste verdieping | 767 | 0.165661 | 0.00763932 | 0.321362 | 5538015 | 1 | Model Group:Merk K22:5538014
5549615 | 01 eerste verdieping | 1483 | 0.311009 | 0.0147707 | 0.612058 | 5538015 | 1 | Model Group:Merk K22:5538014
5538026 | 01 eerste verdieping | 767 | 0.165661 | 0.00763932 | 0.321362 | 5538023 | 1 | Model Group:Merk K22:5538022
5549624 | 01 eerste verdieping | 1483 | 0.311009 | 0.0147707 | 0.612058 | 5538023 | 1 | Model Group:Merk K22:5538022
5538034 | 01 eerste verdieping | 767 | 0.165661 | 0.00763932 | 0.321362 | 5538031 | 1 | Model Group:Merk K22:5538030
5549633 | 01 eerste verdieping | 1483 | 0.311009 | 0.0147707 | 0.612058 | 5538031 | 1 | Model Group:Merk K22:5538030
5538042 | 01 eerste verdieping | 767 | 0.165661 | 0.00763932 | 0.321362 | 5538039 | 1 | Model Group:Merk K22:5538038
5549642 | 01 eerste verdieping | 1483 | 0.311009 | 0.0147707 | 0.612058 | 5538039 | 1 | Model Group:Merk K22:5538038
5538050 | 01 eerste verdieping | 767 | 0.165661 | 0.00763932 | 0.321362 | 5538047 | 1 | Model Group:Merk K22:5538046
5549651 | 01 eerste verdieping | 1483 | 0.311009 | 0.0147707 | 0.612058 | 5538047 | 1 | Model Group:Merk K22:5538046
5538058 | 01 eerste verdieping | 767 | 0.165661 | 0.00763932 | 0.321362 | 5538055 | 1 | Model Group:Merk K22:5538054
5549660 | 01 eerste verdieping | 1483 | 0.311009 | 0.0147707 | 0.612058 | 5538055 | 1 | Model Group:Merk K22:5538054
5538066 | 01 eerste verdieping | 767 | 0.165661 | 0.00763932 | 0.321362 | 5538063 | 1 | Model Group:Merk K22:5538062
5549669 | 01 eerste verdieping | 1483 | 0.311009 | 0.0147707 | 0.612058 | 5538063 | 1 | Model Group:Merk K22:5538062
5538074 | 01 eerste verdieping | 767 | 0.165661 | 0.00763932 | 0.321362 | 5538071 | 1 | Model Group:Merk K22:5538070
5549678 | 01 eerste verdieping | 1483 | 0.311009 | 0.0147707 | 0.612058 | 5538071 | 1 | Model Group:Merk K22:5538070
5538082 | 01 eerste verdieping | 767 | 0.165661 | 0.00763932 | 0.321362 | 5538079 | 1 | Model Group:Merk K22:5538078
5549687 | 01 eerste verdieping | 1483 | 0.311009 | 0.0147707 | 0.612058 | 5538079 | 1 | Model Group:Merk K22:5538078
5538090 | 01 eerste verdieping | 767 | 0.165661 | 0.00763932 | 0.321362 | 5538087 | 1 | Model Group:Merk K22:5538086
5549696 | 01 eerste verdieping | 1483 | 0.311009 | 0.0147707 | 0.612058 | 5538087 | 1 | Model Group:Merk K22:5538086
5538106 | 01 eerste verdieping | 767 | 0.165661 | 0.00763932 | 0.321362 | 5538103 | 1 | Model Group:Merk K32:5538102
5549714 | 01 eerste verdieping | 1483 | 0.311009 | 0.0147707 | 0.612058 | 5538103 | 1 | Model Group:Merk K32:5538102
5538114 | 01 eerste verdieping | 590 | 0.12973 | 0.0058764 | 0.25946 | 5538111 | 1 | Model Group:Merk K29:5538110
5538123 | 01 eerste verdieping | 590 | 0.12973 | 0.0058764 | 0.25946 | 5538120 | 1 | Model Group:Merk K29:5538119
5538132 | 01 eerste verdieping | 590 | 0.12973 | 0.0058764 | 0.25946 | 5538129 | 1 | Model Group:Merk K29:5538128
5538141 | 01 eerste verdieping | 590 | 0.12973 | 0.0058764 | 0.25946 | 5538138 | 1 | Model Group:Merk K29:5538137
5538150 | 01 eerste verdieping | 590 | 0.12973 | 0.0058764 | 0.25946 | 5538147 | 1 | Model Group:Merk K29:5538146
5538159 | 01 eerste verdieping | 590 | 0.12973 | 0.0058764 | 0.25946 | 5538156 | 1 | Model Group:Merk K29:5538155
5538168 | 01 eerste verdieping | 590 | 0.12973 | 0.0058764 | 0.25946 | 5538165 | 1 | Model Group:Merk K29:5538164
5538177 | 01 eerste verdieping | 590 | 0.12973 | 0.0058764 | 0.25946 | 5538174 | 1 | Model Group:Merk K29:5538173
5538186 | 01 eerste verdieping | 590 | 0.12973 | 0.0058764 | 0.25946 | 5538183 | 1 | Model Group:Merk K29:5538182
5538195 | 01 eerste verdieping | 590 | 0.12973 | 0.0058764 | 0.25946 | 5538192 | 1 | Model Group:Merk K29:5538191
5538204 | 01 eerste verdieping | 590 | 0.12973 | 0.0058764 | 0.25946 | 5538201 | 1 | Model Group:Merk K29:5538200
5538213 | 01 eerste verdieping | 590 | 0.12973 | 0.0058764 | 0.25946 | 5538210 | 1 | Model Group:Merk K29:5538209
5538222 | 01 eerste verdieping | 590 | 0.12973 | 0.0058764 | 0.25946 | 5538219 | 1 | Model Group:Merk K29:5538218
5538231 | 01 eerste verdieping | 590 | 0.12973 | 0.0058764 | 0.25946 | 5538228 | 1 | Model Group:Merk K29:5538227
5538240 | 01 eerste verdieping | 590 | 0.12973 | 0.0058764 | 0.25946 | 5538237 | 1 | Model Group:Merk K29:5538236
5538249 | 01 eerste verdieping | 590 | 0.12973 | 0.0058764 | 0.25946 | 5538246 | 1 | Model Group:Merk K29:5538245
5538258 | 01 eerste verdieping | 590 | 0.12973 | 0.0058764 | 0.25946 | 5538255 | 1 | Model Group:Merk K29:5538254
5538531 | 01 eerste verdieping | 1295 | 0.272845 | 0.0128982 | 0.54569 | 5538528 | 1 | Model Group:Merk K26:5538527
5538545 | 01 eerste verdieping | 1228 | 0.259244 | 0.0122309 | 0.508528 | 5538542 | 1 | Model Group:Merk K27:5538541
5553898 | 01 eerste verdieping | 2222 | 0.461026 | 0.0221311 | 0.912092 | 5538542 | 1 | Model Group:Merk K27:5538541
5538688 | 00 Begane grond | 1635 | 0.341865 | 0.0162846 | 0.68373 | 5538685 | 0 | Model Group:Merk K18:5538684
5538738 | 00 Begane grond | 2120 | 0.44032 | 0.0211152 | 0.88064 | 5538735 | 0 | Model Group:Merk K02:5538734
5538748 | 00 Begane grond | 2120 | 0.44032 | 0.0211152 | 0.88064 | 5538745 | 0 | Model Group:Merk K02:5538744
5538756 | 00 Begane grond | 2120 | 0.44032 | 0.0211152 | 0.88064 | 5538753 | 0 | Model Group:Merk K02:5538752
5539070 | 00 Begane grond | 1290 | 0.27183 | 0.0128484 | 0.54366 | 5539067 | 0 | Model Group:Merk K19:5539066
5539199 | 00 Begane grond | 1635 | 0.341865 | 0.0162846 | 0.68373 | 5539196 | 0 | Model Group:Merk K18:5539194
5539228 | 00 Begane grond | 920 | 0.19672 | 0.0091632 | 0.39344 | 5539225 | 0 | Model Group:Merk K01:5539224
5542014 | 00 Begane grond | 857 | 0.183931 | 0.00853572 | 0.357902 | 5542011 | 0 | Model Group:Merk K17:5540560
5542021 | 00 Begane grond | 1183 | 0.250109 | 0.0117827 | 0.490258 | 5542011 | 0 | Model Group:Merk K17:5540560
5542291 | 00 Begane grond | 857 | 0.183931 | 0.00853572 | 0.357902 | 5542288 | 0 | Model Group:Merk K17:5542284
5542298 | 00 Begane grond | 1183 | 0.250109 | 0.0117827 | 0.490258 | 5542288 | 0 | Model Group:Merk K17:5542284
5542317 | 00 Begane grond | 857 | 0.183931 | 0.00853572 | 0.357902 | 5542314 | 0 | Model Group:Merk K17:5542310
5542324 | 00 Begane grond | 1183 | 0.250109 | 0.0117827 | 0.490258 | 5542314 | 0 | Model Group:Merk K17:5542310
5542343 | 00 Begane grond | 857 | 0.183931 | 0.00853572 | 0.357902 | 5542340 | 0 | Model Group:Merk K17:5542336
5542350 | 00 Begane grond | 1183 | 0.250109 | 0.0117827 | 0.490258 | 5542340 | 0 | Model Group:Merk K17:5542336
5542369 | 00 Begane grond | 857 | 0.183931 | 0.00853572 | 0.357902 | 5542366 | 0 | Model Group:Merk K17:5542362
5542376 | 00 Begane grond | 1183 | 0.250109 | 0.0117827 | 0.490258 | 5542366 | 0 | Model Group:Merk K17:5542362
5542395 | 00 Begane grond | 857 | 0.183931 | 0.00853572 | 0.357902 | 5542392 | 0 | Model Group:Merk K17:5542388
5542402 | 00 Begane grond | 1183 | 0.250109 | 0.0117827 | 0.490258 | 5542392 | 0 | Model Group:Merk K17:5542388
5542467 | 00 Begane grond | 880 | 0.1886 | 0.0087648 | 0.3772 | 5542464 | 0 | Model Group:Merk K16:5542460
5544040 | 00 Begane grond | 880 | 0.1886 | 0.0087648 | 0.3772 | 5544037 | 0 | Model Group:Merk K16:5544034
5544062 | 00 Begane grond | 880 | 0.1886 | 0.0087648 | 0.3772 | 5544059 | 0 | Model Group:Merk K16:5544056
5544113 | 00 Begane grond | 880 | 0.1886 | 0.0087648 | 0.3772 | 5544110 | 0 | Model Group:Merk K16:5544107
5544139 | 00 Begane grond | 880 | 0.1886 | 0.0087648 | 0.3772 | 5544136 | 0 | Model Group:Merk K16:5544133
5544301 | 00 Begane grond | 857 | 0.183931 | 0.00853572 | 0.357902 | 5544298 | 0 | Model Group:Merk K17:5544294
5544308 | 00 Begane grond | 1183 | 0.250109 | 0.0117827 | 0.490258 | 5544298 | 0 | Model Group:Merk K17:5544294
5544811 | 00 Begane grond | 880 | 0.1886 | 0.0087648 | 0.3772 | 5544808 | 0 | Model Group:Merk K16:5544805
5544829 | 00 Begane grond | 880 | 0.1886 | 0.0087648 | 0.3772 | 5544826 | 0 | Model Group:Merk K16:5544823
5544979 | 00 Begane grond | 857 | 0.183931 | 0.00853572 | 0.357902 | 5544976 | 0 | Model Group:Merk K17:5544972
5544986 | 00 Begane grond | 1183 | 0.250109 | 0.0117827 | 0.490258 | 5544976 | 0 | Model Group:Merk K17:5544972
5545014 | 00 Begane grond | 857 | 0.183931 | 0.00853572 | 0.357902 | 5545011 | 0 | Model Group:Merk K17:5545007
5545021 | 00 Begane grond | 1183 | 0.250109 | 0.0117827 | 0.490258 | 5545011 | 0 | Model Group:Merk K17:5545007
5545040 | 00 Begane grond | 880 | 0.1886 | 0.0087648 | 0.3772 | 5545037 | 0 | Model Group:Merk K16:5545034
5552595 | 00 Begane grond | 880 | 0.1886 | 0.0087648 | 0.3772 | 5552592 | 0 | Model Group:Merk K16:5552591
5552766 | 00 Begane grond | 880 | 0.1886 | 0.0087648 | 0.3772 | 5552763 | 0 | Model Group:Merk K16:5552762
5610888 | 00 Begane grond | 590 | 0.12973 | 0.0058764 | 0.25946 | 5610885 | 0 | Model Group:Merk K06:5537348
5610912 | 00 Begane grond | 590 | 0.12973 | 0.0058764 | 0.25946 | 5610909 | 0 | Model Group:Merk K06:5537306
5610958 | 00 Begane grond | 590 | 0.12973 | 0.0058764 | 0.25946 | 5610955 | 0 | Model Group:Merk K06:5537485
5855993 | 00 Begane grond | 857 | 0.183931 | 0.00853572 | 0.357902 | 5855990 | 0 | Model Group:Merk K17:5855989
5855999 | 00 Begane grond | 1183 | 0.250109 | 0.0117827 | 0.490258 | 5855990 | 0 | Model Group:Merk K17:5855989
5856005 | 00 Begane grond | 880 | 0.1886 | 0.0087648 | 0.3772 | 5856002 | 0 | Model Group:Merk K16:5856001
5856012 | 00 Begane grond | 880 | 0.1886 | 0.0087648 | 0.3772 | 5856009 | 0 | Model Group:Merk K16:5856008
5856034 | 00 Begane grond | 857 | 0.183931 | 0.00853572 | 0.357902 | 5856031 | 0 | Model Group:Merk K17:5856030
5856040 | 00 Begane grond | 1183 | 0.250109 | 0.0117827 | 0.490258 | 5856031 | 0 | Model Group:Merk K17:5856030
6064881 | 01 eerste verdieping | 880 | 0.1886 | 0.0087648 | 0.3772 | 6064878 | V1 ok. ruwe vloer | Model Group:Merk K28:6064868
6064900 | 01 eerste verdieping | 880 | 0.1886 | 0.0087648 | 0.3772 | 6064897 | V1 ok. ruwe vloer | Model Group:Merk K28:6064887
6064919 | 01 eerste verdieping | 880 | 0.1886 | 0.0087648 | 0.3772 | 6064916 | V1 ok. ruwe vloer | Model Group:Merk K28:6064906
6064938 | 01 eerste verdieping | 880 | 0.1886 | 0.0087648 | 0.3772 | 6064935 | V1 ok. ruwe vloer | Model Group:Merk K28:6064925
6064957 | 01 eerste verdieping | 880 | 0.1886 | 0.0087648 | 0.3772 | 6064954 | V1 ok. ruwe vloer | Model Group:Merk K28:6064944
6064976 | 01 eerste verdieping | 880 | 0.1886 | 0.0087648 | 0.3772 | 6064973 | V1 ok. ruwe vloer | Model Group:Merk K28:6064963
6064995 | 01 eerste verdieping | 880 | 0.1886 | 0.0087648 | 0.3772 | 6064992 | V1 ok. ruwe vloer | Model Group:Merk K28:6064982
6065033 | 01 eerste verdieping | 880 | 0.1886 | 0.0087648 | 0.3772 | 6065030 | V1 ok. ruwe vloer | Model Group:Merk K28:6065020
6065052 | 01 eerste verdieping | 880 | 0.1886 | 0.0087648 | 0.3772 | 6065049 | V1 ok. ruwe vloer | Model Group:Merk K28:6065039
6065090 | 01 eerste verdieping | 880 | 0.1886 | 0.0087648 | 0.3772 | 6065087 | V1 ok. ruwe vloer | Model Group:Merk K28:6065077
6065109 | 01 eerste verdieping | 880 | 0.1886 | 0.0087648 | 0.3772 | 6065106 | V1 ok. ruwe vloer | Model Group:Merk K28:6065096
6065128 | 01 eerste verdieping | 880 | 0.1886 | 0.0087648 | 0.3772 | 6065125 | V1 ok. ruwe vloer | Model Group:Merk K28:6065115
6065147 | 01 eerste verdieping | 880 | 0.1886 | 0.0087648 | 0.3772 | 6065144 | V1 ok. ruwe vloer | Model Group:Merk K28:6065134
6065216 | 01 eerste verdieping | 857 | 0.183931 | 0.00853572 | 0.357902 | 6065213 | V1 ok. ruwe vloer | Model Group:Merk K24:6065197
6065222 | 01 eerste verdieping | 1183 | 0.250109 | 0.0117827 | 0.490258 | 6065213 | V1 ok. ruwe vloer | Model Group:Merk K24:6065197
6065247 | 01 eerste verdieping | 857 | 0.183931 | 0.00853572 | 0.357902 | 6065244 | V1 ok. ruwe vloer | Model Group:Merk K24:6065228
6065253 | 01 eerste verdieping | 1183 | 0.250109 | 0.0117827 | 0.490258 | 6065244 | V1 ok. ruwe vloer | Model Group:Merk K24:6065228
6065278 | 01 eerste verdieping | 857 | 0.183931 | 0.00853572 | 0.357902 | 6065275 | V1 ok. ruwe vloer | Model Group:Merk K24:6065259
6065284 | 01 eerste verdieping | 1183 | 0.250109 | 0.0117827 | 0.490258 | 6065275 | V1 ok. ruwe vloer | Model Group:Merk K24:6065259
6065309 | 01 eerste verdieping | 857 | 0.183931 | 0.00853572 | 0.357902 | 6065306 | V1 ok. ruwe vloer | Model Group:Merk K24:6065290
6065315 | 01 eerste verdieping | 1183 | 0.250109 | 0.0117827 | 0.490258 | 6065306 | V1 ok. ruwe vloer | Model Group:Merk K24:6065290
6065340 | 01 eerste verdieping | 857 | 0.183931 | 0.00853572 | 0.357902 | 6065337 | V1 ok. ruwe vloer | Model Group:Merk K24:6065321
6065346 | 01 eerste verdieping | 1183 | 0.250109 | 0.0117827 | 0.490258 | 6065337 | V1 ok. ruwe vloer | Model Group:Merk K24:6065321
6065371 | 01 eerste verdieping | 857 | 0.183931 | 0.00853572 | 0.357902 | 6065368 | V1 ok. ruwe vloer | Model Group:Merk K24:6065352
6065377 | 01 eerste verdieping | 1183 | 0.250109 | 0.0117827 | 0.490258 | 6065368 | V1 ok. ruwe vloer | Model Group:Merk K24:6065352
6065402 | 01 eerste verdieping | 857 | 0.183931 | 0.00853572 | 0.357902 | 6065399 | V1 ok. ruwe vloer | Model Group:Merk K24:6065383
6065408 | 01 eerste verdieping | 1183 | 0.250109 | 0.0117827 | 0.490258 | 6065399 | V1 ok. ruwe vloer | Model Group:Merk K24:6065383
6065433 | 01 eerste verdieping | 857 | 0.183931 | 0.00853572 | 0.357902 | 6065430 | V1 ok. ruwe vloer | Model Group:Merk K24:6065414
6065439 | 01 eerste verdieping | 1183 | 0.250109 | 0.0117827 | 0.490258 | 6065430 | V1 ok. ruwe vloer | Model Group:Merk K24:6065414
6065464 | 01 eerste verdieping | 857 | 0.183931 | 0.00853572 | 0.357902 | 6065461 | V1 ok. ruwe vloer | Model Group:Merk K24:6065445
6065470 | 01 eerste verdieping | 1183 | 0.250109 | 0.0117827 | 0.490258 | 6065461 | V1 ok. ruwe vloer | Model Group:Merk K24:6065445
6065495 | 01 eerste verdieping | 857 | 0.183931 | 0.00853572 | 0.357902 | 6065492 | V1 ok. ruwe vloer | Model Group:Merk K24:6065476
6065501 | 01 eerste verdieping | 1183 | 0.250109 | 0.0117827 | 0.490258 | 6065492 | V1 ok. ruwe vloer | Model Group:Merk K24:6065476
6065526 | 01 eerste verdieping | 857 | 0.183931 | 0.00853572 | 0.357902 | 6065523 | V1 ok. ruwe vloer | Model Group:Merk K24:6065507
6065532 | 01 eerste verdieping | 1183 | 0.250109 | 0.0117827 | 0.490258 | 6065523 | V1 ok. ruwe vloer | Model Group:Merk K24:6065507
6065557 | 01 eerste verdieping | 857 | 0.183931 | 0.00853572 | 0.357902 | 6065554 | V1 ok. ruwe vloer | Model Group:Merk K24:6065538
6065563 | 01 eerste verdieping | 1183 | 0.250109 | 0.0117827 | 0.490258 | 6065554 | V1 ok. ruwe vloer | Model Group:Merk K24:6065538
6065588 | 01 eerste verdieping | 857 | 0.183931 | 0.00853572 | 0.357902 | 6065585 | V1 ok. ruwe vloer | Model Group:Merk K24:6065569
6065594 | 01 eerste verdieping | 1183 | 0.250109 | 0.0117827 | 0.490258 | 6065585 | V1 ok. ruwe vloer | Model Group:Merk K24:6065569
6315733 | 01 eerste verdieping | 680 | 0.148 | 0.0067728 | 0.296 | 6315730 | V1 ok. ruwe vloer | Model Group:Merk K31:6065001
6315976 | 01 eerste verdieping | 680 | 0.148 | 0.0067728 | 0.296 | 6315973 | V1 ok. ruwe vloer | Model Group:Merk K31:6065058
6322837 | 01 eerste verdieping | 680 | 0.148 | 0.0067728 | 0.296 | 6322834 | V1 ok. ruwe vloer | Model Group:Merk K31:6322821
6322868 | 01 eerste verdieping | 680 | 0.148 | 0.0067728 | 0.296 | 6322865 | V1 ok. ruwe vloer | Model Group:Merk K31:6322854
6474579 | 00 Begane grond | 680 | 0.148 | 0.0067728 | 0.296 | 6474576 | V-1 | Model Group:Merk K31:6474575
6474587 | 01 eerste verdieping | 767 | 0.165661 | 0.00763932 | 0.321362 | 6474584 | 1 | Model Group:Merk K32:5538094
6474593 | 01 eerste verdieping | 1483 | 0.311009 | 0.0147707 | 0.612058 | 6474584 | 1 | Model Group:Merk K32:5538094
6782311 | 00 Begane grond | 2120 | 0.44032 | 0.0211152 | 0.88064 | 6782308 | 0

# IfcMember: Rectangular Mullion:154x83 Gealan Kubus (48)
Type - PredefinedType: MULLION; Material: ISR_Kunststof_RAL7006
Type - Other - Category: Curtain Wall Mullions; Family Name: Rectangular Mullion
Type - Constraints - Angle: 0 deg; Offset: 41.5 mm
Type - Construction - Corner Mullion: no; Position: Perpendicular to Face; Profile: System Mullion Profile: Rectangular; Thickness: 83 mm
Type - Dimensions - Width on side 1: 77 mm; Width on side 2: 77 mm
Type - Identity Data - Workset: Family : Curtain Wall Mullions : Rectangular Mullion; Type Name: 154x83 Gealan Kubus
Type - Materials and Finishes - Material: ISR_Kunststof_RAL7006
Type - Pset_MemberCommon - IsExternal: no
Type - Pset_ProductRequirements - Category: Curtain Wall Mullions
Classification: 31 Uniformat (Uniformat)
Pset_MemberCommon - Reference: 154x83 Gealan Kubus
Pset_QuantityTakeOff - Reference: 154x83 Gealan Kubus
Other - Family: Rectangular Mullion; Family and Type: Rectangular Mullion: 154x83 Gealan Kubus; Type: 154x83 Gealan Kubus; Type Id: 6122554
Identity Data - Workset: Bouwkundig
Phasing - Phase Created: 2. nieuwbouw
Name (Rectangular Mullion:154x83 Gealan Kubus:...) | In | Span (mm) = BaseQuantities, Length (mm) = Dimensions, Length (mm) | CrossSectionArea (m2) = Area (m2) | NetVolume (m3) = Volume (m3) | NetSurfaceArea (m2) | Host Id | Level | Group
5539243 | 00 Begane grond | 1930 | 0.470192 | 0.0246693 | 0.940384 | 5537386 | 0 | Model Group:Merk K08:5537385 | Pset_MemberCommon - IsExternal: yes
5539249 | 00 Begane grond | 590 | 0.152612 | 0.00754138 | 0.305224 | 5537394 | 0 | Model Group:Merk K09:5537393
6897000 | 00 Begane grond | 590 | 0.152612 | 0.00754138 | 0.305224 | 5537402 | 0 | Model Group:Merk K10:5537401
6896097 | 00 Begane grond | 590 | 0.152612 | 0.00754138 | 0.305224 | 5537410 | 0 | Model Group:Merk K11:5537409
5611178 | 00 Begane grond | 1960 | 0.477302 | 0.0250527 | 0.954604 | 5537503 | 0 | Model Group:Merk K07:5537502
5537548 | 00 Begane grond | 2530 | 0.612392 | 0.0323385 | 1.22478 | 5537537 | 0 | Model Group:Merk K15:5537536
6479922 | 00 Begane grond | 2410 | 0.583952 | 0.0308046 | 1.1679 | 5537537 | 0 | Model Group:Merk K15:5537536
5611361 | 00 Begane grond | 1960 | 0.477302 | 0.0250527 | 0.954604 | 5537725 | 0 | Model Group:Merk K07:5537724
5549598 | 01 eerste verdieping | 1710 | 0.418052 | 0.0218572 | 0.836104 | 5537991 | 1 | Model Group:Merk K22:5537990
5548701 | 01 eerste verdieping | 1710 | 0.418052 | 0.0218572 | 0.836104 | 5537999 | 1 | Model Group:Merk K22:5537998
5549607 | 01 eerste verdieping | 1710 | 0.418052 | 0.0218572 | 0.836104 | 5538007 | 1 | Model Group:Merk K22:5538006
5549616 | 01 eerste verdieping | 1710 | 0.418052 | 0.0218572 | 0.836104 | 5538015 | 1 | Model Group:Merk K22:5538014
5549625 | 01 eerste verdieping | 1710 | 0.418052 | 0.0218572 | 0.836104 | 5538023 | 1 | Model Group:Merk K22:5538022
5549634 | 01 eerste verdieping | 1710 | 0.418052 | 0.0218572 | 0.836104 | 5538031 | 1 | Model Group:Merk K22:5538030
5549643 | 01 eerste verdieping | 1710 | 0.418052 | 0.0218572 | 0.836104 | 5538039 | 1 | Model Group:Merk K22:5538038
5549652 | 01 eerste verdieping | 1710 | 0.418052 | 0.0218572 | 0.836104 | 5538047 | 1 | Model Group:Merk K22:5538046
5549661 | 01 eerste verdieping | 1710 | 0.418052 | 0.0218572 | 0.836104 | 5538055 | 1 | Model Group:Merk K22:5538054
5549670 | 01 eerste verdieping | 1710 | 0.418052 | 0.0218572 | 0.836104 | 5538063 | 1 | Model Group:Merk K22:5538062
5549679 | 01 eerste verdieping | 1710 | 0.418052 | 0.0218572 | 0.836104 | 5538071 | 1 | Model Group:Merk K22:5538070
5549688 | 01 eerste verdieping | 1710 | 0.418052 | 0.0218572 | 0.836104 | 5538079 | 1 | Model Group:Merk K22:5538078
5549697 | 01 eerste verdieping | 1710 | 0.418052 | 0.0218572 | 0.836104 | 5538087 | 1 | Model Group:Merk K22:5538086
5549715 | 01 eerste verdieping | 1710 | 0.418052 | 0.0218572 | 0.836104 | 5538103 | 1 | Model Group:Merk K32:5538102
5719823 | 01 eerste verdieping | 2540 | 0.614762 | 0.0324663 | 1.22952 | 5538542 | 1 | Model Group:Merk K27:5538541
5542022 | 00 Begane grond | 1710 | 0.418052 | 0.0218572 | 0.836104 | 5542011 | 0 | Model Group:Merk K17:5540560
5542299 | 00 Begane grond | 1710 | 0.418052 | 0.0218572 | 0.836104 | 5542288 | 0 | Model Group:Merk K17:5542284
5542325 | 00 Begane grond | 1710 | 0.418052 | 0.0218572 | 0.836104 | 5542314 | 0 | Model Group:Merk K17:5542310
5542351 | 00 Begane grond | 1710 | 0.418052 | 0.0218572 | 0.836104 | 5542340 | 0 | Model Group:Merk K17:5542336
5542377 | 00 Begane grond | 1710 | 0.418052 | 0.0218572 | 0.836104 | 5542366 | 0 | Model Group:Merk K17:5542362
5542403 | 00 Begane grond | 1710 | 0.418052 | 0.0218572 | 0.836104 | 5542392 | 0 | Model Group:Merk K17:5542388
5544309 | 00 Begane grond | 1710 | 0.418052 | 0.0218572 | 0.836104 | 5544298 | 0 | Model Group:Merk K17:5544294
5544987 | 00 Begane grond | 1710 | 0.418052 | 0.0218572 | 0.836104 | 5544976 | 0 | Model Group:Merk K17:5544972
5545022 | 00 Begane grond | 1710 | 0.418052 | 0.0218572 | 0.836104 | 5545011 | 0 | Model Group:Merk K17:5545007
5856000 | 00 Begane grond | 1710 | 0.418052 | 0.0218572 | 0.836104 | 5855990 | 0 | Model Group:Merk K17:5855989
5856041 | 00 Begane grond | 1710 | 0.418052 | 0.0218572 | 0.836104 | 5856031 | 0 | Model Group:Merk K17:5856030
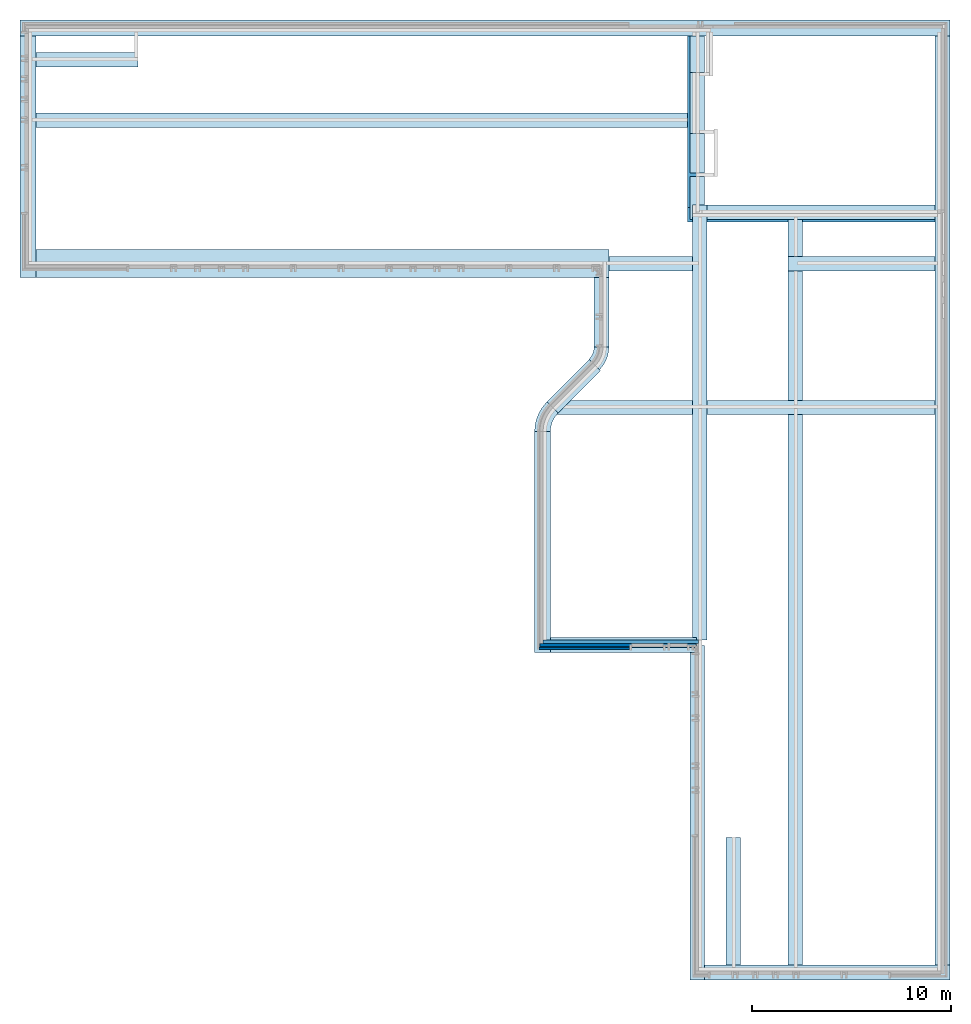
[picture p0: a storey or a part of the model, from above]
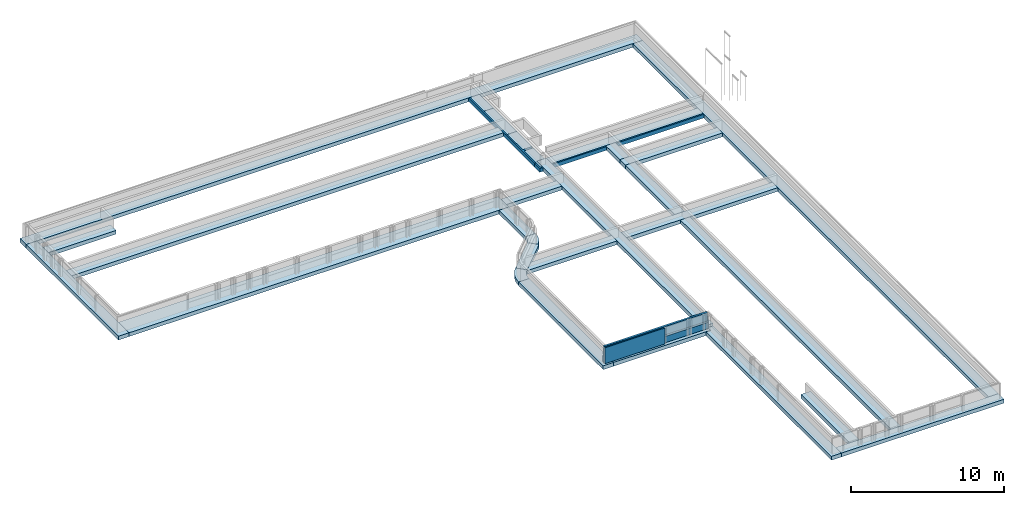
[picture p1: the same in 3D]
Properties of the parts of a building model (IFC2X3), part 19 of 37

# IfcMember: Rectangular Mullion:154x83 Gealan Kubus (48)
Name (Rectangular Mullion:154x83 Gealan Kubus:...) | In | Span (mm) = BaseQuantities, Length (mm) = Dimensions, Length (mm) | CrossSectionArea (m2) = Area (m2) | NetVolume (m3) = Volume (m3) | NetSurfaceArea (m2) | Host Id | Level | Group
6065223 | 01 eerste verdieping | 1710 | 0.418052 | 0.0218572 | 0.836104 | 6065213 | V1 ok. ruwe vloer | Model Group:Merk K24:6065197
6065254 | 01 eerste verdieping | 1710 | 0.418052 | 0.0218572 | 0.836104 | 6065244 | V1 ok. ruwe vloer | Model Group:Merk K24:6065228
6065285 | 01 eerste verdieping | 1710 | 0.418052 | 0.0218572 | 0.836104 | 6065275 | V1 ok. ruwe vloer | Model Group:Merk K24:6065259
6065316 | 01 eerste verdieping | 1710 | 0.418052 | 0.0218572 | 0.836104 | 6065306 | V1 ok. ruwe vloer | Model Group:Merk K24:6065290
6065347 | 01 eerste verdieping | 1710 | 0.418052 | 0.0218572 | 0.836104 | 6065337 | V1 ok. ruwe vloer | Model Group:Merk K24:6065321
6065378 | 01 eerste verdieping | 1710 | 0.418052 | 0.0218572 | 0.836104 | 6065368 | V1 ok. ruwe vloer | Model Group:Merk K24:6065352
6065409 | 01 eerste verdieping | 1710 | 0.418052 | 0.0218572 | 0.836104 | 6065399 | V1 ok. ruwe vloer | Model Group:Merk K24:6065383
6065440 | 01 eerste verdieping | 1710 | 0.418052 | 0.0218572 | 0.836104 | 6065430 | V1 ok. ruwe vloer | Model Group:Merk K24:6065414
6065471 | 01 eerste verdieping | 1710 | 0.418052 | 0.0218572 | 0.836104 | 6065461 | V1 ok. ruwe vloer | Model Group:Merk K24:6065445
6065502 | 01 eerste verdieping | 1710 | 0.418052 | 0.0218572 | 0.836104 | 6065492 | V1 ok. ruwe vloer | Model Group:Merk K24:6065476
6065533 | 01 eerste verdieping | 1710 | 0.418052 | 0.0218572 | 0.836104 | 6065523 | V1 ok. ruwe vloer | Model Group:Merk K24:6065507
6065564 | 01 eerste verdieping | 1710 | 0.418052 | 0.0218572 | 0.836104 | 6065554 | V1 ok. ruwe vloer | Model Group:Merk K24:6065538
6065595 | 01 eerste verdieping | 1710 | 0.418052 | 0.0218572 | 0.836104 | 6065585 | V1 ok. ruwe vloer | Model Group:Merk K24:6065569
6474594 | 01 eerste verdieping | 1710 | 0.418052 | 0.0218572 | 0.836104 | 6474584 | 1 | Model Group:Merk K32:5538094

# IfcMember: Rectangular Mullion:20x74 (19)
In: 00 Begane grond
Type - PredefinedType: MULLION; Material: ISR_Kunststof_wit
Type - Other - Category: Curtain Wall Mullions; Family Name: Rectangular Mullion
Type - Constraints - Angle: 0 deg; Offset: 37 mm
Type - Construction - Corner Mullion: no; Position: Perpendicular to Face; Profile: System Mullion Profile: Rectangular; Thickness: 74 mm
Type - Dimensions - Width on side 1: 10 mm; Width on side 2: 10 mm
Type - Identity Data - Workset: Family : Curtain Wall Mullions : Rectangular Mullion; Type Name: 20x74
Type - Materials and Finishes - Material: ISR_Kunststof_wit
Type - Pset_MemberCommon - IsExternal: no
Type - Pset_ProductRequirements - Category: Curtain Wall Mullions
Pset_MemberCommon - Reference: 20x74
Pset_QuantityTakeOff - Reference: 20x74
Other - Family: Rectangular Mullion; Family and Type: Rectangular Mullion: 20x74; Type: 20x74; Type Id: 4793678
Constraints - Level: 0
Phasing - Phase Created: 2. nieuwbouw
Name (Rectangular Mullion:20x74:...) | Classification | Span (mm) = BaseQuantities, Length (mm) = Dimensions, Length (mm) | CrossSectionArea (m2) = Area (m2) | NetVolume (m3) = Volume (m3) | NetSurfaceArea (m2) | Host Id | Workset | Group
5536860 | 31 Uniformat (Uniformat) | 976 | 0.093224 | 0.00144448 | 0.184968 | 5536857 | Bouwkundig | Model Group:Merk K03:5536856 | Pset_MemberCommon - IsExternal: yes
5536866 | 31 Uniformat (Uniformat) | 976 | 0.093224 | 0.00144448 | 0.184968 | 5536857 | Bouwkundig | Model Group:Merk K03:5536856 | Pset_MemberCommon - IsExternal: yes
5536932 | 31 Uniformat (Uniformat) | 976 | 0.093224 | 0.00144448 | 0.184968 | 5536929 | Bouwkundig | Model Group:Merk K03:5536928
5536938 | 31 Uniformat (Uniformat) | 976 | 0.093224 | 0.00144448 | 0.184968 | 5536929 | Bouwkundig | Model Group:Merk K03:5536928
5537083 | 31 Uniformat (Uniformat) | 976 | 0.093224 | 0.00144448 | 0.184968 | 5537080 | Bouwkundig | Model Group:Merk K03:5537079
5537089 | 31 Uniformat (Uniformat) | 976 | 0.093224 | 0.00144448 | 0.184968 | 5537080 | Bouwkundig | Model Group:Merk K03:5537079
5538766 | 31 Uniformat (Uniformat) | 976 | 0.093224 | 0.00144448 | 0.184968 | 5538763 | Bouwkundig | Model Group:Merk K03:5538762
5538772 | 31 Uniformat (Uniformat) | 976 | 0.093224 | 0.00144448 | 0.184968 | 5538763 | Bouwkundig | Model Group:Merk K03:5538762
5538784 | 31 Uniformat (Uniformat) | 976 | 0.093224 | 0.00144448 | 0.184968 | 5538781 | Bouwkundig | Model Group:Merk K03:5538780
5538790 | 31 Uniformat (Uniformat) | 976 | 0.093224 | 0.00144448 | 0.184968 | 5538781 | Bouwkundig | Model Group:Merk K03:5538780
5538802 | 31 Uniformat (Uniformat) | 976 | 0.093224 | 0.00144448 | 0.184968 | 5538799 | Bouwkundig | Model Group:Merk K03:5538798
5538808 | 31 Uniformat (Uniformat) | 976 | 0.093224 | 0.00144448 | 0.184968 | 5538799 | Bouwkundig | Model Group:Merk K03:5538798
5539078 | 31 Uniformat (Uniformat) | 871 | 0.083354 | 0.00128908 | 0.165228 | 5539075 | Bouwkundig | Model Group:Merk K20:5539074
5539084 | 31 Uniformat (Uniformat) | 871 | 0.083354 | 0.00128908 | 0.165228 | 5539075 | Bouwkundig | Model Group:Merk K20:5539074
6486309 | 27.20 Uniformat (Uniformat) | 1417 | 0.134678 | 0.00209716 | 0.269356 | 6486298 | situatie
6486310 | 27.20 Uniformat (Uniformat) | 1417 | 0.134678 | 0.00209716 | 0.269356 | 6486298 | situatie
6486311 | 27.20 Uniformat (Uniformat) | 2419 | 0.228866 | 0.00358012 | 0.456252 | 6486298 | situatie
6486318 | 27.20 Uniformat (Uniformat) | 2419 | 0.228866 | 0.00358012 | 0.456252 | 6486298 | situatie
6486320 | 27.20 Uniformat (Uniformat) | 1417 | 0.134678 | 0.00209716 | 0.269356 | 6486298 | situatie

# IfcMember: Rectangular Mullion:31_CWM_020x114 (120)
Type - PredefinedType: MULLION; Material: ISR_Kunststof_grijs
Type - Other - Category: Curtain Wall Mullions; Family Name: Rectangular Mullion
Type - Constraints - Angle: 0 deg; Offset: 57 mm
Type - Construction - Corner Mullion: no; Position: Perpendicular to Face; Profile: System Mullion Profile: Rectangular; Thickness: 114 mm
Type - Dimensions - Width on side 1: 10 mm; Width on side 2: 10 mm
Type - Identity Data - Workset: Family : Curtain Wall Mullions : Rectangular Mullion; Type Name: 31_CWM_020x114
Type - Materials and Finishes - Material: ISR_Kunststof_grijs
Type - Pset_MemberCommon - IsExternal: no
Type - Pset_ProductRequirements - Category: Curtain Wall Mullions
Classification: 31.10 Uniformat (Uniformat)
Pset_MemberCommon - Reference: 31_CWM_020x114
Pset_QuantityTakeOff - Reference: 31_CWM_020x114
Other - Family: Rectangular Mullion; Family and Type: Rectangular Mullion: 31_CWM_020x114; Type: 31_CWM_020x114; Type Id: 5121253
Identity Data - Workset: Bouwkundig
Phasing - Phase Created: 2. nieuwbouw
Name (Rectangular Mullion:31_CWM_020x114:...) | In | Span (mm) = BaseQuantities, Length (mm) = Dimensions, Length (mm) | CrossSectionArea (m2) = Area (m2) | NetVolume (m3) = Volume (m3) | NetSurfaceArea (m2) | Host Id | Level | Group
5125429 | 00 Begane grond | 900 | 0.12288 | 0.002052 | 0.24576 | 5125426 | 0 | Model Group:H01:5125425 | Pset_MemberCommon - IsExternal: yes
5125628 | 00 Begane grond | 900 | 0.12288 | 0.002052 | 0.24576 | 5125625 | 0 | Model Group:H01:5125624
5125873 | 00 Begane grond | 966 | 0.131724 | 0.00220248 | 0.263448 | 5125870 | 0 | Model Group:H19:5125869
5126013 | 00 Begane grond | 900 | 0.12288 | 0.002052 | 0.24576 | 5126010 | 0 | Model Group:H01:5126009
5126022 | 00 Begane grond | 900 | 0.12288 | 0.002052 | 0.24576 | 5126019 | 0 | Model Group:H01:5126018
5126066 | 00 Begane grond | 900 | 0.12288 | 0.002052 | 0.24576 | 5126063 | 0 | Model Group:H01:5126062
5126075 | 00 Begane grond | 900 | 0.12288 | 0.002052 | 0.24576 | 5126072 | 0 | Model Group:H01:5126071
5126989 | 00 Begane grond | 900 | 0.12288 | 0.002052 | 0.24576 | 5126986 | 0 | Model Group:H02:5126985
5127344 | 00 Begane grond | 900 | 0.12288 | 0.002052 | 0.24576 | 5127341 | 0 | Model Group:H01:5127340
5127586 | 00 Begane grond | 900 | 0.12288 | 0.002052 | 0.24576 | 5127583 | 0 | Model Group:H01:5127582
5127597 | 00 Begane grond | 900 | 0.12288 | 0.002052 | 0.24576 | 5127594 | 0 | Model Group:H01:5127593
5127608 | 01 eerste verdieping | 900 | 0.12288 | 0.002052 | 0.24576 | 5127605 | 1 | Model Group:H01:5127604
5127619 | 01 eerste verdieping | 900 | 0.12288 | 0.002052 | 0.24576 | 5127616 | 1 | Model Group:H01:5127615
5127630 | 01 eerste verdieping | 900 | 0.12288 | 0.002052 | 0.24576 | 5127627 | 1 | Model Group:H01:5127626
5130148 | 00 Begane grond | 900 | 0.12288 | 0.002052 | 0.24576 | 5130145 | 0 | Model Group:H02:5130144
5130959 | 00 Begane grond | 1000 | 0.13628 | 0.00228 | 0.27256 | 5130949 | 0 | Model Group:H04:5130948
5131657 | 00 Begane grond | 1000 | 0.13628 | 0.00228 | 0.27256 | 5131647 | 0 | Model Group:H04:5131646
5131944 | 00 Begane grond | 1067 | 0.145258 | 0.00243276 | 0.290516 | 5131934 | 0 | Model Group:H03:5131933
5140503 | 00 Begane grond | 1000 | 0.13628 | 0.00228 | 0.27028 | 5140500 | 0 | Model Group:H20:5488876
5488428 | 00 Begane grond | 1000 | 0.13628 | 0.00228 | 0.27028 | 5140500 | 0 | Model Group:H20:5488876
5142283 | 00 Begane grond | 937.5 | 0.127905 | 0.0021375 | 0.25353 | 5142280 | 0 | Model Group:H14:5143401
5142658 | 00 Begane grond | 937.5 | 0.127905 | 0.0021375 | 0.25353 | 5142280 | 0 | Model Group:H14:5143401
5143926 | 00 Begane grond | 1060 | 0.14432 | 0.0024168 | 0.28636 | 5143923 | 0 | Model Group:H06:5143935
5143934 | 00 Begane grond | 1060 | 0.14432 | 0.0024168 | 0.28636 | 5143923 | 0 | Model Group:H06:5143935
5144107 | 00 Begane grond | 990 | 0.13494 | 0.0022572 | 0.2676 | 5144104 | 0 | Model Group:H07:5144116
5144115 | 00 Begane grond | 990 | 0.13494 | 0.0022572 | 0.2676 | 5144104 | 0 | Model Group:H07:5144116
5145174 | 00 Begane grond | 990 | 0.13494 | 0.0022572 | 0.2676 | 5145171 | 0 | Model Group:H07:5145183
5145182 | 00 Begane grond | 990 | 0.13494 | 0.0022572 | 0.2676 | 5145171 | 0 | Model Group:H07:5145183
5149169 | 00 Begane grond | 1000 | 0.13628 | 0.00228 | 0.27256 | 5149166 | 0 | Model Group:H09:5145245
5149213 | 00 Begane grond | 1000 | 0.13628 | 0.00228 | 0.27256 | 5149210 | 0 | Model Group:H09:5145654
5149221 | 00 Begane grond | 1000 | 0.13628 | 0.00228 | 0.27256 | 5149218 | 0 | Model Group:H09:5145678
5151851 | 00 Begane grond | 900 | 0.12288 | 0.002052 | 0.24348 | 5151840 | 0 | Model Group:H10:5151852
5161254 | 00 Begane grond | 900 | 0.12288 | 0.002052 | 0.24348 | 5151840 | 0 | Model Group:H10:5151852
5167026 | 01 eerste verdieping | 1000 | 0.13628 | 0.00228 | 0.27256 | 5167023 | 1 | Model Group:H09:5167012
5167167 | 01 eerste verdieping | 1000 | 0.13628 | 0.00228 | 0.27256 | 5167164 | 1 | Model Group:H09:5167153
5174553 | 01 eerste verdieping | 900 | 0.12288 | 0.002052 | 0.24576 | 5174550 | 1 | Model Group:H01:5174549
5174897 | 01 eerste verdieping | 1000 | 0.13628 | 0.00228 | 0.27256 | 5174894 | 1 | Model Group:H09:5174883
5179832 | 01 eerste verdieping | 1067 | 0.145258 | 0.00243276 | 0.290516 | 5179822 | 1 | Model Group:H03:5179821
5181901 | 01 eerste verdieping | 1000 | 0.13628 | 0.00228 | 0.27256 | 5181898 | 1 | Model Group:H09:5181878
5184360 | 01 eerste verdieping | 1000 | 0.13628 | 0.00228 | 0.27256 | 5184357 | 1 | Model Group:H09:5184337
5184409 | 01 eerste verdieping | 1000 | 0.13628 | 0.00228 | 0.27256 | 5184406 | 1 | Model Group:H09:5184386
5185802 | 01 eerste verdieping | 1067 | 0.145258 | 0.00243276 | 0.290516 | 5185792 | 1 | Model Group:H18:5185791
5194911 | 01 eerste verdieping | 896.25 | 0.122378 | 0.00204345 | 0.242475 | 5194902 | 1 | Model Group:H12:5194912
5194919 | 01 eerste verdieping | 903.75 | 0.123382 | 0.00206055 | 0.244485 | 5194902 | 1 | Model Group:H12:5194912
5202333 | 00 Begane grond | 900 | 0.12288 | 0.002052 | 0.24576 | 5202330 | 0 | Model Group:H02:5127227
5203624 | 00 Begane grond | 1000 | 0.13628 | 0.00228 | 0.27256 | 5203621 | 0 | Model Group:H09:5203601
5206510 | 00 Begane grond | 900 | 0.12288 | 0.002052 | 0.24576 | 5206507 | 0 | Model Group:H02:5206506
5206891 | 00 Begane grond | 1000 | 0.13628 | 0.00228 | 0.27256 | 5206888 | 0 | Model Group:H09:5206741
5227229 | 01 eerste verdieping | 990 | 0.13494 | 0.0022572 | 0.2676 | 5227226 | 1 | Model Group:H07:5227238
5227237 | 01 eerste verdieping | 990 | 0.13494 | 0.0022572 | 0.2676 | 5227226 | 1 | Model Group:H07:5227238
5227248 | 01 eerste verdieping | 900 | 0.12288 | 0.002052 | 0.24576 | 5227245 | 1 | Model Group:H16:5227244
5227255 | 01 eerste verdieping | 990 | 0.13494 | 0.0022572 | 0.2676 | 5227252 | 1 | Model Group:H07:5227264
5227263 | 01 eerste verdieping | 990 | 0.13494 | 0.0022572 | 0.2676 | 5227252 | 1 | Model Group:H07:5227264
5276456 | 00 Begane grond | 900 | 0.12288 | 0.002052 | 0.24576 | 5276453 | 0 | Model Group:H16:5197611
5276563 | 00 Begane grond | 900 | 0.12288 | 0.002052 | 0.24576 | 5276560 | 0 | Model Group:H16:5195722
5276572 | 00 Begane grond | 900 | 0.12288 | 0.002052 | 0.24576 | 5276569 | 0 | Model Group:H16:5197451
5277204 | 01 eerste verdieping | 900 | 0.12288 | 0.002052 | 0.24576 | 5277201 | 1 | Model Group:H01:5174800
5277240 | 01 eerste verdieping | 900 | 0.12288 | 0.002052 | 0.24576 | 5277237 | 1 | Model Group:H01:5174841
5465838 | 00 Begane grond | 1067 | 0.145258 | 0.00243276 | 0.290516 | 5465828 | 0 | Model Group:H03:5465827
5489861 | 00 Begane grond | 1155 | 0.15705 | 0.0026334 | 0.31182 | 5489859 | 0 | Model Group:H24:5489871
5489862 | 00 Begane grond | 1205 | 0.16375 | 0.0027474 | 0.32522 | 5489859 | 0 | Model Group:H24:5489871
5489863 | 00 Begane grond | 2350 | 0.31718 | 0.005358 | 0.63436 | 5489859 | 0 | Model Group:H24:5489871
5489864 | 00 Begane grond | 2350 | 0.31718 | 0.005358 | 0.63436 | 5489859 | 0 | Model Group:H24:5489871
5489869 | 00 Begane grond | 1205 | 0.16375 | 0.0027474 | 0.32522 | 5489859 | 0 | Model Group:H24:5489871
5489870 | 00 Begane grond | 1155 | 0.15705 | 0.0026334 | 0.31182 | 5489859 | 0 | Model Group:H24:5489871
5489888 | 00 Begane grond | 1152.5 | 0.156715 | 0.0026277 | 0.31115 | 5489886 | 0 | Model Group:H21:5489898
5489889 | 00 Begane grond | 1147.5 | 0.156045 | 0.0026163 | 0.30981 | 5489886 | 0 | Model Group:H21:5489898
5489890 | 00 Begane grond | 2350 | 0.31718 | 0.005358 | 0.63436 | 5489886 | 0 | Model Group:H21:5489898
5489891 | 00 Begane grond | 2350 | 0.31718 | 0.005358 | 0.63436 | 5489886 | 0 | Model Group:H21:5489898
5489896 | 00 Begane grond | 1147.5 | 0.156045 | 0.0026163 | 0.30981 | 5489886 | 0 | Model Group:H21:5489898
5489897 | 00 Begane grond | 1152.5 | 0.156715 | 0.0026277 | 0.31115 | 5489886 | 0 | Model Group:H21:5489898
5490911 | 00 Begane grond | 1155 | 0.15705 | 0.0026334 | 0.31182 | 5490909 | 0 | Model Group:H24:5490908
5490912 | 00 Begane grond | 1205 | 0.16375 | 0.0027474 | 0.32522 | 5490909 | 0 | Model Group:H24:5490908
5490913 | 00 Begane grond | 2350 | 0.31718 | 0.005358 | 0.63436 | 5490909 | 0 | Model Group:H24:5490908
5490914 | 00 Begane grond | 2350 | 0.31718 | 0.005358 | 0.63436 | 5490909 | 0 | Model Group:H24:5490908
5490919 | 00 Begane grond | 1205 | 0.16375 | 0.0027474 | 0.32522 | 5490909 | 0 | Model Group:H24:5490908
5490920 | 00 Begane grond | 1155 | 0.15705 | 0.0026334 | 0.31182 | 5490909 | 0 | Model Group:H24:5490908
5493793 | -1 Speelvloer | 900 | 0.12288 | 0.002052 | 0.24348 | 5493791 | V-1 | Model Group:H22:5493776
5493794 | -1 Speelvloer | 1180 | 0.1604 | 0.0026904 | 0.31852 | 5493791 | V-1 | Model Group:H22:5493776
5493795 | -1 Speelvloer | 2610 | 0.35202 | 0.0059508 | 0.70404 | 5493791 | V-1 | Model Group:H22:5493776
5493796 | -1 Speelvloer | 2610 | 0.35202 | 0.0059508 | 0.70404 | 5493791 | V-1 | Model Group:H22:5493776
5493801 | -1 Speelvloer | 1180 | 0.1604 | 0.0026904 | 0.31852 | 5493791 | V-1 | Model Group:H22:5493776
5493802 | -1 Speelvloer | 900 | 0.12288 | 0.002052 | 0.24348 | 5493791 | V-1 | Model Group:H22:5493776
5533685 | 01 eerste verdieping | 900 | 0.12288 | 0.002052 | 0.24576 | 5533682 | 1 | Model Group:H02:5533681
5533698 | 01 eerste verdieping | 900 | 0.12288 | 0.002052 | 0.24348 | 5533689 | 1 | Model Group:H11:5533699
5533706 | 01 eerste verdieping | 900 | 0.12288 | 0.002052 | 0.24348 | 5533689 | 1 | Model Group:H11:5533699
5987152 | 01 eerste verdieping | 900 | 0.12288 | 0.002052 | 0.24576 | 5987149 | 1 | Model Group:H02:5987148
5987398 | 01 eerste verdieping | 900 | 0.12288 | 0.002052 | 0.24576 | 5987395 | 1 | Model Group:H02:5987394
5987406 | 01 eerste verdieping | 900 | 0.12288 | 0.002052 | 0.24576 | 5987403 | 1 | Model Group:H02:5987402
5988151 | 01 eerste verdieping | 1000 | 0.13628 | 0.00228 | 0.27256 | 5988148 | 1 | Model Group:H09:5988145
5994928 | 01 eerste verdieping | 900 | 0.12288 | 0.002052 | 0.24576 | 5994925 | 1 | Model Group:H01:5994924
5995274 | 01 eerste verdieping | 990 | 0.13494 | 0.0022572 | 0.2676 | 5995271 | 1 | Model Group:H07:5995281
5995280 | 01 eerste verdieping | 990 | 0.13494 | 0.0022572 | 0.2676 | 5995271 | 1 | Model Group:H07:5995281
6241472 | 00 Begane grond | 1000 | 0.13628 | 0.00228 | 0.27256 | 6241462 | 0 | Model Group:H04:6241461
6241704 | 00 Begane grond | 1155 | 0.15705 | 0.0026334 | 0.31182 | 6241702 | 0 | Model Group:H24:6241714
6241705 | 00 Begane grond | 1205 | 0.16375 | 0.0027474 | 0.32522 | 6241702 | 0 | Model Group:H24:6241714
6241706 | 00 Begane grond | 2350 | 0.31718 | 0.005358 | 0.63436 | 6241702 | 0 | Model Group:H24:6241714
6241707 | 00 Begane grond | 2350 | 0.31718 | 0.005358 | 0.63436 | 6241702 | 0 | Model Group:H24:6241714
6241712 | 00 Begane grond | 1205 | 0.16375 | 0.0027474 | 0.32522 | 6241702 | 0 | Model Group:H24:6241714
6241713 | 00 Begane grond | 1155 | 0.15705 | 0.0026334 | 0.31182 | 6241702 | 0 | Model Group:H24:6241714
6382287 | 01 eerste verdieping | 900 | 0.12288 | 0.002052 | 0.24576 | 6382284 | 1 | Model Group:H16:5185909
6522734 | 00 Begane grond | 900 | 0.12288 | 0.002052 | 0.24576 | 6522731 | 0 | Model Group:H02:6522730
6604036 | 00 Begane grond | 1067 | 0.145258 | 0.00243276 | 0.290516 | 6604026 | 0 | Model Group:H18:5129917
6608199 | -1 Speelvloer | 1057.96 | 0.144047 | 0.00241215 | 0.285813 | 6608197 | V-1 | Model Group:H23:5131789
6608200 | -1 Speelvloer | 1057 | 0.143918 | 0.00240996 | 0.285556 | 6608197 | V-1 | Model Group:H23:5131789
6608201 | -1 Speelvloer | 2610 | 0.35202 | 0.0059508 | 0.70404 | 6608197 | V-1 | Model Group:H23:5131789
6608202 | -1 Speelvloer | 2610 | 0.35202 | 0.0059508 | 0.70404 | 6608197 | V-1 | Model Group:H23:5131789
6608207 | -1 Speelvloer | 1057 | 0.143918 | 0.00240996 | 0.285556 | 6608197 | V-1 | Model Group:H23:5131789
6608208 | -1 Speelvloer | 1057.96 | 0.144047 | 0.00241215 | 0.285813 | 6608197 | V-1 | Model Group:H23:5131789
6668706 | 00 Begane grond | 1000 | 0.13628 | 0.00228 | 0.27256 | 6668703 | 0 | Model Group:H09:6668701
6694318 | 00 Begane grond | 900 | 0.12288 | 0.002052 | 0.24576 | 6694315 | 0 | Model Group:H02:6694314
6800005 | 00 Begane grond | 900 | 0.12288 | 0.002052 | 0.24576 | 6800002 | 0 | Model Group:H16:5145073
6800237 | 01 eerste verdieping | 900 | 0.12288 | 0.002052 | 0.24576 | 6800234 | 1 | Model Group:H16:5987797
6800246 | 01 eerste verdieping | 900 | 0.12288 | 0.002052 | 0.24576 | 6800243 | 1 | Model Group:H16:5995318
6801739 | 00 Begane grond | 900 | 0.12288 | 0.002052 | 0.24576 | 6801736 | 0 | Model Group:H16:5130407
6801782 | 00 Begane grond | 900 | 0.12288 | 0.002052 | 0.24576 | 6801779 | 0 | Model Group:H16:5127086
6802017 | 01 eerste verdieping | 900 | 0.12288 | 0.002052 | 0.24576 | 6802014 | 1 | Model Group:H16:5987147
6802180 | 01 eerste verdieping | 900 | 0.12288 | 0.002052 | 0.24576 | 6802177 | 1 | Model Group:H16:5987156
6802221 | 01 eerste verdieping | 900 | 0.12288 | 0.002052 | 0.24576 | 6802218 | 1 | Model Group:H16:5179182
6804084 | 00 Begane grond | 900 | 0.12288 | 0.002052 | 0.24576 | 6804081 | 0 | Model Group:H02:5126556

# IfcMember: Rectangular Mullion:31_CWM_067x114 (379)
Type - PredefinedType: MULLION; Material: ISR_HPL
Type - Other - Category: Curtain Wall Mullions; Family Name: Rectangular Mullion
Type - Constraints - Angle: 0 deg; Offset: 57 mm
Type - Construction - Corner Mullion: no; Position: Perpendicular to Face; Profile: System Mullion Profile: Rectangular; Thickness: 114 mm
Type - Dimensions - Width on side 1: 33.5 mm; Width on side 2: 33.5 mm
Type - Identity Data - Assembly Code: 31.0; Manufacturer: ITANNEX; Model: 10-07-2014; Type Name: 31_CWM_067x114; URL: www.bimvoorfabrikanten.nl; Workset: Family : Curtain Wall Mullions : Rectangular Mullion
Type - Materials and Finishes - Material: ISR_HPL
Type - Pset_ManufacturerTypeInformation - Manufacturer: ITANNEX
Type - Pset_MemberCommon - IsExternal: no
Type - Pset_ProductRequirements - Category: Curtain Wall Mullions
Classification: 31.10 Uniformat (Uniformat)
Pset_MemberCommon - Reference: 31_CWM_067x114
Pset_QuantityTakeOff - Reference: 31_CWM_067x114
Pset_DAT_KMS - Assembly Code: 31.0
Other - Family: Rectangular Mullion; Family and Type: Rectangular Mullion: 31_CWM_067x114; Type: 31_CWM_067x114; Type Id: 4285685
Identity Data - Workset: Bouwkundig
Phasing - Phase Created: 2. nieuwbouw
Name (Rectangular Mullion:31_CWM_067x114:...) | In | Span (mm) = BaseQuantities, Length (mm) = Dimensions, Length (mm) | CrossSectionArea (m2) = Area (m2) | NetVolume (m3) | NetSurfaceArea (m2) | Host Id | Level | Volume (m3) | Group
5125428 | 00 Begane grond | 1034 | 0.194792 | 0.00789769 | 0.389584 | 5125426 | 0 | 0.00789769 | Model Group:H01:5125425 | Pset_MemberCommon - IsExternal: yes
5125430 | 00 Begane grond | 2323 | 0.428101 | 0.0177431 | 0.856202 | 5125426 | 0 | 0.0177431 | Model Group:H01:5125425 | Pset_MemberCommon - IsExternal: yes
5125431 | 00 Begane grond | 2323 | 0.428101 | 0.0177431 | 0.856202 | 5125426 | 0 | 0.0177431 | Model Group:H01:5125425 | Pset_MemberCommon - IsExternal: yes
5125627 | 00 Begane grond | 1034 | 0.194792 | 0.00789769 | 0.389584 | 5125625 | 0 | 0.00789769 | Model Group:H01:5125624
5125629 | 00 Begane grond | 2323 | 0.428101 | 0.0177431 | 0.856202 | 5125625 | 0 | 0.0177431 | Model Group:H01:5125624
5125630 | 00 Begane grond | 2323 | 0.428101 | 0.0177431 | 0.856202 | 5125625 | 0 | 0.0177431 | Model Group:H01:5125624
5125872 | 00 Begane grond | 1100 | 0.206738 | 0.0084018 | 0.413476 | 5125870 | 0 | 0.0084018 | Model Group:H19:5125869
5125874 | 00 Begane grond | 2323 | 0.428101 | 0.0177431 | 0.856202 | 5125870 | 0 | 0.0177431 | Model Group:H19:5125869
5125875 | 00 Begane grond | 2323 | 0.428101 | 0.0177431 | 0.856202 | 5125870 | 0 | 0.0177431 | Model Group:H19:5125869
5126012 | 00 Begane grond | 1034 | 0.194792 | 0.00789769 | 0.389584 | 5126010 | 0 | 0.00789769 | Model Group:H01:5126009
5126014 | 00 Begane grond | 2323 | 0.428101 | 0.0177431 | 0.856202 | 5126010 | 0 | 0.0177431 | Model Group:H01:5126009
5126015 | 00 Begane grond | 2323 | 0.428101 | 0.0177431 | 0.856202 | 5126010 | 0 | 0.0177431 | Model Group:H01:5126009
5126021 | 00 Begane grond | 1034 | 0.194792 | 0.00789769 | 0.389584 | 5126019 | 0 | 0.00789769 | Model Group:H01:5126018
5126023 | 00 Begane grond | 2323 | 0.428101 | 0.0177431 | 0.856202 | 5126019 | 0 | 0.0177431 | Model Group:H01:5126018
5126024 | 00 Begane grond | 2323 | 0.428101 | 0.0177431 | 0.856202 | 5126019 | 0 | 0.0177431 | Model Group:H01:5126018
5126065 | 00 Begane grond | 1034 | 0.194792 | 0.00789769 | 0.389584 | 5126063 | 0 | 0.00789769 | Model Group:H01:5126062
5126067 | 00 Begane grond | 2323 | 0.428101 | 0.0177431 | 0.856202 | 5126063 | 0 | 0.0177431 | Model Group:H01:5126062
5126068 | 00 Begane grond | 2323 | 0.428101 | 0.0177431 | 0.856202 | 5126063 | 0 | 0.0177431 | Model Group:H01:5126062
5126074 | 00 Begane grond | 1034 | 0.194792 | 0.00789769 | 0.389584 | 5126072 | 0 | 0.00789769 | Model Group:H01:5126071
5126076 | 00 Begane grond | 2323 | 0.428101 | 0.0177431 | 0.856202 | 5126072 | 0 | 0.0177431 | Model Group:H01:5126071
5126077 | 00 Begane grond | 2323 | 0.428101 | 0.0177431 | 0.856202 | 5126072 | 0 | 0.0177431 | Model Group:H01:5126071
5126988 | 00 Begane grond | 1034 | 0.194792 | 0.00789769 | 0.389584 | 5126986 | 0 | 0.00789769 | Model Group:H02:5126985
5126990 | 00 Begane grond | 2323 | 0.428101 | 0.0177431 | 0.856202 | 5126986 | 0 | 0.0177431 | Model Group:H02:5126985
5126991 | 00 Begane grond | 2323 | 0.428101 | 0.0177431 | 0.856202 | 5126986 | 0 | 0.0177431 | Model Group:H02:5126985
5127343 | 00 Begane grond | 1034 | 0.194792 | 0.00789769 | 0.389584 | 5127341 | 0 | 0.00789769 | Model Group:H01:5127340
5127345 | 00 Begane grond | 2323 | 0.428101 | 0.0177431 | 0.856202 | 5127341 | 0 | 0.0177431 | Model Group:H01:5127340
5127346 | 00 Begane grond | 2323 | 0.428101 | 0.0177431 | 0.856202 | 5127341 | 0 | 0.0177431 | Model Group:H01:5127340
5127585 | 00 Begane grond | 1034 | 0.194792 | 0.00789769 | 0.389584 | 5127583 | 0 | 0.00789769 | Model Group:H01:5127582
5127587 | 00 Begane grond | 2323 | 0.428101 | 0.0177431 | 0.856202 | 5127583 | 0 | 0.0177431 | Model Group:H01:5127582
5127588 | 00 Begane grond | 2323 | 0.428101 | 0.0177431 | 0.856202 | 5127583 | 0 | 0.0177431 | Model Group:H01:5127582
5127596 | 00 Begane grond | 1034 | 0.194792 | 0.00789769 | 0.389584 | 5127594 | 0 | 0.00789769 | Model Group:H01:5127593
5127598 | 00 Begane grond | 2323 | 0.428101 | 0.0177431 | 0.856202 | 5127594 | 0 | 0.0177431 | Model Group:H01:5127593
5127599 | 00 Begane grond | 2323 | 0.428101 | 0.0177431 | 0.856202 | 5127594 | 0 | 0.0177431 | Model Group:H01:5127593
5127607 | 01 eerste verdieping | 1034 | 0.194792 | 0.00789769 | 0.389584 | 5127605 | 1 | 0.00789769 | Model Group:H01:5127604
5127609 | 01 eerste verdieping | 2323 | 0.428101 | 0.0177431 | 0.856202 | 5127605 | 1 | 0.0177431 | Model Group:H01:5127604
5127610 | 01 eerste verdieping | 2323 | 0.428101 | 0.0177431 | 0.856202 | 5127605 | 1 | 0.0177431 | Model Group:H01:5127604
5127618 | 01 eerste verdieping | 1034 | 0.194792 | 0.00789769 | 0.389584 | 5127616 | 1 | 0.00789769 | Model Group:H01:5127615
5127620 | 01 eerste verdieping | 2323 | 0.428101 | 0.0177431 | 0.856202 | 5127616 | 1 | 0.0177431 | Model Group:H01:5127615
5127621 | 01 eerste verdieping | 2323 | 0.428101 | 0.0177431 | 0.856202 | 5127616 | 1 | 0.0177431 | Model Group:H01:5127615
5127629 | 01 eerste verdieping | 1034 | 0.194792 | 0.00789769 | 0.389584 | 5127627 | 1 | 0.00789769 | Model Group:H01:5127626
5127631 | 01 eerste verdieping | 2323 | 0.428101 | 0.0177431 | 0.856202 | 5127627 | 1 | 0.0177431 | Model Group:H01:5127626
5127632 | 01 eerste verdieping | 2323 | 0.428101 | 0.0177431 | 0.856202 | 5127627 | 1 | 0.0177431 | Model Group:H01:5127626
5130147 | 00 Begane grond | 1034 | 0.194792 | 0.00789769 | 0.389584 | 5130145 | 0 | 0.00789769 | Model Group:H02:5130144
5130149 | 00 Begane grond | 2323 | 0.428101 | 0.0177431 | 0.856202 | 5130145 | 0 | 0.0177431 | Model Group:H02:5130144
5130150 | 00 Begane grond | 2323 | 0.428101 | 0.0177431 | 0.856202 | 5130145 | 0 | 0.0177431 | Model Group:H02:5130144
5131936 | 00 Begane grond | 1112 | 0.20891 | 0.00849346 | 0.410182 | 5131934 | 0 | 0.00849346 | Model Group:H03:5131933
5131937 | 00 Begane grond | 246 | 0.052164 | 0.00187895 | 0.104328 | 5131934 | 0 | 0.00187895 | Model Group:H03:5131933
5131938 | 00 Begane grond | 2303 | 0.424481 | 0.0175903 | 0.848962 | 5131934 | 0 | 0.0175903 | Model Group:H03:5131933
5131939 | 00 Begane grond | 2323 | 0.428101 | 0.0177431 | 0.856202 | 5131934 | 0 | 0.0177431 | Model Group:H03:5131933
5131943 | 00 Begane grond | 358 | 0.072436 | 0.0027344 | 0.137234 | 5131934 | 0 | 0.0027344 | Model Group:H03:5131933
5140502 | 00 Begane grond | 1000 | 0.188638 | 0.007638 | 0.369638 | 5140500 | 0 | 0.007638 | Model Group:H20:5488876
5140504 | 00 Begane grond | 2303 | 0.424481 | 0.0175903 | 0.848962 | 5140500 | 0 | 0.0175903 | Model Group:H20:5488876
5140505 | 00 Begane grond | 2303 | 0.424481 | 0.0175903 | 0.848962 | 5140500 | 0 | 0.0175903 | Model Group:H20:5488876
5488427 | 00 Begane grond | 1000 | 0.188638 | 0.007638 | 0.369638 | 5140500 | 0 | 0.007638 | Model Group:H20:5488876
5142282 | 00 Begane grond | 937.5 | 0.177325 | 0.00716062 | 0.347013 | 5142280 | 0 | 0.00716062 | Model Group:H14:5143401
5142284 | 00 Begane grond | 2303 | 0.424481 | 0.0175903 | 0.848962 | 5142280 | 0 | 0.0175903 | Model Group:H14:5143401
5142285 | 00 Begane grond | 2303 | 0.424481 | 0.0175903 | 0.848962 | 5142280 | 0 | 0.0175903 | Model Group:H14:5143401
5142657 | 00 Begane grond | 937.5 | 0.177325 | 0.00716063 | 0.347013 | 5142280 | 0 | 0.00716062 | Model Group:H14:5143401
5143925 | 00 Begane grond | 1060 | 0.199498 | 0.00809628 | 0.391358 | 5143923 | 0 | 0.00809628 | Model Group:H06:5143935
5143927 | 00 Begane grond | 2303 | 0.424481 | 0.0175903 | 0.848962 | 5143923 | 0 | 0.0175903 | Model Group:H06:5143935
5143928 | 00 Begane grond | 2303 | 0.424481 | 0.0175903 | 0.848962 | 5143923 | 0 | 0.0175903 | Model Group:H06:5143935
5143933 | 00 Begane grond | 1060 | 0.199498 | 0.00809628 | 0.391358 | 5143923 | 0 | 0.00809628 | Model Group:H06:5143935
5144106 | 00 Begane grond | 990 | 0.186828 | 0.00756162 | 0.366018 | 5144104 | 0 | 0.00756162 | Model Group:H07:5144116
5144108 | 00 Begane grond | 2303 | 0.424481 | 0.0175903 | 0.848962 | 5144104 | 0 | 0.0175903 | Model Group:H07:5144116
5144109 | 00 Begane grond | 2303 | 0.424481 | 0.0175903 | 0.848962 | 5144104 | 0 | 0.0175903 | Model Group:H07:5144116
5144114 | 00 Begane grond | 990 | 0.186828 | 0.00756162 | 0.366018 | 5144104 | 0 | 0.00756162 | Model Group:H07:5144116
5145173 | 00 Begane grond | 990 | 0.186828 | 0.00756162 | 0.366018 | 5145171 | 0 | 0.00756162 | Model Group:H07:5145183
5145175 | 00 Begane grond | 2303 | 0.424481 | 0.0175903 | 0.848962 | 5145171 | 0 | 0.0175903 | Model Group:H07:5145183
5145176 | 00 Begane grond | 2303 | 0.424481 | 0.0175903 | 0.848962 | 5145171 | 0 | 0.0175903 | Model Group:H07:5145183
5145181 | 00 Begane grond | 990 | 0.186828 | 0.00756162 | 0.366018 | 5145171 | 0 | 0.00756162 | Model Group:H07:5145183
5145323 | 00 Begane grond | 2710 | 0.498148 | 0.020699 | 0.996296 | 5145321 | 0 | 0.020699 | Model Group:H08:5145320
5145324 | 00 Begane grond | 2576 | 0.473894 | 0.0196755 | 0.947788 | 5145321 | 0 | 0.0196755 | Model Group:H08:5145320
5145325 | 00 Begane grond | 533 | 0.104111 | 0.00407105 | 0.208222 | 5145321 | 0 | 0.00407105 | Model Group:H08:5145320
5145326 | 00 Begane grond | 533 | 0.104111 | 0.00407105 | 0.208222 | 5145321 | 0 | 0.00407105 | Model Group:H08:5145320
5145665 | 00 Begane grond | 2710 | 0.498148 | 0.020699 | 0.996296 | 5145663 | 0 | 0.020699 | Model Group:H08:5145662
5145666 | 00 Begane grond | 2576 | 0.473894 | 0.0196755 | 0.947788 | 5145663 | 0 | 0.0196755 | Model Group:H08:5145662
5145667 | 00 Begane grond | 533 | 0.104111 | 0.00407105 | 0.208222 | 5145663 | 0 | 0.00407105 | Model Group:H08:5145662
5145668 | 00 Begane grond | 533 | 0.104111 | 0.00407105 | 0.208222 | 5145663 | 0 | 0.00407105 | Model Group:H08:5145662
5145689 | 00 Begane grond | 2710 | 0.498148 | 0.020699 | 0.996296 | 5145687 | 0 | 0.020699 | Model Group:H08:5145686
5145690 | 00 Begane grond | 2576 | 0.473894 | 0.0196755 | 0.947788 | 5145687 | 0 | 0.0196755 | Model Group:H08:5145686
5145691 | 00 Begane grond | 533 | 0.104111 | 0.00407105 | 0.208222 | 5145687 | 0 | 0.00407105 | Model Group:H08:5145686
5145692 | 00 Begane grond | 533 | 0.104111 | 0.00407105 | 0.208222 | 5145687 | 0 | 0.00407105 | Model Group:H08:5145686
5149163 | 00 Begane grond | 2323 | 0.428101 | 0.0177431 | 0.856202 | 5149166 | 0 | 0.0177431 | Model Group:H09:5145245
5149168 | 00 Begane grond | 1134 | 0.212892 | 0.00866149 | 0.425784 | 5149166 | 0 | 0.00866149 | Model Group:H09:5145245
5149170 | 00 Begane grond | 2323 | 0.428101 | 0.0177431 | 0.856202 | 5149166 | 0 | 0.0177431 | Model Group:H09:5145245
5149208 | 00 Begane grond | 2323 | 0.428101 | 0.0177431 | 0.856202 | 5149210 | 0 | 0.0177431 | Model Group:H09:5145654
5149212 | 00 Begane grond | 1134 | 0.212892 | 0.00866149 | 0.425784 | 5149210 | 0 | 0.00866149 | Model Group:H09:5145654
5149214 | 00 Begane grond | 2323 | 0.428101 | 0.0177431 | 0.856202 | 5149210 | 0 | 0.0177431 | Model Group:H09:5145654
5149216 | 00 Begane grond | 2323 | 0.428101 | 0.0177431 | 0.856202 | 5149218 | 0 | 0.0177431 | Model Group:H09:5145678
5149220 | 00 Begane grond | 1134 | 0.212892 | 0.00866149 | 0.425784 | 5149218 | 0 | 0.00866149 | Model Group:H09:5145678
5149222 | 00 Begane grond | 2323 | 0.428101 | 0.0177431 | 0.856202 | 5149218 | 0 | 0.0177431 | Model Group:H09:5145678
5151842 | 00 Begane grond | 683.75 | 0.131397 | 0.00522248 | 0.255156 | 5151840 | 0 | 0.00522248 | Model Group:H10:5151852
5151843 | 00 Begane grond | 641.25 | 0.123704 | 0.00489787 | 0.247409 | 5151840 | 0 | 0.00489787 | Model Group:H10:5151852
5151844 | 00 Begane grond | 2256 | 0.415974 | 0.0172313 | 0.831948 | 5151840 | 0 | 0.0172313 | Model Group:H10:5151852
5151845 | 00 Begane grond | 2256 | 0.415974 | 0.0172313 | 0.831948 | 5151840 | 0 | 0.0172313 | Model Group:H10:5151852
5151850 | 00 Begane grond | 945 | 0.178683 | 0.00721791 | 0.34209 | 5151840 | 0 | 0.00721791 | Model Group:H10:5151852
5161253 | 00 Begane grond | 686.25 | 0.131849 | 0.00524158 | 0.256061 | 5151840 | 0 | 0.00524158 | Model Group:H10:5151852
5161612 | 00 Begane grond | 945 | 0.178683 | 0.00721791 | 0.34209 | 5151840 | 0 | 0.00721791 | Model Group:H10:5151852
5161613 | 00 Begane grond | 638.75 | 0.123252 | 0.00487877 | 0.246504 | 5151840 | 0 | 0.00487877 | Model Group:H10:5151852
5167021 | 01 eerste verdieping | 2323 | 0.428101 | 0.0177431 | 0.856202 | 5167023 | 1 | 0.0177431 | Model Group:H09:5167012
5167025 | 01 eerste verdieping | 1134 | 0.212892 | 0.00866149 | 0.425784 | 5167023 | 1 | 0.00866149 | Model Group:H09:5167012
5167027 | 01 eerste verdieping | 2323 | 0.428101 | 0.0177431 | 0.856202 | 5167023 | 1 | 0.0177431 | Model Group:H09:5167012
5167162 | 01 eerste verdieping | 2323 | 0.428101 | 0.0177431 | 0.856202 | 5167164 | 1 | 0.0177431 | Model Group:H09:5167153
5167166 | 01 eerste verdieping | 1134 | 0.212892 | 0.00866149 | 0.425784 | 5167164 | 1 | 0.00866149 | Model Group:H09:5167153
5167168 | 01 eerste verdieping | 2323 | 0.428101 | 0.0177431 | 0.856202 | 5167164 | 1 | 0.0177431 | Model Group:H09:5167153
5174068 | 00 Begane grond | 600 | 0.116238 | 0.0045828 | 0.232476 | 5174066 | 0 | 0.0045828 | Model Group:H05:5174065
5174069 | 00 Begane grond | 466 | 0.091984 | 0.00355931 | 0.183968 | 5174066 | 0 | 0.00355931 | Model Group:H05:5174065
5174070 | 00 Begane grond | 1123 | 0.210901 | 0.00857747 | 0.421802 | 5174066 | 0 | 0.00857747 | Model Group:H05:5174065
5174071 | 00 Begane grond | 1123 | 0.210901 | 0.00857747 | 0.421802 | 5174066 | 0 | 0.00857747 | Model Group:H05:5174065
5174268 | 00 Begane grond | 600 | 0.116238 | 0.0045828 | 0.232476 | 5174266 | 0 | 0.0045828 | Model Group:H05:5174265
5174269 | 00 Begane grond | 466 | 0.091984 | 0.00355931 | 0.183968 | 5174266 | 0 | 0.00355931 | Model Group:H05:5174265
5174270 | 00 Begane grond | 1123 | 0.210901 | 0.00857747 | 0.421802 | 5174266 | 0 | 0.00857747 | Model Group:H05:5174265
5174271 | 00 Begane grond | 1123 | 0.210901 | 0.00857747 | 0.421802 | 5174266 | 0 | 0.00857747 | Model Group:H05:5174265
5174288 | 00 Begane grond | 600 | 0.116238 | 0.0045828 | 0.232476 | 5174286 | 0 | 0.0045828 | Model Group:H05:5174285
5174289 | 00 Begane grond | 466 | 0.091984 | 0.00355931 | 0.183968 | 5174286 | 0 | 0.00355931 | Model Group:H05:5174285
5174290 | 00 Begane grond | 1123 | 0.210901 | 0.00857747 | 0.421802 | 5174286 | 0 | 0.00857747 | Model Group:H05:5174285
5174291 | 00 Begane grond | 1123 | 0.210901 | 0.00857747 | 0.421802 | 5174286 | 0 | 0.00857747 | Model Group:H05:5174285
5174298 | 01 eerste verdieping | 600 | 0.116238 | 0.0045828 | 0.232476 | 5174296 | 1 | 0.0045828 | Model Group:H05:5174295
5174299 | 01 eerste verdieping | 466 | 0.091984 | 0.00355931 | 0.183968 | 5174296 | 1 | 0.00355931 | Model Group:H05:5174295
5174300 | 01 eerste verdieping | 1123 | 0.210901 | 0.00857747 | 0.421802 | 5174296 | 1 | 0.00857747 | Model Group:H05:5174295
5174301 | 01 eerste verdieping | 1123 | 0.210901 | 0.00857747 | 0.421802 | 5174296 | 1 | 0.00857747 | Model Group:H05:5174295
5174308 | 01 eerste verdieping | 600 | 0.116238 | 0.0045828 | 0.232476 | 5174306 | 1 | 0.0045828 | Model Group:H05:5174305
5174309 | 01 eerste verdieping | 466 | 0.091984 | 0.00355931 | 0.183968 | 5174306 | 1 | 0.00355931 | Model Group:H05:5174305
5174310 | 01 eerste verdieping | 1123 | 0.210901 | 0.00857747 | 0.421802 | 5174306 | 1 | 0.00857747 | Model Group:H05:5174305
5174311 | 01 eerste verdieping | 1123 | 0.210901 | 0.00857747 | 0.421802 | 5174306 | 1 | 0.00857747 | Model Group:H05:5174305
5174318 | 01 eerste verdieping | 600 | 0.116238 | 0.0045828 | 0.232476 | 5174316 | 1 | 0.0045828 | Model Group:H05:5174315
5174319 | 01 eerste verdieping | 466 | 0.091984 | 0.00355931 | 0.183968 | 5174316 | 1 | 0.00355931 | Model Group:H05:5174315
5174320 | 01 eerste verdieping | 1123 | 0.210901 | 0.00857747 | 0.421802 | 5174316 | 1 | 0.00857747 | Model Group:H05:5174315
5174321 | 01 eerste verdieping | 1123 | 0.210901 | 0.00857747 | 0.421802 | 5174316 | 1 | 0.00857747 | Model Group:H05:5174315
5174552 | 01 eerste verdieping | 1034 | 0.194792 | 0.00789769 | 0.389584 | 5174550 | 1 | 0.00789769 | Model Group:H01:5174549
5174554 | 01 eerste verdieping | 2323 | 0.428101 | 0.0177431 | 0.856202 | 5174550 | 1 | 0.0177431 | Model Group:H01:5174549
5174555 | 01 eerste verdieping | 2323 | 0.428101 | 0.0177431 | 0.856202 | 5174550 | 1 | 0.0177431 | Model Group:H01:5174549
5174564 | 01 eerste verdieping | 600 | 0.116238 | 0.0045828 | 0.232476 | 5174562 | 1 | 0.0045828 | Model Group:H05:5174561
5174565 | 01 eerste verdieping | 466 | 0.091984 | 0.00355931 | 0.183968 | 5174562 | 1 | 0.00355931 | Model Group:H05:5174561
5174566 | 01 eerste verdieping | 1123 | 0.210901 | 0.00857747 | 0.421802 | 5174562 | 1 | 0.00857747 | Model Group:H05:5174561
5174567 | 01 eerste verdieping | 1123 | 0.210901 | 0.00857747 | 0.421802 | 5174562 | 1 | 0.00857747 | Model Group:H05:5174561
5174892 | 01 eerste verdieping | 2323 | 0.428101 | 0.0177431 | 0.856202 | 5174894 | 1 | 0.0177431 | Model Group:H09:5174883
5174896 | 01 eerste verdieping | 1134 | 0.212892 | 0.00866149 | 0.425784 | 5174894 | 1 | 0.00866149 | Model Group:H09:5174883
5174898 | 01 eerste verdieping | 2323 | 0.428101 | 0.0177431 | 0.856202 | 5174894 | 1 | 0.0177431 | Model Group:H09:5174883
5178254 | 01 eerste verdieping | 600 | 0.116238 | 0.0045828 | 0.232476 | 5178252 | 1 | 0.0045828 | Model Group:H05:5178251
5178255 | 01 eerste verdieping | 466 | 0.091984 | 0.00355931 | 0.183968 | 5178252 | 1 | 0.00355931 | Model Group:H05:5178251
5178256 | 01 eerste verdieping | 1123 | 0.210901 | 0.00857747 | 0.421802 | 5178252 | 1 | 0.00857747 | Model Group:H05:5178251
5178257 | 01 eerste verdieping | 1123 | 0.210901 | 0.00857747 | 0.421802 | 5178252 | 1 | 0.00857747 | Model Group:H05:5178251
5179824 | 01 eerste verdieping | 1112 | 0.20891 | 0.00849346 | 0.410182 | 5179822 | 1 | 0.00849346 | Model Group:H03:5179821
5179825 | 01 eerste verdieping | 246 | 0.052164 | 0.00187895 | 0.104328 | 5179822 | 1 | 0.00187895 | Model Group:H03:5179821
5179826 | 01 eerste verdieping | 2303 | 0.424481 | 0.0175903 | 0.848962 | 5179822 | 1 | 0.0175903 | Model Group:H03:5179821
5179827 | 01 eerste verdieping | 2323 | 0.428101 | 0.0177431 | 0.856202 | 5179822 | 1 | 0.0177431 | Model Group:H03:5179821
5179831 | 01 eerste verdieping | 358 | 0.072436 | 0.0027344 | 0.137234 | 5179822 | 1 | 0.0027344 | Model Group:H03:5179821
5181882 | 01 eerste verdieping | 2710 | 0.498148 | 0.020699 | 0.996296 | 5181880 | 1 | 0.020699 | Model Group:H08:5181879
5181883 | 01 eerste verdieping | 2576 | 0.473894 | 0.0196755 | 0.947788 | 5181880 | 1 | 0.0196755 | Model Group:H08:5181879
5181884 | 01 eerste verdieping | 533 | 0.104111 | 0.00407105 | 0.208222 | 5181880 | 1 | 0.00407105 | Model Group:H08:5181879
5181885 | 01 eerste verdieping | 533 | 0.104111 | 0.00407105 | 0.208222 | 5181880 | 1 | 0.00407105 | Model Group:H08:5181879
5181896 | 01 eerste verdieping | 2323 | 0.428101 | 0.0177431 | 0.856202 | 5181898 | 1 | 0.0177431 | Model Group:H09:5181878
5181900 | 01 eerste verdieping | 1134 | 0.212892 | 0.00866149 | 0.425784 | 5181898 | 1 | 0.00866149 | Model Group:H09:5181878
5181902 | 01 eerste verdieping | 2323 | 0.428101 | 0.0177431 | 0.856202 | 5181898 | 1 | 0.0177431 | Model Group:H09:5181878
5184341 | 01 eerste verdieping | 2710 | 0.498148 | 0.020699 | 0.996296 | 5184339 | 1 | 0.020699 | Model Group:H08:5184338
5184342 | 01 eerste verdieping | 2576 | 0.473894 | 0.0196755 | 0.947788 | 5184339 | 1 | 0.0196755 | Model Group:H08:5184338
5184343 | 01 eerste verdieping | 533 | 0.104111 | 0.00407105 | 0.208222 | 5184339 | 1 | 0.00407105 | Model Group:H08:5184338
5184344 | 01 eerste verdieping | 533 | 0.104111 | 0.00407105 | 0.208222 | 5184339 | 1 | 0.00407105 | Model Group:H08:5184338
5184355 | 01 eerste verdieping | 2323 | 0.428101 | 0.0177431 | 0.856202 | 5184357 | 1 | 0.0177431 | Model Group:H09:5184337
5184359 | 01 eerste verdieping | 1134 | 0.212892 | 0.00866149 | 0.425784 | 5184357 | 1 | 0.00866149 | Model Group:H09:5184337
5184361 | 01 eerste verdieping | 2323 | 0.428101 | 0.0177431 | 0.856202 | 5184357 | 1 | 0.0177431 | Model Group:H09:5184337
5184390 | 01 eerste verdieping | 2710 | 0.498148 | 0.020699 | 0.996296 | 5184388 | 1 | 0.020699 | Model Group:H08:5184387
5184391 | 01 eerste verdieping | 2576 | 0.473894 | 0.0196755 | 0.947788 | 5184388 | 1 | 0.0196755 | Model Group:H08:5184387
5184392 | 01 eerste verdieping | 533 | 0.104111 | 0.00407105 | 0.208222 | 5184388 | 1 | 0.00407105 | Model Group:H08:5184387
5184393 | 01 eerste verdieping | 533 | 0.104111 | 0.00407105 | 0.208222 | 5184388 | 1 | 0.00407105 | Model Group:H08:5184387
5184404 | 01 eerste verdieping | 2323 | 0.428101 | 0.0177431 | 0.856202 | 5184406 | 1 | 0.0177431 | Model Group:H09:5184386
5184408 | 01 eerste verdieping | 1134 | 0.212892 | 0.00866149 | 0.425784 | 5184406 | 1 | 0.00866149 | Model Group:H09:5184386
5184410 | 01 eerste verdieping | 2323 | 0.428101 | 0.0177431 | 0.856202 | 5184406 | 1 | 0.0177431 | Model Group:H09:5184386
5185194 | 01 eerste verdieping | 2205 | 0.406743 | 0.0168418 | 0.813486 | 5185192 | 1 | 0.0168418 | Model Group:H13:5167154
5185195 | 01 eerste verdieping | 2071 | 0.382489 | 0.0158183 | 0.764978 | 5185192 | 1 | 0.0158183 | Model Group:H13:5167154
5185196 | 01 eerste verdieping | 533 | 0.104111 | 0.00407105 | 0.208222 | 5185192 | 1 | 0.00407105 | Model Group:H13:5167154
5185197 | 01 eerste verdieping | 533 | 0.104111 | 0.00407105 | 0.208222 | 5185192 | 1 | 0.00407105 | Model Group:H13:5167154
5185257 | 01 eerste verdieping | 2205 | 0.406743 | 0.0168418 | 0.813486 | 5185255 | 1 | 0.0168418 | Model Group:H13:5167013
5185258 | 01 eerste verdieping | 2071 | 0.382489 | 0.0158183 | 0.764978 | 5185255 | 1 | 0.0158183 | Model Group:H13:5167013
5185259 | 01 eerste verdieping | 533 | 0.104111 | 0.00407105 | 0.208222 | 5185255 | 1 | 0.00407105 | Model Group:H13:5167013
5185260 | 01 eerste verdieping | 533 | 0.104111 | 0.00407105 | 0.208222 | 5185255 | 1 | 0.00407105 | Model Group:H13:5167013
5185265 | 01 eerste verdieping | 2205 | 0.406743 | 0.0168418 | 0.813486 | 5185263 | 1 | 0.0168418 | Model Group:H13:5174884
5185266 | 01 eerste verdieping | 2071 | 0.382489 | 0.0158183 | 0.764978 | 5185263 | 1 | 0.0158183 | Model Group:H13:5174884
5185267 | 01 eerste verdieping | 533 | 0.104111 | 0.00407105 | 0.208222 | 5185263 | 1 | 0.00407105 | Model Group:H13:5174884
5185268 | 01 eerste verdieping | 533 | 0.104111 | 0.00407105 | 0.208222 | 5185263 | 1 | 0.00407105 | Model Group:H13:5174884
5185279 | 01 eerste verdieping | 2205 | 0.406743 | 0.0168418 | 0.813486 | 5185277 | 1 | 0.0168418 | Model Group:H13:5184708
5185280 | 01 eerste verdieping | 2071 | 0.382489 | 0.0158183 | 0.764978 | 5185277 | 1 | 0.0158183 | Model Group:H13:5184708
5185281 | 01 eerste verdieping | 533 | 0.104111 | 0.00407105 | 0.208222 | 5185277 | 1 | 0.00407105 | Model Group:H13:5184708
5185282 | 01 eerste verdieping | 533 | 0.104111 | 0.00407105 | 0.208222 | 5185277 | 1 | 0.00407105 | Model Group:H13:5184708
5185372 | 01 eerste verdieping | 600 | 0.116238 | 0.0045828 | 0.232476 | 5185370 | 1 | 0.0045828 | Model Group:H05:5185369
5185373 | 01 eerste verdieping | 466 | 0.091984 | 0.00355931 | 0.183968 | 5185370 | 1 | 0.00355931 | Model Group:H05:5185369
5185374 | 01 eerste verdieping | 1123 | 0.210901 | 0.00857747 | 0.421802 | 5185370 | 1 | 0.00857747 | Model Group:H05:5185369
5185375 | 01 eerste verdieping | 1123 | 0.210901 | 0.00857747 | 0.421802 | 5185370 | 1 | 0.00857747 | Model Group:H05:5185369
5185413 | 01 eerste verdieping | 600 | 0.116238 | 0.0045828 | 0.232476 | 5185411 | 1 | 0.0045828 | Model Group:H05:5185410
5185414 | 01 eerste verdieping | 466 | 0.091984 | 0.00355931 | 0.183968 | 5185411 | 1 | 0.00355931 | Model Group:H05:5185410
5185415 | 01 eerste verdieping | 1123 | 0.210901 | 0.00857747 | 0.421802 | 5185411 | 1 | 0.00857747 | Model Group:H05:5185410
5185416 | 01 eerste verdieping | 1123 | 0.210901 | 0.00857747 | 0.421802 | 5185411 | 1 | 0.00857747 | Model Group:H05:5185410
5185794 | 01 eerste verdieping | 1112 | 0.20891 | 0.00849346 | 0.410182 | 5185792 | 1 | 0.00849346 | Model Group:H18:5185791
5185795 | 01 eerste verdieping | 443 | 0.087821 | 0.00338363 | 0.175642 | 5185792 | 1 | 0.00338363 | Model Group:H18:5185791
5185796 | 01 eerste verdieping | 2303 | 0.424481 | 0.0175903 | 0.848962 | 5185792 | 1 | 0.0175903 | Model Group:H18:5185791
5185797 | 01 eerste verdieping | 2256 | 0.415974 | 0.0172313 | 0.831948 | 5185792 | 1 | 0.0172313 | Model Group:H18:5185791
5185801 | 01 eerste verdieping | 488 | 0.095966 | 0.00372734 | 0.184294 | 5185792 | 1 | 0.00372734 | Model Group:H18:5185791
5194904 | 01 eerste verdieping | 626.75 | 0.12108 | 0.00478712 | 0.234521 | 5194902 | 1 | 0.00478712 | Model Group:H12:5194912
5194905 | 01 eerste verdieping | 574.25 | 0.111577 | 0.00438612 | 0.223155 | 5194902 | 1 | 0.00438612 | Model Group:H12:5194912
5194906 | 01 eerste verdieping | 2301 | 0.424119 | 0.017575 | 0.8406 | 5194902 | 1 | 0.017575 | Model Group:H12:5194912
5194907 | 01 eerste verdieping | 755 | 0.144293 | 0.00576669 | 0.280948 | 5194902 | 1 | 0.00576669 | Model Group:H12:5194912
5194910 | 01 eerste verdieping | 948.75 | 0.179362 | 0.00724655 | 0.343447 | 5194902 | 1 | 0.00724655 | Model Group:H12:5194912
5194918 | 01 eerste verdieping | 686.25 | 0.131849 | 0.00524158 | 0.256061 | 5194902 | 1 | 0.00524158 | Model Group:H12:5194912
5194924 | 01 eerste verdieping | 941.25 | 0.178004 | 0.00718927 | 0.340733 | 5194902 | 1 | 0.00718927 | Model Group:H12:5194912
5194925 | 01 eerste verdieping | 648.75 | 0.125062 | 0.00495515 | 0.250123 | 5194902 | 1 | 0.00495515 | Model Group:H12:5194912
5194938 | 01 eerste verdieping | 822 | 0.15642 | 0.00627844 | 0.305202 | 5194902 | 1 | 0.00627844 | Model Group:H12:5194912
5194939 | 01 eerste verdieping | 2368 | 0.436246 | 0.0180868 | 0.864854 | 5194902 | 1 | 0.0180868 | Model Group:H12:5194912
5196982 | 00 Begane grond | 1123 | 0.210901 | 0.00857747 | 0.421802 | 5196985 | 0 | 0.00857747 | Model Group:H05:5196983
5196987 | 00 Begane grond | 600 | 0.116238 | 0.0045828 | 0.232476 | 5196985 | 0 | 0.0045828 | Model Group:H05:5196983
5196988 | 00 Begane grond | 466 | 0.091984 | 0.00355931 | 0.183968 | 5196985 | 0 | 0.00355931 | Model Group:H05:5196983
5196989 | 00 Begane grond | 1123 | 0.210901 | 0.00857747 | 0.421802 | 5196985 | 0 | 0.00857747 | Model Group:H05:5196983
5197460 | 00 Begane grond | 1123 | 0.210901 | 0.00857747 | 0.421802 | 5197462 | 0 | 0.00857747 | Model Group:H05:5197461
5197464 | 00 Begane grond | 600 | 0.116238 | 0.0045828 | 0.232476 | 5197462 | 0 | 0.0045828 | Model Group:H05:5197461
5197465 | 00 Begane grond | 466 | 0.091984 | 0.00355931 | 0.183968 | 5197462 | 0 | 0.00355931 | Model Group:H05:5197461
5197466 | 00 Begane grond | 1123 | 0.210901 | 0.00857747 | 0.421802 | 5197462 | 0 | 0.00857747 | Model Group:H05:5197461
5197620 | 00 Begane grond | 1123 | 0.210901 | 0.00857747 | 0.421802 | 5197622 | 0 | 0.00857747 | Model Group:H05:5197621
5197624 | 00 Begane grond | 600 | 0.116238 | 0.0045828 | 0.232476 | 5197622 | 0 | 0.0045828 | Model Group:H05:5197621
5197625 | 00 Begane grond | 466 | 0.091984 | 0.00355931 | 0.183968 | 5197622 | 0 | 0.00355931 | Model Group:H05:5197621
5197626 | 00 Begane grond | 1123 | 0.210901 | 0.00857747 | 0.421802 | 5197622 | 0 | 0.00857747 | Model Group:H05:5197621
5202332 | 00 Begane grond | 1034 | 0.194792 | 0.00789769 | 0.389584 | 5202330 | 0 | 0.00789769 | Model Group:H02:5127227
5202334 | 00 Begane grond | 2323 | 0.428101 | 0.0177431 | 0.856202 | 5202330 | 0 | 0.0177431 | Model Group:H02:5127227
5202335 | 00 Begane grond | 2323 | 0.428101 | 0.0177431 | 0.856202 | 5202330 | 0 | 0.0177431 | Model Group:H02:5127227
5203605 | 00 Begane grond | 2710 | 0.498148 | 0.020699 | 0.996296 | 5203603 | 0 | 0.020699 | Model Group:H08:5203602
5203606 | 00 Begane grond | 2576 | 0.473894 | 0.0196755 | 0.947788 | 5203603 | 0 | 0.0196755 | Model Group:H08:5203602
5203607 | 00 Begane grond | 533 | 0.104111 | 0.00407105 | 0.208222 | 5203603 | 0 | 0.00407105 | Model Group:H08:5203602
5203608 | 00 Begane grond | 533 | 0.104111 | 0.00407105 | 0.208222 | 5203603 | 0 | 0.00407105 | Model Group:H08:5203602
5203619 | 00 Begane grond | 2323 | 0.428101 | 0.0177431 | 0.856202 | 5203621 | 0 | 0.0177431 | Model Group:H09:5203601
5203623 | 00 Begane grond | 1134 | 0.212892 | 0.00866149 | 0.425784 | 5203621 | 0 | 0.00866149 | Model Group:H09:5203601
5203625 | 00 Begane grond | 2323 | 0.428101 | 0.0177431 | 0.856202 | 5203621 | 0 | 0.0177431 | Model Group:H09:5203601
5206509 | 00 Begane grond | 1034 | 0.194792 | 0.00789769 | 0.389584 | 5206507 | 0 | 0.00789769 | Model Group:H02:5206506
5206511 | 00 Begane grond | 2323 | 0.428101 | 0.0177431 | 0.856202 | 5206507 | 0 | 0.0177431 | Model Group:H02:5206506
5206512 | 00 Begane grond | 2323 | 0.428101 | 0.0177431 | 0.856202 | 5206507 | 0 | 0.0177431 | Model Group:H02:5206506
5206886 | 00 Begane grond | 2323 | 0.428101 | 0.0177431 | 0.856202 | 5206888 | 0 | 0.0177431 | Model Group:H09:5206741
5206890 | 00 Begane grond | 1134 | 0.212892 | 0.00866149 | 0.425784 | 5206888 | 0 | 0.00866149 | Model Group:H09:5206741
5206892 | 00 Begane grond | 2323 | 0.428101 | 0.0177431 | 0.856202 | 5206888 | 0 | 0.0177431 | Model Group:H09:5206741
5227228 | 01 eerste verdieping | 990 | 0.186828 | 0.00756162 | 0.366018 | 5227226 | 1 | 0.00756162 | Model Group:H07:5227238
5227230 | 01 eerste verdieping | 2303 | 0.424481 | 0.0175903 | 0.848962 | 5227226 | 1 | 0.0175903 | Model Group:H07:5227238
5227231 | 01 eerste verdieping | 2303 | 0.424481 | 0.0175903 | 0.848962 | 5227226 | 1 | 0.0175903 | Model Group:H07:5227238
5227236 | 01 eerste verdieping | 990 | 0.186828 | 0.00756162 | 0.366018 | 5227226 | 1 | 0.00756162 | Model Group:H07:5227238
5227247 | 01 eerste verdieping | 1034 | 0.194792 | 0.00789769 | 0.389584 | 5227245 | 1 | 0.00789769 | Model Group:H16:5227244
5227249 | 01 eerste verdieping | 2323 | 0.428101 | 0.0177431 | 0.856202 | 5227245 | 1 | 0.0177431 | Model Group:H16:5227244
5227250 | 01 eerste verdieping | 2323 | 0.428101 | 0.0177431 | 0.856202 | 5227245 | 1 | 0.0177431 | Model Group:H16:5227244
5227254 | 01 eerste verdieping | 990 | 0.186828 | 0.00756162 | 0.366018 | 5227252 | 1 | 0.00756162 | Model Group:H07:5227264
5227256 | 01 eerste verdieping | 2303 | 0.424481 | 0.0175903 | 0.848962 | 5227252 | 1 | 0.0175903 | Model Group:H07:5227264
5227257 | 01 eerste verdieping | 2303 | 0.424481 | 0.0175903 | 0.848962 | 5227252 | 1 | 0.0175903 | Model Group:H07:5227264
5227262 | 01 eerste verdieping | 990 | 0.186828 | 0.00756162 | 0.366018 | 5227252 | 1 | 0.00756162 | Model Group:H07:5227264
5259384 | 00 Begane grond | 1123 | 0.210901 | 0.00857747 | 0.421802 | 5259387 | 0 | 0.00857747 | Model Group:H17:5259385
5259389 | 00 Begane grond | 550 | 0.107188 | 0.0042009 | 0.214376 | 5259387 | 0 | 0.0042009 | Model Group:H17:5259385
5259390 | 00 Begane grond | 416 | 0.082934 | 0.00317741 | 0.165868 | 5259387 | 0 | 0.00317741 | Model Group:H17:5259385
5259391 | 00 Begane grond | 1123 | 0.210901 | 0.00857747 | 0.421802 | 5259387 | 0 | 0.00857747 | Model Group:H17:5259385
5270213 | 00 Begane grond | 2400 | 0.442038 | 0.0183312 | 0.884076 | 5270211 | 0 | 0.0183312 | Model Group:H15:5270210
5270214 | 00 Begane grond | 2266 | 0.417784 | 0.0173077 | 0.835568 | 5270211 | 0 | 0.0173077 | Model Group:H15:5270210
5270215 | 00 Begane grond | 533 | 0.104111 | 0.00407105 | 0.208222 | 5270211 | 0 | 0.00407105 | Model Group:H15:5270210
5270216 | 00 Begane grond | 533 | 0.104111 | 0.00407105 | 0.208222 | 5270211 | 0 | 0.00407105 | Model Group:H15:5270210
5271081 | 00 Begane grond | 2400 | 0.442038 | 0.0183312 | 0.884076 | 5271079 | 0 | 0.0183312 | Model Group:H15:5271078
5271082 | 00 Begane grond | 2266 | 0.417784 | 0.0173077 | 0.835568 | 5271079 | 0 | 0.0173077 | Model Group:H15:5271078
5271083 | 00 Begane grond | 533 | 0.104111 | 0.00407105 | 0.208222 | 5271079 | 0 | 0.00407105 | Model Group:H15:5271078
5271084 | 00 Begane grond | 533 | 0.104111 | 0.00407105 | 0.208222 | 5271079 | 0 | 0.00407105 | Model Group:H15:5271078
5274119 | 01 eerste verdieping | 2205 | 0.406743 | 0.0168418 | 0.813486 | 5274117 | 1 | 0.0168418 | Model Group:H13:5274116
5274120 | 01 eerste verdieping | 2071 | 0.382489 | 0.0158183 | 0.764978 | 5274117 | 1 | 0.0158183 | Model Group:H13:5274116
5274121 | 01 eerste verdieping | 533 | 0.104111 | 0.00407105 | 0.208222 | 5274117 | 1 | 0.00407105 | Model Group:H13:5274116
5274122 | 01 eerste verdieping | 533 | 0.104111 | 0.00407105 | 0.208222 | 5274117 | 1 | 0.00407105 | Model Group:H13:5274116
5276455 | 00 Begane grond | 1034 | 0.194792 | 0.00789769 | 0.389584 | 5276453 | 0 | 0.00789769 | Model Group:H16:5197611
5276457 | 00 Begane grond | 2323 | 0.428101 | 0.0177431 | 0.856202 | 5276453 | 0 | 0.0177431 | Model Group:H16:5197611
5276458 | 00 Begane grond | 2323 | 0.428101 | 0.0177431 | 0.856202 | 5276453 | 0 | 0.0177431 | Model Group:H16:5197611
5276562 | 00 Begane grond | 1034 | 0.194792 | 0.00789769 | 0.389584 | 5276560 | 0 | 0.00789769 | Model Group:H16:5195722
5276564 | 00 Begane grond | 2323 | 0.428101 | 0.0177431 | 0.856202 | 5276560 | 0 | 0.0177431 | Model Group:H16:5195722
5276565 | 00 Begane grond | 2323 | 0.428101 | 0.0177431 | 0.856202 | 5276560 | 0 | 0.0177431 | Model Group:H16:5195722
5276571 | 00 Begane grond | 1034 | 0.194792 | 0.00789769 | 0.389584 | 5276569 | 0 | 0.00789769 | Model Group:H16:5197451
5276573 | 00 Begane grond | 2323 | 0.428101 | 0.0177431 | 0.856202 | 5276569 | 0 | 0.0177431 | Model Group:H16:5197451
5276574 | 00 Begane grond | 2323 | 0.428101 | 0.0177431 | 0.856202 | 5276569 | 0 | 0.0177431 | Model Group:H16:5197451
5277203 | 01 eerste verdieping | 1034 | 0.194792 | 0.00789769 | 0.389584 | 5277201 | 1 | 0.00789769 | Model Group:H01:5174800
5277205 | 01 eerste verdieping | 2323 | 0.428101 | 0.0177431 | 0.856202 | 5277201 | 1 | 0.0177431 | Model Group:H01:5174800
5277206 | 01 eerste verdieping | 2323 | 0.428101 | 0.0177431 | 0.856202 | 5277201 | 1 | 0.0177431 | Model Group:H01:5174800
5277239 | 01 eerste verdieping | 1034 | 0.194792 | 0.00789769 | 0.389584 | 5277237 | 1 | 0.00789769 | Model Group:H01:5174841
5277241 | 01 eerste verdieping | 2323 | 0.428101 | 0.0177431 | 0.856202 | 5277237 | 1 | 0.0177431 | Model Group:H01:5174841
5277242 | 01 eerste verdieping | 2323 | 0.428101 | 0.0177431 | 0.856202 | 5277237 | 1 | 0.0177431 | Model Group:H01:5174841
5465830 | 00 Begane grond | 1112 | 0.20891 | 0.00849346 | 0.410182 | 5465828 | 0 | 0.00849346 | Model Group:H03:5465827
5465831 | 00 Begane grond | 246 | 0.052164 | 0.00187895 | 0.104328 | 5465828 | 0 | 0.00187895 | Model Group:H03:5465827
5465832 | 00 Begane grond | 2303 | 0.424481 | 0.0175903 | 0.848962 | 5465828 | 0 | 0.0175903 | Model Group:H03:5465827
5465833 | 00 Begane grond | 2323 | 0.428101 | 0.0177431 | 0.856202 | 5465828 | 0 | 0.0177431 | Model Group:H03:5465827
5465837 | 00 Begane grond | 358 | 0.072436 | 0.0027344 | 0.137234 | 5465828 | 0 | 0.0027344 | Model Group:H03:5465827
5533684 | 01 eerste verdieping | 1034 | 0.194792 | 0.00789769 | 0.389584 | 5533682 | 1 | 0.00789769 | Model Group:H02:5533681
5533686 | 01 eerste verdieping | 2323 | 0.428101 | 0.0177431 | 0.856202 | 5533682 | 1 | 0.0177431 | Model Group:H02:5533681
5533687 | 01 eerste verdieping | 2323 | 0.428101 | 0.0177431 | 0.856202 | 5533682 | 1 | 0.0177431 | Model Group:H02:5533681
5533691 | 01 eerste verdieping | 473 | 0.093251 | 0.00361277 | 0.178864 | 5533689 | 1 | 0.00361277 | Model Group:H11:5533699
5533692 | 01 eerste verdieping | 428 | 0.085106 | 0.00326906 | 0.170212 | 5533689 | 1 | 0.00326906 | Model Group:H11:5533699
5533693 | 01 eerste verdieping | 2301 | 0.424119 | 0.017575 | 0.8406 | 5533689 | 1 | 0.017575 | Model Group:H11:5533699
5533694 | 01 eerste verdieping | 755 | 0.144293 | 0.00576669 | 0.280948 | 5533689 | 1 | 0.00576669 | Model Group:H11:5533699
5533697 | 01 eerste verdieping | 945 | 0.178683 | 0.00721791 | 0.34209 | 5533689 | 1 | 0.00721791 | Model Group:H11:5533699
5533705 | 01 eerste verdieping | 540 | 0.105378 | 0.00412452 | 0.203118 | 5533689 | 1 | 0.00412452 | Model Group:H11:5533699
5533711 | 01 eerste verdieping | 945 | 0.178683 | 0.00721791 | 0.34209 | 5533689 | 1 | 0.00721791 | Model Group:H11:5533699
5533712 | 01 eerste verdieping | 495 | 0.097233 | 0.00378081 | 0.194466 | 5533689 | 1 | 0.00378081 | Model Group:H11:5533699
5533725 | 01 eerste verdieping | 822 | 0.15642 | 0.00627844 | 0.305202 | 5533689 | 1 | 0.00627844 | Model Group:H11:5533699
5533726 | 01 eerste verdieping | 2368 | 0.436246 | 0.0180868 | 0.864854 | 5533689 | 1 | 0.0180868 | Model Group:H11:5533699
5987151 | 01 eerste verdieping | 1034 | 0.194792 | 0.00789769 | 0.389584 | 5987149 | 1 | 0.00789769 | Model Group:H02:5987148
5987153 | 01 eerste verdieping | 2323 | 0.428101 | 0.0177431 | 0.856202 | 5987149 | 1 | 0.0177431 | Model Group:H02:5987148
5987154 | 01 eerste verdieping | 2323 | 0.428101 | 0.0177431 | 0.856202 | 5987149 | 1 | 0.0177431 | Model Group:H02:5987148
5987397 | 01 eerste verdieping | 1034 | 0.194792 | 0.00789769 | 0.389584 | 5987395 | 1 | 0.00789769 | Model Group:H02:5987394
5987399 | 01 eerste verdieping | 2323 | 0.428101 | 0.0177431 | 0.856202 | 5987395 | 1 | 0.0177431 | Model Group:H02:5987394
5987400 | 01 eerste verdieping | 2323 | 0.428101 | 0.0177431 | 0.856202 | 5987395 | 1 | 0.0177431 | Model Group:H02:5987394
5987405 | 01 eerste verdieping | 1034 | 0.194792 | 0.00789769 | 0.389584 | 5987403 | 1 | 0.00789769 | Model Group:H02:5987402
5987407 | 01 eerste verdieping | 2323 | 0.428101 | 0.0177431 | 0.856202 | 5987403 | 1 | 0.0177431 | Model Group:H02:5987402
5987408 | 01 eerste verdieping | 2323 | 0.428101 | 0.0177431 | 0.856202 | 5987403 | 1 | 0.0177431 | Model Group:H02:5987402
5988147 | 01 eerste verdieping | 2323 | 0.428101 | 0.0177431 | 0.856202 | 5988148 | 1 | 0.0177431 | Model Group:H09:5988145
5988150 | 01 eerste verdieping | 1134 | 0.212892 | 0.00866149 | 0.425784 | 5988148 | 1 | 0.00866149 | Model Group:H09:5988145
5988152 | 01 eerste verdieping | 2323 | 0.428101 | 0.0177431 | 0.856202 | 5988148 | 1 | 0.0177431 | Model Group:H09:5988145
5988166 | 01 eerste verdieping | 2205 | 0.406743 | 0.0168418 | 0.813486 | 5988164 | 1 | 0.0168418 | Model Group:H13:5988146
5988167 | 01 eerste verdieping | 2071 | 0.382489 | 0.0158183 | 0.764978 | 5988164 | 1 | 0.0158183 | Model Group:H13:5988146
5988168 | 01 eerste verdieping | 533 | 0.104111 | 0.00407105 | 0.208222 | 5988164 | 1 | 0.00407105 | Model Group:H13:5988146
5988169 | 01 eerste verdieping | 533 | 0.104111 | 0.00407105 | 0.208222 | 5988164 | 1 | 0.00407105 | Model Group:H13:5988146
5994927 | 01 eerste verdieping | 1034 | 0.194792 | 0.00789769 | 0.389584 | 5994925 | 1 | 0.00789769 | Model Group:H01:5994924
5994929 | 01 eerste verdieping | 2323 | 0.428101 | 0.0177431 | 0.856202 | 5994925 | 1 | 0.0177431 | Model Group:H01:5994924
5994930 | 01 eerste verdieping | 2323 | 0.428101 | 0.0177431 | 0.856202 | 5994925 | 1 | 0.0177431 | Model Group:H01:5994924
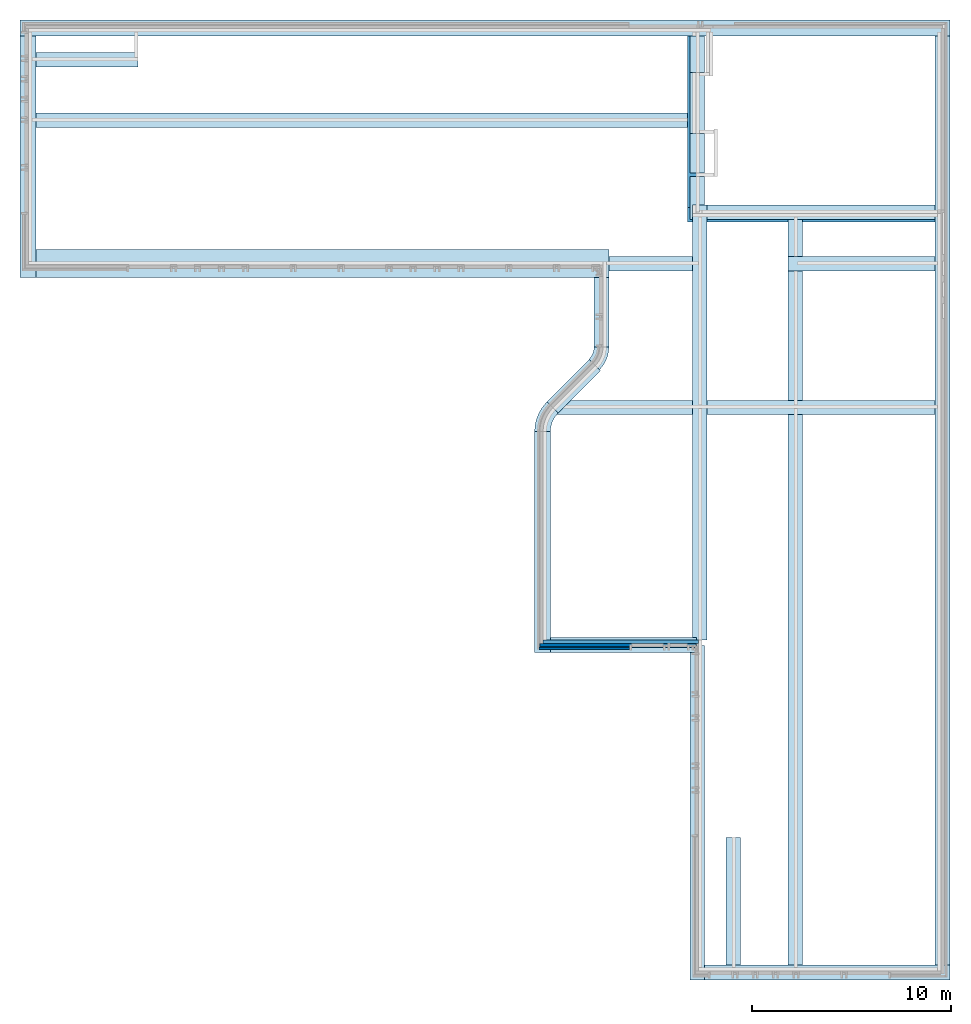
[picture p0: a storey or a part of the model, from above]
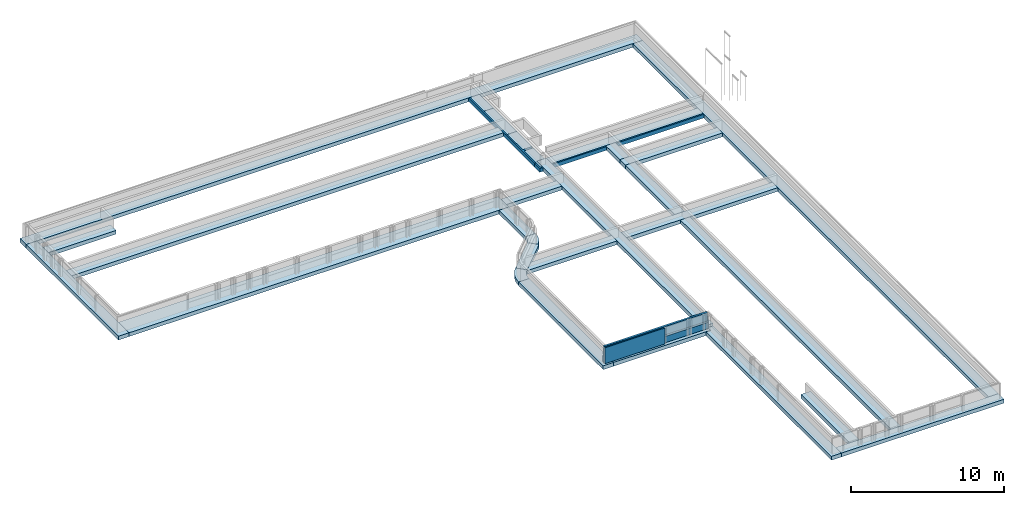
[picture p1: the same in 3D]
Properties of the parts of a building model (IFC2X3), part 20 of 37

# IfcMember: Rectangular Mullion:31_CWM_067x114 (379)
Name (Rectangular Mullion:31_CWM_067x114:...) | In | Span (mm) = BaseQuantities, Length (mm) = Dimensions, Length (mm) | CrossSectionArea (m2) = Area (m2) | NetVolume (m3) | NetSurfaceArea (m2) | Host Id | Level | Volume (m3) | Group
5994937 | 01 eerste verdieping | 600 | 0.116238 | 0.0045828 | 0.232476 | 5994935 | 1 | 0.0045828 | Model Group:H05:5994934
5994938 | 01 eerste verdieping | 466 | 0.091984 | 0.00355931 | 0.183968 | 5994935 | 1 | 0.00355931 | Model Group:H05:5994934
5994939 | 01 eerste verdieping | 1123 | 0.210901 | 0.00857747 | 0.421802 | 5994935 | 1 | 0.00857747 | Model Group:H05:5994934
5994940 | 01 eerste verdieping | 1123 | 0.210901 | 0.00857747 | 0.421802 | 5994935 | 1 | 0.00857747 | Model Group:H05:5994934
5995273 | 01 eerste verdieping | 990 | 0.186828 | 0.00756162 | 0.366018 | 5995271 | 1 | 0.00756162 | Model Group:H07:5995281
5995275 | 01 eerste verdieping | 2303 | 0.424481 | 0.0175903 | 0.848962 | 5995271 | 1 | 0.0175903 | Model Group:H07:5995281
5995276 | 01 eerste verdieping | 2303 | 0.424481 | 0.0175903 | 0.848962 | 5995271 | 1 | 0.0175903 | Model Group:H07:5995281
5995279 | 01 eerste verdieping | 990 | 0.186828 | 0.00756162 | 0.366018 | 5995271 | 1 | 0.00756162 | Model Group:H07:5995281
6382286 | 01 eerste verdieping | 1034 | 0.194792 | 0.00789769 | 0.389584 | 6382284 | 1 | 0.00789769 | Model Group:H16:5185909
6382288 | 01 eerste verdieping | 2323 | 0.428101 | 0.0177431 | 0.856202 | 6382284 | 1 | 0.0177431 | Model Group:H16:5185909
6382289 | 01 eerste verdieping | 2323 | 0.428101 | 0.0177431 | 0.856202 | 6382284 | 1 | 0.0177431 | Model Group:H16:5185909
6423885 | 00 Begane grond | 1123 | 0.210901 | 0.00857747 | 0.421802 | 6423886 | 0 | 0.00857747 | Model Group:H27:5259555
6423888 | 00 Begane grond | 550 | 0.107188 | 0.0042009 | 0.214376 | 6423886 | 0 | 0.0042009 | Model Group:H27:5259555
6423889 | 00 Begane grond | 416 | 0.082934 | 0.00317741 | 0.165868 | 6423886 | 0 | 0.00317741 | Model Group:H27:5259555
6423890 | 00 Begane grond | 1123 | 0.210901 | 0.00857747 | 0.421802 | 6423886 | 0 | 0.00857747 | Model Group:H27:5259555
6423920 | 00 Begane grond | 1123 | 0.210901 | 0.00857747 | 0.421802 | 6423921 | 0 | 0.00857747 | Model Group:H27:5259652
6423923 | 00 Begane grond | 550 | 0.107188 | 0.0042009 | 0.214376 | 6423921 | 0 | 0.0042009 | Model Group:H27:5259652
6423924 | 00 Begane grond | 416 | 0.082934 | 0.00317741 | 0.165868 | 6423921 | 0 | 0.00317741 | Model Group:H27:5259652
6423925 | 00 Begane grond | 1123 | 0.210901 | 0.00857747 | 0.421802 | 6423921 | 0 | 0.00857747 | Model Group:H27:5259652
6522733 | 00 Begane grond | 1034 | 0.194792 | 0.00789769 | 0.389584 | 6522731 | 0 | 0.00789769 | Model Group:H02:6522730
6522735 | 00 Begane grond | 2323 | 0.428101 | 0.0177431 | 0.856202 | 6522731 | 0 | 0.0177431 | Model Group:H02:6522730
6522736 | 00 Begane grond | 2323 | 0.428101 | 0.0177431 | 0.856202 | 6522731 | 0 | 0.0177431 | Model Group:H02:6522730
6604028 | 00 Begane grond | 1112 | 0.20891 | 0.00849346 | 0.410182 | 6604026 | 0 | 0.00849346 | Model Group:H18:5129917
6604029 | 00 Begane grond | 443 | 0.087821 | 0.00338363 | 0.175642 | 6604026 | 0 | 0.00338363 | Model Group:H18:5129917
6604030 | 00 Begane grond | 2303 | 0.424481 | 0.0175903 | 0.848962 | 6604026 | 0 | 0.0175903 | Model Group:H18:5129917
6604031 | 00 Begane grond | 2256 | 0.415974 | 0.0172313 | 0.831948 | 6604026 | 0 | 0.0172313 | Model Group:H18:5129917
6604035 | 00 Begane grond | 488 | 0.095966 | 0.00372734 | 0.184294 | 6604026 | 0 | 0.00372734 | Model Group:H18:5129917
6668702 | 00 Begane grond | 2323 | 0.428101 | 0.0177431 | 0.856202 | 6668703 | 0 | 0.0177431 | Model Group:H09:6668701
6668705 | 00 Begane grond | 1134 | 0.212892 | 0.00866149 | 0.425784 | 6668703 | 0 | 0.00866149 | Model Group:H09:6668701
6668707 | 00 Begane grond | 2323 | 0.428101 | 0.0177431 | 0.856202 | 6668703 | 0 | 0.0177431 | Model Group:H09:6668701
6693329 | 00 Begane grond | 1123 | 0.210901 | 0.00857747 | 0.421802 | 6693330 | 0 | 0.00857747 | Model Group:H27:6693328
6693332 | 00 Begane grond | 550 | 0.107188 | 0.0042009 | 0.214376 | 6693330 | 0 | 0.0042009 | Model Group:H27:6693328
6693333 | 00 Begane grond | 416 | 0.082934 | 0.00317741 | 0.165868 | 6693330 | 0 | 0.00317741 | Model Group:H27:6693328
6693334 | 00 Begane grond | 1123 | 0.210901 | 0.00857747 | 0.421802 | 6693330 | 0 | 0.00857747 | Model Group:H27:6693328
6694317 | 00 Begane grond | 1034 | 0.194792 | 0.00789769 | 0.389584 | 6694315 | 0 | 0.00789769 | Model Group:H02:6694314
6694319 | 00 Begane grond | 2323 | 0.428101 | 0.0177431 | 0.856202 | 6694315 | 0 | 0.0177431 | Model Group:H02:6694314
6694320 | 00 Begane grond | 2323 | 0.428101 | 0.0177431 | 0.856202 | 6694315 | 0 | 0.0177431 | Model Group:H02:6694314
6800004 | 00 Begane grond | 1034 | 0.194792 | 0.00789769 | 0.389584 | 6800002 | 0 | 0.00789769 | Model Group:H16:5145073
6800006 | 00 Begane grond | 2323 | 0.428101 | 0.0177431 | 0.856202 | 6800002 | 0 | 0.0177431 | Model Group:H16:5145073
6800007 | 00 Begane grond | 2323 | 0.428101 | 0.0177431 | 0.856202 | 6800002 | 0 | 0.0177431 | Model Group:H16:5145073
6800236 | 01 eerste verdieping | 1034 | 0.194792 | 0.00789769 | 0.389584 | 6800234 | 1 | 0.00789769 | Model Group:H16:5987797
6800238 | 01 eerste verdieping | 2323 | 0.428101 | 0.0177431 | 0.856202 | 6800234 | 1 | 0.0177431 | Model Group:H16:5987797
6800239 | 01 eerste verdieping | 2323 | 0.428101 | 0.0177431 | 0.856202 | 6800234 | 1 | 0.0177431 | Model Group:H16:5987797
6800245 | 01 eerste verdieping | 1034 | 0.194792 | 0.00789769 | 0.389584 | 6800243 | 1 | 0.00789769 | Model Group:H16:5995318
6800247 | 01 eerste verdieping | 2323 | 0.428101 | 0.0177431 | 0.856202 | 6800243 | 1 | 0.0177431 | Model Group:H16:5995318
6800248 | 01 eerste verdieping | 2323 | 0.428101 | 0.0177431 | 0.856202 | 6800243 | 1 | 0.0177431 | Model Group:H16:5995318
6801738 | 00 Begane grond | 1034 | 0.194792 | 0.00789769 | 0.389584 | 6801736 | 0 | 0.00789769 | Model Group:H16:5130407
6801740 | 00 Begane grond | 2323 | 0.428101 | 0.0177431 | 0.856202 | 6801736 | 0 | 0.0177431 | Model Group:H16:5130407
6801741 | 00 Begane grond | 2323 | 0.428101 | 0.0177431 | 0.856202 | 6801736 | 0 | 0.0177431 | Model Group:H16:5130407
6801781 | 00 Begane grond | 1034 | 0.194792 | 0.00789769 | 0.389584 | 6801779 | 0 | 0.00789769 | Model Group:H16:5127086
6801783 | 00 Begane grond | 2323 | 0.428101 | 0.0177431 | 0.856202 | 6801779 | 0 | 0.0177431 | Model Group:H16:5127086
6801784 | 00 Begane grond | 2323 | 0.428101 | 0.0177431 | 0.856202 | 6801779 | 0 | 0.0177431 | Model Group:H16:5127086
6802016 | 01 eerste verdieping | 1034 | 0.194792 | 0.00789769 | 0.389584 | 6802014 | 1 | 0.00789769 | Model Group:H16:5987147
6802018 | 01 eerste verdieping | 2323 | 0.428101 | 0.0177431 | 0.856202 | 6802014 | 1 | 0.0177431 | Model Group:H16:5987147
6802019 | 01 eerste verdieping | 2323 | 0.428101 | 0.0177431 | 0.856202 | 6802014 | 1 | 0.0177431 | Model Group:H16:5987147
6802179 | 01 eerste verdieping | 1034 | 0.194792 | 0.00789769 | 0.389584 | 6802177 | 1 | 0.00789769 | Model Group:H16:5987156
6802181 | 01 eerste verdieping | 2323 | 0.428101 | 0.0177431 | 0.856202 | 6802177 | 1 | 0.0177431 | Model Group:H16:5987156
6802182 | 01 eerste verdieping | 2323 | 0.428101 | 0.0177431 | 0.856202 | 6802177 | 1 | 0.0177431 | Model Group:H16:5987156
6802220 | 01 eerste verdieping | 1034 | 0.194792 | 0.00789769 | 0.389584 | 6802218 | 1 | 0.00789769 | Model Group:H16:5179182
6802222 | 01 eerste verdieping | 2323 | 0.428101 | 0.0177431 | 0.856202 | 6802218 | 1 | 0.0177431 | Model Group:H16:5179182
6802223 | 01 eerste verdieping | 2323 | 0.428101 | 0.0177431 | 0.856202 | 6802218 | 1 | 0.0177431 | Model Group:H16:5179182
6804083 | 00 Begane grond | 1034 | 0.194792 | 0.00789769 | 0.389584 | 6804081 | 0 | 0.00789769 | Model Group:H02:5126556
6804085 | 00 Begane grond | 2323 | 0.428101 | 0.0177431 | 0.856202 | 6804081 | 0 | 0.0177431 | Model Group:H02:5126556
6804086 | 00 Begane grond | 2323 | 0.428101 | 0.0177431 | 0.856202 | 6804081 | 0 | 0.0177431 | Model Group:H02:5126556

# IfcMember: Rectangular Mullion:31_CWM_090x114 (37)
Type - PredefinedType: MULLION; Material: ISR_HPL Kleur hout
Type - Other - Category: Curtain Wall Mullions; Family Name: Rectangular Mullion
Type - Constraints - Angle: 0 deg; Offset: 57 mm
Type - Construction - Corner Mullion: no; Position: Perpendicular to Face; Profile: System Mullion Profile: Rectangular; Thickness: 114 mm
Type - Dimensions - Width on side 1: 45 mm; Width on side 2: 45 mm
Type - Identity Data - Workset: Family : Curtain Wall Mullions : Rectangular Mullion; Type Name: 31_CWM_090x114
Type - Materials and Finishes - Material: ISR_HPL Kleur hout
Type - Pset_MemberCommon - IsExternal: no
Type - Pset_ProductRequirements - Category: Curtain Wall Mullions
Classification: 31.10 Uniformat (Uniformat)
Pset_MemberCommon - Reference: 31_CWM_090x114
Pset_QuantityTakeOff - Reference: 31_CWM_090x114
Other - Family: Rectangular Mullion; Family and Type: Rectangular Mullion: 31_CWM_090x114; Type: 31_CWM_090x114; Type Id: 6320807
Identity Data - Workset: Bouwkundig
Phasing - Phase Created: 2. nieuwbouw
Name (Rectangular Mullion:31_CWM_090x114:...) | In | Span (mm) = BaseQuantities, Length (mm) = Dimensions, Length (mm) | CrossSectionArea (m2) = Area (m2) | NetVolume (m3) = Volume (m3) | NetSurfaceArea (m2) | Host Id | Level | Group
5130951 | 00 Begane grond | 1135 | 0.2418 | 0.0116451 | 0.47334 | 5130949 | 0 | Model Group:H04:5130948 | Pset_MemberCommon - IsExternal: yes
5130952 | 00 Begane grond | 645 | 0.14184 | 0.0066177 | 0.28368 | 5130949 | 0 | Model Group:H04:5130948 | Pset_MemberCommon - IsExternal: yes
5130953 | 00 Begane grond | 2300 | 0.47946 | 0.023598 | 0.95892 | 5130949 | 0 | Model Group:H04:5130948 | Pset_MemberCommon - IsExternal: yes
5130954 | 00 Begane grond | 2210 | 0.4611 | 0.0226746 | 0.9222 | 5130949 | 0 | Model Group:H04:5130948 | Pset_MemberCommon - IsExternal: yes
5130958 | 00 Begane grond | 690 | 0.15102 | 0.0070794 | 0.29178 | 5130949 | 0 | Model Group:H04:5130948 | Pset_MemberCommon - IsExternal: yes
5130960 | 00 Begane grond | 2300 | 0.47946 | 0.023598 | 0.95892 | 5130949 | 0 | Model Group:H04:5130948 | Pset_MemberCommon - IsExternal: yes
5131649 | 00 Begane grond | 1135 | 0.2418 | 0.0116451 | 0.47334 | 5131647 | 0 | Model Group:H04:5131646
5131650 | 00 Begane grond | 645 | 0.14184 | 0.0066177 | 0.28368 | 5131647 | 0 | Model Group:H04:5131646
5131651 | 00 Begane grond | 2300 | 0.47946 | 0.023598 | 0.95892 | 5131647 | 0 | Model Group:H04:5131646
5131652 | 00 Begane grond | 2210 | 0.4611 | 0.0226746 | 0.9222 | 5131647 | 0 | Model Group:H04:5131646
5131656 | 00 Begane grond | 690 | 0.15102 | 0.0070794 | 0.29178 | 5131647 | 0 | Model Group:H04:5131646
5131658 | 00 Begane grond | 2300 | 0.47946 | 0.023598 | 0.95892 | 5131647 | 0 | Model Group:H04:5131646
5131945 | 00 Begane grond | 2323 | 0.484152 | 0.023834 | 0.968304 | 5131934 | 0 | Model Group:H03:5131933
5161255 | 00 Begane grond | 2323 | 0.484152 | 0.023834 | 0.968304 | 5151840 | 0 | Model Group:H10:5151852
5161614 | 00 Begane grond | 2323 | 0.484152 | 0.023834 | 0.968304 | 5151840 | 0 | Model Group:H10:5151852
5179833 | 01 eerste verdieping | 2323 | 0.484152 | 0.023834 | 0.968304 | 5179822 | 1 | Model Group:H03:5179821
5185803 | 01 eerste verdieping | 2323 | 0.484152 | 0.023834 | 0.968304 | 5185792 | 1 | Model Group:H18:5185791
5194920 | 01 eerste verdieping | 2323 | 0.484152 | 0.023834 | 0.968304 | 5194902 | 1 | Model Group:H12:5194912
5194926 | 01 eerste verdieping | 2323 | 0.484152 | 0.023834 | 0.968304 | 5194902 | 1 | Model Group:H12:5194912
5194941 | 01 eerste verdieping | 993.75 | 0.212985 | 0.0101959 | 0.41571 | 5194902 | 1 | Model Group:H12:5194912
5194942 | 01 eerste verdieping | 986.25 | 0.211455 | 0.0101189 | 0.41265 | 5194902 | 1 | Model Group:H12:5194912
6639305 | 01 eerste verdieping | 710 | 0.1551 | 0.0072846 | 0.3102 | 5194902 | 1 | Model Group:H12:5194912
6639406 | 01 eerste verdieping | 710 | 0.1551 | 0.0072846 | 0.3102 | 5194902 | 1 | Model Group:H12:5194912
5465839 | 00 Begane grond | 2323 | 0.484152 | 0.023834 | 0.968304 | 5465828 | 0 | Model Group:H03:5465827
5533707 | 01 eerste verdieping | 2323 | 0.484152 | 0.023834 | 0.968304 | 5533689 | 1 | Model Group:H11:5533699
5533713 | 01 eerste verdieping | 2323 | 0.484152 | 0.023834 | 0.968304 | 5533689 | 1 | Model Group:H11:5533699
5533728 | 01 eerste verdieping | 990 | 0.21222 | 0.0101574 | 0.41418 | 5533689 | 1 | Model Group:H11:5533699
5533729 | 01 eerste verdieping | 990 | 0.21222 | 0.0101574 | 0.41418 | 5533689 | 1 | Model Group:H11:5533699
6244427 | 01 eerste verdieping | 710 | 0.1551 | 0.0072846 | 0.3102 | 5533689 | 1 | Model Group:H11:5533699
6244529 | 01 eerste verdieping | 710 | 0.1551 | 0.0072846 | 0.3102 | 5533689 | 1 | Model Group:H11:5533699
6241464 | 00 Begane grond | 1135 | 0.2418 | 0.0116451 | 0.47334 | 6241462 | 0 | Model Group:H04:6241461
6241465 | 00 Begane grond | 645 | 0.14184 | 0.0066177 | 0.28368 | 6241462 | 0 | Model Group:H04:6241461
6241466 | 00 Begane grond | 2300 | 0.47946 | 0.023598 | 0.95892 | 6241462 | 0 | Model Group:H04:6241461
6241467 | 00 Begane grond | 2210 | 0.4611 | 0.0226746 | 0.9222 | 6241462 | 0 | Model Group:H04:6241461
6241471 | 00 Begane grond | 690 | 0.15102 | 0.0070794 | 0.29178 | 6241462 | 0 | Model Group:H04:6241461
6241473 | 00 Begane grond | 2300 | 0.47946 | 0.023598 | 0.95892 | 6241462 | 0 | Model Group:H04:6241461
6604037 | 00 Begane grond | 2323 | 0.484152 | 0.023834 | 0.968304 | 6604026 | 0 | Model Group:H18:5129917

# IfcMember: Rectangular Mullion:40x74 Gealan linear (2)
In: 00 Begane grond
Type - PredefinedType: MULLION; Material: ISR_Kunststof_wit
Type - Other - Category: Curtain Wall Mullions; Family Name: Rectangular Mullion
Type - Constraints - Angle: 0 deg; Offset: 37 mm
Type - Construction - Corner Mullion: no; Position: Perpendicular to Face; Profile: System Mullion Profile: Rectangular; Thickness: 74 mm
Type - Dimensions - Width on side 1: 20 mm; Width on side 2: 20 mm
Type - Identity Data - Workset: Family : Curtain Wall Mullions : Rectangular Mullion; Type Name: 40x74 Gealan linear
Type - Materials and Finishes - Material: ISR_Kunststof_wit
Type - Pset_MemberCommon - IsExternal: no
Type - Pset_ProductRequirements - Category: Curtain Wall Mullions
Classification: 31 Uniformat (Uniformat)
Pset_MemberCommon - Reference: 40x74 Gealan linear; Span: 962 mm
Pset_QuantityTakeOff - Reference: 40x74 Gealan linear
BaseQuantities - Length: 962 mm; CrossSectionArea: 0.112628 m2; NetVolume: 0.00284752 m3; NetSurfaceArea: 0.225256 m2
Other - Family: Rectangular Mullion; Family and Type: Rectangular Mullion: 40x74 Gealan linear; Type: 40x74 Gealan linear; Type Id: 5704714
Constraints - Level: 0
Dimensions - Area: 0.112628 m2; Length: 962 mm; Volume: 0.00284752 m3
Identity Data - Workset: Bouwkundig
Phasing - Phase Created: 2. nieuwbouw
Name (Rectangular Mullion:40x74 Gealan linear:...) | Host Id | Group
5537046 | 5537043 | Model Group:Merk K05:5537042 | Pset_MemberCommon - IsExternal: yes
6703048 | 6703045 | Model Group:Merk K05:6703044

# IfcMember: Rectangular Mullion:40x83 Gealan linear (2)
In: 00 Begane grond
Type - PredefinedType: MULLION; Material: ISR_Kunststof_wit
Type - Other - Category: Curtain Wall Mullions; Family Name: Rectangular Mullion
Type - Constraints - Angle: 0 deg; Offset: 40 mm
Type - Construction - Corner Mullion: no; Position: Perpendicular to Face; Profile: System Mullion Profile: Rectangular; Thickness: 83 mm
Type - Dimensions - Width on side 1: 20 mm; Width on side 2: 20 mm
Type - Identity Data - Workset: Family : Curtain Wall Mullions : Rectangular Mullion; Type Name: 40x83 Gealan linear
Type - Materials and Finishes - Material: ISR_Kunststof_wit
Type - Pset_MemberCommon - IsExternal: no
Type - Pset_ProductRequirements - Category: Curtain Wall Mullions
Classification: 31 Uniformat (Uniformat); Group: Model Group:Merk K15:5537536
Pset_MemberCommon - IsExternal: yes; Reference: 40x83 Gealan linear
Pset_QuantityTakeOff - Reference: 40x83 Gealan linear
Other - Family: Rectangular Mullion; Host Id: 5537537; Family and Type: Rectangular Mullion: 40x83 Gealan linear; Type: 40x83 Gealan linear; Type Id: 5703511
Constraints - Level: 0
Identity Data - Workset: Bouwkundig
Phasing - Phase Created: 2. nieuwbouw
Name (Rectangular Mullion:40x83 Gealan linear:...) | Span (mm) = BaseQuantities, Length (mm) = Dimensions, Length (mm) | CrossSectionArea (m2) = Area (m2) | NetVolume (m3) = Volume (m3) | NetSurfaceArea (m2)
5537540 | 1075 | 0.135545 | 0.003569 | 0.26777
5537552 | 901 | 0.114143 | 0.00299132 | 0.224966

# IfcMember: Rectangular Mullion:84x74 Gealan linear (34)
In: 00 Begane grond
Type - PredefinedType: MULLION; Material: ISR_Kunststof_RAL7006
Type - Other - Category: Curtain Wall Mullions; Family Name: Rectangular Mullion
Type - Constraints - Angle: 0 deg; Offset: 37 mm
Type - Construction - Corner Mullion: no; Position: Perpendicular to Face; Profile: System Mullion Profile: Rectangular; Thickness: 74 mm
Type - Dimensions - Width on side 1: 42 mm; Width on side 2: 42 mm
Type - Identity Data - Workset: Family : Curtain Wall Mullions : Rectangular Mullion; Type Name: 84x74 Gealan linear
Type - Materials and Finishes - Material: ISR_Kunststof_RAL7006
Type - Pset_MemberCommon - IsExternal: no
Type - Pset_ProductRequirements - Category: Curtain Wall Mullions
Classification: 31 Uniformat (Uniformat)
Pset_MemberCommon - Reference: 84x74 Gealan linear
Pset_QuantityTakeOff - Reference: 84x74 Gealan linear
Other - Family: Rectangular Mullion; Family and Type: Rectangular Mullion: 84x74 Gealan linear; Type: 84x74 Gealan linear; Type Id: 5643587
Constraints - Level: 0
Identity Data - Workset: Bouwkundig
Phasing - Phase Created: 2. nieuwbouw
Name (Rectangular Mullion:84x74 Gealan linear:...) | Span (mm) = BaseQuantities, Length (mm) = Dimensions, Length (mm) | CrossSectionArea (m2) = Area (m2) | NetVolume (m3) = Volume (m3) | NetSurfaceArea (m2) | Host Id | Group
5536859 | 1060 | 0.173696 | 0.00658896 | 0.341176 | 5536857 | Model Group:Merk K03:5536856 | Pset_MemberCommon - IsExternal: yes
5536861 | 2526 | 0.405324 | 0.0157016 | 0.810648 | 5536857 | Model Group:Merk K03:5536856 | Pset_MemberCommon - IsExternal: yes
5536862 | 2526 | 0.405324 | 0.0157016 | 0.810648 | 5536857 | Model Group:Merk K03:5536856 | Pset_MemberCommon - IsExternal: yes
5536865 | 1060 | 0.173696 | 0.00658896 | 0.341176 | 5536857 | Model Group:Merk K03:5536856 | Pset_MemberCommon - IsExternal: yes
5536931 | 1060 | 0.173696 | 0.00658896 | 0.341176 | 5536929 | Model Group:Merk K03:5536928
5536933 | 2526 | 0.405324 | 0.0157016 | 0.810648 | 5536929 | Model Group:Merk K03:5536928
5536934 | 2526 | 0.405324 | 0.0157016 | 0.810648 | 5536929 | Model Group:Merk K03:5536928
5536937 | 1060 | 0.173696 | 0.00658896 | 0.341176 | 5536929 | Model Group:Merk K03:5536928
5537045 | 962 | 0.158212 | 0.00597979 | 0.316424 | 5537043 | Model Group:Merk K05:5537042
5537047 | 2630 | 0.421756 | 0.0163481 | 0.843512 | 5537043 | Model Group:Merk K05:5537042
5537048 | 2630 | 0.421756 | 0.0163481 | 0.843512 | 5537043 | Model Group:Merk K05:5537042
5537082 | 1060 | 0.173696 | 0.00658896 | 0.341176 | 5537080 | Model Group:Merk K03:5537079
5537084 | 2526 | 0.405324 | 0.0157016 | 0.810648 | 5537080 | Model Group:Merk K03:5537079
5537085 | 2526 | 0.405324 | 0.0157016 | 0.810648 | 5537080 | Model Group:Merk K03:5537079
5537088 | 1060 | 0.173696 | 0.00658896 | 0.341176 | 5537080 | Model Group:Merk K03:5537079
5538765 | 1060 | 0.173696 | 0.00658896 | 0.341176 | 5538763 | Model Group:Merk K03:5538762
5538767 | 2526 | 0.405324 | 0.0157016 | 0.810648 | 5538763 | Model Group:Merk K03:5538762
5538768 | 2526 | 0.405324 | 0.0157016 | 0.810648 | 5538763 | Model Group:Merk K03:5538762
5538771 | 1060 | 0.173696 | 0.00658896 | 0.341176 | 5538763 | Model Group:Merk K03:5538762
5538783 | 1060 | 0.173696 | 0.00658896 | 0.341176 | 5538781 | Model Group:Merk K03:5538780
5538785 | 2526 | 0.405324 | 0.0157016 | 0.810648 | 5538781 | Model Group:Merk K03:5538780
5538786 | 2526 | 0.405324 | 0.0157016 | 0.810648 | 5538781 | Model Group:Merk K03:5538780
5538789 | 1060 | 0.173696 | 0.00658896 | 0.341176 | 5538781 | Model Group:Merk K03:5538780
5538801 | 1060 | 0.173696 | 0.00658896 | 0.341176 | 5538799 | Model Group:Merk K03:5538798
5538803 | 2526 | 0.405324 | 0.0157016 | 0.810648 | 5538799 | Model Group:Merk K03:5538798
5538804 | 2526 | 0.405324 | 0.0157016 | 0.810648 | 5538799 | Model Group:Merk K03:5538798
5538807 | 1060 | 0.173696 | 0.00658896 | 0.341176 | 5538799 | Model Group:Merk K03:5538798
5539077 | 955 | 0.157106 | 0.00593628 | 0.307996 | 5539075 | Model Group:Merk K20:5539074
5539079 | 2546 | 0.408484 | 0.0158259 | 0.816968 | 5539075 | Model Group:Merk K20:5539074
5539080 | 2546 | 0.408484 | 0.0158259 | 0.816968 | 5539075 | Model Group:Merk K20:5539074
5539083 | 955 | 0.157106 | 0.00593628 | 0.307996 | 5539075 | Model Group:Merk K20:5539074
6703047 | 962 | 0.158212 | 0.00597979 | 0.316424 | 6703045 | Model Group:Merk K05:6703044
6703049 | 2630 | 0.421756 | 0.0163481 | 0.843512 | 6703045 | Model Group:Merk K05:6703044
6703050 | 2630 | 0.421756 | 0.0163481 | 0.843512 | 6703045 | Model Group:Merk K05:6703044

# IfcMember: Rectangular Mullion:NLRS_21_CWM_drager LD.0065 - links_Storax (4)
In: 02 tweede verdieping
Type - PredefinedType: MULLION; Material: STAAL_RAL 7006
Type - Other - Category: Curtain Wall Mullions; Family Name: Rectangular Mullion
Type - Constraints - Angle: 0 deg; Offset: 0 mm
Type - Construction - Thickness: 0 mm; Corner Mullion: no; Position: Perpendicular to Face; Profile: NLRS_21_PRF_drager LD.0065_renson : drager - links_Storax_LD.0065
Type - Dimensions - Width on side 1: 0 mm; Width on side 2: 0 mm
Type - Identity Data - Workset: Family : Curtain Wall Mullions : Rectangular Mullion; Assembly Code: 20; Manufacturer: Renson; NLRS_C_code_artikel: VV-L-1.xx01; NLRS_C_code_ETIM_url: http://prod.etim-international.com/Class/Details?classId=EC003108&classVersion=2; NLRS_C_content_creator: Itannex; NLRS_C_content_datum_uitgifte: 29-03-2017; NLRS_C_content_handleiding: n/a; NLRS_C_content_provider: Storax; NLRS_C_content_versie: V1; NLRS_C_description: drager_Storax_Linius_LD.0065; NLRS_C_IFC_versie: 2x3; NLRS_C_model: Linius; NLRS_C_revit_versie: 2016; NLRS_C_type: LD.0065; NLRS_C_type_comments: drager; Storax_I BaseKeynote: 21.1; Type Name: NLRS_21_CWM_drager LD.0065 - links_Storax; URL: https://www.storax.nl/producten/lamellenwanden
Type - Materials and Finishes - Material: STAAL_RAL 7006
Type - Pset_ManufacturerTypeInformation - Manufacturer: Renson
Type - Pset_MemberCommon - IsExternal: no
Type - Pset_ProductRequirements - Category: Curtain Wall Mullions
Classification: 20 Uniformat (Uniformat)
Pset_MemberCommon - Reference: NLRS_21_CWM_drager LD.0065 - links_Storax; Span: 2050 mm
Pset_QuantityTakeOff - Reference: NLRS_21_CWM_drager LD.0065 - links_Storax
Pset_DAT_KMS - Assembly Code: 20
BaseQuantities - Length: 2050 mm; CrossSectionArea: 0.11009 m2; NetSurfaceArea: 0.22018 m2
Other - Family: Rectangular Mullion; Family and Type: Rectangular Mullion: NLRS_21_CWM_drager LD.0065 - links_Storax; Type: NLRS_21_CWM_drager LD.0065 - links_Storax; Type Id: 6284806
Constraints - Level: V2 bk. ruwe vloer
Dimensions - Area: 0.11009 m2; Length: 2050 mm
Identity Data - Workset: Bouwkundig
Phasing - Phase Created: 2. nieuwbouw
Name (Rectangular Mullion:NLRS_21_CWM_drager LD.0065 - links_Storax:...) | NetVolume (m3) = Volume (m3) | Host Id | Group
6285790 | 0.000169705 | 6285781 | Pset_MemberCommon - IsExternal: yes
6286612 | 0.000169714 | 6286603 | Model Group:Paneel op dak:6286816
6287089 | 0.000169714 | 6287080 | Model Group:Paneel op dak:6287293
6287303 | 0.000169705 | 6287294 | Model Group:Paneel op dak:6287507

# IfcMember: Rectangular Mullion:NLRS_21_CWM_drager LD.0065 - rechts_Storax (4)
In: 02 tweede verdieping
Type - PredefinedType: MULLION; Material: STAAL_RAL 7006
Type - Other - Category: Curtain Wall Mullions; Family Name: Rectangular Mullion
Type - Constraints - Angle: 0 deg; Offset: 0 mm
Type - Construction - Thickness: 0 mm; Corner Mullion: no; Position: Perpendicular to Face; Profile: NLRS_21_PRF_drager LD.0065_renson : drager - rechts_Storax_LD.0065
Type - Dimensions - Width on side 1: 0 mm; Width on side 2: 0 mm
Type - Identity Data - Workset: Family : Curtain Wall Mullions : Rectangular Mullion; Assembly Code: 20; Manufacturer: Renson; NLRS_C_code_artikel: VV-L-1.xx01; NLRS_C_code_ETIM_url: http://prod.etim-international.com/Class/Details?classId=EC003108&classVersion=2; NLRS_C_content_creator: Itannex; NLRS_C_content_datum_uitgifte: 29-03-2017; NLRS_C_content_handleiding: n/a; NLRS_C_content_provider: Storax; NLRS_C_content_versie: V1; NLRS_C_description: drager_Storax_Linius_LD.0065; NLRS_C_IFC_versie: 2x3; NLRS_C_model: Linius; NLRS_C_revit_versie: 2016; NLRS_C_type: LD.0065; NLRS_C_type_comments: drager; Storax_I BaseKeynote: 21.1; Type Name: NLRS_21_CWM_drager LD.0065 - rechts_Storax; URL: https://www.storax.nl/producten/lamellenwanden
Type - Materials and Finishes - Material: STAAL_RAL 7006
Type - Pset_ManufacturerTypeInformation - Manufacturer: Renson
Type - Pset_MemberCommon - IsExternal: no
Type - Pset_ProductRequirements - Category: Curtain Wall Mullions
Classification: 20 Uniformat (Uniformat)
Pset_MemberCommon - Reference: NLRS_21_CWM_drager LD.0065 - rechts_Storax; Span: 2050 mm
Pset_QuantityTakeOff - Reference: NLRS_21_CWM_drager LD.0065 - rechts_Storax
Pset_DAT_KMS - Assembly Code: 20
BaseQuantities - Length: 2050 mm; CrossSectionArea: 0.11009 m2; NetSurfaceArea: 0.22018 m2
Other - Family: Rectangular Mullion; Family and Type: Rectangular Mullion: NLRS_21_CWM_drager LD.0065 - rechts_Storax; Type: NLRS_21_CWM_drager LD.0065 - rechts_Storax; Type Id: 6284808
Constraints - Level: V2 bk. ruwe vloer
Dimensions - Area: 0.11009 m2; Length: 2050 mm
Identity Data - Workset: Bouwkundig
Phasing - Phase Created: 2. nieuwbouw
Name (Rectangular Mullion:NLRS_21_CWM_drager LD.0065 - rechts_Storax:...) | NetVolume (m3) = Volume (m3) | Host Id | Group
6285791 | 0.000169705 | 6285781 | Pset_MemberCommon - IsExternal: yes
6286613 | 0.000169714 | 6286603 | Model Group:Paneel op dak:6286816
6287090 | 0.000169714 | 6287080 | Model Group:Paneel op dak:6287293
6287304 | 0.000169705 | 6287294 | Model Group:Paneel op dak:6287507

# IfcMember: Rectangular Mullion:NLRS_21_CWM_drager LD.0065_Storax (10)
In: 02 tweede verdieping
Type - PredefinedType: MULLION; Material: STAAL_RAL 7006
Type - Other - Category: Curtain Wall Mullions; Family Name: Rectangular Mullion
Type - Constraints - Angle: 0 deg; Offset: 0 mm
Type - Construction - Corner Mullion: no; Position: Perpendicular to Face; Profile: NLRS_21_PRF_drager LD.0065_renson : drager_Storax_LD.0065; Thickness: 1.5 mm
Type - Dimensions - Width on side 1: 0 mm; Width on side 2: 0 mm
Type - Identity Data - Workset: Family : Curtain Wall Mullions : Rectangular Mullion; Assembly Code: 20; Manufacturer: Renson; NLRS_C_code_artikel: VV-L-1.xx01; NLRS_C_code_ETIM_url: http://prod.etim-international.com/Class/Details?classId=EC003108&classVersion=2; NLRS_C_content_creator: Itannex; NLRS_C_content_datum_uitgifte: 29-03-2017; NLRS_C_content_handleiding: n/a; NLRS_C_content_provider: Storax; NLRS_C_content_versie: V1; NLRS_C_description: drager_Storax_Linius_LD.0065; NLRS_C_IFC_versie: 2x3; NLRS_C_model: Linius; NLRS_C_revit_versie: 2016; NLRS_C_type: LD.0065; NLRS_C_type_comments: drager; Storax_I BaseKeynote: 21.1; Type Name: NLRS_21_CWM_drager LD.0065_Storax; URL: https://www.storax.nl/producten/lamellenwanden
Type - Materials and Finishes - Material: STAAL_RAL 7006
Type - Pset_ManufacturerTypeInformation - Manufacturer: Renson
Type - Pset_MemberCommon - IsExternal: no
Type - Pset_ProductRequirements - Category: Curtain Wall Mullions
Classification: 20 Uniformat (Uniformat)
Pset_MemberCommon - Reference: NLRS_21_CWM_drager LD.0065_Storax; Span: 2050 mm
Pset_QuantityTakeOff - Reference: NLRS_21_CWM_drager LD.0065_Storax
Pset_DAT_KMS - Assembly Code: 20
BaseQuantities - Length: 2050 mm; CrossSectionArea: 0.11009 m2; NetSurfaceArea: 0.22018 m2
Other - Family: Rectangular Mullion; Family and Type: Rectangular Mullion: NLRS_21_CWM_drager LD.0065_Storax; Type: NLRS_21_CWM_drager LD.0065_Storax; Type Id: 6284804
Constraints - Level: V2 bk. ruwe vloer
Dimensions - Area: 0.11009 m2; Length: 2050 mm
Identity Data - Workset: Bouwkundig
Phasing - Phase Created: 2. nieuwbouw
Name (Rectangular Mullion:NLRS_21_CWM_drager LD.0065_Storax:...) | NetVolume (m3) = Volume (m3) | Host Id | Group
6285793 | 0.000169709 | 6285781 | Pset_MemberCommon - IsExternal: yes
6286614 | 0.000169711 | 6286603 | Model Group:Paneel op dak:6286816
6286615 | 0.000169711 | 6286603 | Model Group:Paneel op dak:6286816
6286765 | 0.000169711 | 6286603 | Model Group:Paneel op dak:6286816
6287091 | 0.000169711 | 6287080 | Model Group:Paneel op dak:6287293
6287092 | 0.000169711 | 6287080 | Model Group:Paneel op dak:6287293
6287242 | 0.000169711 | 6287080 | Model Group:Paneel op dak:6287293
6287305 | 0.000169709 | 6287294 | Model Group:Paneel op dak:6287507
6287306 | 0.000169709 | 6287294 | Model Group:Paneel op dak:6287507
6287456 | 0.000169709 | 6287294 | Model Group:Paneel op dak:6287507

# IfcOpeningElement: Opening (1092)
Name | In | Classification | Depth (mm) | BaseQuantities, Height (mm) | BaseQuantities, Width (mm) | Reference | Pset_OpeningElementCommon, sets with these values | Pset_ProductRequirements, Category | Pset_wanden, Structural Usage | Pset_wanden, Omschrijving | Pset_wanden, NL-sfb-Codering | Pset_kozijnen (CW), Omschrijving | Pset_kozijnen (CW), NL-sfb-Codering | Pset_DAT_KMS, Assembly Code | Pset_DAT_KMS, Assembly Description | Pset_DAT_KMS, Description | Other, Category | Family | Other, Family and Type | Type | Type Id | Base Offset (mm) | Base is Attached = Related to Mass = Top is Attached = Structural | Room Bounding | Base Constraint | Top Offset (mm) | Unconnected Height (mm) | Dimensions, Area (m2) | Length (mm) | Identity Data, Workset | Phase Created | Structural, Structural Usage | Angle (deg) = Offset (mm) | Justification | Number | Horizontal Grid, sets with these values | Cross-Section
Basic Wall:28_DAT_kalkzandsteen_150mm:4788691 | 00 Begane grond | 28.21 Uniformat (Uniformat) | 454.8 | 2390 | 1034 | Merk H02 | 2 | Walls | Non-bearing | houten kozijn | 31.10 | houten kozijn | 31.10 | 31.10 | buitenwandopeningen; niet gevuld, algemeen (verzamelniveau) | houten kozijn | Walls | Curtain Wall | Curtain Wall: Merk H02 | Merk H02 | 5128107 | 0 | no | yes | 0 | 400 | 2390 | 2.47126 | 1034 | Bouwkundig | 2. nieuwbouw | Non-bearing | 0 | Beginning | 4 | 2 | Vertical | Pset_wanden - NLRS_C_Geluidwering_DnTA: 25; Pset_kozijnen (CW) - NLRS_C_Geluidwering_DnTA: 25; Data - NLRS_C_Geluidwering_DnTA: 25; Materials and Finishes - NLRS_C_Afwerking Kozijn: Ral 9010 - Deur HPL Formica F2296 Sno White
2 x Basic Wall:22_DAT_binnenwand_125:4962149 | 00 Begane grond | 22.13 Uniformat (Uniformat) | 429.8 | 2390 | 1034 | Merk H01 | 2 | Walls | Non-bearing | houten kozijn | 31.10 | houten kozijn | 31.10 | 31.10 | buitenwandopeningen; niet gevuld, algemeen (verzamelniveau) | houten kozijn | Walls | Curtain Wall | Curtain Wall: Merk H01 | Merk H01 | 5121256 | 0 | no | yes | 0 | 400 | 2390 | 2.47126 | 1034 | Bouwkundig | 2. nieuwbouw | Non-bearing | 0 | Beginning | 4 | 2 | Vertical | Pset_wanden - NLRS_C_Geluidwering_DnTA: 34; Pset_kozijnen (CW) - NLRS_C_Geluidwering_DnTA: 34; Data - NLRS_C_Geluidwering_DnTA: 34; Materials and Finishes - NLRS_C_Afwerking Kozijn: Ral 9010 - Deur HPL Formica F2296 Sno White
Basic Wall:22_DAT_binnenwand_125:4962149 | 00 Begane grond | 22.13 Uniformat (Uniformat) | 429.8 | 2390 | 1034 | Merk H16 | 2 | Walls | Non-bearing | houten kozijn | 31.10 | houten kozijn | 31.10 | 31.10 | buitenwandopeningen; niet gevuld, algemeen (verzamelniveau) | houten kozijn | Walls | Curtain Wall | Curtain Wall: Merk H16 | Merk H16 | 6103248 | 0 | no | yes | 0 | 400 | 2390 | 2.47126 | 1034 | Bouwkundig | 2. nieuwbouw | Non-bearing | 0 | Beginning | 4 | 2 | Vertical | Pset_wanden - NLRS_C_Geluidwering_DnTA: 34; Pset_kozijnen (CW) - NLRS_C_Geluidwering_DnTA: 34; Data - NLRS_C_Geluidwering_DnTA: 34; Materials and Finishes - NLRS_C_Afwerking Kozijn: Ral 9010 - Deur HPL Formica F2296 Sno White
Basic Wall:22_DAT_binnenwand_125:4962149 | 00 Begane grond | 22.13 Uniformat (Uniformat) | 429.8 | 1190 | 600 | Merk H05 | 2 | Walls | Non-bearing | houten kozijn | 31.10 | houten kozijn | 31.10 | 31.10 | buitenwandopeningen; niet gevuld, algemeen (verzamelniveau) | houten kozijn | Walls | Curtain Wall | Curtain Wall: Merk H05 | Merk H05 | 5132093 | 1200 | no | yes | 0 | 400 | 1190 | 0.714 | 600 | Bouwkundig | 2. nieuwbouw | Non-bearing | 0 | Beginning | 4 | 2 | Vertical | Pset_wanden - NLRS_C_Geluidwering_DnTA: 34; Pset_kozijnen (CW) - NLRS_C_Geluidwering_DnTA: 34; Data - NLRS_C_Geluidwering_DnTA: 34; Materials and Finishes - NLRS_C_Afwerking Kozijn: Ral 9010 - Deur HPL Formica F2296 Sno White
Basic Wall:22_DAT_binnenwand_125:4962406 | 00 Begane grond | 22.13 Uniformat (Uniformat) | 429.8 | 2390 | 1034 | Merk H16 | 2 | Walls | Non-bearing | houten kozijn | 31.10 | houten kozijn | 31.10 | 31.10 | buitenwandopeningen; niet gevuld, algemeen (verzamelniveau) | houten kozijn | Walls | Curtain Wall | Curtain Wall: Merk H16 | Merk H16 | 6103248 | 0 | no | yes | 0 | 400 | 2390 | 2.47126 | 1034 | Bouwkundig | 2. nieuwbouw | Non-bearing | 0 | Beginning | 4 | 2 | Vertical | Pset_wanden - NLRS_C_Geluidwering_DnTA: 34; Pset_kozijnen (CW) - NLRS_C_Geluidwering_DnTA: 34; Kozijnmerk: S; NLRS_C_gespiegeld: S; Data - NLRS_C_Geluidwering_DnTA: 34; NLRS_C_gespiegeld: S; Materials and Finishes - NLRS_C_Afwerking Kozijn: Ral 9010 - Deur HPL Formica F2296 Sno White
Basic Wall:22_DAT_binnenwand_125:4962406 | 00 Begane grond | 22.13 Uniformat (Uniformat) | 429.8 | 1190 | 600 | Merk H05 | 2 | Walls | Non-bearing | houten kozijn | 31.10 | houten kozijn | 31.10 | 31.10 | buitenwandopeningen; niet gevuld, algemeen (verzamelniveau) | houten kozijn | Walls | Curtain Wall | Curtain Wall: Merk H05 | Merk H05 | 5132093 | 1200 | no | yes | 0 | 400 | 1190 | 0.714 | 600 | Bouwkundig | 2. nieuwbouw | Non-bearing | 0 | Beginning | 4 | 2 | Vertical | Pset_wanden - NLRS_C_Geluidwering_DnTA: 34; Pset_kozijnen (CW) - NLRS_C_Geluidwering_DnTA: 34; Data - NLRS_C_Geluidwering_DnTA: 34; Materials and Finishes - NLRS_C_Afwerking Kozijn: Ral 9010 - Deur HPL Formica F2296 Sno White
2 x Basic Wall:22_DAT_binnenwand_125:4962988 | 00 Begane grond | 22.13 Uniformat (Uniformat) | 429.8 | 2390 | 1034 | Merk H01 | 2 | Walls | Non-bearing | houten kozijn | 31.10 | houten kozijn | 31.10 | 31.10 | buitenwandopeningen; niet gevuld, algemeen (verzamelniveau) | houten kozijn | Walls | Curtain Wall | Curtain Wall: Merk H01 | Merk H01 | 5121256 | 0 | no | yes | 0 | 400 | 2390 | 2.47126 | 1034 | Bouwkundig | 2. nieuwbouw | Non-bearing | 0 | Beginning | 4 | 2 | Vertical | Pset_wanden - NLRS_C_Geluidwering_DnTA: 34; Pset_kozijnen (CW) - NLRS_C_Geluidwering_DnTA: 34; Data - NLRS_C_Geluidwering_DnTA: 34; Materials and Finishes - NLRS_C_Afwerking Kozijn: Ral 9010 - Deur HPL Formica F2296 Sno White
Basic Wall:22_DAT_binnenwand_125:4962990 | 00 Begane grond | 22.13 Uniformat (Uniformat) | 240 | 790 | 790 | haspel slang 30m gen hxdxb 730x240x790 | 2 | Plumbing Fixtures |  |  |  |  |  | 59.20 |  | brandslanghaspel inbouw | Plumbing Fixtures | NLRS_59_PF_FB_brandslanghaspel inbouw_gen_ISR | NLRS_59_PF_FB_brandslanghaspel inbouw_gen_ISR: haspel slang 30m gen hxdxb 730x240x790 | haspel slang 30m gen hxdxb 730x240x790 | 4687182 |  |  |  |  |  |  | 1.00371 |  | Bouwkundig | 2. nieuwbouw | Constraints - Elevation from Level: 1780 mm; Host: Basic Wall : 22_DAT_binnenwand_125; Level: V-1; Schedule Level: V-1; Dimensions - NLRS_C_breedte: 790 mm; NLRS_C_diepte: 240 mm; NLRS_C_hoogte: 790 mm; Volume: 0.149784 m3; General - NLRS_P_c01_diameter: 22 mm; NLRS_P_c01_radius: 11 mm; Graphics - slang_bereik: no; Identity Data - Mark: 80; Mechanical - brandslanghaspel_kw_flow: 0.361 m3/s; System Classification: Domestic Cold Water
Basic Wall:22_DAT_binnenwand_125:4962990 | 00 Begane grond | 22.13 Uniformat (Uniformat) | 429.8 | 2390 | 1034 | Merk H02 | 2 | Walls | Non-bearing | houten kozijn | 31.10 | houten kozijn | 31.10 | 31.10 | buitenwandopeningen; niet gevuld, algemeen (verzamelniveau) | houten kozijn | Walls | Curtain Wall | Curtain Wall: Merk H02 | Merk H02 | 5128107 | 0 | no | yes | 0 | 400 | 2390 | 2.47126 | 1034 | Bouwkundig | 2. nieuwbouw | Non-bearing | 0 | Beginning | 4 | 2 | Vertical | Pset_wanden - NLRS_C_Geluidwering_DnTA: 25; Pset_kozijnen (CW) - NLRS_C_Geluidwering_DnTA: 25; Data - NLRS_C_Geluidwering_DnTA: 25; Materials and Finishes - NLRS_C_Afwerking Kozijn: Ral 9010 - Deur HPL Formica F2296 Sno White
Basic Wall:22_DAT_binnenwand_125:4963264 | 00 Begane grond | 22.13 Uniformat (Uniformat) | 429.8 | 2390 | 1825 | Merk H04 | 2 | Walls | Non-bearing | houten kozijn | 31.10 | houten kozijn | 31.10 | 31.10 | buitenwandopeningen; niet gevuld, algemeen (verzamelniveau) | houten kozijn | Walls | Curtain Wall | Curtain Wall: Merk H04 | Merk H04 | 6102986 | 0 | no | yes | 0 | 400 | 2390 | 4.36175 | 1825 | Bouwkundig | 2. nieuwbouw | Non-bearing | 0 | Beginning | 4 | 2 | Vertical | Pset_wanden - NLRS_C_Geluidwering_DnTA: 25; NLRS_C_brandwerendheid: 30; Pset_kozijnen (CW) - NLRS_C_Geluidwering_DnTA: 25; NLRS_C_brandwerendheid: 30; Data - NLRS_C_Geluidwering_DnTA: 25; Materials and Finishes - NLRS_C_Afwerking Kozijn: Kozijn Bamboo - Deur Bamboo; Fire Protection - NLRS_C_brandwerendheid: 30
Basic Wall:22_DAT_binnenwand_125:4963264 | 00 Begane grond | 22.13 Uniformat (Uniformat) | 429.8 | 2415 | 4535 | 22_DAT_binnenwand_125 HPL dubbel | 2 | Walls | Non-bearing | Lichte scheidingswand 125mmAan weerszijden gipsvezelplaat 12,5mmGipsplaat 12,5mm Met daartussen 75mm ms wand gevuld met isolatieVulling afhankelijk van gestelde eisen ingeluidsrapportage | 22.13 |  |  | 22.13 | binnenwanden; niet constructief, systeemwanden; vast | Lichte scheidingswand 125mmAan weerszijden gipsvezelplaat 12,5mmGipsplaat 12,5mm Met daartussen 75mm ms wand gevuld met isolatieVulling afhankelijk van gestelde eisen ingeluidsrapportage | Walls | Basic Wall | Basic Wall: 22_DAT_binnenwand_125 HPL dubbel | 22_DAT_binnenwand_125 HPL dubbel | 6394901 | 0 | no | yes | 0 | 0 | 2415 | 1.09328 | 4597.5 | Bouwkundig | 2. nieuwbouw | Non-bearing |  |  |  |  | Vertical | Dimensions - Volume: 0.136659 m3; Constraints - Base Extension Distance: 0 mm; Top Extension Distance: 0 mm; Location Line: Wall Centerline
Basic Wall:22_DAT_binnenwand_125:4963384 | 00 Begane grond | 22.13 Uniformat (Uniformat) | 429.8 | 2390 | 1825 | Merk H04 | 2 | Walls | Non-bearing | houten kozijn | 31.10 | houten kozijn | 31.10 | 31.10 | buitenwandopeningen; niet gevuld, algemeen (verzamelniveau) | houten kozijn | Walls | Curtain Wall | Curtain Wall: Merk H04 | Merk H04 | 6102986 | 0 | no | yes | 0 | 400 | 2390 | 4.36175 | 1825 | Bouwkundig | 2. nieuwbouw | Non-bearing | 0 | Beginning | 4 | 2 | Vertical | Pset_wanden - NLRS_C_Geluidwering_DnTA: 25; Pset_kozijnen (CW) - NLRS_C_Geluidwering_DnTA: 25; Data - NLRS_C_Geluidwering_DnTA: 25; Materials and Finishes - NLRS_C_Afwerking Kozijn: Kozijn Bamboo - Deur Bamboo
Basic Wall:22_DAT_binnenwand_125:4963384 | 00 Begane grond | 22.13 Uniformat (Uniformat) | 429.8 | 2415 | 4495 | 22_DAT_binnenwand_125 HPL | 2 | Walls | Non-bearing | Lichte scheidingswand 125mmAan weerszijden gipsvezelplaat 12,5mmGipsplaat 12,5mm Met daartussen 75mm ms wand gevuld met isolatieVulling afhankelijk van gestelde eisen ingeluidsrapportage | 22.13 |  |  | 22.13 | binnenwanden; niet constructief, systeemwanden; vast | Lichte scheidingswand 125mmAan weerszijden gipsvezelplaat 12,5mmGipsplaat 12,5mm Met daartussen 75mm ms wand gevuld met isolatieVulling afhankelijk van gestelde eisen ingeluidsrapportage | Walls | Basic Wall | Basic Wall: 22_DAT_binnenwand_125 HPL | 22_DAT_binnenwand_125 HPL | 6329633 | 0 | no | yes | 0 | 0 | 2415 | 0.853275 | 4557.5 | Bouwkundig | 2. nieuwbouw | Non-bearing |  |  |  |  | Vertical | Dimensions - Volume: 0.106659 m3; Constraints - Base Extension Distance: 0 mm; Top Extension Distance: 0 mm; Location Line: Wall Centerline
Basic Wall:22_DAT_binnenwand_125 HPL dubbel:4963858 | 00 Begane grond | 22.13 Uniformat (Uniformat) | 429.8 | 600 | 2400 | Merk H15 | 2 | Walls | Non-bearing | houten kozijn | 31.10 | houten kozijn | 31.10 | 31.10 | buitenwandopeningen; niet gevuld, algemeen (verzamelniveau) | houten kozijn | Walls | Curtain Wall | Curtain Wall: Merk H15 | Merk H15 | 5184984 | 1000 | no | yes | 0 | 400 | 600 | 1.44 | 2400 | Bouwkundig | 2. nieuwbouw | Non-bearing | 0 | Beginning | 4 | 2 | Vertical | Pset_wanden - NLRS_C_Geluidwering_DnTA: 25; NLRS_C_brandwerendheid: 30; Pset_kozijnen (CW) - NLRS_C_Geluidwering_DnTA: 25; NLRS_C_brandwerendheid: 30; Data - NLRS_C_Geluidwering_DnTA: 25; Materials and Finishes - NLRS_C_Afwerking Kozijn: Kozijn Bamboo - Deur Bamboo; Fire Protection - NLRS_C_brandwerendheid: 30
Basic Wall:22_DAT_binnenwand_125 HPL dubbel:4963956 | 00 Begane grond | 22.13 Uniformat (Uniformat) | 429.8 | 600 | 2400 | Merk H15 | 2 | Walls | Non-bearing | houten kozijn | 31.10 | houten kozijn | 31.10 | 31.10 | buitenwandopeningen; niet gevuld, algemeen (verzamelniveau) | houten kozijn | Walls | Curtain Wall | Curtain Wall: Merk H15 | Merk H15 | 5184984 | 1000 | no | yes | 0 | 400 | 600 | 1.44 | 2400 | Bouwkundig | 2. nieuwbouw | Non-bearing | 0 | Beginning | 4 | 2 | Vertical | Pset_wanden - NLRS_C_Geluidwering_DnTA: 25; Pset_kozijnen (CW) - NLRS_C_Geluidwering_DnTA: 25; Data - NLRS_C_Geluidwering_DnTA: 25; Materials and Finishes - NLRS_C_Afwerking Kozijn: Kozijn Bamboo - Deur Bamboo
Basic Wall:22_DAT_binnenwand_125:4964085 | 00 Begane grond | 22.13 Uniformat (Uniformat) | 429.8 | 2415 | 588 | 22_DAT_binnenwand_125 HPL | 2 | Walls | Non-bearing | Lichte scheidingswand 125mmAan weerszijden gipsvezelplaat 12,5mmGipsplaat 12,5mm Met daartussen 75mm ms wand gevuld met isolatieVulling afhankelijk van gestelde eisen ingeluidsrapportage | 22.13 |  |  | 22.13 | binnenwanden; niet constructief, systeemwanden; vast | Lichte scheidingswand 125mmAan weerszijden gipsvezelplaat 12,5mmGipsplaat 12,5mm Met daartussen 75mm ms wand gevuld met isolatieVulling afhankelijk van gestelde eisen ingeluidsrapportage | Walls | Basic Wall | Basic Wall: 22_DAT_binnenwand_125 HPL | 22_DAT_binnenwand_125 HPL | 6329633 | 0 | no | yes | 0 | 0 | 2415 | 1.42002 | 713 | Bouwkundig | 2. nieuwbouw | Non-bearing |  |  |  |  | Vertical | Dimensions - Volume: 0.177503 m3; Constraints - Base Extension Distance: 0 mm; Top Extension Distance: 0 mm; Location Line: Wall Centerline
Basic Wall:22_DAT_binnenwand_125:4965732 | 00 Begane grond | 22.13 Uniformat (Uniformat) | 429.8 | 2415 | 2430 | 22_DAT_binnenwand_125 HPL | 2 | Walls | Non-bearing | Lichte scheidingswand 125mmAan weerszijden gipsvezelplaat 12,5mmGipsplaat 12,5mm Met daartussen 75mm ms wand gevuld met isolatieVulling afhankelijk van gestelde eisen ingeluidsrapportage | 22.13 |  |  | 22.13 | binnenwanden; niet constructief, systeemwanden; vast | Lichte scheidingswand 125mmAan weerszijden gipsvezelplaat 12,5mmGipsplaat 12,5mm Met daartussen 75mm ms wand gevuld met isolatieVulling afhankelijk van gestelde eisen ingeluidsrapportage | Walls | Basic Wall | Basic Wall: 22_DAT_binnenwand_125 HPL | 22_DAT_binnenwand_125 HPL | 6329633 | 0 | no | yes | 0 | 0 | 2415 | 5.86845 | 2580 | Bouwkundig | 2. nieuwbouw | Non-bearing |  |  |  |  | Vertical | Dimensions - Volume: 0.733556 m3; Constraints - Base Extension Distance: 0 mm; Top Extension Distance: 0 mm; Location Line: Wall Centerline
Basic Wall:22_DAT_binnenwand_125:4966228 | 00 Begane grond | 22.13 Uniformat (Uniformat) | 240 | 790 | 790 | haspel slang 30m gen hxdxb 730x240x790 | 2 | Plumbing Fixtures |  |  |  |  |  | 59.20 |  | brandslanghaspel inbouw | Plumbing Fixtures | NLRS_59_PF_FB_brandslanghaspel inbouw_gen_ISR | NLRS_59_PF_FB_brandslanghaspel inbouw_gen_ISR: haspel slang 30m gen hxdxb 730x240x790 | haspel slang 30m gen hxdxb 730x240x790 | 4687182 |  |  |  |  |  |  | 1.00371 |  | Bouwkundig | 2. nieuwbouw | Constraints - Elevation from Level: 1195 mm; Host: Basic Wall : 22_DAT_binnenwand_125; Level: 0; Schedule Level: 0; Dimensions - NLRS_C_breedte: 790 mm; NLRS_C_diepte: 240 mm; NLRS_C_hoogte: 790 mm; Volume: 0.149784 m3; General - NLRS_P_c01_diameter: 22 mm; NLRS_P_c01_radius: 11 mm; Graphics - slang_bereik: no; Identity Data - Mark: 109; Mechanical - brandslanghaspel_kw_flow: 0.361 m3/s; System Classification: Domestic Cold Water
Basic Wall:22_DAT_binnenwand_125:589403 | 00 Begane grond | 22.13 Uniformat (Uniformat) |  | 2415 | 1436 | 22_DAT_binnenwand_125 | 2 | Lines: <Sketch> |  |  |  |  |  |  |  |  |  |  |  |  |  |  |  |  |  |  |  |  | 2415 | Bouwkundig | Pset_ProductRequirements - sets with these values: 2
Basic Wall:22_DAT_binnenwand_125 HPL:4966370:1 | 00 Begane grond | 22.13 Uniformat (Uniformat) |  |  |  | 22_DAT_binnenwand_125 HPL | 2 | Walls | Non-bearing | Lichte scheidingswand 125mmAan weerszijden gipsvezelplaat 12,5mmGipsplaat 12,5mm Met daartussen 75mm ms wand gevuld met isolatieVulling afhankelijk van gestelde eisen ingeluidsrapportage | 22.13 |  |  | 22.13 | binnenwanden; niet constructief, systeemwanden; vast | Lichte scheidingswand 125mmAan weerszijden gipsvezelplaat 12,5mmGipsplaat 12,5mm Met daartussen 75mm ms wand gevuld met isolatieVulling afhankelijk van gestelde eisen ingeluidsrapportage
Basic Wall:22_DAT_binnenwand_125 HPL:4966370 | 00 Begane grond | 22.13 Uniformat (Uniformat) | 429.8 | 2390 | 2000 | Merk H20 | 2 | Walls | Non-bearing | houten kozijn | 31.10 | houten kozijn | 31.10 | 31.10 | buitenwandopeningen; niet gevuld, algemeen (verzamelniveau) | houten kozijn | Walls | Curtain Wall | Curtain Wall: Merk H20 | Merk H20 | 5488219 | 0 | no | yes | 0 | 400 | 2390 | 4.78 | 2000 | Bouwkundig | 2. nieuwbouw | Non-bearing | 0 | Beginning | 4 | 2 | Vertical | Materials and Finishes - NLRS_C_Afwerking Kozijn: Kozijn Bamboo - Deur Bamboo
Basic Wall:22_DAT_binnenwand_125 HPL:4966370 | 00 Begane grond | 22.13 Uniformat (Uniformat) | 429.8 | 2390 | 2120 | Merk H14 | 2 | Walls | Non-bearing | houten kozijn | 31.10 | houten kozijn | 31.10 | 31.10 | buitenwandopeningen; niet gevuld, algemeen (verzamelniveau) | houten kozijn | Walls | Curtain Wall | Curtain Wall: Merk H14 | Merk H14 | 5142452 | 0 | no | yes | 0 | 400 | 2390 | 5.0668 | 2120 | Bouwkundig | 2. nieuwbouw | Non-bearing | 0 | Beginning | 4 | 2 | Vertical | Pset_wanden - NLRS_C_Geluidwering_DnTA: 25; NLRS_C_brandwerendheid: 30; Pset_kozijnen (CW) - NLRS_C_Geluidwering_DnTA: 25; NLRS_C_brandwerendheid: 30; Data - NLRS_C_Geluidwering_DnTA: 25; Materials and Finishes - NLRS_C_Afwerking Kozijn: Kozijn Bamboo - Deur Bamboo; Fire Protection - NLRS_C_brandwerendheid: 30
Basic Wall:22_DAT_binnenwand_125:4967195 | -1 Speelvloer | 22.13 Uniformat (Uniformat) | 429.8 | 2650 | 2080 | Merk H22 | 2 | Walls | Non-bearing | houten kozijn | 31.10 | houten kozijn | 31.10 | 31.10 | buitenwandopeningen; niet gevuld, algemeen (verzamelniveau) | houten kozijn | Walls | Curtain Wall | Curtain Wall: Merk H22 | Merk H22 | 5490352 | 0 | no | yes | V-1 | 400 | 2650 | 5.512 | 2080 | Bouwkundig | 2. nieuwbouw | Non-bearing | 0 | Beginning | 4 | 2 | Vertical | Materials and Finishes - NLRS_C_Afwerking Kozijn: Ral 9010 - Deur HPL Formica F2296 Sno White
Basic Wall:22_DAT_binnenwand_125:4973618 | 00 Begane grond | 22.13 Uniformat (Uniformat) | 429.8 | 2390 | 1875 | Merk H14 | 2 | Walls | Non-bearing | houten kozijn | 31.10 | houten kozijn | 31.10 | 31.10 | buitenwandopeningen; niet gevuld, algemeen (verzamelniveau) | houten kozijn | Walls | Curtain Wall | Curtain Wall: Merk H14 | Merk H14 | 5142452 | 0 | no | yes | 0 | 400 | 2390 | 4.48125 | 1875 | Bouwkundig | 2. nieuwbouw | Non-bearing | 0 | Beginning | 4 | 2 | Vertical | Pset_wanden - NLRS_C_Geluidwering_DnTA: 25; Pset_kozijnen (CW) - NLRS_C_Geluidwering_DnTA: 25; Data - NLRS_C_Geluidwering_DnTA: 25; Materials and Finishes - NLRS_C_Afwerking Kozijn: Kozijn Bamboo - Deur Bamboo
Basic Wall:22_DAT_binnenwand_125:4974016 | 00 Begane grond | 22.13 Uniformat (Uniformat) | 429.8 | 1190 | 550 | Merk H17 | 2 | Walls | Non-bearing | houten kozijn | 31.10 | houten kozijn | 31.10 | 31.10 | buitenwandopeningen; niet gevuld, algemeen (verzamelniveau) | houten kozijn | Walls | Curtain Wall | Curtain Wall: Merk H17 | Merk H17 | 6423568 | 900 | no | yes | 0 | 400 | 1190 | 0.6545 | 550 | Bouwkundig | 2. nieuwbouw | Non-bearing | 0 | Beginning | 4 | 2 | Vertical | Pset_wanden - NLRS_C_Geluidwering_DnTA: 25; Pset_kozijnen (CW) - NLRS_C_Geluidwering_DnTA: 25; Data - NLRS_C_Geluidwering_DnTA: 25; Materials and Finishes - NLRS_C_Afwerking Kozijn: Ral 9010 - Deur HPL Formica F2296 Sno White
2 x Basic Wall:22_DAT_binnenwand_125:4974016 | 00 Begane grond | 22.13 Uniformat (Uniformat) | 429.8 | 1190 | 550 | Merk H17 | 2 | Walls | Non-bearing | houten kozijn | 31.10 | houten kozijn | 31.10 | 31.10 | buitenwandopeningen; niet gevuld, algemeen (verzamelniveau) | houten kozijn | Walls | Curtain Wall | Curtain Wall: Merk H17 | Merk H17 | 6423568 | 900 | no | yes | 0 | 400 | 1190 | 0.6545 | 550 | Bouwkundig | 2. nieuwbouw | Non-bearing | 0 | Beginning | 4 | 2 | Vertical | Pset_wanden - NLRS_C_Geluidwering_DnTA: 39; Pset_kozijnen (CW) - NLRS_C_Geluidwering_DnTA: 39; Data - NLRS_C_Geluidwering_DnTA: 39; Materials and Finishes - NLRS_C_Afwerking Kozijn: Ral 9010 - Deur HPL Formica F2296 Sno White
Basic Wall:22_DAT_binnenwand_125:4974067 | 00 Begane grond | 22.13 Uniformat (Uniformat) | 429.8 | 1190 | 550 | Merk H17 | 2 | Walls | Non-bearing | houten kozijn | 31.10 | houten kozijn | 31.10 | 31.10 | buitenwandopeningen; niet gevuld, algemeen (verzamelniveau) | houten kozijn | Walls | Curtain Wall | Curtain Wall: Merk H17 | Merk H17 | 6423568 | 900 | no | yes | 0 | 400 | 1190 | 0.6545 | 550 | Bouwkundig | 2. nieuwbouw | Non-bearing | 0 | Beginning | 4 | 2 | Vertical | Pset_wanden - NLRS_C_Geluidwering_DnTA: 39; Pset_kozijnen (CW) - NLRS_C_Geluidwering_DnTA: 39; Data - NLRS_C_Geluidwering_DnTA: 39; Materials and Finishes - NLRS_C_Afwerking Kozijn: Ral 9010 - Deur HPL Formica F2296 Sno White
Basic Wall:22_DAT_binnenwand_125:4974273 | 00 Begane grond | 22.13 Uniformat (Uniformat) | 429.8 | 2390 | 1034 | Merk H16 | 2 | Walls | Non-bearing | houten kozijn | 31.10 | houten kozijn | 31.10 | 31.10 | buitenwandopeningen; niet gevuld, algemeen (verzamelniveau) | houten kozijn | Walls | Curtain Wall | Curtain Wall: Merk H16 | Merk H16 | 6103248 | 0 | no | yes | 0 | 400 | 2390 | 2.47126 | 1034 | Bouwkundig | 2. nieuwbouw | Non-bearing | 0 | Beginning | 4 | 2 | Vertical | Pset_wanden - NLRS_C_Geluidwering_DnTA: 39; Pset_kozijnen (CW) - NLRS_C_Geluidwering_DnTA: 39; Kozijnmerk: S; NLRS_C_gespiegeld: S; Data - NLRS_C_Geluidwering_DnTA: 39; NLRS_C_gespiegeld: S; Materials and Finishes - NLRS_C_Afwerking Kozijn: Ral 9010 - Deur HPL Formica F2296 Sno White
Basic Wall:22_DAT_binnenwand_125:4974572 | 00 Begane grond | 22.13 Uniformat (Uniformat) | 429.8 | 2390 | 1034 | Merk H16 | 2 | Walls | Non-bearing | houten kozijn | 31.10 | houten kozijn | 31.10 | 31.10 | buitenwandopeningen; niet gevuld, algemeen (verzamelniveau) | houten kozijn | Walls | Curtain Wall | Curtain Wall: Merk H16 | Merk H16 | 6103248 | 0 | no | yes | 0 | 400 | 2390 | 2.47126 | 1034 | Bouwkundig | 2. nieuwbouw | Non-bearing | 0 | Beginning | 4 | 2 | Vertical | Pset_wanden - NLRS_C_Geluidwering_DnTA: 39; Pset_kozijnen (CW) - NLRS_C_Geluidwering_DnTA: 39; Data - NLRS_C_Geluidwering_DnTA: 39; Materials and Finishes - NLRS_C_Afwerking Kozijn: Ral 9010 - Deur HPL Formica F2296 Sno White
Basic Wall:22_DAT_binnenwand_125:4976702 | 00 Begane grond | 22.13 Uniformat (Uniformat) | 429.8 | 600 | 2710 | Merk H08 | 2 | Walls | Non-bearing | houten kozijn | 31.10 | houten kozijn | 31.10 | 31.10 | buitenwandopeningen; niet gevuld, algemeen (verzamelniveau) | houten kozijn | Walls | Curtain Wall | Curtain Wall: Merk H08 | Merk H08 | 5145389 | 1200 | no | yes | 0 | 400 | 600 | 1.626 | 2710 | Bouwkundig | 2. nieuwbouw | Non-bearing | 0 | Beginning | 4 | 2 | Vertical | Pset_wanden - NLRS_C_Geluidwering_DnTA: 31; Pset_kozijnen (CW) - NLRS_C_Geluidwering_DnTA: 31; Data - NLRS_C_Geluidwering_DnTA: 31; Materials and Finishes - NLRS_C_Afwerking Kozijn: Kozijn Bamboo - Deur Bamboo
Basic Wall:22_DAT_binnenwand_125:4976702 | 00 Begane grond | 22.13 Uniformat (Uniformat) | 429.8 | 2390 | 1134 | Merk H09 | 2 | Walls | Non-bearing | houten kozijn | 31.10 | houten kozijn | 31.10 | 31.10 | buitenwandopeningen; niet gevuld, algemeen (verzamelniveau) | houten kozijn | Walls | Curtain Wall | Curtain Wall: Merk H09 | Merk H09 | 5149044 | 0 | no | yes | 0 | 400 | 2390 | 2.71026 | 1134 | Bouwkundig | 2. nieuwbouw | Non-bearing | 0 | Beginning | 4 | 2 | Vertical | Pset_wanden - NLRS_C_Geluidwering_DnTA: 31; Pset_kozijnen (CW) - NLRS_C_Geluidwering_DnTA: 31; Data - NLRS_C_Geluidwering_DnTA: 31; Materials and Finishes - NLRS_C_Afwerking Kozijn: Kozijn Bamboo - Deur Bamboo
Basic Wall:22_DAT_binnenwand_125:4976702 | 00 Begane grond | 22.13 Uniformat (Uniformat) | 429.8 | 2415 | 3910 | 22_DAT_binnenwand_125 HPL dubbel | 2 | Walls | Non-bearing | Lichte scheidingswand 125mmAan weerszijden gipsvezelplaat 12,5mmGipsplaat 12,5mm Met daartussen 75mm ms wand gevuld met isolatieVulling afhankelijk van gestelde eisen ingeluidsrapportage | 22.13 |  |  | 22.13 | binnenwanden; niet constructief, systeemwanden; vast | Lichte scheidingswand 125mmAan weerszijden gipsvezelplaat 12,5mmGipsplaat 12,5mm Met daartussen 75mm ms wand gevuld met isolatieVulling afhankelijk van gestelde eisen ingeluidsrapportage | Walls | Basic Wall | Basic Wall: 22_DAT_binnenwand_125 HPL dubbel | 22_DAT_binnenwand_125 HPL dubbel | 6394901 | 0 | no | yes | 0 | 0 | 2415 | 5.10639 | 3972.5 | Bouwkundig | 2. nieuwbouw | Non-bearing |  |  |  |  | Vertical | Dimensions - Volume: 0.638299 m3; Constraints - Base Extension Distance: 0 mm; Top Extension Distance: 0 mm; Location Line: Wall Centerline
Basic Wall:22_DAT_binnenwand_125:4976978 | 00 Begane grond | 22.13 Uniformat (Uniformat) | 429.8 | 1190 | 600 | Merk H05 | 2 | Walls | Non-bearing | houten kozijn | 31.10 | houten kozijn | 31.10 | 31.10 | buitenwandopeningen; niet gevuld, algemeen (verzamelniveau) | houten kozijn | Walls | Curtain Wall | Curtain Wall: Merk H05 | Merk H05 | 5132093 | 1200 | no | yes | 0 | 400 | 1190 | 0.714 | 600 | Bouwkundig | 2. nieuwbouw | Non-bearing | 0 | Beginning | 4 | 2 | Vertical | Pset_wanden - NLRS_C_Geluidwering_DnTA: 39; Pset_kozijnen (CW) - NLRS_C_Geluidwering_DnTA: 39; Data - NLRS_C_Geluidwering_DnTA: 39; Materials and Finishes - NLRS_C_Afwerking Kozijn: Ral 9010 - Deur HPL Formica F2296 Sno White; Group: Model Group:WC_V0:4976980
Basic Wall:22_DAT_binnenwand_125:4976981 | 00 Begane grond | 22.13 Uniformat (Uniformat) | 429.8 | 2390 | 1034 | Merk H01 | 2 | Walls | Non-bearing | houten kozijn | 31.10 | houten kozijn | 31.10 | 31.10 | buitenwandopeningen; niet gevuld, algemeen (verzamelniveau) | houten kozijn | Walls | Curtain Wall | Curtain Wall: Merk H01 | Merk H01 | 5121256 | 0 | no | yes | 0 | 400 | 2390 | 2.47126 | 1034 | Bouwkundig | 2. nieuwbouw | Non-bearing | 0 | Beginning | 4 | 2 | Vertical | Pset_wanden - NLRS_C_Geluidwering_DnTA: 33; Pset_kozijnen (CW) - NLRS_C_Geluidwering_DnTA: 33; Data - NLRS_C_Geluidwering_DnTA: 33; Materials and Finishes - NLRS_C_Afwerking Kozijn: Ral 9010 - Deur HPL Formica F2296 Sno White; Group: Model Group:WC_V0:4976980
Basic Wall:22_DAT_binnenwand_125:4977291 | 00 Begane grond | 22.13 Uniformat (Uniformat) | 429.8 | 1190 | 600 | Merk H05 | 2 | Walls | Non-bearing | houten kozijn | 31.10 | houten kozijn | 31.10 | 31.10 | buitenwandopeningen; niet gevuld, algemeen (verzamelniveau) | houten kozijn | Walls | Curtain Wall | Curtain Wall: Merk H05 | Merk H05 | 5132093 | 1200 | no | yes | 0 | 400 | 1190 | 0.714 | 600 | Bouwkundig | 2. nieuwbouw | Non-bearing | 0 | Beginning | 4 | 2 | Vertical | Pset_wanden - NLRS_C_Geluidwering_DnTA: 39; Pset_kozijnen (CW) - NLRS_C_Geluidwering_DnTA: 39; Data - NLRS_C_Geluidwering_DnTA: 39; Materials and Finishes - NLRS_C_Afwerking Kozijn: Ral 9010 - Deur HPL Formica F2296 Sno White; Group: Model Group:WC_V0:4977293
Basic Wall:22_DAT_binnenwand_125:4977294 | 00 Begane grond | 22.13 Uniformat (Uniformat) | 429.8 | 2390 | 1034 | Merk H01 | 2 | Walls | Non-bearing | houten kozijn | 31.10 | houten kozijn | 31.10 | 31.10 | buitenwandopeningen; niet gevuld, algemeen (verzamelniveau) | houten kozijn | Walls | Curtain Wall | Curtain Wall: Merk H01 | Merk H01 | 5121256 | 0 | no | yes | 0 | 400 | 2390 | 2.47126 | 1034 | Bouwkundig | 2. nieuwbouw | Non-bearing | 0 | Beginning | 4 | 2 | Vertical | Pset_wanden - NLRS_C_Geluidwering_DnTA: 33; Pset_kozijnen (CW) - NLRS_C_Geluidwering_DnTA: 33; Data - NLRS_C_Geluidwering_DnTA: 33; Materials and Finishes - NLRS_C_Afwerking Kozijn: Ral 9010 - Deur HPL Formica F2296 Sno White; Group: Model Group:WC_V0:4977293
Basic Wall:22_DAT_binnenwand_125:4977396 | 00 Begane grond | 22.13 Uniformat (Uniformat) | 429.8 | 1190 | 600 | Merk H05 | 2 | Walls | Non-bearing | houten kozijn | 31.10 | houten kozijn | 31.10 | 31.10 | buitenwandopeningen; niet gevuld, algemeen (verzamelniveau) | houten kozijn | Walls | Curtain Wall | Curtain Wall: Merk H05 | Merk H05 | 5132093 | 1200 | no | yes | 0 | 400 | 1190 | 0.714 | 600 | Bouwkundig | 2. nieuwbouw | Non-bearing | 0 | Beginning | 4 | 2 | Vertical | Pset_wanden - NLRS_C_Geluidwering_DnTA: 39; Pset_kozijnen (CW) - NLRS_C_Geluidwering_DnTA: 39; Data - NLRS_C_Geluidwering_DnTA: 39; Materials and Finishes - NLRS_C_Afwerking Kozijn: Ral 9010 - Deur HPL Formica F2296 Sno White; Group: Model Group:WC_V0:4977398
Basic Wall:22_DAT_binnenwand_125:4977399 | 00 Begane grond | 22.13 Uniformat (Uniformat) | 429.8 | 2390 | 1034 | Merk H01 | 2 | Walls | Non-bearing | houten kozijn | 31.10 | houten kozijn | 31.10 | 31.10 | buitenwandopeningen; niet gevuld, algemeen (verzamelniveau) | houten kozijn | Walls | Curtain Wall | Curtain Wall: Merk H01 | Merk H01 | 5121256 | 0 | no | yes | 0 | 400 | 2390 | 2.47126 | 1034 | Bouwkundig | 2. nieuwbouw | Non-bearing | 0 | Beginning | 4 | 2 | Vertical | Pset_wanden - NLRS_C_Geluidwering_DnTA: 33; Pset_kozijnen (CW) - NLRS_C_Geluidwering_DnTA: 33; Data - NLRS_C_Geluidwering_DnTA: 33; Materials and Finishes - NLRS_C_Afwerking Kozijn: Ral 9010 - Deur HPL Formica F2296 Sno White; Group: Model Group:WC_V0:4977398
Basic Wall:22_DAT_binnenwand_125:4978685 | 00 Begane grond | 22.13 Uniformat (Uniformat) | 429.8 | 2390 | 1980 | Merk H07 | 2 | Walls | Non-bearing | houten kozijn | 31.10 | houten kozijn | 31.10 | 31.10 | buitenwandopeningen; niet gevuld, algemeen (verzamelniveau) | houten kozijn | Walls | Curtain Wall | Curtain Wall: Merk H07 | Merk H07 | 5144215 | 0 | no | yes | 0 | 400 | 2390 | 4.7322 | 1980 | Bouwkundig | 2. nieuwbouw | Non-bearing | 0 | Beginning | 4 | 2 | Vertical | Pset_wanden - NLRS_C_Geluidwering_DnTA: 38; Pset_kozijnen (CW) - NLRS_C_Geluidwering_DnTA: 38; Data - NLRS_C_Geluidwering_DnTA: 38; Materials and Finishes - NLRS_C_Afwerking Kozijn: Ral 9010 - Deur HPL Formica F2296 Sno White
Basic Wall:22_DAT_binnenwand_125 HPL dubbel:4979798 | 00 Begane grond | 22.13 Uniformat (Uniformat) | 429.8 | 600 | 2710 | Merk H08 | 2 | Walls | Non-bearing | houten kozijn | 31.10 | houten kozijn | 31.10 | 31.10 | buitenwandopeningen; niet gevuld, algemeen (verzamelniveau) | houten kozijn | Walls | Curtain Wall | Curtain Wall: Merk H08 | Merk H08 | 5145389 | 1200 | no | yes | 0 | 400 | 600 | 1.626 | 2710 | Bouwkundig | 2. nieuwbouw | Non-bearing | 0 | Beginning | 4 | 2 | Vertical | Pset_wanden - NLRS_C_Geluidwering_DnTA: 31; Pset_kozijnen (CW) - NLRS_C_Geluidwering_DnTA: 31; Data - NLRS_C_Geluidwering_DnTA: 31; Materials and Finishes - NLRS_C_Afwerking Kozijn: Kozijn Bamboo - Deur Bamboo
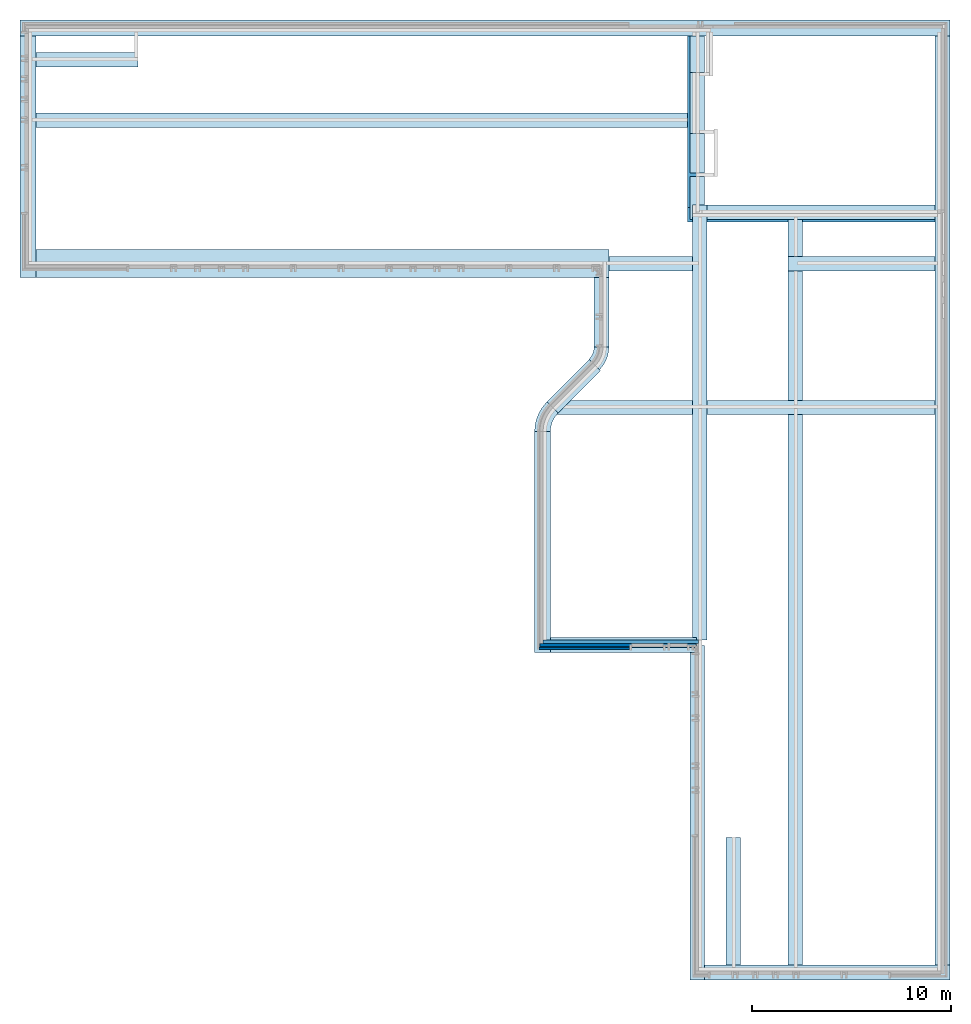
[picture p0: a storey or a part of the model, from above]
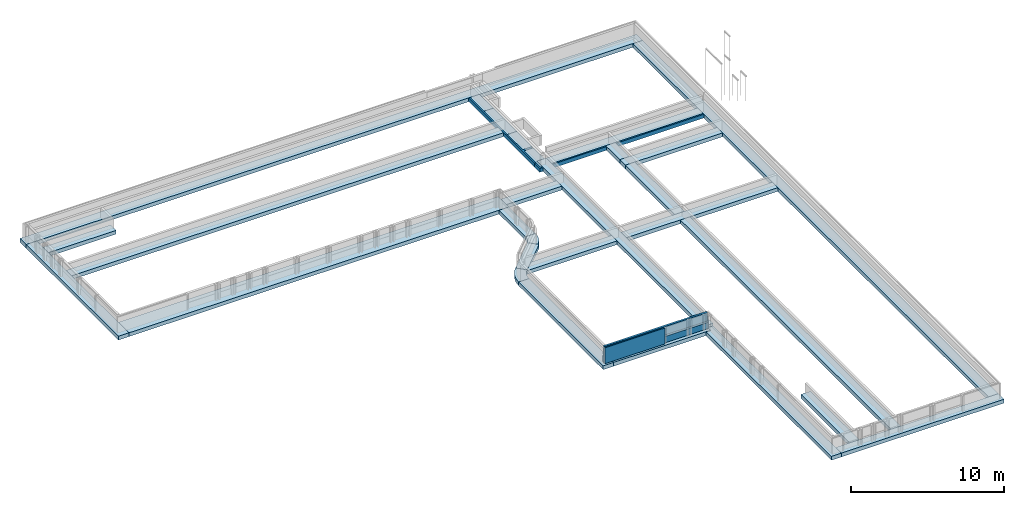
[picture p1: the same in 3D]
Properties of the parts of a building model (IFC2X3), part 21 of 37

# IfcOpeningElement: Opening (1092)
Name | In | Classification | Depth (mm) | BaseQuantities, Height (mm) | BaseQuantities, Width (mm) | Reference | Pset_OpeningElementCommon, sets with these values | Pset_ProductRequirements, Category | Pset_wanden, Structural Usage | Pset_wanden, Omschrijving | Pset_wanden, NL-sfb-Codering | Pset_kozijnen (CW), Omschrijving | Pset_kozijnen (CW), NL-sfb-Codering | Pset_DAT_KMS, Assembly Code | Pset_DAT_KMS, Assembly Description | Pset_DAT_KMS, Description | Other, Category | Family | Other, Family and Type | Type | Type Id | Base Offset (mm) | Base is Attached = Related to Mass = Top is Attached = Structural | Room Bounding | Base Constraint | Top Offset (mm) | Unconnected Height (mm) | Dimensions, Area (m2) | Length (mm) | Identity Data, Workset | Phase Created | Structural, Structural Usage | Angle (deg) = Offset (mm) | Justification | Number | Horizontal Grid, sets with these values | Cross-Section
Basic Wall:22_DAT_binnenwand_125 HPL dubbel:4979798 | 00 Begane grond | 22.13 Uniformat (Uniformat) | 429.8 | 2390 | 1134 | Merk H09 | 2 | Walls | Non-bearing | houten kozijn | 31.10 | houten kozijn | 31.10 | 31.10 | buitenwandopeningen; niet gevuld, algemeen (verzamelniveau) | houten kozijn | Walls | Curtain Wall | Curtain Wall: Merk H09 | Merk H09 | 5149044 | 0 | no | yes | 0 | 400 | 2390 | 2.71026 | 1134 | Bouwkundig | 2. nieuwbouw | Non-bearing | 0 | Beginning | 4 | 2 | Vertical | Pset_wanden - NLRS_C_Geluidwering_DnTA: 31; Pset_kozijnen (CW) - NLRS_C_Geluidwering_DnTA: 31; Data - NLRS_C_Geluidwering_DnTA: 31; Materials and Finishes - NLRS_C_Afwerking Kozijn: Kozijn Bamboo - Deur Bamboo
Basic Wall:22_DAT_binnenwand_125 HPL dubbel:4979938 | 00 Begane grond | 22.13 Uniformat (Uniformat) | 429.8 | 2390 | 1134 | Merk H09 | 2 | Walls | Non-bearing | houten kozijn | 31.10 | houten kozijn | 31.10 | 31.10 | buitenwandopeningen; niet gevuld, algemeen (verzamelniveau) | houten kozijn | Walls | Curtain Wall | Curtain Wall: Merk H09 | Merk H09 | 5149044 | 0 | no | yes | 0 | 400 | 2390 | 2.71026 | 1134 | Bouwkundig | 2. nieuwbouw | Non-bearing | 0 | Beginning | 4 | 2 | Vertical | Pset_wanden - NLRS_C_Geluidwering_DnTA: 31; Pset_kozijnen (CW) - NLRS_C_Geluidwering_DnTA: 31; Data - NLRS_C_Geluidwering_DnTA: 31; Materials and Finishes - NLRS_C_Afwerking Kozijn: Kozijn Bamboo - Deur Bamboo
Basic Wall:22_DAT_binnenwand_125 HPL dubbel:4979938 | 00 Begane grond | 22.13 Uniformat (Uniformat) | 429.8 | 600 | 2710 | Merk H08 | 2 | Walls | Non-bearing | houten kozijn | 31.10 | houten kozijn | 31.10 | 31.10 | buitenwandopeningen; niet gevuld, algemeen (verzamelniveau) | houten kozijn | Walls | Curtain Wall | Curtain Wall: Merk H08 | Merk H08 | 5145389 | 1200 | no | yes | 0 | 400 | 600 | 1.626 | 2710 | Bouwkundig | 2. nieuwbouw | Non-bearing | 0 | Beginning | 4 | 2 | Vertical | Pset_wanden - NLRS_C_Geluidwering_DnTA: 31; Pset_kozijnen (CW) - NLRS_C_Geluidwering_DnTA: 31; Data - NLRS_C_Geluidwering_DnTA: 31; Materials and Finishes - NLRS_C_Afwerking Kozijn: Kozijn Bamboo - Deur Bamboo
Basic Wall:22_DAT_binnenwand_125 HPL dubbel:4980018 | 00 Begane grond | 22.13 Uniformat (Uniformat) | 429.8 | 2390 | 1134 | Merk H09 | 2 | Walls | Non-bearing | houten kozijn | 31.10 | houten kozijn | 31.10 | 31.10 | buitenwandopeningen; niet gevuld, algemeen (verzamelniveau) | houten kozijn | Walls | Curtain Wall | Curtain Wall: Merk H09 | Merk H09 | 5149044 | 0 | no | yes | 0 | 400 | 2390 | 2.71026 | 1134 | Bouwkundig | 2. nieuwbouw | Non-bearing | 0 | Beginning | 4 | 2 | Vertical | Pset_wanden - NLRS_C_Geluidwering_DnTA: 31; Pset_kozijnen (CW) - NLRS_C_Geluidwering_DnTA: 31; Data - NLRS_C_Geluidwering_DnTA: 31; Materials and Finishes - NLRS_C_Afwerking Kozijn: Kozijn Bamboo - Deur Bamboo
Basic Wall:22_DAT_binnenwand_125 HPL dubbel:4980018 | 00 Begane grond | 22.13 Uniformat (Uniformat) | 429.8 | 600 | 2710 | Merk H08 | 2 | Walls | Non-bearing | houten kozijn | 31.10 | houten kozijn | 31.10 | 31.10 | buitenwandopeningen; niet gevuld, algemeen (verzamelniveau) | houten kozijn | Walls | Curtain Wall | Curtain Wall: Merk H08 | Merk H08 | 5145389 | 1200 | no | yes | 0 | 400 | 600 | 1.626 | 2710 | Bouwkundig | 2. nieuwbouw | Non-bearing | 0 | Beginning | 4 | 2 | Vertical | Pset_wanden - NLRS_C_Geluidwering_DnTA: 31; Pset_kozijnen (CW) - NLRS_C_Geluidwering_DnTA: 31; Data - NLRS_C_Geluidwering_DnTA: 31; Materials and Finishes - NLRS_C_Afwerking Kozijn: Kozijn Bamboo - Deur Bamboo
Basic Wall:22_DAT_binnenwand_125:4980749 | 00 Begane grond | 22.13 Uniformat (Uniformat) | 429.8 | 2390 | 1034 | Merk H02 | 2 | Walls | Non-bearing | houten kozijn | 31.10 | houten kozijn | 31.10 | 31.10 | buitenwandopeningen; niet gevuld, algemeen (verzamelniveau) | houten kozijn | Walls | Curtain Wall | Curtain Wall: Merk H02 | Merk H02 | 5128107 | 0 | no | yes | 0 | 400 | 2390 | 2.47126 | 1034 | Bouwkundig | 2. nieuwbouw | Non-bearing | 0 | Beginning | 4 | 2 | Vertical | Pset_wanden - NLRS_C_Geluidwering_DnTA: 25; Pset_kozijnen (CW) - NLRS_C_Geluidwering_DnTA: 25; Data - NLRS_C_Geluidwering_DnTA: 25; Materials and Finishes - NLRS_C_Afwerking Kozijn: Ral 9010 - Deur HPL Formica F2296 Sno White
Floor:23_kanaalplaatvloer_260:4680220 | 00 Begane grond | 23.21 Uniformat (Uniformat) |  | 1260 | 1025 | 23_kanaalplaatvloer_260 | 2 | Shaft Openings |  |  |  |  |  |  |  |  |  |  |  |  |  | -460.475 |  |  | 1 | -51.3805 | 3909.09 |  |  | Bouwkundig | 2. nieuwbouw | Pset_ProductRequirements - sets with these values: 2; Constraints - Top Constraint: Up to level: 2
Floor:23_kanaalplaatvloer_260:4680220 | 00 Begane grond | 23.21 Uniformat (Uniformat) |  | 1035.01 | 1260 | 23_kanaalplaatvloer_260 | 2 | Shaft Openings |  |  |  |  |  |  |  |  |  |  |  |  |  | -429.032 |  |  | 1 | -43.4417 | 3885.59 |  |  | Bouwkundig | 2. nieuwbouw | Pset_ProductRequirements - sets with these values: 2; Constraints - Top Constraint: Up to level: 2
Floor:23_kanaalplaatvloer_260:4680220 | 00 Begane grond | 23.21 Uniformat (Uniformat) |  | 1075 | 415 | 23_kanaalplaatvloer_260 | 2 | Shaft Openings |  |  |  |  |  |  |  |  |  |  |  |  |  | -532.351 |  |  | 1 | -20.0012 | 4012.35 |  |  | Bouwkundig | 2. nieuwbouw | Pset_ProductRequirements - sets with these values: 2; Constraints - Top Constraint: Up to level: 2
Floor:23_kanaalplaatvloer_260:4680220 | 00 Begane grond | 23.21 Uniformat (Uniformat) |  |  |  | 23_kanaalplaatvloer_260 | 2 | Shaft Openings |  |  |  |  |  |  |  |  |  |  |  |  |  | 0 |  |  | V-1 | 1500 | 5750 |  |  | Bouwkundig | 2. nieuwbouw | Pset_ProductRequirements - sets with these values: 2; Constraints - Top Constraint: Up to level: 1; BaseQuantities - Area: 0.0929251 m2
Floor:23_kanaalplaatvloer_260:4680220 | 00 Begane grond | 23.21 Uniformat (Uniformat) |  | 150 | 845 | 23_kanaalplaatvloer_260 | 2 | Shaft Openings |  |  |  |  |  |  |  |  |  |  |  |  |  | 0 |  |  | 0 | 0 | 3650 |  |  | Bouwkundig | 2. nieuwbouw | Pset_ProductRequirements - sets with these values: 2; Constraints - Top Constraint: Up to level: 1
Floor:23_Gewapende Druklaag:5024859 | 01 eerste verdieping | 23.10 Uniformat (Uniformat) |  | 1260 | 1025 | 23_Gewapende Druklaag | 2 | Shaft Openings |  |  |  |  |  |  |  |  |  |  |  |  |  | -460.475 |  |  | 1 | -51.3805 | 3909.09 |  |  | Bouwkundig | 2. nieuwbouw | Pset_ProductRequirements - sets with these values: 2; Constraints - Top Constraint: Up to level: 2
Floor:23_Gewapende Druklaag:5024859 | 01 eerste verdieping | 23.10 Uniformat (Uniformat) |  | 1035.01 | 1260 | 23_Gewapende Druklaag | 2 | Shaft Openings |  |  |  |  |  |  |  |  |  |  |  |  |  | -429.032 |  |  | 1 | -43.4417 | 3885.59 |  |  | Bouwkundig | 2. nieuwbouw | Pset_ProductRequirements - sets with these values: 2; Constraints - Top Constraint: Up to level: 2
Floor:23_Gewapende Druklaag:5024859 | 01 eerste verdieping | 23.10 Uniformat (Uniformat) |  | 1075 | 415 | 23_Gewapende Druklaag | 2 | Shaft Openings |  |  |  |  |  |  |  |  |  |  |  |  |  | -532.351 |  |  | 1 | -20.0012 | 4012.35 |  |  | Bouwkundig | 2. nieuwbouw | Pset_ProductRequirements - sets with these values: 2; Constraints - Top Constraint: Up to level: 2
Floor:23_Gewapende Druklaag:5024859 | 01 eerste verdieping | 23.10 Uniformat (Uniformat) |  |  |  | 23_Gewapende Druklaag | 2 | Shaft Openings |  |  |  |  |  |  |  |  |  |  |  |  |  | 0 |  |  | V-1 | 1500 | 5750 |  |  | Bouwkundig | 2. nieuwbouw | Pset_ProductRequirements - sets with these values: 2; Constraints - Top Constraint: Up to level: 1; BaseQuantities - Area: 0.0929251 m2
Floor:23_Gewapende Druklaag:5024859 | 01 eerste verdieping | 23.10 Uniformat (Uniformat) |  | 150 | 845 | 23_Gewapende Druklaag | 2 | Shaft Openings |  |  |  |  |  |  |  |  |  |  |  |  |  | 0 |  |  | 0 | 0 | 3650 |  |  | Bouwkundig | 2. nieuwbouw | Pset_ProductRequirements - sets with these values: 2; Constraints - Top Constraint: Up to level: 1
Floor:23_Zwevende dekvloer 90mm:5024974 | 01 eerste verdieping | 23.10 Uniformat (Uniformat) |  | 1260 | 1025 | 23_Zwevende dekvloer 90mm | 2 | Shaft Openings |  |  |  |  |  |  |  |  |  |  |  |  |  | -460.475 |  |  | 1 | -51.3805 | 3909.09 |  |  | Bouwkundig | 2. nieuwbouw | Pset_ProductRequirements - sets with these values: 2; Constraints - Top Constraint: Up to level: 2
Floor:23_Zwevende dekvloer 90mm:5024974 | 01 eerste verdieping | 23.10 Uniformat (Uniformat) |  | 1035.01 | 1260 | 23_Zwevende dekvloer 90mm | 2 | Shaft Openings |  |  |  |  |  |  |  |  |  |  |  |  |  | -429.032 |  |  | 1 | -43.4417 | 3885.59 |  |  | Bouwkundig | 2. nieuwbouw | Pset_ProductRequirements - sets with these values: 2; Constraints - Top Constraint: Up to level: 2
Floor:23_Zwevende dekvloer 90mm:5024974 | 01 eerste verdieping | 23.10 Uniformat (Uniformat) |  | 1075 | 415 | 23_Zwevende dekvloer 90mm | 2 | Shaft Openings |  |  |  |  |  |  |  |  |  |  |  |  |  | -532.351 |  |  | 1 | -20.0012 | 4012.35 |  |  | Bouwkundig | 2. nieuwbouw | Pset_ProductRequirements - sets with these values: 2; Constraints - Top Constraint: Up to level: 2
Floor:23_Zwevende dekvloer 90mm:5024974 | 01 eerste verdieping | 23.10 Uniformat (Uniformat) |  |  |  | 23_Zwevende dekvloer 90mm | 2 | Shaft Openings |  |  |  |  |  |  |  |  |  |  |  |  |  | 0 |  |  | V-1 | 1500 | 5750 |  |  | Bouwkundig | 2. nieuwbouw | Pset_ProductRequirements - sets with these values: 2; Constraints - Top Constraint: Up to level: 1; BaseQuantities - Area: 0.0929251 m2
Floor:23_kanaalplaatvloer_200:589345 | 01 eerste verdieping | 23.21 Uniformat (Uniformat) |  | 1260 | 1025 | 23_kanaalplaatvloer_200 | 2 | Shaft Openings |  |  |  |  |  |  |  |  |  |  |  |  |  | -460.475 |  |  | 1 | -51.3805 | 3909.09 |  |  | Bouwkundig | 2. nieuwbouw | Pset_ProductRequirements - sets with these values: 2; Constraints - Top Constraint: Up to level: 2
Floor:23_kanaalplaatvloer_200:589345 | 01 eerste verdieping | 23.21 Uniformat (Uniformat) |  | 1035.01 | 1260 | 23_kanaalplaatvloer_200 | 2 | Shaft Openings |  |  |  |  |  |  |  |  |  |  |  |  |  | -429.032 |  |  | 1 | -43.4417 | 3885.59 |  |  | Bouwkundig | 2. nieuwbouw | Pset_ProductRequirements - sets with these values: 2; Constraints - Top Constraint: Up to level: 2
Floor:23_kanaalplaatvloer_200:589345 | 01 eerste verdieping | 23.21 Uniformat (Uniformat) |  | 1075 | 415 | 23_kanaalplaatvloer_200 | 2 | Shaft Openings |  |  |  |  |  |  |  |  |  |  |  |  |  | -532.351 |  |  | 1 | -20.0012 | 4012.35 |  |  | Bouwkundig | 2. nieuwbouw | Pset_ProductRequirements - sets with these values: 2; Constraints - Top Constraint: Up to level: 2
Floor:23_kanaalplaatvloer_200:589345 | 01 eerste verdieping | 23.21 Uniformat (Uniformat) |  | 700 | 900 | 23_kanaalplaatvloer_200 | 2 | Lines: <Sketch> |  |  |  |  |  |  |  |  | Lines: <Sketch> |  |  |  |  |  |  |  |  |  |  |  | 700 | Constructie | Other - Concrete Cantilever: 0 mm; Steel Cantilever: 0 mm; Analytical Alignment - Alignment Method: Auto-Detect; In-Plane Projection: Floor/Slab Edge; Manually Adjusted: no; Constraints - Defines Constant Height: no; Defines Slope: no; Offset From Base: 0 mm; Dimensions - Slope: 4.76364
Floor:23_Gewapende Druklaag:5024859 | 02 tweede verdieping | 23.10 Uniformat (Uniformat) |  | 1260 | 1025 | 23_Gewapende Druklaag | 2 | Shaft Openings |  |  |  |  |  |  |  |  |  |  |  |  |  | -460.475 |  |  | 1 | -51.3805 | 3909.09 |  |  | Bouwkundig | 2. nieuwbouw | Pset_ProductRequirements - sets with these values: 2; Constraints - Top Constraint: Up to level: 2
Floor:23_Gewapende Druklaag:5024859 | 02 tweede verdieping | 23.10 Uniformat (Uniformat) |  | 1035.01 | 1260 | 23_Gewapende Druklaag | 2 | Shaft Openings |  |  |  |  |  |  |  |  |  |  |  |  |  | -429.032 |  |  | 1 | -43.4417 | 3885.59 |  |  | Bouwkundig | 2. nieuwbouw | Pset_ProductRequirements - sets with these values: 2; Constraints - Top Constraint: Up to level: 2
Floor:23_Gewapende Druklaag:5024859 | 02 tweede verdieping | 23.10 Uniformat (Uniformat) |  | 1075 | 415 | 23_Gewapende Druklaag | 2 | Shaft Openings |  |  |  |  |  |  |  |  |  |  |  |  |  | -532.351 |  |  | 1 | -20.0012 | 4012.35 |  |  | Bouwkundig | 2. nieuwbouw | Pset_ProductRequirements - sets with these values: 2; Constraints - Top Constraint: Up to level: 2
Floor:23_Gewapende Druklaag:5024859 | 02 tweede verdieping | 23.10 Uniformat (Uniformat) |  | 700 | 900 | 23_Gewapende Druklaag | 2 | Lines: <Sketch> |  |  |  |  |  |  |  |  | Lines: <Sketch> |  |  |  |  |  |  |  |  |  |  |  | 700 | Constructie | Other - Concrete Cantilever: 0 mm; Steel Cantilever: 0 mm; Analytical Alignment - Alignment Method: Auto-Detect; In-Plane Projection: Floor/Slab Edge; Manually Adjusted: no; Constraints - Defines Constant Height: no; Defines Slope: no; Offset From Base: 0 mm; Dimensions - Slope: 4.76364
Basic Wall:22_DAT_binnenwand_125:5035209 | 01 eerste verdieping | 22.13 Uniformat (Uniformat) | 429.8 | 3190 | 3270 | Merk H12 | 2 | Walls | Non-bearing | houten kozijn | 31.10 | houten kozijn | 31.10 | 31.10 | buitenwandopeningen; niet gevuld, algemeen (verzamelniveau) | houten kozijn | Walls | Curtain Wall | Curtain Wall: Merk H12 | Merk H12 | 5181526 | 0 | no | yes | 1 | 400 | 3190 | 10.4313 | 3270 | Bouwkundig | 2. nieuwbouw | Non-bearing | 0 | Beginning | 4 | 2 | Vertical | Pset_wanden - NLRS_C_Geluidwering_DnTA: 34; NLRS_C_brandwerendheid: 30; Pset_kozijnen (CW) - NLRS_C_Geluidwering_DnTA: 34; NLRS_C_brandwerendheid: 30; Data - NLRS_C_Geluidwering_DnTA: 34; Materials and Finishes - NLRS_C_Afwerking Kozijn: Ral 9010 - Deur HPL Formica F2296 Sno White; Fire Protection - NLRS_C_brandwerendheid: 30
Basic Wall:22_DAT_binnenwand_125 HPL dubbel:5035466 | 01 eerste verdieping | 22.13 Uniformat (Uniformat) | 429.8 | 600 | 2710 | Merk H08 | 2 | Walls | Non-bearing | houten kozijn | 31.10 | houten kozijn | 31.10 | 31.10 | buitenwandopeningen; niet gevuld, algemeen (verzamelniveau) | houten kozijn | Walls | Curtain Wall | Curtain Wall: Merk H08 | Merk H08 | 5145389 | 1200 | no | yes | 1 | 400 | 600 | 1.626 | 2710 | Bouwkundig | 2. nieuwbouw | Non-bearing | 0 | Beginning | 4 | 2 | Vertical | Pset_wanden - NLRS_C_Geluidwering_DnTA: 31; Pset_kozijnen (CW) - NLRS_C_Geluidwering_DnTA: 31; Data - NLRS_C_Geluidwering_DnTA: 31; Materials and Finishes - NLRS_C_Afwerking Kozijn: Kozijn Bamboo - Deur Bamboo
Basic Wall:22_DAT_binnenwand_125 HPL dubbel:5035466 | 01 eerste verdieping | 22.13 Uniformat (Uniformat) | 429.8 | 2390 | 1134 | Merk H09 | 2 | Walls | Non-bearing | houten kozijn | 31.10 | houten kozijn | 31.10 | 31.10 | buitenwandopeningen; niet gevuld, algemeen (verzamelniveau) | houten kozijn | Walls | Curtain Wall | Curtain Wall: Merk H09 | Merk H09 | 5149044 | 0 | no | yes | 1 | 400 | 2390 | 2.71026 | 1134 | Bouwkundig | 2. nieuwbouw | Non-bearing | 0 | Beginning | 4 | 2 | Vertical | Pset_wanden - NLRS_C_Geluidwering_DnTA: 31; Pset_kozijnen (CW) - NLRS_C_Geluidwering_DnTA: 31; Data - NLRS_C_Geluidwering_DnTA: 31; Materials and Finishes - NLRS_C_Afwerking Kozijn: Kozijn Bamboo - Deur Bamboo
Basic Wall:22_DAT_binnenwand_125:5035647 | 01 eerste verdieping | 22.13 Uniformat (Uniformat) | 429.8 | 1190 | 600 | Merk H05 | 2 | Walls | Non-bearing | houten kozijn | 31.10 | houten kozijn | 31.10 | 31.10 | buitenwandopeningen; niet gevuld, algemeen (verzamelniveau) | houten kozijn | Walls | Curtain Wall | Curtain Wall: Merk H05 | Merk H05 | 5132093 | 1200 | no | yes | 1 | 400 | 1190 | 0.714 | 600 | Bouwkundig | 2. nieuwbouw | Non-bearing | 0 | Beginning | 4 | 2 | Vertical | Pset_wanden - NLRS_C_Geluidwering_DnTA: 39; Pset_kozijnen (CW) - NLRS_C_Geluidwering_DnTA: 39; Data - NLRS_C_Geluidwering_DnTA: 39; Materials and Finishes - NLRS_C_Afwerking Kozijn: Ral 9010 - Deur HPL Formica F2296 Sno White; Group: Model Group:WC_V0:5035649
Basic Wall:22_DAT_binnenwand_125:5035650 | 01 eerste verdieping | 22.13 Uniformat (Uniformat) | 429.8 | 2390 | 1034 | Merk H01 | 2 | Walls | Non-bearing | houten kozijn | 31.10 | houten kozijn | 31.10 | 31.10 | buitenwandopeningen; niet gevuld, algemeen (verzamelniveau) | houten kozijn | Walls | Curtain Wall | Curtain Wall: Merk H01 | Merk H01 | 5121256 | 0 | no | yes | 1 | 400 | 2390 | 2.47126 | 1034 | Bouwkundig | 2. nieuwbouw | Non-bearing | 0 | Beginning | 4 | 2 | Vertical | Pset_wanden - NLRS_C_Geluidwering_DnTA: 33; Pset_kozijnen (CW) - NLRS_C_Geluidwering_DnTA: 33; Data - NLRS_C_Geluidwering_DnTA: 33; Materials and Finishes - NLRS_C_Afwerking Kozijn: Ral 9010 - Deur HPL Formica F2296 Sno White; Group: Model Group:WC_V0:5035649
Basic Wall:22_DAT_binnenwand_125:5035652 | 01 eerste verdieping | 22.13 Uniformat (Uniformat) | 429.8 | 1190 | 600 | Merk H05 | 2 | Walls | Non-bearing | houten kozijn | 31.10 | houten kozijn | 31.10 | 31.10 | buitenwandopeningen; niet gevuld, algemeen (verzamelniveau) | houten kozijn | Walls | Curtain Wall | Curtain Wall: Merk H05 | Merk H05 | 5132093 | 1200 | no | yes | 1 | 400 | 1190 | 0.714 | 600 | Bouwkundig | 2. nieuwbouw | Non-bearing | 0 | Beginning | 4 | 2 | Vertical | Pset_wanden - NLRS_C_Geluidwering_DnTA: 39; Pset_kozijnen (CW) - NLRS_C_Geluidwering_DnTA: 39; Data - NLRS_C_Geluidwering_DnTA: 39; Materials and Finishes - NLRS_C_Afwerking Kozijn: Ral 9010 - Deur HPL Formica F2296 Sno White
Basic Wall:22_DAT_binnenwand_125:5035655 | 01 eerste verdieping | 22.13 Uniformat (Uniformat) | 429.8 | 2390 | 1034 | Merk H01 | 2 | Walls | Non-bearing | houten kozijn | 31.10 | houten kozijn | 31.10 | 31.10 | buitenwandopeningen; niet gevuld, algemeen (verzamelniveau) | houten kozijn | Walls | Curtain Wall | Curtain Wall: Merk H01 | Merk H01 | 5121256 | 0 | no | yes | 1 | 400 | 2390 | 2.47126 | 1034 | Bouwkundig | 2. nieuwbouw | Non-bearing | 0 | Beginning | 4 | 2 | Vertical | Pset_wanden - NLRS_C_Geluidwering_DnTA: 33; Pset_kozijnen (CW) - NLRS_C_Geluidwering_DnTA: 33; Data - NLRS_C_Geluidwering_DnTA: 33; Materials and Finishes - NLRS_C_Afwerking Kozijn: Ral 9010 - Deur HPL Formica F2296 Sno White
Basic Wall:22_DAT_binnenwand_125:5035657 | 01 eerste verdieping | 22.13 Uniformat (Uniformat) | 429.8 | 1190 | 600 | Merk H05 | 2 | Walls | Non-bearing | houten kozijn | 31.10 | houten kozijn | 31.10 | 31.10 | buitenwandopeningen; niet gevuld, algemeen (verzamelniveau) | houten kozijn | Walls | Curtain Wall | Curtain Wall: Merk H05 | Merk H05 | 5132093 | 1200 | no | yes | 1 | 400 | 1190 | 0.714 | 600 | Bouwkundig | 2. nieuwbouw | Non-bearing | 0 | Beginning | 4 | 2 | Vertical | Pset_wanden - NLRS_C_Geluidwering_DnTA: 39; Pset_kozijnen (CW) - NLRS_C_Geluidwering_DnTA: 39; Data - NLRS_C_Geluidwering_DnTA: 39; Materials and Finishes - NLRS_C_Afwerking Kozijn: Ral 9010 - Deur HPL Formica F2296 Sno White; Group: Model Group:WC_V0:5035659
Basic Wall:22_DAT_binnenwand_125:5035660 | 01 eerste verdieping | 22.13 Uniformat (Uniformat) | 429.8 | 2390 | 1034 | Merk H01 | 2 | Walls | Non-bearing | houten kozijn | 31.10 | houten kozijn | 31.10 | 31.10 | buitenwandopeningen; niet gevuld, algemeen (verzamelniveau) | houten kozijn | Walls | Curtain Wall | Curtain Wall: Merk H01 | Merk H01 | 5121256 | 0 | no | yes | 1 | 400 | 2390 | 2.47126 | 1034 | Bouwkundig | 2. nieuwbouw | Non-bearing | 0 | Beginning | 4 | 2 | Vertical | Pset_wanden - NLRS_C_Geluidwering_DnTA: 33; Pset_kozijnen (CW) - NLRS_C_Geluidwering_DnTA: 33; Data - NLRS_C_Geluidwering_DnTA: 33; Materials and Finishes - NLRS_C_Afwerking Kozijn: Ral 9010 - Deur HPL Formica F2296 Sno White; Group: Model Group:WC_V0:5035659
Basic Wall:22_DAT_binnenwand_125 HPL dubbel:5035879 | 01 eerste verdieping | 22.13 Uniformat (Uniformat) | 429.8 | 600 | 2710 | Merk H08 | 2 | Walls | Non-bearing | houten kozijn | 31.10 | houten kozijn | 31.10 | 31.10 | buitenwandopeningen; niet gevuld, algemeen (verzamelniveau) | houten kozijn | Walls | Curtain Wall | Curtain Wall: Merk H08 | Merk H08 | 5145389 | 1200 | no | yes | 1 | 400 | 600 | 1.626 | 2710 | Bouwkundig | 2. nieuwbouw | Non-bearing | 0 | Beginning | 4 | 2 | Vertical | Pset_wanden - NLRS_C_Geluidwering_DnTA: 31; Pset_kozijnen (CW) - NLRS_C_Geluidwering_DnTA: 31; Data - NLRS_C_Geluidwering_DnTA: 31; Materials and Finishes - NLRS_C_Afwerking Kozijn: Kozijn Bamboo - Deur Bamboo
Basic Wall:22_DAT_binnenwand_125 HPL dubbel:5035879 | 01 eerste verdieping | 22.13 Uniformat (Uniformat) | 429.8 | 2390 | 1134 | Merk H09 | 2 | Walls | Non-bearing | houten kozijn | 31.10 | houten kozijn | 31.10 | 31.10 | buitenwandopeningen; niet gevuld, algemeen (verzamelniveau) | houten kozijn | Walls | Curtain Wall | Curtain Wall: Merk H09 | Merk H09 | 5149044 | 0 | no | yes | 1 | 400 | 2390 | 2.71026 | 1134 | Bouwkundig | 2. nieuwbouw | Non-bearing | 0 | Beginning | 4 | 2 | Vertical | Pset_wanden - NLRS_C_Geluidwering_DnTA: 31; Pset_kozijnen (CW) - NLRS_C_Geluidwering_DnTA: 31; Data - NLRS_C_Geluidwering_DnTA: 31; Materials and Finishes - NLRS_C_Afwerking Kozijn: Kozijn Bamboo - Deur Bamboo
Basic Wall:22_DAT_binnenwand_125 HPL dubbel:5035888 | 01 eerste verdieping | 22.13 Uniformat (Uniformat) | 429.8 | 2390 | 1134 | Merk H09 | 2 | Walls | Non-bearing | houten kozijn | 31.10 | houten kozijn | 31.10 | 31.10 | buitenwandopeningen; niet gevuld, algemeen (verzamelniveau) | houten kozijn | Walls | Curtain Wall | Curtain Wall: Merk H09 | Merk H09 | 5149044 | 0 | no | yes | 1 | 400 | 2390 | 2.71026 | 1134 | Bouwkundig | 2. nieuwbouw | Non-bearing | 0 | Beginning | 4 | 2 | Vertical | Pset_wanden - NLRS_C_Geluidwering_DnTA: 31; Pset_kozijnen (CW) - NLRS_C_Geluidwering_DnTA: 31; Data - NLRS_C_Geluidwering_DnTA: 31; Materials and Finishes - NLRS_C_Afwerking Kozijn: Kozijn Bamboo - Deur Bamboo
Basic Wall:22_DAT_binnenwand_125 HPL dubbel:5035888 | 01 eerste verdieping | 22.13 Uniformat (Uniformat) | 429.8 | 600 | 2710 | Merk H08 | 2 | Walls | Non-bearing | houten kozijn | 31.10 | houten kozijn | 31.10 | 31.10 | buitenwandopeningen; niet gevuld, algemeen (verzamelniveau) | houten kozijn | Walls | Curtain Wall | Curtain Wall: Merk H08 | Merk H08 | 5145389 | 1200 | no | yes | 1 | 400 | 600 | 1.626 | 2710 | Bouwkundig | 2. nieuwbouw | Non-bearing | 0 | Beginning | 4 | 2 | Vertical | Pset_wanden - NLRS_C_Geluidwering_DnTA: 31; Pset_kozijnen (CW) - NLRS_C_Geluidwering_DnTA: 31; Data - NLRS_C_Geluidwering_DnTA: 31; Materials and Finishes - NLRS_C_Afwerking Kozijn: Kozijn Bamboo - Deur Bamboo
Basic Wall:22_DAT_binnenwand_125:5036001 | 01 eerste verdieping | 22.13 Uniformat (Uniformat) | 429.8 | 2390 | 1980 | Merk H07 | 2 | Walls | Non-bearing | houten kozijn | 31.10 | houten kozijn | 31.10 | 31.10 | buitenwandopeningen; niet gevuld, algemeen (verzamelniveau) | houten kozijn | Walls | Curtain Wall | Curtain Wall: Merk H07 | Merk H07 | 5144215 | 0 | no | yes | 1 | 400 | 2390 | 4.7322 | 1980 | Bouwkundig | 2. nieuwbouw | Non-bearing | 0 | Beginning | 4 | 2 | Vertical | Pset_wanden - NLRS_C_Geluidwering_DnTA: 38; Pset_kozijnen (CW) - NLRS_C_Geluidwering_DnTA: 38; Data - NLRS_C_Geluidwering_DnTA: 38; Materials and Finishes - NLRS_C_Afwerking Kozijn: Ral 9010 - Deur HPL Formica F2296 Sno White
Basic Wall:22_DAT_binnenwand_125:5036751 | 01 eerste verdieping | 22.13 Uniformat (Uniformat) | 429.8 | 600 | 2205 | Merk H13 | 2 | Walls | Non-bearing | houten kozijn | 31.10 | houten kozijn | 31.10 | 31.10 | buitenwandopeningen; niet gevuld, algemeen (verzamelniveau) | houten kozijn | Walls | Curtain Wall | Curtain Wall: Merk H13 | Merk H13 | 6102836 | 1200 | no | yes | 1 | 400 | 600 | 1.323 | 2205 | Bouwkundig | 2. nieuwbouw | Non-bearing | 0 | Beginning | 4 | 2 | Vertical | Materials and Finishes - NLRS_C_Afwerking Kozijn: Ral 9010 - Deur HPL Formica F2296 Sno White
Basic Wall:22_DAT_binnenwand_125:5037367 | 01 eerste verdieping | 22.13 Uniformat (Uniformat) | 429.8 | 2390 | 1034 | Merk H16 | 2 | Walls | Non-bearing | houten kozijn | 31.10 | houten kozijn | 31.10 | 31.10 | buitenwandopeningen; niet gevuld, algemeen (verzamelniveau) | houten kozijn | Walls | Curtain Wall | Curtain Wall: Merk H16 | Merk H16 | 6103248 | 0 | no | yes | 1 | 400 | 2390 | 2.47126 | 1034 | Bouwkundig | 2. nieuwbouw | Non-bearing | 0 | Beginning | 4 | 2 | Vertical | Pset_wanden - NLRS_C_Geluidwering_DnTA: 38; Pset_kozijnen (CW) - NLRS_C_Geluidwering_DnTA: 38; Kozijnmerk: S; NLRS_C_gespiegeld: S; Data - NLRS_C_Geluidwering_DnTA: 38; NLRS_C_gespiegeld: S; Materials and Finishes - NLRS_C_Afwerking Kozijn: Ral 9010 - Deur HPL Formica F2296 Sno White
Basic Wall:22_DAT_binnenwand_125:5037717 | 01 eerste verdieping | 22.13 Uniformat (Uniformat) | 429.8 | 1190 | 600 | Merk H05 | 2 | Walls | Non-bearing | houten kozijn | 31.10 | houten kozijn | 31.10 | 31.10 | buitenwandopeningen; niet gevuld, algemeen (verzamelniveau) | houten kozijn | Walls | Curtain Wall | Curtain Wall: Merk H05 | Merk H05 | 5132093 | 1200 | no | yes | 1 | 400 | 1190 | 0.714 | 600 | Bouwkundig | 2. nieuwbouw | Non-bearing | 0 | Beginning | 4 | 2 | Vertical | Pset_wanden - NLRS_C_Geluidwering_DnTA: 25; Pset_kozijnen (CW) - NLRS_C_Geluidwering_DnTA: 25; Data - NLRS_C_Geluidwering_DnTA: 25; Materials and Finishes - NLRS_C_Afwerking Kozijn: Ral 9010 - Deur HPL Formica F2296 Sno White
Basic Wall:22_DAT_binnenwand_125:5037782 | 01 eerste verdieping | 22.13 Uniformat (Uniformat) | 429.8 | 2390 | 1034 | Merk H16 | 2 | Walls | Non-bearing | houten kozijn | 31.10 | houten kozijn | 31.10 | 31.10 | buitenwandopeningen; niet gevuld, algemeen (verzamelniveau) | houten kozijn | Walls | Curtain Wall | Curtain Wall: Merk H16 | Merk H16 | 6103248 | 0 | no | yes | 1 | 400 | 2390 | 2.47126 | 1034 | Bouwkundig | 2. nieuwbouw | Non-bearing | 0 | Beginning | 4 | 2 | Vertical | Pset_wanden - NLRS_C_Geluidwering_DnTA: 38; Pset_kozijnen (CW) - NLRS_C_Geluidwering_DnTA: 38; Kozijnmerk: S; NLRS_C_gespiegeld: S; Data - NLRS_C_Geluidwering_DnTA: 38; NLRS_C_gespiegeld: S; Materials and Finishes - NLRS_C_Afwerking Kozijn: Ral 9010 - Deur HPL Formica F2296 Sno White
Basic Wall:22_DAT_binnenwand_125 HPL dubbel:5037885 | 01 eerste verdieping | 22.13 Uniformat (Uniformat) | 429.8 | 2390 | 1134 | Merk H09 | 2 | Walls | Non-bearing | houten kozijn | 31.10 | houten kozijn | 31.10 | 31.10 | buitenwandopeningen; niet gevuld, algemeen (verzamelniveau) | houten kozijn | Walls | Curtain Wall | Curtain Wall: Merk H09 | Merk H09 | 5149044 | 0 | no | yes | 1 | 400 | 2390 | 2.71026 | 1134 | Bouwkundig | 2. nieuwbouw | Non-bearing | 0 | Beginning | 4 | 2 | Vertical | Pset_wanden - NLRS_C_Geluidwering_DnTA: 31; Pset_kozijnen (CW) - NLRS_C_Geluidwering_DnTA: 31; Data - NLRS_C_Geluidwering_DnTA: 31; Materials and Finishes - NLRS_C_Afwerking Kozijn: Kozijn Bamboo - Deur Bamboo
Basic Wall:22_DAT_binnenwand_125 HPL dubbel:5037885 | 01 eerste verdieping | 22.13 Uniformat (Uniformat) | 429.8 | 600 | 2205 | Merk H13 | 2 | Walls | Non-bearing | houten kozijn | 31.10 | houten kozijn | 31.10 | 31.10 | buitenwandopeningen; niet gevuld, algemeen (verzamelniveau) | houten kozijn | Walls | Curtain Wall | Curtain Wall: Merk H13 | Merk H13 | 6102836 | 1200 | no | yes | 1 | 400 | 600 | 1.323 | 2205 | Bouwkundig | 2. nieuwbouw | Non-bearing | 0 | Beginning | 4 | 2 | Vertical | Pset_wanden - NLRS_C_Geluidwering_DnTA: 31; Pset_kozijnen (CW) - NLRS_C_Geluidwering_DnTA: 31; Data - NLRS_C_Geluidwering_DnTA: 31; Materials and Finishes - NLRS_C_Afwerking Kozijn: Kozijn Bamboo - Deur Bamboo
Basic Wall:22_DAT_binnenwand_125 HPL dubbel:5037968 | 01 eerste verdieping | 22.13 Uniformat (Uniformat) | 429.8 | 2390 | 1134 | Merk H09 | 2 | Walls | Non-bearing | houten kozijn | 31.10 | houten kozijn | 31.10 | 31.10 | buitenwandopeningen; niet gevuld, algemeen (verzamelniveau) | houten kozijn | Walls | Curtain Wall | Curtain Wall: Merk H09 | Merk H09 | 5149044 | 0 | no | yes | 1 | 400 | 2390 | 2.71026 | 1134 | Bouwkundig | 2. nieuwbouw | Non-bearing | 0 | Beginning | 4 | 2 | Vertical | Pset_wanden - NLRS_C_Geluidwering_DnTA: 31; Pset_kozijnen (CW) - NLRS_C_Geluidwering_DnTA: 31; Data - NLRS_C_Geluidwering_DnTA: 31; Materials and Finishes - NLRS_C_Afwerking Kozijn: Kozijn Bamboo - Deur Bamboo
Basic Wall:22_DAT_binnenwand_125 HPL dubbel:5037968 | 01 eerste verdieping | 22.13 Uniformat (Uniformat) | 429.8 | 600 | 2205 | Merk H13 | 2 | Walls | Non-bearing | houten kozijn | 31.10 | houten kozijn | 31.10 | 31.10 | buitenwandopeningen; niet gevuld, algemeen (verzamelniveau) | houten kozijn | Walls | Curtain Wall | Curtain Wall: Merk H13 | Merk H13 | 6102836 | 1200 | no | yes | 1 | 400 | 600 | 1.323 | 2205 | Bouwkundig | 2. nieuwbouw | Non-bearing | 0 | Beginning | 4 | 2 | Vertical | Pset_wanden - NLRS_C_Geluidwering_DnTA: 31; Pset_kozijnen (CW) - NLRS_C_Geluidwering_DnTA: 31; Data - NLRS_C_Geluidwering_DnTA: 31; Materials and Finishes - NLRS_C_Afwerking Kozijn: Kozijn Bamboo - Deur Bamboo
Basic Wall:22_DAT_binnenwand_125 HPL:5038141 | 01 eerste verdieping | 22.13 Uniformat (Uniformat) | 429.8 | 2390 | 1470 | Merk H03 | 2 | Walls | Non-bearing | houten kozijn | 31.10 | houten kozijn | 31.10 | 31.10 | buitenwandopeningen; niet gevuld, algemeen (verzamelniveau) | houten kozijn | Walls | Curtain Wall | Curtain Wall: Merk H03 | Merk H03 | 5128005 | 0 | no | yes | 1 | 400 | 2390 | 3.5133 | 1470 | Bouwkundig | 2. nieuwbouw | Non-bearing | 0 | Beginning | 4 | 2 | Vertical | Pset_wanden - NLRS_C_Geluidwering_DnTA: 39; NLRS_C_brandwerendheid: 20; Pset_kozijnen (CW) - NLRS_C_Geluidwering_DnTA: 39; NLRS_C_brandwerendheid: 20; Data - NLRS_C_Geluidwering_DnTA: 39; Materials and Finishes - NLRS_C_Afwerking Kozijn: Kozijn Bamboo - Deur Bamboo; Fire Protection - NLRS_C_brandwerendheid: 20
Basic Wall:22_DAT_binnenwand_125 HPL dubbel:5038896 | 01 eerste verdieping | 22.13 Uniformat (Uniformat) | 429.8 | 2390 | 1134 | Merk H09 | 2 | Walls | Non-bearing | houten kozijn | 31.10 | houten kozijn | 31.10 | 31.10 | buitenwandopeningen; niet gevuld, algemeen (verzamelniveau) | houten kozijn | Walls | Curtain Wall | Curtain Wall: Merk H09 | Merk H09 | 5149044 | 0 | no | yes | 1 | 400 | 2390 | 2.71026 | 1134 | Bouwkundig | 2. nieuwbouw | Non-bearing | 0 | Beginning | 4 | 2 | Vertical | Pset_wanden - NLRS_C_Geluidwering_DnTA: 31; Pset_kozijnen (CW) - NLRS_C_Geluidwering_DnTA: 31; Data - NLRS_C_Geluidwering_DnTA: 31; Materials and Finishes - NLRS_C_Afwerking Kozijn: Kozijn Bamboo - Deur Bamboo
Basic Wall:22_DAT_binnenwand_125 HPL dubbel:5038896 | 01 eerste verdieping | 22.13 Uniformat (Uniformat) | 429.8 | 600 | 2205 | Merk H13 | 2 | Walls | Non-bearing | houten kozijn | 31.10 | houten kozijn | 31.10 | 31.10 | buitenwandopeningen; niet gevuld, algemeen (verzamelniveau) | houten kozijn | Walls | Curtain Wall | Curtain Wall: Merk H13 | Merk H13 | 6102836 | 1200 | no | yes | 1 | 400 | 600 | 1.323 | 2205 | Bouwkundig | 2. nieuwbouw | Non-bearing | 0 | Beginning | 4 | 2 | Vertical | Pset_wanden - NLRS_C_Geluidwering_DnTA: 31; Pset_kozijnen (CW) - NLRS_C_Geluidwering_DnTA: 31; Data - NLRS_C_Geluidwering_DnTA: 31; Materials and Finishes - NLRS_C_Afwerking Kozijn: Kozijn Bamboo - Deur Bamboo
Basic Wall:22_DAT_binnenwand_125:5038987 | 01 eerste verdieping | 22.13 Uniformat (Uniformat) | 429.8 | 1190 | 600 | Merk H05 | 2 | Walls | Non-bearing | houten kozijn | 31.10 | houten kozijn | 31.10 | 31.10 | buitenwandopeningen; niet gevuld, algemeen (verzamelniveau) | houten kozijn | Walls | Curtain Wall | Curtain Wall: Merk H05 | Merk H05 | 5132093 | 1200 | no | yes | 1 | 400 | 1190 | 0.714 | 600 | Bouwkundig | 2. nieuwbouw | Non-bearing | 0 | Beginning | 4 | 2 | Vertical | Pset_wanden - NLRS_C_Geluidwering_DnTA: 25; Pset_kozijnen (CW) - NLRS_C_Geluidwering_DnTA: 25; Data - NLRS_C_Geluidwering_DnTA: 25; Materials and Finishes - NLRS_C_Afwerking Kozijn: Ral 9010 - Deur HPL Formica F2296 Sno White
Basic Wall:22_DAT_binnenwand_125:5039067 | 01 eerste verdieping | 22.13 Uniformat (Uniformat) | 429.8 | 2390 | 1034 | Merk H01 | 2 | Walls | Non-bearing | houten kozijn | 31.10 | houten kozijn | 31.10 | 31.10 | buitenwandopeningen; niet gevuld, algemeen (verzamelniveau) | houten kozijn | Walls | Curtain Wall | Curtain Wall: Merk H01 | Merk H01 | 5121256 | 0 | no | yes | 1 | 400 | 2390 | 2.47126 | 1034 | Bouwkundig | 2. nieuwbouw | Non-bearing | 0 | Beginning | 4 | 2 | Vertical | Pset_wanden - NLRS_C_Geluidwering_DnTA: 25; Pset_kozijnen (CW) - NLRS_C_Geluidwering_DnTA: 25; Data - NLRS_C_Geluidwering_DnTA: 25; Materials and Finishes - NLRS_C_Afwerking Kozijn: Ral 9010 - Deur HPL Formica F2296 Sno White
Basic Wall:22_DAT_binnenwand_125:5039385 | 01 eerste verdieping | 22.13 Uniformat (Uniformat) | 429.8 | 1190 | 600 | Merk H05 | 2 | Walls | Non-bearing | houten kozijn | 31.10 | houten kozijn | 31.10 | 31.10 | buitenwandopeningen; niet gevuld, algemeen (verzamelniveau) | houten kozijn | Walls | Curtain Wall | Curtain Wall: Merk H05 | Merk H05 | 5132093 | 1200 | no | yes | 1 | 400 | 1190 | 0.714 | 600 | Bouwkundig | 2. nieuwbouw | Non-bearing | 0 | Beginning | 4 | 2 | Vertical | Pset_wanden - NLRS_C_Geluidwering_DnTA: 34; Pset_kozijnen (CW) - NLRS_C_Geluidwering_DnTA: 34; Data - NLRS_C_Geluidwering_DnTA: 34; Materials and Finishes - NLRS_C_Afwerking Kozijn: Ral 9010 - Deur HPL Formica F2296 Sno White
Basic Wall:22_DAT_binnenwand_125:5039853 | 01 eerste verdieping | 22.13 Uniformat (Uniformat) | 429.8 | 2390 | 1034 | Merk H16 | 2 | Walls | Non-bearing | houten kozijn | 31.10 | houten kozijn | 31.10 | 31.10 | buitenwandopeningen; niet gevuld, algemeen (verzamelniveau) | houten kozijn | Walls | Curtain Wall | Curtain Wall: Merk H16 | Merk H16 | 6103248 | 0 | no | yes | 1 | 400 | 2390 | 2.47126 | 1034 | Bouwkundig | 2. nieuwbouw | Non-bearing | 0 | Beginning | 4 | 2 | Vertical | Pset_wanden - NLRS_C_Geluidwering_DnTA: 34; Pset_kozijnen (CW) - NLRS_C_Geluidwering_DnTA: 34; Kozijnmerk: S; NLRS_C_gespiegeld: S; Data - NLRS_C_Geluidwering_DnTA: 34; NLRS_C_gespiegeld: S; Materials and Finishes - NLRS_C_Afwerking Kozijn: Ral 9010 - Deur HPL Formica F2296 Sno White
Basic Wall:22_DAT_binnenwand_125 HPL:5174534 | 01 eerste verdieping | 22.13 Uniformat (Uniformat) | 240 | 790 | 790 | haspel slang 30m gen hxdxb 730x240x790 | 2 | Plumbing Fixtures |  |  |  |  |  | 59.20 |  | brandslanghaspel inbouw | Plumbing Fixtures | NLRS_59_PF_FB_brandslanghaspel inbouw_gen_ISR | NLRS_59_PF_FB_brandslanghaspel inbouw_gen_ISR: haspel slang 30m gen hxdxb 730x240x790 | haspel slang 30m gen hxdxb 730x240x790 | 4687182 |  |  |  |  |  |  | 1.00371 |  | Bouwkundig | 2. nieuwbouw | Constraints - Elevation from Level: 1195 mm; Host: Basic Wall : 22_DAT_binnenwand_125 HPL; Level: 1; Schedule Level: 1; Dimensions - NLRS_C_breedte: 790 mm; NLRS_C_diepte: 240 mm; NLRS_C_hoogte: 790 mm; Volume: 0.149784 m3; General - NLRS_P_c01_diameter: 22 mm; NLRS_P_c01_radius: 11 mm; Graphics - slang_bereik: no; Identity Data - Mark: 107; Mechanical - brandslanghaspel_kw_flow: 0.361 m3/s; System Classification: Domestic Cold Water
Basic Wall:22_DAT_binnenwand_125:5174535 | 01 eerste verdieping | 22.13 Uniformat (Uniformat) | 429.8 | 1190 | 600 | Merk H05 | 2 | Walls | Non-bearing | houten kozijn | 31.10 | houten kozijn | 31.10 | 31.10 | buitenwandopeningen; niet gevuld, algemeen (verzamelniveau) | houten kozijn | Walls | Curtain Wall | Curtain Wall: Merk H05 | Merk H05 | 5132093 | 1200 | no | yes | 1 | 400 | 1190 | 0.714 | 600 | Bouwkundig | 2. nieuwbouw | Non-bearing | 0 | Beginning | 4 | 2 | Vertical | Pset_wanden - NLRS_C_Geluidwering_DnTA: 25; Pset_kozijnen (CW) - NLRS_C_Geluidwering_DnTA: 25; Data - NLRS_C_Geluidwering_DnTA: 25; Materials and Finishes - NLRS_C_Afwerking Kozijn: Ral 9010 - Deur HPL Formica F2296 Sno White
Basic Wall:22_DAT_binnenwand_125:5174538 | 01 eerste verdieping | 22.13 Uniformat (Uniformat) | 429.8 | 2390 | 1034 | Merk H01 | 2 | Walls | Non-bearing | houten kozijn | 31.10 | houten kozijn | 31.10 | 31.10 | buitenwandopeningen; niet gevuld, algemeen (verzamelniveau) | houten kozijn | Walls | Curtain Wall | Curtain Wall: Merk H01 | Merk H01 | 5121256 | 0 | no | yes | 1 | 400 | 2390 | 2.47126 | 1034 | Bouwkundig | 2. nieuwbouw | Non-bearing | 0 | Beginning | 4 | 2 | Vertical | Pset_wanden - NLRS_C_Geluidwering_DnTA: 25; Pset_kozijnen (CW) - NLRS_C_Geluidwering_DnTA: 25; Data - NLRS_C_Geluidwering_DnTA: 25; Materials and Finishes - NLRS_C_Afwerking Kozijn: Ral 9010 - Deur HPL Formica F2296 Sno White
Basic Wall:22_DAT_binnenwand_25:5180098 | 01 eerste verdieping | 22.13 Uniformat (Uniformat) | 329.8 | 3190 | 2970 | Merk H11 | 2 | Walls | Non-bearing | houten kozijn | 31.10 | houten kozijn | 31.10 | 31.10 | buitenwandopeningen; niet gevuld, algemeen (verzamelniveau) | houten kozijn | Walls | Curtain Wall | Curtain Wall: Merk H11 | Merk H11 | 5175472 | 0 | no | yes | 1 | 400 | 3190 | 9.4743 | 2970 | Bouwkundig | 2. nieuwbouw | Non-bearing | 0 | Beginning | 4 | 2 | Vertical | Pset_wanden - NLRS_C_Geluidwering_DnTA: 31; NLRS_C_brandwerendheid: 30; Pset_kozijnen (CW) - NLRS_C_Geluidwering_DnTA: 31; NLRS_C_brandwerendheid: 30; Data - NLRS_C_Geluidwering_DnTA: 31; Materials and Finishes - NLRS_C_Afwerking Kozijn: Ral 9010 - Deur HPL Formica F2296 Sno White; Fire Protection - NLRS_C_brandwerendheid: 30
Toposolid:Toposolid 1:4709300 | 00 Begane grond |  |  |  |  | Toposolid 1 | 2 | Lines: <Sketch> |  |  |  |  |  |  |  |  | Lines: <Sketch> |  |  |  |  |  |  |  |  |  |  |  | 50 | Bouwkundig | BaseQuantities - Area: 1162.28 m2; Other - Concrete Cantilever: 0 mm; Steel Cantilever: 0 mm; Constraints - Defines Constant Height: no; Defines Slope: no; Offset From Base: 0 mm; Dimensions - Slope: 4.76364
Toposolid:Toposolid 1:4709300 | 00 Begane grond |  |  |  |  | Toposolid 1 | 2 | Lines: <Sketch> |  |  |  |  |  |  |  |  | Lines: <Sketch> |  |  |  |  |  |  |  |  |  |  |  | 9999.33 | Bouwkundig | BaseQuantities - Area: 244.605 m2; Other - Concrete Cantilever: 0 mm; Steel Cantilever: 0 mm; Constraints - Defines Constant Height: no; Defines Slope: no; Offset From Base: 0 mm; Dimensions - Slope: 4.76364
Basic Wall:22_DAT_binnenwand_125:5204731 | 00 Begane grond | 22.13 Uniformat (Uniformat) | 429.8 | 2390 | 1134 | Merk H09 | 2 | Walls | Non-bearing | houten kozijn | 31.10 | houten kozijn | 31.10 | 31.10 | buitenwandopeningen; niet gevuld, algemeen (verzamelniveau) | houten kozijn | Walls | Curtain Wall | Curtain Wall: Merk H09 | Merk H09 | 5149044 | 0 | no | yes | 0 | 400 | 2390 | 2.71026 | 1134 | Bouwkundig | 2. nieuwbouw | Non-bearing | 0 | Beginning | 4 | 2 | Vertical | Pset_wanden - NLRS_C_Geluidwering_DnTA: 31; Pset_kozijnen (CW) - NLRS_C_Geluidwering_DnTA: 31; Data - NLRS_C_Geluidwering_DnTA: 31; Materials and Finishes - NLRS_C_Afwerking Kozijn: Kozijn Bamboo - Deur Bamboo
Basic Wall:22_DAT_binnenwand_125:5204731 | 00 Begane grond | 22.13 Uniformat (Uniformat) | 429.8 | 600 | 2710 | Merk H08 | 2 | Walls | Non-bearing | houten kozijn | 31.10 | houten kozijn | 31.10 | 31.10 | buitenwandopeningen; niet gevuld, algemeen (verzamelniveau) | houten kozijn | Walls | Curtain Wall | Curtain Wall: Merk H08 | Merk H08 | 5145389 | 1200 | no | yes | 0 | 400 | 600 | 1.626 | 2710 | Bouwkundig | 2. nieuwbouw | Non-bearing | 0 | Beginning | 4 | 2 | Vertical | Pset_wanden - NLRS_C_Geluidwering_DnTA: 31; Pset_kozijnen (CW) - NLRS_C_Geluidwering_DnTA: 31; Data - NLRS_C_Geluidwering_DnTA: 31; Materials and Finishes - NLRS_C_Afwerking Kozijn: Kozijn Bamboo - Deur Bamboo
Basic Wall:22_DAT_binnenwand_125:5205873 | 00 Begane grond | 22.13 Uniformat (Uniformat) | 429.8 | 2390 | 1034 | Merk H02 | 2 | Walls | Non-bearing | houten kozijn | 31.10 | houten kozijn | 31.10 | 31.10 | buitenwandopeningen; niet gevuld, algemeen (verzamelniveau) | houten kozijn | Walls | Curtain Wall | Curtain Wall: Merk H02 | Merk H02 | 5128107 | 0 | no | yes | 0 | 400 | 2390 | 2.47126 | 1034 | Bouwkundig | 2. nieuwbouw | Non-bearing | 0 | Beginning | 4 | 2 | Vertical | Materials and Finishes - NLRS_C_Afwerking Kozijn: Ral 9010 - Deur HPL Formica F2296 Sno White
Basic Wall:22_DAT_binnenwand_125:5205873 | 00 Begane grond | 22.13 Uniformat (Uniformat) | 429.8 | 2390 | 1134 | Merk H09 | 2 | Walls | Non-bearing | houten kozijn | 31.10 | houten kozijn | 31.10 | 31.10 | buitenwandopeningen; niet gevuld, algemeen (verzamelniveau) | houten kozijn | Walls | Curtain Wall | Curtain Wall: Merk H09 | Merk H09 | 5149044 | 0 | no | yes | 0 | 400 | 2390 | 2.71026 | 1134 | Bouwkundig | 2. nieuwbouw | Non-bearing | 0 | Beginning | 4 | 2 | Vertical | Pset_wanden - NLRS_C_Geluidwering_DnTA: 34; Pset_kozijnen (CW) - NLRS_C_Geluidwering_DnTA: 34; Data - NLRS_C_Geluidwering_DnTA: 34; Materials and Finishes - NLRS_C_Afwerking Kozijn: Ral 9010 - Deur HPL Formica F2296 Sno White
Basic Wall:22_DAT_binnenwand_125:5205873 | 00 Begane grond | 22.13 Uniformat (Uniformat) | 240 | 790 | 790 | haspel slang 30m gen hxdxb 730x240x790 | 2 | Plumbing Fixtures |  |  |  |  |  | 59.20 |  | brandslanghaspel inbouw | Plumbing Fixtures | NLRS_59_PF_FB_brandslanghaspel inbouw_gen_ISR | NLRS_59_PF_FB_brandslanghaspel inbouw_gen_ISR: haspel slang 30m gen hxdxb 730x240x790 | haspel slang 30m gen hxdxb 730x240x790 | 4687182 |  |  |  |  |  |  | 1.00371 |  | Bouwkundig | 2. nieuwbouw | Constraints - Elevation from Level: 1195 mm; Host: Basic Wall : 22_DAT_binnenwand_125; Level: 0; Schedule Level: 0; Dimensions - NLRS_C_breedte: 790 mm; NLRS_C_diepte: 240 mm; NLRS_C_hoogte: 790 mm; Volume: 0.149784 m3; General - NLRS_P_c01_diameter: 22 mm; NLRS_P_c01_radius: 11 mm; Graphics - slang_bereik: no; Identity Data - Mark: 103; Mechanical - brandslanghaspel_kw_flow: 0.361 m3/s; System Classification: Domestic Cold Water
Basic Wall:22_DAT_binnenwand_125:5227041 | 01 eerste verdieping | 22.13 Uniformat (Uniformat) | 429.8 | 2390 | 1034 | Merk H16 | 2 | Walls | Non-bearing | houten kozijn | 31.10 | houten kozijn | 31.10 | 31.10 | buitenwandopeningen; niet gevuld, algemeen (verzamelniveau) | houten kozijn | Walls | Curtain Wall | Curtain Wall: Merk H16 | Merk H16 | 6103248 | 0 | no | yes | 1 | 400 | 2390 | 2.47126 | 1034 | Bouwkundig | 2. nieuwbouw | Non-bearing | 0 | Beginning | 4 | 2 | Vertical | Pset_wanden - NLRS_C_Geluidwering_DnTA: 38; Pset_kozijnen (CW) - NLRS_C_Geluidwering_DnTA: 38; Data - NLRS_C_Geluidwering_DnTA: 38; Materials and Finishes - NLRS_C_Afwerking Kozijn: Ral 9010 - Deur HPL Formica F2296 Sno White
Basic Wall:22_DAT_binnenwand_125:5227137 | 01 eerste verdieping | 22.13 Uniformat (Uniformat) | 429.8 | 2390 | 1980 | Merk H07 | 2 | Walls | Non-bearing | houten kozijn | 31.10 | houten kozijn | 31.10 | 31.10 | buitenwandopeningen; niet gevuld, algemeen (verzamelniveau) | houten kozijn | Walls | Curtain Wall | Curtain Wall: Merk H07 | Merk H07 | 5144215 | 0 | no | yes | 1 | 400 | 2390 | 4.7322 | 1980 | Bouwkundig | 2. nieuwbouw | Non-bearing | 0 | Beginning | 4 | 2 | Vertical | Pset_wanden - NLRS_C_Geluidwering_DnTA: 38; Pset_kozijnen (CW) - NLRS_C_Geluidwering_DnTA: 38; Data - NLRS_C_Geluidwering_DnTA: 38; Materials and Finishes - NLRS_C_Afwerking Kozijn: Ral 9010 - Deur HPL Formica F2296 Sno White
Basic Wall:22_DAT_binnenwand_100:5228464 | 00 Begane grond | 22.13 Uniformat (Uniformat) | 240 | 790 | 790 | haspel slang 30m gen hxdxb 730x240x790 | 2 | Plumbing Fixtures |  |  |  |  |  | 59.20 |  | brandslanghaspel inbouw | Plumbing Fixtures | NLRS_59_PF_FB_brandslanghaspel inbouw_gen_ISR | NLRS_59_PF_FB_brandslanghaspel inbouw_gen_ISR: haspel slang 30m gen hxdxb 730x240x790 | haspel slang 30m gen hxdxb 730x240x790 | 4687182 |  |  |  |  |  |  | 1.00371 |  | Bouwkundig | 2. nieuwbouw | Constraints - Elevation from Level: 1195 mm; Host: Basic Wall : 22_DAT_binnenwand_125; Level: 0; Schedule Level: 0; Dimensions - NLRS_C_breedte: 790 mm; NLRS_C_diepte: 240 mm; NLRS_C_hoogte: 790 mm; Volume: 0.149784 m3; General - NLRS_P_c01_diameter: 22 mm; NLRS_P_c01_radius: 11 mm; Graphics - slang_bereik: no; Identity Data - Mark: 109; Mechanical - brandslanghaspel_kw_flow: 0.361 m3/s; System Classification: Domestic Cold Water
4 x Floor:23_Dekvloer 70mm:5247574 | 00 Begane grond | 23.10 Uniformat (Uniformat) |  |  |  | BV-F90 106 | 2 | Generic Models |  |  |  |  |  | 33.21 | vloeropeningen; gevuld, beloopbare vullingen | vloerluik | Generic Models | Storax-vloerluik-BV-F90 | Storax-vloerluik-BV-F90: BV-F90 106 | BV-F90 106 | 6149338 |  |  |  |  |  |  | 1.86317 |  | Bouwkundig | 2. nieuwbouw | Constraints - Elevation from Level: 0 mm; Host: Floor : 23_Dekvloer 70mm; Level: 0; Schedule Level: 0; Dimensions - Volume: 0.0376724 m3; inbouwhoogte: 75 mm; Pset_Generic Models - Family and Type: Storax-vloerluik-BV-F90: BV-F90 106; NL-sfb-Codering: 33.21; Omschrijving: vloerluik; Level: 0
Floor:23_Dekvloer 70mm:5247574 | 00 Begane grond | 23.10 Uniformat (Uniformat) |  |  |  | BV-F90 106 | 2 | Generic Models |  |  |  |  |  | 33.21 | vloeropeningen; gevuld, beloopbare vullingen | vloerluik | Generic Models | Storax-vloerluik-BV-F90 | Storax-vloerluik-BV-F90: BV-F90 106 | BV-F90 106 | 6149338 |  |  |  |  |  |  | 1.86317 |  | Bouwkundig | 2. nieuwbouw | Constraints - Elevation from Level: 0 mm; Host: Floor : 23_Dekvloer 70mm; Dimensions - Volume: 0.0376724 m3; inbouwhoogte: 75 mm; Pset_Generic Models - Family and Type: Storax-vloerluik-BV-F90: BV-F90 106; NL-sfb-Codering: 33.21; Omschrijving: vloerluik
Basic Wall:22_DAT_binnenwand_125 HPL:5296063 | 00 Begane grond | 22.13 Uniformat (Uniformat) | 429.8 | 2390 | 1470 | Merk H03 | 2 | Walls | Non-bearing | houten kozijn | 31.10 | houten kozijn | 31.10 | 31.10 | buitenwandopeningen; niet gevuld, algemeen (verzamelniveau) | houten kozijn | Walls | Curtain Wall | Curtain Wall: Merk H03 | Merk H03 | 5128005 | 0 | no | yes | 0 | 400 | 2390 | 3.5133 | 1470 | Bouwkundig | 2. nieuwbouw | Non-bearing | 0 | Beginning | 4 | 2 | Vertical | Materials and Finishes - NLRS_C_Afwerking Kozijn: Kozijn Bamboo - Deur Bamboo; Pset_wanden - NLRS_C_brandwerendheid: 30; Pset_kozijnen (CW) - NLRS_C_brandwerendheid: 30; Fire Protection - NLRS_C_brandwerendheid: 30
Basic Wall:22_DAT_binnenwand_125 HPL:5296063 | 00 Begane grond | 22.13 Uniformat (Uniformat) | 429.8 | 2400 | 2100 | 22_DAT_binnenwand_125 HPL | 2 | Walls | Non-bearing | Lichte scheidingswand 125mmAan weerszijden gipsvezelplaat 12,5mmGipsplaat 12,5mm Met daartussen 75mm ms wand gevuld met isolatieVulling afhankelijk van gestelde eisen ingeluidsrapportage | 22.13 |  |  | 22.13 | binnenwanden; niet constructief, systeemwanden; vast | Lichte scheidingswand 125mmAan weerszijden gipsvezelplaat 12,5mmGipsplaat 12,5mm Met daartussen 75mm ms wand gevuld met isolatieVulling afhankelijk van gestelde eisen ingeluidsrapportage | Walls | Basic Wall | Basic Wall: 22_DAT_binnenwand_125 HPL | 22_DAT_binnenwand_125 HPL | 6329633 | 0 | no | yes | 0 | 0 | 2400 | 1.5267 | 2100 | Bouwkundig | 2. nieuwbouw | Non-bearing |  |  |  |  | Vertical | Dimensions - Volume: 0.190838 m3; Constraints - Base Extension Distance: 0 mm; Top Extension Distance: 0 mm; Location Line: Wall Centerline
Basic Wall:22_DAT_binnenwand_125:5296366 | 00 Begane grond | 22.13 Uniformat (Uniformat) | 429.8 | 2390 | 1100 | Merk H19 | 2 | Walls | Non-bearing | houten kozijn | 31.10 | houten kozijn | 31.10 | 31.10 | buitenwandopeningen; niet gevuld, algemeen (verzamelniveau) | houten kozijn | Walls | Curtain Wall | Curtain Wall: Merk H19 | Merk H19 | 6103729 | 0 | no | yes | 0 | 400 | 2390 | 2.629 | 1100 | Bouwkundig | 2. nieuwbouw | Non-bearing | 0 | Beginning | 4 | 2 | Vertical | Pset_wanden - NLRS_C_Geluidwering_DnTA: 34; Pset_kozijnen (CW) - NLRS_C_Geluidwering_DnTA: 34; Data - NLRS_C_Geluidwering_DnTA: 34; Materials and Finishes - NLRS_C_Afwerking Kozijn: Ral 9010 - Deur HPL Formica F2296 Sno White
Basic Wall:22_DAT_binnenwand_125:5296597 | 00 Begane grond | 22.13 Uniformat (Uniformat) | 429.8 | 2390 | 2360 | Merk H24 | 2 | Walls | Non-bearing | houten kozijn | 31.10 | houten kozijn | 31.10 | 31.10 | buitenwandopeningen; niet gevuld, algemeen (verzamelniveau) | houten kozijn | Walls | Curtain Wall | Curtain Wall: Merk H24 | Merk H24 | 5489050 | 0 | no | yes | 0 | 400 | 2390 | 5.6404 | 2360 | Bouwkundig | 2. nieuwbouw | Non-bearing | 0 | Beginning | 4 | 2 | Vertical | Materials and Finishes - NLRS_C_Afwerking Kozijn: Ral 9010 - Deur HPL Formica F2296 Sno White
Basic Wall:28_DAT_kalkzandsteen_150mm:4337793 | 00 Begane grond | 28.21 Uniformat (Uniformat) |  |  |  | 28_DAT_kalkzandsteen_150mm | 2 | Lines: <Sketch> |  |  |  |  |  |  |  |  |  |  |  |  |  |  |  |  |  |  |  |  | 2676.11 | Constructie | Pset_ProductRequirements - sets with these values: 2; BaseQuantities - Area: 0.826867 m2
Basic Wall:22_DAT_binnenwand_125 HPL:5306818 | 00 Begane grond | 22.13 Uniformat (Uniformat) | 429.8 | 2390 | 1034 | Merk H16 | 2 | Walls | Non-bearing | houten kozijn | 31.10 | houten kozijn | 31.10 | 31.10 | buitenwandopeningen; niet gevuld, algemeen (verzamelniveau) | houten kozijn | Walls | Curtain Wall | Curtain Wall: Merk H16 | Merk H16 | 6103248 | 0 | no | yes | 0 | 400 | 2390 | 2.47126 | 1034 | Bouwkundig | 2. nieuwbouw | Non-bearing | 0 | Beginning | 4 | 2 | Vertical | Pset_wanden - NLRS_C_Geluidwering_DnTA: 34; Pset_kozijnen (CW) - NLRS_C_Geluidwering_DnTA: 34; Data - NLRS_C_Geluidwering_DnTA: 34; Materials and Finishes - NLRS_C_Afwerking Kozijn: Ral 9010 - Deur HPL Formica F2296 Sno White
2 x Basic Wall:22_DAT_binnenwand_125 HPL:5306818 | 00 Begane grond | 22.13 Uniformat (Uniformat) | 429.8 | 2390 | 1034 | Merk H01 | 2 | Walls | Non-bearing | houten kozijn | 31.10 | houten kozijn | 31.10 | 31.10 | buitenwandopeningen; niet gevuld, algemeen (verzamelniveau) | houten kozijn | Walls | Curtain Wall | Curtain Wall: Merk H01 | Merk H01 | 5121256 | 0 | no | yes | 0 | 400 | 2390 | 2.47126 | 1034 | Bouwkundig | 2. nieuwbouw | Non-bearing | 0 | Beginning | 4 | 2 | Vertical | Pset_wanden - NLRS_C_Geluidwering_DnTA: 34; Pset_kozijnen (CW) - NLRS_C_Geluidwering_DnTA: 34; Data - NLRS_C_Geluidwering_DnTA: 34; Materials and Finishes - NLRS_C_Afwerking Kozijn: Ral 9010 - Deur HPL Formica F2296 Sno White
Basic Wall:22_DAT_binnenwand_125 HPL:5306818 | 00 Begane grond | 22.13 Uniformat (Uniformat) | 429.8 | 1190 | 600 | Merk H05 | 2 | Walls | Non-bearing | houten kozijn | 31.10 | houten kozijn | 31.10 | 31.10 | buitenwandopeningen; niet gevuld, algemeen (verzamelniveau) | houten kozijn | Walls | Curtain Wall | Curtain Wall: Merk H05 | Merk H05 | 5132093 | 1200 | no | yes | 0 | 400 | 1190 | 0.714 | 600 | Bouwkundig | 2. nieuwbouw | Non-bearing | 0 | Beginning | 4 | 2 | Vertical | Pset_wanden - NLRS_C_Geluidwering_DnTA: 34; Pset_kozijnen (CW) - NLRS_C_Geluidwering_DnTA: 34; Data - NLRS_C_Geluidwering_DnTA: 34; Materials and Finishes - NLRS_C_Afwerking Kozijn: Ral 9010 - Deur HPL Formica F2296 Sno White
2 x Basic Wall:22_DAT_binnenwand_125:5307539 | 00 Begane grond | 22.13 Uniformat (Uniformat) | 429.8 | 2390 | 1034 | Merk H01 | 2 | Walls | Non-bearing | houten kozijn | 31.10 | houten kozijn | 31.10 | 31.10 | buitenwandopeningen; niet gevuld, algemeen (verzamelniveau) | houten kozijn | Walls | Curtain Wall | Curtain Wall: Merk H01 | Merk H01 | 5121256 | 0 | no | yes | 0 | 400 | 2390 | 2.47126 | 1034 | Bouwkundig | 2. nieuwbouw | Non-bearing | 0 | Beginning | 4 | 2 | Vertical | Pset_wanden - NLRS_C_Geluidwering_DnTA: 34; NLRS_C_brandwerendheid: 30; Pset_kozijnen (CW) - NLRS_C_Geluidwering_DnTA: 34; Kozijnmerk: S; NLRS_C_gespiegeld: S; NLRS_C_brandwerendheid: 30; Data - NLRS_C_Geluidwering_DnTA: 34; NLRS_C_gespiegeld: S; Materials and Finishes - NLRS_C_Afwerking Kozijn: Ral 9010 - Deur HPL Formica F2296 Sno White; Fire Protection - NLRS_C_brandwerendheid: 30
Basic Wall:22_DAT_binnenwand_125:5382004 | 00 Begane grond | 22.13 Uniformat (Uniformat) | 429.8 | 2415 | 563 | 22_DAT_binnenwand_125 HPL | 2 | Walls | Non-bearing | Lichte scheidingswand 125mmAan weerszijden gipsvezelplaat 12,5mmGipsplaat 12,5mm Met daartussen 75mm ms wand gevuld met isolatieVulling afhankelijk van gestelde eisen ingeluidsrapportage | 22.13 |  |  | 22.13 | binnenwanden; niet constructief, systeemwanden; vast | Lichte scheidingswand 125mmAan weerszijden gipsvezelplaat 12,5mmGipsplaat 12,5mm Met daartussen 75mm ms wand gevuld met isolatieVulling afhankelijk van gestelde eisen ingeluidsrapportage | Walls | Basic Wall | Basic Wall: 22_DAT_binnenwand_125 HPL | 22_DAT_binnenwand_125 HPL | 6329633 | 0 | no | yes | 0 | 0 | 2415 | 1.35964 | 625.5 | Bouwkundig | 2. nieuwbouw | Non-bearing |  |  |  |  | Vertical | Dimensions - Volume: 0.169956 m3; Constraints - Base Extension Distance: 0 mm; Top Extension Distance: 0 mm; Location Line: Wall Centerline
Basic Wall:22_DAT_binnenwand_125:5453722 | 01 eerste verdieping | 22.13 Uniformat (Uniformat) | 429.8 | 600 | 2205 | Merk H13 | 2 | Walls | Non-bearing | houten kozijn | 31.10 | houten kozijn | 31.10 | 31.10 | buitenwandopeningen; niet gevuld, algemeen (verzamelniveau) | houten kozijn | Walls | Curtain Wall | Curtain Wall: Merk H13 | Merk H13 | 6102836 | 1200 | no | yes | 1 | 400 | 600 | 1.323 | 2205 | Bouwkundig | 2. nieuwbouw | Non-bearing | 0 | Beginning | 4 | 2 | Vertical | Pset_wanden - NLRS_C_Geluidwering_DnTA: 31; Pset_kozijnen (CW) - NLRS_C_Geluidwering_DnTA: 31; Data - NLRS_C_Geluidwering_DnTA: 31; Materials and Finishes - NLRS_C_Afwerking Kozijn: Ral 9010 - Deur HPL Formica F2296 Sno White
 | 00 Begane grond | 23.10 Uniformat (Uniformat) | 60 |  |  | 23_Gewapende Druklaag | 2 | Floors |  |  |  |  |  | 23.10 | vloeren; niet constructief, algemeen (verzamelniveau) | Druklaag 60mm | BaseQuantities - Area: 0.0929251 m2; Pset_Vloeren - Omschrijving: Druklaag 60mm; NL-sfb-Codering: 23.10
 | 00 Begane grond | 23.21 Uniformat (Uniformat) | 352 |  |  | 23_Geisoleerde kanaalplaatvloer_200 | 2 | Floors |  |  |  |  |  | 23.21 | vloeren; constructief, vrijdragende vloeren | Geisoleerde kanaalplaatvloer 200mm | BaseQuantities - Area: 0.0929251 m2; Pset_Vloeren - Omschrijving: Geisoleerde kanaalplaatvloer 200mm; NL-sfb-Codering: 23.21
Basic Wall:22_DAT_binnenwand_125:5489199 | 00 Begane grond | 22.13 Uniformat (Uniformat) | 429.8 | 2415 | 4370 | 22_DAT_binnenwand_125 HPL | 2 | Walls | Non-bearing | Lichte scheidingswand 125mmAan weerszijden gipsvezelplaat 12,5mmGipsplaat 12,5mm Met daartussen 75mm ms wand gevuld met isolatieVulling afhankelijk van gestelde eisen ingeluidsrapportage | 22.13 |  |  | 22.13 | binnenwanden; niet constructief, systeemwanden; vast | Lichte scheidingswand 125mmAan weerszijden gipsvezelplaat 12,5mmGipsplaat 12,5mm Met daartussen 75mm ms wand gevuld met isolatieVulling afhankelijk van gestelde eisen ingeluidsrapportage | Walls | Basic Wall | Basic Wall: 22_DAT_binnenwand_125 HPL | 22_DAT_binnenwand_125 HPL | 6329633 | 0 | no | yes | 0 | 0 | 2415 | 0.5514 | 4495 | Bouwkundig | 2. nieuwbouw | Non-bearing |  |  |  |  | Vertical | Dimensions - Volume: 0.068925 m3; Constraints - Base Extension Distance: 0 mm; Top Extension Distance: 0 mm; Location Line: Wall Centerline
Basic Wall:22_DAT_binnenwand_125:5489958 | 00 Begane grond | 22.13 Uniformat (Uniformat) | 429.8 | 2390 | 2300 | Merk H21 | 2 | Walls | Non-bearing | houten kozijn | 31.10 | houten kozijn | 31.10 | 31.10 | buitenwandopeningen; niet gevuld, algemeen (verzamelniveau) | houten kozijn | Walls | Curtain Wall | Curtain Wall: Merk H21 | Merk H21 | 5893300 | 0 | no | yes | 0 | 400 | 2390 | 5.497 | 2300 | Bouwkundig | 2. nieuwbouw | Non-bearing | 0 | Beginning | 4 | 2 | Vertical | Materials and Finishes - NLRS_C_Afwerking Kozijn: S3020-Y20R - Deur HPL Formica F0903 cafe; Pset_wanden - IfcMaterial: S3020-Y20R - Deur HPL Formica F0903 cafe; NLRS_C_afwerkingsklasse: S3020-Y20R - Deur HPL Formica F0903 cafe
Basic Wall:22_DAT_binnenwand_125:5489958 | 00 Begane grond | 22.13 Uniformat (Uniformat) | 429.8 | 2415 | 4535 | 22_DAT_binnenwand_125 HPL dubbel | 2 | Walls | Non-bearing | Lichte scheidingswand 125mmAan weerszijden gipsvezelplaat 12,5mmGipsplaat 12,5mm Met daartussen 75mm ms wand gevuld met isolatieVulling afhankelijk van gestelde eisen ingeluidsrapportage | 22.13 |  |  | 22.13 | binnenwanden; niet constructief, systeemwanden; vast | Lichte scheidingswand 125mmAan weerszijden gipsvezelplaat 12,5mmGipsplaat 12,5mm Met daartussen 75mm ms wand gevuld met isolatieVulling afhankelijk van gestelde eisen ingeluidsrapportage | Walls | Basic Wall | Basic Wall: 22_DAT_binnenwand_125 HPL dubbel | 22_DAT_binnenwand_125 HPL dubbel | 6394901 | 0 | no | yes | 0 | 0 | 2415 | 1.09328 | 4597.5 | Bouwkundig | 2. nieuwbouw | Non-bearing |  |  |  |  | Vertical | Dimensions - Volume: 0.136659 m3; Constraints - Base Extension Distance: 0 mm; Top Extension Distance: 0 mm; Location Line: Wall Centerline
Basic Wall:21_DAT_isolatie minerale wol_160:5536749 | 00 Begane grond | 21.10 Uniformat (Uniformat) | 464.8 | 2760 | 1495 | K_26 | 2 | Walls | Non-bearing | Kunststof kozijn Gealan Kubus | 31 | Kunststof kozijn Gealan Kubus | 31 | 31 | buitenwandopeningen | Kunststof kozijn Gealan Kubus | Walls | Curtain Wall | Curtain Wall: K_26 | K_26 | 4951884 | -20 | no | yes | 1 | 0 | 2760 | 4.1262 | 1495 | Bouwkundig | 2. nieuwbouw | Non-bearing | 0 | Beginning | 4 | 2 | Vertical | Other - Doorvalveilig 1-zijdig: no; Doorvalveilig 2-zijdig: yes; Text - NLRS_C_merk: K01
Basic Wall:21_DAT_isolatie minerale wol_160:5536749 | 00 Begane grond | 21.10 Uniformat (Uniformat) | 464.8 | 2760 | 3450 | K_27 | 2 | Walls | Non-bearing | Kunststof kozijn Gealan Kubus | 31 | Kunststof kozijn Gealan Kubus | 31 | 31 | buitenwandopeningen | Kunststof kozijn Gealan Kubus | Walls | Curtain Wall | Curtain Wall: K_27 | K_27 | 4952631 | -20 | no | yes | 1 | 0 | 2760 | 9.522 | 3450 | Bouwkundig | 2. nieuwbouw | Non-bearing | 0 | Beginning | 4 | 2 | Vertical | Other - Doorvalveilig 1-zijdig: no; Doorvalveilig 2-zijdig: yes; Text - NLRS_C_merk: K01
Basic Wall:21_DAT_isolatie minerale wol_160:5536749 | 00 Begane grond | 21.10 Uniformat (Uniformat) | 464.8 | 990 | 5355 | 21_DAT_isolatie hard_74 | 2 | Walls | Non-bearing | Hoogwaardige isolatie met een RC van 4.7 m²K/W | 21.10 |  |  | 21.10 | buitenwanden; niet constructief, algemeen (verzamelniveau) | Hoogwaardige isolatie met een RC van 4.7 m²K/W | Walls | Basic Wall | Basic Wall: 21_DAT_isolatie hard_74 | 21_DAT_isolatie hard_74 | 5724015 | 240 | no | yes | V0 ok. plafond | -20 | 990 | 5.30145 | 5355 | Bouwkundig | 2. nieuwbouw | Non-bearing |  |  |  |  | Vertical | Dimensions - Volume: 0.371102 m3; Constraints - Base Extension Distance: 0 mm; Top Extension Distance: 0 mm; Location Line: Finish Face: Interior; Top Constraint: Up to level: 1
Basic Wall:21_DAT_isolatie minerale wol_160:5536749 | 00 Begane grond | 21.10 Uniformat (Uniformat) | 464.8 | 2505 | 3705 | 21_DAT_isolatie hard_74 | 2 | Walls | Non-bearing | Hoogwaardige isolatie met een RC van 4.7 m²K/W | 21.10 |  |  | 21.10 | buitenwanden; niet constructief, algemeen (verzamelniveau) | Hoogwaardige isolatie met een RC van 4.7 m²K/W | Walls | Basic Wall | Basic Wall: 21_DAT_isolatie hard_74 | 21_DAT_isolatie hard_74 | 5724015 | 480 | no | yes | 0 | -665 | 2505 | 2.54482 | 3670 | Bouwkundig | 2. nieuwbouw | Non-bearing |  |  |  |  | Vertical | Dimensions - Volume: 0.178138 m3; Constraints - Base Extension Distance: 0 mm; Top Extension Distance: 0 mm; Location Line: Finish Face: Interior; Top Constraint: Up to level: 1
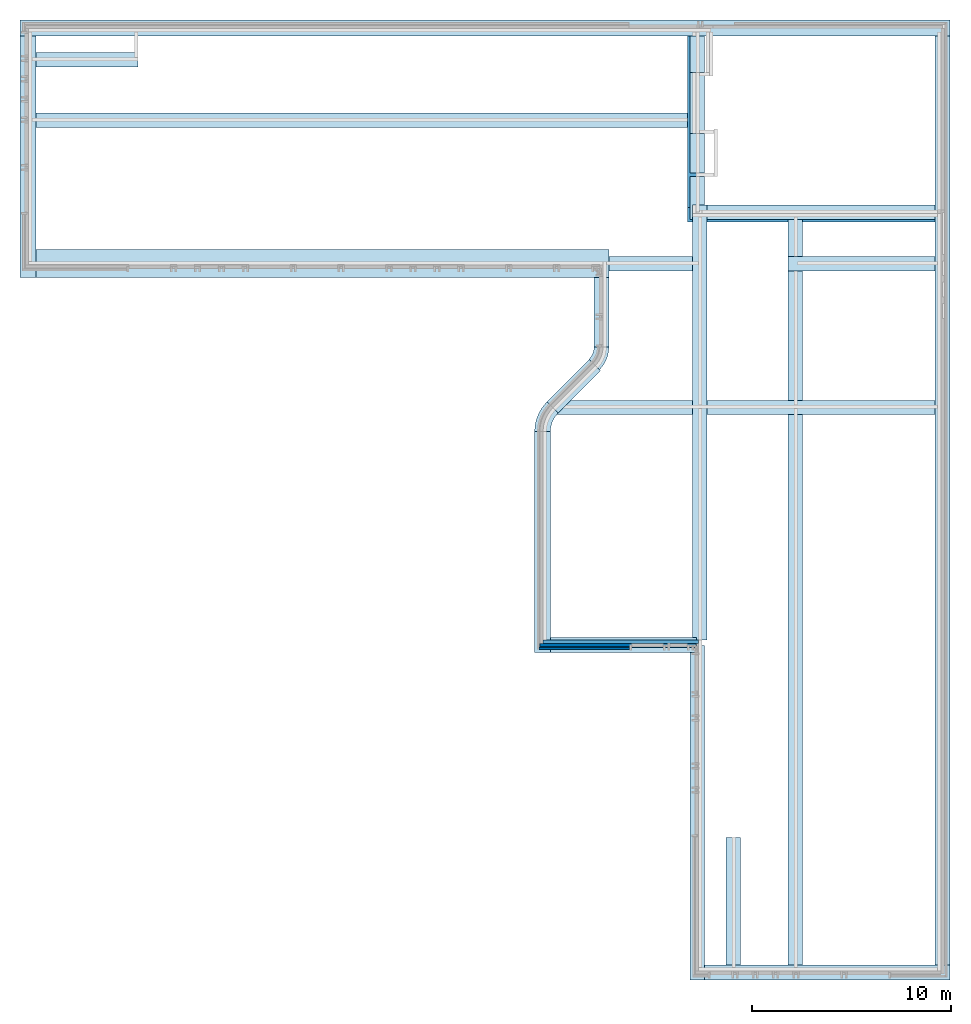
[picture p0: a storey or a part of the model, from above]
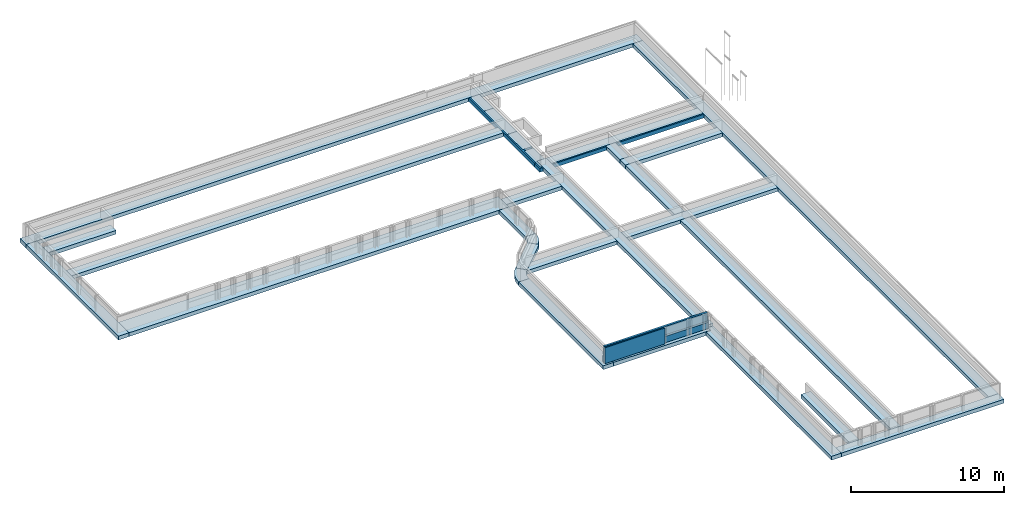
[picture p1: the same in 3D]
Properties of the parts of a building model (IFC2X3), part 22 of 37

# IfcOpeningElement: Opening (1092)
Name | In | Classification | Depth (mm) | BaseQuantities, Height (mm) | BaseQuantities, Width (mm) | Reference | Pset_OpeningElementCommon, sets with these values | Pset_ProductRequirements, Category | Pset_wanden, Structural Usage | Pset_wanden, Omschrijving | Pset_wanden, NL-sfb-Codering | Pset_kozijnen (CW), Omschrijving | Pset_kozijnen (CW), NL-sfb-Codering | Pset_DAT_KMS, Assembly Code | Pset_DAT_KMS, Assembly Description | Pset_DAT_KMS, Description | Other, Category | Family | Other, Family and Type | Type | Type Id | Base Offset (mm) | Base is Attached = Related to Mass = Top is Attached = Structural | Room Bounding | Base Constraint | Top Offset (mm) | Unconnected Height (mm) | Dimensions, Area (m2) | Length (mm) | Identity Data, Workset | Phase Created | Structural, Structural Usage | Angle (deg) = Offset (mm) | Justification | Number | Horizontal Grid, sets with these values | Cross-Section
2 x Basic Wall:21_DAT_isolatie minerale wol_160:5536749 | 00 Begane grond | 21.10 Uniformat (Uniformat) | 464.8 | 2750 | 120 | 21_DAT_isolatie hard_74 | 2 | Walls | Non-bearing | Hoogwaardige isolatie met een RC van 4.7 m²K/W | 21.10 |  |  | 21.10 | buitenwanden; niet constructief, algemeen (verzamelniveau) | Hoogwaardige isolatie met een RC van 4.7 m²K/W | Walls | Basic Wall | Basic Wall: 21_DAT_isolatie hard_74 | 21_DAT_isolatie hard_74 | 5724015 | 0 | no | yes | 0 | 0 | 2750 | 0.33 | 120 | Bouwkundig | 2. nieuwbouw | Non-bearing |  |  |  |  | Vertical | Dimensions - Volume: 0.0231 m3; Constraints - Base Extension Distance: 0 mm; Top Extension Distance: 0 mm; Location Line: Finish Face: Interior
Basic Wall:21_DAT_isolatie minerale wol_160:5536749 | 00 Begane grond | 21.10 Uniformat (Uniformat) | 464.8 | 2750 | 280 | 21_DAT_isolatie hard_74 | 2 | Walls | Non-bearing | Hoogwaardige isolatie met een RC van 4.7 m²K/W | 21.10 |  |  | 21.10 | buitenwanden; niet constructief, algemeen (verzamelniveau) | Hoogwaardige isolatie met een RC van 4.7 m²K/W | Walls | Basic Wall | Basic Wall: 21_DAT_isolatie hard_74 | 21_DAT_isolatie hard_74 | 5724015 | 0 | no | yes | 0 | 0 | 2750 | 0.77 | 280 | Bouwkundig | 2. nieuwbouw | Non-bearing |  |  |  |  | Vertical | Dimensions - Volume: 0.0539 m3; Constraints - Base Extension Distance: 0 mm; Top Extension Distance: 0 mm; Location Line: Finish Face: Interior
Basic Wall:21_DAT_isolatie minerale wol_160:5536749 | 00 Begane grond | 21.10 Uniformat (Uniformat) | 464.8 | 2630 | 3450 | K_15 | 2 | Walls | Non-bearing | Kunststof kozijn Gealan Kubus | 31 | Kunststof kozijn Gealan Kubus | 31 | 31 | buitenwandopeningen | Kunststof kozijn Gealan Kubus | Walls | Curtain Wall | Curtain Wall: K_15 | K_15 | 4912009 | 10 | no | yes | 0 | 0 | 2630 | 9.0735 | 3450 | Bouwkundig | 2. nieuwbouw | Non-bearing | 0 | Beginning | 4 | 2 | Vertical | Other - Doorvalveilig 1-zijdig: no; Doorvalveilig 2-zijdig: yes; Text - NLRS_C_merk: K01
Basic Wall:21_DAT_isolatie minerale wol_160:5536749 | 00 Begane grond | 21.10 Uniformat (Uniformat) | 464.8 | 2630 | 1495 | K_14 | 2 | Walls | Non-bearing | Kunststof kozijn Gealan Kubus | 31 | Kunststof kozijn Gealan Kubus | 31 | 31 | buitenwandopeningen | Kunststof kozijn Gealan Kubus | Walls | Curtain Wall | Curtain Wall: K_14 | K_14 | 4906721 | 10 | no | yes | 0 | 0 | 2630 | 3.93185 | 1495 | Bouwkundig | 2. nieuwbouw | Non-bearing | 0 | Beginning | 4 | 2 | Vertical | Other - Doorvalveilig 1-zijdig: no; Doorvalveilig 2-zijdig: yes; Text - NLRS_C_merk: K01
Basic Wall:21_DAT_isolatie minerale wol_160:5536749 | 00 Begane grond | 21.10 Uniformat (Uniformat) | 464.8 | 2180 | 2300 | K_07 | 2 | Walls | Non-bearing | Kunststof kozijn Gealan Kubus | 31 | Kunststof kozijn Gealan Kubus | 31 | 31 | buitenwandopeningen | Kunststof kozijn Gealan Kubus | Walls | Curtain Wall | Curtain Wall: K_07 | K_07 | 4849800 | 710 | no | yes | 0 | 0 | 2180 | 5.014 | 2300 | Bouwkundig | 2. nieuwbouw | Non-bearing | 0 | Beginning | 4 | 2 | Vertical | Other - Doorvalveilig 1-zijdig: no; Doorvalveilig 2-zijdig: yes; Text - NLRS_C_merk: K01
3 x Basic Wall:21_DAT_isolatie minerale wol_160:5536749 | 00 Begane grond | 21.10 Uniformat (Uniformat) | 464.8 | 1930 | 2040 | K_17 | 2 | Walls | Non-bearing | Kunststof kozijn Gealan Kubus | 31 | Kunststof kozijn Gealan Kubus | 31 | 31 | buitenwandopeningen | Kunststof kozijn Gealan Kubus | Walls | Curtain Wall | Curtain Wall: K_17 | K_17 | 6061266 | 710 | no | yes | 0 | 0 | 1930 | 3.9372 | 2040 | Bouwkundig | 2. nieuwbouw | Non-bearing | 0 | Beginning | 4 | 2 | Vertical | Other - Doorvalveilig 1-zijdig: no; Doorvalveilig 2-zijdig: yes; Text - NLRS_C_merk: K01
3 x Basic Wall:21_DAT_isolatie minerale wol_160:5536749 | 00 Begane grond | 21.10 Uniformat (Uniformat) | 464.8 | 2366.66 | 2280 | 21_DAT_isolatie hard_74 | 2 | Walls | Non-bearing | Hoogwaardige isolatie met een RC van 4.7 m²K/W | 21.10 |  |  | 21.10 | buitenwanden; niet constructief, algemeen (verzamelniveau) | Hoogwaardige isolatie met een RC van 4.7 m²K/W | Walls | Basic Wall | Basic Wall: 21_DAT_isolatie hard_74 | 21_DAT_isolatie hard_74 | 5724015 | 388.34 | no | yes | 0 | 0 | 2366.66 | 1.45879 | 2280 | Bouwkundig | 2. nieuwbouw | Non-bearing |  |  |  |  | Vertical | Dimensions - Volume: 0.102115 m3; Constraints - Base Extension Distance: 0 mm; Top Extension Distance: 0 mm; Location Line: Finish Face: Interior
4 x Basic Wall:21_DAT_isolatie minerale wol_160:5536749 | 00 Begane grond | 21.10 Uniformat (Uniformat) | 464.8 | 1930 | 880 | K_16 | 2 | Walls | Non-bearing | Kunststof kozijn Gealan Kubus | 31 | Kunststof kozijn Gealan Kubus | 31 | 31 | buitenwandopeningen | Kunststof kozijn Gealan Kubus | Walls | Curtain Wall | Curtain Wall: K_16 | K_16 | 6074129 | 710 | no | yes | 0 | 0 | 1930 | 1.6984 | 880 | Bouwkundig | 2. nieuwbouw | Non-bearing | 0 | Beginning | 4 | 2 | Vertical | Other - Doorvalveilig 1-zijdig: no; Doorvalveilig 2-zijdig: yes; Text - NLRS_C_merk: K01
4 x Basic Wall:21_DAT_isolatie minerale wol_160:5536749 | 00 Begane grond | 21.10 Uniformat (Uniformat) | 464.8 | 2750 | 1120 | 21_DAT_isolatie hard_74 | 2 | Walls | Non-bearing | Hoogwaardige isolatie met een RC van 4.7 m²K/W | 21.10 |  |  | 21.10 | buitenwanden; niet constructief, algemeen (verzamelniveau) | Hoogwaardige isolatie met een RC van 4.7 m²K/W | Walls | Basic Wall | Basic Wall: 21_DAT_isolatie hard_74 | 21_DAT_isolatie hard_74 | 5724015 | 520 | no | yes | 0 | 0 | 2750 | 1.3816 | 1120 | Bouwkundig | 2. nieuwbouw | Non-bearing |  |  |  |  | Vertical | Dimensions - Volume: 0.096712 m3; Constraints - Base Extension Distance: 0 mm; Top Extension Distance: 0 mm; Location Line: Finish Face: Interior
Basic Wall:21_DAT_isolatie minerale wol_160:5536750 | 00 Begane grond | 21.10 Uniformat (Uniformat) | 464.8 | 2630 | 1130 | K_05 | 2 | Walls | Non-bearing | Kunststof kozijn Gealan Linear | 31 | Kunststof kozijn Gealan Linear | 31 | 31 | buitenwandopeningen | Kunststof kozijn Gealan Linear | Walls | Curtain Wall | Curtain Wall: K_05 | K_05 | 4797835 | 10 | no | yes | 0 | 0 | 2630 | 2.9719 | 1130 | Bouwkundig | 2. nieuwbouw | Non-bearing | 0 | Beginning | 4 | 2 | Vertical | Other - Doorvalveilig 1-zijdig: no; Doorvalveilig 2-zijdig: yes; Text - NLRS_C_merk: K01
Basic Wall:21_DAT_isolatie minerale wol_160:5536750 | 00 Begane grond | 21.10 Uniformat (Uniformat) | 464.8 | 2610 | 2120 | K_03 | 2 | Walls | Non-bearing | Kunststof kozijn Gealan Linear | 31 | Kunststof kozijn Gealan Linear | 31 | 31 | buitenwandopeningen | Kunststof kozijn Gealan Linear | Walls | Curtain Wall | Curtain Wall: K_03 | K_03 | 4793066 | 30 | no | yes | 0 | 0 | 2610 | 5.5332 | 2120 | Bouwkundig | 2. nieuwbouw | Non-bearing | 0 | Beginning | 4 | 2 | Vertical | Other - Doorvalveilig 1-zijdig: no; Doorvalveilig 2-zijdig: yes; Text - NLRS_C_merk: K01
2 x Basic Wall:21_DAT_isolatie minerale wol_160:5536750 | 00 Begane grond | 21.10 Uniformat (Uniformat) | 464.8 | 2630 | 740 | K_04 | 2 | Walls | Non-bearing | Kunststof kozijn Gealan Kubus | 31 | Kunststof kozijn Gealan Kubus | 31 | 31 | buitenwandopeningen | Kunststof kozijn Gealan Kubus | Walls | Curtain Wall | Curtain Wall: K_04 | K_04 | 4800906 | 10 | no | yes | 0 | 0 | 2630 | 1.9462 | 740 | Bouwkundig | 2. nieuwbouw | Non-bearing | 0 | Beginning | 4 | 2 | Vertical | Other - Doorvalveilig 1-zijdig: no; Doorvalveilig 2-zijdig: yes; Text - NLRS_C_merk: K01
Basic Wall:21_DAT_isolatie minerale wol_160:5536750 | 00 Begane grond | 21.10 Uniformat (Uniformat) | 464.8 | 2630 | 2120 | K_02 | 2 | Walls | Non-bearing | Kunststof kozijn Gealan Kubus | 31 | Kunststof kozijn Gealan Kubus | 31 | 31 | buitenwandopeningen | Kunststof kozijn Gealan Kubus | Walls | Curtain Wall | Curtain Wall: K_02 | K_02 | 4792108 | 10 | no | yes | 0 | 0 | 2630 | 5.5756 | 2120 | Bouwkundig | 2. nieuwbouw | Non-bearing | 0 | Beginning | 4 | 2 | Vertical | Other - Doorvalveilig 1-zijdig: no; Doorvalveilig 2-zijdig: yes; Text - NLRS_C_merk: K01
Basic Wall:21_DAT_isolatie minerale wol_160:5536750 | 00 Begane grond | 21.10 Uniformat (Uniformat) | 464.8 | 2812.67 | 9245 | 21_DAT_isolatie hard_74 | 2 | Walls | Non-bearing | Hoogwaardige isolatie met een RC van 4.7 m²K/W | 21.10 |  |  | 21.10 | buitenwanden; niet constructief, algemeen (verzamelniveau) | Hoogwaardige isolatie met een RC van 4.7 m²K/W | Walls | Basic Wall | Basic Wall: 21_DAT_isolatie hard_74 | 21_DAT_isolatie hard_74 | 5724015 | -45 | no | yes | 0 | -882.333 | 2812.67 | 8.03001 | 9245 | Bouwkundig | 2. nieuwbouw | Non-bearing |  |  |  |  | Vertical | Dimensions - Volume: 0.562101 m3; Constraints - Base Extension Distance: 0 mm; Top Extension Distance: 0 mm; Location Line: Finish Face: Interior; Top Constraint: Up to level: 1
Basic Wall:21_DAT_isolatie minerale wol_160:5536751 | 00 Begane grond | 21.10 Uniformat (Uniformat) | 464.8 | 2630 | 2120 | K_02 | 2 | Walls | Non-bearing | Kunststof kozijn Gealan Kubus | 31 | Kunststof kozijn Gealan Kubus | 31 | 31 | buitenwandopeningen | Kunststof kozijn Gealan Kubus | Walls | Curtain Wall | Curtain Wall: K_02 | K_02 | 4792108 | 10 | no | yes | 0 | 0 | 2630 | 5.5756 | 2120 | Bouwkundig | 2. nieuwbouw | Non-bearing | 0 | Beginning | 4 | 2 | Vertical | Other - Doorvalveilig 1-zijdig: no; Doorvalveilig 2-zijdig: yes; Text - NLRS_C_merk: K01
2 x Basic Wall:21_DAT_isolatie minerale wol_160:5536751 | 00 Begane grond | 21.10 Uniformat (Uniformat) | 464.8 | 2630 | 920 | K_01 | 2 | Walls | Non-bearing | Kunststof kozijn Gealan Kubus | 31 | Kunststof kozijn Gealan Kubus | 31 | 31 | buitenwandopeningen | Kunststof kozijn Gealan Kubus | Walls | Curtain Wall | Curtain Wall: K_01 | K_01 | 4774158 | 10 | no | yes | 0 | 0 | 2630 | 2.4196 | 920 | Bouwkundig | 2. nieuwbouw | Non-bearing | 0 | Beginning | 4 | 2 | Vertical | Other - Doorvalveilig 1-zijdig: no; Doorvalveilig 2-zijdig: yes; Text - NLRS_C_merk: K01
Basic Wall:21_DAT_isolatie minerale wol_160:5536751 | 00 Begane grond | 21.10 Uniformat (Uniformat) | 464.8 | 2610 | 2120 | K_03 | 2 | Walls | Non-bearing | Kunststof kozijn Gealan Linear | 31 | Kunststof kozijn Gealan Linear | 31 | 31 | buitenwandopeningen | Kunststof kozijn Gealan Linear | Walls | Curtain Wall | Curtain Wall: K_03 | K_03 | 4793066 | 30 | no | yes | 0 | 0 | 2610 | 5.5332 | 2120 | Bouwkundig | 2. nieuwbouw | Non-bearing | 0 | Beginning | 4 | 2 | Vertical | Other - Doorvalveilig 1-zijdig: no; Doorvalveilig 2-zijdig: yes; Text - NLRS_C_merk: K01
Basic Wall:21_DAT_isolatie minerale wol_160:5536751 | 00 Begane grond | 21.10 Uniformat (Uniformat) | 464.8 | 2630 | 1865 | K_21 | 2 | Walls | Non-bearing | Kunststof kozijn Gealan Kubus | 31 | Kunststof kozijn Gealan Kubus | 31 | 31 | buitenwandopeningen | Kunststof kozijn Gealan Kubus | Walls | Curtain Wall | Curtain Wall: K_21 | K_21 | 5077807 | 10 | no | yes | 0 | 0 | 2630 | 4.90495 | 1865 | Bouwkundig | 2. nieuwbouw | Non-bearing | 0 | Beginning | 4 | 2 | Vertical | Other - Doorvalveilig 1-zijdig: no; Doorvalveilig 2-zijdig: yes; Text - NLRS_C_merk: K01
Basic Wall:21_DAT_isolatie minerale wol_160:5536751 | 00 Begane grond | 21.10 Uniformat (Uniformat) | 464.8 | 2812.67 | 9525 | 21_DAT_isolatie hard_85 | 2 | Walls | Non-bearing | Hoogwaardige isolatie met een RC van 4.7 m²K/W | 21.10 |  |  | 21.10 | buitenwanden; niet constructief, algemeen (verzamelniveau) | Hoogwaardige isolatie met een RC van 4.7 m²K/W | Walls | Basic Wall | Basic Wall: 21_DAT_isolatie hard_85 | 21_DAT_isolatie hard_85 | 5664636 | -45 | no | yes | 0 | -882.333 | 2812.67 | 5.93771 | 9525 | Bouwkundig | 2. nieuwbouw | Non-bearing |  |  |  |  | Vertical | Dimensions - Volume: 0.504705 m3; Constraints - Base Extension Distance: 0 mm; Top Extension Distance: 0 mm; Location Line: Finish Face: Interior; Top Constraint: Up to level: 1
3 x Basic Wall:21_DAT_isolatie minerale wol_160:5536752 | 00 Begane grond | 21.10 Uniformat (Uniformat) | 464.8 | 2630 | 740 | K_04 | 2 | Walls | Non-bearing | Kunststof kozijn Gealan Kubus | 31 | Kunststof kozijn Gealan Kubus | 31 | 31 | buitenwandopeningen | Kunststof kozijn Gealan Kubus | Walls | Curtain Wall | Curtain Wall: K_04 | K_04 | 4800906 | 10 | no | yes | 0 | 0 | 2630 | 1.9462 | 740 | Bouwkundig | 2. nieuwbouw | Non-bearing | 0 | Beginning | 4 | 2 | Vertical | Other - Doorvalveilig 1-zijdig: no; Doorvalveilig 2-zijdig: yes; Text - NLRS_C_merk: K01
Basic Wall:21_DAT_isolatie minerale wol_160:5536752 | 00 Begane grond | 21.10 Uniformat (Uniformat) | 464.8 | 2630 | 2120 | K_02 | 2 | Walls | Non-bearing | Kunststof kozijn Gealan Kubus | 31 | Kunststof kozijn Gealan Kubus | 31 | 31 | buitenwandopeningen | Kunststof kozijn Gealan Kubus | Walls | Curtain Wall | Curtain Wall: K_02 | K_02 | 4792108 | 10 | no | yes | 0 | 0 | 2630 | 5.5756 | 2120 | Bouwkundig | 2. nieuwbouw | Non-bearing | 0 | Beginning | 4 | 2 | Vertical | Other - Doorvalveilig 1-zijdig: no; Doorvalveilig 2-zijdig: yes; Text - NLRS_C_merk: K01
Basic Wall:21_DAT_isolatie minerale wol_160:5536752 | 00 Begane grond | 21.10 Uniformat (Uniformat) | 464.8 | 2610 | 2120 | K_03 | 2 | Walls | Non-bearing | Kunststof kozijn Gealan Linear | 31 | Kunststof kozijn Gealan Linear | 31 | 31 | buitenwandopeningen | Kunststof kozijn Gealan Linear | Walls | Curtain Wall | Curtain Wall: K_03 | K_03 | 4793066 | 30 | no | yes | 0 | 0 | 2610 | 5.5332 | 2120 | Bouwkundig | 2. nieuwbouw | Non-bearing | 0 | Beginning | 4 | 2 | Vertical | Other - Doorvalveilig 1-zijdig: no; Doorvalveilig 2-zijdig: yes; Text - NLRS_C_merk: K01
Basic Wall:21_DAT_isolatie minerale wol_160:5536752 | 00 Begane grond | 21.10 Uniformat (Uniformat) | 464.8 | 2757.67 | 9260 | 21_DAT_isolatie hard_85 | 2 | Walls | Non-bearing | Hoogwaardige isolatie met een RC van 4.7 m²K/W | 21.10 |  |  | 21.10 | buitenwanden; niet constructief, algemeen (verzamelniveau) | Hoogwaardige isolatie met een RC van 4.7 m²K/W | Walls | Basic Wall | Basic Wall: 21_DAT_isolatie hard_85 | 21_DAT_isolatie hard_85 | 5664636 | 10 | no | yes | 0 | -882.333 | 2757.67 | 5.6167 | 9260 | Bouwkundig | 2. nieuwbouw | Non-bearing |  |  |  |  | Vertical | Dimensions - Volume: 0.47742 m3; Constraints - Base Extension Distance: 0 mm; Top Extension Distance: 0 mm; Location Line: Finish Face: Interior; Top Constraint: Up to level: 1
2 x Basic Wall:21_DAT_isolatie minerale wol_160:5536753 | 00 Begane grond | 21.10 Uniformat (Uniformat) | 464.8 | 1930 | 2040 | K_17 | 2 | Walls | Non-bearing | Kunststof kozijn Gealan Kubus | 31 | Kunststof kozijn Gealan Kubus | 31 | 31 | buitenwandopeningen | Kunststof kozijn Gealan Kubus | Walls | Curtain Wall | Curtain Wall: K_17 | K_17 | 6061266 | 710 | no | yes | 0 | 0 | 1930 | 3.9372 | 2040 | Bouwkundig | 2. nieuwbouw | Non-bearing | 0 | Beginning | 4 | 2 | Vertical | Other - Doorvalveilig 1-zijdig: no; Doorvalveilig 2-zijdig: yes; Text - NLRS_C_merk: K01
2 x Basic Wall:21_DAT_isolatie minerale wol_160:5536753 | 00 Begane grond | 21.10 Uniformat (Uniformat) | 464.8 | 2366.66 | 2280 | 21_DAT_isolatie hard_74 | 2 | Walls | Non-bearing | Hoogwaardige isolatie met een RC van 4.7 m²K/W | 21.10 |  |  | 21.10 | buitenwanden; niet constructief, algemeen (verzamelniveau) | Hoogwaardige isolatie met een RC van 4.7 m²K/W | Walls | Basic Wall | Basic Wall: 21_DAT_isolatie hard_74 | 21_DAT_isolatie hard_74 | 5724015 | 388.34 | no | yes | 0 | 0 | 2366.66 | 1.45879 | 2280 | Bouwkundig | 2. nieuwbouw | Non-bearing |  |  |  |  | Vertical | Dimensions - Volume: 0.102115 m3; Constraints - Base Extension Distance: 0 mm; Top Extension Distance: 0 mm; Location Line: Finish Face: Interior
Basic Wall:21_DAT_isolatie minerale wol_160:5536753 | 00 Begane grond | 21.10 Uniformat (Uniformat) | 464.8 | 1930 | 880 | K_16 | 2 | Walls | Non-bearing | Kunststof kozijn Gealan Kubus | 31 | Kunststof kozijn Gealan Kubus | 31 | 31 | buitenwandopeningen | Kunststof kozijn Gealan Kubus | Walls | Curtain Wall | Curtain Wall: K_16 | K_16 | 6074129 | 710 | no | yes | 0 | 0 | 1930 | 1.6984 | 880 | Bouwkundig | 2. nieuwbouw | Non-bearing | 0 | Beginning | 4 | 2 | Vertical | Other - Doorvalveilig 1-zijdig: no; Doorvalveilig 2-zijdig: yes; Text - NLRS_C_merk: K01
2 x Basic Wall:21_DAT_isolatie minerale wol_160:5536753 | 00 Begane grond | 21.10 Uniformat (Uniformat) | 464.8 | 2750 | 1120 | 21_DAT_isolatie hard_74 | 2 | Walls | Non-bearing | Hoogwaardige isolatie met een RC van 4.7 m²K/W | 21.10 |  |  | 21.10 | buitenwanden; niet constructief, algemeen (verzamelniveau) | Hoogwaardige isolatie met een RC van 4.7 m²K/W | Walls | Basic Wall | Basic Wall: 21_DAT_isolatie hard_74 | 21_DAT_isolatie hard_74 | 5724015 | 520 | no | yes | 0 | 0 | 2750 | 1.3816 | 1120 | Bouwkundig | 2. nieuwbouw | Non-bearing |  |  |  |  | Vertical | Dimensions - Volume: 0.096712 m3; Constraints - Base Extension Distance: 0 mm; Top Extension Distance: 0 mm; Location Line: Finish Face: Interior
3 x Basic Wall:21_DAT_metselwerk_100:5536756 | 00 Begane grond | 21.12 Uniformat (Uniformat) | 404.8 | 2630 | 740 | K_04 | 2 | Walls | Non-bearing | Kunststof kozijn Gealan Kubus | 31 | Kunststof kozijn Gealan Kubus | 31 | 31 | buitenwandopeningen | Kunststof kozijn Gealan Kubus | Walls | Curtain Wall | Curtain Wall: K_04 | K_04 | 4800906 | 10 | no | yes | 0 | 0 | 2630 | 1.9462 | 740 | Bouwkundig | 2. nieuwbouw | Non-bearing | 0 | Beginning | 4 | 2 | Vertical | Other - Doorvalveilig 1-zijdig: no; Doorvalveilig 2-zijdig: yes; Text - NLRS_C_merk: K01
Basic Wall:21_DAT_metselwerk_100:5536756 | 00 Begane grond | 21.12 Uniformat (Uniformat) | 404.8 | 2610 | 2120 | K_03 | 2 | Walls | Non-bearing | Kunststof kozijn Gealan Linear | 31 | Kunststof kozijn Gealan Linear | 31 | 31 | buitenwandopeningen | Kunststof kozijn Gealan Linear | Walls | Curtain Wall | Curtain Wall: K_03 | K_03 | 4793066 | 30 | no | yes | 0 | 0 | 2610 | 5.5332 | 2120 | Bouwkundig | 2. nieuwbouw | Non-bearing | 0 | Beginning | 4 | 2 | Vertical | Other - Doorvalveilig 1-zijdig: no; Doorvalveilig 2-zijdig: yes; Text - NLRS_C_merk: K01
Basic Wall:21_DAT_metselwerk_100:5536756 | 00 Begane grond | 21.12 Uniformat (Uniformat) | 404.8 | 2630 | 2120 | K_02 | 2 | Walls | Non-bearing | Kunststof kozijn Gealan Kubus | 31 | Kunststof kozijn Gealan Kubus | 31 | 31 | buitenwandopeningen | Kunststof kozijn Gealan Kubus | Walls | Curtain Wall | Curtain Wall: K_02 | K_02 | 4792108 | 10 | no | yes | 0 | 0 | 2630 | 5.5756 | 2120 | Bouwkundig | 2. nieuwbouw | Non-bearing | 0 | Beginning | 4 | 2 | Vertical | Other - Doorvalveilig 1-zijdig: no; Doorvalveilig 2-zijdig: yes; Text - NLRS_C_merk: K01
Basic Wall:21_DAT_isolatie minerale wol_160:5536757 | 01 eerste verdieping | 21.10 Uniformat (Uniformat) | 464.8 | 6756.7 | 2295 | 21_DAT_isolatie hard_74 | 2 | Walls | Non-bearing | Hoogwaardige isolatie met een RC van 4.7 m²K/W | 21.10 |  |  | 21.10 | buitenwanden; niet constructief, algemeen (verzamelniveau) | Hoogwaardige isolatie met een RC van 4.7 m²K/W | Walls | Basic Wall | Basic Wall: 21_DAT_isolatie hard_74 | 21_DAT_isolatie hard_74 | 5724015 | -3256.7 | no | yes | 1 | 0 | 6756.7 | 3.40822 | 2295 | Bouwkundig | 2. nieuwbouw | Non-bearing |  |  |  |  | Vertical | Dimensions - Volume: 0.238575 m3; Constraints - Base Extension Distance: 0 mm; Top Extension Distance: 0 mm; Location Line: Finish Face: Interior
Basic Wall:21_DAT_isolatie minerale wol_160:5536757 | 01 eerste verdieping | 21.10 Uniformat (Uniformat) | 464.8 | 4125 | 880 | 21_DAT_isolatie hard_74 | 2 | Walls | Non-bearing | Hoogwaardige isolatie met een RC van 4.7 m²K/W | 21.10 |  |  | 21.10 | buitenwanden; niet constructief, algemeen (verzamelniveau) | Hoogwaardige isolatie met een RC van 4.7 m²K/W | Walls | Basic Wall | Basic Wall: 21_DAT_isolatie hard_74 | 21_DAT_isolatie hard_74 | 5724015 | -625 | no | yes | 1 | 0 | 4125 | 1.1178 | 880 | Bouwkundig | 2. nieuwbouw | Non-bearing |  |  |  |  | Vertical | Dimensions - Volume: 0.078246 m3; Constraints - Base Extension Distance: 0 mm; Top Extension Distance: 0 mm; Location Line: Finish Face: Interior
Basic Wall:21_DAT_isolatie minerale wol_160:5536757 | 01 eerste verdieping | 21.10 Uniformat (Uniformat) | 464.8 | 3500 | 190 | 21_DAT_isolatie hard_74 | 2 | Walls | Non-bearing | Hoogwaardige isolatie met een RC van 4.7 m²K/W | 21.10 |  |  | 21.10 | buitenwanden; niet constructief, algemeen (verzamelniveau) | Hoogwaardige isolatie met een RC van 4.7 m²K/W | Walls | Basic Wall | Basic Wall: 21_DAT_isolatie hard_74 | 21_DAT_isolatie hard_74 | 5724015 | 0 | no | yes | 1 | 0 | 3500 | 0.665 | 190 | Bouwkundig | 2. nieuwbouw | Non-bearing |  |  |  |  | Vertical | Dimensions - Volume: 0.04655 m3; Constraints - Base Extension Distance: 0 mm; Top Extension Distance: 0 mm; Location Line: Finish Face: Interior
Basic Wall:21_DAT_isolatie minerale wol_160:5536757 | 01 eerste verdieping | 21.10 Uniformat (Uniformat) | 464.8 | 3500 | 880 | 21_DAT_isolatie hard_74 | 2 | Walls | Non-bearing | Hoogwaardige isolatie met een RC van 4.7 m²K/W | 21.10 |  |  | 21.10 | buitenwanden; niet constructief, algemeen (verzamelniveau) | Hoogwaardige isolatie met een RC van 4.7 m²K/W | Walls | Basic Wall | Basic Wall: 21_DAT_isolatie hard_74 | 21_DAT_isolatie hard_74 | 5724015 | 0 | no | yes | 1 | 0 | 3500 | 1.06155 | 880 | Bouwkundig | 2. nieuwbouw | Non-bearing |  |  |  |  | Vertical | Dimensions - Volume: 0.0743085 m3; Constraints - Base Extension Distance: 0 mm; Top Extension Distance: 0 mm; Location Line: Finish Face: Interior
Basic Wall:21_DAT_isolatie minerale wol_160:5536757 | 01 eerste verdieping | 21.10 Uniformat (Uniformat) | 464.8 | 2937.5 | 190 | 21_DAT_isolatie hard_74 | 2 | Walls | Non-bearing | Hoogwaardige isolatie met een RC van 4.7 m²K/W | 21.10 |  |  | 21.10 | buitenwanden; niet constructief, algemeen (verzamelniveau) | Hoogwaardige isolatie met een RC van 4.7 m²K/W | Walls | Basic Wall | Basic Wall: 21_DAT_isolatie hard_74 | 21_DAT_isolatie hard_74 | 5724015 | 562.5 | no | yes | 1 | 0 | 2937.5 | 0.558125 | 190 | Bouwkundig | 2. nieuwbouw | Non-bearing |  |  |  |  | Vertical | Dimensions - Volume: 0.0390687 m3; Constraints - Base Extension Distance: 0 mm; Top Extension Distance: 0 mm; Location Line: Finish Face: Interior
Basic Wall:21_DAT_isolatie minerale wol_160:5536757 | 01 eerste verdieping | 21.10 Uniformat (Uniformat) | 464.8 | 2937.5 | 25100 | 21_DAT_isolatie hard_74 | 2 | Walls | Non-bearing | Hoogwaardige isolatie met een RC van 4.7 m²K/W | 21.10 |  |  | 21.10 | buitenwanden; niet constructief, algemeen (verzamelniveau) | Hoogwaardige isolatie met een RC van 4.7 m²K/W | Walls | Basic Wall | Basic Wall: 21_DAT_isolatie hard_74 | 21_DAT_isolatie hard_74 | 5724015 | 562.5 | no | yes | 1 | 0 | 2937.5 | 32.6609 | 25100 | Bouwkundig | 2. nieuwbouw | Non-bearing |  |  |  |  | Vertical | Dimensions - Volume: 2.28626 m3; Constraints - Base Extension Distance: 0 mm; Top Extension Distance: 0 mm; Location Line: Finish Face: Interior
Basic Wall:21_DAT_isolatie minerale wol_160:5536757 | 01 eerste verdieping | 21.10 Uniformat (Uniformat) | 464.8 | 3180 | 790 | K_12 | 2 | Walls | Non-bearing | Kunststof kozijn Gealan Kubus | 31 | Kunststof kozijn Gealan Kubus | 31 | 31 | buitenwandopeningen | Kunststof kozijn Gealan Kubus | Walls | Curtain Wall | Curtain Wall: K_12 | K_12 | 4860014 | 3210 | no | yes | 0 | 0 | 3180 | 2.5122 | 790 | Bouwkundig | 2. nieuwbouw | Non-bearing | 0 | Beginning | 4 | 2 | Vertical | Other - Doorvalveilig 1-zijdig: no; Doorvalveilig 2-zijdig: yes; Text - NLRS_C_merk: K01
Basic Wall:21_DAT_isolatie minerale wol_160:5536757 | 01 eerste verdieping | 21.10 Uniformat (Uniformat) | 464.8 | 3805 | 790 | K_11 | 2 | Walls | Non-bearing | Kunststof kozijn Gealan Kubus | 31 | Kunststof kozijn Gealan Kubus | 31 | 31 | buitenwandopeningen | Kunststof kozijn Gealan Kubus | Walls | Curtain Wall | Curtain Wall: K_11 | K_11 | 4859827 | 2585 | no | yes | 0 | 0 | 3805 | 3.00595 | 790 | Bouwkundig | 2. nieuwbouw | Non-bearing | 0 | Beginning | 4 | 2 | Vertical | Other - Doorvalveilig 1-zijdig: no; Doorvalveilig 2-zijdig: yes; Text - NLRS_C_merk: K01
Basic Wall:21_DAT_isolatie minerale wol_160:5536757 | 01 eerste verdieping | 21.10 Uniformat (Uniformat) | 464.8 | 4430 | 790 | K_10 | 2 | Walls | Non-bearing | Kunststof kozijn Gealan Kubus | 31 | Kunststof kozijn Gealan Kubus | 31 | 31 | buitenwandopeningen | Kunststof kozijn Gealan Kubus | Walls | Curtain Wall | Curtain Wall: K_10 | K_10 | 4859456 | 1960 | no | yes | 0 | 0 | 4430 | 3.4997 | 790 | Bouwkundig | 2. nieuwbouw | Non-bearing | 0 | Beginning | 4 | 2 | Vertical | Other - Doorvalveilig 1-zijdig: no; Doorvalveilig 2-zijdig: yes; Text - NLRS_C_merk: K01
Basic Wall:21_DAT_isolatie minerale wol_160:5536757 | 01 eerste verdieping | 21.10 Uniformat (Uniformat) | 464.8 | 5055 | 790 | K_09 | 2 | Walls | Non-bearing | Kunststof kozijn Gealan Kubus | 31 | Kunststof kozijn Gealan Kubus | 31 | 31 | buitenwandopeningen | Kunststof kozijn Gealan Kubus | Walls | Curtain Wall | Curtain Wall: K_09 | K_09 | 4858854 | 1335 | no | yes | 0 | 0 | 5055 | 3.99345 | 790 | Bouwkundig | 2. nieuwbouw | Non-bearing | 0 | Beginning | 4 | 2 | Vertical | Other - Doorvalveilig 1-zijdig: no; Doorvalveilig 2-zijdig: yes; Text - NLRS_C_merk: K01
Basic Wall:21_DAT_isolatie minerale wol_160:5536757 | 01 eerste verdieping | 21.10 Uniformat (Uniformat) | 464.8 | 5680 | 2130 | K_08 | 2 | Walls | Non-bearing | Kunststof kozijn Gealan Kubus | 31 | Kunststof kozijn Gealan Kubus | 31 | 31 | buitenwandopeningen | Kunststof kozijn Gealan Kubus | Walls | Curtain Wall | Curtain Wall: K_08 | K_08 | 4854521 | 710 | no | yes | 0 | 0 | 5680 | 12.0984 | 2130 | Bouwkundig | 2. nieuwbouw | Non-bearing | 0 | Beginning | 4 | 2 | Vertical | Other - Doorvalveilig 1-zijdig: no; Doorvalveilig 2-zijdig: yes; Text - NLRS_C_merk: K01
Basic Wall:21_DAT_isolatie minerale wol_160:5536757 | 01 eerste verdieping | 21.10 Uniformat (Uniformat) | 464.8 | 2555 | 790 | K_13 | 2 | Walls | Non-bearing | Kunststof kozijn Gealan Kubus | 31 | Kunststof kozijn Gealan Kubus | 31 | 31 | buitenwandopeningen | Kunststof kozijn Gealan Kubus | Walls | Curtain Wall | Curtain Wall: K_13 | K_13 | 4860509 | 3835 | no | yes | 0 | 0 | 2555 | 2.01845 | 790 | Bouwkundig | 2. nieuwbouw | Non-bearing | 0 | Beginning | 4 | 2 | Vertical | Other - Doorvalveilig 1-zijdig: no; Doorvalveilig 2-zijdig: yes; Text - NLRS_C_merk: K01
7 x Basic Wall:21_DAT_isolatie minerale wol_160:5536757 | 01 eerste verdieping | 21.10 Uniformat (Uniformat) | 464.8 | 1930 | 2250 | K_22 | 2 | Walls | Non-bearing | Kunststof kozijn Gealan Kubus | 31 | Kunststof kozijn Gealan Kubus | 31 | 31 | buitenwandopeningen | Kunststof kozijn Gealan Kubus | Walls | Curtain Wall | Curtain Wall: K_22 | K_22 | 4917986 | 810 | no | yes | 1 | 0 | 1930 | 4.3425 | 2250 | Bouwkundig | 2. nieuwbouw | Non-bearing | 0 | Beginning | 4 | 2 | Vertical | Other - Doorvalveilig 1-zijdig: no; Doorvalveilig 2-zijdig: yes; Text - NLRS_C_merk: K01
9 x Basic Wall:21_DAT_isolatie minerale wol_160:5536757 | 01 eerste verdieping | 21.10 Uniformat (Uniformat) | 464.8 | 1930 | 790 | K_29 | 2 | Walls | Non-bearing | Kunststof kozijn Gealan Kubus | 31 | Kunststof kozijn Gealan Kubus | 31 | 31 | buitenwandopeningen | Kunststof kozijn Gealan Kubus | Walls | Curtain Wall | Curtain Wall: K_29 | K_29 | 4860879 | 810 | no | yes | 1 | 0 | 1930 | 1.5247 | 790 | Bouwkundig | 2. nieuwbouw | Non-bearing | 0 | Beginning | 4 | 2 | Vertical | Other - Doorvalveilig 1-zijdig: no; Doorvalveilig 2-zijdig: yes; Text - NLRS_C_merk: K01
Basic Wall:21_DAT_isolatie minerale wol_160:5536757 | 01 eerste verdieping | 21.10 Uniformat (Uniformat) | 464.8 | 5375 | 880 | 21_DAT_isolatie hard_74 | 2 | Walls | Non-bearing | Hoogwaardige isolatie met een RC van 4.7 m²K/W | 21.10 |  |  | 21.10 | buitenwanden; niet constructief, algemeen (verzamelniveau) | Hoogwaardige isolatie met een RC van 4.7 m²K/W | Walls | Basic Wall | Basic Wall: 21_DAT_isolatie hard_74 | 21_DAT_isolatie hard_74 | 5724015 | -1875 | no | yes | 1 | 0 | 5375 | 1.2303 | 880 | Bouwkundig | 2. nieuwbouw | Non-bearing |  |  |  |  | Vertical | Dimensions - Volume: 0.086121 m3; Constraints - Base Extension Distance: 0 mm; Top Extension Distance: 0 mm; Location Line: Finish Face: Interior
Basic Wall:21_DAT_isolatie minerale wol_160:5536757 | 01 eerste verdieping | 21.10 Uniformat (Uniformat) | 464.8 | 5375 | 190 | 21_DAT_isolatie hard_74 | 2 | Walls | Non-bearing | Hoogwaardige isolatie met een RC van 4.7 m²K/W | 21.10 |  |  | 21.10 | buitenwanden; niet constructief, algemeen (verzamelniveau) | Hoogwaardige isolatie met een RC van 4.7 m²K/W | Walls | Basic Wall | Basic Wall: 21_DAT_isolatie hard_74 | 21_DAT_isolatie hard_74 | 5724015 | -1875 | no | yes | 1 | 0 | 5375 | 1.02125 | 190 | Bouwkundig | 2. nieuwbouw | Non-bearing |  |  |  |  | Vertical | Dimensions - Volume: 0.0714875 m3; Constraints - Base Extension Distance: 0 mm; Top Extension Distance: 0 mm; Location Line: Finish Face: Interior
Basic Wall:21_DAT_isolatie minerale wol_160:5536757 | 01 eerste verdieping | 21.10 Uniformat (Uniformat) | 464.8 | 6000 | 880 | 21_DAT_isolatie hard_74 | 2 | Walls | Non-bearing | Hoogwaardige isolatie met een RC van 4.7 m²K/W | 21.10 |  |  | 21.10 | buitenwanden; niet constructief, algemeen (verzamelniveau) | Hoogwaardige isolatie met een RC van 4.7 m²K/W | Walls | Basic Wall | Basic Wall: 21_DAT_isolatie hard_74 | 21_DAT_isolatie hard_74 | 5724015 | -2500 | no | yes | 1 | 0 | 6000 | 1.28655 | 880 | Bouwkundig | 2. nieuwbouw | Non-bearing |  |  |  |  | Vertical | Dimensions - Volume: 0.0900585 m3; Constraints - Base Extension Distance: 0 mm; Top Extension Distance: 0 mm; Location Line: Finish Face: Interior
Basic Wall:21_DAT_isolatie minerale wol_160:5536757 | 01 eerste verdieping | 21.10 Uniformat (Uniformat) | 464.8 | 6000 | 190 | 21_DAT_isolatie hard_74 | 2 | Walls | Non-bearing | Hoogwaardige isolatie met een RC van 4.7 m²K/W | 21.10 |  |  | 21.10 | buitenwanden; niet constructief, algemeen (verzamelniveau) | Hoogwaardige isolatie met een RC van 4.7 m²K/W | Walls | Basic Wall | Basic Wall: 21_DAT_isolatie hard_74 | 21_DAT_isolatie hard_74 | 5724015 | -2500 | no | yes | 1 | 0 | 6000 | 1.14 | 190 | Bouwkundig | 2. nieuwbouw | Non-bearing |  |  |  |  | Vertical | Dimensions - Volume: 0.0798 m3; Constraints - Base Extension Distance: 0 mm; Top Extension Distance: 0 mm; Location Line: Finish Face: Interior
Basic Wall:21_DAT_isolatie minerale wol_160:5536757 | 01 eerste verdieping | 21.10 Uniformat (Uniformat) | 464.8 | 4750 | 190 | 21_DAT_isolatie hard_74 | 2 | Walls | Non-bearing | Hoogwaardige isolatie met een RC van 4.7 m²K/W | 21.10 |  |  | 21.10 | buitenwanden; niet constructief, algemeen (verzamelniveau) | Hoogwaardige isolatie met een RC van 4.7 m²K/W | Walls | Basic Wall | Basic Wall: 21_DAT_isolatie hard_74 | 21_DAT_isolatie hard_74 | 5724015 | -1250 | no | yes | 1 | 0 | 4750 | 0.9025 | 190 | Bouwkundig | 2. nieuwbouw | Non-bearing |  |  |  |  | Vertical | Dimensions - Volume: 0.063175 m3; Constraints - Base Extension Distance: 0 mm; Top Extension Distance: 0 mm; Location Line: Finish Face: Interior
Basic Wall:21_DAT_isolatie minerale wol_160:5536757 | 01 eerste verdieping | 21.10 Uniformat (Uniformat) | 464.8 | 4750 | 880 | 21_DAT_isolatie hard_74 | 2 | Walls | Non-bearing | Hoogwaardige isolatie met een RC van 4.7 m²K/W | 21.10 |  |  | 21.10 | buitenwanden; niet constructief, algemeen (verzamelniveau) | Hoogwaardige isolatie met een RC van 4.7 m²K/W | Walls | Basic Wall | Basic Wall: 21_DAT_isolatie hard_74 | 21_DAT_isolatie hard_74 | 5724015 | -1250 | no | yes | 1 | 0 | 4750 | 1.17405 | 880 | Bouwkundig | 2. nieuwbouw | Non-bearing |  |  |  |  | Vertical | Dimensions - Volume: 0.0821835 m3; Constraints - Base Extension Distance: 0 mm; Top Extension Distance: 0 mm; Location Line: Finish Face: Interior
Basic Wall:21_DAT_isolatie minerale wol_160:5536757 | 01 eerste verdieping | 21.10 Uniformat (Uniformat) | 464.8 | 4125 | 190 | 21_DAT_isolatie hard_74 | 2 | Walls | Non-bearing | Hoogwaardige isolatie met een RC van 4.7 m²K/W | 21.10 |  |  | 21.10 | buitenwanden; niet constructief, algemeen (verzamelniveau) | Hoogwaardige isolatie met een RC van 4.7 m²K/W | Walls | Basic Wall | Basic Wall: 21_DAT_isolatie hard_74 | 21_DAT_isolatie hard_74 | 5724015 | -625 | no | yes | 1 | 0 | 4125 | 0.78375 | 190 | Bouwkundig | 2. nieuwbouw | Non-bearing |  |  |  |  | Vertical | Dimensions - Volume: 0.0548625 m3; Constraints - Base Extension Distance: 0 mm; Top Extension Distance: 0 mm; Location Line: Finish Face: Interior
Basic Wall:21_DAT_isolatie minerale wol_160:5536757 | 01 eerste verdieping | 21.10 Uniformat (Uniformat) | 464.8 | 2937.5 | 880 | 21_DAT_isolatie hard_74 | 2 | Walls | Non-bearing | Hoogwaardige isolatie met een RC van 4.7 m²K/W | 21.10 |  |  | 21.10 | buitenwanden; niet constructief, algemeen (verzamelniveau) | Hoogwaardige isolatie met een RC van 4.7 m²K/W | Walls | Basic Wall | Basic Wall: 21_DAT_isolatie hard_74 | 21_DAT_isolatie hard_74 | 5724015 | 562.5 | no | yes | 1 | 0 | 2937.5 | 1.0603 | 880 | Bouwkundig | 2. nieuwbouw | Non-bearing |  |  |  |  | Vertical | Dimensions - Volume: 0.074221 m3; Constraints - Base Extension Distance: 0 mm; Top Extension Distance: 0 mm; Location Line: Finish Face: Interior
Basic Wall:21_DAT_isolatie minerale wol_160:5536757 | 01 eerste verdieping | 21.10 Uniformat (Uniformat) | 464.8 | 2937.5 | 170 | 21_DAT_isolatie hard_74 | 2 | Walls | Non-bearing | Hoogwaardige isolatie met een RC van 4.7 m²K/W | 21.10 |  |  | 21.10 | buitenwanden; niet constructief, algemeen (verzamelniveau) | Hoogwaardige isolatie met een RC van 4.7 m²K/W | Walls | Basic Wall | Basic Wall: 21_DAT_isolatie hard_74 | 21_DAT_isolatie hard_74 | 5724015 | 562.5 | no | yes | 1 | 0 | 2937.5 | 0.499375 | 170 | Bouwkundig | 2. nieuwbouw | Non-bearing |  |  |  |  | Vertical | Dimensions - Volume: 0.0349562 m3; Constraints - Base Extension Distance: 0 mm; Top Extension Distance: 0 mm; Location Line: Finish Face: Interior
Basic Wall:21_DAT_isolatie minerale wol_160:5536757 | 01 eerste verdieping | 21.10 Uniformat (Uniformat) | 464.8 | 2937.5 | 915 | 21_DAT_isolatie hard_74 | 2 | Walls | Non-bearing | Hoogwaardige isolatie met een RC van 4.7 m²K/W | 21.10 |  |  | 21.10 | buitenwanden; niet constructief, algemeen (verzamelniveau) | Hoogwaardige isolatie met een RC van 4.7 m²K/W | Walls | Basic Wall | Basic Wall: 21_DAT_isolatie hard_74 | 21_DAT_isolatie hard_74 | 5724015 | 562.5 | no | yes | 1 | 0 | 2937.5 | 1.16311 | 915 | Bouwkundig | 2. nieuwbouw | Non-bearing |  |  |  |  | Vertical | Dimensions - Volume: 0.0814179 m3; Constraints - Base Extension Distance: 0 mm; Top Extension Distance: 0 mm; Location Line: Finish Face: Interior
Basic Wall:21_DAT_isolatie minerale wol_160:5536757 | 01 eerste verdieping | 21.10 Uniformat (Uniformat) | 464.8 | 2937.5 | 160 | 21_DAT_isolatie hard_74 | 2 | Walls | Non-bearing | Hoogwaardige isolatie met een RC van 4.7 m²K/W | 21.10 |  |  | 21.10 | buitenwanden; niet constructief, algemeen (verzamelniveau) | Hoogwaardige isolatie met een RC van 4.7 m²K/W | Walls | Basic Wall | Basic Wall: 21_DAT_isolatie hard_74 | 21_DAT_isolatie hard_74 | 5724015 | 562.5 | no | yes | 1 | 0 | 2937.5 | 0.47 | 160 | Bouwkundig | 2. nieuwbouw | Non-bearing |  |  |  |  | Vertical | Dimensions - Volume: 0.0329 m3; Constraints - Base Extension Distance: 0 mm; Top Extension Distance: 0 mm; Location Line: Finish Face: Interior
2 x Basic Wall:21_DAT_isolatie minerale wol_160:5536757 | 01 eerste verdieping | 21.10 Uniformat (Uniformat) | 464.8 | 2375 | 1120 | 21_DAT_isolatie hard_74 | 2 | Walls | Non-bearing | Hoogwaardige isolatie met een RC van 4.7 m²K/W | 21.10 |  |  | 21.10 | buitenwanden; niet constructief, algemeen (verzamelniveau) | Hoogwaardige isolatie met een RC van 4.7 m²K/W | Walls | Basic Wall | Basic Wall: 21_DAT_isolatie hard_74 | 21_DAT_isolatie hard_74 | 5724015 | 500 | no | yes | 1 | 0 | 2375 | 0.9616 | 1120 | Bouwkundig | 2. nieuwbouw | Non-bearing |  |  |  |  | Vertical | Dimensions - Volume: 0.067312 m3; Constraints - Base Extension Distance: 0 mm; Top Extension Distance: 0 mm; Location Line: Finish Face: Interior
Basic Wall:21_DAT_isolatie minerale wol_160:5536759 | 01 eerste verdieping | 21.10 Uniformat (Uniformat) | 464.8 | 2312.5 | 2290 | 21_DAT_isolatie hard_74 | 2 | Walls | Non-bearing | Hoogwaardige isolatie met een RC van 4.7 m²K/W | 21.10 |  |  | 21.10 | buitenwanden; niet constructief, algemeen (verzamelniveau) | Hoogwaardige isolatie met een RC van 4.7 m²K/W | Walls | Basic Wall | Basic Wall: 21_DAT_isolatie hard_74 | 21_DAT_isolatie hard_74 | 5724015 | 652.5 | no | yes | V1 bk. ruwe vloer | 0 | 2312.5 | 1.35842 | 2290 | Bouwkundig | 2. nieuwbouw | Non-bearing |  |  |  |  | Vertical | Dimensions - Volume: 0.0950897 m3; Constraints - Base Extension Distance: 0 mm; Top Extension Distance: 0 mm; Location Line: Finish Face: Interior
2 x Basic Wall:21_DAT_isolatie minerale wol_160:5536759 | 01 eerste verdieping | 21.10 Uniformat (Uniformat) | 464.8 | 2375 | 1120 | 21_DAT_isolatie hard_74 | 2 | Walls | Non-bearing | Hoogwaardige isolatie met een RC van 4.7 m²K/W | 21.10 |  |  | 21.10 | buitenwanden; niet constructief, algemeen (verzamelniveau) | Hoogwaardige isolatie met een RC van 4.7 m²K/W | Walls | Basic Wall | Basic Wall: 21_DAT_isolatie hard_74 | 21_DAT_isolatie hard_74 | 5724015 | 500 | no | yes | 1 | 0 | 2375 | 0.9616 | 1120 | Bouwkundig | 2. nieuwbouw | Non-bearing |  |  |  |  | Vertical | Dimensions - Volume: 0.067312 m3; Constraints - Base Extension Distance: 0 mm; Top Extension Distance: 0 mm; Location Line: Finish Face: Interior
4 x Basic Wall:21_DAT_isolatie minerale wol_160:5536760 | 01 eerste verdieping | 21.10 Uniformat (Uniformat) | 464.8 | 2312.5 | 2290 | 21_DAT_isolatie hard_74 | 2 | Walls | Non-bearing | Hoogwaardige isolatie met een RC van 4.7 m²K/W | 21.10 |  |  | 21.10 | buitenwanden; niet constructief, algemeen (verzamelniveau) | Hoogwaardige isolatie met een RC van 4.7 m²K/W | Walls | Basic Wall | Basic Wall: 21_DAT_isolatie hard_74 | 21_DAT_isolatie hard_74 | 5724015 | 652.5 | no | yes | V1 bk. ruwe vloer | 0 | 2312.5 | 1.35842 | 2290 | Bouwkundig | 2. nieuwbouw | Non-bearing |  |  |  |  | Vertical | Dimensions - Volume: 0.0950897 m3; Constraints - Base Extension Distance: 0 mm; Top Extension Distance: 0 mm; Location Line: Finish Face: Interior
5 x Basic Wall:21_DAT_isolatie minerale wol_160:5536760 | 01 eerste verdieping | 21.10 Uniformat (Uniformat) | 464.8 | 2375 | 1120 | 21_DAT_isolatie hard_74 | 2 | Walls | Non-bearing | Hoogwaardige isolatie met een RC van 4.7 m²K/W | 21.10 |  |  | 21.10 | buitenwanden; niet constructief, algemeen (verzamelniveau) | Hoogwaardige isolatie met een RC van 4.7 m²K/W | Walls | Basic Wall | Basic Wall: 21_DAT_isolatie hard_74 | 21_DAT_isolatie hard_74 | 5724015 | 500 | no | yes | 1 | 0 | 2375 | 0.9616 | 1120 | Bouwkundig | 2. nieuwbouw | Non-bearing |  |  |  |  | Vertical | Dimensions - Volume: 0.067312 m3; Constraints - Base Extension Distance: 0 mm; Top Extension Distance: 0 mm; Location Line: Finish Face: Interior
Basic Wall:21_DAT_isolatie minerale wol_160:5536761 | 01 eerste verdieping | 21.10 Uniformat (Uniformat) | 464.8 | 1930 | 1145 | K_25 | 2 | Walls | Non-bearing | Kunststof kozijn Gealan Kubus | 31 | Kunststof kozijn Gealan Kubus | 31 | 31 | buitenwandopeningen | Kunststof kozijn Gealan Kubus | Walls | Curtain Wall | Curtain Wall: K_25 | K_25 | 4942169 | 810 | no | yes | 1 | 0 | 1930 | 2.20985 | 1145 | Bouwkundig | 2. nieuwbouw | Non-bearing | 0 | Beginning | 4 | 2 | Vertical | Other - Doorvalveilig 1-zijdig: no; Doorvalveilig 2-zijdig: yes; Text - NLRS_C_merk: K01
Basic Wall:21_DAT_isolatie minerale wol_160:5536761 | 01 eerste verdieping | 21.10 Uniformat (Uniformat) | 464.8 | 3425 | 1550 | 21_DAT_isolatie hard_74 | 2 | Walls | Non-bearing | Hoogwaardige isolatie met een RC van 4.7 m²K/W | 21.10 |  |  | 21.10 | buitenwanden; niet constructief, algemeen (verzamelniveau) | Hoogwaardige isolatie met een RC van 4.7 m²K/W | Walls | Basic Wall | Basic Wall: 21_DAT_isolatie hard_74 | 21_DAT_isolatie hard_74 | 5724015 | 562.5 | no | yes | 1 | 0 | 3425 | 3.0989 | 1550 | Bouwkundig | 2. nieuwbouw | Non-bearing |  |  |  |  | Vertical | Dimensions - Volume: 0.216923 m3; Constraints - Base Extension Distance: 0 mm; Top Extension Distance: 0 mm; Location Line: Finish Face: Interior
2 x Basic Wall:21_DAT_isolatie minerale wol_160:5536761 | 01 eerste verdieping | 21.10 Uniformat (Uniformat) | 464.8 | 2312.5 | 2290 | 21_DAT_isolatie hard_74 | 2 | Walls | Non-bearing | Hoogwaardige isolatie met een RC van 4.7 m²K/W | 21.10 |  |  | 21.10 | buitenwanden; niet constructief, algemeen (verzamelniveau) | Hoogwaardige isolatie met een RC van 4.7 m²K/W | Walls | Basic Wall | Basic Wall: 21_DAT_isolatie hard_74 | 21_DAT_isolatie hard_74 | 5724015 | 652.5 | no | yes | V1 bk. ruwe vloer | 0 | 2312.5 | 1.35842 | 2290 | Bouwkundig | 2. nieuwbouw | Non-bearing |  |  |  |  | Vertical | Dimensions - Volume: 0.0950897 m3; Constraints - Base Extension Distance: 0 mm; Top Extension Distance: 0 mm; Location Line: Finish Face: Interior
9 x Basic Wall:21_DAT_isolatie minerale wol_160:5536762 | 01 eerste verdieping | 21.10 Uniformat (Uniformat) | 464.8 | 1930 | 790 | K_29 | 2 | Walls | Non-bearing | Kunststof kozijn Gealan Kubus | 31 | Kunststof kozijn Gealan Kubus | 31 | 31 | buitenwandopeningen | Kunststof kozijn Gealan Kubus | Walls | Curtain Wall | Curtain Wall: K_29 | K_29 | 4860879 | 810 | no | yes | 1 | 0 | 1930 | 1.5247 | 790 | Bouwkundig | 2. nieuwbouw | Non-bearing | 0 | Beginning | 4 | 2 | Vertical | Other - Doorvalveilig 1-zijdig: no; Doorvalveilig 2-zijdig: yes; Text - NLRS_C_merk: K01
Basic Wall:21_DAT_isolatie minerale wol_160:5536762 | 01 eerste verdieping | 21.10 Uniformat (Uniformat) | 464.8 | 1930 | 2250 | K_32 | 2 | Walls | Non-bearing | Kunststof kozijn Gealan Kubus | 31 | Kunststof kozijn Gealan Kubus | 31 | 31 | buitenwandopeningen | Kunststof kozijn Gealan Kubus | Walls | Curtain Wall | Curtain Wall: K_32 | K_32 | 6474551 | 810 | no | yes | 1 | 0 | 1930 | 4.3425 | 2250 | Bouwkundig | 2. nieuwbouw | Non-bearing | 0 | Beginning | 4 | 2 | Vertical | Other - Doorvalveilig 1-zijdig: no; Doorvalveilig 2-zijdig: yes; Text - NLRS_C_merk: K01
6 x Basic Wall:21_DAT_isolatie minerale wol_160:5536762 | 01 eerste verdieping | 21.10 Uniformat (Uniformat) | 464.8 | 1930 | 2250 | K_22 | 2 | Walls | Non-bearing | Kunststof kozijn Gealan Kubus | 31 | Kunststof kozijn Gealan Kubus | 31 | 31 | buitenwandopeningen | Kunststof kozijn Gealan Kubus | Walls | Curtain Wall | Curtain Wall: K_22 | K_22 | 4917986 | 810 | no | yes | 1 | 0 | 1930 | 4.3425 | 2250 | Bouwkundig | 2. nieuwbouw | Non-bearing | 0 | Beginning | 4 | 2 | Vertical | Other - Doorvalveilig 1-zijdig: no; Doorvalveilig 2-zijdig: yes; Text - NLRS_C_merk: K01
Basic Wall:21_DAT_isolatie minerale wol_160:5536762 | 01 eerste verdieping | 21.10 Uniformat (Uniformat) | 464.8 | 2760 | 1495 | K_26 | 2 | Walls | Non-bearing | Kunststof kozijn Gealan Kubus | 31 | Kunststof kozijn Gealan Kubus | 31 | 31 | buitenwandopeningen | Kunststof kozijn Gealan Kubus | Walls | Curtain Wall | Curtain Wall: K_26 | K_26 | 4951884 | -20 | no | yes | 1 | 0 | 2760 | 4.1262 | 1495 | Bouwkundig | 2. nieuwbouw | Non-bearing | 0 | Beginning | 4 | 2 | Vertical | Other - Doorvalveilig 1-zijdig: no; Doorvalveilig 2-zijdig: yes; Text - NLRS_C_merk: K01
Basic Wall:21_DAT_isolatie minerale wol_160:5536762 | 01 eerste verdieping | 21.10 Uniformat (Uniformat) | 464.8 | 2760 | 3450 | K_27 | 2 | Walls | Non-bearing | Kunststof kozijn Gealan Kubus | 31 | Kunststof kozijn Gealan Kubus | 31 | 31 | buitenwandopeningen | Kunststof kozijn Gealan Kubus | Walls | Curtain Wall | Curtain Wall: K_27 | K_27 | 4952631 | -20 | no | yes | 1 | 0 | 2760 | 9.522 | 3450 | Bouwkundig | 2. nieuwbouw | Non-bearing | 0 | Beginning | 4 | 2 | Vertical | Other - Doorvalveilig 1-zijdig: no; Doorvalveilig 2-zijdig: yes; Text - NLRS_C_merk: K01
Basic Wall:21_DAT_isolatie minerale wol_160:5536762 | 01 eerste verdieping | 21.10 Uniformat (Uniformat) | 464.8 | 2350.52 | 35530 | 21_DAT_isolatie hard_74 | 2 | Walls | Non-bearing | Hoogwaardige isolatie met een RC van 4.7 m²K/W | 21.10 |  |  | 21.10 | buitenwanden; niet constructief, algemeen (verzamelniveau) | Hoogwaardige isolatie met een RC van 4.7 m²K/W | Walls | Basic Wall | Basic Wall: 21_DAT_isolatie hard_74 | 21_DAT_isolatie hard_74 | 5724015 | 487.5 | no | yes | 1 | 0 | 2350.52 | 23.913 | 35530 | Bouwkundig | 2. nieuwbouw | Non-bearing |  |  |  |  | Vertical | Dimensions - Volume: 1.67391 m3; Constraints - Base Extension Distance: 0 mm; Top Extension Distance: 0 mm; Location Line: Finish Face: Interior
Basic Wall:21_DAT_isolatie minerale wol_160:5536762 | 01 eerste verdieping | 21.10 Uniformat (Uniformat) | 464.8 | 1930 | 790 | K_30 | 2 | Walls | Non-bearing | Kunststof kozijn Gealan Kubus | 31 | Kunststof kozijn Gealan Kubus | 31 | 31 | buitenwandopeningen | Kunststof kozijn Gealan Kubus | Walls | Curtain Wall | Curtain Wall: K_30 | K_30 | 4942327 | 810 | no | yes | 1 | 0 | 1930 | 1.5247 | 790 | Bouwkundig | 2. nieuwbouw | Non-bearing | 0 | Beginning | 4 | 2 | Vertical | Other - Doorvalveilig 1-zijdig: no; Doorvalveilig 2-zijdig: yes; Text - NLRS_C_merk: K01
Basic Wall:21_DAT_isolatie minerale wol_160:5536762 | 01 eerste verdieping | 21.10 Uniformat (Uniformat) | 464.8 | 2937.5 | 1127 | 21_DAT_isolatie hard_74 | 2 | Walls | Non-bearing | Hoogwaardige isolatie met een RC van 4.7 m²K/W | 21.10 |  |  | 21.10 | buitenwanden; niet constructief, algemeen (verzamelniveau) | Hoogwaardige isolatie met een RC van 4.7 m²K/W | Walls | Basic Wall | Basic Wall: 21_DAT_isolatie hard_74 | 21_DAT_isolatie hard_74 | 5724015 | 562.5 | no | yes | 1 | 0 | 2937.5 | 1.78586 | 1127 | Bouwkundig | 2. nieuwbouw | Non-bearing |  |  |  |  | Vertical | Dimensions - Volume: 0.12501 m3; Constraints - Base Extension Distance: 0 mm; Top Extension Distance: 0 mm; Location Line: Finish Face: Interior
Basic Wall:21_DAT_metselwerk_100:5536766 | 01 eerste verdieping | 21.12 Uniformat (Uniformat) | 404.8 | 515 | 18840 | 21_DAT_gasbeton_100 | 2 | Walls | Non-bearing | Gasbeton 100 mm | 21.10 |  |  | 21.10 | buitenwanden; niet constructief, algemeen (verzamelniveau) | Gasbeton 100 mm | Walls | Basic Wall | Basic Wall: 21_DAT_gasbeton_100 | 21_DAT_gasbeton_100 | 4279461 | 0 | no | yes | V1 bk. ruwe vloer | 0 | 515 | 9.7026 | 18890 | Bouwkundig | 2. nieuwbouw | Non-bearing |  |  |  |  | Vertical | Dimensions - Volume: 0.97026 m3; Constraints - Base Extension Distance: 0 mm; Top Extension Distance: 0 mm; Location Line: Finish Face: Interior
5 x Basic Wall:28_DAT_kalkzandsteen_175mm:5536772 | 00 Begane grond | 28.21 Uniformat (Uniformat) | 479.8 | 1930 | 880 | K_16 | 2 | Walls | Non-bearing | Kunststof kozijn Gealan Kubus | 31 | Kunststof kozijn Gealan Kubus | 31 | 31 | buitenwandopeningen | Kunststof kozijn Gealan Kubus | Walls | Curtain Wall | Curtain Wall: K_16 | K_16 | 6074129 | 710 | no | yes | 0 | 0 | 1930 | 1.6984 | 880 | Bouwkundig | 2. nieuwbouw | Non-bearing | 0 | Beginning | 4 | 2 | Vertical | Other - Doorvalveilig 1-zijdig: no; Doorvalveilig 2-zijdig: yes; Text - NLRS_C_merk: K01
6 x Basic Wall:28_DAT_kalkzandsteen_175mm:5536772 | 00 Begane grond | 28.21 Uniformat (Uniformat) | 479.8 | 1930 | 2040 | K_17 | 2 | Walls | Non-bearing | Kunststof kozijn Gealan Kubus | 31 | Kunststof kozijn Gealan Kubus | 31 | 31 | buitenwandopeningen | Kunststof kozijn Gealan Kubus | Walls | Curtain Wall | Curtain Wall: K_17 | K_17 | 6061266 | 710 | no | yes | 0 | 0 | 1930 | 3.9372 | 2040 | Bouwkundig | 2. nieuwbouw | Non-bearing | 0 | Beginning | 4 | 2 | Vertical | Other - Doorvalveilig 1-zijdig: no; Doorvalveilig 2-zijdig: yes; Text - NLRS_C_merk: K01
2 x Basic Wall:28_DAT_kalkzandsteen_175mm:5536776 | 00 Begane grond | 28.21 Uniformat (Uniformat) | 479.8 | 1930 | 2040 | K_17 | 2 | Walls | Non-bearing | Kunststof kozijn Gealan Kubus | 31 | Kunststof kozijn Gealan Kubus | 31 | 31 | buitenwandopeningen | Kunststof kozijn Gealan Kubus | Walls | Curtain Wall | Curtain Wall: K_17 | K_17 | 6061266 | 710 | no | yes | 0 | 0 | 1930 | 3.9372 | 2040 | Bouwkundig | 2. nieuwbouw | Non-bearing | 0 | Beginning | 4 | 2 | Vertical | Other - Doorvalveilig 1-zijdig: no; Doorvalveilig 2-zijdig: yes; Text - NLRS_C_merk: K01
Basic Wall:28_DAT_kalkzandsteen_175mm:5536776 | 00 Begane grond | 28.21 Uniformat (Uniformat) | 479.8 | 1930 | 880 | K_16 | 2 | Walls | Non-bearing | Kunststof kozijn Gealan Kubus | 31 | Kunststof kozijn Gealan Kubus | 31 | 31 | buitenwandopeningen | Kunststof kozijn Gealan Kubus | Walls | Curtain Wall | Curtain Wall: K_16 | K_16 | 6074129 | 710 | no | yes | 0 | 0 | 1930 | 1.6984 | 880 | Bouwkundig | 2. nieuwbouw | Non-bearing | 0 | Beginning | 4 | 2 | Vertical | Other - Doorvalveilig 1-zijdig: no; Doorvalveilig 2-zijdig: yes; Text - NLRS_C_merk: K01
Basic Wall:28_DAT_kalkzandsteen_175mm:5536776 | 00 Begane grond | 28.21 Uniformat (Uniformat) | 479.8 | 1930 | 880 | K_31 | 2 | Walls | Non-bearing | Kunststof kozijn Gealan Kubus | 31 | Kunststof kozijn Gealan Kubus | 31 | 31 | buitenwandopeningen | Kunststof kozijn Gealan Kubus | Walls | Curtain Wall | Curtain Wall: K_31 | K_31 | 6069143 | 780 | no | yes | V0 bk. ruwe vloer | 0 | 1930 | 1.6984 | 880 | Bouwkundig | 2. nieuwbouw | Non-bearing | 0 | Beginning | 4 | 2 | Vertical | Other - Doorvalveilig 1-zijdig: no; Doorvalveilig 2-zijdig: yes; Text - NLRS_C_merk: K01
Basic Wall:28_DAT_kalkzandsteen_175mm:5536778 | 00 Begane grond | 28.21 Uniformat (Uniformat) | 479.8 | 2630 | 1290 | k_19 | 2 | Walls | Non-bearing | Kunststof kozijn Gealan Kubus | 31 | Kunststof kozijn Gealan Kubus | 31 | 31 | buitenwandopeningen | Kunststof kozijn Gealan Kubus | Walls | Curtain Wall | Curtain Wall: k_19 | k_19 | 4959005 | 10 | no | yes | 0 | 0 | 2630 | 3.3927 | 1290 | Bouwkundig | 2. nieuwbouw | Non-bearing | 0 | Beginning | 4 | 2 | Vertical | Other - Doorvalveilig 1-zijdig: no; Doorvalveilig 2-zijdig: yes; Text - NLRS_C_merk: K01
Basic Wall:28_DAT_kalkzandsteen_175mm:5536778 | 00 Begane grond | 28.21 Uniformat (Uniformat) | 479.8 | 2630 | 1910 | K_20 | 2 | Walls | Non-bearing | Kunststof kozijn Gealan Linear | 31 | Kunststof kozijn Gealan Linear | 31 | 31 | buitenwandopeningen | Kunststof kozijn Gealan Linear | Walls | Curtain Wall | Curtain Wall: K_20 | K_20 | 4960166 | 30 | no | yes | 0 | 0 | 2630 | 5.0233 | 1910 | Bouwkundig | 2. nieuwbouw | Non-bearing | 0 | Beginning | 4 | 2 | Vertical | Other - Doorvalveilig 1-zijdig: no; Doorvalveilig 2-zijdig: yes; Text - NLRS_C_merk: K01
Basic Wall:21_DAT_isolatie minerale wol_160:5536779 | 00 Begane grond | 21.10 Uniformat (Uniformat) | 464.8 | 2630 | 1290 | k_19 | 2 | Walls | Non-bearing | Kunststof kozijn Gealan Kubus | 31 | Kunststof kozijn Gealan Kubus | 31 | 31 | buitenwandopeningen | Kunststof kozijn Gealan Kubus | Walls | Curtain Wall | Curtain Wall: k_19 | k_19 | 4959005 | 10 | no | yes | 0 | 0 | 2630 | 3.3927 | 1290 | Bouwkundig | 2. nieuwbouw | Non-bearing | 0 | Beginning | 4 | 2 | Vertical | Other - Doorvalveilig 1-zijdig: no; Doorvalveilig 2-zijdig: yes; Text - NLRS_C_merk: K01
Basic Wall:21_DAT_isolatie minerale wol_160:5536779 | 00 Begane grond | 21.10 Uniformat (Uniformat) | 464.8 | 2630 | 1910 | K_20 | 2 | Walls | Non-bearing | Kunststof kozijn Gealan Linear | 31 | Kunststof kozijn Gealan Linear | 31 | 31 | buitenwandopeningen | Kunststof kozijn Gealan Linear | Walls | Curtain Wall | Curtain Wall: K_20 | K_20 | 4960166 | 30 | no | yes | 0 | 0 | 2630 | 5.0233 | 1910 | Bouwkundig | 2. nieuwbouw | Non-bearing | 0 | Beginning | 4 | 2 | Vertical | Other - Doorvalveilig 1-zijdig: no; Doorvalveilig 2-zijdig: yes; Text - NLRS_C_merk: K01
Basic Wall:21_DAT_isolatie minerale wol_160:5536779 | 00 Begane grond | 21.10 Uniformat (Uniformat) | 464.8 | 2812.67 | 3910 | 21_DAT_isolatie hard_85 | 2 | Walls | Non-bearing | Hoogwaardige isolatie met een RC van 4.7 m²K/W | 21.10 |  |  | 21.10 | buitenwanden; niet constructief, algemeen (verzamelniveau) | Hoogwaardige isolatie met een RC van 4.7 m²K/W | Walls | Basic Wall | Basic Wall: 21_DAT_isolatie hard_85 | 21_DAT_isolatie hard_85 | 5664636 | -45 | no | yes | 0 | -882.333 | 2812.67 | 2.58153 | 3910 | Bouwkundig | 2. nieuwbouw | Non-bearing |  |  |  |  | Vertical | Dimensions - Volume: 0.21943 m3; Constraints - Base Extension Distance: 0 mm; Top Extension Distance: 0 mm; Location Line: Finish Face: Interior; Top Constraint: Up to level: 1
2 x Basic Wall:28_DAT_kalkzandsteen_175mm:5536781 | 00 Begane grond | 28.21 Uniformat (Uniformat) | 479.8 | 2630 | 740 | K_04 | 2 | Walls | Non-bearing | Kunststof kozijn Gealan Kubus | 31 | Kunststof kozijn Gealan Kubus | 31 | 31 | buitenwandopeningen | Kunststof kozijn Gealan Kubus | Walls | Curtain Wall | Curtain Wall: K_04 | K_04 | 4800906 | 10 | no | yes | 0 | 0 | 2630 | 1.9462 | 740 | Bouwkundig | 2. nieuwbouw | Non-bearing | 0 | Beginning | 4 | 2 | Vertical | Other - Doorvalveilig 1-zijdig: no; Doorvalveilig 2-zijdig: yes; Text - NLRS_C_merk: K01
Basic Wall:28_DAT_kalkzandsteen_175mm:5536781 | 00 Begane grond | 28.21 Uniformat (Uniformat) | 479.8 | 2630 | 1130 | K_05 | 2 | Walls | Non-bearing | Kunststof kozijn Gealan Linear | 31 | Kunststof kozijn Gealan Linear | 31 | 31 | buitenwandopeningen | Kunststof kozijn Gealan Linear | Walls | Curtain Wall | Curtain Wall: K_05 | K_05 | 4797835 | 10 | no | yes | 0 | 0 | 2630 | 2.9719 | 1130 | Bouwkundig | 2. nieuwbouw | Non-bearing | 0 | Beginning | 4 | 2 | Vertical | Other - Doorvalveilig 1-zijdig: no; Doorvalveilig 2-zijdig: yes; Text - NLRS_C_merk: K01
Basic Wall:28_DAT_kalkzandsteen_175mm:5536781 | 00 Begane grond | 28.21 Uniformat (Uniformat) | 479.8 | 2610 | 2120 | K_03 | 2 | Walls | Non-bearing | Kunststof kozijn Gealan Linear | 31 | Kunststof kozijn Gealan Linear | 31 | 31 | buitenwandopeningen | Kunststof kozijn Gealan Linear | Walls | Curtain Wall | Curtain Wall: K_03 | K_03 | 4793066 | 30 | no | yes | 0 | 0 | 2610 | 5.5332 | 2120 | Bouwkundig | 2. nieuwbouw | Non-bearing | 0 | Beginning | 4 | 2 | Vertical | Other - Doorvalveilig 1-zijdig: no; Doorvalveilig 2-zijdig: yes; Text - NLRS_C_merk: K01
Basic Wall:28_DAT_kalkzandsteen_175mm:5536781 | 00 Begane grond | 28.21 Uniformat (Uniformat) | 479.8 | 2630 | 2120 | K_02 | 2 | Walls | Non-bearing | Kunststof kozijn Gealan Kubus | 31 | Kunststof kozijn Gealan Kubus | 31 | 31 | buitenwandopeningen | Kunststof kozijn Gealan Kubus | Walls | Curtain Wall | Curtain Wall: K_02 | K_02 | 4792108 | 10 | no | yes | 0 | 0 | 2630 | 5.5756 | 2120 | Bouwkundig | 2. nieuwbouw | Non-bearing | 0 | Beginning | 4 | 2 | Vertical | Other - Doorvalveilig 1-zijdig: no; Doorvalveilig 2-zijdig: yes; Text - NLRS_C_merk: K01
Basic Wall:28_DAT_kalkzandsteen_175mm:5536781 | 00 Begane grond | 28.21 Uniformat (Uniformat) | 479.8 | 3690 | 740 | 22_DAT_binnenwand_125 HPL | 2 | Walls | Non-bearing | Lichte scheidingswand 125mmAan weerszijden gipsvezelplaat 12,5mmGipsplaat 12,5mm Met daartussen 75mm ms wand gevuld met isolatieVulling afhankelijk van gestelde eisen ingeluidsrapportage | 22.13 |  |  | 22.13 | binnenwanden; niet constructief, systeemwanden; vast | Lichte scheidingswand 125mmAan weerszijden gipsvezelplaat 12,5mmGipsplaat 12,5mm Met daartussen 75mm ms wand gevuld met isolatieVulling afhankelijk van gestelde eisen ingeluidsrapportage | Walls | Basic Wall | Basic Wall: 22_DAT_binnenwand_125 HPL | 22_DAT_binnenwand_125 HPL | 6329633 | -40 | no | yes | 0 | 0 | 3690 | 2.7306 | 740 | Bouwkundig | 2. nieuwbouw | Non-bearing |  |  |  |  | Vertical | Dimensions - Volume: 0.341325 m3; Constraints - Base Extension Distance: 0 mm; Top Extension Distance: 0 mm; Location Line: Wall Centerline; Top Constraint: Up to level: 1
2 x Basic Wall:28_DAT_kalkzandsteen_175mm:5536786 | 01 eerste verdieping | 28.21 Uniformat (Uniformat) | 479.8 | 1930 | 880 | K_28 | 2 | Walls | Non-bearing | Kunststof kozijn Gealan Kubus | 31 | Kunststof kozijn Gealan Kubus | 31 | 31 | buitenwandopeningen | Kunststof kozijn Gealan Kubus | Walls | Curtain Wall | Curtain Wall: K_28 | K_28 | 6068408 | 810 | no | yes | 1 | 0 | 1930 | 1.6984 | 880 | Bouwkundig | 2. nieuwbouw | Non-bearing | 0 | Beginning | 4 | 2 | Vertical | Other - Doorvalveilig 1-zijdig: no; Doorvalveilig 2-zijdig: yes; Text - NLRS_C_merk: K01
Basic Wall:28_DAT_kalkzandsteen_175mm:5536786 | 01 eerste verdieping | 28.21 Uniformat (Uniformat) | 479.8 | 1930 | 2040 | K_24 | 2 | Walls | Non-bearing | Kunststof kozijn Gealan Kubus | 31 | Kunststof kozijn Gealan Kubus | 31 | 31 | buitenwandopeningen | Kunststof kozijn Gealan Kubus | Walls | Curtain Wall | Curtain Wall: K_24 | K_24 | 4801721 | 810 | no | yes | 1 | 0 | 1930 | 3.9372 | 2040 | Bouwkundig | 2. nieuwbouw | Non-bearing | 0 | Beginning | 4 | 2 | Vertical | Other - Doorvalveilig 1-zijdig: no; Doorvalveilig 2-zijdig: yes; Text - NLRS_C_merk: K01
Basic Wall:28_DAT_kalkzandsteen_175mm:5536786 | 01 eerste verdieping | 28.21 Uniformat (Uniformat) | 479.8 | 3310 | 160 | 22_DAT_binnenwand_25 | 2 | Walls | Non-bearing | Lichte scheidingswand 100mm | 22.13 |  |  | 22.13 | binnenwanden; niet constructief, systeemwanden; vast | Lichte scheidingswand 100mm | Walls | Basic Wall | Basic Wall: 22_DAT_binnenwand_25 | 22_DAT_binnenwand_25 | 4977124 | 20 | no | yes | V1 bk. ruwe vloer | 0.0000289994 | 3310 | 0.5296 | 160 | Constructie | 2. nieuwbouw | Non-bearing |  |  |  |  | Vertical | Dimensions - Volume: 0.01324 m3; Constraints - Base Extension Distance: 0 mm; Top Extension Distance: 0 mm; Location Line: Wall Centerline; Top Constraint: Up to level: V2 ok. ruwe vloer
4 x Basic Wall:28_DAT_kalkzandsteen_175mm:5536787 | 01 eerste verdieping | 28.21 Uniformat (Uniformat) | 479.8 | 1930 | 880 | K_28 | 2 | Walls | Non-bearing | Kunststof kozijn Gealan Kubus | 31 | Kunststof kozijn Gealan Kubus | 31 | 31 | buitenwandopeningen | Kunststof kozijn Gealan Kubus | Walls | Curtain Wall | Curtain Wall: K_28 | K_28 | 6068408 | 810 | no | yes | 1 | 0 | 1930 | 1.6984 | 880 | Bouwkundig | 2. nieuwbouw | Non-bearing | 0 | Beginning | 4 | 2 | Vertical | Other - Doorvalveilig 1-zijdig: no; Doorvalveilig 2-zijdig: yes; Text - NLRS_C_merk: K01
4 x Basic Wall:28_DAT_kalkzandsteen_175mm:5536787 | 01 eerste verdieping | 28.21 Uniformat (Uniformat) | 479.8 | 1930 | 2040 | K_24 | 2 | Walls | Non-bearing | Kunststof kozijn Gealan Kubus | 31 | Kunststof kozijn Gealan Kubus | 31 | 31 | buitenwandopeningen | Kunststof kozijn Gealan Kubus | Walls | Curtain Wall | Curtain Wall: K_24 | K_24 | 4801721 | 810 | no | yes | 1 | 0 | 1930 | 3.9372 | 2040 | Bouwkundig | 2. nieuwbouw | Non-bearing | 0 | Beginning | 4 | 2 | Vertical | Other - Doorvalveilig 1-zijdig: no; Doorvalveilig 2-zijdig: yes; Text - NLRS_C_merk: K01
Basic Wall:28_DAT_kalkzandsteen_175mm:5536787 | 01 eerste verdieping | 28.21 Uniformat (Uniformat) | 479.8 | 1930 | 880 | K_31 | 2 | Walls | Non-bearing | Kunststof kozijn Gealan Kubus | 31 | Kunststof kozijn Gealan Kubus | 31 | 31 | buitenwandopeningen | Kunststof kozijn Gealan Kubus | Walls | Curtain Wall | Curtain Wall: K_31 | K_31 | 6069143 | 810 | no | yes | 1 | 0 | 1930 | 1.6984 | 880 | Bouwkundig | 2. nieuwbouw | Non-bearing | 0 | Beginning | 4 | 2 | Vertical | Other - Doorvalveilig 1-zijdig: no; Doorvalveilig 2-zijdig: yes; Text - NLRS_C_merk: K01
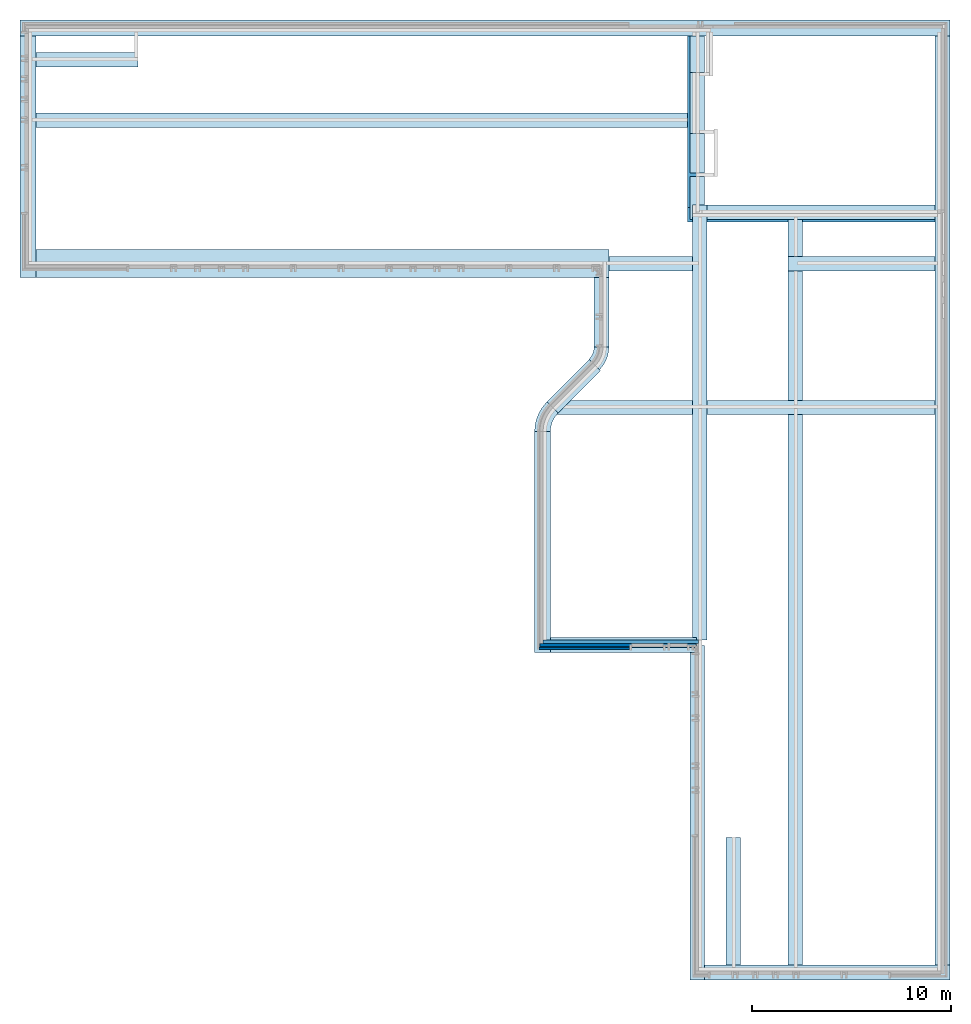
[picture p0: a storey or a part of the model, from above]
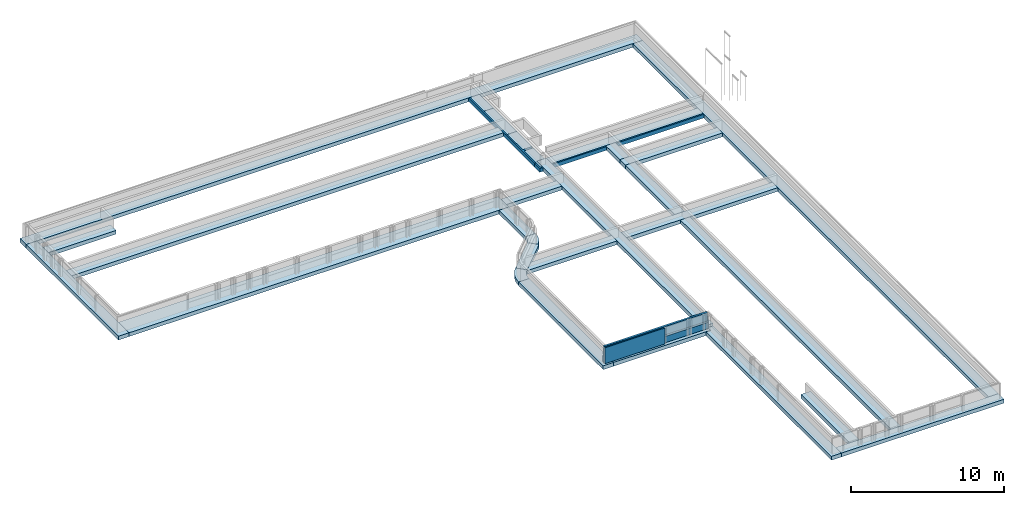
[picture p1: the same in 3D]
Properties of the parts of a building model (IFC2X3), part 23 of 37

# IfcOpeningElement: Opening (1092)
Name | In | Classification | Depth (mm) | BaseQuantities, Height (mm) | BaseQuantities, Width (mm) | Reference | Pset_OpeningElementCommon, sets with these values | Pset_ProductRequirements, Category | Pset_wanden, Structural Usage | Pset_wanden, Omschrijving | Pset_wanden, NL-sfb-Codering | Pset_kozijnen (CW), Omschrijving | Pset_kozijnen (CW), NL-sfb-Codering | Pset_DAT_KMS, Assembly Code | Pset_DAT_KMS, Assembly Description | Pset_DAT_KMS, Description | Other, Category | Family | Other, Family and Type | Type | Type Id | Base Offset (mm) | Base is Attached = Related to Mass = Top is Attached = Structural | Room Bounding | Base Constraint | Top Offset (mm) | Unconnected Height (mm) | Dimensions, Area (m2) | Length (mm) | Identity Data, Workset | Phase Created | Structural, Structural Usage | Angle (deg) = Offset (mm) | Justification | Number | Horizontal Grid, sets with these values | Cross-Section
Basic Wall:28_DAT_kalkzandsteen_175mm:5536788 | 01 eerste verdieping | 28.21 Uniformat (Uniformat) | 479.8 | 1930 | 1145 | K_25 | 2 | Walls | Non-bearing | Kunststof kozijn Gealan Kubus | 31 | Kunststof kozijn Gealan Kubus | 31 | 31 | buitenwandopeningen | Kunststof kozijn Gealan Kubus | Walls | Curtain Wall | Curtain Wall: K_25 | K_25 | 4942169 | 810 | no | yes | 1 | 0 | 1930 | 2.20985 | 1145 | Bouwkundig | 2. nieuwbouw | Non-bearing | 0 | Beginning | 4 | 2 | Vertical | Other - Doorvalveilig 1-zijdig: no; Doorvalveilig 2-zijdig: yes; Text - NLRS_C_merk: K01
Basic Wall:28_DAT_kalkzandsteen_175mm:5536789 | 01 eerste verdieping | 28.21 Uniformat (Uniformat) | 479.8 | 1930 | 790 | K_30 | 2 | Walls | Non-bearing | Kunststof kozijn Gealan Kubus | 31 | Kunststof kozijn Gealan Kubus | 31 | 31 | buitenwandopeningen | Kunststof kozijn Gealan Kubus | Walls | Curtain Wall | Curtain Wall: K_30 | K_30 | 4942327 | 810 | no | yes | 1 | 0 | 1930 | 1.5247 | 790 | Bouwkundig | 2. nieuwbouw | Non-bearing | 0 | Beginning | 4 | 2 | Vertical | Other - Doorvalveilig 1-zijdig: no; Doorvalveilig 2-zijdig: yes; Text - NLRS_C_merk: K01
Basic Wall:28_DAT_kalkzandsteen_175mm:5536789 | 01 eerste verdieping | 28.21 Uniformat (Uniformat) | 479.8 | 3230 | 11 | 21_DAT_Hekwerk 175 | 2 | Walls | Non-bearing | Samengesteld rekwerkBuitenplaat WBP 10mmHouten stijl- en regelwerk 38x140Minirale wolDampremmendefolieGipsplaat 12.5mmGipsvezelplaat 12,5mm | 21.10 |  |  | 21.10 | buitenwanden; niet constructief, algemeen (verzamelniveau) | Samengesteld rekwerkBuitenplaat WBP 10mmHouten stijl- en regelwerk 38x140Minirale wolDampremmendefolieGipsplaat 12.5mmGipsvezelplaat 12,5mm | Walls | Basic Wall | Basic Wall: 21_DAT_Hekwerk 175 | 21_DAT_Hekwerk 175 | 5435600 | 10 | no | yes | 1 | 0.0000289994 | 3230 | 0.03553 | 98.5 | Bouwkundig | 2. nieuwbouw | Non-bearing |  |  |  |  | Vertical | Dimensions - Volume: 0.00621775 m3; Constraints - Base Extension Distance: 0 mm; Top Extension Distance: 0 mm; Location Line: Wall Centerline; Top Constraint: Up to level: V2 ok. ruwe vloer; Pset_wanden - sets with these values: 2
Basic Wall:28_DAT_kalkzandsteen_175mm:5536790 | 01 eerste verdieping | 28.21 Uniformat (Uniformat) | 479.8 | 1930 | 880 | K_31 | 2 | Walls | Non-bearing | Kunststof kozijn Gealan Kubus | 31 | Kunststof kozijn Gealan Kubus | 31 | 31 | buitenwandopeningen | Kunststof kozijn Gealan Kubus | Walls | Curtain Wall | Curtain Wall: K_31 | K_31 | 6069143 | 810 | no | yes | 1 | 0 | 1930 | 1.6984 | 880 | Bouwkundig | 2. nieuwbouw | Non-bearing | 0 | Beginning | 4 | 2 | Vertical | Other - Doorvalveilig 1-zijdig: no; Doorvalveilig 2-zijdig: yes; Text - NLRS_C_merk: K01
Basic Wall:28_DAT_kalkzandsteen_175mm:5536791 | 01 eerste verdieping | 28.21 Uniformat (Uniformat) | 479.8 | 1930 | 2064 | K_23 | 2 | Walls | Non-bearing | Kunststof kozijn Gealan Kubus | 31 | Kunststof kozijn Gealan Kubus | 31 | 31 | buitenwandopeningen | Kunststof kozijn Gealan Kubus | Walls | Curtain Wall | Curtain Wall: K_23 | K_23 | 4942408 | 810 | no | yes | 1 | 0 | 1930 | 3.98352 | 2064 | Bouwkundig | 2. nieuwbouw | Non-bearing | 0 | Beginning | 4 | 2 | Vertical | Other - Doorvalveilig 1-zijdig: no; Doorvalveilig 2-zijdig: yes; Text - NLRS_C_merk: K01
Basic Wall:28_DAT_kalkzandsteen_175mm:5536791 | 01 eerste verdieping | 28.21 Uniformat (Uniformat) | 479.8 |  |  | 21_DAT_Hekwerk 175 | 2 | Walls | Non-bearing | Samengesteld rekwerkBuitenplaat WBP 10mmHouten stijl- en regelwerk 38x140Minirale wolDampremmendefolieGipsplaat 12.5mmGipsvezelplaat 12,5mm | 21.10 |  |  | 21.10 | buitenwanden; niet constructief, algemeen (verzamelniveau) | Samengesteld rekwerkBuitenplaat WBP 10mmHouten stijl- en regelwerk 38x140Minirale wolDampremmendefolieGipsplaat 12.5mmGipsvezelplaat 12,5mm | Walls | Basic Wall | Basic Wall: 21_DAT_Hekwerk 175 | 21_DAT_Hekwerk 175 | 5435600 | 10 | no | yes | 1 | 0.0000289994 | 3230 | 0.21845 | 127.5 | Bouwkundig | 2. nieuwbouw | Non-bearing |  |  |  |  | Vertical | Dimensions - Volume: 0.0382288 m3; Constraints - Base Extension Distance: 0 mm; Top Extension Distance: 0 mm; Location Line: Wall Centerline; Top Constraint: Up to level: V2 ok. ruwe vloer; BaseQuantities - Area: 0.21845 m2; Pset_wanden - sets with these values: 2
Basic Wall:21_DAT_isolatie minerale wol_160:5536792 | 01 eerste verdieping | 21.10 Uniformat (Uniformat) | 464.8 | 1930 | 2064 | K_23 | 2 | Walls | Non-bearing | Kunststof kozijn Gealan Kubus | 31 | Kunststof kozijn Gealan Kubus | 31 | 31 | buitenwandopeningen | Kunststof kozijn Gealan Kubus | Walls | Curtain Wall | Curtain Wall: K_23 | K_23 | 4942408 | 810 | no | yes | 1 | 0 | 1930 | 3.98352 | 2064 | Bouwkundig | 2. nieuwbouw | Non-bearing | 0 | Beginning | 4 | 2 | Vertical | Other - Doorvalveilig 1-zijdig: no; Doorvalveilig 2-zijdig: yes; Text - NLRS_C_merk: K01
Basic Wall:21_DAT_isolatie minerale wol_160:5536792 | 01 eerste verdieping | 21.10 Uniformat (Uniformat) | 464.8 | 2937.5 | 2399.5 | 21_DAT_isolatie hard_74 | 2 | Walls | Non-bearing | Hoogwaardige isolatie met een RC van 4.7 m²K/W | 21.10 |  |  | 21.10 | buitenwanden; niet constructief, algemeen (verzamelniveau) | Hoogwaardige isolatie met een RC van 4.7 m²K/W | Walls | Basic Wall | Basic Wall: 21_DAT_isolatie hard_74 | 21_DAT_isolatie hard_74 | 5724015 | 562.5 | no | yes | 1 | 0 | 2937.5 | 3.06501 | 2399.5 | Bouwkundig | 2. nieuwbouw | Non-bearing |  |  |  |  | Vertical | Dimensions - Volume: 0.214551 m3; Constraints - Base Extension Distance: 0 mm; Top Extension Distance: 0 mm; Location Line: Finish Face: Interior
Basic Wall:21_DAT_isolatie minerale wol_160:5536793 | 01 eerste verdieping | 21.10 Uniformat (Uniformat) | 464.8 | 2375 | 1120 | 21_DAT_isolatie hard_74 | 2 | Walls | Non-bearing | Hoogwaardige isolatie met een RC van 4.7 m²K/W | 21.10 |  |  | 21.10 | buitenwanden; niet constructief, algemeen (verzamelniveau) | Hoogwaardige isolatie met een RC van 4.7 m²K/W | Walls | Basic Wall | Basic Wall: 21_DAT_isolatie hard_74 | 21_DAT_isolatie hard_74 | 5724015 | 500 | no | yes | 1 | 0 | 2375 | 0.9616 | 1120 | Bouwkundig | 2. nieuwbouw | Non-bearing |  |  |  |  | Vertical | Dimensions - Volume: 0.067312 m3; Constraints - Base Extension Distance: 0 mm; Top Extension Distance: 0 mm; Location Line: Finish Face: Interior
3 x Basic Wall:21_DAT_metselwerk_100:5536888 | 00 Begane grond | 21.12 Uniformat (Uniformat) | 404.8 | 2630 | 740 | K_04 | 2 | Walls | Non-bearing | Kunststof kozijn Gealan Kubus | 31 | Kunststof kozijn Gealan Kubus | 31 | 31 | buitenwandopeningen | Kunststof kozijn Gealan Kubus | Walls | Curtain Wall | Curtain Wall: K_04 | K_04 | 4800906 | 10 | no | yes | 0 | 0 | 2630 | 1.9462 | 740 | Bouwkundig | 2. nieuwbouw | Non-bearing | 0 | Beginning | 4 | 2 | Vertical | Other - Doorvalveilig 1-zijdig: no; Doorvalveilig 2-zijdig: yes; Text - NLRS_C_merk: K01
Basic Wall:21_DAT_metselwerk_100:5536888 | 00 Begane grond | 21.12 Uniformat (Uniformat) | 404.8 | 2610 | 2120 | K_03 | 2 | Walls | Non-bearing | Kunststof kozijn Gealan Linear | 31 | Kunststof kozijn Gealan Linear | 31 | 31 | buitenwandopeningen | Kunststof kozijn Gealan Linear | Walls | Curtain Wall | Curtain Wall: K_03 | K_03 | 4793066 | 30 | no | yes | 0 | 0 | 2610 | 5.5332 | 2120 | Bouwkundig | 2. nieuwbouw | Non-bearing | 0 | Beginning | 4 | 2 | Vertical | Other - Doorvalveilig 1-zijdig: no; Doorvalveilig 2-zijdig: yes; Text - NLRS_C_merk: K01
Basic Wall:21_DAT_metselwerk_100:5536888 | 00 Begane grond | 21.12 Uniformat (Uniformat) | 404.8 | 2630 | 2120 | K_02 | 2 | Walls | Non-bearing | Kunststof kozijn Gealan Kubus | 31 | Kunststof kozijn Gealan Kubus | 31 | 31 | buitenwandopeningen | Kunststof kozijn Gealan Kubus | Walls | Curtain Wall | Curtain Wall: K_02 | K_02 | 4792108 | 10 | no | yes | 0 | 0 | 2630 | 5.5756 | 2120 | Bouwkundig | 2. nieuwbouw | Non-bearing | 0 | Beginning | 4 | 2 | Vertical | Other - Doorvalveilig 1-zijdig: no; Doorvalveilig 2-zijdig: yes; Text - NLRS_C_merk: K01
Basic Wall:28_DAT_kalkzandsteen_175mm:5536972 | 00 Begane grond | 28.21 Uniformat (Uniformat) | 479.8 | 2630 | 920 | K_01 | 2 | Walls | Non-bearing | Kunststof kozijn Gealan Kubus | 31 | Kunststof kozijn Gealan Kubus | 31 | 31 | buitenwandopeningen | Kunststof kozijn Gealan Kubus | Walls | Curtain Wall | Curtain Wall: K_01 | K_01 | 4774158 | 10 | no | yes | 0 | 0 | 2630 | 2.4196 | 920 | Bouwkundig | 2. nieuwbouw | Non-bearing | 0 | Beginning | 4 | 2 | Vertical | Other - Doorvalveilig 1-zijdig: no; Doorvalveilig 2-zijdig: yes; Text - NLRS_C_merk: K01
Basic Wall:28_DAT_kalkzandsteen_175mm:5536972 | 00 Begane grond | 28.21 Uniformat (Uniformat) | 479.8 | 2630 | 1635 | K_18 | 2 | Walls | Non-bearing | Kunststof kozijn Gealan Kubus | 31 | Kunststof kozijn Gealan Kubus | 31 | 31 | buitenwandopeningen | Kunststof kozijn Gealan Kubus | Walls | Curtain Wall | Curtain Wall: K_18 | K_18 | 6067594 | 10 | no | yes | 0 | 0 | 2630 | 4.30005 | 1635 | Bouwkundig | 2. nieuwbouw | Non-bearing | 0 | Beginning | 4 | 2 | Vertical | Other - Doorvalveilig 1-zijdig: no; Doorvalveilig 2-zijdig: yes; Text - NLRS_C_merk: K01
Basic Wall:21_DAT_isolatie minerale wol_160:5536973 | 00 Begane grond | 21.10 Uniformat (Uniformat) | 464.8 | 2630 | 1635 | K_18 | 2 | Walls | Non-bearing | Kunststof kozijn Gealan Kubus | 31 | Kunststof kozijn Gealan Kubus | 31 | 31 | buitenwandopeningen | Kunststof kozijn Gealan Kubus | Walls | Curtain Wall | Curtain Wall: K_18 | K_18 | 6067594 | 10 | no | yes | 0 | 0 | 2630 | 4.30005 | 1635 | Bouwkundig | 2. nieuwbouw | Non-bearing | 0 | Beginning | 4 | 2 | Vertical | Other - Doorvalveilig 1-zijdig: no; Doorvalveilig 2-zijdig: yes; Text - NLRS_C_merk: K01
Basic Wall:21_DAT_isolatie minerale wol_160:5536973 | 00 Begane grond | 21.10 Uniformat (Uniformat) | 464.8 | 2630 | 920 | K_01 | 2 | Walls | Non-bearing | Kunststof kozijn Gealan Kubus | 31 | Kunststof kozijn Gealan Kubus | 31 | 31 | buitenwandopeningen | Kunststof kozijn Gealan Kubus | Walls | Curtain Wall | Curtain Wall: K_01 | K_01 | 4774158 | 10 | no | yes | 0 | 0 | 2630 | 2.4196 | 920 | Bouwkundig | 2. nieuwbouw | Non-bearing | 0 | Beginning | 4 | 2 | Vertical | Other - Doorvalveilig 1-zijdig: no; Doorvalveilig 2-zijdig: yes; Text - NLRS_C_merk: K01
Basic Wall:21_DAT_isolatie minerale wol_160:5536973 | 00 Begane grond | 21.10 Uniformat (Uniformat) | 464.8 | 2812.67 | 3345 | 21_DAT_isolatie hard_85 | 2 | Walls | Non-bearing | Hoogwaardige isolatie met een RC van 4.7 m²K/W | 21.10 |  |  | 21.10 | buitenwanden; niet constructief, algemeen (verzamelniveau) | Hoogwaardige isolatie met een RC van 4.7 m²K/W | Walls | Basic Wall | Basic Wall: 21_DAT_isolatie hard_85 | 21_DAT_isolatie hard_85 | 5664636 | -45 | no | yes | 0 | -882.333 | 2812.67 | 2.68872 | 3345 | Bouwkundig | 2. nieuwbouw | Non-bearing |  |  |  |  | Vertical | Dimensions - Volume: 0.228541 m3; Constraints - Base Extension Distance: 0 mm; Top Extension Distance: 0 mm; Location Line: Finish Face: Interior; Top Constraint: Up to level: 1
Basic Wall:21_DAT_metselwerk_100:5537477 | 00 Begane grond | 21.12 Uniformat (Uniformat) | 100 | 2125 | 2000 | raamsparing_K_40 | 2 | Windows |  |  |  |  |  | 31 | buitenwandopeningen | raamsparing | Windows | NLRS_30_WI_WB_raamsparing_type_generiek_ISR | NLRS_30_WI_WB_raamsparing_type_generiek_ISR: raamsparing_K_40 | raamsparing_K_40 | 5540939 |  |  |  |  |  |  | 5.69375 |  | Bouwkundig | 2. nieuwbouw | Constraints - Level: 0; Sill Height: 525 mm; Dimensions - NLRS_C_breedte: 2000 mm; NLRS_C_hoogte: 2125 mm; Identity Data - Mark: 3970; Pset_Window - Omschrijving: raamsparing; NL-sfb-Codering: 31; Other - berekende_gevelsparing_BW_offset: 1562.5 mm; gevelsparing_breedte: 2000 mm; gevelsparing_hoogte: 2125 mm; Head Height: 2650 mm; Host Id: 5536773; Other(Type) - Category: Windows; Family Name: NLRS_30_WI_WB_raamsparing_type_generiek_ISR; Construction(Type) - gevelsparing_breedteverschil: 0 mm; gevelsparing_hoogteverschil: 0 mm; lossing: 0 mm; gevelsparing_borstweringverschil: 500 mm; Dimensions(Type) - Rough Height: 0 mm; Rough Width: 0 mm; Height: 2125 mm; Width: 2000 mm; Graphics(Type) - clash_object_actief: no; Identity Data(Type) - Workset: Family : Windows : NLRS_30_WI_WB_raamsparing_type_generiek_ISR; Assembly Code: 31; Assembly Description: buitenwandopeningen; Description: raamsparing; Model: LOD200; OmniClass Number: 23.30.20.17.11; OmniClass Title: Fixed Windows; SmartRevit_Versie: 1.0; Type Mark: 1231; Type Name: raamsparing_K_40; Analytical Properties(Type) - Define Thermal Properties by: Schematic Type; Analytic Construction: <None>
Basic Wall:21_DAT_metselwerk_100:5537477 | 00 Begane grond | 21.12 Uniformat (Uniformat) | 100 | 2125 | 2000 | raamsparing_K_40 | 2 | Windows |  |  |  |  |  | 31 | buitenwandopeningen | raamsparing | Windows | NLRS_30_WI_WB_raamsparing_type_generiek_ISR | NLRS_30_WI_WB_raamsparing_type_generiek_ISR: raamsparing_K_40 | raamsparing_K_40 | 5540939 |  |  |  |  |  |  | 5.69375 |  | Bouwkundig | 2. nieuwbouw | Constraints - Level: 0; Sill Height: 525 mm; Dimensions - NLRS_C_breedte: 2000 mm; NLRS_C_hoogte: 2125 mm; Identity Data - Mark: 3976; Pset_Window - Omschrijving: raamsparing; NL-sfb-Codering: 31; Other - berekende_gevelsparing_BW_offset: 1562.5 mm; gevelsparing_breedte: 2000 mm; gevelsparing_hoogte: 2125 mm; Head Height: 2650 mm; Host Id: 5536773; Other(Type) - Category: Windows; Family Name: NLRS_30_WI_WB_raamsparing_type_generiek_ISR; Construction(Type) - gevelsparing_breedteverschil: 0 mm; gevelsparing_hoogteverschil: 0 mm; lossing: 0 mm; gevelsparing_borstweringverschil: 500 mm; Dimensions(Type) - Rough Height: 0 mm; Rough Width: 0 mm; Height: 2125 mm; Width: 2000 mm; Graphics(Type) - clash_object_actief: no; Identity Data(Type) - Workset: Family : Windows : NLRS_30_WI_WB_raamsparing_type_generiek_ISR; Assembly Code: 31; Assembly Description: buitenwandopeningen; Description: raamsparing; Model: LOD200; OmniClass Number: 23.30.20.17.11; OmniClass Title: Fixed Windows; SmartRevit_Versie: 1.0; Type Mark: 1231; Type Name: raamsparing_K_40; Analytical Properties(Type) - Define Thermal Properties by: Schematic Type; Analytic Construction: <None>
Basic Wall:21_DAT_metselwerk_100:5537477 | 00 Begane grond | 21.12 Uniformat (Uniformat) | 100 | 2125 | 2000 | raamsparing_K_40 | 2 | Windows |  |  |  |  |  | 31 | buitenwandopeningen | raamsparing | Windows | NLRS_30_WI_WB_raamsparing_type_generiek_ISR | NLRS_30_WI_WB_raamsparing_type_generiek_ISR: raamsparing_K_40 | raamsparing_K_40 | 5540939 |  |  |  |  |  |  | 5.69375 |  | Bouwkundig | 2. nieuwbouw | Constraints - Level: 0; Sill Height: 525 mm; Dimensions - NLRS_C_breedte: 2000 mm; NLRS_C_hoogte: 2125 mm; Identity Data - Mark: 3982; Pset_Window - Omschrijving: raamsparing; NL-sfb-Codering: 31; Other - berekende_gevelsparing_BW_offset: 1562.5 mm; gevelsparing_breedte: 2000 mm; gevelsparing_hoogte: 2125 mm; Head Height: 2650 mm; Host Id: 5536773; Other(Type) - Category: Windows; Family Name: NLRS_30_WI_WB_raamsparing_type_generiek_ISR; Construction(Type) - gevelsparing_breedteverschil: 0 mm; gevelsparing_hoogteverschil: 0 mm; lossing: 0 mm; gevelsparing_borstweringverschil: 500 mm; Dimensions(Type) - Rough Height: 0 mm; Rough Width: 0 mm; Height: 2125 mm; Width: 2000 mm; Graphics(Type) - clash_object_actief: no; Identity Data(Type) - Workset: Family : Windows : NLRS_30_WI_WB_raamsparing_type_generiek_ISR; Assembly Code: 31; Assembly Description: buitenwandopeningen; Description: raamsparing; Model: LOD200; OmniClass Number: 23.30.20.17.11; OmniClass Title: Fixed Windows; SmartRevit_Versie: 1.0; Type Mark: 1231; Type Name: raamsparing_K_40; Analytical Properties(Type) - Define Thermal Properties by: Schematic Type; Analytic Construction: <None>
Basic Wall:21_DAT_metselwerk_100:5537477 | 00 Begane grond | 21.12 Uniformat (Uniformat) | 100 | 2125 | 2000 | raamsparing_K_40 | 2 | Windows |  |  |  |  |  | 31 | buitenwandopeningen | raamsparing | Windows | NLRS_30_WI_WB_raamsparing_type_generiek_ISR | NLRS_30_WI_WB_raamsparing_type_generiek_ISR: raamsparing_K_40 | raamsparing_K_40 | 5540939 |  |  |  |  |  |  | 5.69375 |  | Bouwkundig | 2. nieuwbouw | Constraints - Level: 0; Sill Height: 525 mm; Dimensions - NLRS_C_breedte: 2000 mm; NLRS_C_hoogte: 2125 mm; Identity Data - Mark: 3988; Pset_Window - Omschrijving: raamsparing; NL-sfb-Codering: 31; Other - berekende_gevelsparing_BW_offset: 1562.5 mm; gevelsparing_breedte: 2000 mm; gevelsparing_hoogte: 2125 mm; Head Height: 2650 mm; Host Id: 5536773; Other(Type) - Category: Windows; Family Name: NLRS_30_WI_WB_raamsparing_type_generiek_ISR; Construction(Type) - gevelsparing_breedteverschil: 0 mm; gevelsparing_hoogteverschil: 0 mm; lossing: 0 mm; gevelsparing_borstweringverschil: 500 mm; Dimensions(Type) - Rough Height: 0 mm; Rough Width: 0 mm; Height: 2125 mm; Width: 2000 mm; Graphics(Type) - clash_object_actief: no; Identity Data(Type) - Workset: Family : Windows : NLRS_30_WI_WB_raamsparing_type_generiek_ISR; Assembly Code: 31; Assembly Description: buitenwandopeningen; Description: raamsparing; Model: LOD200; OmniClass Number: 23.30.20.17.11; OmniClass Title: Fixed Windows; SmartRevit_Versie: 1.0; Type Mark: 1231; Type Name: raamsparing_K_40; Analytical Properties(Type) - Define Thermal Properties by: Schematic Type; Analytic Construction: <None>
Basic Wall:21_DAT_metselwerk_100:5537477 | 00 Begane grond | 21.12 Uniformat (Uniformat) | 100 | 2125 | 2000 | raamsparing_K_40 | 2 | Windows |  |  |  |  |  | 31 | buitenwandopeningen | raamsparing | Windows | NLRS_30_WI_WB_raamsparing_type_generiek_ISR | NLRS_30_WI_WB_raamsparing_type_generiek_ISR: raamsparing_K_40 | raamsparing_K_40 | 5540939 |  |  |  |  |  |  | 5.69375 |  | Bouwkundig | 2. nieuwbouw | Constraints - Level: 0; Sill Height: 525 mm; Dimensions - NLRS_C_breedte: 2000 mm; NLRS_C_hoogte: 2125 mm; Identity Data - Mark: 3994; Pset_Window - Omschrijving: raamsparing; NL-sfb-Codering: 31; Other - berekende_gevelsparing_BW_offset: 1562.5 mm; gevelsparing_breedte: 2000 mm; gevelsparing_hoogte: 2125 mm; Head Height: 2650 mm; Host Id: 5536773; Other(Type) - Category: Windows; Family Name: NLRS_30_WI_WB_raamsparing_type_generiek_ISR; Construction(Type) - gevelsparing_breedteverschil: 0 mm; gevelsparing_hoogteverschil: 0 mm; lossing: 0 mm; gevelsparing_borstweringverschil: 500 mm; Dimensions(Type) - Rough Height: 0 mm; Rough Width: 0 mm; Height: 2125 mm; Width: 2000 mm; Graphics(Type) - clash_object_actief: no; Identity Data(Type) - Workset: Family : Windows : NLRS_30_WI_WB_raamsparing_type_generiek_ISR; Assembly Code: 31; Assembly Description: buitenwandopeningen; Description: raamsparing; Model: LOD200; OmniClass Number: 23.30.20.17.11; OmniClass Title: Fixed Windows; SmartRevit_Versie: 1.0; Type Mark: 1231; Type Name: raamsparing_K_40; Analytical Properties(Type) - Define Thermal Properties by: Schematic Type; Analytic Construction: <None>
Basic Wall:21_DAT_metselwerk_100:5537477 | 00 Begane grond | 21.12 Uniformat (Uniformat) | 100 | 2125 | 2000 | raamsparing_K_40 | 2 | Windows |  |  |  |  |  | 31 | buitenwandopeningen | raamsparing | Windows | NLRS_30_WI_WB_raamsparing_type_generiek_ISR | NLRS_30_WI_WB_raamsparing_type_generiek_ISR: raamsparing_K_40 | raamsparing_K_40 | 5540939 |  |  |  |  |  |  | 5.69375 |  | Bouwkundig | 2. nieuwbouw | Constraints - Level: 0; Sill Height: 525 mm; Dimensions - NLRS_C_breedte: 2000 mm; NLRS_C_hoogte: 2125 mm; Identity Data - Mark: 4000; Pset_Window - Omschrijving: raamsparing; NL-sfb-Codering: 31; Other - berekende_gevelsparing_BW_offset: 1562.5 mm; gevelsparing_breedte: 2000 mm; gevelsparing_hoogte: 2125 mm; Head Height: 2650 mm; Host Id: 5536773; Other(Type) - Category: Windows; Family Name: NLRS_30_WI_WB_raamsparing_type_generiek_ISR; Construction(Type) - gevelsparing_breedteverschil: 0 mm; gevelsparing_hoogteverschil: 0 mm; lossing: 0 mm; gevelsparing_borstweringverschil: 500 mm; Dimensions(Type) - Rough Height: 0 mm; Rough Width: 0 mm; Height: 2125 mm; Width: 2000 mm; Graphics(Type) - clash_object_actief: no; Identity Data(Type) - Workset: Family : Windows : NLRS_30_WI_WB_raamsparing_type_generiek_ISR; Assembly Code: 31; Assembly Description: buitenwandopeningen; Description: raamsparing; Model: LOD200; OmniClass Number: 23.30.20.17.11; OmniClass Title: Fixed Windows; SmartRevit_Versie: 1.0; Type Mark: 1231; Type Name: raamsparing_K_40; Analytical Properties(Type) - Define Thermal Properties by: Schematic Type; Analytic Construction: <None>
Basic Wall:21_DAT_metselwerk_100:5537477 | 00 Begane grond | 21.12 Uniformat (Uniformat) | 100 | 2125 | 840 | raamsparing_K_41 | 2 | Windows |  |  |  |  |  | 31 | buitenwandopeningen | raamsparing | Windows | NLRS_30_WI_WB_raamsparing_type_generiek_ISR | NLRS_30_WI_WB_raamsparing_type_generiek_ISR: raamsparing_K_41 | raamsparing_K_41 | 5542498 |  |  |  |  |  |  | 2.82275 |  | Bouwkundig | 2. nieuwbouw | Constraints - Level: 0; Sill Height: 525 mm; Dimensions - NLRS_C_breedte: 840 mm; NLRS_C_hoogte: 2125 mm; Identity Data - Mark: 4012; Pset_Window - Omschrijving: raamsparing; NL-sfb-Codering: 31; Other - berekende_gevelsparing_BW_offset: 1562.5 mm; gevelsparing_breedte: 840 mm; gevelsparing_hoogte: 2125 mm; Head Height: 2650 mm; Host Id: 5536773; Other(Type) - Category: Windows; Family Name: NLRS_30_WI_WB_raamsparing_type_generiek_ISR; Construction(Type) - gevelsparing_breedteverschil: 0 mm; gevelsparing_hoogteverschil: 0 mm; lossing: 0 mm; gevelsparing_borstweringverschil: 500 mm; Dimensions(Type) - Rough Height: 0 mm; Rough Width: 0 mm; Height: 2125 mm; Width: 840 mm; Graphics(Type) - clash_object_actief: no; Identity Data(Type) - Workset: Family : Windows : NLRS_30_WI_WB_raamsparing_type_generiek_ISR; Assembly Code: 31; Assembly Description: buitenwandopeningen; Description: raamsparing; Model: LOD200; OmniClass Number: 23.30.20.17.11; OmniClass Title: Fixed Windows; SmartRevit_Versie: 1.0; Type Mark: 1232; Type Name: raamsparing_K_41; Analytical Properties(Type) - Define Thermal Properties by: Schematic Type; Analytic Construction: <None>
Basic Wall:21_DAT_metselwerk_100:5537477 | 00 Begane grond | 21.12 Uniformat (Uniformat) | 100 | 2125 | 840 | raamsparing_K_41 | 2 | Windows |  |  |  |  |  | 31 | buitenwandopeningen | raamsparing | Windows | NLRS_30_WI_WB_raamsparing_type_generiek_ISR | NLRS_30_WI_WB_raamsparing_type_generiek_ISR: raamsparing_K_41 | raamsparing_K_41 | 5542498 |  |  |  |  |  |  | 2.82275 |  | Bouwkundig | 2. nieuwbouw | Constraints - Level: 0; Sill Height: 525 mm; Dimensions - NLRS_C_breedte: 840 mm; NLRS_C_hoogte: 2125 mm; Identity Data - Mark: 4013; Pset_Window - Omschrijving: raamsparing; NL-sfb-Codering: 31; Other - berekende_gevelsparing_BW_offset: 1562.5 mm; gevelsparing_breedte: 840 mm; gevelsparing_hoogte: 2125 mm; Head Height: 2650 mm; Host Id: 5536773; Other(Type) - Category: Windows; Family Name: NLRS_30_WI_WB_raamsparing_type_generiek_ISR; Construction(Type) - gevelsparing_breedteverschil: 0 mm; gevelsparing_hoogteverschil: 0 mm; lossing: 0 mm; gevelsparing_borstweringverschil: 500 mm; Dimensions(Type) - Rough Height: 0 mm; Rough Width: 0 mm; Height: 2125 mm; Width: 840 mm; Graphics(Type) - clash_object_actief: no; Identity Data(Type) - Workset: Family : Windows : NLRS_30_WI_WB_raamsparing_type_generiek_ISR; Assembly Code: 31; Assembly Description: buitenwandopeningen; Description: raamsparing; Model: LOD200; OmniClass Number: 23.30.20.17.11; OmniClass Title: Fixed Windows; SmartRevit_Versie: 1.0; Type Mark: 1232; Type Name: raamsparing_K_41; Analytical Properties(Type) - Define Thermal Properties by: Schematic Type; Analytic Construction: <None>
Basic Wall:21_DAT_metselwerk_100:5537477 | 00 Begane grond | 21.12 Uniformat (Uniformat) | 100 | 2125 | 840 | raamsparing_K_41 | 2 | Windows |  |  |  |  |  | 31 | buitenwandopeningen | raamsparing | Windows | NLRS_30_WI_WB_raamsparing_type_generiek_ISR | NLRS_30_WI_WB_raamsparing_type_generiek_ISR: raamsparing_K_41 | raamsparing_K_41 | 5542498 |  |  |  |  |  |  | 2.82275 |  | Bouwkundig | 2. nieuwbouw | Constraints - Level: 0; Sill Height: 525 mm; Dimensions - NLRS_C_breedte: 840 mm; NLRS_C_hoogte: 2125 mm; Identity Data - Mark: 4017; Pset_Window - Omschrijving: raamsparing; NL-sfb-Codering: 31; Other - berekende_gevelsparing_BW_offset: 1562.5 mm; gevelsparing_breedte: 840 mm; gevelsparing_hoogte: 2125 mm; Head Height: 2650 mm; Host Id: 5536773; Other(Type) - Category: Windows; Family Name: NLRS_30_WI_WB_raamsparing_type_generiek_ISR; Construction(Type) - gevelsparing_breedteverschil: 0 mm; gevelsparing_hoogteverschil: 0 mm; lossing: 0 mm; gevelsparing_borstweringverschil: 500 mm; Dimensions(Type) - Rough Height: 0 mm; Rough Width: 0 mm; Height: 2125 mm; Width: 840 mm; Graphics(Type) - clash_object_actief: no; Identity Data(Type) - Workset: Family : Windows : NLRS_30_WI_WB_raamsparing_type_generiek_ISR; Assembly Code: 31; Assembly Description: buitenwandopeningen; Description: raamsparing; Model: LOD200; OmniClass Number: 23.30.20.17.11; OmniClass Title: Fixed Windows; SmartRevit_Versie: 1.0; Type Mark: 1232; Type Name: raamsparing_K_41; Analytical Properties(Type) - Define Thermal Properties by: Schematic Type; Analytic Construction: <None>
Basic Wall:21_DAT_metselwerk_100:5537477 | 00 Begane grond | 21.12 Uniformat (Uniformat) | 100 | 2125 | 840 | raamsparing_K_41 | 2 | Windows |  |  |  |  |  | 31 | buitenwandopeningen | raamsparing | Windows | NLRS_30_WI_WB_raamsparing_type_generiek_ISR | NLRS_30_WI_WB_raamsparing_type_generiek_ISR: raamsparing_K_41 | raamsparing_K_41 | 5542498 |  |  |  |  |  |  | 2.82275 |  | Bouwkundig | 2. nieuwbouw | Constraints - Level: 0; Sill Height: 525 mm; Dimensions - NLRS_C_breedte: 840 mm; NLRS_C_hoogte: 2125 mm; Identity Data - Mark: 4021; Pset_Window - Omschrijving: raamsparing; NL-sfb-Codering: 31; Other - berekende_gevelsparing_BW_offset: 1562.5 mm; gevelsparing_breedte: 840 mm; gevelsparing_hoogte: 2125 mm; Head Height: 2650 mm; Host Id: 5536773; Other(Type) - Category: Windows; Family Name: NLRS_30_WI_WB_raamsparing_type_generiek_ISR; Construction(Type) - gevelsparing_breedteverschil: 0 mm; gevelsparing_hoogteverschil: 0 mm; lossing: 0 mm; gevelsparing_borstweringverschil: 500 mm; Dimensions(Type) - Rough Height: 0 mm; Rough Width: 0 mm; Height: 2125 mm; Width: 840 mm; Graphics(Type) - clash_object_actief: no; Identity Data(Type) - Workset: Family : Windows : NLRS_30_WI_WB_raamsparing_type_generiek_ISR; Assembly Code: 31; Assembly Description: buitenwandopeningen; Description: raamsparing; Model: LOD200; OmniClass Number: 23.30.20.17.11; OmniClass Title: Fixed Windows; SmartRevit_Versie: 1.0; Type Mark: 1232; Type Name: raamsparing_K_41; Analytical Properties(Type) - Define Thermal Properties by: Schematic Type; Analytic Construction: <None>
Basic Wall:21_DAT_metselwerk_100:5537477 | 00 Begane grond | 21.12 Uniformat (Uniformat) | 100 | 2125 | 840 | raamsparing_K_41 | 2 | Windows |  |  |  |  |  | 31 | buitenwandopeningen | raamsparing | Windows | NLRS_30_WI_WB_raamsparing_type_generiek_ISR | NLRS_30_WI_WB_raamsparing_type_generiek_ISR: raamsparing_K_41 | raamsparing_K_41 | 5542498 |  |  |  |  |  |  | 2.82275 |  | Bouwkundig | 2. nieuwbouw | Constraints - Level: 0; Sill Height: 525 mm; Dimensions - NLRS_C_breedte: 840 mm; NLRS_C_hoogte: 2125 mm; Identity Data - Mark: 4025; Pset_Window - Omschrijving: raamsparing; NL-sfb-Codering: 31; Other - berekende_gevelsparing_BW_offset: 1562.5 mm; gevelsparing_breedte: 840 mm; gevelsparing_hoogte: 2125 mm; Head Height: 2650 mm; Host Id: 5536773; Other(Type) - Category: Windows; Family Name: NLRS_30_WI_WB_raamsparing_type_generiek_ISR; Construction(Type) - gevelsparing_breedteverschil: 0 mm; gevelsparing_hoogteverschil: 0 mm; lossing: 0 mm; gevelsparing_borstweringverschil: 500 mm; Dimensions(Type) - Rough Height: 0 mm; Rough Width: 0 mm; Height: 2125 mm; Width: 840 mm; Graphics(Type) - clash_object_actief: no; Identity Data(Type) - Workset: Family : Windows : NLRS_30_WI_WB_raamsparing_type_generiek_ISR; Assembly Code: 31; Assembly Description: buitenwandopeningen; Description: raamsparing; Model: LOD200; OmniClass Number: 23.30.20.17.11; OmniClass Title: Fixed Windows; SmartRevit_Versie: 1.0; Type Mark: 1232; Type Name: raamsparing_K_41; Analytical Properties(Type) - Define Thermal Properties by: Schematic Type; Analytic Construction: <None>
Basic Wall:21_DAT_metselwerk_100:5537478 | 00 Begane grond | 21.12 Uniformat (Uniformat) | 100 | 2125 | 2000 | raamsparing_K_40 | 2 | Windows |  |  |  |  |  | 31 | buitenwandopeningen | raamsparing | Windows | NLRS_30_WI_WB_raamsparing_type_generiek_ISR | NLRS_30_WI_WB_raamsparing_type_generiek_ISR: raamsparing_K_40 | raamsparing_K_40 | 5540939 |  |  |  |  |  |  | 5.69375 |  | Bouwkundig | 2. nieuwbouw | Constraints - Level: 0; Sill Height: 525 mm; Dimensions - NLRS_C_breedte: 2000 mm; NLRS_C_hoogte: 2125 mm; Identity Data - Mark: 3970; Pset_Window - Omschrijving: raamsparing; NL-sfb-Codering: 31; Other - berekende_gevelsparing_BW_offset: 1562.5 mm; gevelsparing_breedte: 2000 mm; gevelsparing_hoogte: 2125 mm; Head Height: 2650 mm; Host Id: 5536773; Other(Type) - Category: Windows; Family Name: NLRS_30_WI_WB_raamsparing_type_generiek_ISR; Construction(Type) - gevelsparing_breedteverschil: 0 mm; gevelsparing_hoogteverschil: 0 mm; lossing: 0 mm; gevelsparing_borstweringverschil: 500 mm; Dimensions(Type) - Rough Height: 0 mm; Rough Width: 0 mm; Height: 2125 mm; Width: 2000 mm; Graphics(Type) - clash_object_actief: no; Identity Data(Type) - Workset: Family : Windows : NLRS_30_WI_WB_raamsparing_type_generiek_ISR; Assembly Code: 31; Assembly Description: buitenwandopeningen; Description: raamsparing; Model: LOD200; OmniClass Number: 23.30.20.17.11; OmniClass Title: Fixed Windows; SmartRevit_Versie: 1.0; Type Mark: 1231; Type Name: raamsparing_K_40; Analytical Properties(Type) - Define Thermal Properties by: Schematic Type; Analytic Construction: <None>
Basic Wall:21_DAT_metselwerk_100:5537478 | 00 Begane grond | 21.12 Uniformat (Uniformat) | 100 | 2125 | 2000 | raamsparing_K_40 | 2 | Windows |  |  |  |  |  | 31 | buitenwandopeningen | raamsparing | Windows | NLRS_30_WI_WB_raamsparing_type_generiek_ISR | NLRS_30_WI_WB_raamsparing_type_generiek_ISR: raamsparing_K_40 | raamsparing_K_40 | 5540939 |  |  |  |  |  |  | 5.69375 |  | Bouwkundig | 2. nieuwbouw | Constraints - Level: 0; Sill Height: 525 mm; Dimensions - NLRS_C_breedte: 2000 mm; NLRS_C_hoogte: 2125 mm; Identity Data - Mark: 3976; Pset_Window - Omschrijving: raamsparing; NL-sfb-Codering: 31; Other - berekende_gevelsparing_BW_offset: 1562.5 mm; gevelsparing_breedte: 2000 mm; gevelsparing_hoogte: 2125 mm; Head Height: 2650 mm; Host Id: 5536773; Other(Type) - Category: Windows; Family Name: NLRS_30_WI_WB_raamsparing_type_generiek_ISR; Construction(Type) - gevelsparing_breedteverschil: 0 mm; gevelsparing_hoogteverschil: 0 mm; lossing: 0 mm; gevelsparing_borstweringverschil: 500 mm; Dimensions(Type) - Rough Height: 0 mm; Rough Width: 0 mm; Height: 2125 mm; Width: 2000 mm; Graphics(Type) - clash_object_actief: no; Identity Data(Type) - Workset: Family : Windows : NLRS_30_WI_WB_raamsparing_type_generiek_ISR; Assembly Code: 31; Assembly Description: buitenwandopeningen; Description: raamsparing; Model: LOD200; OmniClass Number: 23.30.20.17.11; OmniClass Title: Fixed Windows; SmartRevit_Versie: 1.0; Type Mark: 1231; Type Name: raamsparing_K_40; Analytical Properties(Type) - Define Thermal Properties by: Schematic Type; Analytic Construction: <None>
Basic Wall:21_DAT_metselwerk_100:5537478 | 00 Begane grond | 21.12 Uniformat (Uniformat) | 100 | 2125 | 2000 | raamsparing_K_40 | 2 | Windows |  |  |  |  |  | 31 | buitenwandopeningen | raamsparing | Windows | NLRS_30_WI_WB_raamsparing_type_generiek_ISR | NLRS_30_WI_WB_raamsparing_type_generiek_ISR: raamsparing_K_40 | raamsparing_K_40 | 5540939 |  |  |  |  |  |  | 5.69375 |  | Bouwkundig | 2. nieuwbouw | Constraints - Level: 0; Sill Height: 525 mm; Dimensions - NLRS_C_breedte: 2000 mm; NLRS_C_hoogte: 2125 mm; Identity Data - Mark: 3982; Pset_Window - Omschrijving: raamsparing; NL-sfb-Codering: 31; Other - berekende_gevelsparing_BW_offset: 1562.5 mm; gevelsparing_breedte: 2000 mm; gevelsparing_hoogte: 2125 mm; Head Height: 2650 mm; Host Id: 5536773; Other(Type) - Category: Windows; Family Name: NLRS_30_WI_WB_raamsparing_type_generiek_ISR; Construction(Type) - gevelsparing_breedteverschil: 0 mm; gevelsparing_hoogteverschil: 0 mm; lossing: 0 mm; gevelsparing_borstweringverschil: 500 mm; Dimensions(Type) - Rough Height: 0 mm; Rough Width: 0 mm; Height: 2125 mm; Width: 2000 mm; Graphics(Type) - clash_object_actief: no; Identity Data(Type) - Workset: Family : Windows : NLRS_30_WI_WB_raamsparing_type_generiek_ISR; Assembly Code: 31; Assembly Description: buitenwandopeningen; Description: raamsparing; Model: LOD200; OmniClass Number: 23.30.20.17.11; OmniClass Title: Fixed Windows; SmartRevit_Versie: 1.0; Type Mark: 1231; Type Name: raamsparing_K_40; Analytical Properties(Type) - Define Thermal Properties by: Schematic Type; Analytic Construction: <None>
Basic Wall:21_DAT_metselwerk_100:5537478 | 00 Begane grond | 21.12 Uniformat (Uniformat) | 100 | 2125 | 2000 | raamsparing_K_40 | 2 | Windows |  |  |  |  |  | 31 | buitenwandopeningen | raamsparing | Windows | NLRS_30_WI_WB_raamsparing_type_generiek_ISR | NLRS_30_WI_WB_raamsparing_type_generiek_ISR: raamsparing_K_40 | raamsparing_K_40 | 5540939 |  |  |  |  |  |  | 5.69375 |  | Bouwkundig | 2. nieuwbouw | Constraints - Level: 0; Sill Height: 525 mm; Dimensions - NLRS_C_breedte: 2000 mm; NLRS_C_hoogte: 2125 mm; Identity Data - Mark: 3988; Pset_Window - Omschrijving: raamsparing; NL-sfb-Codering: 31; Other - berekende_gevelsparing_BW_offset: 1562.5 mm; gevelsparing_breedte: 2000 mm; gevelsparing_hoogte: 2125 mm; Head Height: 2650 mm; Host Id: 5536773; Other(Type) - Category: Windows; Family Name: NLRS_30_WI_WB_raamsparing_type_generiek_ISR; Construction(Type) - gevelsparing_breedteverschil: 0 mm; gevelsparing_hoogteverschil: 0 mm; lossing: 0 mm; gevelsparing_borstweringverschil: 500 mm; Dimensions(Type) - Rough Height: 0 mm; Rough Width: 0 mm; Height: 2125 mm; Width: 2000 mm; Graphics(Type) - clash_object_actief: no; Identity Data(Type) - Workset: Family : Windows : NLRS_30_WI_WB_raamsparing_type_generiek_ISR; Assembly Code: 31; Assembly Description: buitenwandopeningen; Description: raamsparing; Model: LOD200; OmniClass Number: 23.30.20.17.11; OmniClass Title: Fixed Windows; SmartRevit_Versie: 1.0; Type Mark: 1231; Type Name: raamsparing_K_40; Analytical Properties(Type) - Define Thermal Properties by: Schematic Type; Analytic Construction: <None>
Basic Wall:21_DAT_metselwerk_100:5537478 | 00 Begane grond | 21.12 Uniformat (Uniformat) | 100 | 2125 | 2000 | raamsparing_K_40 | 2 | Windows |  |  |  |  |  | 31 | buitenwandopeningen | raamsparing | Windows | NLRS_30_WI_WB_raamsparing_type_generiek_ISR | NLRS_30_WI_WB_raamsparing_type_generiek_ISR: raamsparing_K_40 | raamsparing_K_40 | 5540939 |  |  |  |  |  |  | 5.69375 |  | Bouwkundig | 2. nieuwbouw | Constraints - Level: 0; Sill Height: 525 mm; Dimensions - NLRS_C_breedte: 2000 mm; NLRS_C_hoogte: 2125 mm; Identity Data - Mark: 3994; Pset_Window - Omschrijving: raamsparing; NL-sfb-Codering: 31; Other - berekende_gevelsparing_BW_offset: 1562.5 mm; gevelsparing_breedte: 2000 mm; gevelsparing_hoogte: 2125 mm; Head Height: 2650 mm; Host Id: 5536773; Other(Type) - Category: Windows; Family Name: NLRS_30_WI_WB_raamsparing_type_generiek_ISR; Construction(Type) - gevelsparing_breedteverschil: 0 mm; gevelsparing_hoogteverschil: 0 mm; lossing: 0 mm; gevelsparing_borstweringverschil: 500 mm; Dimensions(Type) - Rough Height: 0 mm; Rough Width: 0 mm; Height: 2125 mm; Width: 2000 mm; Graphics(Type) - clash_object_actief: no; Identity Data(Type) - Workset: Family : Windows : NLRS_30_WI_WB_raamsparing_type_generiek_ISR; Assembly Code: 31; Assembly Description: buitenwandopeningen; Description: raamsparing; Model: LOD200; OmniClass Number: 23.30.20.17.11; OmniClass Title: Fixed Windows; SmartRevit_Versie: 1.0; Type Mark: 1231; Type Name: raamsparing_K_40; Analytical Properties(Type) - Define Thermal Properties by: Schematic Type; Analytic Construction: <None>
Basic Wall:21_DAT_metselwerk_100:5537478 | 00 Begane grond | 21.12 Uniformat (Uniformat) | 100 | 2125 | 2000 | raamsparing_K_40 | 2 | Windows |  |  |  |  |  | 31 | buitenwandopeningen | raamsparing | Windows | NLRS_30_WI_WB_raamsparing_type_generiek_ISR | NLRS_30_WI_WB_raamsparing_type_generiek_ISR: raamsparing_K_40 | raamsparing_K_40 | 5540939 |  |  |  |  |  |  | 5.69375 |  | Bouwkundig | 2. nieuwbouw | Constraints - Level: 0; Sill Height: 525 mm; Dimensions - NLRS_C_breedte: 2000 mm; NLRS_C_hoogte: 2125 mm; Identity Data - Mark: 4000; Pset_Window - Omschrijving: raamsparing; NL-sfb-Codering: 31; Other - berekende_gevelsparing_BW_offset: 1562.5 mm; gevelsparing_breedte: 2000 mm; gevelsparing_hoogte: 2125 mm; Head Height: 2650 mm; Host Id: 5536773; Other(Type) - Category: Windows; Family Name: NLRS_30_WI_WB_raamsparing_type_generiek_ISR; Construction(Type) - gevelsparing_breedteverschil: 0 mm; gevelsparing_hoogteverschil: 0 mm; lossing: 0 mm; gevelsparing_borstweringverschil: 500 mm; Dimensions(Type) - Rough Height: 0 mm; Rough Width: 0 mm; Height: 2125 mm; Width: 2000 mm; Graphics(Type) - clash_object_actief: no; Identity Data(Type) - Workset: Family : Windows : NLRS_30_WI_WB_raamsparing_type_generiek_ISR; Assembly Code: 31; Assembly Description: buitenwandopeningen; Description: raamsparing; Model: LOD200; OmniClass Number: 23.30.20.17.11; OmniClass Title: Fixed Windows; SmartRevit_Versie: 1.0; Type Mark: 1231; Type Name: raamsparing_K_40; Analytical Properties(Type) - Define Thermal Properties by: Schematic Type; Analytic Construction: <None>
Basic Wall:21_DAT_metselwerk_100:5537478 | 00 Begane grond | 21.12 Uniformat (Uniformat) | 100 | 2125 | 840 | raamsparing_K_41 | 2 | Windows |  |  |  |  |  | 31 | buitenwandopeningen | raamsparing | Windows | NLRS_30_WI_WB_raamsparing_type_generiek_ISR | NLRS_30_WI_WB_raamsparing_type_generiek_ISR: raamsparing_K_41 | raamsparing_K_41 | 5542498 |  |  |  |  |  |  | 2.82275 |  | Bouwkundig | 2. nieuwbouw | Constraints - Level: 0; Sill Height: 525 mm; Dimensions - NLRS_C_breedte: 840 mm; NLRS_C_hoogte: 2125 mm; Identity Data - Mark: 4012; Pset_Window - Omschrijving: raamsparing; NL-sfb-Codering: 31; Other - berekende_gevelsparing_BW_offset: 1562.5 mm; gevelsparing_breedte: 840 mm; gevelsparing_hoogte: 2125 mm; Head Height: 2650 mm; Host Id: 5536773; Other(Type) - Category: Windows; Family Name: NLRS_30_WI_WB_raamsparing_type_generiek_ISR; Construction(Type) - gevelsparing_breedteverschil: 0 mm; gevelsparing_hoogteverschil: 0 mm; lossing: 0 mm; gevelsparing_borstweringverschil: 500 mm; Dimensions(Type) - Rough Height: 0 mm; Rough Width: 0 mm; Height: 2125 mm; Width: 840 mm; Graphics(Type) - clash_object_actief: no; Identity Data(Type) - Workset: Family : Windows : NLRS_30_WI_WB_raamsparing_type_generiek_ISR; Assembly Code: 31; Assembly Description: buitenwandopeningen; Description: raamsparing; Model: LOD200; OmniClass Number: 23.30.20.17.11; OmniClass Title: Fixed Windows; SmartRevit_Versie: 1.0; Type Mark: 1232; Type Name: raamsparing_K_41; Analytical Properties(Type) - Define Thermal Properties by: Schematic Type; Analytic Construction: <None>
Basic Wall:21_DAT_metselwerk_100:5537478 | 00 Begane grond | 21.12 Uniformat (Uniformat) | 100 | 2125 | 840 | raamsparing_K_41 | 2 | Windows |  |  |  |  |  | 31 | buitenwandopeningen | raamsparing | Windows | NLRS_30_WI_WB_raamsparing_type_generiek_ISR | NLRS_30_WI_WB_raamsparing_type_generiek_ISR: raamsparing_K_41 | raamsparing_K_41 | 5542498 |  |  |  |  |  |  | 2.82275 |  | Bouwkundig | 2. nieuwbouw | Constraints - Level: 0; Sill Height: 525 mm; Dimensions - NLRS_C_breedte: 840 mm; NLRS_C_hoogte: 2125 mm; Identity Data - Mark: 4013; Pset_Window - Omschrijving: raamsparing; NL-sfb-Codering: 31; Other - berekende_gevelsparing_BW_offset: 1562.5 mm; gevelsparing_breedte: 840 mm; gevelsparing_hoogte: 2125 mm; Head Height: 2650 mm; Host Id: 5536773; Other(Type) - Category: Windows; Family Name: NLRS_30_WI_WB_raamsparing_type_generiek_ISR; Construction(Type) - gevelsparing_breedteverschil: 0 mm; gevelsparing_hoogteverschil: 0 mm; lossing: 0 mm; gevelsparing_borstweringverschil: 500 mm; Dimensions(Type) - Rough Height: 0 mm; Rough Width: 0 mm; Height: 2125 mm; Width: 840 mm; Graphics(Type) - clash_object_actief: no; Identity Data(Type) - Workset: Family : Windows : NLRS_30_WI_WB_raamsparing_type_generiek_ISR; Assembly Code: 31; Assembly Description: buitenwandopeningen; Description: raamsparing; Model: LOD200; OmniClass Number: 23.30.20.17.11; OmniClass Title: Fixed Windows; SmartRevit_Versie: 1.0; Type Mark: 1232; Type Name: raamsparing_K_41; Analytical Properties(Type) - Define Thermal Properties by: Schematic Type; Analytic Construction: <None>
Basic Wall:21_DAT_metselwerk_100:5537478 | 00 Begane grond | 21.12 Uniformat (Uniformat) | 100 | 2125 | 840 | raamsparing_K_41 | 2 | Windows |  |  |  |  |  | 31 | buitenwandopeningen | raamsparing | Windows | NLRS_30_WI_WB_raamsparing_type_generiek_ISR | NLRS_30_WI_WB_raamsparing_type_generiek_ISR: raamsparing_K_41 | raamsparing_K_41 | 5542498 |  |  |  |  |  |  | 2.82275 |  | Bouwkundig | 2. nieuwbouw | Constraints - Level: 0; Sill Height: 525 mm; Dimensions - NLRS_C_breedte: 840 mm; NLRS_C_hoogte: 2125 mm; Identity Data - Mark: 4017; Pset_Window - Omschrijving: raamsparing; NL-sfb-Codering: 31; Other - berekende_gevelsparing_BW_offset: 1562.5 mm; gevelsparing_breedte: 840 mm; gevelsparing_hoogte: 2125 mm; Head Height: 2650 mm; Host Id: 5536773; Other(Type) - Category: Windows; Family Name: NLRS_30_WI_WB_raamsparing_type_generiek_ISR; Construction(Type) - gevelsparing_breedteverschil: 0 mm; gevelsparing_hoogteverschil: 0 mm; lossing: 0 mm; gevelsparing_borstweringverschil: 500 mm; Dimensions(Type) - Rough Height: 0 mm; Rough Width: 0 mm; Height: 2125 mm; Width: 840 mm; Graphics(Type) - clash_object_actief: no; Identity Data(Type) - Workset: Family : Windows : NLRS_30_WI_WB_raamsparing_type_generiek_ISR; Assembly Code: 31; Assembly Description: buitenwandopeningen; Description: raamsparing; Model: LOD200; OmniClass Number: 23.30.20.17.11; OmniClass Title: Fixed Windows; SmartRevit_Versie: 1.0; Type Mark: 1232; Type Name: raamsparing_K_41; Analytical Properties(Type) - Define Thermal Properties by: Schematic Type; Analytic Construction: <None>
Basic Wall:21_DAT_metselwerk_100:5537478 | 00 Begane grond | 21.12 Uniformat (Uniformat) | 100 | 2125 | 840 | raamsparing_K_41 | 2 | Windows |  |  |  |  |  | 31 | buitenwandopeningen | raamsparing | Windows | NLRS_30_WI_WB_raamsparing_type_generiek_ISR | NLRS_30_WI_WB_raamsparing_type_generiek_ISR: raamsparing_K_41 | raamsparing_K_41 | 5542498 |  |  |  |  |  |  | 2.82275 |  | Bouwkundig | 2. nieuwbouw | Constraints - Level: 0; Sill Height: 525 mm; Dimensions - NLRS_C_breedte: 840 mm; NLRS_C_hoogte: 2125 mm; Identity Data - Mark: 4021; Pset_Window - Omschrijving: raamsparing; NL-sfb-Codering: 31; Other - berekende_gevelsparing_BW_offset: 1562.5 mm; gevelsparing_breedte: 840 mm; gevelsparing_hoogte: 2125 mm; Head Height: 2650 mm; Host Id: 5536773; Other(Type) - Category: Windows; Family Name: NLRS_30_WI_WB_raamsparing_type_generiek_ISR; Construction(Type) - gevelsparing_breedteverschil: 0 mm; gevelsparing_hoogteverschil: 0 mm; lossing: 0 mm; gevelsparing_borstweringverschil: 500 mm; Dimensions(Type) - Rough Height: 0 mm; Rough Width: 0 mm; Height: 2125 mm; Width: 840 mm; Graphics(Type) - clash_object_actief: no; Identity Data(Type) - Workset: Family : Windows : NLRS_30_WI_WB_raamsparing_type_generiek_ISR; Assembly Code: 31; Assembly Description: buitenwandopeningen; Description: raamsparing; Model: LOD200; OmniClass Number: 23.30.20.17.11; OmniClass Title: Fixed Windows; SmartRevit_Versie: 1.0; Type Mark: 1232; Type Name: raamsparing_K_41; Analytical Properties(Type) - Define Thermal Properties by: Schematic Type; Analytic Construction: <None>
Basic Wall:21_DAT_metselwerk_100:5537478 | 00 Begane grond | 21.12 Uniformat (Uniformat) | 100 | 2125 | 840 | raamsparing_K_41 | 2 | Windows |  |  |  |  |  | 31 | buitenwandopeningen | raamsparing | Windows | NLRS_30_WI_WB_raamsparing_type_generiek_ISR | NLRS_30_WI_WB_raamsparing_type_generiek_ISR: raamsparing_K_41 | raamsparing_K_41 | 5542498 |  |  |  |  |  |  | 2.82275 |  | Bouwkundig | 2. nieuwbouw | Constraints - Level: 0; Sill Height: 525 mm; Dimensions - NLRS_C_breedte: 840 mm; NLRS_C_hoogte: 2125 mm; Identity Data - Mark: 4025; Pset_Window - Omschrijving: raamsparing; NL-sfb-Codering: 31; Other - berekende_gevelsparing_BW_offset: 1562.5 mm; gevelsparing_breedte: 840 mm; gevelsparing_hoogte: 2125 mm; Head Height: 2650 mm; Host Id: 5536773; Other(Type) - Category: Windows; Family Name: NLRS_30_WI_WB_raamsparing_type_generiek_ISR; Construction(Type) - gevelsparing_breedteverschil: 0 mm; gevelsparing_hoogteverschil: 0 mm; lossing: 0 mm; gevelsparing_borstweringverschil: 500 mm; Dimensions(Type) - Rough Height: 0 mm; Rough Width: 0 mm; Height: 2125 mm; Width: 840 mm; Graphics(Type) - clash_object_actief: no; Identity Data(Type) - Workset: Family : Windows : NLRS_30_WI_WB_raamsparing_type_generiek_ISR; Assembly Code: 31; Assembly Description: buitenwandopeningen; Description: raamsparing; Model: LOD200; OmniClass Number: 23.30.20.17.11; OmniClass Title: Fixed Windows; SmartRevit_Versie: 1.0; Type Mark: 1232; Type Name: raamsparing_K_41; Analytical Properties(Type) - Define Thermal Properties by: Schematic Type; Analytic Construction: <None>
Basic Wall:21_DAT_metselwerk_100:5537479 | 00 Begane grond | 21.12 Uniformat (Uniformat) | 100 | 2125 | 2000 | raamsparing_K_40 | 2 | Windows |  |  |  |  |  | 31 | buitenwandopeningen | raamsparing | Windows | NLRS_30_WI_WB_raamsparing_type_generiek_ISR | NLRS_30_WI_WB_raamsparing_type_generiek_ISR: raamsparing_K_40 | raamsparing_K_40 | 5540939 |  |  |  |  |  |  | 5.69375 |  | Bouwkundig | 2. nieuwbouw | Constraints - Level: 0; Sill Height: 525 mm; Dimensions - NLRS_C_breedte: 2000 mm; NLRS_C_hoogte: 2125 mm; Identity Data - Mark: 3970; Pset_Window - Omschrijving: raamsparing; NL-sfb-Codering: 31; Other - berekende_gevelsparing_BW_offset: 1562.5 mm; gevelsparing_breedte: 2000 mm; gevelsparing_hoogte: 2125 mm; Head Height: 2650 mm; Host Id: 5536773; Other(Type) - Category: Windows; Family Name: NLRS_30_WI_WB_raamsparing_type_generiek_ISR; Construction(Type) - gevelsparing_breedteverschil: 0 mm; gevelsparing_hoogteverschil: 0 mm; lossing: 0 mm; gevelsparing_borstweringverschil: 500 mm; Dimensions(Type) - Rough Height: 0 mm; Rough Width: 0 mm; Height: 2125 mm; Width: 2000 mm; Graphics(Type) - clash_object_actief: no; Identity Data(Type) - Workset: Family : Windows : NLRS_30_WI_WB_raamsparing_type_generiek_ISR; Assembly Code: 31; Assembly Description: buitenwandopeningen; Description: raamsparing; Model: LOD200; OmniClass Number: 23.30.20.17.11; OmniClass Title: Fixed Windows; SmartRevit_Versie: 1.0; Type Mark: 1231; Type Name: raamsparing_K_40; Analytical Properties(Type) - Define Thermal Properties by: Schematic Type; Analytic Construction: <None>
Basic Wall:21_DAT_metselwerk_100:5537479 | 00 Begane grond | 21.12 Uniformat (Uniformat) | 100 | 2125 | 2000 | raamsparing_K_40 | 2 | Windows |  |  |  |  |  | 31 | buitenwandopeningen | raamsparing | Windows | NLRS_30_WI_WB_raamsparing_type_generiek_ISR | NLRS_30_WI_WB_raamsparing_type_generiek_ISR: raamsparing_K_40 | raamsparing_K_40 | 5540939 |  |  |  |  |  |  | 5.69375 |  | Bouwkundig | 2. nieuwbouw | Constraints - Level: 0; Sill Height: 525 mm; Dimensions - NLRS_C_breedte: 2000 mm; NLRS_C_hoogte: 2125 mm; Identity Data - Mark: 3976; Pset_Window - Omschrijving: raamsparing; NL-sfb-Codering: 31; Other - berekende_gevelsparing_BW_offset: 1562.5 mm; gevelsparing_breedte: 2000 mm; gevelsparing_hoogte: 2125 mm; Head Height: 2650 mm; Host Id: 5536773; Other(Type) - Category: Windows; Family Name: NLRS_30_WI_WB_raamsparing_type_generiek_ISR; Construction(Type) - gevelsparing_breedteverschil: 0 mm; gevelsparing_hoogteverschil: 0 mm; lossing: 0 mm; gevelsparing_borstweringverschil: 500 mm; Dimensions(Type) - Rough Height: 0 mm; Rough Width: 0 mm; Height: 2125 mm; Width: 2000 mm; Graphics(Type) - clash_object_actief: no; Identity Data(Type) - Workset: Family : Windows : NLRS_30_WI_WB_raamsparing_type_generiek_ISR; Assembly Code: 31; Assembly Description: buitenwandopeningen; Description: raamsparing; Model: LOD200; OmniClass Number: 23.30.20.17.11; OmniClass Title: Fixed Windows; SmartRevit_Versie: 1.0; Type Mark: 1231; Type Name: raamsparing_K_40; Analytical Properties(Type) - Define Thermal Properties by: Schematic Type; Analytic Construction: <None>
Basic Wall:21_DAT_metselwerk_100:5537479 | 00 Begane grond | 21.12 Uniformat (Uniformat) | 100 | 2125 | 2000 | raamsparing_K_40 | 2 | Windows |  |  |  |  |  | 31 | buitenwandopeningen | raamsparing | Windows | NLRS_30_WI_WB_raamsparing_type_generiek_ISR | NLRS_30_WI_WB_raamsparing_type_generiek_ISR: raamsparing_K_40 | raamsparing_K_40 | 5540939 |  |  |  |  |  |  | 5.69375 |  | Bouwkundig | 2. nieuwbouw | Constraints - Level: 0; Sill Height: 525 mm; Dimensions - NLRS_C_breedte: 2000 mm; NLRS_C_hoogte: 2125 mm; Identity Data - Mark: 3982; Pset_Window - Omschrijving: raamsparing; NL-sfb-Codering: 31; Other - berekende_gevelsparing_BW_offset: 1562.5 mm; gevelsparing_breedte: 2000 mm; gevelsparing_hoogte: 2125 mm; Head Height: 2650 mm; Host Id: 5536773; Other(Type) - Category: Windows; Family Name: NLRS_30_WI_WB_raamsparing_type_generiek_ISR; Construction(Type) - gevelsparing_breedteverschil: 0 mm; gevelsparing_hoogteverschil: 0 mm; lossing: 0 mm; gevelsparing_borstweringverschil: 500 mm; Dimensions(Type) - Rough Height: 0 mm; Rough Width: 0 mm; Height: 2125 mm; Width: 2000 mm; Graphics(Type) - clash_object_actief: no; Identity Data(Type) - Workset: Family : Windows : NLRS_30_WI_WB_raamsparing_type_generiek_ISR; Assembly Code: 31; Assembly Description: buitenwandopeningen; Description: raamsparing; Model: LOD200; OmniClass Number: 23.30.20.17.11; OmniClass Title: Fixed Windows; SmartRevit_Versie: 1.0; Type Mark: 1231; Type Name: raamsparing_K_40; Analytical Properties(Type) - Define Thermal Properties by: Schematic Type; Analytic Construction: <None>
Basic Wall:21_DAT_metselwerk_100:5537479 | 00 Begane grond | 21.12 Uniformat (Uniformat) | 100 | 2125 | 2000 | raamsparing_K_40 | 2 | Windows |  |  |  |  |  | 31 | buitenwandopeningen | raamsparing | Windows | NLRS_30_WI_WB_raamsparing_type_generiek_ISR | NLRS_30_WI_WB_raamsparing_type_generiek_ISR: raamsparing_K_40 | raamsparing_K_40 | 5540939 |  |  |  |  |  |  | 5.69375 |  | Bouwkundig | 2. nieuwbouw | Constraints - Level: 0; Sill Height: 525 mm; Dimensions - NLRS_C_breedte: 2000 mm; NLRS_C_hoogte: 2125 mm; Identity Data - Mark: 3988; Pset_Window - Omschrijving: raamsparing; NL-sfb-Codering: 31; Other - berekende_gevelsparing_BW_offset: 1562.5 mm; gevelsparing_breedte: 2000 mm; gevelsparing_hoogte: 2125 mm; Head Height: 2650 mm; Host Id: 5536773; Other(Type) - Category: Windows; Family Name: NLRS_30_WI_WB_raamsparing_type_generiek_ISR; Construction(Type) - gevelsparing_breedteverschil: 0 mm; gevelsparing_hoogteverschil: 0 mm; lossing: 0 mm; gevelsparing_borstweringverschil: 500 mm; Dimensions(Type) - Rough Height: 0 mm; Rough Width: 0 mm; Height: 2125 mm; Width: 2000 mm; Graphics(Type) - clash_object_actief: no; Identity Data(Type) - Workset: Family : Windows : NLRS_30_WI_WB_raamsparing_type_generiek_ISR; Assembly Code: 31; Assembly Description: buitenwandopeningen; Description: raamsparing; Model: LOD200; OmniClass Number: 23.30.20.17.11; OmniClass Title: Fixed Windows; SmartRevit_Versie: 1.0; Type Mark: 1231; Type Name: raamsparing_K_40; Analytical Properties(Type) - Define Thermal Properties by: Schematic Type; Analytic Construction: <None>
Basic Wall:21_DAT_metselwerk_100:5537479 | 00 Begane grond | 21.12 Uniformat (Uniformat) | 100 | 2125 | 2000 | raamsparing_K_40 | 2 | Windows |  |  |  |  |  | 31 | buitenwandopeningen | raamsparing | Windows | NLRS_30_WI_WB_raamsparing_type_generiek_ISR | NLRS_30_WI_WB_raamsparing_type_generiek_ISR: raamsparing_K_40 | raamsparing_K_40 | 5540939 |  |  |  |  |  |  | 5.69375 |  | Bouwkundig | 2. nieuwbouw | Constraints - Level: 0; Sill Height: 525 mm; Dimensions - NLRS_C_breedte: 2000 mm; NLRS_C_hoogte: 2125 mm; Identity Data - Mark: 3994; Pset_Window - Omschrijving: raamsparing; NL-sfb-Codering: 31; Other - berekende_gevelsparing_BW_offset: 1562.5 mm; gevelsparing_breedte: 2000 mm; gevelsparing_hoogte: 2125 mm; Head Height: 2650 mm; Host Id: 5536773; Other(Type) - Category: Windows; Family Name: NLRS_30_WI_WB_raamsparing_type_generiek_ISR; Construction(Type) - gevelsparing_breedteverschil: 0 mm; gevelsparing_hoogteverschil: 0 mm; lossing: 0 mm; gevelsparing_borstweringverschil: 500 mm; Dimensions(Type) - Rough Height: 0 mm; Rough Width: 0 mm; Height: 2125 mm; Width: 2000 mm; Graphics(Type) - clash_object_actief: no; Identity Data(Type) - Workset: Family : Windows : NLRS_30_WI_WB_raamsparing_type_generiek_ISR; Assembly Code: 31; Assembly Description: buitenwandopeningen; Description: raamsparing; Model: LOD200; OmniClass Number: 23.30.20.17.11; OmniClass Title: Fixed Windows; SmartRevit_Versie: 1.0; Type Mark: 1231; Type Name: raamsparing_K_40; Analytical Properties(Type) - Define Thermal Properties by: Schematic Type; Analytic Construction: <None>
Basic Wall:21_DAT_metselwerk_100:5537479 | 00 Begane grond | 21.12 Uniformat (Uniformat) | 100 | 2125 | 2000 | raamsparing_K_40 | 2 | Windows |  |  |  |  |  | 31 | buitenwandopeningen | raamsparing | Windows | NLRS_30_WI_WB_raamsparing_type_generiek_ISR | NLRS_30_WI_WB_raamsparing_type_generiek_ISR: raamsparing_K_40 | raamsparing_K_40 | 5540939 |  |  |  |  |  |  | 5.69375 |  | Bouwkundig | 2. nieuwbouw | Constraints - Level: 0; Sill Height: 525 mm; Dimensions - NLRS_C_breedte: 2000 mm; NLRS_C_hoogte: 2125 mm; Identity Data - Mark: 4000; Pset_Window - Omschrijving: raamsparing; NL-sfb-Codering: 31; Other - berekende_gevelsparing_BW_offset: 1562.5 mm; gevelsparing_breedte: 2000 mm; gevelsparing_hoogte: 2125 mm; Head Height: 2650 mm; Host Id: 5536773; Other(Type) - Category: Windows; Family Name: NLRS_30_WI_WB_raamsparing_type_generiek_ISR; Construction(Type) - gevelsparing_breedteverschil: 0 mm; gevelsparing_hoogteverschil: 0 mm; lossing: 0 mm; gevelsparing_borstweringverschil: 500 mm; Dimensions(Type) - Rough Height: 0 mm; Rough Width: 0 mm; Height: 2125 mm; Width: 2000 mm; Graphics(Type) - clash_object_actief: no; Identity Data(Type) - Workset: Family : Windows : NLRS_30_WI_WB_raamsparing_type_generiek_ISR; Assembly Code: 31; Assembly Description: buitenwandopeningen; Description: raamsparing; Model: LOD200; OmniClass Number: 23.30.20.17.11; OmniClass Title: Fixed Windows; SmartRevit_Versie: 1.0; Type Mark: 1231; Type Name: raamsparing_K_40; Analytical Properties(Type) - Define Thermal Properties by: Schematic Type; Analytic Construction: <None>
Basic Wall:21_DAT_metselwerk_100:5537479 | 00 Begane grond | 21.12 Uniformat (Uniformat) | 100 | 2125 | 840 | raamsparing_K_41 | 2 | Windows |  |  |  |  |  | 31 | buitenwandopeningen | raamsparing | Windows | NLRS_30_WI_WB_raamsparing_type_generiek_ISR | NLRS_30_WI_WB_raamsparing_type_generiek_ISR: raamsparing_K_41 | raamsparing_K_41 | 5542498 |  |  |  |  |  |  | 2.82275 |  | Bouwkundig | 2. nieuwbouw | Constraints - Level: 0; Sill Height: 525 mm; Dimensions - NLRS_C_breedte: 840 mm; NLRS_C_hoogte: 2125 mm; Identity Data - Mark: 4012; Pset_Window - Omschrijving: raamsparing; NL-sfb-Codering: 31; Other - berekende_gevelsparing_BW_offset: 1562.5 mm; gevelsparing_breedte: 840 mm; gevelsparing_hoogte: 2125 mm; Head Height: 2650 mm; Host Id: 5536773; Other(Type) - Category: Windows; Family Name: NLRS_30_WI_WB_raamsparing_type_generiek_ISR; Construction(Type) - gevelsparing_breedteverschil: 0 mm; gevelsparing_hoogteverschil: 0 mm; lossing: 0 mm; gevelsparing_borstweringverschil: 500 mm; Dimensions(Type) - Rough Height: 0 mm; Rough Width: 0 mm; Height: 2125 mm; Width: 840 mm; Graphics(Type) - clash_object_actief: no; Identity Data(Type) - Workset: Family : Windows : NLRS_30_WI_WB_raamsparing_type_generiek_ISR; Assembly Code: 31; Assembly Description: buitenwandopeningen; Description: raamsparing; Model: LOD200; OmniClass Number: 23.30.20.17.11; OmniClass Title: Fixed Windows; SmartRevit_Versie: 1.0; Type Mark: 1232; Type Name: raamsparing_K_41; Analytical Properties(Type) - Define Thermal Properties by: Schematic Type; Analytic Construction: <None>
Basic Wall:21_DAT_metselwerk_100:5537479 | 00 Begane grond | 21.12 Uniformat (Uniformat) | 100 | 2125 | 840 | raamsparing_K_41 | 2 | Windows |  |  |  |  |  | 31 | buitenwandopeningen | raamsparing | Windows | NLRS_30_WI_WB_raamsparing_type_generiek_ISR | NLRS_30_WI_WB_raamsparing_type_generiek_ISR: raamsparing_K_41 | raamsparing_K_41 | 5542498 |  |  |  |  |  |  | 2.82275 |  | Bouwkundig | 2. nieuwbouw | Constraints - Level: 0; Sill Height: 525 mm; Dimensions - NLRS_C_breedte: 840 mm; NLRS_C_hoogte: 2125 mm; Identity Data - Mark: 4013; Pset_Window - Omschrijving: raamsparing; NL-sfb-Codering: 31; Other - berekende_gevelsparing_BW_offset: 1562.5 mm; gevelsparing_breedte: 840 mm; gevelsparing_hoogte: 2125 mm; Head Height: 2650 mm; Host Id: 5536773; Other(Type) - Category: Windows; Family Name: NLRS_30_WI_WB_raamsparing_type_generiek_ISR; Construction(Type) - gevelsparing_breedteverschil: 0 mm; gevelsparing_hoogteverschil: 0 mm; lossing: 0 mm; gevelsparing_borstweringverschil: 500 mm; Dimensions(Type) - Rough Height: 0 mm; Rough Width: 0 mm; Height: 2125 mm; Width: 840 mm; Graphics(Type) - clash_object_actief: no; Identity Data(Type) - Workset: Family : Windows : NLRS_30_WI_WB_raamsparing_type_generiek_ISR; Assembly Code: 31; Assembly Description: buitenwandopeningen; Description: raamsparing; Model: LOD200; OmniClass Number: 23.30.20.17.11; OmniClass Title: Fixed Windows; SmartRevit_Versie: 1.0; Type Mark: 1232; Type Name: raamsparing_K_41; Analytical Properties(Type) - Define Thermal Properties by: Schematic Type; Analytic Construction: <None>
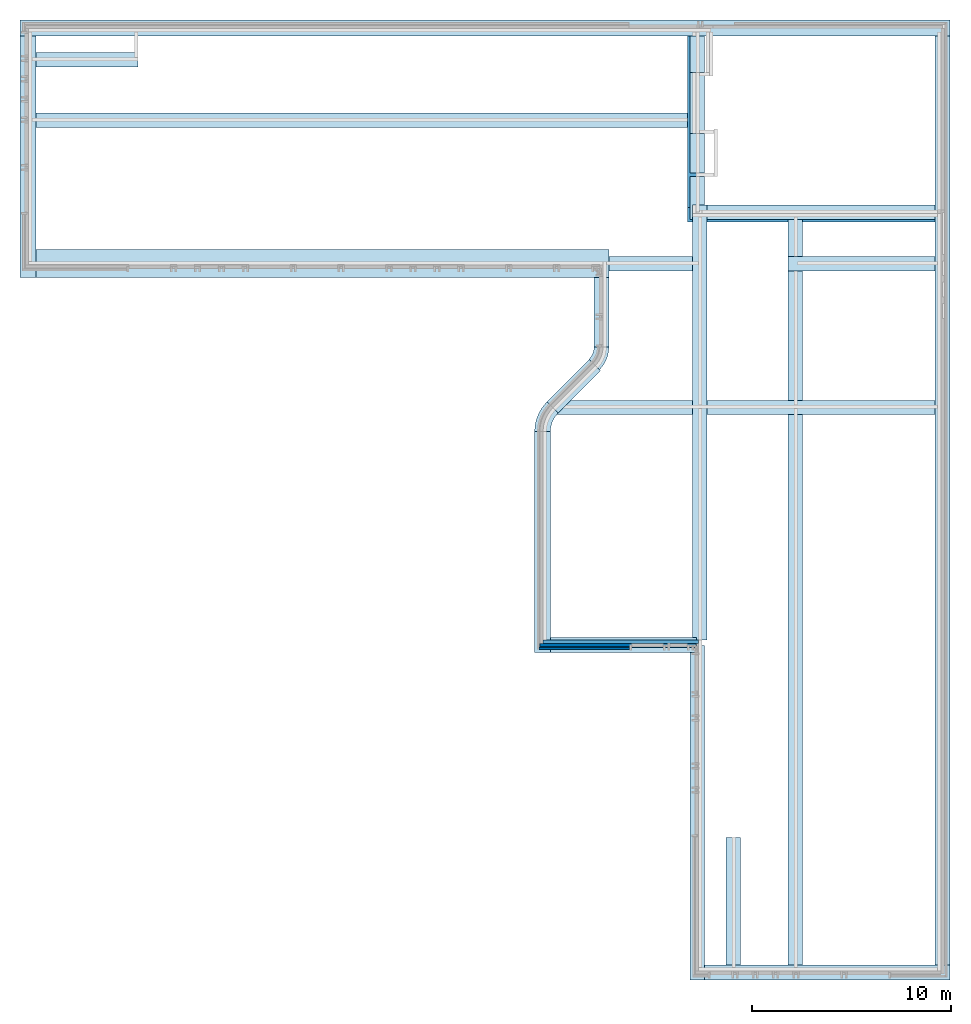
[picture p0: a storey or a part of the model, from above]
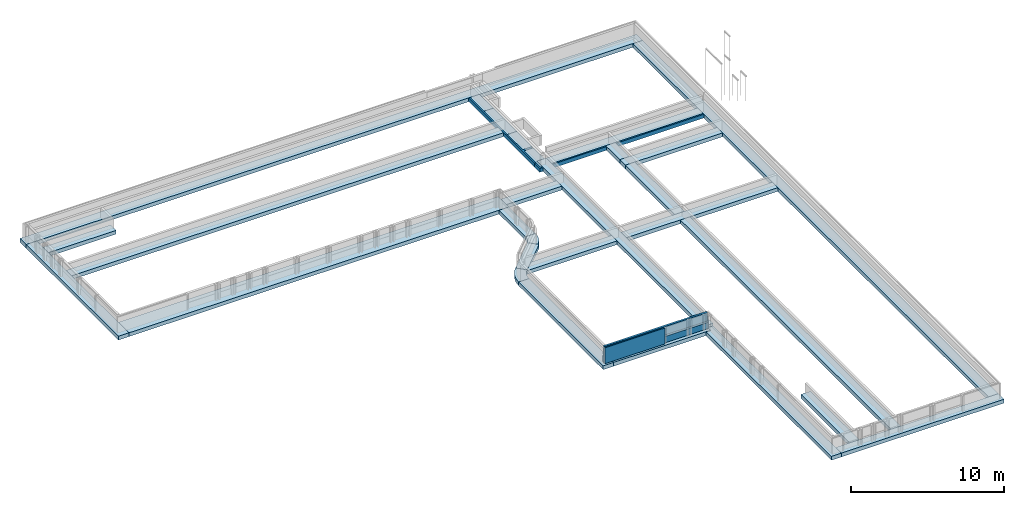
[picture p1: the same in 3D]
Properties of the parts of a building model (IFC2X3), part 24 of 37

# IfcOpeningElement: Opening (1092)
Name | In | Classification | Depth (mm) | BaseQuantities, Height (mm) | BaseQuantities, Width (mm) | Reference | Pset_OpeningElementCommon, sets with these values | Pset_ProductRequirements, Category | Pset_wanden, Structural Usage | Pset_wanden, Omschrijving | Pset_wanden, NL-sfb-Codering | Pset_kozijnen (CW), Omschrijving | Pset_kozijnen (CW), NL-sfb-Codering | Pset_DAT_KMS, Assembly Code | Pset_DAT_KMS, Assembly Description | Pset_DAT_KMS, Description | Other, Category | Family | Other, Family and Type | Type | Type Id | Base Offset (mm) | Base is Attached = Related to Mass = Top is Attached = Structural | Room Bounding | Base Constraint | Top Offset (mm) | Unconnected Height (mm) | Dimensions, Area (m2) | Length (mm) | Identity Data, Workset | Phase Created | Structural, Structural Usage | Angle (deg) = Offset (mm) | Justification | Number | Horizontal Grid, sets with these values | Cross-Section
Basic Wall:21_DAT_metselwerk_100:5537479 | 00 Begane grond | 21.12 Uniformat (Uniformat) | 100 | 2125 | 840 | raamsparing_K_41 | 2 | Windows |  |  |  |  |  | 31 | buitenwandopeningen | raamsparing | Windows | NLRS_30_WI_WB_raamsparing_type_generiek_ISR | NLRS_30_WI_WB_raamsparing_type_generiek_ISR: raamsparing_K_41 | raamsparing_K_41 | 5542498 |  |  |  |  |  |  | 2.82275 |  | Bouwkundig | 2. nieuwbouw | Constraints - Level: 0; Sill Height: 525 mm; Dimensions - NLRS_C_breedte: 840 mm; NLRS_C_hoogte: 2125 mm; Identity Data - Mark: 4017; Pset_Window - Omschrijving: raamsparing; NL-sfb-Codering: 31; Other - berekende_gevelsparing_BW_offset: 1562.5 mm; gevelsparing_breedte: 840 mm; gevelsparing_hoogte: 2125 mm; Head Height: 2650 mm; Host Id: 5536773; Other(Type) - Category: Windows; Family Name: NLRS_30_WI_WB_raamsparing_type_generiek_ISR; Construction(Type) - gevelsparing_breedteverschil: 0 mm; gevelsparing_hoogteverschil: 0 mm; lossing: 0 mm; gevelsparing_borstweringverschil: 500 mm; Dimensions(Type) - Rough Height: 0 mm; Rough Width: 0 mm; Height: 2125 mm; Width: 840 mm; Graphics(Type) - clash_object_actief: no; Identity Data(Type) - Workset: Family : Windows : NLRS_30_WI_WB_raamsparing_type_generiek_ISR; Assembly Code: 31; Assembly Description: buitenwandopeningen; Description: raamsparing; Model: LOD200; OmniClass Number: 23.30.20.17.11; OmniClass Title: Fixed Windows; SmartRevit_Versie: 1.0; Type Mark: 1232; Type Name: raamsparing_K_41; Analytical Properties(Type) - Define Thermal Properties by: Schematic Type; Analytic Construction: <None>
Basic Wall:21_DAT_metselwerk_100:5537479 | 00 Begane grond | 21.12 Uniformat (Uniformat) | 100 | 2125 | 840 | raamsparing_K_41 | 2 | Windows |  |  |  |  |  | 31 | buitenwandopeningen | raamsparing | Windows | NLRS_30_WI_WB_raamsparing_type_generiek_ISR | NLRS_30_WI_WB_raamsparing_type_generiek_ISR: raamsparing_K_41 | raamsparing_K_41 | 5542498 |  |  |  |  |  |  | 2.82275 |  | Bouwkundig | 2. nieuwbouw | Constraints - Level: 0; Sill Height: 525 mm; Dimensions - NLRS_C_breedte: 840 mm; NLRS_C_hoogte: 2125 mm; Identity Data - Mark: 4021; Pset_Window - Omschrijving: raamsparing; NL-sfb-Codering: 31; Other - berekende_gevelsparing_BW_offset: 1562.5 mm; gevelsparing_breedte: 840 mm; gevelsparing_hoogte: 2125 mm; Head Height: 2650 mm; Host Id: 5536773; Other(Type) - Category: Windows; Family Name: NLRS_30_WI_WB_raamsparing_type_generiek_ISR; Construction(Type) - gevelsparing_breedteverschil: 0 mm; gevelsparing_hoogteverschil: 0 mm; lossing: 0 mm; gevelsparing_borstweringverschil: 500 mm; Dimensions(Type) - Rough Height: 0 mm; Rough Width: 0 mm; Height: 2125 mm; Width: 840 mm; Graphics(Type) - clash_object_actief: no; Identity Data(Type) - Workset: Family : Windows : NLRS_30_WI_WB_raamsparing_type_generiek_ISR; Assembly Code: 31; Assembly Description: buitenwandopeningen; Description: raamsparing; Model: LOD200; OmniClass Number: 23.30.20.17.11; OmniClass Title: Fixed Windows; SmartRevit_Versie: 1.0; Type Mark: 1232; Type Name: raamsparing_K_41; Analytical Properties(Type) - Define Thermal Properties by: Schematic Type; Analytic Construction: <None>
Basic Wall:21_DAT_metselwerk_100:5537479 | 00 Begane grond | 21.12 Uniformat (Uniformat) | 100 | 2125 | 840 | raamsparing_K_41 | 2 | Windows |  |  |  |  |  | 31 | buitenwandopeningen | raamsparing | Windows | NLRS_30_WI_WB_raamsparing_type_generiek_ISR | NLRS_30_WI_WB_raamsparing_type_generiek_ISR: raamsparing_K_41 | raamsparing_K_41 | 5542498 |  |  |  |  |  |  | 2.82275 |  | Bouwkundig | 2. nieuwbouw | Constraints - Level: 0; Sill Height: 525 mm; Dimensions - NLRS_C_breedte: 840 mm; NLRS_C_hoogte: 2125 mm; Identity Data - Mark: 4025; Pset_Window - Omschrijving: raamsparing; NL-sfb-Codering: 31; Other - berekende_gevelsparing_BW_offset: 1562.5 mm; gevelsparing_breedte: 840 mm; gevelsparing_hoogte: 2125 mm; Head Height: 2650 mm; Host Id: 5536773; Other(Type) - Category: Windows; Family Name: NLRS_30_WI_WB_raamsparing_type_generiek_ISR; Construction(Type) - gevelsparing_breedteverschil: 0 mm; gevelsparing_hoogteverschil: 0 mm; lossing: 0 mm; gevelsparing_borstweringverschil: 500 mm; Dimensions(Type) - Rough Height: 0 mm; Rough Width: 0 mm; Height: 2125 mm; Width: 840 mm; Graphics(Type) - clash_object_actief: no; Identity Data(Type) - Workset: Family : Windows : NLRS_30_WI_WB_raamsparing_type_generiek_ISR; Assembly Code: 31; Assembly Description: buitenwandopeningen; Description: raamsparing; Model: LOD200; OmniClass Number: 23.30.20.17.11; OmniClass Title: Fixed Windows; SmartRevit_Versie: 1.0; Type Mark: 1232; Type Name: raamsparing_K_41; Analytical Properties(Type) - Define Thermal Properties by: Schematic Type; Analytic Construction: <None>
Basic Wall:21_DAT_isolatie minerale wol_160:5538611 | 00 Begane grond | 21.10 Uniformat (Uniformat) | 464.8 | 2630 | 1635 | K_18 | 2 | Walls | Non-bearing | Kunststof kozijn Gealan Kubus | 31 | Kunststof kozijn Gealan Kubus | 31 | 31 | buitenwandopeningen | Kunststof kozijn Gealan Kubus | Walls | Curtain Wall | Curtain Wall: K_18 | K_18 | 6067594 | 10 | no | yes | 0 | 0 | 2630 | 4.30005 | 1635 | Bouwkundig | 2. nieuwbouw | Non-bearing | 0 | Beginning | 4 | 2 | Vertical | Other - Doorvalveilig 1-zijdig: no; Doorvalveilig 2-zijdig: yes; Text - NLRS_C_merk: K01
3 x Basic Wall:21_DAT_isolatie minerale wol_160:5538611 | 00 Begane grond | 21.10 Uniformat (Uniformat) | 464.8 | 2630 | 2120 | K_02 | 2 | Walls | Non-bearing | Kunststof kozijn Gealan Kubus | 31 | Kunststof kozijn Gealan Kubus | 31 | 31 | buitenwandopeningen | Kunststof kozijn Gealan Kubus | Walls | Curtain Wall | Curtain Wall: K_02 | K_02 | 4792108 | 10 | no | yes | 0 | 0 | 2630 | 5.5756 | 2120 | Bouwkundig | 2. nieuwbouw | Non-bearing | 0 | Beginning | 4 | 2 | Vertical | Other - Doorvalveilig 1-zijdig: no; Doorvalveilig 2-zijdig: yes; Text - NLRS_C_merk: K01
3 x Basic Wall:21_DAT_isolatie minerale wol_160:5538611 | 00 Begane grond | 21.10 Uniformat (Uniformat) | 464.8 | 2610 | 2120 | K_03 | 2 | Walls | Non-bearing | Kunststof kozijn Gealan Linear | 31 | Kunststof kozijn Gealan Linear | 31 | 31 | buitenwandopeningen | Kunststof kozijn Gealan Linear | Walls | Curtain Wall | Curtain Wall: K_03 | K_03 | 4793066 | 30 | no | yes | 0 | 0 | 2610 | 5.5332 | 2120 | Bouwkundig | 2. nieuwbouw | Non-bearing | 0 | Beginning | 4 | 2 | Vertical | Other - Doorvalveilig 1-zijdig: no; Doorvalveilig 2-zijdig: yes; Text - NLRS_C_merk: K01
Basic Wall:21_DAT_isolatie minerale wol_160:5538611 | 00 Begane grond | 21.10 Uniformat (Uniformat) | 464.8 | 2762.67 | 23695 | 21_DAT_isolatie hard_74 | 2 | Walls | Non-bearing | Hoogwaardige isolatie met een RC van 4.7 m²K/W | 21.10 |  |  | 21.10 | buitenwanden; niet constructief, algemeen (verzamelniveau) | Hoogwaardige isolatie met een RC van 4.7 m²K/W | Walls | Basic Wall | Basic Wall: 21_DAT_isolatie hard_74 | 21_DAT_isolatie hard_74 | 5724015 | 5 | no | yes | 0 | -882.333 | 2762.67 | 27.835 | 23695 | Bouwkundig | 2. nieuwbouw | Non-bearing |  |  |  |  | Vertical | Dimensions - Volume: 1.94845 m3; Constraints - Base Extension Distance: 0 mm; Top Extension Distance: 0 mm; Location Line: Finish Face: Interior; Top Constraint: Up to level: 1
Basic Wall:21_DAT_metselwerk_100:5538664 | 00 Begane grond | 21.12 Uniformat (Uniformat) | 404.8 | 1100 | 950.358 | NLRS_31_CW_buitenbergingdeuren | 2 | Walls | Non-bearing | kozijn | 31.10 | kozijn | 31.10 | 31.10 | buitenwandopeningen; niet gevuld, algemeen (verzamelniveau) | kozijn | Walls | Curtain Wall | Curtain Wall: NLRS_31_CW_buitenbergingdeuren | NLRS_31_CW_buitenbergingdeuren | 6486346 | 100 | no | yes | 0 | 0 | 1100 | 1.04539 | 950.358 | situatie | 2. nieuwbouw | Non-bearing | 0 | Beginning | 4 | 2 | Vertical | Group: Model Group:Penant Dubbel:5538665
6 x Basic Wall:21_DAT_isolatie minerale wol_160:5538836 | 01 eerste verdieping | 21.10 Uniformat (Uniformat) | 464.8 | 2312.5 | 2290 | 21_DAT_isolatie hard_74 | 2 | Walls | Non-bearing | Hoogwaardige isolatie met een RC van 4.7 m²K/W | 21.10 |  |  | 21.10 | buitenwanden; niet constructief, algemeen (verzamelniveau) | Hoogwaardige isolatie met een RC van 4.7 m²K/W | Walls | Basic Wall | Basic Wall: 21_DAT_isolatie hard_74 | 21_DAT_isolatie hard_74 | 5724015 | 652.5 | no | yes | V1 bk. ruwe vloer | 0 | 2312.5 | 1.35842 | 2290 | Bouwkundig | 2. nieuwbouw | Non-bearing |  |  |  |  | Vertical | Dimensions - Volume: 0.0950897 m3; Constraints - Base Extension Distance: 0 mm; Top Extension Distance: 0 mm; Location Line: Finish Face: Interior
7 x Basic Wall:21_DAT_isolatie minerale wol_160:5538836 | 01 eerste verdieping | 21.10 Uniformat (Uniformat) | 464.8 | 2375 | 1120 | 21_DAT_isolatie hard_74 | 2 | Walls | Non-bearing | Hoogwaardige isolatie met een RC van 4.7 m²K/W | 21.10 |  |  | 21.10 | buitenwanden; niet constructief, algemeen (verzamelniveau) | Hoogwaardige isolatie met een RC van 4.7 m²K/W | Walls | Basic Wall | Basic Wall: 21_DAT_isolatie hard_74 | 21_DAT_isolatie hard_74 | 5724015 | 500 | no | yes | 1 | 0 | 2375 | 0.9616 | 1120 | Bouwkundig | 2. nieuwbouw | Non-bearing |  |  |  |  | Vertical | Dimensions - Volume: 0.067312 m3; Constraints - Base Extension Distance: 0 mm; Top Extension Distance: 0 mm; Location Line: Finish Face: Interior
Basic Wall:21_DAT_metselwerk_100:5538837 | 01 eerste verdieping | 21.12 Uniformat (Uniformat) | 404.8 |  |  | 21_DAT_gasbeton_100 | 2 | Walls | Non-bearing | Gasbeton 100 mm | 21.10 |  |  | 21.10 | buitenwanden; niet constructief, algemeen (verzamelniveau) | Gasbeton 100 mm | Walls | Basic Wall | Basic Wall: 21_DAT_gasbeton_100 | 21_DAT_gasbeton_100 | 4279461 | 0 | no | yes | V1 bk. ruwe vloer | 0 | 515 | 2.42948 | 4799.96 | Bouwkundig | 2. nieuwbouw | Non-bearing |  |  |  |  | Vertical | Dimensions - Volume: 0.242948 m3; Constraints - Base Extension Distance: 0 mm; Top Extension Distance: 0 mm; Location Line: Finish Face: Interior; BaseQuantities - Area: 2.42948 m2
7 x Basic Wall:28_DAT_kalkzandsteen_175mm:5538838 | 01 eerste verdieping | 28.21 Uniformat (Uniformat) | 479.8 | 1930 | 880 | K_28 | 2 | Walls | Non-bearing | Kunststof kozijn Gealan Kubus | 31 | Kunststof kozijn Gealan Kubus | 31 | 31 | buitenwandopeningen | Kunststof kozijn Gealan Kubus | Walls | Curtain Wall | Curtain Wall: K_28 | K_28 | 6068408 | 810 | no | yes | 1 | 0 | 1930 | 1.6984 | 880 | Bouwkundig | 2. nieuwbouw | Non-bearing | 0 | Beginning | 4 | 2 | Vertical | Other - Doorvalveilig 1-zijdig: no; Doorvalveilig 2-zijdig: yes; Text - NLRS_C_merk: K01
6 x Basic Wall:28_DAT_kalkzandsteen_175mm:5538838 | 01 eerste verdieping | 28.21 Uniformat (Uniformat) | 479.8 | 1930 | 2040 | K_24 | 2 | Walls | Non-bearing | Kunststof kozijn Gealan Kubus | 31 | Kunststof kozijn Gealan Kubus | 31 | 31 | buitenwandopeningen | Kunststof kozijn Gealan Kubus | Walls | Curtain Wall | Curtain Wall: K_24 | K_24 | 4801721 | 810 | no | yes | 1 | 0 | 1930 | 3.9372 | 2040 | Bouwkundig | 2. nieuwbouw | Non-bearing | 0 | Beginning | 4 | 2 | Vertical | Other - Doorvalveilig 1-zijdig: no; Doorvalveilig 2-zijdig: yes; Text - NLRS_C_merk: K01
Basic Wall:28_DAT_kalkzandsteen_175mm:5539110 | 00 Begane grond | 28.21 Uniformat (Uniformat) | 479.8 | 2630 | 1635 | K_18 | 2 | Walls | Non-bearing | Kunststof kozijn Gealan Kubus | 31 | Kunststof kozijn Gealan Kubus | 31 | 31 | buitenwandopeningen | Kunststof kozijn Gealan Kubus | Walls | Curtain Wall | Curtain Wall: K_18 | K_18 | 6067594 | 10 | no | yes | 0 | 0 | 2630 | 4.30005 | 1635 | Bouwkundig | 2. nieuwbouw | Non-bearing | 0 | Beginning | 4 | 2 | Vertical | Other - Doorvalveilig 1-zijdig: no; Doorvalveilig 2-zijdig: yes; Text - NLRS_C_merk: K01
Basic Wall:28_DAT_kalkzandsteen_175mm:5539110 | 00 Begane grond | 28.21 Uniformat (Uniformat) | 479.8 | 3310 | 23235 | 28_DAT_kalkzandsteen_175mm | 2 | Walls | Non-bearing | Kalkzandsteen 175mm | 28.21 |  |  | 28.21 | hoofddraagconstructies; wanden en vloeren, wand-/vloerconstructies | Kalkzandsteen 175mm | Walls | Basic Wall | Basic Wall: 28_DAT_kalkzandsteen_175mm | 28_DAT_kalkzandsteen_175mm | 4741545 | 0 | no | yes | V0 bk. ruwe vloer | 0 | 3310 | 6.8 | 23235 | Bouwkundig | 2. nieuwbouw | Non-bearing |  |  |  |  | Vertical | Dimensions - Volume: 1.19 m3; Constraints - Base Extension Distance: 0 mm; Top Extension Distance: 0 mm; Location Line: Wall Centerline; Top Constraint: Up to level: V1 ok. ruwe vloer
2 x Basic Wall:28_DAT_kalkzandsteen_175mm:5539136 | 00 Begane grond | 28.21 Uniformat (Uniformat) | 479.8 | 1930 | 880 | K_16 | 2 | Walls | Non-bearing | Kunststof kozijn Gealan Kubus | 31 | Kunststof kozijn Gealan Kubus | 31 | 31 | buitenwandopeningen | Kunststof kozijn Gealan Kubus | Walls | Curtain Wall | Curtain Wall: K_16 | K_16 | 6074129 | 710 | no | yes | 0 | 0 | 1930 | 1.6984 | 880 | Bouwkundig | 2. nieuwbouw | Non-bearing | 0 | Beginning | 4 | 2 | Vertical | Other - Doorvalveilig 1-zijdig: no; Doorvalveilig 2-zijdig: yes; Text - NLRS_C_merk: K01
2 x Basic Wall:21_DAT_isolatie minerale wol_160:5539137 | 00 Begane grond | 21.10 Uniformat (Uniformat) | 464.8 | 1930 | 880 | K_16 | 2 | Walls | Non-bearing | Kunststof kozijn Gealan Kubus | 31 | Kunststof kozijn Gealan Kubus | 31 | 31 | buitenwandopeningen | Kunststof kozijn Gealan Kubus | Walls | Curtain Wall | Curtain Wall: K_16 | K_16 | 6074129 | 710 | no | yes | 0 | 0 | 1930 | 1.6984 | 880 | Bouwkundig | 2. nieuwbouw | Non-bearing | 0 | Beginning | 4 | 2 | Vertical | Other - Doorvalveilig 1-zijdig: no; Doorvalveilig 2-zijdig: yes; Text - NLRS_C_merk: K01
Basic Wall:21_DAT_isolatie minerale wol_160:5539137 | 00 Begane grond | 21.10 Uniformat (Uniformat) | 464.8 | 2750 | 1080 | 21_DAT_isolatie hard_74 | 2 | Walls | Non-bearing | Hoogwaardige isolatie met een RC van 4.7 m²K/W | 21.10 |  |  | 21.10 | buitenwanden; niet constructief, algemeen (verzamelniveau) | Hoogwaardige isolatie met een RC van 4.7 m²K/W | Walls | Basic Wall | Basic Wall: 21_DAT_isolatie hard_74 | 21_DAT_isolatie hard_74 | 5724015 | 520 | no | yes | 0 | 0 | 2750 | 1.2716 | 1080 | Bouwkundig | 2. nieuwbouw | Non-bearing |  |  |  |  | Vertical | Dimensions - Volume: 0.089012 m3; Constraints - Base Extension Distance: 0 mm; Top Extension Distance: 0 mm; Location Line: Finish Face: Interior
Basic Wall:21_DAT_isolatie minerale wol_160:5539137 | 00 Begane grond | 21.10 Uniformat (Uniformat) | 464.8 | 2750 | 1120 | 21_DAT_isolatie hard_74 | 2 | Walls | Non-bearing | Hoogwaardige isolatie met een RC van 4.7 m²K/W | 21.10 |  |  | 21.10 | buitenwanden; niet constructief, algemeen (verzamelniveau) | Hoogwaardige isolatie met een RC van 4.7 m²K/W | Walls | Basic Wall | Basic Wall: 21_DAT_isolatie hard_74 | 21_DAT_isolatie hard_74 | 5724015 | 520 | no | yes | 0 | 0 | 2750 | 1.3816 | 1120 | Bouwkundig | 2. nieuwbouw | Non-bearing |  |  |  |  | Vertical | Dimensions - Volume: 0.096712 m3; Constraints - Base Extension Distance: 0 mm; Top Extension Distance: 0 mm; Location Line: Finish Face: Interior
Basic Wall:28_DAT_kalkzandsteen_175mm:5539251 | 01 eerste verdieping | 28.21 Uniformat (Uniformat) | 479.8 | 1930 | 790 | K_30 | 2 | Walls | Non-bearing | Kunststof kozijn Gealan Kubus | 31 | Kunststof kozijn Gealan Kubus | 31 | 31 | buitenwandopeningen | Kunststof kozijn Gealan Kubus | Walls | Curtain Wall | Curtain Wall: K_30 | K_30 | 4942327 | 810 | no | yes | 1 | 0 | 1930 | 1.5247 | 790 | Bouwkundig | 2. nieuwbouw | Non-bearing | 0 | Beginning | 4 | 2 | Vertical | Other - Doorvalveilig 1-zijdig: no; Doorvalveilig 2-zijdig: yes; Text - NLRS_C_merk: K01
9 x Basic Wall:28_DAT_kalkzandsteen_175mm:5539251 | 01 eerste verdieping | 28.21 Uniformat (Uniformat) | 479.8 | 1930 | 790 | K_29 | 2 | Walls | Non-bearing | Kunststof kozijn Gealan Kubus | 31 | Kunststof kozijn Gealan Kubus | 31 | 31 | buitenwandopeningen | Kunststof kozijn Gealan Kubus | Walls | Curtain Wall | Curtain Wall: K_29 | K_29 | 4860879 | 810 | no | yes | 1 | 0 | 1930 | 1.5247 | 790 | Bouwkundig | 2. nieuwbouw | Non-bearing | 0 | Beginning | 4 | 2 | Vertical | Other - Doorvalveilig 1-zijdig: no; Doorvalveilig 2-zijdig: yes; Text - NLRS_C_merk: K01
6 x Basic Wall:28_DAT_kalkzandsteen_175mm:5539251 | 01 eerste verdieping | 28.21 Uniformat (Uniformat) | 479.8 | 1930 | 2250 | K_22 | 2 | Walls | Non-bearing | Kunststof kozijn Gealan Kubus | 31 | Kunststof kozijn Gealan Kubus | 31 | 31 | buitenwandopeningen | Kunststof kozijn Gealan Kubus | Walls | Curtain Wall | Curtain Wall: K_22 | K_22 | 4917986 | 810 | no | yes | 1 | 0 | 1930 | 4.3425 | 2250 | Bouwkundig | 2. nieuwbouw | Non-bearing | 0 | Beginning | 4 | 2 | Vertical | Other - Doorvalveilig 1-zijdig: no; Doorvalveilig 2-zijdig: yes; Text - NLRS_C_merk: K01
Basic Wall:28_DAT_kalkzandsteen_175mm:5539251 | 01 eerste verdieping | 28.21 Uniformat (Uniformat) | 479.8 | 2760 | 3450 | K_27 | 2 | Walls | Non-bearing | Kunststof kozijn Gealan Kubus | 31 | Kunststof kozijn Gealan Kubus | 31 | 31 | buitenwandopeningen | Kunststof kozijn Gealan Kubus | Walls | Curtain Wall | Curtain Wall: K_27 | K_27 | 4952631 | -20 | no | yes | 1 | 0 | 2760 | 9.522 | 3450 | Bouwkundig | 2. nieuwbouw | Non-bearing | 0 | Beginning | 4 | 2 | Vertical | Other - Doorvalveilig 1-zijdig: no; Doorvalveilig 2-zijdig: yes; Text - NLRS_C_merk: K01
8 x Basic Wall:28_DAT_kalkzandsteen_175mm:5539251 | 01 eerste verdieping | 28.21 Uniformat (Uniformat) | 479.8 | 500 | 790 | 21_DAT_Hekwerk 175 | 2 | Walls | Non-bearing | Samengesteld rekwerkBuitenplaat WBP 10mmHouten stijl- en regelwerk 38x140Minirale wolDampremmendefolieGipsplaat 12.5mmGipsvezelplaat 12,5mm | 21.10 |  |  | 21.10 | buitenwanden; niet constructief, algemeen (verzamelniveau) | Samengesteld rekwerkBuitenplaat WBP 10mmHouten stijl- en regelwerk 38x140Minirale wolDampremmendefolieGipsplaat 12.5mmGipsvezelplaat 12,5mm | Walls | Basic Wall | Basic Wall: 21_DAT_Hekwerk 175 | 21_DAT_Hekwerk 175 | 5435600 | 2830 | no | yes | V1 bk. ruwe vloer | 0.0000289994 | 500 | 0.395 | 790 | Bouwkundig | 2. nieuwbouw | Non-bearing |  |  |  |  | Vertical | Dimensions - Volume: 0.069125 m3; Constraints - Base Extension Distance: 0 mm; Top Extension Distance: 0 mm; Location Line: Wall Centerline; Top Constraint: Up to level: V2 ok. ruwe vloer; Pset_wanden - sets with these values: 2
7 x Basic Wall:28_DAT_kalkzandsteen_175mm:5539251 | 01 eerste verdieping | 28.21 Uniformat (Uniformat) | 479.8 | 500 | 2250 | 21_DAT_Hekwerk 175 | 2 | Walls | Non-bearing | Samengesteld rekwerkBuitenplaat WBP 10mmHouten stijl- en regelwerk 38x140Minirale wolDampremmendefolieGipsplaat 12.5mmGipsvezelplaat 12,5mm | 21.10 |  |  | 21.10 | buitenwanden; niet constructief, algemeen (verzamelniveau) | Samengesteld rekwerkBuitenplaat WBP 10mmHouten stijl- en regelwerk 38x140Minirale wolDampremmendefolieGipsplaat 12.5mmGipsvezelplaat 12,5mm | Walls | Basic Wall | Basic Wall: 21_DAT_Hekwerk 175 | 21_DAT_Hekwerk 175 | 5435600 | 2830 | no | yes | V1 bk. ruwe vloer | 0.0000289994 | 500 | 1.125 | 2250 | Bouwkundig | 2. nieuwbouw | Non-bearing |  |  |  |  | Vertical | Dimensions - Volume: 0.196875 m3; Constraints - Base Extension Distance: 0 mm; Top Extension Distance: 0 mm; Location Line: Wall Centerline; Top Constraint: Up to level: V2 ok. ruwe vloer; Pset_wanden - sets with these values: 2
Basic Wall:28_DAT_kalkzandsteen_175mm:5539251 | 01 eerste verdieping | 28.21 Uniformat (Uniformat) | 479.8 | 500 | 2250 | 21_DAT_Hekwerk 175 | 2 | Walls | Non-bearing | Samengesteld rekwerkBuitenplaat WBP 10mmHouten stijl- en regelwerk 38x140Minirale wolDampremmendefolieGipsplaat 12.5mmGipsvezelplaat 12,5mm | 21.10 |  |  | 21.10 | buitenwanden; niet constructief, algemeen (verzamelniveau) | Samengesteld rekwerkBuitenplaat WBP 10mmHouten stijl- en regelwerk 38x140Minirale wolDampremmendefolieGipsplaat 12.5mmGipsvezelplaat 12,5mm | Walls | Basic Wall | Basic Wall: 21_DAT_Hekwerk 175 | 21_DAT_Hekwerk 175 | 5435600 | 2830 | no | yes | V1 bk. ruwe vloer | 0.0000289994 | 500 | 1.125 | 2250 | Bouwkundig | 2. nieuwbouw | Non-bearing |  |  |  |  | Vertical | Dimensions - Volume: 0.196797 m3; Constraints - Base Extension Distance: 0 mm; Top Extension Distance: 0 mm; Location Line: Wall Centerline; Top Constraint: Up to level: V2 ok. ruwe vloer; Pset_wanden - sets with these values: 2
Basic Wall:28_DAT_kalkzandsteen_175mm:5539251 | 01 eerste verdieping | 28.21 Uniformat (Uniformat) | 479.8 | 2430 | 60 | 21_DAT_Hekwerk 175 | 2 | Walls | Non-bearing | Samengesteld rekwerkBuitenplaat WBP 10mmHouten stijl- en regelwerk 38x140Minirale wolDampremmendefolieGipsplaat 12.5mmGipsvezelplaat 12,5mm | 21.10 |  |  | 21.10 | buitenwanden; niet constructief, algemeen (verzamelniveau) | Samengesteld rekwerkBuitenplaat WBP 10mmHouten stijl- en regelwerk 38x140Minirale wolDampremmendefolieGipsplaat 12.5mmGipsvezelplaat 12,5mm | Walls | Basic Wall | Basic Wall: 21_DAT_Hekwerk 175 | 21_DAT_Hekwerk 175 | 5435600 | 810 | no | yes | 1 | 0 | 2430 | 0.1458 | 60 | Bouwkundig | 2. nieuwbouw | Non-bearing |  |  |  |  | Vertical | Dimensions - Volume: 0.025515 m3; Constraints - Base Extension Distance: 0 mm; Top Extension Distance: 0 mm; Location Line: Wall Centerline; Top Constraint: Up to level: V2 ok. ruwe vloer; Pset_wanden - sets with these values: 2
Basic Wall:28_DAT_kalkzandsteen_175mm:5539251 | 01 eerste verdieping | 28.21 Uniformat (Uniformat) | 479.8 | 3240 | 60 | 21_DAT_Hekwerk 175 | 2 | Walls | Non-bearing | Samengesteld rekwerkBuitenplaat WBP 10mmHouten stijl- en regelwerk 38x140Minirale wolDampremmendefolieGipsplaat 12.5mmGipsvezelplaat 12,5mm | 21.10 |  |  | 21.10 | buitenwanden; niet constructief, algemeen (verzamelniveau) | Samengesteld rekwerkBuitenplaat WBP 10mmHouten stijl- en regelwerk 38x140Minirale wolDampremmendefolieGipsplaat 12.5mmGipsvezelplaat 12,5mm | Walls | Basic Wall | Basic Wall: 21_DAT_Hekwerk 175 | 21_DAT_Hekwerk 175 | 5435600 | 0 | no | yes | 1 | 0 | 3240 | 0.1944 | 60 | Bouwkundig | 2. nieuwbouw | Non-bearing |  |  |  |  | Vertical | Dimensions - Volume: 0.03402 m3; Constraints - Base Extension Distance: 0 mm; Top Extension Distance: 0 mm; Location Line: Wall Centerline; Top Constraint: Up to level: V2 ok. ruwe vloer; Pset_wanden - sets with these values: 2
8 x Basic Wall:28_DAT_kalkzandsteen_175mm:5539251 | 01 eerste verdieping | 28.21 Uniformat (Uniformat) | 479.8 | 3240 | 280 | 22_DAT_binnenwand_25 | 2 | Walls | Non-bearing | Lichte scheidingswand 100mm | 22.13 |  |  | 22.13 | binnenwanden; niet constructief, systeemwanden; vast | Lichte scheidingswand 100mm | Walls | Basic Wall | Basic Wall: 22_DAT_binnenwand_25 | 22_DAT_binnenwand_25 | 4977124 | 0 | no | yes | 1 | 0 | 3240 | 0.9072 | 280 | Bouwkundig | 2. nieuwbouw | Non-bearing |  |  |  |  | Vertical | Dimensions - Volume: 0.02268 m3; Constraints - Base Extension Distance: 0 mm; Top Extension Distance: 0 mm; Location Line: Wall Centerline; Top Constraint: Up to level: V2 ok. ruwe vloer
14 x Basic Wall:28_DAT_kalkzandsteen_175mm:5539251 | 01 eerste verdieping | 28.21 Uniformat (Uniformat) | 479.8 | 2430 | 60 | 21_DAT_Hekwerk 150 | 2 | Walls | Non-bearing | Samengesteld rekwerkBuitenplaat WBP 10mmHouten stijl- en regelwerk 38x140Minirale wolDampremmendefolieGipsplaat 12.5mmGipsvezelplaat 12,5mm | 21.10 |  |  | 21.10 | buitenwanden; niet constructief, algemeen (verzamelniveau) | Samengesteld rekwerkBuitenplaat WBP 10mmHouten stijl- en regelwerk 38x140Minirale wolDampremmendefolieGipsplaat 12.5mmGipsvezelplaat 12,5mm | Walls | Basic Wall | Basic Wall: 21_DAT_Hekwerk 150 | 21_DAT_Hekwerk 150 | 6890802 | 810 | no | yes | 1 | 0 | 2430 | 0.1458 | 60 | Bouwkundig | 2. nieuwbouw | Non-bearing |  |  |  |  | Vertical | Dimensions - Volume: 0.02187 m3; Constraints - Base Extension Distance: 0 mm; Top Extension Distance: 0 mm; Location Line: Wall Centerline; Top Constraint: Up to level: V2 ok. ruwe vloer; Pset_wanden - sets with these values: 2
2 x Basic Wall:28_DAT_kalkzandsteen_175mm:5539251 | 01 eerste verdieping | 28.21 Uniformat (Uniformat) | 479.8 | 2430 | 60 | 21_DAT_Hekwerk 150 | 2 | Walls | Non-bearing | Samengesteld rekwerkBuitenplaat WBP 10mmHouten stijl- en regelwerk 38x140Minirale wolDampremmendefolieGipsplaat 12.5mmGipsvezelplaat 12,5mm | 21.10 |  |  | 21.10 | buitenwanden; niet constructief, algemeen (verzamelniveau) | Samengesteld rekwerkBuitenplaat WBP 10mmHouten stijl- en regelwerk 38x140Minirale wolDampremmendefolieGipsplaat 12.5mmGipsvezelplaat 12,5mm | Walls | Basic Wall | Basic Wall: 21_DAT_Hekwerk 150 | 21_DAT_Hekwerk 150 | 6890802 | 810 | no | yes | 1 | 0 | 2430 | 0.133732 | 60 | Bouwkundig | 2. nieuwbouw | Non-bearing |  |  |  |  | Vertical | Dimensions - Volume: 0.0200598 m3; Constraints - Base Extension Distance: 0 mm; Top Extension Distance: 0 mm; Location Line: Wall Centerline; Top Constraint: Up to level: V2 ok. ruwe vloer; Pset_wanden - sets with these values: 2
Basic Wall:28_DAT_kalkzandsteen_175mm:5539251 | 01 eerste verdieping | 28.21 Uniformat (Uniformat) | 479.8 | 3240 | 280 | 22_DAT_binnenwand_25 | 2 | Walls | Non-bearing | Lichte scheidingswand 100mm | 22.13 |  |  | 22.13 | binnenwanden; niet constructief, systeemwanden; vast | Lichte scheidingswand 100mm | Walls | Basic Wall | Basic Wall: 22_DAT_binnenwand_25 | 22_DAT_binnenwand_25 | 4977124 | 0 | no | yes | 1 | 0 | 3240 | 0.904074 | 280 | Bouwkundig | 2. nieuwbouw | Non-bearing |  |  |  |  | Vertical | Dimensions - Volume: 0.0226018 m3; Constraints - Base Extension Distance: 0 mm; Top Extension Distance: 0 mm; Location Line: Wall Centerline; Top Constraint: Up to level: V2 ok. ruwe vloer
Basic Wall:28_DAT_kalkzandsteen_175mm:5539251 | 01 eerste verdieping | 28.21 Uniformat (Uniformat) | 479.8 | 2760 | 1495 | K_26 | 2 | Walls | Non-bearing | Kunststof kozijn Gealan Kubus | 31 | Kunststof kozijn Gealan Kubus | 31 | 31 | buitenwandopeningen | Kunststof kozijn Gealan Kubus | Walls | Curtain Wall | Curtain Wall: K_26 | K_26 | 4951884 | -20 | no | yes | 1 | 0 | 2760 | 4.1262 | 1495 | Bouwkundig | 2. nieuwbouw | Non-bearing | 0 | Beginning | 4 | 2 | Vertical | Other - Doorvalveilig 1-zijdig: no; Doorvalveilig 2-zijdig: yes; Text - NLRS_C_merk: K01
2 x Basic Wall:28_DAT_kalkzandsteen_175mm:5539251 | 01 eerste verdieping | 28.21 Uniformat (Uniformat) | 479.8 | 3230 | 60 | 21_DAT_Hekwerk 175 | 2 | Walls | Non-bearing | Samengesteld rekwerkBuitenplaat WBP 10mmHouten stijl- en regelwerk 38x140Minirale wolDampremmendefolieGipsplaat 12.5mmGipsvezelplaat 12,5mm | 21.10 |  |  | 21.10 | buitenwanden; niet constructief, algemeen (verzamelniveau) | Samengesteld rekwerkBuitenplaat WBP 10mmHouten stijl- en regelwerk 38x140Minirale wolDampremmendefolieGipsplaat 12.5mmGipsvezelplaat 12,5mm | Walls | Basic Wall | Basic Wall: 21_DAT_Hekwerk 175 | 21_DAT_Hekwerk 175 | 5435600 | 10 | no | yes | 1 | 0.0000289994 | 3230 | 0.1938 | 60 | Bouwkundig | 2. nieuwbouw | Non-bearing |  |  |  |  | Vertical | Dimensions - Volume: 0.033915 m3; Constraints - Base Extension Distance: 0 mm; Top Extension Distance: 0 mm; Location Line: Wall Centerline; Top Constraint: Up to level: V2 ok. ruwe vloer; Pset_wanden - sets with these values: 2
Basic Wall:28_DAT_kalkzandsteen_175mm:5539251 | 01 eerste verdieping | 28.21 Uniformat (Uniformat) | 479.8 | 500 | 1595 | 21_DAT_Hekwerk 175 | 2 | Walls | Non-bearing | Samengesteld rekwerkBuitenplaat WBP 10mmHouten stijl- en regelwerk 38x140Minirale wolDampremmendefolieGipsplaat 12.5mmGipsvezelplaat 12,5mm | 21.10 |  |  | 21.10 | buitenwanden; niet constructief, algemeen (verzamelniveau) | Samengesteld rekwerkBuitenplaat WBP 10mmHouten stijl- en regelwerk 38x140Minirale wolDampremmendefolieGipsplaat 12.5mmGipsvezelplaat 12,5mm | Walls | Basic Wall | Basic Wall: 21_DAT_Hekwerk 175 | 21_DAT_Hekwerk 175 | 5435600 | 2830 | no | yes | V1 bk. ruwe vloer | 0.0000289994 | 500 | 0.7975 | 1595 | Bouwkundig | 2. nieuwbouw | Non-bearing |  |  |  |  | Vertical | Dimensions - Volume: 0.139563 m3; Constraints - Base Extension Distance: 0 mm; Top Extension Distance: 0 mm; Location Line: Wall Centerline; Top Constraint: Up to level: V2 ok. ruwe vloer; Pset_wanden - sets with these values: 2
Basic Wall:28_DAT_kalkzandsteen_175mm:5539251 | 01 eerste verdieping | 28.21 Uniformat (Uniformat) | 479.8 | 3240 | 160 | 22_DAT_binnenwand_25 | 2 | Walls | Non-bearing | Lichte scheidingswand 100mm | 22.13 |  |  | 22.13 | binnenwanden; niet constructief, systeemwanden; vast | Lichte scheidingswand 100mm | Walls | Basic Wall | Basic Wall: 22_DAT_binnenwand_25 | 22_DAT_binnenwand_25 | 4977124 | 0 | no | yes | 1 | 0 | 3240 | 0.5184 | 160 | Bouwkundig | 2. nieuwbouw | Non-bearing |  |  |  |  | Vertical | Dimensions - Volume: 0.01296 m3; Constraints - Base Extension Distance: 0 mm; Top Extension Distance: 0 mm; Location Line: Wall Centerline; Top Constraint: Up to level: V2 ok. ruwe vloer
2 x Basic Wall:28_DAT_kalkzandsteen_175mm:5539251 | 01 eerste verdieping | 28.21 Uniformat (Uniformat) | 479.8 | 1930 | 2250 | K_32 | 2 | Walls | Non-bearing | Kunststof kozijn Gealan Kubus | 31 | Kunststof kozijn Gealan Kubus | 31 | 31 | buitenwandopeningen | Kunststof kozijn Gealan Kubus | Walls | Curtain Wall | Curtain Wall: K_32 | K_32 | 6474551 | 810 | no | yes | 1 | 0 | 1930 | 4.3425 | 2250 | Bouwkundig | 2. nieuwbouw | Non-bearing | 0 | Beginning | 4 | 2 | Vertical | Other - Doorvalveilig 1-zijdig: no; Doorvalveilig 2-zijdig: yes; Text - NLRS_C_merk: K01
Basic Wall:28_DAT_kalkzandsteen_175mm:5539251 | 01 eerste verdieping | 28.21 Uniformat (Uniformat) | 479.8 | 500 | 3450 | 21_DAT_Hekwerk 175 | 2 | Walls | Non-bearing | Samengesteld rekwerkBuitenplaat WBP 10mmHouten stijl- en regelwerk 38x140Minirale wolDampremmendefolieGipsplaat 12.5mmGipsvezelplaat 12,5mm | 21.10 |  |  | 21.10 | buitenwanden; niet constructief, algemeen (verzamelniveau) | Samengesteld rekwerkBuitenplaat WBP 10mmHouten stijl- en regelwerk 38x140Minirale wolDampremmendefolieGipsplaat 12.5mmGipsvezelplaat 12,5mm | Walls | Basic Wall | Basic Wall: 21_DAT_Hekwerk 175 | 21_DAT_Hekwerk 175 | 5435600 | 2830 | no | yes | V1 bk. ruwe vloer | 0.0000289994 | 500 | 1.725 | 3450 | Bouwkundig | 2. nieuwbouw | Non-bearing |  |  |  |  | Vertical | Dimensions - Volume: 0.301875 m3; Constraints - Base Extension Distance: 0 mm; Top Extension Distance: 0 mm; Location Line: Wall Centerline; Top Constraint: Up to level: V2 ok. ruwe vloer; Pset_wanden - sets with these values: 2
7 x Basic Wall:28_DAT_kalkzandsteen_175mm:5539252 | 01 eerste verdieping | 28.21 Uniformat (Uniformat) | 479.8 | 1930 | 2250 | K_22 | 2 | Walls | Non-bearing | Kunststof kozijn Gealan Kubus | 31 | Kunststof kozijn Gealan Kubus | 31 | 31 | buitenwandopeningen | Kunststof kozijn Gealan Kubus | Walls | Curtain Wall | Curtain Wall: K_22 | K_22 | 4917986 | 810 | no | yes | 1 | 0 | 1930 | 4.3425 | 2250 | Bouwkundig | 2. nieuwbouw | Non-bearing | 0 | Beginning | 4 | 2 | Vertical | Other - Doorvalveilig 1-zijdig: no; Doorvalveilig 2-zijdig: yes; Text - NLRS_C_merk: K01
9 x Basic Wall:28_DAT_kalkzandsteen_175mm:5539252 | 01 eerste verdieping | 28.21 Uniformat (Uniformat) | 479.8 | 1930 | 790 | K_29 | 2 | Walls | Non-bearing | Kunststof kozijn Gealan Kubus | 31 | Kunststof kozijn Gealan Kubus | 31 | 31 | buitenwandopeningen | Kunststof kozijn Gealan Kubus | Walls | Curtain Wall | Curtain Wall: K_29 | K_29 | 4860879 | 810 | no | yes | 1 | 0 | 1930 | 1.5247 | 790 | Bouwkundig | 2. nieuwbouw | Non-bearing | 0 | Beginning | 4 | 2 | Vertical | Other - Doorvalveilig 1-zijdig: no; Doorvalveilig 2-zijdig: yes; Text - NLRS_C_merk: K01
9 x Basic Wall:28_DAT_kalkzandsteen_175mm:5539252 | 01 eerste verdieping | 28.21 Uniformat (Uniformat) | 479.8 | 500 | 790 | 21_DAT_Hekwerk 175 | 2 | Walls | Non-bearing | Samengesteld rekwerkBuitenplaat WBP 10mmHouten stijl- en regelwerk 38x140Minirale wolDampremmendefolieGipsplaat 12.5mmGipsvezelplaat 12,5mm | 21.10 |  |  | 21.10 | buitenwanden; niet constructief, algemeen (verzamelniveau) | Samengesteld rekwerkBuitenplaat WBP 10mmHouten stijl- en regelwerk 38x140Minirale wolDampremmendefolieGipsplaat 12.5mmGipsvezelplaat 12,5mm | Walls | Basic Wall | Basic Wall: 21_DAT_Hekwerk 175 | 21_DAT_Hekwerk 175 | 5435600 | 2830 | no | yes | V1 bk. ruwe vloer | 0.0000289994 | 500 | 0.395 | 790 | Bouwkundig | 2. nieuwbouw | Non-bearing |  |  |  |  | Vertical | Dimensions - Volume: 0.069125 m3; Constraints - Base Extension Distance: 0 mm; Top Extension Distance: 0 mm; Location Line: Wall Centerline; Top Constraint: Up to level: V2 ok. ruwe vloer; Pset_wanden - sets with these values: 2
7 x Basic Wall:28_DAT_kalkzandsteen_175mm:5539252 | 01 eerste verdieping | 28.21 Uniformat (Uniformat) | 479.8 | 500 | 2250 | 21_DAT_Hekwerk 175 | 2 | Walls | Non-bearing | Samengesteld rekwerkBuitenplaat WBP 10mmHouten stijl- en regelwerk 38x140Minirale wolDampremmendefolieGipsplaat 12.5mmGipsvezelplaat 12,5mm | 21.10 |  |  | 21.10 | buitenwanden; niet constructief, algemeen (verzamelniveau) | Samengesteld rekwerkBuitenplaat WBP 10mmHouten stijl- en regelwerk 38x140Minirale wolDampremmendefolieGipsplaat 12.5mmGipsvezelplaat 12,5mm | Walls | Basic Wall | Basic Wall: 21_DAT_Hekwerk 175 | 21_DAT_Hekwerk 175 | 5435600 | 2830 | no | yes | V1 bk. ruwe vloer | 0.0000289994 | 500 | 1.125 | 2250 | Bouwkundig | 2. nieuwbouw | Non-bearing |  |  |  |  | Vertical | Dimensions - Volume: 0.196875 m3; Constraints - Base Extension Distance: 0 mm; Top Extension Distance: 0 mm; Location Line: Wall Centerline; Top Constraint: Up to level: V2 ok. ruwe vloer; Pset_wanden - sets with these values: 2
Basic Wall:28_DAT_kalkzandsteen_175mm:5539252 | 01 eerste verdieping | 28.21 Uniformat (Uniformat) | 479.8 | 2430 | 45 | 21_DAT_Hekwerk 175 | 2 | Walls | Non-bearing | Samengesteld rekwerkBuitenplaat WBP 10mmHouten stijl- en regelwerk 38x140Minirale wolDampremmendefolieGipsplaat 12.5mmGipsvezelplaat 12,5mm | 21.10 |  |  | 21.10 | buitenwanden; niet constructief, algemeen (verzamelniveau) | Samengesteld rekwerkBuitenplaat WBP 10mmHouten stijl- en regelwerk 38x140Minirale wolDampremmendefolieGipsplaat 12.5mmGipsvezelplaat 12,5mm | Walls | Basic Wall | Basic Wall: 21_DAT_Hekwerk 175 | 21_DAT_Hekwerk 175 | 5435600 | 810 | no | yes | 1 | 0.0000289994 | 2430 | 0.10935 | 45 | Bouwkundig | 2. nieuwbouw | Non-bearing |  |  |  |  | Vertical | Dimensions - Volume: 0.0191363 m3; Constraints - Base Extension Distance: 0 mm; Top Extension Distance: 0 mm; Location Line: Wall Centerline; Top Constraint: Up to level: V2 ok. ruwe vloer; Pset_wanden - sets with these values: 2
6 x Basic Wall:28_DAT_kalkzandsteen_175mm:5539252 | 01 eerste verdieping | 28.21 Uniformat (Uniformat) | 479.8 | 3240 | 280 | 22_DAT_binnenwand_25 | 2 | Walls | Non-bearing | Lichte scheidingswand 100mm | 22.13 |  |  | 22.13 | binnenwanden; niet constructief, systeemwanden; vast | Lichte scheidingswand 100mm | Walls | Basic Wall | Basic Wall: 22_DAT_binnenwand_25 | 22_DAT_binnenwand_25 | 4977124 | 0 | no | yes | 1 | 0 | 3240 | 0.9072 | 280 | Bouwkundig | 2. nieuwbouw | Non-bearing |  |  |  |  | Vertical | Dimensions - Volume: 0.02268 m3; Constraints - Base Extension Distance: 0 mm; Top Extension Distance: 0 mm; Location Line: Wall Centerline; Top Constraint: Up to level: V2 ok. ruwe vloer
8 x Basic Wall:28_DAT_kalkzandsteen_175mm:5539252 | 01 eerste verdieping | 28.21 Uniformat (Uniformat) | 479.8 | 2430 | 60 | 21_DAT_Hekwerk 150 | 2 | Walls | Non-bearing | Samengesteld rekwerkBuitenplaat WBP 10mmHouten stijl- en regelwerk 38x140Minirale wolDampremmendefolieGipsplaat 12.5mmGipsvezelplaat 12,5mm | 21.10 |  |  | 21.10 | buitenwanden; niet constructief, algemeen (verzamelniveau) | Samengesteld rekwerkBuitenplaat WBP 10mmHouten stijl- en regelwerk 38x140Minirale wolDampremmendefolieGipsplaat 12.5mmGipsvezelplaat 12,5mm | Walls | Basic Wall | Basic Wall: 21_DAT_Hekwerk 150 | 21_DAT_Hekwerk 150 | 6890802 | 810 | no | yes | 1 | 0 | 2430 | 0.1458 | 60 | Bouwkundig | 2. nieuwbouw | Non-bearing |  |  |  |  | Vertical | Dimensions - Volume: 0.02187 m3; Constraints - Base Extension Distance: 0 mm; Top Extension Distance: 0 mm; Location Line: Wall Centerline; Top Constraint: Up to level: V2 ok. ruwe vloer; Pset_wanden - sets with these values: 2
Basic Wall:21_DAT_Hekwerk 175:5539255 | 01 eerste verdieping | 21.10 Uniformat (Uniformat) | 479.8 | 1930 | 2064 | K_23 | 2 | Walls | Non-bearing | Kunststof kozijn Gealan Kubus | 31 | Kunststof kozijn Gealan Kubus | 31 | 31 | buitenwandopeningen | Kunststof kozijn Gealan Kubus | Walls | Curtain Wall | Curtain Wall: K_23 | K_23 | 4942408 | 810 | no | yes | 1 | 0 | 1930 | 3.98352 | 2064 | Bouwkundig | 2. nieuwbouw | Non-bearing | 0 | Beginning | 4 | 2 | Vertical | Other - Doorvalveilig 1-zijdig: no; Doorvalveilig 2-zijdig: yes; Text - NLRS_C_merk: K01
Basic Wall:21_DAT_Hekwerk 175:5539257 | 01 eerste verdieping | 21.10 Uniformat (Uniformat) | 479.8 | 1930 | 790 | K_30 | 2 | Walls | Non-bearing | Kunststof kozijn Gealan Kubus | 31 | Kunststof kozijn Gealan Kubus | 31 | 31 | buitenwandopeningen | Kunststof kozijn Gealan Kubus | Walls | Curtain Wall | Curtain Wall: K_30 | K_30 | 4942327 | 810 | no | yes | 1 | 0 | 1930 | 1.5247 | 790 | Bouwkundig | 2. nieuwbouw | Non-bearing | 0 | Beginning | 4 | 2 | Vertical | Other - Doorvalveilig 1-zijdig: no; Doorvalveilig 2-zijdig: yes; Text - NLRS_C_merk: K01
Basic Wall:28_DAT_kalkzandsteen_175mm:5539258 | 01 eerste verdieping | 28.21 Uniformat (Uniformat) | 479.8 | 1930 | 2064 | K_23 | 2 | Walls | Non-bearing | Kunststof kozijn Gealan Kubus | 31 | Kunststof kozijn Gealan Kubus | 31 | 31 | buitenwandopeningen | Kunststof kozijn Gealan Kubus | Walls | Curtain Wall | Curtain Wall: K_23 | K_23 | 4942408 | 810 | no | yes | 1 | 0 | 1930 | 3.98352 | 2064 | Bouwkundig | 2. nieuwbouw | Non-bearing | 0 | Beginning | 4 | 2 | Vertical | Other - Doorvalveilig 1-zijdig: no; Doorvalveilig 2-zijdig: yes; Text - NLRS_C_merk: K01
Basic Wall:28_DAT_kalkzandsteen_175mm:5539258 | 01 eerste verdieping | 28.21 Uniformat (Uniformat) | 479.8 | 509.983 | 2104 | 21_DAT_Hekwerk 175 | 2 | Walls | Non-bearing | Samengesteld rekwerkBuitenplaat WBP 10mmHouten stijl- en regelwerk 38x140Minirale wolDampremmendefolieGipsplaat 12.5mmGipsvezelplaat 12,5mm | 21.10 |  |  | 21.10 | buitenwanden; niet constructief, algemeen (verzamelniveau) | Samengesteld rekwerkBuitenplaat WBP 10mmHouten stijl- en regelwerk 38x140Minirale wolDampremmendefolieGipsplaat 12.5mmGipsvezelplaat 12,5mm | Walls | Basic Wall | Basic Wall: 21_DAT_Hekwerk 175 | 21_DAT_Hekwerk 175 | 5435600 | 2730.02 | no | yes | 1 | 0 | 509.983 | 1.0524 | 2104 | Bouwkundig | 2. nieuwbouw | Non-bearing |  |  |  |  | Vertical | Dimensions - Volume: 0.18417 m3; Constraints - Base Extension Distance: 0 mm; Top Extension Distance: 0 mm; Location Line: Finish Face: Interior; Top Constraint: Up to level: V2 ok. ruwe vloer; Pset_wanden - sets with these values: 2
Basic Wall:28_DAT_kalkzandsteen_175mm:5539283 | -1 fundering | 28.21 Uniformat (Uniformat) | 479.8 | 188 | 8925 | 28_DAT_ihw beton_180 | 2 | Walls | Non-bearing | Beton 180mm | 28.21 |  |  | 28.21 | hoofddraagconstructies; wanden en vloeren, wand-/vloerconstructies | Beton 180mm | Walls | Basic Wall | Basic Wall: 28_DAT_ihw beton_180 | 28_DAT_ihw beton_180 | 589387 | 0 | no | yes | bk. fundering | 0 | 188 | 1.6779 | 9105 | Constructie | 2. nieuwbouw | Non-bearing |  |  |  |  | Vertical | Dimensions - Volume: 0.302022 m3; Constraints - Base Extension Distance: 0 mm; Top Extension Distance: 0 mm; Location Line: Finish Face: Exterior
Basic Wall:28_DAT_ihw specie:5539294 | -1 fundering | 28.21 Uniformat (Uniformat) | 499.8 | 1080 | 11520 | 21_DAT_isolatie minerale wol_160 | 2 | Walls | Non-bearing | Isolatie minerale wol 160mm met een Rc 4,7 m2K/W | 21.10 |  |  | 21.10 | buitenwanden; niet constructief, algemeen (verzamelniveau) | Isolatie minerale wol 160mm met een Rc 4,7 m2K/W | Walls | Basic Wall | Basic Wall: 21_DAT_isolatie minerale wol_160 | 21_DAT_isolatie minerale wol_160 | 589367 | 200 | no | yes | bk. fundering | 10 | 1080 | 12.4416 | 11520 | Bouwkundig | 2. nieuwbouw | Non-bearing |  |  |  |  | Vertical | Dimensions - Volume: 1.99066 m3; Constraints - Base Extension Distance: 0 mm; Top Extension Distance: 0 mm; Location Line: Finish Face: Exterior; Top Constraint: Up to level: 0
Basic Wall:21_DAT_isolatie minerale wol_160:5539313 | -1 fundering | 21.10 Uniformat (Uniformat) | 464.8 | 730 | 3410 | 21_DAT_gevelplint 175 | 2 | Walls | Non-bearing | Isolatie minerale wol 160mm | 21.10 |  |  | 21.10 | buitenwanden; niet constructief, algemeen (verzamelniveau) | Isolatie minerale wol 160mm | Walls | Basic Wall | Basic Wall: 21_DAT_gevelplint 175 | 21_DAT_gevelplint 175 | 5440857 | 500 | no | yes | bk. fundering | -40 | 730 | 2.4893 | 3460 | Bouwkundig | 2. nieuwbouw | Non-bearing |  |  |  |  | Vertical | Dimensions - Volume: 0.472967 m3; Constraints - Base Extension Distance: 0 mm; Top Extension Distance: 0 mm; Location Line: Finish Face: Interior; Top Constraint: Up to level: 0
Basic Wall:21_DAT_isolatie minerale wol_160:5539313 | -1 fundering | 21.10 Uniformat (Uniformat) | 464.8 | 2630 | 3450 | K_15 | 2 | Walls | Non-bearing | Kunststof kozijn Gealan Kubus | 31 | Kunststof kozijn Gealan Kubus | 31 | 31 | buitenwandopeningen | Kunststof kozijn Gealan Kubus | Walls | Curtain Wall | Curtain Wall: K_15 | K_15 | 4912009 | 10 | no | yes | 0 | 0 | 2630 | 9.0735 | 3450 | Bouwkundig | 2. nieuwbouw | Non-bearing | 0 | Beginning | 4 | 2 | Vertical | Other - Doorvalveilig 1-zijdig: no; Doorvalveilig 2-zijdig: yes; Text - NLRS_C_merk: K01
Basic Wall:21_DAT_isolatie minerale wol_160:5539315 | -1 fundering | 21.10 Uniformat (Uniformat) | 464.8 | 730 | 1090 | 21_DAT_gevelplint 175 | 2 | Walls | Non-bearing | Isolatie minerale wol 160mm | 21.10 |  |  | 21.10 | buitenwanden; niet constructief, algemeen (verzamelniveau) | Isolatie minerale wol 160mm | Walls | Basic Wall | Basic Wall: 21_DAT_gevelplint 175 | 21_DAT_gevelplint 175 | 5440857 | 500 | no | yes | bk. fundering | -40 | 730 | 0.7957 | 1190 | Bouwkundig | 2. nieuwbouw | Non-bearing |  |  |  |  | Vertical | Dimensions - Volume: 0.151183 m3; Constraints - Base Extension Distance: 0 mm; Top Extension Distance: 0 mm; Location Line: Finish Face: Interior; Top Constraint: Up to level: 0
3 x Basic Wall:21_DAT_isolatie minerale wol_160:5539315 | -1 fundering | 21.10 Uniformat (Uniformat) | 464.8 | 730 | 700 | 21_DAT_gevelplint 175 | 2 | Walls | Non-bearing | Isolatie minerale wol 160mm | 21.10 |  |  | 21.10 | buitenwanden; niet constructief, algemeen (verzamelniveau) | Isolatie minerale wol 160mm | Walls | Basic Wall | Basic Wall: 21_DAT_gevelplint 175 | 21_DAT_gevelplint 175 | 5440857 | 500 | no | yes | bk. fundering | -40 | 730 | 0.511 | 800 | Bouwkundig | 2. nieuwbouw | Non-bearing |  |  |  |  | Vertical | Dimensions - Volume: 0.09709 m3; Constraints - Base Extension Distance: 0 mm; Top Extension Distance: 0 mm; Location Line: Finish Face: Interior; Top Constraint: Up to level: 0
Basic Wall:21_DAT_isolatie minerale wol_160:5539315 | -1 fundering | 21.10 Uniformat (Uniformat) | 464.8 | 730 | 2080 | 21_DAT_gevelplint 175 | 2 | Walls | Non-bearing | Isolatie minerale wol 160mm | 21.10 |  |  | 21.10 | buitenwanden; niet constructief, algemeen (verzamelniveau) | Isolatie minerale wol 160mm | Walls | Basic Wall | Basic Wall: 21_DAT_gevelplint 175 | 21_DAT_gevelplint 175 | 5440857 | 500 | no | yes | bk. fundering | -40 | 730 | 1.5184 | 2180 | Bouwkundig | 2. nieuwbouw | Non-bearing |  |  |  |  | Vertical | Dimensions - Volume: 0.288496 m3; Constraints - Base Extension Distance: 0 mm; Top Extension Distance: 0 mm; Location Line: Finish Face: Interior; Top Constraint: Up to level: 0
6 x Basic Wall:21_DAT_isolatie minerale wol_160:5539323 | -1 fundering | 21.10 Uniformat (Uniformat) | 464.8 | 730 | 2080 | 21_DAT_gevelplint 175 | 2 | Walls | Non-bearing | Isolatie minerale wol 160mm | 21.10 |  |  | 21.10 | buitenwanden; niet constructief, algemeen (verzamelniveau) | Isolatie minerale wol 160mm | Walls | Basic Wall | Basic Wall: 21_DAT_gevelplint 175 | 21_DAT_gevelplint 175 | 5440857 | 500 | no | yes | bk. fundering | -40 | 730 | 1.5184 | 2180 | Bouwkundig | 2. nieuwbouw | Non-bearing |  |  |  |  | Vertical | Dimensions - Volume: 0.288496 m3; Constraints - Base Extension Distance: 0 mm; Top Extension Distance: 0 mm; Location Line: Finish Face: Interior; Top Constraint: Up to level: 0
Basic Wall:21_DAT_isolatie minerale wol_160:5539323 | -1 fundering | 21.10 Uniformat (Uniformat) | 464.8 | 725 | 1595 | 21_DAT_gevelplint 175 | 2 | Walls | Non-bearing | Isolatie minerale wol 160mm | 21.10 |  |  | 21.10 | buitenwanden; niet constructief, algemeen (verzamelniveau) | Isolatie minerale wol 160mm | Walls | Basic Wall | Basic Wall: 21_DAT_gevelplint 175 | 21_DAT_gevelplint 175 | 5440857 | 500 | no | yes | bk. fundering | -45 | 725 | 1.15637 | 1645 | Bouwkundig | 2. nieuwbouw | Non-bearing |  |  |  |  | Vertical | Dimensions - Volume: 0.219711 m3; Constraints - Base Extension Distance: 0 mm; Top Extension Distance: 0 mm; Location Line: Finish Face: Interior; Top Constraint: Up to level: 0
Basic Wall:21_DAT_isolatie minerale wol_160:5539323 | -1 fundering | 21.10 Uniformat (Uniformat) | 464.8 | 725 | 880 | 21_DAT_gevelplint 175 | 2 | Walls | Non-bearing | Isolatie minerale wol 160mm | 21.10 |  |  | 21.10 | buitenwanden; niet constructief, algemeen (verzamelniveau) | Isolatie minerale wol 160mm | Walls | Basic Wall | Basic Wall: 21_DAT_gevelplint 175 | 21_DAT_gevelplint 175 | 5440857 | 500 | no | yes | bk. fundering | -45 | 725 | 0.638 | 930 | Bouwkundig | 2. nieuwbouw | Non-bearing |  |  |  |  | Vertical | Dimensions - Volume: 0.12122 m3; Constraints - Base Extension Distance: 0 mm; Top Extension Distance: 0 mm; Location Line: Finish Face: Interior; Top Constraint: Up to level: 0
Basic Wall:21_DAT_isolatie minerale wol_160:5539324 | -1 fundering | 21.10 Uniformat (Uniformat) | 464.8 | 730 | 1090 | 21_DAT_gevelplint 175 | 2 | Walls | Non-bearing | Isolatie minerale wol 160mm | 21.10 |  |  | 21.10 | buitenwanden; niet constructief, algemeen (verzamelniveau) | Isolatie minerale wol 160mm | Walls | Basic Wall | Basic Wall: 21_DAT_gevelplint 175 | 21_DAT_gevelplint 175 | 5440857 | 500 | no | yes | bk. fundering | -40 | 730 | 0.7957 | 1190 | Bouwkundig | 2. nieuwbouw | Non-bearing |  |  |  |  | Vertical | Dimensions - Volume: 0.151183 m3; Constraints - Base Extension Distance: 0 mm; Top Extension Distance: 0 mm; Location Line: Finish Face: Interior; Top Constraint: Up to level: 0
Basic Wall:21_DAT_metselwerk_100:5658142:1 | -1 fundering | 21.12 Uniformat (Uniformat) |  |  |  | 21_DAT_metselwerk_100 | 2 | Walls | Non-bearing | Metselwerk | 21.12 |  |  | 21.12 | buitenwanden; niet constructief, spouwwanden | Metselwerk | Group: Model Group:Penant Dubbel:5538623
3 x Basic Wall:21_DAT_isolatie hard_74:5664782 | 00 Begane grond | 21.10 Uniformat (Uniformat) | 374.8 | 2610 | 2120 | K_03 | 2 | Walls | Non-bearing | Kunststof kozijn Gealan Linear | 31 | Kunststof kozijn Gealan Linear | 31 | 31 | buitenwandopeningen | Kunststof kozijn Gealan Linear | Walls | Curtain Wall | Curtain Wall: K_03 | K_03 | 4793066 | 30 | no | yes | 0 | 0 | 2610 | 5.5332 | 2120 | Bouwkundig | 2. nieuwbouw | Non-bearing | 0 | Beginning | 4 | 2 | Vertical | Other - Doorvalveilig 1-zijdig: no; Doorvalveilig 2-zijdig: yes; Text - NLRS_C_merk: K01
Basic Wall:21_DAT_isolatie hard_74:5664782 | 00 Begane grond | 21.10 Uniformat (Uniformat) | 374.8 | 2630 | 1635 | K_18 | 2 | Walls | Non-bearing | Kunststof kozijn Gealan Kubus | 31 | Kunststof kozijn Gealan Kubus | 31 | 31 | buitenwandopeningen | Kunststof kozijn Gealan Kubus | Walls | Curtain Wall | Curtain Wall: K_18 | K_18 | 6067594 | 10 | no | yes | 0 | 0 | 2630 | 4.30005 | 1635 | Bouwkundig | 2. nieuwbouw | Non-bearing | 0 | Beginning | 4 | 2 | Vertical | Other - Doorvalveilig 1-zijdig: no; Doorvalveilig 2-zijdig: yes; Text - NLRS_C_merk: K01
3 x Basic Wall:21_DAT_isolatie hard_74:5664782 | 00 Begane grond | 21.10 Uniformat (Uniformat) | 374.8 | 2630 | 2120 | K_02 | 2 | Walls | Non-bearing | Kunststof kozijn Gealan Kubus | 31 | Kunststof kozijn Gealan Kubus | 31 | 31 | buitenwandopeningen | Kunststof kozijn Gealan Kubus | Walls | Curtain Wall | Curtain Wall: K_02 | K_02 | 4792108 | 10 | no | yes | 0 | 0 | 2630 | 5.5756 | 2120 | Bouwkundig | 2. nieuwbouw | Non-bearing | 0 | Beginning | 4 | 2 | Vertical | Other - Doorvalveilig 1-zijdig: no; Doorvalveilig 2-zijdig: yes; Text - NLRS_C_merk: K01
Basic Wall:21_DAT_isolatie hard_85:5667233 | 00 Begane grond | 21.10 Uniformat (Uniformat) | 389.8 | 2630 | 2120 | K_02 | 2 | Walls | Non-bearing | Kunststof kozijn Gealan Kubus | 31 | Kunststof kozijn Gealan Kubus | 31 | 31 | buitenwandopeningen | Kunststof kozijn Gealan Kubus | Walls | Curtain Wall | Curtain Wall: K_02 | K_02 | 4792108 | 10 | no | yes | 0 | 0 | 2630 | 5.5756 | 2120 | Bouwkundig | 2. nieuwbouw | Non-bearing | 0 | Beginning | 4 | 2 | Vertical | Other - Doorvalveilig 1-zijdig: no; Doorvalveilig 2-zijdig: yes; Text - NLRS_C_merk: K01
3 x Basic Wall:21_DAT_isolatie hard_85:5667233 | 00 Begane grond | 21.10 Uniformat (Uniformat) | 389.8 | 2630 | 740 | K_04 | 2 | Walls | Non-bearing | Kunststof kozijn Gealan Kubus | 31 | Kunststof kozijn Gealan Kubus | 31 | 31 | buitenwandopeningen | Kunststof kozijn Gealan Kubus | Walls | Curtain Wall | Curtain Wall: K_04 | K_04 | 4800906 | 10 | no | yes | 0 | 0 | 2630 | 1.9462 | 740 | Bouwkundig | 2. nieuwbouw | Non-bearing | 0 | Beginning | 4 | 2 | Vertical | Other - Doorvalveilig 1-zijdig: no; Doorvalveilig 2-zijdig: yes; Text - NLRS_C_merk: K01
Basic Wall:21_DAT_isolatie hard_85:5667233 | 00 Begane grond | 21.10 Uniformat (Uniformat) | 389.8 | 2610 | 2120 | K_03 | 2 | Walls | Non-bearing | Kunststof kozijn Gealan Linear | 31 | Kunststof kozijn Gealan Linear | 31 | 31 | buitenwandopeningen | Kunststof kozijn Gealan Linear | Walls | Curtain Wall | Curtain Wall: K_03 | K_03 | 4793066 | 30 | no | yes | 0 | 0 | 2610 | 5.5332 | 2120 | Bouwkundig | 2. nieuwbouw | Non-bearing | 0 | Beginning | 4 | 2 | Vertical | Other - Doorvalveilig 1-zijdig: no; Doorvalveilig 2-zijdig: yes; Text - NLRS_C_merk: K01
Basic Wall:21_DAT_isolatie hard_85:5667233 | 00 Begane grond | 21.10 Uniformat (Uniformat) | 389.8 | 2630 | 1130 | K_05 | 2 | Walls | Non-bearing | Kunststof kozijn Gealan Linear | 31 | Kunststof kozijn Gealan Linear | 31 | 31 | buitenwandopeningen | Kunststof kozijn Gealan Linear | Walls | Curtain Wall | Curtain Wall: K_05 | K_05 | 4797835 | 10 | no | yes | 0 | 0 | 2630 | 2.9719 | 1130 | Bouwkundig | 2. nieuwbouw | Non-bearing | 0 | Beginning | 4 | 2 | Vertical | Other - Doorvalveilig 1-zijdig: no; Doorvalveilig 2-zijdig: yes; Text - NLRS_C_merk: K01
Basic Wall:21_DAT_isolatie hard_85:5667384 | 00 Begane grond | 21.10 Uniformat (Uniformat) | 389.8 | 2630 | 1635 | K_18 | 2 | Walls | Non-bearing | Kunststof kozijn Gealan Kubus | 31 | Kunststof kozijn Gealan Kubus | 31 | 31 | buitenwandopeningen | Kunststof kozijn Gealan Kubus | Walls | Curtain Wall | Curtain Wall: K_18 | K_18 | 6067594 | 10 | no | yes | 0 | 0 | 2630 | 4.30005 | 1635 | Bouwkundig | 2. nieuwbouw | Non-bearing | 0 | Beginning | 4 | 2 | Vertical | Other - Doorvalveilig 1-zijdig: no; Doorvalveilig 2-zijdig: yes; Text - NLRS_C_merk: K01
Basic Wall:21_DAT_isolatie hard_85:5667384 | 00 Begane grond | 21.10 Uniformat (Uniformat) | 389.8 | 2630 | 920 | K_01 | 2 | Walls | Non-bearing | Kunststof kozijn Gealan Kubus | 31 | Kunststof kozijn Gealan Kubus | 31 | 31 | buitenwandopeningen | Kunststof kozijn Gealan Kubus | Walls | Curtain Wall | Curtain Wall: K_01 | K_01 | 4774158 | 10 | no | yes | 0 | 0 | 2630 | 2.4196 | 920 | Bouwkundig | 2. nieuwbouw | Non-bearing | 0 | Beginning | 4 | 2 | Vertical | Other - Doorvalveilig 1-zijdig: no; Doorvalveilig 2-zijdig: yes; Text - NLRS_C_merk: K01
Basic Wall:21_DAT_isolatie hard_85:5667515 | 00 Begane grond | 21.10 Uniformat (Uniformat) | 389.8 | 2630 | 1865 | K_21 | 2 | Walls | Non-bearing | Kunststof kozijn Gealan Kubus | 31 | Kunststof kozijn Gealan Kubus | 31 | 31 | buitenwandopeningen | Kunststof kozijn Gealan Kubus | Walls | Curtain Wall | Curtain Wall: K_21 | K_21 | 5077807 | 10 | no | yes | 0 | 0 | 2630 | 4.90495 | 1865 | Bouwkundig | 2. nieuwbouw | Non-bearing | 0 | Beginning | 4 | 2 | Vertical | Other - Doorvalveilig 1-zijdig: no; Doorvalveilig 2-zijdig: yes; Text - NLRS_C_merk: K01
2 x Basic Wall:21_DAT_isolatie hard_85:5667515 | 00 Begane grond | 21.10 Uniformat (Uniformat) | 389.8 | 2630 | 920 | K_01 | 2 | Walls | Non-bearing | Kunststof kozijn Gealan Kubus | 31 | Kunststof kozijn Gealan Kubus | 31 | 31 | buitenwandopeningen | Kunststof kozijn Gealan Kubus | Walls | Curtain Wall | Curtain Wall: K_01 | K_01 | 4774158 | 10 | no | yes | 0 | 0 | 2630 | 2.4196 | 920 | Bouwkundig | 2. nieuwbouw | Non-bearing | 0 | Beginning | 4 | 2 | Vertical | Other - Doorvalveilig 1-zijdig: no; Doorvalveilig 2-zijdig: yes; Text - NLRS_C_merk: K01
Basic Wall:21_DAT_isolatie hard_85:5667515 | 00 Begane grond | 21.10 Uniformat (Uniformat) | 389.8 | 2610 | 2120 | K_03 | 2 | Walls | Non-bearing | Kunststof kozijn Gealan Linear | 31 | Kunststof kozijn Gealan Linear | 31 | 31 | buitenwandopeningen | Kunststof kozijn Gealan Linear | Walls | Curtain Wall | Curtain Wall: K_03 | K_03 | 4793066 | 30 | no | yes | 0 | 0 | 2610 | 5.5332 | 2120 | Bouwkundig | 2. nieuwbouw | Non-bearing | 0 | Beginning | 4 | 2 | Vertical | Other - Doorvalveilig 1-zijdig: no; Doorvalveilig 2-zijdig: yes; Text - NLRS_C_merk: K01
Basic Wall:21_DAT_isolatie hard_85:5667515 | 00 Begane grond | 21.10 Uniformat (Uniformat) | 389.8 | 2630 | 2120 | K_02 | 2 | Walls | Non-bearing | Kunststof kozijn Gealan Kubus | 31 | Kunststof kozijn Gealan Kubus | 31 | 31 | buitenwandopeningen | Kunststof kozijn Gealan Kubus | Walls | Curtain Wall | Curtain Wall: K_02 | K_02 | 4792108 | 10 | no | yes | 0 | 0 | 2630 | 5.5756 | 2120 | Bouwkundig | 2. nieuwbouw | Non-bearing | 0 | Beginning | 4 | 2 | Vertical | Other - Doorvalveilig 1-zijdig: no; Doorvalveilig 2-zijdig: yes; Text - NLRS_C_merk: K01
Basic Wall:21_DAT_isolatie hard_85:5667684 | 00 Begane grond | 21.10 Uniformat (Uniformat) | 389.8 | 2630 | 1910 | K_20 | 2 | Walls | Non-bearing | Kunststof kozijn Gealan Linear | 31 | Kunststof kozijn Gealan Linear | 31 | 31 | buitenwandopeningen | Kunststof kozijn Gealan Linear | Walls | Curtain Wall | Curtain Wall: K_20 | K_20 | 4960166 | 30 | no | yes | 0 | 0 | 2630 | 5.0233 | 1910 | Bouwkundig | 2. nieuwbouw | Non-bearing | 0 | Beginning | 4 | 2 | Vertical | Other - Doorvalveilig 1-zijdig: no; Doorvalveilig 2-zijdig: yes; Text - NLRS_C_merk: K01
Basic Wall:21_DAT_isolatie hard_85:5667684 | 00 Begane grond | 21.10 Uniformat (Uniformat) | 389.8 | 2630 | 1290 | k_19 | 2 | Walls | Non-bearing | Kunststof kozijn Gealan Kubus | 31 | Kunststof kozijn Gealan Kubus | 31 | 31 | buitenwandopeningen | Kunststof kozijn Gealan Kubus | Walls | Curtain Wall | Curtain Wall: k_19 | k_19 | 4959005 | 10 | no | yes | 0 | 0 | 2630 | 3.3927 | 1290 | Bouwkundig | 2. nieuwbouw | Non-bearing | 0 | Beginning | 4 | 2 | Vertical | Other - Doorvalveilig 1-zijdig: no; Doorvalveilig 2-zijdig: yes; Text - NLRS_C_merk: K01
Basic Wall:28_DAT_kalkzandsteen_175mm:5723334 | 00 Begane grond | 28.21 Uniformat (Uniformat) | 479.8 | 2180 | 2300 | K_07 | 2 | Walls | Non-bearing | Kunststof kozijn Gealan Kubus | 31 | Kunststof kozijn Gealan Kubus | 31 | 31 | buitenwandopeningen | Kunststof kozijn Gealan Kubus | Walls | Curtain Wall | Curtain Wall: K_07 | K_07 | 4849800 | 710 | no | yes | 0 | 0 | 2180 | 5.014 | 2300 | Bouwkundig | 2. nieuwbouw | Non-bearing | 0 | Beginning | 4 | 2 | Vertical | Other - Doorvalveilig 1-zijdig: no; Doorvalveilig 2-zijdig: yes; Text - NLRS_C_merk: K01
Basic Wall:28_DAT_kalkzandsteen_175mm:5723334 | 00 Begane grond | 28.21 Uniformat (Uniformat) | 479.8 | 2630 | 1495 | K_14 | 2 | Walls | Non-bearing | Kunststof kozijn Gealan Kubus | 31 | Kunststof kozijn Gealan Kubus | 31 | 31 | buitenwandopeningen | Kunststof kozijn Gealan Kubus | Walls | Curtain Wall | Curtain Wall: K_14 | K_14 | 4906721 | 10 | no | yes | 0 | 0 | 2630 | 3.93185 | 1495 | Bouwkundig | 2. nieuwbouw | Non-bearing | 0 | Beginning | 4 | 2 | Vertical | Other - Doorvalveilig 1-zijdig: no; Doorvalveilig 2-zijdig: yes; Text - NLRS_C_merk: K01
Basic Wall:28_DAT_kalkzandsteen_175mm:5723334 | 00 Begane grond | 28.21 Uniformat (Uniformat) | 479.8 | 2630 | 3450 | K_15 | 2 | Walls | Non-bearing | Kunststof kozijn Gealan Kubus | 31 | Kunststof kozijn Gealan Kubus | 31 | 31 | buitenwandopeningen | Kunststof kozijn Gealan Kubus | Walls | Curtain Wall | Curtain Wall: K_15 | K_15 | 4912009 | 10 | no | yes | 0 | 0 | 2630 | 9.0735 | 3450 | Bouwkundig | 2. nieuwbouw | Non-bearing | 0 | Beginning | 4 | 2 | Vertical | Other - Doorvalveilig 1-zijdig: no; Doorvalveilig 2-zijdig: yes; Text - NLRS_C_merk: K01
4 x Basic Wall:28_DAT_kalkzandsteen_175mm:5723334 | 00 Begane grond | 28.21 Uniformat (Uniformat) | 479.8 | 1930 | 880 | K_16 | 2 | Walls | Non-bearing | Kunststof kozijn Gealan Kubus | 31 | Kunststof kozijn Gealan Kubus | 31 | 31 | buitenwandopeningen | Kunststof kozijn Gealan Kubus | Walls | Curtain Wall | Curtain Wall: K_16 | K_16 | 6074129 | 710 | no | yes | 0 | 0 | 1930 | 1.6984 | 880 | Bouwkundig | 2. nieuwbouw | Non-bearing | 0 | Beginning | 4 | 2 | Vertical | Other - Doorvalveilig 1-zijdig: no; Doorvalveilig 2-zijdig: yes; Text - NLRS_C_merk: K01
3 x Basic Wall:28_DAT_kalkzandsteen_175mm:5723334 | 00 Begane grond | 28.21 Uniformat (Uniformat) | 479.8 | 1930 | 2040 | K_17 | 2 | Walls | Non-bearing | Kunststof kozijn Gealan Kubus | 31 | Kunststof kozijn Gealan Kubus | 31 | 31 | buitenwandopeningen | Kunststof kozijn Gealan Kubus | Walls | Curtain Wall | Curtain Wall: K_17 | K_17 | 6061266 | 710 | no | yes | 0 | 0 | 1930 | 3.9372 | 2040 | Bouwkundig | 2. nieuwbouw | Non-bearing | 0 | Beginning | 4 | 2 | Vertical | Other - Doorvalveilig 1-zijdig: no; Doorvalveilig 2-zijdig: yes; Text - NLRS_C_merk: K01
Basic Wall:28_DAT_kalkzandsteen_175mm:5723375 | 00 Begane grond | 28.21 Uniformat (Uniformat) | 479.8 | 3310 | 190 | 22_DAT_binnenwand_25 | 2 | Walls | Non-bearing | Lichte scheidingswand 100mm | 22.13 |  |  | 22.13 | binnenwanden; niet constructief, systeemwanden; vast | Lichte scheidingswand 100mm | Walls | Basic Wall | Basic Wall: 22_DAT_binnenwand_25 | 22_DAT_binnenwand_25 | 4977124 | 0 | no | yes | V0 bk. ruwe vloer | 0 | 3310 | 0.6289 | 190 | Bouwkundig | 2. nieuwbouw | Non-bearing |  |  |  |  | Vertical | Dimensions - Volume: 0.0157225 m3; Constraints - Base Extension Distance: 0 mm; Top Extension Distance: 0 mm; Location Line: Wall Centerline; Top Constraint: Up to level: V1 ok. ruwe vloer
Basic Wall:28_DAT_kalkzandsteen_175mm:5723375 | 00 Begane grond | 28.21 Uniformat (Uniformat) | 479.8 | 2180 | 2300 | K_07 | 2 | Walls | Non-bearing | Kunststof kozijn Gealan Kubus | 31 | Kunststof kozijn Gealan Kubus | 31 | 31 | buitenwandopeningen | Kunststof kozijn Gealan Kubus | Walls | Curtain Wall | Curtain Wall: K_07 | K_07 | 4849800 | 710 | no | yes | 0 | 0 | 2180 | 5.014 | 2300 | Bouwkundig | 2. nieuwbouw | Non-bearing | 0 | Beginning | 4 | 2 | Vertical | Other - Doorvalveilig 1-zijdig: no; Doorvalveilig 2-zijdig: yes; Text - NLRS_C_merk: K01
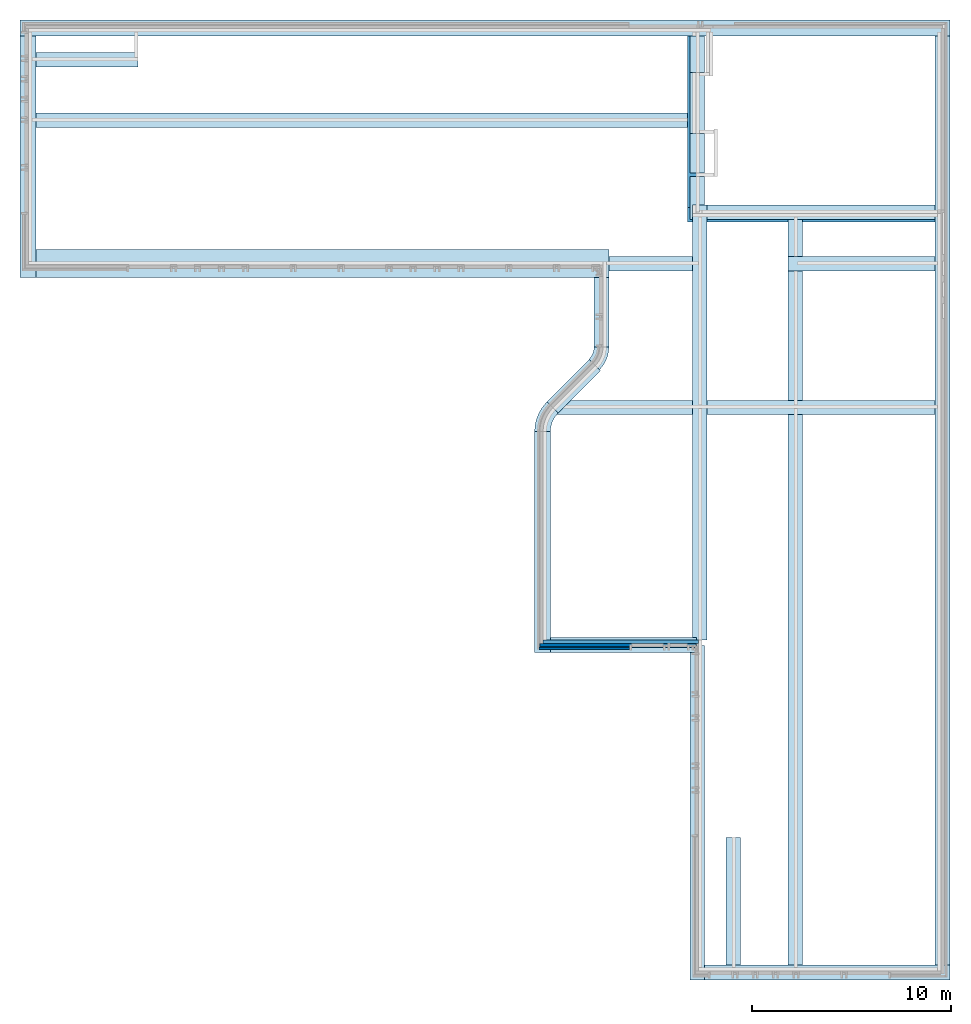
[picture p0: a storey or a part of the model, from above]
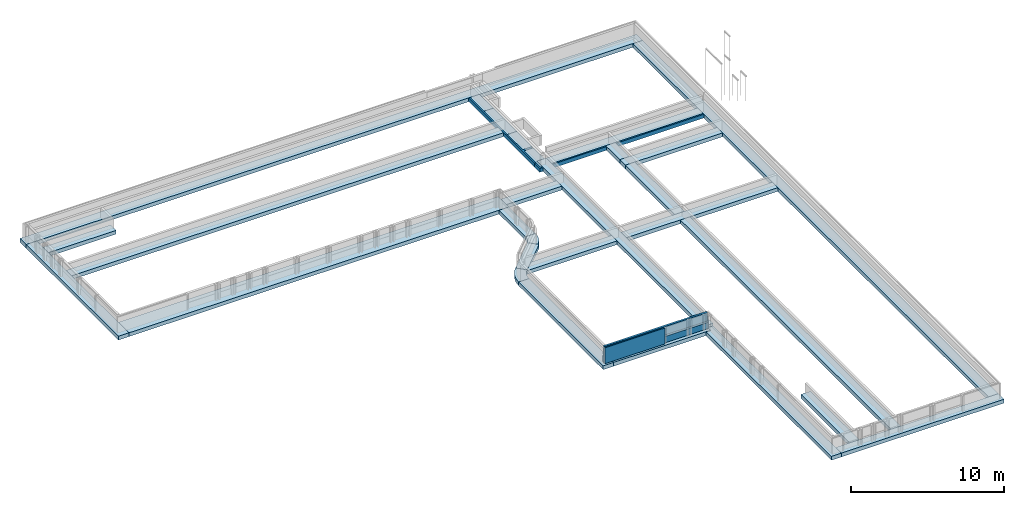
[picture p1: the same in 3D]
Properties of the parts of a building model (IFC2X3), part 25 of 37

# IfcOpeningElement: Opening (1092)
Name | In | Classification | Depth (mm) | BaseQuantities, Height (mm) | BaseQuantities, Width (mm) | Reference | Pset_OpeningElementCommon, sets with these values | Pset_ProductRequirements, Category | Pset_wanden, Structural Usage | Pset_wanden, Omschrijving | Pset_wanden, NL-sfb-Codering | Pset_kozijnen (CW), Omschrijving | Pset_kozijnen (CW), NL-sfb-Codering | Pset_DAT_KMS, Assembly Code | Pset_DAT_KMS, Assembly Description | Pset_DAT_KMS, Description | Other, Category | Family | Other, Family and Type | Type | Type Id | Base Offset (mm) | Base is Attached = Related to Mass = Top is Attached = Structural | Room Bounding | Base Constraint | Top Offset (mm) | Unconnected Height (mm) | Dimensions, Area (m2) | Length (mm) | Identity Data, Workset | Phase Created | Structural, Structural Usage | Angle (deg) = Offset (mm) | Justification | Number | Horizontal Grid, sets with these values | Cross-Section
3 x Basic Wall:28_DAT_kalkzandsteen_175mm:5723375 | 00 Begane grond | 28.21 Uniformat (Uniformat) | 479.8 | 1930 | 2040 | K_17 | 2 | Walls | Non-bearing | Kunststof kozijn Gealan Kubus | 31 | Kunststof kozijn Gealan Kubus | 31 | 31 | buitenwandopeningen | Kunststof kozijn Gealan Kubus | Walls | Curtain Wall | Curtain Wall: K_17 | K_17 | 6061266 | 710 | no | yes | 0 | 0 | 1930 | 3.9372 | 2040 | Bouwkundig | 2. nieuwbouw | Non-bearing | 0 | Beginning | 4 | 2 | Vertical | Other - Doorvalveilig 1-zijdig: no; Doorvalveilig 2-zijdig: yes; Text - NLRS_C_merk: K01
4 x Basic Wall:28_DAT_kalkzandsteen_175mm:5723375 | 00 Begane grond | 28.21 Uniformat (Uniformat) | 479.8 | 1930 | 880 | K_16 | 2 | Walls | Non-bearing | Kunststof kozijn Gealan Kubus | 31 | Kunststof kozijn Gealan Kubus | 31 | 31 | buitenwandopeningen | Kunststof kozijn Gealan Kubus | Walls | Curtain Wall | Curtain Wall: K_16 | K_16 | 6074129 | 710 | no | yes | 0 | 0 | 1930 | 1.6984 | 880 | Bouwkundig | 2. nieuwbouw | Non-bearing | 0 | Beginning | 4 | 2 | Vertical | Other - Doorvalveilig 1-zijdig: no; Doorvalveilig 2-zijdig: yes; Text - NLRS_C_merk: K01
Basic Wall:28_DAT_kalkzandsteen_175mm:5723375 | 00 Begane grond | 28.21 Uniformat (Uniformat) | 479.8 | 2630 | 1495 | K_14 | 2 | Walls | Non-bearing | Kunststof kozijn Gealan Kubus | 31 | Kunststof kozijn Gealan Kubus | 31 | 31 | buitenwandopeningen | Kunststof kozijn Gealan Kubus | Walls | Curtain Wall | Curtain Wall: K_14 | K_14 | 4906721 | 10 | no | yes | 0 | 0 | 2630 | 3.93185 | 1495 | Bouwkundig | 2. nieuwbouw | Non-bearing | 0 | Beginning | 4 | 2 | Vertical | Other - Doorvalveilig 1-zijdig: no; Doorvalveilig 2-zijdig: yes; Text - NLRS_C_merk: K01
Basic Wall:28_DAT_kalkzandsteen_175mm:5723375 | 00 Begane grond | 28.21 Uniformat (Uniformat) | 479.8 | 2630 | 3450 | K_15 | 2 | Walls | Non-bearing | Kunststof kozijn Gealan Kubus | 31 | Kunststof kozijn Gealan Kubus | 31 | 31 | buitenwandopeningen | Kunststof kozijn Gealan Kubus | Walls | Curtain Wall | Curtain Wall: K_15 | K_15 | 4912009 | 10 | no | yes | 0 | 0 | 2630 | 9.0735 | 3450 | Bouwkundig | 2. nieuwbouw | Non-bearing | 0 | Beginning | 4 | 2 | Vertical | Other - Doorvalveilig 1-zijdig: no; Doorvalveilig 2-zijdig: yes; Text - NLRS_C_merk: K01
Basic Wall:21_DAT_isolatie hard_74:5735707 | 00 Begane grond | 21.10 Uniformat (Uniformat) | 374.8 | 2180 | 790 | K_06 | 2 | Walls | Non-bearing | Kunststof kozijn Gealan Kubus | 31 | Kunststof kozijn Gealan Kubus | 31 | 31 | buitenwandopeningen | Kunststof kozijn Gealan Kubus | Walls | Curtain Wall | Curtain Wall: K_06 | K_06 | 4842980 | 710 | no | yes | 0 | 0 | 2180 | 1.7222 | 790 | Bouwkundig | 2. nieuwbouw | Non-bearing | 0 | Beginning | 4 | 2 | Vertical | Other - Doorvalveilig 1-zijdig: no; Doorvalveilig 2-zijdig: yes; Text - NLRS_C_merk: K01
Basic Wall:21_DAT_isolatie hard_74:5735707 | 00 Begane grond | 21.10 Uniformat (Uniformat) | 374.8 | 2180 | 2300 | K_07 | 2 | Walls | Non-bearing | Kunststof kozijn Gealan Kubus | 31 | Kunststof kozijn Gealan Kubus | 31 | 31 | buitenwandopeningen | Kunststof kozijn Gealan Kubus | Walls | Curtain Wall | Curtain Wall: K_07 | K_07 | 4849800 | 710 | no | yes | 0 | 0 | 2180 | 5.014 | 2300 | Bouwkundig | 2. nieuwbouw | Non-bearing | 0 | Beginning | 4 | 2 | Vertical | Other - Doorvalveilig 1-zijdig: no; Doorvalveilig 2-zijdig: yes; Text - NLRS_C_merk: K01
 | 00 Begane grond |  |  |  |  | Model Lines | 2 | Lines: <Sketch> |  |  |  |  |  |  |  |  | Lines: <Sketch> |  |  |  |  |  |  |  |  |  |  |  | 1775.64 | Bouwkundig | BaseQuantities - Area: 57.1766 m2; Other - Concrete Cantilever: 0 mm; Steel Cantilever: 0 mm; Constraints - Defines Constant Height: no; Defines Slope: no; Offset From Base: 0 mm; Dimensions - Slope: 4.76364; Graphics - Center Mark Visible: no
 | 00 Begane grond |  |  |  |  | Model Lines | 2 | Lines: <Sketch> |  |  |  |  |  |  |  |  | Lines: <Sketch> |  |  |  |  |  |  |  |  |  |  |  | 528.412 | Bouwkundig | BaseQuantities - Area: 6.40758 m2; Other - Concrete Cantilever: 0 mm; Steel Cantilever: 0 mm; Constraints - Defines Constant Height: no; Defines Slope: no; Offset From Base: 0 mm; Dimensions - Slope: 4.76364; Graphics - Center Mark Visible: no
 | 00 Begane grond |  |  |  |  | Model Lines | 2 | Lines: <Sketch> |  |  |  |  |  |  |  |  | Lines: <Sketch> |  |  |  |  |  |  |  |  |  |  |  | 5656.43 | Bouwkundig | BaseQuantities - Area: 10.1857 m2; Other - Concrete Cantilever: 0 mm; Steel Cantilever: 0 mm; Constraints - Defines Constant Height: no; Defines Slope: no; Offset From Base: 0 mm; Dimensions - Slope: 4.76364; Graphics - Center Mark Visible: no
Basic Wall:22_DAT_binnenwand_100:5910645 | 01 eerste verdieping | 22.13 Uniformat (Uniformat) | 404.8 | 2390 | 1034 | Merk H02 | 2 | Walls | Non-bearing | houten kozijn | 31.10 | houten kozijn | 31.10 | 31.10 | buitenwandopeningen; niet gevuld, algemeen (verzamelniveau) | houten kozijn | Walls | Curtain Wall | Curtain Wall: Merk H02 | Merk H02 | 5128107 | 0 | no | yes | 1 | 400 | 2390 | 2.47126 | 1034 | Bouwkundig | 2. nieuwbouw | Non-bearing | 0 | Beginning | 4 | 2 | Vertical | Pset_wanden - NLRS_C_Geluidwering_DnTA: 25; Pset_kozijnen (CW) - NLRS_C_Geluidwering_DnTA: 25; Data - NLRS_C_Geluidwering_DnTA: 25; Materials and Finishes - NLRS_C_Afwerking Kozijn: Ral 9010 - Deur HPL Formica F2296 Sno White
Basic Wall:22_DAT_binnenwand_100:5910645 | 01 eerste verdieping | 22.13 Uniformat (Uniformat) | 404.8 | 3190 | 2970 | Merk H11 | 2 | Walls | Non-bearing | houten kozijn | 31.10 | houten kozijn | 31.10 | 31.10 | buitenwandopeningen; niet gevuld, algemeen (verzamelniveau) | houten kozijn | Walls | Curtain Wall | Curtain Wall: Merk H11 | Merk H11 | 5175472 | 0 | no | yes | 1 | 400 | 3190 | 9.4743 | 2970 | Bouwkundig | 2. nieuwbouw | Non-bearing | 0 | Beginning | 4 | 2 | Vertical | Pset_wanden - NLRS_C_Geluidwering_DnTA: 31; NLRS_C_brandwerendheid: 30; Pset_kozijnen (CW) - NLRS_C_Geluidwering_DnTA: 31; NLRS_C_brandwerendheid: 30; Data - NLRS_C_Geluidwering_DnTA: 31; Materials and Finishes - NLRS_C_Afwerking Kozijn: Ral 9010 - Deur HPL Formica F2296 Sno White; Fire Protection - NLRS_C_brandwerendheid: 30
Basic Wall:21_DAT_isolatie hard_74:5914862 | 00 Begane grond | 21.10 Uniformat (Uniformat) | 374.8 | 1930 | 2040 | K_17 | 2 | Walls | Non-bearing | Kunststof kozijn Gealan Kubus | 31 | Kunststof kozijn Gealan Kubus | 31 | 31 | buitenwandopeningen | Kunststof kozijn Gealan Kubus | Walls | Curtain Wall | Curtain Wall: K_17 | K_17 | 6061266 | 710 | no | yes | 0 | 0 | 1930 | 3.9372 | 2040 | Bouwkundig | 2. nieuwbouw | Non-bearing | 0 | Beginning | 4 | 2 | Vertical | Group: Model Group:Merk K17:5544294; Other - Doorvalveilig 1-zijdig: no; Doorvalveilig 2-zijdig: yes; Text - NLRS_C_merk: K01
Basic Wall:21_DAT_isolatie hard_74:5915708 | 00 Begane grond | 21.10 Uniformat (Uniformat) | 374.8 | 1930 | 2040 | K_17 | 2 | Walls | Non-bearing | Kunststof kozijn Gealan Kubus | 31 | Kunststof kozijn Gealan Kubus | 31 | 31 | buitenwandopeningen | Kunststof kozijn Gealan Kubus | Walls | Curtain Wall | Curtain Wall: K_17 | K_17 | 6061266 | 710 | no | yes | 0 | 0 | 1930 | 3.9372 | 2040 | Bouwkundig | 2. nieuwbouw | Non-bearing | 0 | Beginning | 4 | 2 | Vertical | Group: Model Group:Merk K17:5540560; Other - Doorvalveilig 1-zijdig: no; Doorvalveilig 2-zijdig: yes; Text - NLRS_C_merk: K01
Basic Wall:21_DAT_isolatie hard_74:5915712 | 00 Begane grond | 21.10 Uniformat (Uniformat) | 374.8 | 1930 | 2040 | K_17 | 2 | Walls | Non-bearing | Kunststof kozijn Gealan Kubus | 31 | Kunststof kozijn Gealan Kubus | 31 | 31 | buitenwandopeningen | Kunststof kozijn Gealan Kubus | Walls | Curtain Wall | Curtain Wall: K_17 | K_17 | 6061266 | 710 | no | yes | 0 | 0 | 1930 | 3.9372 | 2040 | Bouwkundig | 2. nieuwbouw | Non-bearing | 0 | Beginning | 4 | 2 | Vertical | Group: Model Group:Merk K17:5542284; Other - Doorvalveilig 1-zijdig: no; Doorvalveilig 2-zijdig: yes; Text - NLRS_C_merk: K01
Basic Wall:21_DAT_isolatie hard_74:5915714 | 00 Begane grond | 21.10 Uniformat (Uniformat) | 374.8 | 1930 | 2040 | K_17 | 2 | Walls | Non-bearing | Kunststof kozijn Gealan Kubus | 31 | Kunststof kozijn Gealan Kubus | 31 | 31 | buitenwandopeningen | Kunststof kozijn Gealan Kubus | Walls | Curtain Wall | Curtain Wall: K_17 | K_17 | 6061266 | 710 | no | yes | 0 | 0 | 1930 | 3.9372 | 2040 | Bouwkundig | 2. nieuwbouw | Non-bearing | 0 | Beginning | 4 | 2 | Vertical | Group: Model Group:Merk K17:5542310; Other - Doorvalveilig 1-zijdig: no; Doorvalveilig 2-zijdig: yes; Text - NLRS_C_merk: K01
Basic Wall:21_DAT_isolatie hard_74:5915716 | 00 Begane grond | 21.10 Uniformat (Uniformat) | 374.8 | 1930 | 2040 | K_17 | 2 | Walls | Non-bearing | Kunststof kozijn Gealan Kubus | 31 | Kunststof kozijn Gealan Kubus | 31 | 31 | buitenwandopeningen | Kunststof kozijn Gealan Kubus | Walls | Curtain Wall | Curtain Wall: K_17 | K_17 | 6061266 | 710 | no | yes | 0 | 0 | 1930 | 3.9372 | 2040 | Bouwkundig | 2. nieuwbouw | Non-bearing | 0 | Beginning | 4 | 2 | Vertical | Group: Model Group:Merk K17:5542336; Other - Doorvalveilig 1-zijdig: no; Doorvalveilig 2-zijdig: yes; Text - NLRS_C_merk: K01
Basic Wall:21_DAT_isolatie hard_74:5915718 | 00 Begane grond | 21.10 Uniformat (Uniformat) | 374.8 | 1930 | 2040 | K_17 | 2 | Walls | Non-bearing | Kunststof kozijn Gealan Kubus | 31 | Kunststof kozijn Gealan Kubus | 31 | 31 | buitenwandopeningen | Kunststof kozijn Gealan Kubus | Walls | Curtain Wall | Curtain Wall: K_17 | K_17 | 6061266 | 710 | no | yes | 0 | 0 | 1930 | 3.9372 | 2040 | Bouwkundig | 2. nieuwbouw | Non-bearing | 0 | Beginning | 4 | 2 | Vertical | Group: Model Group:Merk K17:5542362; Other - Doorvalveilig 1-zijdig: no; Doorvalveilig 2-zijdig: yes; Text - NLRS_C_merk: K01
Basic Wall:21_DAT_isolatie hard_74:5915720 | 00 Begane grond | 21.10 Uniformat (Uniformat) | 374.8 | 1930 | 2040 | K_17 | 2 | Walls | Non-bearing | Kunststof kozijn Gealan Kubus | 31 | Kunststof kozijn Gealan Kubus | 31 | 31 | buitenwandopeningen | Kunststof kozijn Gealan Kubus | Walls | Curtain Wall | Curtain Wall: K_17 | K_17 | 6061266 | 710 | no | yes | 0 | 0 | 1930 | 3.9372 | 2040 | Bouwkundig | 2. nieuwbouw | Non-bearing | 0 | Beginning | 4 | 2 | Vertical | Group: Model Group:Merk K17:5542388; Other - Doorvalveilig 1-zijdig: no; Doorvalveilig 2-zijdig: yes; Text - NLRS_C_merk: K01
Basic Wall:21_DAT_isolatie hard_74:5915722 | 00 Begane grond | 21.10 Uniformat (Uniformat) | 374.8 | 1930 | 2040 | K_17 | 2 | Walls | Non-bearing | Kunststof kozijn Gealan Kubus | 31 | Kunststof kozijn Gealan Kubus | 31 | 31 | buitenwandopeningen | Kunststof kozijn Gealan Kubus | Walls | Curtain Wall | Curtain Wall: K_17 | K_17 | 6061266 | 710 | no | yes | 0 | 0 | 1930 | 3.9372 | 2040 | Bouwkundig | 2. nieuwbouw | Non-bearing | 0 | Beginning | 4 | 2 | Vertical | Group: Model Group:Merk K17:5544972; Other - Doorvalveilig 1-zijdig: no; Doorvalveilig 2-zijdig: yes; Text - NLRS_C_merk: K01
Basic Wall:21_DAT_isolatie hard_74:5915724 | 00 Begane grond | 21.10 Uniformat (Uniformat) | 374.8 | 1930 | 2040 | K_17 | 2 | Walls | Non-bearing | Kunststof kozijn Gealan Kubus | 31 | Kunststof kozijn Gealan Kubus | 31 | 31 | buitenwandopeningen | Kunststof kozijn Gealan Kubus | Walls | Curtain Wall | Curtain Wall: K_17 | K_17 | 6061266 | 710 | no | yes | 0 | 0 | 1930 | 3.9372 | 2040 | Bouwkundig | 2. nieuwbouw | Non-bearing | 0 | Beginning | 4 | 2 | Vertical | Group: Model Group:Merk K17:5545007; Other - Doorvalveilig 1-zijdig: no; Doorvalveilig 2-zijdig: yes; Text - NLRS_C_merk: K01
Basic Wall:21_DAT_isolatie hard_74:5915726 | 00 Begane grond | 21.10 Uniformat (Uniformat) | 374.8 | 1930 | 2040 | K_17 | 2 | Walls | Non-bearing | Kunststof kozijn Gealan Kubus | 31 | Kunststof kozijn Gealan Kubus | 31 | 31 | buitenwandopeningen | Kunststof kozijn Gealan Kubus | Walls | Curtain Wall | Curtain Wall: K_17 | K_17 | 6061266 | 710 | no | yes | 0 | 0 | 1930 | 3.9372 | 2040 | Bouwkundig | 2. nieuwbouw | Non-bearing | 0 | Beginning | 4 | 2 | Vertical | Group: Model Group:Merk K17:5855989; Other - Doorvalveilig 1-zijdig: no; Doorvalveilig 2-zijdig: yes; Text - NLRS_C_merk: K01
Basic Wall:21_DAT_isolatie hard_74:5915728 | 00 Begane grond | 21.10 Uniformat (Uniformat) | 374.8 | 1930 | 2040 | K_17 | 2 | Walls | Non-bearing | Kunststof kozijn Gealan Kubus | 31 | Kunststof kozijn Gealan Kubus | 31 | 31 | buitenwandopeningen | Kunststof kozijn Gealan Kubus | Walls | Curtain Wall | Curtain Wall: K_17 | K_17 | 6061266 | 710 | no | yes | 0 | 0 | 1930 | 3.9372 | 2040 | Bouwkundig | 2. nieuwbouw | Non-bearing | 0 | Beginning | 4 | 2 | Vertical | Group: Model Group:Merk K17:5856030; Other - Doorvalveilig 1-zijdig: no; Doorvalveilig 2-zijdig: yes; Text - NLRS_C_merk: K01
Basic Wall:43_DAT_Wandtegelwerk:5949348 | 00 Begane grond | 42.12 Uniformat (Uniformat) | 314.8 | 2390 | 1034 | Merk H01 | 2 | Walls | Non-bearing | houten kozijn | 31.10 | houten kozijn | 31.10 | 31.10 | buitenwandopeningen; niet gevuld, algemeen (verzamelniveau) | houten kozijn | Walls | Curtain Wall | Curtain Wall: Merk H01 | Merk H01 | 5121256 | 0 | no | yes | 0 | 400 | 2390 | 2.47126 | 1034 | Bouwkundig | 2. nieuwbouw | Non-bearing | 0 | Beginning | 4 | 2 | Vertical | Pset_wanden - NLRS_C_Geluidwering_DnTA: 33; Pset_kozijnen (CW) - NLRS_C_Geluidwering_DnTA: 33; Data - NLRS_C_Geluidwering_DnTA: 33; Materials and Finishes - NLRS_C_Afwerking Kozijn: Ral 9010 - Deur HPL Formica F2296 Sno White; Group: Model Group:WC_V0:4976980
Basic Wall:43_DAT_Wandtegelwerk:5949479 | 00 Begane grond | 42.12 Uniformat (Uniformat) | 314.8 | 1190 | 600 | Merk H05 | 2 | Walls | Non-bearing | houten kozijn | 31.10 | houten kozijn | 31.10 | 31.10 | buitenwandopeningen; niet gevuld, algemeen (verzamelniveau) | houten kozijn | Walls | Curtain Wall | Curtain Wall: Merk H05 | Merk H05 | 5132093 | 1200 | no | yes | 0 | 400 | 1190 | 0.714 | 600 | Bouwkundig | 2. nieuwbouw | Non-bearing | 0 | Beginning | 4 | 2 | Vertical | Pset_wanden - NLRS_C_Geluidwering_DnTA: 39; Pset_kozijnen (CW) - NLRS_C_Geluidwering_DnTA: 39; Data - NLRS_C_Geluidwering_DnTA: 39; Materials and Finishes - NLRS_C_Afwerking Kozijn: Ral 9010 - Deur HPL Formica F2296 Sno White; Group: Model Group:WC_V0:4976980
Basic Wall:43_DAT_Wandtegelwerk:5949988 | 00 Begane grond | 42.12 Uniformat (Uniformat) | 314.8 | 2390 | 1034 | Merk H01 | 2 | Walls | Non-bearing | houten kozijn | 31.10 | houten kozijn | 31.10 | 31.10 | buitenwandopeningen; niet gevuld, algemeen (verzamelniveau) | houten kozijn | Walls | Curtain Wall | Curtain Wall: Merk H01 | Merk H01 | 5121256 | 0 | no | yes | 0 | 400 | 2390 | 2.47126 | 1034 | Bouwkundig | 2. nieuwbouw | Non-bearing | 0 | Beginning | 4 | 2 | Vertical | Pset_wanden - NLRS_C_Geluidwering_DnTA: 33; Pset_kozijnen (CW) - NLRS_C_Geluidwering_DnTA: 33; Data - NLRS_C_Geluidwering_DnTA: 33; Materials and Finishes - NLRS_C_Afwerking Kozijn: Ral 9010 - Deur HPL Formica F2296 Sno White; Group: Model Group:WC_V0:4977293
Basic Wall:43_DAT_Wandtegelwerk:5949990 | 00 Begane grond | 42.12 Uniformat (Uniformat) | 314.8 | 1190 | 600 | Merk H05 | 2 | Walls | Non-bearing | houten kozijn | 31.10 | houten kozijn | 31.10 | 31.10 | buitenwandopeningen; niet gevuld, algemeen (verzamelniveau) | houten kozijn | Walls | Curtain Wall | Curtain Wall: Merk H05 | Merk H05 | 5132093 | 1200 | no | yes | 0 | 400 | 1190 | 0.714 | 600 | Bouwkundig | 2. nieuwbouw | Non-bearing | 0 | Beginning | 4 | 2 | Vertical | Pset_wanden - NLRS_C_Geluidwering_DnTA: 39; Pset_kozijnen (CW) - NLRS_C_Geluidwering_DnTA: 39; Data - NLRS_C_Geluidwering_DnTA: 39; Materials and Finishes - NLRS_C_Afwerking Kozijn: Ral 9010 - Deur HPL Formica F2296 Sno White; Group: Model Group:WC_V0:4977293
Basic Wall:43_DAT_Wandtegelwerk:5949995 | 00 Begane grond | 42.12 Uniformat (Uniformat) | 314.8 | 2390 | 1034 | Merk H01 | 2 | Walls | Non-bearing | houten kozijn | 31.10 | houten kozijn | 31.10 | 31.10 | buitenwandopeningen; niet gevuld, algemeen (verzamelniveau) | houten kozijn | Walls | Curtain Wall | Curtain Wall: Merk H01 | Merk H01 | 5121256 | 0 | no | yes | 0 | 400 | 2390 | 2.47126 | 1034 | Bouwkundig | 2. nieuwbouw | Non-bearing | 0 | Beginning | 4 | 2 | Vertical | Pset_wanden - NLRS_C_Geluidwering_DnTA: 33; Pset_kozijnen (CW) - NLRS_C_Geluidwering_DnTA: 33; Data - NLRS_C_Geluidwering_DnTA: 33; Materials and Finishes - NLRS_C_Afwerking Kozijn: Ral 9010 - Deur HPL Formica F2296 Sno White; Group: Model Group:WC_V0:4977398
Basic Wall:43_DAT_Wandtegelwerk:5949997 | 00 Begane grond | 42.12 Uniformat (Uniformat) | 314.8 | 1190 | 600 | Merk H05 | 2 | Walls | Non-bearing | houten kozijn | 31.10 | houten kozijn | 31.10 | 31.10 | buitenwandopeningen; niet gevuld, algemeen (verzamelniveau) | houten kozijn | Walls | Curtain Wall | Curtain Wall: Merk H05 | Merk H05 | 5132093 | 1200 | no | yes | 0 | 400 | 1190 | 0.714 | 600 | Bouwkundig | 2. nieuwbouw | Non-bearing | 0 | Beginning | 4 | 2 | Vertical | Pset_wanden - NLRS_C_Geluidwering_DnTA: 39; Pset_kozijnen (CW) - NLRS_C_Geluidwering_DnTA: 39; Data - NLRS_C_Geluidwering_DnTA: 39; Materials and Finishes - NLRS_C_Afwerking Kozijn: Ral 9010 - Deur HPL Formica F2296 Sno White; Group: Model Group:WC_V0:4977398
Basic Wall:43_DAT_Wandtegelwerk:5950002 | 01 eerste verdieping | 42.12 Uniformat (Uniformat) | 314.8 | 2390 | 1034 | Merk H01 | 2 | Walls | Non-bearing | houten kozijn | 31.10 | houten kozijn | 31.10 | 31.10 | buitenwandopeningen; niet gevuld, algemeen (verzamelniveau) | houten kozijn | Walls | Curtain Wall | Curtain Wall: Merk H01 | Merk H01 | 5121256 | 0 | no | yes | 1 | 400 | 2390 | 2.47126 | 1034 | Bouwkundig | 2. nieuwbouw | Non-bearing | 0 | Beginning | 4 | 2 | Vertical | Pset_wanden - NLRS_C_Geluidwering_DnTA: 33; Pset_kozijnen (CW) - NLRS_C_Geluidwering_DnTA: 33; Data - NLRS_C_Geluidwering_DnTA: 33; Materials and Finishes - NLRS_C_Afwerking Kozijn: Ral 9010 - Deur HPL Formica F2296 Sno White; Group: Model Group:WC_V0:5035649
Basic Wall:43_DAT_Wandtegelwerk:5950004 | 01 eerste verdieping | 42.12 Uniformat (Uniformat) | 314.8 | 1190 | 600 | Merk H05 | 2 | Walls | Non-bearing | houten kozijn | 31.10 | houten kozijn | 31.10 | 31.10 | buitenwandopeningen; niet gevuld, algemeen (verzamelniveau) | houten kozijn | Walls | Curtain Wall | Curtain Wall: Merk H05 | Merk H05 | 5132093 | 1200 | no | yes | 1 | 400 | 1190 | 0.714 | 600 | Bouwkundig | 2. nieuwbouw | Non-bearing | 0 | Beginning | 4 | 2 | Vertical | Pset_wanden - NLRS_C_Geluidwering_DnTA: 39; Pset_kozijnen (CW) - NLRS_C_Geluidwering_DnTA: 39; Data - NLRS_C_Geluidwering_DnTA: 39; Materials and Finishes - NLRS_C_Afwerking Kozijn: Ral 9010 - Deur HPL Formica F2296 Sno White; Group: Model Group:WC_V0:5035649
Basic Wall:43_DAT_Wandtegelwerk:5950009 | 01 eerste verdieping | 42.12 Uniformat (Uniformat) | 314.8 | 2390 | 1034 | Merk H01 | 2 | Walls | Non-bearing | houten kozijn | 31.10 | houten kozijn | 31.10 | 31.10 | buitenwandopeningen; niet gevuld, algemeen (verzamelniveau) | houten kozijn | Walls | Curtain Wall | Curtain Wall: Merk H01 | Merk H01 | 5121256 | 0 | no | yes | 1 | 400 | 2390 | 2.47126 | 1034 | Bouwkundig | 2. nieuwbouw | Non-bearing | 0 | Beginning | 4 | 2 | Vertical | Pset_wanden - NLRS_C_Geluidwering_DnTA: 33; Pset_kozijnen (CW) - NLRS_C_Geluidwering_DnTA: 33; Data - NLRS_C_Geluidwering_DnTA: 33; Materials and Finishes - NLRS_C_Afwerking Kozijn: Ral 9010 - Deur HPL Formica F2296 Sno White; Group: Model Group:WC_V0:5035659
Basic Wall:43_DAT_Wandtegelwerk:5950011 | 01 eerste verdieping | 42.12 Uniformat (Uniformat) | 314.8 | 1190 | 600 | Merk H05 | 2 | Walls | Non-bearing | houten kozijn | 31.10 | houten kozijn | 31.10 | 31.10 | buitenwandopeningen; niet gevuld, algemeen (verzamelniveau) | houten kozijn | Walls | Curtain Wall | Curtain Wall: Merk H05 | Merk H05 | 5132093 | 1200 | no | yes | 1 | 400 | 1190 | 0.714 | 600 | Bouwkundig | 2. nieuwbouw | Non-bearing | 0 | Beginning | 4 | 2 | Vertical | Pset_wanden - NLRS_C_Geluidwering_DnTA: 39; Pset_kozijnen (CW) - NLRS_C_Geluidwering_DnTA: 39; Data - NLRS_C_Geluidwering_DnTA: 39; Materials and Finishes - NLRS_C_Afwerking Kozijn: Ral 9010 - Deur HPL Formica F2296 Sno White; Group: Model Group:WC_V0:5035659
Basic Wall:43_DAT_Wandtegelwerk:5950802 | 00 Begane grond | 42.12 Uniformat (Uniformat) | 240 | 790 | 790 | haspel slang 30m gen hxdxb 730x240x790 | 2 | Plumbing Fixtures |  |  |  |  |  | 59.20 |  | brandslanghaspel inbouw | Plumbing Fixtures | NLRS_59_PF_FB_brandslanghaspel inbouw_gen_ISR | NLRS_59_PF_FB_brandslanghaspel inbouw_gen_ISR: haspel slang 30m gen hxdxb 730x240x790 | haspel slang 30m gen hxdxb 730x240x790 | 4687182 |  |  |  |  |  |  | 1.00371 |  | Bouwkundig | 2. nieuwbouw | Constraints - Elevation from Level: 1780 mm; Host: Basic Wall : 22_DAT_binnenwand_125; Level: V-1; Schedule Level: V-1; Dimensions - NLRS_C_breedte: 790 mm; NLRS_C_diepte: 240 mm; NLRS_C_hoogte: 790 mm; Volume: 0.149784 m3; General - NLRS_P_c01_diameter: 22 mm; NLRS_P_c01_radius: 11 mm; Graphics - slang_bereik: no; Identity Data - Mark: 80; Mechanical - brandslanghaspel_kw_flow: 0.361 m3/s; System Classification: Domestic Cold Water
Basic Wall:43_DAT_Wandtegelwerk:5950802 | 00 Begane grond | 42.12 Uniformat (Uniformat) | 314.8 | 2390 | 1034 | Merk H02 | 2 | Walls | Non-bearing | houten kozijn | 31.10 | houten kozijn | 31.10 | 31.10 | buitenwandopeningen; niet gevuld, algemeen (verzamelniveau) | houten kozijn | Walls | Curtain Wall | Curtain Wall: Merk H02 | Merk H02 | 5128107 | 0 | no | yes | 0 | 400 | 2390 | 2.47126 | 1034 | Bouwkundig | 2. nieuwbouw | Non-bearing | 0 | Beginning | 4 | 2 | Vertical | Pset_wanden - NLRS_C_Geluidwering_DnTA: 25; Pset_kozijnen (CW) - NLRS_C_Geluidwering_DnTA: 25; Data - NLRS_C_Geluidwering_DnTA: 25; Materials and Finishes - NLRS_C_Afwerking Kozijn: Ral 9010 - Deur HPL Formica F2296 Sno White
Basic Wall:43_DAT_Wandtegelwerk:5951626 | 00 Begane grond | 42.12 Uniformat (Uniformat) | 314.8 | 2390 | 1034 | Merk H16 | 2 | Walls | Non-bearing | houten kozijn | 31.10 | houten kozijn | 31.10 | 31.10 | buitenwandopeningen; niet gevuld, algemeen (verzamelniveau) | houten kozijn | Walls | Curtain Wall | Curtain Wall: Merk H16 | Merk H16 | 6103248 | 0 | no | yes | 0 | 400 | 2390 | 2.47126 | 1034 | Bouwkundig | 2. nieuwbouw | Non-bearing | 0 | Beginning | 4 | 2 | Vertical | Pset_wanden - NLRS_C_Geluidwering_DnTA: 34; Pset_kozijnen (CW) - NLRS_C_Geluidwering_DnTA: 34; Kozijnmerk: S; NLRS_C_gespiegeld: S; Data - NLRS_C_Geluidwering_DnTA: 34; NLRS_C_gespiegeld: S; Materials and Finishes - NLRS_C_Afwerking Kozijn: Ral 9010 - Deur HPL Formica F2296 Sno White
Basic Wall:43_DAT_Wandtegelwerk:5952163 | 00 Begane grond | 42.12 Uniformat (Uniformat) | 314.8 | 2390 | 1034 | Merk H16 | 2 | Walls | Non-bearing | houten kozijn | 31.10 | houten kozijn | 31.10 | 31.10 | buitenwandopeningen; niet gevuld, algemeen (verzamelniveau) | houten kozijn | Walls | Curtain Wall | Curtain Wall: Merk H16 | Merk H16 | 6103248 | 0 | no | yes | 0 | 400 | 2390 | 2.47126 | 1034 | Bouwkundig | 2. nieuwbouw | Non-bearing | 0 | Beginning | 4 | 2 | Vertical | Pset_wanden - NLRS_C_Geluidwering_DnTA: 34; Pset_kozijnen (CW) - NLRS_C_Geluidwering_DnTA: 34; Data - NLRS_C_Geluidwering_DnTA: 34; Materials and Finishes - NLRS_C_Afwerking Kozijn: Ral 9010 - Deur HPL Formica F2296 Sno White
2 x Basic Wall:43_DAT_Wandtegelwerk:5952163 | 00 Begane grond | 42.12 Uniformat (Uniformat) | 314.8 | 2390 | 1034 | Merk H01 | 2 | Walls | Non-bearing | houten kozijn | 31.10 | houten kozijn | 31.10 | 31.10 | buitenwandopeningen; niet gevuld, algemeen (verzamelniveau) | houten kozijn | Walls | Curtain Wall | Curtain Wall: Merk H01 | Merk H01 | 5121256 | 0 | no | yes | 0 | 400 | 2390 | 2.47126 | 1034 | Bouwkundig | 2. nieuwbouw | Non-bearing | 0 | Beginning | 4 | 2 | Vertical | Pset_wanden - NLRS_C_Geluidwering_DnTA: 34; Pset_kozijnen (CW) - NLRS_C_Geluidwering_DnTA: 34; Data - NLRS_C_Geluidwering_DnTA: 34; Materials and Finishes - NLRS_C_Afwerking Kozijn: Ral 9010 - Deur HPL Formica F2296 Sno White
Basic Wall:43_DAT_Wandtegelwerk:5952163 | 00 Begane grond | 42.12 Uniformat (Uniformat) | 314.8 | 1190 | 600 | Merk H05 | 2 | Walls | Non-bearing | houten kozijn | 31.10 | houten kozijn | 31.10 | 31.10 | buitenwandopeningen; niet gevuld, algemeen (verzamelniveau) | houten kozijn | Walls | Curtain Wall | Curtain Wall: Merk H05 | Merk H05 | 5132093 | 1200 | no | yes | 0 | 400 | 1190 | 0.714 | 600 | Bouwkundig | 2. nieuwbouw | Non-bearing | 0 | Beginning | 4 | 2 | Vertical | Pset_wanden - NLRS_C_Geluidwering_DnTA: 34; Pset_kozijnen (CW) - NLRS_C_Geluidwering_DnTA: 34; Data - NLRS_C_Geluidwering_DnTA: 34; Materials and Finishes - NLRS_C_Afwerking Kozijn: Ral 9010 - Deur HPL Formica F2296 Sno White
Basic Wall:43_DAT_Wandtegelwerk:5952169 | 00 Begane grond | 42.12 Uniformat (Uniformat) | 314.8 | 2390 | 1034 | Merk H16 | 2 | Walls | Non-bearing | houten kozijn | 31.10 | houten kozijn | 31.10 | 31.10 | buitenwandopeningen; niet gevuld, algemeen (verzamelniveau) | houten kozijn | Walls | Curtain Wall | Curtain Wall: Merk H16 | Merk H16 | 6103248 | 0 | no | yes | 0 | 400 | 2390 | 2.47126 | 1034 | Bouwkundig | 2. nieuwbouw | Non-bearing | 0 | Beginning | 4 | 2 | Vertical | Pset_wanden - NLRS_C_Geluidwering_DnTA: 34; Pset_kozijnen (CW) - NLRS_C_Geluidwering_DnTA: 34; Kozijnmerk: S; NLRS_C_gespiegeld: S; Data - NLRS_C_Geluidwering_DnTA: 34; NLRS_C_gespiegeld: S; Materials and Finishes - NLRS_C_Afwerking Kozijn: Ral 9010 - Deur HPL Formica F2296 Sno White
Basic Wall:43_DAT_Wandtegelwerk:5952169 | 00 Begane grond | 42.12 Uniformat (Uniformat) | 314.8 | 1190 | 600 | Merk H05 | 2 | Walls | Non-bearing | houten kozijn | 31.10 | houten kozijn | 31.10 | 31.10 | buitenwandopeningen; niet gevuld, algemeen (verzamelniveau) | houten kozijn | Walls | Curtain Wall | Curtain Wall: Merk H05 | Merk H05 | 5132093 | 1200 | no | yes | 0 | 400 | 1190 | 0.714 | 600 | Bouwkundig | 2. nieuwbouw | Non-bearing | 0 | Beginning | 4 | 2 | Vertical | Pset_wanden - NLRS_C_Geluidwering_DnTA: 34; Pset_kozijnen (CW) - NLRS_C_Geluidwering_DnTA: 34; Data - NLRS_C_Geluidwering_DnTA: 34; Materials and Finishes - NLRS_C_Afwerking Kozijn: Ral 9010 - Deur HPL Formica F2296 Sno White
Basic Wall:43_DAT_Wandtegelwerk:5952170 | 00 Begane grond | 42.12 Uniformat (Uniformat) | 314.8 | 1190 | 600 | Merk H05 | 2 | Walls | Non-bearing | houten kozijn | 31.10 | houten kozijn | 31.10 | 31.10 | buitenwandopeningen; niet gevuld, algemeen (verzamelniveau) | houten kozijn | Walls | Curtain Wall | Curtain Wall: Merk H05 | Merk H05 | 5132093 | 1200 | no | yes | 0 | 400 | 1190 | 0.714 | 600 | Bouwkundig | 2. nieuwbouw | Non-bearing | 0 | Beginning | 4 | 2 | Vertical | Pset_wanden - NLRS_C_Geluidwering_DnTA: 34; Pset_kozijnen (CW) - NLRS_C_Geluidwering_DnTA: 34; Data - NLRS_C_Geluidwering_DnTA: 34; Materials and Finishes - NLRS_C_Afwerking Kozijn: Ral 9010 - Deur HPL Formica F2296 Sno White
2 x Basic Wall:43_DAT_Wandtegelwerk:5952170 | 00 Begane grond | 42.12 Uniformat (Uniformat) | 314.8 | 2390 | 1034 | Merk H01 | 2 | Walls | Non-bearing | houten kozijn | 31.10 | houten kozijn | 31.10 | 31.10 | buitenwandopeningen; niet gevuld, algemeen (verzamelniveau) | houten kozijn | Walls | Curtain Wall | Curtain Wall: Merk H01 | Merk H01 | 5121256 | 0 | no | yes | 0 | 400 | 2390 | 2.47126 | 1034 | Bouwkundig | 2. nieuwbouw | Non-bearing | 0 | Beginning | 4 | 2 | Vertical | Pset_wanden - NLRS_C_Geluidwering_DnTA: 34; Pset_kozijnen (CW) - NLRS_C_Geluidwering_DnTA: 34; Data - NLRS_C_Geluidwering_DnTA: 34; Materials and Finishes - NLRS_C_Afwerking Kozijn: Ral 9010 - Deur HPL Formica F2296 Sno White
Basic Wall:43_DAT_Wandtegelwerk:5952170 | 00 Begane grond | 42.12 Uniformat (Uniformat) | 314.8 | 2390 | 1034 | Merk H16 | 2 | Walls | Non-bearing | houten kozijn | 31.10 | houten kozijn | 31.10 | 31.10 | buitenwandopeningen; niet gevuld, algemeen (verzamelniveau) | houten kozijn | Walls | Curtain Wall | Curtain Wall: Merk H16 | Merk H16 | 6103248 | 0 | no | yes | 0 | 400 | 2390 | 2.47126 | 1034 | Bouwkundig | 2. nieuwbouw | Non-bearing | 0 | Beginning | 4 | 2 | Vertical | Pset_wanden - NLRS_C_Geluidwering_DnTA: 34; Pset_kozijnen (CW) - NLRS_C_Geluidwering_DnTA: 34; Data - NLRS_C_Geluidwering_DnTA: 34; Materials and Finishes - NLRS_C_Afwerking Kozijn: Ral 9010 - Deur HPL Formica F2296 Sno White
Basic Wall:43_DAT_Wandtegelwerk:5952172 | 00 Begane grond | 42.12 Uniformat (Uniformat) | 314.8 | 1190 | 600 | Merk H05 | 2 | Walls | Non-bearing | houten kozijn | 31.10 | houten kozijn | 31.10 | 31.10 | buitenwandopeningen; niet gevuld, algemeen (verzamelniveau) | houten kozijn | Walls | Curtain Wall | Curtain Wall: Merk H05 | Merk H05 | 5132093 | 1200 | no | yes | 0 | 400 | 1190 | 0.714 | 600 | Bouwkundig | 2. nieuwbouw | Non-bearing | 0 | Beginning | 4 | 2 | Vertical | Pset_wanden - NLRS_C_Geluidwering_DnTA: 34; Pset_kozijnen (CW) - NLRS_C_Geluidwering_DnTA: 34; Data - NLRS_C_Geluidwering_DnTA: 34; Materials and Finishes - NLRS_C_Afwerking Kozijn: Ral 9010 - Deur HPL Formica F2296 Sno White
Basic Wall:43_DAT_Wandtegelwerk:5952172 | 00 Begane grond | 42.12 Uniformat (Uniformat) | 314.8 | 2390 | 1034 | Merk H16 | 2 | Walls | Non-bearing | houten kozijn | 31.10 | houten kozijn | 31.10 | 31.10 | buitenwandopeningen; niet gevuld, algemeen (verzamelniveau) | houten kozijn | Walls | Curtain Wall | Curtain Wall: Merk H16 | Merk H16 | 6103248 | 0 | no | yes | 0 | 400 | 2390 | 2.47126 | 1034 | Bouwkundig | 2. nieuwbouw | Non-bearing | 0 | Beginning | 4 | 2 | Vertical | Pset_wanden - NLRS_C_Geluidwering_DnTA: 34; Pset_kozijnen (CW) - NLRS_C_Geluidwering_DnTA: 34; Kozijnmerk: S; NLRS_C_gespiegeld: S; Data - NLRS_C_Geluidwering_DnTA: 34; NLRS_C_gespiegeld: S; Materials and Finishes - NLRS_C_Afwerking Kozijn: Ral 9010 - Deur HPL Formica F2296 Sno White
Basic Wall:43_DAT_Wandtegelwerk:5952507 | 00 Begane grond | 42.12 Uniformat (Uniformat) | 314.8 | 2390 | 1100 | Merk H19 | 2 | Walls | Non-bearing | houten kozijn | 31.10 | houten kozijn | 31.10 | 31.10 | buitenwandopeningen; niet gevuld, algemeen (verzamelniveau) | houten kozijn | Walls | Curtain Wall | Curtain Wall: Merk H19 | Merk H19 | 6103729 | 0 | no | yes | 0 | 400 | 2390 | 2.629 | 1100 | Bouwkundig | 2. nieuwbouw | Non-bearing | 0 | Beginning | 4 | 2 | Vertical | Pset_wanden - NLRS_C_Geluidwering_DnTA: 34; Pset_kozijnen (CW) - NLRS_C_Geluidwering_DnTA: 34; Data - NLRS_C_Geluidwering_DnTA: 34; Materials and Finishes - NLRS_C_Afwerking Kozijn: Ral 9010 - Deur HPL Formica F2296 Sno White
Basic Wall:43_DAT_Wandtegelwerk:5952787 | 01 eerste verdieping | 42.12 Uniformat (Uniformat) | 314.8 | 1190 | 600 | Merk H05 | 2 | Walls | Non-bearing | houten kozijn | 31.10 | houten kozijn | 31.10 | 31.10 | buitenwandopeningen; niet gevuld, algemeen (verzamelniveau) | houten kozijn | Walls | Curtain Wall | Curtain Wall: Merk H05 | Merk H05 | 5132093 | 1200 | no | yes | 1 | 400 | 1190 | 0.714 | 600 | Bouwkundig | 2. nieuwbouw | Non-bearing | 0 | Beginning | 4 | 2 | Vertical | Pset_wanden - NLRS_C_Geluidwering_DnTA: 25; Pset_kozijnen (CW) - NLRS_C_Geluidwering_DnTA: 25; Data - NLRS_C_Geluidwering_DnTA: 25; Materials and Finishes - NLRS_C_Afwerking Kozijn: Ral 9010 - Deur HPL Formica F2296 Sno White
Basic Wall:43_DAT_Wandtegelwerk:5952830:1 | 01 eerste verdieping | 42.12 Uniformat (Uniformat) |  |  |  | 43_DAT_Wandtegelwerk | 2 | Walls | Non-bearing | Wandtegelwerk | 42.12 |  |  | 42.12 | binnenwandafwerkingen; bekledingen | Wandtegelwerk | Pset_wanden - sets with these values: 2
Basic Wall:43_DAT_Wandtegelwerk:5952858 | 01 eerste verdieping | 42.12 Uniformat (Uniformat) | 314.8 | 2390 | 1034 | Merk H01 | 2 | Walls | Non-bearing | houten kozijn | 31.10 | houten kozijn | 31.10 | 31.10 | buitenwandopeningen; niet gevuld, algemeen (verzamelniveau) | houten kozijn | Walls | Curtain Wall | Curtain Wall: Merk H01 | Merk H01 | 5121256 | 0 | no | yes | 1 | 400 | 2390 | 2.47126 | 1034 | Bouwkundig | 2. nieuwbouw | Non-bearing | 0 | Beginning | 4 | 2 | Vertical | Pset_wanden - NLRS_C_Geluidwering_DnTA: 25; Pset_kozijnen (CW) - NLRS_C_Geluidwering_DnTA: 25; Data - NLRS_C_Geluidwering_DnTA: 25; Materials and Finishes - NLRS_C_Afwerking Kozijn: Ral 9010 - Deur HPL Formica F2296 Sno White
Basic Wall:43_DAT_Wandtegelwerk:5953476 | 01 eerste verdieping | 42.12 Uniformat (Uniformat) | 314.8 | 2390 | 1034 | Merk H02 | 2 | Walls | Non-bearing | houten kozijn | 31.10 | houten kozijn | 31.10 | 31.10 | buitenwandopeningen; niet gevuld, algemeen (verzamelniveau) | houten kozijn | Walls | Curtain Wall | Curtain Wall: Merk H02 | Merk H02 | 5128107 | 0 | no | yes | 1 | 400 | 2390 | 2.47126 | 1034 | Bouwkundig | 2. nieuwbouw | Non-bearing | 0 | Beginning | 4 | 2 | Vertical | Pset_wanden - NLRS_C_Geluidwering_DnTA: 25; Pset_kozijnen (CW) - NLRS_C_Geluidwering_DnTA: 25; Data - NLRS_C_Geluidwering_DnTA: 25; Materials and Finishes - NLRS_C_Afwerking Kozijn: Ral 9010 - Deur HPL Formica F2296 Sno White
6 x Basic Wall:21_DAT_isolatie hard_74:5956460 | 00 Begane grond | 21.10 Uniformat (Uniformat) | 374.8 | 1930 | 2040 | K_17 | 2 | Walls | Non-bearing | Kunststof kozijn Gealan Kubus | 31 | Kunststof kozijn Gealan Kubus | 31 | 31 | buitenwandopeningen | Kunststof kozijn Gealan Kubus | Walls | Curtain Wall | Curtain Wall: K_17 | K_17 | 6061266 | 710 | no | yes | 0 | 0 | 1930 | 3.9372 | 2040 | Bouwkundig | 2. nieuwbouw | Non-bearing | 0 | Beginning | 4 | 2 | Vertical | Group: Model Group:K_Raamwerk_16:5542459; Other - Doorvalveilig 1-zijdig: no; Doorvalveilig 2-zijdig: yes; Text - NLRS_C_merk: K01
5 x Basic Wall:21_DAT_isolatie hard_74:5956460 | 00 Begane grond | 21.10 Uniformat (Uniformat) | 374.8 | 1930 | 880 | K_16 | 2 | Walls | Non-bearing | Kunststof kozijn Gealan Kubus | 31 | Kunststof kozijn Gealan Kubus | 31 | 31 | buitenwandopeningen | Kunststof kozijn Gealan Kubus | Walls | Curtain Wall | Curtain Wall: K_16 | K_16 | 6074129 | 710 | no | yes | 0 | 0 | 1930 | 1.6984 | 880 | Bouwkundig | 2. nieuwbouw | Non-bearing | 0 | Beginning | 4 | 2 | Vertical | Group: Model Group:K_Raamwerk_16:5542459; Other - Doorvalveilig 1-zijdig: no; Doorvalveilig 2-zijdig: yes; Text - NLRS_C_merk: K01
6 x Basic Wall:21_DAT_isolatie hard_74:5956464 | 00 Begane grond | 21.10 Uniformat (Uniformat) | 374.8 | 1930 | 2040 | K_17 | 2 | Walls | Non-bearing | Kunststof kozijn Gealan Kubus | 31 | Kunststof kozijn Gealan Kubus | 31 | 31 | buitenwandopeningen | Kunststof kozijn Gealan Kubus | Walls | Curtain Wall | Curtain Wall: K_17 | K_17 | 6061266 | 710 | no | yes | 0 | 0 | 1930 | 3.9372 | 2040 | Bouwkundig | 2. nieuwbouw | Non-bearing | 0 | Beginning | 4 | 2 | Vertical | Group: Model Group:K_Raamwerk_16:5544033; Other - Doorvalveilig 1-zijdig: no; Doorvalveilig 2-zijdig: yes; Text - NLRS_C_merk: K01
5 x Basic Wall:21_DAT_isolatie hard_74:5956464 | 00 Begane grond | 21.10 Uniformat (Uniformat) | 374.8 | 1930 | 880 | K_16 | 2 | Walls | Non-bearing | Kunststof kozijn Gealan Kubus | 31 | Kunststof kozijn Gealan Kubus | 31 | 31 | buitenwandopeningen | Kunststof kozijn Gealan Kubus | Walls | Curtain Wall | Curtain Wall: K_16 | K_16 | 6074129 | 710 | no | yes | 0 | 0 | 1930 | 1.6984 | 880 | Bouwkundig | 2. nieuwbouw | Non-bearing | 0 | Beginning | 4 | 2 | Vertical | Group: Model Group:K_Raamwerk_16:5544033; Other - Doorvalveilig 1-zijdig: no; Doorvalveilig 2-zijdig: yes; Text - NLRS_C_merk: K01
6 x Basic Wall:21_DAT_isolatie hard_74:5956466 | 00 Begane grond | 21.10 Uniformat (Uniformat) | 374.8 | 1930 | 2040 | K_17 | 2 | Walls | Non-bearing | Kunststof kozijn Gealan Kubus | 31 | Kunststof kozijn Gealan Kubus | 31 | 31 | buitenwandopeningen | Kunststof kozijn Gealan Kubus | Walls | Curtain Wall | Curtain Wall: K_17 | K_17 | 6061266 | 710 | no | yes | 0 | 0 | 1930 | 3.9372 | 2040 | Bouwkundig | 2. nieuwbouw | Non-bearing | 0 | Beginning | 4 | 2 | Vertical | Group: Model Group:K_Raamwerk_16:5544055; Other - Doorvalveilig 1-zijdig: no; Doorvalveilig 2-zijdig: yes; Text - NLRS_C_merk: K01
5 x Basic Wall:21_DAT_isolatie hard_74:5956466 | 00 Begane grond | 21.10 Uniformat (Uniformat) | 374.8 | 1930 | 880 | K_16 | 2 | Walls | Non-bearing | Kunststof kozijn Gealan Kubus | 31 | Kunststof kozijn Gealan Kubus | 31 | 31 | buitenwandopeningen | Kunststof kozijn Gealan Kubus | Walls | Curtain Wall | Curtain Wall: K_16 | K_16 | 6074129 | 710 | no | yes | 0 | 0 | 1930 | 1.6984 | 880 | Bouwkundig | 2. nieuwbouw | Non-bearing | 0 | Beginning | 4 | 2 | Vertical | Group: Model Group:K_Raamwerk_16:5544055; Other - Doorvalveilig 1-zijdig: no; Doorvalveilig 2-zijdig: yes; Text - NLRS_C_merk: K01
6 x Basic Wall:21_DAT_isolatie hard_74:5956468 | 00 Begane grond | 21.10 Uniformat (Uniformat) | 374.8 | 1930 | 2040 | K_17 | 2 | Walls | Non-bearing | Kunststof kozijn Gealan Kubus | 31 | Kunststof kozijn Gealan Kubus | 31 | 31 | buitenwandopeningen | Kunststof kozijn Gealan Kubus | Walls | Curtain Wall | Curtain Wall: K_17 | K_17 | 6061266 | 710 | no | yes | 0 | 0 | 1930 | 3.9372 | 2040 | Bouwkundig | 2. nieuwbouw | Non-bearing | 0 | Beginning | 4 | 2 | Vertical | Group: Model Group:K_Raamwerk_16:5544106; Other - Doorvalveilig 1-zijdig: no; Doorvalveilig 2-zijdig: yes; Text - NLRS_C_merk: K01
5 x Basic Wall:21_DAT_isolatie hard_74:5956468 | 00 Begane grond | 21.10 Uniformat (Uniformat) | 374.8 | 1930 | 880 | K_16 | 2 | Walls | Non-bearing | Kunststof kozijn Gealan Kubus | 31 | Kunststof kozijn Gealan Kubus | 31 | 31 | buitenwandopeningen | Kunststof kozijn Gealan Kubus | Walls | Curtain Wall | Curtain Wall: K_16 | K_16 | 6074129 | 710 | no | yes | 0 | 0 | 1930 | 1.6984 | 880 | Bouwkundig | 2. nieuwbouw | Non-bearing | 0 | Beginning | 4 | 2 | Vertical | Group: Model Group:K_Raamwerk_16:5544106; Other - Doorvalveilig 1-zijdig: no; Doorvalveilig 2-zijdig: yes; Text - NLRS_C_merk: K01
6 x Basic Wall:21_DAT_isolatie hard_74:5956470 | 00 Begane grond | 21.10 Uniformat (Uniformat) | 374.8 | 1930 | 2040 | K_17 | 2 | Walls | Non-bearing | Kunststof kozijn Gealan Kubus | 31 | Kunststof kozijn Gealan Kubus | 31 | 31 | buitenwandopeningen | Kunststof kozijn Gealan Kubus | Walls | Curtain Wall | Curtain Wall: K_17 | K_17 | 6061266 | 710 | no | yes | 0 | 0 | 1930 | 3.9372 | 2040 | Bouwkundig | 2. nieuwbouw | Non-bearing | 0 | Beginning | 4 | 2 | Vertical | Group: Model Group:K_Raamwerk_16:5544132; Other - Doorvalveilig 1-zijdig: no; Doorvalveilig 2-zijdig: yes; Text - NLRS_C_merk: K01
5 x Basic Wall:21_DAT_isolatie hard_74:5956470 | 00 Begane grond | 21.10 Uniformat (Uniformat) | 374.8 | 1930 | 880 | K_16 | 2 | Walls | Non-bearing | Kunststof kozijn Gealan Kubus | 31 | Kunststof kozijn Gealan Kubus | 31 | 31 | buitenwandopeningen | Kunststof kozijn Gealan Kubus | Walls | Curtain Wall | Curtain Wall: K_16 | K_16 | 6074129 | 710 | no | yes | 0 | 0 | 1930 | 1.6984 | 880 | Bouwkundig | 2. nieuwbouw | Non-bearing | 0 | Beginning | 4 | 2 | Vertical | Group: Model Group:K_Raamwerk_16:5544132; Other - Doorvalveilig 1-zijdig: no; Doorvalveilig 2-zijdig: yes; Text - NLRS_C_merk: K01
3 x Basic Wall:21_DAT_isolatie hard_74:5956472 | 00 Begane grond | 21.10 Uniformat (Uniformat) | 374.8 | 1930 | 2040 | K_17 | 2 | Walls | Non-bearing | Kunststof kozijn Gealan Kubus | 31 | Kunststof kozijn Gealan Kubus | 31 | 31 | buitenwandopeningen | Kunststof kozijn Gealan Kubus | Walls | Curtain Wall | Curtain Wall: K_17 | K_17 | 6061266 | 710 | no | yes | 0 | 0 | 1930 | 3.9372 | 2040 | Bouwkundig | 2. nieuwbouw | Non-bearing | 0 | Beginning | 4 | 2 | Vertical | Group: Model Group:K_Raamwerk_16:5544804; Other - Doorvalveilig 1-zijdig: no; Doorvalveilig 2-zijdig: yes; Text - NLRS_C_merk: K01
4 x Basic Wall:21_DAT_isolatie hard_74:5956472 | 00 Begane grond | 21.10 Uniformat (Uniformat) | 374.8 | 1930 | 880 | K_16 | 2 | Walls | Non-bearing | Kunststof kozijn Gealan Kubus | 31 | Kunststof kozijn Gealan Kubus | 31 | 31 | buitenwandopeningen | Kunststof kozijn Gealan Kubus | Walls | Curtain Wall | Curtain Wall: K_16 | K_16 | 6074129 | 710 | no | yes | 0 | 0 | 1930 | 1.6984 | 880 | Bouwkundig | 2. nieuwbouw | Non-bearing | 0 | Beginning | 4 | 2 | Vertical | Group: Model Group:K_Raamwerk_16:5544804; Other - Doorvalveilig 1-zijdig: no; Doorvalveilig 2-zijdig: yes; Text - NLRS_C_merk: K01
3 x Basic Wall:21_DAT_isolatie hard_74:5956474 | 00 Begane grond | 21.10 Uniformat (Uniformat) | 374.8 | 1930 | 2040 | K_17 | 2 | Walls | Non-bearing | Kunststof kozijn Gealan Kubus | 31 | Kunststof kozijn Gealan Kubus | 31 | 31 | buitenwandopeningen | Kunststof kozijn Gealan Kubus | Walls | Curtain Wall | Curtain Wall: K_17 | K_17 | 6061266 | 710 | no | yes | 0 | 0 | 1930 | 3.9372 | 2040 | Bouwkundig | 2. nieuwbouw | Non-bearing | 0 | Beginning | 4 | 2 | Vertical | Group: Model Group:K_Raamwerk_16:5544822; Other - Doorvalveilig 1-zijdig: no; Doorvalveilig 2-zijdig: yes; Text - NLRS_C_merk: K01
4 x Basic Wall:21_DAT_isolatie hard_74:5956474 | 00 Begane grond | 21.10 Uniformat (Uniformat) | 374.8 | 1930 | 880 | K_16 | 2 | Walls | Non-bearing | Kunststof kozijn Gealan Kubus | 31 | Kunststof kozijn Gealan Kubus | 31 | 31 | buitenwandopeningen | Kunststof kozijn Gealan Kubus | Walls | Curtain Wall | Curtain Wall: K_16 | K_16 | 6074129 | 710 | no | yes | 0 | 0 | 1930 | 1.6984 | 880 | Bouwkundig | 2. nieuwbouw | Non-bearing | 0 | Beginning | 4 | 2 | Vertical | Group: Model Group:K_Raamwerk_16:5544822; Other - Doorvalveilig 1-zijdig: no; Doorvalveilig 2-zijdig: yes; Text - NLRS_C_merk: K01
Basic Wall:21_DAT_isolatie hard_74:5956476 | 00 Begane grond | 21.10 Uniformat (Uniformat) | 374.8 | 1930 | 880 | K_16 | 2 | Walls | Non-bearing | Kunststof kozijn Gealan Kubus | 31 | Kunststof kozijn Gealan Kubus | 31 | 31 | buitenwandopeningen | Kunststof kozijn Gealan Kubus | Walls | Curtain Wall | Curtain Wall: K_16 | K_16 | 6074129 | 710 | no | yes | 0 | 0 | 1930 | 1.6984 | 880 | Bouwkundig | 2. nieuwbouw | Non-bearing | 0 | Beginning | 4 | 2 | Vertical | Group: Model Group:K_Raamwerk_16:5545033; Other - Doorvalveilig 1-zijdig: no; Doorvalveilig 2-zijdig: yes; Text - NLRS_C_merk: K01
Basic Wall:21_DAT_isolatie hard_74:5956478 | 00 Begane grond | 21.10 Uniformat (Uniformat) | 374.8 | 1930 | 880 | K_31 | 2 | Walls | Non-bearing | Kunststof kozijn Gealan Kubus | 31 | Kunststof kozijn Gealan Kubus | 31 | 31 | buitenwandopeningen | Kunststof kozijn Gealan Kubus | Walls | Curtain Wall | Curtain Wall: K_31 | K_31 | 6069143 | 780 | no | yes | V0 bk. ruwe vloer | 0 | 1930 | 1.6984 | 880 | Bouwkundig | 2. nieuwbouw | Non-bearing | 0 | Beginning | 4 | 2 | Vertical | Group: Model Group:K_Raamwerk_16:5545106; Other - Doorvalveilig 1-zijdig: no; Doorvalveilig 2-zijdig: yes; Text - NLRS_C_merk: K01
2 x Basic Wall:21_DAT_isolatie hard_74:5956480 | 00 Begane grond | 21.10 Uniformat (Uniformat) | 374.8 | 1930 | 880 | K_16 | 2 | Walls | Non-bearing | Kunststof kozijn Gealan Kubus | 31 | Kunststof kozijn Gealan Kubus | 31 | 31 | buitenwandopeningen | Kunststof kozijn Gealan Kubus | Walls | Curtain Wall | Curtain Wall: K_16 | K_16 | 6074129 | 710 | no | yes | 0 | 0 | 1930 | 1.6984 | 880 | Bouwkundig | 2. nieuwbouw | Non-bearing | 0 | Beginning | 4 | 2 | Vertical | Group: Model Group:K_Raamwerk_16:5545129; Other - Doorvalveilig 1-zijdig: no; Doorvalveilig 2-zijdig: yes; Text - NLRS_C_merk: K01
2 x Basic Wall:21_DAT_isolatie hard_74:5956482 | 00 Begane grond | 21.10 Uniformat (Uniformat) | 374.8 | 1930 | 880 | K_16 | 2 | Walls | Non-bearing | Kunststof kozijn Gealan Kubus | 31 | Kunststof kozijn Gealan Kubus | 31 | 31 | buitenwandopeningen | Kunststof kozijn Gealan Kubus | Walls | Curtain Wall | Curtain Wall: K_16 | K_16 | 6074129 | 710 | no | yes | 0 | 0 | 1930 | 1.6984 | 880 | Bouwkundig | 2. nieuwbouw | Non-bearing | 0 | Beginning | 4 | 2 | Vertical | Other - Doorvalveilig 1-zijdig: no; Doorvalveilig 2-zijdig: yes; Text - NLRS_C_merk: K01
3 x Basic Wall:21_DAT_isolatie hard_74:5956484 | 00 Begane grond | 21.10 Uniformat (Uniformat) | 374.8 | 1930 | 2040 | K_17 | 2 | Walls | Non-bearing | Kunststof kozijn Gealan Kubus | 31 | Kunststof kozijn Gealan Kubus | 31 | 31 | buitenwandopeningen | Kunststof kozijn Gealan Kubus | Walls | Curtain Wall | Curtain Wall: K_17 | K_17 | 6061266 | 710 | no | yes | 0 | 0 | 1930 | 3.9372 | 2040 | Bouwkundig | 2. nieuwbouw | Non-bearing | 0 | Beginning | 4 | 2 | Vertical | Group: Model Group:K_Raamwerk_16:5856137; Other - Doorvalveilig 1-zijdig: no; Doorvalveilig 2-zijdig: yes; Text - NLRS_C_merk: K01
4 x Basic Wall:21_DAT_isolatie hard_74:5956484 | 00 Begane grond | 21.10 Uniformat (Uniformat) | 374.8 | 1930 | 880 | K_16 | 2 | Walls | Non-bearing | Kunststof kozijn Gealan Kubus | 31 | Kunststof kozijn Gealan Kubus | 31 | 31 | buitenwandopeningen | Kunststof kozijn Gealan Kubus | Walls | Curtain Wall | Curtain Wall: K_16 | K_16 | 6074129 | 710 | no | yes | 0 | 0 | 1930 | 1.6984 | 880 | Bouwkundig | 2. nieuwbouw | Non-bearing | 0 | Beginning | 4 | 2 | Vertical | Group: Model Group:K_Raamwerk_16:5856137; Other - Doorvalveilig 1-zijdig: no; Doorvalveilig 2-zijdig: yes; Text - NLRS_C_merk: K01
3 x Basic Wall:21_DAT_isolatie hard_74:5956486 | 00 Begane grond | 21.10 Uniformat (Uniformat) | 374.8 | 1930 | 2040 | K_17 | 2 | Walls | Non-bearing | Kunststof kozijn Gealan Kubus | 31 | Kunststof kozijn Gealan Kubus | 31 | 31 | buitenwandopeningen | Kunststof kozijn Gealan Kubus | Walls | Curtain Wall | Curtain Wall: K_17 | K_17 | 6061266 | 710 | no | yes | 0 | 0 | 1930 | 3.9372 | 2040 | Bouwkundig | 2. nieuwbouw | Non-bearing | 0 | Beginning | 4 | 2 | Vertical | Group: Model Group:K_Raamwerk_16:5856140; Other - Doorvalveilig 1-zijdig: no; Doorvalveilig 2-zijdig: yes; Text - NLRS_C_merk: K01
4 x Basic Wall:21_DAT_isolatie hard_74:5956486 | 00 Begane grond | 21.10 Uniformat (Uniformat) | 374.8 | 1930 | 880 | K_16 | 2 | Walls | Non-bearing | Kunststof kozijn Gealan Kubus | 31 | Kunststof kozijn Gealan Kubus | 31 | 31 | buitenwandopeningen | Kunststof kozijn Gealan Kubus | Walls | Curtain Wall | Curtain Wall: K_16 | K_16 | 6074129 | 710 | no | yes | 0 | 0 | 1930 | 1.6984 | 880 | Bouwkundig | 2. nieuwbouw | Non-bearing | 0 | Beginning | 4 | 2 | Vertical | Group: Model Group:K_Raamwerk_16:5856140; Other - Doorvalveilig 1-zijdig: no; Doorvalveilig 2-zijdig: yes; Text - NLRS_C_merk: K01
Basic Wall:21_DAT_isolatie hard_74:5958055 | 01 eerste verdieping | 21.10 Uniformat (Uniformat) | 374.8 | 1930 | 1145 | K_25 | 2 | Walls | Non-bearing | Kunststof kozijn Gealan Kubus | 31 | Kunststof kozijn Gealan Kubus | 31 | 31 | buitenwandopeningen | Kunststof kozijn Gealan Kubus | Walls | Curtain Wall | Curtain Wall: K_25 | K_25 | 4942169 | 810 | no | yes | 1 | 0 | 1930 | 2.20985 | 1145 | Bouwkundig | 2. nieuwbouw | Non-bearing | 0 | Beginning | 4 | 2 | Vertical | Other - Doorvalveilig 1-zijdig: no; Doorvalveilig 2-zijdig: yes; Text - NLRS_C_merk: K01
2 x Basic Wall:21_DAT_isolatie hard_74:5958472 | 01 eerste verdieping | 21.10 Uniformat (Uniformat) | 374.8 | 1930 | 2250 | K_32 | 2 | Walls | Non-bearing | Kunststof kozijn Gealan Kubus | 31 | Kunststof kozijn Gealan Kubus | 31 | 31 | buitenwandopeningen | Kunststof kozijn Gealan Kubus | Walls | Curtain Wall | Curtain Wall: K_32 | K_32 | 6474551 | 810 | no | yes | 1 | 0 | 1930 | 4.3425 | 2250 | Bouwkundig | 2. nieuwbouw | Non-bearing | 0 | Beginning | 4 | 2 | Vertical | Other - Doorvalveilig 1-zijdig: no; Doorvalveilig 2-zijdig: yes; Text - NLRS_C_merk: K01
9 x Basic Wall:21_DAT_isolatie hard_74:5958472 | 01 eerste verdieping | 21.10 Uniformat (Uniformat) | 374.8 | 1930 | 790 | K_29 | 2 | Walls | Non-bearing | Kunststof kozijn Gealan Kubus | 31 | Kunststof kozijn Gealan Kubus | 31 | 31 | buitenwandopeningen | Kunststof kozijn Gealan Kubus | Walls | Curtain Wall | Curtain Wall: K_29 | K_29 | 4860879 | 810 | no | yes | 1 | 0 | 1930 | 1.5247 | 790 | Bouwkundig | 2. nieuwbouw | Non-bearing | 0 | Beginning | 4 | 2 | Vertical | Other - Doorvalveilig 1-zijdig: no; Doorvalveilig 2-zijdig: yes; Text - NLRS_C_merk: K01
6 x Basic Wall:21_DAT_isolatie hard_74:5958472 | 01 eerste verdieping | 21.10 Uniformat (Uniformat) | 374.8 | 1930 | 2250 | K_22 | 2 | Walls | Non-bearing | Kunststof kozijn Gealan Kubus | 31 | Kunststof kozijn Gealan Kubus | 31 | 31 | buitenwandopeningen | Kunststof kozijn Gealan Kubus | Walls | Curtain Wall | Curtain Wall: K_22 | K_22 | 4917986 | 810 | no | yes | 1 | 0 | 1930 | 4.3425 | 2250 | Bouwkundig | 2. nieuwbouw | Non-bearing | 0 | Beginning | 4 | 2 | Vertical | Other - Doorvalveilig 1-zijdig: no; Doorvalveilig 2-zijdig: yes; Text - NLRS_C_merk: K01
Basic Wall:21_DAT_isolatie hard_74:5958472 | 01 eerste verdieping | 21.10 Uniformat (Uniformat) | 374.8 | 2760 | 3450 | K_27 | 2 | Walls | Non-bearing | Kunststof kozijn Gealan Kubus | 31 | Kunststof kozijn Gealan Kubus | 31 | 31 | buitenwandopeningen | Kunststof kozijn Gealan Kubus | Walls | Curtain Wall | Curtain Wall: K_27 | K_27 | 4952631 | -20 | no | yes | 1 | 0 | 2760 | 9.522 | 3450 | Bouwkundig | 2. nieuwbouw | Non-bearing | 0 | Beginning | 4 | 2 | Vertical | Other - Doorvalveilig 1-zijdig: no; Doorvalveilig 2-zijdig: yes; Text - NLRS_C_merk: K01
Basic Wall:21_DAT_isolatie hard_74:5958472 | 01 eerste verdieping | 21.10 Uniformat (Uniformat) | 374.8 | 2760 | 1495 | K_26 | 2 | Walls | Non-bearing | Kunststof kozijn Gealan Kubus | 31 | Kunststof kozijn Gealan Kubus | 31 | 31 | buitenwandopeningen | Kunststof kozijn Gealan Kubus | Walls | Curtain Wall | Curtain Wall: K_26 | K_26 | 4951884 | -20 | no | yes | 1 | 0 | 2760 | 4.1262 | 1495 | Bouwkundig | 2. nieuwbouw | Non-bearing | 0 | Beginning | 4 | 2 | Vertical | Other - Doorvalveilig 1-zijdig: no; Doorvalveilig 2-zijdig: yes; Text - NLRS_C_merk: K01
Basic Wall:21_DAT_isolatie hard_74:5959449 | 01 eerste verdieping | 21.10 Uniformat (Uniformat) | 374.8 | 1930 | 790 | K_30 | 2 | Walls | Non-bearing | Kunststof kozijn Gealan Kubus | 31 | Kunststof kozijn Gealan Kubus | 31 | 31 | buitenwandopeningen | Kunststof kozijn Gealan Kubus | Walls | Curtain Wall | Curtain Wall: K_30 | K_30 | 4942327 | 810 | no | yes | 1 | 0 | 1930 | 1.5247 | 790 | Bouwkundig | 2. nieuwbouw | Non-bearing | 0 | Beginning | 4 | 2 | Vertical | Other - Doorvalveilig 1-zijdig: no; Doorvalveilig 2-zijdig: yes; Text - NLRS_C_merk: K01
9 x Basic Wall:21_DAT_isolatie hard_74:5959449 | 01 eerste verdieping | 21.10 Uniformat (Uniformat) | 374.8 | 1930 | 790 | K_29 | 2 | Walls | Non-bearing | Kunststof kozijn Gealan Kubus | 31 | Kunststof kozijn Gealan Kubus | 31 | 31 | buitenwandopeningen | Kunststof kozijn Gealan Kubus | Walls | Curtain Wall | Curtain Wall: K_29 | K_29 | 4860879 | 810 | no | yes | 1 | 0 | 1930 | 1.5247 | 790 | Bouwkundig | 2. nieuwbouw | Non-bearing | 0 | Beginning | 4 | 2 | Vertical | Other - Doorvalveilig 1-zijdig: no; Doorvalveilig 2-zijdig: yes; Text - NLRS_C_merk: K01
6 x Basic Wall:21_DAT_isolatie hard_74:5959449 | 01 eerste verdieping | 21.10 Uniformat (Uniformat) | 374.8 | 1930 | 2250 | K_22 | 2 | Walls | Non-bearing | Kunststof kozijn Gealan Kubus | 31 | Kunststof kozijn Gealan Kubus | 31 | 31 | buitenwandopeningen | Kunststof kozijn Gealan Kubus | Walls | Curtain Wall | Curtain Wall: K_22 | K_22 | 4917986 | 810 | no | yes | 1 | 0 | 1930 | 4.3425 | 2250 | Bouwkundig | 2. nieuwbouw | Non-bearing | 0 | Beginning | 4 | 2 | Vertical | Other - Doorvalveilig 1-zijdig: no; Doorvalveilig 2-zijdig: yes; Text - NLRS_C_merk: K01
2 x Basic Wall:21_DAT_isolatie hard_74:5959449 | 01 eerste verdieping | 21.10 Uniformat (Uniformat) | 374.8 | 1930 | 2250 | K_32 | 2 | Walls | Non-bearing | Kunststof kozijn Gealan Kubus | 31 | Kunststof kozijn Gealan Kubus | 31 | 31 | buitenwandopeningen | Kunststof kozijn Gealan Kubus | Walls | Curtain Wall | Curtain Wall: K_32 | K_32 | 6474551 | 810 | no | yes | 1 | 0 | 1930 | 4.3425 | 2250 | Bouwkundig | 2. nieuwbouw | Non-bearing | 0 | Beginning | 4 | 2 | Vertical | Other - Doorvalveilig 1-zijdig: no; Doorvalveilig 2-zijdig: yes; Text - NLRS_C_merk: K01
Basic Wall:21_DAT_isolatie hard_74:5959449 | 01 eerste verdieping | 21.10 Uniformat (Uniformat) | 374.8 | 2760 | 3450 | K_27 | 2 | Walls | Non-bearing | Kunststof kozijn Gealan Kubus | 31 | Kunststof kozijn Gealan Kubus | 31 | 31 | buitenwandopeningen | Kunststof kozijn Gealan Kubus | Walls | Curtain Wall | Curtain Wall: K_27 | K_27 | 4952631 | -20 | no | yes | 1 | 0 | 2760 | 9.522 | 3450 | Bouwkundig | 2. nieuwbouw | Non-bearing | 0 | Beginning | 4 | 2 | Vertical | Other - Doorvalveilig 1-zijdig: no; Doorvalveilig 2-zijdig: yes; Text - NLRS_C_merk: K01
Basic Wall:21_DAT_isolatie hard_74:5959449 | 01 eerste verdieping | 21.10 Uniformat (Uniformat) | 374.8 | 2760 | 1495 | K_26 | 2 | Walls | Non-bearing | Kunststof kozijn Gealan Kubus | 31 | Kunststof kozijn Gealan Kubus | 31 | 31 | buitenwandopeningen | Kunststof kozijn Gealan Kubus | Walls | Curtain Wall | Curtain Wall: K_26 | K_26 | 4951884 | -20 | no | yes | 1 | 0 | 2760 | 4.1262 | 1495 | Bouwkundig | 2. nieuwbouw | Non-bearing | 0 | Beginning | 4 | 2 | Vertical | Other - Doorvalveilig 1-zijdig: no; Doorvalveilig 2-zijdig: yes; Text - NLRS_C_merk: K01
Basic Wall:21_DAT_isolatie hard_74:5959957 | 01 eerste verdieping | 21.10 Uniformat (Uniformat) | 374.8 | 1930 | 2064 | K_23 | 2 | Walls | Non-bearing | Kunststof kozijn Gealan Kubus | 31 | Kunststof kozijn Gealan Kubus | 31 | 31 | buitenwandopeningen | Kunststof kozijn Gealan Kubus | Walls | Curtain Wall | Curtain Wall: K_23 | K_23 | 4942408 | 810 | no | yes | 1 | 0 | 1930 | 3.98352 | 2064 | Bouwkundig | 2. nieuwbouw | Non-bearing | 0 | Beginning | 4 | 2 | Vertical | Other - Doorvalveilig 1-zijdig: no; Doorvalveilig 2-zijdig: yes; Text - NLRS_C_merk: K01
Basic Wall:22_DAT_binnenwand_125:5987157 | 01 eerste verdieping | 22.13 Uniformat (Uniformat) | 429.8 | 2390 | 1034 | Merk H02 | 2 | Walls | Non-bearing | houten kozijn | 31.10 | houten kozijn | 31.10 | 31.10 | buitenwandopeningen; niet gevuld, algemeen (verzamelniveau) | houten kozijn | Walls | Curtain Wall | Curtain Wall: Merk H02 | Merk H02 | 5128107 | 0 | no | yes | 1 | 400 | 2390 | 2.47126 | 1034 | Bouwkundig | 2. nieuwbouw | Non-bearing | 0 | Beginning | 4 | 2 | Vertical | Pset_wanden - NLRS_C_Geluidwering_DnTA: 34; Pset_kozijnen (CW) - NLRS_C_Geluidwering_DnTA: 34; Data - NLRS_C_Geluidwering_DnTA: 34; Materials and Finishes - NLRS_C_Afwerking Kozijn: Ral 9010 - Deur HPL Formica F2296 Sno White
Basic Wall:22_DAT_binnenwand_125:5987157 | 01 eerste verdieping | 22.13 Uniformat (Uniformat) | 429.8 | 2390 | 1034 | Merk H16 | 2 | Walls | Non-bearing | houten kozijn | 31.10 | houten kozijn | 31.10 | 31.10 | buitenwandopeningen; niet gevuld, algemeen (verzamelniveau) | houten kozijn | Walls | Curtain Wall | Curtain Wall: Merk H16 | Merk H16 | 6103248 | 0 | no | yes | 1 | 400 | 2390 | 2.47126 | 1034 | Bouwkundig | 2. nieuwbouw | Non-bearing | 0 | Beginning | 4 | 2 | Vertical | Pset_wanden - NLRS_C_Geluidwering_DnTA: 34; Pset_kozijnen (CW) - NLRS_C_Geluidwering_DnTA: 34; Data - NLRS_C_Geluidwering_DnTA: 34; Materials and Finishes - NLRS_C_Afwerking Kozijn: Ral 9010 - Deur HPL Formica F2296 Sno White
Basic Wall:22_DAT_binnenwand_125:5987157 | 01 eerste verdieping | 22.13 Uniformat (Uniformat) | 429.8 | 2390 | 1034 | Merk H16 | 2 | Walls | Non-bearing | houten kozijn | 31.10 | houten kozijn | 31.10 | 31.10 | buitenwandopeningen; niet gevuld, algemeen (verzamelniveau) | houten kozijn | Walls | Curtain Wall | Curtain Wall: Merk H16 | Merk H16 | 6103248 | 0 | no | yes | 1 | 400 | 2390 | 2.47126 | 1034 | Bouwkundig | 2. nieuwbouw | Non-bearing | 0 | Beginning | 4 | 2 | Vertical | Pset_wanden - NLRS_C_Geluidwering_DnTA: 34; Pset_kozijnen (CW) - NLRS_C_Geluidwering_DnTA: 34; Kozijnmerk: S; NLRS_C_gespiegeld: S; Data - NLRS_C_Geluidwering_DnTA: 34; NLRS_C_gespiegeld: S; Materials and Finishes - NLRS_C_Afwerking Kozijn: Ral 9010 - Deur HPL Formica F2296 Sno White
Basic Wall:22_DAT_binnenwand_125:5987393 | 01 eerste verdieping | 22.13 Uniformat (Uniformat) | 429.8 | 2390 | 1034 | Merk H02 | 2 | Walls | Non-bearing | houten kozijn | 31.10 | houten kozijn | 31.10 | 31.10 | buitenwandopeningen; niet gevuld, algemeen (verzamelniveau) | houten kozijn | Walls | Curtain Wall | Curtain Wall: Merk H02 | Merk H02 | 5128107 | 0 | no | yes | 1 | 400 | 2390 | 2.47126 | 1034 | Bouwkundig | 2. nieuwbouw | Non-bearing | 0 | Beginning | 4 | 2 | Vertical | Pset_wanden - NLRS_C_Geluidwering_DnTA: 34; Pset_kozijnen (CW) - NLRS_C_Geluidwering_DnTA: 34; Data - NLRS_C_Geluidwering_DnTA: 34; Materials and Finishes - NLRS_C_Afwerking Kozijn: Ral 9010 - Deur HPL Formica F2296 Sno White
Basic Wall:22_DAT_binnenwand_125:5987393 | 01 eerste verdieping | 22.13 Uniformat (Uniformat) | 429.8 | 2390 | 1034 | Merk H02 | 2 | Walls | Non-bearing | houten kozijn | 31.10 | houten kozijn | 31.10 | 31.10 | buitenwandopeningen; niet gevuld, algemeen (verzamelniveau) | houten kozijn | Walls | Curtain Wall | Curtain Wall: Merk H02 | Merk H02 | 5128107 | 0 | no | yes | 1 | 400 | 2390 | 2.47126 | 1034 | Bouwkundig | 2. nieuwbouw | Non-bearing | 0 | Beginning | 4 | 2 | Vertical | Pset_wanden - NLRS_C_Geluidwering_DnTA: 25; Pset_kozijnen (CW) - NLRS_C_Geluidwering_DnTA: 25; Data - NLRS_C_Geluidwering_DnTA: 25; Materials and Finishes - NLRS_C_Afwerking Kozijn: Ral 9010 - Deur HPL Formica F2296 Sno White
Basic Wall:22_DAT_binnenwand_125:589403 | 01 eerste verdieping | 22.13 Uniformat (Uniformat) |  | 2105 | 900 | 22_DAT_binnenwand_125 | 2 | Lines: <Sketch> |  |  |  |  |  |  |  |  |  |  |  |  |  |  |  |  |  |  |  |  | 2105 | Bouwkundig | Pset_ProductRequirements - sets with these values: 2
Basic Wall:22_DAT_binnenwand_125 HPL dubbel:5988144 | 01 eerste verdieping | 22.13 Uniformat (Uniformat) | 429.8 | 2390 | 1134 | Merk H09 | 2 | Walls | Non-bearing | houten kozijn | 31.10 | houten kozijn | 31.10 | 31.10 | buitenwandopeningen; niet gevuld, algemeen (verzamelniveau) | houten kozijn | Walls | Curtain Wall | Curtain Wall: Merk H09 | Merk H09 | 5149044 | 0 | no | yes | 1 | 400 | 2390 | 2.71026 | 1134 | Bouwkundig | 2. nieuwbouw | Non-bearing | 0 | Beginning | 4 | 2 | Vertical | Pset_wanden - NLRS_C_Geluidwering_DnTA: 31; Pset_kozijnen (CW) - NLRS_C_Geluidwering_DnTA: 31; Data - NLRS_C_Geluidwering_DnTA: 31; Materials and Finishes - NLRS_C_Afwerking Kozijn: Kozijn Bamboo - Deur Bamboo
Basic Wall:22_DAT_binnenwand_125 HPL dubbel:5988144 | 01 eerste verdieping | 22.13 Uniformat (Uniformat) | 429.8 | 600 | 2205 | Merk H13 | 2 | Walls | Non-bearing | houten kozijn | 31.10 | houten kozijn | 31.10 | 31.10 | buitenwandopeningen; niet gevuld, algemeen (verzamelniveau) | houten kozijn | Walls | Curtain Wall | Curtain Wall: Merk H13 | Merk H13 | 6102836 | 1200 | no | yes | 1 | 400 | 600 | 1.323 | 2205 | Bouwkundig | 2. nieuwbouw | Non-bearing | 0 | Beginning | 4 | 2 | Vertical | Pset_wanden - NLRS_C_Geluidwering_DnTA: 31; Pset_kozijnen (CW) - NLRS_C_Geluidwering_DnTA: 31; Data - NLRS_C_Geluidwering_DnTA: 31; Materials and Finishes - NLRS_C_Afwerking Kozijn: Kozijn Bamboo - Deur Bamboo
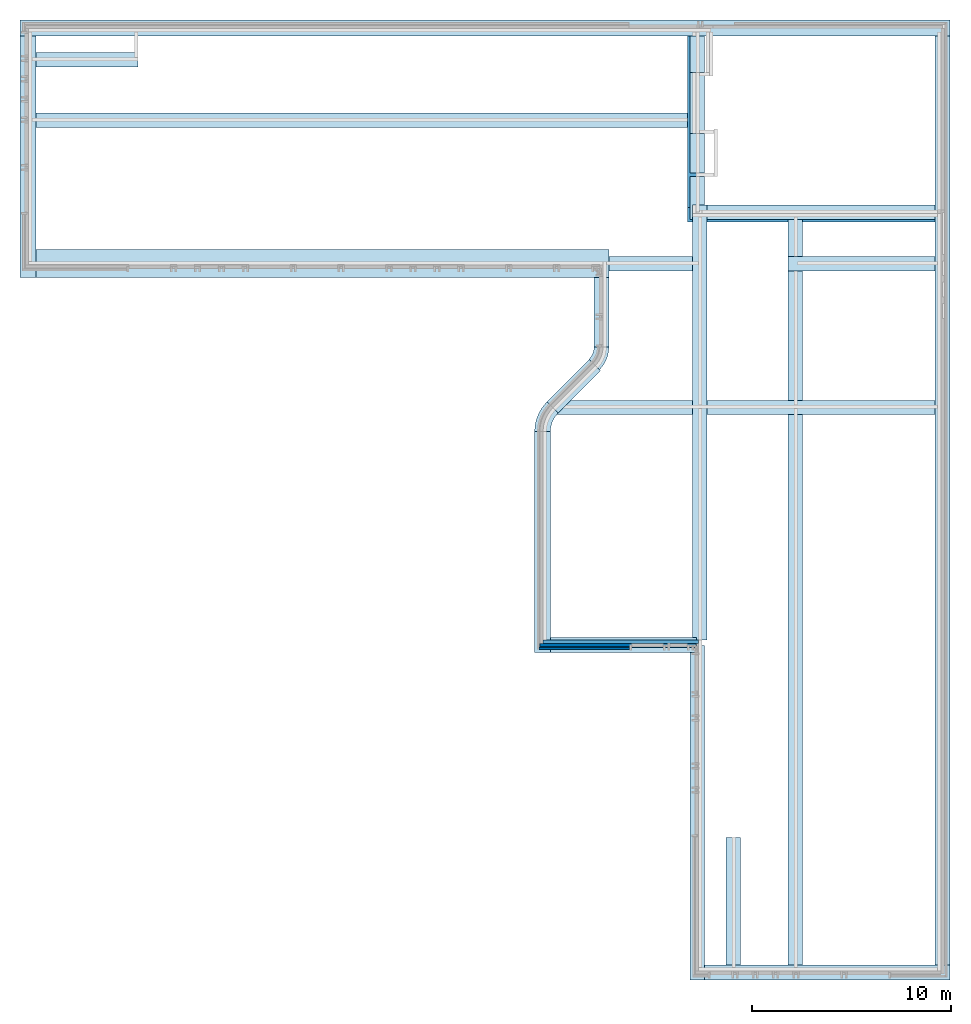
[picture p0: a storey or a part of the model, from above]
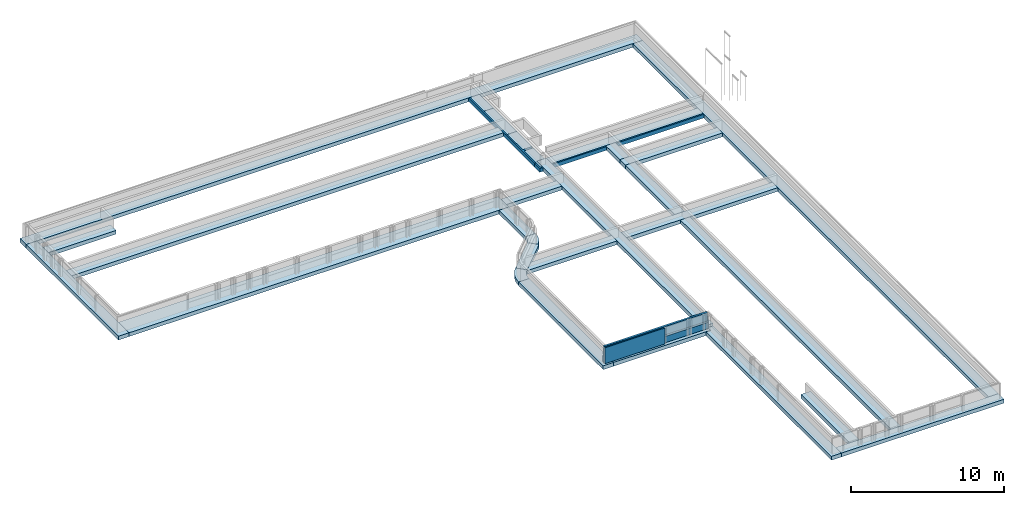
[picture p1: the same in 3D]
Properties of the parts of a building model (IFC2X3), part 26 of 37

# IfcOpeningElement: Opening (1092)
Name | In | Classification | Depth (mm) | BaseQuantities, Height (mm) | BaseQuantities, Width (mm) | Reference | Pset_OpeningElementCommon, sets with these values | Pset_ProductRequirements, Category | Pset_wanden, Structural Usage | Pset_wanden, Omschrijving | Pset_wanden, NL-sfb-Codering | Pset_kozijnen (CW), Omschrijving | Pset_kozijnen (CW), NL-sfb-Codering | Pset_DAT_KMS, Assembly Code | Pset_DAT_KMS, Assembly Description | Pset_DAT_KMS, Description | Other, Category | Family | Other, Family and Type | Type | Type Id | Base Offset (mm) | Base is Attached = Related to Mass = Top is Attached = Structural | Room Bounding | Base Constraint | Top Offset (mm) | Unconnected Height (mm) | Dimensions, Area (m2) | Length (mm) | Identity Data, Workset | Phase Created | Structural, Structural Usage | Angle (deg) = Offset (mm) | Justification | Number | Horizontal Grid, sets with these values | Cross-Section
Basic Wall:22_DAT_binnenwand_125:5994910 | 01 eerste verdieping | 22.13 Uniformat (Uniformat) | 429.8 | 1190 | 600 | Merk H05 | 2 | Walls | Non-bearing | houten kozijn | 31.10 | houten kozijn | 31.10 | 31.10 | buitenwandopeningen; niet gevuld, algemeen (verzamelniveau) | houten kozijn | Walls | Curtain Wall | Curtain Wall: Merk H05 | Merk H05 | 5132093 | 1200 | no | yes | 1 | 400 | 1190 | 0.714 | 600 | Bouwkundig | 2. nieuwbouw | Non-bearing | 0 | Beginning | 4 | 2 | Vertical | Pset_wanden - NLRS_C_Geluidwering_DnTA: 25; Pset_kozijnen (CW) - NLRS_C_Geluidwering_DnTA: 25; Data - NLRS_C_Geluidwering_DnTA: 25; Materials and Finishes - NLRS_C_Afwerking Kozijn: Ral 9010 - Deur HPL Formica F2296 Sno White; Group: Model Group:WC_V0:5994912
Basic Wall:22_DAT_binnenwand_125:5994913 | 01 eerste verdieping | 22.13 Uniformat (Uniformat) | 429.8 | 2390 | 1034 | Merk H01 | 2 | Walls | Non-bearing | houten kozijn | 31.10 | houten kozijn | 31.10 | 31.10 | buitenwandopeningen; niet gevuld, algemeen (verzamelniveau) | houten kozijn | Walls | Curtain Wall | Curtain Wall: Merk H01 | Merk H01 | 5121256 | 0 | no | yes | 1 | 400 | 2390 | 2.47126 | 1034 | Bouwkundig | 2. nieuwbouw | Non-bearing | 0 | Beginning | 4 | 2 | Vertical | Materials and Finishes - NLRS_C_Afwerking Kozijn: Ral 9010 - Deur HPL Formica F2296 Sno White; Group: Model Group:WC_V0:5994912
Basic Wall:43_DAT_Wandtegelwerk:5994944 | 01 eerste verdieping | 42.12 Uniformat (Uniformat) | 314.8 | 2390 | 1034 | Merk H01 | 2 | Walls | Non-bearing | houten kozijn | 31.10 | houten kozijn | 31.10 | 31.10 | buitenwandopeningen; niet gevuld, algemeen (verzamelniveau) | houten kozijn | Walls | Curtain Wall | Curtain Wall: Merk H01 | Merk H01 | 5121256 | 0 | no | yes | 1 | 400 | 2390 | 2.47126 | 1034 | Bouwkundig | 2. nieuwbouw | Non-bearing | 0 | Beginning | 4 | 2 | Vertical | Materials and Finishes - NLRS_C_Afwerking Kozijn: Ral 9010 - Deur HPL Formica F2296 Sno White; Group: Model Group:WC_V0:5994912
Basic Wall:43_DAT_Wandtegelwerk:5994946 | 01 eerste verdieping | 42.12 Uniformat (Uniformat) | 314.8 | 1190 | 600 | Merk H05 | 2 | Walls | Non-bearing | houten kozijn | 31.10 | houten kozijn | 31.10 | 31.10 | buitenwandopeningen; niet gevuld, algemeen (verzamelniveau) | houten kozijn | Walls | Curtain Wall | Curtain Wall: Merk H05 | Merk H05 | 5132093 | 1200 | no | yes | 1 | 400 | 1190 | 0.714 | 600 | Bouwkundig | 2. nieuwbouw | Non-bearing | 0 | Beginning | 4 | 2 | Vertical | Pset_wanden - NLRS_C_Geluidwering_DnTA: 25; Pset_kozijnen (CW) - NLRS_C_Geluidwering_DnTA: 25; Data - NLRS_C_Geluidwering_DnTA: 25; Materials and Finishes - NLRS_C_Afwerking Kozijn: Ral 9010 - Deur HPL Formica F2296 Sno White; Group: Model Group:WC_V0:5994912
Basic Wall:22_DAT_binnenwand_125:5995270 | 01 eerste verdieping | 22.13 Uniformat (Uniformat) | 429.8 | 2390 | 1980 | Merk H07 | 2 | Walls | Non-bearing | houten kozijn | 31.10 | houten kozijn | 31.10 | 31.10 | buitenwandopeningen; niet gevuld, algemeen (verzamelniveau) | houten kozijn | Walls | Curtain Wall | Curtain Wall: Merk H07 | Merk H07 | 5144215 | 0 | no | yes | 1 | 400 | 2390 | 4.7322 | 1980 | Bouwkundig | 2. nieuwbouw | Non-bearing | 0 | Beginning | 4 | 2 | Vertical | Pset_wanden - NLRS_C_Geluidwering_DnTA: 38; Pset_kozijnen (CW) - NLRS_C_Geluidwering_DnTA: 38; Data - NLRS_C_Geluidwering_DnTA: 38; Materials and Finishes - NLRS_C_Afwerking Kozijn: Ral 9010 - Deur HPL Formica F2296 Sno White
8 x Basic Wall:28_DAT_kalkzandsteen_175mm:5997719 | 00 Begane grond | 28.21 Uniformat (Uniformat) | 479.8 | 3310 | 160 | 22_DAT_binnenwand_25 | 2 | Walls | Non-bearing | Lichte scheidingswand 100mm | 22.13 |  |  | 22.13 | binnenwanden; niet constructief, systeemwanden; vast | Lichte scheidingswand 100mm | Walls | Basic Wall | Basic Wall: 22_DAT_binnenwand_25 | 22_DAT_binnenwand_25 | 4977124 | 0 | no | yes | V0 bk. ruwe vloer | 0 | 3310 | 0.5296 | 160 | Bouwkundig | 2. nieuwbouw | Non-bearing |  |  |  |  | Vertical | Dimensions - Volume: 0.01324 m3; Constraints - Base Extension Distance: 0 mm; Top Extension Distance: 0 mm; Location Line: Wall Centerline; Top Constraint: Up to level: V1 ok. ruwe vloer
3 x Basic Wall:28_DAT_kalkzandsteen_175mm:5997719 | 00 Begane grond | 28.21 Uniformat (Uniformat) | 479.8 | 2610 | 2120 | K_03 | 2 | Walls | Non-bearing | Kunststof kozijn Gealan Linear | 31 | Kunststof kozijn Gealan Linear | 31 | 31 | buitenwandopeningen | Kunststof kozijn Gealan Linear | Walls | Curtain Wall | Curtain Wall: K_03 | K_03 | 4793066 | 30 | no | yes | 0 | 0 | 2610 | 5.5332 | 2120 | Bouwkundig | 2. nieuwbouw | Non-bearing | 0 | Beginning | 4 | 2 | Vertical | Other - Doorvalveilig 1-zijdig: no; Doorvalveilig 2-zijdig: yes; Text - NLRS_C_merk: K01
Basic Wall:28_DAT_kalkzandsteen_175mm:5997719 | 00 Begane grond | 28.21 Uniformat (Uniformat) | 479.8 | 2630 | 1635 | K_18 | 2 | Walls | Non-bearing | Kunststof kozijn Gealan Kubus | 31 | Kunststof kozijn Gealan Kubus | 31 | 31 | buitenwandopeningen | Kunststof kozijn Gealan Kubus | Walls | Curtain Wall | Curtain Wall: K_18 | K_18 | 6067594 | 10 | no | yes | 0 | 0 | 2630 | 4.30005 | 1635 | Bouwkundig | 2. nieuwbouw | Non-bearing | 0 | Beginning | 4 | 2 | Vertical | Other - Doorvalveilig 1-zijdig: no; Doorvalveilig 2-zijdig: yes; Text - NLRS_C_merk: K01
3 x Basic Wall:28_DAT_kalkzandsteen_175mm:5997719 | 00 Begane grond | 28.21 Uniformat (Uniformat) | 479.8 | 2630 | 2120 | K_02 | 2 | Walls | Non-bearing | Kunststof kozijn Gealan Kubus | 31 | Kunststof kozijn Gealan Kubus | 31 | 31 | buitenwandopeningen | Kunststof kozijn Gealan Kubus | Walls | Curtain Wall | Curtain Wall: K_02 | K_02 | 4792108 | 10 | no | yes | 0 | 0 | 2630 | 5.5756 | 2120 | Bouwkundig | 2. nieuwbouw | Non-bearing | 0 | Beginning | 4 | 2 | Vertical | Other - Doorvalveilig 1-zijdig: no; Doorvalveilig 2-zijdig: yes; Text - NLRS_C_merk: K01
14 x Basic Wall:28_DAT_kalkzandsteen_175mm:5997719 | 00 Begane grond | 28.21 Uniformat (Uniformat) | 479.8 | 3230 | 60 | 21_DAT_Hekwerk 175 | 2 | Walls | Non-bearing | Samengesteld rekwerkBuitenplaat WBP 10mmHouten stijl- en regelwerk 38x140Minirale wolDampremmendefolieGipsplaat 12.5mmGipsvezelplaat 12,5mm | 21.10 |  |  | 21.10 | buitenwanden; niet constructief, algemeen (verzamelniveau) | Samengesteld rekwerkBuitenplaat WBP 10mmHouten stijl- en regelwerk 38x140Minirale wolDampremmendefolieGipsplaat 12.5mmGipsvezelplaat 12,5mm | Walls | Basic Wall | Basic Wall: 21_DAT_Hekwerk 175 | 21_DAT_Hekwerk 175 | 5435600 | 10 | no | yes | 0 | 0 | 3230 | 0.1938 | 60 | Bouwkundig | 2. nieuwbouw | Non-bearing |  |  |  |  | Vertical | Dimensions - Volume: 0.033915 m3; Constraints - Base Extension Distance: 0 mm; Top Extension Distance: 0 mm; Location Line: Wall Centerline; Top Constraint: Up to level: V1 ok. ruwe vloer; Pset_wanden - sets with these values: 2
3 x Basic Wall:28_DAT_kalkzandsteen_175mm:5997719 | 00 Begane grond | 28.21 Uniformat (Uniformat) | 479.8 | 600 | 2119.94 | 21_DAT_Hekwerk 175 | 2 | Walls | Non-bearing | Samengesteld rekwerkBuitenplaat WBP 10mmHouten stijl- en regelwerk 38x140Minirale wolDampremmendefolieGipsplaat 12.5mmGipsvezelplaat 12,5mm | 21.10 |  |  | 21.10 | buitenwanden; niet constructief, algemeen (verzamelniveau) | Samengesteld rekwerkBuitenplaat WBP 10mmHouten stijl- en regelwerk 38x140Minirale wolDampremmendefolieGipsplaat 12.5mmGipsvezelplaat 12,5mm | Walls | Basic Wall | Basic Wall: 21_DAT_Hekwerk 175 | 21_DAT_Hekwerk 175 | 5435600 | 2710 | no | yes | V0 bk. ruwe vloer | 0 | 600 | 1.27196 | 2119.94 | Bouwkundig | 2. nieuwbouw | Non-bearing |  |  |  |  | Vertical | Dimensions - Volume: 0.222593 m3; Constraints - Base Extension Distance: 0 mm; Top Extension Distance: 0 mm; Location Line: Wall Centerline; Top Constraint: Up to level: V1 ok. ruwe vloer; Pset_wanden - sets with these values: 2
2 x Basic Wall:28_DAT_kalkzandsteen_175mm:5997719 | 00 Begane grond | 28.21 Uniformat (Uniformat) | 479.8 | 3230 | 2120 | 21_DAT_Hekwerk 175 | 2 | Walls | Non-bearing | Samengesteld rekwerkBuitenplaat WBP 10mmHouten stijl- en regelwerk 38x140Minirale wolDampremmendefolieGipsplaat 12.5mmGipsvezelplaat 12,5mm | 21.10 |  |  | 21.10 | buitenwanden; niet constructief, algemeen (verzamelniveau) | Samengesteld rekwerkBuitenplaat WBP 10mmHouten stijl- en regelwerk 38x140Minirale wolDampremmendefolieGipsplaat 12.5mmGipsvezelplaat 12,5mm | Walls | Basic Wall | Basic Wall: 21_DAT_Hekwerk 175 | 21_DAT_Hekwerk 175 | 5435600 | 80 | no | yes | V0 bk. ruwe vloer | 0 | 3230 | 1.3144 | 2120 | Bouwkundig | 2. nieuwbouw | Non-bearing |  |  |  |  | Vertical | Dimensions - Volume: 0.23002 m3; Constraints - Base Extension Distance: 0 mm; Top Extension Distance: 0 mm; Location Line: Wall Centerline; Top Constraint: Up to level: V1 ok. ruwe vloer; Pset_wanden - sets with these values: 2
6 x Basic Wall:28_DAT_kalkzandsteen_175mm:5997719 | 00 Begane grond | 28.21 Uniformat (Uniformat) | 479.8 | 600 | 920 | 21_DAT_Hekwerk 175 | 2 | Walls | Non-bearing | Samengesteld rekwerkBuitenplaat WBP 10mmHouten stijl- en regelwerk 38x140Minirale wolDampremmendefolieGipsplaat 12.5mmGipsvezelplaat 12,5mm | 21.10 |  |  | 21.10 | buitenwanden; niet constructief, algemeen (verzamelniveau) | Samengesteld rekwerkBuitenplaat WBP 10mmHouten stijl- en regelwerk 38x140Minirale wolDampremmendefolieGipsplaat 12.5mmGipsvezelplaat 12,5mm | Walls | Basic Wall | Basic Wall: 21_DAT_Hekwerk 175 | 21_DAT_Hekwerk 175 | 5435600 | 2710 | no | yes | V0 bk. ruwe vloer | 0 | 600 | 0.552 | 920 | Bouwkundig | 2. nieuwbouw | Non-bearing |  |  |  |  | Vertical | Dimensions - Volume: 0.0966 m3; Constraints - Base Extension Distance: 0 mm; Top Extension Distance: 0 mm; Location Line: Wall Centerline; Top Constraint: Up to level: V1 ok. ruwe vloer; Pset_wanden - sets with these values: 2
Basic Wall:28_DAT_kalkzandsteen_175mm:5997719 | 00 Begane grond | 28.21 Uniformat (Uniformat) | 479.8 | 600 | 1635.06 | 21_DAT_Hekwerk 175 | 2 | Walls | Non-bearing | Samengesteld rekwerkBuitenplaat WBP 10mmHouten stijl- en regelwerk 38x140Minirale wolDampremmendefolieGipsplaat 12.5mmGipsvezelplaat 12,5mm | 21.10 |  |  | 21.10 | buitenwanden; niet constructief, algemeen (verzamelniveau) | Samengesteld rekwerkBuitenplaat WBP 10mmHouten stijl- en regelwerk 38x140Minirale wolDampremmendefolieGipsplaat 12.5mmGipsvezelplaat 12,5mm | Walls | Basic Wall | Basic Wall: 21_DAT_Hekwerk 175 | 21_DAT_Hekwerk 175 | 5435600 | 2710 | no | yes | V0 bk. ruwe vloer | 0 | 600 | 0.981038 | 1635.06 | Bouwkundig | 2. nieuwbouw | Non-bearing |  |  |  |  | Vertical | Dimensions - Volume: 0.171682 m3; Constraints - Base Extension Distance: 0 mm; Top Extension Distance: 0 mm; Location Line: Wall Centerline; Top Constraint: Up to level: V1 ok. ruwe vloer; Pset_wanden - sets with these values: 2
6 x Basic Wall:28_DAT_kalkzandsteen_175mm:5997719 | 00 Begane grond | 28.21 Uniformat (Uniformat) | 479.8 | 2680 | 920 | 22_DAT_binnenwand_100 | 2 | Walls | Non-bearing | Lichte scheidingswand 100mm75mm ms wand gevuld met isolatieVulling afhankelijk van gestelde eisen ingeluidsrapportageGipsplaat 12,5mmGipsvezelplaat 12,5mm | 22.13 |  |  | 22.13 | binnenwanden; niet constructief, systeemwanden; vast | Lichte scheidingswand 100mm75mm ms wand gevuld met isolatieVulling afhankelijk van gestelde eisen ingeluidsrapportageGipsplaat 12,5mmGipsvezelplaat 12,5mm | Walls | Basic Wall | Basic Wall: 22_DAT_binnenwand_100 | 22_DAT_binnenwand_100 | 589402 | -40 | no | yes | 0 | -600 | 2680 | 2.4656 | 920 | Bouwkundig | 2. nieuwbouw | Non-bearing |  |  |  |  | Vertical | Dimensions - Volume: 0.24656 m3; Constraints - Base Extension Distance: 0 mm; Top Extension Distance: 0 mm; Location Line: Wall Centerline; Top Constraint: Up to level: V1 ok. ruwe vloer
2 x Basic Wall:21_DAT_wand_HSB_150:5999931 | 00 Begane grond | 21.12 Uniformat (Uniformat) | 479.8 | 3310 | 160 | 22_DAT_binnenwand_25 | 2 | Walls | Non-bearing | Lichte scheidingswand 100mm | 22.13 |  |  | 22.13 | binnenwanden; niet constructief, systeemwanden; vast | Lichte scheidingswand 100mm | Walls | Basic Wall | Basic Wall: 22_DAT_binnenwand_25 | 22_DAT_binnenwand_25 | 4977124 | 0 | no | yes | V0 bk. ruwe vloer | 0 | 3310 | 0.5296 | 160 | Bouwkundig | 2. nieuwbouw | Non-bearing |  |  |  |  | Vertical | Dimensions - Volume: 0.01324 m3; Constraints - Base Extension Distance: 0 mm; Top Extension Distance: 0 mm; Location Line: Wall Centerline; Top Constraint: Up to level: V1 ok. ruwe vloer
Basic Wall:21_DAT_wand_HSB_150:5999931 | 00 Begane grond | 21.12 Uniformat (Uniformat) | 479.8 | 2630 | 2120 | K_02 | 2 | Walls | Non-bearing | Kunststof kozijn Gealan Kubus | 31 | Kunststof kozijn Gealan Kubus | 31 | 31 | buitenwandopeningen | Kunststof kozijn Gealan Kubus | Walls | Curtain Wall | Curtain Wall: K_02 | K_02 | 4792108 | 10 | no | yes | 0 | 0 | 2630 | 5.5756 | 2120 | Bouwkundig | 2. nieuwbouw | Non-bearing | 0 | Beginning | 4 | 2 | Vertical | Other - Doorvalveilig 1-zijdig: no; Doorvalveilig 2-zijdig: yes; Text - NLRS_C_merk: K01
Basic Wall:21_DAT_wand_HSB_150:5999931 | 00 Begane grond | 21.12 Uniformat (Uniformat) | 479.8 | 2630 | 1865 | K_21 | 2 | Walls | Non-bearing | Kunststof kozijn Gealan Kubus | 31 | Kunststof kozijn Gealan Kubus | 31 | 31 | buitenwandopeningen | Kunststof kozijn Gealan Kubus | Walls | Curtain Wall | Curtain Wall: K_21 | K_21 | 5077807 | 10 | no | yes | 0 | 0 | 2630 | 4.90495 | 1865 | Bouwkundig | 2. nieuwbouw | Non-bearing | 0 | Beginning | 4 | 2 | Vertical | Other - Doorvalveilig 1-zijdig: no; Doorvalveilig 2-zijdig: yes; Text - NLRS_C_merk: K01
2 x Basic Wall:21_DAT_wand_HSB_150:5999931 | 00 Begane grond | 21.12 Uniformat (Uniformat) | 479.8 | 2630 | 920 | K_01 | 2 | Walls | Non-bearing | Kunststof kozijn Gealan Kubus | 31 | Kunststof kozijn Gealan Kubus | 31 | 31 | buitenwandopeningen | Kunststof kozijn Gealan Kubus | Walls | Curtain Wall | Curtain Wall: K_01 | K_01 | 4774158 | 10 | no | yes | 0 | 0 | 2630 | 2.4196 | 920 | Bouwkundig | 2. nieuwbouw | Non-bearing | 0 | Beginning | 4 | 2 | Vertical | Other - Doorvalveilig 1-zijdig: no; Doorvalveilig 2-zijdig: yes; Text - NLRS_C_merk: K01
2 x Basic Wall:21_DAT_wand_HSB_150:5999931 | 00 Begane grond | 21.12 Uniformat (Uniformat) | 479.8 | 600 | 920 | 21_DAT_Hekwerk 175 | 2 | Walls | Non-bearing | Samengesteld rekwerkBuitenplaat WBP 10mmHouten stijl- en regelwerk 38x140Minirale wolDampremmendefolieGipsplaat 12.5mmGipsvezelplaat 12,5mm | 21.10 |  |  | 21.10 | buitenwanden; niet constructief, algemeen (verzamelniveau) | Samengesteld rekwerkBuitenplaat WBP 10mmHouten stijl- en regelwerk 38x140Minirale wolDampremmendefolieGipsplaat 12.5mmGipsvezelplaat 12,5mm | Walls | Basic Wall | Basic Wall: 21_DAT_Hekwerk 175 | 21_DAT_Hekwerk 175 | 5435600 | 2710 | no | yes | V0 bk. ruwe vloer | 0 | 600 | 0.552 | 920 | Bouwkundig | 2. nieuwbouw | Non-bearing |  |  |  |  | Vertical | Dimensions - Volume: 0.0966 m3; Constraints - Base Extension Distance: 0 mm; Top Extension Distance: 0 mm; Location Line: Wall Centerline; Top Constraint: Up to level: V1 ok. ruwe vloer; Pset_wanden - sets with these values: 2
Basic Wall:21_DAT_wand_HSB_150:5999931 | 00 Begane grond | 21.12 Uniformat (Uniformat) | 479.8 | 2610 | 2120 | K_03 | 2 | Walls | Non-bearing | Kunststof kozijn Gealan Linear | 31 | Kunststof kozijn Gealan Linear | 31 | 31 | buitenwandopeningen | Kunststof kozijn Gealan Linear | Walls | Curtain Wall | Curtain Wall: K_03 | K_03 | 4793066 | 30 | no | yes | 0 | 0 | 2610 | 5.5332 | 2120 | Bouwkundig | 2. nieuwbouw | Non-bearing | 0 | Beginning | 4 | 2 | Vertical | Other - Doorvalveilig 1-zijdig: no; Doorvalveilig 2-zijdig: yes; Text - NLRS_C_merk: K01
Basic Wall:21_DAT_wand_HSB_150:5999931 | 00 Begane grond | 21.12 Uniformat (Uniformat) | 479.8 | 3230 | 2120 | 21_DAT_Hekwerk 175 | 2 | Walls | Non-bearing | Samengesteld rekwerkBuitenplaat WBP 10mmHouten stijl- en regelwerk 38x140Minirale wolDampremmendefolieGipsplaat 12.5mmGipsvezelplaat 12,5mm | 21.10 |  |  | 21.10 | buitenwanden; niet constructief, algemeen (verzamelniveau) | Samengesteld rekwerkBuitenplaat WBP 10mmHouten stijl- en regelwerk 38x140Minirale wolDampremmendefolieGipsplaat 12.5mmGipsvezelplaat 12,5mm | Walls | Basic Wall | Basic Wall: 21_DAT_Hekwerk 175 | 21_DAT_Hekwerk 175 | 5435600 | 80 | no | yes | V0 bk. ruwe vloer | 0 | 3230 | 1.272 | 2120 | Bouwkundig | 2. nieuwbouw | Non-bearing |  |  |  |  | Vertical | Dimensions - Volume: 0.2226 m3; Constraints - Base Extension Distance: 0 mm; Top Extension Distance: 0 mm; Location Line: Wall Centerline; Top Constraint: Up to level: V1 ok. ruwe vloer; Pset_wanden - sets with these values: 2
Basic Wall:21_DAT_wand_HSB_150:5999931 | 00 Begane grond | 21.12 Uniformat (Uniformat) | 479.8 | 3230 | 2120 | 21_DAT_Hekwerk 175 | 2 | Walls | Non-bearing | Samengesteld rekwerkBuitenplaat WBP 10mmHouten stijl- en regelwerk 38x140Minirale wolDampremmendefolieGipsplaat 12.5mmGipsvezelplaat 12,5mm | 21.10 |  |  | 21.10 | buitenwanden; niet constructief, algemeen (verzamelniveau) | Samengesteld rekwerkBuitenplaat WBP 10mmHouten stijl- en regelwerk 38x140Minirale wolDampremmendefolieGipsplaat 12.5mmGipsvezelplaat 12,5mm | Walls | Basic Wall | Basic Wall: 21_DAT_Hekwerk 175 | 21_DAT_Hekwerk 175 | 5435600 | 80 | no | yes | V0 bk. ruwe vloer | 0 | 3230 | 1.3144 | 2120 | Bouwkundig | 2. nieuwbouw | Non-bearing |  |  |  |  | Vertical | Dimensions - Volume: 0.23002 m3; Constraints - Base Extension Distance: 0 mm; Top Extension Distance: 0 mm; Location Line: Wall Centerline; Top Constraint: Up to level: V1 ok. ruwe vloer; Pset_wanden - sets with these values: 2
4 x Basic Wall:21_DAT_wand_HSB_150:5999931 | 00 Begane grond | 21.12 Uniformat (Uniformat) | 479.8 | 3230 | 60 | 21_DAT_Hekwerk 175 | 2 | Walls | Non-bearing | Samengesteld rekwerkBuitenplaat WBP 10mmHouten stijl- en regelwerk 38x140Minirale wolDampremmendefolieGipsplaat 12.5mmGipsvezelplaat 12,5mm | 21.10 |  |  | 21.10 | buitenwanden; niet constructief, algemeen (verzamelniveau) | Samengesteld rekwerkBuitenplaat WBP 10mmHouten stijl- en regelwerk 38x140Minirale wolDampremmendefolieGipsplaat 12.5mmGipsvezelplaat 12,5mm | Walls | Basic Wall | Basic Wall: 21_DAT_Hekwerk 175 | 21_DAT_Hekwerk 175 | 5435600 | 10 | no | yes | 0 | 0 | 3230 | 0.1938 | 60 | Bouwkundig | 2. nieuwbouw | Non-bearing |  |  |  |  | Vertical | Dimensions - Volume: 0.033915 m3; Constraints - Base Extension Distance: 0 mm; Top Extension Distance: 0 mm; Location Line: Wall Centerline; Top Constraint: Up to level: V1 ok. ruwe vloer; Pset_wanden - sets with these values: 2
Basic Wall:21_DAT_wand_HSB_150:5999931 | 00 Begane grond | 21.12 Uniformat (Uniformat) | 479.8 | 800 | 16430 | 28_DAT_kalkzandsteen_175mm | 2 | Walls | Non-bearing | Kalkzandsteen 175mm | 28.21 |  |  | 28.21 | hoofddraagconstructies; wanden en vloeren, wand-/vloerconstructies | Kalkzandsteen 175mm | Walls | Basic Wall | Basic Wall: 28_DAT_kalkzandsteen_175mm | 28_DAT_kalkzandsteen_175mm | 4741545 | 0 | no | yes | bk. fundering | -140 | 800 | 13.144 | 16430 | Constructie | 2. nieuwbouw | Non-bearing |  |  |  |  | Vertical | Dimensions - Volume: 2.3002 m3; Constraints - Base Extension Distance: 0 mm; Top Extension Distance: 0 mm; Location Line: Finish Face: Exterior; Top Constraint: Up to level: V0 ok. ruwe vloer
Basic Wall:21_DAT_wand_HSB_150:5999931 | 00 Begane grond | 21.12 Uniformat (Uniformat) | 479.8 | 600 | 1865 | 21_DAT_Hekwerk 175 | 2 | Walls | Non-bearing | Samengesteld rekwerkBuitenplaat WBP 10mmHouten stijl- en regelwerk 38x140Minirale wolDampremmendefolieGipsplaat 12.5mmGipsvezelplaat 12,5mm | 21.10 |  |  | 21.10 | buitenwanden; niet constructief, algemeen (verzamelniveau) | Samengesteld rekwerkBuitenplaat WBP 10mmHouten stijl- en regelwerk 38x140Minirale wolDampremmendefolieGipsplaat 12.5mmGipsvezelplaat 12,5mm | Walls | Basic Wall | Basic Wall: 21_DAT_Hekwerk 175 | 21_DAT_Hekwerk 175 | 5435600 | 2710 | no | yes | V0 bk. ruwe vloer | 0 | 600 | 1.119 | 1865 | Bouwkundig | 2. nieuwbouw | Non-bearing |  |  |  |  | Vertical | Dimensions - Volume: 0.195825 m3; Constraints - Base Extension Distance: 0 mm; Top Extension Distance: 0 mm; Location Line: Wall Centerline; Top Constraint: Up to level: V1 ok. ruwe vloer; Pset_wanden - sets with these values: 2
6 x Basic Wall:28_DAT_kalkzandsteen_175mm:6000860 | 00 Begane grond | 28.21 Uniformat (Uniformat) | 479.8 | 2180 | 790 | K_06 | 2 | Walls | Non-bearing | Kunststof kozijn Gealan Kubus | 31 | Kunststof kozijn Gealan Kubus | 31 | 31 | buitenwandopeningen | Kunststof kozijn Gealan Kubus | Walls | Curtain Wall | Curtain Wall: K_06 | K_06 | 4842980 | 710 | no | yes | 0 | 0 | 2180 | 1.7222 | 790 | Bouwkundig | 2. nieuwbouw | Non-bearing | 0 | Beginning | 4 | 2 | Vertical | Other - Doorvalveilig 1-zijdig: no; Doorvalveilig 2-zijdig: yes; Text - NLRS_C_merk: K01
6 x Basic Wall:28_DAT_kalkzandsteen_175mm:6000860 | 00 Begane grond | 28.21 Uniformat (Uniformat) | 479.8 | 350 | 790 | 21_DAT_Hekwerk 175 | 2 | Walls | Non-bearing | Samengesteld rekwerkBuitenplaat WBP 10mmHouten stijl- en regelwerk 38x140Minirale wolDampremmendefolieGipsplaat 12.5mmGipsvezelplaat 12,5mm | 21.10 |  |  | 21.10 | buitenwanden; niet constructief, algemeen (verzamelniveau) | Samengesteld rekwerkBuitenplaat WBP 10mmHouten stijl- en regelwerk 38x140Minirale wolDampremmendefolieGipsplaat 12.5mmGipsvezelplaat 12,5mm | Walls | Basic Wall | Basic Wall: 21_DAT_Hekwerk 175 | 21_DAT_Hekwerk 175 | 5435600 | 2890 | no | yes | 0 | 0 | 350 | 0.2765 | 790 | Bouwkundig | 2. nieuwbouw | Non-bearing |  |  |  |  | Vertical | Dimensions - Volume: 0.0483875 m3; Constraints - Base Extension Distance: 0 mm; Top Extension Distance: 0 mm; Location Line: Wall Centerline; Top Constraint: Up to level: V1 ok. ruwe vloer; Pset_wanden - sets with these values: 2
Basic Wall:28_DAT_kalkzandsteen_175mm:6000860 | 00 Begane grond | 28.21 Uniformat (Uniformat) | 479.8 | 350 | 2300 | 21_DAT_Hekwerk 175 | 2 | Walls | Non-bearing | Samengesteld rekwerkBuitenplaat WBP 10mmHouten stijl- en regelwerk 38x140Minirale wolDampremmendefolieGipsplaat 12.5mmGipsvezelplaat 12,5mm | 21.10 |  |  | 21.10 | buitenwanden; niet constructief, algemeen (verzamelniveau) | Samengesteld rekwerkBuitenplaat WBP 10mmHouten stijl- en regelwerk 38x140Minirale wolDampremmendefolieGipsplaat 12.5mmGipsvezelplaat 12,5mm | Walls | Basic Wall | Basic Wall: 21_DAT_Hekwerk 175 | 21_DAT_Hekwerk 175 | 5435600 | 2890 | no | yes | 0 | 0 | 350 | 0.805 | 2300 | Bouwkundig | 2. nieuwbouw | Non-bearing |  |  |  |  | Vertical | Dimensions - Volume: 0.140875 m3; Constraints - Base Extension Distance: 0 mm; Top Extension Distance: 0 mm; Location Line: Wall Centerline; Top Constraint: Up to level: V1 ok. ruwe vloer; Pset_wanden - sets with these values: 2
4 x Basic Wall:28_DAT_kalkzandsteen_175mm:6000860 | 00 Begane grond | 28.21 Uniformat (Uniformat) | 479.8 | 2530 | 45 | 21_DAT_Hekwerk 175 | 2 | Walls | Non-bearing | Samengesteld rekwerkBuitenplaat WBP 10mmHouten stijl- en regelwerk 38x140Minirale wolDampremmendefolieGipsplaat 12.5mmGipsvezelplaat 12,5mm | 21.10 |  |  | 21.10 | buitenwanden; niet constructief, algemeen (verzamelniveau) | Samengesteld rekwerkBuitenplaat WBP 10mmHouten stijl- en regelwerk 38x140Minirale wolDampremmendefolieGipsplaat 12.5mmGipsvezelplaat 12,5mm | Walls | Basic Wall | Basic Wall: 21_DAT_Hekwerk 175 | 21_DAT_Hekwerk 175 | 5435600 | 710 | no | yes | 0 | 0 | 2530 | 0.11385 | 45 | Bouwkundig | 2. nieuwbouw | Non-bearing |  |  |  |  | Vertical | Dimensions - Volume: 0.0199238 m3; Constraints - Base Extension Distance: 0 mm; Top Extension Distance: 0 mm; Location Line: Wall Centerline; Top Constraint: Up to level: V1 ok. ruwe vloer; Pset_wanden - sets with these values: 2
Basic Wall:28_DAT_kalkzandsteen_175mm:6000860 | 00 Begane grond | 28.21 Uniformat (Uniformat) | 479.8 | 2530 | 40 | 21_DAT_Hekwerk 175 | 2 | Walls | Non-bearing | Samengesteld rekwerkBuitenplaat WBP 10mmHouten stijl- en regelwerk 38x140Minirale wolDampremmendefolieGipsplaat 12.5mmGipsvezelplaat 12,5mm | 21.10 |  |  | 21.10 | buitenwanden; niet constructief, algemeen (verzamelniveau) | Samengesteld rekwerkBuitenplaat WBP 10mmHouten stijl- en regelwerk 38x140Minirale wolDampremmendefolieGipsplaat 12.5mmGipsvezelplaat 12,5mm | Walls | Basic Wall | Basic Wall: 21_DAT_Hekwerk 175 | 21_DAT_Hekwerk 175 | 5435600 | 710 | no | yes | 0 | 0 | 2530 | 0.1012 | 40 | Bouwkundig | 2. nieuwbouw | Non-bearing |  |  |  |  | Vertical | Dimensions - Volume: 0.01771 m3; Constraints - Base Extension Distance: 0 mm; Top Extension Distance: 0 mm; Location Line: Wall Centerline; Top Constraint: Up to level: V1 ok. ruwe vloer; Pset_wanden - sets with these values: 2
2 x Basic Wall:28_DAT_kalkzandsteen_175mm:6000860 | 00 Begane grond | 28.21 Uniformat (Uniformat) | 479.8 | 3310 | 190 | 22_DAT_binnenwand_25 | 2 | Walls | Non-bearing | Lichte scheidingswand 100mm | 22.13 |  |  | 22.13 | binnenwanden; niet constructief, systeemwanden; vast | Lichte scheidingswand 100mm | Walls | Basic Wall | Basic Wall: 22_DAT_binnenwand_25 | 22_DAT_binnenwand_25 | 4977124 | 0 | no | yes | V0 bk. ruwe vloer | 0 | 3310 | 0.6289 | 190 | Bouwkundig | 2. nieuwbouw | Non-bearing |  |  |  |  | Vertical | Dimensions - Volume: 0.0157225 m3; Constraints - Base Extension Distance: 0 mm; Top Extension Distance: 0 mm; Location Line: Wall Centerline; Top Constraint: Up to level: V1 ok. ruwe vloer
Basic Wall:28_DAT_kalkzandsteen_175mm:6000860 | 00 Begane grond | 28.21 Uniformat (Uniformat) | 479.8 | 2180 | 2300 | K_07 | 2 | Walls | Non-bearing | Kunststof kozijn Gealan Kubus | 31 | Kunststof kozijn Gealan Kubus | 31 | 31 | buitenwandopeningen | Kunststof kozijn Gealan Kubus | Walls | Curtain Wall | Curtain Wall: K_07 | K_07 | 4849800 | 710 | no | yes | 0 | 0 | 2180 | 5.014 | 2300 | Bouwkundig | 2. nieuwbouw | Non-bearing | 0 | Beginning | 4 | 2 | Vertical | Other - Doorvalveilig 1-zijdig: no; Doorvalveilig 2-zijdig: yes; Text - NLRS_C_merk: K01
Basic Wall:28_DAT_kalkzandsteen_175mm:6000860 | 00 Begane grond | 28.21 Uniformat (Uniformat) | 479.8 | 780 | 2130 | 28_DAT_kalkzandsteen_175mm | 2 | Walls | Non-bearing | Kalkzandsteen 175mm | 28.21 |  |  | 28.21 | hoofddraagconstructies; wanden en vloeren, wand-/vloerconstructies | Kalkzandsteen 175mm | Walls | Basic Wall | Basic Wall: 28_DAT_kalkzandsteen_175mm | 28_DAT_kalkzandsteen_175mm | 4741545 | 0 | no | yes | V0 bk. ruwe vloer | 0 | 780 | 1.6614 | 2130 | Constructie | 2. nieuwbouw | Non-bearing |  |  |  |  | Vertical | Dimensions - Volume: 0.290745 m3; Constraints - Base Extension Distance: 0 mm; Top Extension Distance: 0 mm; Location Line: Wall Centerline
Basic Wall:28_DAT_kalkzandsteen_175mm:6000860 | 00 Begane grond | 28.21 Uniformat (Uniformat) | 479.8 | 3310 | 160 | 22_DAT_binnenwand_25 | 2 | Walls | Non-bearing | Lichte scheidingswand 100mm | 22.13 |  |  | 22.13 | binnenwanden; niet constructief, systeemwanden; vast | Lichte scheidingswand 100mm | Walls | Basic Wall | Basic Wall: 22_DAT_binnenwand_25 | 22_DAT_binnenwand_25 | 4977124 | 0 | no | yes | V0 bk. ruwe vloer | 0 | 3310 | 0.5296 | 160 | Bouwkundig | 2. nieuwbouw | Non-bearing |  |  |  |  | Vertical | Dimensions - Volume: 0.01324 m3; Constraints - Base Extension Distance: 0 mm; Top Extension Distance: 0 mm; Location Line: Wall Centerline; Top Constraint: Up to level: V1 ok. ruwe vloer
3 x Basic Wall:28_DAT_kalkzandsteen_175mm:6000860 | 00 Begane grond | 28.21 Uniformat (Uniformat) | 479.8 | 6860 | 190 | 22_DAT_binnenwand_25 | 2 | Walls | Non-bearing | Lichte scheidingswand 100mm | 22.13 |  |  | 22.13 | binnenwanden; niet constructief, systeemwanden; vast | Lichte scheidingswand 100mm | Walls | Basic Wall | Basic Wall: 22_DAT_binnenwand_25 | 22_DAT_binnenwand_25 | 4977124 | 0 | no | yes | 0 | -30 | 6860 | 1.3034 | 190 | Bouwkundig | 2. nieuwbouw | Non-bearing |  |  |  |  | Vertical | Dimensions - Volume: 0.032585 m3; Constraints - Base Extension Distance: 0 mm; Top Extension Distance: 0 mm; Location Line: Wall Centerline; Top Constraint: Up to level: V2 ok. ruwe vloer
Basic Wall:22_DAT_binnenwand_25:6002383 | 00 Begane grond | 22.13 Uniformat (Uniformat) | 329.8 | 2180 | 2300 | K_07 | 2 | Walls | Non-bearing | Kunststof kozijn Gealan Kubus | 31 | Kunststof kozijn Gealan Kubus | 31 | 31 | buitenwandopeningen | Kunststof kozijn Gealan Kubus | Walls | Curtain Wall | Curtain Wall: K_07 | K_07 | 4849800 | 710 | no | yes | 0 | 0 | 2180 | 5.014 | 2300 | Bouwkundig | 2. nieuwbouw | Non-bearing | 0 | Beginning | 4 | 2 | Vertical | Group: Model Group:Kollom tussenmaat 120x120:6002382; Other - Doorvalveilig 1-zijdig: no; Doorvalveilig 2-zijdig: yes; Text - NLRS_C_merk: K01
Basic Wall:22_DAT_binnenwand_25:6002383 | 00 Begane grond | 22.13 Uniformat (Uniformat) | 329.8 | 2630 | 1495 | K_14 | 2 | Walls | Non-bearing | Kunststof kozijn Gealan Kubus | 31 | Kunststof kozijn Gealan Kubus | 31 | 31 | buitenwandopeningen | Kunststof kozijn Gealan Kubus | Walls | Curtain Wall | Curtain Wall: K_14 | K_14 | 4906721 | 10 | no | yes | 0 | 0 | 2630 | 3.93185 | 1495 | Bouwkundig | 2. nieuwbouw | Non-bearing | 0 | Beginning | 4 | 2 | Vertical | Group: Model Group:Kollom tussenmaat 120x120:6002382; Other - Doorvalveilig 1-zijdig: no; Doorvalveilig 2-zijdig: yes; Text - NLRS_C_merk: K01
Basic Wall:22_DAT_binnenwand_25:6002383 | 00 Begane grond | 22.13 Uniformat (Uniformat) | 329.8 | 2630 | 3450 | K_15 | 2 | Walls | Non-bearing | Kunststof kozijn Gealan Kubus | 31 | Kunststof kozijn Gealan Kubus | 31 | 31 | buitenwandopeningen | Kunststof kozijn Gealan Kubus | Walls | Curtain Wall | Curtain Wall: K_15 | K_15 | 4912009 | 10 | no | yes | 0 | 0 | 2630 | 9.0735 | 3450 | Bouwkundig | 2. nieuwbouw | Non-bearing | 0 | Beginning | 4 | 2 | Vertical | Group: Model Group:Kollom tussenmaat 120x120:6002382; Other - Doorvalveilig 1-zijdig: no; Doorvalveilig 2-zijdig: yes; Text - NLRS_C_merk: K01
3 x Basic Wall:22_DAT_binnenwand_25:6002383 | 00 Begane grond | 22.13 Uniformat (Uniformat) | 329.8 | 1930 | 2040 | K_17 | 2 | Walls | Non-bearing | Kunststof kozijn Gealan Kubus | 31 | Kunststof kozijn Gealan Kubus | 31 | 31 | buitenwandopeningen | Kunststof kozijn Gealan Kubus | Walls | Curtain Wall | Curtain Wall: K_17 | K_17 | 6061266 | 710 | no | yes | 0 | 0 | 1930 | 3.9372 | 2040 | Bouwkundig | 2. nieuwbouw | Non-bearing | 0 | Beginning | 4 | 2 | Vertical | Group: Model Group:Kollom tussenmaat 120x120:6002382; Other - Doorvalveilig 1-zijdig: no; Doorvalveilig 2-zijdig: yes; Text - NLRS_C_merk: K01
4 x Basic Wall:22_DAT_binnenwand_25:6002383 | 00 Begane grond | 22.13 Uniformat (Uniformat) | 329.8 | 1930 | 880 | K_16 | 2 | Walls | Non-bearing | Kunststof kozijn Gealan Kubus | 31 | Kunststof kozijn Gealan Kubus | 31 | 31 | buitenwandopeningen | Kunststof kozijn Gealan Kubus | Walls | Curtain Wall | Curtain Wall: K_16 | K_16 | 6074129 | 710 | no | yes | 0 | 0 | 1930 | 1.6984 | 880 | Bouwkundig | 2. nieuwbouw | Non-bearing | 0 | Beginning | 4 | 2 | Vertical | Group: Model Group:Kollom tussenmaat 120x120:6002382; Other - Doorvalveilig 1-zijdig: no; Doorvalveilig 2-zijdig: yes; Text - NLRS_C_merk: K01
Basic Wall:21_DAT_Hekwerk 175:6002587 | 00 Begane grond | 21.10 Uniformat (Uniformat) | 479.8 | 3310 | 160 | 22_DAT_binnenwand_25 | 2 | Walls | Non-bearing | Lichte scheidingswand 100mm | 22.13 |  |  | 22.13 | binnenwanden; niet constructief, systeemwanden; vast | Lichte scheidingswand 100mm | Walls | Basic Wall | Basic Wall: 22_DAT_binnenwand_25 | 22_DAT_binnenwand_25 | 4977124 | 0 | no | yes | V0 bk. ruwe vloer | 0 | 3310 | 0.5296 | 160 | Bouwkundig | 2. nieuwbouw | Non-bearing |  |  |  |  | Vertical | Dimensions - Volume: 0.01324 m3; Constraints - Base Extension Distance: 0 mm; Top Extension Distance: 0 mm; Location Line: Wall Centerline; Top Constraint: Up to level: V1 ok. ruwe vloer
Basic Wall:21_DAT_Hekwerk 175:6002587 | 00 Begane grond | 21.10 Uniformat (Uniformat) | 479.8 | 2630 | 3450 | K_15 | 2 | Walls | Non-bearing | Kunststof kozijn Gealan Kubus | 31 | Kunststof kozijn Gealan Kubus | 31 | 31 | buitenwandopeningen | Kunststof kozijn Gealan Kubus | Walls | Curtain Wall | Curtain Wall: K_15 | K_15 | 4912009 | 10 | no | yes | 0 | 0 | 2630 | 9.0735 | 3450 | Bouwkundig | 2. nieuwbouw | Non-bearing | 0 | Beginning | 4 | 2 | Vertical | Other - Doorvalveilig 1-zijdig: no; Doorvalveilig 2-zijdig: yes; Text - NLRS_C_merk: K01
Basic Wall:21_DAT_Hekwerk 175:6002587 | 00 Begane grond | 21.10 Uniformat (Uniformat) | 479.8 | 2630 | 1495 | K_14 | 2 | Walls | Non-bearing | Kunststof kozijn Gealan Kubus | 31 | Kunststof kozijn Gealan Kubus | 31 | 31 | buitenwandopeningen | Kunststof kozijn Gealan Kubus | Walls | Curtain Wall | Curtain Wall: K_14 | K_14 | 4906721 | 10 | no | yes | 0 | 0 | 2630 | 3.93185 | 1495 | Bouwkundig | 2. nieuwbouw | Non-bearing | 0 | Beginning | 4 | 2 | Vertical | Other - Doorvalveilig 1-zijdig: no; Doorvalveilig 2-zijdig: yes; Text - NLRS_C_merk: K01
Basic Wall:21_DAT_Hekwerk 175:6002587 | 00 Begane grond | 21.10 Uniformat (Uniformat) | 479.8 | 2180 | 2300 | K_07 | 2 | Walls | Non-bearing | Kunststof kozijn Gealan Kubus | 31 | Kunststof kozijn Gealan Kubus | 31 | 31 | buitenwandopeningen | Kunststof kozijn Gealan Kubus | Walls | Curtain Wall | Curtain Wall: K_07 | K_07 | 4849800 | 710 | no | yes | 0 | 0 | 2180 | 5.014 | 2300 | Bouwkundig | 2. nieuwbouw | Non-bearing | 0 | Beginning | 4 | 2 | Vertical | Other - Doorvalveilig 1-zijdig: no; Doorvalveilig 2-zijdig: yes; Text - NLRS_C_merk: K01
3 x Basic Wall:21_DAT_Hekwerk 175:6002587 | 00 Begane grond | 21.10 Uniformat (Uniformat) | 479.8 | 1930 | 2040 | K_17 | 2 | Walls | Non-bearing | Kunststof kozijn Gealan Kubus | 31 | Kunststof kozijn Gealan Kubus | 31 | 31 | buitenwandopeningen | Kunststof kozijn Gealan Kubus | Walls | Curtain Wall | Curtain Wall: K_17 | K_17 | 6061266 | 710 | no | yes | 0 | 0 | 1930 | 3.9372 | 2040 | Bouwkundig | 2. nieuwbouw | Non-bearing | 0 | Beginning | 4 | 2 | Vertical | Other - Doorvalveilig 1-zijdig: no; Doorvalveilig 2-zijdig: yes; Text - NLRS_C_merk: K01
4 x Basic Wall:21_DAT_Hekwerk 175:6002587 | 00 Begane grond | 21.10 Uniformat (Uniformat) | 479.8 | 1930 | 880 | K_16 | 2 | Walls | Non-bearing | Kunststof kozijn Gealan Kubus | 31 | Kunststof kozijn Gealan Kubus | 31 | 31 | buitenwandopeningen | Kunststof kozijn Gealan Kubus | Walls | Curtain Wall | Curtain Wall: K_16 | K_16 | 6074129 | 710 | no | yes | 0 | 0 | 1930 | 1.6984 | 880 | Bouwkundig | 2. nieuwbouw | Non-bearing | 0 | Beginning | 4 | 2 | Vertical | Other - Doorvalveilig 1-zijdig: no; Doorvalveilig 2-zijdig: yes; Text - NLRS_C_merk: K01
2 x Basic Wall:21_DAT_Hekwerk 175:6002587 | 00 Begane grond | 21.10 Uniformat (Uniformat) | 479.8 | 2530 | 60 | 21_DAT_Hekwerk 175 | 2 | Walls | Non-bearing | Samengesteld rekwerkBuitenplaat WBP 10mmHouten stijl- en regelwerk 38x140Minirale wolDampremmendefolieGipsplaat 12.5mmGipsvezelplaat 12,5mm | 21.10 |  |  | 21.10 | buitenwanden; niet constructief, algemeen (verzamelniveau) | Samengesteld rekwerkBuitenplaat WBP 10mmHouten stijl- en regelwerk 38x140Minirale wolDampremmendefolieGipsplaat 12.5mmGipsvezelplaat 12,5mm | Walls | Basic Wall | Basic Wall: 21_DAT_Hekwerk 175 | 21_DAT_Hekwerk 175 | 5435600 | 710 | no | yes | 0 | 0 | 2530 | 0.1518 | 60 | Bouwkundig | 2. nieuwbouw | Non-bearing |  |  |  |  | Vertical | Dimensions - Volume: 0.026565 m3; Constraints - Base Extension Distance: 0 mm; Top Extension Distance: 0 mm; Location Line: Wall Centerline; Top Constraint: Up to level: V1 ok. ruwe vloer; Pset_wanden - sets with these values: 2
2 x Basic Wall:21_DAT_Hekwerk 175:6002587 | 00 Begane grond | 21.10 Uniformat (Uniformat) | 479.8 | 710 | 60 | 21_DAT_Hekwerk 175 | 2 | Walls | Non-bearing | Samengesteld rekwerkBuitenplaat WBP 10mmHouten stijl- en regelwerk 38x140Minirale wolDampremmendefolieGipsplaat 12.5mmGipsvezelplaat 12,5mm | 21.10 |  |  | 21.10 | buitenwanden; niet constructief, algemeen (verzamelniveau) | Samengesteld rekwerkBuitenplaat WBP 10mmHouten stijl- en regelwerk 38x140Minirale wolDampremmendefolieGipsplaat 12.5mmGipsvezelplaat 12,5mm | Walls | Basic Wall | Basic Wall: 21_DAT_Hekwerk 175 | 21_DAT_Hekwerk 175 | 5435600 | 0 | no | yes | 0 | 0 | 710 | 0.0426 | 60 | Bouwkundig | 2. nieuwbouw | Non-bearing |  |  |  |  | Vertical | Dimensions - Volume: 0.007455 m3; Constraints - Base Extension Distance: 0 mm; Top Extension Distance: 0 mm; Location Line: Wall Centerline; Pset_wanden - sets with these values: 2
Basic Wall:28_DAT_kalkzandsteen_175mm:6002709 | 00 Begane grond | 28.21 Uniformat (Uniformat) | 479.8 | 2180 | 2300 | K_07 | 2 | Walls | Non-bearing | Kunststof kozijn Gealan Kubus | 31 | Kunststof kozijn Gealan Kubus | 31 | 31 | buitenwandopeningen | Kunststof kozijn Gealan Kubus | Walls | Curtain Wall | Curtain Wall: K_07 | K_07 | 4849800 | 710 | no | yes | 0 | 0 | 2180 | 5.014 | 2300 | Bouwkundig | 2. nieuwbouw | Non-bearing | 0 | Beginning | 4 | 2 | Vertical | Other - Doorvalveilig 1-zijdig: no; Doorvalveilig 2-zijdig: yes; Text - NLRS_C_merk: K01
Basic Wall:28_DAT_kalkzandsteen_175mm:6002709 | 00 Begane grond | 28.21 Uniformat (Uniformat) | 479.8 | 2630 | 1495 | K_14 | 2 | Walls | Non-bearing | Kunststof kozijn Gealan Kubus | 31 | Kunststof kozijn Gealan Kubus | 31 | 31 | buitenwandopeningen | Kunststof kozijn Gealan Kubus | Walls | Curtain Wall | Curtain Wall: K_14 | K_14 | 4906721 | 10 | no | yes | 0 | 0 | 2630 | 3.93185 | 1495 | Bouwkundig | 2. nieuwbouw | Non-bearing | 0 | Beginning | 4 | 2 | Vertical | Other - Doorvalveilig 1-zijdig: no; Doorvalveilig 2-zijdig: yes; Text - NLRS_C_merk: K01
Basic Wall:28_DAT_kalkzandsteen_175mm:6002709 | 00 Begane grond | 28.21 Uniformat (Uniformat) | 479.8 | 2630 | 3450 | K_15 | 2 | Walls | Non-bearing | Kunststof kozijn Gealan Kubus | 31 | Kunststof kozijn Gealan Kubus | 31 | 31 | buitenwandopeningen | Kunststof kozijn Gealan Kubus | Walls | Curtain Wall | Curtain Wall: K_15 | K_15 | 4912009 | 10 | no | yes | 0 | 0 | 2630 | 9.0735 | 3450 | Bouwkundig | 2. nieuwbouw | Non-bearing | 0 | Beginning | 4 | 2 | Vertical | Other - Doorvalveilig 1-zijdig: no; Doorvalveilig 2-zijdig: yes; Text - NLRS_C_merk: K01
3 x Basic Wall:28_DAT_kalkzandsteen_175mm:6002709 | 00 Begane grond | 28.21 Uniformat (Uniformat) | 479.8 | 1930 | 2040 | K_17 | 2 | Walls | Non-bearing | Kunststof kozijn Gealan Kubus | 31 | Kunststof kozijn Gealan Kubus | 31 | 31 | buitenwandopeningen | Kunststof kozijn Gealan Kubus | Walls | Curtain Wall | Curtain Wall: K_17 | K_17 | 6061266 | 710 | no | yes | 0 | 0 | 1930 | 3.9372 | 2040 | Bouwkundig | 2. nieuwbouw | Non-bearing | 0 | Beginning | 4 | 2 | Vertical | Other - Doorvalveilig 1-zijdig: no; Doorvalveilig 2-zijdig: yes; Text - NLRS_C_merk: K01
4 x Basic Wall:28_DAT_kalkzandsteen_175mm:6002709 | 00 Begane grond | 28.21 Uniformat (Uniformat) | 479.8 | 1930 | 880 | K_16 | 2 | Walls | Non-bearing | Kunststof kozijn Gealan Kubus | 31 | Kunststof kozijn Gealan Kubus | 31 | 31 | buitenwandopeningen | Kunststof kozijn Gealan Kubus | Walls | Curtain Wall | Curtain Wall: K_16 | K_16 | 6074129 | 710 | no | yes | 0 | 0 | 1930 | 1.6984 | 880 | Bouwkundig | 2. nieuwbouw | Non-bearing | 0 | Beginning | 4 | 2 | Vertical | Other - Doorvalveilig 1-zijdig: no; Doorvalveilig 2-zijdig: yes; Text - NLRS_C_merk: K01
Basic Wall:21_DAT_isolatie hard_74:6003012 | 00 Begane grond | 21.10 Uniformat (Uniformat) | 374.8 | 2630 | 1130 | K_05 | 2 | Walls | Non-bearing | Kunststof kozijn Gealan Linear | 31 | Kunststof kozijn Gealan Linear | 31 | 31 | buitenwandopeningen | Kunststof kozijn Gealan Linear | Walls | Curtain Wall | Curtain Wall: K_05 | K_05 | 4797835 | 10 | no | yes | 0 | 0 | 2630 | 2.9719 | 1130 | Bouwkundig | 2. nieuwbouw | Non-bearing | 0 | Beginning | 4 | 2 | Vertical | Other - Doorvalveilig 1-zijdig: no; Doorvalveilig 2-zijdig: yes; Text - NLRS_C_merk: K01
Basic Wall:21_DAT_isolatie hard_74:6003012 | 00 Begane grond | 21.10 Uniformat (Uniformat) | 374.8 | 2610 | 2120 | K_03 | 2 | Walls | Non-bearing | Kunststof kozijn Gealan Linear | 31 | Kunststof kozijn Gealan Linear | 31 | 31 | buitenwandopeningen | Kunststof kozijn Gealan Linear | Walls | Curtain Wall | Curtain Wall: K_03 | K_03 | 4793066 | 30 | no | yes | 0 | 0 | 2610 | 5.5332 | 2120 | Bouwkundig | 2. nieuwbouw | Non-bearing | 0 | Beginning | 4 | 2 | Vertical | Other - Doorvalveilig 1-zijdig: no; Doorvalveilig 2-zijdig: yes; Text - NLRS_C_merk: K01
Basic Wall:21_DAT_isolatie hard_74:6003012 | 00 Begane grond | 21.10 Uniformat (Uniformat) | 374.8 | 2630 | 2120 | K_02 | 2 | Walls | Non-bearing | Kunststof kozijn Gealan Kubus | 31 | Kunststof kozijn Gealan Kubus | 31 | 31 | buitenwandopeningen | Kunststof kozijn Gealan Kubus | Walls | Curtain Wall | Curtain Wall: K_02 | K_02 | 4792108 | 10 | no | yes | 0 | 0 | 2630 | 5.5756 | 2120 | Bouwkundig | 2. nieuwbouw | Non-bearing | 0 | Beginning | 4 | 2 | Vertical | Other - Doorvalveilig 1-zijdig: no; Doorvalveilig 2-zijdig: yes; Text - NLRS_C_merk: K01
2 x Basic Wall:21_DAT_isolatie hard_74:6003012 | 00 Begane grond | 21.10 Uniformat (Uniformat) | 374.8 | 2630 | 740 | K_04 | 2 | Walls | Non-bearing | Kunststof kozijn Gealan Kubus | 31 | Kunststof kozijn Gealan Kubus | 31 | 31 | buitenwandopeningen | Kunststof kozijn Gealan Kubus | Walls | Curtain Wall | Curtain Wall: K_04 | K_04 | 4800906 | 10 | no | yes | 0 | 0 | 2630 | 1.9462 | 740 | Bouwkundig | 2. nieuwbouw | Non-bearing | 0 | Beginning | 4 | 2 | Vertical | Other - Doorvalveilig 1-zijdig: no; Doorvalveilig 2-zijdig: yes; Text - NLRS_C_merk: K01
Basic Wall:21_DAT_wand_HSB_150:6003690 | 00 Begane grond | 21.12 Uniformat (Uniformat) | 479.8 | 2630 | 920 | K_01 | 2 | Walls | Non-bearing | Kunststof kozijn Gealan Kubus | 31 | Kunststof kozijn Gealan Kubus | 31 | 31 | buitenwandopeningen | Kunststof kozijn Gealan Kubus | Walls | Curtain Wall | Curtain Wall: K_01 | K_01 | 4774158 | 10 | no | yes | 0 | 0 | 2630 | 2.4196 | 920 | Bouwkundig | 2. nieuwbouw | Non-bearing | 0 | Beginning | 4 | 2 | Vertical | Other - Doorvalveilig 1-zijdig: no; Doorvalveilig 2-zijdig: yes; Text - NLRS_C_merk: K01
Basic Wall:21_DAT_wand_HSB_150:6003690 | 00 Begane grond | 21.12 Uniformat (Uniformat) | 479.8 | 2630 | 1635 | K_18 | 2 | Walls | Non-bearing | Kunststof kozijn Gealan Kubus | 31 | Kunststof kozijn Gealan Kubus | 31 | 31 | buitenwandopeningen | Kunststof kozijn Gealan Kubus | Walls | Curtain Wall | Curtain Wall: K_18 | K_18 | 6067594 | 10 | no | yes | 0 | 0 | 2630 | 4.30005 | 1635 | Bouwkundig | 2. nieuwbouw | Non-bearing | 0 | Beginning | 4 | 2 | Vertical | Other - Doorvalveilig 1-zijdig: no; Doorvalveilig 2-zijdig: yes; Text - NLRS_C_merk: K01
Basic Wall:21_DAT_Hekwerk 175:6004052 | 00 Begane grond | 21.10 Uniformat (Uniformat) | 479.8 | 2630 | 2120 | K_02 | 2 | Walls | Non-bearing | Kunststof kozijn Gealan Kubus | 31 | Kunststof kozijn Gealan Kubus | 31 | 31 | buitenwandopeningen | Kunststof kozijn Gealan Kubus | Walls | Curtain Wall | Curtain Wall: K_02 | K_02 | 4792108 | 10 | no | yes | 0 | 0 | 2630 | 5.5756 | 2120 | Bouwkundig | 2. nieuwbouw | Non-bearing | 0 | Beginning | 4 | 2 | Vertical | Other - Doorvalveilig 1-zijdig: no; Doorvalveilig 2-zijdig: yes; Text - NLRS_C_merk: K01
2 x Basic Wall:28_DAT_kalkzandsteen_175mm:6005228 | 01 eerste verdieping | 28.21 Uniformat (Uniformat) | 479.8 | 1930 | 2040 | K_24 | 2 | Walls | Non-bearing | Kunststof kozijn Gealan Kubus | 31 | Kunststof kozijn Gealan Kubus | 31 | 31 | buitenwandopeningen | Kunststof kozijn Gealan Kubus | Walls | Curtain Wall | Curtain Wall: K_24 | K_24 | 4801721 | 810 | no | yes | 1 | 0 | 1930 | 3.9372 | 2040 | Bouwkundig | 2. nieuwbouw | Non-bearing | 0 | Beginning | 4 | 2 | Vertical | Other - Doorvalveilig 1-zijdig: no; Doorvalveilig 2-zijdig: yes; Text - NLRS_C_merk: K01
Basic Wall:28_DAT_kalkzandsteen_175mm:6005228 | 01 eerste verdieping | 28.21 Uniformat (Uniformat) | 479.8 | 3310 | 160 | 22_DAT_binnenwand_25 | 2 | Walls | Non-bearing | Lichte scheidingswand 100mm | 22.13 |  |  | 22.13 | binnenwanden; niet constructief, systeemwanden; vast | Lichte scheidingswand 100mm | Walls | Basic Wall | Basic Wall: 22_DAT_binnenwand_25 | 22_DAT_binnenwand_25 | 4977124 | 20 | no | yes | V1 bk. ruwe vloer | 0.0000289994 | 3310 | 0.5296 | 160 | Bouwkundig | 2. nieuwbouw | Non-bearing |  |  |  |  | Vertical | Dimensions - Volume: 0.01324 m3; Constraints - Base Extension Distance: 0 mm; Top Extension Distance: 0 mm; Location Line: Wall Centerline; Top Constraint: Up to level: V2 ok. ruwe vloer
Basic Wall:28_DAT_kalkzandsteen_175mm:6006165 | 01 eerste verdieping | 28.21 Uniformat (Uniformat) | 479.8 | 3310 | 160 | 22_DAT_binnenwand_25 | 2 | Walls | Non-bearing | Lichte scheidingswand 100mm | 22.13 |  |  | 22.13 | binnenwanden; niet constructief, systeemwanden; vast | Lichte scheidingswand 100mm | Walls | Basic Wall | Basic Wall: 22_DAT_binnenwand_25 | 22_DAT_binnenwand_25 | 4977124 | 20 | no | yes | V1 bk. ruwe vloer | 0.0000289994 | 3310 | 0.5296 | 160 | Bouwkundig | 2. nieuwbouw | Non-bearing |  |  |  |  | Vertical | Dimensions - Volume: 0.01324 m3; Constraints - Base Extension Distance: 0 mm; Top Extension Distance: 0 mm; Location Line: Wall Centerline; Top Constraint: Up to level: V2 ok. ruwe vloer
2 x Basic Wall:28_DAT_kalkzandsteen_175mm:6006165 | 01 eerste verdieping | 28.21 Uniformat (Uniformat) | 479.8 | 1930 | 880 | K_31 | 2 | Walls | Non-bearing | Kunststof kozijn Gealan Kubus | 31 | Kunststof kozijn Gealan Kubus | 31 | 31 | buitenwandopeningen | Kunststof kozijn Gealan Kubus | Walls | Curtain Wall | Curtain Wall: K_31 | K_31 | 6069143 | 810 | no | yes | 1 | 0 | 1930 | 1.6984 | 880 | Bouwkundig | 2. nieuwbouw | Non-bearing | 0 | Beginning | 4 | 2 | Vertical | Other - Doorvalveilig 1-zijdig: no; Doorvalveilig 2-zijdig: yes; Text - NLRS_C_merk: K01
Basic Wall:21_DAT_isolatie hard_74:6007099 | 01 eerste verdieping | 21.10 Uniformat (Uniformat) | 374.8 | 5680 | 2130 | K_08 | 2 | Walls | Non-bearing | Kunststof kozijn Gealan Kubus | 31 | Kunststof kozijn Gealan Kubus | 31 | 31 | buitenwandopeningen | Kunststof kozijn Gealan Kubus | Walls | Curtain Wall | Curtain Wall: K_08 | K_08 | 4854521 | 710 | no | yes | 0 | 0 | 5680 | 12.0984 | 2130 | Bouwkundig | 2. nieuwbouw | Non-bearing | 0 | Beginning | 4 | 2 | Vertical | Other - Doorvalveilig 1-zijdig: no; Doorvalveilig 2-zijdig: yes; Text - NLRS_C_merk: K01
Basic Wall:21_DAT_isolatie hard_74:6010342 | 01 eerste verdieping | 21.10 Uniformat (Uniformat) | 374.8 | 4430 | 790 | K_10 | 2 | Walls | Non-bearing | Kunststof kozijn Gealan Kubus | 31 | Kunststof kozijn Gealan Kubus | 31 | 31 | buitenwandopeningen | Kunststof kozijn Gealan Kubus | Walls | Curtain Wall | Curtain Wall: K_10 | K_10 | 4859456 | 1960 | no | yes | 0 | 0 | 4430 | 3.4997 | 790 | Bouwkundig | 2. nieuwbouw | Non-bearing | 0 | Beginning | 4 | 2 | Vertical | Other - Doorvalveilig 1-zijdig: no; Doorvalveilig 2-zijdig: yes; Text - NLRS_C_merk: K01
Basic Wall:21_DAT_isolatie hard_74:6010460 | 01 eerste verdieping | 21.10 Uniformat (Uniformat) | 374.8 | 5055 | 790 | K_09 | 2 | Walls | Non-bearing | Kunststof kozijn Gealan Kubus | 31 | Kunststof kozijn Gealan Kubus | 31 | 31 | buitenwandopeningen | Kunststof kozijn Gealan Kubus | Walls | Curtain Wall | Curtain Wall: K_09 | K_09 | 4858854 | 1335 | no | yes | 0 | 0 | 5055 | 3.99345 | 790 | Bouwkundig | 2. nieuwbouw | Non-bearing | 0 | Beginning | 4 | 2 | Vertical | Other - Doorvalveilig 1-zijdig: no; Doorvalveilig 2-zijdig: yes; Text - NLRS_C_merk: K01
Basic Wall:21_DAT_isolatie hard_74:6010799 | 01 eerste verdieping | 21.10 Uniformat (Uniformat) | 374.8 | 3805 | 790 | K_11 | 2 | Walls | Non-bearing | Kunststof kozijn Gealan Kubus | 31 | Kunststof kozijn Gealan Kubus | 31 | 31 | buitenwandopeningen | Kunststof kozijn Gealan Kubus | Walls | Curtain Wall | Curtain Wall: K_11 | K_11 | 4859827 | 2585 | no | yes | 0 | 0 | 3805 | 3.00595 | 790 | Bouwkundig | 2. nieuwbouw | Non-bearing | 0 | Beginning | 4 | 2 | Vertical | Other - Doorvalveilig 1-zijdig: no; Doorvalveilig 2-zijdig: yes; Text - NLRS_C_merk: K01
Basic Wall:21_DAT_isolatie hard_74:6010956 | 01 eerste verdieping | 21.10 Uniformat (Uniformat) | 374.8 | 3180 | 790 | K_12 | 2 | Walls | Non-bearing | Kunststof kozijn Gealan Kubus | 31 | Kunststof kozijn Gealan Kubus | 31 | 31 | buitenwandopeningen | Kunststof kozijn Gealan Kubus | Walls | Curtain Wall | Curtain Wall: K_12 | K_12 | 4860014 | 3210 | no | yes | 0 | 0 | 3180 | 2.5122 | 790 | Bouwkundig | 2. nieuwbouw | Non-bearing | 0 | Beginning | 4 | 2 | Vertical | Other - Doorvalveilig 1-zijdig: no; Doorvalveilig 2-zijdig: yes; Text - NLRS_C_merk: K01
Basic Wall:21_DAT_isolatie hard_74:6011134 | 01 eerste verdieping | 21.10 Uniformat (Uniformat) | 374.8 | 2555 | 790 | K_13 | 2 | Walls | Non-bearing | Kunststof kozijn Gealan Kubus | 31 | Kunststof kozijn Gealan Kubus | 31 | 31 | buitenwandopeningen | Kunststof kozijn Gealan Kubus | Walls | Curtain Wall | Curtain Wall: K_13 | K_13 | 4860509 | 3835 | no | yes | 0 | 0 | 2555 | 2.01845 | 790 | Bouwkundig | 2. nieuwbouw | Non-bearing | 0 | Beginning | 4 | 2 | Vertical | Other - Doorvalveilig 1-zijdig: no; Doorvalveilig 2-zijdig: yes; Text - NLRS_C_merk: K01
Basic Wall:21_DAT_isolatie hard_74:6011315 | 01 eerste verdieping | 21.10 Uniformat (Uniformat) | 374.8 | 1930 | 790 | K_29 | 2 | Walls | Non-bearing | Kunststof kozijn Gealan Kubus | 31 | Kunststof kozijn Gealan Kubus | 31 | 31 | buitenwandopeningen | Kunststof kozijn Gealan Kubus | Walls | Curtain Wall | Curtain Wall: K_29 | K_29 | 4860879 | 810 | no | yes | 1 | 0 | 1930 | 1.5247 | 790 | Bouwkundig | 2. nieuwbouw | Non-bearing | 0 | Beginning | 4 | 2 | Vertical | Other - Doorvalveilig 1-zijdig: no; Doorvalveilig 2-zijdig: yes; Text - NLRS_C_merk: K01
Basic Wall:21_DAT_isolatie hard_74:6011616 | 01 eerste verdieping | 21.10 Uniformat (Uniformat) | 374.8 | 1930 | 790 | K_29 | 2 | Walls | Non-bearing | Kunststof kozijn Gealan Kubus | 31 | Kunststof kozijn Gealan Kubus | 31 | 31 | buitenwandopeningen | Kunststof kozijn Gealan Kubus | Walls | Curtain Wall | Curtain Wall: K_29 | K_29 | 4860879 | 810 | no | yes | 1 | 0 | 1930 | 1.5247 | 790 | Bouwkundig | 2. nieuwbouw | Non-bearing | 0 | Beginning | 4 | 2 | Vertical | Other - Doorvalveilig 1-zijdig: no; Doorvalveilig 2-zijdig: yes; Text - NLRS_C_merk: K01
7 x Basic Wall:21_DAT_isolatie hard_74:6011710 | 01 eerste verdieping | 21.10 Uniformat (Uniformat) | 374.8 | 1930 | 2250 | K_22 | 2 | Walls | Non-bearing | Kunststof kozijn Gealan Kubus | 31 | Kunststof kozijn Gealan Kubus | 31 | 31 | buitenwandopeningen | Kunststof kozijn Gealan Kubus | Walls | Curtain Wall | Curtain Wall: K_22 | K_22 | 4917986 | 810 | no | yes | 1 | 0 | 1930 | 4.3425 | 2250 | Bouwkundig | 2. nieuwbouw | Non-bearing | 0 | Beginning | 4 | 2 | Vertical | Other - Doorvalveilig 1-zijdig: no; Doorvalveilig 2-zijdig: yes; Text - NLRS_C_merk: K01
7 x Basic Wall:21_DAT_isolatie hard_74:6011710 | 01 eerste verdieping | 21.10 Uniformat (Uniformat) | 374.8 | 1930 | 790 | K_29 | 2 | Walls | Non-bearing | Kunststof kozijn Gealan Kubus | 31 | Kunststof kozijn Gealan Kubus | 31 | 31 | buitenwandopeningen | Kunststof kozijn Gealan Kubus | Walls | Curtain Wall | Curtain Wall: K_29 | K_29 | 4860879 | 810 | no | yes | 1 | 0 | 1930 | 1.5247 | 790 | Bouwkundig | 2. nieuwbouw | Non-bearing | 0 | Beginning | 4 | 2 | Vertical | Other - Doorvalveilig 1-zijdig: no; Doorvalveilig 2-zijdig: yes; Text - NLRS_C_merk: K01
6 x Basic Wall:21_DAT_isolatie hard_74:6014053 | 00 Begane grond | 21.10 Uniformat (Uniformat) | 374.8 | 2180 | 790 | K_06 | 2 | Walls | Non-bearing | Kunststof kozijn Gealan Kubus | 31 | Kunststof kozijn Gealan Kubus | 31 | 31 | buitenwandopeningen | Kunststof kozijn Gealan Kubus | Walls | Curtain Wall | Curtain Wall: K_06 | K_06 | 4842980 | 710 | no | yes | 0 | 0 | 2180 | 1.7222 | 790 | Bouwkundig | 2. nieuwbouw | Non-bearing | 0 | Beginning | 4 | 2 | Vertical | Other - Doorvalveilig 1-zijdig: no; Doorvalveilig 2-zijdig: yes; Text - NLRS_C_merk: K01
Basic Wall:21_DAT_isolatie hard_74:6014053 | 00 Begane grond | 21.10 Uniformat (Uniformat) | 374.8 | 2180 | 2300 | K_07 | 2 | Walls | Non-bearing | Kunststof kozijn Gealan Kubus | 31 | Kunststof kozijn Gealan Kubus | 31 | 31 | buitenwandopeningen | Kunststof kozijn Gealan Kubus | Walls | Curtain Wall | Curtain Wall: K_07 | K_07 | 4849800 | 710 | no | yes | 0 | 0 | 2180 | 5.014 | 2300 | Bouwkundig | 2. nieuwbouw | Non-bearing | 0 | Beginning | 4 | 2 | Vertical | Other - Doorvalveilig 1-zijdig: no; Doorvalveilig 2-zijdig: yes; Text - NLRS_C_merk: K01
Basic Wall:21_DAT_isolatie hard_74:6057862 | 01 eerste verdieping | 21.10 Uniformat (Uniformat) | 374.8 | 1930 | 880 | K_28 | 2 | Walls | Non-bearing | Kunststof kozijn Gealan Kubus | 31 | Kunststof kozijn Gealan Kubus | 31 | 31 | buitenwandopeningen | Kunststof kozijn Gealan Kubus | Walls | Curtain Wall | Curtain Wall: K_28 | K_28 | 6068408 | 810 | no | yes | 1 | 0 | 1930 | 1.6984 | 880 | Bouwkundig | 2. nieuwbouw | Non-bearing | 0 | Beginning | 4 | 2 | Vertical | Group: Model Group:K_Raamwerk_28:6057727; Other - Doorvalveilig 1-zijdig: no; Doorvalveilig 2-zijdig: yes; Text - NLRS_C_merk: K01
Basic Wall:21_DAT_isolatie hard_74:6058280 | 01 eerste verdieping | 21.10 Uniformat (Uniformat) | 374.8 | 1930 | 880 | K_28 | 2 | Walls | Non-bearing | Kunststof kozijn Gealan Kubus | 31 | Kunststof kozijn Gealan Kubus | 31 | 31 | buitenwandopeningen | Kunststof kozijn Gealan Kubus | Walls | Curtain Wall | Curtain Wall: K_28 | K_28 | 6068408 | 810 | no | yes | 1 | 0 | 1930 | 1.6984 | 880 | Bouwkundig | 2. nieuwbouw | Non-bearing | 0 | Beginning | 4 | 2 | Vertical | Group: Model Group:K_Raamwerk_28:6058262; Other - Doorvalveilig 1-zijdig: no; Doorvalveilig 2-zijdig: yes; Text - NLRS_C_merk: K01
Basic Wall:21_DAT_isolatie hard_74:6058299 | 01 eerste verdieping | 21.10 Uniformat (Uniformat) | 374.8 | 1930 | 880 | K_28 | 2 | Walls | Non-bearing | Kunststof kozijn Gealan Kubus | 31 | Kunststof kozijn Gealan Kubus | 31 | 31 | buitenwandopeningen | Kunststof kozijn Gealan Kubus | Walls | Curtain Wall | Curtain Wall: K_28 | K_28 | 6068408 | 810 | no | yes | 1 | 0 | 1930 | 1.6984 | 880 | Bouwkundig | 2. nieuwbouw | Non-bearing | 0 | Beginning | 4 | 2 | Vertical | Group: Model Group:K_Raamwerk_28:6058281; Other - Doorvalveilig 1-zijdig: no; Doorvalveilig 2-zijdig: yes; Text - NLRS_C_merk: K01
Basic Wall:21_DAT_isolatie hard_74:6058318 | 01 eerste verdieping | 21.10 Uniformat (Uniformat) | 374.8 | 1930 | 880 | K_28 | 2 | Walls | Non-bearing | Kunststof kozijn Gealan Kubus | 31 | Kunststof kozijn Gealan Kubus | 31 | 31 | buitenwandopeningen | Kunststof kozijn Gealan Kubus | Walls | Curtain Wall | Curtain Wall: K_28 | K_28 | 6068408 | 810 | no | yes | 1 | 0 | 1930 | 1.6984 | 880 | Bouwkundig | 2. nieuwbouw | Non-bearing | 0 | Beginning | 4 | 2 | Vertical | Group: Model Group:K_Raamwerk_28:6058300; Other - Doorvalveilig 1-zijdig: no; Doorvalveilig 2-zijdig: yes; Text - NLRS_C_merk: K01
Basic Wall:21_DAT_isolatie hard_74:6058337 | 01 eerste verdieping | 21.10 Uniformat (Uniformat) | 374.8 | 1930 | 880 | K_28 | 2 | Walls | Non-bearing | Kunststof kozijn Gealan Kubus | 31 | Kunststof kozijn Gealan Kubus | 31 | 31 | buitenwandopeningen | Kunststof kozijn Gealan Kubus | Walls | Curtain Wall | Curtain Wall: K_28 | K_28 | 6068408 | 810 | no | yes | 1 | 0 | 1930 | 1.6984 | 880 | Bouwkundig | 2. nieuwbouw | Non-bearing | 0 | Beginning | 4 | 2 | Vertical | Group: Model Group:K_Raamwerk_28:6058319; Other - Doorvalveilig 1-zijdig: no; Doorvalveilig 2-zijdig: yes; Text - NLRS_C_merk: K01
Basic Wall:21_DAT_isolatie hard_74:6058356 | 01 eerste verdieping | 21.10 Uniformat (Uniformat) | 374.8 | 1930 | 880 | K_28 | 2 | Walls | Non-bearing | Kunststof kozijn Gealan Kubus | 31 | Kunststof kozijn Gealan Kubus | 31 | 31 | buitenwandopeningen | Kunststof kozijn Gealan Kubus | Walls | Curtain Wall | Curtain Wall: K_28 | K_28 | 6068408 | 810 | no | yes | 1 | 0 | 1930 | 1.6984 | 880 | Bouwkundig | 2. nieuwbouw | Non-bearing | 0 | Beginning | 4 | 2 | Vertical | Group: Model Group:K_Raamwerk_28:6058338; Other - Doorvalveilig 1-zijdig: no; Doorvalveilig 2-zijdig: yes; Text - NLRS_C_merk: K01
Basic Wall:21_DAT_isolatie hard_74:6058375 | 01 eerste verdieping | 21.10 Uniformat (Uniformat) | 374.8 | 1930 | 880 | K_28 | 2 | Walls | Non-bearing | Kunststof kozijn Gealan Kubus | 31 | Kunststof kozijn Gealan Kubus | 31 | 31 | buitenwandopeningen | Kunststof kozijn Gealan Kubus | Walls | Curtain Wall | Curtain Wall: K_28 | K_28 | 6068408 | 810 | no | yes | 1 | 0 | 1930 | 1.6984 | 880 | Bouwkundig | 2. nieuwbouw | Non-bearing | 0 | Beginning | 4 | 2 | Vertical | Group: Model Group:K_Raamwerk_28:6058357; Other - Doorvalveilig 1-zijdig: no; Doorvalveilig 2-zijdig: yes; Text - NLRS_C_merk: K01
Basic Wall:21_DAT_isolatie hard_74:6058394 | 01 eerste verdieping | 21.10 Uniformat (Uniformat) | 374.8 | 1930 | 880 | K_28 | 2 | Walls | Non-bearing | Kunststof kozijn Gealan Kubus | 31 | Kunststof kozijn Gealan Kubus | 31 | 31 | buitenwandopeningen | Kunststof kozijn Gealan Kubus | Walls | Curtain Wall | Curtain Wall: K_28 | K_28 | 6068408 | 810 | no | yes | 1 | 0 | 1930 | 1.6984 | 880 | Bouwkundig | 2. nieuwbouw | Non-bearing | 0 | Beginning | 4 | 2 | Vertical | Group: Model Group:K_Raamwerk_28:6058376; Other - Doorvalveilig 1-zijdig: no; Doorvalveilig 2-zijdig: yes; Text - NLRS_C_merk: K01
Basic Wall:21_DAT_isolatie hard_74:6058413 | 01 eerste verdieping | 21.10 Uniformat (Uniformat) | 374.8 | 1930 | 880 | K_28 | 2 | Walls | Non-bearing | Kunststof kozijn Gealan Kubus | 31 | Kunststof kozijn Gealan Kubus | 31 | 31 | buitenwandopeningen | Kunststof kozijn Gealan Kubus | Walls | Curtain Wall | Curtain Wall: K_28 | K_28 | 6068408 | 810 | no | yes | 1 | 0 | 1930 | 1.6984 | 880 | Bouwkundig | 2. nieuwbouw | Non-bearing | 0 | Beginning | 4 | 2 | Vertical | Group: Model Group:K_Raamwerk_28:6058395; Other - Doorvalveilig 1-zijdig: no; Doorvalveilig 2-zijdig: yes; Text - NLRS_C_merk: K01
Basic Wall:21_DAT_isolatie hard_74:6058432 | 01 eerste verdieping | 21.10 Uniformat (Uniformat) | 374.8 | 1930 | 880 | K_28 | 2 | Walls | Non-bearing | Kunststof kozijn Gealan Kubus | 31 | Kunststof kozijn Gealan Kubus | 31 | 31 | buitenwandopeningen | Kunststof kozijn Gealan Kubus | Walls | Curtain Wall | Curtain Wall: K_28 | K_28 | 6068408 | 810 | no | yes | 1 | 0 | 1930 | 1.6984 | 880 | Bouwkundig | 2. nieuwbouw | Non-bearing | 0 | Beginning | 4 | 2 | Vertical | Group: Model Group:K_Raamwerk_28:6058414; Other - Doorvalveilig 1-zijdig: no; Doorvalveilig 2-zijdig: yes; Text - NLRS_C_merk: K01
Basic Wall:21_DAT_isolatie hard_74:6058451 | 01 eerste verdieping | 21.10 Uniformat (Uniformat) | 374.8 | 1930 | 880 | K_31 | 2 | Walls | Non-bearing | Kunststof kozijn Gealan Kubus | 31 | Kunststof kozijn Gealan Kubus | 31 | 31 | buitenwandopeningen | Kunststof kozijn Gealan Kubus | Walls | Curtain Wall | Curtain Wall: K_31 | K_31 | 6069143 | 810 | no | yes | 1 | 0 | 1930 | 1.6984 | 880 | Bouwkundig | 2. nieuwbouw | Non-bearing | 0 | Beginning | 4 | 2 | Vertical | Group: Model Group:K_Raamwerk_28:6058433; Other - Doorvalveilig 1-zijdig: no; Doorvalveilig 2-zijdig: yes; Text - NLRS_C_merk: K01
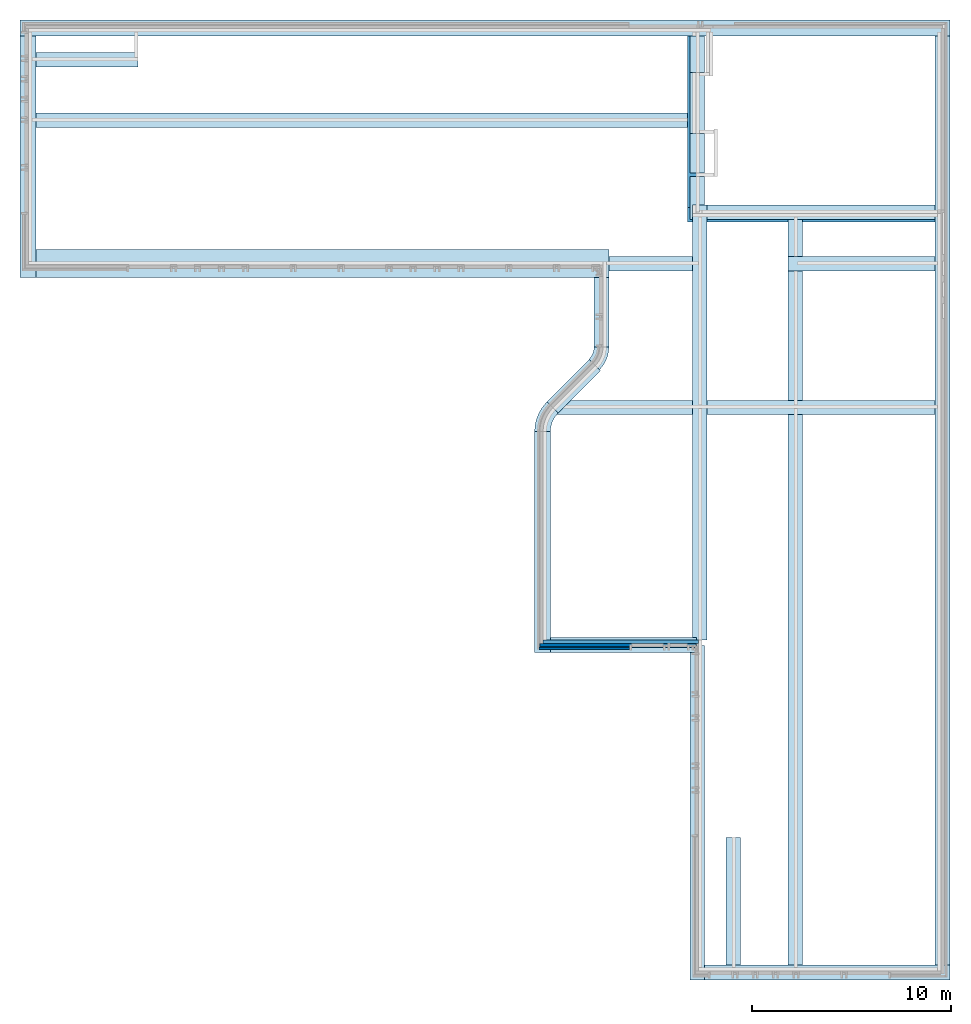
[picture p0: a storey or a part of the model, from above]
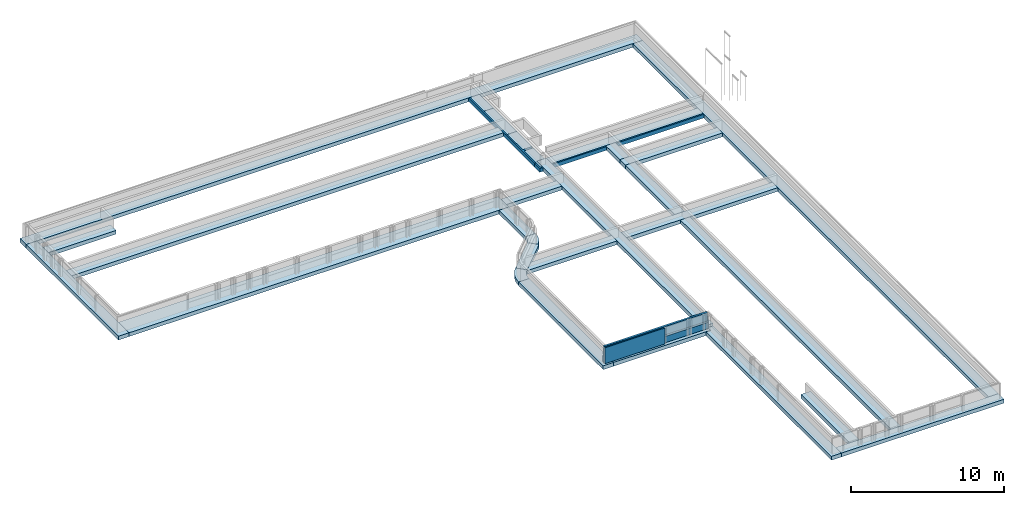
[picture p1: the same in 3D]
Properties of the parts of a building model (IFC2X3), part 27 of 37

# IfcOpeningElement: Opening (1092)
Name | In | Classification | Depth (mm) | BaseQuantities, Height (mm) | BaseQuantities, Width (mm) | Reference | Pset_OpeningElementCommon, sets with these values | Pset_ProductRequirements, Category | Pset_wanden, Structural Usage | Pset_wanden, Omschrijving | Pset_wanden, NL-sfb-Codering | Pset_kozijnen (CW), Omschrijving | Pset_kozijnen (CW), NL-sfb-Codering | Pset_DAT_KMS, Assembly Code | Pset_DAT_KMS, Assembly Description | Pset_DAT_KMS, Description | Other, Category | Family | Other, Family and Type | Type | Type Id | Base Offset (mm) | Base is Attached = Related to Mass = Top is Attached = Structural | Room Bounding | Base Constraint | Top Offset (mm) | Unconnected Height (mm) | Dimensions, Area (m2) | Length (mm) | Identity Data, Workset | Phase Created | Structural, Structural Usage | Angle (deg) = Offset (mm) | Justification | Number | Horizontal Grid, sets with these values | Cross-Section
Basic Wall:21_DAT_isolatie hard_74:6058470 | 01 eerste verdieping | 21.10 Uniformat (Uniformat) | 374.8 | 1930 | 880 | K_31 | 2 | Walls | Non-bearing | Kunststof kozijn Gealan Kubus | 31 | Kunststof kozijn Gealan Kubus | 31 | 31 | buitenwandopeningen | Kunststof kozijn Gealan Kubus | Walls | Curtain Wall | Curtain Wall: K_31 | K_31 | 6069143 | 810 | no | yes | 1 | 0 | 1930 | 1.6984 | 880 | Bouwkundig | 2. nieuwbouw | Non-bearing | 0 | Beginning | 4 | 2 | Vertical | Group: Model Group:K_Raamwerk_28:6058452; Other - Doorvalveilig 1-zijdig: no; Doorvalveilig 2-zijdig: yes; Text - NLRS_C_merk: K01
Basic Wall:21_DAT_isolatie hard_74:6058489 | 01 eerste verdieping | 21.10 Uniformat (Uniformat) | 374.8 | 1930 | 880 | K_31 | 2 | Walls | Non-bearing | Kunststof kozijn Gealan Kubus | 31 | Kunststof kozijn Gealan Kubus | 31 | 31 | buitenwandopeningen | Kunststof kozijn Gealan Kubus | Walls | Curtain Wall | Curtain Wall: K_31 | K_31 | 6069143 | 810 | no | yes | 1 | 0 | 1930 | 1.6984 | 880 | Bouwkundig | 2. nieuwbouw | Non-bearing | 0 | Beginning | 4 | 2 | Vertical | Group: Model Group:K_Raamwerk_28:6058471; Other - Doorvalveilig 1-zijdig: no; Doorvalveilig 2-zijdig: yes; Text - NLRS_C_merk: K01
Basic Wall:21_DAT_isolatie hard_74:6058508 | 01 eerste verdieping | 21.10 Uniformat (Uniformat) | 374.8 | 1930 | 880 | K_28 | 2 | Walls | Non-bearing | Kunststof kozijn Gealan Kubus | 31 | Kunststof kozijn Gealan Kubus | 31 | 31 | buitenwandopeningen | Kunststof kozijn Gealan Kubus | Walls | Curtain Wall | Curtain Wall: K_28 | K_28 | 6068408 | 810 | no | yes | 1 | 0 | 1930 | 1.6984 | 880 | Bouwkundig | 2. nieuwbouw | Non-bearing | 0 | Beginning | 4 | 2 | Vertical | Group: Model Group:K_Raamwerk_28:6058490; Other - Doorvalveilig 1-zijdig: no; Doorvalveilig 2-zijdig: yes; Text - NLRS_C_merk: K01
Basic Wall:21_DAT_isolatie hard_74:6058527 | 01 eerste verdieping | 21.10 Uniformat (Uniformat) | 374.8 | 1930 | 880 | K_31 | 2 | Walls | Non-bearing | Kunststof kozijn Gealan Kubus | 31 | Kunststof kozijn Gealan Kubus | 31 | 31 | buitenwandopeningen | Kunststof kozijn Gealan Kubus | Walls | Curtain Wall | Curtain Wall: K_31 | K_31 | 6069143 | 810 | no | yes | 1 | 0 | 1930 | 1.6984 | 880 | Bouwkundig | 2. nieuwbouw | Non-bearing | 0 | Beginning | 4 | 2 | Vertical | Group: Model Group:K_Raamwerk_28:6058509; Other - Doorvalveilig 1-zijdig: no; Doorvalveilig 2-zijdig: yes; Text - NLRS_C_merk: K01
Basic Wall:21_DAT_isolatie hard_74:6058546 | 01 eerste verdieping | 21.10 Uniformat (Uniformat) | 374.8 | 1930 | 880 | K_28 | 2 | Walls | Non-bearing | Kunststof kozijn Gealan Kubus | 31 | Kunststof kozijn Gealan Kubus | 31 | 31 | buitenwandopeningen | Kunststof kozijn Gealan Kubus | Walls | Curtain Wall | Curtain Wall: K_28 | K_28 | 6068408 | 810 | no | yes | 1 | 0 | 1930 | 1.6984 | 880 | Bouwkundig | 2. nieuwbouw | Non-bearing | 0 | Beginning | 4 | 2 | Vertical | Group: Model Group:K_Raamwerk_28:6058528; Other - Doorvalveilig 1-zijdig: no; Doorvalveilig 2-zijdig: yes; Text - NLRS_C_merk: K01
Basic Wall:21_DAT_isolatie hard_74:6058565 | 01 eerste verdieping | 21.10 Uniformat (Uniformat) | 374.8 | 1930 | 880 | K_28 | 2 | Walls | Non-bearing | Kunststof kozijn Gealan Kubus | 31 | Kunststof kozijn Gealan Kubus | 31 | 31 | buitenwandopeningen | Kunststof kozijn Gealan Kubus | Walls | Curtain Wall | Curtain Wall: K_28 | K_28 | 6068408 | 810 | no | yes | 1 | 0 | 1930 | 1.6984 | 880 | Bouwkundig | 2. nieuwbouw | Non-bearing | 0 | Beginning | 4 | 2 | Vertical | Group: Model Group:K_Raamwerk_28:6058547; Other - Doorvalveilig 1-zijdig: no; Doorvalveilig 2-zijdig: yes; Text - NLRS_C_merk: K01
Basic Wall:21_DAT_isolatie hard_74:6058696 | 01 eerste verdieping | 21.10 Uniformat (Uniformat) | 374.8 | 1930 | 2040 | K_24 | 2 | Walls | Non-bearing | Kunststof kozijn Gealan Kubus | 31 | Kunststof kozijn Gealan Kubus | 31 | 31 | buitenwandopeningen | Kunststof kozijn Gealan Kubus | Walls | Curtain Wall | Curtain Wall: K_24 | K_24 | 4801721 | 810 | no | yes | 1 | 0 | 1930 | 3.9372 | 2040 | Bouwkundig | 2. nieuwbouw | Non-bearing | 0 | Beginning | 4 | 2 | Vertical | Group: Model Group:raamwerk K07:6058698; Other - Doorvalveilig 1-zijdig: no; Doorvalveilig 2-zijdig: yes; Text - NLRS_C_merk: K01
Basic Wall:21_DAT_isolatie hard_74:6059004 | 01 eerste verdieping | 21.10 Uniformat (Uniformat) | 374.8 | 1930 | 2040 | K_24 | 2 | Walls | Non-bearing | Kunststof kozijn Gealan Kubus | 31 | Kunststof kozijn Gealan Kubus | 31 | 31 | buitenwandopeningen | Kunststof kozijn Gealan Kubus | Walls | Curtain Wall | Curtain Wall: K_24 | K_24 | 4801721 | 810 | no | yes | 1 | 0 | 1930 | 3.9372 | 2040 | Bouwkundig | 2. nieuwbouw | Non-bearing | 0 | Beginning | 4 | 2 | Vertical | Group: Model Group:raamwerk K07:6059006; Other - Doorvalveilig 1-zijdig: no; Doorvalveilig 2-zijdig: yes; Text - NLRS_C_merk: K01
Basic Wall:21_DAT_isolatie hard_74:6059023 | 01 eerste verdieping | 21.10 Uniformat (Uniformat) | 374.8 | 1930 | 2040 | K_24 | 2 | Walls | Non-bearing | Kunststof kozijn Gealan Kubus | 31 | Kunststof kozijn Gealan Kubus | 31 | 31 | buitenwandopeningen | Kunststof kozijn Gealan Kubus | Walls | Curtain Wall | Curtain Wall: K_24 | K_24 | 4801721 | 810 | no | yes | 1 | 0 | 1930 | 3.9372 | 2040 | Bouwkundig | 2. nieuwbouw | Non-bearing | 0 | Beginning | 4 | 2 | Vertical | Group: Model Group:raamwerk K07:6059025; Other - Doorvalveilig 1-zijdig: no; Doorvalveilig 2-zijdig: yes; Text - NLRS_C_merk: K01
Basic Wall:21_DAT_isolatie hard_74:6059042 | 01 eerste verdieping | 21.10 Uniformat (Uniformat) | 374.8 | 1930 | 2040 | K_24 | 2 | Walls | Non-bearing | Kunststof kozijn Gealan Kubus | 31 | Kunststof kozijn Gealan Kubus | 31 | 31 | buitenwandopeningen | Kunststof kozijn Gealan Kubus | Walls | Curtain Wall | Curtain Wall: K_24 | K_24 | 4801721 | 810 | no | yes | 1 | 0 | 1930 | 3.9372 | 2040 | Bouwkundig | 2. nieuwbouw | Non-bearing | 0 | Beginning | 4 | 2 | Vertical | Group: Model Group:raamwerk K07:6059044; Other - Doorvalveilig 1-zijdig: no; Doorvalveilig 2-zijdig: yes; Text - NLRS_C_merk: K01
Basic Wall:21_DAT_isolatie hard_74:6059061 | 01 eerste verdieping | 21.10 Uniformat (Uniformat) | 374.8 | 1930 | 2040 | K_24 | 2 | Walls | Non-bearing | Kunststof kozijn Gealan Kubus | 31 | Kunststof kozijn Gealan Kubus | 31 | 31 | buitenwandopeningen | Kunststof kozijn Gealan Kubus | Walls | Curtain Wall | Curtain Wall: K_24 | K_24 | 4801721 | 810 | no | yes | 1 | 0 | 1930 | 3.9372 | 2040 | Bouwkundig | 2. nieuwbouw | Non-bearing | 0 | Beginning | 4 | 2 | Vertical | Group: Model Group:raamwerk K07:6059063; Other - Doorvalveilig 1-zijdig: no; Doorvalveilig 2-zijdig: yes; Text - NLRS_C_merk: K01
Basic Wall:21_DAT_isolatie hard_74:6059080 | 01 eerste verdieping | 21.10 Uniformat (Uniformat) | 374.8 | 1930 | 2040 | K_24 | 2 | Walls | Non-bearing | Kunststof kozijn Gealan Kubus | 31 | Kunststof kozijn Gealan Kubus | 31 | 31 | buitenwandopeningen | Kunststof kozijn Gealan Kubus | Walls | Curtain Wall | Curtain Wall: K_24 | K_24 | 4801721 | 810 | no | yes | 1 | 0 | 1930 | 3.9372 | 2040 | Bouwkundig | 2. nieuwbouw | Non-bearing | 0 | Beginning | 4 | 2 | Vertical | Group: Model Group:raamwerk K07:6059082; Other - Doorvalveilig 1-zijdig: no; Doorvalveilig 2-zijdig: yes; Text - NLRS_C_merk: K01
Basic Wall:21_DAT_isolatie hard_74:6059099 | 01 eerste verdieping | 21.10 Uniformat (Uniformat) | 374.8 | 1930 | 2040 | K_24 | 2 | Walls | Non-bearing | Kunststof kozijn Gealan Kubus | 31 | Kunststof kozijn Gealan Kubus | 31 | 31 | buitenwandopeningen | Kunststof kozijn Gealan Kubus | Walls | Curtain Wall | Curtain Wall: K_24 | K_24 | 4801721 | 810 | no | yes | 1 | 0 | 1930 | 3.9372 | 2040 | Bouwkundig | 2. nieuwbouw | Non-bearing | 0 | Beginning | 4 | 2 | Vertical | Group: Model Group:raamwerk K07:6059101; Other - Doorvalveilig 1-zijdig: no; Doorvalveilig 2-zijdig: yes; Text - NLRS_C_merk: K01
Basic Wall:21_DAT_isolatie hard_74:6059118 | 01 eerste verdieping | 21.10 Uniformat (Uniformat) | 374.8 | 1930 | 2040 | K_24 | 2 | Walls | Non-bearing | Kunststof kozijn Gealan Kubus | 31 | Kunststof kozijn Gealan Kubus | 31 | 31 | buitenwandopeningen | Kunststof kozijn Gealan Kubus | Walls | Curtain Wall | Curtain Wall: K_24 | K_24 | 4801721 | 810 | no | yes | 1 | 0 | 1930 | 3.9372 | 2040 | Bouwkundig | 2. nieuwbouw | Non-bearing | 0 | Beginning | 4 | 2 | Vertical | Group: Model Group:raamwerk K07:6059120; Other - Doorvalveilig 1-zijdig: no; Doorvalveilig 2-zijdig: yes; Text - NLRS_C_merk: K01
Basic Wall:21_DAT_isolatie hard_74:6059137 | 01 eerste verdieping | 21.10 Uniformat (Uniformat) | 374.8 | 1930 | 2040 | K_24 | 2 | Walls | Non-bearing | Kunststof kozijn Gealan Kubus | 31 | Kunststof kozijn Gealan Kubus | 31 | 31 | buitenwandopeningen | Kunststof kozijn Gealan Kubus | Walls | Curtain Wall | Curtain Wall: K_24 | K_24 | 4801721 | 810 | no | yes | 1 | 0 | 1930 | 3.9372 | 2040 | Bouwkundig | 2. nieuwbouw | Non-bearing | 0 | Beginning | 4 | 2 | Vertical | Group: Model Group:raamwerk K07:6059139; Other - Doorvalveilig 1-zijdig: no; Doorvalveilig 2-zijdig: yes; Text - NLRS_C_merk: K01
Basic Wall:21_DAT_isolatie hard_74:6059156 | 01 eerste verdieping | 21.10 Uniformat (Uniformat) | 374.8 | 1930 | 2040 | K_24 | 2 | Walls | Non-bearing | Kunststof kozijn Gealan Kubus | 31 | Kunststof kozijn Gealan Kubus | 31 | 31 | buitenwandopeningen | Kunststof kozijn Gealan Kubus | Walls | Curtain Wall | Curtain Wall: K_24 | K_24 | 4801721 | 810 | no | yes | 1 | 0 | 1930 | 3.9372 | 2040 | Bouwkundig | 2. nieuwbouw | Non-bearing | 0 | Beginning | 4 | 2 | Vertical | Group: Model Group:raamwerk K07:6059158; Other - Doorvalveilig 1-zijdig: no; Doorvalveilig 2-zijdig: yes; Text - NLRS_C_merk: K01
Basic Wall:21_DAT_isolatie hard_74:6059175 | 01 eerste verdieping | 21.10 Uniformat (Uniformat) | 374.8 | 1930 | 2040 | K_24 | 2 | Walls | Non-bearing | Kunststof kozijn Gealan Kubus | 31 | Kunststof kozijn Gealan Kubus | 31 | 31 | buitenwandopeningen | Kunststof kozijn Gealan Kubus | Walls | Curtain Wall | Curtain Wall: K_24 | K_24 | 4801721 | 810 | no | yes | 1 | 0 | 1930 | 3.9372 | 2040 | Bouwkundig | 2. nieuwbouw | Non-bearing | 0 | Beginning | 4 | 2 | Vertical | Group: Model Group:raamwerk K07:6059177; Other - Doorvalveilig 1-zijdig: no; Doorvalveilig 2-zijdig: yes; Text - NLRS_C_merk: K01
Basic Wall:21_DAT_isolatie hard_74:6059194 | 01 eerste verdieping | 21.10 Uniformat (Uniformat) | 374.8 | 1930 | 2040 | K_24 | 2 | Walls | Non-bearing | Kunststof kozijn Gealan Kubus | 31 | Kunststof kozijn Gealan Kubus | 31 | 31 | buitenwandopeningen | Kunststof kozijn Gealan Kubus | Walls | Curtain Wall | Curtain Wall: K_24 | K_24 | 4801721 | 810 | no | yes | 1 | 0 | 1930 | 3.9372 | 2040 | Bouwkundig | 2. nieuwbouw | Non-bearing | 0 | Beginning | 4 | 2 | Vertical | Group: Model Group:raamwerk K07:6059196; Other - Doorvalveilig 1-zijdig: no; Doorvalveilig 2-zijdig: yes; Text - NLRS_C_merk: K01
Basic Wall:21_DAT_isolatie hard_74:6059213 | 01 eerste verdieping | 21.10 Uniformat (Uniformat) | 374.8 | 1930 | 2040 | K_24 | 2 | Walls | Non-bearing | Kunststof kozijn Gealan Kubus | 31 | Kunststof kozijn Gealan Kubus | 31 | 31 | buitenwandopeningen | Kunststof kozijn Gealan Kubus | Walls | Curtain Wall | Curtain Wall: K_24 | K_24 | 4801721 | 810 | no | yes | 1 | 0 | 1930 | 3.9372 | 2040 | Bouwkundig | 2. nieuwbouw | Non-bearing | 0 | Beginning | 4 | 2 | Vertical | Group: Model Group:raamwerk K07:6059215; Other - Doorvalveilig 1-zijdig: no; Doorvalveilig 2-zijdig: yes; Text - NLRS_C_merk: K01
Basic Wall:22_DAT_binnenwand_125:6241460 | 00 Begane grond | 22.13 Uniformat (Uniformat) | 429.8 | 2390 | 1825 | Merk H04 | 2 | Walls | Non-bearing | houten kozijn | 31.10 | houten kozijn | 31.10 | 31.10 | buitenwandopeningen; niet gevuld, algemeen (verzamelniveau) | houten kozijn | Walls | Curtain Wall | Curtain Wall: Merk H04 | Merk H04 | 6102986 | 0 | no | yes | 0 | 400 | 2390 | 4.36175 | 1825 | Bouwkundig | 2. nieuwbouw | Non-bearing | 0 | Beginning | 4 | 2 | Vertical | Pset_wanden - NLRS_C_Geluidwering_DnTA: 25; NLRS_C_brandwerendheid: 30; Pset_kozijnen (CW) - NLRS_C_Geluidwering_DnTA: 25; NLRS_C_brandwerendheid: 30; Data - NLRS_C_Geluidwering_DnTA: 25; Materials and Finishes - NLRS_C_Afwerking Kozijn: Kozijn Bamboo - Deur Bamboo; Fire Protection - NLRS_C_brandwerendheid: 30
Basic Wall:22_DAT_binnenwand_125:6320863 | 00 Begane grond | 22.13 Uniformat (Uniformat) | 429.8 | 2390 | 1034 | Merk H16 | 2 | Walls | Non-bearing | houten kozijn | 31.10 | houten kozijn | 31.10 | 31.10 | buitenwandopeningen; niet gevuld, algemeen (verzamelniveau) | houten kozijn | Walls | Curtain Wall | Curtain Wall: Merk H16 | Merk H16 | 6103248 | 0 | no | yes | 0 | 400 | 2390 | 2.47126 | 1034 | Bouwkundig | 2. nieuwbouw | Non-bearing | 0 | Beginning | 4 | 2 | Vertical | Pset_wanden - NLRS_C_Geluidwering_DnTA: 34; Pset_kozijnen (CW) - NLRS_C_Geluidwering_DnTA: 34; Kozijnmerk: S; NLRS_C_gespiegeld: S; Data - NLRS_C_Geluidwering_DnTA: 34; NLRS_C_gespiegeld: S; Materials and Finishes - NLRS_C_Afwerking Kozijn: Ral 9010 - Deur HPL Formica F2296 Sno White
Basic Wall:22_DAT_binnenwand_125:6320863 | 00 Begane grond | 22.13 Uniformat (Uniformat) | 429.8 | 1190 | 600 | Merk H05 | 2 | Walls | Non-bearing | houten kozijn | 31.10 | houten kozijn | 31.10 | 31.10 | buitenwandopeningen; niet gevuld, algemeen (verzamelniveau) | houten kozijn | Walls | Curtain Wall | Curtain Wall: Merk H05 | Merk H05 | 5132093 | 1200 | no | yes | 0 | 400 | 1190 | 0.714 | 600 | Bouwkundig | 2. nieuwbouw | Non-bearing | 0 | Beginning | 4 | 2 | Vertical | Pset_wanden - NLRS_C_Geluidwering_DnTA: 34; Pset_kozijnen (CW) - NLRS_C_Geluidwering_DnTA: 34; Data - NLRS_C_Geluidwering_DnTA: 34; Materials and Finishes - NLRS_C_Afwerking Kozijn: Ral 9010 - Deur HPL Formica F2296 Sno White
Basic Wall:22_DAT_binnenwand_125:6366677 | 00 Begane grond | 22.13 Uniformat (Uniformat) | 429.8 | 2415 | 1656.25 | 22_DAT_binnenwand_125 HPL | 2 | Walls | Non-bearing | Lichte scheidingswand 125mmAan weerszijden gipsvezelplaat 12,5mmGipsplaat 12,5mm Met daartussen 75mm ms wand gevuld met isolatieVulling afhankelijk van gestelde eisen ingeluidsrapportage | 22.13 |  |  | 22.13 | binnenwanden; niet constructief, systeemwanden; vast | Lichte scheidingswand 125mmAan weerszijden gipsvezelplaat 12,5mmGipsplaat 12,5mm Met daartussen 75mm ms wand gevuld met isolatieVulling afhankelijk van gestelde eisen ingeluidsrapportage | Walls | Basic Wall | Basic Wall: 22_DAT_binnenwand_125 HPL | 22_DAT_binnenwand_125 HPL | 6329633 | 0 | no | yes | 0 | 0 | 2415 | 0.175844 | 1656.25 | Bouwkundig | 2. nieuwbouw | Non-bearing |  |  |  |  | Vertical | Dimensions - Volume: 0.0219805 m3; Constraints - Base Extension Distance: 0 mm; Top Extension Distance: 0 mm; Location Line: Wall Centerline
Basic Wall:22_DAT_binnenwand_125 HPL:6371836 | 01 eerste verdieping | 22.13 Uniformat (Uniformat) | 240 | 790 | 790 | haspel slang 30m gen hxdxb 730x240x790 | 2 | Plumbing Fixtures |  |  |  |  |  | 59.20 |  | brandslanghaspel inbouw | Plumbing Fixtures | NLRS_59_PF_FB_brandslanghaspel inbouw_gen_ISR | NLRS_59_PF_FB_brandslanghaspel inbouw_gen_ISR: haspel slang 30m gen hxdxb 730x240x790 | haspel slang 30m gen hxdxb 730x240x790 | 4687182 |  |  |  |  |  |  | 1.00371 |  | Bouwkundig | 2. nieuwbouw | Constraints - Elevation from Level: 1195 mm; Host: Basic Wall : 22_DAT_binnenwand_125 HPL; Level: 1; Schedule Level: 1; Dimensions - NLRS_C_breedte: 790 mm; NLRS_C_diepte: 240 mm; NLRS_C_hoogte: 790 mm; Volume: 0.149784 m3; General - NLRS_P_c01_diameter: 22 mm; NLRS_P_c01_radius: 11 mm; Graphics - slang_bereik: no; Identity Data - Mark: 81; Mechanical - brandslanghaspel_kw_flow: 0.361 m3/s; System Classification: Domestic Cold Water
Basic Wall:22_DAT_binnenwand_125:6372197 | 01 eerste verdieping | 22.13 Uniformat (Uniformat) | 429.8 | 2400 | 2866.5 | 22_DAT_binnenwand_125 HPL | 2 | Walls | Non-bearing | Lichte scheidingswand 125mmAan weerszijden gipsvezelplaat 12,5mmGipsplaat 12,5mm Met daartussen 75mm ms wand gevuld met isolatieVulling afhankelijk van gestelde eisen ingeluidsrapportage | 22.13 |  |  | 22.13 | binnenwanden; niet constructief, systeemwanden; vast | Lichte scheidingswand 125mmAan weerszijden gipsvezelplaat 12,5mmGipsplaat 12,5mm Met daartussen 75mm ms wand gevuld met isolatieVulling afhankelijk van gestelde eisen ingeluidsrapportage | Walls | Basic Wall | Basic Wall: 22_DAT_binnenwand_125 HPL | 22_DAT_binnenwand_125 HPL | 6329633 | 0 | no | yes | 1 | 0 | 2400 | 0.58434 | 2866.5 | Bouwkundig | 2. nieuwbouw | Non-bearing |  |  |  |  | Vertical | Dimensions - Volume: 0.0730425 m3; Constraints - Base Extension Distance: 0 mm; Top Extension Distance: 0 mm; Location Line: Wall Centerline
Basic Wall:22_DAT_binnenwand_125 HPL:6382280 | 00 Begane grond | 22.13 Uniformat (Uniformat) | 429.8 | 2390 | 1600 | Merk H18 | 2 | Walls | Non-bearing | houten kozijn | 31.10 | houten kozijn | 31.10 | 31.10 | buitenwandopeningen; niet gevuld, algemeen (verzamelniveau) | houten kozijn | Walls | Curtain Wall | Curtain Wall: Merk H18 | Merk H18 | 6103426 | 0 | no | yes | 0 | 400 | 2390 | 3.824 | 1600 | Bouwkundig | 2. nieuwbouw | Non-bearing | 0 | Beginning | 4 | 2 | Vertical | Pset_wanden - NLRS_C_Geluidwering_DnTA: 31; Pset_kozijnen (CW) - NLRS_C_Geluidwering_DnTA: 31; Data - NLRS_C_Geluidwering_DnTA: 31; Materials and Finishes - NLRS_C_Afwerking Kozijn: Kozijn Bamboo - Deur Bamboo
Basic Wall:22_DAT_binnenwand_125 HPL:6382295 | 01 eerste verdieping | 22.13 Uniformat (Uniformat) | 429.8 | 2390 | 1034 | Merk H16 | 2 | Walls | Non-bearing | houten kozijn | 31.10 | houten kozijn | 31.10 | 31.10 | buitenwandopeningen; niet gevuld, algemeen (verzamelniveau) | houten kozijn | Walls | Curtain Wall | Curtain Wall: Merk H16 | Merk H16 | 6103248 | 0 | no | yes | 1 | 400 | 2390 | 2.47126 | 1034 | Bouwkundig | 2. nieuwbouw | Non-bearing | 0 | Beginning | 4 | 2 | Vertical | Pset_wanden - NLRS_C_Geluidwering_DnTA: 25; Pset_kozijnen (CW) - NLRS_C_Geluidwering_DnTA: 25; Kozijnmerk: S; NLRS_C_gespiegeld: S; Data - NLRS_C_Geluidwering_DnTA: 25; NLRS_C_gespiegeld: S; Materials and Finishes - NLRS_C_Afwerking Kozijn: Kozijn Bamboo - Deur Bamboo
Basic Wall:22_DAT_binnenwand_125 HPL:6382295 | 01 eerste verdieping | 22.13 Uniformat (Uniformat) | 429.8 | 2390 | 1600 | Merk H18 | 2 | Walls | Non-bearing | houten kozijn | 31.10 | houten kozijn | 31.10 | 31.10 | buitenwandopeningen; niet gevuld, algemeen (verzamelniveau) | houten kozijn | Walls | Curtain Wall | Curtain Wall: Merk H18 | Merk H18 | 6103426 | 0 | no | yes | 1 | 400 | 2390 | 3.824 | 1600 | Bouwkundig | 2. nieuwbouw | Non-bearing | 0 | Beginning | 4 | 2 | Vertical | Pset_wanden - NLRS_C_Geluidwering_DnTA: 31; Pset_kozijnen (CW) - NLRS_C_Geluidwering_DnTA: 31; Data - NLRS_C_Geluidwering_DnTA: 31; Materials and Finishes - NLRS_C_Afwerking Kozijn: Kozijn Bamboo - Deur Bamboo
Basic Wall:22_DAT_binnenwand_125 HPL:6382302 | 00 Begane grond | 22.13 Uniformat (Uniformat) | 429.8 | 2390 | 1470 | Merk H03 | 2 | Walls | Non-bearing | houten kozijn | 31.10 | houten kozijn | 31.10 | 31.10 | buitenwandopeningen; niet gevuld, algemeen (verzamelniveau) | houten kozijn | Walls | Curtain Wall | Curtain Wall: Merk H03 | Merk H03 | 5128005 | 0 | no | yes | 0 | 400 | 2390 | 3.5133 | 1470 | Bouwkundig | 2. nieuwbouw | Non-bearing | 0 | Beginning | 4 | 2 | Vertical | Materials and Finishes - NLRS_C_Afwerking Kozijn: Kozijn Bamboo - Deur Bamboo; Pset_wanden - NLRS_C_brandwerendheid: 30; Pset_kozijnen (CW) - NLRS_C_brandwerendheid: 30; Fire Protection - NLRS_C_brandwerendheid: 30
Basic Wall:22_DAT_binnenwand_125:6395592 | 00 Begane grond | 22.13 Uniformat (Uniformat) | 429.8 | 2390 | 1034 | Merk H16 | 2 | Walls | Non-bearing | houten kozijn | 31.10 | houten kozijn | 31.10 | 31.10 | buitenwandopeningen; niet gevuld, algemeen (verzamelniveau) | houten kozijn | Walls | Curtain Wall | Curtain Wall: Merk H16 | Merk H16 | 6103248 | 0 | no | yes | 0 | 400 | 2390 | 2.47126 | 1034 | Bouwkundig | 2. nieuwbouw | Non-bearing | 0 | Beginning | 4 | 2 | Vertical | Pset_wanden - NLRS_C_Geluidwering_DnTA: 38; Pset_kozijnen (CW) - NLRS_C_Geluidwering_DnTA: 38; Data - NLRS_C_Geluidwering_DnTA: 38; Materials and Finishes - NLRS_C_Afwerking Kozijn: Ral 9010 - Deur HPL Formica F2296 Sno White
Basic Wall:22_DAT_binnenwand_125:6395661 | 00 Begane grond | 22.13 Uniformat (Uniformat) | 429.8 | 2390 | 1980 | Merk H07 | 2 | Walls | Non-bearing | houten kozijn | 31.10 | houten kozijn | 31.10 | 31.10 | buitenwandopeningen; niet gevuld, algemeen (verzamelniveau) | houten kozijn | Walls | Curtain Wall | Curtain Wall: Merk H07 | Merk H07 | 5144215 | 0 | no | yes | 0 | 400 | 2390 | 4.7322 | 1980 | Bouwkundig | 2. nieuwbouw | Non-bearing | 0 | Beginning | 4 | 2 | Vertical | Pset_wanden - NLRS_C_Geluidwering_DnTA: 38; Pset_kozijnen (CW) - NLRS_C_Geluidwering_DnTA: 38; Data - NLRS_C_Geluidwering_DnTA: 38; Materials and Finishes - NLRS_C_Afwerking Kozijn: Ral 9010 - Deur HPL Formica F2296 Sno White
Basic Wall:22_DAT_binnenwand_125 HPL dubbel:6397607 | 00 Begane grond | 22.13 Uniformat (Uniformat) | 429.8 | 600 | 2710 | Merk H08 | 2 | Walls | Non-bearing | houten kozijn | 31.10 | houten kozijn | 31.10 | 31.10 | buitenwandopeningen; niet gevuld, algemeen (verzamelniveau) | houten kozijn | Walls | Curtain Wall | Curtain Wall: Merk H08 | Merk H08 | 5145389 | 1200 | no | yes | 0 | 400 | 600 | 1.626 | 2710 | Bouwkundig | 2. nieuwbouw | Non-bearing | 0 | Beginning | 4 | 2 | Vertical | Pset_wanden - NLRS_C_Geluidwering_DnTA: 31; Pset_kozijnen (CW) - NLRS_C_Geluidwering_DnTA: 31; Data - NLRS_C_Geluidwering_DnTA: 31; Materials and Finishes - NLRS_C_Afwerking Kozijn: Kozijn Bamboo - Deur Bamboo
Basic Wall:22_DAT_binnenwand_125 HPL dubbel:6397607 | 00 Begane grond | 22.13 Uniformat (Uniformat) | 429.8 | 2390 | 1134 | Merk H09 | 2 | Walls | Non-bearing | houten kozijn | 31.10 | houten kozijn | 31.10 | 31.10 | buitenwandopeningen; niet gevuld, algemeen (verzamelniveau) | houten kozijn | Walls | Curtain Wall | Curtain Wall: Merk H09 | Merk H09 | 5149044 | 0 | no | yes | 0 | 400 | 2390 | 2.71026 | 1134 | Bouwkundig | 2. nieuwbouw | Non-bearing | 0 | Beginning | 4 | 2 | Vertical | Pset_wanden - NLRS_C_Geluidwering_DnTA: 31; Pset_kozijnen (CW) - NLRS_C_Geluidwering_DnTA: 31; Data - NLRS_C_Geluidwering_DnTA: 31; Materials and Finishes - NLRS_C_Afwerking Kozijn: Kozijn Bamboo - Deur Bamboo
Basic Wall:22_DAT_binnenwand_125 HPL:6400357 | 00 Begane grond | 22.13 Uniformat (Uniformat) | 429.8 | 2390 | 2360 | Merk H24 | 2 | Walls | Non-bearing | houten kozijn | 31.10 | houten kozijn | 31.10 | 31.10 | buitenwandopeningen; niet gevuld, algemeen (verzamelniveau) | houten kozijn | Walls | Curtain Wall | Curtain Wall: Merk H24 | Merk H24 | 5489050 | 0 | no | yes | 0 | 400 | 2390 | 5.6404 | 2360 | Bouwkundig | 2. nieuwbouw | Non-bearing | 0 | Beginning | 4 | 2 | Vertical | Materials and Finishes - NLRS_C_Afwerking Kozijn: S3020-Y20R - Deur HPL Formica F0903 cafe
Basic Wall:22_DAT_binnenwand_125 HPL:6400357 | 00 Begane grond | 22.13 Uniformat (Uniformat) | 429.8 | 2390 | 1825 | Merk H04 | 2 | Walls | Non-bearing | houten kozijn | 31.10 | houten kozijn | 31.10 | 31.10 | buitenwandopeningen; niet gevuld, algemeen (verzamelniveau) | houten kozijn | Walls | Curtain Wall | Curtain Wall: Merk H04 | Merk H04 | 6102986 | 0 | no | yes | 0 | 400 | 2390 | 4.36175 | 1825 | Bouwkundig | 2. nieuwbouw | Non-bearing | 0 | Beginning | 4 | 2 | Vertical | Pset_wanden - NLRS_C_Geluidwering_DnTA: 25; NLRS_C_brandwerendheid: 30; Pset_kozijnen (CW) - NLRS_C_Geluidwering_DnTA: 25; NLRS_C_brandwerendheid: 30; Data - NLRS_C_Geluidwering_DnTA: 25; Materials and Finishes - NLRS_C_Afwerking Kozijn: Kozijn Bamboo - Deur Bamboo; Fire Protection - NLRS_C_brandwerendheid: 30
Basic Wall:22_DAT_binnenwand_125 HPL dubbel:6400512 | 00 Begane grond | 22.13 Uniformat (Uniformat) | 429.8 | 2390 | 2300 | Merk H21 | 2 | Walls | Non-bearing | houten kozijn | 31.10 | houten kozijn | 31.10 | 31.10 | buitenwandopeningen; niet gevuld, algemeen (verzamelniveau) | houten kozijn | Walls | Curtain Wall | Curtain Wall: Merk H21 | Merk H21 | 5893300 | 0 | no | yes | 0 | 400 | 2390 | 5.497 | 2300 | Bouwkundig | 2. nieuwbouw | Non-bearing | 0 | Beginning | 4 | 2 | Vertical | Materials and Finishes - NLRS_C_Afwerking Kozijn: S3020-Y20R - Deur HPL Formica F0903 cafe; Pset_wanden - IfcMaterial: S3020-Y20R - Deur HPL Formica F0903 cafe; NLRS_C_afwerkingsklasse: S3020-Y20R - Deur HPL Formica F0903 cafe
Basic Wall:22_DAT_binnenwand_125 HPL dubbel:6400512 | 00 Begane grond | 22.13 Uniformat (Uniformat) | 429.8 | 2390 | 1825 | Merk H04 | 2 | Walls | Non-bearing | houten kozijn | 31.10 | houten kozijn | 31.10 | 31.10 | buitenwandopeningen; niet gevuld, algemeen (verzamelniveau) | houten kozijn | Walls | Curtain Wall | Curtain Wall: Merk H04 | Merk H04 | 6102986 | 0 | no | yes | 0 | 400 | 2390 | 4.36175 | 1825 | Bouwkundig | 2. nieuwbouw | Non-bearing | 0 | Beginning | 4 | 2 | Vertical | Pset_wanden - NLRS_C_Geluidwering_DnTA: 25; NLRS_C_brandwerendheid: 30; Pset_kozijnen (CW) - NLRS_C_Geluidwering_DnTA: 25; NLRS_C_brandwerendheid: 30; Data - NLRS_C_Geluidwering_DnTA: 25; Materials and Finishes - NLRS_C_Afwerking Kozijn: Kozijn Bamboo - Deur Bamboo; Fire Protection - NLRS_C_brandwerendheid: 30
Basic Wall:22_DAT_binnenwand_125 HPL:6402098 | 00 Begane grond | 22.13 Uniformat (Uniformat) | 429.8 | 2390 | 2360 | Merk H24 | 2 | Walls | Non-bearing | houten kozijn | 31.10 | houten kozijn | 31.10 | 31.10 | buitenwandopeningen; niet gevuld, algemeen (verzamelniveau) | houten kozijn | Walls | Curtain Wall | Curtain Wall: Merk H24 | Merk H24 | 5489050 | 0 | no | yes | 0 | 400 | 2390 | 5.6404 | 2360 | Bouwkundig | 2. nieuwbouw | Non-bearing | 0 | Beginning | 4 | 2 | Vertical | Materials and Finishes - NLRS_C_Afwerking Kozijn: S3020-Y20R - Deur HPL Formica F0903 cafe
Basic Wall:22_DAT_binnenwand_125 HPL:6402098 | 00 Begane grond | 22.13 Uniformat (Uniformat) | 429.8 | 2390 | 1825 | Merk H04 | 2 | Walls | Non-bearing | houten kozijn | 31.10 | houten kozijn | 31.10 | 31.10 | buitenwandopeningen; niet gevuld, algemeen (verzamelniveau) | houten kozijn | Walls | Curtain Wall | Curtain Wall: Merk H04 | Merk H04 | 6102986 | 0 | no | yes | 0 | 400 | 2390 | 4.36175 | 1825 | Bouwkundig | 2. nieuwbouw | Non-bearing | 0 | Beginning | 4 | 2 | Vertical | Pset_wanden - NLRS_C_Geluidwering_DnTA: 25; Pset_kozijnen (CW) - NLRS_C_Geluidwering_DnTA: 25; Data - NLRS_C_Geluidwering_DnTA: 25; Materials and Finishes - NLRS_C_Afwerking Kozijn: Kozijn Bamboo - Deur Bamboo
Basic Wall:22_DAT_binnenwand_125:6428112 | 00 Begane grond | 22.13 Uniformat (Uniformat) | 429.8 | 2415 | 563 | 22_DAT_binnenwand_125 HPL | 2 | Walls | Non-bearing | Lichte scheidingswand 125mmAan weerszijden gipsvezelplaat 12,5mmGipsplaat 12,5mm Met daartussen 75mm ms wand gevuld met isolatieVulling afhankelijk van gestelde eisen ingeluidsrapportage | 22.13 |  |  | 22.13 | binnenwanden; niet constructief, systeemwanden; vast | Lichte scheidingswand 125mmAan weerszijden gipsvezelplaat 12,5mmGipsplaat 12,5mm Met daartussen 75mm ms wand gevuld met isolatieVulling afhankelijk van gestelde eisen ingeluidsrapportage | Walls | Basic Wall | Basic Wall: 22_DAT_binnenwand_125 HPL | 22_DAT_binnenwand_125 HPL | 6329633 | 0 | no | yes | 0 | 0 | 2415 | 1.35964 | 563 | Bouwkundig | 2. nieuwbouw | Non-bearing |  |  |  |  | Vertical | Dimensions - Volume: 0.169956 m3; Constraints - Base Extension Distance: 0 mm; Top Extension Distance: 0 mm; Location Line: Wall Centerline
Basic Wall:21_DAT_zetwerk_2:4664595 | 00 Begane grond | 21.12 Uniformat (Uniformat) |  | 332 | 38.6157 | 21_DAT_zetwerk_2 | 2 | Lines: <Sketch> |  |  |  |  |  |  |  |  |  |  |  |  |  |  |  |  |  |  |  |  | 332 | Bouwkundig | Pset_ProductRequirements - sets with these values: 2
Basic Wall:28_DAT_kalkzandsteen_175mm:6516634 | 00 Begane grond | 28.21 Uniformat (Uniformat) | 479.8 | 3310 | 160 | 22_DAT_binnenwand_25 | 2 | Walls | Non-bearing | Lichte scheidingswand 100mm | 22.13 |  |  | 22.13 | binnenwanden; niet constructief, systeemwanden; vast | Lichte scheidingswand 100mm | Walls | Basic Wall | Basic Wall: 22_DAT_binnenwand_25 | 22_DAT_binnenwand_25 | 4977124 | 0 | no | yes | V0 bk. ruwe vloer | 0 | 3310 | 0.5296 | 160 | Bouwkundig | 2. nieuwbouw | Non-bearing |  |  |  |  | Vertical | Dimensions - Volume: 0.01324 m3; Constraints - Base Extension Distance: 0 mm; Top Extension Distance: 0 mm; Location Line: Wall Centerline; Top Constraint: Up to level: V1 ok. ruwe vloer
Basic Wall:28_DAT_kalkzandsteen_175mm:6516634 | 00 Begane grond | 28.21 Uniformat (Uniformat) | 479.8 | 2630 | 1495 | K_14 | 2 | Walls | Non-bearing | Kunststof kozijn Gealan Kubus | 31 | Kunststof kozijn Gealan Kubus | 31 | 31 | buitenwandopeningen | Kunststof kozijn Gealan Kubus | Walls | Curtain Wall | Curtain Wall: K_14 | K_14 | 4906721 | 10 | no | yes | 0 | 0 | 2630 | 3.93185 | 1495 | Bouwkundig | 2. nieuwbouw | Non-bearing | 0 | Beginning | 4 | 2 | Vertical | Other - Doorvalveilig 1-zijdig: no; Doorvalveilig 2-zijdig: yes; Text - NLRS_C_merk: K01
Basic Wall:28_DAT_kalkzandsteen_175mm:6516634 | 00 Begane grond | 28.21 Uniformat (Uniformat) | 479.8 | 2630 | 3450 | K_15 | 2 | Walls | Non-bearing | Kunststof kozijn Gealan Kubus | 31 | Kunststof kozijn Gealan Kubus | 31 | 31 | buitenwandopeningen | Kunststof kozijn Gealan Kubus | Walls | Curtain Wall | Curtain Wall: K_15 | K_15 | 4912009 | 10 | no | yes | 0 | 0 | 2630 | 9.0735 | 3450 | Bouwkundig | 2. nieuwbouw | Non-bearing | 0 | Beginning | 4 | 2 | Vertical | Other - Doorvalveilig 1-zijdig: no; Doorvalveilig 2-zijdig: yes; Text - NLRS_C_merk: K01
Basic Wall:28_DAT_kalkzandsteen_175mm:6516999 | 00 Begane grond | 28.21 Uniformat (Uniformat) | 479.8 | 3310 | 160 | 22_DAT_binnenwand_25 | 2 | Walls | Non-bearing | Lichte scheidingswand 100mm | 22.13 |  |  | 22.13 | binnenwanden; niet constructief, systeemwanden; vast | Lichte scheidingswand 100mm | Walls | Basic Wall | Basic Wall: 22_DAT_binnenwand_25 | 22_DAT_binnenwand_25 | 4977124 | 0 | no | yes | V0 bk. ruwe vloer | 0 | 3310 | 0.5296 | 160 | Bouwkundig | 2. nieuwbouw | Non-bearing |  |  |  |  | Vertical | Dimensions - Volume: 0.01324 m3; Constraints - Base Extension Distance: 0 mm; Top Extension Distance: 0 mm; Location Line: Wall Centerline; Top Constraint: Up to level: V1 ok. ruwe vloer
2 x Basic Wall:28_DAT_kalkzandsteen_175mm:6516999 | 00 Begane grond | 28.21 Uniformat (Uniformat) | 479.8 | 3310 | 190 | 22_DAT_binnenwand_25 | 2 | Walls | Non-bearing | Lichte scheidingswand 100mm | 22.13 |  |  | 22.13 | binnenwanden; niet constructief, systeemwanden; vast | Lichte scheidingswand 100mm | Walls | Basic Wall | Basic Wall: 22_DAT_binnenwand_25 | 22_DAT_binnenwand_25 | 4977124 | 0 | no | yes | V0 bk. ruwe vloer | 0 | 3310 | 0.6289 | 190 | Bouwkundig | 2. nieuwbouw | Non-bearing |  |  |  |  | Vertical | Dimensions - Volume: 0.0157225 m3; Constraints - Base Extension Distance: 0 mm; Top Extension Distance: 0 mm; Location Line: Wall Centerline; Top Constraint: Up to level: V1 ok. ruwe vloer
Basic Wall:22_DAT_binnenwand_125:6522723 | 00 Begane grond | 22.13 Uniformat (Uniformat) | 429.8 | 2390 | 1034 | Merk H02 | 2 | Walls | Non-bearing | houten kozijn | 31.10 | houten kozijn | 31.10 | 31.10 | buitenwandopeningen; niet gevuld, algemeen (verzamelniveau) | houten kozijn | Walls | Curtain Wall | Curtain Wall: Merk H02 | Merk H02 | 5128107 | 0 | no | yes | 0 | 400 | 2390 | 2.47126 | 1034 | Bouwkundig | 2. nieuwbouw | Non-bearing | 0 | Beginning | 4 | 2 | Vertical | Pset_wanden - NLRS_C_Geluidwering_DnTA: 25; Pset_kozijnen (CW) - NLRS_C_Geluidwering_DnTA: 25; Data - NLRS_C_Geluidwering_DnTA: 25; Materials and Finishes - NLRS_C_Afwerking Kozijn: Ral 9010 - Deur HPL Formica F2296 Sno White
Basic Wall:43_DAT_Wandtegelwerk:6522728 | 00 Begane grond | 42.12 Uniformat (Uniformat) | 314.8 | 2390 | 1034 | Merk H02 | 2 | Walls | Non-bearing | houten kozijn | 31.10 | houten kozijn | 31.10 | 31.10 | buitenwandopeningen; niet gevuld, algemeen (verzamelniveau) | houten kozijn | Walls | Curtain Wall | Curtain Wall: Merk H02 | Merk H02 | 5128107 | 0 | no | yes | 0 | 400 | 2390 | 2.47126 | 1034 | Bouwkundig | 2. nieuwbouw | Non-bearing | 0 | Beginning | 4 | 2 | Vertical | Pset_wanden - NLRS_C_Geluidwering_DnTA: 25; Pset_kozijnen (CW) - NLRS_C_Geluidwering_DnTA: 25; Data - NLRS_C_Geluidwering_DnTA: 25; Materials and Finishes - NLRS_C_Afwerking Kozijn: Ral 9010 - Deur HPL Formica F2296 Sno White
Basic Wall:22_DAT_binnenwand_125:6668692 | 00 Begane grond | 22.13 Uniformat (Uniformat) | 429.8 | 2390 | 1134 | Merk H09 | 2 | Walls | Non-bearing | houten kozijn | 31.10 | houten kozijn | 31.10 | 31.10 | buitenwandopeningen; niet gevuld, algemeen (verzamelniveau) | houten kozijn | Walls | Curtain Wall | Curtain Wall: Merk H09 | Merk H09 | 5149044 | 0 | no | yes | 0 | 400 | 2390 | 2.71026 | 1134 | Bouwkundig | 2. nieuwbouw | Non-bearing | 0 | Beginning | 4 | 2 | Vertical | Pset_wanden - NLRS_C_Geluidwering_DnTA: 39; Pset_kozijnen (CW) - NLRS_C_Geluidwering_DnTA: 39; Data - NLRS_C_Geluidwering_DnTA: 39; Materials and Finishes - NLRS_C_Afwerking Kozijn: Ral 9010 - Deur HPL Formica F2296 Sno White
Basic Wall:22_DAT_binnenwand_125 HPL:6693819 | 00 Begane grond | 22.13 Uniformat (Uniformat) | 429.8 | 2390 | 1470 | Merk H03 | 2 | Walls | Non-bearing | houten kozijn | 31.10 | houten kozijn | 31.10 | 31.10 | buitenwandopeningen; niet gevuld, algemeen (verzamelniveau) | houten kozijn | Walls | Curtain Wall | Curtain Wall: Merk H03 | Merk H03 | 5128005 | 0 | no | yes | 0 | 400 | 2390 | 3.5133 | 1470 | Bouwkundig | 2. nieuwbouw | Non-bearing | 0 | Beginning | 4 | 2 | Vertical | Pset_wanden - NLRS_C_Geluidwering_DnTA: 31; NLRS_C_brandwerendheid: 30; Pset_kozijnen (CW) - NLRS_C_Geluidwering_DnTA: 31; NLRS_C_brandwerendheid: 30; Data - NLRS_C_Geluidwering_DnTA: 31; Materials and Finishes - NLRS_C_Afwerking Kozijn: Kozijn Bamboo - Deur Bamboo; Fire Protection - NLRS_C_brandwerendheid: 30
Basic Wall:22_DAT_binnenwand_125:6694068 | 00 Begane grond | 22.13 Uniformat (Uniformat) | 429.8 | 2390 | 1034 | Merk H02 | 2 | Walls | Non-bearing | houten kozijn | 31.10 | houten kozijn | 31.10 | 31.10 | buitenwandopeningen; niet gevuld, algemeen (verzamelniveau) | houten kozijn | Walls | Curtain Wall | Curtain Wall: Merk H02 | Merk H02 | 5128107 | 0 | no | yes | 0 | 400 | 2390 | 2.47126 | 1034 | Bouwkundig | 2. nieuwbouw | Non-bearing | 0 | Beginning | 4 | 2 | Vertical | Pset_wanden - NLRS_C_Geluidwering_DnTA: 25; Pset_kozijnen (CW) - NLRS_C_Geluidwering_DnTA: 25; Data - NLRS_C_Geluidwering_DnTA: 25; Materials and Finishes - NLRS_C_Afwerking Kozijn: Ral 9010 - Deur HPL Formica F2296 Sno White
Basic Wall:21_DAT_Hekwerk 175:6777284 | 00 Begane grond | 21.10 Uniformat (Uniformat) | 479.8 | 2180 | 2300 | K_07 | 2 | Walls | Non-bearing | Kunststof kozijn Gealan Kubus | 31 | Kunststof kozijn Gealan Kubus | 31 | 31 | buitenwandopeningen | Kunststof kozijn Gealan Kubus | Walls | Curtain Wall | Curtain Wall: K_07 | K_07 | 4849800 | 710 | no | yes | 0 | 0 | 2180 | 5.014 | 2300 | Bouwkundig | 2. nieuwbouw | Non-bearing | 0 | Beginning | 4 | 2 | Vertical | Other - Doorvalveilig 1-zijdig: no; Doorvalveilig 2-zijdig: yes; Text - NLRS_C_merk: K01
2 x Basic Wall:21_DAT_Hekwerk 175:6779811 | 01 eerste verdieping | 21.10 Uniformat (Uniformat) | 479.8 | 1930 | 880 | K_31 | 2 | Walls | Non-bearing | Kunststof kozijn Gealan Kubus | 31 | Kunststof kozijn Gealan Kubus | 31 | 31 | buitenwandopeningen | Kunststof kozijn Gealan Kubus | Walls | Curtain Wall | Curtain Wall: K_31 | K_31 | 6069143 | 810 | no | yes | 1 | 0 | 1930 | 1.6984 | 880 | Bouwkundig | 2. nieuwbouw | Non-bearing | 0 | Beginning | 4 | 2 | Vertical | Other - Doorvalveilig 1-zijdig: no; Doorvalveilig 2-zijdig: yes; Text - NLRS_C_merk: K01
2 x Basic Wall:21_DAT_Hekwerk 175:6779843 | 01 eerste verdieping | 21.10 Uniformat (Uniformat) | 479.8 | 1930 | 880 | K_28 | 2 | Walls | Non-bearing | Kunststof kozijn Gealan Kubus | 31 | Kunststof kozijn Gealan Kubus | 31 | 31 | buitenwandopeningen | Kunststof kozijn Gealan Kubus | Walls | Curtain Wall | Curtain Wall: K_28 | K_28 | 6068408 | 810 | no | yes | 1 | 0 | 1930 | 1.6984 | 880 | Bouwkundig | 2. nieuwbouw | Non-bearing | 0 | Beginning | 4 | 2 | Vertical | Group: Model Group:Kollom tussenmaat 120x120:6152818; Other - Doorvalveilig 1-zijdig: no; Doorvalveilig 2-zijdig: yes; Text - NLRS_C_merk: K01
Basic Wall:21_DAT_Hekwerk 175:6779843 | 01 eerste verdieping | 21.10 Uniformat (Uniformat) | 479.8 | 1930 | 2040 | K_24 | 2 | Walls | Non-bearing | Kunststof kozijn Gealan Kubus | 31 | Kunststof kozijn Gealan Kubus | 31 | 31 | buitenwandopeningen | Kunststof kozijn Gealan Kubus | Walls | Curtain Wall | Curtain Wall: K_24 | K_24 | 4801721 | 810 | no | yes | 1 | 0 | 1930 | 3.9372 | 2040 | Bouwkundig | 2. nieuwbouw | Non-bearing | 0 | Beginning | 4 | 2 | Vertical | Group: Model Group:Kollom tussenmaat 120x120:6152818; Other - Doorvalveilig 1-zijdig: no; Doorvalveilig 2-zijdig: yes; Text - NLRS_C_merk: K01
2 x Basic Wall:21_DAT_Hekwerk 175:6779844 | 01 eerste verdieping | 21.10 Uniformat (Uniformat) | 479.8 | 1930 | 880 | K_28 | 2 | Walls | Non-bearing | Kunststof kozijn Gealan Kubus | 31 | Kunststof kozijn Gealan Kubus | 31 | 31 | buitenwandopeningen | Kunststof kozijn Gealan Kubus | Walls | Curtain Wall | Curtain Wall: K_28 | K_28 | 6068408 | 810 | no | yes | 1 | 0 | 1930 | 1.6984 | 880 | Bouwkundig | 2. nieuwbouw | Non-bearing | 0 | Beginning | 4 | 2 | Vertical | Group: Model Group:Kollom tussenmaat 120x120:6152818; Other - Doorvalveilig 1-zijdig: no; Doorvalveilig 2-zijdig: yes; Text - NLRS_C_merk: K01
Basic Wall:21_DAT_Hekwerk 175:6779844 | 01 eerste verdieping | 21.10 Uniformat (Uniformat) | 479.8 | 1930 | 2040 | K_24 | 2 | Walls | Non-bearing | Kunststof kozijn Gealan Kubus | 31 | Kunststof kozijn Gealan Kubus | 31 | 31 | buitenwandopeningen | Kunststof kozijn Gealan Kubus | Walls | Curtain Wall | Curtain Wall: K_24 | K_24 | 4801721 | 810 | no | yes | 1 | 0 | 1930 | 3.9372 | 2040 | Bouwkundig | 2. nieuwbouw | Non-bearing | 0 | Beginning | 4 | 2 | Vertical | Group: Model Group:Kollom tussenmaat 120x120:6152818; Other - Doorvalveilig 1-zijdig: no; Doorvalveilig 2-zijdig: yes; Text - NLRS_C_merk: K01
Basic Wall:21_DAT_Hekwerk 175:6781345 | 00 Begane grond | 21.10 Uniformat (Uniformat) | 479.8 | 2630 | 2120 | K_02 | 2 | Walls | Non-bearing | Kunststof kozijn Gealan Kubus | 31 | Kunststof kozijn Gealan Kubus | 31 | 31 | buitenwandopeningen | Kunststof kozijn Gealan Kubus | Walls | Curtain Wall | Curtain Wall: K_02 | K_02 | 4792108 | 10 | no | yes | 0 | 0 | 2630 | 5.5756 | 2120 | Bouwkundig | 2. nieuwbouw | Non-bearing | 0 | Beginning | 4 | 2 | Vertical | Other - Doorvalveilig 1-zijdig: no; Doorvalveilig 2-zijdig: yes; Text - NLRS_C_merk: K01
Basic Wall:21_DAT_Hekwerk 175:6781413 | 00 Begane grond | 21.10 Uniformat (Uniformat) | 479.8 | 2610 | 2120 | K_03 | 2 | Walls | Non-bearing | Kunststof kozijn Gealan Linear | 31 | Kunststof kozijn Gealan Linear | 31 | 31 | buitenwandopeningen | Kunststof kozijn Gealan Linear | Walls | Curtain Wall | Curtain Wall: K_03 | K_03 | 4793066 | 30 | no | yes | 0 | 0 | 2610 | 5.5332 | 2120 | Bouwkundig | 2. nieuwbouw | Non-bearing | 0 | Beginning | 4 | 2 | Vertical | Other - Doorvalveilig 1-zijdig: no; Doorvalveilig 2-zijdig: yes; Text - NLRS_C_merk: K01
Basic Wall:21_DAT_Hekwerk 175:6781667 | 00 Begane grond | 21.10 Uniformat (Uniformat) | 479.8 | 2610 | 2120 | K_03 | 2 | Walls | Non-bearing | Kunststof kozijn Gealan Linear | 31 | Kunststof kozijn Gealan Linear | 31 | 31 | buitenwandopeningen | Kunststof kozijn Gealan Linear | Walls | Curtain Wall | Curtain Wall: K_03 | K_03 | 4793066 | 30 | no | yes | 0 | 0 | 2610 | 5.5332 | 2120 | Bouwkundig | 2. nieuwbouw | Non-bearing | 0 | Beginning | 4 | 2 | Vertical | Other - Doorvalveilig 1-zijdig: no; Doorvalveilig 2-zijdig: yes; Text - NLRS_C_merk: K01
Basic Wall:21_DAT_Hekwerk 175:6781673 | 00 Begane grond | 21.10 Uniformat (Uniformat) | 479.8 | 2610 | 2120 | K_03 | 2 | Walls | Non-bearing | Kunststof kozijn Gealan Linear | 31 | Kunststof kozijn Gealan Linear | 31 | 31 | buitenwandopeningen | Kunststof kozijn Gealan Linear | Walls | Curtain Wall | Curtain Wall: K_03 | K_03 | 4793066 | 30 | no | yes | 0 | 0 | 2610 | 5.5332 | 2120 | Bouwkundig | 2. nieuwbouw | Non-bearing | 0 | Beginning | 4 | 2 | Vertical | Other - Doorvalveilig 1-zijdig: no; Doorvalveilig 2-zijdig: yes; Text - NLRS_C_merk: K01
Basic Wall:21_DAT_Hekwerk 175:6781676 | 00 Begane grond | 21.10 Uniformat (Uniformat) | 479.8 | 2610 | 2120 | K_03 | 2 | Walls | Non-bearing | Kunststof kozijn Gealan Linear | 31 | Kunststof kozijn Gealan Linear | 31 | 31 | buitenwandopeningen | Kunststof kozijn Gealan Linear | Walls | Curtain Wall | Curtain Wall: K_03 | K_03 | 4793066 | 30 | no | yes | 0 | 0 | 2610 | 5.5332 | 2120 | Bouwkundig | 2. nieuwbouw | Non-bearing | 0 | Beginning | 4 | 2 | Vertical | Other - Doorvalveilig 1-zijdig: no; Doorvalveilig 2-zijdig: yes; Text - NLRS_C_merk: K01
Basic Wall:28_DAT_kalkzandsteen_175mm:6788664 | 00 Begane grond | 28.21 Uniformat (Uniformat) | 479.8 | 5055 | 790 | K_09 | 2 | Walls | Non-bearing | Kunststof kozijn Gealan Kubus | 31 | Kunststof kozijn Gealan Kubus | 31 | 31 | buitenwandopeningen | Kunststof kozijn Gealan Kubus | Walls | Curtain Wall | Curtain Wall: K_09 | K_09 | 4858854 | 1335 | no | yes | 0 | 0 | 5055 | 3.99345 | 790 | Bouwkundig | 2. nieuwbouw | Non-bearing | 0 | Beginning | 4 | 2 | Vertical | Other - Doorvalveilig 1-zijdig: no; Doorvalveilig 2-zijdig: yes; Text - NLRS_C_merk: K01
Basic Wall:28_DAT_kalkzandsteen_175mm:6788756 | 00 Begane grond | 28.21 Uniformat (Uniformat) | 479.8 | 4430 | 790 | K_10 | 2 | Walls | Non-bearing | Kunststof kozijn Gealan Kubus | 31 | Kunststof kozijn Gealan Kubus | 31 | 31 | buitenwandopeningen | Kunststof kozijn Gealan Kubus | Walls | Curtain Wall | Curtain Wall: K_10 | K_10 | 4859456 | 1960 | no | yes | 0 | 0 | 4430 | 3.4997 | 790 | Bouwkundig | 2. nieuwbouw | Non-bearing | 0 | Beginning | 4 | 2 | Vertical | Other - Doorvalveilig 1-zijdig: no; Doorvalveilig 2-zijdig: yes; Text - NLRS_C_merk: K01
Basic Wall:28_DAT_kalkzandsteen_175mm:6788801 | 00 Begane grond | 28.21 Uniformat (Uniformat) | 479.8 | 3805 | 790 | K_11 | 2 | Walls | Non-bearing | Kunststof kozijn Gealan Kubus | 31 | Kunststof kozijn Gealan Kubus | 31 | 31 | buitenwandopeningen | Kunststof kozijn Gealan Kubus | Walls | Curtain Wall | Curtain Wall: K_11 | K_11 | 4859827 | 2585 | no | yes | 0 | 0 | 3805 | 3.00595 | 790 | Bouwkundig | 2. nieuwbouw | Non-bearing | 0 | Beginning | 4 | 2 | Vertical | Other - Doorvalveilig 1-zijdig: no; Doorvalveilig 2-zijdig: yes; Text - NLRS_C_merk: K01
Basic Wall:28_DAT_kalkzandsteen_175mm:6788809 | 00 Begane grond | 28.21 Uniformat (Uniformat) | 479.8 | 3180 | 790 | K_12 | 2 | Walls | Non-bearing | Kunststof kozijn Gealan Kubus | 31 | Kunststof kozijn Gealan Kubus | 31 | 31 | buitenwandopeningen | Kunststof kozijn Gealan Kubus | Walls | Curtain Wall | Curtain Wall: K_12 | K_12 | 4860014 | 3210 | no | yes | 0 | 0 | 3180 | 2.5122 | 790 | Bouwkundig | 2. nieuwbouw | Non-bearing | 0 | Beginning | 4 | 2 | Vertical | Other - Doorvalveilig 1-zijdig: no; Doorvalveilig 2-zijdig: yes; Text - NLRS_C_merk: K01
Basic Wall:28_DAT_kalkzandsteen_175mm:6788819 | 00 Begane grond | 28.21 Uniformat (Uniformat) | 479.8 | 2555 | 790 | K_13 | 2 | Walls | Non-bearing | Kunststof kozijn Gealan Kubus | 31 | Kunststof kozijn Gealan Kubus | 31 | 31 | buitenwandopeningen | Kunststof kozijn Gealan Kubus | Walls | Curtain Wall | Curtain Wall: K_13 | K_13 | 4860509 | 3835 | no | yes | 0 | 0 | 2555 | 2.01845 | 790 | Bouwkundig | 2. nieuwbouw | Non-bearing | 0 | Beginning | 4 | 2 | Vertical | Other - Doorvalveilig 1-zijdig: no; Doorvalveilig 2-zijdig: yes; Text - NLRS_C_merk: K01
Basic Wall:21_DAT_Hekwerk 175:6789433 | 00 Begane grond | 21.10 Uniformat (Uniformat) | 479.8 | 5055 | 790 | K_09 | 2 | Walls | Non-bearing | Kunststof kozijn Gealan Kubus | 31 | Kunststof kozijn Gealan Kubus | 31 | 31 | buitenwandopeningen | Kunststof kozijn Gealan Kubus | Walls | Curtain Wall | Curtain Wall: K_09 | K_09 | 4858854 | 1335 | no | yes | 0 | 0 | 5055 | 3.99345 | 790 | Bouwkundig | 2. nieuwbouw | Non-bearing | 0 | Beginning | 4 | 2 | Vertical | Group: Model Group:Kollom tussenmaat 150x150 Trap:6789422; Other - Doorvalveilig 1-zijdig: no; Doorvalveilig 2-zijdig: yes; Text - NLRS_C_merk: K01
Basic Wall:21_DAT_Hekwerk 150:6790580 | 01 eerste verdieping | 21.10 Uniformat (Uniformat) | 454.8 | 1930 | 790 | K_29 | 2 | Walls | Non-bearing | Kunststof kozijn Gealan Kubus | 31 | Kunststof kozijn Gealan Kubus | 31 | 31 | buitenwandopeningen | Kunststof kozijn Gealan Kubus | Walls | Curtain Wall | Curtain Wall: K_29 | K_29 | 4860879 | 810 | no | yes | 1 | 0 | 1930 | 1.5247 | 790 | Bouwkundig | 2. nieuwbouw | Non-bearing | 0 | Beginning | 4 | 2 | Vertical | Group: Model Group:Kollom tussenmaat 120x120 eerste verdieping:6790571; Other - Doorvalveilig 1-zijdig: no; Doorvalveilig 2-zijdig: yes; Text - NLRS_C_merk: K01
Basic Wall:21_DAT_Hekwerk 150:6791144 | 01 eerste verdieping | 21.10 Uniformat (Uniformat) | 454.8 | 1930 | 2250 | K_22 | 2 | Walls | Non-bearing | Kunststof kozijn Gealan Kubus | 31 | Kunststof kozijn Gealan Kubus | 31 | 31 | buitenwandopeningen | Kunststof kozijn Gealan Kubus | Walls | Curtain Wall | Curtain Wall: K_22 | K_22 | 4917986 | 810 | no | yes | 1 | 0 | 1930 | 4.3425 | 2250 | Bouwkundig | 2. nieuwbouw | Non-bearing | 0 | Beginning | 4 | 2 | Vertical | Group: Model Group:Kollom tussenmaat 120x120 eerste verdieping:6791136; Other - Doorvalveilig 1-zijdig: no; Doorvalveilig 2-zijdig: yes; Text - NLRS_C_merk: K01
Basic Wall:21_DAT_Hekwerk 150:6791155 | 01 eerste verdieping | 21.10 Uniformat (Uniformat) | 454.8 | 1930 | 790 | K_29 | 2 | Walls | Non-bearing | Kunststof kozijn Gealan Kubus | 31 | Kunststof kozijn Gealan Kubus | 31 | 31 | buitenwandopeningen | Kunststof kozijn Gealan Kubus | Walls | Curtain Wall | Curtain Wall: K_29 | K_29 | 4860879 | 810 | no | yes | 1 | 0 | 1930 | 1.5247 | 790 | Bouwkundig | 2. nieuwbouw | Non-bearing | 0 | Beginning | 4 | 2 | Vertical | Group: Model Group:Kollom tussenmaat 120x120 eerste verdieping:6791147; Other - Doorvalveilig 1-zijdig: no; Doorvalveilig 2-zijdig: yes; Text - NLRS_C_merk: K01
Basic Wall:21_DAT_Hekwerk 150:6791988 | 01 eerste verdieping | 21.10 Uniformat (Uniformat) | 454.8 | 1930 | 790 | K_30 | 2 | Walls | Non-bearing | Kunststof kozijn Gealan Kubus | 31 | Kunststof kozijn Gealan Kubus | 31 | 31 | buitenwandopeningen | Kunststof kozijn Gealan Kubus | Walls | Curtain Wall | Curtain Wall: K_30 | K_30 | 4942327 | 810 | no | yes | 1 | 0 | 1930 | 1.5247 | 790 | Bouwkundig | 2. nieuwbouw | Non-bearing | 0 | Beginning | 4 | 2 | Vertical | Group: Model Group:Kollom tussenmaat 120x120 eerste verdieping:6791290; Other - Doorvalveilig 1-zijdig: no; Doorvalveilig 2-zijdig: yes; Text - NLRS_C_merk: K01
9 x Basic Wall:21_DAT_Hekwerk 150:6791988 | 01 eerste verdieping | 21.10 Uniformat (Uniformat) | 454.8 | 1930 | 790 | K_29 | 2 | Walls | Non-bearing | Kunststof kozijn Gealan Kubus | 31 | Kunststof kozijn Gealan Kubus | 31 | 31 | buitenwandopeningen | Kunststof kozijn Gealan Kubus | Walls | Curtain Wall | Curtain Wall: K_29 | K_29 | 4860879 | 810 | no | yes | 1 | 0 | 1930 | 1.5247 | 790 | Bouwkundig | 2. nieuwbouw | Non-bearing | 0 | Beginning | 4 | 2 | Vertical | Group: Model Group:Kollom tussenmaat 120x120 eerste verdieping:6791290; Other - Doorvalveilig 1-zijdig: no; Doorvalveilig 2-zijdig: yes; Text - NLRS_C_merk: K01
6 x Basic Wall:21_DAT_Hekwerk 150:6791988 | 01 eerste verdieping | 21.10 Uniformat (Uniformat) | 454.8 | 1930 | 2250 | K_22 | 2 | Walls | Non-bearing | Kunststof kozijn Gealan Kubus | 31 | Kunststof kozijn Gealan Kubus | 31 | 31 | buitenwandopeningen | Kunststof kozijn Gealan Kubus | Walls | Curtain Wall | Curtain Wall: K_22 | K_22 | 4917986 | 810 | no | yes | 1 | 0 | 1930 | 4.3425 | 2250 | Bouwkundig | 2. nieuwbouw | Non-bearing | 0 | Beginning | 4 | 2 | Vertical | Group: Model Group:Kollom tussenmaat 120x120 eerste verdieping:6791290; Other - Doorvalveilig 1-zijdig: no; Doorvalveilig 2-zijdig: yes; Text - NLRS_C_merk: K01
2 x Basic Wall:21_DAT_Hekwerk 150:6791988 | 01 eerste verdieping | 21.10 Uniformat (Uniformat) | 454.8 | 1930 | 2250 | K_32 | 2 | Walls | Non-bearing | Kunststof kozijn Gealan Kubus | 31 | Kunststof kozijn Gealan Kubus | 31 | 31 | buitenwandopeningen | Kunststof kozijn Gealan Kubus | Walls | Curtain Wall | Curtain Wall: K_32 | K_32 | 6474551 | 810 | no | yes | 1 | 0 | 1930 | 4.3425 | 2250 | Bouwkundig | 2. nieuwbouw | Non-bearing | 0 | Beginning | 4 | 2 | Vertical | Group: Model Group:Kollom tussenmaat 120x120 eerste verdieping:6791290; Other - Doorvalveilig 1-zijdig: no; Doorvalveilig 2-zijdig: yes; Text - NLRS_C_merk: K01
Basic Wall:21_DAT_Hekwerk 150:6791988 | 01 eerste verdieping | 21.10 Uniformat (Uniformat) | 454.8 | 2760 | 1495 | K_26 | 2 | Walls | Non-bearing | Kunststof kozijn Gealan Kubus | 31 | Kunststof kozijn Gealan Kubus | 31 | 31 | buitenwandopeningen | Kunststof kozijn Gealan Kubus | Walls | Curtain Wall | Curtain Wall: K_26 | K_26 | 4951884 | -20 | no | yes | 1 | 0 | 2760 | 4.1262 | 1495 | Bouwkundig | 2. nieuwbouw | Non-bearing | 0 | Beginning | 4 | 2 | Vertical | Group: Model Group:Kollom tussenmaat 120x120 eerste verdieping:6791290; Other - Doorvalveilig 1-zijdig: no; Doorvalveilig 2-zijdig: yes; Text - NLRS_C_merk: K01
Basic Wall:21_DAT_Hekwerk 150:6791988 | 01 eerste verdieping | 21.10 Uniformat (Uniformat) | 454.8 | 2760 | 3450 | K_27 | 2 | Walls | Non-bearing | Kunststof kozijn Gealan Kubus | 31 | Kunststof kozijn Gealan Kubus | 31 | 31 | buitenwandopeningen | Kunststof kozijn Gealan Kubus | Walls | Curtain Wall | Curtain Wall: K_27 | K_27 | 4952631 | -20 | no | yes | 1 | 0 | 2760 | 9.522 | 3450 | Bouwkundig | 2. nieuwbouw | Non-bearing | 0 | Beginning | 4 | 2 | Vertical | Group: Model Group:Kollom tussenmaat 120x120 eerste verdieping:6791290; Other - Doorvalveilig 1-zijdig: no; Doorvalveilig 2-zijdig: yes; Text - NLRS_C_merk: K01
2 x Basic Wall:21_DAT_metselwerk_100:5536764 | 01 eerste verdieping |  | 100 | 2125 | 2000
2 x Basic Wall:21_DAT_metselwerk_100:5536765 | 01 eerste verdieping |  | 100 | 2125 | 840
Basic Wall:21_DAT_metselwerk_100:5536765 | 01 eerste verdieping |  | 100 | 2125 | 2000
5 x Basic Wall:21_DAT_metselwerk_100:5536766 | 01 eerste verdieping |  | 100 | 2125 | 840
4 x Basic Wall:21_DAT_metselwerk_100:5536766 | 01 eerste verdieping |  | 100 | 2125 | 2000
2 x Basic Wall:21_DAT_metselwerk_100:5536777 | 00 Begane grond |  | 100 | 2125 | 2000
2 x Basic Wall:21_DAT_metselwerk_100:5536777 | 00 Begane grond |  | 100 | 2125 | 840
Basic Wall:21_DAT_metselwerk_100:5536794 | 01 eerste verdieping |  | 100 | 2125 | 840
3 x Basic Wall:21_DAT_metselwerk_100:5537279 | 00 Begane grond |  | 100 | 2125 | 2000
4 x Basic Wall:21_DAT_metselwerk_100:5537279 | 00 Begane grond |  | 100 | 2125 | 840
6 x Basic Wall:21_DAT_metselwerk_100:5538837 | 01 eerste verdieping |  | 100 | 2125 | 2000
7 x Basic Wall:21_DAT_metselwerk_100:5538837 | 01 eerste verdieping |  | 100 | 2125 | 840
2 x Basic Wall:21_DAT_metselwerk_100:5539138 | 00 Begane grond |  | 100 | 2125 | 840

# IfcOpeningElement: Recess (3)
In: 01 eerste verdieping
Classification: 21.10 Uniformat (Uniformat)
BaseQuantities - Depth: 100 mm; Height: 2125 mm
Pset_OpeningElementCommon - sets with these values: 2
Pset_ProductRequirements - Category: Windows
Pset_Window - Omschrijving: raamsparing; NL-sfb-Codering: 31
Pset_DAT_KMS - Assembly Code: 31; Assembly Description: buitenwandopeningen; Description: raamsparing
Other - Category: Windows; Family: NLRS_30_WI_WB_raamsparing_type_generiek_ISR; gevelsparing_hoogte: 2125 mm; Head Height: 2750 mm; Host Id: 5536765
Constraints - Level: 1; Sill Height: 625 mm
Dimensions - NLRS_C_hoogte: 2125 mm
Identity Data - Workset: Bouwkundig
Phasing - Phase Created: 2. nieuwbouw
Other(Type) - Category: Windows; Family Name: NLRS_30_WI_WB_raamsparing_type_generiek_ISR
Construction(Type) - gevelsparing_breedteverschil: 0 mm; gevelsparing_hoogteverschil: 0 mm; lossing: 0 mm
Dimensions(Type) - Rough Height: 0 mm; Rough Width: 0 mm; Height: 2125 mm
Graphics(Type) - clash_object_actief: no
Identity Data(Type) - Assembly Code: 31; Assembly Description: buitenwandopeningen; Description: raamsparing; Model: LOD200; OmniClass Number: 23.30.20.17.11; OmniClass Title: Fixed Windows; SmartRevit_Versie: 1.0; Workset: Family : Windows : NLRS_30_WI_WB_raamsparing_type_generiek_ISR
Analytical Properties(Type) - Define Thermal Properties by: Schematic Type; Analytic Construction: <None>
Name (Basic Wall:21_DAT_isolatie minerale wol_160:...) | BaseQuantities, Width (mm) = gevelsparing_breedte (mm) = NLRS_C_breedte (mm) = Dimensions(Type), Width (mm) | Reference = Type = Type Name | berekende_gevelsparing_BW_offset (mm) | Family and Type | Type Id | Area (m2) | Mark | gevelsparing_borstweringverschil (mm) | Type Mark
5536759 | 2000 | raamsparing_K_07 | 1562.5 | NLRS_30_WI_WB_raamsparing_type_generiek_ISR: raamsparing_K_07 | 4814872 | 5.69375 | 1098 | 500 | 1225
5536759 | 840 | raamsparing_K_42 | 1062.5 | NLRS_30_WI_WB_raamsparing_type_generiek_ISR: raamsparing_K_42 | 5545475 | 2.82275 | 991 | 0 | 1233
5536759 | 840 | raamsparing_K_42 | 1062.5 | NLRS_30_WI_WB_raamsparing_type_generiek_ISR: raamsparing_K_42 | 5545475 | 2.82275 | 992 | 0 | 1233

# IfcPlate: System Panel:30_dicht_50, System Panel:30_dicht_50:5537544
In: 00 Begane grond
Type - PredefinedType: CURTAIN_PANEL; Material: Glass 43 mm
Type - Other - Category: Curtain Panels; Family Name: System Panel
Type - Constraints - Offset: 41 mm
Type - Dimensions - Thickness: 43 mm
Type - Identity Data - Assembly Code: 31.11; Assembly Description: buitenwandopeningen; niet gevuld, daglichtopeningen; Description: Sandwichpaneel Ral:7006; Type Comments: Dicht paneel in kleur XX; Type Name: 30_dicht_50; Workset: Family : Curtain Panels : System Panel
Type - Materials and Finishes - Material: 200_ISR_Wand
Type - Analytical Properties - Define Thermal Properties by: Schematic Type; Analytic Construction: <None>
Type - Pset_PlateCommon - IsExternal: no
Type - Pset_ProductRequirements - Category: Curtain Panels
Classification: 31 Uniformat (Uniformat); Material: 200_ISR_Wand; Group: Model Group:Merk K15:5537536
Pset_PlateCommon - IsExternal: yes; Reference: 30_dicht_50
Pset_QuantityTakeOff - Reference: 30_dicht_50
Pset_DAT_KMS - Assembly Code: 31.11; Assembly Description: buitenwandopeningen; niet gevuld, daglichtopeningen; Description: Sandwichpaneel Ral:7006
BaseQuantities - NetVolume: 0.0393794 m3
Other - Host Id: 5537537; Family: System Panel; Family and Type: System Panel: 30_dicht_50; Type: 30_dicht_50; Type Id: 4079486
Constraints - Level: 0
Dimensions - Area: 0.9158 m2; Height: 2410 mm; Volume: 0.0393794 m3; Width: 380 mm
Identity Data - Workset: Bouwkundig; Mark: 3634
Phasing - Phase Created: 2. nieuwbouw

# IfcRailing: Railing:34_DAT_spijlenhekwerk_h1200 (4)
In: 00 Begane grond
Classification: 34.10 Uniformat (Uniformat); Material: ISR_Staal_groen
Pset_ProductRequirements - Category: Railings
Pset_QuantityTakeOff - Reference: 34_DAT_spijlenhekwerk_h1200
Pset_RailingCommon - IsExternal: no; Reference: 34_DAT_spijlenhekwerk_h1200; Height: 1219.2 mm
BaseQuantities - sets with these values: 2
Other - Category: Railings; Family: Railing; Family and Type: Railing: 34_DAT_spijlenhekwerk_h1200; Type: 34_DAT_spijlenhekwerk_h1200; Type Id: 6471772
Constraints - Base Offset: 0 mm; Base Level: 0
Identity Data - Workset: situatie
Phasing - Phase Created: 2. nieuwbouw
Other(Type) - Category: Railings; Family Name: Railing
Construction(Type) - Angled Joins: No Connector; Baluster Offset: 0 mm; Landing Height Adjustment: 0 mm; Rail Connections: Weld; Tangent Joins: Extend Rails to Meet; Use Landing Height Adjustment: no; Railing Height: 1175 mm
Identity Data(Type) - Workset: Railing Types; Assembly Code: 34.10; Assembly Description: balustrades en leuningen; balustrades, algemeen (verzamelniveau); Description: Spijlenhekwerk hoogte 1600mm; Type Name: 34_DAT_spijlenhekwerk_h1200
Top Rail(Type) - Height: 1219.2 mm; Use Top Rail: no
Name (Railing:34_DAT_spijlenhekwerk_h1200:...) | Length (mm) | Offset from Path (mm)
6474339 | 29061.4 | 0
6474348 | 8406.47 | 25
6474360 | 950.144 | -25
6872224 | 950.144 | -25

# IfcRailing: Railing:34_DAT_spijlenhekwerk_h1600 (5)
In: 00 Begane grond
Classification: 34.10 Uniformat (Uniformat); Material: ISR_Staal_groen
Pset_ProductRequirements - Category: Railings
Pset_QuantityTakeOff - Reference: 34_DAT_spijlenhekwerk_h1600
Pset_RailingCommon - IsExternal: no; Reference: 34_DAT_spijlenhekwerk_h1600; Height: 1219.2 mm
BaseQuantities - sets with these values: 2
Other - Category: Railings; Family: Railing; Family and Type: Railing: 34_DAT_spijlenhekwerk_h1600; Type: 34_DAT_spijlenhekwerk_h1600; Type Id: 6469334
Constraints - Base Offset: 0 mm; Base Level: 0
Identity Data - Workset: situatie
Phasing - Phase Created: 2. nieuwbouw
Other(Type) - Category: Railings; Family Name: Railing
Construction(Type) - Angled Joins: No Connector; Baluster Offset: 0 mm; Landing Height Adjustment: 0 mm; Rail Connections: Weld; Railing Height: 1575 mm; Tangent Joins: Extend Rails to Meet; Use Landing Height Adjustment: no
Identity Data(Type) - Assembly Code: 34.10; Assembly Description: balustrades en leuningen; balustrades, algemeen (verzamelniveau); Description: Spijlenhekwerk hoogte 1600mm; Type Comments: spijlenhekwerk:diameter spijl 25mmspijlen h.o.h. 100mmkleur groen; Type Name: 34_DAT_spijlenhekwerk_h1600; Workset: Railing Types
Top Rail(Type) - Height: 1219.2 mm; Use Top Rail: no
Name (Railing:34_DAT_spijlenhekwerk_h1600:...) | Length (mm) | Offset from Path (mm)
6469606 | 73431.3 | -25
6469774 | 24573.6 | -28.7
6474293 | 26184.7 | 25
6474311 | 2500 | 25
6474317 | 3481.84 | -25

# IfcRailing: Railings 10:Railings 7, Railings 10:Railings 7:6885287
In: 01 eerste verdieping
Type - Material: ISR_RVS
Type - Other - Category: Railings; Family Name: Railings 10
Type - Identity Data - Workset: Bouwkundig; Description: buisleuning gepoedercoat; Type Name: Railings 7
Type - Pset_ProductRequirements - Category: Railings
Type - Pset_RailingCommon - IsExternal: no
Pset_QuantityTakeOff - Reference: Railings 7
Pset_RailingCommon - Reference: Railings 7
Other - Type: Railings 7; Family: Railings 10; Family and Type: Railings 10: Railings 7; Type Id: 6885285
Constraints - Elevation from Level: 0 mm; Moves With Nearby Elements: no
Dimensions - Area: 0.344319 m2; Volume: 0.00688615 m3
Phasing - Phase Created: 2. nieuwbouw

# IfcRailing: Railings 2:Railings 2, Railings 2:Railings 2:6162367
In: 00 Begane grond
Type - Material: ISR_RVS
Type - Other - Category: Railings; Family Name: Railings 2
Type - Identity Data - Workset: Bouwkundig; Description: Gepoedercoat staal in Ral:; Type Name: Railings 2
Type - Pset_ProductRequirements - Category: Railings
Type - Pset_RailingCommon - IsExternal: no
Pset_QuantityTakeOff - Reference: Railings 2
Pset_RailingCommon - Reference: Railings 2
Other - Family: Railings 2; Family and Type: Railings 2: Railings 2; Type: Railings 2; Type Id: 6162365
Constraints - Moves With Nearby Elements: no; Elevation from Level: 200 mm
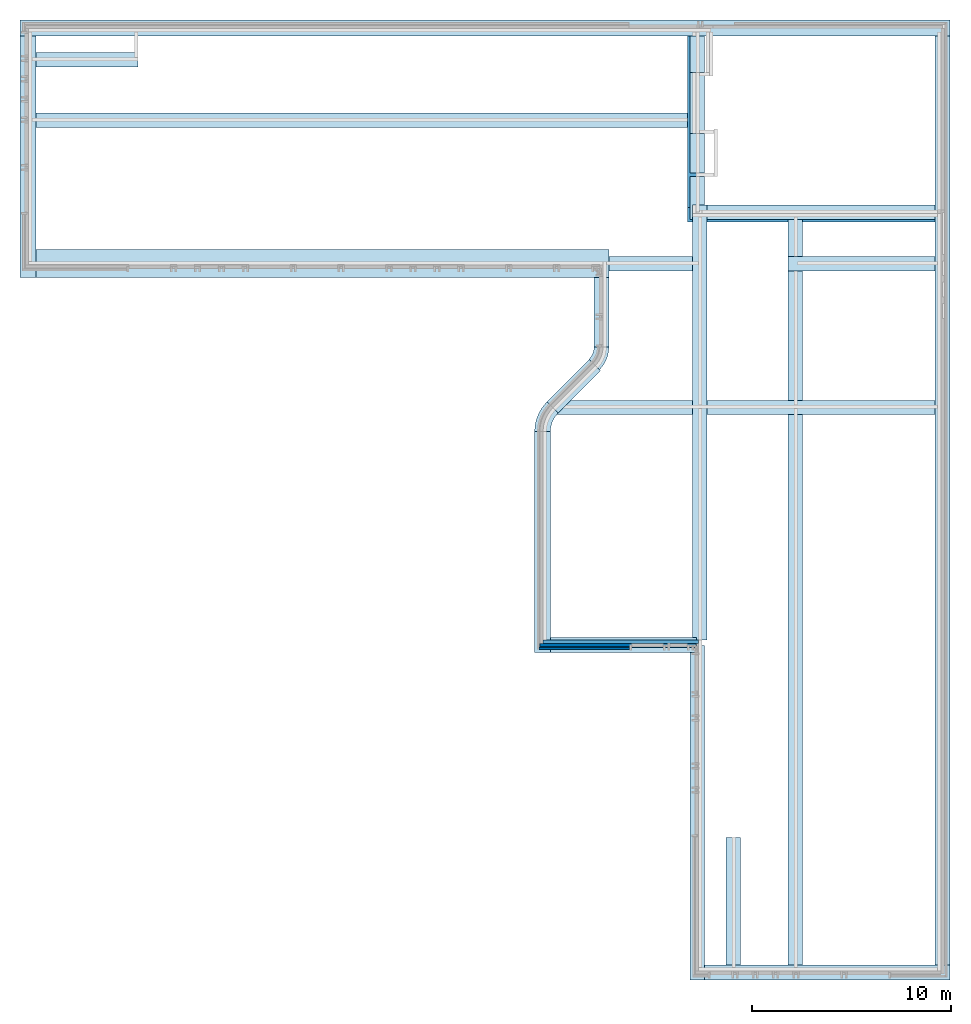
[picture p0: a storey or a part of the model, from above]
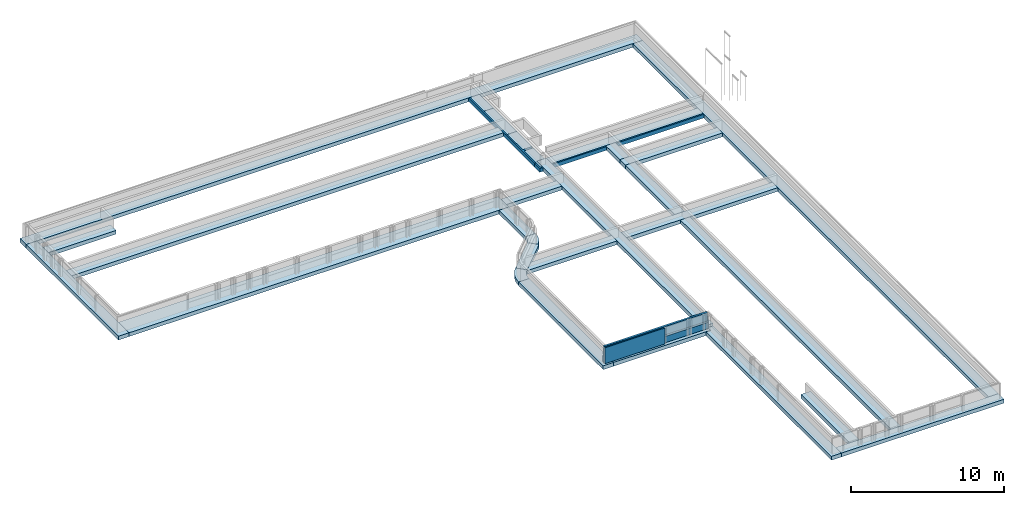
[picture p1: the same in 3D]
Properties of the parts of a building model (IFC2X3), part 28 of 37

# IfcRailing: Railings 2:Railings 2, Railings 2:Railings 2:6162367
Dimensions - Area: 0.236562 m2; Volume: 0.00473101 m3
Phasing - Phase Created: 2. nieuwbouw

# IfcRailing: Railings 3:Railings 3, Railings 3:Railings 3:6671649
In: 00 Begane grond
Type - Material: ISR_HPL Kleur hout
Type - Other - Category: Railings; Family Name: Railings 3
Type - Identity Data - Workset: Bouwkundig; Description: Afdeklat Bamboo; Type Comments: Houten borsweringafdekking; Type Name: Railings 3
Type - Pset_ProductRequirements - Category: Railings
Type - Pset_RailingCommon - IsExternal: no
Pset_QuantityTakeOff - Reference: Railings 3
Pset_RailingCommon - Reference: Railings 3
Other - Family: Railings 3; Family and Type: Railings 3: Railings 3; Type: Railings 3; Type Id: 6671647
Constraints - Elevation from Level: 0 mm; Moves With Nearby Elements: no
Dimensions - Area: 2.58443 m2; Volume: 0.0554774 m3
Phasing - Phase Created: 2. nieuwbouw

# IfcRailing: Railings 4:Railings 2, Railings 4:Railings 2:6165540
In: 00 Begane grond
Type - Material: ISR_RVS
Type - Other - Category: Railings; Family Name: Railings 4
Type - Identity Data - Workset: Bouwkundig; Description: buisleuning; Type Name: Railings 2
Type - Pset_ProductRequirements - Category: Railings
Type - Pset_RailingCommon - IsExternal: no
Pset_QuantityTakeOff - Reference: Railings 2
Pset_RailingCommon - Reference: Railings 2
Other - Type: Railings 2; Family: Railings 4; Family and Type: Railings 4: Railings 2; Type Id: 6165538
Constraints - Elevation from Level: 0 mm; Moves With Nearby Elements: no
Dimensions - Area: 0.441216 m2; Volume: 0.00882433 m3
Phasing - Phase Created: 2. nieuwbouw

# IfcRailing: Railings 5:Railings 5, Railings 5:Railings 5:6176859
In: 01 eerste verdieping
Type - Material: ISR_RVS
Type - Other - Category: Railings; Family Name: Railings 5
Type - Identity Data - Workset: Bouwkundig; Description: buisleuning; Type Name: Railings 5
Type - Pset_ProductRequirements - Category: Railings
Type - Pset_RailingCommon - IsExternal: no
Pset_QuantityTakeOff - Reference: Railings 5
Pset_RailingCommon - Reference: Railings 5
Other - Family: Railings 5; Family and Type: Railings 5: Railings 5; Type: Railings 5; Type Id: 6176857
Constraints - Elevation from Level: 0 mm; Moves With Nearby Elements: no
Dimensions - Area: 0.203951 m2; Volume: 0.00407884 m3
Phasing - Phase Created: 2. nieuwbouw

# IfcRailing: Railings 6:Railings 6, Railings 6:Railings 6:6178156
In: 01 eerste verdieping
Type - Material: ISR_Kunststof_wit
Type - Other - Category: Railings; Family Name: Railings 6
Type - Identity Data - Workset: Bouwkundig; Description: Afdeklat Bamboo; Type Name: Railings 6
Type - Pset_ProductRequirements - Category: Railings
Type - Pset_RailingCommon - IsExternal: no
Pset_QuantityTakeOff - Reference: Railings 6
Pset_RailingCommon - Reference: Railings 6
Other - Family: Railings 6; Family and Type: Railings 6: Railings 6; Type: Railings 6; Type Id: 6178154
Constraints - Moves With Nearby Elements: no
Dimensions - Area: 1.17942 m2; Volume: 0.0163312 m3
Phasing - Phase Created: 2. nieuwbouw

# IfcRailing: Railings 7:Railings 7, Railings 7:Railings 7:6178947
In: 00 Begane grond
Type - Material: ISR_RVS
Type - Other - Category: Railings; Family Name: Railings 7
Type - Identity Data - Workset: Bouwkundig; Description: buisleuning gepoedercoat in Ral:ntb; Type Name: Railings 7
Type - Pset_ProductRequirements - Category: Railings
Type - Pset_RailingCommon - IsExternal: no
Pset_QuantityTakeOff - Reference: Railings 7
Pset_RailingCommon - Reference: Railings 7
Other - Family: Railings 7; Family and Type: Railings 7: Railings 7; Type: Railings 7; Type Id: 6178945
Constraints - Elevation from Level: 0 mm; Moves With Nearby Elements: no
Dimensions - Area: 0.362446 m2; Volume: 0.0072486 m3
Phasing - Phase Created: 2. nieuwbouw

# IfcRailing: Railings 8:Railings 8, Railings 8:Railings 8:6621830
In: 00 Begane grond
Type - Material: ISR_RVS
Type - Other - Category: Railings; Family Name: Railings 8
Type - Identity Data - Workset: Bouwkundig; Description: Afdeklat Bamboo; Type Name: Railings 8
Type - Pset_ProductRequirements - Category: Railings
Type - Pset_RailingCommon - IsExternal: no
Pset_QuantityTakeOff - Reference: Railings 8
Pset_RailingCommon - Reference: Railings 8
Other - Family: Railings 8; Family and Type: Railings 8: Railings 8; Type: Railings 8; Type Id: 6621828
Constraints - Moves With Nearby Elements: no
Dimensions - Area: 1.41407 m2; Volume: 0.0195923 m3
Phasing - Phase Created: 2. nieuwbouw

# IfcRailing: Railings 9:Railings 7, Railings 9:Railings 7:6179709
In: 00 Begane grond
Type - Material: ISR_RVS
Type - Other - Category: Railings; Family Name: Railings 9
Type - Identity Data - Workset: Bouwkundig; Description: buisleuning gepoedercoat in Ral:ntb; Type Name: Railings 7
Type - Pset_ProductRequirements - Category: Railings
Type - Pset_RailingCommon - IsExternal: no
Pset_QuantityTakeOff - Reference: Railings 7
Pset_RailingCommon - Reference: Railings 7
Other - Type: Railings 7; Family: Railings 9; Family and Type: Railings 9: Railings 7; Type Id: 6179707
Constraints - Moves With Nearby Elements: no; Elevation from Level: 200 mm
Dimensions - Area: 0.365369 m2; Volume: 0.00730706 m3
Phasing - Phase Created: 2. nieuwbouw

# IfcRoof: Basic Roof:300_27_dakisolatie+dakleer (7)
Classification: 47.10 Uniformat (Uniformat); Material: ISR_Bitumen 2 mm, ISR_Bitumen 2 mm, ISR_Dak_isolatie 200 mm
Pset_ProductRequirements - Category: Roofs
Pset_QuantityTakeOff - Reference: 300_27_dakisolatie+dakleer
Pset_RoofCommon - IsExternal: yes; Reference: 300_27_dakisolatie+dakleer
Pset_Daken - Assembly Code: 47.10; Description: Afschotisolatie + bedekking Rc vlgs. BENG minimaal Rc 6.3 m2 K/W; Family and Type: Basic Roof: 300_27_dakisolatie+dakleer
Pset_DAT_KMS - Assembly Code: 47.10; Assembly Description: dakafwerkingen; afwerkingen, algemeen (verzamelniveau); Description: Afschotisolatie + bedekking Rc vlgs. BENG minimaal Rc 6.3 m2 K/W
Other - Category: Roofs; Family: Basic Roof; Family and Type: Basic Roof: 300_27_dakisolatie+dakleer; Type: 300_27_dakisolatie+dakleer; Type Id: 1002707
Constraints - Related to Mass: no; Room Bounding: yes; Base Offset From Level: 0 mm; Cutoff Offset: 0 mm
Construction - Fascia Depth: 0 mm; Rafter Cut: Plumb Cut; Maximum Ridge Height: 7354 mm
Identity Data - Workset: Bouwkundig
Phasing - Phase Created: 2. nieuwbouw
Name (Basic Roof:300_27_dakisolatie+dakleer:...) | In | ProjectedArea (m2) | TotalArea (m2) = Area (m2) | Base Level | Volume (m3) | Curved Edge Condition
5088902 | 01 eerste verdieping | 239.24 | 238.724 | 2 | 68.9409 | 0
6261850 | 02 tweede verdieping | 297.833 | 298.296 | V2 bk. ruwe vloer | 86.0952 | 0
6536944 | 01 eerste verdieping | 64.3101 | 64.3101 | 2 | 13.1193 | Dimensions - Thickness: 204 mm
6537082 | 01 eerste verdieping | 123.303 | 123.703 | 2 | 33.1258 | 0
6539282 | 01 eerste verdieping | 70.0207 | 70.0207 | 2 | 14.2842 | Dimensions - Thickness: 204 mm
6539505 | 01 eerste verdieping | 123.227 | 123.308 | 2 | 32.9017 | 0
6637200 | 02 tweede verdieping | 12.2058 | 12.2438 | V2 bk. ruwe vloer | 3.03562 | 0

# IfcRoof: Basic Roof:300_27_dakisolatie+dakleer+grind (2)
In: 01 eerste verdieping
Classification: 47.10 Uniformat (Uniformat); Material: ISR_Grind 50 mm, ISR_Bitumen 2 mm, ISR_Bitumen 2 mm, ISR_Dak_isolatie 200 mm
Pset_ProductRequirements - Category: Roofs
Pset_QuantityTakeOff - Reference: 300_27_dakisolatie+dakleer+grind
Pset_RoofCommon - IsExternal: yes; Reference: 300_27_dakisolatie+dakleer+grind
Pset_Daken - Assembly Code: 47.10; Description: Afschotisolatie + bedekking Rc vlgs. BENG minimaal Rc 6.3 m2 K/W; Family and Type: Basic Roof: 300_27_dakisolatie+dakleer+grind
Pset_DAT_KMS - Assembly Code: 47.10; Assembly Description: dakafwerkingen; afwerkingen, algemeen (verzamelniveau); Description: Afschotisolatie + bedekking Rc vlgs. BENG minimaal Rc 6.3 m2 K/W
Other - Category: Roofs; Family: Basic Roof; Family and Type: Basic Roof: 300_27_dakisolatie+dakleer+grind; Type: 300_27_dakisolatie+dakleer+grind; Type Id: 6872456
Constraints - Related to Mass: no; Room Bounding: yes; Base Level: V1 bk. ruwe vloer; Base Offset From Level: 0 mm; Cutoff Offset: 0 mm
Construction - Fascia Depth: 0 mm; Maximum Ridge Height: 3814 mm; Rafter Cut: Plumb Cut
Identity Data - Workset: Bouwkundig
Phasing - Phase Created: 2. nieuwbouw
Name (Basic Roof:300_27_dakisolatie+dakleer+grind:...) | ProjectedArea (m2) | TotalArea (m2) = Area (m2) | Volume (m3)
5043984 | 119.357 | 119.545 | 38.8363 | Slab Shape Edit - Curved Edge Condition: 1
5155270 | 18.1575 | 18.1575 | 4.612 | Dimensions - Thickness: 254 mm

# IfcRoof: Basic Roof:300_27_underlayment_dakbedekking, Basic Roof:300_27_underlayment_dakbedekking:6485417
In: 00 Begane grond
Classification: 27.10 Uniformat (Uniformat); Material: ISR_Dak_folie 4 mm, ISR_Dak_plaat 20 mm
Pset_ProductRequirements - Category: Roofs
Pset_QuantityTakeOff - Reference: 300_27_underlayment_dakbedekking
Pset_RoofCommon - IsExternal: yes; Reference: 300_27_underlayment_dakbedekking; ProjectedArea: 59.8727 m2; TotalArea: 59.8727 m2
Pset_Daken - Assembly Code: 27.10; Description: Underlayment 20 mm; Family and Type: Basic Roof: 300_27_underlayment_dakbedekking
Pset_DAT_KMS - Assembly Code: 27.10; Assembly Description: daken; niet constructief, algemeen (verzamelniveau); Description: Underlayment 20 mm
Other - Category: Roofs; Family: Basic Roof; Family and Type: Basic Roof: 300_27_underlayment_dakbedekking; Type: 300_27_underlayment_dakbedekking; Type Id: 6485426
Constraints - Related to Mass: no; Room Bounding: yes; Cutoff Offset: 0 mm; Base Level: 0; Base Offset From Level: 2100 mm
Construction - Fascia Depth: 0 mm; Rafter Cut: Plumb Cut; Maximum Ridge Height: 2124 mm
Dimensions - Area: 59.8727 m2; Thickness: 24 mm; Volume: 1.43694 m3
Identity Data - Workset: situatie
Phasing - Phase Created: 2. nieuwbouw

# IfcRoof: Sloped Glazing:berging luik, Sloped Glazing:berging luik:6486298
In: 00 Begane grond
Type - Other - Category: Roofs; Family Name: Sloped Glazing
Type - Construction - Curtain Panel: Empty System Panel : leeg; Join Condition: Not Defined
Type - Identity Data - Assembly Code: 27.20; Assembly Description: daken; constructief, algemeen (verzamelniveau); Type Name: berging luik; Workset: Sloped Glazing Types
Type - Grid 1 - Adjust for Mullion Size: yes; Spacing: 1000 mm
Type - Grid 2 - Adjust for Mullion Size: yes; Spacing: 1000 mm
Type - Grid 1 Mullions - Border 1 Type: Rectangular Mullion : 20x74; Border 2 Type: Rectangular Mullion : 20x74; Interior Type: Rectangular Mullion : 20x74
Type - Grid 2 Mullions - Border 1 Type: Rectangular Mullion : 20x74; Border 2 Type: Rectangular Mullion : 20x74; Interior Type: Rectangular Mullion : 20x74
Type - Pset_CurtainWallCommon - IsExternal: yes
Type - Pset_ProductRequirements - Category: Roofs
Classification: 27.20 Uniformat (Uniformat)
Pset_QuantityTakeOff - Reference: berging luik
Pset_RoofCommon - IsExternal: yes; Reference: berging luik; ProjectedArea: 6.95221 m2
Pset_Daken - Assembly Code: 27.20; Family and Type: Sloped Glazing: berging luik
Pset_DAT_KMS - Assembly Code: 27.20; Assembly Description: daken; constructief, algemeen (verzamelniveau)
Other - Family: Sloped Glazing; Family and Type: Sloped Glazing: berging luik; Type: berging luik; Type Id: 6486299
Constraints - Related to Mass: no; Room Bounding: yes; Cutoff Offset: 0 mm; Base Level: 0; Base Offset From Level: 915 mm
Construction - Fascia Depth: 0 mm; Rafter Cut: Plumb Cut; Maximum Ridge Height: 1015 mm
Dimensions - Thickness: 100 mm
Identity Data - Workset: situatie
Phasing - Phase Created: 2. nieuwbouw
Grid 1 - Angle: 0 deg; Justification: Beginning; Number: 4; Offset: 0 mm; sets with these values: 2

# IfcSlab: Basic Roof:300_27_dakisolatie+dakleer (2)
In: 01 eerste verdieping
Type - PredefinedType: ROOF
Type - Other(Type) - Category: Roofs; Family Name: Basic Roof
Type - Construction(Type) - Default Thickness: 204 mm
Type - Graphics(Type) - Coarse Scale Fill Pattern: <Solid fill>; Coarse Scale Fill Color: 8421504
Type - Identity Data(Type) - Workset: Roof Types; Assembly Code: 47.10; Assembly Description: dakafwerkingen; afwerkingen, algemeen (verzamelniveau); Description: Afschotisolatie + bedekking Rc vlgs. BENG minimaal Rc 6.3 m2 K/W; Manufacturer: Dakisolatie brandvertragend + bedekking; Type Comments: Afschotisolatie + bedekking Rc vlgs. BENG; Type Name: 300_27_dakisolatie+dakleer
Type - Analytical Properties(Type) - Roughness: 1; Absorptance: 0.1
Type - Pset_ElementShading - Roughness: 304.8 mm
Type - Pset_ManufacturerTypeInformation - Manufacturer: Dakisolatie brandvertragend + bedekking
Type - Pset_ProductRequirements - Category: Roofs
Type - Pset_ReinforcementBarPitchOfSlab - Description: Afschotisolatie + bedekking Rc vlgs. BENG minimaal Rc 6.3 m2 K/W
Type - Pset_SlabCommon - IsExternal: yes
Classification: 47.10 Uniformat (Uniformat); Material: ISR_Bitumen 2 mm, ISR_Bitumen 2 mm, ISR_Dak_isolatie 200 mm
Pset_QuantityTakeOff - Reference: 300_27_dakisolatie+dakleer; sets with these values: 2
Pset_SlabCommon - PitchAngle: 0 deg; Reference: 300_27_dakisolatie+dakleer
Pset_Daken - Assembly Code: 47.10; Description: Afschotisolatie + bedekking Rc vlgs. BENG minimaal Rc 6.3 m2 K/W; Family and Type: Basic Roof: 300_27_dakisolatie+dakleer
Pset_DAT_KMS - Assembly Code: 47.10; Assembly Description: dakafwerkingen; afwerkingen, algemeen (verzamelniveau); Description: Afschotisolatie + bedekking Rc vlgs. BENG minimaal Rc 6.3 m2 K/W
BaseQuantities - Length: 204 mm
Name (Basic Roof:300_27_dakisolatie+dakleer:...) | GrossArea (m2) | NetArea (m2) | GrossVolume (m3) | NetVolume (m3) | Perimeter (mm)
6536944 | 5.9746 | 64.3101 | 1.21882 | 13.1193 | 80802
6539282 | 6.50514 | 70.0207 | 1.32705 | 14.2842 | 87682

# IfcSlab: Basic Roof:300_27_dakisolatie+dakleer+grind, Basic Roof:300_27_dakisolatie+dakleer+grind:5155270
In: 01 eerste verdieping
Type - PredefinedType: ROOF
Type - Other(Type) - Category: Roofs; Family Name: Basic Roof
Type - Construction(Type) - Default Thickness: 254 mm
Type - Graphics(Type) - Coarse Scale Fill Pattern: <Solid fill>; Coarse Scale Fill Color: 8421504
Type - Identity Data(Type) - Assembly Code: 47.10; Assembly Description: dakafwerkingen; afwerkingen, algemeen (verzamelniveau); Description: Afschotisolatie + bedekking Rc vlgs. BENG minimaal Rc 6.3 m2 K/W; Manufacturer: Dakisolatie brandvertragend + bedekking; Type Comments: Afschotisolatie + bedekking Rc vlgs. BENGmet grind; Type Name: 300_27_dakisolatie+dakleer+grind; Workset: Roof Types
Type - Analytical Properties(Type) - Roughness: 1; Absorptance: 0.1
Type - Pset_ElementShading - Roughness: 304.8 mm
Type - Pset_ManufacturerTypeInformation - Manufacturer: Dakisolatie brandvertragend + bedekking
Type - Pset_ProductRequirements - Category: Roofs
Type - Pset_ReinforcementBarPitchOfSlab - Description: Afschotisolatie + bedekking Rc vlgs. BENG minimaal Rc 6.3 m2 K/W
Type - Pset_SlabCommon - IsExternal: yes
Classification: 47.10 Uniformat (Uniformat); Material: ISR_Grind 50 mm, ISR_Bitumen 2 mm, ISR_Bitumen 2 mm, ISR_Dak_isolatie 200 mm
Pset_QuantityTakeOff - Reference: 300_27_dakisolatie+dakleer+grind; sets with these values: 2
Pset_SlabCommon - PitchAngle: 0 deg; Reference: 300_27_dakisolatie+dakleer+grind
Pset_Daken - Assembly Code: 47.10; Description: Afschotisolatie + bedekking Rc vlgs. BENG minimaal Rc 6.3 m2 K/W; Family and Type: Basic Roof: 300_27_dakisolatie+dakleer+grind
Pset_DAT_KMS - Assembly Code: 47.10; Assembly Description: dakafwerkingen; afwerkingen, algemeen (verzamelniveau); Description: Afschotisolatie + bedekking Rc vlgs. BENG minimaal Rc 6.3 m2 K/W
BaseQuantities - GrossArea: 1.68689 m2; NetArea: 18.1575 m2; GrossVolume: 0.428469 m3; NetVolume: 4.612 m3; Perimeter: 18850 mm; Length: 254 mm

# IfcSlab: Basic Roof:300_27_underlayment_dakbedekking, Basic Roof:300_27_underlayment_dakbedekking:6485417
In: 00 Begane grond
Type - PredefinedType: ROOF
Type - Other - Category: Roofs; Family Name: Basic Roof
Type - Construction - Default Thickness: 24 mm
Type - Graphics - Coarse Scale Fill Pattern: <Solid fill>; Coarse Scale Fill Color: 8421504
Type - Identity Data - Workset: Roof Types; Assembly Code: 27.10; Assembly Description: daken; niet constructief, algemeen (verzamelniveau); Description: Underlayment 20 mm; Type Name: 300_27_underlayment_dakbedekking
Type - Analytical Properties - Roughness: 1; Absorptance: 0.1
Type - Pset_ElementShading - Roughness: 304.8 mm
Type - Pset_ProductRequirements - Category: Roofs
Type - Pset_ReinforcementBarPitchOfSlab - Description: Underlayment 20 mm
Type - Pset_SlabCommon - IsExternal: yes
Classification: 27.10 Uniformat (Uniformat); Material: ISR_Dak_folie 4 mm, ISR_Dak_plaat 20 mm
Pset_QuantityTakeOff - Reference: 300_27_underlayment_dakbedekking; sets with these values: 2
Pset_SlabCommon - PitchAngle: 0 deg; Reference: 300_27_underlayment_dakbedekking
Pset_Daken - Assembly Code: 27.10; Description: Underlayment 20 mm; Family and Type: Basic Roof: 300_27_underlayment_dakbedekking
Pset_DAT_KMS - Assembly Code: 27.10; Assembly Description: daken; niet constructief, algemeen (verzamelniveau); Description: Underlayment 20 mm
BaseQuantities - GrossArea: 5.56235 m2; NetArea: 59.8727 m2; GrossVolume: 0.133496 m3; NetVolume: 1.43694 m3; Perimeter: 59571.8 mm; Length: 24 mm

# IfcSlab: Floor:23_Dekvloer 70mm (2)
In: 00 Begane grond
Type - PredefinedType: FLOOR; Material: ISR_Beton ihwg 70 mm
Type - Other - Category: Floors; Family Name: Floor
Type - Construction - Function: Interior; Default Thickness: 70 mm
Type - Graphics - Coarse Scale Fill Pattern: <Solid fill>; Coarse Scale Fill Color: 8421504
Type - Identity Data - Workset: Floor Types; Assembly Code: 23.10; Assembly Description: vloeren; niet constructief, algemeen (verzamelniveau); Description: Cementdekvloer 70mm; Type Comments: Cementdekvloer 70mm; Type Name: 23_Dekvloer 70mm
Type - Materials and Finishes - Structural Material: ISR_Beton ihwg
Type - Analytical Properties - Roughness: 1; Absorptance: 0.1
Type - Pset_ElementShading - Roughness: 304.8 mm
Type - Pset_ProductRequirements - Category: Floors
Type - Pset_ReinforcementBarPitchOfSlab - Description: Cementdekvloer 70mm
Type - Pset_SlabCommon - IsExternal: no
Classification: 23.10 Uniformat (Uniformat)
Pset_QuantityTakeOff - Reference: 23_Dekvloer 70mm; sets with these values: 2
Pset_SlabCommon - LoadBearing: no; PitchAngle: 0 deg; Reference: 23_Dekvloer 70mm
Pset_Vloeren - Omschrijving: Cementdekvloer 70mm; NL-sfb-Codering: 23.10
Pset_DAT_KMS - Assembly Code: 23.10; Assembly Description: vloeren; niet constructief, algemeen (verzamelniveau); Description: Cementdekvloer 70mm
BaseQuantities - Depth: 70 mm
Other - Family: Floor; Family and Type: Floor: 23_Dekvloer 70mm; Type: 23_Dekvloer 70mm; Type Id: 5472719
Constraints - Level: 0; Related to Mass: no; Room Bounding: yes
Dimensions - Thickness: 70 mm
Identity Data - Workset: Bouwkundig; Has Association: no
Phasing - Phase Created: 2. nieuwbouw
Structural - Structural: no
Name (Floor:23_Dekvloer 70mm:...) | GrossArea (m2) | NetArea (m2) = Area (m2) | GrossVolume (m3) | NetVolume (m3) = Volume (m3) | BaseQuantities, Perimeter (mm) = Dimensions, Perimeter (mm) | Height Offset From Level (mm) = Elevation at Top (mm) = Elevation at Top Core (mm) | Elevation at Bottom (mm) = Elevation at Bottom Core (mm)
5247574 | 964.606 | 960.468 | 67.5224 | 67.2284 | 195032 | 0 | -70
5249453 | 94.6836 | 94.6838 | 6.62785 | 6.62787 | 42961.7 | -600 | -670

# IfcSlab: Floor:23_Geisoleerde kanaalplaatvloer_200 (2)
Type - PredefinedType: FLOOR; Material: ISR_Kanaalplaatvloer 200 mm, ISR_Dak_isolatie(198) 152 mm
Type - Other - Category: Floors; Family Name: Floor
Type - Construction - Function: Interior; Default Thickness: 352 mm
Type - Graphics - Coarse Scale Fill Pattern: <Solid fill>; Coarse Scale Fill Color: 8421504
Type - Identity Data - Workset: Floor Types; Assembly Code: 23.21; Assembly Description: vloeren; constructief, vrijdragende vloeren; Description: Geisoleerde kanaalplaatvloer 200mm; Type Comments: Geisoleerde kanaalplaatvloer 200mm minimaal Rc 3.7 m²K/W; Type Name: 23_Geisoleerde kanaalplaatvloer_200
Type - Materials and Finishes - Structural Material: ISR_Kanaalplaatvloer
Type - Analytical Properties - Roughness: 1; Absorptance: 0.1
Type - Pset_ElementShading - Roughness: 304.8 mm
Type - Pset_ProductRequirements - Category: Floors
Type - Pset_ReinforcementBarPitchOfSlab - Description: Geisoleerde kanaalplaatvloer 200mm
Type - Pset_SlabCommon - IsExternal: no
Classification: 23.21 Uniformat (Uniformat)
Pset_QuantityTakeOff - Reference: 23_Geisoleerde kanaalplaatvloer_200; sets with these values: 2
Pset_SlabCommon - LoadBearing: no; PitchAngle: 0 deg; Reference: 23_Geisoleerde kanaalplaatvloer_200
Pset_Vloeren - Omschrijving: Geisoleerde kanaalplaatvloer 200mm; NL-sfb-Codering: 23.21
Pset_DAT_KMS - Assembly Code: 23.21; Assembly Description: vloeren; constructief, vrijdragende vloeren; Description: Geisoleerde kanaalplaatvloer 200mm
BaseQuantities - Depth: 352 mm
Other - Family: Floor; Family and Type: Floor: 23_Geisoleerde kanaalplaatvloer_200; Type: 23_Geisoleerde kanaalplaatvloer_200; Type Id: 5472786
Constraints - Related to Mass: no; Room Bounding: yes
Dimensions - Thickness: 352 mm
Identity Data - Workset: Bouwkundig; Has Association: no
Phasing - Phase Created: 2. nieuwbouw
Structural - Structural: no
Name (Floor:23_Geisoleerde kanaalplaatvloer_200:...) | In | GrossArea (m2) | NetArea (m2) = Area (m2) | GrossVolume (m3) | NetVolume (m3) = Volume (m3) | BaseQuantities, Perimeter (mm) = Dimensions, Perimeter (mm) | Level | Height Offset From Level (mm) | Elevation at Bottom (mm) = Elevation at Bottom Core (mm) | Elevation at Top (mm) = Elevation at Top Core (mm)
5472760 | 00 Begane grond | 993.621 | 993.525 | 349.755 | 349.721 | 196462 | V0 bk. ruwe vloer | -60 | -482 | -130
5480495 | -1 Speelvloer | 107.899 | 107.899 | 37.9805 | 37.9805 | 42819.8 | V-1 | -130 | -1082 | -730

# IfcSlab: Floor:23_Gewapende Druklaag (5)
Type - PredefinedType: FLOOR; Material: ISR_Beton ihwg 60 mm
Type - Other - Category: Floors; Family Name: Floor
Type - Construction - Function: Interior; Default Thickness: 60 mm
Type - Graphics - Coarse Scale Fill Pattern: <Solid fill>; Coarse Scale Fill Color: 8421504
Type - Identity Data - Workset: Floor Types; Assembly Code: 23.10; Assembly Description: vloeren; niet constructief, algemeen (verzamelniveau); Description: Druklaag 60mm; Type Comments: Druklaag 60mm; Type Name: 23_Gewapende Druklaag
Type - Materials and Finishes - Structural Material: ISR_Beton ihwg
Type - Analytical Properties - Roughness: 1; Absorptance: 0.1
Type - Pset_ElementShading - Roughness: 304.8 mm
Type - Pset_ProductRequirements - Category: Floors
Type - Pset_ReinforcementBarPitchOfSlab - Description: Druklaag 60mm
Type - Pset_SlabCommon - IsExternal: no
Classification: 23.10 Uniformat (Uniformat)
Pset_QuantityTakeOff - Reference: 23_Gewapende Druklaag; sets with these values: 2
Pset_SlabCommon - LoadBearing: no; PitchAngle: 0 deg; Reference: 23_Gewapende Druklaag
Pset_Vloeren - Omschrijving: Druklaag 60mm; NL-sfb-Codering: 23.10
Pset_DAT_KMS - Assembly Code: 23.10; Assembly Description: vloeren; niet constructief, algemeen (verzamelniveau); Description: Druklaag 60mm
BaseQuantities - Depth: 60 mm
Other - Family: Floor; Family and Type: Floor: 23_Gewapende Druklaag; Type: 23_Gewapende Druklaag; Type Id: 5024859
Constraints - Related to Mass: no; Room Bounding: yes
Dimensions - Thickness: 60 mm
Identity Data - Has Association: no
Phasing - Phase Created: 2. nieuwbouw
Structural - Structural: no
Name (Floor:23_Gewapende Druklaag:...) | In | GrossArea (m2) | NetArea (m2) = Area (m2) | GrossVolume (m3) | NetVolume (m3) = Volume (m3) | BaseQuantities, Perimeter (mm) = Dimensions, Perimeter (mm) | Height Offset From Level (mm) | Level | Elevation at Bottom (mm) = Elevation at Bottom Core (mm) | Elevation at Top (mm) = Elevation at Top Core (mm) | Workset
5024813 | 01 eerste verdieping | 987.261 | 983.88 | 59.2357 | 59.0328 | 213267 | 0 | V1 bk. ruwe vloer | 3500 | 3560 | Constructie
5025075 | 02 tweede verdieping | 949.388 | 945.716 | 56.9633 | 56.7429 | 189200 | 0 | V2 bk. ruwe vloer | 7090 | 7150 | Constructie
5026352 | 00 Begane grond | 19.9586 | 19.9585 | 1.19751 | 1.19751 | 20123 | 2920 | 0 | 2860 | 2920 | Constructie
5472722 | 00 Begane grond | 993.621 | 993.525 | 59.6172 | 59.6116 | 196462 | 0 | V0 bk. ruwe vloer | -130 | -70 | Bouwkundig
5480476 | -1 Speelvloer | 105.878 | 105.878 | 6.35266 | 6.35267 | 41831.6 | -70 | V-1 | -730 | -670 | Bouwkundig

# IfcSlab: Floor:23_Zwevende dekvloer 90mm, Floor:23_Zwevende dekvloer 90mm:5024939
In: 01 eerste verdieping
Type - PredefinedType: FLOOR; Material: ISR_Beton ihwg 70 mm, ISR_Isolatie 20 mm
Type - Other - Category: Floors; Family Name: Floor
Type - Construction - Function: Interior; Default Thickness: 90 mm
Type - Graphics - Coarse Scale Fill Pattern: <Solid fill>; Coarse Scale Fill Color: 8421504
Type - Identity Data - Workset: Floor Types; Assembly Code: 23.10; Assembly Description: vloeren; niet constructief, algemeen (verzamelniveau); Description: Cementdekvloer 20+70mm; Type Comments: Zwevende dekvloer 90mmCementdekvloer 70mmIsolatie20mm; Type Name: 23_Zwevende dekvloer 90mm
Type - Materials and Finishes - Structural Material: ISR_Beton ihwg
Type - Analytical Properties - Roughness: 1; Absorptance: 0.1
Type - Pset_ElementShading - Roughness: 304.8 mm
Type - Pset_ProductRequirements - Category: Floors
Type - Pset_ReinforcementBarPitchOfSlab - Description: Cementdekvloer 20+70mm
Type - Pset_SlabCommon - IsExternal: no
Classification: 23.10 Uniformat (Uniformat)
Pset_QuantityTakeOff - Reference: 23_Zwevende dekvloer 90mm; sets with these values: 2
Pset_SlabCommon - LoadBearing: no; PitchAngle: 0 deg; Reference: 23_Zwevende dekvloer 90mm
Pset_Vloeren - Omschrijving: Cementdekvloer 20+70mm; NL-sfb-Codering: 23.10
Pset_DAT_KMS - Assembly Code: 23.10; Assembly Description: vloeren; niet constructief, algemeen (verzamelniveau); Description: Cementdekvloer 20+70mm
BaseQuantities - GrossArea: 814.902 m2; NetArea: 811.647 m2; GrossVolume: 73.3412 m3; NetVolume: 73.0483 m3; Perimeter: 207600 mm; Depth: 90 mm
Other - Family: Floor; Family and Type: Floor: 23_Zwevende dekvloer 90mm; Type: 23_Zwevende dekvloer 90mm; Type Id: 5024974
Constraints - Level: 1; Related to Mass: no; Room Bounding: yes; Height Offset From Level: 0 mm
Dimensions - Area: 811.647 m2; Elevation at Bottom: 3560 mm; Elevation at Bottom Core: 3560 mm; Elevation at Top: 3650 mm; Elevation at Top Core: 3650 mm; Perimeter: 207600 mm; Thickness: 90 mm; Volume: 73.0483 m3
Identity Data - Workset: Bouwkundig; Has Association: no
Phasing - Phase Created: 2. nieuwbouw
Structural - Structural: no

# IfcSlab: Floor:23_kanaalplaatvloer_200 (2)
Type - PredefinedType: FLOOR; Material: ISR_Kanaalplaatvloer 200 mm
Type - Other - Category: Floors; Family Name: Floor
Type - Construction - Function: Interior; Default Thickness: 200 mm
Type - Graphics - Coarse Scale Fill Pattern: <Solid fill>; Coarse Scale Fill Color: 8421504
Type - Identity Data - Workset: Floor Types; Assembly Code: 23.21; Assembly Description: vloeren; constructief, vrijdragende vloeren; Description: Kanaalplaatvloer 200mm; Type Comments: Kanaalplaatvloer 200mm; Type Name: 23_kanaalplaatvloer_200
Type - Materials and Finishes - Structural Material: ISR_Kanaalplaatvloer
Type - Analytical Properties - Roughness: 1; Absorptance: 0.1
Type - Pset_ElementShading - Roughness: 304.8 mm
Type - Pset_ProductRequirements - Category: Floors
Type - Pset_ReinforcementBarPitchOfSlab - Description: Kanaalplaatvloer 200mm
Type - Pset_SlabCommon - IsExternal: no
Classification: 23.21 Uniformat (Uniformat)
Pset_QuantityTakeOff - Reference: 23_kanaalplaatvloer_200; sets with these values: 2
Pset_SlabCommon - LoadBearing: no; PitchAngle: 0 deg; Reference: 23_kanaalplaatvloer_200
Pset_Vloeren - Omschrijving: Kanaalplaatvloer 200mm; NL-sfb-Codering: 23.21
Pset_DAT_KMS - Assembly Code: 23.21; Assembly Description: vloeren; constructief, vrijdragende vloeren; Description: Kanaalplaatvloer 200mm
BaseQuantities - Depth: 200 mm
Other - Family: Floor; Family and Type: Floor: 23_kanaalplaatvloer_200; Type: 23_kanaalplaatvloer_200; Type Id: 589345
Constraints - Related to Mass: no; Room Bounding: yes
Dimensions - Thickness: 200 mm
Identity Data - Has Association: no; Workset: Constructie
Phasing - Phase Created: 2. nieuwbouw
Structural - Structural: no
Name (Floor:23_kanaalplaatvloer_200:...) | In | GrossArea (m2) | NetArea (m2) = Area (m2) | GrossVolume (m3) | NetVolume (m3) = Volume (m3) | BaseQuantities, Perimeter (mm) = Dimensions, Perimeter (mm) | Height Offset From Level (mm) | Level | Elevation at Bottom (mm) = Elevation at Bottom Core (mm) | Elevation at Top (mm) = Elevation at Top Core (mm)
5025056 | 01 eerste verdieping | 949.388 | 945.716 | 189.878 | 189.143 | 189200 | 200 | V2 ok. ruwe vloer | 6890 | 7090
6177144 | 00 Begane grond | 21.3227 | 21.3227 | 4.26454 | 4.26454 | 21527.5 | 2930 | V0 bk. ruwe vloer | 2660 | 2860

# IfcSlab: Floor:23_kanaalplaatvloer_260, Floor:23_kanaalplaatvloer_260:5023476
In: 00 Begane grond
Type - PredefinedType: FLOOR; Material: ISR_Kanaalplaatvloer 260 mm
Type - Other - Category: Floors; Family Name: Floor
Type - Construction - Function: Interior; Default Thickness: 260 mm
Type - Graphics - Coarse Scale Fill Pattern: <Solid fill>; Coarse Scale Fill Color: 8421504
Type - Identity Data - Assembly Code: 23.21; Assembly Description: vloeren; constructief, vrijdragende vloeren; Description: Kanaalplaatvloer 260mm; Type Comments: Kanaalplaatvloer 260; Type Name: 23_kanaalplaatvloer_260; Workset: Floor Types
Type - Materials and Finishes - Structural Material: ISR_Kanaalplaatvloer
Type - Analytical Properties - Roughness: 1; Absorptance: 0.1
Type - Pset_ElementShading - Roughness: 304.8 mm
Type - Pset_ProductRequirements - Category: Floors
Type - Pset_ReinforcementBarPitchOfSlab - Description: Kanaalplaatvloer 260mm
Type - Pset_SlabCommon - IsExternal: no
Classification: 23.21 Uniformat (Uniformat)
Pset_QuantityTakeOff - Reference: 23_kanaalplaatvloer_260; sets with these values: 2
Pset_SlabCommon - LoadBearing: no; Reference: 23_kanaalplaatvloer_260; PitchAngle: 0 deg
Pset_Vloeren - Omschrijving: Kanaalplaatvloer 260mm; NL-sfb-Codering: 23.21
Pset_DAT_KMS - Assembly Code: 23.21; Assembly Description: vloeren; constructief, vrijdragende vloeren; Description: Kanaalplaatvloer 260mm
BaseQuantities - GrossArea: 989.992 m2; NetArea: 986.651 m2; GrossVolume: 257.398 m3; NetVolume: 256.529 m3; Perimeter: 212665 mm; Depth: 260 mm
Other - Family: Floor; Family and Type: Floor: 23_kanaalplaatvloer_260; Type: 23_kanaalplaatvloer_260; Type Id: 4680220
Constraints - Related to Mass: no; Room Bounding: yes; Height Offset From Level: 260 mm; Level: V1 ok. ruwe vloer
Dimensions - Area: 986.651 m2; Elevation at Bottom: 3240 mm; Elevation at Bottom Core: 3240 mm; Elevation at Top: 3500 mm; Elevation at Top Core: 3500 mm; Perimeter: 212665 mm; Thickness: 260 mm; Volume: 256.529 m3
Identity Data - Has Association: no; Workset: Constructie
Phasing - Phase Created: 2. nieuwbouw
Structural - Structural: no

# IfcStair: Hoofdtrap1:Hoofdtrap (2)
In: 00 Begane grond
Name (Hoofdtrap1:Hoofdtrap:...)
4989249 | Material: ISR_Beton_prefab
4989249 | Pset_ProductRequirements - Category: Stairs; Pset_QuantityTakeOff - Reference: Hoofdtrap; Pset_StairCommon - IsExternal: no; Reference: Hoofdtrap; Pset_trappen - Family and Type: Hoofdtrap1: Hoofdtrap; Omschrijving: Tribune trap.Loopgedeelten metaantrede 250mmZitgedeelte metaantrede 500optrede 365optreden 182.5mm; Pset_DAT_KMS - Description: Tribune trap.Loopgedeelten metaantrede 250mmZitgedeelte metaantrede 500optrede 365optreden 182.5mm; Other - Category: Stairs; Family: Hoofdtrap1; Family and Type: Hoofdtrap1: Hoofdtrap; Type: Hoofdtrap; Type Id: 4989247; Constraints - Moves With Nearby Elements: no; Dimensions - Area: 28.9299 m2; Volume: 6.9555 m3; Identity Data - Workset: Bouwkundig; Phasing - Phase Created: 2. nieuwbouw; Structural - Rebar Cover: Rebar Cover 1 <25 mm>; Other(Type) - Category: Stairs; Family Name: Hoofdtrap1; Identity Data(Type) - Workset: Bouwkundig; Description: Tribune trap.Loopgedeelten metaantrede 250mmZitgedeelte metaantrede 500optrede 365optreden 182.5mm; Type Comments: Tribune trap.Loopgedeelten metaantrede 250mmoptreden 183mmzitgedeelten metaantrede 500optrede 365; Type Name: Hoofdtrap

# IfcStair: Hoofdtrap2:Hoofdtrap (2)
In: 00 Begane grond
Name (Hoofdtrap2:Hoofdtrap:...)
6166338 | Material: ISR_Hardhout
6166338 | Pset_ProductRequirements - Category: Stairs; Pset_QuantityTakeOff - Reference: Hoofdtrap; Pset_StairCommon - IsExternal: no; Reference: Hoofdtrap; Pset_trappen - Family and Type: Hoofdtrap2: Hoofdtrap; Omschrijving: Tribune trap.Loopgedeelten metaantrede 280mmoptreden 181mm; Pset_DAT_KMS - Description: Tribune trap.Loopgedeelten metaantrede 280mmoptreden 181mm; Other - Category: Stairs; Type: Hoofdtrap; Family: Hoofdtrap2; Family and Type: Hoofdtrap2: Hoofdtrap; Type Id: 6166336; Constraints - Moves With Nearby Elements: no; Dimensions - Area: 9 m2; Volume: 1.6425 m3; Identity Data - Workset: Bouwkundig; Phasing - Phase Created: 2. nieuwbouw; Structural - Rebar Cover: Rebar Cover 1 <25 mm>; Other(Type) - Category: Stairs; Family Name: Hoofdtrap2; Identity Data(Type) - Workset: Bouwkundig; Description: Tribune trap.Loopgedeelten metaantrede 280mmoptreden 181mm; Type Comments: Tribune trap.Loopgedeelten metaantrede 250mmoptreden 183mmzitgedeelten metaantrede 500optrede 365; Type Name: Hoofdtrap

# IfcStair: Stairs 1:Stairs 1 (2)
In: -1 Speelvloer
Name (Stairs 1:Stairs 1:...)
4992620 | Material: ISR_Beton_prefab
4992620 | Pset_ProductRequirements - Category: Stairs; Pset_QuantityTakeOff - Reference: Stairs 1; Pset_StairCommon - IsExternal: no; Reference: Stairs 1; Pset_trappen - Family and Type: Stairs 1: Stairs 1; Other - Category: Stairs; Family: Stairs 1; Family and Type: Stairs 1: Stairs 1; Type: Stairs 1; Type Id: 4992618; Constraints - Moves With Nearby Elements: no; Dimensions - Area: 5.0955 m2; Volume: 1.29709 m3; Identity Data - Workset: Bouwkundig; Phasing - Phase Created: 2. nieuwbouw; Structural - Rebar Cover: Rebar Cover 1 <25 mm>; Other(Type) - Category: Stairs; Family Name: Stairs 1; Identity Data(Type) - Workset: Bouwkundig; Type Comments: trap:optrede: 200mmaantrede: 250mm; Type Name: Stairs 1

# IfcStair: Stairs 2:Stairs 1 (2)
In: -1 Speelvloer
Name (Stairs 2:Stairs 1:...)
5001752 | Material: ISR_Beton_prefab
5001752 | Pset_ProductRequirements - Category: Stairs; Pset_QuantityTakeOff - Reference: Stairs 1; Pset_StairCommon - IsExternal: no; Reference: Stairs 1; Pset_trappen - Family and Type: Stairs 2: Stairs 1; Other - Category: Stairs; Type: Stairs 1; Family: Stairs 2; Family and Type: Stairs 2: Stairs 1; Type Id: 5001750; Constraints - Elevation from Level: 0 mm; Moves With Nearby Elements: no; Dimensions - Area: 1.659 m2; Volume: 0.3654 m3; Identity Data - Workset: Bouwkundig; Phasing - Phase Created: 2. nieuwbouw; Structural - Rebar Cover: Rebar Cover 1 <25 mm>; Other(Type) - Category: Stairs; Family Name: Stairs 2; Identity Data(Type) - Workset: Bouwkundig; Type Comments: trap:optrede 200mmaantrede 250mm; Type Name: Stairs 1

# IfcStair: Stairs 3:Stairs 3 (2)
In: 00 Begane grond
Name (Stairs 3:Stairs 3:...)
6431086 | Material: ISR_Beton_prefab
6431086 | Pset_ProductRequirements - Category: Stairs; Pset_QuantityTakeOff - Reference: Stairs 3; Pset_StairCommon - IsExternal: no; Reference: Stairs 3; Pset_trappen - Family and Type: Stairs 3: Stairs 3; Other - Category: Stairs; Family: Stairs 3; Family and Type: Stairs 3: Stairs 3; Type: Stairs 3; Type Id: 6431084; Constraints - Moves With Nearby Elements: no; Dimensions - Area: 0.125 m2; Volume: 0.0228125 m3; Identity Data - Workset: Bouwkundig; Phasing - Phase Created: 2. nieuwbouw; Structural - Rebar Cover: Rebar Cover 1 <25 mm>; Other(Type) - Category: Stairs; Family Name: Stairs 3; Identity Data(Type) - Workset: Bouwkundig; Type Name: Stairs 3

# IfcStair: Stairs 4:Stairs 4 (2)
In: -1 Speelvloer
Name (Stairs 4:Stairs 4:...)
6873871 | Material: ISR_Beton_prefab
6873871 | Pset_ProductRequirements - Category: Stairs; Pset_QuantityTakeOff - Reference: Stairs 4; Pset_StairCommon - IsExternal: no; Reference: Stairs 4; Pset_trappen - Family and Type: Stairs 4: Stairs 4; Other - Category: Stairs; Family: Stairs 4; Family and Type: Stairs 4: Stairs 4; Type: Stairs 4; Type Id: 6873869; Constraints - Moves With Nearby Elements: no; Dimensions - Area: 0.125 m2; Volume: 0.025 m3; Identity Data - Workset: Bouwkundig; Phasing - Phase Created: 2. nieuwbouw; Structural - Rebar Cover: Rebar Cover 1 <25 mm>; Other(Type) - Category: Stairs; Family Name: Stairs 4; Identity Data(Type) - Workset: Bouwkundig; Type Name: Stairs 4

# IfcWall: Basic Wall:21_DAT_Hekwerk 175, Basic Wall:21_DAT_Hekwerk 175:6793363
In: 01 eerste verdieping
Type - PredefinedType: STANDARD; Material: ISR_Gips 12.5 mm, ISR_Gips 12.5 mm, ISR_Dak_isolatie(198) 140 mm, ISR_Multiplex 10 mm
Type - Other(Type) - Category: Walls; Family Name: Basic Wall
Type - Construction(Type) - Function: Exterior; Wrapping at Ends: Exterior; Width: 175 mm; Wrapping at Inserts: Exterior
Type - Graphics(Type) - Coarse Scale Fill Pattern: <Solid fill>; Coarse Scale Fill Color: 4210752
Type - Identity Data(Type) - Workset: Wall Types; Assembly Code: 21.10; Assembly Description: buitenwanden; niet constructief, algemeen (verzamelniveau); Description: Samengesteld rekwerkBuitenplaat WBP 10mmHouten stijl- en regelwerk 38x140Minirale wolDampremmendefolieGipsplaat 12.5mmGipsvezelplaat 12,5mm; Type Comments: Samengesteld rekwerkBuitenplaat WBP 10mmHouten stijl- en regelwerk 38x140Minirale wolDampremmendefolieGipsplaat 12.5mmGipsvezelplaat 12,5mm; Type Name: 21_DAT_Hekwerk 175
Type - Materials and Finishes(Type) - Structural Material: ISR_Dak_isolatie(198)
Type - Analytical Properties(Type) - Roughness: 1; Absorptance: 0.1
Type - Pset_ElementShading - Roughness: 304.8 mm
Type - Pset_ProductRequirements - Category: Walls
Type - Pset_ReinforcementBarPitchOfWall - Description: Samengesteld rekwerkBuitenplaat WBP 10mmHouten stijl- en regelwerk 38x140Minirale wolDampremmendefolieGipsplaat 12.5mmGipsvezelplaat 12,5mm
Type - Pset_WallCommon - IsExternal: yes
Classification: 21.10 Uniformat (Uniformat)
Pset_QuantityTakeOff - Reference: 21_DAT_Hekwerk 175; sets with these values: 2
Pset_WallCommon - ExtendToStructure: no; LoadBearing: no; Reference: 21_DAT_Hekwerk 175
Pset_wanden - Structural Usage: Non-bearing; Omschrijving: Samengesteld rekwerkBuitenplaat WBP 10mmHouten stijl- en regelwerk 38x140Minirale wolDampremmendefolieGipsplaat 12.5mmGipsvezelplaat 12,5mm; NL-sfb-Codering: 21.10; sets with these values: 2
Pset_DAT_KMS - Assembly Code: 21.10; Assembly Description: buitenwanden; niet constructief, algemeen (verzamelniveau); Description: Samengesteld rekwerkBuitenplaat WBP 10mmHouten stijl- en regelwerk 38x140Minirale wolDampremmendefolieGipsplaat 12.5mmGipsvezelplaat 12,5mm
Other - Category: Walls; Family: Basic Wall; Family and Type: Basic Wall: 21_DAT_Hekwerk 175; Type: 21_DAT_Hekwerk 175; Type Id: 5435600
Constraints - Base Extension Distance: 0 mm; Base is Attached: no; Related to Mass: no; Room Bounding: yes; Top Extension Distance: 0 mm; Top is Attached: no; Base Constraint: 1; Location Line: Wall Centerline; Top Constraint: Up to level: V2 ok. ruwe vloer; Base Offset: 10 mm; Top Offset: 0.0000289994 mm; Unconnected Height: 3230 mm
Dimensions - Area: 0.21845 m2; Length: 127.5 mm; Volume: 0.0382288 m3
Identity Data - Workset: Bouwkundig
Phasing - Phase Created: 2. nieuwbouw
Structural - Structural Usage: Non-bearing; Structural: no
Cross-Section Definition - Cross-Section: Vertical

# IfcWall: Basic Wall:21_DAT_gasbeton_100, Basic Wall:21_DAT_gasbeton_100:5539208
In: 01 eerste verdieping
Type - PredefinedType: STANDARD; Material: DAT_Gasbeton 100 mm
Type - Other(Type) - Category: Walls; Family Name: Basic Wall
Type - Construction(Type) - Function: Exterior; Wrapping at Inserts: Do not wrap; Width: 100 mm
Type - Graphics(Type) - Coarse Scale Fill Pattern: <Solid fill>; Coarse Scale Fill Color: 0
Type - Identity Data(Type) - Workset: Wall Types; Assembly Code: 21.10; Assembly Description: buitenwanden; niet constructief, algemeen (verzamelniveau); Description: Gasbeton 100 mm; Type Comments: Gasbeton 100 mm; Type Name: 21_DAT_gasbeton_100
Type - Materials and Finishes(Type) - Structural Material: DAT_Gasbeton
Type - Analytical Properties(Type) - Roughness: 1; Absorptance: 0.1
Type - Pset_ElementShading - Roughness: 304.8 mm
Type - Pset_ProductRequirements - Category: Walls
Type - Pset_ReinforcementBarPitchOfWall - Description: Gasbeton 100 mm
Type - Pset_WallCommon - IsExternal: yes
Classification: 21.10 Uniformat (Uniformat)
Pset_QuantityTakeOff - Reference: 21_DAT_gasbeton_100; sets with these values: 2
Pset_WallCommon - ExtendToStructure: no; LoadBearing: no; Reference: 21_DAT_gasbeton_100
Pset_wanden - Structural Usage: Non-bearing; Omschrijving: Gasbeton 100 mm; NL-sfb-Codering: 21.10
Pset_DAT_KMS - Assembly Code: 21.10; Assembly Description: buitenwanden; niet constructief, algemeen (verzamelniveau); Description: Gasbeton 100 mm
Other - Category: Walls; Family: Basic Wall; Family and Type: Basic Wall: 21_DAT_gasbeton_100; Type: 21_DAT_gasbeton_100; Type Id: 4279461
Constraints - Base Offset: 0 mm; Top Offset: 0 mm; Base Extension Distance: 0 mm; Base is Attached: no; Location Line: Finish Face: Interior; Related to Mass: no; Room Bounding: yes; Top Extension Distance: 0 mm; Top is Attached: no; Base Constraint: V1 bk. ruwe vloer; Unconnected Height: 515 mm
Dimensions - Area: 2.42948 m2; Length: 4799.96 mm; Volume: 0.242948 m3
Identity Data - Workset: Bouwkundig
Phasing - Phase Created: 2. nieuwbouw
Structural - Structural Usage: Non-bearing; Structural: no
Cross-Section Definition - Cross-Section: Vertical

# IfcWall: Basic Wall:21_DAT_isolatie minerale wol_160 (3)
Type - PredefinedType: STANDARD; Material: ISR_Isolatie 160 mm
Type - Other - Category: Walls; Family Name: Basic Wall
Type - Construction - Function: Exterior; Wrapping at Inserts: Do not wrap; Width: 160 mm
Type - Graphics - Coarse Scale Fill Pattern: <Solid fill>; Coarse Scale Fill Color: 4210752
Type - Identity Data - Workset: Wall Types; Assembly Code: 21.10; Assembly Description: buitenwanden; niet constructief, algemeen (verzamelniveau); Description: Isolatie minerale wol 160mm met een Rc 4,7 m2K/W; Type Comments: Isolatie minerale wol 160mm met een Rc 4.7 m2K/W; Type Name: 21_DAT_isolatie minerale wol_160
Type - Materials and Finishes - Structural Material: ISR_Isolatie
Type - Analytical Properties - Roughness: 1; Absorptance: 0.1
Type - Pset_ElementShading - Roughness: 304.8 mm
Type - Pset_ProductRequirements - Category: Walls
Type - Pset_ReinforcementBarPitchOfWall - Description: Isolatie minerale wol 160mm met een Rc 4,7 m2K/W
Type - Pset_WallCommon - IsExternal: yes
Classification: 21.10 Uniformat (Uniformat)
Pset_QuantityTakeOff - Reference: 21_DAT_isolatie minerale wol_160; sets with these values: 2
Pset_WallCommon - ExtendToStructure: no; LoadBearing: no; Reference: 21_DAT_isolatie minerale wol_160
Pset_wanden - Structural Usage: Non-bearing; Omschrijving: Isolatie minerale wol 160mm met een Rc 4,7 m2K/W; NL-sfb-Codering: 21.10
Pset_DAT_KMS - Assembly Code: 21.10; Assembly Description: buitenwanden; niet constructief, algemeen (verzamelniveau); Description: Isolatie minerale wol 160mm met een Rc 4,7 m2K/W
Other - Family: Basic Wall; Family and Type: Basic Wall: 21_DAT_isolatie minerale wol_160; Type: 21_DAT_isolatie minerale wol_160; Type Id: 589367
Constraints - Base Extension Distance: 0 mm; Base is Attached: no; Related to Mass: no; Room Bounding: yes; Top Extension Distance: 0 mm; Top is Attached: no
Phasing - Phase Created: 2. nieuwbouw
Structural - Structural Usage: Non-bearing; Structural: no
Cross-Section Definition - Cross-Section: Vertical
Name (Basic Wall:21_DAT_isolatie minerale wol_160:...) | In | Base Offset (mm) | Location Line | Base Constraint | Top Constraint | Top Offset (mm) | Unconnected Height (mm) | Area (m2) | Length (mm) | Volume (m3) | Workset
5536748 | 00 Begane grond | 0 | Finish Face: Interior | 0 | Up to level: 1 | 184.514 | 3834.51 | 83.4477 | 47410 | 13.3516 | Bouwkundig
5539322 | -1 fundering | 600 | Finish Face: Exterior | bk. fundering | Up to level: 0 | -10 | 660 | 0.757319 | 4033.1 | 0.121171 | Bouwkundig
6492360 | -1 fundering | 0 | Finish Face: Exterior | bk. fundering | Up to level: V0 ok. ruwe vloer | -152 | 788 | 1.6012 | 2195 | 0.256192 | situatie

# IfcWall: Basic Wall:21_DAT_metselwerk_100 (57)
Type - PredefinedType: STANDARD; Material: ISR_Metselwerk 100 mm
Type - Other - Category: Walls; Family Name: Basic Wall
Type - Construction - Function: Exterior; Width: 100 mm; Wrapping at Ends: Exterior; Wrapping at Inserts: Both
Type - Graphics - Coarse Scale Fill Color: 4210752; Coarse Scale Fill Pattern: <Solid fill>
Type - Identity Data - Assembly Code: 21.12; Assembly Description: buitenwanden; niet constructief, spouwwanden; Description: Metselwerk; Type Comments: Metselwerk 100mm; Type Name: 21_DAT_metselwerk_100; Workset: Wall Types
Type - Materials and Finishes - Structural Material: ISR_Metselwerk
Type - Analytical Properties - Absorptance: 0.1; Roughness: 1
Type - Pset_ElementShading - Roughness: 304.8 mm
Type - Pset_ProductRequirements - Category: Walls
Type - Pset_ReinforcementBarPitchOfWall - Description: Metselwerk
Type - Pset_WallCommon - IsExternal: yes
Classification: 21.12 Uniformat (Uniformat)
Pset_QuantityTakeOff - Reference: 21_DAT_metselwerk_100; sets with these values: 2
Pset_WallCommon - Reference: 21_DAT_metselwerk_100; ExtendToStructure: no; LoadBearing: no
Pset_wanden - Structural Usage: Non-bearing; Omschrijving: Metselwerk; NL-sfb-Codering: 21.12
Pset_DAT_KMS - Assembly Code: 21.12; Assembly Description: buitenwanden; niet constructief, spouwwanden; Description: Metselwerk
Other - Family: Basic Wall; Family and Type: Basic Wall: 21_DAT_metselwerk_100; Type: 21_DAT_metselwerk_100; Type Id: 589363
Constraints - Top Offset: 0 mm; Base Extension Distance: 0 mm; Base is Attached: no; Location Line: Finish Face: Interior; Related to Mass: no; Room Bounding: yes; Top Extension Distance: 0 mm; Top is Attached: no
Identity Data - Workset: Bouwkundig
Phasing - Phase Created: 2. nieuwbouw
Structural - Structural Usage: Non-bearing; Structural: no
Cross-Section Definition - Cross-Section: Vertical
Name (Basic Wall:21_DAT_metselwerk_100:...) | In | Base Offset (mm) | Base Constraint | Top Constraint | Unconnected Height (mm) | Area (m2) | Length (mm) | Volume (m3) | Group
5536758 | 01 eerste verdieping | 0 | 1 | Up to level: V2 bk. ruwe vloer | 3500 | 12.0945 | 3475 | 1.20945
5536773 | 00 Begane grond | 0 | 0 | Up to level: 1 | 3650 | 78.7218 | 31845 | 7.83168
5536796 | 01 eerste verdieping | 0 | 1 |  | 625 | 1.99937 | 3175 | 0.199937
5536900 | 00 Begane grond | 0 | 0 | Up to level: 1 | 3650 | 23.9136 | 6997 | 2.39136
5537358 | 01 eerste verdieping | 0 | 1 | Up to level: V2 bk. ruwe vloer | 3500 | 18.325 | 6260 | 1.8325
5537480 | 00 Begane grond | 0 | 0 |  | 1150 | 1.2935 | 1160 | 0.12935
5539090 | 00 Begane grond | -0.0000245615 | 0 | Up to level: 1 | 3650 | 0.0568948 | 54.2862 | 0.00568948
5665192 | -1 fundering | 0 | bk. fundering | Up to level: 0 | 1270 | 0.3697 | 417.5 | 0.03697 | Model Group:Penant Hoek:5539183
5665259 | -1 fundering | 0 | bk. fundering | Up to level: 0 | 1270 | 0.3787 | 385 | 0.03787 | Model Group:Penant Hoek:5539183
6548549 | -1 fundering | 0 | bk. fundering | Up to level: 0 | 1270 | 0.20205 | 215 | 0.020205 | Model Group:Penant Dubbel:5538623
6548550 | -1 fundering | 0 | bk. fundering | Up to level: 0 | 1270 | 0.217675 | 215 | 0.0217675 | Model Group:Penant Dubbel:5538623
6548893 | -1 fundering | 0 | bk. fundering | Up to level: 0 | 1270 | 0.3986 | 255 | 0.03986 | Model Group:Penant Dubbel:5536807
6548894 | -1 fundering | 0 | bk. fundering | Up to level: 0 | 1270 | 0.3986 | 255 | 0.03986 | Model Group:Penant Dubbel:5536807
6548897 | -1 fundering | 0 | bk. fundering | Up to level: 0 | 1270 | 0.398601 | 255.001 | 0.0398601 | Model Group:Penant Dubbel:5536817
6548898 | -1 fundering | 0 | bk. fundering | Up to level: 0 | 1270 | 0.398601 | 255.001 | 0.0398601 | Model Group:Penant Dubbel:5536817
6548901 | -1 fundering | 0 | bk. fundering | Up to level: 0 | 1270 | 0.398601 | 255.001 | 0.0398601 | Model Group:Penant Dubbel:5536821
6548902 | -1 fundering | 0 | bk. fundering | Up to level: 0 | 1270 | 0.398601 | 255.001 | 0.0398601 | Model Group:Penant Dubbel:5536821
6548905 | -1 fundering | 0 | bk. fundering | Up to level: 0 | 1270 | 0.398601 | 255.001 | 0.0398601 | Model Group:Penant Dubbel:5536825
6548906 | -1 fundering | 0 | bk. fundering | Up to level: 0 | 1270 | 0.398601 | 255.001 | 0.0398601 | Model Group:Penant Dubbel:5536825
6548909 | -1 fundering | 0 | bk. fundering | Up to level: 0 | 1270 | 0.398601 | 255.001 | 0.0398601 | Model Group:Penant Dubbel:5536829
6548910 | -1 fundering | 0 | bk. fundering | Up to level: 0 | 1270 | 0.3986 | 255 | 0.03986 | Model Group:Penant Dubbel:5536829
6548913 | -1 fundering | 0 | bk. fundering | Up to level: 0 | 1270 | 0.3986 | 255 | 0.03986 | Model Group:Penant Dubbel:5536875
6548914 | -1 fundering | 0 | bk. fundering | Up to level: 0 | 1270 | 0.3986 | 255 | 0.03986 | Model Group:Penant Dubbel:5536875
6548917 | -1 fundering | 0 | bk. fundering | Up to level: 0 | 1270 | 0.3986 | 255 | 0.03986 | Model Group:Penant Dubbel:5536915
6548918 | -1 fundering | 0 | bk. fundering | Up to level: 0 | 1270 | 0.3986 | 255 | 0.03986 | Model Group:Penant Dubbel:5536915
6548921 | -1 fundering | 0 | bk. fundering | Up to level: 0 | 1270 | 0.3986 | 255 | 0.03986 | Model Group:Penant Dubbel:5536947
6548922 | -1 fundering | 0 | bk. fundering | Up to level: 0 | 1270 | 0.3986 | 255 | 0.03986 | Model Group:Penant Dubbel:5536947
6548926 | -1 fundering | 0 | bk. fundering | Up to level: 0 | 1270 | 0.3986 | 255 | 0.03986 | Model Group:Penant Dubbel:5536961
6548929 | -1 fundering | 0 | bk. fundering | Up to level: 0 | 1270 | 0.3986 | 255 | 0.03986 | Model Group:Penant Dubbel:5537029
6548930 | -1 fundering | 0 | bk. fundering | Up to level: 0 | 1270 | 0.398601 | 255.001 | 0.0398601 | Model Group:Penant Dubbel:5537029
6548934 | -1 fundering | 0 | bk. fundering | Up to level: 0 | 1270 | 0.398176 | 255.001 | 0.0398176 | Model Group:Penant Dubbel:5537041
6548938 | -1 fundering | 0 | bk. fundering | Up to level: 0 | 1270 | 0.398601 | 255.001 | 0.0398601 | Model Group:Penant Dubbel:5537064
6548942 | -1 fundering | 0 | bk. fundering | Up to level: 0 | 1270 | 0.3986 | 255 | 0.03986 | Model Group:Penant Dubbel:5537076
6548945 | -1 fundering | 0 | bk. fundering | Up to level: 0 | 1270 | 0.3986 | 255 | 0.03986 | Model Group:Penant Dubbel:5537098
6548946 | -1 fundering | 0 | bk. fundering | Up to level: 0 | 1270 | 0.3986 | 255 | 0.03986 | Model Group:Penant Dubbel:5537098
6548949 | -1 fundering | 0 | bk. fundering | Up to level: 0 | 1270 | 0.3986 | 255 | 0.03986 | Model Group:Penant Dubbel:5537524
6548962 | -1 fundering | 0 | bk. fundering | Up to level: 0 | 1270 | 0.3986 | 255 | 0.03986 | Model Group:Penant Dubbel:5538649
6548965 | -1 fundering | 0 | bk. fundering | Up to level: 0 | 1270 | 0.3986 | 255 | 0.03986 | Model Group:Penant Dubbel:5538653
6548966 | -1 fundering | 0 | bk. fundering | Up to level: 0 | 1270 | 0.3986 | 255 | 0.03986 | Model Group:Penant Dubbel:5538653
6548969 | -1 fundering | 0 | bk. fundering | Up to level: 0 | 1270 | 0.3986 | 255 | 0.03986 | Model Group:Penant Dubbel:5538657
6548970 | -1 fundering | 0 | bk. fundering | Up to level: 0 | 1270 | 0.3986 | 255 | 0.03986 | Model Group:Penant Dubbel:5538657
6548973 | -1 fundering | 0 | bk. fundering | Up to level: 0 | 1270 | 0.3986 | 255 | 0.03986 | Model Group:Penant Dubbel:5538661
6548986 | -1 fundering | 0 | bk. fundering | Up to level: 0 | 1270 | 0.3986 | 255 | 0.03986 | Model Group:Penant Dubbel:5538673
6548989 | -1 fundering | 0 | bk. fundering | Up to level: 0 | 1270 | 0.3986 | 255 | 0.03986 | Model Group:Penant Dubbel:5538677
6548990 | -1 fundering | 0 | bk. fundering | Up to level: 0 | 1270 | 0.3986 | 255 | 0.03986 | Model Group:Penant Dubbel:5538677
6548993 | -1 fundering | 0 | bk. fundering | Up to level: 0 | 1270 | 0.3986 | 255 | 0.03986 | Model Group:Penant Dubbel:5538681
6548994 | -1 fundering | 0 | bk. fundering | Up to level: 0 | 1270 | 0.398175 | 255 | 0.0398175 | Model Group:Penant Dubbel:5538681
6548997 | -1 fundering | 0 | bk. fundering | Up to level: 0 | 1270 | 0.398627 | 255.037 | 0.0398627 | Model Group:Penant Dubbel:5539114
6548998 | -1 fundering | 0 | bk. fundering | Up to level: 0 | 1270 | 0.398202 | 255.037 | 0.0398202 | Model Group:Penant Dubbel:5539114
6549001 | -1 fundering | 0 | bk. fundering | Up to level: 0 | 1270 | 0.3986 | 255 | 0.03986 | Model Group:Penant Dubbel:5539188
6557735 | -1 fundering | 0 | bk. fundering | Up to level: 0 | 1270 | 0.369747 | 417.537 | 0.0369747 | Model Group:Penant Hoek:5539155
6557736 | -1 fundering | 0 | bk. fundering | Up to level: 0 | 1270 | 0.370075 | 385 | 0.0370075 | Model Group:Penant Hoek:5539155
6557869 | -1 fundering | 0 | bk. fundering | Up to level: 0 | 1270 | 0.2188 | 197.5 | 0.02188 | Model Group:Penant Hoek:5539183
6557870 | -1 fundering | 0 | bk. fundering | Up to level: 0 | 1270 | 0.0918 | 197.5 | 0.00918 | Model Group:Penant Hoek:5539183
6557979 | -1 fundering | 0 | bk. fundering | Up to level: 0 | 1270 | 0.217675 | 197.5 | 0.0217675 | Model Group:Penant Hoek:5539155
6557980 | -1 fundering | 0 | bk. fundering | Up to level: 0 | 1270 | 0.0915928 | 197.537 | 0.00915928 | Model Group:Penant Hoek:5539155
6557981 | -1 fundering | 0 | bk. fundering | Up to level: 0 | 1270 | 0.398627 | 255.037 | 0.0398627 | Model Group:Penant Hoek:5539155

# IfcWall: Basic Wall:22_DAT_binnenwand_125 (9)
Type - PredefinedType: STANDARD; Material: ISR_Gips 1 mm, ISR_Binnenwand 123 mm, ISR_Gips 1 mm
Type - Other - Category: Walls; Family Name: Basic Wall
Type - Construction - Wrapping at Inserts: Both; Function: Interior; Width: 125 mm; Wrapping at Ends: Interior
Type - Graphics - Coarse Scale Fill Pattern: <Solid fill>; Coarse Scale Fill Color: 12632256
Type - Identity Data - Workset: Wall Types; Assembly Code: 22.13; Assembly Description: binnenwanden; niet constructief, systeemwanden; vast; Description: Lichte scheidingswand 125mmAan weerszijden gipsvezelplaat 12,5mmGipsplaat 12,5mm Met daartussen 75mm ms wand gevuld met isolatieVulling afhankelijk van gestelde eisen ingeluidsrapportage; Type Comments: Lichte scheidingswand 125mmGipsvezelplaat 12.5mmGipsplaat 12.5mmMS-wand 75 mm gevuld met isolatieGipsplaat 12.5mmGipsvezelplaat 12.5mmvulling afhankelijk van gestelde eisen ingeluidrapportage; Type Name: 22_DAT_binnenwand_125
Type - Materials and Finishes - Structural Material: ISR_Binnenwand
Type - Analytical Properties - Roughness: 1; Absorptance: 0.1
Type - Pset_ElementShading - Roughness: 304.8 mm
Type - Pset_ProductRequirements - Category: Walls
Type - Pset_ReinforcementBarPitchOfWall - Description: Lichte scheidingswand 125mmAan weerszijden gipsvezelplaat 12,5mmGipsplaat 12,5mm Met daartussen 75mm ms wand gevuld met isolatieVulling afhankelijk van gestelde eisen ingeluidsrapportage
Type - Pset_WallCommon - IsExternal: no
Classification: 22.13 Uniformat (Uniformat)
Pset_QuantityTakeOff - Reference: 22_DAT_binnenwand_125; sets with these values: 2
Pset_WallCommon - ExtendToStructure: no; LoadBearing: no; Reference: 22_DAT_binnenwand_125
Pset_wanden - Structural Usage: Non-bearing; Omschrijving: Lichte scheidingswand 125mmAan weerszijden gipsvezelplaat 12,5mmGipsplaat 12,5mm Met daartussen 75mm ms wand gevuld met isolatieVulling afhankelijk van gestelde eisen ingeluidsrapportage; NL-sfb-Codering: 22.13
Pset_DAT_KMS - Assembly Code: 22.13; Assembly Description: binnenwanden; niet constructief, systeemwanden; vast; Description: Lichte scheidingswand 125mmAan weerszijden gipsvezelplaat 12,5mmGipsplaat 12,5mm Met daartussen 75mm ms wand gevuld met isolatieVulling afhankelijk van gestelde eisen ingeluidsrapportage
Other - Family: Basic Wall; Family and Type: Basic Wall: 22_DAT_binnenwand_125; Type: 22_DAT_binnenwand_125; Type Id: 589403
Constraints - Base Offset: 0 mm; Base Extension Distance: 0 mm; Base is Attached: no; Related to Mass: no; Room Bounding: yes; Top Extension Distance: 0 mm; Top is Attached: no; Location Line: Wall Centerline
Identity Data - Workset: Bouwkundig
Phasing - Phase Created: 2. nieuwbouw
Structural - Structural Usage: Non-bearing; Structural: no
Cross-Section Definition - Cross-Section: Vertical
Name (Basic Wall:22_DAT_binnenwand_125:...) | In | Top Offset (mm) | Base Constraint | Top Constraint | Unconnected Height (mm) | Area (m2) | Length (mm) | Volume (m3)
4963508 | 00 Begane grond | 0 | 0 | Up to level: V1 ok. ruwe vloer | 3240 | 8.1486 | 2515 | 1.01847 | Pset_wanden - NLRS_C_brandwerendheid: R200; Fire Protection - NLRS_C_brandwerendheid: R200
4974709 | 00 Begane grond | 0 | 0 | Up to level: V1 ok. ruwe vloer | 3240 | 6.76354 | 5380 | 0.843559
4980829 | 00 Begane grond | 0 | 0 |  | 3920 | 9.76465 | 3554 | 1.22058
5036166 | 00 Begane grond | 0 | V1 ok. ruwe vloer |  | 1410 | 0.98432 | 1075 | 0.118744
5037714 | 01 eerste verdieping | 0.0000290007 | 1 | Up to level: V2 ok. ruwe vloer | 3240 | 7.00574 | 2800 | 0.874405
5038022 | 01 eerste verdieping | 0 | 1 | Up to level: V2 ok. ruwe vloer | 3240 | 3.96284 | 4910 | 0.494935 | Pset_wanden - NLRS_C_brandwerendheid: 20; Fire Protection - NLRS_C_brandwerendheid: 20
5040712 | 01 eerste verdieping | 0 | 1 |  | 1000 | 0.754081 | 760 | 0.0942602
5228154 | -1 Speelvloer | 0 | V-1 | Up to level: V1 ok. ruwe vloer | 3840 | 9.26386 | 4782.46 | 1.15798
5481974 | -1 Speelvloer | 0 | V-1 | Up to level: 0 | 600 | 0.308027 | 570.001 | 0.0385033

# IfcWall: Basic Wall:22_DAT_binnenwand_125 HPL (4)
In: 00 Begane grond
Type - PredefinedType: STANDARD; Material: ISR_Binnenwand 113 mm, ISR_HPL Kleur hout 12 mm
Type - Other(Type) - Category: Walls; Family Name: Basic Wall
Type - Construction(Type) - Function: Interior; Wrapping at Inserts: Do not wrap; Width: 125 mm
Type - Graphics(Type) - Coarse Scale Fill Pattern: <Solid fill>; Coarse Scale Fill Color: 12632256
Type - Identity Data(Type) - Workset: Wall Types; Assembly Code: 22.13; Assembly Description: binnenwanden; niet constructief, systeemwanden; vast; Description: Lichte scheidingswand 125mmAan weerszijden gipsvezelplaat 12,5mmGipsplaat 12,5mm Met daartussen 75mm ms wand gevuld met isolatieVulling afhankelijk van gestelde eisen ingeluidsrapportage; Type Comments: Lichte scheidingswand 125mmHPL plaat op MDFGipsplaat 12.5mmMS-wand 75 mm gevuld met isolatieGipsplaat 12.5mmGipsvezelplaat 12.5mmvulling afhankelijk van gestelde eisen ingeluidrapportage; Type Name: 22_DAT_binnenwand_125 HPL
Type - Materials and Finishes(Type) - Structural Material: ISR_Binnenwand
Type - Analytical Properties(Type) - Roughness: 1; Absorptance: 0.1
Type - Pset_ElementShading - Roughness: 304.8 mm
Type - Pset_ProductRequirements - Category: Walls
Type - Pset_ReinforcementBarPitchOfWall - Description: Lichte scheidingswand 125mmAan weerszijden gipsvezelplaat 12,5mmGipsplaat 12,5mm Met daartussen 75mm ms wand gevuld met isolatieVulling afhankelijk van gestelde eisen ingeluidsrapportage
Type - Pset_WallCommon - IsExternal: no
Classification: 22.13 Uniformat (Uniformat)
Pset_QuantityTakeOff - Reference: 22_DAT_binnenwand_125 HPL; sets with these values: 2
Pset_WallCommon - ExtendToStructure: no; LoadBearing: no; Reference: 22_DAT_binnenwand_125 HPL
Pset_wanden - Structural Usage: Non-bearing; Omschrijving: Lichte scheidingswand 125mmAan weerszijden gipsvezelplaat 12,5mmGipsplaat 12,5mm Met daartussen 75mm ms wand gevuld met isolatieVulling afhankelijk van gestelde eisen ingeluidsrapportage; NL-sfb-Codering: 22.13
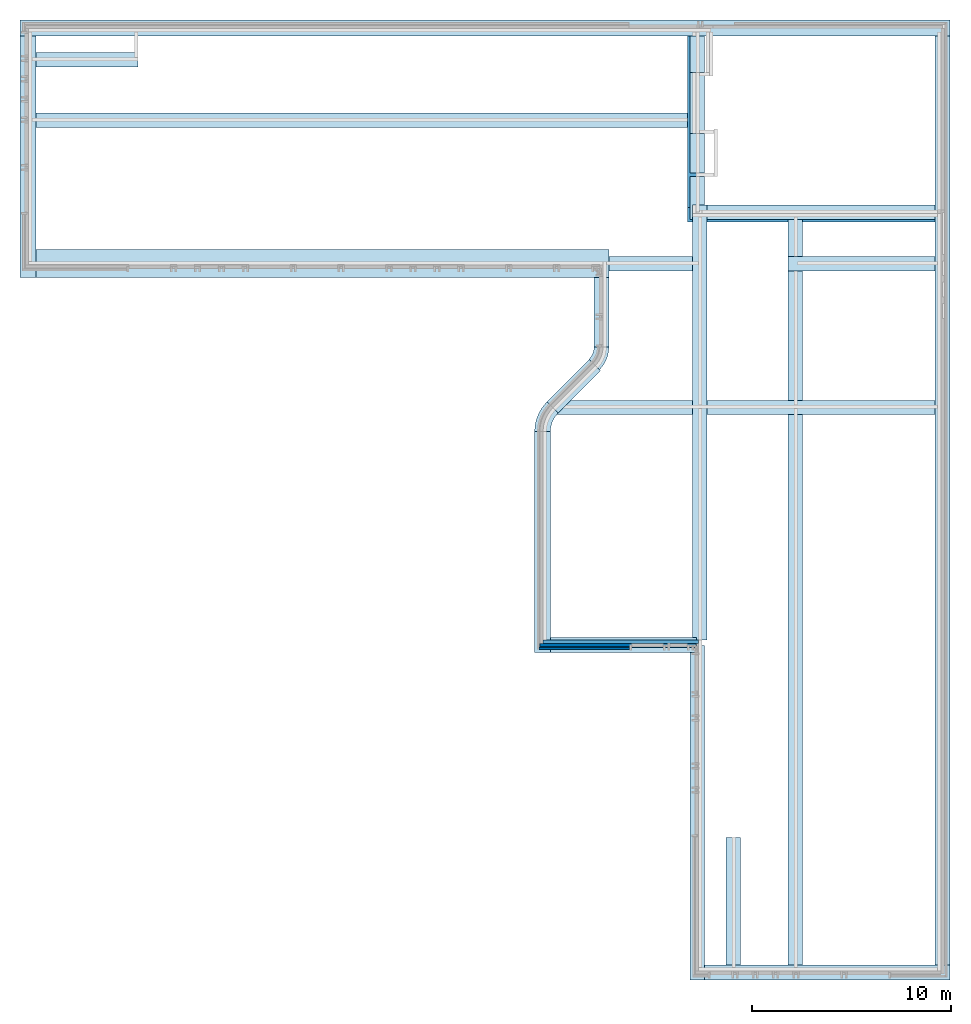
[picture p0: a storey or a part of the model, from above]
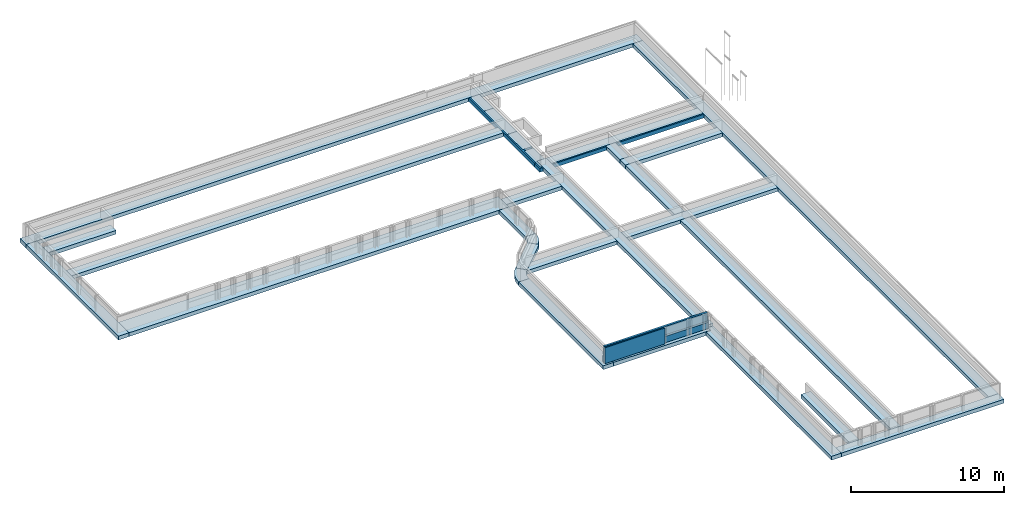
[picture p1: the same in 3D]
Properties of the parts of a building model (IFC2X3), part 29 of 37

# IfcWall: Basic Wall:22_DAT_binnenwand_125 HPL (4)
Pset_DAT_KMS - Assembly Code: 22.13; Assembly Description: binnenwanden; niet constructief, systeemwanden; vast; Description: Lichte scheidingswand 125mmAan weerszijden gipsvezelplaat 12,5mmGipsplaat 12,5mm Met daartussen 75mm ms wand gevuld met isolatieVulling afhankelijk van gestelde eisen ingeluidsrapportage
Other - Category: Walls; Family: Basic Wall; Family and Type: Basic Wall: 22_DAT_binnenwand_125 HPL; Type: 22_DAT_binnenwand_125 HPL; Type Id: 6329633
Constraints - Base Offset: 0 mm; Top Offset: 0 mm; Base Extension Distance: 0 mm; Base is Attached: no; Related to Mass: no; Room Bounding: yes; Top Extension Distance: 0 mm; Top is Attached: no; Location Line: Wall Centerline; Base Constraint: 0; Top Constraint: Up to level: V1 ok. ruwe vloer; Unconnected Height: 3240 mm
Identity Data - Workset: Bouwkundig
Phasing - Phase Created: 2. nieuwbouw
Structural - Structural Usage: Non-bearing; Structural: no
Cross-Section Definition - Cross-Section: Vertical
Name (Basic Wall:22_DAT_binnenwand_125 HPL:...) | Area (m2) | Length (mm) | Volume (m3)
4980111 | 3.645 | 1125 | 0.455604
5307045 | 3.16872 | 915.5 | 0.395985 | Pset_wanden - NLRS_C_brandwerendheid: R200; Fire Protection - NLRS_C_brandwerendheid: R200
5381957 | 3.16872 | 915.5 | 0.39399 | Pset_wanden - NLRS_C_brandwerendheid: R200; Fire Protection - NLRS_C_brandwerendheid: R200
5382005 | 3.16872 | 978 | 0.39399

# IfcWall: Basic Wall:22_DAT_binnenwand_25, Basic Wall:22_DAT_binnenwand_25:6142181
In: 00 Begane grond
Type - PredefinedType: STANDARD; Material: ISR_Gips 1 mm, ISR_Binnenwand 23 mm, ISR_Gips 1 mm
Type - Other - Category: Walls; Family Name: Basic Wall
Type - Construction - Function: Interior; Wrapping at Inserts: Do not wrap; Width: 25 mm
Type - Graphics - Coarse Scale Fill Pattern: <Solid fill>; Coarse Scale Fill Color: 12632256
Type - Identity Data - Workset: Wall Types; Assembly Code: 22.13; Assembly Description: binnenwanden; niet constructief, systeemwanden; vast; Description: Lichte scheidingswand 100mm; Type Comments: Dubbele gipsplaat; Type Name: 22_DAT_binnenwand_25
Type - Materials and Finishes - Structural Material: ISR_Binnenwand
Type - Analytical Properties - Roughness: 1; Absorptance: 0.1
Type - Pset_ElementShading - Roughness: 304.8 mm
Type - Pset_ProductRequirements - Category: Walls
Type - Pset_ReinforcementBarPitchOfWall - Description: Lichte scheidingswand 100mm
Type - Pset_WallCommon - IsExternal: no
Classification: 22.13 Uniformat (Uniformat)
Pset_QuantityTakeOff - Reference: 22_DAT_binnenwand_25; sets with these values: 2
Pset_WallCommon - ExtendToStructure: no; LoadBearing: no; Reference: 22_DAT_binnenwand_25
Pset_wanden - Structural Usage: Non-bearing; Omschrijving: Lichte scheidingswand 100mm; NL-sfb-Codering: 22.13
Pset_DAT_KMS - Assembly Code: 22.13; Assembly Description: binnenwanden; niet constructief, systeemwanden; vast; Description: Lichte scheidingswand 100mm
Other - Family: Basic Wall; Family and Type: Basic Wall: 22_DAT_binnenwand_25; Type: 22_DAT_binnenwand_25; Type Id: 4977124
Constraints - Top Offset: 0 mm; Base Extension Distance: 0 mm; Base is Attached: no; Related to Mass: no; Room Bounding: yes; Top Extension Distance: 0 mm; Top is Attached: no; Location Line: Wall Centerline; Top Constraint: Up to level: 1; Base Constraint: V1 ok. ruwe vloer; Base Offset: -68 mm; Unconnected Height: 478 mm
Dimensions - Area: 0.363059 m2; Length: 760 mm; Volume: 0.00907648 m3
Identity Data - Workset: Bouwkundig
Phasing - Phase Created: 2. nieuwbouw
Structural - Structural Usage: Non-bearing; Structural: no
Cross-Section Definition - Cross-Section: Vertical

# IfcWall: Basic Wall:28_DAT_ihw beton_180 (3)
Type - PredefinedType: STANDARD; Material: ISR_Gips 1 mm, ISR_Beton ihwg 178 mm, ISR_Gips 1 mm
Type - Other - Category: Walls; Family Name: Basic Wall
Type - Construction - Function: Exterior; Wrapping at Inserts: Do not wrap; Width: 180 mm
Type - Graphics - Coarse Scale Fill Pattern: <Solid fill>; Coarse Scale Fill Color: 4210752
Type - Identity Data - Workset: Wall Types; Assembly Code: 28.21; Assembly Description: hoofddraagconstructies; wanden en vloeren, wand-/vloerconstructies; Description: Beton 180mm; Type Comments: IWG beton 180mm volgens opgave constructeur; Type Name: 28_DAT_ihw beton_180
Type - Materials and Finishes - Structural Material: ISR_Beton ihwg
Type - Analytical Properties - Roughness: 1; Absorptance: 0.1
Type - Pset_ElementShading - Roughness: 304.8 mm
Type - Pset_ProductRequirements - Category: Walls
Type - Pset_ReinforcementBarPitchOfWall - Description: Beton 180mm
Type - Pset_WallCommon - IsExternal: yes
Classification: 28.21 Uniformat (Uniformat)
Pset_QuantityTakeOff - Reference: 28_DAT_ihw beton_180; sets with these values: 2
Pset_WallCommon - ExtendToStructure: no; LoadBearing: no; Reference: 28_DAT_ihw beton_180
Pset_wanden - Structural Usage: Non-bearing; Omschrijving: Beton 180mm; NL-sfb-Codering: 28.21
Pset_DAT_KMS - Assembly Code: 28.21; Assembly Description: hoofddraagconstructies; wanden en vloeren, wand-/vloerconstructies; Description: Beton 180mm
Other - Family: Basic Wall; Family and Type: Basic Wall: 28_DAT_ihw beton_180; Type: 28_DAT_ihw beton_180; Type Id: 589387
Constraints - Base Extension Distance: 0 mm; Base is Attached: no; Related to Mass: no; Room Bounding: yes; Top Extension Distance: 0 mm; Top is Attached: no; Location Line: Finish Face: Exterior
Identity Data - Workset: Constructie
Phasing - Phase Created: 2. nieuwbouw
Structural - Structural Usage: Non-bearing; Structural: no
Cross-Section Definition - Cross-Section: Vertical
Name (Basic Wall:28_DAT_ihw beton_180:...) | In | Top Offset (mm) | Base Constraint | Base Offset (mm) | Unconnected Height (mm) | Area (m2) | Length (mm) | Volume (m3)
6560646 | -1 Speelvloer | 0 | V-1 | -670 | 1200 | 13.836 | 11442.5 | 2.49047
6560865 | -1 Speelvloer | 0 | V-1 | -70 | 600 | 5.445 | 9105 | 0.9801
6563005 | -1 fundering | 237.562 | bk. fundering | 188 | 989.562 | 11.7118 | 11975 | 2.10498 | Constraints - Top Constraint: Up to level: V0 ok. ruwe vloer

# IfcWall: Basic Wall:28_DAT_kalkzandsteen_175mm (5)
Type - PredefinedType: STANDARD; Material: ISR_Gips 1 mm, ISR_Kalkzandsteen 173 mm, ISR_Gips 1 mm
Type - Other - Category: Walls; Family Name: Basic Wall
Type - Construction - Function: Interior; Wrapping at Ends: Interior; Width: 175 mm; Wrapping at Inserts: Interior
Type - Graphics - Coarse Scale Fill Pattern: <Solid fill>; Coarse Scale Fill Color: 12632256
Type - Identity Data - Workset: Wall Types; Assembly Code: 28.21; Assembly Description: hoofddraagconstructies; wanden en vloeren, wand-/vloerconstructies; Cost: 0; Description: Kalkzandsteen 175mm; Fire Rating: 90 min.; Type Comments: Kalkzandsteen 175mm; Type Name: 28_DAT_kalkzandsteen_175mm
Type - Materials and Finishes - Structural Material: ISR_Kalkzandsteen
Type - Analytical Properties - Roughness: 1; Absorptance: 0.1
Type - Pset_ConcreteElementGeneral - FireRating: 90 min.
Type - Pset_ElementShading - Roughness: 304.8 mm
Type - Pset_ProductRequirements - Category: Walls
Type - Pset_ReinforcementBarPitchOfWall - Description: Kalkzandsteen 175mm
Type - Pset_WallCommon - IsExternal: no; FireRating: 90 min.
Classification: 28.21 Uniformat (Uniformat)
Pset_QuantityTakeOff - Reference: 28_DAT_kalkzandsteen_175mm; sets with these values: 2
Pset_WallCommon - ExtendToStructure: no; LoadBearing: no; Reference: 28_DAT_kalkzandsteen_175mm
Pset_wanden - Structural Usage: Non-bearing; Omschrijving: Kalkzandsteen 175mm; NL-sfb-Codering: 28.21
Pset_DAT_KMS - Assembly Code: 28.21; Assembly Description: hoofddraagconstructies; wanden en vloeren, wand-/vloerconstructies; Description: Kalkzandsteen 175mm
Other - Family: Basic Wall; Family and Type: Basic Wall: 28_DAT_kalkzandsteen_175mm; Type: 28_DAT_kalkzandsteen_175mm; Type Id: 4741545
Constraints - Base Extension Distance: 0 mm; Base is Attached: no; Related to Mass: no; Room Bounding: yes; Top Extension Distance: 0 mm; Top is Attached: no
Phasing - Phase Created: 2. nieuwbouw
Structural - Structural Usage: Non-bearing; Structural: no
Cross-Section Definition - Cross-Section: Vertical
Name (Basic Wall:28_DAT_kalkzandsteen_175mm:...) | In | Base Offset (mm) | Location Line | Base Constraint | Top Constraint | Top Offset (mm) | Unconnected Height (mm) | Area (m2) | Length (mm) | Volume (m3) | Workset
5481364 | -1 fundering | 0 | Finish Face: Exterior | bk. fundering | Up to level: V0 ok. ruwe vloer | -140 | 800 | 1.88438 | 2362.87 | 0.329766 | Constructie
5481376 | -1 fundering | 0 | Finish Face: Exterior | bk. fundering | Up to level: V0 ok. ruwe vloer | -140 | 800 | 1.39278 | 1849.63 | 0.243737 | Constructie
6265611 | -1 fundering | 0 | Wall Centerline | bk. fundering | Up to level: V0 ok. ruwe vloer | -140 | 800 | 17.0071 | 21542.5 | 2.97624 | Constructie
6265843 | -1 fundering | 0 | Wall Centerline | bk. fundering | Up to level: V0 ok. ruwe vloer | -140 | 800 | 30.1032 | 37972.5 | 5.26805 | Constructie
6782315 | 00 Begane grond | 80 | Wall Centerline | V0 bk. ruwe vloer | Up to level: V1 ok. ruwe vloer | 0 | 3230 | 4.522 | 8990 | 0.79135 | Bouwkundig

# IfcWall: Walls 1:Walls 1, Walls 1:Walls 1:6175128
In: 01 eerste verdieping
Type - Material: ISR_Gips
Type - Other - Category: Walls; Family Name: Walls 1
Type - Identity Data - Workset: Bouwkundig; Type Name: Walls 1
Type - Pset_ProductRequirements - Category: Walls
Type - Pset_WallCommon - IsExternal: no
Pset_QuantityTakeOff - Reference: Walls 1; sets with these values: 2
Pset_WallCommon - Reference: Walls 1
Other - Family: Walls 1; Family and Type: Walls 1: Walls 1; Type: Walls 1; Type Id: 6175126
Constraints - Moves With Nearby Elements: no; Room Bounding: yes
Dimensions - Area: 0.0375451 m2; Volume: 0.00163567 m3
Phasing - Phase Created: 2. nieuwbouw
Structural - Rebar Cover: Rebar Cover 1 <25 mm>

# IfcWallStandardCase: Basic Wall:21_DAT_Gasbeton (3)
In: 02 tweede verdieping
Type - PredefinedType: STANDARD; Material: ISR_Gasbeton 100 mm
Type - Other - Category: Walls; Family Name: Basic Wall
Type - Construction - Function: Exterior; Wrapping at Inserts: Do not wrap; Width: 100 mm
Type - Graphics - Coarse Scale Fill Pattern: <Solid fill>; Coarse Scale Fill Color: 4210752
Type - Identity Data - Workset: Wall Types; Assembly Code: 21.12; Assembly Description: buitenwanden; niet constructief, spouwwanden; Description: Metselwerk 100mm; Type Name: 21_DAT_Gasbeton
Type - Materials and Finishes - Structural Material: ISR_Gasbeton
Type - Analytical Properties - Roughness: 1; Absorptance: 0.1
Type - Pset_ElementShading - Roughness: 304.8 mm
Type - Pset_ProductRequirements - Category: Walls
Type - Pset_ReinforcementBarPitchOfWall - Description: Metselwerk 100mm
Type - Pset_WallCommon - IsExternal: yes
Classification: 21.12 Uniformat (Uniformat)
BaseQuantities - Height: 200 mm; Width: 100 mm
Pset_QuantityTakeOff - Reference: 21_DAT_Gasbeton; sets with these values: 2
Pset_WallCommon - ExtendToStructure: no; LoadBearing: no; Reference: 21_DAT_Gasbeton
Pset_wanden - Structural Usage: Non-bearing; Omschrijving: Metselwerk 100mm; NL-sfb-Codering: 21.12
Pset_DAT_KMS - Assembly Code: 21.12; Assembly Description: buitenwanden; niet constructief, spouwwanden; Description: Metselwerk 100mm
Other - Family: Basic Wall; Family and Type: Basic Wall: 21_DAT_Gasbeton; Type: 21_DAT_Gasbeton; Type Id: 5083415
Constraints - Base Offset: 0 mm; Top Offset: 0 mm; Base Extension Distance: 0 mm; Base is Attached: no; Location Line: Finish Face: Interior; Related to Mass: no; Room Bounding: yes; Top Extension Distance: 0 mm; Top is Attached: no; Base Constraint: V2 bk. ruwe vloer; Unconnected Height: 200 mm
Identity Data - Workset: Bouwkundig
Phasing - Phase Created: 2. nieuwbouw
Structural - Structural Usage: Non-bearing; Structural: no
Cross-Section Definition - Cross-Section: Vertical
Name (Basic Wall:21_DAT_Gasbeton:...) | BaseQuantities, Length (mm) | GrossFootprintArea (m2) | GrossVolume (m3) = NetVolume (m3) = Volume (m3) | GrossSideArea (m2) = NetSideArea (m2) = Area (m2) | Dimensions, Length (mm)
5083409 | 19035 | 1.9035 | 0.3807 | 3.807 | 18905
5083410 | 3360 | 0.336 | 0.0672 | 0.672 | 3360
5083411 | 21950 | 2.195 | 0.439 | 4.39 | 22000

# IfcWallStandardCase: Basic Wall:21_DAT_Hekwerk 100 (13)
Type - PredefinedType: STANDARD; Material: ISR_Multiplex 9 mm, ISR_IsolatieHekwerk 100 mm
Type - Other - Category: Walls; Family Name: Basic Wall
Type - Construction - Function: Exterior; Wrapping at Inserts: Do not wrap; Width: 109 mm
Type - Graphics - Coarse Scale Fill Pattern: <Solid fill>; Coarse Scale Fill Color: 4210752
Type - Identity Data - Workset: Wall Types; Assembly Code: 21.10; Assembly Description: buitenwanden; niet constructief, algemeen (verzamelniveau); Description: Houten dakopstant; Type Comments: Houten dakopstant; Type Name: 21_DAT_Hekwerk 100
Type - Materials and Finishes - Structural Material: ISR_IsolatieHekwerk
Type - Analytical Properties - Roughness: 1; Absorptance: 0.1
Type - Pset_ElementShading - Roughness: 304.8 mm
Type - Pset_ProductRequirements - Category: Walls
Type - Pset_ReinforcementBarPitchOfWall - Description: Houten dakopstant
Type - Pset_WallCommon - IsExternal: yes
Classification: 21.10 Uniformat (Uniformat)
BaseQuantities - Width: 109 mm
Pset_QuantityTakeOff - Reference: 21_DAT_Hekwerk 100; sets with these values: 2
Pset_WallCommon - ExtendToStructure: no; LoadBearing: no; Reference: 21_DAT_Hekwerk 100
Pset_wanden - Structural Usage: Non-bearing; Omschrijving: Houten dakopstant; NL-sfb-Codering: 21.10
Pset_DAT_KMS - Assembly Code: 21.10; Assembly Description: buitenwanden; niet constructief, algemeen (verzamelniveau); Description: Houten dakopstant
Other - Family: Basic Wall; Family and Type: Basic Wall: 21_DAT_Hekwerk 100; Type: 21_DAT_Hekwerk 100; Type Id: 5043834
Constraints - Base Extension Distance: 0 mm; Base is Attached: no; Location Line: Finish Face: Interior; Related to Mass: no; Room Bounding: yes; Top Extension Distance: 0 mm; Top is Attached: no
Identity Data - Workset: Bouwkundig
Phasing - Phase Created: 2. nieuwbouw
Structural - Structural Usage: Non-bearing; Structural: no
Cross-Section Definition - Cross-Section: Vertical
Name (Basic Wall:21_DAT_Hekwerk 100:...) | In | Height (mm) = Unconnected Height (mm) | BaseQuantities, Length (mm) | GrossFootprintArea (m2) | GrossVolume (m3) | GrossSideArea (m2) | NetSideArea (m2) = Area (m2) | NetVolume (m3) = Volume (m3) | Top Offset (mm) | Base Constraint | Base Offset (mm) | Dimensions, Length (mm)
5539130 | 01 eerste verdieping | 425 | 3813.1 | 0.415628 | 0.176642 | 1.62057 | 1.62057 | 0.176642 | 0 | 1 | -0.0000245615 | 3863.1
5539131 | 01 eerste verdieping | 425 | 1083.46 | 0.118095 | 0.00504942 | 0.046325 | 0.478661 | 0.050191 | 0 | 1 | -0.0000245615 | 1083.46 | Graphics - Center Mark Visible: no
5539132 | 01 eerste verdieping | 425 | 3000 | 0.327 | 0.138975 | 1.275 | 1.275 | 0.138975 | 0 | 1 | -0.0000245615 | 3000
5539133 | 01 eerste verdieping | 575 | 1272.74 | 0.138727 | 0.00683157 | 0.062675 | 0.756437 | 0.0797684 | 0 | 1 | -150 | 1272.74 | Graphics - Center Mark Visible: no
5539134 | 01 eerste verdieping | 425 | 10614.3 | 1.15695 | 0.491706 | 4.51106 | 4.51106 | 0.491706 | 0 | 1 | -0.0000245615 | 10694.3
5539135 | 01 eerste verdieping | 515 | 7390.96 | 0.805615 | 0.414892 | 3.80635 | 3.80635 | 0.414892 | 0 | 1 | -90 | 7495.46
5539172 | 02 tweede verdieping | 550 | 35470 | 3.86623 | 2.12643 | 19.5085 | 19.5085 | 2.12643 | 60 | V2 bk. ruwe vloer | 0 | 35520
5539173 | 02 tweede verdieping | 550 | 6900 | 0.7521 | 0.413655 | 3.795 | 3.795 | 0.413655 | 60 | V2 bk. ruwe vloer | 0 | 7030
5539174 | 02 tweede verdieping | 550 | 43966 | 4.79229 | 2.63576 | 24.1813 | 24.1813 | 2.63576 | 60 | V2 bk. ruwe vloer | 0 | 44100.5
5539175 | 02 tweede verdieping | 550 | 12041 | 1.31247 | 0.721858 | 6.62255 | 6.62255 | 0.721858 | 60 | V2 bk. ruwe vloer | 0 | 12175.5
5539176 | 02 tweede verdieping | 550 | 35400 | 3.8586 | 2.12223 | 19.47 | 19.47 | 2.12223 | 60 | V2 bk. ruwe vloer | 0 | 35400
5539177 | 02 tweede verdieping | 550 | 33600 | 3.6624 | 2.01432 | 18.48 | 18.48 | 2.01432 | 60 | V2 bk. ruwe vloer | 0 | 33734.5
5539178 | 02 tweede verdieping | 550 | 11632 | 1.26789 | 0.697338 | 6.3976 | 6.3976 | 0.697338 | 60 | V2 bk. ruwe vloer | 0 | 11741

# IfcWallStandardCase: Basic Wall:21_DAT_Hekwerk 150 (32)
In: 01 eerste verdieping
Type - PredefinedType: STANDARD; Material: ISR_Dak_isolatie(198) 140 mm, ISR_Multiplex 10 mm
Type - Other(Type) - Category: Walls; Family Name: Basic Wall
Type - Construction(Type) - Function: Exterior; Wrapping at Ends: Exterior; Wrapping at Inserts: Exterior; Width: 150 mm
Type - Graphics(Type) - Coarse Scale Fill Pattern: <Solid fill>; Coarse Scale Fill Color: 4210752
Type - Identity Data(Type) - Workset: Wall Types; Assembly Code: 21.10; Assembly Description: buitenwanden; niet constructief, algemeen (verzamelniveau); Description: Samengesteld rekwerkBuitenplaat WBP 10mmHouten stijl- en regelwerk 38x140Minirale wolDampremmendefolieGipsplaat 12.5mmGipsvezelplaat 12,5mm; Type Comments: Samengesteld rekwerkBuitenplaat WBP 10mmHouten stijl- en regelwerk 38x140Minirale wolDampremmendefolieGipsplaat 12.5mmGipsvezelplaat 12,5mm; Type Name: 21_DAT_Hekwerk 150
Type - Materials and Finishes(Type) - Structural Material: ISR_Dak_isolatie(198)
Type - Analytical Properties(Type) - Roughness: 1; Absorptance: 0.1
Type - Pset_ElementShading - Roughness: 304.8 mm
Type - Pset_ProductRequirements - Category: Walls
Type - Pset_ReinforcementBarPitchOfWall - Description: Samengesteld rekwerkBuitenplaat WBP 10mmHouten stijl- en regelwerk 38x140Minirale wolDampremmendefolieGipsplaat 12.5mmGipsvezelplaat 12,5mm
Type - Pset_WallCommon - IsExternal: yes
Classification: 21.10 Uniformat (Uniformat)
BaseQuantities - Height: 2430 mm; Length: 60 mm; Width: 150 mm; GrossFootprintArea: 0.009 m2; GrossVolume: 0.054675 m3; GrossSideArea: 0.3645 m2; NetSideArea: 0.3645 m2
Pset_QuantityTakeOff - Reference: 21_DAT_Hekwerk 150; sets with these values: 2
Pset_WallCommon - ExtendToStructure: no; LoadBearing: no; Reference: 21_DAT_Hekwerk 150
Pset_wanden - Structural Usage: Non-bearing; Omschrijving: Samengesteld rekwerkBuitenplaat WBP 10mmHouten stijl- en regelwerk 38x140Minirale wolDampremmendefolieGipsplaat 12.5mmGipsvezelplaat 12,5mm; NL-sfb-Codering: 21.10; sets with these values: 2
Pset_DAT_KMS - Assembly Code: 21.10; Assembly Description: buitenwanden; niet constructief, algemeen (verzamelniveau); Description: Samengesteld rekwerkBuitenplaat WBP 10mmHouten stijl- en regelwerk 38x140Minirale wolDampremmendefolieGipsplaat 12.5mmGipsvezelplaat 12,5mm
Other - Category: Walls; Family: Basic Wall; Family and Type: Basic Wall: 21_DAT_Hekwerk 150; Type: 21_DAT_Hekwerk 150; Type Id: 6890802
Constraints - Top Offset: 0 mm; Base Extension Distance: 0 mm; Base is Attached: no; Related to Mass: no; Room Bounding: yes; Top Extension Distance: 0 mm; Top is Attached: no; Base Constraint: 1; Location Line: Wall Centerline; Top Constraint: Up to level: V2 ok. ruwe vloer; Base Offset: 810 mm; Unconnected Height: 2430 mm
Dimensions - Length: 60 mm
Identity Data - Workset: Bouwkundig
Phasing - Phase Created: 2. nieuwbouw
Structural - Structural Usage: Non-bearing; Structural: no
Cross-Section Definition - Cross-Section: Vertical
Name (Basic Wall:21_DAT_Hekwerk 150:...) | NetVolume (m3) = Volume (m3) | Area (m2) | Group
6790266 | 0.02187 | 0.1458 | Model Group:Kollom tussenmaat 120x120 eerste verdieping:6790255
6790267 | 0.02187 | 0.1458 | Model Group:Kollom tussenmaat 120x120 eerste verdieping:6790255
6790524 | 0.02187 | 0.1458 | Model Group:Kollom tussenmaat 120x120 eerste verdieping:6790516
6790525 | 0.02187 | 0.1458 | Model Group:Kollom tussenmaat 120x120 eerste verdieping:6790516
6790535 | 0.02187 | 0.1458 | Model Group:Kollom tussenmaat 120x120 eerste verdieping:6790527
6790536 | 0.02187 | 0.1458 | Model Group:Kollom tussenmaat 120x120 eerste verdieping:6790527
6790546 | 0.02187 | 0.1458 | Model Group:Kollom tussenmaat 120x120 eerste verdieping:6790538
6790547 | 0.02187 | 0.1458 | Model Group:Kollom tussenmaat 120x120 eerste verdieping:6790538
6790557 | 0.02187 | 0.1458 | Model Group:Kollom tussenmaat 120x120 eerste verdieping:6790549
6790558 | 0.02187 | 0.1458 | Model Group:Kollom tussenmaat 120x120 eerste verdieping:6790549
6790568 | 0.02187 | 0.1458 | Model Group:Kollom tussenmaat 120x120 eerste verdieping:6790560
6790569 | 0.02187 | 0.1458 | Model Group:Kollom tussenmaat 120x120 eerste verdieping:6790560
6790579 | 0.02187 | 0.1458 | Model Group:Kollom tussenmaat 120x120 eerste verdieping:6790571
6790580 | 0.019554 | 0.13036 | Model Group:Kollom tussenmaat 120x120 eerste verdieping:6790571
6791089 | 0.02187 | 0.1458 | Model Group:Kollom tussenmaat 120x120 eerste verdieping:6791081
6791090 | 0.02187 | 0.1458 | Model Group:Kollom tussenmaat 120x120 eerste verdieping:6791081
6791100 | 0.02187 | 0.1458 | Model Group:Kollom tussenmaat 120x120 eerste verdieping:6791092
6791101 | 0.02187 | 0.1458 | Model Group:Kollom tussenmaat 120x120 eerste verdieping:6791092
6791111 | 0.02187 | 0.1458 | Model Group:Kollom tussenmaat 120x120 eerste verdieping:6791103
6791112 | 0.02187 | 0.1458 | Model Group:Kollom tussenmaat 120x120 eerste verdieping:6791103
6791122 | 0.02187 | 0.1458 | Model Group:Kollom tussenmaat 120x120 eerste verdieping:6791114
6791123 | 0.02187 | 0.1458 | Model Group:Kollom tussenmaat 120x120 eerste verdieping:6791114
6791133 | 0.02187 | 0.1458 | Model Group:Kollom tussenmaat 120x120 eerste verdieping:6791125
6791134 | 0.02187 | 0.1458 | Model Group:Kollom tussenmaat 120x120 eerste verdieping:6791125
6791144 | 0.0200598 | 0.133732 | Model Group:Kollom tussenmaat 120x120 eerste verdieping:6791136
6791145 | 0.02187 | 0.1458 | Model Group:Kollom tussenmaat 120x120 eerste verdieping:6791136
6791155 | 0.0200598 | 0.133732 | Model Group:Kollom tussenmaat 120x120 eerste verdieping:6791147
6791156 | 0.02187 | 0.1458 | Model Group:Kollom tussenmaat 120x120 eerste verdieping:6791147
6791988 | 0.02187 | 0.1458 | Model Group:Kollom tussenmaat 120x120 eerste verdieping:6791290
6791989 | 0.02187 | 0.1458 | Model Group:Kollom tussenmaat 120x120 eerste verdieping:6791290
6792035 | 0.02187 | 0.1458 | Model Group:Kollom tussenmaat 120x120 eerste verdieping:6791938
6792036 | 0.02187 | 0.1458 | Model Group:Kollom tussenmaat 120x120 eerste verdieping:6791938

# IfcWallStandardCase: Basic Wall:21_DAT_Hekwerk 175 (132)
Type - PredefinedType: STANDARD; Material: ISR_Gips 12.5 mm, ISR_Gips 12.5 mm, ISR_Dak_isolatie(198) 140 mm, ISR_Multiplex 10 mm
Type - Other(Type) - Category: Walls; Family Name: Basic Wall
Type - Construction(Type) - Function: Exterior; Wrapping at Ends: Exterior; Width: 175 mm; Wrapping at Inserts: Exterior
Type - Graphics(Type) - Coarse Scale Fill Pattern: <Solid fill>; Coarse Scale Fill Color: 4210752
Type - Identity Data(Type) - Workset: Wall Types; Assembly Code: 21.10; Assembly Description: buitenwanden; niet constructief, algemeen (verzamelniveau); Description: Samengesteld rekwerkBuitenplaat WBP 10mmHouten stijl- en regelwerk 38x140Minirale wolDampremmendefolieGipsplaat 12.5mmGipsvezelplaat 12,5mm; Type Comments: Samengesteld rekwerkBuitenplaat WBP 10mmHouten stijl- en regelwerk 38x140Minirale wolDampremmendefolieGipsplaat 12.5mmGipsvezelplaat 12,5mm; Type Name: 21_DAT_Hekwerk 175
Type - Materials and Finishes(Type) - Structural Material: ISR_Dak_isolatie(198)
Type - Analytical Properties(Type) - Roughness: 1; Absorptance: 0.1
Type - Pset_ElementShading - Roughness: 304.8 mm
Type - Pset_ProductRequirements - Category: Walls
Type - Pset_ReinforcementBarPitchOfWall - Description: Samengesteld rekwerkBuitenplaat WBP 10mmHouten stijl- en regelwerk 38x140Minirale wolDampremmendefolieGipsplaat 12.5mmGipsvezelplaat 12,5mm
Type - Pset_WallCommon - IsExternal: yes
Classification: 21.10 Uniformat (Uniformat)
BaseQuantities - Width: 175 mm
Pset_QuantityTakeOff - Reference: 21_DAT_Hekwerk 175; sets with these values: 2
Pset_WallCommon - ExtendToStructure: no; LoadBearing: no; Reference: 21_DAT_Hekwerk 175
Pset_wanden - Structural Usage: Non-bearing; Omschrijving: Samengesteld rekwerkBuitenplaat WBP 10mmHouten stijl- en regelwerk 38x140Minirale wolDampremmendefolieGipsplaat 12.5mmGipsvezelplaat 12,5mm; NL-sfb-Codering: 21.10; sets with these values: 2
Pset_DAT_KMS - Assembly Code: 21.10; Assembly Description: buitenwanden; niet constructief, algemeen (verzamelniveau); Description: Samengesteld rekwerkBuitenplaat WBP 10mmHouten stijl- en regelwerk 38x140Minirale wolDampremmendefolieGipsplaat 12.5mmGipsvezelplaat 12,5mm
Other - Category: Walls; Family: Basic Wall; Family and Type: Basic Wall: 21_DAT_Hekwerk 175; Type: 21_DAT_Hekwerk 175; Type Id: 5435600
Constraints - Base Extension Distance: 0 mm; Base is Attached: no; Related to Mass: no; Room Bounding: yes; Top Extension Distance: 0 mm; Top is Attached: no
Phasing - Phase Created: 2. nieuwbouw
Structural - Structural Usage: Non-bearing; Structural: no
Cross-Section Definition - Cross-Section: Vertical
Name (Basic Wall:21_DAT_Hekwerk 175:...) | In | Height (mm) | BaseQuantities, Length (mm) | GrossFootprintArea (m2) | GrossVolume (m3) | GrossSideArea (m2) = NetSideArea (m2) | NetVolume (m3) = Volume (m3) | Top Offset (mm) | Location Line | Base Constraint | Top Constraint | Base Offset (mm) | Unconnected Height (mm) | Area (m2) | Dimensions, Length (mm) | Workset | Group
5539255 | 01 eerste verdieping | 509.983 | 2104 | 0.3682 | 0.18417 | 1.0524 | 0.18417 | 0 | Finish Face: Interior | 1 | Up to level: V2 ok. ruwe vloer | 2730.02 | 509.983 | 1.0524 | 2104 | Bouwkundig
5539257 | 01 eerste verdieping | 500 | 773 | 0.135275 | 0.0676375 | 0.3865 | 0.0676375 | 0 | Finish Face: Interior | 1 | Up to level: V2 ok. ruwe vloer | 2730.02 | 509.983 | 0.3865 | 773 | Bouwkundig
6002587 | 00 Begane grond | 3310 | 5325 | 0.931875 | 0.64785 | 3.702 | 0.64785 | 0 | Wall Centerline | V0 bk. ruwe vloer | Up to level: V1 ok. ruwe vloer | 0 | 3310 | 3.702 | 5325 | Bouwkundig
6004052 | 00 Begane grond | 600 | 2120 | 0.371 | 0.2226 | 1.272 | 0.2226 | 0 | Wall Centerline | V0 bk. ruwe vloer | Up to level: V1 ok. ruwe vloer | 80 | 3230 | 1.272 | 2120 | Bouwkundig
6776609 | 00 Begane grond | 350 | 790 | 0.13825 | 0.0483875 | 0.2765 | 0.0483875 | 0 | Wall Centerline | 0 | Up to level: V1 ok. ruwe vloer | 2890 | 350 | 0.2765 | 790 | Bouwkundig | Model Group:K_Raamwerk_06a:5537494
6777284 | 00 Begane grond | 2530 | 2330 | 0.40775 | 0.154158 | 0.8809 | 0.154158 | 0 | Wall Centerline | 0 | Up to level: V1 ok. ruwe vloer | 710 | 2530 | 0.8809 | 2330 | Bouwkundig
6777656 | 00 Begane grond | 350 | 790 | 0.13825 | 0.0483875 | 0.2765 | 0.0483875 | 0 | Wall Centerline | 0 | Up to level: V1 ok. ruwe vloer | 2890 | 350 | 0.2765 | 790 | Bouwkundig | Model Group:K_Raamwerk_06:5537289
6777864 | 00 Begane grond | 350 | 790 | 0.13825 | 0.0483875 | 0.2765 | 0.0483875 | 0 | Wall Centerline | 0 | Up to level: V1 ok. ruwe vloer | 2890 | 350 | 0.2765 | 790 | Bouwkundig | Model Group:K_Raamwerk_06:5537301
6777867 | 00 Begane grond | 350 | 790 | 0.13825 | 0.0483875 | 0.2765 | 0.0483875 | 0 | Wall Centerline | 0 | Up to level: V1 ok. ruwe vloer | 2890 | 350 | 0.2765 | 790 | Bouwkundig | Model Group:K_Raamwerk_06:5537313
6777870 | 00 Begane grond | 350 | 790 | 0.13825 | 0.0483875 | 0.2765 | 0.0483875 | 0 | Wall Centerline | 0 | Up to level: V1 ok. ruwe vloer | 2890 | 350 | 0.2765 | 790 | Bouwkundig | Model Group:K_Raamwerk_06:5537322
6777873 | 00 Begane grond | 350 | 790 | 0.13825 | 0.0483875 | 0.2765 | 0.0483875 | 0 | Wall Centerline | 0 | Up to level: V1 ok. ruwe vloer | 2890 | 350 | 0.2765 | 790 | Bouwkundig | Model Group:K_Raamwerk_06:5537327
6777876 | 00 Begane grond | 350 | 790 | 0.13825 | 0.0483875 | 0.2765 | 0.0483875 | 0 | Wall Centerline | 0 | Up to level: V1 ok. ruwe vloer | 2890 | 350 | 0.2765 | 790 | Bouwkundig | Model Group:K_Raamwerk_06:5537331
6778088 | 00 Begane grond | 2530 | 40 | 0.007 | 0.0774813 | 0.44275 | 0.01771 | 0 | Wall Centerline | 0 | Up to level: V1 ok. ruwe vloer | 710 | 2530 | 0.1012 | 40 | Bouwkundig
6778270 | 00 Begane grond | 350 | 2300 | 0.4025 | 0.140875 | 0.805 | 0.140875 | 0 | Wall Centerline | 0 | Up to level: V1 ok. ruwe vloer | 2890 | 350 | 0.805 | 2300 | Bouwkundig
6778571 | 00 Begane grond | 2530 | 45 | 0.007875 | 0.0774813 | 0.44275 | 0.0199238 | 0 | Wall Centerline | 0 | Up to level: V1 ok. ruwe vloer | 710 | 2530 | 0.11385 | 45 | Bouwkundig | Model Group:Kollom tussenmaat 150x150:6001993
6778795 | 00 Begane grond | 2530 | 45 | 0.007875 | 0.0774813 | 0.44275 | 0.0199238 | 0 | Wall Centerline | 0 | Up to level: V1 ok. ruwe vloer | 710 | 2530 | 0.11385 | 45 | Bouwkundig | Model Group:Kollom tussenmaat 150x150:6001993
6778834 | 00 Begane grond | 2530 | 45 | 0.007875 | 0.0774813 | 0.44275 | 0.0199238 | 0 | Wall Centerline | 0 | Up to level: V1 ok. ruwe vloer | 710 | 2530 | 0.11385 | 45 | Bouwkundig | Model Group:Kollom tussenmaat 150x150:6001982
6778835 | 00 Begane grond | 2530 | 45 | 0.007875 | 0.0774813 | 0.44275 | 0.0199238 | 0 | Wall Centerline | 0 | Up to level: V1 ok. ruwe vloer | 710 | 2530 | 0.11385 | 45 | Bouwkundig | Model Group:Kollom tussenmaat 150x150:6001982
6778838 | 01 eerste verdieping | 3970 | 45 | 0.007875 | 0.121581 | 0.69475 | 0.0312638 | 0.0000289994 | Wall Centerline | 1 | Up to level: V2 ok. ruwe vloer | -730 | 3970 | 0.17865 | 45 | Bouwkundig
6778839 | 01 eerste verdieping | 2430 | 45 | 0.007875 | 0.0744188 | 0.42525 | 0.0191363 | 0.0000289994 | Wall Centerline | 1 | Up to level: V2 ok. ruwe vloer | 810 | 2430 | 0.10935 | 45 | Bouwkundig
6779344 | 00 Begane grond | 2530 | 60 | 0.0105 | 0.0774813 | 0.44275 | 0.026565 | 0 | Wall Centerline | 0 | Up to level: V1 ok. ruwe vloer | 710 | 2530 | 0.1518 | 60 | Bouwkundig | Model Group:Kollom tussenmaat 120x120:6002382
6779345 | 00 Begane grond | 2530 | 60 | 0.0105 | 0.0774813 | 0.44275 | 0.026565 | 0 | Wall Centerline | 0 | Up to level: V1 ok. ruwe vloer | 710 | 2530 | 0.1518 | 60 | Bouwkundig | Model Group:Kollom tussenmaat 120x120:6002382
6779723 | 00 Begane grond | 2530 | 60 | 0.0105 | 0.0774813 | 0.44275 | 0.026565 | 0 | Wall Centerline | 0 | Up to level: V1 ok. ruwe vloer | 710 | 2530 | 0.1518 | 60 | Bouwkundig | Model Group:Kollom tussenmaat 120x120:5998666
6779724 | 00 Begane grond | 2530 | 60 | 0.0105 | 0.0774813 | 0.44275 | 0.026565 | 0 | Wall Centerline | 0 | Up to level: V1 ok. ruwe vloer | 710 | 2530 | 0.1518 | 60 | Bouwkundig | Model Group:Kollom tussenmaat 120x120:5998666
6779743 | 00 Begane grond | 3230 | 60 | 0.0105 | 0.0989188 | 0.56525 | 0.033915 | 0 | Wall Centerline | 0 | Up to level: V1 ok. ruwe vloer | 10 | 3230 | 0.1938 | 60 | Bouwkundig | Model Group:Kollom tussenmaat 120x120 Heel:6000703
6779744 | 00 Begane grond | 3230 | 60 | 0.0105 | 0.0989188 | 0.56525 | 0.033915 | 0 | Wall Centerline | 0 | Up to level: V1 ok. ruwe vloer | 10 | 3230 | 0.1938 | 60 | Bouwkundig | Model Group:Kollom tussenmaat 120x120 Heel:6000703
6779756 | 00 Begane grond | 3240 | 60 | 0.0105 | 0.099225 | 0.567 | 0.03402 | 0 | Wall Centerline | 0 | Up to level: V1 ok. ruwe vloer | 0 | 3240 | 0.1944 | 60 | Bouwkundig
6779759 | 00 Begane grond | 2530 | 60 | 0.0105 | 0.0774813 | 0.44275 | 0.026565 | 0 | Wall Centerline | 0 | Up to level: V1 ok. ruwe vloer | 710 | 2530 | 0.1518 | 60 | Bouwkundig | Model Group:Kollom tussenmaat 120x120:6002465
6779760 | 00 Begane grond | 2530 | 60 | 0.0105 | 0.0774813 | 0.44275 | 0.026565 | 0 | Wall Centerline | 0 | Up to level: V1 ok. ruwe vloer | 710 | 2530 | 0.1518 | 60 | Bouwkundig | Model Group:Kollom tussenmaat 120x120:6002465
6779811 | 01 eerste verdieping | 2530 | 60 | 0.0105 | 0.0774813 | 0.44275 | 0.026565 | 0.0000289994 | Wall Centerline | 1 | Up to level: V2 ok. ruwe vloer | 710 | 2530 | 0.1518 | 60 | Bouwkundig
6779812 | 01 eerste verdieping | 3650 | 60 | 0.0105 | 0.111781 | 0.63875 | 0.038325 | 0.0000289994 | Wall Centerline | 1 | Up to level: V2 ok. ruwe vloer | -410 | 3650 | 0.219 | 60 | Bouwkundig
6779843 | 01 eerste verdieping | 2530 | 60 | 0.0105 | 0.0774813 | 0.44275 | 0.026565 | 0.0000289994 | Wall Centerline | 1 | Up to level: V2 ok. ruwe vloer | 710 | 2530 | 0.1518 | 60 | Constructie | Model Group:Kollom tussenmaat 120x120:6152818
6779844 | 01 eerste verdieping | 2530 | 60 | 0.0105 | 0.0774813 | 0.44275 | 0.026565 | 0.0000289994 | Wall Centerline | 1 | Up to level: V2 ok. ruwe vloer | 710 | 2530 | 0.1518 | 60 | Constructie | Model Group:Kollom tussenmaat 120x120:6152818
6779847 | 01 eerste verdieping | 2530 | 60 | 0.0105 | 0.0774813 | 0.44275 | 0.026565 | 0.0000289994 | Wall Centerline | 1 | Up to level: V2 ok. ruwe vloer | 710 | 2530 | 0.1518 | 60 | Bouwkundig | Model Group:Kollom tussenmaat 120x120:6152949
6779848 | 01 eerste verdieping | 2530 | 60 | 0.0105 | 0.0774813 | 0.44275 | 0.026565 | 0.0000289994 | Wall Centerline | 1 | Up to level: V2 ok. ruwe vloer | 710 | 2530 | 0.1518 | 60 | Bouwkundig | Model Group:Kollom tussenmaat 120x120:6152949
6780310 | 00 Begane grond | 710 | 60 | 0.0105 | 0.0217438 | 0.12425 | 0.007455 | 0 | Wall Centerline | 0 |  | 0 | 710 | 0.0426 | 60 | Bouwkundig
6780311 | 00 Begane grond | 710 | 60 | 0.0105 | 0.0217438 | 0.12425 | 0.007455 | 0 | Wall Centerline | 0 |  | 0 | 710 | 0.0426 | 60 | Bouwkundig
6781345 | 00 Begane grond | 600 | 2120 | 0.371 | 0.2226 | 1.272 | 0.2226 | 0 | Wall Centerline | V0 bk. ruwe vloer | Up to level: V1 ok. ruwe vloer | 80 | 3230 | 1.272 | 2120 | Bouwkundig
6781413 | 00 Begane grond | 3230 | 2120 | 0.371 | 0.23002 | 1.3144 | 0.23002 | 0 | Wall Centerline | V0 bk. ruwe vloer | Up to level: V1 ok. ruwe vloer | 80 | 3230 | 1.3144 | 2120 | Bouwkundig
6781667 | 00 Begane grond | 3230 | 2120 | 0.371 | 0.23002 | 1.3144 | 0.23002 | 0 | Wall Centerline | V0 bk. ruwe vloer | Up to level: V1 ok. ruwe vloer | 80 | 3230 | 1.3144 | 2120 | Bouwkundig
6781673 | 00 Begane grond | 3230 | 2120 | 0.371 | 0.23002 | 1.3144 | 0.23002 | 0 | Wall Centerline | V0 bk. ruwe vloer | Up to level: V1 ok. ruwe vloer | 80 | 3230 | 1.3144 | 2120 | Bouwkundig
6781676 | 00 Begane grond | 3230 | 2120 | 0.371 | 0.23002 | 1.3144 | 0.23002 | 0 | Wall Centerline | V0 bk. ruwe vloer | Up to level: V1 ok. ruwe vloer | 80 | 3230 | 1.3144 | 2120 | Bouwkundig
6781805 | 00 Begane grond | 600 | 740 | 0.1295 | 0.0777 | 0.444 | 0.0777 | 0 | Wall Centerline | V0 bk. ruwe vloer | Up to level: V1 ok. ruwe vloer | 2710 | 600 | 0.444 | 740 | Bouwkundig
6781884 | 00 Begane grond | 600 | 740 | 0.1295 | 0.0777 | 0.444 | 0.0777 | 0 | Wall Centerline | V0 bk. ruwe vloer | Up to level: V1 ok. ruwe vloer | 2710 | 600 | 0.444 | 740 | Bouwkundig
6781887 | 00 Begane grond | 600 | 740 | 0.1295 | 0.0777 | 0.444 | 0.0777 | 0 | Wall Centerline | V0 bk. ruwe vloer | Up to level: V1 ok. ruwe vloer | 2710 | 600 | 0.444 | 740 | Bouwkundig
6782117 | 00 Begane grond | 600 | 1130 | 0.19775 | 0.11865 | 0.678 | 0.11865 | 0 | Wall Centerline | V0 bk. ruwe vloer | Up to level: V1 ok. ruwe vloer | 2710 | 600 | 0.678 | 1130 | Bouwkundig
6782613 | 00 Begane grond | 3230 | 60 | 0.0105 | 0.0989188 | 0.56525 | 0.033915 | 0 | Wall Centerline | 0 | Up to level: V1 ok. ruwe vloer | 10 | 3230 | 0.1938 | 60 | Bouwkundig | Model Group:Kollom tussenmaat 120x120 Heel:6000652
6782614 | 00 Begane grond | 3230 | 60 | 0.0105 | 0.0989188 | 0.56525 | 0.033915 | 0 | Wall Centerline | 0 | Up to level: V1 ok. ruwe vloer | 10 | 3230 | 0.1938 | 60 | Bouwkundig | Model Group:Kollom tussenmaat 120x120 Heel:6000652
6782788 | 00 Begane grond | 600 | 920 | 0.161 | 0.0966 | 0.552 | 0.0966 | 0 | Wall Centerline | V0 bk. ruwe vloer | Up to level: V1 ok. ruwe vloer | 2710 | 600 | 0.552 | 920 | Bouwkundig | Model Group:K_Raamwerk_01:5536916
6782920 | 00 Begane grond | 600 | 920 | 0.161 | 0.0966 | 0.552 | 0.0966 | 0 | Wall Centerline | V0 bk. ruwe vloer | Up to level: V1 ok. ruwe vloer | 2710 | 600 | 0.552 | 920 | Bouwkundig | Model Group:K_Raamwerk_01:5536948
6782923 | 00 Begane grond | 600 | 920 | 0.161 | 0.0966 | 0.552 | 0.0966 | 0 | Wall Centerline | V0 bk. ruwe vloer | Up to level: V1 ok. ruwe vloer | 2710 | 600 | 0.552 | 920 | Bouwkundig | Model Group:K_Raamwerk_01:5536975
6783343 | 00 Begane grond | 600 | 1865 | 0.326375 | 0.195825 | 1.119 | 0.195825 | 0 | Wall Centerline | V0 bk. ruwe vloer | Up to level: V1 ok. ruwe vloer | 2710 | 600 | 1.119 | 1865 | Bouwkundig | Model Group:K_Raamwerk_21:5536962
6783640 | 00 Begane grond | 3230 | 60 | 0.0105 | 0.0989188 | 0.56525 | 0.033915 | 0 | Wall Centerline | 0 | Up to level: V1 ok. ruwe vloer | 10 | 3230 | 0.1938 | 60 | Bouwkundig | Model Group:Kollom tussenmaat 120x120 Heel:5998690
6783641 | 00 Begane grond | 3230 | 60 | 0.0105 | 0.0989188 | 0.56525 | 0.033915 | 0 | Wall Centerline | 0 | Up to level: V1 ok. ruwe vloer | 10 | 3230 | 0.1938 | 60 | Bouwkundig | Model Group:Kollom tussenmaat 120x120 Heel:5998690
6783688 | 00 Begane grond | 3230 | 60 | 0.0105 | 0.0989188 | 0.56525 | 0.033915 | 0 | Wall Centerline | 0 | Up to level: V1 ok. ruwe vloer | 10 | 3230 | 0.1938 | 60 | Bouwkundig | Model Group:Kollom tussenmaat 120x120 Heel:5998677
6783689 | 00 Begane grond | 3230 | 60 | 0.0105 | 0.0989188 | 0.56525 | 0.033915 | 0 | Wall Centerline | 0 | Up to level: V1 ok. ruwe vloer | 10 | 3230 | 0.1938 | 60 | Bouwkundig | Model Group:Kollom tussenmaat 120x120 Heel:5998677
6783770 | 00 Begane grond | 3230 | 60 | 0.0105 | 0.0989188 | 0.56525 | 0.033915 | 0 | Wall Centerline | 0 | Up to level: V1 ok. ruwe vloer | 10 | 3230 | 0.1938 | 60 | Bouwkundig | Model Group:Kollom tussenmaat 120x120 Heel:5998631
6783771 | 00 Begane grond | 3230 | 60 | 0.0105 | 0.0989188 | 0.56525 | 0.033915 | 0 | Wall Centerline | 0 | Up to level: V1 ok. ruwe vloer | 10 | 3230 | 0.1938 | 60 | Bouwkundig | Model Group:Kollom tussenmaat 120x120 Heel:5998631
6783817 | 00 Begane grond | 3230 | 60 | 0.0105 | 0.0989188 | 0.56525 | 0.033915 | 0 | Wall Centerline | 0 | Up to level: V1 ok. ruwe vloer | 10 | 3230 | 0.1938 | 60 | Bouwkundig | Model Group:Kollom tussenmaat 120x120 Heel:5998642
6783818 | 00 Begane grond | 3230 | 60 | 0.0105 | 0.0989188 | 0.56525 | 0.033915 | 0 | Wall Centerline | 0 | Up to level: V1 ok. ruwe vloer | 10 | 3230 | 0.1938 | 60 | Bouwkundig | Model Group:Kollom tussenmaat 120x120 Heel:5998642
6784091 | 00 Begane grond | 600 | 2119.94 | 0.370989 | 0.222593 | 1.27196 | 0.222593 | 0 | Wall Centerline | V0 bk. ruwe vloer | Up to level: V1 ok. ruwe vloer | 2710 | 600 | 1.27196 | 2119.94 | Bouwkundig | Model Group:K_Raamwerk_02:5539371
6784244 | 00 Begane grond | 600 | 2119.94 | 0.370989 | 0.222593 | 1.27196 | 0.222593 | 0 | Wall Centerline | V0 bk. ruwe vloer | Up to level: V1 ok. ruwe vloer | 2710 | 600 | 1.27196 | 2119.94 | Bouwkundig | Model Group:K_Raamwerk_02:5538732
6784247 | 00 Begane grond | 600 | 2119.94 | 0.370989 | 0.222593 | 1.27196 | 0.222593 | 0 | Wall Centerline | V0 bk. ruwe vloer | Up to level: V1 ok. ruwe vloer | 2710 | 600 | 1.27196 | 2119.94 | Bouwkundig | Model Group:K_Raamwerk_02:5538742
6784507 | 00 Begane grond | 3230 | 60 | 0.0105 | 0.0989188 | 0.56525 | 0.033915 | 0 | Wall Centerline | 0 | Up to level: V1 ok. ruwe vloer | 10 | 3230 | 0.1938 | 60 | Bouwkundig | Model Group:Kollom tussenmaat 120x120 Heel:5998655
6784508 | 00 Begane grond | 3230 | 60 | 0.0105 | 0.0989188 | 0.56525 | 0.033915 | 0 | Wall Centerline | 0 | Up to level: V1 ok. ruwe vloer | 10 | 3230 | 0.1938 | 60 | Bouwkundig | Model Group:Kollom tussenmaat 120x120 Heel:5998655
6784590 | 00 Begane grond | 3230 | 60 | 0.0105 | 0.0989188 | 0.56525 | 0.033915 | 0 | Wall Centerline | 0 | Up to level: V1 ok. ruwe vloer | 10 | 3230 | 0.1938 | 60 | Bouwkundig | Model Group:Kollom tussenmaat 120x120 Heel:5998910
6784591 | 00 Begane grond | 3230 | 60 | 0.0105 | 0.0989188 | 0.56525 | 0.033915 | 0 | Wall Centerline | 0 | Up to level: V1 ok. ruwe vloer | 10 | 3230 | 0.1938 | 60 | Bouwkundig | Model Group:Kollom tussenmaat 120x120 Heel:5998910
6784766 | 00 Begane grond | 3230 | 60 | 0.0105 | 0.0989188 | 0.56525 | 0.033915 | 0 | Wall Centerline | 0 | Up to level: V1 ok. ruwe vloer | 10 | 3230 | 0.1938 | 60 | Bouwkundig | Model Group:Kollom tussenmaat 120x120 Heel:5998578
6784767 | 00 Begane grond | 3230 | 60 | 0.0105 | 0.0989188 | 0.56525 | 0.033915 | 0 | Wall Centerline | 0 | Up to level: V1 ok. ruwe vloer | 10 | 3230 | 0.1938 | 60 | Bouwkundig | Model Group:Kollom tussenmaat 120x120 Heel:5998578
6784980 | 00 Begane grond | 600 | 1635.06 | 0.286136 | 0.171682 | 0.981038 | 0.171682 | 0 | Wall Centerline | V0 bk. ruwe vloer | Up to level: V1 ok. ruwe vloer | 2710 | 600 | 0.981038 | 1635.06 | Bouwkundig | Model Group:K_Raamwerk_18:5538682
6785128 | 00 Begane grond | 600 | 920 | 0.161 | 0.0966 | 0.552 | 0.0966 | 0 | Wall Centerline | V0 bk. ruwe vloer | Up to level: V1 ok. ruwe vloer | 2710 | 600 | 0.552 | 920 | Bouwkundig | Model Group:K_Raamwerk_01 A:5538692
6785316 | 00 Begane grond | 600 | 920 | 0.161 | 0.0966 | 0.552 | 0.0966 | 0 | Wall Centerline | V0 bk. ruwe vloer | Up to level: V1 ok. ruwe vloer | 2710 | 600 | 0.552 | 920 | Bouwkundig | Model Group:K_Raamwerk_01 A:5538614
6785319 | 00 Begane grond | 600 | 920 | 0.161 | 0.0966 | 0.552 | 0.0966 | 0 | Wall Centerline | V0 bk. ruwe vloer | Up to level: V1 ok. ruwe vloer | 2710 | 600 | 0.552 | 920 | Bouwkundig | Model Group:K_Raamwerk_01 A:5538632
6785322 | 00 Begane grond | 600 | 920 | 0.161 | 0.0966 | 0.552 | 0.0966 | 0 | Wall Centerline | V0 bk. ruwe vloer | Up to level: V1 ok. ruwe vloer | 2710 | 600 | 0.552 | 920 | Bouwkundig | Model Group:K_Raamwerk_01 A:5538702
6785325 | 00 Begane grond | 600 | 920 | 0.161 | 0.0966 | 0.552 | 0.0966 | 0 | Wall Centerline | V0 bk. ruwe vloer | Up to level: V1 ok. ruwe vloer | 2710 | 600 | 0.552 | 920 | Bouwkundig | Model Group:K_Raamwerk_01 A:5538712
6785328 | 00 Begane grond | 600 | 920 | 0.161 | 0.0966 | 0.552 | 0.0966 | 0 | Wall Centerline | V0 bk. ruwe vloer | Up to level: V1 ok. ruwe vloer | 2710 | 600 | 0.552 | 920 | Bouwkundig | Model Group:K_Raamwerk_01 A:5538722
6787093 | 01 eerste verdieping | 500 | 790 | 0.13825 | 0.069125 | 0.395 | 0.069125 | 0.0000289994 | Wall Centerline | V1 bk. ruwe vloer | Up to level: V2 ok. ruwe vloer | 2830 | 500 | 0.395 | 790 | Bouwkundig | Model Group:K_Raamwerk_29:5537783
6787115 | 01 eerste verdieping | 500 | 2250 | 0.39375 | 0.196875 | 1.125 | 0.196875 | 0.0000289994 | Wall Centerline | V1 bk. ruwe vloer | Up to level: V2 ok. ruwe vloer | 2830 | 500 | 1.125 | 2250 | Bouwkundig
6787423 | 01 eerste verdieping | 500 | 790 | 0.13825 | 0.069125 | 0.395 | 0.069125 | 0.0000289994 | Wall Centerline | V1 bk. ruwe vloer | Up to level: V2 ok. ruwe vloer | 2830 | 500 | 0.395 | 790 | Bouwkundig | Model Group:K_Raamwerk_29:5537787
6787426 | 01 eerste verdieping | 500 | 790 | 0.13825 | 0.069125 | 0.395 | 0.069125 | 0.0000289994 | Wall Centerline | V1 bk. ruwe vloer | Up to level: V2 ok. ruwe vloer | 2830 | 500 | 0.395 | 790 | Bouwkundig | Model Group:K_Raamwerk_29:5537791
6787429 | 01 eerste verdieping | 500 | 790 | 0.13825 | 0.069125 | 0.395 | 0.069125 | 0.0000289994 | Wall Centerline | V1 bk. ruwe vloer | Up to level: V2 ok. ruwe vloer | 2830 | 500 | 0.395 | 790 | Bouwkundig | Model Group:K_Raamwerk_29:5537795
6787432 | 01 eerste verdieping | 500 | 790 | 0.13825 | 0.069125 | 0.395 | 0.069125 | 0.0000289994 | Wall Centerline | V1 bk. ruwe vloer | Up to level: V2 ok. ruwe vloer | 2830 | 500 | 0.395 | 790 | Bouwkundig | Model Group:K_Raamwerk_29:5537799
6787435 | 01 eerste verdieping | 500 | 790 | 0.13825 | 0.069125 | 0.395 | 0.069125 | 0.0000289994 | Wall Centerline | V1 bk. ruwe vloer | Up to level: V2 ok. ruwe vloer | 2830 | 500 | 0.395 | 790 | Bouwkundig | Model Group:K_Raamwerk_29:5537803
6787438 | 01 eerste verdieping | 500 | 790 | 0.13825 | 0.069125 | 0.395 | 0.069125 | 0.0000289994 | Wall Centerline | V1 bk. ruwe vloer | Up to level: V2 ok. ruwe vloer | 2830 | 500 | 0.395 | 790 | Bouwkundig | Model Group:K_Raamwerk_29:5537807
6787441 | 01 eerste verdieping | 500 | 790 | 0.13825 | 0.069125 | 0.395 | 0.069125 | 0.0000289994 | Wall Centerline | V1 bk. ruwe vloer | Up to level: V2 ok. ruwe vloer | 2830 | 500 | 0.395 | 790 | Bouwkundig | Model Group:K_Raamwerk_29:5537811
6787444 | 01 eerste verdieping | 500 | 790 | 0.13825 | 0.069125 | 0.395 | 0.069125 | 0.0000289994 | Wall Centerline | V1 bk. ruwe vloer | Up to level: V2 ok. ruwe vloer | 2830 | 500 | 0.395 | 790 | Bouwkundig | Model Group:K_Raamwerk_29:5537834
6787447 | 01 eerste verdieping | 500 | 790 | 0.13825 | 0.069125 | 0.395 | 0.069125 | 0.0000289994 | Wall Centerline | V1 bk. ruwe vloer | Up to level: V2 ok. ruwe vloer | 2830 | 500 | 0.395 | 790 | Bouwkundig | Model Group:K_Raamwerk_29:5537858
6787450 | 01 eerste verdieping | 500 | 790 | 0.13825 | 0.069125 | 0.395 | 0.069125 | 0.0000289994 | Wall Centerline | V1 bk. ruwe vloer | Up to level: V2 ok. ruwe vloer | 2830 | 500 | 0.395 | 790 | Bouwkundig | Model Group:K_Raamwerk_29:5537866
6787453 | 01 eerste verdieping | 500 | 790 | 0.13825 | 0.069125 | 0.395 | 0.069125 | 0.0000289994 | Wall Centerline | V1 bk. ruwe vloer | Up to level: V2 ok. ruwe vloer | 2830 | 500 | 0.395 | 790 | Bouwkundig | Model Group:K_Raamwerk_29:5537890
6787456 | 01 eerste verdieping | 500 | 790 | 0.13825 | 0.069125 | 0.395 | 0.069125 | 0.0000289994 | Wall Centerline | V1 bk. ruwe vloer | Up to level: V2 ok. ruwe vloer | 2830 | 500 | 0.395 | 790 | Bouwkundig | Model Group:K_Raamwerk_29:5537898
6787459 | 01 eerste verdieping | 500 | 790 | 0.13825 | 0.069125 | 0.395 | 0.069125 | 0.0000289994 | Wall Centerline | V1 bk. ruwe vloer | Up to level: V2 ok. ruwe vloer | 2830 | 500 | 0.395 | 790 | Bouwkundig | Model Group:K_Raamwerk_29:5537922
6787462 | 01 eerste verdieping | 500 | 790 | 0.13825 | 0.069125 | 0.395 | 0.069125 | 0.0000289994 | Wall Centerline | V1 bk. ruwe vloer | Up to level: V2 ok. ruwe vloer | 2830 | 500 | 0.395 | 790 | Bouwkundig | Model Group:K_Raamwerk_29:5537930
6787465 | 01 eerste verdieping | 500 | 790 | 0.13825 | 0.069125 | 0.395 | 0.069125 | 0.0000289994 | Wall Centerline | V1 bk. ruwe vloer | Up to level: V2 ok. ruwe vloer | 2830 | 500 | 0.395 | 790 | Bouwkundig | Model Group:K_Raamwerk_29:5537954
6787610 | 01 eerste verdieping | 500 | 2250 | 0.39375 | 0.196875 | 1.125 | 0.196875 | 0.0000289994 | Wall Centerline | V1 bk. ruwe vloer | Up to level: V2 ok. ruwe vloer | 2830 | 500 | 1.125 | 2250 | Bouwkundig | Model Group:K_Raamwerk_22:5537779
6787707 | 01 eerste verdieping | 500 | 2250 | 0.39375 | 0.196875 | 1.125 | 0.196875 | 0.0000289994 | Wall Centerline | V1 bk. ruwe vloer | Up to level: V2 ok. ruwe vloer | 2830 | 500 | 1.125 | 2250 | Bouwkundig | Model Group:K_Raamwerk_22:5537759
6787710 | 01 eerste verdieping | 500 | 2250 | 0.39375 | 0.196875 | 1.125 | 0.196875 | 0.0000289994 | Wall Centerline | V1 bk. ruwe vloer | Up to level: V2 ok. ruwe vloer | 2830 | 500 | 1.125 | 2250 | Bouwkundig | Model Group:K_Raamwerk_22:5537763
6787713 | 01 eerste verdieping | 500 | 2250 | 0.39375 | 0.196875 | 1.125 | 0.196875 | 0.0000289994 | Wall Centerline | V1 bk. ruwe vloer | Up to level: V2 ok. ruwe vloer | 2830 | 500 | 1.125 | 2250 | Bouwkundig | Model Group:K_Raamwerk_22:5537767
6787716 | 01 eerste verdieping | 500 | 2250 | 0.39375 | 0.196875 | 1.125 | 0.196875 | 0.0000289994 | Wall Centerline | V1 bk. ruwe vloer | Up to level: V2 ok. ruwe vloer | 2830 | 500 | 1.125 | 2250 | Bouwkundig | Model Group:K_Raamwerk_22:5537771
6787719 | 01 eerste verdieping | 500 | 2250 | 0.39375 | 0.196875 | 1.125 | 0.196875 | 0.0000289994 | Wall Centerline | V1 bk. ruwe vloer | Up to level: V2 ok. ruwe vloer | 2830 | 500 | 1.125 | 2250 | Bouwkundig | Model Group:K_Raamwerk_22:5537775
6787722 | 01 eerste verdieping | 500 | 2250 | 0.39375 | 0.196875 | 1.125 | 0.196875 | 0.0000289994 | Wall Centerline | V1 bk. ruwe vloer | Up to level: V2 ok. ruwe vloer | 2830 | 500 | 1.125 | 2250 | Bouwkundig | Model Group:K_Raamwerk_22:5537838
6787725 | 01 eerste verdieping | 500 | 2250 | 0.39375 | 0.196875 | 1.125 | 0.196875 | 0.0000289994 | Wall Centerline | V1 bk. ruwe vloer | Up to level: V2 ok. ruwe vloer | 2830 | 500 | 1.125 | 2250 | Bouwkundig | Model Group:K_Raamwerk_22:5537846
6787728 | 01 eerste verdieping | 500 | 2250 | 0.39375 | 0.196875 | 1.125 | 0.196875 | 0.0000289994 | Wall Centerline | V1 bk. ruwe vloer | Up to level: V2 ok. ruwe vloer | 2830 | 500 | 1.125 | 2250 | Bouwkundig | Model Group:K_Raamwerk_22:5537870
6787731 | 01 eerste verdieping | 500 | 2250 | 0.39375 | 0.196875 | 1.125 | 0.196875 | 0.0000289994 | Wall Centerline | V1 bk. ruwe vloer | Up to level: V2 ok. ruwe vloer | 2830 | 500 | 1.125 | 2250 | Bouwkundig | Model Group:K_Raamwerk_22:5537878
6787734 | 01 eerste verdieping | 500 | 2250 | 0.39375 | 0.196875 | 1.125 | 0.196875 | 0.0000289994 | Wall Centerline | V1 bk. ruwe vloer | Up to level: V2 ok. ruwe vloer | 2830 | 500 | 1.125 | 2250 | Bouwkundig | Model Group:K_Raamwerk_22:5537902
6787737 | 01 eerste verdieping | 500 | 2250 | 0.39375 | 0.196875 | 1.125 | 0.196797 | 0.0000289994 | Wall Centerline | V1 bk. ruwe vloer | Up to level: V2 ok. ruwe vloer | 2830 | 500 | 1.125 | 2250 | Bouwkundig | Model Group:K_Raamwerk_22:5537910
6787740 | 01 eerste verdieping | 500 | 2250 | 0.39375 | 0.196875 | 1.125 | 0.196875 | 0.0000289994 | Wall Centerline | V1 bk. ruwe vloer | Up to level: V2 ok. ruwe vloer | 2830 | 500 | 1.125 | 2250 | Bouwkundig | Model Group:K_Raamwerk_22:5537934
6787743 | 01 eerste verdieping | 500 | 2250 | 0.39375 | 0.196875 | 1.125 | 0.196875 | 0.0000289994 | Wall Centerline | V1 bk. ruwe vloer | Up to level: V2 ok. ruwe vloer | 2830 | 500 | 1.125 | 2250 | Bouwkundig | Model Group:K_Raamwerk_22:5537942
6788138 | 01 eerste verdieping | 500 | 790 | 0.13825 | 0.069125 | 0.395 | 0.069125 | 0.0000289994 | Wall Centerline | V1 bk. ruwe vloer | Up to level: V2 ok. ruwe vloer | 2830 | 500 | 0.395 | 790 | Bouwkundig
6788148 | 01 eerste verdieping | 500 | 790 | 0.13825 | 0.069125 | 0.395 | 0.069125 | 0.0000289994 | Wall Centerline | V1 bk. ruwe vloer | Up to level: V2 ok. ruwe vloer | 2830 | 500 | 0.395 | 790 | Bouwkundig
6788158 | 01 eerste verdieping | 500 | 790 | 0.13825 | 0.069125 | 0.395 | 0.069125 | 0.0000289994 | Wall Centerline | V1 bk. ruwe vloer | Up to level: V2 ok. ruwe vloer | 2830 | 500 | 0.395 | 790 | Bouwkundig
6788168 | 01 eerste verdieping | 500 | 790 | 0.13825 | 0.069125 | 0.395 | 0.069125 | 0.0000289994 | Wall Centerline | V1 bk. ruwe vloer | Up to level: V2 ok. ruwe vloer | 2830 | 500 | 0.395 | 790 | Bouwkundig
6788180 | 01 eerste verdieping | 500 | 790 | 0.13825 | 0.069125 | 0.395 | 0.069125 | 0.0000289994 | Wall Centerline | V1 bk. ruwe vloer | Up to level: V2 ok. ruwe vloer | 2830 | 500 | 0.395 | 790 | Bouwkundig
6788190 | 01 eerste verdieping | 500 | 790 | 0.13825 | 0.069125 | 0.395 | 0.069125 | 0.0000289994 | Wall Centerline | V1 bk. ruwe vloer | Up to level: V2 ok. ruwe vloer | 2830 | 500 | 0.395 | 790 | Bouwkundig
6788202 | 01 eerste verdieping | 500 | 2130 | 0.37275 | 0.186375 | 1.065 | 0.186375 | 0.0000289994 | Wall Centerline | V1 bk. ruwe vloer | Up to level: V2 ok. ruwe vloer | 2830 | 500 | 1.065 | 2130 | Bouwkundig
6789363 | 00 Begane grond | 6890 | 45 | 0.007875 | 0.211006 | 1.20575 | 0.0542588 | 0 | Wall Centerline | 0 | Up to level: V2 ok. ruwe vloer | 0 | 6890 | 0.31005 | 45 | Bouwkundig | Model Group:Kollom tussenmaat 150x150 Trap:6008169
6789364 | 00 Begane grond | 6890 | 45 | 0.007875 | 0.211006 | 1.20575 | 0.0542588 | 0 | Wall Centerline | 0 | Up to level: V2 ok. ruwe vloer | 0 | 6890 | 0.31005 | 45 | Bouwkundig | Model Group:Kollom tussenmaat 150x150 Trap:6008169
6789367 | 00 Begane grond | 6890 | 45 | 0.007875 | 0.211006 | 1.20575 | 0.0542588 | 0 | Wall Centerline | 0 | Up to level: V2 ok. ruwe vloer | 0 | 6890 | 0.31005 | 45 | Bouwkundig | Model Group:Kollom tussenmaat 150x150 Trap:6008522
6789368 | 00 Begane grond | 6890 | 45 | 0.007875 | 0.211006 | 1.20575 | 0.0542588 | 0 | Wall Centerline | 0 | Up to level: V2 ok. ruwe vloer | 0 | 6890 | 0.31005 | 45 | Bouwkundig | Model Group:Kollom tussenmaat 150x150 Trap:6008522
6789371 | 00 Begane grond | 6890 | 45 | 0.007875 | 0.211006 | 1.20575 | 0.0542588 | 0 | Wall Centerline | 0 | Up to level: V2 ok. ruwe vloer | 0 | 6890 | 0.31005 | 45 | Bouwkundig | Model Group:Kollom tussenmaat 150x150 Trap:6008536
6789372 | 00 Begane grond | 6890 | 45 | 0.007875 | 0.211006 | 1.20575 | 0.0542588 | 0 | Wall Centerline | 0 | Up to level: V2 ok. ruwe vloer | 0 | 6890 | 0.31005 | 45 | Bouwkundig | Model Group:Kollom tussenmaat 150x150 Trap:6008536
6789433 | 00 Begane grond | 6890 | 45 | 0.007875 | 0.211006 | 1.20575 | 0.0542588 | 0 | Wall Centerline | 0 | Up to level: V2 ok. ruwe vloer | 0 | 6890 | 0.31005 | 45 | Bouwkundig | Model Group:Kollom tussenmaat 150x150 Trap:6789422
6789434 | 00 Begane grond | 6890 | 45 | 0.007875 | 0.211006 | 1.20575 | 0.0542588 | 0 | Wall Centerline | 0 | Up to level: V2 ok. ruwe vloer | 0 | 6890 | 0.31005 | 45 | Bouwkundig | Model Group:Kollom tussenmaat 150x150 Trap:6789422
6789704 | 00 Begane grond | 6890 | 45 | 0.007875 | 0.211006 | 1.20575 | 0.0542588 | 0 | Wall Centerline | 0 | Up to level: V2 ok. ruwe vloer | 0 | 6890 | 0.31005 | 45 | Bouwkundig | Model Group:Kollom tussenmaat 150x150 Trap:6789695
6789705 | 00 Begane grond | 6890 | 45 | 0.007875 | 0.211006 | 1.20575 | 0.0542588 | 0 | Wall Centerline | 0 | Up to level: V2 ok. ruwe vloer | 0 | 6890 | 0.31005 | 45 | Bouwkundig | Model Group:Kollom tussenmaat 150x150 Trap:6789695
6791078 | 01 eerste verdieping | 2430 | 60 | 0.0105 | 0.0744188 | 0.42525 | 0.025515 | 0 | Wall Centerline | 1 | Up to level: V2 ok. ruwe vloer | 810 | 2430 | 0.1458 | 60 | Bouwkundig
6791079 | 01 eerste verdieping | 3240 | 60 | 0.0105 | 0.099225 | 0.567 | 0.03402 | 0 | Wall Centerline | 1 | Up to level: V2 ok. ruwe vloer | 0 | 3240 | 0.1944 | 60 | Bouwkundig
6792419 | 01 eerste verdieping | 500 | 3450 | 0.60375 | 0.301875 | 1.725 | 0.301875 | 0.0000289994 | Wall Centerline | V1 bk. ruwe vloer | Up to level: V2 ok. ruwe vloer | 2830 | 500 | 1.725 | 3450 | Bouwkundig
6792491 | 01 eerste verdieping | 500 | 1595 | 0.279125 | 0.139563 | 0.7975 | 0.139563 | 0.0000289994 | Wall Centerline | V1 bk. ruwe vloer | Up to level: V2 ok. ruwe vloer | 2830 | 500 | 0.7975 | 1595 | Bouwkundig
6792678 | 01 eerste verdieping | 3230 | 60 | 0.0105 | 0.0989188 | 0.56525 | 0.033915 | 0.0000289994 | Wall Centerline | 1 | Up to level: V2 ok. ruwe vloer | 10 | 3230 | 0.1938 | 60 | Bouwkundig | Model Group:Kollom tussenmaat 120x120 Heel:6004935
6792679 | 01 eerste verdieping | 3230 | 60 | 0.0105 | 0.0989188 | 0.56525 | 0.033915 | 0.0000289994 | Wall Centerline | 1 | Up to level: V2 ok. ruwe vloer | 10 | 3230 | 0.1938 | 60 | Bouwkundig | Model Group:Kollom tussenmaat 120x120 Heel:6004935
6793136 | 01 eerste verdieping | 3230 | 11 | 0.001925 | 0.0989188 | 0.56525 | 0.00621775 | 0.0000289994 | Wall Centerline | 1 | Up to level: V2 ok. ruwe vloer | 10 | 3230 | 0.03553 | 98.5 | Bouwkundig
6892566 | 00 Begane grond | 220 | 1675 | 0.293125 | 0.0644875 | 0.3685 | 0.0644875 | 220 | Wall Centerline | V0 bk. ruwe vloer | Up to level: V1 ok. ruwe vloer | 3310 | 220 | 0.3685 | 1675 | Bouwkundig

# IfcWallStandardCase: Basic Wall:21_DAT_gaas_hekwerk (6)
In: 00 Begane grond
Type - PredefinedType: STANDARD; Material: gaas_hekwerk 16 mm
Type - Other - Category: Walls; Family Name: Basic Wall
Type - Construction - Function: Exterior; Wrapping at Inserts: Do not wrap; Width: 16 mm
Type - Graphics - Coarse Scale Fill Pattern: <Solid fill>; Coarse Scale Fill Color: 4210752
Type - Identity Data - Workset: Wall Types; Assembly Code: 21.12; Assembly Description: buitenwanden; niet constructief, spouwwanden; Description: gaas; Type Comments: gaast.b.v. klimop; Type Name: 21_DAT_gaas_hekwerk
Type - Materials and Finishes - Structural Material: gaas_hekwerk
Type - Analytical Properties - Roughness: 1; Absorptance: 0.1
Type - Pset_ElementShading - Roughness: 304.8 mm
Type - Pset_ProductRequirements - Category: Walls
Type - Pset_ReinforcementBarPitchOfWall - Description: gaas
Type - Pset_WallCommon - IsExternal: yes
Classification: 21.12 Uniformat (Uniformat)
BaseQuantities - Height: 2050 mm; Length: 1880 mm; Width: 16 mm; GrossFootprintArea: 0.03008 m2; GrossVolume: 0.061664 m3; GrossSideArea: 3.854 m2; NetSideArea: 3.854 m2; NetVolume: 0.061664 m3
Pset_QuantityTakeOff - Reference: 21_DAT_gaas_hekwerk; sets with these values: 2
Pset_WallCommon - ExtendToStructure: no; LoadBearing: no; Reference: 21_DAT_gaas_hekwerk
Pset_wanden - Structural Usage: Non-bearing; Omschrijving: gaas; NL-sfb-Codering: 21.12
Pset_DAT_KMS - Assembly Code: 21.12; Assembly Description: buitenwanden; niet constructief, spouwwanden; Description: gaas
Other - Family: Basic Wall; Family and Type: Basic Wall: 21_DAT_gaas_hekwerk; Type: 21_DAT_gaas_hekwerk; Type Id: 6536582
Constraints - Top Offset: 0 mm; Base Extension Distance: 0 mm; Base is Attached: no; Related to Mass: no; Room Bounding: yes; Top Extension Distance: 0 mm; Top is Attached: no; Location Line: Wall Centerline; Base Constraint: 0; Base Offset: 50 mm; Unconnected Height: 2050 mm
Dimensions - Area: 3.854 m2; Length: 1880 mm; Volume: 0.061664 m3
Identity Data - Workset: situatie
Phasing - Phase Created: 2. nieuwbouw
Structural - Structural Usage: Non-bearing; Structural: no
Cross-Section Definition - Cross-Section: Vertical
Name (Basic Wall:21_DAT_gaas_hekwerk:...) | Group
6536579 | Model Group:berging-gaas 2100:6536580
6536591 | Model Group:berging-gaas 2100:6536592
6536593 | Model Group:berging-gaas 2100:6536594
6536595 | Model Group:berging-gaas 2100:6536596
6536597 | Model Group:berging-gaas 2100:6536598
6536599 | Model Group:berging-gaas 2100:6536600

# IfcWallStandardCase: Basic Wall:21_DAT_gasbeton_100 (5)
In: 01 eerste verdieping
Type - PredefinedType: STANDARD; Material: DAT_Gasbeton 100 mm
Type - Other(Type) - Category: Walls; Family Name: Basic Wall
Type - Construction(Type) - Function: Exterior; Wrapping at Inserts: Do not wrap; Width: 100 mm
Type - Graphics(Type) - Coarse Scale Fill Pattern: <Solid fill>; Coarse Scale Fill Color: 0
Type - Identity Data(Type) - Workset: Wall Types; Assembly Code: 21.10; Assembly Description: buitenwanden; niet constructief, algemeen (verzamelniveau); Description: Gasbeton 100 mm; Type Comments: Gasbeton 100 mm; Type Name: 21_DAT_gasbeton_100
Type - Materials and Finishes(Type) - Structural Material: DAT_Gasbeton
Type - Analytical Properties(Type) - Roughness: 1; Absorptance: 0.1
Type - Pset_ElementShading - Roughness: 304.8 mm
Type - Pset_ProductRequirements - Category: Walls
Type - Pset_ReinforcementBarPitchOfWall - Description: Gasbeton 100 mm
Type - Pset_WallCommon - IsExternal: yes
Classification: 21.10 Uniformat (Uniformat)
BaseQuantities - Width: 100 mm
Pset_QuantityTakeOff - Reference: 21_DAT_gasbeton_100; sets with these values: 2
Pset_WallCommon - ExtendToStructure: no; LoadBearing: no; Reference: 21_DAT_gasbeton_100
Pset_wanden - Structural Usage: Non-bearing; Omschrijving: Gasbeton 100 mm; NL-sfb-Codering: 21.10
Pset_DAT_KMS - Assembly Code: 21.10; Assembly Description: buitenwanden; niet constructief, algemeen (verzamelniveau); Description: Gasbeton 100 mm
Other - Category: Walls; Family: Basic Wall; Family and Type: Basic Wall: 21_DAT_gasbeton_100; Type: 21_DAT_gasbeton_100; Type Id: 4279461
Constraints - Base Offset: 0 mm; Top Offset: 0 mm; Base Extension Distance: 0 mm; Base is Attached: no; Related to Mass: no; Room Bounding: yes; Top Extension Distance: 0 mm; Top is Attached: no; Base Constraint: V1 bk. ruwe vloer
Phasing - Phase Created: 2. nieuwbouw
Structural - Structural Usage: Non-bearing; Structural: no
Cross-Section Definition - Cross-Section: Vertical
Name (Basic Wall:21_DAT_gasbeton_100:...) | Height (mm) = Unconnected Height (mm) | BaseQuantities, Length (mm) | GrossFootprintArea (m2) | GrossVolume (m3) | GrossSideArea (m2) = NetSideArea (m2) = Area (m2) | NetVolume (m3) = Volume (m3) | Location Line | Dimensions, Length (mm) | Workset
5536801 | 355 | 6775 | 0.6775 | 0.240512 | 2.40512 | 0.240513 | Wall Centerline | 6862.5 | Constructie
5539205 | 390 | 7000 | 0.7 | 0.273 | 2.73 | 0.273 | Finish Face: Interior | 6950 | Bouwkundig
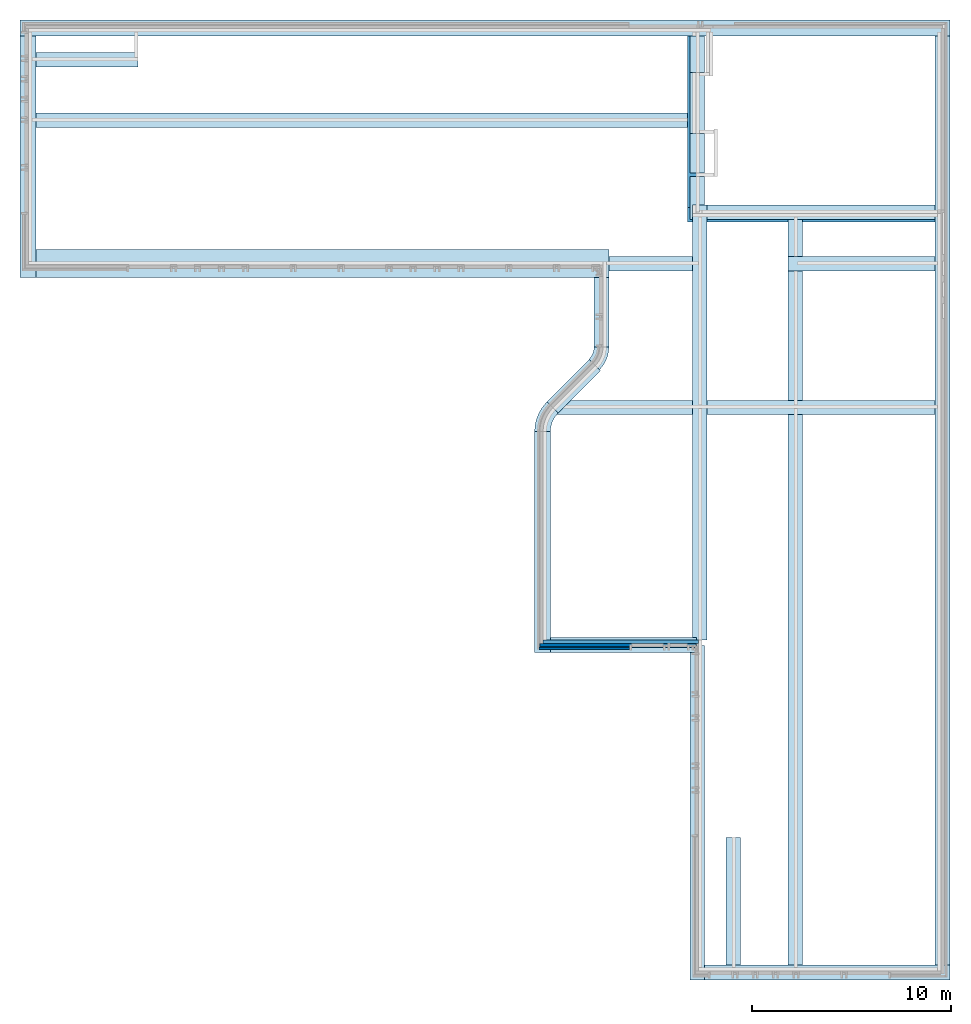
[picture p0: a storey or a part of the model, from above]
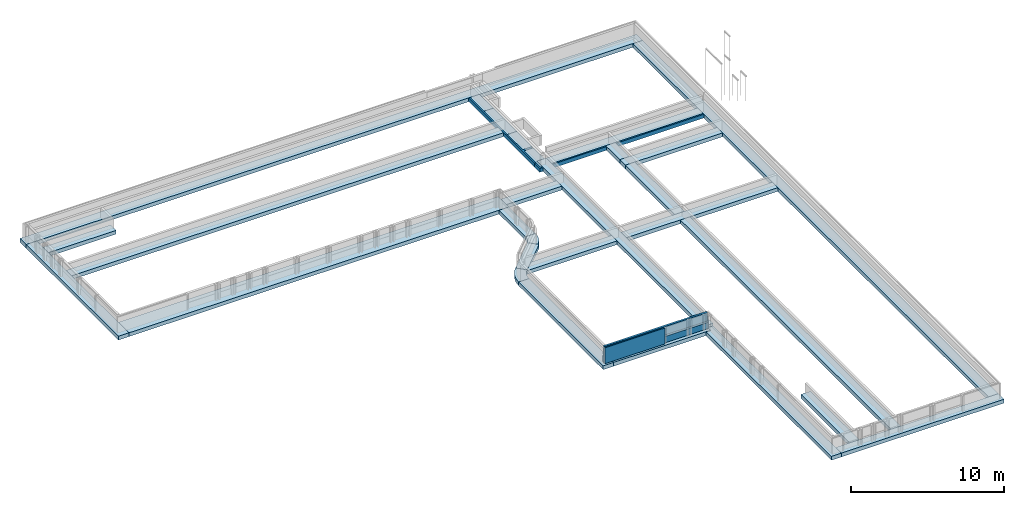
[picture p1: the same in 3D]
Properties of the parts of a building model (IFC2X3), part 30 of 37

# IfcWallStandardCase: Basic Wall:21_DAT_gasbeton_100 (5)
Name (Basic Wall:21_DAT_gasbeton_100:...) | Height (mm) = Unconnected Height (mm) | BaseQuantities, Length (mm) | GrossFootprintArea (m2) | GrossVolume (m3) | GrossSideArea (m2) = NetSideArea (m2) = Area (m2) | NetVolume (m3) = Volume (m3) | Location Line | Dimensions, Length (mm) | Workset
5539206 | 290 | 566 | 0.0566 | 0.016414 | 0.16414 | 0.016414 | Finish Face: Interior | 616 | Bouwkundig
5539207 | 290 | 2134 | 0.2134 | 0.061886 | 0.61886 | 0.061886 | Finish Face: Interior | 2134 | Bouwkundig
5539209 | 515 | 18840 | 1.884 | 0.97026 | 9.7026 | 0.97026 | Finish Face: Interior | 18890 | Bouwkundig

# IfcWallStandardCase: Basic Wall:21_DAT_gevelplint 175 (35)
In: -1 fundering
Type - PredefinedType: STANDARD; Material: ISR_Beton_prefab 15 mm, ISR_Isolatie 175 mm
Type - Other - Category: Walls; Family Name: Basic Wall
Type - Construction - Function: Exterior; Wrapping at Inserts: Do not wrap; Width: 190 mm
Type - Graphics - Coarse Scale Fill Pattern: <Solid fill>; Coarse Scale Fill Color: 4210752
Type - Identity Data - Workset: Wall Types; Assembly Code: 21.10; Assembly Description: buitenwanden; niet constructief, algemeen (verzamelniveau); Description: Isolatie minerale wol 160mm; Type Comments: Kantplank 175mm 4.89 m²K/W met vochtbestendige plaat; Type Name: 21_DAT_gevelplint 175
Type - Materials and Finishes - Structural Material: ISR_Isolatie
Type - Analytical Properties - Roughness: 1; Absorptance: 0.1
Type - Pset_ElementShading - Roughness: 304.8 mm
Type - Pset_ProductRequirements - Category: Walls
Type - Pset_ReinforcementBarPitchOfWall - Description: Isolatie minerale wol 160mm
Type - Pset_WallCommon - IsExternal: yes
Classification: 21.10 Uniformat (Uniformat)
BaseQuantities - Width: 190 mm
Pset_QuantityTakeOff - Reference: 21_DAT_gevelplint 175; sets with these values: 2
Pset_WallCommon - ExtendToStructure: no; LoadBearing: no; Reference: 21_DAT_gevelplint 175
Pset_wanden - Structural Usage: Non-bearing; Omschrijving: Isolatie minerale wol 160mm; NL-sfb-Codering: 21.10
Pset_DAT_KMS - Assembly Code: 21.10; Assembly Description: buitenwanden; niet constructief, algemeen (verzamelniveau); Description: Isolatie minerale wol 160mm
Other - Family: Basic Wall; Family and Type: Basic Wall: 21_DAT_gevelplint 175; Type: 21_DAT_gevelplint 175; Type Id: 5440857
Constraints - Base Extension Distance: 0 mm; Base is Attached: no; Location Line: Finish Face: Interior; Related to Mass: no; Room Bounding: yes; Top Extension Distance: 0 mm; Top is Attached: no; Base Constraint: bk. fundering; Top Constraint: Up to level: 0; Base Offset: 500 mm
Identity Data - Workset: Bouwkundig
Phasing - Phase Created: 2. nieuwbouw
Structural - Structural Usage: Non-bearing; Structural: no
Cross-Section Definition - Cross-Section: Vertical
Name (Basic Wall:21_DAT_gevelplint 175:...) | Height (mm) = Unconnected Height (mm) | BaseQuantities, Length (mm) | GrossFootprintArea (m2) | GrossVolume (m3) = NetVolume (m3) = Volume (m3) | GrossSideArea (m2) = NetSideArea (m2) = Area (m2) | Top Offset (mm) | Dimensions, Length (mm) | Group
5539260 | 730 | 3410 | 0.6479 | 0.472967 | 2.4893 | -40 | 3460
5539306 | 730 | 1090 | 0.2071 | 0.151183 | 0.7957 | -40 | 1190
5539308 | 730 | 2080 | 0.3952 | 0.288496 | 1.5184 | -40 | 2180 | Model Group:K_Raamwerk_03:5538761
5539309 | 730 | 1870 | 0.3553 | 0.259369 | 1.3651 | -40 | 1970
5539311 | 730 | 1090 | 0.2071 | 0.151183 | 0.7957 | -40 | 1190
5539355 | 725 | 880 | 0.1672 | 0.12122 | 0.638 | -45 | 930 | Model Group:K_Raamwerk_01 A:5538614
5539356 | 730 | 880 | 0.1672 | 0.122056 | 0.6424 | -40 | 980 | Model Group:K_Raamwerk_01:5536916
5539357 | 730 | 880 | 0.1672 | 0.122056 | 0.6424 | -40 | 980 | Model Group:K_Raamwerk_01:5536948
5539358 | 730 | 880 | 0.1672 | 0.122056 | 0.6424 | -40 | 980 | Model Group:K_Raamwerk_01:5536975
5539364 | 730 | 2080 | 0.3952 | 0.288496 | 1.5184 | -40 | 2180 | Model Group:K_Raamwerk_02:5538732
5539365 | 730 | 2080 | 0.3952 | 0.288496 | 1.5184 | -40 | 2180 | Model Group:K_Raamwerk_02:5538742
5539366 | 730 | 2080 | 0.3952 | 0.288496 | 1.5184 | -40 | 2180 | Model Group:K_Raamwerk_03:5536855
5539367 | 730 | 2080 | 0.3952 | 0.288496 | 1.5184 | -40 | 2180 | Model Group:K_Raamwerk_03:5536927
5539368 | 730 | 2080 | 0.3952 | 0.288496 | 1.5184 | -40 | 2180 | Model Group:K_Raamwerk_03:5537078
5539369 | 730 | 2080 | 0.3952 | 0.288496 | 1.5184 | -40 | 2180 | Model Group:K_Raamwerk_03:5538779
5539370 | 725 | 1595 | 0.30305 | 0.219711 | 1.15637 | -45 | 1645
5539374 | 730 | 2080 | 0.3952 | 0.288496 | 1.5184 | -40 | 2180 | Model Group:K_Raamwerk_02:5539371
5539375 | 725 | 1242 | 0.23598 | 0.171086 | 0.90045 | -45 | 1292
5539376 | 730 | 2080 | 0.3952 | 0.288496 | 1.5184 | -40 | 2180 | Model Group:K_Raamwerk_03a:5538797
5539377 | 730 | 700 | 0.133 | 0.09709 | 0.511 | -40 | 800 | Model Group:K_Raamwerk_04:5539100
5539378 | 730 | 705 | 0.13395 | 0.0977835 | 0.51465 | -40 | 755 | Model Group:K_Raamwerk_04:5539091
5539379 | 725 | 705 | 0.13395 | 0.0971138 | 0.511125 | -45 | 755 | Model Group:K_Raamwerk_04 A:5539094
5539380 | 730 | 755 | 0.14345 | 0.104719 | 0.55115 | -40 | 805 | Model Group:K_Raamwerk_04:5539097
5539381 | 730 | 700 | 0.133 | 0.09709 | 0.511 | -40 | 800 | Model Group:K_Raamwerk_04:5539103
5539382 | 730 | 700 | 0.133 | 0.09709 | 0.511 | -40 | 800 | Model Group:K_Raamwerk_04:5539106
5539383 | 730 | 2080 | 0.3952 | 0.288496 | 1.5184 | -40 | 2180 | Model Group:K_Raamwerk_02a:5536878
5539384 | 730 | 2080 | 0.3952 | 0.288496 | 1.5184 | -40 | 2180 | Model Group:K_Raamwerk_02a:5536902
5539385 | 730 | 2080 | 0.3952 | 0.288496 | 1.5184 | -40 | 2180 | Model Group:K_Raamwerk_02a:5537101
5665367 | 725 | 1825 | 0.34675 | 0.251394 | 1.32312 | -45 | 1925 | Model Group:K_Raamwerk_21:5536962
5665863 | 725 | 1595 | 0.30305 | 0.219711 | 1.15638 | -45 | 1695 | Model Group:K_Raamwerk_18A:5539193
6239125 | 725 | 880 | 0.1672 | 0.12122 | 0.638 | -45 | 930 | Model Group:K_Raamwerk_01 A:5538632
6239130 | 725 | 880 | 0.1672 | 0.12122 | 0.638 | -45 | 980 | Model Group:K_Raamwerk_01 A:5538692
6239135 | 725 | 880 | 0.1672 | 0.12122 | 0.638 | -45 | 980 | Model Group:K_Raamwerk_01 A:5538702
6239140 | 725 | 880 | 0.1672 | 0.12122 | 0.638 | -45 | 980 | Model Group:K_Raamwerk_01 A:5538712
6239145 | 725 | 880 | 0.1672 | 0.12122 | 0.638 | -45 | 980 | Model Group:K_Raamwerk_01 A:5538722

# IfcWallStandardCase: Basic Wall:21_DAT_hout_bekleding_berging (22)
In: 00 Begane grond
Type - PredefinedType: STANDARD; Material: ISR_Hardhout_gevelbekleding 16 mm
Type - Other - Category: Walls; Family Name: Basic Wall
Type - Construction - Function: Exterior; Wrapping at Inserts: Do not wrap; Width: 16 mm
Type - Graphics - Coarse Scale Fill Pattern: <Solid fill>; Coarse Scale Fill Color: 4210752
Type - Identity Data - Workset: Wall Types; Assembly Code: 21.12; Assembly Description: buitenwanden; niet constructief, spouwwanden; Description: Metselwerk; Type Comments: houten bekleding; Type Name: 21_DAT_hout_bekleding_berging
Type - Materials and Finishes - Structural Material: ISR_Hardhout_gevelbekleding
Type - Analytical Properties - Roughness: 1; Absorptance: 0.1
Type - Pset_ElementShading - Roughness: 304.8 mm
Type - Pset_ProductRequirements - Category: Walls
Type - Pset_ReinforcementBarPitchOfWall - Description: Metselwerk
Type - Pset_WallCommon - IsExternal: yes
Classification: 21.12 Uniformat (Uniformat)
BaseQuantities - Width: 16 mm
Pset_QuantityTakeOff - Reference: 21_DAT_hout_bekleding_berging; sets with these values: 2
Pset_WallCommon - ExtendToStructure: no; LoadBearing: no; Reference: 21_DAT_hout_bekleding_berging
Pset_wanden - Structural Usage: Non-bearing; Omschrijving: Metselwerk; NL-sfb-Codering: 21.12
Pset_DAT_KMS - Assembly Code: 21.12; Assembly Description: buitenwanden; niet constructief, spouwwanden; Description: Metselwerk
Other - Family: Basic Wall; Family and Type: Basic Wall: 21_DAT_hout_bekleding_berging; Type: 21_DAT_hout_bekleding_berging; Type Id: 6485396
Constraints - Top Offset: 0 mm; Base Extension Distance: 0 mm; Base is Attached: no; Related to Mass: no; Room Bounding: yes; Top Extension Distance: 0 mm; Top is Attached: no; Base Constraint: 0
Phasing - Phase Created: 2. nieuwbouw
Structural - Structural Usage: Non-bearing; Structural: no
Cross-Section Definition - Cross-Section: Vertical
Name (Basic Wall:21_DAT_hout_bekleding_berging:...) | Height (mm) = Unconnected Height (mm) | BaseQuantities, Length (mm) | GrossFootprintArea (m2) | GrossVolume (m3) = NetVolume (m3) = Volume (m3) | GrossSideArea (m2) = NetSideArea (m2) = Area (m2) | Base Offset (mm) | Location Line | Dimensions, Length (mm) | Workset | Group
6486274 | 1065 | 1500 | 0.024 | 0.02556 | 1.5975 | 0 | Finish Face: Interior | 1492 | situatie
6486275 | 1056 | 4854 | 0.077664 | 0.0820132 | 5.12582 | 0 | Finish Face: Interior | 4854 | situatie
6486276 | 1065 | 1484 | 0.023744 | 0.0252874 | 1.58046 | 0 | Finish Face: Interior | 1492 | situatie
6496023 | 2050 | 1890 | 0.03024 | 0.061992 | 3.8745 | 50 | Wall Centerline | 1890 | situatie | Model Group:bergingpaneel 1890:6496384
6496412 | 2050 | 1890 | 0.03024 | 0.061992 | 3.8745 | 50 | Wall Centerline | 1890 | situatie | Model Group:bergingpaneel 1890:6496413
6496425 | 2050 | 1890 | 0.03024 | 0.061992 | 3.8745 | 50 | Wall Centerline | 1890 | situatie | Model Group:bergingpaneel 1890:6496426
6496487 | 2050 | 1890 | 0.03024 | 0.061992 | 3.8745 | 50 | Wall Centerline | 1890 | situatie | Model Group:bergingpaneel 1890:6496488
6496523 | 2050 | 1880 | 0.03008 | 0.061664 | 3.854 | 50 | Wall Centerline | 1880 | situatie | Model Group:bergingpaneel 2100:6496585
6496606 | 2050 | 1880 | 0.03008 | 0.061664 | 3.854 | 50 | Wall Centerline | 1880 | situatie | Model Group:bergingpaneel 2100:6496607
6496615 | 2050 | 1880 | 0.03008 | 0.061664 | 3.854 | 50 | Wall Centerline | 1880 | situatie | Model Group:bergingpaneel 2100:6496616
6496624 | 2050 | 1880 | 0.03008 | 0.061664 | 3.854 | 50 | Wall Centerline | 1880 | situatie | Model Group:bergingpaneel 2100:6496625
6496635 | 2050 | 1880 | 0.03008 | 0.061664 | 3.854 | 50 | Wall Centerline | 1880 | situatie | Model Group:bergingpaneel 2100:6496636
6496644 | 2050 | 1880 | 0.03008 | 0.061664 | 3.854 | 50 | Wall Centerline | 1880 | situatie | Model Group:bergingpaneel 2100:6496645
6496653 | 2050 | 1880 | 0.03008 | 0.061664 | 3.854 | 50 | Wall Centerline | 1880 | situatie | Model Group:bergingpaneel 2100:6496654
6496664 | 2050 | 1880 | 0.03008 | 0.061664 | 3.854 | 50 | Wall Centerline | 1880 | situatie | Model Group:bergingpaneel 2100:6496665
6621999 | 2050 | 1890 | 0.03024 | 0.061992 | 3.8745 | 50 | Wall Centerline | 1890 | situatie | Model Group:bergingpaneel 1890:6621998
6622050 | 2050 | 1890 | 0.03024 | 0.061992 | 3.8745 | 50 | Wall Centerline | 1890 | situatie | Model Group:bergingpaneel 1890:6622049
6622059 | 2050 | 1890 | 0.03024 | 0.061992 | 3.8745 | 50 | Wall Centerline | 1890 | situatie | Model Group:bergingpaneel 1890:6622058
6622170 | 2050 | 1890 | 0.03024 | 0.061992 | 3.8745 | 50 | Wall Centerline | 1890 | situatie | Model Group:bergingpaneel 1890:6622169
6765651 | 1065 | 325 | 0.0052 | 0.005538 | 0.346125 | 0 | Finish Face: Interior | 333 | situatie
6766351 | 1065 | 600 | 0.0096 | 0.010224 | 0.639 | 0 | Finish Face: Interior | 600 | Bouwkundig
6766357 | 1065 | 333 | 0.005328 | 0.00567432 | 0.354645 | 0 | Finish Face: Interior | 341 | Bouwkundig

# IfcWallStandardCase: Basic Wall:21_DAT_isolatie hard_74 (84)
Type - PredefinedType: STANDARD; Material: ISR_Isolatie 70 mm
Type - Other(Type) - Category: Walls; Family Name: Basic Wall
Type - Construction(Type) - Function: Exterior; Wrapping at Inserts: Do not wrap; Width: 70 mm
Type - Graphics(Type) - Coarse Scale Fill Pattern: <Solid fill>; Coarse Scale Fill Color: 4210752
Type - Identity Data(Type) - Workset: Wall Types; Assembly Code: 21.10; Assembly Description: buitenwanden; niet constructief, algemeen (verzamelniveau); Description: Hoogwaardige isolatie met een RC van 4.7 m²K/W; Type Comments: Hoogwaarde Isolatie voldoen aan RC 4.7m2K/W; Type Name: 21_DAT_isolatie hard_74
Type - Materials and Finishes(Type) - Structural Material: ISR_Isolatie
Type - Analytical Properties(Type) - Roughness: 1; Absorptance: 0.1
Type - Pset_ElementShading - Roughness: 304.8 mm
Type - Pset_ProductRequirements - Category: Walls
Type - Pset_ReinforcementBarPitchOfWall - Description: Hoogwaardige isolatie met een RC van 4.7 m²K/W
Type - Pset_WallCommon - IsExternal: yes
Classification: 21.10 Uniformat (Uniformat)
BaseQuantities - Width: 70 mm
Pset_QuantityTakeOff - Reference: 21_DAT_isolatie hard_74; sets with these values: 2
Pset_WallCommon - ExtendToStructure: no; LoadBearing: no; Reference: 21_DAT_isolatie hard_74
Pset_wanden - Structural Usage: Non-bearing; Omschrijving: Hoogwaardige isolatie met een RC van 4.7 m²K/W; NL-sfb-Codering: 21.10
Pset_DAT_KMS - Assembly Code: 21.10; Assembly Description: buitenwanden; niet constructief, algemeen (verzamelniveau); Description: Hoogwaardige isolatie met een RC van 4.7 m²K/W
Other - Category: Walls; Family: Basic Wall; Family and Type: Basic Wall: 21_DAT_isolatie hard_74; Type: 21_DAT_isolatie hard_74; Type Id: 5724015
Constraints - Base Extension Distance: 0 mm; Base is Attached: no; Related to Mass: no; Room Bounding: yes; Top Extension Distance: 0 mm; Top is Attached: no
Identity Data - Workset: Bouwkundig
Phasing - Phase Created: 2. nieuwbouw
Structural - Structural Usage: Non-bearing; Structural: no
Cross-Section Definition - Cross-Section: Vertical
Name (Basic Wall:21_DAT_isolatie hard_74:...) | In | Height (mm) = Unconnected Height (mm) | BaseQuantities, Length (mm) | GrossFootprintArea (m2) | GrossVolume (m3) | GrossSideArea (m2) | NetSideArea (m2) = Area (m2) | NetVolume (m3) = Volume (m3) | Location Line | Base Constraint | Base Offset (mm) | Top Offset (mm) | Dimensions, Length (mm) | Group
5664782 | 00 Begane grond | 2762.67 | 23695 | 1.65865 | 4.5823 | 65.4614 | 27.835 | 1.94845 | Finish Face: Interior | 0 | 5 | -882.333 | 23695 | Constraints - Top Constraint: Up to level: 1
5721191 | 00 Begane grond | 990 | 5355 | 0.37485 | 0.371102 | 5.30145 | 5.30145 | 0.371102 | Finish Face: Interior | V0 ok. plafond | 240 | -20 | 5355 | Constraints - Top Constraint: Up to level: 1
5735707 | 00 Begane grond | 2505 | 3705 | 0.25935 | 0.649672 | 9.28102 | 2.54482 | 0.178138 | Finish Face: Interior | 0 | 480 | -665 | 3670 | Constraints - Top Constraint: Up to level: 1
5914862 | 00 Begane grond | 2366.66 | 2280 | 0.1596 | 0.377719 | 5.39599 | 1.45879 | 0.102115 | Finish Face: Interior | 0 | 388.34 | 0 | 2280 | Model Group:Merk K17:5544294
5915708 | 00 Begane grond | 2366.66 | 2280 | 0.1596 | 0.377719 | 5.39599 | 1.45879 | 0.102115 | Finish Face: Interior | 0 | 388.34 | 0 | 2280 | Model Group:Merk K17:5540560
5915712 | 00 Begane grond | 2366.66 | 2280 | 0.1596 | 0.377719 | 5.39599 | 1.45879 | 0.102115 | Finish Face: Interior | 0 | 388.34 | 0 | 2280 | Model Group:Merk K17:5542284
5915714 | 00 Begane grond | 2366.66 | 2280 | 0.1596 | 0.377719 | 5.39599 | 1.45879 | 0.102115 | Finish Face: Interior | 0 | 388.34 | 0 | 2280 | Model Group:Merk K17:5542310
5915716 | 00 Begane grond | 2366.66 | 2280 | 0.1596 | 0.377719 | 5.39599 | 1.45879 | 0.102115 | Finish Face: Interior | 0 | 388.34 | 0 | 2280 | Model Group:Merk K17:5542336
5915718 | 00 Begane grond | 2366.66 | 2280 | 0.1596 | 0.377719 | 5.39599 | 1.45879 | 0.102115 | Finish Face: Interior | 0 | 388.34 | 0 | 2280 | Model Group:Merk K17:5542362
5915720 | 00 Begane grond | 2366.66 | 2280 | 0.1596 | 0.377719 | 5.39599 | 1.45879 | 0.102115 | Finish Face: Interior | 0 | 388.34 | 0 | 2280 | Model Group:Merk K17:5542388
5915722 | 00 Begane grond | 2366.66 | 2280 | 0.1596 | 0.377719 | 5.39599 | 1.45879 | 0.102115 | Finish Face: Interior | 0 | 388.34 | 0 | 2280 | Model Group:Merk K17:5544972
5915724 | 00 Begane grond | 2366.66 | 2280 | 0.1596 | 0.377719 | 5.39599 | 1.45879 | 0.102115 | Finish Face: Interior | 0 | 388.34 | 0 | 2280 | Model Group:Merk K17:5545007
5915726 | 00 Begane grond | 2366.66 | 2280 | 0.1596 | 0.377719 | 5.39599 | 1.45879 | 0.102115 | Finish Face: Interior | 0 | 388.34 | 0 | 2280 | Model Group:Merk K17:5855989
5915728 | 00 Begane grond | 2366.66 | 2280 | 0.1596 | 0.377719 | 5.39599 | 1.45879 | 0.102115 | Finish Face: Interior | 0 | 388.34 | 0 | 2280 | Model Group:Merk K17:5856030
5917464 | 00 Begane grond | 2750 | 120 | 0.0084 | 0.0231 | 0.33 | 0.33 | 0.0231 | Finish Face: Interior | 0 | 0 | 0 | 120
5917756 | 00 Begane grond | 2750 | 280 | 0.0196 | 0.0539 | 0.77 | 0.77 | 0.0539 | Finish Face: Interior | 0 | 0 | 0 | 280
5918139 | 00 Begane grond | 2750 | 120 | 0.0084 | 0.0231 | 0.33 | 0.33 | 0.0231 | Finish Face: Interior | 0 | 0 | 0 | 120
5956460 | 00 Begane grond | 2750 | 1120 | 0.0784 | 0.2156 | 3.08 | 1.3816 | 0.096712 | Finish Face: Interior | 0 | 520 | 0 | 1120 | Model Group:K_Raamwerk_16:5542459
5956464 | 00 Begane grond | 2750 | 1120 | 0.0784 | 0.2156 | 3.08 | 1.3816 | 0.096712 | Finish Face: Interior | 0 | 520 | 0 | 1120 | Model Group:K_Raamwerk_16:5544033
5956466 | 00 Begane grond | 2750 | 1120 | 0.0784 | 0.2156 | 3.08 | 1.3816 | 0.096712 | Finish Face: Interior | 0 | 520 | 0 | 1120 | Model Group:K_Raamwerk_16:5544055
5956468 | 00 Begane grond | 2750 | 1120 | 0.0784 | 0.2156 | 3.08 | 1.3816 | 0.096712 | Finish Face: Interior | 0 | 520 | 0 | 1120 | Model Group:K_Raamwerk_16:5544106
5956470 | 00 Begane grond | 2750 | 1120 | 0.0784 | 0.2156 | 3.08 | 1.3816 | 0.096712 | Finish Face: Interior | 0 | 520 | 0 | 1120 | Model Group:K_Raamwerk_16:5544132
5956472 | 00 Begane grond | 2750 | 1120 | 0.0784 | 0.2156 | 3.08 | 1.3816 | 0.096712 | Finish Face: Interior | 0 | 520 | 0 | 1120 | Model Group:K_Raamwerk_16:5544804
5956474 | 00 Begane grond | 2750 | 1120 | 0.0784 | 0.2156 | 3.08 | 1.3816 | 0.096712 | Finish Face: Interior | 0 | 520 | 0 | 1120 | Model Group:K_Raamwerk_16:5544822
5956476 | 00 Begane grond | 2750 | 1120 | 0.0784 | 0.2156 | 3.08 | 1.3816 | 0.096712 | Finish Face: Interior | 0 | 520 | 0 | 1120 | Model Group:K_Raamwerk_16:5545033
5956478 | 00 Begane grond | 2750 | 1120 | 0.0784 | 0.2156 | 3.08 | 1.3816 | 0.096712 | Finish Face: Interior | 0 | 520 | 0 | 1120 | Model Group:K_Raamwerk_16:5545106
5956480 | 00 Begane grond | 2750 | 1120 | 0.0784 | 0.2156 | 3.08 | 1.3816 | 0.096712 | Finish Face: Interior | 0 | 520 | 0 | 1120 | Model Group:K_Raamwerk_16:5545129
5956482 | 00 Begane grond | 2750 | 1080 | 0.0756 | 0.2079 | 2.97 | 1.2716 | 0.089012 | Finish Face: Interior | 0 | 520 | 0 | 1080
5956484 | 00 Begane grond | 2750 | 1120 | 0.0784 | 0.2156 | 3.08 | 1.3816 | 0.096712 | Finish Face: Interior | 0 | 520 | 0 | 1120 | Model Group:K_Raamwerk_16:5856137
5956486 | 00 Begane grond | 2750 | 1120 | 0.0784 | 0.2156 | 3.08 | 1.3816 | 0.096712 | Finish Face: Interior | 0 | 520 | 0 | 1120 | Model Group:K_Raamwerk_16:5856140
5958055 | 01 eerste verdieping | 3425 | 1550 | 0.1085 | 0.371612 | 5.30875 | 3.0989 | 0.216923 | Finish Face: Interior | 1 | 562.5 | 0 | 1550
5958472 | 01 eerste verdieping | 2350.52 | 35530 | 2.4871 | 5.06627 | 72.3753 | 23.913 | 1.67391 | Finish Face: Interior | 1 | 487.5 | 0 | 35530
5959449 | 01 eerste verdieping | 2937.5 | 1127 | 0.07889 | 0.231739 | 3.31056 | 1.78586 | 0.12501 | Finish Face: Interior | 1 | 562.5 | 0 | 1127
5959957 | 01 eerste verdieping | 2937.5 | 2399.5 | 0.167965 | 0.493397 | 7.04853 | 3.06501 | 0.214551 | Finish Face: Interior | 1 | 562.5 | 0 | 2399.5
6003012 | 00 Begane grond | 2812.67 | 9245 | 0.64715 | 1.82022 | 26.0031 | 8.03001 | 0.562101 | Finish Face: Interior | 0 | -45 | -882.333 | 9245 | Constraints - Top Constraint: Up to level: 1
6007099 | 01 eerste verdieping | 6756.7 | 2295 | 0.16065 | 1.08546 | 15.5066 | 3.40822 | 0.238575 | Finish Face: Interior | 1 | -3256.7 | 0 | 2295
6010342 | 01 eerste verdieping | 5375 | 880 | 0.0616 | 0.3311 | 4.73 | 1.2303 | 0.086121 | Finish Face: Interior | 1 | -1875 | 0 | 880
6010377 | 01 eerste verdieping | 5375 | 190 | 0.0133 | 0.0714875 | 1.02125 | 1.02125 | 0.0714875 | Finish Face: Interior | 1 | -1875 | 0 | 190
6010460 | 01 eerste verdieping | 6000 | 880 | 0.0616 | 0.3696 | 5.28 | 1.28655 | 0.0900585 | Finish Face: Interior | 1 | -2500 | 0 | 880
6010486 | 01 eerste verdieping | 6000 | 190 | 0.0133 | 0.0798 | 1.14 | 1.14 | 0.0798 | Finish Face: Interior | 1 | -2500 | 0 | 190
6010746 | 01 eerste verdieping | 4750 | 190 | 0.0133 | 0.063175 | 0.9025 | 0.9025 | 0.063175 | Finish Face: Interior | 1 | -1250 | 0 | 190
6010799 | 01 eerste verdieping | 4750 | 880 | 0.0616 | 0.2926 | 4.18 | 1.17405 | 0.0821835 | Finish Face: Interior | 1 | -1250 | 0 | 880
6010930 | 01 eerste verdieping | 4125 | 190 | 0.0133 | 0.0548625 | 0.78375 | 0.78375 | 0.0548625 | Finish Face: Interior | 1 | -625 | 0 | 190
6010956 | 01 eerste verdieping | 4125 | 880 | 0.0616 | 0.2541 | 3.63 | 1.1178 | 0.078246 | Finish Face: Interior | 1 | -625 | 0 | 880
6011102 | 01 eerste verdieping | 3500 | 190 | 0.0133 | 0.04655 | 0.665 | 0.665 | 0.04655 | Finish Face: Interior | 1 | 0 | 0 | 190
6011134 | 01 eerste verdieping | 3500 | 880 | 0.0616 | 0.2156 | 3.08 | 1.06155 | 0.0743085 | Finish Face: Interior | 1 | 0 | 0 | 880
6011286 | 01 eerste verdieping | 2937.5 | 190 | 0.0133 | 0.0390687 | 0.558125 | 0.558125 | 0.0390687 | Finish Face: Interior | 1 | 562.5 | 0 | 190
6011315 | 01 eerste verdieping | 2937.5 | 880 | 0.0616 | 0.18095 | 2.585 | 1.0603 | 0.074221 | Finish Face: Interior | 1 | 562.5 | 0 | 880
6011584 | 01 eerste verdieping | 2937.5 | 170 | 0.0119 | 0.0349562 | 0.499375 | 0.499375 | 0.0349562 | Finish Face: Interior | 1 | 562.5 | 0 | 170
6011616 | 01 eerste verdieping | 2937.5 | 915 | 0.06405 | 0.188147 | 2.68781 | 1.16311 | 0.0814179 | Finish Face: Interior | 1 | 562.5 | 0 | 915
6011669 | 01 eerste verdieping | 2937.5 | 160 | 0.0112 | 0.0329 | 0.47 | 0.47 | 0.0329 | Finish Face: Interior | 1 | 562.5 | 0 | 160
6011710 | 01 eerste verdieping | 2937.5 | 25100 | 1.757 | 5.16119 | 73.7312 | 32.6609 | 2.28626 | Finish Face: Interior | 1 | 562.5 | 0 | 25100
6014053 | 00 Begane grond | 2750 | 9095 | 0.63665 | 1.75079 | 25.0112 | 9.66405 | 0.676483 | Finish Face: Interior | 0 | 520 | 0 | 9130
6057862 | 01 eerste verdieping | 2375 | 1120 | 0.0784 | 0.1862 | 2.66 | 0.9616 | 0.067312 | Finish Face: Interior | 1 | 500 | 0 | 1120 | Model Group:K_Raamwerk_28:6057727
6058280 | 01 eerste verdieping | 2375 | 1120 | 0.0784 | 0.1862 | 2.66 | 0.9616 | 0.067312 | Finish Face: Interior | 1 | 500 | 0 | 1120 | Model Group:K_Raamwerk_28:6058262
6058299 | 01 eerste verdieping | 2375 | 1120 | 0.0784 | 0.1862 | 2.66 | 0.9616 | 0.067312 | Finish Face: Interior | 1 | 500 | 0 | 1120 | Model Group:K_Raamwerk_28:6058281
6058318 | 01 eerste verdieping | 2375 | 1120 | 0.0784 | 0.1862 | 2.66 | 0.9616 | 0.067312 | Finish Face: Interior | 1 | 500 | 0 | 1120 | Model Group:K_Raamwerk_28:6058300
6058337 | 01 eerste verdieping | 2375 | 1120 | 0.0784 | 0.1862 | 2.66 | 0.9616 | 0.067312 | Finish Face: Interior | 1 | 500 | 0 | 1120 | Model Group:K_Raamwerk_28:6058319
6058356 | 01 eerste verdieping | 2375 | 1120 | 0.0784 | 0.1862 | 2.66 | 0.9616 | 0.067312 | Finish Face: Interior | 1 | 500 | 0 | 1120 | Model Group:K_Raamwerk_28:6058338
6058375 | 01 eerste verdieping | 2375 | 1120 | 0.0784 | 0.1862 | 2.66 | 0.9616 | 0.067312 | Finish Face: Interior | 1 | 500 | 0 | 1120 | Model Group:K_Raamwerk_28:6058357
6058394 | 01 eerste verdieping | 2375 | 1120 | 0.0784 | 0.1862 | 2.66 | 0.9616 | 0.067312 | Finish Face: Interior | 1 | 500 | 0 | 1120 | Model Group:K_Raamwerk_28:6058376
6058413 | 01 eerste verdieping | 2375 | 1120 | 0.0784 | 0.1862 | 2.66 | 0.9616 | 0.067312 | Finish Face: Interior | 1 | 500 | 0 | 1120 | Model Group:K_Raamwerk_28:6058395
6058432 | 01 eerste verdieping | 2375 | 1120 | 0.0784 | 0.1862 | 2.66 | 0.9616 | 0.067312 | Finish Face: Interior | 1 | 500 | 0 | 1120 | Model Group:K_Raamwerk_28:6058414
6058451 | 01 eerste verdieping | 2375 | 1120 | 0.0784 | 0.1862 | 2.66 | 0.9616 | 0.067312 | Finish Face: Interior | 1 | 500 | 0 | 1120 | Model Group:K_Raamwerk_28:6058433
6058470 | 01 eerste verdieping | 2375 | 1120 | 0.0784 | 0.1862 | 2.66 | 0.9616 | 0.067312 | Finish Face: Interior | 1 | 500 | 0 | 1120 | Model Group:K_Raamwerk_28:6058452
6058489 | 01 eerste verdieping | 2375 | 1120 | 0.0784 | 0.1862 | 2.66 | 0.9616 | 0.067312 | Finish Face: Interior | 1 | 500 | 0 | 1120 | Model Group:K_Raamwerk_28:6058471
6058508 | 01 eerste verdieping | 2375 | 1120 | 0.0784 | 0.1862 | 2.66 | 0.9616 | 0.067312 | Finish Face: Interior | 1 | 500 | 0 | 1120 | Model Group:K_Raamwerk_28:6058490
6058527 | 01 eerste verdieping | 2375 | 1120 | 0.0784 | 0.1862 | 2.66 | 0.9616 | 0.067312 | Finish Face: Interior | 1 | 500 | 0 | 1120 | Model Group:K_Raamwerk_28:6058509
6058546 | 01 eerste verdieping | 2375 | 1120 | 0.0784 | 0.1862 | 2.66 | 0.9616 | 0.067312 | Finish Face: Interior | 1 | 500 | 0 | 1120 | Model Group:K_Raamwerk_28:6058528
6058565 | 01 eerste verdieping | 2375 | 1120 | 0.0784 | 0.1862 | 2.66 | 0.9616 | 0.067312 | Finish Face: Interior | 1 | 500 | 0 | 1120 | Model Group:K_Raamwerk_28:6058547
6058696 | 01 eerste verdieping | 2312.5 | 2290 | 0.1603 | 0.370694 | 5.29563 | 1.35842 | 0.0950897 | Finish Face: Interior | V1 bk. ruwe vloer | 652.5 | 0 | 2290 | Model Group:raamwerk K07:6058698
6059004 | 01 eerste verdieping | 2312.5 | 2290 | 0.1603 | 0.370694 | 5.29563 | 1.35842 | 0.0950897 | Finish Face: Interior | V1 bk. ruwe vloer | 652.5 | 0 | 2290 | Model Group:raamwerk K07:6059006
6059023 | 01 eerste verdieping | 2312.5 | 2290 | 0.1603 | 0.370694 | 5.29563 | 1.35842 | 0.0950897 | Finish Face: Interior | V1 bk. ruwe vloer | 652.5 | 0 | 2290 | Model Group:raamwerk K07:6059025
6059042 | 01 eerste verdieping | 2312.5 | 2290 | 0.1603 | 0.370694 | 5.29563 | 1.35842 | 0.0950897 | Finish Face: Interior | V1 bk. ruwe vloer | 652.5 | 0 | 2290 | Model Group:raamwerk K07:6059044
6059061 | 01 eerste verdieping | 2312.5 | 2290 | 0.1603 | 0.370694 | 5.29563 | 1.35842 | 0.0950897 | Finish Face: Interior | V1 bk. ruwe vloer | 652.5 | 0 | 2290 | Model Group:raamwerk K07:6059063
6059080 | 01 eerste verdieping | 2312.5 | 2290 | 0.1603 | 0.370694 | 5.29563 | 1.35842 | 0.0950897 | Finish Face: Interior | V1 bk. ruwe vloer | 652.5 | 0 | 2290 | Model Group:raamwerk K07:6059082
6059099 | 01 eerste verdieping | 2312.5 | 2290 | 0.1603 | 0.370694 | 5.29563 | 1.35842 | 0.0950897 | Finish Face: Interior | V1 bk. ruwe vloer | 652.5 | 0 | 2290 | Model Group:raamwerk K07:6059101
6059118 | 01 eerste verdieping | 2312.5 | 2290 | 0.1603 | 0.370694 | 5.29563 | 1.35842 | 0.0950897 | Finish Face: Interior | V1 bk. ruwe vloer | 652.5 | 0 | 2290 | Model Group:raamwerk K07:6059120
6059137 | 01 eerste verdieping | 2312.5 | 2290 | 0.1603 | 0.370694 | 5.29563 | 1.35842 | 0.0950897 | Finish Face: Interior | V1 bk. ruwe vloer | 652.5 | 0 | 2290 | Model Group:raamwerk K07:6059139
6059156 | 01 eerste verdieping | 2312.5 | 2290 | 0.1603 | 0.370694 | 5.29563 | 1.35842 | 0.0950897 | Finish Face: Interior | V1 bk. ruwe vloer | 652.5 | 0 | 2290 | Model Group:raamwerk K07:6059158
6059175 | 01 eerste verdieping | 2312.5 | 2290 | 0.1603 | 0.370694 | 5.29563 | 1.35842 | 0.0950897 | Finish Face: Interior | V1 bk. ruwe vloer | 652.5 | 0 | 2290 | Model Group:raamwerk K07:6059177
6059194 | 01 eerste verdieping | 2312.5 | 2290 | 0.1603 | 0.370694 | 5.29563 | 1.35842 | 0.0950897 | Finish Face: Interior | V1 bk. ruwe vloer | 652.5 | 0 | 2290 | Model Group:raamwerk K07:6059196
6059213 | 01 eerste verdieping | 2312.5 | 2290 | 0.1603 | 0.370694 | 5.29563 | 1.35842 | 0.0950897 | Finish Face: Interior | V1 bk. ruwe vloer | 652.5 | 0 | 2290 | Model Group:raamwerk K07:6059215
6382339 | 01 eerste verdieping | 355 | 6862.5 | 0.480375 | 0.170533 | 2.43619 | 2.43619 | 0.170533 | Wall Centerline | V1 bk. ruwe vloer | 0 | 0 | 6862.5

# IfcWallStandardCase: Basic Wall:21_DAT_isolatie hard_85 (4)
In: 00 Begane grond
Type - PredefinedType: STANDARD; Material: ISR_Isolatie 85 mm
Type - Other(Type) - Category: Walls; Family Name: Basic Wall
Type - Construction(Type) - Function: Exterior; Wrapping at Inserts: Do not wrap; Width: 85 mm
Type - Graphics(Type) - Coarse Scale Fill Pattern: <Solid fill>; Coarse Scale Fill Color: 4210752
Type - Identity Data(Type) - Workset: Wall Types; Assembly Code: 21.10; Assembly Description: buitenwanden; niet constructief, algemeen (verzamelniveau); Description: Hoogwaardige isolatie met een RC van 4.7 m²K/W; Type Comments: Isolatie; Type Name: 21_DAT_isolatie hard_85
Type - Materials and Finishes(Type) - Structural Material: ISR_Isolatie
Type - Analytical Properties(Type) - Roughness: 1; Absorptance: 0.1
Type - Pset_ElementShading - Roughness: 304.8 mm
Type - Pset_ProductRequirements - Category: Walls
Type - Pset_ReinforcementBarPitchOfWall - Description: Hoogwaardige isolatie met een RC van 4.7 m²K/W
Type - Pset_WallCommon - IsExternal: yes
Classification: 21.10 Uniformat (Uniformat)
BaseQuantities - Width: 85 mm
Pset_QuantityTakeOff - Reference: 21_DAT_isolatie hard_85; sets with these values: 2
Pset_WallCommon - ExtendToStructure: no; LoadBearing: no; Reference: 21_DAT_isolatie hard_85
Pset_wanden - Structural Usage: Non-bearing; Omschrijving: Hoogwaardige isolatie met een RC van 4.7 m²K/W; NL-sfb-Codering: 21.10
Pset_DAT_KMS - Assembly Code: 21.10; Assembly Description: buitenwanden; niet constructief, algemeen (verzamelniveau); Description: Hoogwaardige isolatie met een RC van 4.7 m²K/W
Other - Category: Walls; Family: Basic Wall; Family and Type: Basic Wall: 21_DAT_isolatie hard_85; Type: 21_DAT_isolatie hard_85; Type Id: 5664636
Constraints - Base Extension Distance: 0 mm; Base is Attached: no; Location Line: Finish Face: Interior; Related to Mass: no; Room Bounding: yes; Top Extension Distance: 0 mm; Top is Attached: no; Base Constraint: 0; Top Constraint: Up to level: 1; Top Offset: -882.333 mm
Identity Data - Workset: Bouwkundig
Phasing - Phase Created: 2. nieuwbouw
Structural - Structural Usage: Non-bearing; Structural: no
Cross-Section Definition - Cross-Section: Vertical
Name (Basic Wall:21_DAT_isolatie hard_85:...) | Height (mm) = Unconnected Height (mm) | BaseQuantities, Length (mm) = Dimensions, Length (mm) | GrossFootprintArea (m2) | GrossVolume (m3) | GrossSideArea (m2) | NetSideArea (m2) = Area (m2) | NetVolume (m3) = Volume (m3) | Base Offset (mm)
5667233 | 2757.67 | 9260 | 0.7871 | 0.947742 | 11.1499 | 5.6167 | 0.47742 | 10
5667384 | 2812.67 | 3345 | 0.284325 | 0.799712 | 9.40837 | 2.68872 | 0.228541 | -45
5667515 | 2812.67 | 9525 | 0.809625 | 2.27721 | 26.7907 | 5.93771 | 0.504705 | -45
5667684 | 2812.67 | 3910 | 0.33235 | 0.93479 | 10.9975 | 2.58153 | 0.21943 | -45

# IfcWallStandardCase: Basic Wall:21_DAT_isolatie minerale wol_160 (49)
Type - PredefinedType: STANDARD; Material: ISR_Isolatie 160 mm
Type - Other - Category: Walls; Family Name: Basic Wall
Type - Construction - Function: Exterior; Wrapping at Inserts: Do not wrap; Width: 160 mm
Type - Graphics - Coarse Scale Fill Pattern: <Solid fill>; Coarse Scale Fill Color: 4210752
Type - Identity Data - Workset: Wall Types; Assembly Code: 21.10; Assembly Description: buitenwanden; niet constructief, algemeen (verzamelniveau); Description: Isolatie minerale wol 160mm met een Rc 4,7 m2K/W; Type Comments: Isolatie minerale wol 160mm met een Rc 4.7 m2K/W; Type Name: 21_DAT_isolatie minerale wol_160
Type - Materials and Finishes - Structural Material: ISR_Isolatie
Type - Analytical Properties - Roughness: 1; Absorptance: 0.1
Type - Pset_ElementShading - Roughness: 304.8 mm
Type - Pset_ProductRequirements - Category: Walls
Type - Pset_ReinforcementBarPitchOfWall - Description: Isolatie minerale wol 160mm met een Rc 4,7 m2K/W
Type - Pset_WallCommon - IsExternal: yes
Classification: 21.10 Uniformat (Uniformat)
BaseQuantities - Width: 160 mm
Pset_QuantityTakeOff - Reference: 21_DAT_isolatie minerale wol_160; sets with these values: 2
Pset_WallCommon - ExtendToStructure: no; LoadBearing: no; Reference: 21_DAT_isolatie minerale wol_160
Pset_wanden - Structural Usage: Non-bearing; Omschrijving: Isolatie minerale wol 160mm met een Rc 4,7 m2K/W; NL-sfb-Codering: 21.10
Pset_DAT_KMS - Assembly Code: 21.10; Assembly Description: buitenwanden; niet constructief, algemeen (verzamelniveau); Description: Isolatie minerale wol 160mm met een Rc 4,7 m2K/W
Other - Family: Basic Wall; Family and Type: Basic Wall: 21_DAT_isolatie minerale wol_160; Type: 21_DAT_isolatie minerale wol_160; Type Id: 589367
Constraints - Base Extension Distance: 0 mm; Base is Attached: no; Related to Mass: no; Room Bounding: yes; Top Extension Distance: 0 mm; Top is Attached: no
Phasing - Phase Created: 2. nieuwbouw
Structural - Structural Usage: Non-bearing; Structural: no
Cross-Section Definition - Cross-Section: Vertical
Name (Basic Wall:21_DAT_isolatie minerale wol_160:...) | In | Height (mm) = Unconnected Height (mm) | BaseQuantities, Length (mm) | GrossFootprintArea (m2) | GrossVolume (m3) | GrossSideArea (m2) | NetSideArea (m2) | NetVolume (m3) = Volume (m3) | Top Offset (mm) | Location Line | Base Constraint | Top Constraint | Base Offset (mm) | Area (m2) | Dimensions, Length (mm) | Workset
5536749 | 00 Begane grond | 3640 | 45945 | 7.3512 | 22.1453 | 138.408 | 109.9 | 17.5587 | 0 | Finish Face: Interior | 0 | Up to level: 1 | 10 | 109.742 | 45865 | Bouwkundig
5536750 | 00 Begane grond | 3650 | 11850 | 1.896 | 2.82647 | 17.6654 | 17.6654 | 2.82647 | 0 | Finish Face: Interior | 0 | Up to level: 1 | 0 | 17.6654 | 12010 | Bouwkundig
5536751 | 00 Begane grond | 3650 | 16590 | 2.6544 | 5.47064 | 34.1915 | 34.1915 | 5.47064 | 0 | Finish Face: Interior | 0 | Up to level: 1 | 0 | 34.1915 | 16430 | Bouwkundig
5536752 | 00 Begane grond | 3650 | 12150 | 1.944 | 7.0956 | 44.3475 | 18.8115 | 3.00984 | 0 | Finish Face: Interior | 0 | Up to level: 1 | 0 | 18.8115 | 12310 | Bouwkundig
5536753 | 00 Begane grond | 3650 | 10774.3 | 1.72388 | 6.29217 | 39.3261 | 22.3741 | 3.57985 | 0 | Finish Face: Interior | 0 | Up to level: 1 | 0 | 22.3741 | 10694.3 | Bouwkundig
5536757 | 01 eerste verdieping | 3590 | 44395 | 7.1032 | 8.23956 | 51.4972 | 46.1772 | 7.38836 | 0 | Finish Face: Interior | 1 | Up to level: V2 bk. ruwe vloer | -90 | 46.1772 | 44235 | Bouwkundig
5536759 | 01 eerste verdieping | 3500 | 12310 | 1.9696 | 6.8936 | 43.085 | 32.4694 | 5.1951 | 0 | Finish Face: Interior | 1 | Up to level: V2 bk. ruwe vloer | 0 | 32.4694 | 12390 | Bouwkundig
5536760 | 01 eerste verdieping | 3590 | 35400 | 5.664 | 20.3338 | 127.086 | 92.6035 | 14.8166 | 0 | Finish Face: Interior | V1 bk. ruwe vloer | Up to level: V2 bk. ruwe vloer | 0 | 92.6035 | 35400 | Bouwkundig
5536761 | 01 eerste verdieping | 3500 | 11850 | 1.896 | 5.9404 | 37.1275 | 26.5362 | 4.2458 | 0 | Finish Face: Interior | 1 | Up to level: V2 bk. ruwe vloer | 0 | 26.5362 | 11842.5 | Bouwkundig
5536762 | 01 eerste verdieping | 3500 | 38543 | 6.16688 | 7.34265 | 45.8916 | 45.8916 | 7.34265 | 0 | Finish Face: Interior | 1 | Up to level: V2 bk. ruwe vloer | 0 | 45.8916 | 38543 | Bouwkundig
5536779 | 00 Begane grond | 3650 | 4113.1 | 0.658095 | 0.673653 | 4.21033 | 4.21033 | 0.673653 | 0 | Finish Face: Interior | 0 | Up to level: 1 | 0 | 4.21033 | 4033.1 | Bouwkundig
5536792 | 01 eerste verdieping | 3500 | 2870 | 0.4592 | 0.547585 | 3.42241 | 3.42241 | 0.547585 | 0 | Finish Face: Interior | 1 | Up to level: V2 bk. ruwe vloer | 0 | 3.42241 | 2950 | Bouwkundig
5536793 | 01 eerste verdieping | 3590 | 7200 | 1.152 | 4.13568 | 25.848 | 23.188 | 3.71008 | 0 | Finish Face: Interior | V1 bk. ruwe vloer | Up to level: V2 bk. ruwe vloer | 0 | 23.188 | 7200 | Bouwkundig
5536798 | 01 eerste verdieping | 440.486 | 3035 | 0.4856 | 0.2139 | 1.33688 | 1.33688 | 0.2139 | 60 | Finish Face: Interior | 1 |  | 184.514 | 1.33688 | 3005 | Bouwkundig
5536799 | 01 eerste verdieping | 621.989 | 6950 | 1.112 | 0.691651 | 4.32282 | 4.32282 | 0.691651 | 60 | Finish Face: Interior | 1 |  | 0 | 4.32282 | 7030 | Bouwkundig
5536973 | 00 Begane grond | 3650 | 7639.96 | 1.22239 | 2.98048 | 18.628 | 18.628 | 2.98048 | 0 | Finish Face: Interior | 0 | Up to level: 1 | 0 | 18.628 | 7799.96 | Bouwkundig
5538606 | 00 Begane grond | 3650 | 1378.37 | 0.220541 | 0.09344 | 0.584 | 5.2604 | 0.805042 | 0 | Finish Face: Interior | 0 | Up to level: 1 | 0 | 5.2604 | 1378.37 | Bouwkundig | Graphics - Center Mark Visible: no
5538609 | 00 Begane grond | 3650 | 977.821 | 0.156451 | 0.09344 | 0.584 | 3.79838 | 0.571044 | 0 | Finish Face: Interior | 0 | Up to level: 1 | 0 | 3.79838 | 977.821 | Bouwkundig | Graphics - Center Mark Visible: no
5538611 | 00 Begane grond | 3645 | 28800 | 4.60801 | 6.32236 | 39.5147 | 39.5147 | 6.32236 | 0 | Finish Face: Interior | 0 | Up to level: 1 | 5 | 39.5147 | 28800 | Bouwkundig
5538836 | 01 eerste verdieping | 3500 | 33600 | 5.376 | 18.816 | 117.6 | 67.2062 | 10.753 | 0 | Finish Face: Interior | 1 | Up to level: V2 bk. ruwe vloer | 0 | 67.2062 | 33600 | Bouwkundig
5539124 | 01 eerste verdieping | 425 | 3813.1 | 0.610095 | 0.259291 | 1.62057 | 1.62057 | 0.259291 | 0 | Finish Face: Interior | 1 |  | -0.0000245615 | 1.62057 | 3863.1 | Bouwkundig
5539125 | 01 eerste verdieping | 425 | 977.821 | 0.156451 | 0.01088 | 0.068 | 0.442277 | 0.0664914 | 0 | Finish Face: Interior | 1 |  | -0.0000245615 | 0.442277 | 977.821 | Bouwkundig | Graphics - Center Mark Visible: no
5539126 | 01 eerste verdieping | 425 | 3000 | 0.48 | 0.204 | 1.275 | 1.275 | 0.204 | 0 | Finish Face: Interior | 1 |  | -0.0000245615 | 1.275 | 3000 | Bouwkundig
5539127 | 01 eerste verdieping | 425 | 1378.37 | 0.220541 | 0.01088 | 0.068 | 0.612512 | 0.0937378 | 0 | Finish Face: Interior | 1 |  | -0.0000245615 | 0.612512 | 1378.37 | Bouwkundig | Graphics - Center Mark Visible: no
5539128 | 01 eerste verdieping | 425 | 10774.3 | 1.72388 | 0.73265 | 4.57906 | 4.57906 | 0.73265 | 0 | Finish Face: Interior | 1 |  | -0.0000245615 | 4.57906 | 10694.3 | Bouwkundig
5539129 | 01 eerste verdieping | 425 | 7499.96 | 1.19999 | 0.509997 | 3.18748 | 3.18748 | 0.509997 | 0 | Finish Face: Interior | 1 |  | -0.0000245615 | 3.18748 | 7629.96 | Bouwkundig
5539137 | 00 Begane grond | 3650 | 3000 | 0.48 | 1.752 | 10.95 | 4.9 | 0.784 | 0 | Finish Face: Interior | 0 | Up to level: 1 | 0 | 4.9 | 3000 | Bouwkundig
5539165 | 02 tweede verdieping | 550 | 11875 | 1.9 | 1.045 | 6.53125 | 6.53125 | 1.045 | 60 | Finish Face: Interior | V2 bk. ruwe vloer |  | 0 | 6.53125 | 11795 | Bouwkundig
5539166 | 02 tweede verdieping | 502.871 | 35200 | 5.632 | 2.83217 | 17.7011 | 17.7011 | 2.83217 | 60 | Finish Face: Interior | V2 bk. ruwe vloer |  | 0 | 17.7011 | 35250 | Bouwkundig
5539167 | 02 tweede verdieping | 550 | 44235 | 7.0776 | 3.89268 | 24.3292 | 24.3292 | 3.89268 | 60 | Finish Face: Interior | V2 bk. ruwe vloer |  | 0 | 24.3292 | 44235 | Bouwkundig
5539168 | 02 tweede verdieping | 550 | 12310 | 1.9696 | 1.08328 | 6.7705 | 6.7705 | 1.08328 | 60 | Finish Face: Interior | V2 bk. ruwe vloer |  | 0 | 6.7705 | 12310 | Bouwkundig
5539169 | 02 tweede verdieping | 520 | 35400 | 5.664 | 2.94528 | 18.408 | 18.408 | 2.94528 | 60 | Finish Face: Interior | V2 bk. ruwe vloer |  | 0 | 18.408 | 35400 | Bouwkundig
5539170 | 02 tweede verdieping | 550 | 33440 | 5.3504 | 2.94272 | 18.392 | 18.392 | 2.94272 | 60 | Finish Face: Interior | V2 bk. ruwe vloer |  | 0 | 18.392 | 33600 | Bouwkundig
5539171 | 02 tweede verdieping | 550 | 7060 | 1.1296 | 0.62128 | 3.883 | 3.883 | 0.62128 | 60 | Finish Face: Interior | V2 bk. ruwe vloer |  | 0 | 3.883 | 7030 | Bouwkundig
5539313 | -1 fundering | 680 | 34470 | 5.5152 | 3.40661 | 21.2913 | 21.2913 | 3.40661 | 10 | Finish Face: Exterior | bk. fundering | Up to level: 0 | 600 | 21.2913 | 34390 | Bouwkundig
5539314 | -1 fundering | 1070 | 9100 | 1.456 | 1.55792 | 9.737 | 9.737 | 1.55792 | 0 | Finish Face: Exterior | bk. fundering | Up to level: 0 | 200 | 9.737 | 9180 | Bouwkundig
5539315 | -1 fundering | 670 | 12310 | 1.9696 | 0.788416 | 4.9276 | 4.9276 | 0.788416 | 0 | Finish Face: Exterior | bk. fundering | Up to level: 0 | 600 | 4.9276 | 12310 | Bouwkundig
5539316 | -1 fundering | 670 | 16430 | 2.6288 | 1.7613 | 11.0081 | 11.0081 | 1.7613 | 0 | Finish Face: Exterior | bk. fundering | Up to level: 0 | 600 | 11.0081 | 16430 | Bouwkundig
5539317 | -1 fundering | 670 | 7799.96 | 1.24799 | 0.836156 | 5.22598 | 5.22598 | 0.836156 | 0 | Finish Face: Exterior | bk. fundering | Up to level: 0 | 600 | 5.22598 | 7799.96 | Bouwkundig
5539318 | -1 fundering | 670 | 10614.3 | 1.69828 | 1.13785 | 7.11156 | 7.11156 | 1.13785 | 0 | Finish Face: Exterior | bk. fundering | Up to level: 0 | 600 | 7.11156 | 10694.3 | Bouwkundig
5539319 | -1 fundering | 670 | 1378.37 | 0.220541 | 0.017152 | 0.1072 | 0.965608 | 0.147775 | 0 | Finish Face: Exterior | bk. fundering | Up to level: 0 | 600 | 0.965608 | 1378.37 | Bouwkundig | Graphics - Center Mark Visible: no
5539320 | -1 fundering | 670 | 3000 | 0.48 | 0.3216 | 2.01 | 2.01 | 0.3216 | 0 | Finish Face: Exterior | bk. fundering | Up to level: 0 | 600 | 2.01 | 3000 | Bouwkundig
5539321 | -1 fundering | 670 | 977.821 | 0.156451 | 0.017152 | 0.1072 | 0.697237 | 0.104822 | 0 | Finish Face: Exterior | bk. fundering | Up to level: 0 | 600 | 0.697237 | 977.821 | Bouwkundig | Graphics - Center Mark Visible: no
5539323 | -1 fundering | 625 | 28800 | 4.60801 | 1.3845 | 8.65315 | 8.65315 | 1.3845 | -45 | Finish Face: Exterior | bk. fundering | Up to level: 0 | 600 | 8.65315 | 28800 | Bouwkundig
5539324 | -1 fundering | 670 | 11850 | 1.896 | 1.16045 | 7.2528 | 7.2528 | 1.16045 | 0 | Finish Face: Exterior | bk. fundering | Up to level: 0 | 600 | 7.2528 | 12010 | Bouwkundig
6492230 | -1 fundering | 788 | 12280 | 1.96479 | 1.54826 | 9.67661 | 9.67661 | 1.54826 | -152 | Finish Face: Exterior | bk. fundering | Up to level: V0 ok. ruwe vloer | 0 | 9.67661 | 12287.5 | situatie
6516622 | -1 fundering | 670 | 38310 | 6.1296 | 4.10683 | 25.6677 | 25.6677 | 4.10683 | 0 | Finish Face: Exterior | bk. fundering | Up to level: 0 | 600 | 25.6677 | 38230 | Bouwkundig
6516623 | -1 fundering | 1080 | 11520 | 1.8432 | 1.99066 | 12.4416 | 12.4416 | 1.99066 | 10 | Finish Face: Exterior | bk. fundering | Up to level: 0 | 200 | 12.4416 | 11520 | Bouwkundig
6562865 | -1 fundering | 788 | 9105 | 1.4568 | 1.14796 | 7.17474 | 7.17474 | 1.14796 | -152 | Finish Face: Exterior | bk. fundering | Up to level: V0 ok. ruwe vloer | 0 | 7.17474 | 9272.5 | Bouwkundig

# IfcWallStandardCase: Basic Wall:21_DAT_metselwerk_100 (534)
Type - PredefinedType: STANDARD; Material: ISR_Metselwerk 100 mm
Type - Other - Category: Walls; Family Name: Basic Wall
Type - Construction - Function: Exterior; Width: 100 mm; Wrapping at Ends: Exterior; Wrapping at Inserts: Both
Type - Graphics - Coarse Scale Fill Color: 4210752; Coarse Scale Fill Pattern: <Solid fill>
Type - Identity Data - Assembly Code: 21.12; Assembly Description: buitenwanden; niet constructief, spouwwanden; Description: Metselwerk; Type Comments: Metselwerk 100mm; Type Name: 21_DAT_metselwerk_100; Workset: Wall Types
Type - Materials and Finishes - Structural Material: ISR_Metselwerk
Type - Analytical Properties - Absorptance: 0.1; Roughness: 1
Type - Pset_ElementShading - Roughness: 304.8 mm
Type - Pset_ProductRequirements - Category: Walls
Type - Pset_ReinforcementBarPitchOfWall - Description: Metselwerk
Type - Pset_WallCommon - IsExternal: yes
Classification: 21.12 Uniformat (Uniformat)
BaseQuantities - Width: 100 mm
Pset_QuantityTakeOff - Reference: 21_DAT_metselwerk_100; sets with these values: 2
Pset_WallCommon - Reference: 21_DAT_metselwerk_100; ExtendToStructure: no; LoadBearing: no
Pset_wanden - Omschrijving: Metselwerk; NL-sfb-Codering: 21.12; Structural Usage: Non-bearing
Pset_DAT_KMS - Assembly Code: 21.12; Assembly Description: buitenwanden; niet constructief, spouwwanden; Description: Metselwerk
Other - Family: Basic Wall; Family and Type: Basic Wall: 21_DAT_metselwerk_100; Type: 21_DAT_metselwerk_100; Type Id: 589363
Constraints - Base Extension Distance: 0 mm; Base is Attached: no; Related to Mass: no; Room Bounding: yes; Top Extension Distance: 0 mm; Top is Attached: no
Phasing - Phase Created: 2. nieuwbouw
Structural - Structural Usage: Non-bearing; Structural: no
Cross-Section Definition - Cross-Section: Vertical
Name (Basic Wall:21_DAT_metselwerk_100:...) | In | Height (mm) = Unconnected Height (mm) | BaseQuantities, Length (mm) | GrossFootprintArea (m2) | GrossVolume (m3) | GrossSideArea (m2) | NetSideArea (m2) | NetVolume (m3) = Volume (m3) | Top Offset (mm) | Base Constraint | Base Offset (mm) | Location Line | Area (m2) | Dimensions, Length (mm) | Workset | Group
4746785 | 01 eerste verdieping | 2350 | 3980 | 0.398 | 0.9353 | 9.353 | 9.353 | 0.9353 | 0 | 2 | 200 | Finish Face: Interior | 9.353 | 3930 | Bouwkundig | Constraints - Top Constraint: Up to level: 3
4747080 | 01 eerste verdieping | 2550 | 3360 | 0.336 | 0.8568 | 8.568 | 8.568 | 0.8568 | 0 | 2 | 0 | Finish Face: Interior | 8.568 | 3360 | Bouwkundig | Constraints - Top Constraint: Up to level: 3
5042636 | 01 eerste verdieping | 2350 | 3360 | 0.336 | 0.7896 | 7.896 | 7.896 | 0.7896 | 0 | 2 | 200 | Finish Face: Interior | 7.896 | 3360 | Bouwkundig | Constraints - Top Constraint: Up to level: 3
5042761 | 01 eerste verdieping | 2350 | 3880 | 0.388 | 0.9118 | 9.118 | 9.118 | 0.911768 | 0 | 2 | 200 | Finish Face: Interior | 9.118 | 3930 | Bouwkundig | Constraints - Top Constraint: Up to level: 3
5083732 | 01 eerste verdieping | 2550 | 200 | 0.02 | 0.051 | 0.51 | 0.51 | 0.051 | 0 | 2 | 0 | Finish Face: Interior | 0.51 | 250 | Bouwkundig | Constraints - Top Constraint: Up to level: 3
5536756 | 00 Begane grond | 3650 | 765 | 0.0765 | 0.279225 | 2.79225 | 2.79225 | 0.279225 | 0 | 0 | 0 | Finish Face: Interior | 2.79225 | 715 | Bouwkundig | Constraints - Top Constraint: Up to level: 1
5536763 | 01 eerste verdieping | 625 | 30305 | 3.0305 | 1.89406 | 18.9406 | 18.9406 | 1.89406 | 0 | 1 | 0 | Finish Face: Interior | 18.9406 | 30305 | Bouwkundig
5536764 | 01 eerste verdieping | 3500 | 10640 | 1.064 | 3.724 | 37.24 | 28.74 | 2.874 | 0 | 1 | 0 | Finish Face: Interior | 28.74 | 10740 | Bouwkundig | Constraints - Top Constraint: Up to level: V2 bk. ruwe vloer
5536765 | 01 eerste verdieping | 3500 | 12650 | 1.265 | 0.425 | 4.25 | 36.455 | 3.6455 | 0 | 1 | 0 | Finish Face: Interior | 36.455 | 12650 | Bouwkundig | Constraints - Top Constraint: Up to level: V2 bk. ruwe vloer
5536766 | 01 eerste verdieping | 3500 | 35400 | 3.54 | 0.425 | 4.25 | 89.968 | 8.9968 | 0 | 1 | 0 | Finish Face: Interior | 89.968 | 35400 | Bouwkundig | Constraints - Top Constraint: Up to level: V2 bk. ruwe vloer
5536768 | 02 tweede verdieping | 550 | 10740 | 1.074 | 0.5907 | 5.907 | 5.907 | 0.5907 | 0 | V2 bk. ruwe vloer | 0 | Finish Face: Interior | 5.907 | 10740 | Bouwkundig
5536769 | 02 tweede verdieping | 550 | 33600 | 3.36 | 1.848 | 18.48 | 18.48 | 1.848 | 0 | V2 bk. ruwe vloer | 0 | Finish Face: Interior | 18.48 | 33600 | Bouwkundig
5536770 | 02 tweede verdieping | 550 | 12750 | 1.275 | 0.70125 | 7.0125 | 7.0125 | 0.70125 | 0 | V2 bk. ruwe vloer | 0 | Finish Face: Interior | 7.0125 | 12650 | Bouwkundig
5536771 | 02 tweede verdieping | 550 | 35300 | 3.53 | 1.9415 | 19.415 | 19.415 | 1.9415 | 0 | V2 bk. ruwe vloer | 0 | Finish Face: Interior | 19.415 | 35400 | Bouwkundig
5536777 | 00 Begane grond | 3650 | 10815.4 | 1.08154 | 3.94761 | 39.4761 | 27.4061 | 2.74061 | 0 | 0 | 0 | Finish Face: Interior | 27.4061 | 10865.4 | Bouwkundig | Constraints - Top Constraint: Up to level: 1
5536780 | 00 Begane grond | 825 | 3914.29 | 0.391429 | 0.322929 | 3.22929 | 3.22929 | 0.322929 | 0 | 0 | 2825 | Finish Face: Interior | 3.22929 | 3864.29 | Bouwkundig | Constraints - Top Constraint: Up to level: 1
5536782 | 00 Begane grond | 3650 | 450 | 0.045 | 0.16425 | 1.6425 | 1.6425 | 0.16425 | 0 | 0 | 0 | Finish Face: Interior | 1.6425 | 450 | Bouwkundig | Constraints - Top Constraint: Up to level: 1
5536784 | 00 Begane grond | 3650 | 6625 | 0.6625 | 2.41483 | 24.1483 | 24.1483 | 2.41483 | 0 | 0 | 0 | Finish Face: Interior | 24.1483 | 6725 | Bouwkundig | Constraints - Top Constraint: Up to level: 1
5536794 | 01 eerste verdieping | 3200 | 7150 | 0.715 | 2.288 | 22.88 | 21.095 | 2.1095 | 0 | 1 | 300 | Finish Face: Interior | 21.095 | 7200 | Bouwkundig | Constraints - Top Constraint: Up to level: V2 bk. ruwe vloer
5536795 | 01 eerste verdieping | 3300 | 516 | 0.0516 | 0.17028 | 1.7028 | 1.7028 | 0.17028 | 0 | 1 | 200 | Finish Face: Interior | 1.7028 | 616 | Bouwkundig | Constraints - Top Constraint: Up to level: V2 bk. ruwe vloer
5536797 | 01 eerste verdieping | 625 | 8457 | 0.8457 | 0.528562 | 5.28562 | 5.28562 | 0.528562 | 0 | 1 | 0 | Finish Face: Interior | 5.28562 | 8507 | Bouwkundig
5536802 | 02 tweede verdieping | 550 | 7100 | 0.71 | 0.3905 | 3.905 | 3.905 | 0.3905 | 0 | V2 bk. ruwe vloer | 0 | Finish Face: Interior | 3.905 | 7200 | Bouwkundig
5536804 | 00 Begane grond | 2650 | 265 | 0.0265 | 0.070225 | 0.70225 | 0.70225 | 0.070225 | 0 | 0 | 0 | Finish Face: Interior | 0.70225 | 215 | Bouwkundig | Model Group:Penant Dubbel:5536807
5536805 | 00 Begane grond | 2650 | 120 | 0.012 | 0.0318 | 0.318 | 0.318 | 0.0318 | 0 | 0 | 0 | Finish Face: Interior | 0.318 | 220 | Bouwkundig | Model Group:Penant Dubbel:5536807
5536806 | 00 Begane grond | 2650 | 265 | 0.0265 | 0.070225 | 0.70225 | 0.70225 | 0.070225 | 0 | 0 | 0 | Finish Face: Interior | 0.70225 | 215 | Bouwkundig | Model Group:Penant Dubbel:5536807
5536808 | 00 Begane grond | 2200 | 265 | 0.0265 | 0.0583 | 0.583 | 0.583 | 0.0583 | 0 | 0 | 700 | Finish Face: Interior | 0.583 | 215 | Bouwkundig | Model Group:Penant Dubbel P+450:5536811
5536809 | 00 Begane grond | 2200 | 120 | 0.012 | 0.0264 | 0.264 | 0.264 | 0.0264 | 0 | 0 | 700 | Finish Face: Interior | 0.264 | 220 | Bouwkundig | Model Group:Penant Dubbel P+450:5536811
5536810 | 00 Begane grond | 2200 | 265 | 0.0265 | 0.0583 | 0.583 | 0.583 | 0.0583 | 0 | 0 | 700 | Finish Face: Interior | 0.583 | 215 | Bouwkundig | Model Group:Penant Dubbel P+450:5536811
5536813 | 00 Begane grond | 825 | 23565 | 2.3565 | 1.94412 | 19.4412 | 19.4412 | 1.94412 | 0 | 0 | 2825 | Finish Face: Interior | 19.4412 | 23615 | Bouwkundig | Constraints - Top Constraint: Up to level: 1
5536814 | 00 Begane grond | 2650 | 265 | 0.0265 | 0.070225 | 0.70225 | 0.70225 | 0.070225 | 0 | 0 | 0 | Finish Face: Interior | 0.70225 | 215 | Bouwkundig | Model Group:Penant Dubbel:5536817
5536815 | 00 Begane grond | 2650 | 120 | 0.012 | 0.0318 | 0.318 | 0.318 | 0.0318 | 0 | 0 | 0 | Finish Face: Interior | 0.318 | 220 | Bouwkundig | Model Group:Penant Dubbel:5536817
5536816 | 00 Begane grond | 2650 | 265 | 0.0265 | 0.070225 | 0.70225 | 0.70225 | 0.070225 | 0 | 0 | 0 | Finish Face: Interior | 0.70225 | 215 | Bouwkundig | Model Group:Penant Dubbel:5536817
5536818 | 00 Begane grond | 2650 | 265 | 0.0265 | 0.070225 | 0.70225 | 0.70225 | 0.070225 | 0 | 0 | 0 | Finish Face: Interior | 0.70225 | 215 | Bouwkundig | Model Group:Penant Dubbel:5536821
5536819 | 00 Begane grond | 2650 | 120 | 0.012 | 0.0318 | 0.318 | 0.318 | 0.0318 | 0 | 0 | 0 | Finish Face: Interior | 0.318 | 220 | Bouwkundig | Model Group:Penant Dubbel:5536821
5536820 | 00 Begane grond | 2650 | 265 | 0.0265 | 0.070225 | 0.70225 | 0.70225 | 0.070225 | 0 | 0 | 0 | Finish Face: Interior | 0.70225 | 215 | Bouwkundig | Model Group:Penant Dubbel:5536821
5536822 | 00 Begane grond | 2650 | 265 | 0.0265 | 0.070225 | 0.70225 | 0.70225 | 0.070225 | 0 | 0 | 0 | Finish Face: Interior | 0.70225 | 215 | Bouwkundig | Model Group:Penant Dubbel:5536825
5536823 | 00 Begane grond | 2650 | 120 | 0.012 | 0.0318 | 0.318 | 0.318 | 0.0318 | 0 | 0 | 0 | Finish Face: Interior | 0.318 | 220 | Bouwkundig | Model Group:Penant Dubbel:5536825
5536824 | 00 Begane grond | 2650 | 265 | 0.0265 | 0.070225 | 0.70225 | 0.70225 | 0.070225 | 0 | 0 | 0 | Finish Face: Interior | 0.70225 | 215 | Bouwkundig | Model Group:Penant Dubbel:5536825
5536826 | 00 Begane grond | 2650 | 265 | 0.0265 | 0.070225 | 0.70225 | 0.70225 | 0.070225 | 0 | 0 | 0 | Finish Face: Interior | 0.70225 | 215 | Bouwkundig | Model Group:Penant Dubbel:5536829
5536827 | 00 Begane grond | 2650 | 120 | 0.012 | 0.0318 | 0.318 | 0.318 | 0.0318 | 0 | 0 | 0 | Finish Face: Interior | 0.318 | 220 | Bouwkundig | Model Group:Penant Dubbel:5536829
5536828 | 00 Begane grond | 2650 | 265 | 0.0265 | 0.070225 | 0.70225 | 0.70225 | 0.070225 | 0 | 0 | 0 | Finish Face: Interior | 0.70225 | 215 | Bouwkundig | Model Group:Penant Dubbel:5536829
5536872 | 00 Begane grond | 2650 | 265 | 0.0265 | 0.070225 | 0.70225 | 0.70225 | 0.070225 | 0 | 0 | 0 | Finish Face: Interior | 0.70225 | 215 | Bouwkundig | Model Group:Penant Dubbel:5536875
5536873 | 00 Begane grond | 2650 | 120 | 0.012 | 0.0318 | 0.318 | 0.318 | 0.0318 | 0 | 0 | 0 | Finish Face: Interior | 0.318 | 220 | Bouwkundig | Model Group:Penant Dubbel:5536875
5536874 | 00 Begane grond | 2650 | 265 | 0.0265 | 0.070225 | 0.70225 | 0.70225 | 0.070225 | 0 | 0 | 0 | Finish Face: Interior | 0.70225 | 215 | Bouwkundig | Model Group:Penant Dubbel:5536875
5536876 | 00 Begane grond | 2650 | 265 | 0.0265 | 0.070225 | 0.70225 | 0.70225 | 0.070225 | 0 | 0 | 0 | Finish Face: Interior | 0.70225 | 265 | Bouwkundig | Model Group:Penant Enkel:5536877
5536887 | 00 Begane grond | 825 | 9150 | 0.915 | 0.754875 | 7.54875 | 7.54875 | 0.754875 | 0 | 0 | 2825 | Finish Face: Interior | 7.54875 | 9150 | Bouwkundig | Constraints - Top Constraint: Up to level: 1
5536888 | 00 Begane grond | 3650 | 2835 | 0.2835 | 1.03478 | 10.3478 | 10.3478 | 1.03478 | 0 | 0 | 0 | Finish Face: Interior | 10.3478 | 2785 | Bouwkundig | Constraints - Top Constraint: Up to level: 1
5536899 | 00 Begane grond | 2650 | 265 | 0.0265 | 0.070225 | 0.70225 | 0.70225 | 0.070225 | 0 | 0 | 0 | Finish Face: Interior | 0.70225 | 265 | Bouwkundig | Model Group:Penant Enkel:5536898
5536901 | 00 Begane grond | 825 | 9483 | 0.9483 | 0.782348 | 7.82348 | 7.82348 | 0.782348 | 0 | 0 | 2825 | Finish Face: Interior | 7.82348 | 9433 | Bouwkundig | Constraints - Top Constraint: Up to level: 1
5536912 | 00 Begane grond | 2650 | 265 | 0.0265 | 0.070225 | 0.70225 | 0.70225 | 0.070225 | 0 | 0 | 0 | Finish Face: Interior | 0.70225 | 215 | Bouwkundig | Model Group:Penant Dubbel:5536915
5536913 | 00 Begane grond | 2650 | 120 | 0.012 | 0.0318 | 0.318 | 0.318 | 0.0318 | 0 | 0 | 0 | Finish Face: Interior | 0.318 | 220 | Bouwkundig | Model Group:Penant Dubbel:5536915
5536914 | 00 Begane grond | 2650 | 265 | 0.0265 | 0.070225 | 0.70225 | 0.70225 | 0.070225 | 0 | 0 | 0 | Finish Face: Interior | 0.70225 | 215 | Bouwkundig | Model Group:Penant Dubbel:5536915
5536944 | 00 Begane grond | 2650 | 265 | 0.0265 | 0.070225 | 0.70225 | 0.70225 | 0.070225 | 0 | 0 | 0 | Finish Face: Interior | 0.70225 | 215 | Bouwkundig | Model Group:Penant Dubbel:5536947
5536945 | 00 Begane grond | 2650 | 120 | 0.012 | 0.0318 | 0.318 | 0.318 | 0.0318 | 0 | 0 | 0 | Finish Face: Interior | 0.318 | 220 | Bouwkundig | Model Group:Penant Dubbel:5536947
5536946 | 00 Begane grond | 2650 | 265 | 0.0265 | 0.070225 | 0.70225 | 0.70225 | 0.070225 | 0 | 0 | 0 | Finish Face: Interior | 0.70225 | 215 | Bouwkundig | Model Group:Penant Dubbel:5536947
5536958 | 00 Begane grond | 2650 | 265 | 0.0265 | 0.070225 | 0.70225 | 0.70225 | 0.070225 | 0 | 0 | 0 | Finish Face: Interior | 0.70225 | 215 | Bouwkundig | Model Group:Penant Dubbel:5536961
5536959 | 00 Begane grond | 2650 | 120 | 0.012 | 0.0318 | 0.318 | 0.318 | 0.0318 | 0 | 0 | 0 | Finish Face: Interior | 0.318 | 220 | Bouwkundig | Model Group:Penant Dubbel:5536961
5536960 | 00 Begane grond | 2650 | 265 | 0.0265 | 0.070225 | 0.70225 | 0.70225 | 0.070225 | 0 | 0 | 0 | Finish Face: Interior | 0.70225 | 215 | Bouwkundig | Model Group:Penant Dubbel:5536961
5536974 | 00 Begane grond | 3650 | 4634.96 | 0.463496 | 1.69176 | 16.9176 | 16.9176 | 1.69176 | 0 | 0 | 0 | Finish Face: Interior | 16.9176 | 4584.96 | Bouwkundig | Constraints - Top Constraint: Up to level: 1
5537024 | 00 Begane grond | 825 | 9222 | 0.9222 | 0.760815 | 7.60815 | 7.60815 | 0.760815 | 0 | 0 | 2825 | Finish Face: Interior | 7.60815 | 9222 | Bouwkundig | Constraints - Top Constraint: Up to level: 1
5537025 | 00 Begane grond | 3650 | 2735 | 0.2735 | 0.993573 | 9.93573 | 9.93573 | 0.993573 | 0 | 0 | 0 | Finish Face: Interior | 9.93573 | 2835 | Bouwkundig | Constraints - Top Constraint: Up to level: 1
5537026 | 00 Begane grond | 2650 | 265 | 0.0265 | 0.070225 | 0.70225 | 0.70225 | 0.070225 | 0 | 0 | 0 | Finish Face: Interior | 0.70225 | 215 | Bouwkundig | Model Group:Penant Dubbel:5537029
5537027 | 00 Begane grond | 2650 | 120 | 0.012 | 0.0318 | 0.318 | 0.318 | 0.0318 | 0 | 0 | 0 | Finish Face: Interior | 0.318 | 220 | Bouwkundig | Model Group:Penant Dubbel:5537029
5537028 | 00 Begane grond | 2650 | 265 | 0.0265 | 0.070225 | 0.70225 | 0.70225 | 0.070225 | 0 | 0 | 0 | Finish Face: Interior | 0.70225 | 215 | Bouwkundig | Model Group:Penant Dubbel:5537029
5537038 | 00 Begane grond | 2650 | 265 | 0.0265 | 0.070225 | 0.70225 | 0.70225 | 0.070225 | 0 | 0 | 0 | Finish Face: Interior | 0.70225 | 215 | Bouwkundig | Model Group:Penant Dubbel:5537041
5537039 | 00 Begane grond | 2650 | 120 | 0.012 | 0.0318 | 0.318 | 0.318 | 0.0318 | 0 | 0 | 0 | Finish Face: Interior | 0.318 | 220 | Bouwkundig | Model Group:Penant Dubbel:5537041
5537040 | 00 Begane grond | 2650 | 265 | 0.0265 | 0.070225 | 0.70225 | 0.70225 | 0.070225 | 0 | 0 | 0 | Finish Face: Interior | 0.70225 | 215 | Bouwkundig | Model Group:Penant Dubbel:5537041
5537052 | 00 Begane grond | 2650 | 265 | 0.0265 | 0.070225 | 0.70225 | 0.70225 | 0.070225 | 0 | 0 | 0 | Finish Face: Interior | 0.70225 | 265 | Bouwkundig | Model Group:Penant Enkel:5537051
5537061 | 00 Begane grond | 2650 | 265 | 0.0265 | 0.070225 | 0.70225 | 0.70225 | 0.070225 | 0 | 0 | 0 | Finish Face: Interior | 0.70225 | 215 | Bouwkundig | Model Group:Penant Dubbel:5537064
5537062 | 00 Begane grond | 2650 | 120 | 0.012 | 0.0318 | 0.318 | 0.318 | 0.0318 | 0 | 0 | 0 | Finish Face: Interior | 0.318 | 220 | Bouwkundig | Model Group:Penant Dubbel:5537064
5537063 | 00 Begane grond | 2650 | 265 | 0.0265 | 0.070225 | 0.70225 | 0.70225 | 0.070225 | 0 | 0 | 0 | Finish Face: Interior | 0.70225 | 215 | Bouwkundig | Model Group:Penant Dubbel:5537064
5537073 | 00 Begane grond | 2650 | 265 | 0.0265 | 0.070225 | 0.70225 | 0.70225 | 0.070225 | 0 | 0 | 0 | Finish Face: Interior | 0.70225 | 215 | Bouwkundig | Model Group:Penant Dubbel:5537076
5537074 | 00 Begane grond | 2650 | 120 | 0.012 | 0.0318 | 0.318 | 0.318 | 0.0318 | 0 | 0 | 0 | Finish Face: Interior | 0.318 | 220 | Bouwkundig | Model Group:Penant Dubbel:5537076
5537075 | 00 Begane grond | 2650 | 265 | 0.0265 | 0.070225 | 0.70225 | 0.70225 | 0.070225 | 0 | 0 | 0 | Finish Face: Interior | 0.70225 | 215 | Bouwkundig | Model Group:Penant Dubbel:5537076
5537095 | 00 Begane grond | 2650 | 265 | 0.0265 | 0.070225 | 0.70225 | 0.70225 | 0.070225 | 0 | 0 | 0 | Finish Face: Interior | 0.70225 | 215 | Bouwkundig | Model Group:Penant Dubbel:5537098
5537096 | 00 Begane grond | 2650 | 120 | 0.012 | 0.0318 | 0.318 | 0.318 | 0.0318 | 0 | 0 | 0 | Finish Face: Interior | 0.318 | 220 | Bouwkundig | Model Group:Penant Dubbel:5537098
5537097 | 00 Begane grond | 2650 | 265 | 0.0265 | 0.070225 | 0.70225 | 0.70225 | 0.070225 | 0 | 0 | 0 | Finish Face: Interior | 0.70225 | 215 | Bouwkundig | Model Group:Penant Dubbel:5537098
5537099 | 00 Begane grond | 2650 | 265 | 0.0265 | 0.070225 | 0.70225 | 0.70225 | 0.070225 | 0 | 0 | 0 | Finish Face: Interior | 0.70225 | 265 | Bouwkundig | Model Group:Penant Enkel:5537100
5537279 | 00 Begane grond | 3650 | 30205 | 3.0205 | 11.0248 | 110.248 | 90.3583 | 9.03583 | 0 | 0 | 0 | Finish Face: Interior | 90.3583 | 30305 | Bouwkundig | Constraints - Top Constraint: Up to level: 1
5537280 | 00 Begane grond | 2650 | 265 | 0.0265 | 0.070225 | 0.70225 | 0.70225 | 0.070225 | -1000 | 0 | 0 | Finish Face: Interior | 0.70225 | 265 | Bouwkundig | Constraints - Top Constraint: Up to level: 1
5537290 | 00 Begane grond | 2200 | 265 | 0.0265 | 0.0583 | 0.583 | 0.583 | 0.0583 | 0 | 0 | 700 | Finish Face: Interior | 0.583 | 215 | Bouwkundig | Model Group:Penant Dubbel P+450:5536812
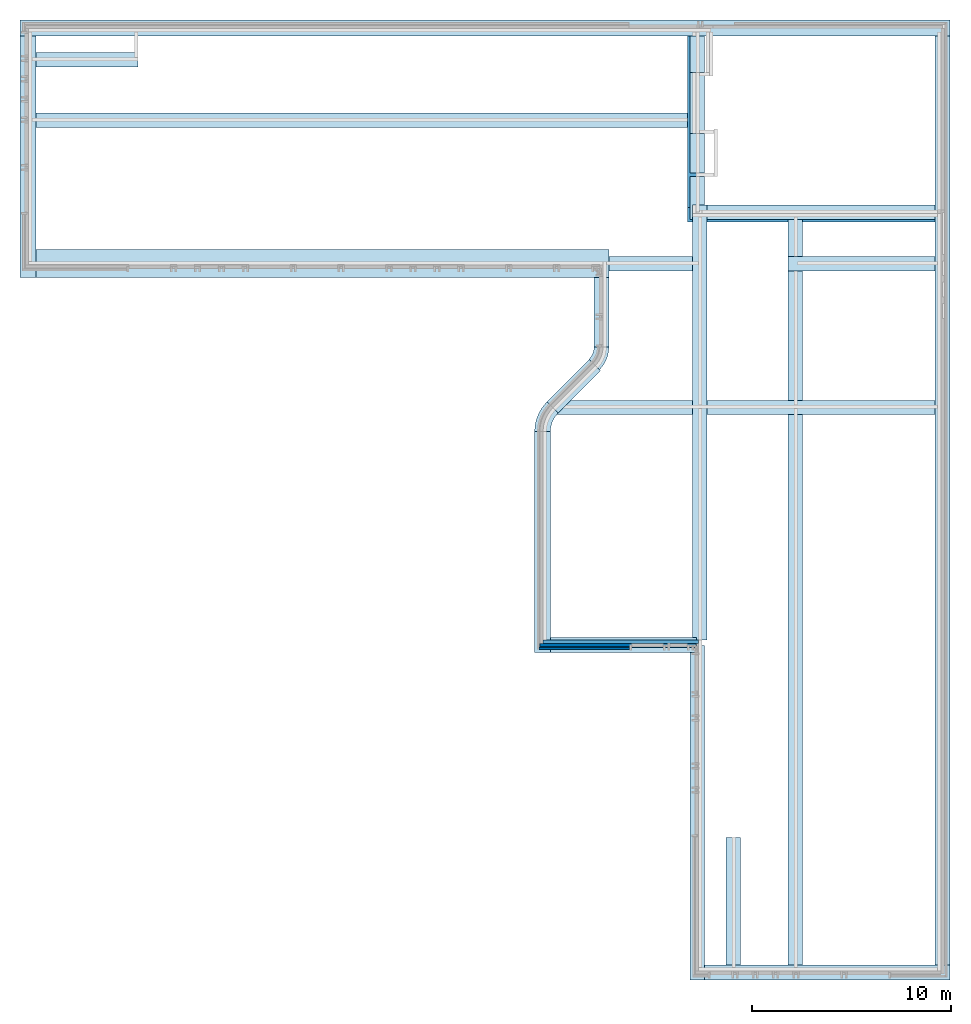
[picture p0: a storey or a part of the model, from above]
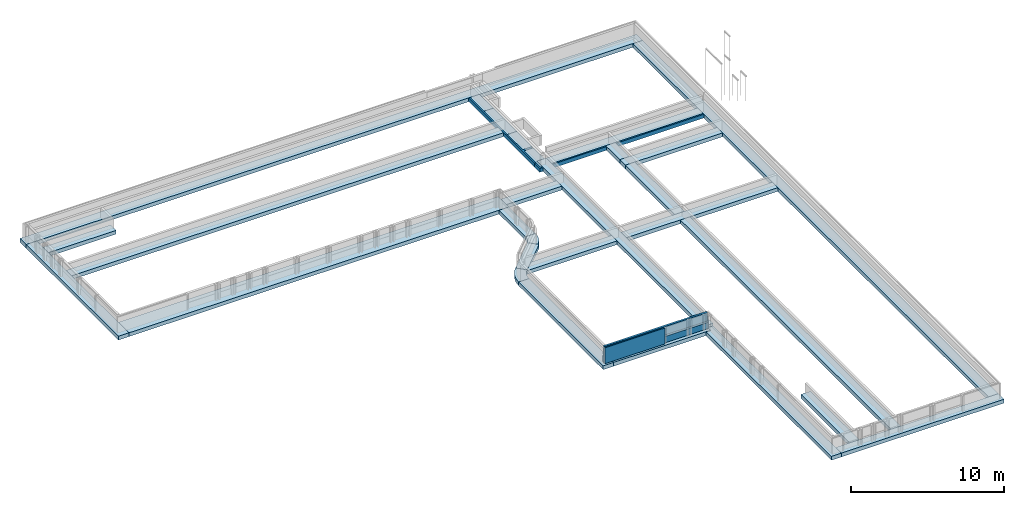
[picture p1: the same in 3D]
Properties of the parts of a building model (IFC2X3), part 31 of 37

# IfcWallStandardCase: Basic Wall:21_DAT_metselwerk_100 (534)
Name (Basic Wall:21_DAT_metselwerk_100:...) | In | Height (mm) = Unconnected Height (mm) | BaseQuantities, Length (mm) | GrossFootprintArea (m2) | GrossVolume (m3) | GrossSideArea (m2) | NetSideArea (m2) | NetVolume (m3) = Volume (m3) | Top Offset (mm) | Base Constraint | Base Offset (mm) | Location Line | Area (m2) | Dimensions, Length (mm) | Workset | Group
5537291 | 00 Begane grond | 2200 | 120 | 0.012 | 0.0264 | 0.264 | 0.264 | 0.0264 | 0 | 0 | 700 | Finish Face: Interior | 0.264 | 220 | Bouwkundig | Model Group:Penant Dubbel P+450:5536812
5537292 | 00 Begane grond | 2200 | 265 | 0.0265 | 0.0583 | 0.583 | 0.583 | 0.0583 | 0 | 0 | 700 | Finish Face: Interior | 0.583 | 215 | Bouwkundig | Model Group:Penant Dubbel P+450:5536812
5537303 | 00 Begane grond | 2200 | 265 | 0.0265 | 0.0583 | 0.583 | 0.583 | 0.0583 | 0 | 0 | 700 | Finish Face: Interior | 0.583 | 215 | Bouwkundig | Model Group:Penant Dubbel P+450:5537302
5537304 | 00 Begane grond | 2200 | 120 | 0.012 | 0.0264 | 0.264 | 0.264 | 0.0264 | 0 | 0 | 700 | Finish Face: Interior | 0.264 | 220 | Bouwkundig | Model Group:Penant Dubbel P+450:5537302
5537305 | 00 Begane grond | 2200 | 265 | 0.0265 | 0.0583 | 0.583 | 0.583 | 0.0583 | 0 | 0 | 700 | Finish Face: Interior | 0.583 | 215 | Bouwkundig | Model Group:Penant Dubbel P+450:5537302
5537314 | 00 Begane grond | 525 | 11635 | 1.1635 | 0.610837 | 6.10837 | 6.10837 | 0.610837 | 0 | 0 | 0 | Finish Face: Interior | 6.10837 | 11585 | Bouwkundig
5537315 | 00 Begane grond | 575 | 9435 | 0.9435 | 0.542513 | 5.42513 | 5.42513 | 0.542513 | 0 | 0 | 3075 | Finish Face: Interior | 5.42513 | 9435 | Bouwkundig | Constraints - Top Constraint: Up to level: 1
5537319 | 00 Begane grond | 2200 | 265 | 0.0265 | 0.0583 | 0.583 | 0.583 | 0.0583 | 0 | 0 | 700 | Finish Face: Interior | 0.583 | 215 | Bouwkundig | Model Group:Penant Dubbel P+450:5537318
5537320 | 00 Begane grond | 2200 | 120 | 0.012 | 0.0264 | 0.264 | 0.264 | 0.0264 | 0 | 0 | 700 | Finish Face: Interior | 0.264 | 220 | Bouwkundig | Model Group:Penant Dubbel P+450:5537318
5537321 | 00 Begane grond | 2200 | 265 | 0.0265 | 0.0583 | 0.583 | 0.583 | 0.0583 | 0 | 0 | 700 | Finish Face: Interior | 0.583 | 215 | Bouwkundig | Model Group:Penant Dubbel P+450:5537318
5537324 | 00 Begane grond | 2200 | 265 | 0.0265 | 0.0583 | 0.583 | 0.583 | 0.0583 | 0 | 0 | 700 | Finish Face: Interior | 0.583 | 215 | Bouwkundig | Model Group:Penant Dubbel P+450:5537323
5537325 | 00 Begane grond | 2200 | 120 | 0.012 | 0.0264 | 0.264 | 0.264 | 0.0264 | 0 | 0 | 700 | Finish Face: Interior | 0.264 | 220 | Bouwkundig | Model Group:Penant Dubbel P+450:5537323
5537326 | 00 Begane grond | 2200 | 265 | 0.0265 | 0.0583 | 0.583 | 0.583 | 0.0583 | 0 | 0 | 700 | Finish Face: Interior | 0.583 | 215 | Bouwkundig | Model Group:Penant Dubbel P+450:5537323
5537328 | 00 Begane grond | 6825 | 265 | 0.0265 | 0.180862 | 1.80862 | 1.80862 | 0.180862 | 0 | 0 | 700 | Finish Face: Interior | 1.80862 | 215 | Bouwkundig
5537329 | 00 Begane grond | 2200 | 120 | 0.012 | 0.0264 | 0.264 | 0.264 | 0.0264 | 0 | 0 | 700 | Finish Face: Interior | 0.264 | 220 | Bouwkundig
5537330 | 00 Begane grond | 2200 | 265 | 0.0265 | 0.0583 | 0.583 | 0.583 | 0.0583 | 0 | 0 | 700 | Finish Face: Interior | 0.583 | 215 | Bouwkundig
5537360 | 00 Begane grond | 6200 | 265 | 0.0265 | 0.1643 | 1.643 | 1.643 | 0.1643 | 0 | 0 | 1325 | Finish Face: Interior | 1.643 | 215 | Bouwkundig
5537361 | 00 Begane grond | 6200 | 120 | 0.012 | 0.0744 | 0.744 | 0.744 | 0.0744 | 0 | 0 | 1325 | Finish Face: Interior | 0.744 | 220 | Bouwkundig
5537362 | 00 Begane grond | 6825 | 265 | 0.0265 | 0.180862 | 1.80862 | 1.80862 | 0.180862 | 0 | 0 | 700 | Finish Face: Interior | 1.80862 | 215 | Bouwkundig
5537364 | 02 tweede verdieping | 550 | 6260 | 0.626 | 0.3443 | 3.443 | 3.443 | 0.3443 | 0 | V2 bk. ruwe vloer | 0 | Finish Face: Interior | 3.443 | 6260 | Bouwkundig
5537365 | 00 Begane grond | 5575 | 265 | 0.0265 | 0.147737 | 1.47737 | 1.47737 | 0.147737 | 0 | 0 | 1950 | Finish Face: Interior | 1.47737 | 215 | Bouwkundig
5537366 | 00 Begane grond | 5575 | 120 | 0.012 | 0.0669 | 0.669 | 0.669 | 0.0669 | 0 | 0 | 1950 | Finish Face: Interior | 0.669 | 220 | Bouwkundig
5537367 | 00 Begane grond | 6200 | 265 | 0.0265 | 0.1643 | 1.643 | 1.643 | 0.1643 | 0 | 0 | 1325 | Finish Face: Interior | 1.643 | 215 | Bouwkundig
5537368 | 00 Begane grond | 4950 | 265 | 0.0265 | 0.131175 | 1.31175 | 1.31175 | 0.131175 | 0 | 0 | 2575 | Finish Face: Interior | 1.31175 | 215 | Bouwkundig
5537369 | 00 Begane grond | 4950 | 120 | 0.012 | 0.0594 | 0.594 | 0.594 | 0.0594 | 0 | 0 | 2575 | Finish Face: Interior | 0.594 | 220 | Bouwkundig
5537370 | 00 Begane grond | 5575 | 265 | 0.0265 | 0.147737 | 1.47737 | 1.47737 | 0.147737 | 0 | 0 | 1950 | Finish Face: Interior | 1.47737 | 215 | Bouwkundig
5537371 | 00 Begane grond | 4325 | 265 | 0.0265 | 0.114612 | 1.14612 | 1.14612 | 0.114612 | 0 | 0 | 3200 | Finish Face: Interior | 1.14612 | 215 | Bouwkundig
5537372 | 00 Begane grond | 4325 | 120 | 0.012 | 0.0519 | 0.519 | 0.519 | 0.0519 | 0 | 0 | 3200 | Finish Face: Interior | 0.519 | 220 | Bouwkundig
5537373 | 00 Begane grond | 4950 | 265 | 0.0265 | 0.131175 | 1.31175 | 1.31175 | 0.131175 | 0 | 0 | 2575 | Finish Face: Interior | 1.31175 | 215 | Bouwkundig
5537374 | 00 Begane grond | 3700 | 265 | 0.0265 | 0.09805 | 0.9805 | 0.9805 | 0.09805 | 0 | 0 | 3825 | Finish Face: Interior | 0.9805 | 215 | Bouwkundig
5537375 | 00 Begane grond | 3700 | 120 | 0.012 | 0.0444 | 0.444 | 0.444 | 0.0444 | 0 | 0 | 3825 | Finish Face: Interior | 0.444 | 220 | Bouwkundig
5537376 | 00 Begane grond | 4325 | 265 | 0.0265 | 0.114612 | 1.14612 | 1.14612 | 0.114612 | 0 | 0 | 3200 | Finish Face: Interior | 1.14612 | 215 | Bouwkundig
5537377 | 00 Begane grond | 3075 | 265 | 0.0265 | 0.0814875 | 0.814875 | 0.814875 | 0.0814875 | 0 | 0 | 4450 | Finish Face: Interior | 0.814875 | 215 | Bouwkundig
5537378 | 00 Begane grond | 3075 | 120 | 0.012 | 0.0369 | 0.369 | 0.369 | 0.0369 | 0 | 0 | 4450 | Finish Face: Interior | 0.369 | 220 | Bouwkundig
5537379 | 00 Begane grond | 3700 | 265 | 0.0265 | 0.09805 | 0.9805 | 0.9805 | 0.09805 | 0 | 0 | 3825 | Finish Face: Interior | 0.9805 | 215 | Bouwkundig
5537477 | 00 Begane grond | 3025 | 1970 | 0.197 | 0.379925 | 3.79925 | 3.79925 | 0.379925 | 0 | 0 | 0 | Finish Face: Interior | 3.79925 | 2020 | Bouwkundig
5537478 | 00 Begane grond | 2400 | 1970 | 0.197 | 0.4728 | 4.728 | 4.728 | 0.4728 | 0 | 0 | 0 | Finish Face: Interior | 4.728 | 2020 | Bouwkundig
5537479 | 00 Begane grond | 1775 | 1070 | 0.107 | 0.189925 | 1.89925 | 1.89925 | 0.189925 | 0 | 0 | 0 | Finish Face: Interior | 1.89925 | 1120 | Bouwkundig
5537481 | 00 Begane grond | 2200 | 265 | 0.0265 | 0.0583 | 0.583 | 0.583 | 0.0583 | 0 | 0 | 700 | Finish Face: Interior | 0.583 | 215 | Bouwkundig | Model Group:Penant Dubbel P+450:5537484
5537482 | 00 Begane grond | 2200 | 120 | 0.012 | 0.0264 | 0.264 | 0.264 | 0.0264 | 0 | 0 | 700 | Finish Face: Interior | 0.264 | 220 | Bouwkundig | Model Group:Penant Dubbel P+450:5537484
5537483 | 00 Begane grond | 2200 | 265 | 0.0265 | 0.0583 | 0.583 | 0.583 | 0.0583 | 0 | 0 | 700 | Finish Face: Interior | 0.583 | 215 | Bouwkundig | Model Group:Penant Dubbel P+450:5537484
5537498 | 00 Begane grond | 2200 | 265 | 0.0265 | 0.0583 | 0.583 | 0.583 | 0.0583 | 0 | 0 | 700 | Finish Face: Interior | 0.583 | 215 | Bouwkundig | Model Group:Penant Dubbel P+450:5537501
5537499 | 00 Begane grond | 2200 | 120 | 0.012 | 0.0264 | 0.264 | 0.264 | 0.0264 | 0 | 0 | 700 | Finish Face: Interior | 0.264 | 220 | Bouwkundig | Model Group:Penant Dubbel P+450:5537501
5537500 | 00 Begane grond | 2200 | 265 | 0.0265 | 0.0583 | 0.583 | 0.583 | 0.0583 | 0 | 0 | 700 | Finish Face: Interior | 0.583 | 215 | Bouwkundig | Model Group:Penant Dubbel P+450:5537501
5537511 | 00 Begane grond | 525 | 3865 | 0.3865 | 0.202912 | 2.02912 | 2.02912 | 0.202912 | 0 | 0 | 0 | Finish Face: Interior | 2.02912 | 3915 | Bouwkundig
5537512 | 00 Begane grond | 575 | 3865 | 0.3865 | 0.222238 | 2.22238 | 2.22238 | 0.222238 | 0 | 0 | 3075 | Finish Face: Interior | 2.22238 | 3915 | Bouwkundig | Constraints - Top Constraint: Up to level: 1
5537521 | 00 Begane grond | 2650 | 265 | 0.0265 | 0.070225 | 0.70225 | 0.70225 | 0.070225 | 0 | 0 | 0 | Finish Face: Interior | 0.70225 | 215 | Bouwkundig | Model Group:Penant Dubbel:5537524
5537522 | 00 Begane grond | 2650 | 120 | 0.012 | 0.0318 | 0.318 | 0.318 | 0.0318 | 0 | 0 | 0 | Finish Face: Interior | 0.318 | 220 | Bouwkundig | Model Group:Penant Dubbel:5537524
5537523 | 00 Begane grond | 2650 | 265 | 0.0265 | 0.070225 | 0.70225 | 0.70225 | 0.070225 | 0 | 0 | 0 | Finish Face: Interior | 0.70225 | 215 | Bouwkundig | Model Group:Penant Dubbel:5537524
5537558 | 00 Begane grond | 3075 | 265 | 0.0265 | 0.0814875 | 0.814875 | 0.814875 | 0.0814875 | 0 | 0 | 4450 | Finish Face: Interior | 0.814875 | 215 | Bouwkundig | Model Group:Penant Dubbel v1:5537561
5537559 | 00 Begane grond | 3075 | 120 | 0.012 | 0.0369 | 0.369 | 0.369 | 0.0369 | 0 | 0 | 4450 | Finish Face: Interior | 0.369 | 220 | Bouwkundig | Model Group:Penant Dubbel v1:5537561
5537560 | 00 Begane grond | 3075 | 265 | 0.0265 | 0.0814875 | 0.814875 | 0.814875 | 0.0814875 | 0 | 0 | 4450 | Finish Face: Interior | 0.814875 | 215 | Bouwkundig | Model Group:Penant Dubbel v1:5537561
5537562 | 00 Begane grond | 3075 | 265 | 0.0265 | 0.0814875 | 0.814875 | 0.814875 | 0.0814875 | 0 | 0 | 4450 | Finish Face: Interior | 0.814875 | 215 | Bouwkundig | Model Group:Penant Dubbel v1:5537565
5537563 | 00 Begane grond | 3075 | 120 | 0.012 | 0.0369 | 0.369 | 0.369 | 0.0369 | 0 | 0 | 4450 | Finish Face: Interior | 0.369 | 220 | Bouwkundig | Model Group:Penant Dubbel v1:5537565
5537564 | 00 Begane grond | 3075 | 265 | 0.0265 | 0.0814875 | 0.814875 | 0.814875 | 0.0814875 | 0 | 0 | 4450 | Finish Face: Interior | 0.814875 | 215 | Bouwkundig | Model Group:Penant Dubbel v1:5537565
5537567 | 00 Begane grond | 3075 | 265 | 0.0265 | 0.0814875 | 0.814875 | 0.814875 | 0.0814875 | 0 | 0 | 4450 | Finish Face: Interior | 0.814875 | 215 | Bouwkundig | Model Group:Penant Dubbel v1:5537570
5537568 | 00 Begane grond | 3075 | 120 | 0.012 | 0.0369 | 0.369 | 0.369 | 0.0369 | 0 | 0 | 4450 | Finish Face: Interior | 0.369 | 220 | Bouwkundig | Model Group:Penant Dubbel v1:5537570
5537569 | 00 Begane grond | 3075 | 265 | 0.0265 | 0.0814875 | 0.814875 | 0.814875 | 0.0814875 | 0 | 0 | 4450 | Finish Face: Interior | 0.814875 | 215 | Bouwkundig | Model Group:Penant Dubbel v1:5537570
5537571 | 00 Begane grond | 3075 | 265 | 0.0265 | 0.0814875 | 0.814875 | 0.814875 | 0.0814875 | 0 | 0 | 4450 | Finish Face: Interior | 0.814875 | 215 | Bouwkundig | Model Group:Penant Dubbel v1:5537574
5537572 | 00 Begane grond | 3075 | 120 | 0.012 | 0.0369 | 0.369 | 0.369 | 0.0369 | 0 | 0 | 4450 | Finish Face: Interior | 0.369 | 220 | Bouwkundig | Model Group:Penant Dubbel v1:5537574
5537573 | 00 Begane grond | 3075 | 265 | 0.0265 | 0.0814875 | 0.814875 | 0.814875 | 0.0814875 | 0 | 0 | 4450 | Finish Face: Interior | 0.814875 | 215 | Bouwkundig | Model Group:Penant Dubbel v1:5537574
5537575 | 00 Begane grond | 3075 | 265 | 0.0265 | 0.0814875 | 0.814875 | 0.814875 | 0.0814875 | 0 | 0 | 4450 | Finish Face: Interior | 0.814875 | 215 | Bouwkundig | Model Group:Penant Dubbel v1:5537578
5537576 | 00 Begane grond | 3075 | 120 | 0.012 | 0.0369 | 0.369 | 0.369 | 0.0369 | 0 | 0 | 4450 | Finish Face: Interior | 0.369 | 220 | Bouwkundig | Model Group:Penant Dubbel v1:5537578
5537577 | 00 Begane grond | 3075 | 265 | 0.0265 | 0.0814875 | 0.814875 | 0.814875 | 0.0814875 | 0 | 0 | 4450 | Finish Face: Interior | 0.814875 | 215 | Bouwkundig | Model Group:Penant Dubbel v1:5537578
5537579 | 00 Begane grond | 3075 | 265 | 0.0265 | 0.0814875 | 0.814875 | 0.814875 | 0.0814875 | 0 | 0 | 4450 | Finish Face: Interior | 0.814875 | 215 | Bouwkundig | Model Group:Penant Dubbel v1:5537582
5537580 | 00 Begane grond | 3075 | 120 | 0.012 | 0.0369 | 0.369 | 0.369 | 0.0369 | 0 | 0 | 4450 | Finish Face: Interior | 0.369 | 220 | Bouwkundig | Model Group:Penant Dubbel v1:5537582
5537581 | 00 Begane grond | 3075 | 265 | 0.0265 | 0.0814875 | 0.814875 | 0.814875 | 0.0814875 | 0 | 0 | 4450 | Finish Face: Interior | 0.814875 | 215 | Bouwkundig | Model Group:Penant Dubbel v1:5537582
5537583 | 00 Begane grond | 3075 | 265 | 0.0265 | 0.0814875 | 0.814875 | 0.814875 | 0.0814875 | 0 | 0 | 4450 | Finish Face: Interior | 0.814875 | 215 | Bouwkundig | Model Group:Penant Dubbel v1:5537586
5537584 | 00 Begane grond | 3075 | 120 | 0.012 | 0.0369 | 0.369 | 0.369 | 0.0369 | 0 | 0 | 4450 | Finish Face: Interior | 0.369 | 220 | Bouwkundig | Model Group:Penant Dubbel v1:5537586
5537585 | 00 Begane grond | 3075 | 265 | 0.0265 | 0.0814875 | 0.814875 | 0.814875 | 0.0814875 | 0 | 0 | 4450 | Finish Face: Interior | 0.814875 | 215 | Bouwkundig | Model Group:Penant Dubbel v1:5537586
5537587 | 00 Begane grond | 3075 | 265 | 0.0265 | 0.0814875 | 0.814875 | 0.814875 | 0.0814875 | 0 | 0 | 4450 | Finish Face: Interior | 0.814875 | 215 | Bouwkundig | Model Group:Penant Dubbel v1:5537590
5537588 | 00 Begane grond | 3075 | 120 | 0.012 | 0.0369 | 0.369 | 0.369 | 0.0369 | 0 | 0 | 4450 | Finish Face: Interior | 0.369 | 220 | Bouwkundig | Model Group:Penant Dubbel v1:5537590
5537589 | 00 Begane grond | 3075 | 265 | 0.0265 | 0.0814875 | 0.814875 | 0.814875 | 0.0814875 | 0 | 0 | 4450 | Finish Face: Interior | 0.814875 | 215 | Bouwkundig | Model Group:Penant Dubbel v1:5537590
5537591 | 00 Begane grond | 3075 | 265 | 0.0265 | 0.0814875 | 0.814875 | 0.814875 | 0.0814875 | 0 | 0 | 4450 | Finish Face: Interior | 0.814875 | 215 | Bouwkundig | Model Group:Penant Dubbel v1:5537594
5537592 | 00 Begane grond | 3075 | 120 | 0.012 | 0.0369 | 0.369 | 0.369 | 0.0369 | 0 | 0 | 4450 | Finish Face: Interior | 0.369 | 220 | Bouwkundig | Model Group:Penant Dubbel v1:5537594
5537593 | 00 Begane grond | 3075 | 265 | 0.0265 | 0.0814875 | 0.814875 | 0.814875 | 0.0814875 | 0 | 0 | 4450 | Finish Face: Interior | 0.814875 | 215 | Bouwkundig | Model Group:Penant Dubbel v1:5537594
5537595 | 00 Begane grond | 3075 | 265 | 0.0265 | 0.0814875 | 0.814875 | 0.814875 | 0.0814875 | 0 | 0 | 4450 | Finish Face: Interior | 0.814875 | 215 | Bouwkundig | Model Group:Penant Dubbel v1:5537598
5537596 | 00 Begane grond | 3075 | 120 | 0.012 | 0.0369 | 0.369 | 0.369 | 0.0369 | 0 | 0 | 4450 | Finish Face: Interior | 0.369 | 220 | Bouwkundig | Model Group:Penant Dubbel v1:5537598
5537597 | 00 Begane grond | 3075 | 265 | 0.0265 | 0.0814875 | 0.814875 | 0.814875 | 0.0814875 | 0 | 0 | 4450 | Finish Face: Interior | 0.814875 | 215 | Bouwkundig | Model Group:Penant Dubbel v1:5537598
5537599 | 00 Begane grond | 3075 | 265 | 0.0265 | 0.0814875 | 0.814875 | 0.814875 | 0.0814875 | 0 | 0 | 4450 | Finish Face: Interior | 0.814875 | 215 | Bouwkundig | Model Group:Penant Dubbel v1:5537602
5537600 | 00 Begane grond | 3075 | 120 | 0.012 | 0.0369 | 0.369 | 0.369 | 0.0369 | 0 | 0 | 4450 | Finish Face: Interior | 0.369 | 220 | Bouwkundig | Model Group:Penant Dubbel v1:5537602
5537601 | 00 Begane grond | 3075 | 265 | 0.0265 | 0.0814875 | 0.814875 | 0.814875 | 0.0814875 | 0 | 0 | 4450 | Finish Face: Interior | 0.814875 | 215 | Bouwkundig | Model Group:Penant Dubbel v1:5537602
5537603 | 00 Begane grond | 3075 | 265 | 0.0265 | 0.0814875 | 0.814875 | 0.814875 | 0.0814875 | 0 | 0 | 4450 | Finish Face: Interior | 0.814875 | 215 | Bouwkundig | Model Group:Penant Dubbel v1:5537606
5537604 | 00 Begane grond | 3075 | 120 | 0.012 | 0.0369 | 0.369 | 0.369 | 0.0369 | 0 | 0 | 4450 | Finish Face: Interior | 0.369 | 220 | Bouwkundig | Model Group:Penant Dubbel v1:5537606
5537605 | 00 Begane grond | 3075 | 265 | 0.0265 | 0.0814875 | 0.814875 | 0.814875 | 0.0814875 | 0 | 0 | 4450 | Finish Face: Interior | 0.814875 | 215 | Bouwkundig | Model Group:Penant Dubbel v1:5537606
5537607 | 00 Begane grond | 3075 | 265 | 0.0265 | 0.0814875 | 0.814875 | 0.814875 | 0.0814875 | 0 | 0 | 4450 | Finish Face: Interior | 0.814875 | 215 | Bouwkundig | Model Group:Penant Dubbel v1:5537610
5537608 | 00 Begane grond | 3075 | 120 | 0.012 | 0.0369 | 0.369 | 0.369 | 0.0369 | 0 | 0 | 4450 | Finish Face: Interior | 0.369 | 220 | Bouwkundig | Model Group:Penant Dubbel v1:5537610
5537609 | 00 Begane grond | 3075 | 265 | 0.0265 | 0.0814875 | 0.814875 | 0.814875 | 0.0814875 | 0 | 0 | 4450 | Finish Face: Interior | 0.814875 | 215 | Bouwkundig | Model Group:Penant Dubbel v1:5537610
5537611 | 00 Begane grond | 3075 | 265 | 0.0265 | 0.0814875 | 0.814875 | 0.814875 | 0.0814875 | 0 | 0 | 4450 | Finish Face: Interior | 0.814875 | 215 | Bouwkundig | Model Group:Penant Dubbel v1:5537614
5537612 | 00 Begane grond | 3075 | 120 | 0.012 | 0.0369 | 0.369 | 0.369 | 0.0369 | 0 | 0 | 4450 | Finish Face: Interior | 0.369 | 220 | Bouwkundig | Model Group:Penant Dubbel v1:5537614
5537613 | 00 Begane grond | 3075 | 265 | 0.0265 | 0.0814875 | 0.814875 | 0.814875 | 0.0814875 | 0 | 0 | 4450 | Finish Face: Interior | 0.814875 | 215 | Bouwkundig | Model Group:Penant Dubbel v1:5537614
5537615 | 00 Begane grond | 3075 | 265 | 0.0265 | 0.0814875 | 0.814875 | 0.814875 | 0.0814875 | 0 | 0 | 4450 | Finish Face: Interior | 0.814875 | 215 | Bouwkundig | Model Group:Penant Dubbel v1:5537618
5537616 | 00 Begane grond | 3075 | 120 | 0.012 | 0.0369 | 0.369 | 0.369 | 0.0369 | 0 | 0 | 4450 | Finish Face: Interior | 0.369 | 220 | Bouwkundig | Model Group:Penant Dubbel v1:5537618
5537617 | 00 Begane grond | 3075 | 265 | 0.0265 | 0.0814875 | 0.814875 | 0.814875 | 0.0814875 | 0 | 0 | 4450 | Finish Face: Interior | 0.814875 | 215 | Bouwkundig | Model Group:Penant Dubbel v1:5537618
5537622 | 01 eerste verdieping | 625 | 27250 | 2.725 | 1.70313 | 17.0313 | 17.0313 | 1.70313 | 0 | 1 | 0 | Finish Face: Interior | 17.0313 | 27300 | Bouwkundig
5537673 | 02 tweede verdieping | 550 | 3335 | 0.3335 | 0.183425 | 1.83425 | 1.83425 | 0.183425 | 0 | V2 bk. ruwe vloer | 0 | Finish Face: Interior | 1.83425 | 3435 | Bouwkundig
5537686 | 00 Begane grond | 1950 | 265 | 0.0265 | 0.051675 | 0.51675 | 0.51675 | 0.051675 | 0 | 0 | 4450 | Finish Face: Interior | 0.51675 | 215 | Bouwkundig | Model Group:Penant Dubbel v1 Laag:5537689
5537687 | 00 Begane grond | 1950 | 120 | 0.012 | 0.0234 | 0.234 | 0.234 | 0.0234 | 0 | 0 | 4450 | Finish Face: Interior | 0.234 | 220 | Bouwkundig | Model Group:Penant Dubbel v1 Laag:5537689
5537688 | 00 Begane grond | 1950 | 265 | 0.0265 | 0.051675 | 0.51675 | 0.51675 | 0.051675 | 0 | 0 | 4450 | Finish Face: Interior | 0.51675 | 215 | Bouwkundig | Model Group:Penant Dubbel v1 Laag:5537689
5537705 | 00 Begane grond | 3075 | 270 | 0.027 | 0.083025 | 0.83025 | 0.83025 | 0.083025 | 0 | 0 | 4450 | Finish Face: Interior | 0.83025 | 270 | Bouwkundig | Model Group:Penant Dubbel v1 Enkel:5537706
5537707 | 00 Begane grond | 1950 | 270 | 0.027 | 0.05265 | 0.5265 | 0.5265 | 0.05265 | 0 | 0 | 4450 | Finish Face: Interior | 0.5265 | 270 | Bouwkundig
5537708 | 01 eerste verdieping | 425 | 2184 | 0.2184 | 0.09282 | 0.9282 | 0.9282 | 0.09282 | 0 | 1 | 200 | Finish Face: Interior | 0.9282 | 2184 | Bouwkundig
5537709 | 00 Begane grond | 1950 | 265 | 0.0265 | 0.051675 | 0.51675 | 0.51675 | 0.051675 | 0 | 0 | 4450 | Finish Face: Interior | 0.51675 | 215 | Bouwkundig | Model Group:Penant Dubbel v1 Laag:5537690
5537710 | 00 Begane grond | 1950 | 120 | 0.012 | 0.0234 | 0.234 | 0.234 | 0.0234 | 0 | 0 | 4450 | Finish Face: Interior | 0.234 | 220 | Bouwkundig | Model Group:Penant Dubbel v1 Laag:5537690
5537711 | 00 Begane grond | 1950 | 265 | 0.0265 | 0.051675 | 0.51675 | 0.51675 | 0.051675 | 0 | 0 | 4450 | Finish Face: Interior | 0.51675 | 215 | Bouwkundig | Model Group:Penant Dubbel v1 Laag:5537690
5537712 | 01 eerste verdieping | 575 | 2659 | 0.2659 | 0.152893 | 1.52893 | 1.52893 | 0.152893 | 0 | 1 | 2925 | Finish Face: Interior | 1.52893 | 2609 | Bouwkundig | Constraints - Top Constraint: Up to level: V2 bk. ruwe vloer
5537714 | 01 eerste verdieping | 575 | 1287 | 0.1287 | 0.0740025 | 0.740025 | 0.740025 | 0.0740025 | 0 | 1 | 2925 | Finish Face: Interior | 0.740025 | 1337 | Bouwkundig | Constraints - Top Constraint: Up to level: V2 bk. ruwe vloer
5537716 | 00 Begane grond | 2200 | 265 | 0.0265 | 0.0583 | 0.583 | 0.583 | 0.0583 | 0 | 0 | 700 | Finish Face: Interior | 0.583 | 215 | Bouwkundig | Model Group:Penant Dubbel P+450:5537715
5537717 | 00 Begane grond | 2200 | 120 | 0.012 | 0.0264 | 0.264 | 0.264 | 0.0264 | 0 | 0 | 700 | Finish Face: Interior | 0.264 | 220 | Bouwkundig | Model Group:Penant Dubbel P+450:5537715
5537718 | 00 Begane grond | 2200 | 265 | 0.0265 | 0.0583 | 0.583 | 0.583 | 0.0583 | 0 | 0 | 700 | Finish Face: Interior | 0.583 | 215 | Bouwkundig | Model Group:Penant Dubbel P+450:5537715
5537719 | 00 Begane grond | 2200 | 265 | 0.0265 | 0.0583 | 0.583 | 0.583 | 0.0583 | 0 | 0 | 700 | Finish Face: Interior | 0.583 | 265 | Bouwkundig
5537733 | 00 Begane grond | 2200 | 265 | 0.0265 | 0.0583 | 0.583 | 0.583 | 0.0583 | 0 | 0 | 700 | Finish Face: Interior | 0.583 | 215 | Bouwkundig | Model Group:Penant Dubbel P+450:5537732
5537734 | 00 Begane grond | 2200 | 120 | 0.012 | 0.0264 | 0.264 | 0.264 | 0.0264 | 0 | 0 | 700 | Finish Face: Interior | 0.264 | 220 | Bouwkundig | Model Group:Penant Dubbel P+450:5537732
5537735 | 00 Begane grond | 2200 | 265 | 0.0265 | 0.0583 | 0.583 | 0.583 | 0.0583 | 0 | 0 | 700 | Finish Face: Interior | 0.583 | 215 | Bouwkundig | Model Group:Penant Dubbel P+450:5537732
5537816 | 00 Begane grond | 1950 | 270 | 0.027 | 0.05265 | 0.5265 | 0.5265 | 0.05265 | 0 | 0 | 4450 | Finish Face: Interior | 0.5265 | 270 | Bouwkundig
5537817 | 01 eerste verdieping | 3500 | 2003 | 0.2003 | 0.699325 | 6.99325 | 6.99325 | 0.699325 | 0 | 1 | 0 | Finish Face: Interior | 6.99325 | 2053 | Bouwkundig | Constraints - Top Constraint: Up to level: V2 bk. ruwe vloer
5537818 | 00 Begane grond | 3075 | 265 | 0.0265 | 0.0814875 | 0.814875 | 0.814875 | 0.0814875 | 0 | 0 | 4450 | Finish Face: Interior | 0.814875 | 215 | Bouwkundig | Model Group:Penant Dubbel v1:5537821
5537819 | 00 Begane grond | 3075 | 120 | 0.012 | 0.0369 | 0.369 | 0.369 | 0.0369 | 0 | 0 | 4450 | Finish Face: Interior | 0.369 | 220 | Bouwkundig | Model Group:Penant Dubbel v1:5537821
5537820 | 00 Begane grond | 3075 | 265 | 0.0265 | 0.0814875 | 0.814875 | 0.814875 | 0.0814875 | 0 | 0 | 4450 | Finish Face: Interior | 0.814875 | 215 | Bouwkundig | Model Group:Penant Dubbel v1:5537821
5537826 | 00 Begane grond | 3075 | 265 | 0.0265 | 0.0814875 | 0.814875 | 0.814875 | 0.0814875 | 0 | 0 | 4450 | Finish Face: Interior | 0.814875 | 215 | Bouwkundig | Model Group:Penant Dubbel v1:5537829
5537827 | 00 Begane grond | 3075 | 120 | 0.012 | 0.0369 | 0.369 | 0.369 | 0.0369 | 0 | 0 | 4450 | Finish Face: Interior | 0.369 | 220 | Bouwkundig | Model Group:Penant Dubbel v1:5537829
5537828 | 00 Begane grond | 3075 | 265 | 0.0265 | 0.0814875 | 0.814875 | 0.814875 | 0.0814875 | 0 | 0 | 4450 | Finish Face: Interior | 0.814875 | 215 | Bouwkundig | Model Group:Penant Dubbel v1:5537829
5537830 | 00 Begane grond | 3075 | 265 | 0.0265 | 0.0814875 | 0.814875 | 0.814875 | 0.0814875 | 0 | 0 | 4450 | Finish Face: Interior | 0.814875 | 215 | Bouwkundig | Model Group:Penant Dubbel v1:5537833
5537831 | 00 Begane grond | 3075 | 120 | 0.012 | 0.0369 | 0.369 | 0.369 | 0.0369 | 0 | 0 | 4450 | Finish Face: Interior | 0.369 | 220 | Bouwkundig | Model Group:Penant Dubbel v1:5537833
5537832 | 00 Begane grond | 3075 | 265 | 0.0265 | 0.0814875 | 0.814875 | 0.814875 | 0.0814875 | 0 | 0 | 4450 | Finish Face: Interior | 0.814875 | 215 | Bouwkundig | Model Group:Penant Dubbel v1:5537833
5537842 | 00 Begane grond | 3075 | 265 | 0.0265 | 0.0814875 | 0.814875 | 0.814875 | 0.0814875 | 0 | 0 | 4450 | Finish Face: Interior | 0.814875 | 215 | Bouwkundig | Model Group:Penant Dubbel v1:5537845
5537843 | 00 Begane grond | 3075 | 120 | 0.012 | 0.0369 | 0.369 | 0.369 | 0.0369 | 0 | 0 | 4450 | Finish Face: Interior | 0.369 | 220 | Bouwkundig | Model Group:Penant Dubbel v1:5537845
5537844 | 00 Begane grond | 3075 | 265 | 0.0265 | 0.0814875 | 0.814875 | 0.814875 | 0.0814875 | 0 | 0 | 4450 | Finish Face: Interior | 0.814875 | 215 | Bouwkundig | Model Group:Penant Dubbel v1:5537845
5537850 | 00 Begane grond | 3075 | 265 | 0.0265 | 0.0814875 | 0.814875 | 0.814875 | 0.0814875 | 0 | 0 | 4450 | Finish Face: Interior | 0.814875 | 215 | Bouwkundig | Model Group:Penant Dubbel v1:5537853
5537851 | 00 Begane grond | 3075 | 120 | 0.012 | 0.0369 | 0.369 | 0.369 | 0.0369 | 0 | 0 | 4450 | Finish Face: Interior | 0.369 | 220 | Bouwkundig | Model Group:Penant Dubbel v1:5537853
5537852 | 00 Begane grond | 3075 | 265 | 0.0265 | 0.0814875 | 0.814875 | 0.814875 | 0.0814875 | 0 | 0 | 4450 | Finish Face: Interior | 0.814875 | 215 | Bouwkundig | Model Group:Penant Dubbel v1:5537853
5537854 | 00 Begane grond | 3075 | 265 | 0.0265 | 0.0814875 | 0.814875 | 0.814875 | 0.0814875 | 0 | 0 | 4450 | Finish Face: Interior | 0.814875 | 215 | Bouwkundig | Model Group:Penant Dubbel v1:5537857
5537855 | 00 Begane grond | 3075 | 120 | 0.012 | 0.0369 | 0.369 | 0.369 | 0.0369 | 0 | 0 | 4450 | Finish Face: Interior | 0.369 | 220 | Bouwkundig | Model Group:Penant Dubbel v1:5537857
5537856 | 00 Begane grond | 3075 | 265 | 0.0265 | 0.0814875 | 0.814875 | 0.814875 | 0.0814875 | 0 | 0 | 4450 | Finish Face: Interior | 0.814875 | 215 | Bouwkundig | Model Group:Penant Dubbel v1:5537857
5537862 | 00 Begane grond | 3075 | 265 | 0.0265 | 0.0814875 | 0.814875 | 0.814875 | 0.0814875 | 0 | 0 | 4450 | Finish Face: Interior | 0.814875 | 215 | Bouwkundig | Model Group:Penant Dubbel v1:5537865
5537863 | 00 Begane grond | 3075 | 120 | 0.012 | 0.0369 | 0.369 | 0.369 | 0.0369 | 0 | 0 | 4450 | Finish Face: Interior | 0.369 | 220 | Bouwkundig | Model Group:Penant Dubbel v1:5537865
5537864 | 00 Begane grond | 3075 | 265 | 0.0265 | 0.0814875 | 0.814875 | 0.814875 | 0.0814875 | 0 | 0 | 4450 | Finish Face: Interior | 0.814875 | 215 | Bouwkundig | Model Group:Penant Dubbel v1:5537865
5537874 | 00 Begane grond | 3075 | 265 | 0.0265 | 0.0814875 | 0.814875 | 0.814875 | 0.0814875 | 0 | 0 | 4450 | Finish Face: Interior | 0.814875 | 215 | Bouwkundig | Model Group:Penant Dubbel v1:5537877
5537875 | 00 Begane grond | 3075 | 120 | 0.012 | 0.0369 | 0.369 | 0.369 | 0.0369 | 0 | 0 | 4450 | Finish Face: Interior | 0.369 | 220 | Bouwkundig | Model Group:Penant Dubbel v1:5537877
5537876 | 00 Begane grond | 3075 | 265 | 0.0265 | 0.0814875 | 0.814875 | 0.814875 | 0.0814875 | 0 | 0 | 4450 | Finish Face: Interior | 0.814875 | 215 | Bouwkundig | Model Group:Penant Dubbel v1:5537877
5537882 | 00 Begane grond | 3075 | 265 | 0.0265 | 0.0814875 | 0.814875 | 0.814875 | 0.0814875 | 0 | 0 | 4450 | Finish Face: Interior | 0.814875 | 215 | Bouwkundig | Model Group:Penant Dubbel v1:5537885
5537883 | 00 Begane grond | 3075 | 120 | 0.012 | 0.0369 | 0.369 | 0.369 | 0.0369 | 0 | 0 | 4450 | Finish Face: Interior | 0.369 | 220 | Bouwkundig | Model Group:Penant Dubbel v1:5537885
5537884 | 00 Begane grond | 3075 | 265 | 0.0265 | 0.0814875 | 0.814875 | 0.814875 | 0.0814875 | 0 | 0 | 4450 | Finish Face: Interior | 0.814875 | 215 | Bouwkundig | Model Group:Penant Dubbel v1:5537885
5537886 | 00 Begane grond | 3075 | 265 | 0.0265 | 0.0814875 | 0.814875 | 0.814875 | 0.0814875 | 0 | 0 | 4450 | Finish Face: Interior | 0.814875 | 215 | Bouwkundig | Model Group:Penant Dubbel v1:5537889
5537887 | 00 Begane grond | 3075 | 120 | 0.012 | 0.0369 | 0.369 | 0.369 | 0.0369 | 0 | 0 | 4450 | Finish Face: Interior | 0.369 | 220 | Bouwkundig | Model Group:Penant Dubbel v1:5537889
5537888 | 00 Begane grond | 3075 | 265 | 0.0265 | 0.0814875 | 0.814875 | 0.814875 | 0.0814875 | 0 | 0 | 4450 | Finish Face: Interior | 0.814875 | 215 | Bouwkundig | Model Group:Penant Dubbel v1:5537889
5537894 | 00 Begane grond | 3075 | 265 | 0.0265 | 0.0814875 | 0.814875 | 0.814875 | 0.0814875 | 0 | 0 | 4450 | Finish Face: Interior | 0.814875 | 215 | Bouwkundig | Model Group:Penant Dubbel v1:5537897
5537895 | 00 Begane grond | 3075 | 120 | 0.012 | 0.0369 | 0.369 | 0.369 | 0.0369 | 0 | 0 | 4450 | Finish Face: Interior | 0.369 | 220 | Bouwkundig | Model Group:Penant Dubbel v1:5537897
5537896 | 00 Begane grond | 3075 | 265 | 0.0265 | 0.0814875 | 0.814875 | 0.814875 | 0.0814875 | 0 | 0 | 4450 | Finish Face: Interior | 0.814875 | 215 | Bouwkundig | Model Group:Penant Dubbel v1:5537897
5537906 | 00 Begane grond | 3075 | 265 | 0.0265 | 0.0814875 | 0.814875 | 0.814875 | 0.0814875 | 0 | 0 | 4450 | Finish Face: Interior | 0.814875 | 215 | Bouwkundig | Model Group:Penant Dubbel v1:5537909
5537907 | 00 Begane grond | 3075 | 120 | 0.012 | 0.0369 | 0.369 | 0.369 | 0.0369 | 0 | 0 | 4450 | Finish Face: Interior | 0.369 | 220 | Bouwkundig | Model Group:Penant Dubbel v1:5537909
5537908 | 00 Begane grond | 3075 | 265 | 0.0265 | 0.0814875 | 0.814875 | 0.814875 | 0.0814875 | 0 | 0 | 4450 | Finish Face: Interior | 0.814875 | 215 | Bouwkundig | Model Group:Penant Dubbel v1:5537909
5537914 | 00 Begane grond | 3075 | 265 | 0.0265 | 0.0814875 | 0.814875 | 0.814875 | 0.0814875 | 0 | 0 | 4450 | Finish Face: Interior | 0.814875 | 215 | Bouwkundig | Model Group:Penant Dubbel v1:5537917
5537915 | 00 Begane grond | 3075 | 120 | 0.012 | 0.0369 | 0.369 | 0.369 | 0.0369 | 0 | 0 | 4450 | Finish Face: Interior | 0.369 | 220 | Bouwkundig | Model Group:Penant Dubbel v1:5537917
5537916 | 00 Begane grond | 3075 | 265 | 0.0265 | 0.0814875 | 0.814875 | 0.814875 | 0.0814875 | 0 | 0 | 4450 | Finish Face: Interior | 0.814875 | 215 | Bouwkundig | Model Group:Penant Dubbel v1:5537917
5537918 | 00 Begane grond | 3075 | 265 | 0.0265 | 0.0814875 | 0.814875 | 0.814875 | 0.0814875 | 0 | 0 | 4450 | Finish Face: Interior | 0.814875 | 215 | Bouwkundig | Model Group:Penant Dubbel v1:5537921
5537919 | 00 Begane grond | 3075 | 120 | 0.012 | 0.0369 | 0.369 | 0.369 | 0.0369 | 0 | 0 | 4450 | Finish Face: Interior | 0.369 | 220 | Bouwkundig | Model Group:Penant Dubbel v1:5537921
5537920 | 00 Begane grond | 3075 | 265 | 0.0265 | 0.0814875 | 0.814875 | 0.814875 | 0.0814875 | 0 | 0 | 4450 | Finish Face: Interior | 0.814875 | 215 | Bouwkundig | Model Group:Penant Dubbel v1:5537921
5537926 | 00 Begane grond | 3075 | 265 | 0.0265 | 0.0814875 | 0.814875 | 0.814875 | 0.0814875 | 0 | 0 | 4450 | Finish Face: Interior | 0.814875 | 215 | Bouwkundig | Model Group:Penant Dubbel v1:5537929
5537927 | 00 Begane grond | 3075 | 120 | 0.012 | 0.0369 | 0.369 | 0.369 | 0.0369 | 0 | 0 | 4450 | Finish Face: Interior | 0.369 | 220 | Bouwkundig | Model Group:Penant Dubbel v1:5537929
5537928 | 00 Begane grond | 3075 | 265 | 0.0265 | 0.0814875 | 0.814875 | 0.814875 | 0.0814875 | 0 | 0 | 4450 | Finish Face: Interior | 0.814875 | 215 | Bouwkundig | Model Group:Penant Dubbel v1:5537929
5537938 | 00 Begane grond | 3075 | 265 | 0.0265 | 0.0814875 | 0.814875 | 0.814875 | 0.0814875 | 0 | 0 | 4450 | Finish Face: Interior | 0.814875 | 215 | Bouwkundig | Model Group:Penant Dubbel v1:5537941
5537939 | 00 Begane grond | 3075 | 120 | 0.012 | 0.0369 | 0.369 | 0.369 | 0.0369 | 0 | 0 | 4450 | Finish Face: Interior | 0.369 | 220 | Bouwkundig | Model Group:Penant Dubbel v1:5537941
5537940 | 00 Begane grond | 3075 | 265 | 0.0265 | 0.0814875 | 0.814875 | 0.814875 | 0.0814875 | 0 | 0 | 4450 | Finish Face: Interior | 0.814875 | 215 | Bouwkundig | Model Group:Penant Dubbel v1:5537941
5537946 | 00 Begane grond | 3075 | 265 | 0.0265 | 0.0814875 | 0.814875 | 0.814875 | 0.0814875 | 0 | 0 | 4450 | Finish Face: Interior | 0.814875 | 215 | Bouwkundig | Model Group:Penant Dubbel v1:5537949
5537947 | 00 Begane grond | 3075 | 120 | 0.012 | 0.0369 | 0.369 | 0.369 | 0.0369 | 0 | 0 | 4450 | Finish Face: Interior | 0.369 | 220 | Bouwkundig | Model Group:Penant Dubbel v1:5537949
5537948 | 00 Begane grond | 3075 | 265 | 0.0265 | 0.0814875 | 0.814875 | 0.814875 | 0.0814875 | 0 | 0 | 4450 | Finish Face: Interior | 0.814875 | 215 | Bouwkundig | Model Group:Penant Dubbel v1:5537949
5537950 | 00 Begane grond | 3075 | 265 | 0.0265 | 0.0814875 | 0.814875 | 0.814875 | 0.0814875 | 0 | 0 | 4450 | Finish Face: Interior | 0.814875 | 215 | Bouwkundig | Model Group:Penant Dubbel v1:5537953
5537951 | 00 Begane grond | 3075 | 120 | 0.012 | 0.0369 | 0.369 | 0.369 | 0.0369 | 0 | 0 | 4450 | Finish Face: Interior | 0.369 | 220 | Bouwkundig | Model Group:Penant Dubbel v1:5537953
5537952 | 00 Begane grond | 3075 | 265 | 0.0265 | 0.0814875 | 0.814875 | 0.814875 | 0.0814875 | 0 | 0 | 4450 | Finish Face: Interior | 0.814875 | 215 | Bouwkundig | Model Group:Penant Dubbel v1:5537953
5537958 | 01 eerste verdieping | 1800 | 265 | 0.0265 | 0.0477 | 0.477 | 0.477 | 0.0477 | -2700 | 1 | -1000 | Finish Face: Interior | 0.477 | 265 | Bouwkundig | Constraints - Top Constraint: Up to level: V2 bk. ruwe vloer
5537960 | 01 eerste verdieping | 4875 | 265 | 0.0265 | 0.129188 | 1.29188 | 1.29188 | 0.129188 | 0 | 1 | -1000 | Finish Face: Interior | 1.29188 | 215 | Bouwkundig
5537961 | 01 eerste verdieping | 4875 | 120 | 0.012 | 0.0585 | 0.585 | 0.585 | 0.0585 | 0 | 1 | -1000 | Finish Face: Interior | 0.585 | 220 | Bouwkundig
5537962 | 01 eerste verdieping | 4875 | 265 | 0.0265 | 0.129187 | 1.29187 | 1.29187 | 0.129187 | 0 | 1 | -1000 | Finish Face: Interior | 1.29187 | 215 | Bouwkundig
5537965 | 00 Begane grond | 3075 | 265 | 0.0265 | 0.0814875 | 0.814875 | 0.814875 | 0.0814875 | 0 | 0 | 4450 | Finish Face: Interior | 0.814875 | 215 | Bouwkundig | Model Group:Penant Dubbel v1:5537968
5537966 | 00 Begane grond | 3075 | 120 | 0.012 | 0.0369 | 0.369 | 0.369 | 0.0369 | 0 | 0 | 4450 | Finish Face: Interior | 0.369 | 220 | Bouwkundig | Model Group:Penant Dubbel v1:5537968
5537967 | 00 Begane grond | 3075 | 265 | 0.0265 | 0.0814875 | 0.814875 | 0.814875 | 0.0814875 | 0 | 0 | 4450 | Finish Face: Interior | 0.814875 | 215 | Bouwkundig | Model Group:Penant Dubbel v1:5537968
5537973 | 00 Begane grond | 3075 | 270 | 0.027 | 0.083025 | 0.83025 | 0.83025 | 0.083025 | 0 | 0 | 4450 | Finish Face: Interior | 0.83025 | 270 | Bouwkundig | Model Group:Penant Dubbel v1 Enkel:5537964
5538266 | 01 eerste verdieping | 625 | 1610 | 0.161 | 0.100625 | 1.00625 | 1.00625 | 0.100625 | 0 | 1 | 0 | Finish Face: Interior | 1.00625 | 1940 | Bouwkundig
5538607 | 00 Begane grond | 3650 | 1511.89 | 0.15119 | 0.0365 | 0.365 | 5.66174 | 0.551844 | 0 | 0 | -0.0000245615 | Finish Face: Interior | 5.66174 | 1511.89 | Bouwkundig | Constraints - Top Constraint: Up to level: 1; Graphics - Center Mark Visible: no
5538610 | 00 Begane grond | 3650 | 786.466 | 0.0785136 | 0.0365138 | 0.365138 | 3.00412 | 0.28658 | 0 | 0 | -0.0000245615 | Finish Face: Interior | 3.00412 | 785.136 | Bouwkundig | Constraints - Top Constraint: Up to level: 1; Graphics - Center Mark Visible: no
5538613 | 00 Begane grond | 3650 | 5235 | 0.5235 | 1.91078 | 19.1078 | 19.1078 | 1.91078 | 0 | 0 | 0 | Finish Face: Interior | 19.1078 | 5185 | Bouwkundig | Constraints - Top Constraint: Up to level: 1
5538616 | 00 Begane grond | 2650 | 265 | 0.0265 | 0.070225 | 0.70225 | 0.70225 | 0.070225 | 0 | 0 | 0 | Finish Face: Interior | 0.70225 | 215 | Bouwkundig | Model Group:Penant Dubbel:5538619
5538617 | 00 Begane grond | 2650 | 120 | 0.012 | 0.0318 | 0.318 | 0.318 | 0.0318 | 0 | 0 | 0 | Finish Face: Interior | 0.318 | 220 | Bouwkundig | Model Group:Penant Dubbel:5538619
5538618 | 00 Begane grond | 2650 | 265 | 0.0265 | 0.070225 | 0.70225 | 0.70225 | 0.070225 | 0 | 0 | 0 | Finish Face: Interior | 0.70225 | 215 | Bouwkundig | Model Group:Penant Dubbel:5538619
5538620 | 00 Begane grond | 2650 | 265 | 0.0265 | 0.070225 | 0.70225 | 0.70225 | 0.070225 | 0 | 0 | 0 | Finish Face: Interior | 0.70225 | 215 | Bouwkundig | Model Group:Penant Dubbel:5538623
5538621 | 00 Begane grond | 2650 | 120 | 0.012 | 0.0318 | 0.318 | 0.318 | 0.0318 | 0 | 0 | 0 | Finish Face: Interior | 0.318 | 220 | Bouwkundig | Model Group:Penant Dubbel:5538623
5538622 | 00 Begane grond | 2650 | 265 | 0.0265 | 0.070225 | 0.70225 | 0.70225 | 0.070225 | 0 | 0 | 0 | Finish Face: Interior | 0.70225 | 215 | Bouwkundig | Model Group:Penant Dubbel:5538623
5538642 | 00 Begane grond | 2650 | 265 | 0.0265 | 0.070225 | 0.70225 | 0.70225 | 0.070225 | 0 | 0 | 0 | Finish Face: Interior | 0.70225 | 215 | Bouwkundig | Model Group:Penant Dubbel:5538645
5538643 | 00 Begane grond | 2650 | 120 | 0.012 | 0.0318 | 0.318 | 0.318 | 0.0318 | 0 | 0 | 0 | Finish Face: Interior | 0.318 | 220 | Bouwkundig | Model Group:Penant Dubbel:5538645
5538644 | 00 Begane grond | 2650 | 265 | 0.0265 | 0.070225 | 0.70225 | 0.70225 | 0.070225 | 0 | 0 | 0 | Finish Face: Interior | 0.70225 | 215 | Bouwkundig | Model Group:Penant Dubbel:5538645
5538646 | 00 Begane grond | 2650 | 265 | 0.0265 | 0.070225 | 0.70225 | 0.70225 | 0.070225 | 0 | 0 | 0 | Finish Face: Interior | 0.70225 | 215 | Bouwkundig | Model Group:Penant Dubbel:5538649
5538647 | 00 Begane grond | 2650 | 120 | 0.012 | 0.0318 | 0.318 | 0.318 | 0.0318 | 0 | 0 | 0 | Finish Face: Interior | 0.318 | 220 | Bouwkundig | Model Group:Penant Dubbel:5538649
5538648 | 00 Begane grond | 2650 | 265 | 0.0265 | 0.070225 | 0.70225 | 0.70225 | 0.070225 | 0 | 0 | 0 | Finish Face: Interior | 0.70225 | 215 | Bouwkundig | Model Group:Penant Dubbel:5538649
5538650 | 00 Begane grond | 2650 | 265 | 0.0265 | 0.070225 | 0.70225 | 0.70225 | 0.070225 | 0 | 0 | 0 | Finish Face: Interior | 0.70225 | 215 | Bouwkundig | Model Group:Penant Dubbel:5538653
5538651 | 00 Begane grond | 2650 | 120 | 0.012 | 0.0318 | 0.318 | 0.318 | 0.0318 | 0 | 0 | 0 | Finish Face: Interior | 0.318 | 220 | Bouwkundig | Model Group:Penant Dubbel:5538653
5538652 | 00 Begane grond | 2650 | 265 | 0.0265 | 0.070225 | 0.70225 | 0.70225 | 0.070225 | 0 | 0 | 0 | Finish Face: Interior | 0.70225 | 215 | Bouwkundig | Model Group:Penant Dubbel:5538653
5538654 | 00 Begane grond | 2650 | 265 | 0.0265 | 0.070225 | 0.70225 | 0.70225 | 0.070225 | 0 | 0 | 0 | Finish Face: Interior | 0.70225 | 215 | Bouwkundig | Model Group:Penant Dubbel:5538657
5538655 | 00 Begane grond | 2650 | 120 | 0.012 | 0.0318 | 0.318 | 0.318 | 0.0318 | 0 | 0 | 0 | Finish Face: Interior | 0.318 | 220 | Bouwkundig | Model Group:Penant Dubbel:5538657
5538656 | 00 Begane grond | 2650 | 265 | 0.0265 | 0.070225 | 0.70225 | 0.70225 | 0.070225 | 0 | 0 | 0 | Finish Face: Interior | 0.70225 | 215 | Bouwkundig | Model Group:Penant Dubbel:5538657
5538658 | 00 Begane grond | 2650 | 265 | 0.0265 | 0.070225 | 0.70225 | 0.70225 | 0.070225 | 0 | 0 | 0 | Finish Face: Interior | 0.70225 | 215 | Bouwkundig | Model Group:Penant Dubbel:5538661
5538659 | 00 Begane grond | 2650 | 120 | 0.012 | 0.0318 | 0.318 | 0.318 | 0.0318 | 0 | 0 | 0 | Finish Face: Interior | 0.318 | 220 | Bouwkundig | Model Group:Penant Dubbel:5538661
5538660 | 00 Begane grond | 2650 | 265 | 0.0265 | 0.070225 | 0.70225 | 0.70225 | 0.070225 | 0 | 0 | 0 | Finish Face: Interior | 0.70225 | 215 | Bouwkundig | Model Group:Penant Dubbel:5538661
5538662 | 00 Begane grond | 2650 | 265 | 0.0265 | 0.070225 | 0.70225 | 0.70225 | 0.070225 | 0 | 0 | 0 | Finish Face: Interior | 0.70225 | 215 | Bouwkundig | Model Group:Penant Dubbel:5538665
5538663 | 00 Begane grond | 2650 | 120 | 0.012 | 0.0318 | 0.318 | 0.318 | 0.0318 | 0 | 0 | 0 | Finish Face: Interior | 0.318 | 220 | Bouwkundig | Model Group:Penant Dubbel:5538665
5538664 | 00 Begane grond | 2650 | 265 | 0.0265 | 0.0702015 | 0.702015 | 0.702015 | 0.0702015 | 0 | 0 | 0 | Finish Face: Interior | 0.702015 | 215 | Bouwkundig | Model Group:Penant Dubbel:5538665
5538666 | 00 Begane grond | 2650 | 265 | 0.0265 | 0.070225 | 0.70225 | 0.70225 | 0.070225 | 0 | 0 | 0 | Finish Face: Interior | 0.70225 | 215 | Bouwkundig | Model Group:Penant Dubbel:5538669
5538667 | 00 Begane grond | 2650 | 120 | 0.012 | 0.0318 | 0.318 | 0.318 | 0.0318 | 0 | 0 | 0 | Finish Face: Interior | 0.318 | 220 | Bouwkundig | Model Group:Penant Dubbel:5538669
5538668 | 00 Begane grond | 2650 | 265 | 0.0265 | 0.070225 | 0.70225 | 0.70225 | 0.070225 | 0 | 0 | 0 | Finish Face: Interior | 0.70225 | 215 | Bouwkundig | Model Group:Penant Dubbel:5538669
5538670 | 00 Begane grond | 2650 | 265 | 0.0265 | 0.070225 | 0.70225 | 0.70225 | 0.070225 | 0 | 0 | 0 | Finish Face: Interior | 0.70225 | 215 | Bouwkundig | Model Group:Penant Dubbel:5538673
5538671 | 00 Begane grond | 2650 | 120 | 0.012 | 0.0318 | 0.318 | 0.318 | 0.0318 | 0 | 0 | 0 | Finish Face: Interior | 0.318 | 220 | Bouwkundig | Model Group:Penant Dubbel:5538673
5538672 | 00 Begane grond | 2650 | 265 | 0.0265 | 0.070225 | 0.70225 | 0.70225 | 0.070225 | 0 | 0 | 0 | Finish Face: Interior | 0.70225 | 215 | Bouwkundig | Model Group:Penant Dubbel:5538673
5538674 | 00 Begane grond | 2650 | 265 | 0.0265 | 0.070225 | 0.70225 | 0.70225 | 0.070225 | 0 | 0 | 0 | Finish Face: Interior | 0.70225 | 215 | Bouwkundig | Model Group:Penant Dubbel:5538677
5538675 | 00 Begane grond | 2650 | 120 | 0.012 | 0.0318 | 0.318 | 0.318 | 0.0318 | 0 | 0 | 0 | Finish Face: Interior | 0.318 | 220 | Bouwkundig | Model Group:Penant Dubbel:5538677
5538676 | 00 Begane grond | 2650 | 265 | 0.0265 | 0.070225 | 0.70225 | 0.70225 | 0.070225 | 0 | 0 | 0 | Finish Face: Interior | 0.70225 | 215 | Bouwkundig | Model Group:Penant Dubbel:5538677
5538678 | 00 Begane grond | 2650 | 265 | 0.0265 | 0.070225 | 0.70225 | 0.70225 | 0.070225 | 0 | 0 | 0 | Finish Face: Interior | 0.70225 | 215 | Bouwkundig | Model Group:Penant Dubbel:5538681
5538679 | 00 Begane grond | 2650 | 120 | 0.012 | 0.0318 | 0.318 | 0.318 | 0.0318 | 0 | 0 | 0 | Finish Face: Interior | 0.318 | 220 | Bouwkundig | Model Group:Penant Dubbel:5538681
5538680 | 00 Begane grond | 2650 | 265 | 0.0265 | 0.070225 | 0.70225 | 0.70225 | 0.070225 | 0 | 0 | 0 | Finish Face: Interior | 0.70225 | 215 | Bouwkundig | Model Group:Penant Dubbel:5538681
5538815 | 00 Begane grond | 2650 | 265 | 0.0265 | 0.070225 | 0.70225 | 0.70225 | 0.070225 | 0 | 0 | 0 | Finish Face: Interior | 0.70225 | 265 | Bouwkundig | Model Group:Penant Enkel:5538814
5538837 | 01 eerste verdieping | 3500 | 33600 | 3.36 | 11.5603 | 115.603 | 77.6075 | 7.76075 | 0 | 1 | 0 | Finish Face: Interior | 77.6075 | 33600 | Bouwkundig | Constraints - Top Constraint: Up to level: V2 bk. ruwe vloer
5539111 | 00 Begane grond | 2650 | 265 | 0.0265 | 0.070225 | 0.70225 | 0.70225 | 0.070225 | 0 | 0 | 0 | Finish Face: Interior | 0.70225 | 215 | Bouwkundig | Model Group:Penant Dubbel:5539114
5539112 | 00 Begane grond | 2650 | 120 | 0.012 | 0.0318 | 0.318 | 0.318 | 0.0318 | 0 | 0 | 0 | Finish Face: Interior | 0.318 | 220 | Bouwkundig | Model Group:Penant Dubbel:5539114
5539113 | 00 Begane grond | 2650 | 265 | 0.0265 | 0.070225 | 0.70225 | 0.70225 | 0.070225 | 0 | 0 | 0 | Finish Face: Interior | 0.70225 | 215 | Bouwkundig | Model Group:Penant Dubbel:5539114
5539116 | 00 Begane grond | 2650 | 185.037 | 0.0185037 | 0.0490348 | 0.490348 | 0.490348 | 0.0490348 | 0 | 0 | 0 | Finish Face: Interior | 0.490348 | 265.037 | Bouwkundig | Model Group:Penant Enkel:5539115
5539118 | 01 eerste verdieping | 425 | 10815.4 | 1.08154 | 0.459653 | 4.59653 | 4.59653 | 0.459653 | 0 | 1 | 0 | Finish Face: Interior | 4.59653 | 10865.4 | Bouwkundig
5539119 | 01 eerste verdieping | 425 | 7799.96 | 0.779996 | 0.331498 | 3.31498 | 3.31498 | 0.331498 | 0 | 1 | 0 | Finish Face: Interior | 3.31498 | 7799.96 | Bouwkundig
5539120 | 01 eerste verdieping | 425 | 1511.89 | 0.15119 | 0.00425 | 0.0425 | 0.659244 | 0.0642558 | 0 | 1 | -0.0000245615 | Finish Face: Interior | 0.659244 | 1511.89 | Bouwkundig | Graphics - Center Mark Visible: no
5539121 | 01 eerste verdieping | 425 | 3058.87 | 0.305749 | 0.130002 | 1.30002 | 1.30002 | 0.129943 | 0 | 1 | 0 | Finish Face: Interior | 1.30002 | 3057.51 | Bouwkundig
5539122 | 01 eerste verdieping | 425 | 786.466 | 0.0785136 | 0.00425161 | 0.0425161 | 0.349794 | 0.0333689 | 0 | 1 | -0.0000245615 | Finish Face: Interior | 0.349794 | 785.136 | Bouwkundig | Graphics - Center Mark Visible: no
5539123 | 01 eerste verdieping | 425 | 3814.29 | 0.381429 | 0.162107 | 1.62107 | 1.62107 | 0.162107 | 0 | 1 | -0.0000245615 | Finish Face: Interior | 1.62107 | 3864.29 | Bouwkundig
5539138 | 00 Begane grond | 3650 | 3058.87 | 0.305749 | 1.11649 | 11.1649 | 7.59488 | 0.758985 | 0 | 0 | 0 | Finish Face: Interior | 7.59488 | 3057.51 | Bouwkundig | Constraints - Top Constraint: Up to level: 1
5539152 | 00 Begane grond | 2650 | 265 | 0.0265 | 0.070225 | 0.70225 | 0.70225 | 0.070225 | 0 | 0 | 0 | Finish Face: Interior | 0.70225 | 215 | Bouwkundig | Model Group:Penant Hoek:5539155
5539153 | 00 Begane grond | 2650 | 120 | 0.012 | 0.0318 | 0.318 | 0.318 | 0.0318 | 0 | 0 | 0 | Finish Face: Interior | 0.318 | 220 | Bouwkundig | Model Group:Penant Hoek:5539155
5539154 | 00 Begane grond | 2650 | 265 | 0.0265 | 0.070225 | 0.70225 | 0.70225 | 0.070225 | 0 | 0 | 0 | Finish Face: Interior | 0.70225 | 165 | Bouwkundig | Model Group:Penant Hoek:5539155
5539156 | 00 Begane grond | 2650 | 165 | 0.0165 | 0.043725 | 0.43725 | 0.43725 | 0.043725 | 0 | 0 | 0 | Finish Face: Interior | 0.43725 | 165 | Bouwkundig | Model Group:Penant Hoek:5539155
5539157 | 00 Begane grond | 2650 | 120 | 0.012 | 0.0318 | 0.318 | 0.318 | 0.0318 | 0 | 0 | 0 | Finish Face: Interior | 0.318 | 220 | Bouwkundig | Model Group:Penant Hoek:5539155
5539158 | 00 Begane grond | 2650 | 265 | 0.0265 | 0.070225 | 0.70225 | 0.70225 | 0.070225 | 0 | 0 | 0 | Finish Face: Interior | 0.70225 | 215 | Bouwkundig | Model Group:Penant Hoek:5539155
5539164 | 00 Begane grond | 825 | 3165 | 0.3165 | 0.261113 | 2.61113 | 2.61113 | 0.261113 | 0 | 0 | 2825 | Finish Face: Interior | 2.61113 | 3215 | Bouwkundig | Constraints - Top Constraint: Up to level: 1
5539180 | 00 Begane grond | 2650 | 265 | 0.0265 | 0.070225 | 0.70225 | 0.70225 | 0.070225 | 0 | 0 | 0 | Finish Face: Interior | 0.70225 | 215 | Bouwkundig | Model Group:Penant Hoek:5539183
5539181 | 00 Begane grond | 2650 | 120 | 0.012 | 0.0318 | 0.318 | 0.318 | 0.0318 | 0 | 0 | 0 | Finish Face: Interior | 0.318 | 220 | Bouwkundig | Model Group:Penant Hoek:5539183
5539182 | 00 Begane grond | 2650 | 265 | 0.0265 | 0.070225 | 0.70225 | 0.70225 | 0.070225 | 0 | 0 | 0 | Finish Face: Interior | 0.70225 | 165 | Bouwkundig | Model Group:Penant Hoek:5539183
5539184 | 00 Begane grond | 2650 | 165 | 0.0165 | 0.043725 | 0.43725 | 0.43725 | 0.043725 | 0 | 0 | 0 | Finish Face: Interior | 0.43725 | 165 | Bouwkundig | Model Group:Penant Hoek:5539183
5539185 | 00 Begane grond | 2650 | 120 | 0.012 | 0.0318 | 0.318 | 0.318 | 0.0318 | 0 | 0 | 0 | Finish Face: Interior | 0.318 | 220 | Bouwkundig | Model Group:Penant Hoek:5539183
5539186 | 00 Begane grond | 2650 | 265 | 0.0265 | 0.070225 | 0.70225 | 0.70225 | 0.070225 | 0 | 0 | 0 | Finish Face: Interior | 0.70225 | 215 | Bouwkundig | Model Group:Penant Hoek:5539183
5539187 | 00 Begane grond | 2650 | 265 | 0.0265 | 0.070225 | 0.70225 | 0.70225 | 0.070225 | 0 | 0 | 0 | Finish Face: Interior | 0.70225 | 265 | Bouwkundig | Model Group:Penant Enkel:5536803
5539189 | 00 Begane grond | 2650 | 265 | 0.0265 | 0.070225 | 0.70225 | 0.70225 | 0.070225 | 0 | 0 | 0 | Finish Face: Interior | 0.70225 | 215 | Bouwkundig | Model Group:Penant Dubbel:5539188
5539190 | 00 Begane grond | 2650 | 120 | 0.012 | 0.0318 | 0.318 | 0.318 | 0.0318 | 0 | 0 | 0 | Finish Face: Interior | 0.318 | 220 | Bouwkundig | Model Group:Penant Dubbel:5539188
5539191 | 00 Begane grond | 2650 | 265 | 0.0265 | 0.070225 | 0.70225 | 0.70225 | 0.070225 | 0 | 0 | 0 | Finish Face: Interior | 0.70225 | 215 | Bouwkundig | Model Group:Penant Dubbel:5539188
5539195 | 00 Begane grond | 2650 | 265 | 0.0265 | 0.070225 | 0.70225 | 0.70225 | 0.070225 | 0 | 0 | 0 | Finish Face: Interior | 0.70225 | 265 | Bouwkundig | Model Group:Penant Enkel:5539192
5539261 | -1 fundering | 1270 | 765 | 0.0765 | 0.097155 | 0.97155 | 0.97155 | 0.097155 | 0 | bk. fundering | 0 | Finish Face: Interior | 0.97155 | 765 | Bouwkundig | Constraints - Top Constraint: Up to level: 0
5539262 | -1 fundering | 1270 | 47850 | 4.785 | 6.07695 | 60.7695 | 60.7695 | 6.07695 | 0 | bk. fundering | 0 | Finish Face: Interior | 60.7695 | 47750 | Bouwkundig | Constraints - Top Constraint: Up to level: 0
5539263 | -1 fundering | 1270 | 10914.3 | 1.09143 | 1.38611 | 13.8611 | 13.8611 | 1.38611 | 0 | bk. fundering | 0 | Finish Face: Interior | 13.8611 | 10864.3 | Bouwkundig | Constraints - Top Constraint: Up to level: 0
5539264 | -1 fundering | 1270 | 450 | 0.045 | 0.05715 | 0.5715 | 0.5715 | 0.05715 | 0 | bk. fundering | 0 | Finish Face: Interior | 0.5715 | 450 | Bouwkundig | Constraints - Top Constraint: Up to level: 0
5539266 | -1 fundering | 1270 | 4534.96 | 0.453496 | 0.57594 | 5.7594 | 5.7594 | 0.57594 | 0 | bk. fundering | 0 | Finish Face: Interior | 5.7594 | 4634.96 | Bouwkundig | Constraints - Top Constraint: Up to level: 0
5539267 | -1 fundering | 1270 | 10560 | 1.056 | 1.34112 | 13.4112 | 13.4112 | 1.34112 | 0 | bk. fundering | 0 | Finish Face: Interior | 13.4112 | 10610 | Bouwkundig | Constraints - Top Constraint: Up to level: 0
5539268 | -1 fundering | 1270 | 1511.89 | 0.15119 | 0.0127 | 0.127 | 1.96997 | 0.192011 | 0 | bk. fundering | -0.0000245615 | Finish Face: Interior | 1.96997 | 1511.89 | Bouwkundig | Constraints - Top Constraint: Up to level: 0; Graphics - Center Mark Visible: no
5539269 | -1 fundering | 1270 | 802.733 | 0.080179 | 0.0127025 | 0.127025 | 1.06689 | 0.101827 | 0 | bk. fundering | -0.0000245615 | Finish Face: Interior | 1.06689 | 801.777 | Bouwkundig | Constraints - Top Constraint: Up to level: 0; Graphics - Center Mark Visible: no
5539270 | -1 fundering | 1270 | 5235 | 0.5235 | 0.664845 | 6.64845 | 6.64845 | 0.664845 | 0 | bk. fundering | 0 | Finish Face: Interior | 6.64845 | 5235 | Bouwkundig | Constraints - Top Constraint: Up to level: 0
5539271 | -1 fundering | 1270 | 3042.65 | 0.304166 | 0.386417 | 3.86417 | 3.86417 | 0.386291 | 0 | bk. fundering | 0 | Finish Face: Interior | 3.86417 | 3041.67 | Bouwkundig | Constraints - Top Constraint: Up to level: 0
5539272 | -1 fundering | 1270 | 4.28625 | 0.000428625 | 0.0127 | 0.127 | 0.127 | 0.000544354 | 0 | bk. fundering | -0.0000245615 | Finish Face: Interior | 0.00544354 | 54.2862 | Bouwkundig | Constraints - Top Constraint: Up to level: 0
5539326 | -1 fundering | 1270 | 2735 | 0.2735 | 0.347345 | 3.47345 | 3.47345 | 0.347345 | 0 | bk. fundering | 0 | Finish Face: Interior | 3.47345 | 2835 | Bouwkundig | Constraints - Top Constraint: Up to level: 0
5539327 | -1 fundering | 1270 | 120 | 0.012 | 0.01524 | 0.1524 | 0.1524 | 0.01524 | 0 | bk. fundering | 0 | Finish Face: Interior | 0.1524 | 220 | Bouwkundig | Model Group:Penant Dubbel:5538619 | Constraints - Top Constraint: Up to level: 0
5539329 | -1 fundering | 1270 | 120 | 0.012 | 0.01524 | 0.1524 | 0.1524 | 0.01524 | 0 | bk. fundering | 0 | Finish Face: Interior | 0.1524 | 220 | Bouwkundig | Constraints - Top Constraint: Up to level: 0
5539330 | -1 fundering | 1270 | 170 | 0.017 | 0.02159 | 0.2159 | 0.2159 | 0.02159 | 0 | bk. fundering | -0.0000245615 | Finish Face: Interior | 0.2159 | 270 | Bouwkundig | Constraints - Top Constraint: Up to level: 0
5539332 | -1 fundering | 1270 | 2735 | 0.2735 | 0.347345 | 3.47345 | 3.47345 | 0.347345 | 0 | bk. fundering | 0 | Finish Face: Interior | 3.47345 | 2835 | Bouwkundig | Constraints - Top Constraint: Up to level: 0
5539333 | -1 fundering | 1270 | 30305 | 3.0305 | 3.84874 | 38.4874 | 38.4874 | 3.84874 | 0 | bk. fundering | 0 | Finish Face: Interior | 38.4874 | 30355 | Bouwkundig | Constraints - Top Constraint: Up to level: 0
5539334 | -1 fundering | 1270 | 6935 | 0.6935 | 0.880745 | 8.80745 | 8.80745 | 0.880745 | 0 | bk. fundering | 0 | Finish Face: Interior | 8.80745 | 7035 | Bouwkundig | Constraints - Top Constraint: Up to level: 0
5658097 | -1 fundering | 1270 | 120 | 0.012 | 0.01524 | 0.1524 | 0.1524 | 0.01524 | 0 | bk. fundering | 0 | Finish Face: Interior | 0.1524 | 220 | Bouwkundig | Model Group:Penant Dubbel:5536807 | Constraints - Top Constraint: Up to level: 0
5658100 | -1 fundering | 1270 | 120 | 0.012 | 0.01524 | 0.1524 | 0.1524 | 0.01524 | 0 | bk. fundering | 0 | Finish Face: Interior | 0.1524 | 220 | Bouwkundig | Model Group:Penant Dubbel:5536817 | Constraints - Top Constraint: Up to level: 0
5658103 | -1 fundering | 1270 | 120 | 0.012 | 0.01524 | 0.1524 | 0.1524 | 0.01524 | 0 | bk. fundering | 0 | Finish Face: Interior | 0.1524 | 220 | Bouwkundig | Model Group:Penant Dubbel:5536821 | Constraints - Top Constraint: Up to level: 0
5658106 | -1 fundering | 1270 | 120 | 0.012 | 0.01524 | 0.1524 | 0.1524 | 0.01524 | 0 | bk. fundering | 0 | Finish Face: Interior | 0.1524 | 220 | Bouwkundig | Model Group:Penant Dubbel:5536825 | Constraints - Top Constraint: Up to level: 0
5658109 | -1 fundering | 1270 | 120 | 0.012 | 0.01524 | 0.1524 | 0.1524 | 0.01524 | 0 | bk. fundering | 0 | Finish Face: Interior | 0.1524 | 220 | Bouwkundig | Model Group:Penant Dubbel:5536829 | Constraints - Top Constraint: Up to level: 0
5658112 | -1 fundering | 1270 | 120 | 0.012 | 0.01524 | 0.1524 | 0.1524 | 0.01524 | 0 | bk. fundering | 0 | Finish Face: Interior | 0.1524 | 220 | Bouwkundig | Model Group:Penant Dubbel:5536875 | Constraints - Top Constraint: Up to level: 0
5658115 | -1 fundering | 1270 | 120 | 0.012 | 0.01524 | 0.1524 | 0.1524 | 0.01524 | 0 | bk. fundering | 0 | Finish Face: Interior | 0.1524 | 220 | Bouwkundig | Model Group:Penant Dubbel:5536915 | Constraints - Top Constraint: Up to level: 0
5658118 | -1 fundering | 1270 | 120 | 0.012 | 0.01524 | 0.1524 | 0.1524 | 0.01524 | 0 | bk. fundering | 0 | Finish Face: Interior | 0.1524 | 220 | Bouwkundig | Model Group:Penant Dubbel:5536947 | Constraints - Top Constraint: Up to level: 0
5658121 | -1 fundering | 1270 | 120 | 0.012 | 0.01524 | 0.1524 | 0.1524 | 0.01524 | 0 | bk. fundering | 0 | Finish Face: Interior | 0.1524 | 220 | Bouwkundig | Model Group:Penant Dubbel:5536961 | Constraints - Top Constraint: Up to level: 0
5658124 | -1 fundering | 1270 | 120 | 0.012 | 0.01524 | 0.1524 | 0.1524 | 0.01524 | 0 | bk. fundering | 0 | Finish Face: Interior | 0.1524 | 220 | Bouwkundig | Model Group:Penant Dubbel:5537029 | Constraints - Top Constraint: Up to level: 0
5658127 | -1 fundering | 1270 | 120 | 0.012 | 0.01524 | 0.1524 | 0.1524 | 0.01524 | 0 | bk. fundering | 0 | Finish Face: Interior | 0.1524 | 220 | Bouwkundig | Model Group:Penant Dubbel:5537041 | Constraints - Top Constraint: Up to level: 0
5658130 | -1 fundering | 1270 | 120 | 0.012 | 0.01524 | 0.1524 | 0.1524 | 0.01524 | 0 | bk. fundering | 0 | Finish Face: Interior | 0.1524 | 220 | Bouwkundig | Model Group:Penant Dubbel:5537064 | Constraints - Top Constraint: Up to level: 0
5658133 | -1 fundering | 1270 | 120 | 0.012 | 0.01524 | 0.1524 | 0.1524 | 0.01524 | 0 | bk. fundering | 0 | Finish Face: Interior | 0.1524 | 220 | Bouwkundig | Model Group:Penant Dubbel:5537076 | Constraints - Top Constraint: Up to level: 0
5658136 | -1 fundering | 1270 | 120 | 0.012 | 0.01524 | 0.1524 | 0.1524 | 0.01524 | 0 | bk. fundering | 0 | Finish Face: Interior | 0.1524 | 220 | Bouwkundig | Model Group:Penant Dubbel:5537098 | Constraints - Top Constraint: Up to level: 0
5658139 | -1 fundering | 1270 | 120 | 0.012 | 0.01524 | 0.1524 | 0.1524 | 0.01524 | 0 | bk. fundering | 0 | Finish Face: Interior | 0.1524 | 220 | Bouwkundig | Model Group:Penant Dubbel:5537524 | Constraints - Top Constraint: Up to level: 0
5658142 | -1 fundering | 1270 | 320 | 0.032 | 0.04064 | 0.4064 | 0.4064 | 0.0390775 | 0 | bk. fundering | 0 | Finish Face: Interior | 0.4064 | 320 | Bouwkundig | Model Group:Penant Dubbel:5538623 | Constraints - Top Constraint: Up to level: 0
5658145 | -1 fundering | 1270 | 120 | 0.012 | 0.01524 | 0.1524 | 0.1524 | 0.01524 | 0 | bk. fundering | 0 | Finish Face: Interior | 0.1524 | 220 | Bouwkundig | Model Group:Penant Dubbel:5538645 | Constraints - Top Constraint: Up to level: 0
5658148 | -1 fundering | 1270 | 120 | 0.012 | 0.01524 | 0.1524 | 0.1524 | 0.01524 | 0 | bk. fundering | 0 | Finish Face: Interior | 0.1524 | 220 | Bouwkundig | Model Group:Penant Dubbel:5538649 | Constraints - Top Constraint: Up to level: 0
5658151 | -1 fundering | 1270 | 120 | 0.012 | 0.01524 | 0.1524 | 0.1524 | 0.01524 | 0 | bk. fundering | 0 | Finish Face: Interior | 0.1524 | 220 | Bouwkundig | Model Group:Penant Dubbel:5538653 | Constraints - Top Constraint: Up to level: 0
5658154 | -1 fundering | 1270 | 120 | 0.012 | 0.01524 | 0.1524 | 0.1524 | 0.01524 | 0 | bk. fundering | 0 | Finish Face: Interior | 0.1524 | 220 | Bouwkundig | Model Group:Penant Dubbel:5538657 | Constraints - Top Constraint: Up to level: 0
5658157 | -1 fundering | 1270 | 120 | 0.012 | 0.01524 | 0.1524 | 0.1524 | 0.01524 | 0 | bk. fundering | 0 | Finish Face: Interior | 0.1524 | 220 | Bouwkundig | Model Group:Penant Dubbel:5538661 | Constraints - Top Constraint: Up to level: 0
5658160 | -1 fundering | 1270 | 120 | 0.012 | 0.01524 | 0.1524 | 0.1524 | 0.01524 | 0 | bk. fundering | 0 | Finish Face: Interior | 0.1524 | 220 | Bouwkundig | Model Group:Penant Dubbel:5538665 | Constraints - Top Constraint: Up to level: 0
5658163 | -1 fundering | 1270 | 120 | 0.012 | 0.01524 | 0.1524 | 0.1524 | 0.01524 | 0 | bk. fundering | 0 | Finish Face: Interior | 0.1524 | 220 | Bouwkundig | Model Group:Penant Dubbel:5538669 | Constraints - Top Constraint: Up to level: 0
5658166 | -1 fundering | 1270 | 120 | 0.012 | 0.01524 | 0.1524 | 0.1524 | 0.01524 | 0 | bk. fundering | 0 | Finish Face: Interior | 0.1524 | 220 | Bouwkundig | Model Group:Penant Dubbel:5538673 | Constraints - Top Constraint: Up to level: 0
5658169 | -1 fundering | 1270 | 120 | 0.012 | 0.01524 | 0.1524 | 0.1524 | 0.01524 | 0 | bk. fundering | 0 | Finish Face: Interior | 0.1524 | 220 | Bouwkundig | Model Group:Penant Dubbel:5538677 | Constraints - Top Constraint: Up to level: 0
5658172 | -1 fundering | 1270 | 120 | 0.012 | 0.01524 | 0.1524 | 0.1524 | 0.01524 | 0 | bk. fundering | 0 | Finish Face: Interior | 0.1524 | 220 | Bouwkundig | Model Group:Penant Dubbel:5538681 | Constraints - Top Constraint: Up to level: 0
5658175 | -1 fundering | 1270 | 120 | 0.012 | 0.01524 | 0.1524 | 0.1524 | 0.01524 | 0 | bk. fundering | 0 | Finish Face: Interior | 0.1524 | 220 | Bouwkundig | Model Group:Penant Dubbel:5539114 | Constraints - Top Constraint: Up to level: 0
5658178 | -1 fundering | 1270 | 120 | 0.012 | 0.01524 | 0.1524 | 0.1524 | 0.01524 | 0 | bk. fundering | 0 | Finish Face: Interior | 0.1524 | 220 | Bouwkundig | Model Group:Penant Dubbel:5539188 | Constraints - Top Constraint: Up to level: 0
5914405 | 00 Begane grond | 2025 | 110 | 0.011 | 0.022275 | 0.22275 | 0.22275 | 0.022275 | -1000 | 0 | 625 | Finish Face: Interior | 0.22275 | 160 | Bouwkundig | Model Group:negge merk k40:5915474 | Constraints - Top Constraint: Up to level: 1
5914760 | 00 Begane grond | 2025 | 110 | 0.011 | 0.022275 | 0.22275 | 0.22275 | 0.022275 | -1000 | 0 | 625 | Finish Face: Interior | 0.22275 | 160 | Bouwkundig | Model Group:negge merk k40:5915474 | Constraints - Top Constraint: Up to level: 1
5916088 | 00 Begane grond | 2025 | 110 | 0.011 | 0.022275 | 0.22275 | 0.22275 | 0.022275 | -1000 | 0 | 625 | Finish Face: Interior | 0.22275 | 160 | Bouwkundig | Model Group:negge merk k40:5916090 | Constraints - Top Constraint: Up to level: 1
5916089 | 00 Begane grond | 2025 | 110 | 0.011 | 0.022275 | 0.22275 | 0.22275 | 0.022275 | -1000 | 0 | 625 | Finish Face: Interior | 0.22275 | 160 | Bouwkundig | Model Group:negge merk k40:5916090 | Constraints - Top Constraint: Up to level: 1
5916096 | 00 Begane grond | 2025 | 120 | 0.012 | 0.0243 | 0.243 | 0.243 | 0.0243 | -1000 | 0 | 625 | Finish Face: Interior | 0.243 | 170 | Bouwkundig | Model Group:negge merk k40:5916098 | Constraints - Top Constraint: Up to level: 1
5916097 | 00 Begane grond | 2025 | 120 | 0.012 | 0.0243 | 0.243 | 0.243 | 0.0243 | -1000 | 0 | 625 | Finish Face: Interior | 0.243 | 170 | Bouwkundig | Model Group:negge merk k40:5916098 | Constraints - Top Constraint: Up to level: 1
5916120 | 00 Begane grond | 2025 | 110 | 0.011 | 0.022275 | 0.22275 | 0.22275 | 0.022275 | -1000 | 0 | 625 | Finish Face: Interior | 0.22275 | 160 | Bouwkundig | Model Group:negge merk k40:5916122 | Constraints - Top Constraint: Up to level: 1
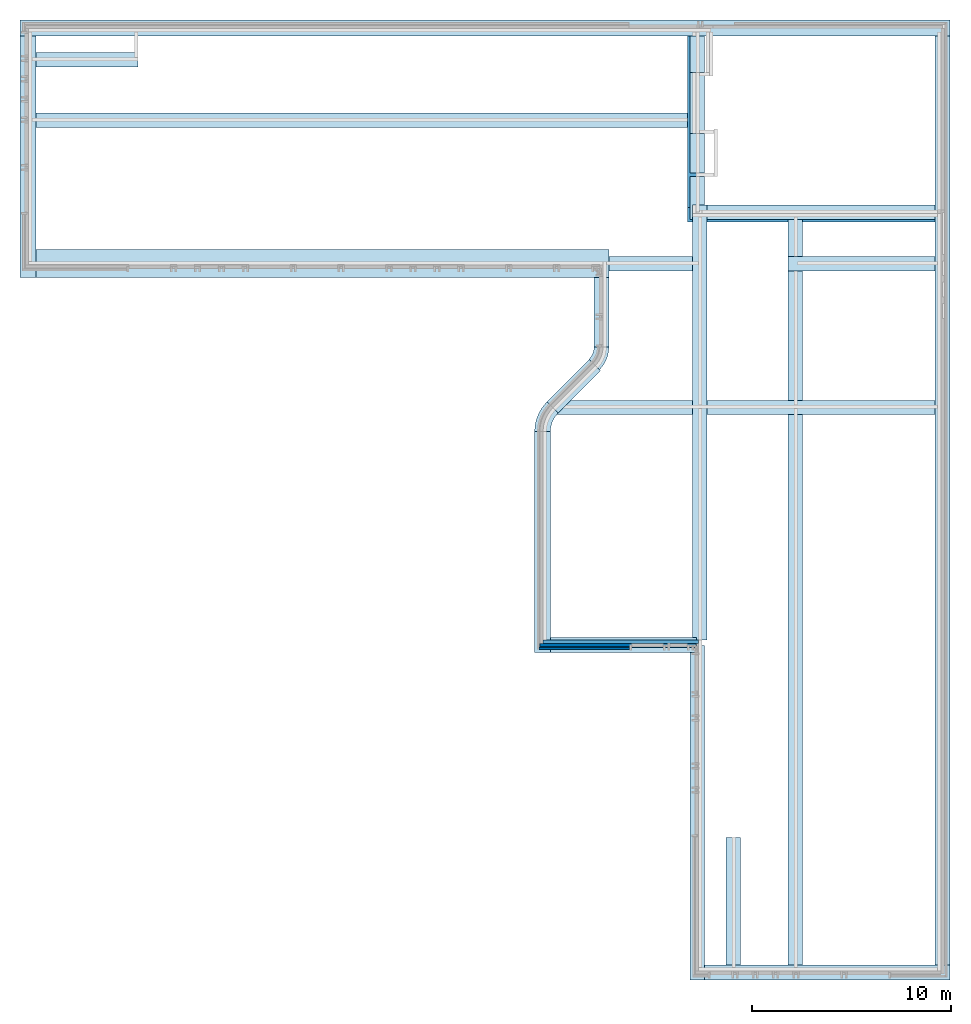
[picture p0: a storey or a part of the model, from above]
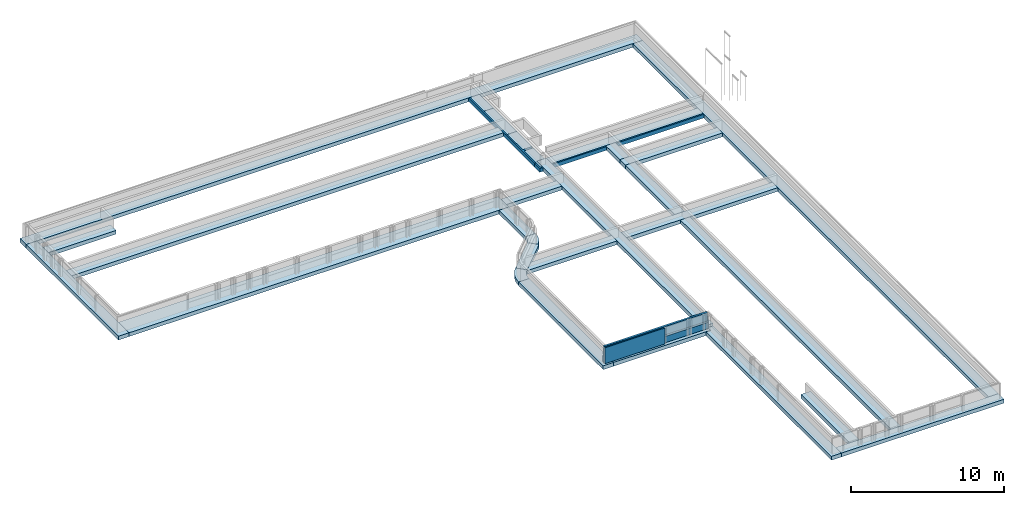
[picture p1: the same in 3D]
Properties of the parts of a building model (IFC2X3), part 32 of 37

# IfcWallStandardCase: Basic Wall:21_DAT_metselwerk_100 (534)
Name (Basic Wall:21_DAT_metselwerk_100:...) | In | Height (mm) = Unconnected Height (mm) | BaseQuantities, Length (mm) | GrossFootprintArea (m2) | GrossVolume (m3) | GrossSideArea (m2) | NetSideArea (m2) | NetVolume (m3) = Volume (m3) | Top Offset (mm) | Base Constraint | Base Offset (mm) | Location Line | Area (m2) | Dimensions, Length (mm) | Workset | Group
5916121 | 00 Begane grond | 2025 | 110 | 0.011 | 0.022275 | 0.22275 | 0.22275 | 0.022275 | -1000 | 0 | 625 | Finish Face: Interior | 0.22275 | 160 | Bouwkundig | Model Group:negge merk k40:5916122 | Constraints - Top Constraint: Up to level: 1
5916189 | 00 Begane grond | 2025 | 110 | 0.011 | 0.022275 | 0.22275 | 0.22275 | 0.022275 | -1000 | 0 | 625 | Finish Face: Interior | 0.22275 | 160 | Bouwkundig | Model Group:negge merk k40:5916191 | Constraints - Top Constraint: Up to level: 1
5916190 | 00 Begane grond | 2025 | 110 | 0.011 | 0.022275 | 0.22275 | 0.22275 | 0.022275 | -1000 | 0 | 625 | Finish Face: Interior | 0.22275 | 160 | Bouwkundig | Model Group:negge merk k40:5916191 | Constraints - Top Constraint: Up to level: 1
5916223 | 00 Begane grond | 2025 | 110 | 0.011 | 0.022275 | 0.22275 | 0.22275 | 0.022275 | -1000 | 0 | 625 | Finish Face: Interior | 0.22275 | 160 | Bouwkundig | Model Group:negge merk k40:5916225 | Constraints - Top Constraint: Up to level: 1
5916224 | 00 Begane grond | 2025 | 110 | 0.011 | 0.022275 | 0.22275 | 0.22275 | 0.022275 | -1000 | 0 | 625 | Finish Face: Interior | 0.22275 | 160 | Bouwkundig | Model Group:negge merk k40:5916225 | Constraints - Top Constraint: Up to level: 1
5916257 | 00 Begane grond | 2025 | 110 | 0.011 | 0.022275 | 0.22275 | 0.22275 | 0.022275 | -1000 | 0 | 625 | Finish Face: Interior | 0.22275 | 160 | Bouwkundig | Model Group:negge merk k40:5916259 | Constraints - Top Constraint: Up to level: 1
5916258 | 00 Begane grond | 2025 | 110 | 0.011 | 0.022275 | 0.22275 | 0.22275 | 0.022275 | -1000 | 0 | 625 | Finish Face: Interior | 0.22275 | 160 | Bouwkundig | Model Group:negge merk k40:5916259 | Constraints - Top Constraint: Up to level: 1
5916278 | 00 Begane grond | 2025 | 110 | 0.011 | 0.022275 | 0.22275 | 0.22275 | 0.022275 | -1000 | 0 | 625 | Finish Face: Interior | 0.22275 | 160 | Bouwkundig | Model Group:negge merk k40:5916280 | Constraints - Top Constraint: Up to level: 1
5916279 | 00 Begane grond | 2025 | 110 | 0.011 | 0.022275 | 0.22275 | 0.22275 | 0.022275 | -1000 | 0 | 625 | Finish Face: Interior | 0.22275 | 160 | Bouwkundig | Model Group:negge merk k40:5916280 | Constraints - Top Constraint: Up to level: 1
5916326 | 00 Begane grond | 2025 | 110 | 0.011 | 0.022275 | 0.22275 | 0.22275 | 0.022275 | -1000 | 0 | 625 | Finish Face: Interior | 0.22275 | 160 | Bouwkundig | Model Group:negge merk k40:5916328 | Constraints - Top Constraint: Up to level: 1
5916327 | 00 Begane grond | 2025 | 110 | 0.011 | 0.022275 | 0.22275 | 0.22275 | 0.022275 | -1000 | 0 | 625 | Finish Face: Interior | 0.22275 | 160 | Bouwkundig | Model Group:negge merk k40:5916328 | Constraints - Top Constraint: Up to level: 1
5916369 | 00 Begane grond | 2025 | 110 | 0.011 | 0.022275 | 0.22275 | 0.22275 | 0.022275 | -1000 | 0 | 625 | Finish Face: Interior | 0.22275 | 160 | Bouwkundig | Model Group:negge merk k41:5916371 | Constraints - Top Constraint: Up to level: 1
5916370 | 00 Begane grond | 2025 | 110 | 0.011 | 0.022275 | 0.22275 | 0.22275 | 0.022275 | -1000 | 0 | 625 | Finish Face: Interior | 0.22275 | 160 | Bouwkundig | Model Group:negge merk k41:5916371 | Constraints - Top Constraint: Up to level: 1
5916915 | 00 Begane grond | 2025 | 110 | 0.011 | 0.022275 | 0.22275 | 0.22275 | 0.022275 | -1000 | 0 | 625 | Finish Face: Interior | 0.22275 | 160 | Bouwkundig | Model Group:negge merk k41:5916917 | Constraints - Top Constraint: Up to level: 1
5916916 | 00 Begane grond | 2025 | 110 | 0.011 | 0.022275 | 0.22275 | 0.22275 | 0.022275 | -1000 | 0 | 625 | Finish Face: Interior | 0.22275 | 160 | Bouwkundig | Model Group:negge merk k41:5916917 | Constraints - Top Constraint: Up to level: 1
5916940 | 00 Begane grond | 2025 | 110 | 0.011 | 0.022275 | 0.22275 | 0.22275 | 0.022275 | -1000 | 0 | 625 | Finish Face: Interior | 0.22275 | 160 | Bouwkundig | Model Group:negge merk k41:5916942 | Constraints - Top Constraint: Up to level: 1
5916941 | 00 Begane grond | 2025 | 110 | 0.011 | 0.022275 | 0.22275 | 0.22275 | 0.022275 | -1000 | 0 | 625 | Finish Face: Interior | 0.22275 | 160 | Bouwkundig | Model Group:negge merk k41:5916942 | Constraints - Top Constraint: Up to level: 1
5916972 | 00 Begane grond | 2025 | 110 | 0.011 | 0.022275 | 0.22275 | 0.22275 | 0.022275 | -1000 | 0 | 625 | Finish Face: Interior | 0.22275 | 160 | Bouwkundig | Model Group:negge merk k41:5916974 | Constraints - Top Constraint: Up to level: 1
5916973 | 00 Begane grond | 2025 | 110 | 0.011 | 0.022275 | 0.22275 | 0.22275 | 0.022275 | -1000 | 0 | 625 | Finish Face: Interior | 0.22275 | 160 | Bouwkundig | Model Group:negge merk k41:5916974 | Constraints - Top Constraint: Up to level: 1
5917037 | 00 Begane grond | 2025 | 110 | 0.011 | 0.022275 | 0.22275 | 0.22275 | 0.022275 | -1000 | 0 | 625 | Finish Face: Interior | 0.22275 | 160 | Bouwkundig | Model Group:negge merk k41:5917039 | Constraints - Top Constraint: Up to level: 1
5917038 | 00 Begane grond | 2025 | 110 | 0.011 | 0.022275 | 0.22275 | 0.22275 | 0.022275 | -1000 | 0 | 625 | Finish Face: Interior | 0.22275 | 160 | Bouwkundig | Model Group:negge merk k41:5917039 | Constraints - Top Constraint: Up to level: 1
5917174 | 00 Begane grond | 2025 | 110 | 0.011 | 0.022275 | 0.22275 | 0.22275 | 0.022275 | -1000 | 0 | 625 | Finish Face: Interior | 0.22275 | 160 | Bouwkundig | Model Group:negge merk k41:5917176 | Constraints - Top Constraint: Up to level: 1
5917175 | 00 Begane grond | 2025 | 110 | 0.011 | 0.022275 | 0.22275 | 0.22275 | 0.022275 | -1000 | 0 | 625 | Finish Face: Interior | 0.22275 | 160 | Bouwkundig | Model Group:negge merk k41:5917176 | Constraints - Top Constraint: Up to level: 1
5917229 | 00 Begane grond | 2025 | 110 | 0.011 | 0.022275 | 0.22275 | 0.22275 | 0.022275 | -1000 | 0 | 625 | Finish Face: Interior | 0.22275 | 160 | Bouwkundig | Model Group:negge merk k41:5917231 | Constraints - Top Constraint: Up to level: 1
5917230 | 00 Begane grond | 2025 | 110 | 0.011 | 0.022275 | 0.22275 | 0.22275 | 0.022275 | -1000 | 0 | 625 | Finish Face: Interior | 0.22275 | 160 | Bouwkundig | Model Group:negge merk k41:5917231 | Constraints - Top Constraint: Up to level: 1
5917240 | 00 Begane grond | 2025 | 110 | 0.011 | 0.022275 | 0.22275 | 0.22275 | 0.022275 | -1000 | 0 | 625 | Finish Face: Interior | 0.22275 | 160 | Bouwkundig | Model Group:negge merk k41:5917242 | Constraints - Top Constraint: Up to level: 1
5917241 | 00 Begane grond | 2025 | 110 | 0.011 | 0.022275 | 0.22275 | 0.22275 | 0.022275 | -1000 | 0 | 625 | Finish Face: Interior | 0.22275 | 160 | Bouwkundig | Model Group:negge merk k41:5917242 | Constraints - Top Constraint: Up to level: 1
5917351 | 00 Begane grond | 2025 | 110 | 0.011 | 0.022275 | 0.22275 | 0.22275 | 0.022275 | -1000 | 0 | 625 | Finish Face: Interior | 0.22275 | 160 | Bouwkundig | Model Group:negge merk k41:5917353 | Constraints - Top Constraint: Up to level: 1
5917352 | 00 Begane grond | 2025 | 110 | 0.011 | 0.022275 | 0.22275 | 0.22275 | 0.022275 | -1000 | 0 | 625 | Finish Face: Interior | 0.22275 | 160 | Bouwkundig | Model Group:negge merk k41:5917353 | Constraints - Top Constraint: Up to level: 1
5917390 | 00 Begane grond | 2025 | 110 | 0.011 | 0.022275 | 0.22275 | 0.22275 | 0.022275 | -1000 | 0 | 625 | Finish Face: Interior | 0.22275 | 160 | Bouwkundig | Model Group:negge merk k40:5917384 | Constraints - Top Constraint: Up to level: 1
5917391 | 00 Begane grond | 2025 | 110 | 0.011 | 0.022275 | 0.22275 | 0.22275 | 0.022275 | -1000 | 0 | 625 | Finish Face: Interior | 0.22275 | 160 | Bouwkundig | Model Group:negge merk k40:5917384 | Constraints - Top Constraint: Up to level: 1
5917418 | 00 Begane grond | 2025 | 110 | 0.011 | 0.022275 | 0.22275 | 0.22275 | 0.022275 | -1000 | 0 | 625 | Finish Face: Interior | 0.22275 | 160 | Bouwkundig | Model Group:negge merk k40:5917417 | Constraints - Top Constraint: Up to level: 1
5917419 | 00 Begane grond | 2025 | 110 | 0.011 | 0.022275 | 0.22275 | 0.22275 | 0.022275 | -1000 | 0 | 625 | Finish Face: Interior | 0.22275 | 160 | Bouwkundig | Model Group:negge merk k40:5917417 | Constraints - Top Constraint: Up to level: 1
5918043 | 00 Begane grond | 7150 | 215 | 0.0215 | 0.153725 | 1.53725 | 1.53725 | 0.153725 | 0 | 0 | 0 | Finish Face: Interior | 1.53725 | 165 | Bouwkundig
5954453 | 00 Begane grond | 2025 | 160 | 0.016 | 0.0324 | 0.324 | 0.324 | 0.0324 | -1000 | 0 | 625 | Finish Face: Interior | 0.324 | 160 | Bouwkundig | Model Group:negge merk k41:5954455 | Constraints - Top Constraint: Up to level: 1
5954454 | 00 Begane grond | 2025 | 110 | 0.011 | 0.022275 | 0.22275 | 0.22275 | 0.022275 | -1000 | 0 | 625 | Finish Face: Interior | 0.22275 | 160 | Bouwkundig | Model Group:negge merk k41:5954455 | Constraints - Top Constraint: Up to level: 1
5954463 | 00 Begane grond | 2025 | 110 | 0.011 | 0.022275 | 0.22275 | 0.22275 | 0.022275 | -1000 | 0 | 625 | Finish Face: Interior | 0.22275 | 160 | Bouwkundig | Model Group:negge merk k41:5954465 | Constraints - Top Constraint: Up to level: 1
5954464 | 00 Begane grond | 2025 | 160 | 0.016 | 0.0324 | 0.324 | 0.324 | 0.0324 | -1000 | 0 | 625 | Finish Face: Interior | 0.324 | 160 | Bouwkundig | Model Group:negge merk k41:5954465 | Constraints - Top Constraint: Up to level: 1
5954468 | 00 Begane grond | 2025 | 110 | 0.011 | 0.022275 | 0.22275 | 0.22275 | 0.022275 | -1000 | 0 | 625 | Finish Face: Interior | 0.22275 | 160 | Bouwkundig | Model Group:negge merk k41:5954470 | Constraints - Top Constraint: Up to level: 1
5954469 | 00 Begane grond | 2025 | 110 | 0.011 | 0.022275 | 0.22275 | 0.22275 | 0.022275 | -1000 | 0 | 625 | Finish Face: Interior | 0.22275 | 160 | Bouwkundig | Model Group:negge merk k41:5954470 | Constraints - Top Constraint: Up to level: 1
5954473 | 00 Begane grond | 2025 | 160 | 0.016 | 0.0324 | 0.324 | 0.324 | 0.0324 | -1000 | 0 | 625 | Finish Face: Interior | 0.324 | 160 | Bouwkundig | Model Group:negge merk k41:5954475 | Constraints - Top Constraint: Up to level: 1
5954474 | 00 Begane grond | 2025 | 160 | 0.016 | 0.0324 | 0.324 | 0.324 | 0.0324 | -1000 | 0 | 625 | Finish Face: Interior | 0.324 | 160 | Bouwkundig | Model Group:negge merk k41:5954475 | Constraints - Top Constraint: Up to level: 1
5954478 | 00 Begane grond | 2025 | 110 | 0.011 | 0.022275 | 0.22275 | 0.22275 | 0.022275 | -1000 | 0 | 625 | Finish Face: Interior | 0.22275 | 160 | Bouwkundig | Model Group:negge merk k41:5954480 | Constraints - Top Constraint: Up to level: 1
5954479 | 00 Begane grond | 2025 | 110 | 0.011 | 0.022275 | 0.22275 | 0.22275 | 0.022275 | -1000 | 0 | 625 | Finish Face: Interior | 0.22275 | 160 | Bouwkundig | Model Group:negge merk k41:5954480 | Constraints - Top Constraint: Up to level: 1
5954483 | 00 Begane grond | 2025 | 110 | 0.011 | 0.022275 | 0.22275 | 0.22275 | 0.022275 | -1000 | 0 | 625 | Finish Face: Interior | 0.22275 | 160 | Bouwkundig | Model Group:negge merk k41:5954485 | Constraints - Top Constraint: Up to level: 1
5954484 | 00 Begane grond | 2025 | 110 | 0.011 | 0.022275 | 0.22275 | 0.22275 | 0.022275 | -1000 | 0 | 625 | Finish Face: Interior | 0.22275 | 160 | Bouwkundig | Model Group:negge merk k41:5954485 | Constraints - Top Constraint: Up to level: 1
5954488 | 00 Begane grond | 2025 | 110 | 0.011 | 0.022275 | 0.22275 | 0.22275 | 0.022275 | -1000 | 0 | 625 | Finish Face: Interior | 0.22275 | 160 | Bouwkundig | Model Group:negge merk k41:5954490 | Constraints - Top Constraint: Up to level: 1
5954489 | 00 Begane grond | 2025 | 110 | 0.011 | 0.022275 | 0.22275 | 0.22275 | 0.022275 | -1000 | 0 | 625 | Finish Face: Interior | 0.22275 | 160 | Bouwkundig | Model Group:negge merk k41:5954490 | Constraints - Top Constraint: Up to level: 1
5954493 | 00 Begane grond | 2025 | 110 | 0.011 | 0.022275 | 0.22275 | 0.22275 | 0.022275 | -1000 | 0 | 625 | Finish Face: Interior | 0.22275 | 160 | Bouwkundig | Model Group:negge merk k41:5954495 | Constraints - Top Constraint: Up to level: 1
5954494 | 00 Begane grond | 2025 | 110 | 0.011 | 0.022275 | 0.22275 | 0.22275 | 0.022275 | -1000 | 0 | 625 | Finish Face: Interior | 0.22275 | 160 | Bouwkundig | Model Group:negge merk k41:5954495 | Constraints - Top Constraint: Up to level: 1
5954498 | 00 Begane grond | 2025 | 110.87 | 0.011087 | 0.0224511 | 0.224511 | 0.224511 | 0.0224511 | -1000 | 0 | 625 | Finish Face: Interior | 0.224511 | 160 | Bouwkundig | Model Group:negge merk k41:5954500 | Constraints - Top Constraint: Up to level: 1
5954499 | 00 Begane grond | 2025 | 110.87 | 0.011087 | 0.0224511 | 0.224511 | 0.224511 | 0.0224511 | -1000 | 0 | 625 | Finish Face: Interior | 0.224511 | 160 | Bouwkundig | Model Group:negge merk k41:5954500 | Constraints - Top Constraint: Up to level: 1
5954503 | 00 Begane grond | 2025 | 110.87 | 0.011087 | 0.0224511 | 0.224511 | 0.224511 | 0.0224511 | -1000 | 0 | 625 | Finish Face: Interior | 0.224511 | 160 | Bouwkundig | Model Group:negge merk k41:5954505 | Constraints - Top Constraint: Up to level: 1
5954504 | 00 Begane grond | 2025 | 110.87 | 0.011087 | 0.0224511 | 0.224511 | 0.224511 | 0.0224511 | -1000 | 0 | 625 | Finish Face: Interior | 0.224511 | 160 | Bouwkundig | Model Group:negge merk k41:5954505 | Constraints - Top Constraint: Up to level: 1
5954508 | 00 Begane grond | 2025 | 110 | 0.011 | 0.022275 | 0.22275 | 0.22275 | 0.022275 | -1000 | 0 | 625 | Finish Face: Interior | 0.22275 | 160 | Bouwkundig | Model Group:negge merk k41:5954510 | Constraints - Top Constraint: Up to level: 1
5954509 | 00 Begane grond | 2025 | 110 | 0.011 | 0.022275 | 0.22275 | 0.22275 | 0.022275 | -1000 | 0 | 625 | Finish Face: Interior | 0.22275 | 160 | Bouwkundig | Model Group:negge merk k41:5954510 | Constraints - Top Constraint: Up to level: 1
5954513 | 00 Begane grond | 2025 | 110 | 0.011 | 0.022275 | 0.22275 | 0.22275 | 0.022275 | -1000 | 0 | 625 | Finish Face: Interior | 0.22275 | 160 | Bouwkundig | Model Group:negge merk k41:5954515 | Constraints - Top Constraint: Up to level: 1
5954514 | 00 Begane grond | 2025 | 110 | 0.011 | 0.022275 | 0.22275 | 0.22275 | 0.022275 | -1000 | 0 | 625 | Finish Face: Interior | 0.22275 | 160 | Bouwkundig | Model Group:negge merk k41:5954515 | Constraints - Top Constraint: Up to level: 1
6057859 | 01 eerste verdieping | 2125 | 110 | 0.011 | 0.023375 | 0.23375 | 0.23375 | 0.023375 | -750 | 1 | 625 | Finish Face: Interior | 0.23375 | 160 | Bouwkundig | Model Group:negge merk k42:6057861 | Constraints - Top Constraint: Up to level: V2 bk. ruwe vloer
6057860 | 01 eerste verdieping | 2125 | 110 | 0.011 | 0.023375 | 0.23375 | 0.23375 | 0.023375 | -750 | 1 | 625 | Finish Face: Interior | 0.23375 | 160 | Bouwkundig | Model Group:negge merk k42:6057861 | Constraints - Top Constraint: Up to level: V2 bk. ruwe vloer
6058277 | 01 eerste verdieping | 2125 | 110 | 0.011 | 0.023375 | 0.23375 | 0.23375 | 0.023375 | -750 | 1 | 625 | Finish Face: Interior | 0.23375 | 160 | Bouwkundig | Model Group:negge merk k42:6058279 | Constraints - Top Constraint: Up to level: V2 bk. ruwe vloer
6058278 | 01 eerste verdieping | 2125 | 110 | 0.011 | 0.023375 | 0.23375 | 0.23375 | 0.023375 | -750 | 1 | 625 | Finish Face: Interior | 0.23375 | 160 | Bouwkundig | Model Group:negge merk k42:6058279 | Constraints - Top Constraint: Up to level: V2 bk. ruwe vloer
6058296 | 01 eerste verdieping | 2125 | 110 | 0.011 | 0.023375 | 0.23375 | 0.23375 | 0.023375 | -750 | 1 | 625 | Finish Face: Interior | 0.23375 | 160 | Bouwkundig | Model Group:negge merk k42:6058298 | Constraints - Top Constraint: Up to level: V2 bk. ruwe vloer
6058297 | 01 eerste verdieping | 2125 | 110 | 0.011 | 0.023375 | 0.23375 | 0.23375 | 0.023375 | -750 | 1 | 625 | Finish Face: Interior | 0.23375 | 160 | Bouwkundig | Model Group:negge merk k42:6058298 | Constraints - Top Constraint: Up to level: V2 bk. ruwe vloer
6058315 | 01 eerste verdieping | 2125 | 110 | 0.011 | 0.023375 | 0.23375 | 0.23375 | 0.023375 | -750 | 1 | 625 | Finish Face: Interior | 0.23375 | 160 | Bouwkundig | Model Group:negge merk k42:6058317 | Constraints - Top Constraint: Up to level: V2 bk. ruwe vloer
6058316 | 01 eerste verdieping | 2125 | 110 | 0.011 | 0.023375 | 0.23375 | 0.23375 | 0.023375 | -750 | 1 | 625 | Finish Face: Interior | 0.23375 | 160 | Bouwkundig | Model Group:negge merk k42:6058317 | Constraints - Top Constraint: Up to level: V2 bk. ruwe vloer
6058334 | 01 eerste verdieping | 2125 | 110 | 0.011 | 0.023375 | 0.23375 | 0.23375 | 0.023375 | -750 | 1 | 625 | Finish Face: Interior | 0.23375 | 160 | Bouwkundig | Model Group:negge merk k42:6058336 | Constraints - Top Constraint: Up to level: V2 bk. ruwe vloer
6058335 | 01 eerste verdieping | 2125 | 110 | 0.011 | 0.023375 | 0.23375 | 0.23375 | 0.023375 | -750 | 1 | 625 | Finish Face: Interior | 0.23375 | 160 | Bouwkundig | Model Group:negge merk k42:6058336 | Constraints - Top Constraint: Up to level: V2 bk. ruwe vloer
6058353 | 01 eerste verdieping | 2125 | 110 | 0.011 | 0.023375 | 0.23375 | 0.23375 | 0.023375 | -750 | 1 | 625 | Finish Face: Interior | 0.23375 | 160 | Bouwkundig | Model Group:negge merk k42:6058355 | Constraints - Top Constraint: Up to level: V2 bk. ruwe vloer
6058354 | 01 eerste verdieping | 2125 | 110 | 0.011 | 0.023375 | 0.23375 | 0.23375 | 0.023375 | -750 | 1 | 625 | Finish Face: Interior | 0.23375 | 160 | Bouwkundig | Model Group:negge merk k42:6058355 | Constraints - Top Constraint: Up to level: V2 bk. ruwe vloer
6058372 | 01 eerste verdieping | 2125 | 110 | 0.011 | 0.023375 | 0.23375 | 0.23375 | 0.023375 | -750 | 1 | 625 | Finish Face: Interior | 0.23375 | 160 | Bouwkundig | Model Group:negge merk k42:6058374 | Constraints - Top Constraint: Up to level: V2 bk. ruwe vloer
6058373 | 01 eerste verdieping | 2125 | 110 | 0.011 | 0.023375 | 0.23375 | 0.23375 | 0.023375 | -750 | 1 | 625 | Finish Face: Interior | 0.23375 | 160 | Bouwkundig | Model Group:negge merk k42:6058374 | Constraints - Top Constraint: Up to level: V2 bk. ruwe vloer
6058391 | 01 eerste verdieping | 2125 | 110 | 0.011 | 0.023375 | 0.23375 | 0.23375 | 0.023375 | -750 | 1 | 625 | Finish Face: Interior | 0.23375 | 160 | Bouwkundig | Model Group:negge merk k42:6058393 | Constraints - Top Constraint: Up to level: V2 bk. ruwe vloer
6058392 | 01 eerste verdieping | 2125 | 110 | 0.011 | 0.023375 | 0.23375 | 0.23375 | 0.023375 | -750 | 1 | 625 | Finish Face: Interior | 0.23375 | 160 | Bouwkundig | Model Group:negge merk k42:6058393 | Constraints - Top Constraint: Up to level: V2 bk. ruwe vloer
6058410 | 01 eerste verdieping | 2125 | 110 | 0.011 | 0.023375 | 0.23375 | 0.23375 | 0.023375 | -750 | 1 | 625 | Finish Face: Interior | 0.23375 | 160 | Bouwkundig | Model Group:negge merk k42:6058412 | Constraints - Top Constraint: Up to level: V2 bk. ruwe vloer
6058411 | 01 eerste verdieping | 2125 | 110 | 0.011 | 0.023375 | 0.23375 | 0.23375 | 0.023375 | -750 | 1 | 625 | Finish Face: Interior | 0.23375 | 160 | Bouwkundig | Model Group:negge merk k42:6058412 | Constraints - Top Constraint: Up to level: V2 bk. ruwe vloer
6058429 | 01 eerste verdieping | 2125 | 110 | 0.011 | 0.023375 | 0.23375 | 0.23375 | 0.023375 | -750 | 1 | 625 | Finish Face: Interior | 0.23375 | 160 | Bouwkundig | Model Group:negge merk k42:6058431 | Constraints - Top Constraint: Up to level: V2 bk. ruwe vloer
6058430 | 01 eerste verdieping | 2125 | 110 | 0.011 | 0.023375 | 0.23375 | 0.23375 | 0.023375 | -750 | 1 | 625 | Finish Face: Interior | 0.23375 | 160 | Bouwkundig | Model Group:negge merk k42:6058431 | Constraints - Top Constraint: Up to level: V2 bk. ruwe vloer
6058448 | 01 eerste verdieping | 2125 | 110 | 0.011 | 0.023375 | 0.23375 | 0.23375 | 0.023375 | -750 | 1 | 625 | Finish Face: Interior | 0.23375 | 160 | Bouwkundig | Model Group:negge merk k42:6058450 | Constraints - Top Constraint: Up to level: V2 bk. ruwe vloer
6058449 | 01 eerste verdieping | 2125 | 110 | 0.011 | 0.023375 | 0.23375 | 0.23375 | 0.023375 | -750 | 1 | 625 | Finish Face: Interior | 0.23375 | 160 | Bouwkundig | Model Group:negge merk k42:6058450 | Constraints - Top Constraint: Up to level: V2 bk. ruwe vloer
6058467 | 01 eerste verdieping | 2125 | 110 | 0.011 | 0.023375 | 0.23375 | 0.23375 | 0.023375 | -750 | 1 | 625 | Finish Face: Interior | 0.23375 | 160 | Bouwkundig | Model Group:negge merk k42:6058469 | Constraints - Top Constraint: Up to level: V2 bk. ruwe vloer
6058468 | 01 eerste verdieping | 2125 | 110 | 0.011 | 0.023375 | 0.23375 | 0.23375 | 0.023375 | -750 | 1 | 625 | Finish Face: Interior | 0.23375 | 160 | Bouwkundig | Model Group:negge merk k42:6058469 | Constraints - Top Constraint: Up to level: V2 bk. ruwe vloer
6058486 | 01 eerste verdieping | 2125 | 110 | 0.011 | 0.023375 | 0.23375 | 0.23375 | 0.023375 | -750 | 1 | 625 | Finish Face: Interior | 0.23375 | 160 | Bouwkundig | Model Group:negge merk k42:6058488 | Constraints - Top Constraint: Up to level: V2 bk. ruwe vloer
6058487 | 01 eerste verdieping | 2125 | 110 | 0.011 | 0.023375 | 0.23375 | 0.23375 | 0.023375 | -750 | 1 | 625 | Finish Face: Interior | 0.23375 | 160 | Bouwkundig | Model Group:negge merk k42:6058488 | Constraints - Top Constraint: Up to level: V2 bk. ruwe vloer
6058505 | 01 eerste verdieping | 2125 | 110 | 0.011 | 0.023375 | 0.23375 | 0.23375 | 0.023375 | -750 | 1 | 625 | Finish Face: Interior | 0.23375 | 160 | Bouwkundig | Model Group:negge merk k42:6058507 | Constraints - Top Constraint: Up to level: V2 bk. ruwe vloer
6058506 | 01 eerste verdieping | 2125 | 110 | 0.011 | 0.023375 | 0.23375 | 0.23375 | 0.023375 | -750 | 1 | 625 | Finish Face: Interior | 0.23375 | 160 | Bouwkundig | Model Group:negge merk k42:6058507 | Constraints - Top Constraint: Up to level: V2 bk. ruwe vloer
6058524 | 01 eerste verdieping | 2125 | 110 | 0.011 | 0.023375 | 0.23375 | 0.23375 | 0.023375 | -750 | 1 | 625 | Finish Face: Interior | 0.23375 | 160 | Bouwkundig | Model Group:negge merk k42:6058526 | Constraints - Top Constraint: Up to level: V2 bk. ruwe vloer
6058525 | 01 eerste verdieping | 2125 | 110 | 0.011 | 0.023375 | 0.23375 | 0.23375 | 0.023375 | -750 | 1 | 625 | Finish Face: Interior | 0.23375 | 160 | Bouwkundig | Model Group:negge merk k42:6058526 | Constraints - Top Constraint: Up to level: V2 bk. ruwe vloer
6058543 | 01 eerste verdieping | 2125 | 110 | 0.011 | 0.023375 | 0.23375 | 0.23375 | 0.023375 | -750 | 1 | 625 | Finish Face: Interior | 0.23375 | 160 | Bouwkundig | Model Group:negge merk k42:6058545 | Constraints - Top Constraint: Up to level: V2 bk. ruwe vloer
6058544 | 01 eerste verdieping | 2125 | 110 | 0.011 | 0.023375 | 0.23375 | 0.23375 | 0.023375 | -750 | 1 | 625 | Finish Face: Interior | 0.23375 | 160 | Bouwkundig | Model Group:negge merk k42:6058545 | Constraints - Top Constraint: Up to level: V2 bk. ruwe vloer
6058562 | 01 eerste verdieping | 2125 | 110 | 0.011 | 0.023375 | 0.23375 | 0.23375 | 0.023375 | -750 | 1 | 625 | Finish Face: Interior | 0.23375 | 160 | Bouwkundig | Model Group:negge merk k42:6058564 | Constraints - Top Constraint: Up to level: V2 bk. ruwe vloer
6058563 | 01 eerste verdieping | 2125 | 110 | 0.011 | 0.023375 | 0.23375 | 0.23375 | 0.023375 | -750 | 1 | 625 | Finish Face: Interior | 0.23375 | 160 | Bouwkundig | Model Group:negge merk k42:6058564 | Constraints - Top Constraint: Up to level: V2 bk. ruwe vloer
6058695 | 01 eerste verdieping | 2125 | 110 | 0.011 | 0.023375 | 0.23375 | 0.23375 | 0.023375 | -750 | V1 bk. ruwe vloer | 715 | Finish Face: Interior | 0.23375 | 160 | Bouwkundig | Model Group:raamwerk K07:6058698 | Constraints - Top Constraint: Up to level: 2
6058697 | 01 eerste verdieping | 2125 | 110 | 0.011 | 0.023375 | 0.23375 | 0.23375 | 0.023375 | -750 | V1 bk. ruwe vloer | 715 | Finish Face: Interior | 0.23375 | 160 | Bouwkundig | Model Group:raamwerk K07:6058698 | Constraints - Top Constraint: Up to level: 2
6059003 | 01 eerste verdieping | 2125 | 110 | 0.011 | 0.023375 | 0.23375 | 0.23375 | 0.023375 | -750 | V1 bk. ruwe vloer | 715 | Finish Face: Interior | 0.23375 | 160 | Bouwkundig | Model Group:raamwerk K07:6059006 | Constraints - Top Constraint: Up to level: V2 bk. ruwe vloer
6059005 | 01 eerste verdieping | 2125 | 110 | 0.011 | 0.023375 | 0.23375 | 0.23375 | 0.023375 | -750 | V1 bk. ruwe vloer | 715 | Finish Face: Interior | 0.23375 | 160 | Bouwkundig | Model Group:raamwerk K07:6059006 | Constraints - Top Constraint: Up to level: V2 bk. ruwe vloer
6059022 | 01 eerste verdieping | 2125 | 110 | 0.011 | 0.023375 | 0.23375 | 0.23375 | 0.023375 | -750 | V1 bk. ruwe vloer | 715 | Finish Face: Interior | 0.23375 | 160 | Bouwkundig | Model Group:raamwerk K07:6059025 | Constraints - Top Constraint: Up to level: V2 bk. ruwe vloer
6059024 | 01 eerste verdieping | 2125 | 110 | 0.011 | 0.023375 | 0.23375 | 0.23375 | 0.023375 | -750 | V1 bk. ruwe vloer | 715 | Finish Face: Interior | 0.23375 | 160 | Bouwkundig | Model Group:raamwerk K07:6059025 | Constraints - Top Constraint: Up to level: V2 bk. ruwe vloer
6059041 | 01 eerste verdieping | 2125 | 110 | 0.011 | 0.023375 | 0.23375 | 0.23375 | 0.023375 | -750 | V1 bk. ruwe vloer | 715 | Finish Face: Interior | 0.23375 | 160 | Bouwkundig | Model Group:raamwerk K07:6059044 | Constraints - Top Constraint: Up to level: V2 bk. ruwe vloer
6059043 | 01 eerste verdieping | 2125 | 110 | 0.011 | 0.023375 | 0.23375 | 0.23375 | 0.023375 | -750 | V1 bk. ruwe vloer | 715 | Finish Face: Interior | 0.23375 | 160 | Bouwkundig | Model Group:raamwerk K07:6059044 | Constraints - Top Constraint: Up to level: V2 bk. ruwe vloer
6059060 | 01 eerste verdieping | 2125 | 110.001 | 0.0110001 | 0.0233753 | 0.233753 | 0.233753 | 0.0233753 | -750 | V1 bk. ruwe vloer | 715 | Finish Face: Interior | 0.233753 | 160.001 | Bouwkundig | Model Group:raamwerk K07:6059063 | Constraints - Top Constraint: Up to level: V2 bk. ruwe vloer
6059062 | 01 eerste verdieping | 2125 | 110.001 | 0.0110001 | 0.0233753 | 0.233753 | 0.233753 | 0.0233753 | -750 | V1 bk. ruwe vloer | 715 | Finish Face: Interior | 0.233753 | 160.001 | Bouwkundig | Model Group:raamwerk K07:6059063 | Constraints - Top Constraint: Up to level: V2 bk. ruwe vloer
6059079 | 01 eerste verdieping | 2125 | 110 | 0.011 | 0.023375 | 0.23375 | 0.23375 | 0.023375 | -750 | V1 bk. ruwe vloer | 715 | Finish Face: Interior | 0.23375 | 160 | Bouwkundig | Model Group:raamwerk K07:6059082 | Constraints - Top Constraint: Up to level: V2 bk. ruwe vloer
6059081 | 01 eerste verdieping | 2125 | 110 | 0.011 | 0.023375 | 0.23375 | 0.23375 | 0.023375 | -750 | V1 bk. ruwe vloer | 715 | Finish Face: Interior | 0.23375 | 160 | Bouwkundig | Model Group:raamwerk K07:6059082 | Constraints - Top Constraint: Up to level: V2 bk. ruwe vloer
6059098 | 01 eerste verdieping | 2125 | 110 | 0.011 | 0.023375 | 0.23375 | 0.23375 | 0.023375 | -750 | V1 bk. ruwe vloer | 715 | Finish Face: Interior | 0.23375 | 160 | Bouwkundig | Model Group:raamwerk K07:6059101 | Constraints - Top Constraint: Up to level: V2 bk. ruwe vloer
6059100 | 01 eerste verdieping | 2125 | 110 | 0.011 | 0.023375 | 0.23375 | 0.23375 | 0.023375 | -750 | V1 bk. ruwe vloer | 715 | Finish Face: Interior | 0.23375 | 160 | Bouwkundig | Model Group:raamwerk K07:6059101 | Constraints - Top Constraint: Up to level: V2 bk. ruwe vloer
6059117 | 01 eerste verdieping | 2125 | 110 | 0.011 | 0.023375 | 0.23375 | 0.23375 | 0.023375 | -750 | V1 bk. ruwe vloer | 715 | Finish Face: Interior | 0.23375 | 160 | Bouwkundig | Model Group:raamwerk K07:6059120 | Constraints - Top Constraint: Up to level: V2 bk. ruwe vloer
6059119 | 01 eerste verdieping | 2125 | 110 | 0.011 | 0.023375 | 0.23375 | 0.23375 | 0.023375 | -750 | V1 bk. ruwe vloer | 715 | Finish Face: Interior | 0.23375 | 160 | Bouwkundig | Model Group:raamwerk K07:6059120 | Constraints - Top Constraint: Up to level: V2 bk. ruwe vloer
6059136 | 01 eerste verdieping | 2125 | 110 | 0.011 | 0.023375 | 0.23375 | 0.23375 | 0.023375 | -750 | V1 bk. ruwe vloer | 715 | Finish Face: Interior | 0.23375 | 160 | Bouwkundig | Model Group:raamwerk K07:6059139 | Constraints - Top Constraint: Up to level: V2 bk. ruwe vloer
6059138 | 01 eerste verdieping | 2125 | 110 | 0.011 | 0.023375 | 0.23375 | 0.23375 | 0.023375 | -750 | V1 bk. ruwe vloer | 715 | Finish Face: Interior | 0.23375 | 160 | Bouwkundig | Model Group:raamwerk K07:6059139 | Constraints - Top Constraint: Up to level: V2 bk. ruwe vloer
6059155 | 01 eerste verdieping | 2125 | 110 | 0.011 | 0.023375 | 0.23375 | 0.23375 | 0.023375 | -750 | V1 bk. ruwe vloer | 715 | Finish Face: Interior | 0.23375 | 160 | Bouwkundig | Model Group:raamwerk K07:6059158 | Constraints - Top Constraint: Up to level: V2 bk. ruwe vloer
6059157 | 01 eerste verdieping | 2125 | 110 | 0.011 | 0.023375 | 0.23375 | 0.23375 | 0.023375 | -750 | V1 bk. ruwe vloer | 715 | Finish Face: Interior | 0.23375 | 160 | Bouwkundig | Model Group:raamwerk K07:6059158 | Constraints - Top Constraint: Up to level: V2 bk. ruwe vloer
6059174 | 01 eerste verdieping | 2125 | 110 | 0.011 | 0.023375 | 0.23375 | 0.23375 | 0.023375 | -750 | V1 bk. ruwe vloer | 715 | Finish Face: Interior | 0.23375 | 160 | Bouwkundig | Model Group:raamwerk K07:6059177 | Constraints - Top Constraint: Up to level: V2 bk. ruwe vloer
6059176 | 01 eerste verdieping | 2125 | 110 | 0.011 | 0.023375 | 0.23375 | 0.23375 | 0.023375 | -750 | V1 bk. ruwe vloer | 715 | Finish Face: Interior | 0.23375 | 160 | Bouwkundig | Model Group:raamwerk K07:6059177 | Constraints - Top Constraint: Up to level: V2 bk. ruwe vloer
6059193 | 01 eerste verdieping | 2125 | 110 | 0.011 | 0.023375 | 0.23375 | 0.23375 | 0.023375 | -750 | V1 bk. ruwe vloer | 715 | Finish Face: Interior | 0.23375 | 160 | Bouwkundig | Model Group:raamwerk K07:6059196 | Constraints - Top Constraint: Up to level: V2 bk. ruwe vloer
6059195 | 01 eerste verdieping | 2125 | 110 | 0.011 | 0.023375 | 0.23375 | 0.23375 | 0.023375 | -750 | V1 bk. ruwe vloer | 715 | Finish Face: Interior | 0.23375 | 160 | Bouwkundig | Model Group:raamwerk K07:6059196 | Constraints - Top Constraint: Up to level: V2 bk. ruwe vloer
6059212 | 01 eerste verdieping | 2125 | 110 | 0.011 | 0.023375 | 0.23375 | 0.23375 | 0.023375 | -750 | V1 bk. ruwe vloer | 715 | Finish Face: Interior | 0.23375 | 160 | Bouwkundig | Model Group:raamwerk K07:6059215 | Constraints - Top Constraint: Up to level: V2 bk. ruwe vloer
6059214 | 01 eerste verdieping | 2125 | 110 | 0.011 | 0.023375 | 0.23375 | 0.23375 | 0.023375 | -750 | V1 bk. ruwe vloer | 715 | Finish Face: Interior | 0.23375 | 160 | Bouwkundig | Model Group:raamwerk K07:6059215 | Constraints - Top Constraint: Up to level: V2 bk. ruwe vloer
6284252 | 01 eerste verdieping | 2350 | 3680 | 0.368 | 0.8648 | 8.648 | 8.648 | 0.864768 | 0 | 2 | 200 | Finish Face: Interior | 8.648 | 3680 | Bouwkundig | Constraints - Top Constraint: Up to level: 3
6284313 | 01 eerste verdieping | 2550 | 7575 | 0.7575 | 1.93162 | 19.3162 | 19.3162 | 1.93162 | 0 | 2 | 0 | Finish Face: Interior | 19.3162 | 7525 | Bouwkundig | Constraints - Top Constraint: Up to level: 3
6382337 | 01 eerste verdieping | 360 | 6775 | 0.6775 | 0.2439 | 2.439 | 2.439 | 0.2439 | 0 | V1 bk. ruwe vloer | 355 | Wall Centerline | 2.439 | 6862.5 | Constructie
6548925 | -1 fundering | 1270 | 265 | 0.0265 | 0.033655 | 0.33655 | 0.33655 | 0.033655 | 0 | bk. fundering | 0 | Finish Face: Interior | 0.33655 | 215 | Bouwkundig | Model Group:Penant Dubbel:5536961 | Constraints - Top Constraint: Up to level: 0
6548933 | -1 fundering | 1270 | 265 | 0.0265 | 0.033655 | 0.33655 | 0.33655 | 0.033655 | 0 | bk. fundering | 0 | Finish Face: Interior | 0.33655 | 215 | Bouwkundig | Model Group:Penant Dubbel:5537041 | Constraints - Top Constraint: Up to level: 0
6548937 | -1 fundering | 1270 | 265 | 0.0265 | 0.033655 | 0.33655 | 0.33655 | 0.033655 | 0 | bk. fundering | 0 | Finish Face: Interior | 0.33655 | 215 | Bouwkundig | Model Group:Penant Dubbel:5537064 | Constraints - Top Constraint: Up to level: 0
6548941 | -1 fundering | 1270 | 265 | 0.0265 | 0.033655 | 0.33655 | 0.33655 | 0.033655 | 0 | bk. fundering | 0 | Finish Face: Interior | 0.33655 | 215 | Bouwkundig | Model Group:Penant Dubbel:5537076 | Constraints - Top Constraint: Up to level: 0
6548950 | -1 fundering | 1270 | 265 | 0.0265 | 0.033655 | 0.33655 | 0.33655 | 0.033655 | 0 | bk. fundering | 0 | Finish Face: Interior | 0.33655 | 215 | Bouwkundig | Model Group:Penant Dubbel:5537524 | Constraints - Top Constraint: Up to level: 0
6548953 | -1 fundering | 1270 | 265 | 0.0265 | 0.033655 | 0.33655 | 0.33655 | 0.033655 | 0 | bk. fundering | 0 | Finish Face: Interior | 0.33655 | 215 | Bouwkundig | Model Group:Penant Dubbel:5538619 | Constraints - Top Constraint: Up to level: 0
6548954 | -1 fundering | 1270 | 265 | 0.0265 | 0.033655 | 0.33655 | 0.33655 | 0.033655 | 0 | bk. fundering | 0 | Finish Face: Interior | 0.33655 | 215 | Bouwkundig | Model Group:Penant Dubbel:5538619 | Constraints - Top Constraint: Up to level: 0
6548957 | -1 fundering | 1270 | 265 | 0.0265 | 0.033655 | 0.33655 | 0.33655 | 0.033655 | 0 | bk. fundering | 0 | Finish Face: Interior | 0.33655 | 215 | Bouwkundig | Model Group:Penant Dubbel:5538645 | Constraints - Top Constraint: Up to level: 0
6548958 | -1 fundering | 1270 | 265 | 0.0265 | 0.033655 | 0.33655 | 0.33655 | 0.033655 | 0 | bk. fundering | 0 | Finish Face: Interior | 0.33655 | 215 | Bouwkundig | Model Group:Penant Dubbel:5538645 | Constraints - Top Constraint: Up to level: 0
6548961 | -1 fundering | 1270 | 265 | 0.0265 | 0.033655 | 0.33655 | 0.33655 | 0.033655 | 0 | bk. fundering | 0 | Finish Face: Interior | 0.33655 | 215 | Bouwkundig | Model Group:Penant Dubbel:5538649 | Constraints - Top Constraint: Up to level: 0
6548974 | -1 fundering | 1270 | 265 | 0.0265 | 0.033655 | 0.33655 | 0.33655 | 0.033655 | 0 | bk. fundering | 0 | Finish Face: Interior | 0.33655 | 215 | Bouwkundig | Model Group:Penant Dubbel:5538661 | Constraints - Top Constraint: Up to level: 0
6548977 | -1 fundering | 1270 | 265 | 0.0265 | 0.033655 | 0.33655 | 0.33655 | 0.033655 | 0 | bk. fundering | 0 | Finish Face: Interior | 0.33655 | 215 | Bouwkundig | Model Group:Penant Dubbel:5538665 | Constraints - Top Constraint: Up to level: 0
6548978 | -1 fundering | 1270 | 265 | 0.0265 | 0.033655 | 0.33655 | 0.33655 | 0.033655 | 0 | bk. fundering | 0 | Finish Face: Interior | 0.33655 | 215 | Bouwkundig | Model Group:Penant Dubbel:5538665 | Constraints - Top Constraint: Up to level: 0
6548981 | -1 fundering | 1270 | 265 | 0.0265 | 0.033655 | 0.33655 | 0.33655 | 0.033655 | 0 | bk. fundering | 0 | Finish Face: Interior | 0.33655 | 215 | Bouwkundig | Model Group:Penant Dubbel:5538669 | Constraints - Top Constraint: Up to level: 0
6548982 | -1 fundering | 1270 | 265 | 0.0265 | 0.033655 | 0.33655 | 0.33655 | 0.033655 | 0 | bk. fundering | 0 | Finish Face: Interior | 0.33655 | 215 | Bouwkundig | Model Group:Penant Dubbel:5538669 | Constraints - Top Constraint: Up to level: 0
6548985 | -1 fundering | 1270 | 265 | 0.0265 | 0.033655 | 0.33655 | 0.33655 | 0.033655 | 0 | bk. fundering | 0 | Finish Face: Interior | 0.33655 | 215 | Bouwkundig | Model Group:Penant Dubbel:5538673 | Constraints - Top Constraint: Up to level: 0
6549002 | -1 fundering | 1270 | 265 | 0.0265 | 0.033655 | 0.33655 | 0.33655 | 0.033655 | 0 | bk. fundering | 0 | Finish Face: Interior | 0.33655 | 215 | Bouwkundig | Model Group:Penant Dubbel:5539188 | Constraints - Top Constraint: Up to level: 0
6557441 | -1 fundering | 1270 | 265 | 0.0265 | 0.033655 | 0.33655 | 0.33655 | 0.033655 | 0 | bk. fundering | 0 | Finish Face: Interior | 0.33655 | 265 | Bouwkundig | Model Group:Penant Enkel:5538814 | Constraints - Top Constraint: Up to level: 0
6557545 | -1 fundering | 1270 | 265 | 0.0265 | 0.033655 | 0.33655 | 0.33655 | 0.033655 | 0 | bk. fundering | 0 | Finish Face: Interior | 0.33655 | 265 | Bouwkundig | Model Group:Penant Enkel:5536803 | Constraints - Top Constraint: Up to level: 0
6557548 | -1 fundering | 1270 | 265 | 0.0265 | 0.033655 | 0.33655 | 0.33655 | 0.033655 | 0 | bk. fundering | 0 | Finish Face: Interior | 0.33655 | 265 | Bouwkundig | Model Group:Penant Enkel:5536877 | Constraints - Top Constraint: Up to level: 0
6557551 | -1 fundering | 1270 | 265 | 0.0265 | 0.033655 | 0.33655 | 0.33655 | 0.033655 | 0 | bk. fundering | 0 | Finish Face: Interior | 0.33655 | 265 | Bouwkundig | Model Group:Penant Enkel:5536898 | Constraints - Top Constraint: Up to level: 0
6557554 | -1 fundering | 1270 | 265 | 0.0265 | 0.033655 | 0.33655 | 0.33655 | 0.033655 | 0 | bk. fundering | 0 | Finish Face: Interior | 0.33655 | 265 | Bouwkundig | Model Group:Penant Enkel:5537051 | Constraints - Top Constraint: Up to level: 0
6557557 | -1 fundering | 1270 | 265 | 0.0265 | 0.033655 | 0.33655 | 0.33655 | 0.033655 | 0 | bk. fundering | 0 | Finish Face: Interior | 0.33655 | 265 | Bouwkundig | Model Group:Penant Enkel:5537100 | Constraints - Top Constraint: Up to level: 0
6557560 | -1 fundering | 1270 | 265 | 0.0265 | 0.033655 | 0.33655 | 0.33655 | 0.033655 | 0 | bk. fundering | 0 | Finish Face: Interior | 0.33655 | 265 | Bouwkundig | Model Group:Penant Enkel:5539115 | Constraints - Top Constraint: Up to level: 0
6557563 | -1 fundering | 1270 | 265 | 0.0265 | 0.033655 | 0.33655 | 0.33655 | 0.033655 | 0 | bk. fundering | 0 | Finish Face: Interior | 0.33655 | 265 | Bouwkundig | Model Group:Penant Enkel:5539192 | Constraints - Top Constraint: Up to level: 0
6557868 | -1 fundering | 1270 | 265 | 0.0265 | 0.033655 | 0.33655 | 0.33655 | 0.033655 | 0 | bk. fundering | 0 | Finish Face: Interior | 0.33655 | 215 | Bouwkundig | Model Group:Penant Hoek:5539183 | Constraints - Top Constraint: Up to level: 0
6557871 | -1 fundering | 1270 | 350 | 0.035 | 0.04445 | 0.4445 | 0.4445 | 0.04445 | 0 | bk. fundering | 0 | Finish Face: Interior | 0.4445 | 255 | Bouwkundig | Model Group:Penant Hoek:5539183 | Constraints - Top Constraint: Up to level: 0
6557978 | -1 fundering | 1270 | 265 | 0.0265 | 0.033655 | 0.33655 | 0.33655 | 0.033655 | 0 | bk. fundering | 0 | Finish Face: Interior | 0.33655 | 215 | Bouwkundig | Model Group:Penant Hoek:5539155 | Constraints - Top Constraint: Up to level: 0
6871296 | 00 Begane grond | 2650 | 190 | 0.019 | 0.05035 | 0.5035 | 0.5035 | 0.05035 | 0 | 0 | 0 | Finish Face: Interior | 0.5035 | 270 | Bouwkundig
6871297 | 01 eerste verdieping | 4875 | 190 | 0.019 | 0.092625 | 0.92625 | 0.92625 | 0.092625 | 0 | 1 | -1000 | Finish Face: Interior | 0.92625 | 270 | Bouwkundig

# IfcWallStandardCase: Basic Wall:21_DAT_plaat, Basic Wall:21_DAT_plaat:6326294
In: 00 Begane grond
Type - PredefinedType: STANDARD; Material: ISR_Metselwerk_rood 50 mm
Type - Other - Category: Walls; Family Name: Basic Wall
Type - Construction - Function: Exterior; Wrapping at Inserts: Do not wrap; Width: 50 mm
Type - Graphics - Coarse Scale Fill Pattern: <Solid fill>; Coarse Scale Fill Color: 4210752
Type - Identity Data - Workset: Wall Types; Assembly Code: 21.12; Assembly Description: buitenwanden; niet constructief, spouwwanden; Description: Metselwerk 100mm; Type Name: 21_DAT_plaat
Type - Materials and Finishes - Structural Material: ISR_Metselwerk_rood
Type - Analytical Properties - Roughness: 1; Absorptance: 0.1
Type - Pset_ElementShading - Roughness: 304.8 mm
Type - Pset_ProductRequirements - Category: Walls
Type - Pset_ReinforcementBarPitchOfWall - Description: Metselwerk 100mm
Type - Pset_WallCommon - IsExternal: yes
Classification: 21.12 Uniformat (Uniformat)
BaseQuantities - Height: 915 mm; Length: 1540 mm; Width: 50 mm; GrossFootprintArea: 0.077 m2; GrossVolume: 0.070455 m3; GrossSideArea: 1.4091 m2; NetSideArea: 1.4091 m2; NetVolume: 0.070455 m3
Pset_QuantityTakeOff - Reference: 21_DAT_plaat; sets with these values: 2
Pset_WallCommon - ExtendToStructure: no; LoadBearing: no; Reference: 21_DAT_plaat
Pset_wanden - Structural Usage: Non-bearing; Omschrijving: Metselwerk 100mm; NL-sfb-Codering: 21.12
Pset_DAT_KMS - Assembly Code: 21.12; Assembly Description: buitenwanden; niet constructief, spouwwanden; Description: Metselwerk 100mm
Other - Family: Basic Wall; Family and Type: Basic Wall: 21_DAT_plaat; Type: 21_DAT_plaat; Type Id: 6326220
Constraints - Top Offset: 0 mm; Base Extension Distance: 0 mm; Base is Attached: no; Location Line: Finish Face: Interior; Related to Mass: no; Room Bounding: yes; Top Extension Distance: 0 mm; Top is Attached: no; Base Constraint: 0; Base Offset: 1048 mm; Unconnected Height: 915 mm
Dimensions - Area: 1.4091 m2; Length: 1540 mm; Volume: 0.070455 m3
Identity Data - Workset: Bouwkundig
Phasing - Phase Created: 2. nieuwbouw
Structural - Structural Usage: Non-bearing; Structural: no
Cross-Section Definition - Cross-Section: Vertical

# IfcWallStandardCase: Basic Wall:21_DAT_wand_HSB_150 (2)
In: 00 Begane grond
Type - PredefinedType: STANDARD; Material: ISR_Isolatie 150 mm, ISR_Multiplex 12.5 mm, ISR_Gips 12.5 mm
Type - Other - Category: Walls; Family Name: Basic Wall
Type - Construction - Function: Interior; Wrapping at Inserts: Do not wrap; Width: 175 mm
Type - Graphics - Coarse Scale Fill Pattern: <Solid fill>; Coarse Scale Fill Color: 4210752
Type - Identity Data - Workset: Wall Types; Assembly Code: 21.12; Assembly Description: buitenwanden; niet constructief, spouwwanden; Description: Samengesteld rekwerkBuitenplaat WBP 10mmHouten stijl- en regelwerk 38x140MiniralewolDampremmendefolieGipsplaat 12.5mmGipsvezelplaat 12,5mm; Type Comments: samenstelling 260-12-12,5; Type Name: 21_DAT_wand_HSB_150
Type - Materials and Finishes - Structural Material: ISR_Isolatie
Type - Analytical Properties - Roughness: 1; Absorptance: 0.1
Type - Pset_ElementShading - Roughness: 304.8 mm
Type - Pset_ProductRequirements - Category: Walls
Type - Pset_ReinforcementBarPitchOfWall - Description: Samengesteld rekwerkBuitenplaat WBP 10mmHouten stijl- en regelwerk 38x140MiniralewolDampremmendefolieGipsplaat 12.5mmGipsvezelplaat 12,5mm
Type - Pset_WallCommon - IsExternal: no
Classification: 21.12 Uniformat (Uniformat)
BaseQuantities - Height: 3310 mm; Width: 175 mm
Pset_QuantityTakeOff - Reference: 21_DAT_wand_HSB_150; sets with these values: 2
Pset_WallCommon - ExtendToStructure: no; LoadBearing: no; Reference: 21_DAT_wand_HSB_150
Pset_wanden - Structural Usage: Non-bearing; Omschrijving: Samengesteld rekwerkBuitenplaat WBP 10mmHouten stijl- en regelwerk 38x140MiniralewolDampremmendefolieGipsplaat 12.5mmGipsvezelplaat 12,5mm; NL-sfb-Codering: 21.12; sets with these values: 2
Pset_DAT_KMS - Assembly Code: 21.12; Assembly Description: buitenwanden; niet constructief, spouwwanden; Description: Samengesteld rekwerkBuitenplaat WBP 10mmHouten stijl- en regelwerk 38x140MiniralewolDampremmendefolieGipsplaat 12.5mmGipsvezelplaat 12,5mm
Other - Family: Basic Wall; Family and Type: Basic Wall: 21_DAT_wand_HSB_150; Type: 21_DAT_wand_HSB_150; Type Id: 147587
Constraints - Base Offset: 0 mm; Top Offset: 0 mm; Base Extension Distance: 0 mm; Base is Attached: no; Related to Mass: no; Room Bounding: yes; Top Extension Distance: 0 mm; Top is Attached: no; Location Line: Wall Centerline; Top Constraint: Up to level: V1 ok. ruwe vloer; Base Constraint: V0 bk. ruwe vloer; Unconnected Height: 3310 mm
Identity Data - Workset: Bouwkundig
Phasing - Phase Created: 2. nieuwbouw
Structural - Structural Usage: Non-bearing; Structural: no
Cross-Section Definition - Cross-Section: Vertical
Name (Basic Wall:21_DAT_wand_HSB_150:...) | BaseQuantities, Length (mm) = Dimensions, Length (mm) | GrossFootprintArea (m2) | GrossVolume (m3) = NetVolume (m3) = Volume (m3) | GrossSideArea (m2) = NetSideArea (m2) = Area (m2)
5999931 | 9065 | 1.58637 | 0.43897 | 2.5084
6003690 | 2835 | 0.496125 | 0.466235 | 2.6642

# IfcWallStandardCase: Basic Wall:21_DAT_zetwerk_2 (55)
Type - PredefinedType: STANDARD; Material: STAAL_RAL 7006 2 mm
Type - Other - Category: Walls; Family Name: Basic Wall
Type - Construction - Function: Exterior; Wrapping at Inserts: Do not wrap; Width: 2 mm
Type - Graphics - Coarse Scale Fill Pattern: <Solid fill>; Coarse Scale Fill Color: 4210752
Type - Identity Data - Workset: Wall Types; Assembly Code: 21.12; Assembly Description: buitenwanden; niet constructief, spouwwanden; Description: zetwerk 2mm in RAL: 7006; Type Comments: Aluminium zetwerk 2mm in RAL7006; Type Name: 21_DAT_zetwerk_2
Type - Analytical Properties - Roughness: 1; Absorptance: 0.1
Type - Pset_ElementShading - Roughness: 304.8 mm
Type - Pset_ProductRequirements - Category: Walls
Type - Pset_ReinforcementBarPitchOfWall - Description: zetwerk 2mm in RAL: 7006
Type - Pset_WallCommon - IsExternal: yes
Classification: 21.12 Uniformat (Uniformat)
BaseQuantities - Width: 2 mm
Pset_QuantityTakeOff - Reference: 21_DAT_zetwerk_2; sets with these values: 2
Pset_WallCommon - ExtendToStructure: no; LoadBearing: no; Reference: 21_DAT_zetwerk_2
Pset_wanden - Structural Usage: Non-bearing; Omschrijving: zetwerk 2mm in RAL: 7006; NL-sfb-Codering: 21.12
Pset_DAT_KMS - Assembly Code: 21.12; Assembly Description: buitenwanden; niet constructief, spouwwanden; Description: zetwerk 2mm in RAL: 7006
Other - Family: Basic Wall; Family and Type: Basic Wall: 21_DAT_zetwerk_2; Type: 21_DAT_zetwerk_2; Type Id: 4664595
Constraints - Base Extension Distance: 0 mm; Base is Attached: no; Related to Mass: no; Room Bounding: yes; Top Extension Distance: 0 mm; Top is Attached: no
Identity Data - Workset: Bouwkundig
Phasing - Phase Created: 2. nieuwbouw
Structural - Structural Usage: Non-bearing; Structural: no
Cross-Section Definition - Cross-Section: Vertical
Name (Basic Wall:21_DAT_zetwerk_2:...) | In | Height (mm) = Unconnected Height (mm) | BaseQuantities, Length (mm) | GrossFootprintArea (m2) | GrossVolume (m3) | GrossSideArea (m2) | NetSideArea (m2) = Area (m2) | NetVolume (m3) = Volume (m3) | Location Line | Base Constraint | Top Constraint | Base Offset (mm) | Top Offset (mm) | Dimensions, Length (mm) | Group
5538555 | 01 eerste verdieping | 1135 | 734 | 0.001468 | 0.00166618 | 0.83309 | 0.83309 | 0.00166618 | Finish Face: Interior | 1 | Up to level: V2 bk. ruwe vloer | 2740 | 375 | 734 | Model Group:K_Raamwerk_29a:5537822
5538556 | 01 eerste verdieping | 1120 | 2194 | 0.004388 | 0.00491456 | 2.45728 | 2.45728 | 0.00491456 | Finish Face: Interior | 1 | Up to level: V2 bk. ruwe vloer | 2740 | 360 | 2194 | Model Group:K_Raamwerk_22:5537838
5538557 | 01 eerste verdieping | 1120 | 2194 | 0.004388 | 0.00491456 | 2.45728 | 2.45728 | 0.00491456 | Finish Face: Interior | 1 | Up to level: V2 bk. ruwe vloer | 2740 | 360 | 2194 | Model Group:K_Raamwerk_22:5537759
5538558 | 01 eerste verdieping | 1120 | 2194 | 0.004388 | 0.00491456 | 2.45728 | 2.45728 | 0.00491456 | Finish Face: Interior | 1 | Up to level: V2 bk. ruwe vloer | 2740 | 360 | 2194 | Model Group:K_Raamwerk_22:5537763
5538559 | 01 eerste verdieping | 1120 | 2194 | 0.004388 | 0.00491456 | 2.45728 | 2.45728 | 0.00491456 | Finish Face: Interior | 1 | Up to level: V2 bk. ruwe vloer | 2740 | 360 | 2194 | Model Group:K_Raamwerk_22:5537767
5538560 | 01 eerste verdieping | 1120 | 2194 | 0.004388 | 0.00491456 | 2.45728 | 2.45728 | 0.00491456 | Finish Face: Interior | 1 | Up to level: V2 bk. ruwe vloer | 2740 | 360 | 2194 | Model Group:K_Raamwerk_22:5537771
5538561 | 01 eerste verdieping | 1120 | 2194 | 0.004388 | 0.00491456 | 2.45728 | 2.45728 | 0.00491456 | Finish Face: Interior | 1 | Up to level: V2 bk. ruwe vloer | 2740 | 360 | 2194 | Model Group:K_Raamwerk_22:5537775
5538562 | 01 eerste verdieping | 1120 | 2194 | 0.004388 | 0.00491456 | 2.45728 | 2.45728 | 0.00491456 | Finish Face: Interior | 1 | Up to level: V2 bk. ruwe vloer | 2740 | 360 | 2194 | Model Group:K_Raamwerk_22:5537779
5538563 | 01 eerste verdieping | 1120 | 2194 | 0.004388 | 0.00491456 | 2.45728 | 2.45728 | 0.00491456 | Finish Face: Interior | 1 | Up to level: V2 bk. ruwe vloer | 2740 | 360 | 2194 | Model Group:K_Raamwerk_22:5537846
5538564 | 01 eerste verdieping | 1120 | 2194 | 0.004388 | 0.00491456 | 2.45728 | 2.45728 | 0.00491456 | Finish Face: Interior | 1 | Up to level: V2 bk. ruwe vloer | 2740 | 360 | 2194 | Model Group:K_Raamwerk_22:5537870
5538565 | 01 eerste verdieping | 1120 | 2194 | 0.004388 | 0.00491456 | 2.45728 | 2.45728 | 0.00491456 | Finish Face: Interior | 1 | Up to level: V2 bk. ruwe vloer | 2740 | 360 | 2194 | Model Group:K_Raamwerk_22:5537878
5538566 | 01 eerste verdieping | 1120 | 2194 | 0.004388 | 0.00491456 | 2.45728 | 2.45728 | 0.00491456 | Finish Face: Interior | 1 | Up to level: V2 bk. ruwe vloer | 2740 | 360 | 2194 | Model Group:K_Raamwerk_22:5537902
5538567 | 01 eerste verdieping | 1120 | 2194 | 0.004388 | 0.00491456 | 2.45728 | 2.45728 | 0.00491456 | Finish Face: Interior | 1 | Up to level: V2 bk. ruwe vloer | 2740 | 360 | 2194 | Model Group:K_Raamwerk_22:5537910
5538568 | 01 eerste verdieping | 1120 | 2194 | 0.004388 | 0.00491456 | 2.45728 | 2.45728 | 0.00491456 | Finish Face: Interior | 1 | Up to level: V2 bk. ruwe vloer | 2740 | 360 | 2194 | Model Group:K_Raamwerk_22:5537934
5538569 | 01 eerste verdieping | 1120 | 2194 | 0.004388 | 0.00491456 | 2.45728 | 2.45728 | 0.00491456 | Finish Face: Interior | 1 | Up to level: V2 bk. ruwe vloer | 2740 | 360 | 2194 | Model Group:K_Raamwerk_22:5537942
5538570 | 01 eerste verdieping | 1135 | 1539 | 0.003078 | 0.00349353 | 1.74677 | 1.74677 | 0.00349353 | Finish Face: Interior | 1 | Up to level: V2 bk. ruwe vloer | 2740 | 375 | 1539
5538571 | 01 eerste verdieping | 1120 | 734 | 0.001468 | 0.00164416 | 0.82208 | 0.82208 | 0.00164416 | Finish Face: Interior | 1 | Up to level: V2 bk. ruwe vloer | 2740 | 360 | 734 | Model Group:K_Raamwerk_29:5537834
5538572 | 01 eerste verdieping | 1120 | 734 | 0.001468 | 0.00164416 | 0.82208 | 0.82208 | 0.00164416 | Finish Face: Interior | 1 | Up to level: V2 bk. ruwe vloer | 2740 | 360 | 734 | Model Group:K_Raamwerk_29:5537783
5538573 | 01 eerste verdieping | 1120 | 734 | 0.001468 | 0.00164416 | 0.82208 | 0.82208 | 0.00164416 | Finish Face: Interior | 1 | Up to level: V2 bk. ruwe vloer | 2740 | 360 | 734 | Model Group:K_Raamwerk_29:5537787
5538574 | 01 eerste verdieping | 1120 | 734 | 0.001468 | 0.00164416 | 0.82208 | 0.82208 | 0.00164416 | Finish Face: Interior | 1 | Up to level: V2 bk. ruwe vloer | 2740 | 360 | 734 | Model Group:K_Raamwerk_29:5537791
5538575 | 01 eerste verdieping | 1120 | 734 | 0.001468 | 0.00164416 | 0.82208 | 0.82208 | 0.00164416 | Finish Face: Interior | 1 | Up to level: V2 bk. ruwe vloer | 2740 | 360 | 734 | Model Group:K_Raamwerk_29:5537795
5538576 | 01 eerste verdieping | 1120 | 734 | 0.001468 | 0.00164416 | 0.82208 | 0.82208 | 0.00164416 | Finish Face: Interior | 1 | Up to level: V2 bk. ruwe vloer | 2740 | 360 | 734 | Model Group:K_Raamwerk_29:5537799
5538577 | 01 eerste verdieping | 1120 | 734 | 0.001468 | 0.00164416 | 0.82208 | 0.82208 | 0.00164416 | Finish Face: Interior | 1 | Up to level: V2 bk. ruwe vloer | 2740 | 360 | 734 | Model Group:K_Raamwerk_29:5537803
5538578 | 01 eerste verdieping | 1120 | 734 | 0.001468 | 0.00164416 | 0.82208 | 0.82208 | 0.00164416 | Finish Face: Interior | 1 | Up to level: V2 bk. ruwe vloer | 2740 | 360 | 734 | Model Group:K_Raamwerk_29:5537807
5538579 | 01 eerste verdieping | 1120 | 734 | 0.001468 | 0.00164416 | 0.82208 | 0.82208 | 0.00164416 | Finish Face: Interior | 1 | Up to level: V2 bk. ruwe vloer | 2740 | 360 | 734 | Model Group:K_Raamwerk_29:5537811
5538580 | 01 eerste verdieping | 1120 | 734 | 0.001468 | 0.00164416 | 0.82208 | 0.82208 | 0.00164416 | Finish Face: Interior | 1 | Up to level: V2 bk. ruwe vloer | 2740 | 360 | 734 | Model Group:K_Raamwerk_29:5537858
5538581 | 01 eerste verdieping | 1120 | 734 | 0.001468 | 0.00164416 | 0.82208 | 0.82208 | 0.00164416 | Finish Face: Interior | 1 | Up to level: V2 bk. ruwe vloer | 2740 | 360 | 734 | Model Group:K_Raamwerk_29:5537866
5538582 | 01 eerste verdieping | 1120 | 734 | 0.001468 | 0.00164416 | 0.82208 | 0.82208 | 0.00164416 | Finish Face: Interior | 1 | Up to level: V2 bk. ruwe vloer | 2740 | 360 | 734 | Model Group:K_Raamwerk_29:5537890
5538583 | 01 eerste verdieping | 1120 | 734 | 0.001468 | 0.00164416 | 0.82208 | 0.82208 | 0.00164416 | Finish Face: Interior | 1 | Up to level: V2 bk. ruwe vloer | 2740 | 360 | 734 | Model Group:K_Raamwerk_29:5537898
5538584 | 01 eerste verdieping | 1120 | 734 | 0.001468 | 0.00164416 | 0.82208 | 0.82208 | 0.00164416 | Finish Face: Interior | 1 | Up to level: V2 bk. ruwe vloer | 2740 | 360 | 734 | Model Group:K_Raamwerk_29:5537922
5538585 | 01 eerste verdieping | 1120 | 734 | 0.001468 | 0.00164416 | 0.82208 | 0.82208 | 0.00164416 | Finish Face: Interior | 1 | Up to level: V2 bk. ruwe vloer | 2740 | 360 | 734 | Model Group:K_Raamwerk_29:5537930
5538586 | 01 eerste verdieping | 1120 | 734 | 0.001468 | 0.00164416 | 0.82208 | 0.82208 | 0.00164416 | Finish Face: Interior | 1 | Up to level: V2 bk. ruwe vloer | 2740 | 360 | 734 | Model Group:K_Raamwerk_29:5537954
5538587 | 01 eerste verdieping | 1135 | 3394 | 0.006788 | 0.00770438 | 3.85219 | 3.85219 | 0.00770438 | Finish Face: Interior | 1 | Up to level: V2 bk. ruwe vloer | 2740 | 375 | 3394
5538595 | 01 eerste verdieping | 1145 | 1105 | 0.00221 | 0.00253045 | 1.26522 | 1.26522 | 0.00253045 | Finish Face: Interior | 1 | Up to level: V2 bk. ruwe vloer | 2730 | 375 | 1155 | Model Group:K_Raamwerk_25:5537969
5538596 | 01 eerste verdieping | 1125 | 734 | 0.001468 | 0.0016515 | 0.82575 | 0.82575 | 0.0016515 | Finish Face: Interior | 1 | Up to level: V2 bk. ruwe vloer | 2750 | 375 | 734
5538597 | 01 eerste verdieping | 1125 | 734 | 0.001468 | 0.0016515 | 0.82575 | 0.82575 | 0.0016515 | Finish Face: Interior | 1 | Up to level: V2 bk. ruwe vloer | 2750 | 375 | 734
5538598 | 01 eerste verdieping | 1125 | 734 | 0.001468 | 0.0016515 | 0.82575 | 0.82575 | 0.0016515 | Finish Face: Interior | 1 | Up to level: V2 bk. ruwe vloer | 2750 | 375 | 734
5538599 | 01 eerste verdieping | 1125 | 734 | 0.001468 | 0.0016515 | 0.82575 | 0.82575 | 0.0016515 | Finish Face: Interior | 1 | Up to level: V2 bk. ruwe vloer | 2750 | 375 | 734
5538600 | 01 eerste verdieping | 1125 | 734 | 0.001468 | 0.0016515 | 0.82575 | 0.82575 | 0.0016515 | Finish Face: Interior | 1 | Up to level: V2 bk. ruwe vloer | 2750 | 375 | 734
5538601 | 01 eerste verdieping | 1125 | 734 | 0.001468 | 0.0016515 | 0.82575 | 0.82575 | 0.0016515 | Finish Face: Interior | 1 | Up to level: V2 bk. ruwe vloer | 2750 | 375 | 734
5538602 | 01 eerste verdieping | 1125 | 2074 | 0.004148 | 0.0046665 | 2.33325 | 2.33325 | 0.0046665 | Finish Face: Interior | 1 | Up to level: V2 bk. ruwe vloer | 2750 | 375 | 2074
5538603 | 01 eerste verdieping | 1135 | 2194 | 0.004388 | 0.00498038 | 2.49019 | 2.49019 | 0.00498038 | Finish Face: Interior | 1 | Up to level: V2 bk. ruwe vloer | 2740 | 375 | 2194
5720869 | 00 Begane grond | 805 | 1539 | 0.003078 | 0.00247779 | 1.2389 | 1.2389 | 0.00247779 | Finish Face: Interior | 0 | Up to level: 1 | 2825 | -20 | 1539
5721019 | 00 Begane grond | 805 | 3394 | 0.006788 | 0.00546434 | 2.73217 | 2.73217 | 0.00546434 | Finish Face: Interior | 0 | Up to level: 1 | 2825 | -20 | 3394
6480647 | 00 Begane grond | 2640 | 688 | 0.001376 | 0.00363264 | 1.81632 | 1.8035 | 0.003607 | Finish Face: Interior | 0 |  | 10 | 0 | 688
6662358 | 00 Begane grond | 2640 | 168 | 0.000336 | 0.00088704 | 0.44352 | 0.44352 | 0.00088704 | Finish Face: Interior | 0 |  | 10 | 0 | 167
6662418 | 00 Begane grond | 2630 | 372 | 0.000744 | 0.00195672 | 0.97836 | 0.97836 | 0.00195672 | Finish Face: Interior | 0 |  | 10 | 0 | 372
6662486 | 00 Begane grond | 2640 | 166 | 0.000332 | 0.00087648 | 0.43824 | 0.43824 | 0.00087648 | Finish Face: Interior | 0 |  | 10 | 0 | 167
6871382 | 00 Begane grond | 2635 | 920 | 0.00184 | 0.0048484 | 2.4242 | 2.4242 | 0.0048484 | Wall Centerline | 0 |  | 5 | 0 | 920 | Other - Doorvalveilig 1-zijdig: no; Doorvalveilig 2-zijdig: yes; Text - NLRS_C_merk: K01
6871574 | 00 Begane grond | 2635 | 920 | 0.00184 | 0.0048484 | 2.4242 | 2.4242 | 0.0048484 | Wall Centerline | 0 |  | 5 | 0 | 920 | Other - Doorvalveilig 1-zijdig: no; Doorvalveilig 2-zijdig: yes; Text - NLRS_C_merk: K01
6871582 | 00 Begane grond | 2635 | 920 | 0.00184 | 0.0048484 | 2.4242 | 2.4242 | 0.0048484 | Wall Centerline | 0 |  | 5 | 0 | 920 | Other - Doorvalveilig 1-zijdig: no; Doorvalveilig 2-zijdig: yes; Text - NLRS_C_merk: K01
6871594 | 00 Begane grond | 2635 | 900 | 0.0018 | 0.004743 | 2.3715 | 2.3715 | 0.004743 | Wall Centerline | 0 |  | 5 | 0 | 900 | Other - Doorvalveilig 1-zijdig: no; Doorvalveilig 2-zijdig: yes; Text - NLRS_C_merk: K01
6871602 | 00 Begane grond | 2635 | 900 | 0.0018 | 0.004743 | 2.3715 | 2.3715 | 0.004743 | Wall Centerline | 0 |  | 5 | 0 | 900 | Other - Doorvalveilig 1-zijdig: no; Doorvalveilig 2-zijdig: yes; Text - NLRS_C_merk: K01
6871610 | 00 Begane grond | 2635 | 920 | 0.00184 | 0.0048484 | 2.4242 | 2.4242 | 0.0048484 | Wall Centerline | 0 |  | 5 | 0 | 920 | Other - Doorvalveilig 1-zijdig: no; Doorvalveilig 2-zijdig: yes; Text - NLRS_C_merk: K01
6871731 | 00 Begane grond | 2635 | 740 | 0.00148 | 0.0038998 | 1.9499 | 1.9499 | 0.0038998 | Wall Centerline | 0 |  | 5 | 0 | 740 | Other - Doorvalveilig 1-zijdig: no; Doorvalveilig 2-zijdig: yes; Text - NLRS_C_merk: K01

# IfcWallStandardCase: Basic Wall:22_DAT_binnenwand_100 (23)
Type - PredefinedType: STANDARD; Material: ISR_Binnenwand 100 mm
Type - Other - Category: Walls; Family Name: Basic Wall
Type - Construction - Function: Interior; Wrapping at Inserts: Do not wrap; Width: 100 mm
Type - Graphics - Coarse Scale Fill Pattern: <Solid fill>; Coarse Scale Fill Color: 12632256
Type - Identity Data - Workset: Wall Types; Assembly Code: 22.13; Assembly Description: binnenwanden; niet constructief, systeemwanden; vast; Description: Lichte scheidingswand 100mm75mm ms wand gevuld met isolatieVulling afhankelijk van gestelde eisen ingeluidsrapportageGipsplaat 12,5mmGipsvezelplaat 12,5mm; Type Comments: Lichte scheidingswand 100mm75mm ms wand gevuld met isolatieVulling afhankelijk van gestelde eisen ingeluidsrapportageGipsplaat 12,5mmGipsvezelplaat 12,5mm; Type Name: 22_DAT_binnenwand_100
Type - Materials and Finishes - Structural Material: ISR_Binnenwand
Type - Analytical Properties - Roughness: 1; Absorptance: 0.1
Type - Pset_ElementShading - Roughness: 304.8 mm
Type - Pset_ProductRequirements - Category: Walls
Type - Pset_ReinforcementBarPitchOfWall - Description: Lichte scheidingswand 100mm75mm ms wand gevuld met isolatieVulling afhankelijk van gestelde eisen ingeluidsrapportageGipsplaat 12,5mmGipsvezelplaat 12,5mm
Type - Pset_WallCommon - IsExternal: no
Classification: 22.13 Uniformat (Uniformat)
BaseQuantities - Width: 100 mm
Pset_QuantityTakeOff - Reference: 22_DAT_binnenwand_100; sets with these values: 2
Pset_WallCommon - ExtendToStructure: no; LoadBearing: no; Reference: 22_DAT_binnenwand_100
Pset_wanden - Structural Usage: Non-bearing; Omschrijving: Lichte scheidingswand 100mm75mm ms wand gevuld met isolatieVulling afhankelijk van gestelde eisen ingeluidsrapportageGipsplaat 12,5mmGipsvezelplaat 12,5mm; NL-sfb-Codering: 22.13
Pset_DAT_KMS - Assembly Code: 22.13; Assembly Description: binnenwanden; niet constructief, systeemwanden; vast; Description: Lichte scheidingswand 100mm75mm ms wand gevuld met isolatieVulling afhankelijk van gestelde eisen ingeluidsrapportageGipsplaat 12,5mmGipsvezelplaat 12,5mm
Other - Family: Basic Wall; Family and Type: Basic Wall: 22_DAT_binnenwand_100; Type: 22_DAT_binnenwand_100; Type Id: 589402
Constraints - Base Extension Distance: 0 mm; Base is Attached: no; Related to Mass: no; Room Bounding: yes; Top Extension Distance: 0 mm; Top is Attached: no; Location Line: Wall Centerline
Identity Data - Workset: Bouwkundig
Phasing - Phase Created: 2. nieuwbouw
Structural - Structural Usage: Non-bearing; Structural: no
Cross-Section Definition - Cross-Section: Vertical
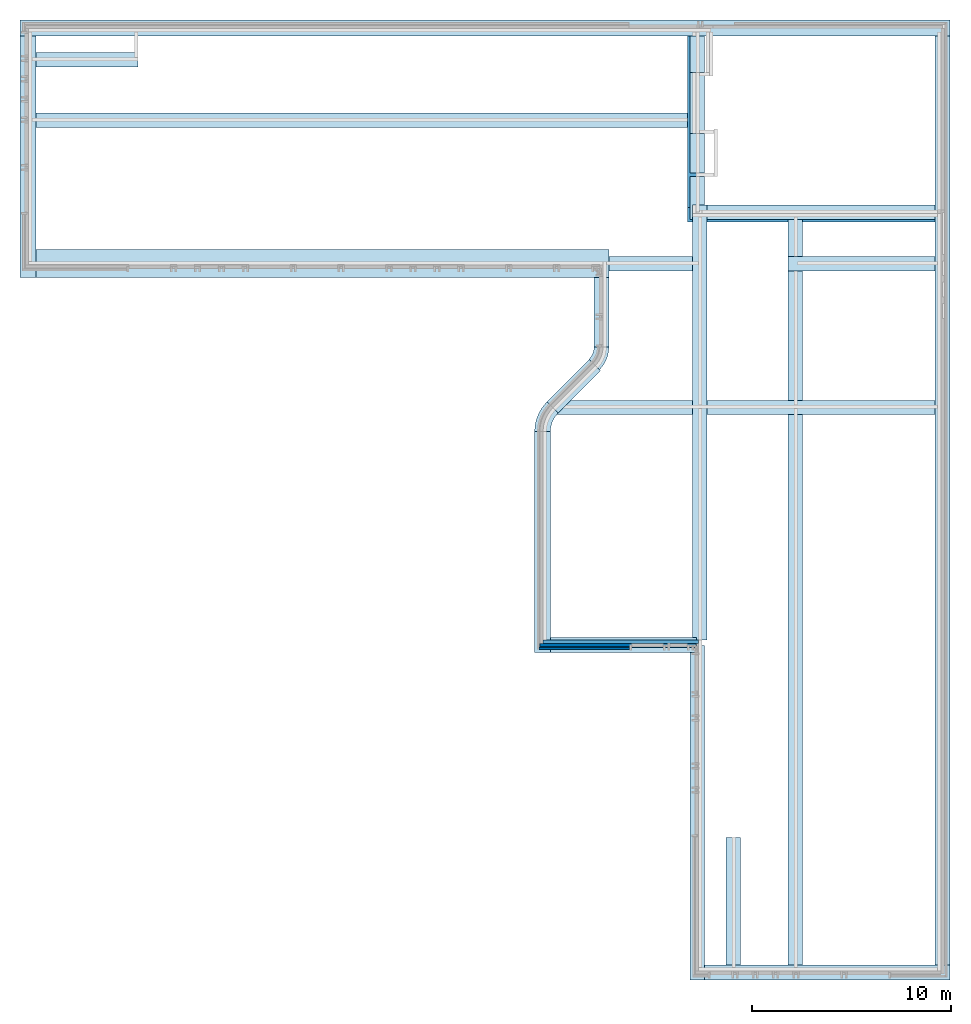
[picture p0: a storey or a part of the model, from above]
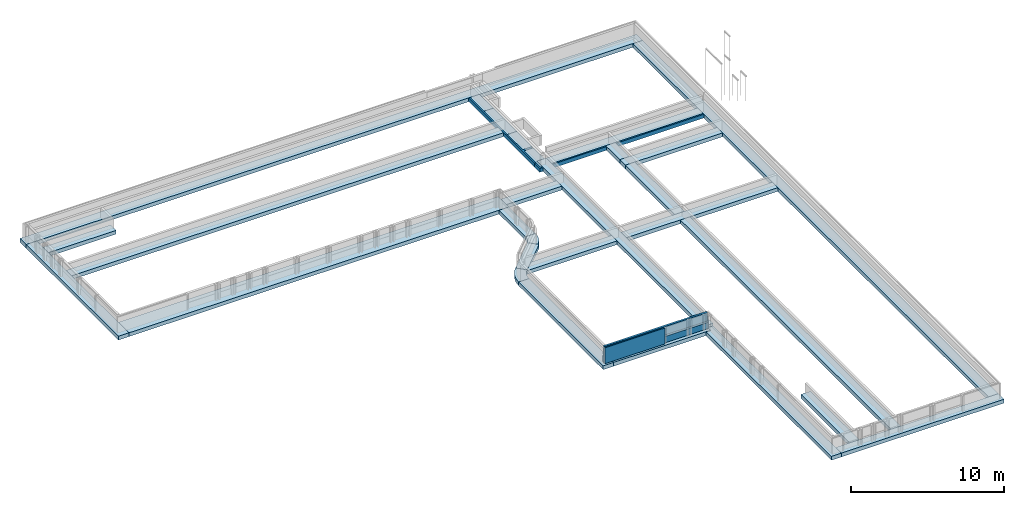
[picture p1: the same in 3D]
Properties of the parts of a building model (IFC2X3), part 33 of 37

# IfcWallStandardCase: Basic Wall:22_DAT_binnenwand_100 (23)
Name (Basic Wall:22_DAT_binnenwand_100:...) | In | Height (mm) = Unconnected Height (mm) | BaseQuantities, Length (mm) | GrossFootprintArea (m2) | GrossVolume (m3) = NetVolume (m3) = Volume (m3) | GrossSideArea (m2) = NetSideArea (m2) = Area (m2) | Base Offset (mm) | Top Offset (mm) | Base Constraint | Top Constraint | Dimensions, Length (mm)
4963003 | 00 Begane grond | 3240 | 903 | 0.0903 | 0.292572 | 2.92572 | 0 | 0 | 0 | Up to level: V1 ok. ruwe vloer | 965.5 | Pset_wanden - NLRS_C_brandwerendheid: 30; Fire Protection - NLRS_C_brandwerendheid: 30
4967366 | -1 Speelvloer | 3240 | 700 | 0.07 | 0.2268 | 2.268 | 600 | 0 | V-1 | Up to level: V1 ok. ruwe vloer | 750
4973743 | 00 Begane grond | 3240 | 537.001 | 0.0537001 | 0.173988 | 1.73988 | 0 | 0 | 0 | Up to level: V1 ok. ruwe vloer | 599.501
5167727 | 01 eerste verdieping | 3240 | 1685 | 0.1685 | 0.54594 | 5.4594 | 0 | 0.0000290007 | 1 | Up to level: V2 ok. ruwe vloer | 1797.5
5168024 | 01 eerste verdieping | 3240 | 240 | 0.024 | 0.07776 | 0.7776 | 0 | 0.0000290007 | 1 | Up to level: V2 ok. ruwe vloer | 127.5
5216470 | 00 Begane grond | 3240 | 1048.5 | 0.10485 | 0.339714 | 3.39714 | 0 | 0 | 0 | Up to level: V1 ok. ruwe vloer | 1173.5
5228464 | 00 Begane grond | 3240 | 800 | 0.08 | 0.2592 | 2.592 | 0 | 0 | 0 | Up to level: V1 ok. ruwe vloer | 800
5229194 | 01 eerste verdieping | 3240 | 1060.98 | 0.106098 | 0.343758 | 3.43758 | 0 | 0.0000290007 | 1 | Up to level: V2 ok. ruwe vloer | 1185.98
5910609 | 01 eerste verdieping | 3240 | 1100 | 0.11 | 0.3564 | 3.564 | 0 | 0 | 1 | Up to level: V2 ok. ruwe vloer | 1212.5
5910645 | 01 eerste verdieping | 2400 | 250 | 0.025 | 0.06 | 0.6 | 0 | -840 | 1 | Up to level: V2 ok. ruwe vloer | 137.5
6145391 | 00 Begane grond | 3240 | 675 | 0.0675 | 0.2187 | 2.187 | 0 | 0 | 0 | Up to level: V1 ok. ruwe vloer | 675
6145543 | 00 Begane grond | 3240 | 280 | 0.028 | 0.09072 | 0.9072 | 0 | 0 | 0 | Up to level: V1 ok. ruwe vloer | 280
6145762 | -1 Speelvloer | 3840 | 575 | 0.0575 | 0.2208 | 2.208 | 0 | 0 | V-1 | Up to level: V1 ok. ruwe vloer | 625
6146249 | 00 Begane grond | 3650 | 300 | 0.03 | 0.1095 | 1.095 | 0 | 0 | 0 | Up to level: 1 | 300
6238602 | 00 Begane grond | 2680 | 920 | 0.092 | 0.24656 | 2.4656 | -40 | -600 | 0 | Up to level: V1 ok. ruwe vloer | 920 | Group: Model Group:Dicht kozijn:6238663
6238865 | 00 Begane grond | 2680 | 920 | 0.092 | 0.24656 | 2.4656 | -40 | -600 | 0 | Up to level: V1 ok. ruwe vloer | 920 | Group: Model Group:Dicht kozijn:6238866
6238877 | 00 Begane grond | 2680 | 920 | 0.092 | 0.24656 | 2.4656 | -40 | -600 | 0 | Up to level: V1 ok. ruwe vloer | 920 | Group: Model Group:Dicht kozijn:6238878
6238889 | 00 Begane grond | 2680 | 920 | 0.092 | 0.24656 | 2.4656 | -40 | -600 | 0 | Up to level: V1 ok. ruwe vloer | 920 | Group: Model Group:Dicht kozijn:6238890
6694600 | 00 Begane grond | 3240 | 265 | 0.0265 | 0.08586 | 0.8586 | 0 | 0 | 0 | Up to level: V1 ok. ruwe vloer | 327.5
6886427 | 01 eerste verdieping | 1200 | 935 | 0.0935 | 0.1122 | 1.122 | 0 | 0.0000290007 | 1 |  | 997.5
6889414 | 01 eerste verdieping | 1200 | 1060 | 0.106 | 0.1272 | 1.272 | 0 | 0.0000290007 | 1 |  | 997.5
6905424 | 00 Begane grond | 2680 | 920 | 0.092 | 0.24656 | 2.4656 | -40 | -600 | 0 | Up to level: V1 ok. ruwe vloer | 920 | Group: Model Group:Dicht kozijn:6905425
6905435 | 00 Begane grond | 2680 | 920 | 0.092 | 0.24656 | 2.4656 | -40 | -600 | 0 | Up to level: V1 ok. ruwe vloer | 920 | Group: Model Group:Dicht kozijn:6905436

# IfcWallStandardCase: Basic Wall:22_DAT_binnenwand_12 HPL (7)
Type - PredefinedType: STANDARD; Material: ISR_HPL Kleur hout 12 mm
Type - Other - Category: Walls; Family Name: Basic Wall
Type - Construction - Function: Interior; Wrapping at Inserts: Do not wrap; Width: 12 mm
Type - Graphics - Coarse Scale Fill Pattern: <Solid fill>; Coarse Scale Fill Color: 12632256
Type - Identity Data - Workset: Wall Types; Assembly Code: 22.13; Assembly Description: binnenwanden; niet constructief, systeemwanden; vast; Description: Lichte scheidingswand 125mmAan weerszijden gipsvezelplaat 12,5mmGipsplaat 12,5mm Met daartussen 75mm ms wand gevuld met isolatieVulling afhankelijk van gestelde eisen ingeluidsrapportage; Type Name: 22_DAT_binnenwand_12 HPL
Type - Analytical Properties - Roughness: 1; Absorptance: 0.1
Type - Pset_ElementShading - Roughness: 304.8 mm
Type - Pset_ProductRequirements - Category: Walls
Type - Pset_ReinforcementBarPitchOfWall - Description: Lichte scheidingswand 125mmAan weerszijden gipsvezelplaat 12,5mmGipsplaat 12,5mm Met daartussen 75mm ms wand gevuld met isolatieVulling afhankelijk van gestelde eisen ingeluidsrapportage
Type - Pset_WallCommon - IsExternal: no
Classification: 22.13 Uniformat (Uniformat)
BaseQuantities - Width: 12 mm
Pset_QuantityTakeOff - Reference: 22_DAT_binnenwand_12 HPL; sets with these values: 2
Pset_WallCommon - ExtendToStructure: no; LoadBearing: no; Reference: 22_DAT_binnenwand_12 HPL
Pset_wanden - Structural Usage: Non-bearing; Omschrijving: Lichte scheidingswand 125mmAan weerszijden gipsvezelplaat 12,5mmGipsplaat 12,5mm Met daartussen 75mm ms wand gevuld met isolatieVulling afhankelijk van gestelde eisen ingeluidsrapportage; NL-sfb-Codering: 22.13
Pset_DAT_KMS - Assembly Code: 22.13; Assembly Description: binnenwanden; niet constructief, systeemwanden; vast; Description: Lichte scheidingswand 125mmAan weerszijden gipsvezelplaat 12,5mmGipsplaat 12,5mm Met daartussen 75mm ms wand gevuld met isolatieVulling afhankelijk van gestelde eisen ingeluidsrapportage
Other - Family: Basic Wall; Family and Type: Basic Wall: 22_DAT_binnenwand_12 HPL; Type: 22_DAT_binnenwand_12 HPL; Type Id: 6332429
Constraints - Base Extension Distance: 0 mm; Base is Attached: no; Related to Mass: no; Room Bounding: yes; Top Extension Distance: 0 mm; Top is Attached: no; Location Line: Wall Centerline
Identity Data - Workset: Bouwkundig
Phasing - Phase Created: 2. nieuwbouw
Structural - Structural Usage: Non-bearing; Structural: no
Cross-Section Definition - Cross-Section: Vertical
Name (Basic Wall:22_DAT_binnenwand_12 HPL:...) | In | Height (mm) = Unconnected Height (mm) | BaseQuantities, Length (mm) | GrossFootprintArea (m2) | GrossVolume (m3) = NetVolume (m3) = Volume (m3) | GrossSideArea (m2) = NetSideArea (m2) = Area (m2) | Base Offset (mm) | Base Constraint | Top Constraint | Top Offset (mm) | Dimensions, Length (mm)
6332496 | 00 Begane grond | 2390 | 178.06 | 0.00213672 | 0.00510676 | 0.425563 | 0 | 0 | Up to level: V1 ok. ruwe vloer | -850 | 178.06
6332614 | 00 Begane grond | 2390 | 356.94 | 0.00428328 | 0.010237 | 0.853087 | 0 | 0 | Up to level: V1 ok. ruwe vloer | -850 | 356.94
6332778 | 00 Begane grond | 67 | 1866 | 0.022392 | 0.00150026 | 0.125022 | 2323 | 0 | Up to level: V1 ok. ruwe vloer | -850 | 1866
6370446 | 01 eerste verdieping | 2400 | 1200 | 0.0144 | 0.03456 | 2.88 | 0 | 1 | Up to level: 2 | -1100 | 1262.5
6420855 | 00 Begane grond | 2390 | 283 | 0.003396 | 0.00811644 | 0.67637 | 0 | 0 | Up to level: V1 ok. ruwe vloer | -850 | 283
6641065 | 00 Begane grond | 1715 | 430.042 | 0.0051605 | 0.00885026 | 0.737522 | 0 | 0 |  | 0 | 430.042
6671221 | 00 Begane grond | 1715 | 445.042 | 0.0053405 | 0.00915896 | 0.763247 | 0 | 0 |  | 0 | 445.042

# IfcWallStandardCase: Basic Wall:22_DAT_binnenwand_125 (155)
Type - PredefinedType: STANDARD; Material: ISR_Gips 1 mm, ISR_Binnenwand 123 mm, ISR_Gips 1 mm
Type - Other - Category: Walls; Family Name: Basic Wall
Type - Construction - Wrapping at Inserts: Both; Function: Interior; Width: 125 mm; Wrapping at Ends: Interior
Type - Graphics - Coarse Scale Fill Pattern: <Solid fill>; Coarse Scale Fill Color: 12632256
Type - Identity Data - Workset: Wall Types; Assembly Code: 22.13; Assembly Description: binnenwanden; niet constructief, systeemwanden; vast; Description: Lichte scheidingswand 125mmAan weerszijden gipsvezelplaat 12,5mmGipsplaat 12,5mm Met daartussen 75mm ms wand gevuld met isolatieVulling afhankelijk van gestelde eisen ingeluidsrapportage; Type Comments: Lichte scheidingswand 125mmGipsvezelplaat 12.5mmGipsplaat 12.5mmMS-wand 75 mm gevuld met isolatieGipsplaat 12.5mmGipsvezelplaat 12.5mmvulling afhankelijk van gestelde eisen ingeluidrapportage; Type Name: 22_DAT_binnenwand_125
Type - Materials and Finishes - Structural Material: ISR_Binnenwand
Type - Analytical Properties - Roughness: 1; Absorptance: 0.1
Type - Pset_ElementShading - Roughness: 304.8 mm
Type - Pset_ProductRequirements - Category: Walls
Type - Pset_ReinforcementBarPitchOfWall - Description: Lichte scheidingswand 125mmAan weerszijden gipsvezelplaat 12,5mmGipsplaat 12,5mm Met daartussen 75mm ms wand gevuld met isolatieVulling afhankelijk van gestelde eisen ingeluidsrapportage
Type - Pset_WallCommon - IsExternal: no
Classification: 22.13 Uniformat (Uniformat)
BaseQuantities - Width: 125 mm
Pset_QuantityTakeOff - Reference: 22_DAT_binnenwand_125; sets with these values: 2
Pset_WallCommon - ExtendToStructure: no; LoadBearing: no; Reference: 22_DAT_binnenwand_125
Pset_wanden - Structural Usage: Non-bearing; Omschrijving: Lichte scheidingswand 125mmAan weerszijden gipsvezelplaat 12,5mmGipsplaat 12,5mm Met daartussen 75mm ms wand gevuld met isolatieVulling afhankelijk van gestelde eisen ingeluidsrapportage; NL-sfb-Codering: 22.13
Pset_DAT_KMS - Assembly Code: 22.13; Assembly Description: binnenwanden; niet constructief, systeemwanden; vast; Description: Lichte scheidingswand 125mmAan weerszijden gipsvezelplaat 12,5mmGipsplaat 12,5mm Met daartussen 75mm ms wand gevuld met isolatieVulling afhankelijk van gestelde eisen ingeluidsrapportage
Other - Family: Basic Wall; Family and Type: Basic Wall: 22_DAT_binnenwand_125; Type: 22_DAT_binnenwand_125; Type Id: 589403
Constraints - Base Extension Distance: 0 mm; Base is Attached: no; Related to Mass: no; Room Bounding: yes; Top Extension Distance: 0 mm; Top is Attached: no
Phasing - Phase Created: 2. nieuwbouw
Structural - Structural Usage: Non-bearing; Structural: no
Cross-Section Definition - Cross-Section: Vertical
Name (Basic Wall:22_DAT_binnenwand_125:...) | In | Height (mm) | BaseQuantities, Length (mm) | GrossFootprintArea (m2) | GrossVolume (m3) | GrossSideArea (m2) | NetSideArea (m2) | NetVolume (m3) = Volume (m3) | Base Offset (mm) | Top Offset (mm) | Base Constraint | Location Line | Unconnected Height (mm) | Area (m2) | Dimensions, Length (mm) | Workset | Top Constraint
4752845 | 01 eerste verdieping | 810 | 5065 | 0.633125 | 0.512831 | 4.10265 | 4.10265 | 0.512831 | 0 | 0 | 1 | Wall Centerline | 810 | 4.10265 | 5152.5 | Constructie
4962149 | 00 Begane grond | 3240 | 8422 | 1.05275 | 2.48419 | 19.8735 | 19.1595 | 2.39494 | 0 | 0 | 0 | Wall Centerline | 3240 | 19.1595 | 8422 | Bouwkundig | Up to level: V1 ok. ruwe vloer
4962406 | 00 Begane grond | 3240 | 8422 | 1.05275 | 3.102 | 24.816 | 24.102 | 3.01275 | 0 | 0 | 0 | Wall Centerline | 3240 | 24.102 | 8422 | Bouwkundig | Up to level: V1 ok. ruwe vloer
4962846 | 00 Begane grond | 3240 | 3625 | 0.453125 | 1.46813 | 11.745 | 11.745 | 1.46813 | 0 | 0 | 0 | Wall Centerline | 3240 | 11.745 | 3750 | Bouwkundig | Up to level: V1 ok. ruwe vloer | Pset_wanden - NLRS_C_brandwerendheid: R200; Fire Protection - NLRS_C_brandwerendheid: R200
4962988 | 00 Begane grond | 3240 | 5125 | 0.640625 | 1.45781 | 11.6625 | 11.6625 | 1.45781 | 0 | 0 | 0 | Wall Centerline | 3240 | 11.6625 | 5125 | Bouwkundig | Up to level: V1 ok. ruwe vloer
4962990 | 00 Begane grond | 3240 | 3625 | 0.453125 | 1.15922 | 9.27374 | 8.64964 | 1.08121 | 0 | 0 | 0 | Wall Centerline | 3240 | 8.64964 | 3750 | Bouwkundig | Up to level: V1 ok. ruwe vloer
4963125 | 00 Begane grond | 3240 | 3625 | 0.453125 | 1.46813 | 11.745 | 11.745 | 1.46813 | 0 | 0 | 0 | Wall Centerline | 3240 | 11.745 | 3750 | Bouwkundig | Up to level: V1 ok. ruwe vloer
4963170 | 00 Begane grond | 3240 | 3625 | 0.453125 | 1.46813 | 11.745 | 11.745 | 1.46813 | 0 | 0 | 0 | Wall Centerline | 3240 | 11.745 | 3750 | Bouwkundig | Up to level: V1 ok. ruwe vloer
4963230 | 00 Begane grond | 3240 | 3625 | 0.453125 | 1.46813 | 11.745 | 11.745 | 1.46813 | 0 | 0 | 0 | Wall Centerline | 3240 | 11.745 | 3750 | Bouwkundig | Up to level: V1 ok. ruwe vloer | Pset_wanden - NLRS_C_brandwerendheid: R200; Fire Protection - NLRS_C_brandwerendheid: R200
4963231 | 00 Begane grond | 3240 | 3625 | 0.453125 | 1.46813 | 11.745 | 11.745 | 1.46813 | 0 | 0 | 0 | Wall Centerline | 3240 | 11.745 | 3750 | Bouwkundig | Up to level: V1 ok. ruwe vloer
4963264 | 00 Begane grond | 825 | 1955 | 0.244375 | 0.201609 | 1.61288 | 1.61288 | 0.201609 | 0 | 0 | 0 | Wall Centerline | 3240 | 1.61288 | 1955 | Bouwkundig | Up to level: V1 ok. ruwe vloer | Pset_wanden - NLRS_C_brandwerendheid: R200; Fire Protection - NLRS_C_brandwerendheid: R200
4963384 | 00 Begane grond | 825 | 1955 | 0.244375 | 0.201609 | 1.61288 | 1.61288 | 0.201609 | 0 | 0 | 0 | Wall Centerline | 3240 | 1.61288 | 2017.5 | Bouwkundig | Up to level: V1 ok. ruwe vloer
4963914 | 00 Begane grond | 3240 | 2515 | 0.314375 | 1.01858 | 8.1486 | 8.1486 | 1.01858 | 0 | 0 | 0 | Wall Centerline | 3240 | 8.1486 | 2515 | Bouwkundig | Up to level: V1 ok. ruwe vloer
4964084 | 00 Begane grond | 3240 | 2555 | 0.319375 | 1.03478 | 8.2782 | 8.2782 | 1.03478 | 0 | 0 | 0 | Wall Centerline | 3240 | 8.2782 | 2555 | Bouwkundig | Up to level: V1 ok. ruwe vloer | Pset_wanden - NLRS_C_brandwerendheid: R200; Fire Protection - NLRS_C_brandwerendheid: R200
4964085 | 00 Begane grond | 825 | 588 | 0.0735 | 0.0606375 | 0.4851 | 0.4851 | 0.0606375 | 0 | 0 | 0 | Wall Centerline | 3240 | 0.4851 | 713 | Bouwkundig | Up to level: V1 ok. ruwe vloer
4965732 | 00 Begane grond | 825 | 2430 | 0.30375 | 0.250594 | 2.00475 | 2.00475 | 0.250594 | 0 | 0 | 0 | Wall Centerline | 3240 | 2.00475 | 2580 | Bouwkundig | Up to level: V1 ok. ruwe vloer | Pset_wanden - NLRS_C_brandwerendheid: R200; Fire Protection - NLRS_C_brandwerendheid: R200
4966136 | 00 Begane grond | 3240 | 555 | 0.069375 | 0.224775 | 1.7982 | 1.7982 | 0.224775 | 0 | 0 | 0 | Wall Centerline | 3240 | 1.7982 | 555 | Bouwkundig | Up to level: V1 ok. ruwe vloer | Pset_wanden - NLRS_C_brandwerendheid: 30; Fire Protection - NLRS_C_brandwerendheid: 30
4966228 | 00 Begane grond | 3240 | 3527.46 | 0.440933 | 0.995129 | 7.96103 | 7.33693 | 0.917116 | 0 | 0 | 0 | Wall Centerline | 3240 | 7.33693 | 3527.46 | Bouwkundig | Up to level: V1 ok. ruwe vloer
4966586 | 00 Begane grond | 3240 | 555 | 0.069375 | 0.224775 | 1.7982 | 1.7982 | 0.224775 | 0 | 0 | 0 | Wall Centerline | 3240 | 1.7982 | 617.5 | Bouwkundig | Up to level: V1 ok. ruwe vloer | Pset_wanden - NLRS_C_brandwerendheid: 30; Fire Protection - NLRS_C_brandwerendheid: 30
4966618 | 00 Begane grond | 3240 | 2395 | 0.299375 | 0.969975 | 7.7598 | 7.7598 | 0.969975 | 0 | 0 | 0 | Wall Centerline | 3240 | 7.7598 | 2520 | Bouwkundig | Up to level: V1 ok. ruwe vloer
4967138 | -1 Speelvloer | 3840 | 775 | 0.096875 | 0.372 | 2.976 | 2.976 | 0.372 | 0 | 0 | V-1 | Wall Centerline | 3840 | 2.976 | 900 | Bouwkundig | Up to level: V1 ok. ruwe vloer
4967195 | -1 Speelvloer | 3840 | 4930 | 0.61625 | 1.6774 | 13.4192 | 13.4192 | 1.6774 | 0 | 0 | V-1 | Wall Centerline | 3840 | 13.4192 | 5055 | Bouwkundig | Up to level: V1 ok. ruwe vloer
4968269 | 00 Begane grond | 3240 | 1884.96 | 0.234939 | 0.050625 | 0.405 | 6.42534 | 0.759311 | 0 | 0 | 0 | Wall Centerline | 3240 | 6.42534 | 1884.96 | Bouwkundig | Up to level: V1 ok. ruwe vloer | Graphics - Center Mark Visible: no
4973618 | 00 Begane grond | 3240 | 1920 | 0.24 | 0.217444 | 1.73955 | 1.73955 | 0.217444 | 0 | 0 | 0 | Wall Centerline | 3240 | 1.73955 | 1982.5 | Bouwkundig | Up to level: V1 ok. ruwe vloer
4973797 | 00 Begane grond | 3240 | 1100 | 0.1375 | 0.4455 | 3.564 | 3.564 | 0.4455 | 0 | 0 | 0 | Wall Centerline | 3240 | 3.564 | 1225 | Bouwkundig | Up to level: V1 ok. ruwe vloer
4974016 | 00 Begane grond | 3240 | 3939.96 | 0.492495 | 1.59569 | 12.7655 | 10.802 | 1.35025 | 0 | 0 | 0 | Wall Centerline | 3240 | 10.802 | 3939.96 | Bouwkundig | Up to level: V1 ok. ruwe vloer
4974067 | 00 Begane grond | 3240 | 1432.04 | 0.179005 | 0.579976 | 4.63981 | 3.98531 | 0.498164 | 0 | 0 | 0 | Wall Centerline | 3240 | 3.98531 | 1432.04 | Bouwkundig | Up to level: V1 ok. ruwe vloer
4974273 | 00 Begane grond | 3240 | 4815.59 | 0.594136 | 1.6414 | 13.1312 | 13.1312 | 1.61609 | 0 | 0 | 0 | Wall Centerline | 3240 | 13.1312 | 4876.83 | Bouwkundig | Up to level: V1 ok. ruwe vloer
4974535 | 00 Begane grond | 3240 | 1252.71 | 0.156582 | 0.050625 | 0.405 | 4.37687 | 0.507346 | 0 | 0 | 0 | Wall Centerline | 3240 | 4.37687 | 1252.71 | Bouwkundig | Up to level: V1 ok. ruwe vloer | Graphics - Center Mark Visible: no
4974572 | 00 Begane grond | 3240 | 2799.96 | 0.349995 | 0.825077 | 6.60062 | 6.60062 | 0.825077 | 0 | 0 | 0 | Wall Centerline | 3240 | 6.60062 | 2924.96 | Bouwkundig | Up to level: V1 ok. ruwe vloer
4974631 | 00 Begane grond | 3240 | 6549.96 | 0.818745 | 2.65274 | 21.2219 | 21.2219 | 2.65274 | 0 | 0 | 0 | Wall Centerline | 3240 | 21.2219 | 6549.96 | Bouwkundig | Up to level: V1 ok. ruwe vloer | Pset_wanden - NLRS_C_brandwerendheid: 30; Fire Protection - NLRS_C_brandwerendheid: 30
4974980 | 00 Begane grond | 3240 | 1299.39 | 0.162424 | 0.526255 | 4.21004 | 4.21004 | 0.526255 | 0 | 0 | 0 | Wall Centerline | 3240 | 4.21004 | 1424.39 | Bouwkundig | Up to level: V1 ok. ruwe vloer | Pset_wanden - NLRS_C_brandwerendheid: 30; Fire Protection - NLRS_C_brandwerendheid: 30
4976702 | 00 Begane grond | 3240 | 7255 | 0.906875 | 1.75794 | 14.0636 | 14.0636 | 1.75794 | 0 | 0 | 0 | Wall Centerline | 3240 | 14.0636 | 7255 | Bouwkundig | Up to level: V1 ok. ruwe vloer
4976977 | 00 Begane grond | 3240 | 1660 | 0.2075 | 0.6723 | 5.3784 | 5.3784 | 0.6723 | 0 | 0 | 0 | Wall Centerline | 3240 | 5.3784 | 1785 | Bouwkundig | Up to level: V1 ok. ruwe vloer | Pset_wanden - NLRS_C_brandwerendheid: 30; Fire Protection - NLRS_C_brandwerendheid: 30
4976978 | 00 Begane grond | 3240 | 2920 | 0.365 | 1.1826 | 9.4608 | 8.7468 | 1.09335 | 0 | 0 | 0 | Wall Centerline | 3240 | 8.7468 | 2795 | Bouwkundig | Up to level: V1 ok. ruwe vloer | Group: Model Group:WC_V0:4976980
4976981 | 00 Begane grond | 3240 | 2795 | 0.349375 | 0.823068 | 6.58454 | 6.58454 | 0.823068 | 0 | 0 | 0 | Wall Centerline | 3240 | 6.58454 | 2795 | Bouwkundig | Up to level: V1 ok. ruwe vloer | Group: Model Group:WC_V0:4976980
4977246 | 00 Begane grond | 3240 | 6600.01 | 0.825001 | 2.673 | 21.384 | 21.384 | 2.673 | 0 | 0 | 0 | Wall Centerline | 3240 | 21.384 | 6750.01 | Bouwkundig | Up to level: V1 ok. ruwe vloer | Pset_wanden - NLRS_C_brandwerendheid: 30; Fire Protection - NLRS_C_brandwerendheid: 30
4977291 | 00 Begane grond | 3240 | 2920 | 0.365 | 1.1826 | 9.4608 | 8.7468 | 1.09335 | 0 | 0 | 0 | Wall Centerline | 3240 | 8.7468 | 2795 | Bouwkundig | Up to level: V1 ok. ruwe vloer | Group: Model Group:WC_V0:4977293
4977294 | 00 Begane grond | 3240 | 2670 | 0.33375 | 0.772443 | 6.17954 | 6.17954 | 0.772443 | 0 | 0 | 0 | Wall Centerline | 3240 | 6.17954 | 2795 | Bouwkundig | Up to level: V1 ok. ruwe vloer | Group: Model Group:WC_V0:4977293
4977396 | 00 Begane grond | 3240 | 2935 | 0.366875 | 1.18868 | 9.5094 | 8.7954 | 1.09943 | 0 | 0 | 0 | Wall Centerline | 3240 | 8.7954 | 2810 | Bouwkundig | Up to level: V1 ok. ruwe vloer | Group: Model Group:WC_V0:4977398
4977399 | 00 Begane grond | 3240 | 2810 | 0.35125 | 0.829143 | 6.63314 | 6.63314 | 0.829143 | 0 | 0 | 0 | Wall Centerline | 3240 | 6.63314 | 2810 | Bouwkundig | Up to level: V1 ok. ruwe vloer | Group: Model Group:WC_V0:4977398
4978685 | 00 Begane grond | 3240 | 6600.01 | 0.825001 | 2.08148 | 16.6518 | 16.6518 | 2.08148 | 0 | 0 | 0 | Wall Centerline | 3240 | 16.6518 | 6687.51 | Bouwkundig | Up to level: V1 ok. ruwe vloer
4980749 | 00 Begane grond | 3240 | 1100 | 0.1375 | 0.136593 | 1.09274 | 1.09274 | 0.136593 | 0 | 0 | 0 | Wall Centerline | 3240 | 1.09274 | 1162.5 | Bouwkundig | Up to level: V1 ok. ruwe vloer
4980991 | 00 Begane grond | 3172 | 215 | 0.026875 | 0.0852475 | 0.68198 | 0.68198 | 0.0852475 | 0 | 0 | 0 | Wall Centerline | 3240 | 0.68198 | 215 | Bouwkundig | Up to level: V1 ok. ruwe vloer
4981107 | 00 Begane grond | 3240 | 1252.71 | 0.156582 | 0.050625 | 0.405 | 4.37687 | 0.507319 | 0 | 0 | 0 | Finish Face: Interior | 3240 | 4.37687 | 1252.71 | Bouwkundig | Up to level: V1 ok. ruwe vloer | Graphics - Center Mark Visible: no
5000774 | 00 Begane grond | 3240 | 1415 | 0.176875 | 0.573075 | 4.5846 | 4.5846 | 0.573075 | 0 | 0 | 0 | Wall Centerline | 3240 | 4.5846 | 1540 | Bouwkundig | Up to level: V1 ok. ruwe vloer
5000829 | 00 Begane grond | 3240 | 1390 | 0.17375 | 0.56295 | 4.5036 | 4.5036 | 0.56295 | 0 | 0 | 0 | Wall Centerline | 3240 | 4.5036 | 1452.5 | Bouwkundig | Up to level: V1 ok. ruwe vloer
5002302 | 00 Begane grond | 3240 | 1680 | 0.21 | 0.6804 | 5.4432 | 5.4432 | 0.6804 | 0 | 0 | 0 | Wall Centerline | 3240 | 5.4432 | 1780 | Bouwkundig | Up to level: V1 ok. ruwe vloer
5035209 | 01 eerste verdieping | 3240 | 3290 | 0.41125 | 0.050625 | 0.405 | 0.405 | 0.0285375 | 0 | 0 | 1 | Wall Centerline | 3240 | 0.2283 | 3440 | Bouwkundig | Up to level: V2 ok. ruwe vloer
5035646 | 01 eerste verdieping | 3240 | 1660 | 0.2075 | 0.6723 | 5.3784 | 5.3784 | 0.6723 | 0 | 0.0000290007 | 1 | Wall Centerline | 3240 | 5.3784 | 1785 | Bouwkundig | Up to level: V2 ok. ruwe vloer | Pset_wanden - NLRS_C_brandwerendheid: 30; Fire Protection - NLRS_C_brandwerendheid: 30
5035647 | 01 eerste verdieping | 3240 | 2925 | 0.365625 | 1.18463 | 9.477 | 8.763 | 1.09538 | 0 | 0.0000290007 | 1 | Wall Centerline | 3240 | 8.763 | 2800 | Bouwkundig | Up to level: V2 ok. ruwe vloer | Group: Model Group:WC_V0:5035649
5035650 | 01 eerste verdieping | 3240 | 2800 | 0.35 | 0.825093 | 6.60074 | 6.60074 | 0.825093 | 0 | 0.0000290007 | 1 | Wall Centerline | 3240 | 6.60074 | 2800 | Bouwkundig | Up to level: V2 ok. ruwe vloer | Group: Model Group:WC_V0:5035649
5035652 | 01 eerste verdieping | 3240 | 2800 | 0.35 | 1.134 | 9.072 | 8.358 | 1.04475 | 0 | 0.0000290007 | 1 | Wall Centerline | 3240 | 8.358 | 2800 | Bouwkundig | Up to level: V2 ok. ruwe vloer
5035655 | 01 eerste verdieping | 3240 | 2675 | 0.334375 | 0.774468 | 6.19574 | 6.19574 | 0.774468 | 0 | 0.0000290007 | 1 | Wall Centerline | 3240 | 6.19574 | 2800 | Bouwkundig | Up to level: V2 ok. ruwe vloer
5035657 | 01 eerste verdieping | 3240 | 2925 | 0.365625 | 1.18463 | 9.477 | 8.763 | 1.09538 | 0 | 0.0000290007 | 1 | Wall Centerline | 3240 | 8.763 | 2800 | Bouwkundig | Up to level: V2 ok. ruwe vloer | Group: Model Group:WC_V0:5035659
5035660 | 01 eerste verdieping | 3240 | 2800 | 0.35 | 0.825093 | 6.60074 | 6.60074 | 0.825093 | 0 | 0.0000290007 | 1 | Wall Centerline | 3240 | 6.60074 | 2800 | Bouwkundig | Up to level: V2 ok. ruwe vloer | Group: Model Group:WC_V0:5035659
5035729 | 01 eerste verdieping | 3240 | 6600 | 0.825 | 2.673 | 21.384 | 21.384 | 2.673 | 0 | 0 | 1 | Wall Centerline | 3240 | 21.384 | 6750 | Bouwkundig | Up to level: V2 ok. ruwe vloer | Pset_wanden - NLRS_C_brandwerendheid: 30; Fire Protection - NLRS_C_brandwerendheid: 30
5036001 | 01 eerste verdieping | 3240 | 6600 | 0.825 | 2.08148 | 16.6518 | 16.6518 | 2.08148 | 0 | 0 | 1 | Wall Centerline | 3240 | 16.6518 | 6600 | Bouwkundig | Up to level: V2 ok. ruwe vloer
5036236 | 01 eerste verdieping | 1090 | 6070 | 0.75875 | 0.827038 | 6.6163 | 6.6163 | 0.827038 | 0 | 0 | V1 bk. ruwe vloer | Wall Centerline | 1090 | 6.6163 | 6070 | Bouwkundig
5036532 | 01 eerste verdieping | 1000 | 1354.81 | 0.169349 | 0.015625 | 0.125 | 1.45299 | 0.169352 | 0 | 0 | 1 | Finish Face: Exterior | 1000 | 1.45299 | 1354.81 | Bouwkundig | Graphics - Center Mark Visible: no
5036751 | 01 eerste verdieping | 3240 | 8900 | 1.1125 | 3.6045 | 28.836 | 27.513 | 3.43912 | 0 | 0 | 1 | Wall Centerline | 3240 | 27.513 | 8900 | Bouwkundig | Up to level: V2 ok. ruwe vloer
5036925 | 01 eerste verdieping | 1000 | 1354.81 | 0.169349 | 0.015625 | 0.125 | 1.45299 | 0.169352 | 0 | 0 | 1 | Finish Face: Exterior | 1000 | 1.45299 | 1462.09 | Bouwkundig | Graphics - Center Mark Visible: no
5037367 | 01 eerste verdieping | 3240 | 6590 | 0.82375 | 2.36004 | 18.8803 | 18.8803 | 2.36004 | 0 | 0 | 1 | Wall Centerline | 3240 | 18.8803 | 6740 | Bouwkundig | Up to level: V2 ok. ruwe vloer
5037717 | 01 eerste verdieping | 3240 | 2925 | 0.365625 | 1.18463 | 9.477 | 8.763 | 1.09538 | 0 | 0.0000290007 | 1 | Wall Centerline | 3240 | 8.763 | 2800 | Bouwkundig | Up to level: V2 ok. ruwe vloer
5037782 | 01 eerste verdieping | 3240 | 6590 | 0.82375 | 2.36004 | 18.8803 | 18.8803 | 2.36004 | 0 | 0 | 1 | Wall Centerline | 3240 | 18.8803 | 6740 | Bouwkundig | Up to level: V2 ok. ruwe vloer
5038193 | 01 eerste verdieping | 3240 | 620 | 0.0775 | 0.2511 | 2.0088 | 2.0088 | 0.2511 | 0 | 0 | 1 | Wall Centerline | 3240 | 2.0088 | 620 | Bouwkundig | Up to level: V2 ok. ruwe vloer
5038387 | 01 eerste verdieping | 3240 | 1660 | 0.2075 | 0.6723 | 5.3784 | 5.3784 | 0.6723 | 0 | 0 | 1 | Wall Centerline | 3240 | 5.3784 | 1785 | Bouwkundig | Up to level: V2 ok. ruwe vloer | Pset_wanden - NLRS_C_brandwerendheid: 20; Fire Protection - NLRS_C_brandwerendheid: 20
5038987 | 01 eerste verdieping | 3240 | 2705 | 0.338125 | 1.09553 | 8.7642 | 8.0502 | 1.00628 | 0 | 0 | 1 | Wall Centerline | 3240 | 8.0502 | 2730 | Bouwkundig | Up to level: V2 ok. ruwe vloer
5039067 | 01 eerste verdieping | 3240 | 2707.5 | 0.338438 | 0.78763 | 6.30104 | 6.30104 | 0.78763 | 0 | 0 | 1 | Wall Centerline | 3240 | 6.30104 | 2795 | Bouwkundig | Up to level: V2 ok. ruwe vloer
5039353 | 01 eerste verdieping | 3240 | 1075 | 0.134375 | 0.435375 | 3.483 | 3.483 | 0.435375 | 0 | 0 | 1 | Wall Centerline | 3240 | 3.483 | 1200 | Bouwkundig | Up to level: V2 ok. ruwe vloer
5039385 | 01 eerste verdieping | 3240 | 2233 | 0.279125 | 0.904365 | 7.23492 | 6.52092 | 0.815115 | 0 | 0 | 1 | Wall Centerline | 3240 | 6.52092 | 2233 | Bouwkundig | Up to level: V2 ok. ruwe vloer
5039504 | 01 eerste verdieping | 3240 | 2660 | 0.3325 | 1.0773 | 8.6184 | 8.6184 | 1.0773 | 0 | 0 | 1 | Wall Centerline | 3240 | 8.6184 | 2810 | Bouwkundig | Up to level: V2 ok. ruwe vloer
5039539 | 01 eerste verdieping | 3240 | 2660 | 0.3325 | 1.0773 | 8.6184 | 8.6184 | 1.0773 | 0 | 0 | 1 | Wall Centerline | 3240 | 8.6184 | 2722.5 | Bouwkundig | Up to level: V2 ok. ruwe vloer
5039785 | 01 eerste verdieping | 3240 | 1625.13 | 0.203141 | 0.658176 | 5.26541 | 5.26541 | 0.658176 | 0 | 0 | 1 | Wall Centerline | 3240 | 5.26541 | 1750.13 | Bouwkundig | Up to level: V2 ok. ruwe vloer
5039853 | 01 eerste verdieping | 3240 | 2950 | 0.36875 | 0.885842 | 7.08674 | 7.08674 | 0.885842 | 0 | 0 | 1 | Wall Centerline | 3240 | 7.08674 | 3075 | Bouwkundig | Up to level: V2 ok. ruwe vloer
5042229 | 01 eerste verdieping | 3240 | 1625.13 | 0.203141 | 0.658176 | 5.26541 | 5.26541 | 0.658176 | 0 | 0 | 1 | Wall Centerline | 3240 | 5.26541 | 1750.13 | Bouwkundig | Up to level: V2 ok. ruwe vloer
5042360 | 01 eerste verdieping | 3240 | 1354.81 | 0.169349 | 0.050625 | 0.405 | 4.70768 | 0.548672 | 0 | 0 | 1 | Wall Centerline | 3240 | 4.70768 | 1354.81 | Bouwkundig | Up to level: V2 ok. ruwe vloer | Graphics - Center Mark Visible: no
5129712 | 00 Begane grond | 3240 | 6549.96 | 0.818745 | 2.65274 | 21.2219 | 21.2219 | 2.65274 | 0 | 0 | 0 | Wall Centerline | 3240 | 21.2219 | 6699.96 | Bouwkundig | Up to level: V1 ok. ruwe vloer
5166193 | 01 eerste verdieping | 3240 | 1660 | 0.2075 | 0.6723 | 5.3784 | 5.3784 | 0.6723 | 0 | 0.0000290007 | 1 | Wall Centerline | 3240 | 5.3784 | 1660 | Bouwkundig | Up to level: V2 ok. ruwe vloer
5174535 | 01 eerste verdieping | 3240 | 2800 | 0.35 | 1.134 | 9.072 | 8.358 | 1.04475 | 0 | 0.0000290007 | 1 | Wall Centerline | 3240 | 8.358 | 2800 | Bouwkundig | Up to level: V2 ok. ruwe vloer
5174538 | 01 eerste verdieping | 3240 | 2800 | 0.35 | 0.825093 | 6.60074 | 6.60074 | 0.825093 | 0 | 0.0000290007 | 1 | Wall Centerline | 3240 | 6.60074 | 2800 | Bouwkundig | Up to level: V2 ok. ruwe vloer
5200259 | 00 Begane grond | 3920.09 | 1354.81 | 0.169349 | 0.0612513 | 0.490011 | 5.69583 | 0.66384 | 0 | 680.086 | 0 | Finish Face: Interior | 3920.09 | 5.69583 | 1354.81 | Bouwkundig | Up to level: V1 ok. ruwe vloer | Graphics - Center Mark Visible: no
5204731 | 00 Begane grond | 3240 | 195 | 0.024375 | 0.0556238 | 0.44499 | 0.44499 | 0.0556238 | 0 | 0 | 0 | Wall Centerline | 3240 | 0.44499 | 132.5 | Bouwkundig | Up to level: V1 ok. ruwe vloer
5205818 | 00 Begane grond | 3240 | 1000 | 0.125 | 0.405 | 3.24 | 3.24 | 0.405 | 0 | 0 | 0 | Wall Centerline | 3240 | 3.24 | 1125 | Bouwkundig | Up to level: V1 ok. ruwe vloer
5205873 | 00 Begane grond | 3240 | 4493.5 | 0.561688 | 1.17218 | 9.37742 | 8.75332 | 1.09417 | 0 | 0 | 0 | Wall Centerline | 3240 | 8.75332 | 4556 | Bouwkundig | Up to level: V1 ok. ruwe vloer
5215191 | 00 Begane grond | 3240 | 1680 | 0.21 | 0.6804 | 5.4432 | 5.4432 | 0.6804 | 0 | 0 | 0 | Wall Centerline | 3240 | 5.4432 | 1780 | Bouwkundig | Up to level: V1 ok. ruwe vloer
5215206 | 01 eerste verdieping | 3240 | 1689.63 | 0.211203 | 0.684298 | 5.47439 | 5.47439 | 0.684298 | 0 | 0.000029 | 1 | Wall Centerline | 3240 | 5.47439 | 1752.13 | Bouwkundig | Up to level: V2 ok. ruwe vloer
5216510 | 00 Begane grond | 3240 | 155 | 0.019375 | 0.062775 | 0.5022 | 0.5022 | 0.062775 | 0 | 0 | 0 | Wall Centerline | 3240 | 0.5022 | 167.5 | Bouwkundig | Up to level: V1 ok. ruwe vloer
5218019 | 00 Begane grond | 3240 | 492.5 | 0.0615625 | 0.199463 | 1.5957 | 1.5957 | 0.199463 | 0 | 0 | 0 | Wall Centerline | 3240 | 1.5957 | 555 | Bouwkundig | Up to level: V1 ok. ruwe vloer
5220151 | 00 Begane grond | 3240 | 790 | 0.09875 | 0.31995 | 2.5596 | 2.5596 | 0.31995 | 0 | 0 | 0 | Wall Centerline | 3240 | 2.5596 | 959.5 | Bouwkundig | Up to level: V1 ok. ruwe vloer
5220185 | 00 Begane grond | 3240 | 209.999 | 0.0262499 | 0.0850498 | 0.680398 | 0.680398 | 0.0850498 | 0 | 0 | 0 | Wall Centerline | 3240 | 0.680398 | 209.999 | Bouwkundig | Up to level: V1 ok. ruwe vloer
5227041 | 01 eerste verdieping | 3240 | 6600 | 0.825 | 2.36409 | 18.9127 | 18.9127 | 2.36409 | 0 | 0.0000290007 | 1 | Wall Centerline | 3240 | 18.9127 | 6600 | Bouwkundig | Up to level: V2 ok. ruwe vloer
5227137 | 01 eerste verdieping | 3240 | 6600 | 0.825 | 2.08148 | 16.6518 | 16.6518 | 2.08148 | 0 | 0.0000290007 | 1 | Wall Centerline | 3240 | 16.6518 | 6600 | Bouwkundig | Up to level: V2 ok. ruwe vloer
5229195 | 01 eerste verdieping | 3240 | 137.5 | 0.0171875 | 0.0556875 | 0.4455 | 0.4455 | 0.0556875 | 0 | 0.0000290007 | 1 | Wall Centerline | 3240 | 0.4455 | 150 | Bouwkundig | Up to level: V2 ok. ruwe vloer
5230276 | 01 eerste verdieping | 3240 | 1660 | 0.2075 | 0.6723 | 5.3784 | 5.3784 | 0.6723 | 0 | 0.0000290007 | 1 | Wall Centerline | 3240 | 5.3784 | 1785 | Bouwkundig | Up to level: V2 ok. ruwe vloer
5247352 | 00 Begane grond | 99.9954 | 6537.5 | 0.817188 | 0.081715 | 0.65372 | 0.65372 | 0.081715 | 3140 | 0 | 0 | Wall Centerline | 99.9954 | 0.65372 | 6537.5 | Bouwkundig | Up to level: V1 ok. ruwe vloer
5271242 | 00 Begane grond | 3240 | 2422.5 | 0.302813 | 0.978277 | 7.82621 | 7.82621 | 0.978277 | 0 | 0 | 0 | Wall Centerline | 3240 | 7.82621 | 2485 | Bouwkundig | Up to level: V1 ok. ruwe vloer | Pset_wanden - NLRS_C_brandwerendheid: 30; Fire Protection - NLRS_C_brandwerendheid: 30
5296366 | 00 Begane grond | 3240 | 2095 | 0.261875 | 0.51985 | 4.1588 | 4.1588 | 0.51985 | 0 | 0 | 0 | Wall Centerline | 3240 | 4.1588 | 2032.5 | Bouwkundig | Up to level: V1 ok. ruwe vloer
5296597 | 00 Begane grond | 3240 | 4930 | 0.61625 | 1.32446 | 10.5957 | 10.5957 | 1.32446 | 0 | 0 | 0 | Wall Centerline | 3240 | 10.5957 | 4930 | Bouwkundig | Up to level: V1 ok. ruwe vloer
5299564 | 01 eerste verdieping | 3240 | 2500 | 0.3125 | 1.0125 | 8.1 | 8.1 | 1.0125 | 0 | 0 | 1 | Wall Centerline | 3240 | 8.1 | 2650 | Bouwkundig | Up to level: V2 ok. ruwe vloer
5299708 | 01 eerste verdieping | 3240 | 665 | 0.083125 | 0.269325 | 2.1546 | 2.1546 | 0.269325 | 0 | 0 | 1 | Wall Centerline | 3240 | 2.1546 | 602.5 | Bouwkundig | Up to level: V2 ok. ruwe vloer
5307539 | 00 Begane grond | 3240 | 5237.5 | 0.654687 | 1.50337 | 12.027 | 12.027 | 1.50337 | 0 | 0 | 0 | Wall Centerline | 3240 | 12.027 | 5237.5 | Bouwkundig | Up to level: V1 ok. ruwe vloer | Pset_wanden - NLRS_C_brandwerendheid: R200; Fire Protection - NLRS_C_brandwerendheid: R200
5307921 | 00 Begane grond | 3240 | 3860 | 0.4825 | 1.5633 | 12.5064 | 12.5064 | 1.5633 | 0 | 0 | 0 | Wall Centerline | 3240 | 12.5064 | 3797.5 | Bouwkundig | Up to level: V1 ok. ruwe vloer | Pset_wanden - NLRS_C_brandwerendheid: R200; Fire Protection - NLRS_C_brandwerendheid: R200
5382004 | 00 Begane grond | 825 | 495.5 | 0.0619375 | 0.0510984 | 0.408788 | 0.408788 | 0.0510984 | 0 | 0 | 0 | Wall Centerline | 3240 | 0.408788 | 495.5 | Bouwkundig | Up to level: V1 ok. ruwe vloer
5453722 | 01 eerste verdieping | 3240 | 4883 | 0.610375 | 1.97762 | 15.8209 | 14.4979 | 1.81224 | 0 | 0 | 1 | Wall Centerline | 3240 | 14.4979 | 4945.5 | Bouwkundig | Up to level: V2 ok. ruwe vloer | Pset_wanden - NLRS_C_brandwerendheid: 20; Fire Protection - NLRS_C_brandwerendheid: 20
5454059 | 01 eerste verdieping | 3240 | 740 | 0.0925 | 0.2997 | 2.3976 | 2.3976 | 0.2997 | 0 | 0 | 1 | Wall Centerline | 3240 | 2.3976 | 802.5 | Bouwkundig | Up to level: V2 ok. ruwe vloer
5454181 | 01 eerste verdieping | 3240 | 1497.5 | 0.187188 | 0.606487 | 4.8519 | 4.8519 | 0.606487 | 0 | 0 | 1 | Wall Centerline | 3240 | 4.8519 | 1497.5 | Bouwkundig | Up to level: V2 ok. ruwe vloer | Pset_wanden - NLRS_C_brandwerendheid: 20; Fire Protection - NLRS_C_brandwerendheid: 20
5481970 | -1 Speelvloer | 600 | 2091.46 | 0.261432 | 0.156859 | 1.25488 | 1.25488 | 0.156859 | 0 | 0 | V-1 | Wall Centerline | 600 | 1.25488 | 2091.46 | Bouwkundig | Up to level: 0
5481971 | -1 Speelvloer | 600 | 800 | 0.1 | 0.06 | 0.48 | 0.48 | 0.06 | 0 | 0 | V-1 | Wall Centerline | 600 | 0.48 | 800 | Bouwkundig | Up to level: 0
5481972 | -1 Speelvloer | 600 | 1884.96 | 0.234939 | 0.009375 | 0.075 | 1.18988 | 0.140613 | 0 | 0 | V-1 | Wall Centerline | 600 | 1.18988 | 1884.96 | Bouwkundig | Up to level: 0 | Graphics - Center Mark Visible: no
5481973 | -1 Speelvloer | 600 | 1645 | 0.205625 | 0.123375 | 0.987 | 0.987 | 0.123375 | 0 | 0 | V-1 | Wall Centerline | 600 | 0.987 | 1770 | Bouwkundig | Up to level: 0
5481975 | -1 Speelvloer | 600 | 915 | 0.114375 | 0.068625 | 0.549 | 0.549 | 0.068625 | 0 | 0 | V-1 | Wall Centerline | 600 | 0.549 | 959.5 | Bouwkundig | Up to level: 0
5481976 | -1 Speelvloer | 600 | 100 | 0.0125 | 0.009375 | 0.075 | 0.075 | 0.0075 | 0 | 0 | V-1 | Wall Centerline | 600 | 0.06 | 225 | Bouwkundig | Up to level: 0
5481977 | -1 Speelvloer | 600 | 675 | 0.084375 | 0.050625 | 0.405 | 0.405 | 0.050625 | 0 | 0 | V-1 | Wall Centerline | 600 | 0.405 | 675 | Bouwkundig | Up to level: 0
5481978 | -1 Speelvloer | 600 | 2767.87 | 0.345984 | 0.207591 | 1.66072 | 1.66072 | 0.207591 | 0 | 0 | V-1 | Wall Centerline | 600 | 1.66072 | 2767.87 | Bouwkundig | Up to level: 0
5482675 | -1 Speelvloer | 600 | 900 | 0.1125 | 0.0675 | 0.54 | 0.54 | 0.0675 | 0 | 0 | V-1 | Wall Centerline | 600 | 0.54 | 837.5 | Bouwkundig | Up to level: 0
5489199 | 00 Begane grond | 825 | 2415 | 0.301875 | 0.249047 | 1.99238 | 1.99238 | 0.249047 | 0 | 0 | 0 | Wall Centerline | 3240 | 1.99238 | 2477.5 | Bouwkundig | Up to level: V1 ok. ruwe vloer
5489958 | 00 Begane grond | 825 | 2580 | 0.3225 | 0.266063 | 2.1285 | 2.1285 | 0.266063 | 0 | 0 | 0 | Wall Centerline | 3240 | 2.1285 | 2580 | Bouwkundig | Up to level: V1 ok. ruwe vloer
5987157 | 01 eerste verdieping | 3240 | 8900 | 1.1125 | 2.67778 | 21.4222 | 21.4222 | 2.67778 | 0 | 0 | 1 | Wall Centerline | 3240 | 21.4222 | 8987.5 | Bouwkundig | Up to level: V2 ok. ruwe vloer
5987393 | 01 eerste verdieping | 3240 | 4331 | 0.541375 | 0.899428 | 7.19542 | 7.19542 | 0.899428 | 0 | 0.0000290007 | 1 | Wall Centerline | 3240 | 7.19542 | 4393.5 | Bouwkundig | Up to level: V2 ok. ruwe vloer
5994910 | 01 eerste verdieping | 3240 | 2925 | 0.365625 | 1.18463 | 9.477 | 8.763 | 1.09538 | 0 | 0.0000290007 | 1 | Wall Centerline | 3240 | 8.763 | 2800 | Bouwkundig | Up to level: V2 ok. ruwe vloer | Group: Model Group:WC_V0:5994912
5994913 | 01 eerste verdieping | 3240 | 2800 | 0.35 | 0.825093 | 6.60074 | 6.60074 | 0.825093 | 0 | 0.0000290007 | 1 | Wall Centerline | 3240 | 6.60074 | 2800 | Bouwkundig | Up to level: V2 ok. ruwe vloer | Group: Model Group:WC_V0:5994912
5995270 | 01 eerste verdieping | 3240 | 6590 | 0.82375 | 2.07742 | 16.6194 | 16.6194 | 2.07742 | 0 | 0 | 1 | Wall Centerline | 3240 | 16.6194 | 6740 | Bouwkundig | Up to level: V2 ok. ruwe vloer
6241460 | 00 Begane grond | 3240 | 1980 | 0.2475 | 0.256681 | 2.05345 | 2.05345 | 0.256681 | 0 | 0 | 0 | Wall Centerline | 3240 | 2.05345 | 2042.5 | Bouwkundig | Up to level: V1 ok. ruwe vloer | Pset_wanden - NLRS_C_brandwerendheid: R200; Fire Protection - NLRS_C_brandwerendheid: R200
6263690 | 00 Begane grond | 3240 | 845 | 0.105625 | 0.342225 | 2.7378 | 2.7378 | 0.342225 | 0 | 0 | 0 | Wall Centerline | 3240 | 2.7378 | 957.5 | Bouwkundig | Up to level: V1 ok. ruwe vloer
6287923 | 01 eerste verdieping | 3240 | 4820 | 0.6025 | 1.9521 | 15.6168 | 15.6168 | 1.9521 | 0 | 0 | 1 | Wall Centerline | 3240 | 15.6168 | 4932.5 | Bouwkundig | Up to level: V2 ok. ruwe vloer | Pset_wanden - NLRS_C_brandwerendheid: 20; Fire Protection - NLRS_C_brandwerendheid: 20
6320863 | 00 Begane grond | 3240 | 3185 | 0.398125 | 0.981018 | 7.84814 | 7.13414 | 0.891768 | 0 | 0 | 0 | Wall Centerline | 3240 | 7.13414 | 3185 | Bouwkundig | Up to level: V1 ok. ruwe vloer
6329865 | 00 Begane grond | 3240 | 130 | 0.01625 | 0.05265 | 0.4212 | 0.4212 | 0.05265 | 0 | 0 | 0 | Wall Centerline | 3240 | 0.4212 | 130 | Bouwkundig | Up to level: V1 ok. ruwe vloer
6366677 | 00 Begane grond | 3240 | 3289.99 | 0.411249 | 0.832467 | 6.65973 | 6.65973 | 0.832467 | 0 | 0 | 0 | Wall Centerline | 3240 | 6.65973 | 3289.99 | Bouwkundig | Up to level: V1 ok. ruwe vloer
6370317 | 01 eerste verdieping | 3240 | 238 | 0.02975 | 0.09639 | 0.77112 | 0.77112 | 0.09639 | 0 | 0 | 1 | Wall Centerline | 3240 | 0.77112 | 188 | Bouwkundig | Up to level: V2 ok. ruwe vloer | Pset_wanden - NLRS_C_brandwerendheid: 20; Fire Protection - NLRS_C_brandwerendheid: 20
6372197 | 01 eerste verdieping | 3240 | 3290 | 0.41125 | 0.47625 | 3.81 | 3.81 | 0.47625 | 0 | 0 | 1 | Wall Centerline | 3240 | 3.81 | 3377.5 | Bouwkundig | Up to level: V2 ok. ruwe vloer
6395592 | 00 Begane grond | 3240 | 6600.01 | 0.825001 | 2.3641 | 18.9128 | 18.9128 | 2.3641 | 0 | 0 | 0 | Wall Centerline | 3240 | 18.9128 | 6750.01 | Bouwkundig | Up to level: V1 ok. ruwe vloer
6395661 | 00 Begane grond | 3240 | 6600.01 | 0.825001 | 2.08148 | 16.6518 | 16.6518 | 2.08148 | 0 | 0 | 0 | Wall Centerline | 3240 | 16.6518 | 6687.51 | Bouwkundig | Up to level: V1 ok. ruwe vloer
6398045 | 00 Begane grond | 3240 | 650 | 0.08125 | 0.26325 | 2.106 | 2.106 | 0.26325 | 0 | 0 | 0 | Wall Centerline | 3240 | 2.106 | 587.5 | Bouwkundig | Up to level: V1 ok. ruwe vloer | Pset_wanden - NLRS_C_brandwerendheid: 30; Fire Protection - NLRS_C_brandwerendheid: 30
6405556 | 01 eerste verdieping | 840 | 1797.5 | 0.224688 | 0.188737 | 1.5099 | 1.5099 | 0.188737 | 0 | 0 | V1 ok. plafond | Wall Centerline | 840 | 1.5099 | 1847.5 | Bouwkundig | Up to level: V2 ok. ruwe vloer
6424686 | 00 Begane grond | 3240 | 1252.71 | 0.156582 | 0.050625 | 0.405 | 4.37687 | 0.507352 | 0 | 0 | 0 | Wall Centerline | 3240 | 4.37687 | 1252.71 | Bouwkundig | Up to level: V1 ok. ruwe vloer | Graphics - Center Mark Visible: no
6427654 | 00 Begane grond | 3240 | 260 | 0.0325 | 0.1053 | 0.8424 | 0.8424 | 0.1053 | 0 | 0 | 0 | Wall Centerline | 3240 | 0.8424 | 322.5 | Bouwkundig | Up to level: V1 ok. ruwe vloer | Pset_wanden - NLRS_C_brandwerendheid: 30; Fire Protection - NLRS_C_brandwerendheid: 30
6428112 | 00 Begane grond | 3240 | 6658 | 0.83225 | 2.52955 | 20.2364 | 20.2364 | 2.52955 | 0 | 0 | 0 | Wall Centerline | 3240 | 20.2364 | 6595.5 | Bouwkundig | Up to level: V1 ok. ruwe vloer | Pset_wanden - NLRS_C_brandwerendheid: 30; Fire Protection - NLRS_C_brandwerendheid: 30
6428219 | 00 Begane grond | 3240 | 600 | 0.075 | 0.243 | 1.944 | 1.944 | 0.243 | 0 | 0 | 0 | Wall Centerline | 3240 | 1.944 | 612.5 | Bouwkundig | Up to level: V1 ok. ruwe vloer | Pset_wanden - NLRS_C_brandwerendheid: 30; Fire Protection - NLRS_C_brandwerendheid: 30
6428390 | 00 Begane grond | 3240 | 475 | 0.059375 | 0.192375 | 1.539 | 1.539 | 0.192375 | 0 | 0 | 0 | Wall Centerline | 3240 | 1.539 | 600 | Bouwkundig | Up to level: V1 ok. ruwe vloer | Pset_wanden - NLRS_C_brandwerendheid: 30; Fire Protection - NLRS_C_brandwerendheid: 30
6428496 | 00 Begane grond | 3240 | 433 | 0.054125 | 0.175365 | 1.40292 | 1.40292 | 0.175365 | 0 | 0 | 0 | Wall Centerline | 3240 | 1.40292 | 433 | Bouwkundig | Up to level: V1 ok. ruwe vloer
6444665 | 00 Begane grond | 3240 | 475 | 0.059375 | 0.192375 | 1.539 | 1.539 | 0.192375 | 0 | 0 | 0 | Wall Centerline | 3240 | 1.539 | 600 | Bouwkundig | Up to level: V1 ok. ruwe vloer
6446632 | 00 Begane grond | 850 | 3600 | 0.45 | 0.3825 | 3.06 | 3.06 | 0.3825 | 2390 | 0 | 0 | Wall Centerline | 850 | 3.06 | 3662.5 | Bouwkundig | Up to level: V1 ok. ruwe vloer
6522723 | 00 Begane grond | 3240 | 2134.96 | 0.26687 | 0.555753 | 4.44602 | 4.44602 | 0.555753 | 0 | 0 | 0 | Wall Centerline | 3240 | 4.44602 | 2222.46 | Bouwkundig | Up to level: V1 ok. ruwe vloer
6522724 | 00 Begane grond | 3240 | 2270 | 0.28375 | 0.91935 | 7.3548 | 7.3548 | 0.91935 | 0 | 0 | 0 | Wall Centerline | 3240 | 7.3548 | 2320 | Bouwkundig | Up to level: V1 ok. ruwe vloer
6522725 | 00 Begane grond | 3240 | 962.113 | 0.120268 | 0.050625 | 0.405 | 3.43533 | 0.389668 | 0 | 0 | 0 | Wall Centerline | 3240 | 3.43533 | 962.113 | Bouwkundig | Up to level: V1 ok. ruwe vloer | Graphics - Center Mark Visible: no
6522727 | 00 Begane grond | 3240 | 962.113 | 0.120268 | 0.050625 | 0.405 | 3.43533 | 0.389663 | 0 | 0 | 0 | Wall Centerline | 3240 | 3.43533 | 962.113 | Bouwkundig | Up to level: V1 ok. ruwe vloer | Graphics - Center Mark Visible: no
6661363 | 00 Begane grond | 3240 | 895 | 0.111875 | 0.362475 | 2.8998 | 2.8998 | 0.362475 | 0 | 0 | 0 | Wall Centerline | 3240 | 2.8998 | 895 | Bouwkundig | Up to level: V1 ok. ruwe vloer
6668648 | 00 Begane grond | 3240 | 280 | 0.035 | 0.1134 | 0.9072 | 0.9072 | 0.1134 | 0 | 0 | 0 | Wall Centerline | 3240 | 0.9072 | 280 | Bouwkundig | Up to level: V1 ok. ruwe vloer | Pset_wanden - NLRS_C_brandwerendheid: 30; Fire Protection - NLRS_C_brandwerendheid: 30
6668692 | 00 Begane grond | 3240 | 1420 | 0.1775 | 0.236318 | 1.89054 | 1.89054 | 0.236318 | 0 | 0 | 0 | Wall Centerline | 3240 | 1.89054 | 1420 | Bouwkundig | Up to level: V1 ok. ruwe vloer | Pset_wanden - NLRS_C_brandwerendheid: 30; Fire Protection - NLRS_C_brandwerendheid: 30
6671292 | 00 Begane grond | 1730 | 585 | 0.073125 | 0.126506 | 1.01205 | 1.01205 | 0.126506 | 0 | 0 | 0 | Wall Centerline | 1730 | 1.01205 | 585 | Bouwkundig
6693733 | 00 Begane grond | 3240 | 555 | 0.069375 | 0.224775 | 1.7982 | 1.7982 | 0.224775 | 0 | 0 | 0 | Wall Centerline | 3240 | 1.7982 | 642.5 | Bouwkundig | Up to level: V1 ok. ruwe vloer | Pset_wanden - NLRS_C_brandwerendheid: 30; NLRS_C_brandklasse_eis: 30; Fire Protection - NLRS_C_brandwerendheid: 30; NLRS_C_brandklasse_eis: 30
6694068 | 00 Begane grond | 3240 | 2100 | 0.2625 | 0.541593 | 4.33274 | 4.33274 | 0.541593 | 0 | 0 | 0 | Wall Centerline | 3240 | 4.33274 | 2187.5 | Bouwkundig | Up to level: V1 ok. ruwe vloer
6884282 | 00 Begane grond | 3240 | 100 | 0.0125 | 0.050625 | 0.405 | 0.405 | 0.0405 | 0 | 0 | 0 | Wall Centerline | 3240 | 0.324 | 100 | Bouwkundig | Up to level: V1 ok. ruwe vloer | Pset_wanden - NLRS_C_brandwerendheid: R200; Fire Protection - NLRS_C_brandwerendheid: R200
6886270 | 01 eerste verdieping | 1200 | 887.5 | 0.110938 | 0.133125 | 1.065 | 1.065 | 0.133125 | 0 | 0.0000290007 | 1 | Wall Centerline | 1200 | 1.065 | 937.5 | Bouwkundig

# IfcWallStandardCase: Basic Wall:22_DAT_binnenwand_125 HPL (60)
Type - PredefinedType: STANDARD; Material: ISR_Binnenwand 113 mm, ISR_HPL Kleur hout 12 mm
Type - Other(Type) - Category: Walls; Family Name: Basic Wall
Type - Construction(Type) - Function: Interior; Wrapping at Inserts: Do not wrap; Width: 125 mm
Type - Graphics(Type) - Coarse Scale Fill Pattern: <Solid fill>; Coarse Scale Fill Color: 12632256
Type - Identity Data(Type) - Workset: Wall Types; Assembly Code: 22.13; Assembly Description: binnenwanden; niet constructief, systeemwanden; vast; Description: Lichte scheidingswand 125mmAan weerszijden gipsvezelplaat 12,5mmGipsplaat 12,5mm Met daartussen 75mm ms wand gevuld met isolatieVulling afhankelijk van gestelde eisen ingeluidsrapportage; Type Comments: Lichte scheidingswand 125mmHPL plaat op MDFGipsplaat 12.5mmMS-wand 75 mm gevuld met isolatieGipsplaat 12.5mmGipsvezelplaat 12.5mmvulling afhankelijk van gestelde eisen ingeluidrapportage; Type Name: 22_DAT_binnenwand_125 HPL
Type - Materials and Finishes(Type) - Structural Material: ISR_Binnenwand
Type - Analytical Properties(Type) - Roughness: 1; Absorptance: 0.1
Type - Pset_ElementShading - Roughness: 304.8 mm
Type - Pset_ProductRequirements - Category: Walls
Type - Pset_ReinforcementBarPitchOfWall - Description: Lichte scheidingswand 125mmAan weerszijden gipsvezelplaat 12,5mmGipsplaat 12,5mm Met daartussen 75mm ms wand gevuld met isolatieVulling afhankelijk van gestelde eisen ingeluidsrapportage
Type - Pset_WallCommon - IsExternal: no
Classification: 22.13 Uniformat (Uniformat)
BaseQuantities - Width: 125 mm
Pset_QuantityTakeOff - Reference: 22_DAT_binnenwand_125 HPL; sets with these values: 2
Pset_WallCommon - ExtendToStructure: no; LoadBearing: no; Reference: 22_DAT_binnenwand_125 HPL
Pset_wanden - Structural Usage: Non-bearing; Omschrijving: Lichte scheidingswand 125mmAan weerszijden gipsvezelplaat 12,5mmGipsplaat 12,5mm Met daartussen 75mm ms wand gevuld met isolatieVulling afhankelijk van gestelde eisen ingeluidsrapportage; NL-sfb-Codering: 22.13
Pset_DAT_KMS - Assembly Code: 22.13; Assembly Description: binnenwanden; niet constructief, systeemwanden; vast; Description: Lichte scheidingswand 125mmAan weerszijden gipsvezelplaat 12,5mmGipsplaat 12,5mm Met daartussen 75mm ms wand gevuld met isolatieVulling afhankelijk van gestelde eisen ingeluidsrapportage
Other - Category: Walls; Family: Basic Wall; Family and Type: Basic Wall: 22_DAT_binnenwand_125 HPL; Type: 22_DAT_binnenwand_125 HPL; Type Id: 6329633
Constraints - Base Extension Distance: 0 mm; Base is Attached: no; Related to Mass: no; Room Bounding: yes; Top Extension Distance: 0 mm; Top is Attached: no; Location Line: Wall Centerline
Identity Data - Workset: Bouwkundig
Phasing - Phase Created: 2. nieuwbouw
Structural - Structural Usage: Non-bearing; Structural: no
Cross-Section Definition - Cross-Section: Vertical
Name (Basic Wall:22_DAT_binnenwand_125 HPL:...) | In | Height (mm) = Unconnected Height (mm) | BaseQuantities, Length (mm) | GrossFootprintArea (m2) | GrossVolume (m3) | GrossSideArea (m2) | NetSideArea (m2) | NetVolume (m3) = Volume (m3) | Base Offset (mm) | Top Offset (mm) | Base Constraint | Top Constraint | Area (m2) | Dimensions, Length (mm)
4963559 | 00 Begane grond | 3240 | 290 | 0.03625 | 0.11745 | 0.9396 | 0.9396 | 0.11745 | 0 | 0 | 0 | Up to level: V1 ok. ruwe vloer | 0.9396 | 352.5 | Pset_wanden - NLRS_C_brandwerendheid: R200; Fire Protection - NLRS_C_brandwerendheid: R200
4963915 | 00 Begane grond | 3240 | 290 | 0.03625 | 0.11745 | 0.9396 | 0.9396 | 0.11745 | 0 | 0 | 0 | Up to level: V1 ok. ruwe vloer | 0.9396 | 352.5
4966370 | 00 Begane grond | 3240 | 4800.04 | 0.600005 | 0.711141 | 5.68913 | 5.68913 | 0.662541 | 0 | 0 | 0 | Up to level: V1 ok. ruwe vloer | 5.30033 | 4862.54
4977290 | 00 Begane grond | 3240 | 1250 | 0.15625 | 0.50625 | 4.05 | 4.05 | 0.50625 | 0 | 0 | 0 | Up to level: V1 ok. ruwe vloer | 4.05 | 1187.5
4977395 | 00 Begane grond | 3240 | 1125 | 0.140625 | 0.455625 | 3.645 | 3.645 | 0.455625 | 0 | 0 | 0 | Up to level: V1 ok. ruwe vloer | 3.645 | 1187.5
5035651 | 01 eerste verdieping | 3240 | 1250 | 0.15625 | 0.50625 | 4.05 | 4.05 | 0.50625 | 0 | 0.0000290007 | 1 | Up to level: V2 ok. ruwe vloer | 4.05 | 1187.5
5035653 | 01 eerste verdieping | 3240 | 535 | 0.066875 | 0.216675 | 1.7334 | 1.7334 | 0.216675 | 0 | 0.0000290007 | 1 | Up to level: V2 ok. ruwe vloer | 1.7334 | 597.5
5035656 | 01 eerste verdieping | 3240 | 1125 | 0.140625 | 0.455625 | 3.645 | 3.645 | 0.455625 | 0 | 0.0000290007 | 1 | Up to level: V2 ok. ruwe vloer | 3.645 | 1187.5
5038141 | 01 eerste verdieping | 3240 | 1532 | 0.1915 | 0.181298 | 1.45038 | 1.45038 | 0.181298 | 0 | 0 | 1 | Up to level: V2 ok. ruwe vloer | 1.45038 | 1619.5 | Pset_wanden - NLRS_C_brandwerendheid: 20; Fire Protection - NLRS_C_brandwerendheid: 20
5166584 | 01 eerste verdieping | 3240 | 560 | 0.07 | 0.2268 | 1.8144 | 1.8144 | 0.2268 | 0 | 0.0000290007 | 1 | Up to level: V2 ok. ruwe vloer | 1.8144 | 610
5174534 | 01 eerste verdieping | 3240 | 1250 | 0.15625 | 0.50625 | 4.05 | 3.4259 | 0.428238 | 0 | 0.0000290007 | 1 | Up to level: V2 ok. ruwe vloer | 3.4259 | 1125
5174582 | 01 eerste verdieping | 3240 | 1125 | 0.140625 | 0.455625 | 3.645 | 3.645 | 0.455625 | 0 | 0.0000290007 | 1 | Up to level: V2 ok. ruwe vloer | 3.645 | 1187.5
5179545 | 01 eerste verdieping | 3240 | 1100 | 0.1375 | 0.4455 | 3.564 | 3.564 | 0.4455 | 0 | 0 | 1 | Up to level: V2 ok. ruwe vloer | 3.564 | 1212.5
5204586 | 00 Begane grond | 3240 | 775 | 0.096875 | 0.313875 | 2.511 | 2.511 | 0.313875 | 0 | 0 | 0 | Up to level: V1 ok. ruwe vloer | 2.511 | 712.5
5206014 | 00 Begane grond | 3240 | 1250 | 0.15625 | 0.50625 | 4.05 | 4.05 | 0.50625 | 0 | 0 | 0 | Up to level: V1 ok. ruwe vloer | 4.05 | 1375
5296063 | 00 Begane grond | 3240 | 2110 | 0.26375 | 0.22455 | 1.7964 | 1.7964 | 0.22455 | 0 | 0 | 0 | Up to level: V1 ok. ruwe vloer | 1.7964 | 2110 | Pset_wanden - NLRS_C_brandwerendheid: 30; NLRS_C_brandklasse_eis: 30; Fire Protection - NLRS_C_brandwerendheid: 30; NLRS_C_brandklasse_eis: 30
5306818 | 00 Begane grond | 3240 | 978 | 0.12225 | 0.39609 | 3.16872 | 3.16872 | 0.39609 | 0 | 0 | 0 | Up to level: V1 ok. ruwe vloer | 3.16872 | 915.5 | Pset_wanden - NLRS_C_brandwerendheid: R200; Fire Protection - NLRS_C_brandwerendheid: R200
5308064 | 00 Begane grond | 3240 | 415 | 0.051875 | 0.168075 | 1.3446 | 1.3446 | 0.168075 | 0 | 0 | 0 | Up to level: V1 ok. ruwe vloer | 1.3446 | 415
5381859 | 00 Begane grond | 3240 | 688 | 0.086 | 0.27864 | 2.22912 | 2.22912 | 0.27864 | 0 | 0 | 0 | Up to level: V1 ok. ruwe vloer | 2.22912 | 625.5
5988143 | 01 eerste verdieping | 3240 | 535 | 0.066875 | 0.216675 | 1.7334 | 1.7334 | 0.216675 | 0 | 0.0000290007 | 1 | Up to level: V2 ok. ruwe vloer | 1.7334 | 597.5
5994604 | 01 eerste verdieping | 3240 | 535 | 0.066875 | 0.216675 | 1.7334 | 1.7334 | 0.216675 | 0 | 0.0000290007 | 1 | Up to level: V2 ok. ruwe vloer | 1.7334 | 597.5
5994777 | 01 eerste verdieping | 3240 | 1125 | 0.140625 | 0.455625 | 3.645 | 3.645 | 0.455625 | 0 | 0.0000290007 | 1 | Up to level: V2 ok. ruwe vloer | 3.645 | 1187.5
5994987 | 01 eerste verdieping | 3240 | 535 | 0.066875 | 0.216675 | 1.7334 | 1.7334 | 0.216675 | 0 | 0 | 1 | Up to level: V2 ok. ruwe vloer | 1.7334 | 597.5
6239304 | 00 Begane grond | 3690 | 740 | 0.0925 | 0.341325 | 2.7306 | 2.7306 | 0.341325 | -40 | 0 | 0 | Up to level: 1 | 2.7306 | 740
6329617 | 00 Begane grond | 3240 | 977.5 | 0.122187 | 0.395888 | 3.1671 | 3.1671 | 0.395888 | 0 | 0 | 0 | Up to level: V1 ok. ruwe vloer | 3.1671 | 915
6366191 | 00 Begane grond | 3240 | 1785 | 0.223125 | 0.722925 | 5.7834 | 5.7834 | 0.722925 | 0 | 0 | 0 | Up to level: V1 ok. ruwe vloer | 5.7834 | 1785 | Group: Model Group:WC_V0:4976980
6366337 | 00 Begane grond | 3240 | 1785 | 0.223125 | 0.722925 | 5.7834 | 5.7834 | 0.722925 | 0 | 0 | 0 | Up to level: V1 ok. ruwe vloer | 5.7834 | 1785 | Group: Model Group:WC_V0:4977293
6366341 | 00 Begane grond | 3240 | 1785 | 0.223125 | 0.722925 | 5.7834 | 5.7834 | 0.722925 | 0 | 0 | 0 | Up to level: V1 ok. ruwe vloer | 5.7834 | 1785 | Group: Model Group:WC_V0:4977398
6366345 | 01 eerste verdieping | 3240 | 1785 | 0.223125 | 0.722925 | 5.7834 | 5.7834 | 0.722925 | 0 | 0.0000290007 | 1 | Up to level: V2 ok. ruwe vloer | 5.7834 | 1785 | Group: Model Group:WC_V0:5035649
6366349 | 01 eerste verdieping | 3240 | 1785 | 0.223125 | 0.722925 | 5.7834 | 5.7834 | 0.722925 | 0 | 0.0000290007 | 1 | Up to level: V2 ok. ruwe vloer | 5.7834 | 1785 | Group: Model Group:WC_V0:5035659
6366353 | 01 eerste verdieping | 3240 | 1785 | 0.223125 | 0.722925 | 5.7834 | 5.7834 | 0.722925 | 0 | 0.0000290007 | 1 | Up to level: V2 ok. ruwe vloer | 5.7834 | 1785 | Group: Model Group:WC_V0:5994912
6366520 | 00 Begane grond | 3240 | 535 | 0.066875 | 0.216675 | 1.7334 | 1.7334 | 0.216675 | 0 | 0 | 0 | Up to level: V1 ok. ruwe vloer | 1.7334 | 597.5
6366590 | 00 Begane grond | 3240 | 535 | 0.066875 | 0.216675 | 1.7334 | 1.7334 | 0.216675 | 0 | 0 | 0 | Up to level: V1 ok. ruwe vloer | 1.7334 | 597.5
6366730 | 00 Begane grond | 3240 | 1250 | 0.15625 | 0.50625 | 4.05 | 4.05 | 0.50625 | 0 | 0 | 0 | Up to level: V1 ok. ruwe vloer | 4.05 | 1250
6368831 | 01 eerste verdieping | 3240 | 535 | 0.066875 | 0.216675 | 1.7334 | 1.7334 | 0.216675 | 0 | 0.0000290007 | 1 | Up to level: V2 ok. ruwe vloer | 1.7334 | 597.5
6368977 | 01 eerste verdieping | 3240 | 660 | 0.0825 | 0.2673 | 2.1384 | 2.1384 | 0.2673 | 0 | 0.0000290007 | 1 | Up to level: V2 ok. ruwe vloer | 2.1384 | 660
6369100 | 01 eerste verdieping | 3240 | 1125 | 0.140625 | 0.455625 | 3.645 | 3.645 | 0.455625 | 0 | 0.0000290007 | 1 | Up to level: V2 ok. ruwe vloer | 3.645 | 1187.5
6369225 | 01 eerste verdieping | 3240 | 1250 | 0.15625 | 0.50625 | 4.05 | 4.05 | 0.50625 | 0 | 0.0000290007 | 1 | Up to level: V2 ok. ruwe vloer | 4.05 | 1250
6369532 | 01 eerste verdieping | 3240 | 1125 | 0.140625 | 0.455625 | 3.645 | 3.645 | 0.455625 | 0 | 0.0000290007 | 1 | Up to level: V2 ok. ruwe vloer | 3.645 | 1187.5
6369680 | 01 eerste verdieping | 3240 | 535 | 0.066875 | 0.216675 | 1.7334 | 1.7334 | 0.216675 | 0 | 0.0000290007 | 1 | Up to level: V2 ok. ruwe vloer | 1.7334 | 597.5
6369796 | 01 eerste verdieping | 3240 | 1125 | 0.140625 | 0.455625 | 3.645 | 3.645 | 0.455625 | 0 | 0 | 1 | Up to level: V2 ok. ruwe vloer | 3.645 | 1187.5
6371684 | 01 eerste verdieping | 3240 | 660 | 0.0825 | 0.2673 | 2.1384 | 2.1384 | 0.2673 | 0 | 0.0000290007 | 1 | Up to level: V2 ok. ruwe vloer | 2.1384 | 597.5
6371836 | 01 eerste verdieping | 3240 | 1250 | 0.15625 | 0.50625 | 4.05 | 3.4259 | 0.428238 | 0 | 0.0000290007 | 1 | Up to level: V2 ok. ruwe vloer | 3.4259 | 1187.5
6371951 | 01 eerste verdieping | 3240 | 535 | 0.066875 | 0.216675 | 1.7334 | 1.7334 | 0.216675 | 0 | 0.0000290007 | 1 | Up to level: V2 ok. ruwe vloer | 1.7334 | 597.5
6372257 | 01 eerste verdieping | 3240 | 1250 | 0.15625 | 0.50625 | 4.05 | 4.05 | 0.50625 | 0 | 0 | 1 | Up to level: V2 ok. ruwe vloer | 4.05 | 1250
6382280 | 00 Begane grond | 2415 | 1656.25 | 0.207031 | 0.0377344 | 0.301875 | 0.301875 | 0.0219805 | 0 | 0 | 0 |  | 0.175844 | 1656.25
6382295 | 01 eerste verdieping | 2400 | 2866.5 | 0.358312 | 0.0730425 | 0.58434 | 0.58434 | 0.0730425 | 0 | 0 | 1 |  | 0.58434 | 2866.5
6382302 | 00 Begane grond | 2400 | 2100 | 0.2625 | 0.190838 | 1.5267 | 1.5267 | 0.190838 | 0 | 0 | 0 |  | 1.5267 | 2100
6395494 | 00 Begane grond | 3240 | 660 | 0.0825 | 0.2673 | 2.1384 | 2.1384 | 0.2673 | 0 | 0 | 0 | Up to level: V1 ok. ruwe vloer | 2.1384 | 660
6397968 | 00 Begane grond | 3240 | 600 | 0.075 | 0.243 | 1.944 | 1.944 | 0.243 | 0 | 0 | 0 | Up to level: V1 ok. ruwe vloer | 1.944 | 600 | Pset_wanden - NLRS_C_brandwerendheid: 30; Fire Protection - NLRS_C_brandwerendheid: 30
6400357 | 00 Begane grond | 2415 | 4370 | 0.54625 | 0.068925 | 0.5514 | 0.5514 | 0.068925 | 0 | 0 | 0 |  | 0.5514 | 4495
6401127 | 00 Begane grond | 2415 | 2430 | 0.30375 | 0.733556 | 5.86845 | 5.86845 | 0.733556 | 0 | 0 | 0 |  | 5.86845 | 2580
6401293 | 00 Begane grond | 2415 | 588 | 0.0735 | 0.177503 | 1.42002 | 1.42002 | 0.177503 | 0 | 0 | 0 |  | 1.42002 | 713
6401907 | 00 Begane grond | 2415 | 563 | 0.070375 | 0.169956 | 1.35964 | 1.35964 | 0.169956 | 0 | 0 | 0 |  | 1.35964 | 563
6401970 | 00 Begane grond | 2415 | 563 | 0.070375 | 0.169956 | 1.35964 | 1.35964 | 0.169956 | 0 | 0 | 0 |  | 1.35964 | 625.5
6402098 | 00 Begane grond | 2415 | 4495 | 0.561875 | 0.106659 | 0.853275 | 0.853275 | 0.106659 | 0 | 0 | 0 |  | 0.853275 | 4557.5
6406579 | 01 eerste verdieping | 3240 | 660 | 0.0825 | 0.2673 | 2.1384 | 2.1384 | 0.2673 | 0 | 0 | 1 | Up to level: V2 ok. ruwe vloer | 2.1384 | 660
6693819 | 00 Begane grond | 3240 | 1670 | 0.20875 | 0.237188 | 1.8975 | 1.8975 | 0.237188 | 0 | 0 | 0 | Up to level: V1 ok. ruwe vloer | 1.8975 | 1670 | Pset_wanden - NLRS_C_brandwerendheid: 30; Fire Protection - NLRS_C_brandwerendheid: 30
6884492 | 00 Begane grond | 3240 | 675.5 | 0.0844375 | 0.273578 | 2.18862 | 2.18862 | 0.273578 | 0 | 0 | 0 | Up to level: V1 ok. ruwe vloer | 2.18862 | 675.5 | Pset_wanden - NLRS_C_brandwerendheid: R200; Fire Protection - NLRS_C_brandwerendheid: R200
6884493 | 00 Begane grond | 3240 | 302.5 | 0.0378125 | 0.122513 | 0.9801 | 0.9801 | 0.122513 | 0 | 0 | 0 | Up to level: V1 ok. ruwe vloer | 0.9801 | 302.5

# IfcWallStandardCase: Basic Wall:22_DAT_binnenwand_125 HPL dubbel (18)
Type - PredefinedType: STANDARD; Material: ISR_HPL Kleur hout 12 mm, ISR_Binnenwand 101 mm, ISR_HPL Kleur hout 12 mm
Type - Other(Type) - Category: Walls; Family Name: Basic Wall
Type - Construction(Type) - Function: Interior; Wrapping at Inserts: Do not wrap; Width: 125 mm
Type - Graphics(Type) - Coarse Scale Fill Pattern: <Solid fill>; Coarse Scale Fill Color: 12632256
Type - Identity Data(Type) - Workset: Wall Types; Assembly Code: 22.13; Assembly Description: binnenwanden; niet constructief, systeemwanden; vast; Description: Lichte scheidingswand 125mmAan weerszijden gipsvezelplaat 12,5mmGipsplaat 12,5mm Met daartussen 75mm ms wand gevuld met isolatieVulling afhankelijk van gestelde eisen ingeluidsrapportage; Type Name: 22_DAT_binnenwand_125 HPL dubbel
Type - Materials and Finishes(Type) - Structural Material: ISR_Binnenwand
Type - Analytical Properties(Type) - Roughness: 1; Absorptance: 0.1
Type - Pset_ElementShading - Roughness: 304.8 mm
Type - Pset_ProductRequirements - Category: Walls
Type - Pset_ReinforcementBarPitchOfWall - Description: Lichte scheidingswand 125mmAan weerszijden gipsvezelplaat 12,5mmGipsplaat 12,5mm Met daartussen 75mm ms wand gevuld met isolatieVulling afhankelijk van gestelde eisen ingeluidsrapportage
Type - Pset_WallCommon - IsExternal: no
Classification: 22.13 Uniformat (Uniformat)
BaseQuantities - Width: 125 mm
Pset_QuantityTakeOff - Reference: 22_DAT_binnenwand_125 HPL dubbel; sets with these values: 2
Pset_WallCommon - ExtendToStructure: no; LoadBearing: no; Reference: 22_DAT_binnenwand_125 HPL dubbel
Pset_wanden - Structural Usage: Non-bearing; Omschrijving: Lichte scheidingswand 125mmAan weerszijden gipsvezelplaat 12,5mmGipsplaat 12,5mm Met daartussen 75mm ms wand gevuld met isolatieVulling afhankelijk van gestelde eisen ingeluidsrapportage; NL-sfb-Codering: 22.13
Pset_DAT_KMS - Assembly Code: 22.13; Assembly Description: binnenwanden; niet constructief, systeemwanden; vast; Description: Lichte scheidingswand 125mmAan weerszijden gipsvezelplaat 12,5mmGipsplaat 12,5mm Met daartussen 75mm ms wand gevuld met isolatieVulling afhankelijk van gestelde eisen ingeluidsrapportage
Other - Category: Walls; Family: Basic Wall; Family and Type: Basic Wall: 22_DAT_binnenwand_125 HPL dubbel; Type: 22_DAT_binnenwand_125 HPL dubbel; Type Id: 6394901
Constraints - Base Offset: 0 mm; Base Extension Distance: 0 mm; Base is Attached: no; Related to Mass: no; Room Bounding: yes; Top Extension Distance: 0 mm; Top is Attached: no; Location Line: Wall Centerline
Identity Data - Workset: Bouwkundig
Phasing - Phase Created: 2. nieuwbouw
Structural - Structural Usage: Non-bearing; Structural: no
Cross-Section Definition - Cross-Section: Vertical
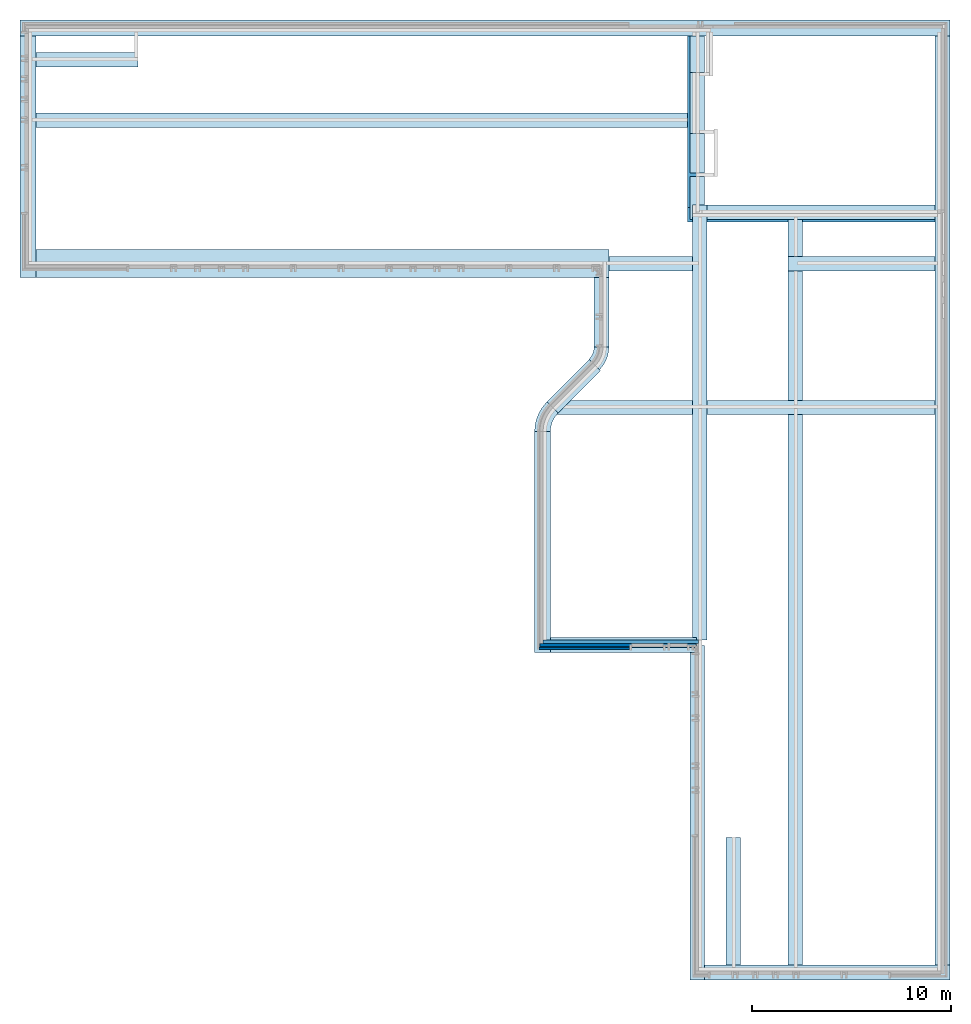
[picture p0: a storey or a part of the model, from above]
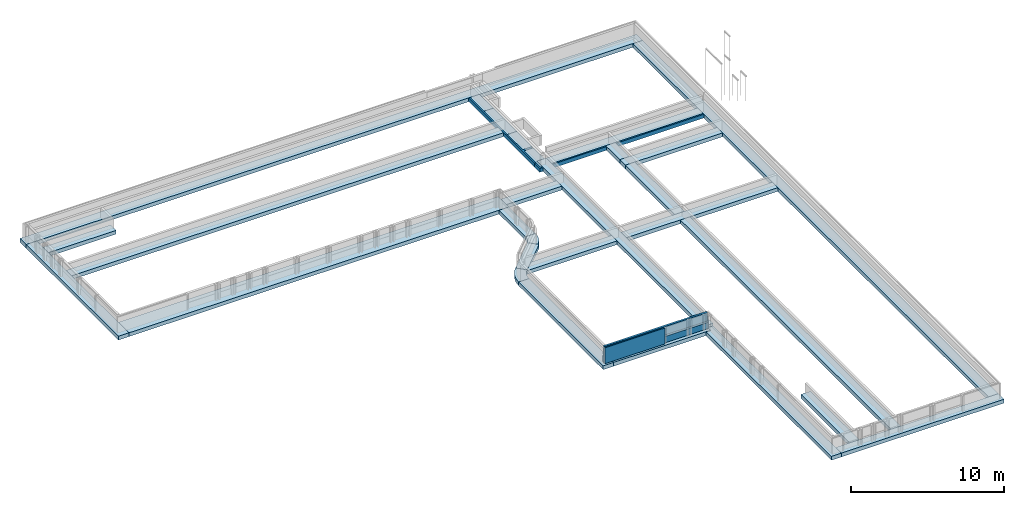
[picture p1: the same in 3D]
Properties of the parts of a building model (IFC2X3), part 34 of 37

# IfcWallStandardCase: Basic Wall:22_DAT_binnenwand_125 HPL dubbel (18)
Name (Basic Wall:22_DAT_binnenwand_125 HPL dubbel:...) | In | Height (mm) = Unconnected Height (mm) | BaseQuantities, Length (mm) | GrossFootprintArea (m2) | GrossVolume (m3) | GrossSideArea (m2) | NetSideArea (m2) = Area (m2) | NetVolume (m3) = Volume (m3) | Top Offset (mm) | Base Constraint | Top Constraint | Dimensions, Length (mm)
4963858 | 00 Begane grond | 3240 | 2430 | 0.30375 | 0.98415 | 7.8732 | 6.4332 | 0.80415 | 0 | 0 | Up to level: V1 ok. ruwe vloer | 2430 | Pset_wanden - NLRS_C_brandwerendheid: R200; Fire Protection - NLRS_C_brandwerendheid: R200
4963956 | 00 Begane grond | 3240 | 2430 | 0.30375 | 0.98415 | 7.8732 | 6.4332 | 0.80415 | 0 | 0 | Up to level: V1 ok. ruwe vloer | 2492.5
4979798 | 00 Begane grond | 3240 | 4275 | 0.534375 | 1.18934 | 9.51474 | 9.51474 | 1.18934 | 0 | 0 | Up to level: V1 ok. ruwe vloer | 4400
4979938 | 00 Begane grond | 3207 | 4275 | 0.534375 | 1.17171 | 9.37367 | 9.37367 | 1.17171 | -33 | 0 | Up to level: V1 ok. ruwe vloer | 4400
4980018 | 00 Begane grond | 3240 | 4275 | 0.534375 | 1.18934 | 9.51474 | 9.51474 | 1.18934 | 0 | 0 | Up to level: V1 ok. ruwe vloer | 4337.5
5035466 | 01 eerste verdieping | 3240 | 4275 | 0.534375 | 1.18934 | 9.51474 | 9.51474 | 1.18934 | 0 | 1 | Up to level: V2 ok. ruwe vloer | 4400
5035879 | 01 eerste verdieping | 3240 | 4275 | 0.534375 | 1.18934 | 9.51474 | 9.51474 | 1.18934 | 0 | 1 | Up to level: V2 ok. ruwe vloer | 4400
5035888 | 01 eerste verdieping | 3240 | 4275 | 0.534375 | 1.18934 | 9.51474 | 9.51474 | 1.18934 | 0 | 1 | Up to level: V2 ok. ruwe vloer | 4400
5037885 | 01 eerste verdieping | 3240 | 4275 | 0.534375 | 1.22722 | 9.81774 | 9.81774 | 1.22722 | 0 | 1 | Up to level: V2 ok. ruwe vloer | 4400
5037968 | 01 eerste verdieping | 3240 | 4275 | 0.534375 | 1.22722 | 9.81774 | 9.81774 | 1.22722 | 0 | 1 | Up to level: V2 ok. ruwe vloer | 4400
5038896 | 01 eerste verdieping | 3240 | 4275 | 0.534375 | 1.22722 | 9.81774 | 9.81774 | 1.22722 | 0 | 1 | Up to level: V2 ok. ruwe vloer | 4400
5130547 | 00 Begane grond | 1200 | 3290 | 0.41125 | 0.4935 | 3.948 | 3.948 | 0.4935 | 0 | 0 |  | 3165
5130578 | 00 Begane grond | 1200 | 675 | 0.084375 | 0.10125 | 0.81 | 0.81 | 0.10125 | 0 | 0 |  | 737.5
5988144 | 01 eerste verdieping | 3240 | 4275 | 0.534375 | 1.22722 | 9.81774 | 9.81774 | 1.22722 | 0 | 1 | Up to level: V2 ok. ruwe vloer | 4400
6397607 | 00 Begane grond | 2415 | 3910 | 0.48875 | 0.638299 | 5.10639 | 5.10639 | 0.638299 | 0 | 0 |  | 3972.5
6398402 | 00 Begane grond | 3240 | 475 | 0.059375 | 0.192375 | 1.539 | 1.539 | 0.192375 | 0 | 0 | Up to level: V1 ok. ruwe vloer | 537.5
6400512 | 00 Begane grond | 2415 | 4535 | 0.566875 | 0.136659 | 1.09328 | 1.09328 | 0.136659 | 0 | 0 |  | 4597.5
6428936 | 00 Begane grond | 1200 | 675 | 0.084375 | 0.10125 | 0.81 | 0.81 | 0.10125 | 0 | 0 |  | 737.5

# IfcWallStandardCase: Basic Wall:22_DAT_binnenwand_25 (105)
Type - PredefinedType: STANDARD; Material: ISR_Gips 1 mm, ISR_Binnenwand 23 mm, ISR_Gips 1 mm
Type - Other - Category: Walls; Family Name: Basic Wall
Type - Construction - Function: Interior; Wrapping at Inserts: Do not wrap; Width: 25 mm
Type - Graphics - Coarse Scale Fill Pattern: <Solid fill>; Coarse Scale Fill Color: 12632256
Type - Identity Data - Workset: Wall Types; Assembly Code: 22.13; Assembly Description: binnenwanden; niet constructief, systeemwanden; vast; Description: Lichte scheidingswand 100mm; Type Comments: Dubbele gipsplaat; Type Name: 22_DAT_binnenwand_25
Type - Materials and Finishes - Structural Material: ISR_Binnenwand
Type - Analytical Properties - Roughness: 1; Absorptance: 0.1
Type - Pset_ElementShading - Roughness: 304.8 mm
Type - Pset_ProductRequirements - Category: Walls
Type - Pset_ReinforcementBarPitchOfWall - Description: Lichte scheidingswand 100mm
Type - Pset_WallCommon - IsExternal: no
Classification: 22.13 Uniformat (Uniformat)
BaseQuantities - Width: 25 mm
Pset_QuantityTakeOff - Reference: 22_DAT_binnenwand_25; sets with these values: 2
Pset_WallCommon - ExtendToStructure: no; LoadBearing: no; Reference: 22_DAT_binnenwand_25
Pset_wanden - Structural Usage: Non-bearing; Omschrijving: Lichte scheidingswand 100mm; NL-sfb-Codering: 22.13
Pset_DAT_KMS - Assembly Code: 22.13; Assembly Description: binnenwanden; niet constructief, systeemwanden; vast; Description: Lichte scheidingswand 100mm
Other - Family: Basic Wall; Family and Type: Basic Wall: 22_DAT_binnenwand_25; Type: 22_DAT_binnenwand_25; Type Id: 4977124
Constraints - Base Extension Distance: 0 mm; Base is Attached: no; Related to Mass: no; Room Bounding: yes; Top Extension Distance: 0 mm; Top is Attached: no; Location Line: Wall Centerline
Phasing - Phase Created: 2. nieuwbouw
Structural - Structural Usage: Non-bearing; Structural: no
Cross-Section Definition - Cross-Section: Vertical
Name (Basic Wall:22_DAT_binnenwand_25:...) | In | Height (mm) = Unconnected Height (mm) | BaseQuantities, Length (mm) | GrossFootprintArea (m2) | GrossVolume (m3) | GrossSideArea (m2) | NetSideArea (m2) = Area (m2) | NetVolume (m3) = Volume (m3) | Base Offset (mm) | Top Offset (mm) | Base Constraint | Top Constraint | Dimensions, Length (mm) | Workset | Group
4966971 | 00 Begane grond | 3240 | 1970 | 0.04925 | 0.15957 | 6.3828 | 6.3828 | 0.15957 | 0 | 0 | 0 | Up to level: V1 ok. ruwe vloer | 2095 | Bouwkundig
4977530 | 00 Begane grond | 2470 | 1660 | 0.0415 | 0.102505 | 4.1002 | 4.1002 | 0.102505 | 0 | 70 | 0 | Up to level: V0 ok. plafond | 1660 | Bouwkundig | Model Group:WC_V0:4976980
4977709 | 00 Begane grond | 2470 | 1660 | 0.0415 | 0.102505 | 4.1002 | 4.1002 | 0.102505 | 0 | 70 | 0 | Up to level: V0 ok. plafond | 1660 | Bouwkundig | Model Group:WC_V0:4977293
4977720 | 00 Begane grond | 2470 | 1660 | 0.0415 | 0.102505 | 4.1002 | 4.1002 | 0.102505 | 0 | 70 | 0 | Up to level: V0 ok. plafond | 1660 | Bouwkundig | Model Group:WC_V0:4977398
5000929 | 00 Begane grond | 3170 | 920 | 0.023 | 0.07291 | 2.9164 | 2.9164 | 0.07291 | 0 | -70 | 0 | Up to level: V1 ok. ruwe vloer | 920 | Bouwkundig
5035661 | 01 eerste verdieping | 2470 | 1660 | 0.0415 | 0.102505 | 4.1002 | 4.1002 | 0.102505 | 0 | 70 | 1 | Up to level: V1 ok. plafond | 1660 | Bouwkundig | Model Group:WC_V0:5035649
5035679 | 01 eerste verdieping | 2470 | 1660 | 0.0415 | 0.102505 | 4.1002 | 4.1002 | 0.102505 | 0 | 70 | 1 | Up to level: V1 ok. plafond | 1660 | Bouwkundig | Model Group:WC_V0:5035659
5132636 | 00 Begane grond | 2600 | 1614.88 | 0.0403719 | 0.104967 | 4.19868 | 4.19868 | 0.104967 | 0 | 200 | 0 | Up to level: V0 ok. plafond | 1602.38 | Bouwkundig
5132863 | 00 Begane grond | 2600 | 200 | 0.005 | 0.013 | 0.52 | 0.52 | 0.013 | 0 | 200 | 0 | Up to level: V0 ok. plafond | 275 | Bouwkundig
5136081 | 00 Begane grond | 3170 | 2085 | 0.052125 | 0.165236 | 6.60945 | 6.60945 | 0.165236 | 0 | -70 | 0 | Up to level: V1 ok. ruwe vloer | 2210 | Bouwkundig
5152508 | 00 Begane grond | 840 | 2435 | 0.060875 | 0.051135 | 2.0454 | 2.0454 | 0.051135 | 0 | 0 | V0 ok. plafond | Up to level: V1 ok. ruwe vloer | 2435 | Bouwkundig
5153099 | 00 Begane grond | 840 | 2430 | 0.06075 | 0.05103 | 2.0412 | 2.0412 | 0.05103 | 0 | 0 | V0 ok. plafond | Up to level: V1 ok. ruwe vloer | 2430 | Bouwkundig
5153160 | 00 Begane grond | 840 | 1975 | 0.049375 | 0.041475 | 1.659 | 1.659 | 0.041475 | 0 | 0 | V0 ok. plafond | Up to level: V1 ok. ruwe vloer | 1975 | Bouwkundig
5154639 | 00 Begane grond | 1140 | 1250 | 0.03125 | 0.035625 | 1.425 | 1.425 | 0.035625 | -300 | 0 | V0 ok. plafond | Up to level: V1 ok. ruwe vloer | 1250 | Bouwkundig
5165416 | 00 Begane grond | 840 | 1260 | 0.0315 | 0.02646 | 1.0584 | 1.0584 | 0.02646 | 0 | 0 | V0 ok. plafond | Up to level: V1 ok. ruwe vloer | 1260 | Bouwkundig
5172606 | 01 eerste verdieping | 840 | 4287 | 0.107175 | 0.090027 | 3.60108 | 3.60108 | 0.090027 | 0 | 0 | V1 ok. plafond | Up to level: V2 ok. ruwe vloer | 4287 | Bouwkundig
5172759 | 01 eerste verdieping | 840 | 4275 | 0.106875 | 0.089775 | 3.591 | 3.591 | 0.089775 | 0 | 0 | V1 ok. plafond | Up to level: V2 ok. ruwe vloer | 4337.5 | Bouwkundig | Model Group:V1_Basiselement:5167028
5174539 | 01 eerste verdieping | 2470 | 1660 | 0.0415 | 0.102505 | 4.1002 | 4.1002 | 0.102505 | 0 | 70 | 1 | Up to level: V1 ok. plafond | 1660 | Bouwkundig
5174901 | 01 eerste verdieping | 840 | 4272.5 | 0.106813 | 0.0897225 | 3.5889 | 3.5889 | 0.0897225 | 0 | 0 | V1 ok. plafond | Up to level: V2 ok. ruwe vloer | 4335 | Bouwkundig
5178862 | 01 eerste verdieping | 3170 | 1064 | 0.0266 | 0.084322 | 3.37288 | 3.37288 | 0.084322 | 0 | -70 | 1 | Up to level: V2 ok. ruwe vloer | 1189 | Bouwkundig
5180098 | 01 eerste verdieping | 840 | 6610 | 0.16525 | 0.13881 | 5.5524 | 5.5524 | 0.13881 | 0 | 0 | V1 ok. plafond | Up to level: V2 ok. ruwe vloer | 6697.5 | Bouwkundig
5188811 | 00 Begane grond | 640 | 6880 | 0.172 | 0.11008 | 4.4032 | 4.4032 | 0.11008 | 200 | 0 | V0 ok. plafond | Up to level: V1 ok. ruwe vloer | 6880 | Bouwkundig
5189015 | 00 Begane grond | 640 | 6880 | 0.172 | 0.11008 | 4.4032 | 4.4032 | 0.11008 | 200 | 0 | V0 ok. plafond | Up to level: V1 ok. ruwe vloer | 6880 | Bouwkundig
5189688 | 00 Begane grond | 640 | 6940 | 0.1735 | 0.11104 | 4.4416 | 4.4416 | 0.11104 | 200 | 0 | V0 ok. plafond | Up to level: V1 ok. ruwe vloer | 6940 | Bouwkundig
5203626 | 00 Begane grond | 840 | 4275 | 0.106875 | 0.089775 | 3.591 | 3.591 | 0.089775 | 0 | 0 | V0 ok. plafond | Up to level: V1 ok. ruwe vloer | 4275 | Bouwkundig | Model Group:Basisgroep element 2:5203610
5250477 | 01 eerste verdieping | 840 | 4275 | 0.106875 | 0.089775 | 3.591 | 3.591 | 0.089775 | 0 | 0 | V1 ok. plafond | Up to level: V2 ok. ruwe vloer | 4337.5 | Bouwkundig
5250590 | 01 eerste verdieping | 840 | 4275 | 0.106875 | 0.089775 | 3.591 | 3.591 | 0.089775 | 0 | 0 | V1 ok. plafond | Up to level: V2 ok. ruwe vloer | 4337.5 | Bouwkundig | Model Group:V1_Basiselement:5167028
5250602 | 01 eerste verdieping | 840 | 4275 | 0.106875 | 0.089775 | 3.591 | 3.591 | 0.089775 | 0 | 0 | V1 ok. plafond | Up to level: V2 ok. ruwe vloer | 4337.5 | Bouwkundig
5472464 | 00 Begane grond | 840 | 3290 | 0.08225 | 0.06909 | 2.7636 | 2.7636 | 0.06909 | 0 | 0.00000414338 | V0 ok. plafond | Up to level: V1 ok. ruwe vloer | 3290 | Bouwkundig
5936771 | 01 eerste verdieping | 410 | 8500 | 0.2125 | 0.087125 | 3.485 | 3.485 | 0.087125 | -410 | -3240 | 1 | Up to level: V2 ok. ruwe vloer | 8500 | Bouwkundig
5988155 | 01 eerste verdieping | 840 | 4337.5 | 0.108437 | 0.0910875 | 3.6435 | 3.6435 | 0.0910875 | 0 | 0 | V1 ok. plafond | Up to level: V2 ok. ruwe vloer | 4337.5 | Bouwkundig | Model Group:V1_Basiselement:5988153
5988174 | 01 eerste verdieping | 840 | 4275 | 0.106875 | 0.089775 | 3.591 | 3.591 | 0.089775 | 0 | 0 | V1 ok. plafond | Up to level: V2 ok. ruwe vloer | 4337.5 | Bouwkundig | Model Group:V1_Basiselement:5988153
5994914 | 01 eerste verdieping | 2470 | 1660 | 0.0415 | 0.102505 | 4.1002 | 4.1002 | 0.102505 | 0 | 70 | 1 | Up to level: V1 ok. plafond | 1660 | Bouwkundig | Model Group:WC_V0:5994912
5996741 | 00 Begane grond | 840 | 4275 | 0.106875 | 0.089775 | 3.591 | 3.591 | 0.089775 | 0 | 0 | V0 ok. plafond | Up to level: V1 ok. ruwe vloer | 4275 | Bouwkundig | Model Group:Basisgroep element:5145670
5996742 | 00 Begane grond | 840 | 4275 | 0.106875 | 0.089775 | 3.591 | 3.591 | 0.089775 | 0 | 0 | V0 ok. plafond | Up to level: V1 ok. ruwe vloer | 4275 | Bouwkundig | Model Group:Basisgroep element:5145620
5996746 | 00 Begane grond | 840 | 4275 | 0.106875 | 0.089775 | 3.591 | 3.591 | 0.089775 | 0 | 0 | V0 ok. plafond | Up to level: V1 ok. ruwe vloer | 4275 | Bouwkundig | Model Group:Basisgroep element:5145694
5996747 | 01 eerste verdieping | 840 | 4275 | 0.106875 | 0.089775 | 3.591 | 3.591 | 0.089775 | 0 | 0.0000290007 | V1 ok. plafond | Up to level: V2 ok. ruwe vloer | 4275 | Bouwkundig | Model Group:Basisgroep element:5181887
5996748 | 01 eerste verdieping | 840 | 4275 | 0.106875 | 0.089775 | 3.591 | 3.591 | 0.089775 | 0 | 0.0000290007 | V1 ok. plafond | Up to level: V2 ok. ruwe vloer | 4275 | Bouwkundig | Model Group:Basisgroep element:5184346
5996749 | 01 eerste verdieping | 840 | 4275 | 0.106875 | 0.089775 | 3.591 | 3.591 | 0.089775 | 0 | 0.0000290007 | V1 ok. plafond | Up to level: V2 ok. ruwe vloer | 4275 | Bouwkundig | Model Group:Basisgroep element:5184395
5996901 | 00 Begane grond | 840 | 4275 | 0.106875 | 0.089775 | 3.591 | 3.591 | 0.089775 | 0 | 0 | V0 ok. plafond | Up to level: V1 ok. ruwe vloer | 4275 | Bouwkundig | Model Group:Basisgroep element:5145670
5996991 | 00 Begane grond | 840 | 4275 | 0.106875 | 0.089775 | 3.591 | 3.591 | 0.089775 | 0 | 0 | V0 ok. plafond | Up to level: V1 ok. ruwe vloer | 4275 | Bouwkundig | Model Group:Basisgroep element:5145620
5996997 | 00 Begane grond | 840 | 4275 | 0.106875 | 0.089775 | 3.591 | 3.591 | 0.089775 | 0 | 0 | V0 ok. plafond | Up to level: V1 ok. ruwe vloer | 4275 | Bouwkundig | Model Group:Basisgroep element:5145694
5997000 | 01 eerste verdieping | 840 | 4275 | 0.106875 | 0.089775 | 3.591 | 3.591 | 0.089775 | 0 | 0.0000290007 | V1 ok. plafond | Up to level: V2 ok. ruwe vloer | 4275 | Bouwkundig | Model Group:Basisgroep element:5181887
5997003 | 01 eerste verdieping | 840 | 4275 | 0.106875 | 0.089775 | 3.591 | 3.591 | 0.089775 | 0 | 0.0000290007 | V1 ok. plafond | Up to level: V2 ok. ruwe vloer | 4275 | Bouwkundig | Model Group:Basisgroep element:5184346
5997006 | 01 eerste verdieping | 840 | 4275 | 0.106875 | 0.089775 | 3.591 | 3.591 | 0.089775 | 0 | 0.0000290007 | V1 ok. plafond | Up to level: V2 ok. ruwe vloer | 4275 | Bouwkundig | Model Group:Basisgroep element:5184395
5998665 | 00 Begane grond | 3310 | 160 | 0.004 | 0.01324 | 0.5296 | 0.5296 | 0.01324 | 0 | 0 | V0 bk. ruwe vloer | Up to level: V1 ok. ruwe vloer | 160 | Bouwkundig | Model Group:Kollom tussenmaat 120x120:5998666
6000702 | 00 Begane grond | 3310 | 160 | 0.004 | 0.01324 | 0.5296 | 0.5296 | 0.01324 | 0 | 0 | V0 bk. ruwe vloer | Up to level: V1 ok. ruwe vloer | 160 | Bouwkundig | Model Group:Kollom tussenmaat 120x120 Heel:6000703
6000769 | 00 Begane grond | 3310 | 167.5 | 0.0041875 | 0.0138606 | 0.554425 | 0.554425 | 0.0138606 | 0 | 0 | V0 bk. ruwe vloer | Up to level: V1 ok. ruwe vloer | 167.5 | Bouwkundig
6001983 | 00 Begane grond | 3310 | 190 | 0.00475 | 0.0157225 | 0.6289 | 0.6289 | 0.0157225 | 0 | 0 | V0 bk. ruwe vloer | Up to level: V1 ok. ruwe vloer | 190 | Bouwkundig | Model Group:Kollom tussenmaat 150x150:6001982
6001994 | 00 Begane grond | 3310 | 190 | 0.00475 | 0.0157225 | 0.6289 | 0.6289 | 0.0157225 | 0 | 0 | V0 bk. ruwe vloer | Up to level: V1 ok. ruwe vloer | 190 | Bouwkundig | Model Group:Kollom tussenmaat 150x150:6001993
6002161 | 00 Begane grond | 3310 | 160 | 0.004 | 0.01324 | 0.5296 | 0.5296 | 0.01324 | 0 | 0 | V0 bk. ruwe vloer | Up to level: V1 ok. ruwe vloer | 160 | Bouwkundig
6002383 | 00 Begane grond | 3310 | 160 | 0.004 | 0.01324 | 0.5296 | 0.5296 | 0.01324 | 0 | 0 | V0 bk. ruwe vloer | Up to level: V1 ok. ruwe vloer | 160 | Bouwkundig | Model Group:Kollom tussenmaat 120x120:6002382
6002466 | 00 Begane grond | 3310 | 160 | 0.004 | 0.01324 | 0.5296 | 0.5296 | 0.01324 | 0 | 0 | V0 bk. ruwe vloer | Up to level: V1 ok. ruwe vloer | 160 | Bouwkundig | Model Group:Kollom tussenmaat 120x120:6002465
6002832 | 00 Begane grond | 3310 | 190 | 0.00475 | 0.0157225 | 0.6289 | 0.6289 | 0.0157225 | 0 | 0 | V0 bk. ruwe vloer | Up to level: V1 ok. ruwe vloer | 190 | Bouwkundig
6007334 | 01 eerste verdieping | 3310 | 160 | 0.004 | 0.01324 | 0.5296 | 0.5296 | 0.01324 | 20 | 0.0000289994 | V1 bk. ruwe vloer | Up to level: V2 ok. ruwe vloer | 160 | Bouwkundig
6007528 | 01 eerste verdieping | 3970 | 190 | 0.00475 | 0.0188575 | 0.7543 | 0.7543 | 0.0188575 | -640 | 0.0000289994 | V1 bk. ruwe vloer | Up to level: V2 ok. ruwe vloer | 190 | Bouwkundig
6008174 | 00 Begane grond | 6860 | 190 | 0.00475 | 0.032585 | 1.3034 | 1.3034 | 0.032585 | 0 | -30 | 0 | Up to level: V2 ok. ruwe vloer | 190 | Bouwkundig | Model Group:Kollom tussenmaat 150x150 Trap:6008169
6008523 | 00 Begane grond | 6860 | 190 | 0.00475 | 0.032585 | 1.3034 | 1.3034 | 0.032585 | 0 | -30 | 0 | Up to level: V2 ok. ruwe vloer | 190 | Bouwkundig | Model Group:Kollom tussenmaat 150x150 Trap:6008522
6008537 | 00 Begane grond | 6860 | 190 | 0.00475 | 0.032585 | 1.3034 | 1.3034 | 0.032585 | 0 | -30 | 0 | Up to level: V2 ok. ruwe vloer | 190 | Bouwkundig | Model Group:Kollom tussenmaat 150x150 Trap:6008536
6141906 | 00 Begane grond | 403 | 6070 | 0.15175 | 0.0611552 | 2.44621 | 2.44621 | 0.0611552 | -83 | 0 | V1 ok. ruwe vloer | Up to level: V1 bk. ruwe vloer | 6070 | Bouwkundig
6141907 | 00 Begane grond | 483 | 1276.27 | 0.0319064 | 0.000301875 | 0.012075 | 0.625923 | 0.0154108 | -73 | 0 | V1 ok. ruwe vloer | Up to level: 1 | 1276.27 | Bouwkundig | Graphics - Center Mark Visible: no
6141908 | 00 Begane grond | 493 | 1276.27 | 0.0319064 | 0.000308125 | 0.012325 | 0.638882 | 0.0157298 | -83 | 0 | V1 ok. ruwe vloer | Up to level: 1 | 1276.27 | Bouwkundig | Graphics - Center Mark Visible: no
6152819 | 01 eerste verdieping | 3310 | 160 | 0.004 | 0.01324 | 0.5296 | 0.5296 | 0.01324 | 20 | 0.0000289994 | V1 bk. ruwe vloer | Up to level: V2 ok. ruwe vloer | 160 | Constructie | Model Group:Kollom tussenmaat 120x120:6152818
6152950 | 01 eerste verdieping | 3310 | 160 | 0.004 | 0.01324 | 0.5296 | 0.5296 | 0.01324 | 20 | 0.0000289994 | V1 bk. ruwe vloer | Up to level: V2 ok. ruwe vloer | 160 | Bouwkundig | Model Group:Kollom tussenmaat 120x120:6152949
6177894 | 01 eerste verdieping | 410 | 5065 | 0.126625 | 0.0519163 | 2.07665 | 2.07665 | 0.0519163 | -410 | 0 | 1 |  | 5152.5 | Bouwkundig
6180702 | 00 Begane grond | 840 | 1955 | 0.048875 | 0.041055 | 1.6422 | 1.6422 | 0.041055 | 0 | 0 | V0 ok. plafond | Up to level: V1 ok. ruwe vloer | 1955 | Bouwkundig
6180723 | 00 Begane grond | 840 | 1960 | 0.049 | 0.04116 | 1.6464 | 1.6464 | 0.04116 | 0 | 0 | V0 ok. plafond | Up to level: V1 ok. ruwe vloer | 1960 | Bouwkundig
6183687 | 00 Begane grond | 410 | 8987.5 | 0.224687 | 0.0921219 | 3.68488 | 3.68488 | 0.0921219 | 0 | 0 | V1 ok. ruwe vloer | Up to level: 1 | 8987.5 | Bouwkundig
6309993 | 00 Begane grond | 840 | 2430 | 0.06075 | 0.05103 | 2.0412 | 2.0412 | 0.05103 | 0 | 0 | V0 ok. plafond | Up to level: V1 ok. ruwe vloer | 2430 | Bouwkundig
6310129 | 00 Begane grond | 840 | 2430 | 0.06075 | 0.05103 | 2.0412 | 2.0412 | 0.05103 | 0 | 0 | V0 ok. plafond | Up to level: V1 ok. ruwe vloer | 2430 | Bouwkundig
6310148 | 00 Begane grond | 840 | 2430 | 0.06075 | 0.05103 | 2.0412 | 2.0412 | 0.05103 | 0 | 0 | V0 ok. plafond | Up to level: V1 ok. ruwe vloer | 2430 | Bouwkundig
6422433 | 00 Begane grond | 840 | 1871.24 | 0.046781 | 0.0392961 | 1.57184 | 1.57184 | 0.0392961 | 0 | 0 | V0 ok. plafond | Up to level: V1 ok. ruwe vloer | 1871.24 | Bouwkundig
6422617 | 00 Begane grond | 840 | 1079.92 | 0.0269983 | 0.000525 | 0.021 | 0.923628 | 0.0226786 | 0 | 0 | V0 ok. plafond | Up to level: V1 ok. ruwe vloer | 1079.92 | Bouwkundig | Graphics - Center Mark Visible: no
6425720 | 00 Begane grond | 840 | 2150.04 | 0.053751 | 0.0451508 | 1.80603 | 1.80603 | 0.0451508 | 0 | 0 | V0 ok. plafond | Up to level: V1 ok. ruwe vloer | 2150.04 | Bouwkundig
6426827 | 00 Begane grond | 340 | 7155 | 0.178875 | 0.0608175 | 2.4327 | 2.4327 | 0.0608175 | 500 | 0 | V0 ok. plafond | Up to level: V1 ok. ruwe vloer | 7242.5 | Bouwkundig
6782612 | 00 Begane grond | 3310 | 160 | 0.004 | 0.01324 | 0.5296 | 0.5296 | 0.01324 | 0 | 0 | V0 bk. ruwe vloer | Up to level: V1 ok. ruwe vloer | 160 | Bouwkundig | Model Group:Kollom tussenmaat 120x120 Heel:6000652
6783638 | 00 Begane grond | 3310 | 160 | 0.004 | 0.01324 | 0.5296 | 0.5296 | 0.01324 | 0 | 0 | V0 bk. ruwe vloer | Up to level: V1 ok. ruwe vloer | 160 | Bouwkundig | Model Group:Kollom tussenmaat 120x120 Heel:5998690
6783687 | 00 Begane grond | 3310 | 160 | 0.004 | 0.01324 | 0.5296 | 0.5296 | 0.01324 | 0 | 0 | V0 bk. ruwe vloer | Up to level: V1 ok. ruwe vloer | 160 | Bouwkundig | Model Group:Kollom tussenmaat 120x120 Heel:5998677
6783769 | 00 Begane grond | 3310 | 160 | 0.004 | 0.01324 | 0.5296 | 0.5296 | 0.01324 | 0 | 0 | V0 bk. ruwe vloer | Up to level: V1 ok. ruwe vloer | 160 | Bouwkundig | Model Group:Kollom tussenmaat 120x120 Heel:5998631
6783816 | 00 Begane grond | 3310 | 160 | 0.004 | 0.01324 | 0.5296 | 0.5296 | 0.01324 | 0 | 0 | V0 bk. ruwe vloer | Up to level: V1 ok. ruwe vloer | 160 | Bouwkundig | Model Group:Kollom tussenmaat 120x120 Heel:5998642
6784506 | 00 Begane grond | 3310 | 160 | 0.004 | 0.01324 | 0.5296 | 0.5296 | 0.01324 | 0 | 0 | V0 bk. ruwe vloer | Up to level: V1 ok. ruwe vloer | 160 | Bouwkundig | Model Group:Kollom tussenmaat 120x120 Heel:5998655
6784589 | 00 Begane grond | 3310 | 160 | 0.004 | 0.01324 | 0.5296 | 0.5296 | 0.01324 | 0 | 0 | V0 bk. ruwe vloer | Up to level: V1 ok. ruwe vloer | 160 | Bouwkundig | Model Group:Kollom tussenmaat 120x120 Heel:5998910
6784765 | 00 Begane grond | 3310 | 160 | 0.004 | 0.01324 | 0.5296 | 0.5296 | 0.01324 | 0 | 0 | V0 bk. ruwe vloer | Up to level: V1 ok. ruwe vloer | 160 | Bouwkundig | Model Group:Kollom tussenmaat 120x120 Heel:5998578
6789432 | 00 Begane grond | 6860 | 190 | 0.00475 | 0.032585 | 1.3034 | 1.3034 | 0.032585 | 0 | -30 | 0 | Up to level: V2 ok. ruwe vloer | 190 | Bouwkundig | Model Group:Kollom tussenmaat 150x150 Trap:6789422
6789702 | 00 Begane grond | 6860 | 190 | 0.00475 | 0.032585 | 1.3034 | 1.3034 | 0.032585 | 0 | -30 | 0 | Up to level: V2 ok. ruwe vloer | 190 | Bouwkundig | Model Group:Kollom tussenmaat 150x150 Trap:6789695
6790265 | 01 eerste verdieping | 3240 | 280 | 0.007 | 0.02268 | 0.9072 | 0.9072 | 0.02268 | 0 | 0 | 1 | Up to level: V2 ok. ruwe vloer | 280 | Bouwkundig | Model Group:Kollom tussenmaat 120x120 eerste verdieping:6790255
6790523 | 01 eerste verdieping | 3240 | 280 | 0.007 | 0.02268 | 0.9072 | 0.9072 | 0.02268 | 0 | 0 | 1 | Up to level: V2 ok. ruwe vloer | 280 | Bouwkundig | Model Group:Kollom tussenmaat 120x120 eerste verdieping:6790516
6790534 | 01 eerste verdieping | 3240 | 280 | 0.007 | 0.02268 | 0.9072 | 0.9072 | 0.02268 | 0 | 0 | 1 | Up to level: V2 ok. ruwe vloer | 280 | Bouwkundig | Model Group:Kollom tussenmaat 120x120 eerste verdieping:6790527
6790545 | 01 eerste verdieping | 3240 | 280 | 0.007 | 0.02268 | 0.9072 | 0.9072 | 0.02268 | 0 | 0 | 1 | Up to level: V2 ok. ruwe vloer | 280 | Bouwkundig | Model Group:Kollom tussenmaat 120x120 eerste verdieping:6790538
6790556 | 01 eerste verdieping | 3240 | 280 | 0.007 | 0.02268 | 0.9072 | 0.9072 | 0.02268 | 0 | 0 | 1 | Up to level: V2 ok. ruwe vloer | 280 | Bouwkundig | Model Group:Kollom tussenmaat 120x120 eerste verdieping:6790549
6790567 | 01 eerste verdieping | 3240 | 280 | 0.007 | 0.02268 | 0.9072 | 0.9072 | 0.02268 | 0 | 0 | 1 | Up to level: V2 ok. ruwe vloer | 280 | Bouwkundig | Model Group:Kollom tussenmaat 120x120 eerste verdieping:6790560
6790578 | 01 eerste verdieping | 3240 | 280 | 0.007 | 0.02268 | 0.9072 | 0.9072 | 0.02268 | 0 | 0 | 1 | Up to level: V2 ok. ruwe vloer | 280 | Bouwkundig | Model Group:Kollom tussenmaat 120x120 eerste verdieping:6790571
6791077 | 01 eerste verdieping | 3240 | 160 | 0.004 | 0.01296 | 0.5184 | 0.5184 | 0.01296 | 0 | 0 | 1 | Up to level: V2 ok. ruwe vloer | 160 | Bouwkundig
6791088 | 01 eerste verdieping | 3240 | 280 | 0.007 | 0.02268 | 0.9072 | 0.9072 | 0.02268 | 0 | 0 | 1 | Up to level: V2 ok. ruwe vloer | 280 | Bouwkundig | Model Group:Kollom tussenmaat 120x120 eerste verdieping:6791081
6791099 | 01 eerste verdieping | 3240 | 280 | 0.007 | 0.02268 | 0.9072 | 0.9072 | 0.02268 | 0 | 0 | 1 | Up to level: V2 ok. ruwe vloer | 280 | Bouwkundig | Model Group:Kollom tussenmaat 120x120 eerste verdieping:6791092
6791110 | 01 eerste verdieping | 3240 | 280 | 0.007 | 0.02268 | 0.9072 | 0.9072 | 0.02268 | 0 | 0 | 1 | Up to level: V2 ok. ruwe vloer | 280 | Bouwkundig | Model Group:Kollom tussenmaat 120x120 eerste verdieping:6791103
6791121 | 01 eerste verdieping | 3240 | 280 | 0.007 | 0.02268 | 0.9072 | 0.9072 | 0.02268 | 0 | 0 | 1 | Up to level: V2 ok. ruwe vloer | 280 | Bouwkundig | Model Group:Kollom tussenmaat 120x120 eerste verdieping:6791114
6791132 | 01 eerste verdieping | 3240 | 280 | 0.007 | 0.02268 | 0.9072 | 0.9072 | 0.02268 | 0 | 0 | 1 | Up to level: V2 ok. ruwe vloer | 280 | Bouwkundig | Model Group:Kollom tussenmaat 120x120 eerste verdieping:6791125
6791143 | 01 eerste verdieping | 3240 | 280 | 0.007 | 0.02268 | 0.9072 | 0.9072 | 0.02268 | 0 | 0 | 1 | Up to level: V2 ok. ruwe vloer | 280 | Bouwkundig | Model Group:Kollom tussenmaat 120x120 eerste verdieping:6791136
6791154 | 01 eerste verdieping | 3240 | 280 | 0.007 | 0.0226018 | 0.904074 | 0.904074 | 0.0226018 | 0 | 0 | 1 | Up to level: V2 ok. ruwe vloer | 280 | Bouwkundig | Model Group:Kollom tussenmaat 120x120 eerste verdieping:6791147
6791987 | 01 eerste verdieping | 3240 | 280 | 0.007 | 0.02268 | 0.9072 | 0.9072 | 0.02268 | 0 | 0 | 1 | Up to level: V2 ok. ruwe vloer | 280 | Bouwkundig | Model Group:Kollom tussenmaat 120x120 eerste verdieping:6791290
6792034 | 01 eerste verdieping | 3240 | 280 | 0.007 | 0.02268 | 0.9072 | 0.9072 | 0.02268 | 0 | 0 | 1 | Up to level: V2 ok. ruwe vloer | 280 | Bouwkundig | Model Group:Kollom tussenmaat 120x120 eerste verdieping:6791938
6792677 | 01 eerste verdieping | 3310 | 160 | 0.004 | 0.01324 | 0.5296 | 0.5296 | 0.01324 | 20 | 0.0000289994 | V1 bk. ruwe vloer | Up to level: V2 ok. ruwe vloer | 160 | Bouwkundig | Model Group:Kollom tussenmaat 120x120 Heel:6004935
6893024 | 00 Begane grond | 3240 | 6600.01 | 0.165 | 0.534601 | 21.384 | 21.384 | 0.534601 | 0 | 0 | 0 | Up to level: V1 ok. ruwe vloer | 6687.51 | Bouwkundig | Pset_wanden - NLRS_C_brandwerendheid: 30; Fire Protection - NLRS_C_brandwerendheid: 30
6893188 | 01 eerste verdieping | 3240 | 6600.01 | 0.165 | 0.534601 | 21.384 | 21.384 | 0.534601 | 0 | 0.0000289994 | 1 | Up to level: V2 ok. ruwe vloer | 6687.51 | Bouwkundig | Pset_wanden - NLRS_C_brandwerendheid: 30; Fire Protection - NLRS_C_brandwerendheid: 30

# IfcWallStandardCase: Basic Wall:28_DAT_ihw beton_180 (2)
In: -1 fundering
Type - PredefinedType: STANDARD; Material: ISR_Gips 1 mm, ISR_Beton ihwg 178 mm, ISR_Gips 1 mm
Type - Other - Category: Walls; Family Name: Basic Wall
Type - Construction - Function: Exterior; Wrapping at Inserts: Do not wrap; Width: 180 mm
Type - Graphics - Coarse Scale Fill Pattern: <Solid fill>; Coarse Scale Fill Color: 4210752
Type - Identity Data - Workset: Wall Types; Assembly Code: 28.21; Assembly Description: hoofddraagconstructies; wanden en vloeren, wand-/vloerconstructies; Description: Beton 180mm; Type Comments: IWG beton 180mm volgens opgave constructeur; Type Name: 28_DAT_ihw beton_180
Type - Materials and Finishes - Structural Material: ISR_Beton ihwg
Type - Analytical Properties - Roughness: 1; Absorptance: 0.1
Type - Pset_ElementShading - Roughness: 304.8 mm
Type - Pset_ProductRequirements - Category: Walls
Type - Pset_ReinforcementBarPitchOfWall - Description: Beton 180mm
Type - Pset_WallCommon - IsExternal: yes
Classification: 28.21 Uniformat (Uniformat)
BaseQuantities - Height: 188 mm; Width: 180 mm
Pset_QuantityTakeOff - Reference: 28_DAT_ihw beton_180; sets with these values: 2
Pset_WallCommon - ExtendToStructure: no; LoadBearing: no; Reference: 28_DAT_ihw beton_180
Pset_wanden - Structural Usage: Non-bearing; Omschrijving: Beton 180mm; NL-sfb-Codering: 28.21
Pset_DAT_KMS - Assembly Code: 28.21; Assembly Description: hoofddraagconstructies; wanden en vloeren, wand-/vloerconstructies; Description: Beton 180mm
Other - Family: Basic Wall; Family and Type: Basic Wall: 28_DAT_ihw beton_180; Type: 28_DAT_ihw beton_180; Type Id: 589387
Constraints - Base Offset: 0 mm; Base Extension Distance: 0 mm; Base is Attached: no; Related to Mass: no; Room Bounding: yes; Top Extension Distance: 0 mm; Top is Attached: no; Location Line: Finish Face: Exterior; Base Constraint: bk. fundering; Unconnected Height: 188 mm
Identity Data - Workset: Constructie
Phasing - Phase Created: 2. nieuwbouw
Structural - Structural Usage: Non-bearing; Structural: no
Cross-Section Definition - Cross-Section: Vertical
Name (Basic Wall:28_DAT_ihw beton_180:...) | BaseQuantities, Length (mm) | GrossFootprintArea (m2) | GrossVolume (m3) = NetVolume (m3) = Volume (m3) | GrossSideArea (m2) = NetSideArea (m2) = Area (m2) | Top Offset (mm) | Dimensions, Length (mm)
5473358 | 12120 | 2.18159 | 0.410139 | 2.27855 | -482 | 12120 | Constraints - Top Constraint: Up to level: V-1
5539354 | 8925 | 1.6065 | 0.302022 | 1.6779 | 0 | 9105

# IfcWallStandardCase: Basic Wall:28_DAT_ihw specie (12)
In: -1 fundering
Type - PredefinedType: STANDARD; Material: ISR_Speci ihwg(1) 195 mm
Type - Other - Category: Walls; Family Name: Basic Wall
Type - Construction - Function: Exterior; Wrapping at Inserts: Do not wrap; Width: 195 mm
Type - Graphics - Coarse Scale Fill Pattern: <Solid fill>; Coarse Scale Fill Color: 4210752
Type - Identity Data - Workset: Wall Types; Assembly Code: 28.21; Assembly Description: hoofddraagconstructies; wanden en vloeren, wand-/vloerconstructies; Description: Beton 250mm; Type Comments: Vullen met specie volgens opgave constructeur; Type Name: 28_DAT_ihw specie
Type - Materials and Finishes - Structural Material: ISR_Speci ihwg(1)
Type - Analytical Properties - Roughness: 1; Absorptance: 0.1
Type - Pset_ElementShading - Roughness: 304.8 mm
Type - Pset_ProductRequirements - Category: Walls
Type - Pset_ReinforcementBarPitchOfWall - Description: Beton 250mm
Type - Pset_WallCommon - IsExternal: yes
Classification: 28.21 Uniformat (Uniformat)
BaseQuantities - Height: 500 mm; Width: 195 mm
Pset_QuantityTakeOff - Reference: 28_DAT_ihw specie; sets with these values: 2
Pset_WallCommon - ExtendToStructure: no; LoadBearing: no; Reference: 28_DAT_ihw specie
Pset_wanden - Structural Usage: Non-bearing; Omschrijving: Beton 250mm; NL-sfb-Codering: 28.21
Pset_DAT_KMS - Assembly Code: 28.21; Assembly Description: hoofddraagconstructies; wanden en vloeren, wand-/vloerconstructies; Description: Beton 250mm
Other - Family: Basic Wall; Family and Type: Basic Wall: 28_DAT_ihw specie; Type: 28_DAT_ihw specie; Type Id: 589386
Constraints - Base Offset: 0 mm; Top Offset: 0 mm; Base Extension Distance: 0 mm; Base is Attached: no; Related to Mass: no; Room Bounding: yes; Top Extension Distance: 0 mm; Top is Attached: no; Location Line: Finish Face: Exterior; Base Constraint: bk. fundering; Unconnected Height: 500 mm
Identity Data - Workset: Bouwkundig
Phasing - Phase Created: 2. nieuwbouw
Structural - Structural Usage: Non-bearing; Structural: no
Cross-Section Definition - Cross-Section: Vertical
Name (Basic Wall:28_DAT_ihw specie:...) | BaseQuantities, Length (mm) | GrossFootprintArea (m2) | GrossVolume (m3) | GrossSideArea (m2) | NetSideArea (m2) = Area (m2) | NetVolume (m3) = Volume (m3) | Dimensions, Length (mm)
5539294 | 46150 | 8.99925 | 3.8257 | 19.619 | 19.619 | 3.8257 | 45955
5539295 | 47455 | 9.25373 | 4.62686 | 23.7275 | 23.7275 | 4.62686 | 47455
5539296 | 12355 | 2.40922 | 1.20461 | 6.1775 | 6.1775 | 1.20461 | 12355
5539297 | 16335 | 3.18533 | 1.59266 | 8.1675 | 8.1675 | 1.59266 | 16432.5
5539298 | 7899.96 | 1.54049 | 0.770246 | 3.94998 | 3.94998 | 0.770246 | 7802.46
5539299 | 10619.3 | 2.07076 | 1.03538 | 5.30963 | 5.30963 | 1.03538 | 10716.8
5539300 | 1396.05 | 0.27223 | 0.0190125 | 0.0975 | 0.736311 | 0.136115 | 1396.05 | Graphics - Center Mark Visible: no
5539301 | 3000 | 0.585 | 0.2925 | 1.5 | 1.5 | 0.2925 | 3000
5539302 | 960.149 | 0.187228 | 0.0190125 | 0.0975 | 0.518363 | 0.0936144 | 960.149 | Graphics - Center Mark Visible: no
5539303 | 4108.1 | 0.801079 | 0.400539 | 2.05405 | 2.05405 | 0.400539 | 4010.6
5539304 | 28800 | 5.61601 | 2.808 | 14.4 | 14.4 | 2.808 | 28800
5539305 | 11860 | 2.3127 | 1.15635 | 5.93 | 5.93 | 1.15635 | 12055

# IfcWallStandardCase: Basic Wall:28_DAT_kalkzandsteen_150mm (4)
Type - PredefinedType: STANDARD; Material: ISR_Gips 1 mm, ISR_Kalkzandsteen 148 mm, ISR_Gips 1 mm
Type - Other - Category: Walls; Family Name: Basic Wall
Type - Construction - Function: Interior; Width: 150 mm; Wrapping at Inserts: Do not wrap
Type - Graphics - Coarse Scale Fill Pattern: <Solid fill>; Coarse Scale Fill Color: 12632256
Type - Identity Data - Workset: Wall Types; Assembly Code: 28.21; Assembly Description: hoofddraagconstructies; wanden en vloeren, wand-/vloerconstructies; Cost: 0; Description: Kalkzandsteen 150mm; Fire Rating: 90 min.; Type Comments: Kalkzandsteen 150mm; Type Name: 28_DAT_kalkzandsteen_150mm
Type - Materials and Finishes - Structural Material: ISR_Kalkzandsteen
Type - Analytical Properties - Roughness: 1; Absorptance: 0.1
Type - Pset_ConcreteElementGeneral - FireRating: 90 min.
Type - Pset_ElementShading - Roughness: 304.8 mm
Type - Pset_ProductRequirements - Category: Walls
Type - Pset_ReinforcementBarPitchOfWall - Description: Kalkzandsteen 150mm
Type - Pset_WallCommon - IsExternal: no; FireRating: 90 min.
Classification: 28.21 Uniformat (Uniformat)
BaseQuantities - Height: 3240 mm; Width: 150 mm
Pset_QuantityTakeOff - Reference: 28_DAT_kalkzandsteen_150mm; sets with these values: 2
Pset_WallCommon - ExtendToStructure: no; LoadBearing: no; Reference: 28_DAT_kalkzandsteen_150mm
Pset_wanden - Structural Usage: Non-bearing; Omschrijving: Kalkzandsteen 150mm; NL-sfb-Codering: 28.21
Pset_DAT_KMS - Assembly Code: 28.21; Assembly Description: hoofddraagconstructies; wanden en vloeren, wand-/vloerconstructies; Description: Kalkzandsteen 150mm
Other - Family: Basic Wall; Family and Type: Basic Wall: 28_DAT_kalkzandsteen_150mm; Type: 28_DAT_kalkzandsteen_150mm; Type Id: 4337793
Constraints - Base Offset: 0 mm; Top Offset: 0 mm; Base Extension Distance: 0 mm; Base is Attached: no; Related to Mass: no; Room Bounding: yes; Top Extension Distance: 0 mm; Top is Attached: no; Location Line: Wall Centerline; Unconnected Height: 3240 mm
Identity Data - Workset: Constructie
Phasing - Phase Created: 2. nieuwbouw
Structural - Structural Usage: Non-bearing; Structural: no
Cross-Section Definition - Cross-Section: Vertical
Name (Basic Wall:28_DAT_kalkzandsteen_150mm:...) | In | BaseQuantities, Length (mm) | GrossFootprintArea (m2) | GrossVolume (m3) = NetVolume (m3) = Volume (m3) | GrossSideArea (m2) = NetSideArea (m2) = Area (m2) | Base Constraint | Top Constraint | Dimensions, Length (mm)
4788691 | 00 Begane grond | 6510 | 0.9765 | 2.79317 | 18.6211 | 0 | Up to level: V1 ok. ruwe vloer | 6510
4789188 | 01 eerste verdieping | 6510 | 0.9765 | 3.16386 | 21.0924 | 1 | Up to level: V2 ok. ruwe vloer | 6597.5
4789532 | 00 Begane grond | 2525 | 0.37875 | 1.22715 | 8.181 | 0 | Up to level: V1 ok. ruwe vloer | 2525 | Pset_wanden - NLRS_C_brandwerendheid: 30; Fire Protection - NLRS_C_brandwerendheid: 30
5296904 | 00 Begane grond | 1757.96 | 0.263694 | 0.580175 | 3.86783 | 0 | Up to level: V1 ok. ruwe vloer | 1757.96 | Pset_wanden - NLRS_C_brandwerendheid: 0; Fire Protection - NLRS_C_brandwerendheid: 0

# IfcWallStandardCase: Basic Wall:28_DAT_kalkzandsteen_175mm (73)
Type - PredefinedType: STANDARD; Material: ISR_Gips 1 mm, ISR_Kalkzandsteen 173 mm, ISR_Gips 1 mm
Type - Other - Category: Walls; Family Name: Basic Wall
Type - Construction - Function: Interior; Wrapping at Ends: Interior; Width: 175 mm; Wrapping at Inserts: Interior
Type - Graphics - Coarse Scale Fill Pattern: <Solid fill>; Coarse Scale Fill Color: 12632256
Type - Identity Data - Workset: Wall Types; Assembly Code: 28.21; Assembly Description: hoofddraagconstructies; wanden en vloeren, wand-/vloerconstructies; Cost: 0; Description: Kalkzandsteen 175mm; Fire Rating: 90 min.; Type Comments: Kalkzandsteen 175mm; Type Name: 28_DAT_kalkzandsteen_175mm
Type - Materials and Finishes - Structural Material: ISR_Kalkzandsteen
Type - Analytical Properties - Roughness: 1; Absorptance: 0.1
Type - Pset_ConcreteElementGeneral - FireRating: 90 min.
Type - Pset_ElementShading - Roughness: 304.8 mm
Type - Pset_ProductRequirements - Category: Walls
Type - Pset_ReinforcementBarPitchOfWall - Description: Kalkzandsteen 175mm
Type - Pset_WallCommon - IsExternal: no; FireRating: 90 min.
Classification: 28.21 Uniformat (Uniformat)
BaseQuantities - Width: 175 mm
Pset_QuantityTakeOff - Reference: 28_DAT_kalkzandsteen_175mm; sets with these values: 2
Pset_WallCommon - ExtendToStructure: no; LoadBearing: no; Reference: 28_DAT_kalkzandsteen_175mm
Pset_wanden - Structural Usage: Non-bearing; Omschrijving: Kalkzandsteen 175mm; NL-sfb-Codering: 28.21
Pset_DAT_KMS - Assembly Code: 28.21; Assembly Description: hoofddraagconstructies; wanden en vloeren, wand-/vloerconstructies; Description: Kalkzandsteen 175mm
Other - Family: Basic Wall; Family and Type: Basic Wall: 28_DAT_kalkzandsteen_175mm; Type: 28_DAT_kalkzandsteen_175mm; Type Id: 4741545
Constraints - Base Extension Distance: 0 mm; Base is Attached: no; Related to Mass: no; Room Bounding: yes; Top Extension Distance: 0 mm; Top is Attached: no
Phasing - Phase Created: 2. nieuwbouw
Structural - Structural Usage: Non-bearing; Structural: no
Cross-Section Definition - Cross-Section: Vertical
Name (Basic Wall:28_DAT_kalkzandsteen_175mm:...) | In | Height (mm) | BaseQuantities, Length (mm) | GrossFootprintArea (m2) | GrossVolume (m3) | GrossSideArea (m2) | NetSideArea (m2) | NetVolume (m3) = Volume (m3) | Base Offset (mm) | Location Line | Base Constraint | Top Constraint | Top Offset (mm) | Unconnected Height (mm) | Area (m2) | Dimensions, Length (mm) | Workset
5480987 | -1 fundering | 800 | 2195 | 0.384125 | 0.3073 | 1.756 | 1.756 | 0.3073 | 0 | Finish Face: Exterior | bk. fundering | Up to level: V0 ok. ruwe vloer | -140 | 800 | 1.756 | 2195 | Constructie
5481353 | -1 fundering | 800 | 3058.69 | 0.53527 | 0.428216 | 2.44695 | 2.44695 | 0.428216 | 0 | Finish Face: Exterior | bk. fundering | Up to level: V0 ok. ruwe vloer | -140 | 800 | 2.44695 | 2883.69 | Constructie
5481453 | -1 fundering | 800 | 505 | 0.088375 | 0.0707 | 0.404 | 0.404 | 0.0707 | 0 | Finish Face: Exterior | bk. fundering | Up to level: V0 ok. ruwe vloer | -140 | 800 | 0.404 | 680 | Constructie
5481543 | -1 fundering | 800 | 725 | 0.126875 | 0.1015 | 0.58 | 0.58 | 0.1015 | 0 | Finish Face: Exterior | bk. fundering | Up to level: V0 ok. ruwe vloer | -140 | 800 | 0.58 | 955 | Constructie
5481614 | -1 fundering | 800 | 900 | 0.1575 | 0.126 | 0.72 | 0.72 | 0.126 | 0 | Finish Face: Exterior | bk. fundering | Up to level: V0 ok. ruwe vloer | -140 | 800 | 0.72 | 900 | Constructie
5536772 | 00 Begane grond | 3310 | 28410 | 4.97175 | 16.4565 | 94.0371 | 61.9219 | 10.8363 | 0 | Wall Centerline | V0 bk. ruwe vloer | Up to level: V1 ok. ruwe vloer | 0 | 3310 | 61.9219 | 28322.5 | Constructie
5536774 | 00 Begane grond | 3310 | 545 | 0.095375 | 0.315691 | 1.80395 | 1.80395 | 0.315691 | 0 | Wall Centerline | V0 bk. ruwe vloer | Up to level: V1 ok. ruwe vloer | 0 | 3310 | 1.80395 | 457.5 | Constructie
5536776 | 00 Begane grond | 3310 | 10615.4 | 1.85769 | 6.14896 | 35.1369 | 23.8657 | 4.1765 | 0 | Wall Centerline | V0 bk. ruwe vloer | Up to level: V1 ok. ruwe vloer | 0 | 3310 | 23.8657 | 10527.9 | Constructie
5536778 | 00 Begane grond | 3310 | 4095 | 0.716625 | 2.37203 | 13.5545 | 5.13845 | 0.899229 | 0 | Wall Centerline | V0 bk. ruwe vloer | Up to level: V1 ok. ruwe vloer | 0 | 3310 | 5.13845 | 4095 | Constructie
5536781 | 00 Begane grond | 3310 | 9355 | 1.63713 | 4.99412 | 28.5379 | 10.5648 | 1.84883 | 0 | Wall Centerline | V0 bk. ruwe vloer | Up to level: V1 ok. ruwe vloer | 0 | 3310 | 10.5648 | 9267.5 | Constructie
5536785 | 01 eerste verdieping | 3330 | 3215 | 0.562625 | 1.87354 | 10.706 | 10.706 | 1.87354 | 0 | Wall Centerline | V1 bk. ruwe vloer | Up to level: V2 ok. ruwe vloer | 0 | 3330 | 10.706 | 3127.5 | Constructie
5536786 | 01 eerste verdieping | 3430 | 11975 | 2.09563 | 7.04218 | 40.2411 | 32.9071 | 5.75873 | -100 | Wall Centerline | V1 bk. ruwe vloer | Up to level: V2 ok. ruwe vloer | 0 | 3430 | 32.9071 | 11975 | Constructie
5536787 | 01 eerste verdieping | 3330 | 35400 | 6.195 | 20.6294 | 117.882 | 93.6412 | 16.3872 | 0 | Wall Centerline | V1 bk. ruwe vloer | Up to level: V2 ok. ruwe vloer | 0 | 3330 | 93.6412 | 35400 | Constructie
5536788 | 01 eerste verdieping | 3330 | 1305 | 0.228375 | 0.386724 | 2.20985 | 2.1358 | 0.373765 | 0 | Wall Centerline | V1 bk. ruwe vloer | Up to level: V2 ok. ruwe vloer | 0 | 3330 | 2.1358 | 1392.5 | Constructie
5536789 | 01 eerste verdieping | 2820 | 959 | 0.167825 | 0.208303 | 1.1903 | 1.1903 | 0.208303 | 0 | Wall Centerline | V1 bk. ruwe vloer | Up to level: V2 ok. ruwe vloer | -510 | 2820 | 1.1903 | 871.5 | Constructie
5536790 | 01 eerste verdieping | 3330 | 7200 | 1.26 | 4.1958 | 23.976 | 22.2776 | 3.89858 | 0 | Wall Centerline | V1 bk. ruwe vloer | Up to level: V2 ok. ruwe vloer | 0 | 3330 | 22.2776 | 7200 | Constructie
5536791 | 01 eerste verdieping | 900 | 2076 | 0.3633 | 0.32137 | 1.8364 | 1.8364 | 0.32137 | 0 | Wall Centerline | V1 bk. ruwe vloer | Up to level: V2 ok. ruwe vloer | -510 | 2820 | 1.8364 | 2163.5 | Constructie
5536800 | 01 eerste verdieping | 625 | 2800 | 0.49 | 0.30625 | 1.75 | 1.75 | 0.30625 | 0 | Wall Centerline | 1 |  | 0 | 625 | 1.75 | 2800 | Constructie
5536972 | 00 Begane grond | 3310 | 4239.96 | 0.741994 | 2.456 | 14.0343 | 14.0343 | 2.456 | 0 | Wall Centerline | V0 bk. ruwe vloer | Up to level: V1 ok. ruwe vloer | 0 | 3310 | 14.0343 | 4327.46 | Constructie
5538605 | 00 Begane grond | 3310 | 1246.82 | 0.218191 | 0.101369 | 0.57925 | 4.35444 | 0.722217 | 0 | Finish Face: Interior | V0 bk. ruwe vloer | Up to level: V1 ok. ruwe vloer | 0 | 3310 | 4.35444 | 1246.82 | Constructie | Graphics - Center Mark Visible: no
5538608 | 00 Begane grond | 3310 | 1109.37 | 0.194138 | 0.101369 | 0.57925 | 3.8995 | 0.642601 | 0 | Finish Face: Interior | V0 bk. ruwe vloer | Up to level: V1 ok. ruwe vloer | 0 | 3310 | 3.8995 | 1109.37 | Constructie | Graphics - Center Mark Visible: no
5538612 | 00 Begane grond | 3310 | 5015 | 0.877625 | 2.90494 | 16.5997 | 16.5997 | 2.90494 | 0 | Wall Centerline | V0 bk. ruwe vloer | Up to level: V1 ok. ruwe vloer | 0 | 3310 | 16.5997 | 4927.5 | Constructie
5538838 | 01 eerste verdieping | 3330 | 33600 | 5.88 | 19.5804 | 111.888 | 76.376 | 13.3658 | 0 | Wall Centerline | V1 bk. ruwe vloer | Up to level: V2 ok. ruwe vloer | 0 | 3330 | 76.376 | 33600 | Constructie
5539110 | 00 Begane grond | 3310 | 530 | 0.09275 | 0.307003 | 1.7543 | 1.7543 | 0.307003 | 0 | Wall Centerline | V0 bk. ruwe vloer | Up to level: V1 ok. ruwe vloer | 0 | 3310 | 1.7543 | 1220 | Constructie
5539136 | 00 Begane grond | 3310 | 2999.21 | 0.524862 | 1.73729 | 9.9274 | 6.5306 | 1.14285 | 0 | Finish Face: Interior | V0 bk. ruwe vloer | Up to level: V1 ok. ruwe vloer | 0 | 3310 | 6.5306 | 2999.21 | Constructie
5539251 | 01 eerste verdieping | 3330 | 37591 | 6.57843 | 6.82003 | 38.9716 | 38.9716 | 6.82003 | 0 | Wall Centerline | V1 bk. ruwe vloer | Up to level: V2 ok. ruwe vloer | 0 | 3330 | 38.9716 | 37671 | Constructie
5539252 | 01 eerste verdieping | 3330 | 27105 | 4.74337 | 5.10523 | 29.1727 | 29.1727 | 5.10523 | 0 | Wall Centerline | V1 bk. ruwe vloer | Up to level: V2 ok. ruwe vloer | 0 | 3330 | 29.1727 | 27105 | Bouwkundig
5539258 | 01 eerste verdieping | 3330 | 924 | 0.1617 | 0.526554 | 3.00888 | 3.00888 | 0.526554 | 0 | Wall Centerline | V1 bk. ruwe vloer | Up to level: V2 ok. ruwe vloer | 0 | 3330 | 3.00888 | 1011.5 | Constructie
5539282 | -1 fundering | 800 | 34222.5 | 5.98894 | 4.79116 | 27.378 | 27.378 | 4.79116 | 0 | Finish Face: Exterior | bk. fundering | Up to level: V0 ok. ruwe vloer | -140 | 800 | 27.378 | 34135 | Constructie
5539283 | -1 fundering | 800 | 38150 | 6.67625 | 5.341 | 30.52 | 30.52 | 5.341 | 0 | Finish Face: Exterior | bk. fundering | Up to level: V0 ok. ruwe vloer | -140 | 800 | 30.52 | 37972.5 | Constructie
5539284 | -1 fundering | 800 | 11975 | 2.09562 | 1.6765 | 9.58 | 9.58 | 1.6765 | 0 | Finish Face: Exterior | bk. fundering | Up to level: V0 ok. ruwe vloer | -140 | 800 | 9.58 | 11975 | Constructie
5539285 | -1 fundering | 800 | 16430 | 2.87525 | 2.3002 | 13.144 | 13.144 | 2.3002 | 0 | Finish Face: Exterior | bk. fundering | Up to level: V0 ok. ruwe vloer | -140 | 800 | 13.144 | 16430 | Constructie
5539286 | -1 fundering | 800 | 7799.96 | 1.36499 | 1.09199 | 6.23997 | 6.23997 | 1.09199 | 0 | Finish Face: Exterior | bk. fundering | Up to level: V0 ok. ruwe vloer | -140 | 800 | 6.23997 | 7799.96 | Constructie
5539287 | -1 fundering | 800 | 10439.3 | 1.82687 | 1.4615 | 8.35141 | 8.35141 | 1.4615 | 0 | Finish Face: Exterior | bk. fundering | Up to level: V0 ok. ruwe vloer | -140 | 800 | 8.35141 | 10526.8 | Constructie
5539288 | -1 fundering | 800 | 1246.82 | 0.218191 | 0.0245 | 0.14 | 1.05243 | 0.174554 | 0 | Finish Face: Exterior | bk. fundering | Up to level: V0 ok. ruwe vloer | -140 | 800 | 1.05243 | 1246.82 | Constructie | Graphics - Center Mark Visible: no
5539289 | -1 fundering | 800 | 3000 | 0.525 | 0.42 | 2.4 | 2.4 | 0.42 | 0 | Finish Face: Exterior | bk. fundering | Up to level: V0 ok. ruwe vloer | -140 | 800 | 2.4 | 3000 | Constructie
5539290 | -1 fundering | 800 | 1109.37 | 0.194138 | 0.0245 | 0.14 | 0.942478 | 0.155311 | 0 | Finish Face: Exterior | bk. fundering | Up to level: V0 ok. ruwe vloer | -140 | 800 | 0.942478 | 1109.37 | Constructie | Graphics - Center Mark Visible: no
5539291 | -1 fundering | 800 | 4288.1 | 0.750417 | 0.600334 | 3.43048 | 3.43048 | 0.600334 | 0 | Finish Face: Exterior | bk. fundering | Up to level: V0 ok. ruwe vloer | -140 | 800 | 3.43048 | 4200.6 | Constructie
5539292 | -1 fundering | 800 | 28800 | 5.04001 | 4.03201 | 23.04 | 23.04 | 4.03201 | 0 | Finish Face: Exterior | bk. fundering | Up to level: V0 ok. ruwe vloer | -140 | 800 | 23.04 | 28800 | Constructie
5539293 | -1 fundering | 800 | 11500 | 2.0125 | 1.61 | 9.2 | 9.2 | 1.61 | 0 | Finish Face: Exterior | bk. fundering | Up to level: V0 ok. ruwe vloer | -140 | 800 | 9.2 | 11675 | Constructie
5723334 | 00 Begane grond | 3310 | 29360 | 5.138 | 17.0068 | 97.1816 | 78.5764 | 13.7509 | 0 | Wall Centerline | V0 bk. ruwe vloer | Up to level: V1 ok. ruwe vloer | 0 | 3310 | 78.5764 | 29447.5 | Constructie
5723375 | 00 Begane grond | 3310 | 6785 | 1.18738 | 3.82015 | 21.8295 | 21.8295 | 3.82015 | 0 | Wall Centerline | V0 bk. ruwe vloer | Up to level: V1 ok. ruwe vloer | 0 | 3310 | 21.8295 | 6785 | Constructie
5748451 | 00 Begane grond | 320 | 5040 | 0.882 | 0.28224 | 1.6128 | 1.6128 | 0.28224 | 0 | Wall Centerline | V1 ok. ruwe vloer | Up to level: V1 bk. ruwe vloer | 0 | 320 | 1.6128 | 4952.5 | Constructie
5748667 | 00 Begane grond | 320 | 1250 | 0.21875 | 0.07 | 0.4 | 0.4 | 0.07 | 0 | Wall Centerline | V1 ok. ruwe vloer | Up to level: V1 bk. ruwe vloer | 0 | 320 | 0.4 | 1337.5 | Constructie
5997719 | 00 Begane grond | 3310 | 23235 | 4.06612 | 1.22609 | 7.00625 | 7.00625 | 1.19 | 0 | Wall Centerline | V0 bk. ruwe vloer | Up to level: V1 ok. ruwe vloer | 0 | 3310 | 6.8 | 23235 | Bouwkundig
5999825 | 00 Begane grond | 3310 | 6640 | 1.162 | 3.84622 | 21.9784 | 21.9784 | 3.84622 | 0 | Wall Centerline | V0 bk. ruwe vloer | Up to level: V1 ok. ruwe vloer | 0 | 3310 | 21.9784 | 6727.5 | Constructie
6000860 | 00 Begane grond | 3310 | 8820 | 1.5435 | 1.67451 | 9.5686 | 9.5686 | 1.67451 | 0 | Wall Centerline | V0 bk. ruwe vloer | Up to level: V1 ok. ruwe vloer | 0 | 3310 | 9.5686 | 8820 | Bouwkundig
6002709 | 00 Begane grond | 3310 | 550 | 0.09625 | 0.318588 | 1.8205 | 1.8205 | 0.318588 | 0 | Wall Centerline | V0 bk. ruwe vloer | Up to level: V1 ok. ruwe vloer | 0 | 3310 | 1.8205 | 550 | Constructie
6003475 | 00 Begane grond | 3310 | 2320 | 0.406 | 1.34386 | 7.6792 | 7.6792 | 1.34386 | 0 | Wall Centerline | V0 bk. ruwe vloer | Up to level: V1 ok. ruwe vloer | 0 | 3310 | 7.6792 | 2407.5 | Constructie
6004583 | 00 Begane grond | 3310 | 2440 | 0.427 | 1.41337 | 8.0764 | 8.0764 | 1.41337 | 0 | Wall Centerline | V0 bk. ruwe vloer | Up to level: V1 ok. ruwe vloer | 0 | 3310 | 8.0764 | 2527.5 | Constructie
6005228 | 01 eerste verdieping | 3330 | 10195 | 1.78413 | 5.84846 | 33.4198 | 25.5454 | 4.47044 | 0 | Wall Centerline | V1 bk. ruwe vloer | Up to level: V2 ok. ruwe vloer | 0 | 3330 | 25.5454 | 10282.5 | Constructie
6006165 | 01 eerste verdieping | 3330 | 5900 | 1.0325 | 3.36532 | 19.2304 | 15.8336 | 2.77088 | 0 | Wall Centerline | V1 bk. ruwe vloer | Up to level: V2 ok. ruwe vloer | 0 | 3330 | 15.8336 | 5812.5 | Constructie
6008619 | 00 Begane grond | 640 | 1910 | 0.33425 | 0.21392 | 1.2224 | 1.2224 | 0.21392 | -320 | Wall Centerline | V1 ok. ruwe vloer | Up to level: V1 bk. ruwe vloer | 0 | 640 | 1.2224 | 1910 | Constructie
6008778 | 00 Begane grond | 2710 | 2145 | 0.375375 | 1.01727 | 5.81295 | 5.81295 | 1.01727 | 0 | Wall Centerline | V0 bk. ruwe vloer | Up to level: V1 ok. ruwe vloer | -600 | 2710 | 5.81295 | 2145 | Constructie
6063550 | 00 Begane grond | 3650 | 600 | 0.105 | 0.38325 | 2.19 | 2.19 | 0.38325 | 0 | Wall Centerline | 0 | Up to level: 1 | 0 | 3650 | 2.19 | 600 | Constructie
6179295 | 00 Begane grond | 320 | 6572.5 | 1.15019 | 0.36806 | 2.1032 | 2.1032 | 0.36806 | 0 | Wall Centerline | V1 ok. ruwe vloer | Up to level: V1 bk. ruwe vloer | 0 | 320 | 2.1032 | 6660 | Constructie
6265115 | -1 fundering | 800 | 33120 | 5.79601 | 4.63681 | 26.496 | 26.496 | 4.63681 | 0 | Wall Centerline | bk. fundering | Up to level: V0 ok. ruwe vloer | -140 | 800 | 26.496 | 33287.5 | Constructie
6265365 | -1 fundering | 800 | 4620 | 0.8085 | 0.6468 | 3.696 | 3.696 | 0.6468 | 0 | Wall Centerline | bk. fundering | Up to level: V0 ok. ruwe vloer | -140 | 800 | 3.696 | 4707.5 | Constructie
6265525 | -1 fundering | 800 | 19078 | 3.32335 | 2.67093 | 15.2624 | 15.2624 | 2.65868 | 0 | Wall Centerline | bk. fundering | Up to level: V0 ok. ruwe vloer | -140 | 800 | 15.2624 | 19201.8 | Constructie
6266142 | -1 fundering | 800 | 6510 | 1.13925 | 0.9114 | 5.208 | 5.208 | 0.9114 | 0 | Wall Centerline | bk. fundering | Up to level: V0 ok. ruwe vloer | -140 | 800 | 5.208 | 6597.5 | Constructie
6266258 | -1 fundering | 800 | 7012.5 | 1.22719 | 0.98175 | 5.61 | 5.61 | 0.98175 | 0 | Wall Centerline | bk. fundering | Up to level: V0 ok. ruwe vloer | -140 | 800 | 5.61 | 7187.5 | Constructie
6266565 | -1 fundering | 800 | 2020 | 0.3535 | 0.2828 | 1.616 | 1.616 | 0.2828 | 0 | Finish Face: Exterior | bk. fundering | Up to level: V0 ok. ruwe vloer | -140 | 800 | 1.616 | 2195 | Constructie
6266693 | -1 fundering | 800 | 1999.19 | 0.349858 | 0.279886 | 1.59935 | 1.59935 | 0.279886 | 0 | Finish Face: Exterior | bk. fundering | Up to level: V0 ok. ruwe vloer | -140 | 800 | 1.59935 | 2226.31 | Constructie
6266973 | -1 fundering | 800 | 5311 | 0.929425 | 0.74354 | 4.2488 | 4.2488 | 0.74354 | 0 | Wall Centerline | bk. fundering | Up to level: V0 ok. ruwe vloer | -140 | 800 | 4.2488 | 5311 | Constructie
6267162 | -1 fundering | 800 | 1270 | 0.22225 | 0.1778 | 1.016 | 1.016 | 0.1778 | 0 | Wall Centerline | bk. fundering | Up to level: V0 ok. ruwe vloer | -140 | 800 | 1.016 | 1445 | Constructie
6516634 | 00 Begane grond | 780 | 3467.5 | 0.606812 | 0.451474 | 2.57985 | 2.57985 | 0.451474 | 0 | Wall Centerline | V0 bk. ruwe vloer |  | 0 | 780 | 2.57985 | 3467.5 | Constructie
6516999 | 00 Begane grond | 780 | 2130 | 0.37275 | 0.290745 | 1.6614 | 1.6614 | 0.290745 | 0 | Wall Centerline | V0 bk. ruwe vloer |  | 0 | 780 | 1.6614 | 2130 | Constructie
6661868 | 00 Begane grond | 3650 | 550 | 0.09625 | 0.351313 | 2.0075 | 2.0075 | 0.351313 | 0 | Wall Centerline | 0 | Up to level: 1 | 0 | 3650 | 2.0075 | 550 | Bouwkundig
6788664 | 00 Begane grond | 1405 | 789.999 | 0.13825 | 0.194241 | 1.10995 | 1.10995 | 0.194241 | 0 | Wall Centerline | V0 bk. ruwe vloer |  | 0 | 1425 | 1.10995 | 789.999 | Bouwkundig
6788756 | 00 Begane grond | 2030 | 789.999 | 0.13825 | 0.280647 | 1.6037 | 1.6037 | 0.280647 | 0 | Wall Centerline | V0 bk. ruwe vloer |  | 0 | 2050 | 1.6037 | 789.999 | Bouwkundig
6788801 | 00 Begane grond | 2655 | 789.999 | 0.13825 | 0.367053 | 2.09745 | 2.09745 | 0.367053 | 0 | Wall Centerline | V0 bk. ruwe vloer |  | 0 | 2675 | 2.09745 | 789.999 | Bouwkundig
6788809 | 00 Begane grond | 3280 | 789.999 | 0.13825 | 0.453459 | 2.5912 | 2.5912 | 0.453459 | 0 | Wall Centerline | V0 bk. ruwe vloer |  | 0 | 3300 | 2.5912 | 789.999 | Bouwkundig
6788819 | 00 Begane grond | 3905 | 789.999 | 0.13825 | 0.539866 | 3.08495 | 3.08495 | 0.539866 | 0 | Wall Centerline | V0 bk. ruwe vloer |  | 0 | 3925 | 3.08495 | 789.999 | Bouwkundig

# IfcWallStandardCase: Basic Wall:28_DAT_kalkzandsteen_214mm (4)
Type - PredefinedType: STANDARD; Material: ISR_Gips 1 mm, ISR_Kalkzandsteen 212 mm, ISR_Gips 1 mm
Type - Other - Category: Walls; Family Name: Basic Wall
Type - Construction - Wrapping at Ends: Exterior; Wrapping at Inserts: Both; Function: Interior; Width: 214 mm
Type - Graphics - Coarse Scale Fill Pattern: <Solid fill>; Coarse Scale Fill Color: 12632256
Type - Identity Data - Workset: Wall Types; Assembly Code: 28.21; Assembly Description: hoofddraagconstructies; wanden en vloeren, wand-/vloerconstructies; Cost: 0; Description: Kalkzandsteen 214mm; Fire Rating: 90 min.; Type Name: 28_DAT_kalkzandsteen_214mm
Type - Materials and Finishes - Structural Material: ISR_Kalkzandsteen
Type - Analytical Properties - Roughness: 1; Absorptance: 0.1
Type - Pset_ConcreteElementGeneral - FireRating: 90 min.
Type - Pset_ElementShading - Roughness: 304.8 mm
Type - Pset_ProductRequirements - Category: Walls
Type - Pset_ReinforcementBarPitchOfWall - Description: Kalkzandsteen 214mm
Type - Pset_WallCommon - IsExternal: no; FireRating: 90 min.
Classification: 28.21 Uniformat (Uniformat)
BaseQuantities - Width: 214 mm
Pset_QuantityTakeOff - Reference: 28_DAT_kalkzandsteen_214mm; sets with these values: 2
Pset_WallCommon - ExtendToStructure: no; LoadBearing: no; Reference: 28_DAT_kalkzandsteen_214mm
Pset_wanden - Structural Usage: Non-bearing; Omschrijving: Kalkzandsteen 214mm; NL-sfb-Codering: 28.21
Pset_DAT_KMS - Assembly Code: 28.21; Assembly Description: hoofddraagconstructies; wanden en vloeren, wand-/vloerconstructies; Description: Kalkzandsteen 214mm
Other - Family: Basic Wall; Family and Type: Basic Wall: 28_DAT_kalkzandsteen_214mm; Type: 28_DAT_kalkzandsteen_214mm; Type Id: 4337865
Constraints - Base Offset: 0 mm; Base Extension Distance: 0 mm; Base is Attached: no; Related to Mass: no; Room Bounding: yes; Top Extension Distance: 0 mm; Top is Attached: no; Location Line: Wall Centerline
Phasing - Phase Created: 2. nieuwbouw
Structural - Structural Usage: Non-bearing; Structural: no
Cross-Section Definition - Cross-Section: Vertical
Name (Basic Wall:28_DAT_kalkzandsteen_214mm:...) | In | Height (mm) = Unconnected Height (mm) | BaseQuantities, Length (mm) = Dimensions, Length (mm) | GrossFootprintArea (m2) | GrossVolume (m3) = NetVolume (m3) = Volume (m3) | GrossSideArea (m2) = NetSideArea (m2) = Area (m2) | Top Offset (mm) | Base Constraint | Top Constraint | Workset
4772470 | 00 Begane grond | 3240 | 1645 | 0.35203 | 1.14058 | 5.3298 | 0 | 0 | Up to level: V1 ok. ruwe vloer | Constructie
4772539 | 01 eerste verdieping | 3180 | 1862.63 | 0.398602 | 1.26755 | 5.92315 | -60 | 1 | Up to level: V2 ok. ruwe vloer | Constructie
5482032 | -1 Speelvloer | 600 | 1645 | 0.35203 | 0.211218 | 0.987 | 0 | V-1 | Up to level: 0 | Bouwkundig
5483040 | -1 Speelvloer | 600 | 1645 | 0.35203 | 0.211218 | 0.987 | 0 | V-1 | Up to level: 0 | Bouwkundig

# IfcWallStandardCase: Basic Wall:43_DAT_Wandtegelwerk (64)
Type - PredefinedType: STANDARD; Material: ISR_Tegels_grijs_150x150 10 mm
Type - Other - Category: Walls; Family Name: Basic Wall
Type - Construction - Function: Interior; Wrapping at Inserts: Do not wrap; Width: 10 mm
Type - Graphics - Coarse Scale Fill Pattern: <Solid fill>; Coarse Scale Fill Color: 4210752
Type - Identity Data - Workset: Wall Types; Assembly Code: 42.12; Assembly Description: binnenwandafwerkingen; bekledingen; Description: Wandtegelwerk; Type Comments: Tegelwand; Type Name: 43_DAT_Wandtegelwerk
Type - Materials and Finishes - Structural Material: ISR_Tegels_grijs_150x150
Type - Analytical Properties - Roughness: 1; Absorptance: 0.1
Type - Pset_ElementShading - Roughness: 304.8 mm
Type - Pset_ProductRequirements - Category: Walls
Type - Pset_ReinforcementBarPitchOfWall - Description: Wandtegelwerk
Type - Pset_WallCommon - IsExternal: no
Classification: 42.12 Uniformat (Uniformat)
BaseQuantities - Width: 10 mm
Pset_QuantityTakeOff - Reference: 43_DAT_Wandtegelwerk; sets with these values: 2
Pset_WallCommon - ExtendToStructure: no; LoadBearing: no; Reference: 43_DAT_Wandtegelwerk
Pset_wanden - Structural Usage: Non-bearing; Omschrijving: Wandtegelwerk; NL-sfb-Codering: 42.12; sets with these values: 2
Pset_DAT_KMS - Assembly Code: 42.12; Assembly Description: binnenwandafwerkingen; bekledingen; Description: Wandtegelwerk
Other - Family: Basic Wall; Family and Type: Basic Wall: 43_DAT_Wandtegelwerk; Type: 43_DAT_Wandtegelwerk; Type Id: 4669376
Constraints - Base Offset: 0 mm; Base Extension Distance: 0 mm; Base is Attached: no; Related to Mass: no; Top Extension Distance: 0 mm; Top is Attached: no; Location Line: Wall Centerline
Identity Data - Workset: Bouwkundig
Phasing - Phase Created: 2. nieuwbouw
Structural - Structural Usage: Non-bearing; Structural: no
Cross-Section Definition - Cross-Section: Vertical
Name (Basic Wall:43_DAT_Wandtegelwerk:...) | In | Height (mm) = Unconnected Height (mm) | BaseQuantities, Length (mm) | GrossFootprintArea (m2) | GrossVolume (m3) | GrossSideArea (m2) | NetSideArea (m2) = Area (m2) | NetVolume (m3) = Volume (m3) | Top Offset (mm) | Room Bounding | Base Constraint | Dimensions, Length (mm) | Top Constraint
5948892 | 00 Begane grond | 1400 | 750 | 0.0075 | 0.0105 | 1.05 | 1.05 | 0.0105 | 0 | yes | 0 | 750
5949348 | 00 Begane grond | 2450 | 2435 | 0.02435 | 0.0349449 | 3.49449 | 3.49449 | 0.0349449 | 50 | yes | 0 | 2435 | Up to level: V0 ok. plafond | Group: Model Group:WC_V0:4976980
5949423 | 00 Begane grond | 2450 | 1650 | 0.0165 | 0.040425 | 4.0425 | 4.0425 | 0.040425 | 50 | yes | 0 | 1650 | Up to level: V0 ok. plafond | Group: Model Group:WC_V0:4976980
5949479 | 00 Begane grond | 2450 | 2435 | 0.02435 | 0.0596575 | 5.96575 | 5.25175 | 0.0525175 | 50 | yes | 0 | 2435 | Up to level: V0 ok. plafond | Group: Model Group:WC_V0:4976980
5949537 | 00 Begane grond | 2450 | 1650 | 0.0165 | 0.040425 | 4.0425 | 4.0425 | 0.040425 | 50 | yes | 0 | 1650 | Up to level: V0 ok. plafond | Group: Model Group:WC_V0:4976980
5949988 | 00 Begane grond | 2450 | 2435 | 0.02435 | 0.0349449 | 3.49449 | 3.49449 | 0.0349449 | 50 | yes | 0 | 2435 | Up to level: V0 ok. plafond | Group: Model Group:WC_V0:4977293
5949989 | 00 Begane grond | 2450 | 1650 | 0.0165 | 0.040425 | 4.0425 | 4.0425 | 0.040425 | 50 | yes | 0 | 1650 | Up to level: V0 ok. plafond | Group: Model Group:WC_V0:4977293
5949990 | 00 Begane grond | 2450 | 2435 | 0.02435 | 0.0596575 | 5.96575 | 5.25175 | 0.0525175 | 50 | yes | 0 | 2435 | Up to level: V0 ok. plafond | Group: Model Group:WC_V0:4977293
5949991 | 00 Begane grond | 2450 | 1650 | 0.0165 | 0.040425 | 4.0425 | 4.0425 | 0.040425 | 50 | yes | 0 | 1650 | Up to level: V0 ok. plafond | Group: Model Group:WC_V0:4977293
5949995 | 00 Begane grond | 2450 | 2435 | 0.02435 | 0.0349449 | 3.49449 | 3.49449 | 0.0349449 | 50 | yes | 0 | 2435 | Up to level: V0 ok. plafond | Group: Model Group:WC_V0:4977398
5949996 | 00 Begane grond | 2450 | 1650 | 0.0165 | 0.040425 | 4.0425 | 4.0425 | 0.040425 | 50 | yes | 0 | 1650 | Up to level: V0 ok. plafond | Group: Model Group:WC_V0:4977398
5949997 | 00 Begane grond | 2450 | 2435 | 0.02435 | 0.0596575 | 5.96575 | 5.25175 | 0.0525175 | 50 | yes | 0 | 2435 | Up to level: V0 ok. plafond | Group: Model Group:WC_V0:4977398
5949998 | 00 Begane grond | 2450 | 1650 | 0.0165 | 0.040425 | 4.0425 | 4.0425 | 0.040425 | 50 | yes | 0 | 1650 | Up to level: V0 ok. plafond | Group: Model Group:WC_V0:4977398
5950002 | 01 eerste verdieping | 2450 | 2435 | 0.02435 | 0.0349449 | 3.49449 | 3.49449 | 0.0349449 | 50 | yes | 1 | 2435 | Up to level: V1 ok. plafond | Group: Model Group:WC_V0:5035649
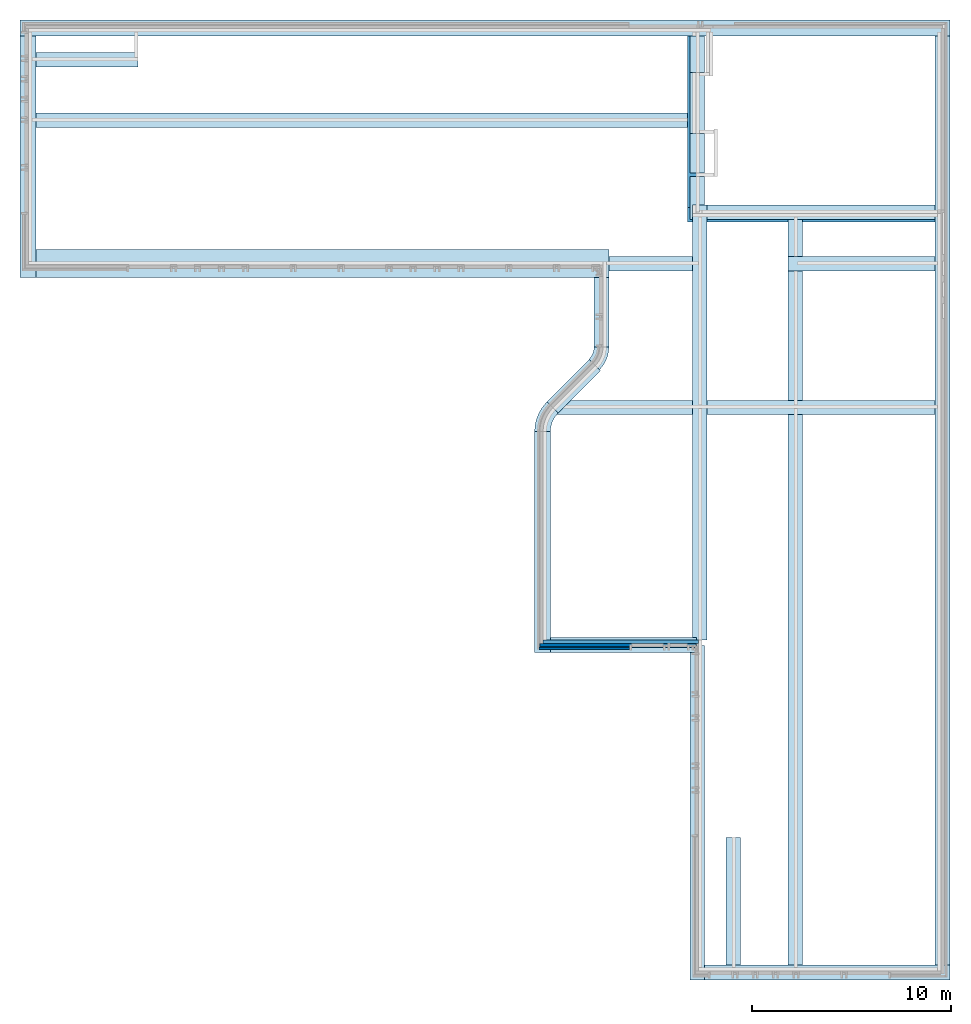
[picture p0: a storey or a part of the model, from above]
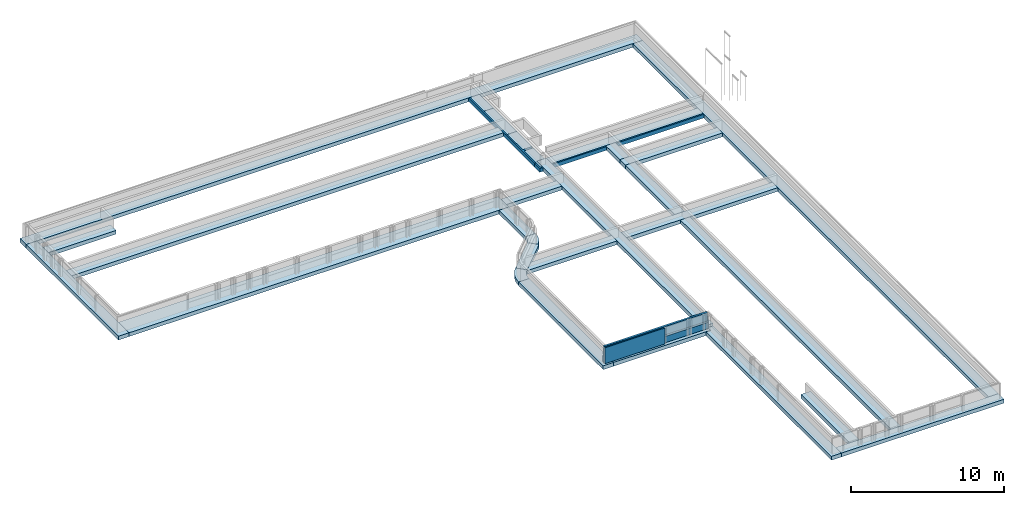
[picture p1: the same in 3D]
Properties of the parts of a building model (IFC2X3), part 35 of 37

# IfcWallStandardCase: Basic Wall:43_DAT_Wandtegelwerk (64)
Name (Basic Wall:43_DAT_Wandtegelwerk:...) | In | Height (mm) = Unconnected Height (mm) | BaseQuantities, Length (mm) | GrossFootprintArea (m2) | GrossVolume (m3) | GrossSideArea (m2) | NetSideArea (m2) = Area (m2) | NetVolume (m3) = Volume (m3) | Top Offset (mm) | Room Bounding | Base Constraint | Dimensions, Length (mm) | Top Constraint
5950003 | 01 eerste verdieping | 2450 | 1650 | 0.0165 | 0.040425 | 4.0425 | 4.0425 | 0.040425 | 50 | yes | 1 | 1650 | Up to level: V1 ok. plafond | Group: Model Group:WC_V0:5035649
5950004 | 01 eerste verdieping | 2450 | 2435 | 0.02435 | 0.0596575 | 5.96575 | 5.25175 | 0.0525175 | 50 | yes | 1 | 2435 | Up to level: V1 ok. plafond | Group: Model Group:WC_V0:5035649
5950005 | 01 eerste verdieping | 2450 | 1650 | 0.0165 | 0.040425 | 4.0425 | 4.0425 | 0.040425 | 50 | yes | 1 | 1650 | Up to level: V1 ok. plafond | Group: Model Group:WC_V0:5035649
5950009 | 01 eerste verdieping | 2450 | 2435 | 0.02435 | 0.0349449 | 3.49449 | 3.49449 | 0.0349449 | 50 | yes | 1 | 2435 | Up to level: V1 ok. plafond | Group: Model Group:WC_V0:5035659
5950010 | 01 eerste verdieping | 2450 | 1650 | 0.0165 | 0.040425 | 4.0425 | 4.0425 | 0.040425 | 50 | yes | 1 | 1650 | Up to level: V1 ok. plafond | Group: Model Group:WC_V0:5035659
5950011 | 01 eerste verdieping | 2450 | 2435 | 0.02435 | 0.0596575 | 5.96575 | 5.25175 | 0.0525175 | 50 | yes | 1 | 2435 | Up to level: V1 ok. plafond | Group: Model Group:WC_V0:5035659
5950012 | 01 eerste verdieping | 2450 | 1650 | 0.0165 | 0.040425 | 4.0425 | 4.0425 | 0.040425 | 50 | yes | 1 | 1650 | Up to level: V1 ok. plafond | Group: Model Group:WC_V0:5035659
5950523 | 00 Begane grond | 2450 | 1071 | 0.01071 | 0.0262395 | 2.62395 | 2.62395 | 0.0262395 | 50 | no | 0 | 1076 | Up to level: V0 ok. plafond
5950612 | 00 Begane grond | 2450 | 1081 | 0.01081 | 0.0264845 | 2.64845 | 2.64845 | 0.0264845 | 50 | no | 0 | 1143.5 | Up to level: V0 ok. plafond
5950715 | 00 Begane grond | 2450 | 1195 | 0.01195 | 0.0292775 | 2.92775 | 2.92775 | 0.0292775 | 50 | no | 0 | 1185 | Up to level: V0 ok. plafond
5950758 | 00 Begane grond | 2450 | 910 | 0.0091 | 0.022295 | 2.2295 | 2.2295 | 0.022295 | 50 | no | 0 | 910 | Up to level: V0 ok. plafond
5950802 | 00 Begane grond | 2450 | 1185 | 0.01185 | 0.0043199 | 0.43199 | 0.43199 | 0.0043199 | 50 | no | 0 | 1185 | Up to level: V0 ok. plafond
5950843 | 00 Begane grond | 2450 | 900 | 0.009 | 0.02205 | 2.205 | 2.205 | 0.02205 | 50 | no | 0 | 910 | Up to level: V0 ok. plafond
5951307 | 00 Begane grond | 2450 | 1020 | 0.0102 | 0.02499 | 2.499 | 2.499 | 0.02499 | 50 | yes | 0 | 1015 | Up to level: V0 ok. plafond
5951365 | 00 Begane grond | 2450 | 1405 | 0.01405 | 0.0344225 | 3.44225 | 3.44225 | 0.0344225 | 50 | yes | 0 | 1405 | Up to level: V0 ok. plafond
5951431 | 00 Begane grond | 2450 | 345 | 0.00345 | 0.0084525 | 0.84525 | 0.84525 | 0.0084525 | 50 | yes | 0 | 345 | Up to level: V0 ok. plafond
5951462 | 00 Begane grond | 2450 | 135 | 0.00135 | 0.0033075 | 0.33075 | 0.33075 | 0.0033075 | 50 | yes | 0 | 135 | Up to level: V0 ok. plafond
5951509 | 00 Begane grond | 2450 | 1050 | 0.0105 | 0.025725 | 2.5725 | 2.5725 | 0.025725 | 50 | yes | 0 | 1050 | Up to level: V0 ok. plafond
5951539 | 00 Begane grond | 2450 | 2075 | 0.02075 | 0.0508375 | 5.08375 | 5.08375 | 0.0508375 | 50 | yes | 0 | 2075 | Up to level: V0 ok. plafond
5951626 | 00 Begane grond | 2450 | 1715 | 0.01715 | 0.0173049 | 1.73049 | 1.73049 | 0.0173049 | 50 | yes | 0 | 1720 | Up to level: V0 ok. plafond
5951854 | 00 Begane grond | 2450 | 1740 | 0.0174 | 0.04263 | 4.263 | 4.263 | 0.04263 | 50 | yes | 0 | 1735 | Up to level: V0 ok. plafond
5951917 | 00 Begane grond | 2450 | 3615 | 0.03615 | 0.0885675 | 8.85675 | 8.85675 | 0.0885675 | 50 | yes | 0 | 3615 | Up to level: V0 ok. plafond
5951969 | 00 Begane grond | 2450 | 1730 | 0.0173 | 0.042385 | 4.2385 | 4.2385 | 0.042385 | 50 | yes | 0 | 1735 | Up to level: V0 ok. plafond
5952163 | 00 Begane grond | 2450 | 2065 | 0.02065 | 0.0258799 | 2.58799 | 2.58799 | 0.0258799 | 50 | yes | 0 | 2060 | Up to level: V0 ok. plafond
5952168 | 00 Begane grond | 2450 | 1639.88 | 0.0163988 | 0.0401769 | 4.01769 | 4.01769 | 0.0401769 | 50 | yes | 0 | 1629.88 | Up to level: V0 ok. plafond
5952169 | 00 Begane grond | 2450 | 1830 | 0.0183 | 0.0201224 | 2.01224 | 2.01224 | 0.0201224 | 50 | yes | 0 | 1835 | Up to level: V0 ok. plafond
5952170 | 00 Begane grond | 2450 | 1740 | 0.0174 | 0.03549 | 3.549 | 3.549 | 0.03549 | 50 | yes | 0 | 1735 | Up to level: V0 ok. plafond
5952171 | 00 Begane grond | 2450 | 3610 | 0.0361 | 0.088445 | 8.8445 | 8.8445 | 0.088445 | 50 | yes | 0 | 3610 | Up to level: V0 ok. plafond
5952172 | 00 Begane grond | 2450 | 1730 | 0.0173 | 0.035364 | 3.5364 | 3.5364 | 0.035364 | 50 | yes | 0 | 1735 | Up to level: V0 ok. plafond
5952321 | 00 Begane grond | 2450 | 1985.12 | 0.0198512 | 0.0486356 | 4.86356 | 4.86356 | 0.0486356 | 50 | yes | 0 | 1985.12 | Up to level: V0 ok. plafond
5952357 | 00 Begane grond | 2450 | 215 | 0.00215 | 0.0052675 | 0.52675 | 0.52675 | 0.0052675 | 50 | yes | 0 | 225 | Up to level: V0 ok. plafond
5952507 | 00 Begane grond | 2450 | 1970 | 0.0197 | 0.021975 | 2.1975 | 2.1975 | 0.021975 | 50 | yes | 0 | 1960 | Up to level: V0 ok. plafond
5952575 | 00 Begane grond | 2450 | 2230 | 0.0223 | 0.054635 | 5.4635 | 5.4635 | 0.054635 | 50 | yes | 0 | 2230 | Up to level: V0 ok. plafond
5952621 | 00 Begane grond | 2450 | 1960 | 0.0196 | 0.04802 | 4.802 | 4.802 | 0.04802 | 50 | yes | 0 | 1960 | Up to level: V0 ok. plafond
5952663 | 00 Begane grond | 2450 | 2220 | 0.0222 | 0.05439 | 5.439 | 5.439 | 0.05439 | 50 | yes | 0 | 2230 | Up to level: V0 ok. plafond
5952787 | 01 eerste verdieping | 2450 | 2335 | 0.02335 | 0.0572075 | 5.72075 | 5.00675 | 0.0500675 | 50 | yes | 1 | 2325 | Up to level: V1 ok. plafond
5952830 | 01 eerste verdieping | 2450 | 1650 | 0.0165 | 0.040425 | 4.0425 | 3.9925 | 0.039925 | 50 | yes | 1 | 1650 | Up to level: V1 ok. plafond
5952858 | 01 eerste verdieping | 2450 | 2315 | 0.02315 | 0.0320049 | 3.20049 | 3.20049 | 0.0320049 | 50 | yes | 1 | 2325 | Up to level: V1 ok. plafond
5953113 | 01 eerste verdieping | 1400 | 750 | 0.0075 | 0.0105 | 1.05 | 1.05 | 0.0105 | 0 | yes | 1 | 750
5953353 | 01 eerste verdieping | 2450 | 1405.13 | 0.0140513 | 0.0344256 | 3.44256 | 3.44256 | 0.0344256 | 50 | yes | 1 | 1405.13 | Up to level: V1 ok. plafond
5953395 | 01 eerste verdieping | 2450 | 1049 | 0.01049 | 0.0257005 | 2.57005 | 2.57005 | 0.0257005 | 50 | yes | 1 | 1054 | Up to level: V1 ok. plafond
5953476 | 01 eerste verdieping | 2450 | 1059 | 0.01059 | 0.0012329 | 0.12329 | 0.12329 | 0.0012329 | 50 | yes | 1 | 1054 | Up to level: V1 ok. plafond
5994605 | 01 eerste verdieping | 2450 | 1650 | 0.0165 | 0.040425 | 4.0425 | 4.0425 | 0.040425 | 50 | yes | 1 | 1650 | Up to level: V1 ok. plafond
5994944 | 01 eerste verdieping | 2450 | 2435 | 0.02435 | 0.0349449 | 3.49449 | 3.49449 | 0.0349449 | 50 | yes | 1 | 2435 | Up to level: V1 ok. plafond | Group: Model Group:WC_V0:5994912
5994945 | 01 eerste verdieping | 2450 | 1650 | 0.0165 | 0.040425 | 4.0425 | 4.0425 | 0.040425 | 50 | yes | 1 | 1650 | Up to level: V1 ok. plafond | Group: Model Group:WC_V0:5994912
5994946 | 01 eerste verdieping | 2450 | 2435 | 0.02435 | 0.0596575 | 5.96575 | 5.25175 | 0.0525175 | 50 | yes | 1 | 2435 | Up to level: V1 ok. plafond | Group: Model Group:WC_V0:5994912
5994947 | 01 eerste verdieping | 2450 | 1650 | 0.0165 | 0.040425 | 4.0425 | 4.0425 | 0.040425 | 50 | yes | 1 | 1650 | Up to level: V1 ok. plafond | Group: Model Group:WC_V0:5994912
6141531 | 01 eerste verdieping | 2450 | 1620.13 | 0.0162013 | 0.0396931 | 3.96931 | 3.96931 | 0.0396931 | 50 | yes | 1 | 1620.13 | Up to level: V1 ok. plafond
6522728 | 00 Begane grond | 2450 | 1880 | 0.0188 | 0.0213474 | 2.13474 | 2.13474 | 0.0213474 | 50 | no | 0 | 1880 | Up to level: V0 ok. plafond
6522729 | 00 Begane grond | 2450 | 1880 | 0.0188 | 0.04606 | 4.606 | 4.606 | 0.04606 | 50 | no | 0 | 1880 | Up to level: V0 ok. plafond

# IfcWallStandardCase: Basic Wall:43_DAT_sanitairewand (47)
Type - PredefinedType: STANDARD; Material: ISR_Kunststof_grijs 25 mm
Type - Other - Category: Walls; Family Name: Basic Wall
Type - Construction - Function: Interior; Wrapping at Inserts: Do not wrap; Width: 25 mm
Type - Graphics - Coarse Scale Fill Pattern: <Solid fill>; Coarse Scale Fill Color: 12632256
Type - Identity Data - Workset: Wall Types; Assembly Code: 22.13; Assembly Description: binnenwanden; niet constructief, systeemwanden; vast; Description: Sanitaire scheidingswand; Type Name: 43_DAT_sanitairewand
Type - Materials and Finishes - Structural Material: ISR_Kunststof_grijs
Type - Analytical Properties - Roughness: 1; Absorptance: 0.1
Type - Pset_ElementShading - Roughness: 304.8 mm
Type - Pset_ProductRequirements - Category: Walls
Type - Pset_ReinforcementBarPitchOfWall - Description: Sanitaire scheidingswand
Type - Pset_WallCommon - IsExternal: no
Classification: 22.13 Uniformat (Uniformat)
BaseQuantities - Height: 2000 mm; Width: 25 mm
Pset_QuantityTakeOff - Reference: 43_DAT_sanitairewand; sets with these values: 2
Pset_WallCommon - ExtendToStructure: no; LoadBearing: no; Reference: 43_DAT_sanitairewand
Pset_wanden - Structural Usage: Non-bearing; Omschrijving: Sanitaire scheidingswand; NL-sfb-Codering: 22.13
Pset_DAT_KMS - Assembly Code: 22.13; Assembly Description: binnenwanden; niet constructief, systeemwanden; vast; Description: Sanitaire scheidingswand
Other - Family: Basic Wall; Family and Type: Basic Wall: 43_DAT_sanitairewand; Type: 43_DAT_sanitairewand; Type Id: 4977424
Constraints - Top Offset: 0 mm; Base Extension Distance: 0 mm; Base is Attached: no; Related to Mass: no; Room Bounding: yes; Top Extension Distance: 0 mm; Top is Attached: no; Base Offset: 150 mm; Location Line: Finish Face: Exterior; Unconnected Height: 2000 mm
Identity Data - Workset: Bouwkundig
Phasing - Phase Created: 2. nieuwbouw
Structural - Structural Usage: Non-bearing; Structural: no
Cross-Section Definition - Cross-Section: Vertical
Name (Basic Wall:43_DAT_sanitairewand:...) | In | BaseQuantities, Length (mm) | GrossFootprintArea (m2) | GrossVolume (m3) = NetVolume (m3) = Volume (m3) | GrossSideArea (m2) = NetSideArea (m2) = Area (m2) | Base Constraint | Dimensions, Length (mm) | Group
4977531 | 00 Begane grond | 975 | 0.024375 | 0.04875 | 1.95 | 0 | 975 | Model Group:WC_V0:4976980
4977534 | 00 Begane grond | 600 | 0.015 | 0.03 | 1.2 | 0 | 600 | Model Group:WC_V0:4976980
4977535 | 00 Begane grond | 300 | 0.0075 | 0.015 | 0.6 | 0 | 300 | Model Group:WC_V0:4976980
4977536 | 00 Begane grond | 80 | 0.002 | 0.004 | 0.16 | 0 | 80 | Model Group:WC_V0:4976980
4977537 | 00 Begane grond | 600 | 0.015 | 0.03 | 1.2 | 0 | 600 | Model Group:WC_V0:4976980
4977538 | 00 Begane grond | 80 | 0.002 | 0.004 | 0.16 | 0 | 80 | Model Group:WC_V0:4976980
4977710 | 00 Begane grond | 975 | 0.024375 | 0.04875 | 1.95 | 0 | 975 | Model Group:WC_V0:4977293
4977713 | 00 Begane grond | 600 | 0.015 | 0.03 | 1.2 | 0 | 600 | Model Group:WC_V0:4977293
4977714 | 00 Begane grond | 300 | 0.0075 | 0.015 | 0.6 | 0 | 300 | Model Group:WC_V0:4977293
4977715 | 00 Begane grond | 80 | 0.002 | 0.004 | 0.16 | 0 | 80 | Model Group:WC_V0:4977293
4977716 | 00 Begane grond | 600 | 0.015 | 0.03 | 1.2 | 0 | 600 | Model Group:WC_V0:4977293
4977717 | 00 Begane grond | 80 | 0.002 | 0.004 | 0.16 | 0 | 80 | Model Group:WC_V0:4977293
4977721 | 00 Begane grond | 975 | 0.024375 | 0.04875 | 1.95 | 0 | 975 | Model Group:WC_V0:4977398
4977724 | 00 Begane grond | 600 | 0.015 | 0.03 | 1.2 | 0 | 600 | Model Group:WC_V0:4977398
4977725 | 00 Begane grond | 300 | 0.0075 | 0.015 | 0.6 | 0 | 300 | Model Group:WC_V0:4977398
4977726 | 00 Begane grond | 80 | 0.002 | 0.004 | 0.16 | 0 | 80 | Model Group:WC_V0:4977398
4977727 | 00 Begane grond | 600 | 0.015 | 0.03 | 1.2 | 0 | 600 | Model Group:WC_V0:4977398
4977728 | 00 Begane grond | 80 | 0.002 | 0.004 | 0.16 | 0 | 80 | Model Group:WC_V0:4977398
5035662 | 01 eerste verdieping | 975 | 0.024375 | 0.04875 | 1.95 | 1 | 975 | Model Group:WC_V0:5035649
5035665 | 01 eerste verdieping | 600 | 0.015 | 0.03 | 1.2 | 1 | 600 | Model Group:WC_V0:5035649
5035666 | 01 eerste verdieping | 300 | 0.0075 | 0.015 | 0.6 | 1 | 300 | Model Group:WC_V0:5035649
5035667 | 01 eerste verdieping | 80 | 0.002 | 0.004 | 0.16 | 1 | 80 | Model Group:WC_V0:5035649
5035668 | 01 eerste verdieping | 600 | 0.015 | 0.03 | 1.2 | 1 | 600 | Model Group:WC_V0:5035649
5035669 | 01 eerste verdieping | 80 | 0.002 | 0.004 | 0.16 | 1 | 80 | Model Group:WC_V0:5035649
5035680 | 01 eerste verdieping | 975 | 0.024375 | 0.04875 | 1.95 | 1 | 975 | Model Group:WC_V0:5035659
5035683 | 01 eerste verdieping | 600 | 0.015 | 0.03 | 1.2 | 1 | 600 | Model Group:WC_V0:5035659
5035684 | 01 eerste verdieping | 300 | 0.0075 | 0.015 | 0.6 | 1 | 300 | Model Group:WC_V0:5035659
5035685 | 01 eerste verdieping | 80 | 0.002 | 0.004 | 0.16 | 1 | 80 | Model Group:WC_V0:5035659
5035686 | 01 eerste verdieping | 600 | 0.015 | 0.03 | 1.2 | 1 | 600 | Model Group:WC_V0:5035659
5035687 | 01 eerste verdieping | 80 | 0.002 | 0.004 | 0.16 | 1 | 80 | Model Group:WC_V0:5035659
5132788 | 00 Begane grond | 770.434 | 0.0192609 | 0.0385217 | 1.54087 | 0 | 770.434
5135448 | 00 Begane grond | 1035 | 0.025875 | 0.05175 | 2.07 | 0 | 1047.5
5174540 | 01 eerste verdieping | 975 | 0.024375 | 0.04875 | 1.95 | 1 | 975
5174543 | 01 eerste verdieping | 600 | 0.015 | 0.03 | 1.2 | 1 | 600
5174544 | 01 eerste verdieping | 300 | 0.0075 | 0.015 | 0.6 | 1 | 300
5174545 | 01 eerste verdieping | 80 | 0.002 | 0.004 | 0.16 | 1 | 80
5174546 | 01 eerste verdieping | 600 | 0.015 | 0.03 | 1.2 | 1 | 600
5174547 | 01 eerste verdieping | 80 | 0.002 | 0.004 | 0.16 | 1 | 80
5994915 | 01 eerste verdieping | 975 | 0.024375 | 0.04875 | 1.95 | 1 | 975 | Model Group:WC_V0:5994912
5994918 | 01 eerste verdieping | 600 | 0.015 | 0.03 | 1.2 | 1 | 600 | Model Group:WC_V0:5994912
5994919 | 01 eerste verdieping | 300 | 0.0075 | 0.015 | 0.6 | 1 | 300 | Model Group:WC_V0:5994912
5994920 | 01 eerste verdieping | 80 | 0.002 | 0.004 | 0.16 | 1 | 80 | Model Group:WC_V0:5994912
5994921 | 01 eerste verdieping | 600 | 0.015 | 0.03 | 1.2 | 1 | 600 | Model Group:WC_V0:5994912
5994922 | 01 eerste verdieping | 80 | 0.002 | 0.004 | 0.16 | 1 | 80 | Model Group:WC_V0:5994912
6598611 | 00 Begane grond | 142.5 | 0.0035625 | 0.007125 | 0.285 | 0 | 142.5
6598612 | 00 Begane grond | 182.5 | 0.0045625 | 0.009125 | 0.365 | 0 | 170
6598613 | 00 Begane grond | 600 | 0.015 | 0.03 | 1.2 | 0 | 600

# IfcWindow: 30_DAT_GMRB_Gorter dakluik:RHT7090, 30_DAT_GMRB_Gorter dakluik:RHT7090:6317996
In: 01 eerste verdieping
Type - ParameterTakesPrecedence: no; Sizeable: no; Material: Gorter_Material 1, ISR_Kozijn, Gorter_Material 2
Type - Other - Category: Windows; dubbel: no; enkel: yes; Family Name: 30_DAT_GMRB_Gorter dakluik; Weight (kg): 38
Type - Dimensions - A: 700 mm; B: 900 mm; Height: 900 mm; Rough Height: 900 mm; Rough Width: 700 mm; Width: 700 mm
Type - Identity Data - Assembly Code: 37.22.28; Belastbaarheid: 1050 kg/m2; Bestendigheid tegen sneeuwbelasting: 405 kg/m²; Bestendigheid tegen windbelasting: 3000 Pa; Constructiesterkte: ± 3000 Pa; Description: Dakluik; Geluidwerendheid: 27 dB; Hard body impact test (EN 356): Class P5A; Isolatiewaarde deksel: Rc = 4,52 (m2.K)W; U = 0,221 W/(m2.K); Isolatiewaarde opstand: Rc = 4,41 (m2.K)W; U = 0,227 W/(m2.K); Luchtdichtheid: 0,5 m3/hm1; Manufacturer: Gorter; Model: RHT; Soft body impact test (EN 13049): Class 5; Type Comments: Dakluik 700x900 met schaartrap; Type Mark: 1236; Type Name: RHT7090; URL: http://www.gortergroup.com/nl-nederlands/producten/dakluiken.html; Wind- en waterdichtheid: 650 Pa; Workset: Family : Windows : 30_DAT_GMRB_Gorter dakluik
Type - Materials and Finishes - Hatch Material: Gorter_Material 1; Oppervlaktebehandeling binnenzijde: Gepoedercoat RAL9010; Oppervlaktebehandeling buitenzijde: Gepoedercoat RAL7047
Type - Analytical Properties - Define Thermal Properties by: Schematic Type; Analytic Construction: <None>
Type - Pset_ManufacturerTypeInformation - Manufacturer: Gorter
Type - Pset_ProductRequirements - Category: Windows
Type - Pset_WindowCommon - IsExternal: no
Type - Pset_Window - Kozijnmerk: 1236
OverallHeight: 1180 mm; OverallWidth: 2729.53 mm; Classification: 37.22.28 Uniformat (Uniformat)
Pset_QuantityTakeOff - Reference: RHT7090
Pset_WindowCommon - IsExternal: yes; Reference: RHT7090
Pset_Window - Omschrijving: Dakluik; NL-sfb-Codering: 37.22.28
Pset_DAT_KMS - Assembly Code: 37.22.28; Description: Dakluik
BaseQuantities - Height: 900 mm; Width: 700 mm; Area: 0.63 m2
Other - Family: 30_DAT_GMRB_Gorter dakluik; Family and Type: 30_DAT_GMRB_Gorter dakluik: RHT7090; Host Id: 5088902; Type: RHT7090; Type Id: 6317958
Constraints - Moves With Nearby Elements: no; Level: 2
Dimensions - Area: 2.93761 m2; Offset to structural layer: 100 mm; Volume: 0.15583 m3
Identity Data - Workset: Bouwkundig; Mark: 3505
Phasing - Phase Created: 2. nieuwbouw

# IfcWindow: 31_WI_raam_1:GEALAN KUBUS RAAM (45)
Type - ParameterTakesPrecedence: no; Sizeable: no; Material: ISR_Aluminium
Type - Other - Category: Windows; Family Name: 31_WI_raam_1
Type - Constraints - offset: -18 mm; offset_bovenkant: 64 mm; offset_links: 64 mm; offset_onderkant: 64 mm; offset_rechts: 64 mm
Type - Dimensions - SillStacks: 0; Frame: 64 mm; Head: 64 mm; Sill: 64 mm; Thickness: 81 mm
Type - Identity Data - Assembly Code: 31.2; Description: raam met 1 subvak; Manufacturer: ITANNEX; Model: 10-07-2014; Type Comments: ramen; Type Mark: 1235; Type Name: GEALAN KUBUS RAAM; URL: www.bimvoorfabrikanten.nl; Workset: Family : Windows : 31_WI_raam_1
Type - Analytical Properties - Define Thermal Properties by: Schematic Type; Analytic Construction: <None>
Type - Pset_ManufacturerTypeInformation - Manufacturer: ITANNEX
Type - Pset_ProductRequirements - Category: Windows
Type - Pset_WindowCommon - IsExternal: no
Type - Pset_Window - Kozijnmerk: 1235
Classification: 31 Uniformat (Uniformat)
Pset_QuantityTakeOff - Reference: GEALAN KUBUS RAAM
Pset_WindowCommon - Reference: GEALAN KUBUS RAAM
Pset_Window - paneel_exterieur_materiaal: ISR_Aluminium; paneel_interieur_materiaal: ISR_Aluminium; Omschrijving: raam met 1 subvak; NL-sfb-Codering: 31.2
Pset_DAT_KMS - Assembly Code: 31.2; Description: raam met 1 subvak
Other - offset_b: 0 mm; SillStacksCalc: 2; Family: 31_WI_raam_1; Family and Type: 31_WI_raam_1: GEALAN KUBUS RAAM; offset_a: 18 mm; offset_bovenkant_a: 64 mm; offset_bovenkant_b: 128 mm; offset_links_a: 64 mm; offset_links_b: 128 mm; offset_onderkant_a: 64 mm; offset_onderkant_b: 128 mm; offset_rechts_a: 64 mm; offset_rechts_b: 128 mm; Type: GEALAN KUBUS RAAM; Type Id: 5587782
Model Properties - subpaneel_a1_roedes_hor: 0; subpaneel_a1_roedes_ver: 0; diepte_offset: 0 mm; subpaneel_a1_type: WI_subvak : glas 2
Identity Data - Workset: Bouwkundig
Materials and Finishes - paneel_exterieur_materiaal: ISR_Aluminium; paneel_interieur_materiaal: ISR_Aluminium
Phasing - Phase Created: 2. nieuwbouw
Name (31_WI_raam_1:GEALAN KUBUS RAAM:...) | In | OverallHeight (mm) | OverallWidth (mm) = netto_breedte (mm) | BaseQuantities, Height (mm) = HeightReport (mm) = subpaneel_1_hoogte (mm) = Dimensions, Height (mm) | BaseQuantities, Width (mm) = subpaneel_a_breedte (mm) = WidthReport (mm) = Dimensions, Width (mm) | BaseQuantities, Area (m2) = subpaneel_a1_oppervlakte (m2) = Dimensions, Area (m2) | Host Id | draairichting_a_type | Level | netto_hoogte (mm) | paneel_oppervlakte (m2) | Volume (m3) | Mark | Group
5537504 | 00 Begane grond | 2104 | 1484 | 1960 | 1356 | 2.65776 | 5537503 | BI draai-val links1 : BI draai-val links | 0 | 2088 | 0.440832 | 0.00531552 | 3630 | Model Group:Merk K07:5537502 | Pset_WindowCommon - IsExternal: yes
5537726 | 00 Begane grond | 2104 | 1484 | 1960 | 1356 | 2.65776 | 5537725 | BI draai-val links1 : BI draai-val links | 0 | 2088 | 0.440832 | 0.00531552 | 3655 | Model Group:Merk K07:5537724
5537741 | 01 eerste verdieping | 1854 | 718 | 1710 | 590 | 1.0089 | 5537740 | BI draai-val links1 : BI draai-val links | 1 | 1838 | 0.310784 | 0.0020178 | 3657 | Model Group:Merk K30:5537739
5549594 | 01 eerste verdieping | 1854 | 1434 | 1710 | 1306 | 2.23326 | 5537991 | BI draai-val rechts | 1 | 1838 | 0.402432 | 0.00446652 | 3666 | Model Group:Merk K22:5537990
5548595 | 01 eerste verdieping | 1854 | 1434 | 1710 | 1306 | 2.23326 | 5537999 | BI draai-val rechts | 1 | 1838 | 0.402432 | 0.00446652 | 3900 | Model Group:Merk K22:5537998
5549603 | 01 eerste verdieping | 1854 | 1434 | 1710 | 1306 | 2.23326 | 5538007 | BI draai-val rechts | 1 | 1838 | 0.402432 | 0.00446652 | 3674 | Model Group:Merk K22:5538006
5549612 | 01 eerste verdieping | 1854 | 1434 | 1710 | 1306 | 2.23326 | 5538015 | BI draai-val rechts | 1 | 1838 | 0.402432 | 0.00446652 | 3682 | Model Group:Merk K22:5538014
5549621 | 01 eerste verdieping | 1854 | 1434 | 1710 | 1306 | 2.23326 | 5538023 | BI draai-val rechts | 1 | 1838 | 0.402432 | 0.00446652 | 3690 | Model Group:Merk K22:5538022
5549630 | 01 eerste verdieping | 1854 | 1434 | 1710 | 1306 | 2.23326 | 5538031 | BI draai-val rechts | 1 | 1838 | 0.402432 | 0.00446652 | 3748 | Model Group:Merk K22:5538030
5549639 | 01 eerste verdieping | 1854 | 1434 | 1710 | 1306 | 2.23326 | 5538039 | BI draai-val rechts | 1 | 1838 | 0.402432 | 0.00446652 | 3772 | Model Group:Merk K22:5538038
5549648 | 01 eerste verdieping | 1854 | 1434 | 1710 | 1306 | 2.23326 | 5538047 | BI draai-val rechts | 1 | 1838 | 0.402432 | 0.00446652 | 3776 | Model Group:Merk K22:5538046
5549657 | 01 eerste verdieping | 1854 | 1434 | 1710 | 1306 | 2.23326 | 5538055 | BI draai-val rechts | 1 | 1838 | 0.402432 | 0.00446652 | 3780 | Model Group:Merk K22:5538054
5549666 | 01 eerste verdieping | 1854 | 1434 | 1710 | 1306 | 2.23326 | 5538063 | BI draai-val rechts | 1 | 1838 | 0.402432 | 0.00446652 | 3784 | Model Group:Merk K22:5538062
5549675 | 01 eerste verdieping | 1854 | 1434 | 1710 | 1306 | 2.23326 | 5538071 | BI draai-val rechts | 1 | 1838 | 0.402432 | 0.00446652 | 3788 | Model Group:Merk K22:5538070
5549684 | 01 eerste verdieping | 1854 | 1434 | 1710 | 1306 | 2.23326 | 5538079 | BI draai-val rechts | 1 | 1838 | 0.402432 | 0.00446652 | 3792 | Model Group:Merk K22:5538078
5549693 | 01 eerste verdieping | 1854 | 1434 | 1710 | 1306 | 2.23326 | 5538087 | BI draai-val rechts | 1 | 1838 | 0.402432 | 0.00446652 | 3796 | Model Group:Merk K22:5538086
5542018 | 00 Begane grond | 1854 | 1134 | 1710 | 1006 | 1.72026 | 5542011 | BI draai-val rechts | 0 | 1838 | 0.364032 | 0.00344052 | 3972 | Model Group:Merk K17:5540560
5542295 | 00 Begane grond | 1854 | 1134 | 1710 | 1006 | 1.72026 | 5542288 | BI draai-val rechts | 0 | 1838 | 0.364032 | 0.00344052 | 3978 | Model Group:Merk K17:5542284
5542321 | 00 Begane grond | 1854 | 1134 | 1710 | 1006 | 1.72026 | 5542314 | BI draai-val rechts | 0 | 1838 | 0.364032 | 0.00344052 | 3984 | Model Group:Merk K17:5542310
5542347 | 00 Begane grond | 1854 | 1134 | 1710 | 1006 | 1.72026 | 5542340 | BI draai-val rechts | 0 | 1838 | 0.364032 | 0.00344052 | 3990 | Model Group:Merk K17:5542336
5542373 | 00 Begane grond | 1854 | 1134 | 1710 | 1006 | 1.72026 | 5542366 | BI draai-val rechts | 0 | 1838 | 0.364032 | 0.00344052 | 3996 | Model Group:Merk K17:5542362
5542399 | 00 Begane grond | 1854 | 1134 | 1710 | 1006 | 1.72026 | 5542392 | BI draai-val rechts | 0 | 1838 | 0.364032 | 0.00344052 | 4002 | Model Group:Merk K17:5542388
5544305 | 00 Begane grond | 1854 | 1134 | 1710 | 1006 | 1.72026 | 5544298 | BI draai-val rechts | 0 | 1838 | 0.364032 | 0.00344052 | 4046 | Model Group:Merk K17:5544294
5544983 | 00 Begane grond | 1854 | 1134 | 1710 | 1006 | 1.72026 | 5544976 | BI draai-val rechts | 0 | 1838 | 0.364032 | 0.00344052 | 4078 | Model Group:Merk K17:5544972
5545018 | 00 Begane grond | 1854 | 1134 | 1710 | 1006 | 1.72026 | 5545011 | BI draai-val rechts | 0 | 1838 | 0.364032 | 0.00344052 | 4084 | Model Group:Merk K17:5545007
5855997 | 00 Begane grond | 1854 | 1134 | 1710 | 1006 | 1.72026 | 5855990 | BI draai-val rechts | 0 | 1838 | 0.364032 | 0.00344052 | 1041 | Model Group:Merk K17:5855989
5856038 | 00 Begane grond | 1854 | 1134 | 1710 | 1006 | 1.72026 | 5856031 | BI draai-val rechts | 0 | 1838 | 0.364032 | 0.00344052 | 1077 | Model Group:Merk K17:5856030
6065220 | 01 eerste verdieping | 1854 | 1134 | 1710 | 1006 | 1.72026 | 6065213 | BI draai-val rechts | 1 | 1838 | 0.364032 | 0.00344052 | 810 | Model Group:Merk K24:6065197
6065251 | 01 eerste verdieping | 1854 | 1134 | 1710 | 1006 | 1.72026 | 6065244 | BI draai-val rechts | 1 | 1838 | 0.364032 | 0.00344052 | 1128 | Model Group:Merk K24:6065228
6065282 | 01 eerste verdieping | 1854 | 1134 | 1710 | 1006 | 1.72026 | 6065275 | BI draai-val rechts | 1 | 1838 | 0.364032 | 0.00344052 | 1133 | Model Group:Merk K24:6065259
6065313 | 01 eerste verdieping | 1854 | 1134 | 1710 | 1006 | 1.72026 | 6065306 | BI draai-val rechts | 1 | 1838 | 0.364032 | 0.00344052 | 1138 | Model Group:Merk K24:6065290
6065344 | 01 eerste verdieping | 1854 | 1134 | 1710 | 1006 | 1.72026 | 6065337 | BI draai-val rechts | 1 | 1838 | 0.364032 | 0.00344052 | 1143 | Model Group:Merk K24:6065321
6065375 | 01 eerste verdieping | 1854 | 1134 | 1710 | 1006 | 1.72026 | 6065368 | BI draai-val rechts | 1 | 1838 | 0.364032 | 0.00344052 | 1148 | Model Group:Merk K24:6065352
6065406 | 01 eerste verdieping | 1854 | 1134 | 1710 | 1006 | 1.72026 | 6065399 | BI draai-val rechts | 1 | 1838 | 0.364032 | 0.00344052 | 1153 | Model Group:Merk K24:6065383
6065437 | 01 eerste verdieping | 1854 | 1134 | 1710 | 1006 | 1.72026 | 6065430 | BI draai-val rechts | 1 | 1838 | 0.364032 | 0.00344052 | 1158 | Model Group:Merk K24:6065414
6065468 | 01 eerste verdieping | 1854 | 1134 | 1710 | 1006 | 1.72026 | 6065461 | BI draai-val rechts | 1 | 1838 | 0.364032 | 0.00344052 | 1163 | Model Group:Merk K24:6065445
6065499 | 01 eerste verdieping | 1854 | 1134 | 1710 | 1006 | 1.72026 | 6065492 | BI draai-val rechts | 1 | 1838 | 0.364032 | 0.00344052 | 1168 | Model Group:Merk K24:6065476
6065530 | 01 eerste verdieping | 1854 | 1134 | 1710 | 1006 | 1.72026 | 6065523 | BI draai-val rechts | 1 | 1838 | 0.364032 | 0.00344052 | 1173 | Model Group:Merk K24:6065507
6065561 | 01 eerste verdieping | 1854 | 1134 | 1710 | 1006 | 1.72026 | 6065554 | BI draai-val rechts | 1 | 1838 | 0.364032 | 0.00344052 | 1178 | Model Group:Merk K24:6065538
6065592 | 01 eerste verdieping | 1854 | 1134 | 1710 | 1006 | 1.72026 | 6065585 | BI draai-val rechts | 1 | 1838 | 0.364032 | 0.00344052 | 1183 | Model Group:Merk K24:6065569
6315731 | 01 eerste verdieping | 1854 | 808 | 1710 | 680 | 1.1628 | 6315730 | BI draai-val links1 : BI draai-val links | 1 | 1838 | 0.322304 | 0.0023256 | 3469 | Model Group:Merk K31:6065001
6315974 | 01 eerste verdieping | 1854 | 808 | 1710 | 680 | 1.1628 | 6315973 | BI draai-val links1 : BI draai-val links | 1 | 1838 | 0.322304 | 0.0023256 | 3487 | Model Group:Merk K31:6065058
6322835 | 01 eerste verdieping | 1854 | 808 | 1710 | 680 | 1.1628 | 6322834 | BI draai-val links1 : BI draai-val links | 1 | 1838 | 0.322304 | 0.0023256 | 3506 | Model Group:Merk K31:6322821
6322866 | 01 eerste verdieping | 1854 | 808 | 1710 | 680 | 1.1628 | 6322865 | BI draai-val links1 : BI draai-val links | 1 | 1838 | 0.322304 | 0.0023256 | 3553 | Model Group:Merk K31:6322854
6474577 | 00 Begane grond | 1854 | 808 | 1710 | 680 | 1.1628 | 6474576 | BI draai-val links1 : BI draai-val links | V0 bk. ruwe vloer | 1838 | 0.322304 | 0.0023256 | 656 | Model Group:Merk K31:6474575

# IfcWindow: BI deur links:BI deur links (3)
In: 00 Begane grond
Type - ParameterTakesPrecedence: no; Sizeable: no; Material: Clearance Zones
Type - Other - Category: Windows; 3D_draairichting_draai_hoek: 90 deg; Family Name: BI deur links
Type - Constraints - Default Elevation: 1219.2 mm
Type - Dimensions - Offset_projectie_draairichting_bu: 0 mm
Type - Graphics - Elevation Symbol: yes; FloorPlan Symbol_15gr: no; FloorPlan Symbol_90gr: yes
Type - Identity Data - Assembly Code: 31.31; Assembly Description: buitenwandopeningen; gevuld met deuren, draaideuren; Description: binnendraaiende deur links; Manufacturer: ITANNEX; Model: 04-11-2013; Type Comments: draarichting; Type Name: BI deur links; URL: www.bimvoorfabrikanten.nl; Workset: Family : Windows : BI deur links
Type - Analytical Properties - Define Thermal Properties by: Schematic Type; Analytic Construction: <None>
Type - Pset_ManufacturerTypeInformation - Manufacturer: ITANNEX
Type - Pset_ProductRequirements - Category: Windows
Type - Pset_WindowCommon - IsExternal: no
Classification: 31.31 Uniformat (Uniformat)
Pset_QuantityTakeOff - Reference: BI deur links
Pset_WindowCommon - Reference: BI deur links
Pset_Window - Omschrijving: binnendraaiende deur links; NL-sfb-Codering: 31.31
Pset_DAT_KMS - Assembly Code: 31.31; Assembly Description: buitenwandopeningen; gevuld met deuren, draaideuren; Description: binnendraaiende deur links
Other - Family: BI deur links; Family and Type: BI deur links: BI deur links; Type: BI deur links; Type Id: 4285679
Constraints - Level: 0; Moves With Nearby Elements: no
Dimensions - Rough Height: 0 mm; Rough Width: 0 mm
Phasing - Phase Created: 2. nieuwbouw
Visibility - 3D_draairichting: yes
Name (BI deur links:BI deur links:...) | OverallHeight (mm) | OverallWidth (mm) = BaseQuantities, Width (mm) = Dimensions, Width (mm) | BaseQuantities, Height (mm) = Dimensions, Height (mm) | BaseQuantities, Area (m2) | Offset from Host (mm) | Host | Dimensions, Area (m2) | Thickness (mm) | Volume (m3) | Workset | Mark
5537556 | 1355 | 1039 | 2618 | 2.7201 | 0 | Curtain Wall : K_15 | 5.7043 | 86 | 2.21966 | Bouwkundig | 3639 | Group: Model Group:Merk K15:5537536
6486326 | 1701 | 1417 | 2389 | 3.38521 | 2572.75 | Sloped Glazing : berging luik | 7.6212 | 54 | 3.76764 | situatie | 3560
6486328 | 1701 | 1417 | 2389 | 3.38521 | 2572.75 | Sloped Glazing : berging luik | 7.6212 | 54 | 3.76764 | situatie | 3561

# IfcWindow: BI deur rechts:BI deur rechts (2)
Type - ParameterTakesPrecedence: no; Sizeable: no; Material: Clearance Zones
Type - Other - Category: Windows; 3D_draairichting_draai_hoek: 90 deg; Family Name: BI deur rechts
Type - Constraints - Default Elevation: 1219.2 mm
Type - Dimensions - Offset_projectie_draairichting_bu: 0 mm
Type - Graphics - Elevation Symbol: yes; FloorPlan Symbol_15gr: no; FloorPlan Symbol_90gr: yes
Type - Identity Data - Assembly Code: 31.31; Assembly Description: buitenwandopeningen; gevuld met deuren, draaideuren; Description: binnendraaiende deur rechts; Manufacturer: ITANNEX; Model: 04-11-2013; Type Comments: draarichting; Type Name: BI deur rechts; URL: www.bimvoorfabrikanten.nl; Workset: Family : Windows : BI deur rechts
Type - Analytical Properties - Define Thermal Properties by: Schematic Type; Analytic Construction: <None>
Type - Pset_ManufacturerTypeInformation - Manufacturer: ITANNEX
Type - Pset_ProductRequirements - Category: Windows
Type - Pset_WindowCommon - IsExternal: no
Classification: 31.31 Uniformat (Uniformat)
Pset_QuantityTakeOff - Reference: BI deur rechts
Pset_WindowCommon - Reference: BI deur rechts
Pset_Window - Omschrijving: binnendraaiende deur rechts; NL-sfb-Codering: 31.31
Pset_DAT_KMS - Assembly Code: 31.31; Assembly Description: buitenwandopeningen; gevuld met deuren, draaideuren; Description: binnendraaiende deur rechts
Other - Family: BI deur rechts; Family and Type: BI deur rechts: BI deur rechts; Type: BI deur rechts; Type Id: 4285680
Constraints - Moves With Nearby Elements: no
Dimensions - Rough Height: 0 mm; Rough Width: 0 mm
Identity Data - Workset: Bouwkundig
Phasing - Phase Created: 2. nieuwbouw
Visibility - 3D_draairichting: yes
Name (BI deur rechts:BI deur rechts:...) | In | OverallHeight (mm) | OverallWidth (mm) = BaseQuantities, Width (mm) = Dimensions, Width (mm) | BaseQuantities, Height (mm) = Dimensions, Height (mm) | BaseQuantities, Area (m2) | Level | Host | Offset from Host (mm) | Dimensions, Area (m2) | Thickness (mm) | Volume (m3) | Mark | Group
5194928 | 01 eerste verdieping | 1180.25 | 896.25 | 2303 | 2.06406 | 1 | Curtain Wall : Merk H12 | 20 | 4.31604 | 54 | 1.4529 | 3398 | Model Group:H12:5194912
5537554 | 00 Begane grond | 1281 | 965 | 2618 | 2.52637 | 0 | Curtain Wall : K_15 | 0 | 5.24193 | 86 | 1.91473 | 3637 | Model Group:Merk K15:5537536

# IfcWindow: BI draai-val rechts:BI draai-val rechts (37)
Type - ParameterTakesPrecedence: no; Sizeable: no; Material: Clearance Zones
Type - Other - Category: Windows; 3D_draairichting_draai_hoek: 90 deg; 3D_draairichting_val_hoek: 15 deg; Family Name: BI draai-val rechts
Type - Constraints - Default Elevation: 1219.2 mm
Type - Dimensions - Offset_projectie_draairichting_bu: 0 mm
Type - Graphics - Elevation Symbol: yes; FloorPlan Symbol: yes
Type - Identity Data - Assembly Code: 31.22; Assembly Description: buitenwandopeningen; gevuld met ramen, ramen draaiend aan een kant; Description: draai-val rechts; Manufacturer: ITANNEX; Model: 04-11-2013; Type Comments: draarichting; Type Name: BI draai-val rechts; URL: www.bimvoorfabrikanten.nl; Workset: Family : Windows : BI draai-val rechts
Type - Analytical Properties - Define Thermal Properties by: Schematic Type; Analytic Construction: <None>
Type - Pset_ManufacturerTypeInformation - Manufacturer: ITANNEX
Type - Pset_ProductRequirements - Category: Windows
Type - Pset_WindowCommon - IsExternal: no
Classification: 31.22 Uniformat (Uniformat)
Pset_QuantityTakeOff - Reference: BI draai-val rechts
Pset_WindowCommon - Reference: BI draai-val rechts
Pset_Window - Omschrijving: draai-val rechts; NL-sfb-Codering: 31.22
Pset_DAT_KMS - Assembly Code: 31.22; Assembly Description: buitenwandopeningen; gevuld met ramen, ramen draaiend aan een kant; Description: draai-val rechts
BaseQuantities - Height: 1838 mm
Other - Family: BI draai-val rechts; Family and Type: BI draai-val rechts: BI draai-val rechts; Type: BI draai-val rechts; Type Id: 4285682
Constraints - Moves With Nearby Elements: no; Offset from Host: -64 mm
Dimensions - Rough Height: 0 mm; Rough Width: 0 mm; Height: 1838 mm; Thickness: 81 mm
Identity Data - Workset: Bouwkundig
Phasing - Phase Created: 2. nieuwbouw
Visibility - 3D_draairichting: yes
Name (BI draai-val rechts:BI draai-val rechts:...) | In | OverallHeight (mm) | OverallWidth (mm) = BaseQuantities, Width (mm) = Dimensions, Width (mm) | BaseQuantities, Area (m2) | Level | Host | Dimensions, Area (m2) | Volume (m3) | Mark | Group
5608096 | 00 Begane grond | 1215 | 1134 | 2.08429 | 0 | Curtain Wall : K_17 | 7.53061 | 2.35777 | 4119 | Model Group:Merk K17:5544294
5608284 | 00 Begane grond | 1215 | 1134 | 2.08429 | 0 | Curtain Wall : K_17 | 7.53061 | 2.35777 | 3974 | Model Group:Merk K17:5540560
5608292 | 00 Begane grond | 1215 | 1134 | 2.08429 | 0 | Curtain Wall : K_17 | 7.53061 | 2.35777 | 3980 | Model Group:Merk K17:5542284
5608296 | 00 Begane grond | 1215 | 1134 | 2.08429 | 0 | Curtain Wall : K_17 | 7.53061 | 2.35777 | 3986 | Model Group:Merk K17:5542310
5608300 | 00 Begane grond | 1215 | 1134 | 2.08429 | 0 | Curtain Wall : K_17 | 7.53061 | 2.35777 | 3992 | Model Group:Merk K17:5542336
5608304 | 00 Begane grond | 1215 | 1134 | 2.08429 | 0 | Curtain Wall : K_17 | 7.53061 | 2.35777 | 3998 | Model Group:Merk K17:5542362
5608308 | 00 Begane grond | 1215 | 1134 | 2.08429 | 0 | Curtain Wall : K_17 | 7.53061 | 2.35777 | 4004 | Model Group:Merk K17:5542388
5608320 | 00 Begane grond | 1215 | 1134 | 2.08429 | 0 | Curtain Wall : K_17 | 7.53061 | 2.35777 | 4080 | Model Group:Merk K17:5544972
5608324 | 00 Begane grond | 1215 | 1134 | 2.08429 | 0 | Curtain Wall : K_17 | 7.53061 | 2.35777 | 4086 | Model Group:Merk K17:5545007
5610035 | 01 eerste verdieping | 1515 | 1434 | 2.63569 | 1 | Curtain Wall : K_22 | 9.74378 | 3.60251 | 933 | Model Group:Merk K22:5538022
5610510 | 01 eerste verdieping | 1515 | 1434 | 2.63569 | 1 | Curtain Wall : K_22 | 9.74378 | 3.60251 | 3670 | Model Group:Merk K22:5537990
5610514 | 01 eerste verdieping | 1515 | 1434 | 2.63569 | 1 | Curtain Wall : K_22 | 9.74378 | 3.60251 | 3902 | Model Group:Merk K22:5537998
5610518 | 01 eerste verdieping | 1515 | 1434 | 2.63569 | 1 | Curtain Wall : K_22 | 9.74378 | 3.60251 | 3678 | Model Group:Merk K22:5538006
5610522 | 01 eerste verdieping | 1515 | 1434 | 2.63569 | 1 | Curtain Wall : K_22 | 9.74378 | 3.60251 | 3686 | Model Group:Merk K22:5538014
5610526 | 01 eerste verdieping | 1515 | 1434 | 2.63569 | 1 | Curtain Wall : K_22 | 9.74378 | 3.60251 | 3750 | Model Group:Merk K22:5538030
5610530 | 01 eerste verdieping | 1515 | 1434 | 2.63569 | 1 | Curtain Wall : K_22 | 9.74378 | 3.60251 | 3774 | Model Group:Merk K22:5538038
5610534 | 01 eerste verdieping | 1515 | 1434 | 2.63569 | 1 | Curtain Wall : K_22 | 9.74378 | 3.60251 | 3778 | Model Group:Merk K22:5538046
5610538 | 01 eerste verdieping | 1515 | 1434 | 2.63569 | 1 | Curtain Wall : K_22 | 9.74378 | 3.60251 | 3782 | Model Group:Merk K22:5538054
5610542 | 01 eerste verdieping | 1515 | 1434 | 2.63569 | 1 | Curtain Wall : K_22 | 9.74378 | 3.60251 | 3786 | Model Group:Merk K22:5538062
5610546 | 01 eerste verdieping | 1515 | 1434 | 2.63569 | 1 | Curtain Wall : K_22 | 9.74378 | 3.60251 | 3790 | Model Group:Merk K22:5538070
5610550 | 01 eerste verdieping | 1515 | 1434 | 2.63569 | 1 | Curtain Wall : K_22 | 9.74378 | 3.60251 | 3794 | Model Group:Merk K22:5538078
5610554 | 01 eerste verdieping | 1515 | 1434 | 2.63569 | 1 | Curtain Wall : K_22 | 9.74378 | 3.60251 | 3798 | Model Group:Merk K22:5538086
5856018 | 00 Begane grond | 1215 | 1134 | 2.08429 | 0 | Curtain Wall : K_17 | 7.53061 | 2.35777 | 1071 | Model Group:Merk K17:5855989
5856043 | 00 Begane grond | 1215 | 1134 | 2.08429 | 0 | Curtain Wall : K_17 | 7.53061 | 2.35777 | 1082 | Model Group:Merk K17:5856030
6065225 | 00 Begane grond | 1215 | 1134 | 2.08429 | V1 ok. ruwe vloer | Curtain Wall : K_24 | 7.53061 | 2.35777 | 1096 | Model Group:Merk K24:6065197
6065256 | 00 Begane grond | 1215 | 1134 | 2.08429 | V1 ok. ruwe vloer | Curtain Wall : K_24 | 7.53061 | 2.35777 | 1130 | Model Group:Merk K24:6065228
6065287 | 00 Begane grond | 1215 | 1134 | 2.08429 | V1 ok. ruwe vloer | Curtain Wall : K_24 | 7.53061 | 2.35777 | 1135 | Model Group:Merk K24:6065259
6065318 | 00 Begane grond | 1215 | 1134 | 2.08429 | V1 ok. ruwe vloer | Curtain Wall : K_24 | 7.53061 | 2.35777 | 1140 | Model Group:Merk K24:6065290
6065349 | 00 Begane grond | 1215 | 1134 | 2.08429 | V1 ok. ruwe vloer | Curtain Wall : K_24 | 7.53061 | 2.35777 | 1145 | Model Group:Merk K24:6065321
6065380 | 00 Begane grond | 1215 | 1134 | 2.08429 | V1 ok. ruwe vloer | Curtain Wall : K_24 | 7.53061 | 2.35777 | 1150 | Model Group:Merk K24:6065352
6065411 | 00 Begane grond | 1215 | 1134 | 2.08429 | V1 ok. ruwe vloer | Curtain Wall : K_24 | 7.53061 | 2.35777 | 1155 | Model Group:Merk K24:6065383
6065442 | 00 Begane grond | 1215 | 1134 | 2.08429 | V1 ok. ruwe vloer | Curtain Wall : K_24 | 7.53061 | 2.35777 | 1160 | Model Group:Merk K24:6065414
6065473 | 00 Begane grond | 1215 | 1134 | 2.08429 | V1 ok. ruwe vloer | Curtain Wall : K_24 | 7.53061 | 2.35777 | 1165 | Model Group:Merk K24:6065445
6065504 | 00 Begane grond | 1215 | 1134 | 2.08429 | V1 ok. ruwe vloer | Curtain Wall : K_24 | 7.53061 | 2.35777 | 1170 | Model Group:Merk K24:6065476
6065535 | 00 Begane grond | 1215 | 1134 | 2.08429 | V1 ok. ruwe vloer | Curtain Wall : K_24 | 7.53061 | 2.35777 | 1175 | Model Group:Merk K24:6065507
6065566 | 00 Begane grond | 1215 | 1134 | 2.08429 | V1 ok. ruwe vloer | Curtain Wall : K_24 | 7.53061 | 2.35777 | 1180 | Model Group:Merk K24:6065538
6065597 | 00 Begane grond | 1215 | 1134 | 2.08429 | V1 ok. ruwe vloer | Curtain Wall : K_24 | 7.53061 | 2.35777 | 1185 | Model Group:Merk K24:6065569

# IfcWindow: BI schuif rechts:BI schuif rechts (6)
Type - ParameterTakesPrecedence: no; Sizeable: no; Material: Clearance Zones
Type - Other - Category: Windows; Family Name: BI schuif rechts
Type - Constraints - Default Elevation: 1219.2 mm
Type - Dimensions - Offset_projectie_draairichting_bu: 0 mm; Symbol Height: 0.5; Symbol Width: 0.5; Frame: 120 mm
Type - Graphics - Elevation Symbol: yes; FloorPlan Symbol: yes
Type - Identity Data - Description: draairichting; Type Comments: SCHUIF RECHTS; Type Mark: 1217; Type Name: BI schuif rechts; Workset: Family : Windows : BI schuif rechts
Type - Analytical Properties - Define Thermal Properties by: Schematic Type; Analytic Construction: <None>
Type - Pset_ProductRequirements - Category: Windows
Type - Pset_WindowCommon - IsExternal: no
Type - Pset_Window - Kozijnmerk: 1217
OverallHeight: 194 mm
Pset_QuantityTakeOff - Reference: BI schuif rechts
Pset_WindowCommon - Reference: BI schuif rechts
Pset_Window - Omschrijving: draairichting
Pset_DAT_KMS - Description: draairichting
Other - Family: BI schuif rechts; Family and Type: BI schuif rechts: BI schuif rechts; Type: BI schuif rechts; Type Id: 4703909
Constraints - Moves With Nearby Elements: no; Offset from Host: 0 mm
Dimensions - Rough Height: 0 mm; Rough Width: 0 mm; Thickness: 54 mm
Identity Data - Workset: Bouwkundig
Phasing - Phase Created: 2. nieuwbouw
Visibility - 3D_draairichting: yes
Name (BI schuif rechts:BI schuif rechts:...) | In | OverallWidth (mm) | BaseQuantities, Height (mm) = Dimensions, Height (mm) | BaseQuantities, Width (mm) = Dimensions, Width (mm) | BaseQuantities, Area (m2) | HeightCalc (mm) | Width_calc (mm) | WidthCalc (mm) | Level | Host | Dimensions, Area (m2) | Volume (m3) | Mark | Group
5489868 | 00 Begane grond | 2150 | 2350 | 1135 | 2.66725 | 1175 | 1015 | 567.5 | 0 | Curtain Wall : Merk H24 | 2.56696 | 0.128803 | 3508 | Model Group:H24:5489871
5489895 | 00 Begane grond | 2145 | 2350 | 1132.5 | 2.66137 | 1175 | 1012.5 | 566.25 | 0 | Curtain Wall : Merk H21 | 2.56095 | 0.128486 | 3510 | Model Group:H21:5489898
5490918 | 00 Begane grond | 2150 | 2350 | 1135 | 2.66725 | 1175 | 1015 | 567.5 | 0 | Curtain Wall : Merk H24 | 2.56696 | 0.128803 | 3518 | Model Group:H24:5490908
5493800 | -1 Speelvloer | 1640 | 2610 | 880 | 2.2968 | 1305 | 760 | 440 | V-1 | Curtain Wall : Merk H22 | 2.16558 | 0.107114 | 3200 | Model Group:H22:5493776
6241711 | 00 Begane grond | 2150 | 2350 | 1135 | 2.66725 | 1175 | 1015 | 567.5 | 0 | Curtain Wall : Merk H24 | 2.56696 | 0.128803 | 3462 | Model Group:H24:6241714
6608206 | -1 Speelvloer | 1955.92 | 2610 | 1037.96 | 2.70908 | 1305 | 917.96 | 518.98 | V-1 | Curtain Wall : Merk H23 | 2.58639 | 0.129377 | 3464 | Model Group:H23:5131789

# IfcWindow: BU deur links:BU deur links (87)
Type - ParameterTakesPrecedence: no; Sizeable: no; Material: Clearance Zones
Type - Other - Category: Windows; 3D_draairichting_draai_hoek: 90 deg; Family Name: BU deur links
Type - Constraints - Default Elevation: 1219.2 mm
Type - Dimensions - Offset_projectie_draairichting_bu: 0 mm
Type - Graphics - Elevation Symbol: yes; FloorPlan Symbol_15gr: no; FloorPlan Symbol_90gr: yes
Type - Identity Data - Assembly Code: 31.31; Assembly Description: buitenwandopeningen; gevuld met deuren, draaideuren; Description: buitendraaiend deur links; Manufacturer: ITANNEX; Model: 04-11-2013; Type Comments: draarichting; Type Name: BU deur links; URL: www.bimvoorfabrikanten.nl; Workset: Family : Windows : BU deur links
Type - Analytical Properties - Define Thermal Properties by: Schematic Type; Analytic Construction: <None>
Type - Pset_ManufacturerTypeInformation - Manufacturer: ITANNEX
Type - Pset_ProductRequirements - Category: Windows
Type - Pset_WindowCommon - IsExternal: no
Classification: 31.31 Uniformat (Uniformat)
Pset_QuantityTakeOff - Reference: BU deur links
Pset_WindowCommon - Reference: BU deur links
Pset_Window - Omschrijving: buitendraaiend deur links; NL-sfb-Codering: 31.31
Pset_DAT_KMS - Assembly Code: 31.31; Assembly Description: buitenwandopeningen; gevuld met deuren, draaideuren; Description: buitendraaiend deur links
Other - Family: BU deur links; Family and Type: BU deur links: BU deur links; Type: BU deur links; Type Id: 4285640
Constraints - Moves With Nearby Elements: no
Dimensions - Rough Height: 0 mm; Rough Width: 0 mm
Phasing - Phase Created: 2. nieuwbouw
Visibility - 3D_draairichting: yes
Name (BU deur links:BU deur links:...) | In | OverallHeight (mm) | OverallWidth (mm) = BaseQuantities, Width (mm) = Dimensions, Width (mm) | BaseQuantities, Height (mm) = Dimensions, Height (mm) | BaseQuantities, Area (m2) | Level | Offset from Host (mm) | Host | Dimensions, Area (m2) | Thickness (mm) | Volume (m3) | Workset | Mark | Group
5125432 | 00 Begane grond | 1184 | 900 | 2303 | 2.0727 | 0 | 0 | Curtain Wall : Merk H01 | 4.33675 | 54 | 1.46509 | Bouwkundig | 488 | Model Group:H01:5125425
5125631 | 00 Begane grond | 1184 | 900 | 2303 | 2.0727 | 0 | 0 | Curtain Wall : Merk H01 | 4.33675 | 54 | 1.46509 | Bouwkundig | 492 | Model Group:H01:5125624
5125876 | 00 Begane grond | 1250 | 966 | 2303 | 2.2247 | 0 | 0 | Curtain Wall : Merk H19 | 4.70485 | 54 | 1.68785 | Bouwkundig | 508 | Model Group:H19:5125869
5126016 | 00 Begane grond | 1184 | 900 | 2303 | 2.0727 | 0 | 0 | Curtain Wall : Merk H01 | 4.33675 | 54 | 1.46509 | Bouwkundig | 3188 | Model Group:H01:5126009
5126025 | 00 Begane grond | 1184 | 900 | 2303 | 2.0727 | 0 | 0 | Curtain Wall : Merk H01 | 4.33675 | 54 | 1.46509 | Bouwkundig | 3190 | Model Group:H01:5126018
5126069 | 00 Begane grond | 1184 | 900 | 2303 | 2.0727 | 0 | 0 | Curtain Wall : Merk H01 | 4.33675 | 54 | 1.46509 | Bouwkundig | 3196 | Model Group:H01:5126062
5126078 | 00 Begane grond | 1184 | 900 | 2303 | 2.0727 | 0 | 0 | Curtain Wall : Merk H01 | 4.33675 | 54 | 1.46509 | Bouwkundig | 3198 | Model Group:H01:5126071
5126992 | 00 Begane grond | 1184 | 900 | 2303 | 2.0727 | 0 | 0 | Curtain Wall : Merk H02 | 4.33675 | 54 | 1.46509 | Bouwkundig | 3216 | Model Group:H02:5126985
5127347 | 00 Begane grond | 1184 | 900 | 2303 | 2.0727 | 0 | 0 | Curtain Wall : Merk H01 | 4.33675 | 54 | 1.46509 | Bouwkundig | 3227 | Model Group:H01:5127340
5127589 | 00 Begane grond | 1184 | 900 | 2303 | 2.0727 | 0 | 0 | Curtain Wall : Merk H01 | 4.33675 | 54 | 1.46509 | Bouwkundig | 3229 | Model Group:H01:5127582
5127600 | 00 Begane grond | 1184 | 900 | 2303 | 2.0727 | 0 | 0 | Curtain Wall : Merk H01 | 4.33675 | 54 | 1.46509 | Bouwkundig | 3231 | Model Group:H01:5127593
5127611 | 01 eerste verdieping | 1184 | 900 | 2303 | 2.0727 | 1 | 0 | Curtain Wall : Merk H01 | 4.33675 | 54 | 1.46509 | Bouwkundig | 3233 | Model Group:H01:5127604
5127622 | 01 eerste verdieping | 1184 | 900 | 2303 | 2.0727 | 1 | 0 | Curtain Wall : Merk H01 | 4.33675 | 54 | 1.46509 | Bouwkundig | 3235 | Model Group:H01:5127615
5127633 | 01 eerste verdieping | 1184 | 900 | 2303 | 2.0727 | 1 | 0 | Curtain Wall : Merk H01 | 4.33675 | 54 | 1.46509 | Bouwkundig | 3237 | Model Group:H01:5127626
5130151 | 00 Begane grond | 1184 | 900 | 2303 | 2.0727 | 0 | 0 | Curtain Wall : Merk H02 | 4.33675 | 54 | 1.46509 | Bouwkundig | 3253 | Model Group:H02:5130144
5162158 | 00 Begane grond | 1184 | 900 | 2303 | 2.0727 | 0 | 20 | Curtain Wall : Merk H10 | 4.33675 | 54 | 1.46509 | Bouwkundig | 3252 | Model Group:H10:5151852
5174556 | 01 eerste verdieping | 1184 | 900 | 2303 | 2.0727 | 1 | 0 | Curtain Wall : Merk H01 | 4.33675 | 54 | 1.46509 | Bouwkundig | 3315 | Model Group:H01:5174549
5202336 | 00 Begane grond | 1184 | 900 | 2303 | 2.0727 | 0 | 0 | Curtain Wall : Merk H02 | 4.33675 | 54 | 1.46509 | Bouwkundig | 3363 | Model Group:H02:5127227
5206513 | 00 Begane grond | 1184 | 900 | 2303 | 2.0727 | 0 | 0 | Curtain Wall : Merk H02 | 4.33675 | 54 | 1.46509 | Bouwkundig | 3364 | Model Group:H02:5206506
5275097 | 00 Begane grond | 1284 | 1000 | 2280 | 2.28 | 0 | 20 | Curtain Wall : Merk H04 | 4.85609 | 54 | 1.79069 | Bouwkundig | 3370 | Model Group:H04:5130948
5275103 | 00 Begane grond | 1284 | 1000 | 2280 | 2.28 | 0 | 20 | Curtain Wall : Merk H04 | 4.85609 | 54 | 1.79069 | Bouwkundig | 3265 | Model Group:H04:5131646
5275217 | 01 eerste verdieping | 1284 | 1000 | 2303 | 2.303 | 1 | 20 | Curtain Wall : Merk H09 | 4.89715 | 54 | 1.80876 | Bouwkundig | 3382 | Model Group:H09:5167012
5275411 | 00 Begane grond | 1284 | 1000 | 2303 | 2.303 | 0 | 20 | Curtain Wall : Merk H09 | 4.89715 | 54 | 1.80876 | Bouwkundig | 3384 | Model Group:H09:5145245
5275417 | 00 Begane grond | 1284 | 1000 | 2303 | 2.303 | 0 | 20 | Curtain Wall : Merk H09 | 4.89715 | 54 | 1.80876 | Bouwkundig | 3386 | Model Group:H09:5145654
5275420 | 00 Begane grond | 1284 | 1000 | 2303 | 2.303 | 0 | 20 | Curtain Wall : Merk H09 | 4.89715 | 54 | 1.80876 | Bouwkundig | 3388 | Model Group:H09:5145678
5275432 | 01 eerste verdieping | 1284 | 1000 | 2303 | 2.303 | 1 | 20 | Curtain Wall : Merk H09 | 4.89715 | 54 | 1.80876 | Bouwkundig | 3392 | Model Group:H09:5167153
5275435 | 01 eerste verdieping | 1284 | 1000 | 2303 | 2.303 | 1 | 20 | Curtain Wall : Merk H09 | 4.89715 | 54 | 1.80876 | Bouwkundig | 3412 | Model Group:H09:5174883
5275438 | 01 eerste verdieping | 1284 | 1000 | 2303 | 2.303 | 1 | 20 | Curtain Wall : Merk H09 | 4.89715 | 54 | 1.80876 | Bouwkundig | 3414 | Model Group:H09:5181878
5275441 | 01 eerste verdieping | 1284 | 1000 | 2303 | 2.303 | 1 | 20 | Curtain Wall : Merk H09 | 4.89715 | 54 | 1.80876 | Bouwkundig | 3416 | Model Group:H09:5184337
5275444 | 01 eerste verdieping | 1284 | 1000 | 2303 | 2.303 | 1 | 20 | Curtain Wall : Merk H09 | 4.89715 | 54 | 1.80876 | Bouwkundig | 3418 | Model Group:H09:5184386
5275447 | 00 Begane grond | 1284 | 1000 | 2303 | 2.303 | 0 | 20 | Curtain Wall : Merk H09 | 4.89715 | 54 | 1.80876 | Bouwkundig | 3420 | Model Group:H09:5203601
5275453 | 00 Begane grond | 1284 | 1000 | 2303 | 2.303 | 0 | 20 | Curtain Wall : Merk H09 | 4.89715 | 54 | 1.80876 | Bouwkundig | 3422 | Model Group:H09:5206741
5275607 | 00 Begane grond | 1277 | 993 | 2303 | 2.28688 | 0 | 20 | Curtain Wall : Merk H14 | 4.85741 | 54 | 1.78352 | Bouwkundig | 3426 | Model Group:H06:5143935
5275806 | 00 Begane grond | 1284 | 1000 | 2303 | 2.303 | 0 | 20 | Curtain Wall : Merk H03 | 4.89715 | 54 | 1.80876 | Bouwkundig | 3428 | Model Group:H03:5131933
5275912 | 01 eerste verdieping | 1284 | 1000 | 2303 | 2.303 | 1 | 20 | Curtain Wall : Merk H03 | 4.89715 | 54 | 1.80876 | Bouwkundig | 3361 | Model Group:H03:5179821
5275915 | 01 eerste verdieping | 1284 | 1000 | 2303 | 2.303 | 1 | 20 | Curtain Wall : Merk H18 | 4.89715 | 54 | 1.80876 | Bouwkundig | 3373 | Model Group:H18:5185791
5276113 | 01 eerste verdieping | 1207 | 923 | 2303 | 2.12567 | 1 | 20 | Curtain Wall : Merk H07 | 4.46425 | 54 | 1.54093 | Bouwkundig | 3432 | Model Group:H07:5227238
5276200 | 00 Begane grond | 1207 | 923 | 2303 | 2.12567 | 0 | 20 | Curtain Wall : Merk H07 | 4.46425 | 54 | 1.54093 | Bouwkundig | 3436 | Model Group:H07:5144116
5276210 | 00 Begane grond | 1207 | 923 | 2303 | 2.12567 | 0 | 20 | Curtain Wall : Merk H07 | 4.46425 | 54 | 1.54093 | Bouwkundig | 3440 | Model Group:H07:5145183
5276215 | 01 eerste verdieping | 1207 | 923 | 2303 | 2.12567 | 1 | 20 | Curtain Wall : Merk H07 | 4.46425 | 54 | 1.54093 | Bouwkundig | 3444 | Model Group:H07:5227264
5276353 | 01 eerste verdieping | 1184 | 900 | 2303 | 2.0727 | 1 | 20 | Curtain Wall : Merk H16 | 4.33675 | 54 | 1.46509 | Bouwkundig | 3446 | Model Group:H16:5227244
5276460 | 00 Begane grond | 1184 | 900 | 2303 | 2.0727 | 0 | 20 | Curtain Wall : Merk H16 | 4.33675 | 54 | 1.46509 | Bouwkundig | 3450 | Model Group:H16:5197611
5276567 | 00 Begane grond | 1184 | 900 | 2303 | 2.0727 | 0 | 20 | Curtain Wall : Merk H16 | 4.33675 | 54 | 1.46509 | Bouwkundig | 3452 | Model Group:H16:5195722
5276576 | 00 Begane grond | 1184 | 900 | 2303 | 2.0727 | 0 | 20 | Curtain Wall : Merk H16 | 4.33675 | 54 | 1.46509 | Bouwkundig | 3454 | Model Group:H16:5197451
5277207 | 01 eerste verdieping | 1184 | 900 | 2303 | 2.0727 | 1 | 0 | Curtain Wall : Merk H01 | 4.33675 | 54 | 1.46509 | Bouwkundig | 3465 | Model Group:H01:5174800
5277243 | 01 eerste verdieping | 1184 | 900 | 2303 | 2.0727 | 1 | 0 | Curtain Wall : Merk H01 | 4.33675 | 54 | 1.46509 | Bouwkundig | 3467 | Model Group:H01:5174841
5465841 | 00 Begane grond | 1284 | 1000 | 2303 | 2.303 | 0 | 20 | Curtain Wall : Merk H03 | 4.89715 | 54 | 1.80876 | Bouwkundig | 523 | Model Group:H03:5465827
5488425 | 00 Begane grond | 1217 | 933 | 2303 | 2.1487 | 0 | 20 | Curtain Wall : Merk H20 | 4.51995 | 54 | 1.5745 | Bouwkundig | 3503 | Model Group:H20:5488876
5533688 | 01 eerste verdieping | 1184 | 900 | 2303 | 2.0727 | 1 | 0 | Curtain Wall : Merk H02 | 4.33675 | 54 | 1.46509 | Bouwkundig | 3476 | Model Group:H02:5533681
5533715 | 01 eerste verdieping | 1184 | 900 | 2303 | 2.0727 | 1 | 20 | Curtain Wall : Merk H11 | 4.33675 | 54 | 1.46509 | Bouwkundig | 500 | Model Group:H11:5533699
5536870 | 00 Begane grond | 1314 | 1010 | 2550 | 2.5755 | 0 | 0 | Curtain Wall : K_03 | 5.39946 | 74 | 2.043 | Bouwkundig | 3501 | Model Group:Merk K03:5536856
5536942 | 00 Begane grond | 1314 | 1010 | 2550 | 2.5755 | 0 | 0 | Curtain Wall : K_03 | 5.39946 | 74 | 2.043 | Bouwkundig | 3524 | Model Group:Merk K03:5536928
5537093 | 00 Begane grond | 1314 | 1010 | 2550 | 2.5755 | 0 | 0 | Curtain Wall : K_03 | 5.39946 | 74 | 2.043 | Bouwkundig | 3540 | Model Group:Merk K03:5537079
5538776 | 00 Begane grond | 1314 | 1010 | 2550 | 2.5755 | 0 | 0 | Curtain Wall : K_03 | 5.39946 | 74 | 2.043 | Bouwkundig | 3837 | Model Group:Merk K03:5538762
5538794 | 00 Begane grond | 1314 | 1010 | 2550 | 2.5755 | 0 | 0 | Curtain Wall : K_03 | 5.39946 | 74 | 2.043 | Bouwkundig | 3841 | Model Group:Merk K03:5538780
5538812 | 00 Begane grond | 1314 | 1010 | 2550 | 2.5755 | 0 | 0 | Curtain Wall : K_03 | 5.39946 | 74 | 2.043 | Bouwkundig | 3845 | Model Group:Merk K03:5538798
5539088 | 00 Begane grond | 1209 | 905 | 2570 | 2.32585 | 0 | 0 | Curtain Wall : K_20 | 4.79581 | 74 | 1.65317 | Bouwkundig | 3917 | Model Group:Merk K20:5539074
5922940 | 00 Begane grond | 1154.5 | 870.5 | 2303 | 2.00476 | 0 | 20 | Curtain Wall : Merk H14 | 4.17444 | 54 | 1.37063 | Bouwkundig | 1105 | Model Group:H14:5143401
5987155 | 01 eerste verdieping | 1184 | 900 | 2303 | 2.0727 | 1 | 0 | Curtain Wall : Merk H02 | 4.33675 | 54 | 1.46509 | Bouwkundig | 3477 | Model Group:H02:5987148
5987401 | 01 eerste verdieping | 1184 | 900 | 2303 | 2.0727 | 1 | 0 | Curtain Wall : Merk H02 | 4.33675 | 54 | 1.46509 | Bouwkundig | 3482 | Model Group:H02:5987394
5987409 | 01 eerste verdieping | 1184 | 900 | 2303 | 2.0727 | 1 | 0 | Curtain Wall : Merk H02 | 4.33675 | 54 | 1.46509 | Bouwkundig | 3483 | Model Group:H02:5987402
5988185 | 01 eerste verdieping | 1284 | 1000 | 2303 | 2.303 | 1 | 20 | Curtain Wall : Merk H09 | 4.89715 | 54 | 1.80876 | Bouwkundig | 3512 | Model Group:H09:5988145
5994931 | 01 eerste verdieping | 1184 | 900 | 2303 | 2.0727 | 1 | 0 | Curtain Wall : Merk H01 | 4.33675 | 54 | 1.46509 | Bouwkundig | 3543 | Model Group:H01:5994924
5995290 | 01 eerste verdieping | 1207 | 923 | 2303 | 2.12567 | 1 | 20 | Curtain Wall : Merk H07 | 4.46425 | 54 | 1.54093 | Bouwkundig | 3549 | Model Group:H07:5995281
6241475 | 00 Begane grond | 1284 | 1000 | 2280 | 2.28 | 0 | 20 | Curtain Wall : Merk H04 | 4.85609 | 54 | 1.79069 | Bouwkundig | 3460 | Model Group:H04:6241461
6382291 | 01 eerste verdieping | 1184 | 900 | 2303 | 2.0727 | 1 | 20 | Curtain Wall : Merk H16 | 4.33675 | 54 | 1.46509 | Bouwkundig | 3468 | Model Group:H16:5185909
6486414 | 00 Begane grond | 1135.5 | 889.5 | 1065 | 0.947318 | 0 | 0 | Curtain Wall : NLRS_31_CW_buitenbergingdeuren | 2.31274 | 16 | 0.661802 | situatie | 3573
6487011 | 00 Begane grond | 1530 | 1250 | 1500 | 1.875 | 0 | 0 | Curtain Wall : NLRS_31_CW_buitenbergingdeuren | 4.57306 | 50 | 1.8399 | situatie | 3579
6487413 | 00 Begane grond | 2020.9 | 1740.9 | 1500 | 2.61135 | 0 | 0 | Curtain Wall : NLRS_31_CW_buitenbergingdeuren | 7.04294 | 50 | 3.57065 | situatie | 3585
6495811 | 00 Begane grond | 1186 | 940 | 2050 | 1.927 | 0 | 0 | Curtain Wall : NLRS_31_CW_buitenbergingdeuren | 4.13442 | 16 | 1.42264 | situatie | 3610 | Model Group:bergingdeur:6495812
6495827 | 00 Begane grond | 1186 | 940 | 2050 | 1.927 | 0 | 0 | Curtain Wall : NLRS_31_CW_buitenbergingdeuren | 4.13442 | 16 | 1.42264 | situatie | 3624 | Model Group:bergingdeur:6495828
6495931 | 00 Begane grond | 1186 | 940 | 2050 | 1.927 | 0 | 0 | Curtain Wall : NLRS_31_CW_buitenbergingdeuren | 4.13442 | 16 | 1.42264 | situatie | 3643 | Model Group:bergingdeur:6495932
6495945 | 00 Begane grond | 1186 | 940 | 2050 | 1.927 | 0 | 0 | Curtain Wall : NLRS_31_CW_buitenbergingdeuren | 4.13442 | 16 | 1.42264 | situatie | 3645 | Model Group:bergingdeur:6495946
6522737 | 00 Begane grond | 1184 | 900 | 2303 | 2.0727 | 0 | 0 | Curtain Wall : Merk H02 | 4.33675 | 54 | 1.46509 | Bouwkundig | 3559 | Model Group:H02:6522730
6604039 | 00 Begane grond | 1284 | 1000 | 2303 | 2.303 | 0 | 20 | Curtain Wall : Merk H18 | 4.89715 | 54 | 1.80876 | Bouwkundig | 531 | Model Group:H18:5129917
6668709 | 00 Begane grond | 1284 | 1000 | 2303 | 2.303 | 0 | 20 | Curtain Wall : Merk H09 | 4.89715 | 54 | 1.80876 | Bouwkundig | 3332 | Model Group:H09:6668701
6694321 | 00 Begane grond | 1184 | 900 | 2303 | 2.0727 | 0 | 0 | Curtain Wall : Merk H02 | 4.33675 | 54 | 1.46509 | Bouwkundig | 3218 | Model Group:H02:6694314
6766706 | 00 Begane grond | 1135.5 | 889.5 | 1065 | 0.947318 | 0 | 0 | Curtain Wall : NLRS_31_CW_buitenbergingdeuren | 2.31274 | 16 | 0.661802 | Bouwkundig | 3197
6800009 | 00 Begane grond | 1184 | 900 | 2303 | 2.0727 | 0 | 20 | Curtain Wall : Merk H16 | 4.33675 | 54 | 1.46509 | Bouwkundig | 3319 | Model Group:H16:5145073
6800241 | 01 eerste verdieping | 1184 | 900 | 2303 | 2.0727 | 1 | 20 | Curtain Wall : Merk H16 | 4.33675 | 54 | 1.46509 | Bouwkundig | 3327 | Model Group:H16:5987797
6800250 | 01 eerste verdieping | 1184 | 900 | 2303 | 2.0727 | 1 | 20 | Curtain Wall : Merk H16 | 4.33675 | 54 | 1.46509 | Bouwkundig | 3333 | Model Group:H16:5995318
6801743 | 00 Begane grond | 1184 | 900 | 2303 | 2.0727 | 0 | 20 | Curtain Wall : Merk H16 | 4.33675 | 54 | 1.46509 | Bouwkundig | 3343 | Model Group:H16:5130407
6801786 | 00 Begane grond | 1184 | 900 | 2303 | 2.0727 | 0 | 20 | Curtain Wall : Merk H16 | 4.33675 | 54 | 1.46509 | Bouwkundig | 3346 | Model Group:H16:5127086
6802021 | 01 eerste verdieping | 1184 | 900 | 2303 | 2.0727 | 1 | 20 | Curtain Wall : Merk H16 | 4.33675 | 54 | 1.46509 | Bouwkundig | 3374 | Model Group:H16:5987147
6802184 | 01 eerste verdieping | 1184 | 900 | 2303 | 2.0727 | 1 | 20 | Curtain Wall : Merk H16 | 4.33675 | 54 | 1.46509 | Bouwkundig | 3376 | Model Group:H16:5987156
6802225 | 01 eerste verdieping | 1184 | 900 | 2303 | 2.0727 | 1 | 20 | Curtain Wall : Merk H16 | 4.33675 | 54 | 1.46509 | Bouwkundig | 3378 | Model Group:H16:5179182
6804087 | 00 Begane grond | 1184 | 900 | 2303 | 2.0727 | 0 | 0 | Curtain Wall : Merk H02 | 4.33675 | 54 | 1.46509 | Bouwkundig | 3379 | Model Group:H02:5126556

# IfcWindow: BU deur rechts:BU deur rechts (28)
Type - ParameterTakesPrecedence: no; Sizeable: no; Material: Clearance Zones
Type - Other - Category: Windows; 3D_draairichting_draai_hoek: 90 deg; Family Name: BU deur rechts
Type - Constraints - Default Elevation: 1219.2 mm
Type - Dimensions - Offset_projectie_draairichting_bu: 0 mm
Type - Graphics - Elevation Symbol: yes; FloorPlan Symbol_15gr: no; FloorPlan Symbol_90gr: yes
Type - Identity Data - Assembly Code: 31.31; Assembly Description: buitenwandopeningen; gevuld met deuren, draaideuren; Description: buitendraaiend deur rechts; Manufacturer: ITANNEX; Model: 04-11-2013; Type Comments: draarichting; Type Name: BU deur rechts; URL: www.bimvoorfabrikanten.nl; Workset: Family : Windows : BU deur rechts
Type - Analytical Properties - Define Thermal Properties by: Schematic Type; Analytic Construction: <None>
Type - Pset_ManufacturerTypeInformation - Manufacturer: ITANNEX
Type - Pset_ProductRequirements - Category: Windows
Type - Pset_WindowCommon - IsExternal: no
Classification: 31.31 Uniformat (Uniformat)
Pset_QuantityTakeOff - Reference: BU deur rechts
Pset_WindowCommon - Reference: BU deur rechts
Pset_Window - Omschrijving: buitendraaiend deur rechts; NL-sfb-Codering: 31.31
Pset_DAT_KMS - Assembly Code: 31.31; Assembly Description: buitenwandopeningen; gevuld met deuren, draaideuren; Description: buitendraaiend deur rechts
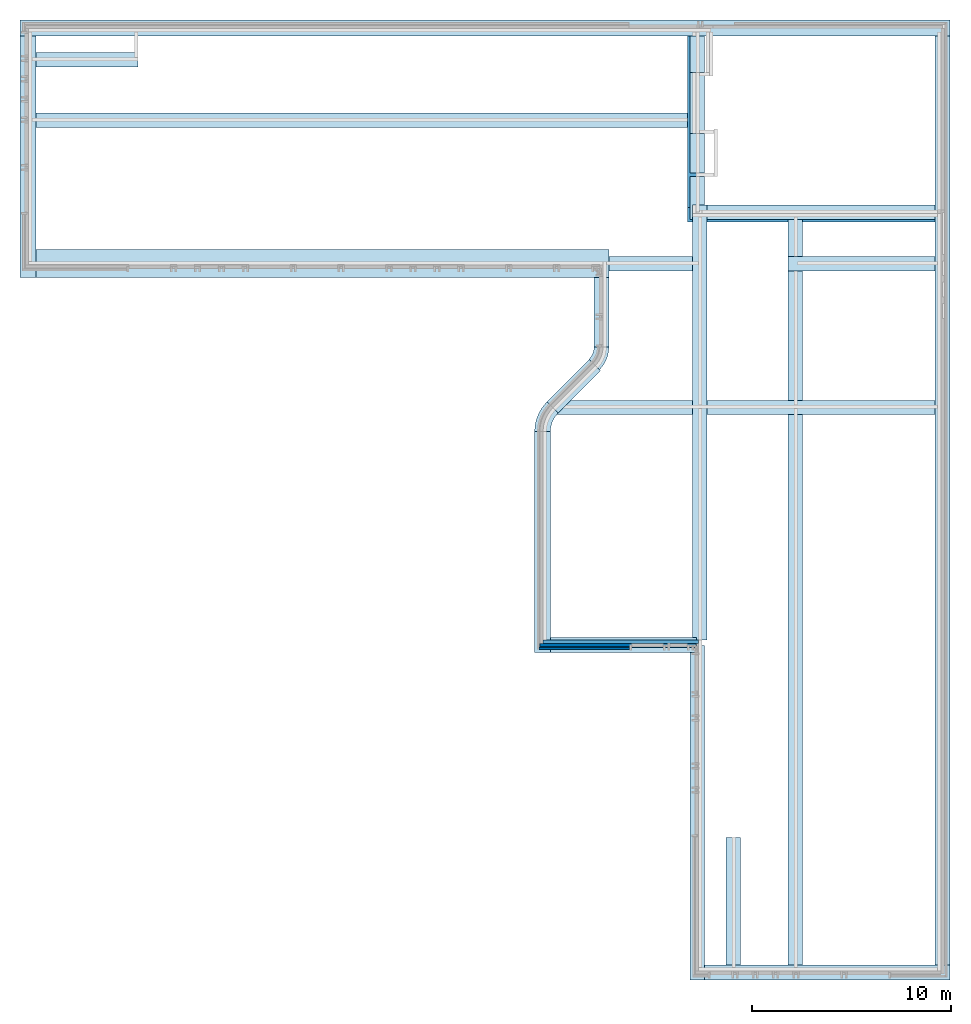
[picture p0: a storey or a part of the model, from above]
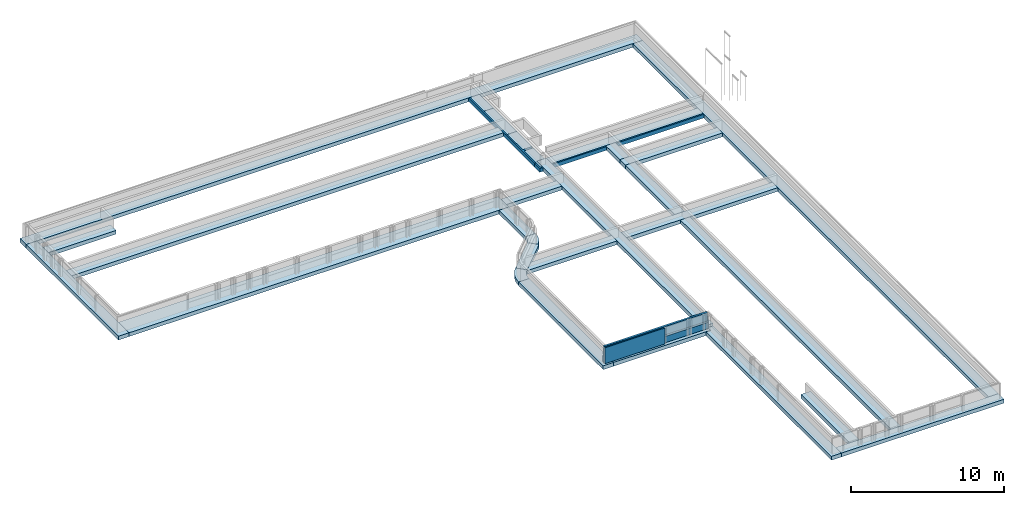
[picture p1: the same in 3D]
Properties of the parts of a building model (IFC2X3), part 36 of 37

# IfcWindow: BU deur rechts:BU deur rechts (28)
Other - Family: BU deur rechts; Family and Type: BU deur rechts: BU deur rechts; Type: BU deur rechts; Type Id: 4285678
Constraints - Moves With Nearby Elements: no; Offset from Host: 0 mm
Dimensions - Rough Height: 0 mm; Rough Width: 0 mm
Phasing - Phase Created: 2. nieuwbouw
Visibility - 3D_draairichting: yes
Name (BU deur rechts:BU deur rechts:...) | In | OverallHeight (mm) | OverallWidth (mm) = BaseQuantities, Width (mm) = Dimensions, Width (mm) | BaseQuantities, Height (mm) = Dimensions, Height (mm) | BaseQuantities, Area (m2) | Level | Host | Dimensions, Area (m2) | Thickness (mm) | Volume (m3) | Workset | Mark | Group
5140506 | 00 Begane grond | 1217 | 933 | 2303 | 2.1487 | 0 | Curtain Wall : Merk H20 | 4.51994 | 54 | 1.57449 | Bouwkundig | 2705 | Model Group:H20:5488876
5162250 | 00 Begane grond | 1184 | 900 | 2303 | 2.0727 | 0 | Curtain Wall : Merk H10 | 4.33674 | 54 | 1.46508 | Bouwkundig | 3260 | Model Group:H10:5151852
5194930 | 01 eerste verdieping | 1187.75 | 903.75 | 2303 | 2.08134 | 1 | Curtain Wall : Merk H12 | 4.35748 | 54 | 1.47732 | Bouwkundig | 3400 | Model Group:H12:5194912
5275548 | 00 Begane grond | 1277 | 993 | 2303 | 2.28688 | 0 | Curtain Wall : Merk H14 | 4.8574 | 54 | 1.78351 | Bouwkundig | 3424 | Model Group:H06:5143935
5276054 | 01 eerste verdieping | 1207 | 923 | 2303 | 2.12567 | 1 | Curtain Wall : Merk H07 | 4.46425 | 54 | 1.54092 | Bouwkundig | 3430 | Model Group:H07:5227238
5276198 | 00 Begane grond | 1207 | 923 | 2303 | 2.12567 | 0 | Curtain Wall : Merk H07 | 4.46425 | 54 | 1.54092 | Bouwkundig | 3434 | Model Group:H07:5144116
5276208 | 00 Begane grond | 1207 | 923 | 2303 | 2.12567 | 0 | Curtain Wall : Merk H07 | 4.46425 | 54 | 1.54092 | Bouwkundig | 3438 | Model Group:H07:5145183
5276213 | 01 eerste verdieping | 1207 | 923 | 2303 | 2.12567 | 1 | Curtain Wall : Merk H07 | 4.46425 | 54 | 1.54092 | Bouwkundig | 3442 | Model Group:H07:5227264
5533717 | 01 eerste verdieping | 1184 | 900 | 2303 | 2.0727 | 1 | Curtain Wall : Merk H11 | 4.33674 | 54 | 1.46508 | Bouwkundig | 502 | Model Group:H11:5533699
5536868 | 00 Begane grond | 1314 | 1010 | 2550 | 2.5755 | 0 | Curtain Wall : K_03 | 5.39945 | 74 | 2.04299 | Bouwkundig | 3499 | Model Group:Merk K03:5536856
5536940 | 00 Begane grond | 1314 | 1010 | 2550 | 2.5755 | 0 | Curtain Wall : K_03 | 5.39945 | 74 | 2.04299 | Bouwkundig | 3522 | Model Group:Merk K03:5536928
5537050 | 00 Begane grond | 1334 | 1030 | 2550 | 2.6265 | 0 | Curtain Wall : K_05 | 5.52254 | 74 | 2.12468 | Bouwkundig | 3532 | Model Group:Merk K05:5537042
5537091 | 00 Begane grond | 1314 | 1010 | 2550 | 2.5755 | 0 | Curtain Wall : K_03 | 5.39945 | 74 | 2.04299 | Bouwkundig | 3538 | Model Group:Merk K03:5537079
5538774 | 00 Begane grond | 1314 | 1010 | 2550 | 2.5755 | 0 | Curtain Wall : K_03 | 5.39945 | 74 | 2.04299 | Bouwkundig | 3835 | Model Group:Merk K03:5538762
5538792 | 00 Begane grond | 1314 | 1010 | 2550 | 2.5755 | 0 | Curtain Wall : K_03 | 5.39945 | 74 | 2.04299 | Bouwkundig | 3839 | Model Group:Merk K03:5538780
5538810 | 00 Begane grond | 1314 | 1010 | 2550 | 2.5755 | 0 | Curtain Wall : K_03 | 5.39945 | 74 | 2.04299 | Bouwkundig | 3843 | Model Group:Merk K03:5538798
5539086 | 00 Begane grond | 1209 | 905 | 2570 | 2.32585 | 0 | Curtain Wall : K_20 | 4.79581 | 74 | 1.65315 | Bouwkundig | 3915 | Model Group:Merk K20:5539074
5922866 | 00 Begane grond | 1154.5 | 870.5 | 2303 | 2.00476 | 0 | Curtain Wall : Merk H14 | 4.17444 | 54 | 1.37063 | Bouwkundig | 1094 | Model Group:H14:5143401
5995288 | 01 eerste verdieping | 1207 | 923 | 2303 | 2.12567 | 1 | Curtain Wall : Merk H07 | 4.46425 | 54 | 1.54092 | Bouwkundig | 3547 | Model Group:H07:5995281
6487010 | 00 Begane grond | 1530 | 1250 | 1500 | 1.875 | 0 | Curtain Wall : NLRS_31_CW_buitenbergingdeuren | 4.57192 | 50 | 1.83877 | situatie | 3578
6487412 | 00 Begane grond | 2020.94 | 1740.94 | 1500 | 2.61141 | 0 | Curtain Wall : NLRS_31_CW_buitenbergingdeuren | 7.04334 | 50 | 3.571 | situatie | 3584
6495810 | 00 Begane grond | 1186 | 940 | 2050 | 1.927 | 0 | Curtain Wall : NLRS_31_CW_buitenbergingdeuren | 4.13442 | 16 | 1.42263 | situatie | 3609 | Model Group:bergingdeur:6495812
6495826 | 00 Begane grond | 1186 | 940 | 2050 | 1.927 | 0 | Curtain Wall : NLRS_31_CW_buitenbergingdeuren | 4.13442 | 16 | 1.42263 | situatie | 3611 | Model Group:bergingdeur:6495828
6495930 | 00 Begane grond | 1186 | 940 | 2050 | 1.927 | 0 | Curtain Wall : NLRS_31_CW_buitenbergingdeuren | 4.13442 | 16 | 1.42263 | situatie | 3642 | Model Group:bergingdeur:6495932
6495944 | 00 Begane grond | 1186 | 940 | 2050 | 1.927 | 0 | Curtain Wall : NLRS_31_CW_buitenbergingdeuren | 4.13442 | 16 | 1.42263 | situatie | 3644 | Model Group:bergingdeur:6495946
6703052 | 00 Begane grond | 1334 | 1030 | 2550 | 2.6265 | 0 | Curtain Wall : K_05 | 5.52254 | 74 | 2.12468 | Bouwkundig | 3193 | Model Group:Merk K05:6703044
6766113 | 00 Begane grond | 1146.5 | 900.5 | 1065 | 0.959032 | 0 | Curtain Wall : NLRS_31_CW_buitenbergingdeuren | 2.34911 | 16 | 0.678266 | situatie | 3195
6766708 | 00 Begane grond | 1146.5 | 900.5 | 1065 | 0.959032 | 0 | Curtain Wall : NLRS_31_CW_buitenbergingdeuren | 2.34911 | 16 | 0.678266 | Bouwkundig | 3201

# IfcWindow: BU schuif links:BU schuif links (6)
Type - ParameterTakesPrecedence: no; Sizeable: no; Material: Clearance Zones
Type - Other - Category: Windows; Family Name: BU schuif links
Type - Constraints - Default Elevation: 1219.2 mm
Type - Dimensions - Offset_projectie_draairichting_bu: 0 mm; Frame: 120 mm; Symbol Height: 0.5; Symbol Width: 0.5
Type - Graphics - Elevation Symbol: yes; FloorPlan Symbol: yes
Type - Identity Data - Description: draairichting; Manufacturer: ITANNEX; Model: 04-11-2013; Type Comments: SCHUIF LINKS; Type Mark: 1223; Type Name: BU schuif links; URL: www.bimvoorfabrikanten.nl; Workset: Family : Windows : BU schuif links
Type - Analytical Properties - Define Thermal Properties by: Schematic Type; Analytic Construction: <None>
Type - Pset_ManufacturerTypeInformation - Manufacturer: ITANNEX
Type - Pset_ProductRequirements - Category: Windows
Type - Pset_WindowCommon - IsExternal: no
Type - Pset_Window - Kozijnmerk: 1223
OverallHeight: 194 mm
Pset_QuantityTakeOff - Reference: BU schuif links
Pset_WindowCommon - Reference: BU schuif links
Pset_Window - Omschrijving: draairichting
Pset_DAT_KMS - Description: draairichting
Other - Family: BU schuif links; Family and Type: BU schuif links: BU schuif links; Type: BU schuif links; Type Id: 4708212
Constraints - Moves With Nearby Elements: no; Offset from Host: 0 mm
Dimensions - Rough Height: 0 mm; Rough Width: 0 mm; Thickness: 54 mm
Identity Data - Workset: Bouwkundig
Phasing - Phase Created: 2. nieuwbouw
Visibility - draairichting_3D: yes
Name (BU schuif links:BU schuif links:...) | In | OverallWidth (mm) | BaseQuantities, Height (mm) = Dimensions, Height (mm) | BaseQuantities, Width (mm) = Dimensions, Width (mm) | BaseQuantities, Area (m2) | HeightCalc (mm) | Width_calc (mm) | WidthCalc (mm) | Level | Host | Dimensions, Area (m2) | Volume (m3) | Mark | Group
5489865 | 00 Begane grond | 2250 | 2350 | 1185 | 2.78475 | 1175 | 1065 | 592.5 | 0 | Curtain Wall : Merk H24 | 2.68716 | 0.135149 | 3507 | Model Group:H24:5489871
5489892 | 00 Begane grond | 2135 | 2350 | 1127.5 | 2.64963 | 1175 | 1007.5 | 563.75 | 0 | Curtain Wall : Merk H21 | 2.54893 | 0.127852 | 3509 | Model Group:H21:5489898
5490915 | 00 Begane grond | 2250 | 2350 | 1185 | 2.78475 | 1175 | 1065 | 592.5 | 0 | Curtain Wall : Merk H24 | 2.68716 | 0.135149 | 3517 | Model Group:H24:5490908
5493797 | -1 Speelvloer | 2200 | 2610 | 1160 | 3.0276 | 1305 | 1040 | 580 | V-1 | Curtain Wall : Merk H22 | 2.9115 | 0.146578 | 3199 | Model Group:H22:5493776
6241708 | 00 Begane grond | 2250 | 2350 | 1185 | 2.78475 | 1175 | 1065 | 592.5 | 0 | Curtain Wall : Merk H24 | 2.68716 | 0.135149 | 3461 | Model Group:H24:6241714
6608203 | -1 Speelvloer | 1954 | 2610 | 1037 | 2.70657 | 1305 | 917 | 518.5 | V-1 | Curtain Wall : Merk H23 | 2.58383 | 0.129242 | 3463 | Model Group:H23:5131789

# IfcWindow: WI_subvak1:glas 2 (72)
Type - ParameterTakesPrecedence: no; Sizeable: no; Material: glas_enscape
Type - Other - Category: Windows; Family Name: WI_subvak1
Type - Dimensions - VentilationHeight: 0 mm; decoratie_breedte: 52 mm; decoratie_diepte: 10 mm; Thickness: 24 mm
Type - General - VentilationType: ventilatierooster1 : Type 1
Type - Identity Data - Workset: Family : Windows : WI_subvak1; Assembly Code: 31.11; Assembly Description: buitenwandopeningen; niet gevuld, daglichtopeningen; Description: enkel glas + rooster; Manufacturer: ITANNEX; Model: 10-07-2014; Type Comments: subvakken; Type Mark: ○○; Type Name: glas 2; URL: www.bimvoorfabrikanten.nl
Type - Materials and Finishes - FinishExteriorMaterial: glas_enscape
Type - Analytical Properties - Define Thermal Properties by: Schematic Type; Analytic Construction: <None>
Type - Pset_ManufacturerTypeInformation - Manufacturer: ITANNEX
Type - Pset_ProductRequirements - Category: Windows
Type - Pset_WindowCommon - IsExternal: no
Type - Pset_Window - Kozijnmerk: ○○
OverallHeight: 609.929 mm; Classification: 31.11 Uniformat (Uniformat)
Pset_QuantityTakeOff - Reference: glas 2
Pset_WindowCommon - Reference: glas 2
Pset_Window - Omschrijving: enkel glas + rooster; NL-sfb-Codering: 31.11
Pset_DAT_KMS - Assembly Code: 31.11; Assembly Description: buitenwandopeningen; niet gevuld, daglichtopeningen; Description: enkel glas + rooster
Other - WBDBO 30: no; CalcHorMultiple: no; CalcHorSingle: no; CalcVertMultiple: no; CalcVertSingle: no; Family: WI_subvak1; SubPanel_1_h_Calc: 2; SubPanel_1_v_Calc: 2; Ventilation: no; CalcVentilationHeight: 80 mm; Family and Type: WI_subvak1: glas 2; Type: glas 2; Type Id: 4378174
Model Properties - correctie_roede_hor: 0 mm; correctie_roede_ver: 0 mm; shift_roede_hor: 0 mm; shift_roede_ver: 0 mm; subpaneel_1_roedes_hor: 0; subpaneel_1_roedes_ver: 0
Constraints - Moves With Nearby Elements: no; Offset from Host: 240 mm
Fire Protection - WBDO_30_1on_0off: 0
Identity Data - Workset: Bouwkundig
Phasing - Phase Created: 2. nieuwbouw
Name (WI_subvak1:glas 2:...) | In | OverallWidth (mm) = BaseQuantities, Width (mm) = Rough Width (mm) = Dimensions, Width (mm) | BaseQuantities, Height (mm) = subpaneel_1_hoogte (mm) = Dimensions, Height (mm) = Rough Height (mm) | BaseQuantities, Area (m2) | calc_mid_hor (mm) | calc_mid_ver (mm) | CalcEndHor (mm) = CalcStartHor (mm) | CalcEndVert (mm) = CalcStartVert (mm) | Level | Host | Dimensions, Area (m2) | Volume (m3) | Mark | FrameExteriorMaterial | FrameInteriorMaterial | Group
5162157 | 00 Begane grond | 660 | 1943 | 1.28238 | 971.5 | 330 | 647.667 | 220 | 0 | Curtain Wall : Merk H10 | 0.974556 | 0.00812136 | 3248 | HPL F7853 ocean gray | HPL F7853 ocean gray | Model Group:H10:5151852
5162249 | 00 Begane grond | 660 | 1943 | 1.28238 | 971.5 | 330 | 647.667 | 220 | 0 | Curtain Wall : Merk H10 | 0.974556 | 0.00812136 | 3254 | HPL F7853 ocean gray | HPL F7853 ocean gray | Model Group:H10:5151852
5194927 | 01 eerste verdieping | 656.25 | 1943 | 1.27509 | 971.5 | 328.125 | 647.667 | 218.75 | 1 | Curtain Wall : Merk H12 | 0.973161 | 0.00810966 | 3397 | HPL F7853 ocean gray | HPL F7853 ocean gray | Model Group:H12:5194912
5194929 | 01 eerste verdieping | 663.75 | 1943 | 1.28967 | 971.5 | 331.875 | 647.667 | 221.25 | 1 | Curtain Wall : Merk H12 | 0.975951 | 0.00813306 | 3399 | HPL F7853 ocean gray | HPL F7853 ocean gray | Model Group:H12:5194912
5275096 | 00 Begane grond | 760 | 1920 | 1.4592 | 960 | 380 | 640 | 253.333 | 0 | Curtain Wall : Merk H04 | 1.0032 | 0.0083616 | 3274 | ISR_HPL Kleur hout | ISR_HPL Kleur hout | Model Group:H04:5130948
5275102 | 00 Begane grond | 760 | 1920 | 1.4592 | 960 | 380 | 640 | 253.333 | 0 | Curtain Wall : Merk H04 | 1.0032 | 0.0083616 | 3257 | ISR_HPL Kleur hout | ISR_HPL Kleur hout | Model Group:H04:5131646
5275216 | 01 eerste verdieping | 760 | 1943 | 1.47668 | 971.5 | 380 | 647.667 | 253.333 | 1 | Curtain Wall : Merk H09 | 1.01176 | 0.00843336 | 3381 | ISR_HPL Kleur hout | ISR_HPL Kleur hout | Model Group:H09:5167012
5275410 | 00 Begane grond | 760 | 1943 | 1.47668 | 971.5 | 380 | 647.667 | 253.333 | 0 | Curtain Wall : Merk H09 | 1.01176 | 0.00843336 | 3383 | ISR_HPL Kleur hout | ISR_HPL Kleur hout | Model Group:H09:5145245
5275416 | 00 Begane grond | 760 | 1943 | 1.47668 | 971.5 | 380 | 647.667 | 253.333 | 0 | Curtain Wall : Merk H09 | 1.01176 | 0.00843336 | 3385 | ISR_HPL Kleur hout | ISR_HPL Kleur hout | Model Group:H09:5145654
5275419 | 00 Begane grond | 760 | 1943 | 1.47668 | 971.5 | 380 | 647.667 | 253.333 | 0 | Curtain Wall : Merk H09 | 1.01176 | 0.00843336 | 3387 | ISR_HPL Kleur hout | ISR_HPL Kleur hout | Model Group:H09:5145678
5275431 | 01 eerste verdieping | 760 | 1943 | 1.47668 | 971.5 | 380 | 647.667 | 253.333 | 1 | Curtain Wall : Merk H09 | 1.01176 | 0.00843336 | 3391 | ISR_HPL Kleur hout | ISR_HPL Kleur hout | Model Group:H09:5167153
5275434 | 01 eerste verdieping | 760 | 1943 | 1.47668 | 971.5 | 380 | 647.667 | 253.333 | 1 | Curtain Wall : Merk H09 | 1.01176 | 0.00843336 | 3411 | ISR_HPL Kleur hout | ISR_HPL Kleur hout | Model Group:H09:5174883
5275437 | 01 eerste verdieping | 760 | 1943 | 1.47668 | 971.5 | 380 | 647.667 | 253.333 | 1 | Curtain Wall : Merk H09 | 1.01176 | 0.00843336 | 3413 | ISR_HPL Kleur hout | ISR_HPL Kleur hout | Model Group:H09:5181878
5275440 | 01 eerste verdieping | 760 | 1943 | 1.47668 | 971.5 | 380 | 647.667 | 253.333 | 1 | Curtain Wall : Merk H09 | 1.01176 | 0.00843336 | 3415 | ISR_HPL Kleur hout | ISR_HPL Kleur hout | Model Group:H09:5184337
5275443 | 01 eerste verdieping | 760 | 1943 | 1.47668 | 971.5 | 380 | 647.667 | 253.333 | 1 | Curtain Wall : Merk H09 | 1.01176 | 0.00843336 | 3417 | ISR_HPL Kleur hout | ISR_HPL Kleur hout | Model Group:H09:5184386
5275446 | 00 Begane grond | 760 | 1943 | 1.47668 | 971.5 | 380 | 647.667 | 253.333 | 0 | Curtain Wall : Merk H09 | 1.01176 | 0.00843336 | 3419 | ISR_HPL Kleur hout | ISR_HPL Kleur hout | Model Group:H09:5203601
5275452 | 00 Begane grond | 760 | 1943 | 1.47668 | 971.5 | 380 | 647.667 | 253.333 | 0 | Curtain Wall : Merk H09 | 1.01176 | 0.00843336 | 3421 | ISR_HPL Kleur hout | ISR_HPL Kleur hout | Model Group:H09:5206741
5275547 | 00 Begane grond | 753 | 1943 | 1.46308 | 971.5 | 376.5 | 647.667 | 251 | 0 | Curtain Wall : Merk H14 | 1.00915 | 0.00841152 | 3423 | ISR_HPL Kleur hout | ISR_HPL Kleur hout | Model Group:H06:5143935
5275606 | 00 Begane grond | 753 | 1943 | 1.46308 | 971.5 | 376.5 | 647.667 | 251 | 0 | Curtain Wall : Merk H14 | 1.00915 | 0.00841152 | 3425 | ISR_HPL Kleur hout | HPL F7853 ocean gray | Model Group:H06:5143935
5275805 | 00 Begane grond | 760 | 1943 | 1.47668 | 971.5 | 380 | 647.667 | 253.333 | 0 | Curtain Wall : Merk H03 | 1.01176 | 0.00843336 | 3427 | HPL F7853 ocean gray | HPL F7853 ocean gray | Model Group:H03:5131933
5275911 | 01 eerste verdieping | 760 | 1943 | 1.47668 | 971.5 | 380 | 647.667 | 253.333 | 1 | Curtain Wall : Merk H03 | 1.01176 | 0.00843336 | 3354 | HPL F7853 ocean gray | HPL F7853 ocean gray | Model Group:H03:5179821
5275914 | 01 eerste verdieping | 760 | 1943 | 1.47668 | 971.5 | 380 | 647.667 | 253.333 | 1 | Curtain Wall : Merk H18 | 1.01176 | 0.00843336 | 3369 | HPL F7853 ocean gray | HPL F7853 ocean gray | Model Group:H18:5185791
5276053 | 01 eerste verdieping | 683 | 1943 | 1.32707 | 971.5 | 341.5 | 647.667 | 227.667 | 1 | Curtain Wall : Merk H07 | 0.983112 | 0.00819312 | 3429 | HPL F7853 ocean gray | HPL F7853 ocean gray | Model Group:H07:5227238
5276112 | 01 eerste verdieping | 683 | 1943 | 1.32707 | 971.5 | 341.5 | 647.667 | 227.667 | 1 | Curtain Wall : Merk H07 | 0.983112 | 0.00819312 | 3431 | HPL F7853 ocean gray | HPL F7853 ocean gray | Model Group:H07:5227238
5276197 | 00 Begane grond | 683 | 1943 | 1.32707 | 971.5 | 341.5 | 647.667 | 227.667 | 0 | Curtain Wall : Merk H07 | 0.983112 | 0.00819312 | 3433 | HPL F7853 ocean gray | HPL F7853 ocean gray | Model Group:H07:5144116
5276199 | 00 Begane grond | 683 | 1943 | 1.32707 | 971.5 | 341.5 | 647.667 | 227.667 | 0 | Curtain Wall : Merk H07 | 0.983112 | 0.00819312 | 3435 | HPL F7853 ocean gray | HPL F7853 ocean gray | Model Group:H07:5144116
5276207 | 00 Begane grond | 683 | 1943 | 1.32707 | 971.5 | 341.5 | 647.667 | 227.667 | 0 | Curtain Wall : Merk H07 | 0.983112 | 0.00819312 | 3437 | HPL F7853 ocean gray | HPL F7853 ocean gray | Model Group:H07:5145183
5276209 | 00 Begane grond | 683 | 1943 | 1.32707 | 971.5 | 341.5 | 647.667 | 227.667 | 0 | Curtain Wall : Merk H07 | 0.983112 | 0.00819312 | 3439 | HPL F7853 ocean gray | HPL F7853 ocean gray | Model Group:H07:5145183
5276212 | 01 eerste verdieping | 683 | 1943 | 1.32707 | 971.5 | 341.5 | 647.667 | 227.667 | 1 | Curtain Wall : Merk H07 | 0.983112 | 0.00819312 | 3441 | HPL F7853 ocean gray | HPL F7853 ocean gray | Model Group:H07:5227264
5276214 | 01 eerste verdieping | 683 | 1943 | 1.32707 | 971.5 | 341.5 | 647.667 | 227.667 | 1 | Curtain Wall : Merk H07 | 0.983112 | 0.00819312 | 3443 | HPL F7853 ocean gray | HPL F7853 ocean gray | Model Group:H07:5227264
5276352 | 01 eerste verdieping | 660 | 1943 | 1.28238 | 971.5 | 330 | 647.667 | 220 | 1 | Curtain Wall : Merk H16 | 0.974556 | 0.00812136 | 3445 | HPL F7853 ocean gray | HPL F7853 ocean gray | Model Group:H16:5227244
5276459 | 00 Begane grond | 660 | 1943 | 1.28238 | 971.5 | 330 | 647.667 | 220 | 0 | Curtain Wall : Merk H16 | 0.974556 | 0.00812136 | 3449 | HPL F7853 ocean gray | HPL F7853 ocean gray | Model Group:H16:5197611
5276566 | 00 Begane grond | 660 | 1943 | 1.28238 | 971.5 | 330 | 647.667 | 220 | 0 | Curtain Wall : Merk H16 | 0.974556 | 0.00812136 | 3451 | HPL F7853 ocean gray | HPL F7853 ocean gray | Model Group:H16:5195722
5276575 | 00 Begane grond | 660 | 1943 | 1.28238 | 971.5 | 330 | 647.667 | 220 | 0 | Curtain Wall : Merk H16 | 0.974556 | 0.00812136 | 3453 | HPL F7853 ocean gray | HPL F7853 ocean gray | Model Group:H16:5197451
5465840 | 00 Begane grond | 760 | 1943 | 1.47668 | 971.5 | 380 | 647.667 | 253.333 | 0 | Curtain Wall : Merk H03 | 1.01176 | 0.00843336 | 522 | HPL F7853 ocean gray | HPL F7853 ocean gray | Model Group:H03:5465827
5533714 | 01 eerste verdieping | 660 | 1943 | 1.28238 | 971.5 | 330 | 647.667 | 220 | 1 | Curtain Wall : Merk H11 | 0.974556 | 0.00812136 | 493 | HPL F7853 ocean gray | HPL F7853 ocean gray | Model Group:H11:5533699
5533716 | 01 eerste verdieping | 660 | 1943 | 1.28238 | 971.5 | 330 | 647.667 | 220 | 1 | Curtain Wall : Merk H11 | 0.974556 | 0.00812136 | 501 | HPL F7853 ocean gray | HPL F7853 ocean gray | Model Group:H11:5533699
5536867 | 00 Begane grond | 790 | 2330 | 1.8407 | 1165 | 395 | 776.667 | 263.333 | 0 | Curtain Wall : K_03 | 1.16688 | 0.0097344 | 3498 | ISR_Kunststof_RAL7006 | ISR_Kunststof_RAL7006 | Model Group:Merk K03:5536856
5536869 | 00 Begane grond | 790 | 2330 | 1.8407 | 1165 | 395 | 776.667 | 263.333 | 0 | Curtain Wall : K_03 | 1.16688 | 0.0097344 | 3500 | ISR_Kunststof_RAL7006 | ISR_Kunststof_RAL7006 | Model Group:Merk K03:5536856
5536939 | 00 Begane grond | 790 | 2330 | 1.8407 | 1165 | 395 | 776.667 | 263.333 | 0 | Curtain Wall : K_03 | 1.16688 | 0.0097344 | 3521 | ISR_Kunststof_RAL7006 | ISR_Kunststof_RAL7006 | Model Group:Merk K03:5536928
5536941 | 00 Begane grond | 790 | 2330 | 1.8407 | 1165 | 395 | 776.667 | 263.333 | 0 | Curtain Wall : K_03 | 1.16688 | 0.0097344 | 3523 | ISR_Kunststof_RAL7006 | ISR_Kunststof_RAL7006 | Model Group:Merk K03:5536928
5537049 | 00 Begane grond | 810 | 2330 | 1.8873 | 1165 | 405 | 776.667 | 270 | 0 | Curtain Wall : K_05 | 1.17432 | 0.0097968 | 3531 | ISR_Kunststof_RAL7006 | ISR_Kunststof_RAL7006 | Model Group:Merk K05:5537042
5537090 | 00 Begane grond | 790 | 2330 | 1.8407 | 1165 | 395 | 776.667 | 263.333 | 0 | Curtain Wall : K_03 | 1.16688 | 0.0097344 | 3537 | ISR_Kunststof_RAL7006 | ISR_Kunststof_RAL7006 | Model Group:Merk K03:5537079
5537092 | 00 Begane grond | 790 | 2330 | 1.8407 | 1165 | 395 | 776.667 | 263.333 | 0 | Curtain Wall : K_03 | 1.16688 | 0.0097344 | 3539 | ISR_Kunststof_RAL7006 | ISR_Kunststof_RAL7006 | Model Group:Merk K03:5537079
5537553 | 00 Begane grond | 725 | 2258 | 1.63705 | 1129 | 362.5 | 752.667 | 241.667 | 0 | Curtain Wall : K_15 | 1.11592 | 0.00930696 | 3636 | ISR_Kunststof_RAL7006 | ISR_Kunststof_RAL7006 | Model Group:Merk K15:5537536
5537555 | 00 Begane grond | 799 | 2258 | 1.80414 | 1129 | 399.5 | 752.667 | 266.333 | 0 | Curtain Wall : K_15 | 1.14344 | 0.00953784 | 3638 | ISR_Kunststof_RAL7006 | ISR_Kunststof_RAL7006 | Model Group:Merk K15:5537536
5538773 | 00 Begane grond | 790 | 2330 | 1.8407 | 1165 | 395 | 776.667 | 263.333 | 0 | Curtain Wall : K_03 | 1.16688 | 0.0097344 | 3834 | ISR_Kunststof_RAL7006 | ISR_Kunststof_RAL7006 | Model Group:Merk K03:5538762
5538775 | 00 Begane grond | 790 | 2330 | 1.8407 | 1165 | 395 | 776.667 | 263.333 | 0 | Curtain Wall : K_03 | 1.16688 | 0.0097344 | 3836 | ISR_Kunststof_RAL7006 | ISR_Kunststof_RAL7006 | Model Group:Merk K03:5538762
5538791 | 00 Begane grond | 790 | 2330 | 1.8407 | 1165 | 395 | 776.667 | 263.333 | 0 | Curtain Wall : K_03 | 1.16688 | 0.0097344 | 3838 | ISR_Kunststof_RAL7006 | ISR_Kunststof_RAL7006 | Model Group:Merk K03:5538780
5538793 | 00 Begane grond | 790 | 2330 | 1.8407 | 1165 | 395 | 776.667 | 263.333 | 0 | Curtain Wall : K_03 | 1.16688 | 0.0097344 | 3840 | ISR_Kunststof_RAL7006 | ISR_Kunststof_RAL7006 | Model Group:Merk K03:5538780
5538809 | 00 Begane grond | 790 | 2330 | 1.8407 | 1165 | 395 | 776.667 | 263.333 | 0 | Curtain Wall : K_03 | 1.16688 | 0.0097344 | 3842 | ISR_Kunststof_RAL7006 | ISR_Kunststof_RAL7006 | Model Group:Merk K03:5538798
5538811 | 00 Begane grond | 790 | 2330 | 1.8407 | 1165 | 395 | 776.667 | 263.333 | 0 | Curtain Wall : K_03 | 1.16688 | 0.0097344 | 3844 | ISR_Kunststof_RAL7006 | ISR_Kunststof_RAL7006 | Model Group:Merk K03:5538798
5539085 | 00 Begane grond | 685 | 2350 | 1.60975 | 1175 | 342.5 | 783.333 | 228.333 | 0 | Curtain Wall : K_20 | 1.13526 | 0.0094692 | 3914 | ISR_Kunststof_RAL7006 | ISR_Kunststof_RAL7006 | Model Group:Merk K20:5539074
5539087 | 00 Begane grond | 685 | 2350 | 1.60975 | 1175 | 342.5 | 783.333 | 228.333 | 0 | Curtain Wall : K_20 | 1.13526 | 0.0094692 | 3916 | ISR_Kunststof_RAL7006 | ISR_Kunststof_RAL7006 | Model Group:Merk K20:5539074
5922865 | 00 Begane grond | 630.5 | 1943 | 1.22506 | 971.5 | 315.25 | 647.667 | 210.167 | 0 | Curtain Wall : Merk H14 | 0.963582 | 0.00802932 | 1093 | HPL F7853 ocean gray | HPL F7853 ocean gray | Model Group:H14:5143401
5922939 | 00 Begane grond | 630.5 | 1943 | 1.22506 | 971.5 | 315.25 | 647.667 | 210.167 | 0 | Curtain Wall : Merk H14 | 0.963582 | 0.00802932 | 1104 | HPL F7853 ocean gray | HPL F7853 ocean gray | Model Group:H14:5143401
5988184 | 01 eerste verdieping | 760 | 1943 | 1.47668 | 971.5 | 380 | 647.667 | 253.333 | 1 | Curtain Wall : Merk H09 | 1.01176 | 0.00843336 | 3511 | ISR_HPL Kleur hout | ISR_HPL Kleur hout | Model Group:H09:5988145
5995287 | 01 eerste verdieping | 683 | 1943 | 1.32707 | 971.5 | 341.5 | 647.667 | 227.667 | 1 | Curtain Wall : Merk H07 | 0.983112 | 0.00819312 | 3546 | HPL F7853 ocean gray | HPL F7853 ocean gray | Model Group:H07:5995281
5995289 | 01 eerste verdieping | 683 | 1943 | 1.32707 | 971.5 | 341.5 | 647.667 | 227.667 | 1 | Curtain Wall : Merk H07 | 0.983112 | 0.00819312 | 3548 | HPL F7853 ocean gray | HPL F7853 ocean gray | Model Group:H07:5995281
6241474 | 00 Begane grond | 760 | 1920 | 1.4592 | 960 | 380 | 640 | 253.333 | 0 | Curtain Wall : Merk H04 | 1.0032 | 0.0083616 | 3459 | ISR_HPL Kleur hout | ISR_HPL Kleur hout | Model Group:H04:6241461
6382290 | 01 eerste verdieping | 660 | 1943 | 1.28238 | 971.5 | 330 | 647.667 | 220 | 1 | Curtain Wall : Merk H16 | 0.974556 | 0.00812136 | 3466 | HPL F7853 ocean gray | HPL F7853 ocean gray | Model Group:H16:5185909
6604038 | 00 Begane grond | 760 | 1943 | 1.47668 | 971.5 | 380 | 647.667 | 253.333 | 0 | Curtain Wall : Merk H18 | 1.01176 | 0.00843336 | 530 | HPL F7853 ocean gray | HPL F7853 ocean gray | Model Group:H18:5129917
6668708 | 00 Begane grond | 760 | 1943 | 1.47668 | 971.5 | 380 | 647.667 | 253.333 | 0 | Curtain Wall : Merk H09 | 1.01176 | 0.00843336 | 3331 | ISR_HPL Kleur hout | ISR_HPL Kleur hout | Model Group:H09:6668701
6703051 | 00 Begane grond | 810 | 2330 | 1.8873 | 1165 | 405 | 776.667 | 270 | 0 | Curtain Wall : K_05 | 1.17432 | 0.0097968 | 3192 | ISR_Kunststof_RAL7006 | ISR_Kunststof_RAL7006 | Model Group:Merk K05:6703044
6800008 | 00 Begane grond | 660 | 1943 | 1.28238 | 971.5 | 330 | 647.667 | 220 | 0 | Curtain Wall : Merk H16 | 0.974556 | 0.00812136 | 3316 | HPL F7853 ocean gray | HPL F7853 ocean gray | Model Group:H16:5145073
6800240 | 01 eerste verdieping | 660 | 1943 | 1.28238 | 971.5 | 330 | 647.667 | 220 | 1 | Curtain Wall : Merk H16 | 0.974556 | 0.00812136 | 3326 | HPL F7853 ocean gray | HPL F7853 ocean gray | Model Group:H16:5987797
6800249 | 01 eerste verdieping | 660 | 1943 | 1.28238 | 971.5 | 330 | 647.667 | 220 | 1 | Curtain Wall : Merk H16 | 0.974556 | 0.00812136 | 3328 | HPL F7853 ocean gray | HPL F7853 ocean gray | Model Group:H16:5995318
6801742 | 00 Begane grond | 660 | 1943 | 1.28238 | 971.5 | 330 | 647.667 | 220 | 0 | Curtain Wall : Merk H16 | 0.974556 | 0.00812136 | 3342 | HPL F7853 ocean gray | HPL F7853 ocean gray | Model Group:H16:5130407
6801785 | 00 Begane grond | 660 | 1943 | 1.28238 | 971.5 | 330 | 647.667 | 220 | 0 | Curtain Wall : Merk H16 | 0.974556 | 0.00812136 | 3344 | HPL F7853 ocean gray | HPL F7853 ocean gray | Model Group:H16:5127086
6802020 | 01 eerste verdieping | 660 | 1943 | 1.28238 | 971.5 | 330 | 647.667 | 220 | 1 | Curtain Wall : Merk H16 | 0.974556 | 0.00812136 | 3366 | HPL F7853 ocean gray | HPL F7853 ocean gray | Model Group:H16:5987147
6802183 | 01 eerste verdieping | 660 | 1943 | 1.28238 | 971.5 | 330 | 647.667 | 220 | 1 | Curtain Wall : Merk H16 | 0.974556 | 0.00812136 | 3375 | HPL F7853 ocean gray | HPL F7853 ocean gray | Model Group:H16:5987156
6802224 | 01 eerste verdieping | 660 | 1943 | 1.28238 | 971.5 | 330 | 647.667 | 220 | 1 | Curtain Wall : Merk H16 | 0.974556 | 0.00812136 | 3377 | HPL F7853 ocean gray | HPL F7853 ocean gray | Model Group:H16:5179182

# IfcWindow: WI_subvak1:glas 4 (179)
Type - ParameterTakesPrecedence: no; Sizeable: no; Material: glas_enscape
Type - Other - Category: Windows; Family Name: WI_subvak1
Type - Dimensions - decoratie_breedte: 30 mm; decoratie_diepte: 10 mm; Thickness: 24 mm; VentilationHeight: 0 mm
Type - General - VentilationType: ventilatierooster1 : Type 1
Type - Identity Data - Assembly Code: 31.11; Assembly Description: buitenwandopeningen; niet gevuld, daglichtopeningen; Description: enkel glas + rooster; Manufacturer: ITANNEX; Model: 10-07-2014; Type Comments: subvakken; Type Name: glas 4; URL: www.bimvoorfabrikanten.nl; Workset: Family : Windows : WI_subvak1
Type - Materials and Finishes - FinishExteriorMaterial: glas_enscape
Type - Analytical Properties - Define Thermal Properties by: Schematic Type; Analytic Construction: <None>
Type - Pset_ManufacturerTypeInformation - Manufacturer: ITANNEX
Type - Pset_ProductRequirements - Category: Windows
Type - Pset_WindowCommon - IsExternal: no
OverallHeight: 609.929 mm; Classification: 31.11 Uniformat (Uniformat)
Pset_QuantityTakeOff - Reference: glas 4
Pset_WindowCommon - Reference: glas 4
Pset_Window - Omschrijving: enkel glas + rooster; NL-sfb-Codering: 31.11
Pset_DAT_KMS - Assembly Code: 31.11; Assembly Description: buitenwandopeningen; niet gevuld, daglichtopeningen; Description: enkel glas + rooster
Other - WBDBO 30: no; CalcHorMultiple: no; CalcHorSingle: no; CalcVentilationHeight: 80 mm; CalcVertMultiple: no; CalcVertSingle: no; Family: WI_subvak1; Family and Type: WI_subvak1: glas 4; SubPanel_1_h_Calc: 2; SubPanel_1_v_Calc: 2; Type: glas 4; Type Id: 4339171; Ventilation: no
Model Properties - correctie_roede_hor: 0 mm; correctie_roede_ver: 0 mm; shift_roede_hor: 0 mm; shift_roede_ver: 0 mm; subpaneel_1_roedes_hor: 0; subpaneel_1_roedes_ver: 0
Constraints - Moves With Nearby Elements: no; Offset from Host: 0 mm
Fire Protection - WBDO_30_1on_0off: 0
Identity Data - Workset: Bouwkundig
Phasing - Phase Created: 2. nieuwbouw
Name (WI_subvak1:glas 4:...) | In | OverallWidth (mm) = BaseQuantities, Width (mm) = Rough Width (mm) = Dimensions, Width (mm) | BaseQuantities, Height (mm) = subpaneel_1_hoogte (mm) = Dimensions, Height (mm) = Rough Height (mm) | BaseQuantities, Area (m2) | calc_mid_hor (mm) | calc_mid_ver (mm) | CalcEndHor (mm) = CalcStartHor (mm) | CalcEndVert (mm) = CalcStartVert (mm) | Level | Host | Dimensions, Area (m2) | Volume (m3) | Mark | FrameExteriorMaterial = FrameInteriorMaterial | Group
5130955 | 00 Begane grond | 555 | 2210 | 1.22655 | 1105 | 277.5 | 736.667 | 185 | 0 | Curtain Wall : Merk H04 | 0.6672 | 0.004977 | 3273 | HPL F7853 ocean gray | Model Group:H04:5130948
5131653 | 00 Begane grond | 555 | 2210 | 1.22655 | 1105 | 277.5 | 736.667 | 185 | 0 | Curtain Wall : Merk H04 | 0.6672 | 0.004977 | 3256 | HPL F7853 ocean gray | Model Group:H04:5131646
5131940 | 00 Begane grond | 246 | 2256 | 0.554976 | 1128 | 123 | 752 | 82 | 0 | Curtain Wall : Merk H03 | 0.60408 | 0.0045036 | 3276 | HPL F7853 ocean gray | Model Group:H03:5131933
5145327 | 00 Begane grond | 2576 | 466 | 1.20042 | 233 | 1288 | 155.333 | 858.667 | 0 | Curtain Wall : Merk H08 | 0.73368 | 0.0054756 | 2724 | HPL F7853 ocean gray | Model Group:H08:5145320
5145669 | 00 Begane grond | 2576 | 466 | 1.20042 | 233 | 1288 | 155.333 | 858.667 | 0 | Curtain Wall : Merk H08 | 0.73368 | 0.0054756 | 3283 | HPL F7853 ocean gray | Model Group:H08:5145662
5145693 | 00 Begane grond | 2576 | 466 | 1.20042 | 233 | 1288 | 155.333 | 858.667 | 0 | Curtain Wall : Merk H08 | 0.73368 | 0.0054756 | 3286 | HPL F7853 ocean gray | Model Group:H08:5145686
5160781 | 00 Begane grond | 574.25 | 2256 | 1.29551 | 1128 | 287.125 | 752 | 191.417 | 0 | Curtain Wall : Merk H10 | 0.68286 | 0.00509445 | 2697 | HPL F7853 ocean gray | Model Group:H10:5151852
5161595 | 00 Begane grond | 571.75 | 2256 | 1.28987 | 1128 | 285.875 | 752 | 190.583 | 0 | Curtain Wall : Merk H10 | 0.68226 | 0.00508995 | 2707 | HPL F7853 ocean gray | Model Group:H10:5151852
5174072 | 00 Begane grond | 466 | 1056 | 0.492096 | 528 | 233 | 352 | 155.333 | 0 | Curtain Wall : Merk H05 | 0.36888 | 0.0027396 | 3300 | HPL F7853 ocean gray | Model Group:H05:5174065
5174272 | 00 Begane grond | 466 | 1056 | 0.492096 | 528 | 233 | 352 | 155.333 | 0 | Curtain Wall : Merk H05 | 0.36888 | 0.0027396 | 3302 | HPL F7853 ocean gray | Model Group:H05:5174265
5174292 | 00 Begane grond | 466 | 1056 | 0.492096 | 528 | 233 | 352 | 155.333 | 0 | Curtain Wall : Merk H05 | 0.36888 | 0.0027396 | 3304 | HPL F7853 ocean gray | Model Group:H05:5174285
5174302 | 01 eerste verdieping | 466 | 1056 | 0.492096 | 528 | 233 | 352 | 155.333 | 1 | Curtain Wall : Merk H05 | 0.36888 | 0.0027396 | 3306 | HPL F7853 ocean gray | Model Group:H05:5174295
5174312 | 01 eerste verdieping | 466 | 1056 | 0.492096 | 528 | 233 | 352 | 155.333 | 1 | Curtain Wall : Merk H05 | 0.36888 | 0.0027396 | 3308 | HPL F7853 ocean gray | Model Group:H05:5174305
5174322 | 01 eerste verdieping | 466 | 1056 | 0.492096 | 528 | 233 | 352 | 155.333 | 1 | Curtain Wall : Merk H05 | 0.36888 | 0.0027396 | 3310 | HPL F7853 ocean gray | Model Group:H05:5174315
5174568 | 01 eerste verdieping | 466 | 1056 | 0.492096 | 528 | 233 | 352 | 155.333 | 1 | Curtain Wall : Merk H05 | 0.36888 | 0.0027396 | 3318 | HPL F7853 ocean gray | Model Group:H05:5174561
5178258 | 01 eerste verdieping | 466 | 1056 | 0.492096 | 528 | 233 | 352 | 155.333 | 1 | Curtain Wall : Merk H05 | 0.36888 | 0.0027396 | 3298 | HPL F7853 ocean gray | Model Group:H05:5178251
5179828 | 01 eerste verdieping | 246 | 2256 | 0.554976 | 1128 | 123 | 752 | 82 | 1 | Curtain Wall : Merk H03 | 0.60408 | 0.0045036 | 3353 | HPL F7853 ocean gray | Model Group:H03:5179821
5181886 | 01 eerste verdieping | 2576 | 466 | 1.20042 | 233 | 1288 | 155.333 | 858.667 | 1 | Curtain Wall : Merk H08 | 0.73368 | 0.0054756 | 3290 | HPL F7853 ocean gray | Model Group:H08:5181879
5184345 | 01 eerste verdieping | 2576 | 466 | 1.20042 | 233 | 1288 | 155.333 | 858.667 | 1 | Curtain Wall : Merk H08 | 0.73368 | 0.0054756 | 3311 | HPL F7853 ocean gray | Model Group:H08:5184338
5184394 | 01 eerste verdieping | 2576 | 466 | 1.20042 | 233 | 1288 | 155.333 | 858.667 | 1 | Curtain Wall : Merk H08 | 0.73368 | 0.0054756 | 3330 | HPL F7853 ocean gray | Model Group:H08:5184387
5185198 | 01 eerste verdieping | 2071 | 466 | 0.965086 | 233 | 1035.5 | 155.333 | 690.333 | 1 | Curtain Wall : Merk H13 | 0.61248 | 0.0045666 | 3292 | HPL F7853 ocean gray | Model Group:H13:5167154
5185261 | 01 eerste verdieping | 2071 | 466 | 0.965086 | 233 | 1035.5 | 155.333 | 690.333 | 1 | Curtain Wall : Merk H13 | 0.61248 | 0.0045666 | 3336 | HPL F7853 ocean gray | Model Group:H13:5167013
5185269 | 01 eerste verdieping | 2071 | 466 | 0.965086 | 233 | 1035.5 | 155.333 | 690.333 | 1 | Curtain Wall : Merk H13 | 0.61248 | 0.0045666 | 3349 | HPL F7853 ocean gray | Model Group:H13:5174884
5185283 | 01 eerste verdieping | 2071 | 466 | 0.965086 | 233 | 1035.5 | 155.333 | 690.333 | 1 | Curtain Wall : Merk H13 | 0.61248 | 0.0045666 | 3351 | HPL F7853 ocean gray | Model Group:H13:5184708
5185376 | 01 eerste verdieping | 466 | 1056 | 0.492096 | 528 | 233 | 352 | 155.333 | 1 | Curtain Wall : Merk H05 | 0.36888 | 0.0027396 | 3356 | HPL F7853 ocean gray | Model Group:H05:5185369
5185417 | 01 eerste verdieping | 466 | 1056 | 0.492096 | 528 | 233 | 352 | 155.333 | 1 | Curtain Wall : Merk H05 | 0.36888 | 0.0027396 | 3358 | HPL F7853 ocean gray | Model Group:H05:5185410
5185798 | 01 eerste verdieping | 376 | 2256 | 0.848256 | 1128 | 188 | 752 | 125.333 | 1 | Curtain Wall : Merk H18 | 0.63528 | 0.0047376 | 3360 | HPL F7853 ocean gray | Model Group:H18:5185791
5194915 | 01 eerste verdieping | 574.25 | 3056 | 1.75491 | 1528 | 287.125 | 1018.67 | 191.417 | 1 | Curtain Wall : Merk H12 | 0.87486 | 0.00653445 | 3394 | HPL F7853 ocean gray | Model Group:H12:5194912
5194923 | 01 eerste verdieping | 581.75 | 3056 | 1.77783 | 1528 | 290.875 | 1018.67 | 193.917 | 1 | Curtain Wall : Merk H12 | 0.87666 | 0.00654795 | 3396 | HPL F7853 ocean gray | Model Group:H12:5194912
5194944 | 01 eerste verdieping | 903.75 | 710 | 0.641662 | 355 | 451.875 | 236.667 | 301.25 | 1 | Curtain Wall : Merk H12 | 0.3909 | 0.00290475 | 3407 | HPL F7853 ocean gray | Model Group:H12:5194912
5194945 | 01 eerste verdieping | 896.25 | 710 | 0.636337 | 355 | 448.125 | 236.667 | 298.75 | 1 | Curtain Wall : Merk H12 | 0.3891 | 0.00289125 | 3408 | HPL F7853 ocean gray | Model Group:H12:5194912
5196990 | 00 Begane grond | 466 | 1056 | 0.492096 | 528 | 233 | 352 | 155.333 | 0 | Curtain Wall : Merk H05 | 0.36888 | 0.0027396 | 3280 | HPL F7853 ocean gray | Model Group:H05:5196983
5197467 | 00 Begane grond | 466 | 1056 | 0.492096 | 528 | 233 | 352 | 155.333 | 0 | Curtain Wall : Merk H05 | 0.36888 | 0.0027396 | 3208 | HPL F7853 ocean gray | Model Group:H05:5197461
5197627 | 00 Begane grond | 466 | 1056 | 0.492096 | 528 | 233 | 352 | 155.333 | 0 | Curtain Wall : Merk H05 | 0.36888 | 0.0027396 | 3215 | HPL F7853 ocean gray | Model Group:H05:5197621
5203609 | 00 Begane grond | 2576 | 466 | 1.20042 | 233 | 1288 | 155.333 | 858.667 | 0 | Curtain Wall : Merk H08 | 0.73368 | 0.0054756 | 3368 | HPL F7853 ocean gray | Model Group:H08:5203602
5259392 | 00 Begane grond | 416 | 1056 | 0.439296 | 528 | 208 | 352 | 138.667 | 0 | Curtain Wall : Merk H17 | 0.35688 | 0.0026496 | 2719 | HPL F7853 ocean gray | Model Group:H17:5259385
5270217 | 00 Begane grond | 2266 | 466 | 1.05596 | 233 | 1133 | 155.333 | 755.333 | 0 | Curtain Wall : Merk H15 | 0.65928 | 0.0049176 | 2738 | HPL F7853 ocean gray | Model Group:H15:5270210
5271085 | 00 Begane grond | 2266 | 466 | 1.05596 | 233 | 1133 | 155.333 | 755.333 | 0 | Curtain Wall : Merk H15 | 0.65928 | 0.0049176 | 3284 | HPL F7853 ocean gray | Model Group:H15:5271078
5274123 | 01 eerste verdieping | 2071 | 466 | 0.965086 | 233 | 1035.5 | 155.333 | 690.333 | 1 | Curtain Wall : Merk H13 | 0.61248 | 0.0045666 | 3372 | HPL F7853 ocean gray | Model Group:H13:5274116
5465834 | 00 Begane grond | 246 | 2256 | 0.554976 | 1128 | 123 | 752 | 82 | 0 | Curtain Wall : Merk H03 | 0.60408 | 0.0045036 | 519 | HPL F7853 ocean gray | Model Group:H03:5465827
5533702 | 01 eerste verdieping | 428 | 3056 | 1.30797 | 1528 | 214 | 1018.67 | 142.667 | 1 | Curtain Wall : Merk H11 | 0.83976 | 0.0062712 | 489 | HPL F7853 ocean gray | Model Group:H11:5533699
5533710 | 01 eerste verdieping | 428 | 3056 | 1.30797 | 1528 | 214 | 1018.67 | 142.667 | 1 | Curtain Wall : Merk H11 | 0.83976 | 0.0062712 | 491 | HPL F7853 ocean gray | Model Group:H11:5533699
5533731 | 01 eerste verdieping | 1800 | 710 | 1.278 | 355 | 900 | 236.667 | 600 | 1 | Curtain Wall : Merk H11 | 0.606 | 0.004518 | 516 | HPL F7853 ocean gray | Model Group:H11:5533699
5536837 | 00 Begane grond | 540 | 2410 | 1.3014 | 1205 | 270 | 803.333 | 180 | 0 | Curtain Wall : K_04 | 0.7116 | 0.00531 | 3493 | ISR_Aluminium | Model Group:Merk K04:5536830
5536845 | 00 Begane grond | 540 | 2410 | 1.3014 | 1205 | 270 | 803.333 | 180 | 0 | Curtain Wall : K_04 | 0.7116 | 0.00531 | 3495 | ISR_Aluminium | Model Group:Merk K04:5536838
5536853 | 00 Begane grond | 540 | 2410 | 1.3014 | 1205 | 270 | 803.333 | 180 | 0 | Curtain Wall : K_04 | 0.7116 | 0.00531 | 3497 | ISR_Aluminium | Model Group:Merk K04:5536846
5536886 | 00 Begane grond | 1920 | 2410 | 4.6272 | 1205 | 960 | 803.333 | 640 | 0 | Curtain Wall : K_02 | 1.0428 | 0.007794 | 3504 | ISR_Aluminium | Model Group:Merk K02:5536879
5536911 | 00 Begane grond | 1920 | 2410 | 4.6272 | 1205 | 960 | 803.333 | 640 | 0 | Curtain Wall : K_02 | 1.0428 | 0.007794 | 3516 | ISR_Aluminium | Model Group:Merk K02:5536904
5536925 | 00 Begane grond | 720 | 2410 | 1.7352 | 1205 | 360 | 803.333 | 240 | 0 | Curtain Wall : K_01 | 0.7548 | 0.005634 | 3520 | ISR_Aluminium | Model Group:Merk K01:5536918
5536957 | 00 Begane grond | 720 | 2410 | 1.7352 | 1205 | 360 | 803.333 | 240 | 0 | Curtain Wall : K_01 | 0.7548 | 0.005634 | 3526 | ISR_Aluminium | Model Group:Merk K01:5536950
5536971 | 00 Begane grond | 1665 | 2410 | 4.01265 | 1205 | 832.499 | 803.333 | 555 | 0 | Curtain Wall : K_21 | 0.9816 | 0.007335 | 3528 | ISR_Aluminium | Model Group:Merk K21:5536964
5537037 | 00 Begane grond | 540 | 2410 | 1.3014 | 1205 | 270 | 803.333 | 180 | 0 | Curtain Wall : K_04 | 0.7116 | 0.00531 | 3530 | ISR_Aluminium | Model Group:Merk K04:5537030
5537072 | 00 Begane grond | 540 | 2410 | 1.3014 | 1205 | 270 | 803.333 | 180 | 0 | Curtain Wall : K_04 | 0.7116 | 0.00531 | 3536 | ISR_Aluminium | Model Group:Merk K04:5537065
5537109 | 00 Begane grond | 1920 | 2410 | 4.6272 | 1205 | 960 | 803.333 | 640 | 0 | Curtain Wall : K_02 | 1.0428 | 0.007794 | 3542 | ISR_Aluminium | Model Group:Merk K02:5537102
5537288 | 00 Begane grond | 590 | 1960 | 1.1564 | 980 | 295 | 653.333 | 196.667 | 0 | Curtain Wall : K_06 | 0.6156 | 0.00459 | 3599 | ISR_Aluminium | Model Group:Merk K06:5537281
5537300 | 00 Begane grond | 590 | 1960 | 1.1564 | 980 | 295 | 653.333 | 196.667 | 0 | Curtain Wall : K_06 | 0.6156 | 0.00459 | 3601 | ISR_Aluminium | Model Group:Merk K06:5537293
5537339 | 00 Begane grond | 590 | 1960 | 1.1564 | 980 | 295 | 653.333 | 196.667 | 0 | Curtain Wall : K_06 | 0.6156 | 0.00459 | 3606 | ISR_Aluminium | Model Group:Merk K06:5537332
5537347 | 00 Begane grond | 590 | 1960 | 1.1564 | 980 | 295 | 653.333 | 196.667 | 0 | Curtain Wall : K_06 | 0.6156 | 0.00459 | 3608 | ISR_Aluminium | Model Group:Merk K06:5537340
5537392 | 00 Begane grond | 1930 | 2643 | 5.10099 | 1321.5 | 965 | 881 | 643.333 | 0 | Curtain Wall : K_08 | 1.10112 | 0.0082314 | 3613 | ISR_Aluminium | Model Group:Merk K08:5537385
5537400 | 00 Begane grond | 590 | 2971 | 1.75289 | 1485.5 | 295 | 990.333 | 196.667 | 0 | Curtain Wall : K_09 | 0.85824 | 0.0064098 | 3615 | ISR_Aluminium | Model Group:Merk K09:5537393
5537408 | 00 Begane grond | 590 | 1403 | 0.82777 | 701.5 | 295 | 467.667 | 196.667 | 0 | Curtain Wall : K_10 | 0.48192 | 0.0035874 | 3617 | ISR_Aluminium | Model Group:Merk K10:5537401
5537416 | 00 Begane grond | 590 | 1721 | 1.01539 | 860.5 | 295 | 573.667 | 196.667 | 0 | Curtain Wall : K_11 | 0.55824 | 0.0041598 | 3619 | ISR_Aluminium | Model Group:Merk K11:5537409
5537424 | 00 Begane grond | 590 | 2960 | 1.7464 | 1480 | 295 | 986.667 | 196.667 | 0 | Curtain Wall : K_12 | 0.8556 | 0.00639 | 3621 | ISR_Aluminium | Model Group:Merk K12:5537417
5537432 | 00 Begane grond | 590 | 2335 | 1.37765 | 1167.5 | 295 | 778.333 | 196.667 | 0 | Curtain Wall : K_13 | 0.7056 | 0.005265 | 3623 | ISR_Aluminium | Model Group:Merk K13:5537425
5537532 | 00 Begane grond | 1295 | 2410 | 3.12095 | 1205 | 647.5 | 803.333 | 431.667 | 0 | Curtain Wall : K_14 | 0.8928 | 0.006669 | 3633 | ISR_Aluminium | Model Group:Merk K14:5537525
5537754 | 01 eerste verdieping | 1864 | 1710 | 3.18744 | 855 | 932 | 570 | 621.333 | 1 | Curtain Wall : K_23 | 0.86136 | 0.0064332 | 3660 | ISR_Aluminium | Model Group:Merk K23:5537747
5538265 | 01 eerste verdieping | 945 | 1710 | 1.61595 | 855 | 472.5 | 570 | 315 | 1 | Curtain Wall : K_25 | 0.6408 | 0.004779 | 3746 | ISR_Aluminium | Model Group:Merk K25:5537974
5538534 | 01 eerste verdieping | 1295 | 2540 | 3.2893 | 1270 | 647.5 | 846.667 | 431.667 | 1 | Curtain Wall : K_26 | 0.924 | 0.006903 | 3806 | ISR_Aluminium | Model Group:Merk K26:5538527
5538548 | 01 eerste verdieping | 1051 | 2540 | 2.66954 | 1270 | 525.5 | 846.667 | 350.333 | 1 | Curtain Wall : K_27 | 0.86544 | 0.0064638 | 3810 | ISR_Aluminium | Model Group:Merk K27:5538541
5538691 | 00 Begane grond | 1435 | 2410 | 3.45835 | 1205 | 717.5 | 803.333 | 478.333 | 0 | Curtain Wall : K_18 | 0.9264 | 0.006921 | 3819 | ISR_Aluminium | Model Group:Merk K18:5538684
5538741 | 00 Begane grond | 1920 | 2410 | 4.6272 | 1205 | 960 | 803.333 | 640 | 0 | Curtain Wall : K_02 | 1.0428 | 0.007794 | 3829 | ISR_Aluminium | Model Group:Merk K02:5538734
5538751 | 00 Begane grond | 1920 | 2410 | 4.6272 | 1205 | 960 | 803.333 | 640 | 0 | Curtain Wall : K_02 | 1.0428 | 0.007794 | 3831 | ISR_Aluminium | Model Group:Merk K02:5538744
5538759 | 00 Begane grond | 1920 | 2410 | 4.6272 | 1205 | 960 | 803.333 | 640 | 0 | Curtain Wall : K_02 | 1.0428 | 0.007794 | 3833 | ISR_Aluminium | Model Group:Merk K02:5538752
5539073 | 00 Begane grond | 1090 | 2410 | 2.6269 | 1205 | 545 | 803.333 | 363.333 | 0 | Curtain Wall : k_19 | 0.8436 | 0.0063 | 3913 | ISR_Aluminium | Model Group:Merk K19:5539066
5539202 | 00 Begane grond | 1435 | 2410 | 3.45835 | 1205 | 717.5 | 803.333 | 478.333 | 0 | Curtain Wall : K_18 | 0.9264 | 0.006921 | 3922 | ISR_Aluminium | Model Group:Merk K18:5539194
5539231 | 00 Begane grond | 720 | 2410 | 1.7352 | 1205 | 360 | 803.333 | 240 | 0 | Curtain Wall : K_01 | 0.7548 | 0.005634 | 3927 | ISR_Aluminium | Model Group:Merk K01:5539224
5539240 | 00 Begane grond | 1930 | 2663 | 5.13959 | 1331.5 | 965 | 887.667 | 643.333 | 0 | Curtain Wall : K_08 | 1.10592 | 0.0082674 | 3929 | ISR_Aluminium | Model Group:Merk K08:5537385
5539246 | 00 Begane grond | 590 | 1710 | 1.0089 | 855 | 295 | 570 | 196.667 | 0 | Curtain Wall : K_09 | 0.5556 | 0.00414 | 3931 | ISR_Aluminium | Model Group:Merk K09:5537393
5607703 | 00 Begane grond | 680 | 1710 | 1.1628 | 855 | 340 | 570 | 226.667 | 0 | Curtain Wall : K_16 | 0.5772 | 0.004302 | 915 | ISR_Aluminium | Model Group:Merk K16:5544805
5607809 | 00 Begane grond | 680 | 1710 | 1.1628 | 855 | 340 | 570 | 226.667 | 0 | Curtain Wall : K_16 | 0.5772 | 0.004302 | 4008 | ISR_Aluminium | Model Group:Merk K16:5542460
5607813 | 00 Begane grond | 680 | 1710 | 1.1628 | 855 | 340 | 570 | 226.667 | 0 | Curtain Wall : K_16 | 0.5772 | 0.004302 | 4009 | ISR_Aluminium | Model Group:Merk K16:5544034
5607815 | 00 Begane grond | 680 | 1710 | 1.1628 | 855 | 340 | 570 | 226.667 | 0 | Curtain Wall : K_16 | 0.5772 | 0.004302 | 4015 | ISR_Aluminium | Model Group:Merk K16:5544056
5607817 | 00 Begane grond | 680 | 1710 | 1.1628 | 855 | 340 | 570 | 226.667 | 0 | Curtain Wall : K_16 | 0.5772 | 0.004302 | 4019 | ISR_Aluminium | Model Group:Merk K16:5544107
5607819 | 00 Begane grond | 680 | 1710 | 1.1628 | 855 | 340 | 570 | 226.667 | 0 | Curtain Wall : K_16 | 0.5772 | 0.004302 | 4023 | ISR_Aluminium | Model Group:Merk K16:5544133
5607825 | 00 Begane grond | 680 | 1710 | 1.1628 | 855 | 340 | 570 | 226.667 | 0 | Curtain Wall : K_16 | 0.5772 | 0.004302 | 4067 | ISR_Aluminium | Model Group:Merk K16:5544823
5607827 | 00 Begane grond | 680 | 1710 | 1.1628 | 855 | 340 | 570 | 226.667 | 0 | Curtain Wall : K_16 | 0.5772 | 0.004302 | 4089 | ISR_Aluminium | Model Group:Merk K16:5545034
5607831 | 00 Begane grond | 680 | 1710 | 1.1628 | 855 | 340 | 570 | 226.667 | 0 | Curtain Wall : K_16 | 0.5772 | 0.004302 | 4108 | ISR_Aluminium | Model Group:Merk K16:5552591
5607833 | 00 Begane grond | 680 | 1710 | 1.1628 | 855 | 340 | 570 | 226.667 | 0 | Curtain Wall : K_16 | 0.5772 | 0.004302 | 4111 | ISR_Aluminium | Model Group:Merk K16:5552762
5608019 | 00 Begane grond | 680 | 1710 | 1.1628 | 855 | 340 | 570 | 226.667 | 0 | Curtain Wall : K_17 | 0.5772 | 0.004302 | 4118 | ISR_Aluminium | Model Group:Merk K17:5544294
5608283 | 00 Begane grond | 680 | 1710 | 1.1628 | 855 | 340 | 570 | 226.667 | 0 | Curtain Wall : K_17 | 0.5772 | 0.004302 | 3973 | ISR_Aluminium | Model Group:Merk K17:5540560
5608291 | 00 Begane grond | 680 | 1710 | 1.1628 | 855 | 340 | 570 | 226.667 | 0 | Curtain Wall : K_17 | 0.5772 | 0.004302 | 3979 | ISR_Aluminium | Model Group:Merk K17:5542284
5608295 | 00 Begane grond | 680 | 1710 | 1.1628 | 855 | 340 | 570 | 226.667 | 0 | Curtain Wall : K_17 | 0.5772 | 0.004302 | 3985 | ISR_Aluminium | Model Group:Merk K17:5542310
5608299 | 00 Begane grond | 680 | 1710 | 1.1628 | 855 | 340 | 570 | 226.667 | 0 | Curtain Wall : K_17 | 0.5772 | 0.004302 | 3991 | ISR_Aluminium | Model Group:Merk K17:5542336
5608303 | 00 Begane grond | 680 | 1710 | 1.1628 | 855 | 340 | 570 | 226.667 | 0 | Curtain Wall : K_17 | 0.5772 | 0.004302 | 3997 | ISR_Aluminium | Model Group:Merk K17:5542362
5608307 | 00 Begane grond | 680 | 1710 | 1.1628 | 855 | 340 | 570 | 226.667 | 0 | Curtain Wall : K_17 | 0.5772 | 0.004302 | 4003 | ISR_Aluminium | Model Group:Merk K17:5542388
5608319 | 00 Begane grond | 680 | 1710 | 1.1628 | 855 | 340 | 570 | 226.667 | 0 | Curtain Wall : K_17 | 0.5772 | 0.004302 | 4079 | ISR_Aluminium | Model Group:Merk K17:5544972
5608323 | 00 Begane grond | 680 | 1710 | 1.1628 | 855 | 340 | 570 | 226.667 | 0 | Curtain Wall : K_17 | 0.5772 | 0.004302 | 4085 | ISR_Aluminium | Model Group:Merk K17:5545007
5609358 | 01 eerste verdieping | 590 | 1710 | 1.0089 | 855 | 295 | 570 | 196.667 | 1 | Curtain Wall : K_29 | 0.5556 | 0.00414 | 921 | ISR_Aluminium | Model Group:Merk K29:5538164
5609683 | 01 eerste verdieping | 590 | 1710 | 1.0089 | 855 | 295 | 570 | 196.667 | 1 | Curtain Wall : K_29 | 0.5556 | 0.00414 | 3663 | ISR_Aluminium | Model Group:Merk K29:5537981
5609685 | 01 eerste verdieping | 590 | 1710 | 1.0089 | 855 | 295 | 570 | 196.667 | 1 | Curtain Wall : K_29 | 0.5556 | 0.00414 | 3696 | ISR_Aluminium | Model Group:Merk K29:5538110
5609687 | 01 eerste verdieping | 590 | 1710 | 1.0089 | 855 | 295 | 570 | 196.667 | 1 | Curtain Wall : K_29 | 0.5556 | 0.00414 | 3699 | ISR_Aluminium | Model Group:Merk K29:5538119
5609689 | 01 eerste verdieping | 590 | 1710 | 1.0089 | 855 | 295 | 570 | 196.667 | 1 | Curtain Wall : K_29 | 0.5556 | 0.00414 | 3702 | ISR_Aluminium | Model Group:Merk K29:5538128
5609691 | 01 eerste verdieping | 590 | 1710 | 1.0089 | 855 | 295 | 570 | 196.667 | 1 | Curtain Wall : K_29 | 0.5556 | 0.00414 | 3705 | ISR_Aluminium | Model Group:Merk K29:5538137
5609693 | 01 eerste verdieping | 590 | 1710 | 1.0089 | 855 | 295 | 570 | 196.667 | 1 | Curtain Wall : K_29 | 0.5556 | 0.00414 | 3708 | ISR_Aluminium | Model Group:Merk K29:5538146
5609695 | 01 eerste verdieping | 590 | 1710 | 1.0089 | 855 | 295 | 570 | 196.667 | 1 | Curtain Wall : K_29 | 0.5556 | 0.00414 | 3711 | ISR_Aluminium | Model Group:Merk K29:5538155
5609697 | 01 eerste verdieping | 590 | 1710 | 1.0089 | 855 | 295 | 570 | 196.667 | 1 | Curtain Wall : K_29 | 0.5556 | 0.00414 | 3717 | ISR_Aluminium | Model Group:Merk K29:5538173
5609699 | 01 eerste verdieping | 590 | 1710 | 1.0089 | 855 | 295 | 570 | 196.667 | 1 | Curtain Wall : K_29 | 0.5556 | 0.00414 | 3720 | ISR_Aluminium | Model Group:Merk K29:5538182
5609701 | 01 eerste verdieping | 590 | 1710 | 1.0089 | 855 | 295 | 570 | 196.667 | 1 | Curtain Wall : K_29 | 0.5556 | 0.00414 | 3723 | ISR_Aluminium | Model Group:Merk K29:5538191
5609703 | 01 eerste verdieping | 590 | 1710 | 1.0089 | 855 | 295 | 570 | 196.667 | 1 | Curtain Wall : K_29 | 0.5556 | 0.00414 | 3726 | ISR_Aluminium | Model Group:Merk K29:5538200
5609705 | 01 eerste verdieping | 590 | 1710 | 1.0089 | 855 | 295 | 570 | 196.667 | 1 | Curtain Wall : K_29 | 0.5556 | 0.00414 | 3729 | ISR_Aluminium | Model Group:Merk K29:5538209
5609707 | 01 eerste verdieping | 590 | 1710 | 1.0089 | 855 | 295 | 570 | 196.667 | 1 | Curtain Wall : K_29 | 0.5556 | 0.00414 | 3732 | ISR_Aluminium | Model Group:Merk K29:5538218
5609709 | 01 eerste verdieping | 590 | 1710 | 1.0089 | 855 | 295 | 570 | 196.667 | 1 | Curtain Wall : K_29 | 0.5556 | 0.00414 | 3735 | ISR_Aluminium | Model Group:Merk K29:5538227
5609711 | 01 eerste verdieping | 590 | 1710 | 1.0089 | 855 | 295 | 570 | 196.667 | 1 | Curtain Wall : K_29 | 0.5556 | 0.00414 | 3738 | ISR_Aluminium | Model Group:Merk K29:5538236
5609713 | 01 eerste verdieping | 590 | 1710 | 1.0089 | 855 | 295 | 570 | 196.667 | 1 | Curtain Wall : K_29 | 0.5556 | 0.00414 | 3741 | ISR_Aluminium | Model Group:Merk K29:5538245
5609715 | 01 eerste verdieping | 590 | 1710 | 1.0089 | 855 | 295 | 570 | 196.667 | 1 | Curtain Wall : K_29 | 0.5556 | 0.00414 | 3744 | ISR_Aluminium | Model Group:Merk K29:5538254
5609903 | 01 eerste verdieping | 590 | 1710 | 1.0089 | 855 | 295 | 570 | 196.667 | 1 | Curtain Wall : K_22 | 0.5556 | 0.00414 | 885 | ISR_Aluminium | Model Group:Merk K22:5538022
5610509 | 01 eerste verdieping | 590 | 1710 | 1.0089 | 855 | 295 | 570 | 196.667 | 1 | Curtain Wall : K_22 | 0.5556 | 0.00414 | 3668 | ISR_Aluminium | Model Group:Merk K22:5537990
5610513 | 01 eerste verdieping | 590 | 1710 | 1.0089 | 855 | 295 | 570 | 196.667 | 1 | Curtain Wall : K_22 | 0.5556 | 0.00414 | 3901 | ISR_Aluminium | Model Group:Merk K22:5537998
5610517 | 01 eerste verdieping | 590 | 1710 | 1.0089 | 855 | 295 | 570 | 196.667 | 1 | Curtain Wall : K_22 | 0.5556 | 0.00414 | 3676 | ISR_Aluminium | Model Group:Merk K22:5538006
5610521 | 01 eerste verdieping | 590 | 1710 | 1.0089 | 855 | 295 | 570 | 196.667 | 1 | Curtain Wall : K_22 | 0.5556 | 0.00414 | 3684 | ISR_Aluminium | Model Group:Merk K22:5538014
5610525 | 01 eerste verdieping | 590 | 1710 | 1.0089 | 855 | 295 | 570 | 196.667 | 1 | Curtain Wall : K_22 | 0.5556 | 0.00414 | 3749 | ISR_Aluminium | Model Group:Merk K22:5538030
5610529 | 01 eerste verdieping | 590 | 1710 | 1.0089 | 855 | 295 | 570 | 196.667 | 1 | Curtain Wall : K_22 | 0.5556 | 0.00414 | 3773 | ISR_Aluminium | Model Group:Merk K22:5538038
5610533 | 01 eerste verdieping | 590 | 1710 | 1.0089 | 855 | 295 | 570 | 196.667 | 1 | Curtain Wall : K_22 | 0.5556 | 0.00414 | 3777 | ISR_Aluminium | Model Group:Merk K22:5538046
5610537 | 01 eerste verdieping | 590 | 1710 | 1.0089 | 855 | 295 | 570 | 196.667 | 1 | Curtain Wall : K_22 | 0.5556 | 0.00414 | 3781 | ISR_Aluminium | Model Group:Merk K22:5538054
5610541 | 01 eerste verdieping | 590 | 1710 | 1.0089 | 855 | 295 | 570 | 196.667 | 1 | Curtain Wall : K_22 | 0.5556 | 0.00414 | 3785 | ISR_Aluminium | Model Group:Merk K22:5538062
5610545 | 01 eerste verdieping | 590 | 1710 | 1.0089 | 855 | 295 | 570 | 196.667 | 1 | Curtain Wall : K_22 | 0.5556 | 0.00414 | 3789 | ISR_Aluminium | Model Group:Merk K22:5538070
5610549 | 01 eerste verdieping | 590 | 1710 | 1.0089 | 855 | 295 | 570 | 196.667 | 1 | Curtain Wall : K_22 | 0.5556 | 0.00414 | 3793 | ISR_Aluminium | Model Group:Merk K22:5538078
5610553 | 01 eerste verdieping | 590 | 1710 | 1.0089 | 855 | 295 | 570 | 196.667 | 1 | Curtain Wall : K_22 | 0.5556 | 0.00414 | 3797 | ISR_Aluminium | Model Group:Merk K22:5538086
5610561 | 01 eerste verdieping | 590 | 1710 | 1.0089 | 855 | 295 | 570 | 196.667 | 1 | Curtain Wall : K_32 | 0.5556 | 0.00414 | 3870 | ISR_Aluminium | Model Group:Merk K32:5538102
5610891 | 00 Begane grond | 590 | 1960 | 1.1564 | 980 | 295 | 653.333 | 196.667 | 0 | Curtain Wall : K_06 | 0.6156 | 0.00459 | 944 | ISR_Aluminium | Model Group:Merk K06:5537348
5610915 | 00 Begane grond | 590 | 1960 | 1.1564 | 980 | 295 | 653.333 | 196.667 | 0 | Curtain Wall : K_06 | 0.6156 | 0.00459 | 961 | ISR_Aluminium | Model Group:Merk K06:5537306
5610961 | 00 Begane grond | 590 | 1960 | 1.1564 | 980 | 295 | 653.333 | 196.667 | 0 | Curtain Wall : K_06 | 0.6156 | 0.00459 | 978 | ISR_Aluminium | Model Group:Merk K06:5537485
5611159 | 00 Begane grond | 590 | 1960 | 1.1564 | 980 | 295 | 653.333 | 196.667 | 0 | Curtain Wall : K_07 | 0.6156 | 0.00459 | 982 | ISR_Aluminium | Model Group:Merk K07:5537502
5611358 | 00 Begane grond | 590 | 1960 | 1.1564 | 980 | 295 | 653.333 | 196.667 | 0 | Curtain Wall : K_07 | 0.6156 | 0.00459 | 3692 | ISR_Aluminium | Model Group:Merk K07:5537724
5719806 | 01 eerste verdieping | 2045 | 2540 | 5.1943 | 1270 | 1022.5 | 846.667 | 681.667 | 1 | Curtain Wall : K_27 | 1.104 | 0.008253 | 521 | ISR_Aluminium | Model Group:Merk K27:5538541
5856015 | 00 Begane grond | 680 | 1710 | 1.1628 | 855 | 340 | 570 | 226.667 | 0 | Curtain Wall : K_16 | 0.5772 | 0.004302 | 1059 | ISR_Aluminium | Model Group:Merk K16:5856001
5856016 | 00 Begane grond | 680 | 1710 | 1.1628 | 855 | 340 | 570 | 226.667 | 0 | Curtain Wall : K_16 | 0.5772 | 0.004302 | 1063 | ISR_Aluminium | Model Group:Merk K16:5856008
5856017 | 00 Begane grond | 680 | 1710 | 1.1628 | 855 | 340 | 570 | 226.667 | 0 | Curtain Wall : K_17 | 0.5772 | 0.004302 | 1067 | ISR_Aluminium | Model Group:Merk K17:5855989
5856042 | 00 Begane grond | 680 | 1710 | 1.1628 | 855 | 340 | 570 | 226.667 | 0 | Curtain Wall : K_17 | 0.5772 | 0.004302 | 1078 | ISR_Aluminium | Model Group:Merk K17:5856030
5988170 | 01 eerste verdieping | 2071 | 466 | 0.965086 | 233 | 1035.5 | 155.333 | 690.333 | 1 | Curtain Wall : Merk H13 | 0.61248 | 0.0045666 | 3491 | HPL F7853 ocean gray | Model Group:H13:5988146
5994941 | 01 eerste verdieping | 466 | 1056 | 0.492096 | 528 | 233 | 352 | 155.333 | 1 | Curtain Wall : Merk H05 | 0.36888 | 0.0027396 | 3545 | HPL F7853 ocean gray | Model Group:H05:5994934
6064884 | 01 eerste verdieping | 680 | 1710 | 1.1628 | 855 | 340 | 570 | 226.667 | 1 | Curtain Wall : K_28 | 0.5772 | 0.004302 | 556 | ISR_Aluminium | Model Group:Merk K28:6064868
6064903 | 01 eerste verdieping | 680 | 1710 | 1.1628 | 855 | 340 | 570 | 226.667 | 1 | Curtain Wall : K_28 | 0.5772 | 0.004302 | 1092 | ISR_Aluminium | Model Group:Merk K28:6064887
6064922 | 01 eerste verdieping | 680 | 1710 | 1.1628 | 855 | 340 | 570 | 226.667 | 1 | Curtain Wall : K_28 | 0.5772 | 0.004302 | 1100 | ISR_Aluminium | Model Group:Merk K28:6064906
6064941 | 01 eerste verdieping | 680 | 1710 | 1.1628 | 855 | 340 | 570 | 226.667 | 1 | Curtain Wall : K_28 | 0.5772 | 0.004302 | 1102 | ISR_Aluminium | Model Group:Merk K28:6064925
6064960 | 01 eerste verdieping | 680 | 1710 | 1.1628 | 855 | 340 | 570 | 226.667 | 1 | Curtain Wall : K_28 | 0.5772 | 0.004302 | 1106 | ISR_Aluminium | Model Group:Merk K28:6064944
6064979 | 01 eerste verdieping | 680 | 1710 | 1.1628 | 855 | 340 | 570 | 226.667 | 1 | Curtain Wall : K_28 | 0.5772 | 0.004302 | 1108 | ISR_Aluminium | Model Group:Merk K28:6064963
6064998 | 01 eerste verdieping | 680 | 1710 | 1.1628 | 855 | 340 | 570 | 226.667 | 1 | Curtain Wall : K_28 | 0.5772 | 0.004302 | 1110 | ISR_Aluminium | Model Group:Merk K28:6064982
6065036 | 01 eerste verdieping | 680 | 1710 | 1.1628 | 855 | 340 | 570 | 226.667 | 1 | Curtain Wall : K_28 | 0.5772 | 0.004302 | 1114 | ISR_Aluminium | Model Group:Merk K28:6065020
6065055 | 01 eerste verdieping | 680 | 1710 | 1.1628 | 855 | 340 | 570 | 226.667 | 1 | Curtain Wall : K_28 | 0.5772 | 0.004302 | 1116 | ISR_Aluminium | Model Group:Merk K28:6065039
6065093 | 01 eerste verdieping | 680 | 1710 | 1.1628 | 855 | 340 | 570 | 226.667 | 1 | Curtain Wall : K_28 | 0.5772 | 0.004302 | 1120 | ISR_Aluminium | Model Group:Merk K28:6065077
6065112 | 01 eerste verdieping | 680 | 1710 | 1.1628 | 855 | 340 | 570 | 226.667 | 1 | Curtain Wall : K_28 | 0.5772 | 0.004302 | 1122 | ISR_Aluminium | Model Group:Merk K28:6065096
6065131 | 01 eerste verdieping | 680 | 1710 | 1.1628 | 855 | 340 | 570 | 226.667 | 1 | Curtain Wall : K_28 | 0.5772 | 0.004302 | 1124 | ISR_Aluminium | Model Group:Merk K28:6065115
6065150 | 01 eerste verdieping | 680 | 1710 | 1.1628 | 855 | 340 | 570 | 226.667 | 1 | Curtain Wall : K_28 | 0.5772 | 0.004302 | 1126 | ISR_Aluminium | Model Group:Merk K28:6065134
6065224 | 00 Begane grond | 680 | 1710 | 1.1628 | 855 | 340 | 570 | 226.667 | V1 ok. ruwe vloer | Curtain Wall : K_24 | 0.5772 | 0.004302 | 1095 | ISR_Aluminium | Model Group:Merk K24:6065197
6065255 | 00 Begane grond | 680 | 1710 | 1.1628 | 855 | 340 | 570 | 226.667 | V1 ok. ruwe vloer | Curtain Wall : K_24 | 0.5772 | 0.004302 | 1129 | ISR_Aluminium | Model Group:Merk K24:6065228
6065286 | 00 Begane grond | 680 | 1710 | 1.1628 | 855 | 340 | 570 | 226.667 | V1 ok. ruwe vloer | Curtain Wall : K_24 | 0.5772 | 0.004302 | 1134 | ISR_Aluminium | Model Group:Merk K24:6065259
6065317 | 00 Begane grond | 680 | 1710 | 1.1628 | 855 | 340 | 570 | 226.667 | V1 ok. ruwe vloer | Curtain Wall : K_24 | 0.5772 | 0.004302 | 1139 | ISR_Aluminium | Model Group:Merk K24:6065290
6065348 | 00 Begane grond | 680 | 1710 | 1.1628 | 855 | 340 | 570 | 226.667 | V1 ok. ruwe vloer | Curtain Wall : K_24 | 0.5772 | 0.004302 | 1144 | ISR_Aluminium | Model Group:Merk K24:6065321
6065379 | 00 Begane grond | 680 | 1710 | 1.1628 | 855 | 340 | 570 | 226.667 | V1 ok. ruwe vloer | Curtain Wall : K_24 | 0.5772 | 0.004302 | 1149 | ISR_Aluminium | Model Group:Merk K24:6065352
6065410 | 00 Begane grond | 680 | 1710 | 1.1628 | 855 | 340 | 570 | 226.667 | V1 ok. ruwe vloer | Curtain Wall : K_24 | 0.5772 | 0.004302 | 1154 | ISR_Aluminium | Model Group:Merk K24:6065383
6065441 | 00 Begane grond | 680 | 1710 | 1.1628 | 855 | 340 | 570 | 226.667 | V1 ok. ruwe vloer | Curtain Wall : K_24 | 0.5772 | 0.004302 | 1159 | ISR_Aluminium | Model Group:Merk K24:6065414
6065472 | 00 Begane grond | 680 | 1710 | 1.1628 | 855 | 340 | 570 | 226.667 | V1 ok. ruwe vloer | Curtain Wall : K_24 | 0.5772 | 0.004302 | 1164 | ISR_Aluminium | Model Group:Merk K24:6065445
6065503 | 00 Begane grond | 680 | 1710 | 1.1628 | 855 | 340 | 570 | 226.667 | V1 ok. ruwe vloer | Curtain Wall : K_24 | 0.5772 | 0.004302 | 1169 | ISR_Aluminium | Model Group:Merk K24:6065476
6065534 | 00 Begane grond | 680 | 1710 | 1.1628 | 855 | 340 | 570 | 226.667 | V1 ok. ruwe vloer | Curtain Wall : K_24 | 0.5772 | 0.004302 | 1174 | ISR_Aluminium | Model Group:Merk K24:6065507
6065565 | 00 Begane grond | 680 | 1710 | 1.1628 | 855 | 340 | 570 | 226.667 | V1 ok. ruwe vloer | Curtain Wall : K_24 | 0.5772 | 0.004302 | 1179 | ISR_Aluminium | Model Group:Merk K24:6065538
6065596 | 00 Begane grond | 680 | 1710 | 1.1628 | 855 | 340 | 570 | 226.667 | V1 ok. ruwe vloer | Curtain Wall : K_24 | 0.5772 | 0.004302 | 1184 | ISR_Aluminium | Model Group:Merk K24:6065569
6241468 | 00 Begane grond | 555 | 2210 | 1.22655 | 1105 | 277.5 | 736.667 | 185 | 0 | Curtain Wall : Merk H04 | 0.6672 | 0.004977 | 3458 | HPL F7853 ocean gray | Model Group:H04:6241461
6423891 | 00 Begane grond | 416 | 1056 | 0.439296 | 528 | 208 | 352 | 138.667 | 0 | Curtain Wall : Merk H17 | 0.35688 | 0.0026496 | 3288 | HPL F7853 ocean gray | Model Group:H27:5259555
6423926 | 00 Begane grond | 416 | 1056 | 0.439296 | 528 | 208 | 352 | 138.667 | 0 | Curtain Wall : Merk H17 | 0.35688 | 0.0026496 | 3294 | HPL F7853 ocean gray | Model Group:H27:5259652
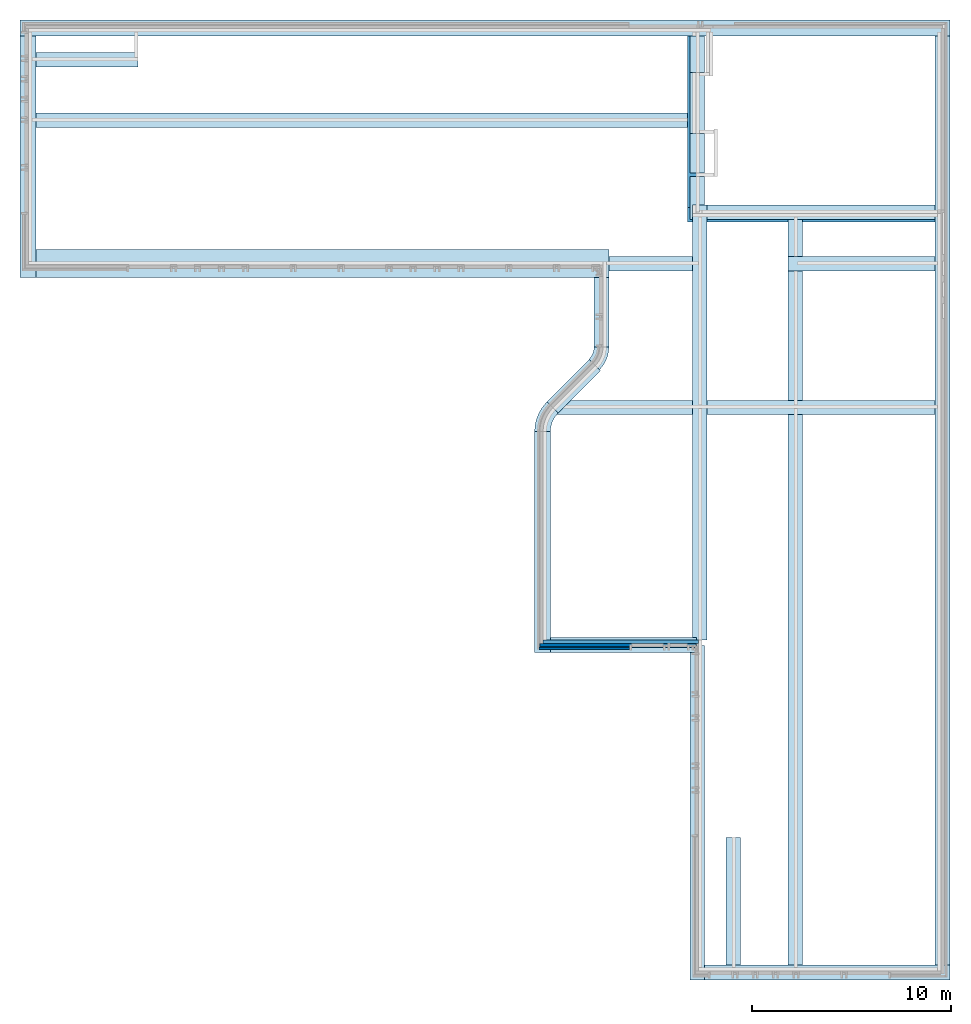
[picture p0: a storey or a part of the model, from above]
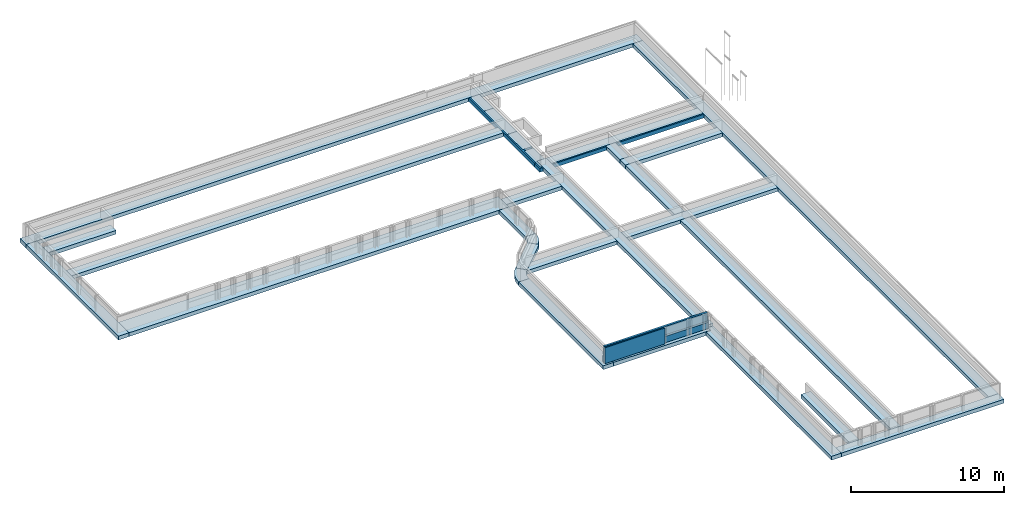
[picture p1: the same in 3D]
Properties of the parts of a building model (IFC2X3), part 37 of 37

# IfcWindow: WI_subvak1:glas 4 (179)
Name (WI_subvak1:glas 4:...) | In | OverallWidth (mm) = BaseQuantities, Width (mm) = Rough Width (mm) = Dimensions, Width (mm) | BaseQuantities, Height (mm) = subpaneel_1_hoogte (mm) = Dimensions, Height (mm) = Rough Height (mm) | BaseQuantities, Area (m2) | calc_mid_hor (mm) | calc_mid_ver (mm) | CalcEndHor (mm) = CalcStartHor (mm) | CalcEndVert (mm) = CalcStartVert (mm) | Level | Host | Dimensions, Area (m2) | Volume (m3) | Mark | FrameExteriorMaterial = FrameInteriorMaterial | Group
6474554 | 01 eerste verdieping | 1306 | 1710 | 2.23326 | 855 | 653 | 570 | 435.333 | 1 | Curtain Wall : K_32 | 0.72744 | 0.0054288 | 4010 | ISR_Aluminium | Model Group:Merk K32:5538102
6474595 | 01 eerste verdieping | 590 | 1710 | 1.0089 | 855 | 295 | 570 | 196.667 | 1 | Curtain Wall : K_32 | 0.5556 | 0.00414 | 661 | ISR_Aluminium | Model Group:Merk K32:5538094
6474596 | 01 eerste verdieping | 1306 | 1710 | 2.23326 | 855 | 653 | 570 | 435.333 | 1 | Curtain Wall : K_32 | 0.72744 | 0.0054288 | 662 | ISR_Aluminium | Model Group:Merk K32:5538094
6479903 | 00 Begane grond | 686 | 2410 | 1.65326 | 1205 | 343 | 803.333 | 228.667 | 0 | Curtain Wall : K_15 | 0.74664 | 0.0055728 | 577 | ISR_Aluminium | Model Group:Merk K15:5537536
6604032 | 00 Begane grond | 376 | 2256 | 0.848256 | 1128 | 188 | 752 | 125.333 | 0 | Curtain Wall : Merk H18 | 0.63528 | 0.0047376 | 529 | HPL F7853 ocean gray | Model Group:H18:5129917
6693335 | 00 Begane grond | 416 | 1056 | 0.439296 | 528 | 208 | 352 | 138.667 | 0 | Curtain Wall : Merk H17 | 0.35688 | 0.0026496 | 3324 | HPL F7853 ocean gray | Model Group:H27:6693328
6782314 | 00 Begane grond | 1920 | 2410 | 4.6272 | 1205 | 960 | 803.333 | 640 | 0 | Curtain Wall : K_02 | 1.0428 | 0.007794 | 3862 | ISR_Aluminium
6896078 | 00 Begane grond | 590 | 1710 | 1.0089 | 855 | 295 | 570 | 196.667 | 0 | Curtain Wall : K_11 | 0.5556 | 0.00414 | 3312 | ISR_Aluminium | Model Group:Merk K11:5537409
6896981 | 00 Begane grond | 590 | 2653 | 1.56527 | 1326.5 | 295 | 884.333 | 196.667 | 0 | Curtain Wall : K_10 | 0.78192 | 0.0058374 | 471 | ISR_Aluminium | Model Group:Merk K10:5537401

# IfcWindow: WI_subvak:glas 2 (45)
Type - ParameterTakesPrecedence: no; Sizeable: no; Material: glas_enscape
Type - Other - Category: Windows; Family Name: WI_subvak
Type - Dimensions - VentilationHeight: 0 mm; decoratie_breedte: 30 mm; decoratie_diepte: 10 mm; Thickness: 24 mm
Type - General - VentilationType: ventilatierooster : Type 1
Type - Identity Data - Assembly Code: 31.11; Assembly Description: buitenwandopeningen; niet gevuld, daglichtopeningen; Description: enkel glas + rooster; Manufacturer: ITANNEX; Model: 10-07-2014; Type Comments: subvakken; Type Name: glas 2; URL: www.bimvoorfabrikanten.nl; Workset: Family : Windows : WI_subvak
Type - Materials and Finishes - FinishExteriorMaterial: glas_enscape
Type - Analytical Properties - Define Thermal Properties by: Schematic Type; Analytic Construction: <None>
Type - Pset_ManufacturerTypeInformation - Manufacturer: ITANNEX
Type - Pset_ProductRequirements - Category: Windows
Type - Pset_WindowCommon - IsExternal: no
OverallHeight: 609.929 mm; Classification: 31.11 Uniformat (Uniformat)
Pset_QuantityTakeOff - Reference: glas 2
Pset_WindowCommon - Reference: glas 2
Pset_Window - Omschrijving: enkel glas + rooster; NL-sfb-Codering: 31.11
Pset_DAT_KMS - Assembly Code: 31.11; Assembly Description: buitenwandopeningen; niet gevuld, daglichtopeningen; Description: enkel glas + rooster
Other - CalcHorMultiple: no; CalcHorSingle: no; CalcVertMultiple: no; CalcVertSingle: no; SubPanel_1_h_Calc: 2; SubPanel_1_v_Calc: 2; Ventilation: no; Type: glas 2; CalcVentilationHeight: 80 mm; Family: WI_subvak; Family and Type: WI_subvak: glas 2; Type Id: 4285624
Model Properties - subpaneel_1_roedes_hor: 0; subpaneel_1_roedes_ver: 0
Constraints - Moves With Nearby Elements: no; Offset from Host: 0 mm
Identity Data - Workset: Bouwkundig
Materials and Finishes - FrameExteriorMaterial: ISR_Aluminium; FrameInteriorMaterial: ISR_Aluminium
Phasing - Phase Created: 2. nieuwbouw
Name (WI_subvak:glas 2:...) | In | OverallWidth (mm) = BaseQuantities, Width (mm) = Rough Width (mm) = Dimensions, Width (mm) | BaseQuantities, Height (mm) = subpaneel_1_hoogte (mm) = Dimensions, Height (mm) = Rough Height (mm) | BaseQuantities, Area (m2) | CalcStartHor (mm) | CalcStartVert (mm) | Level | Host | Dimensions, Area (m2) | Volume (m3) | Mark | Group
5608097 | 00 Begane grond | 1006 | 1710 | 1.72026 | 570 | 335.333 | 0 | Curtain Wall : K_17 | 0.65544 | 0.0048888 | 4120 | Model Group:Merk K17:5544294
5608285 | 00 Begane grond | 1006 | 1710 | 1.72026 | 570 | 335.333 | 0 | Curtain Wall : K_17 | 0.65544 | 0.0048888 | 3975 | Model Group:Merk K17:5540560
5608293 | 00 Begane grond | 1006 | 1710 | 1.72026 | 570 | 335.333 | 0 | Curtain Wall : K_17 | 0.65544 | 0.0048888 | 3981 | Model Group:Merk K17:5542284
5608297 | 00 Begane grond | 1006 | 1710 | 1.72026 | 570 | 335.333 | 0 | Curtain Wall : K_17 | 0.65544 | 0.0048888 | 3987 | Model Group:Merk K17:5542310
5608301 | 00 Begane grond | 1006 | 1710 | 1.72026 | 570 | 335.333 | 0 | Curtain Wall : K_17 | 0.65544 | 0.0048888 | 3993 | Model Group:Merk K17:5542336
5608305 | 00 Begane grond | 1006 | 1710 | 1.72026 | 570 | 335.333 | 0 | Curtain Wall : K_17 | 0.65544 | 0.0048888 | 3999 | Model Group:Merk K17:5542362
5608309 | 00 Begane grond | 1006 | 1710 | 1.72026 | 570 | 335.333 | 0 | Curtain Wall : K_17 | 0.65544 | 0.0048888 | 4005 | Model Group:Merk K17:5542388
5608321 | 00 Begane grond | 1006 | 1710 | 1.72026 | 570 | 335.333 | 0 | Curtain Wall : K_17 | 0.65544 | 0.0048888 | 4081 | Model Group:Merk K17:5544972
5608325 | 00 Begane grond | 1006 | 1710 | 1.72026 | 570 | 335.333 | 0 | Curtain Wall : K_17 | 0.65544 | 0.0048888 | 4087 | Model Group:Merk K17:5545007
5610036 | 01 eerste verdieping | 1306 | 1710 | 2.23326 | 570 | 435.333 | 1 | Curtain Wall : K_22 | 0.72744 | 0.0054288 | 937 | Model Group:Merk K22:5538022
5610511 | 01 eerste verdieping | 1306 | 1710 | 2.23326 | 570 | 435.333 | 1 | Curtain Wall : K_22 | 0.72744 | 0.0054288 | 3672 | Model Group:Merk K22:5537990
5610515 | 01 eerste verdieping | 1306 | 1710 | 2.23326 | 570 | 435.333 | 1 | Curtain Wall : K_22 | 0.72744 | 0.0054288 | 3903 | Model Group:Merk K22:5537998
5610519 | 01 eerste verdieping | 1306 | 1710 | 2.23326 | 570 | 435.333 | 1 | Curtain Wall : K_22 | 0.72744 | 0.0054288 | 3680 | Model Group:Merk K22:5538006
5610523 | 01 eerste verdieping | 1306 | 1710 | 2.23326 | 570 | 435.333 | 1 | Curtain Wall : K_22 | 0.72744 | 0.0054288 | 3688 | Model Group:Merk K22:5538014
5610527 | 01 eerste verdieping | 1306 | 1710 | 2.23326 | 570 | 435.333 | 1 | Curtain Wall : K_22 | 0.72744 | 0.0054288 | 3751 | Model Group:Merk K22:5538030
5610531 | 01 eerste verdieping | 1306 | 1710 | 2.23326 | 570 | 435.333 | 1 | Curtain Wall : K_22 | 0.72744 | 0.0054288 | 3775 | Model Group:Merk K22:5538038
5610535 | 01 eerste verdieping | 1306 | 1710 | 2.23326 | 570 | 435.333 | 1 | Curtain Wall : K_22 | 0.72744 | 0.0054288 | 3779 | Model Group:Merk K22:5538046
5610539 | 01 eerste verdieping | 1306 | 1710 | 2.23326 | 570 | 435.333 | 1 | Curtain Wall : K_22 | 0.72744 | 0.0054288 | 3783 | Model Group:Merk K22:5538054
5610543 | 01 eerste verdieping | 1306 | 1710 | 2.23326 | 570 | 435.333 | 1 | Curtain Wall : K_22 | 0.72744 | 0.0054288 | 3787 | Model Group:Merk K22:5538062
5610547 | 01 eerste verdieping | 1306 | 1710 | 2.23326 | 570 | 435.333 | 1 | Curtain Wall : K_22 | 0.72744 | 0.0054288 | 3791 | Model Group:Merk K22:5538070
5610551 | 01 eerste verdieping | 1306 | 1710 | 2.23326 | 570 | 435.333 | 1 | Curtain Wall : K_22 | 0.72744 | 0.0054288 | 3795 | Model Group:Merk K22:5538078
5610555 | 01 eerste verdieping | 1306 | 1710 | 2.23326 | 570 | 435.333 | 1 | Curtain Wall : K_22 | 0.72744 | 0.0054288 | 3804 | Model Group:Merk K22:5538086
5611560 | 00 Begane grond | 1356 | 1960 | 2.65776 | 653.333 | 452 | 0 | Curtain Wall : K_07 | 0.79944 | 0.0059688 | 647 | Model Group:Merk K07:5537502
5611643 | 00 Begane grond | 1356 | 1960 | 2.65776 | 653.333 | 452 | 0 | Curtain Wall : K_07 | 0.79944 | 0.0059688 | 3697 | Model Group:Merk K07:5537724
5611825 | 01 eerste verdieping | 590 | 1710 | 1.0089 | 570 | 196.667 | 1 | Curtain Wall : K_30 | 0.5556 | 0.00414 | 652 | Model Group:Merk K30:5537739
5856019 | 00 Begane grond | 1006 | 1710 | 1.72026 | 570 | 335.333 | 0 | Curtain Wall : K_17 | 0.65544 | 0.0048888 | 1075 | Model Group:Merk K17:5855989
5856044 | 00 Begane grond | 1006 | 1710 | 1.72026 | 570 | 335.333 | 0 | Curtain Wall : K_17 | 0.65544 | 0.0048888 | 1089 | Model Group:Merk K17:5856030
6065226 | 00 Begane grond | 1006 | 1710 | 1.72026 | 570 | 335.333 | V1 ok. ruwe vloer | Curtain Wall : K_24 | 0.65544 | 0.0048888 | 1097 | Model Group:Merk K24:6065197
6065257 | 00 Begane grond | 1006 | 1710 | 1.72026 | 570 | 335.333 | V1 ok. ruwe vloer | Curtain Wall : K_24 | 0.65544 | 0.0048888 | 1131 | Model Group:Merk K24:6065228
6065288 | 00 Begane grond | 1006 | 1710 | 1.72026 | 570 | 335.333 | V1 ok. ruwe vloer | Curtain Wall : K_24 | 0.65544 | 0.0048888 | 1136 | Model Group:Merk K24:6065259
6065319 | 00 Begane grond | 1006 | 1710 | 1.72026 | 570 | 335.333 | V1 ok. ruwe vloer | Curtain Wall : K_24 | 0.65544 | 0.0048888 | 1141 | Model Group:Merk K24:6065290
6065350 | 00 Begane grond | 1006 | 1710 | 1.72026 | 570 | 335.333 | V1 ok. ruwe vloer | Curtain Wall : K_24 | 0.65544 | 0.0048888 | 1146 | Model Group:Merk K24:6065321
6065381 | 00 Begane grond | 1006 | 1710 | 1.72026 | 570 | 335.333 | V1 ok. ruwe vloer | Curtain Wall : K_24 | 0.65544 | 0.0048888 | 1151 | Model Group:Merk K24:6065352
6065412 | 00 Begane grond | 1006 | 1710 | 1.72026 | 570 | 335.333 | V1 ok. ruwe vloer | Curtain Wall : K_24 | 0.65544 | 0.0048888 | 1156 | Model Group:Merk K24:6065383
6065443 | 00 Begane grond | 1006 | 1710 | 1.72026 | 570 | 335.333 | V1 ok. ruwe vloer | Curtain Wall : K_24 | 0.65544 | 0.0048888 | 1161 | Model Group:Merk K24:6065414
6065474 | 00 Begane grond | 1006 | 1710 | 1.72026 | 570 | 335.333 | V1 ok. ruwe vloer | Curtain Wall : K_24 | 0.65544 | 0.0048888 | 1166 | Model Group:Merk K24:6065445
6065505 | 00 Begane grond | 1006 | 1710 | 1.72026 | 570 | 335.333 | V1 ok. ruwe vloer | Curtain Wall : K_24 | 0.65544 | 0.0048888 | 1171 | Model Group:Merk K24:6065476
6065536 | 00 Begane grond | 1006 | 1710 | 1.72026 | 570 | 335.333 | V1 ok. ruwe vloer | Curtain Wall : K_24 | 0.65544 | 0.0048888 | 1176 | Model Group:Merk K24:6065507
6065567 | 00 Begane grond | 1006 | 1710 | 1.72026 | 570 | 335.333 | V1 ok. ruwe vloer | Curtain Wall : K_24 | 0.65544 | 0.0048888 | 1181 | Model Group:Merk K24:6065538
6065598 | 00 Begane grond | 1006 | 1710 | 1.72026 | 570 | 335.333 | V1 ok. ruwe vloer | Curtain Wall : K_24 | 0.65544 | 0.0048888 | 1186 | Model Group:Merk K24:6065569
6315737 | 01 eerste verdieping | 680 | 1710 | 1.1628 | 570 | 226.667 | 1 | Curtain Wall : K_31 | 0.5772 | 0.004302 | 3486 | Model Group:Merk K31:6065001
6315980 | 01 eerste verdieping | 680 | 1710 | 1.1628 | 570 | 226.667 | 1 | Curtain Wall : K_31 | 0.5772 | 0.004302 | 3489 | Model Group:Merk K31:6065058
6322841 | 01 eerste verdieping | 680 | 1710 | 1.1628 | 570 | 226.667 | 1 | Curtain Wall : K_31 | 0.5772 | 0.004302 | 3552 | Model Group:Merk K31:6322821
6322872 | 01 eerste verdieping | 680 | 1710 | 1.1628 | 570 | 226.667 | 1 | Curtain Wall : K_31 | 0.5772 | 0.004302 | 976 | Model Group:Merk K31:6322854
6474583 | 00 Begane grond | 680 | 1710 | 1.1628 | 570 | 226.667 | V0 bk. ruwe vloer | Curtain Wall : K_31 | 0.5772 | 0.004302 | 658 | Model Group:Merk K31:6474575
